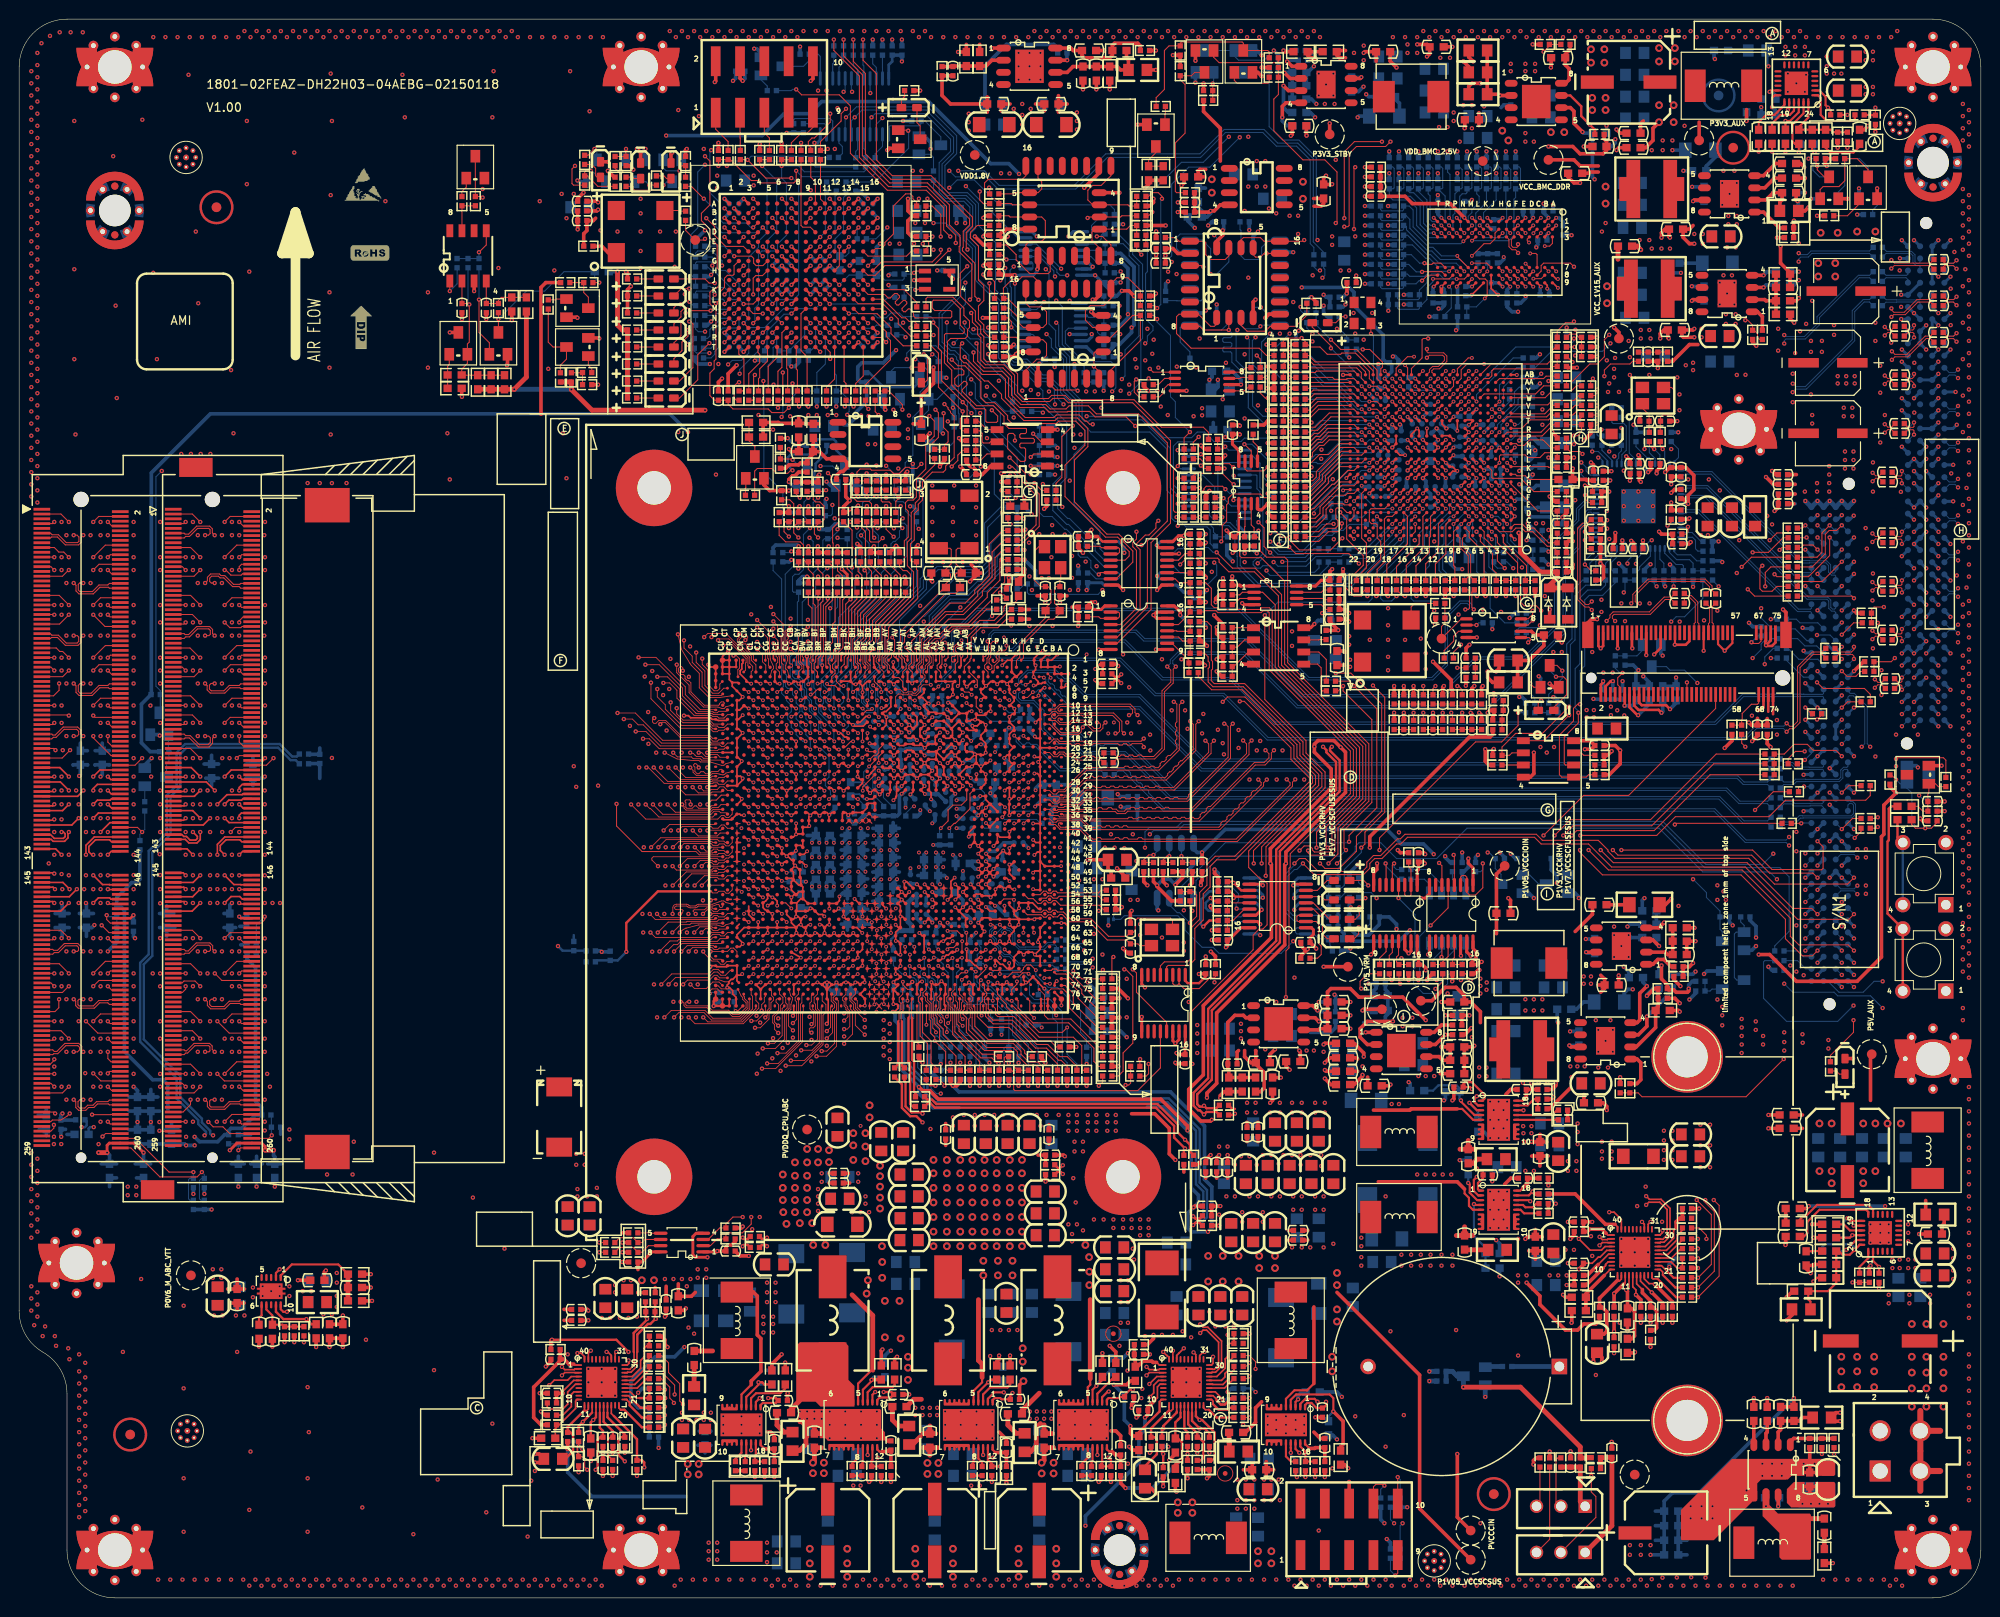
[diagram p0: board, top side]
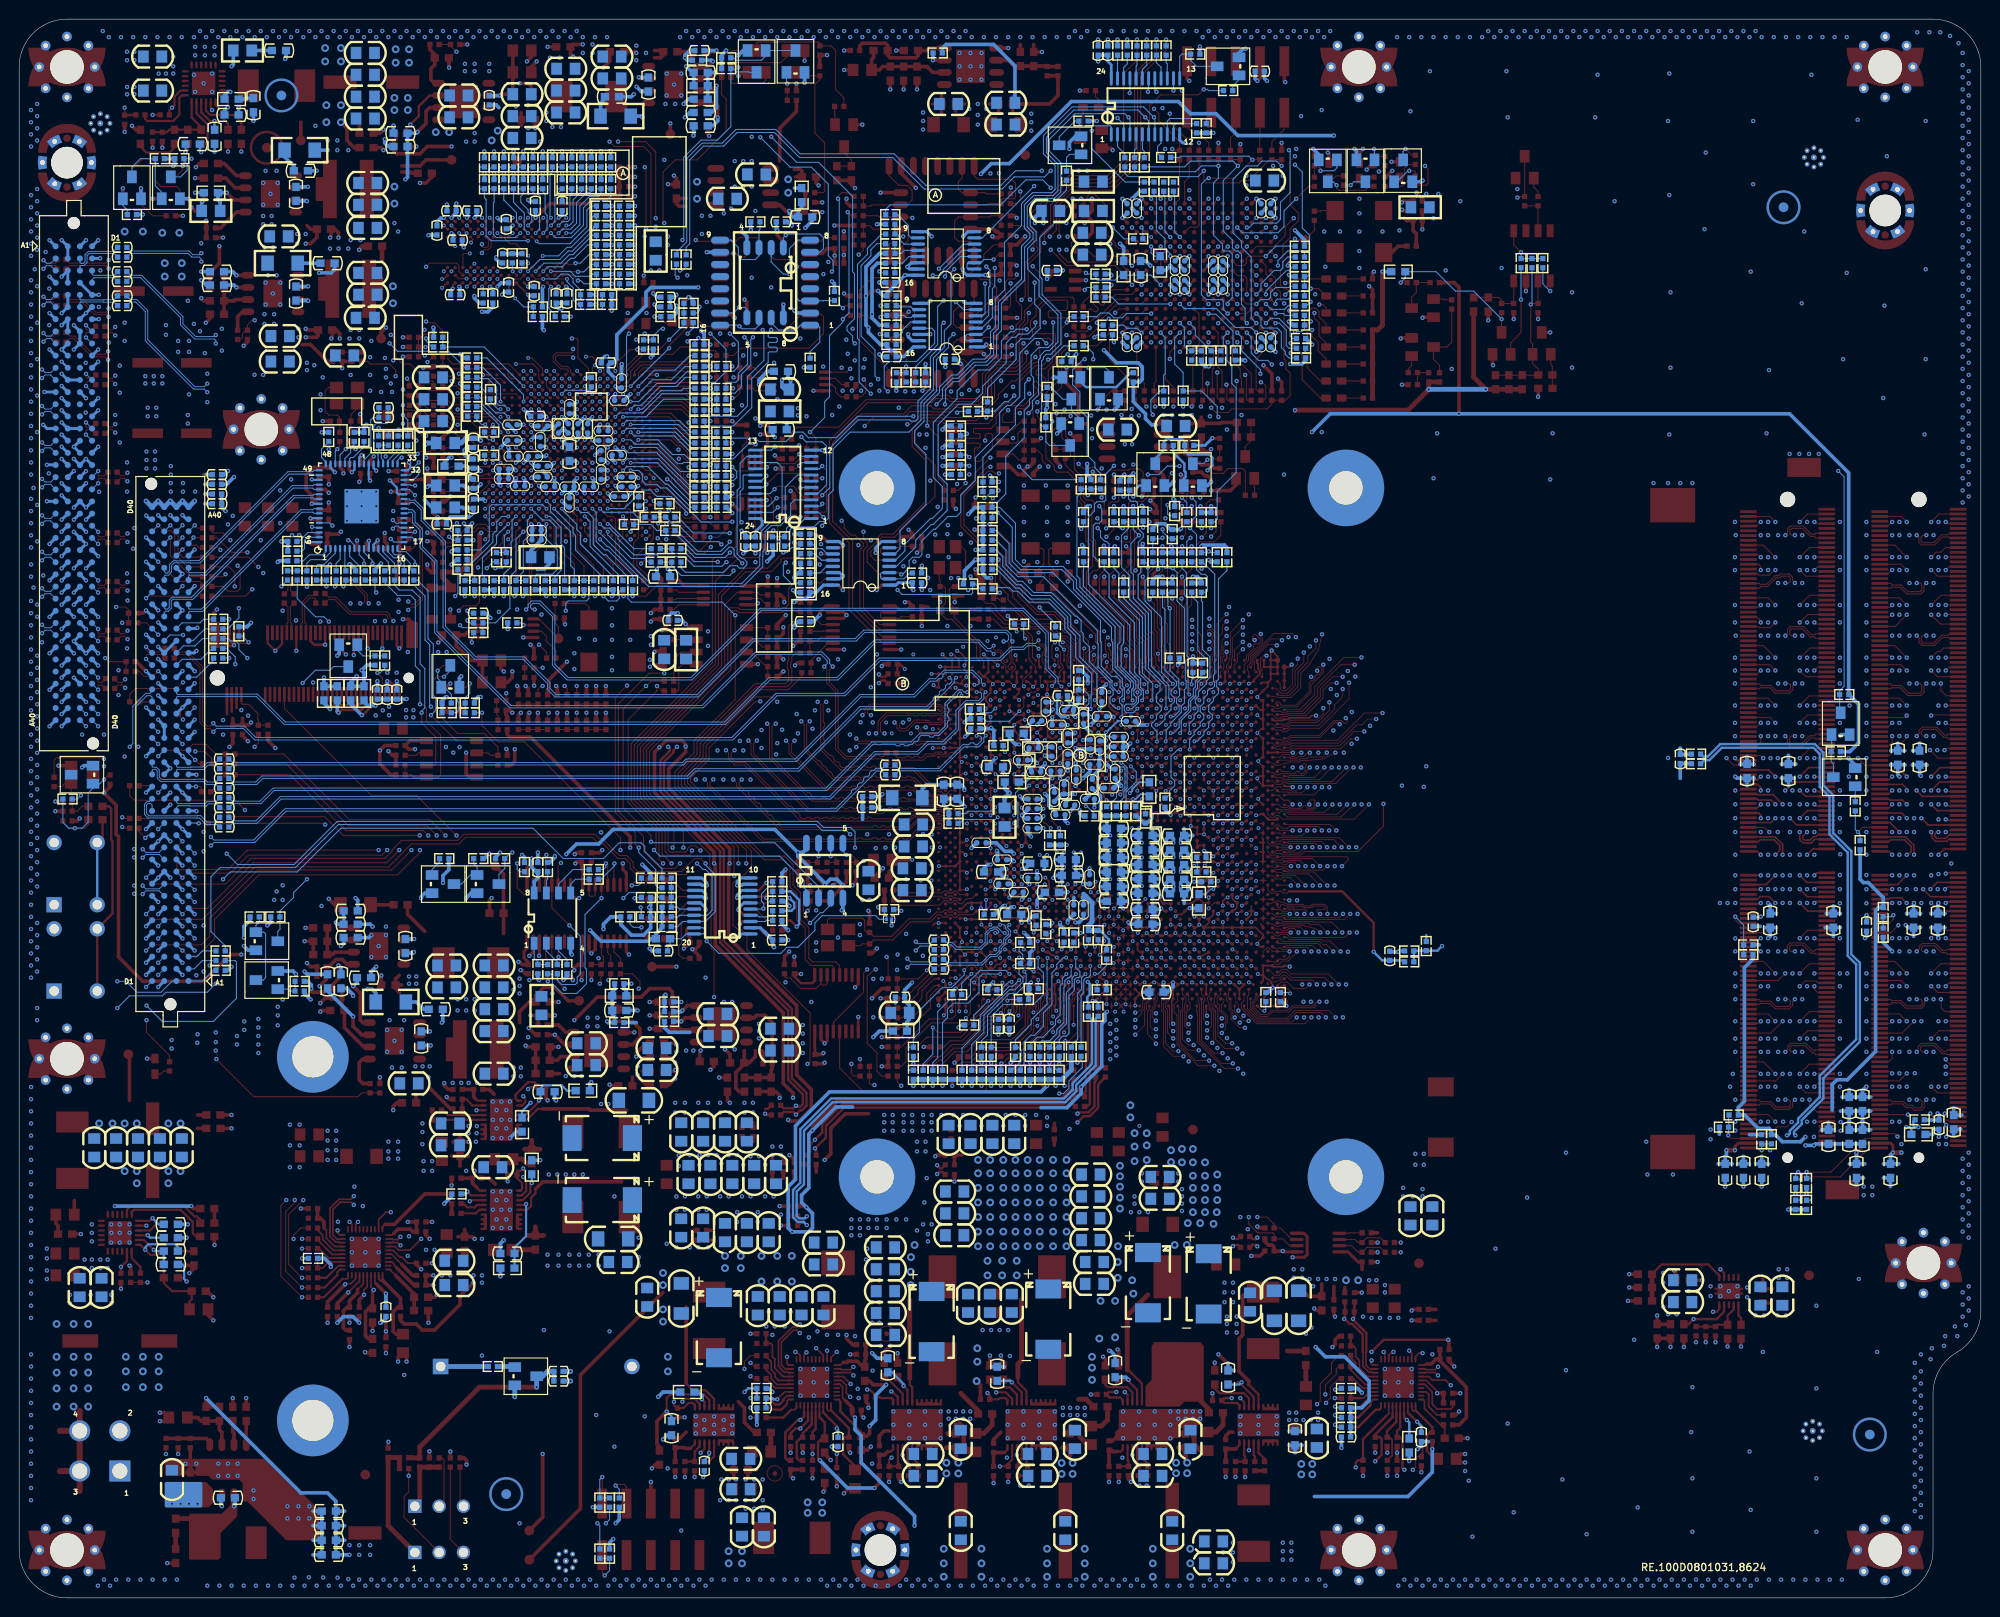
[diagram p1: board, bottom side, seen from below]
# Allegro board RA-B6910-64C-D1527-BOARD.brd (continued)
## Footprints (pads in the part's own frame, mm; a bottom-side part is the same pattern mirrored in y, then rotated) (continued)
10131758
  round 1.1 hole 1.1 unplated: (0,0)
  round 1.6 hole 1.6 unplated: (20,0)
  rect 0.3x1.55 smd: 1(0.75,4.725) 2(1,-1.725) 3(1.25,4.725) 4(1.5,-1.725) 5(1.75,4.725) 6(2,-1.725) 7(2.25,4.725) 8(2.5,-1.725) 9(2.75,4.725) 10(3,-1.725) 11(3.25,4.725) 12(3.5,-1.725) 13(3.75,4.725) 14(4,-1.725) 15(4.25,4.725) 16(4.5,-1.725) 17(4.75,4.725) 18(5,-1.725) 19(5.25,4.725) 20(5.5,-1.725) 21(5.75,4.725) 22(6,-1.725) 23(6.25,4.725) 24(6.5,-1.725) 25(6.75,4.725) 26(7,-1.725) 27(7.25,4.725) 28(7.5,-1.725) 29(7.75,4.725) 30(8,-1.725) 31(8.25,4.725) 32(8.5,-1.725) 33(8.75,4.725) 34(9,-1.725) 35(9.25,4.725) 36(9.5,-1.725) 37(9.75,4.725) 38(10,-1.725) 39(10.25,4.725) 40(10.5,-1.725) 41(10.75,4.725) 42(11,-1.725) 43(11.25,4.725) 44(11.5,-1.725) 45(11.75,4.725) 46(12,-1.725) 47(12.25,4.725) 48(12.5,-1.725) 49(12.75,4.725) 50(13,-1.725) 51(13.25,4.725) 52(13.5,-1.725) 53(13.75,4.725) 54(14,-1.725) 55(14.25,4.725) 56(14.5,-1.725) 57(14.75,4.725) 58(15,-1.725) 67(17.25,4.725) 68(17.5,-1.725) 69(17.75,4.725) 70(18,-1.725) 71(18.25,4.725) 72(18.5,-1.725) 73(18.75,4.725) 74(19,-1.725) 75(19.25,4.725)
  rect 1.2x2.76 smd: 76(-0.35,4.5) 77(20.35,4.5)
10141732
  round 1.1 hole 1.1 unplated: (-34.4,0)
  round 1.6 hole 1.6 unplated: (34.4,0)
  rect 0.3x1.75 smd: 1(33.375,4.1) 2(33.125,-4.1) 3(32.875,4.1) 4(32.625,-4.1) 5(32.375,4.1) 6(32.125,-4.1) 7(31.875,4.1) 8(31.625,-4.1) 9(31.375,4.1) 10(31.125,-4.1) 11(30.875,4.1) 12(30.625,-4.1) 13(30.375,4.1) 14(30.125,-4.1) 15(29.875,4.1) 16(29.625,-4.1) 17(29.375,4.1) 18(29.125,-4.1) 19(28.875,4.1) 20(28.625,-4.1) 21(28.375,4.1) 22(28.125,-4.1) 23(27.875,4.1) 24(27.625,-4.1) 25(27.375,4.1) 26(27.125,-4.1) 27(26.875,4.1) 28(26.625,-4.1) 29(26.375,4.1) 30(26.125,-4.1) 31(25.875,4.1) 32(25.625,-4.1) 33(25.375,4.1) 34(25.125,-4.1) 35(24.875,4.1) 36(24.625,-4.1) 37(24.375,4.1) 38(24.125,-4.1) 39(23.875,4.1) 40(23.625,-4.1) 41(23.375,4.1) 42(23.125,-4.1) 43(22.875,4.1) 44(22.625,-4.1) 45(22.375,4.1) 46(22.125,-4.1) 47(21.875,4.1) 48(21.625,-4.1) 49(21.375,4.1) 50(21.125,-4.1) 51(20.875,4.1) 52(20.625,-4.1) 53(20.375,4.1) 54(20.125,-4.1) 55(19.875,4.1) 56(19.625,-4.1) 57(19.375,4.1) 58(19.125,-4.1) 59(18.875,4.1) 60(18.625,-4.1) 61(18.375,4.1) 62(18.125,-4.1) 63(17.875,4.1) 64(17.625,-4.1) 65(17.375,4.1) 66(17.125,-4.1) 67(16.875,4.1) 68(16.625,-4.1) 69(16.375,4.1) 70(16.125,-4.1) 71(15.875,4.1) 72(15.625,-4.1) 73(15.375,4.1) 74(15.125,-4.1) 75(14.875,4.1) 76(14.625,-4.1) 77(14.375,4.1) 78(14.125,-4.1) 79(13.875,4.1) 80(13.625,-4.1) 81(13.375,4.1) 82(13.125,-4.1) 83(12.875,4.1) 84(12.625,-4.1) 85(12.375,4.1) 86(12.125,-4.1) 87(11.875,4.1) 88(11.625,-4.1) 89(11.375,4.1) 90(11.125,-4.1) 91(10.875,4.1) 92(10.625,-4.1) 93(10.375,4.1) 94(10.125,-4.1) 95(9.875,4.1) 96(9.625,-4.1) 97(9.375,4.1) 98(9.125,-4.1) 99(8.875,4.1) 100(8.625,-4.1) 101(8.375,4.1) 102(8.125,-4.1) 103(7.875,4.1) 104(7.625,-4.1) 105(7.375,4.1) 106(7.125,-4.1) 107(6.875,4.1) 108(6.625,-4.1) 109(6.375,4.1) 110(6.125,-4.1) 111(5.875,4.1) 112(5.625,-4.1) 113(5.375,4.1) 114(5.125,-4.1) 115(4.875,4.1) 116(4.625,-4.1) 117(4.375,4.1) 118(4.125,-4.1) 119(3.875,4.1) 120(3.625,-4.1) 121(3.375,4.1) 122(3.125,-4.1) 123(2.875,4.1) 124(2.625,-4.1) 125(2.375,4.1) 126(2.125,-4.1) 127(1.875,4.1) 128(1.625,-4.1) 129(1.375,4.1) 130(1.125,-4.1) 131(0.875,4.1) 132(0.625,-4.1) 133(0.375,4.1) 134(0.125,-4.1) 135(-0.125,4.1) 136(-0.375,-4.1) 137(-0.625,4.1) 138(-0.875,-4.1) 139(-1.125,4.1) 140(-1.375,-4.1) 141(-1.625,4.1) 142(-1.875,-4.1) 143(-2.125,4.1) 144(-2.375,-4.1) 145(-4.625,4.1) 146(-4.875,-4.1) 147(-5.125,4.1) 148(-5.375,-4.1) 149(-5.625,4.1) 150(-5.875,-4.1) 151(-6.125,4.1) 152(-6.375,-4.1) 153(-6.625,4.1) 154(-6.875,-4.1) 155(-7.125,4.1) 156(-7.375,-4.1) 157(-7.625,4.1) 158(-7.875,-4.1) 159(-8.125,4.1) 160(-8.375,-4.1) 161(-8.625,4.1) 162(-8.875,-4.1) 163(-9.125,4.1) 164(-9.375,-4.1) 165(-9.625,4.1) 166(-9.875,-4.1) 167(-10.125,4.1) 168(-10.375,-4.1) 169(-10.625,4.1) 170(-10.875,-4.1) 171(-11.125,4.1) 172(-11.375,-4.1) 173(-11.625,4.1) 174(-11.875,-4.1) 175(-12.125,4.1) 176(-12.375,-4.1) 177(-12.625,4.1) 178(-12.875,-4.1) 179(-13.125,4.1) 180(-13.375,-4.1) 181(-13.625,4.1) 182(-13.875,-4.1) 183(-14.125,4.1) 184(-14.375,-4.1) 185(-14.625,4.1) 186(-14.875,-4.1) 187(-15.125,4.1) 188(-15.375,-4.1) 189(-15.625,4.1) 190(-15.875,-4.1) 191(-16.125,4.1) 192(-16.375,-4.1) 193(-16.625,4.1) 194(-16.875,-4.1) 195(-17.125,4.1) 196(-17.375,-4.1) 197(-17.625,4.1) 198(-17.875,-4.1) 199(-18.125,4.1) 200(-18.375,-4.1) 201(-18.625,4.1) 202(-18.875,-4.1) 203(-19.125,4.1) 204(-19.375,-4.1) 205(-19.625,4.1) 206(-19.875,-4.1) 207(-20.125,4.1) 208(-20.375,-4.1) 209(-20.625,4.1) 210(-20.875,-4.1) 211(-21.125,4.1) 212(-21.375,-4.1) 213(-21.625,4.1) 214(-21.875,-4.1) 215(-22.125,4.1) 216(-22.375,-4.1) 217(-22.625,4.1) 218(-22.875,-4.1) 219(-23.125,4.1) 220(-23.375,-4.1) 221(-23.625,4.1) 222(-23.875,-4.1) 223(-24.125,4.1) 224(-24.375,-4.1) 225(-24.625,4.1) 226(-24.875,-4.1) 227(-25.125,4.1) 228(-25.375,-4.1) 229(-25.625,4.1) 230(-25.875,-4.1) 231(-26.125,4.1) 232(-26.375,-4.1) 233(-26.625,4.1) 234(-26.875,-4.1) 235(-27.125,4.1) 236(-27.375,-4.1) 237(-27.625,4.1) 238(-27.875,-4.1) 239(-28.125,4.1) 240(-28.375,-4.1) 241(-28.625,4.1) 242(-28.875,-4.1) 243(-29.125,4.1) 244(-29.375,-4.1) 245(-29.625,4.1) 246(-29.875,-4.1) 247(-30.125,4.1) 248(-30.375,-4.1) 249(-30.625,4.1) 250(-30.875,-4.1) 251(-31.125,4.1) 252(-31.375,-4.1) 253(-31.625,4.1) 254(-31.875,-4.1) 255(-32.125,4.1) 256(-32.375,-4.1) 257(-32.625,4.1) 258(-32.875,-4.1) 259(-33.125,4.1) 260(-33.375,-4.1)
  rect 2x3.5 smd: 261(-37.75,-8) 262(37.75,-12)
10141997
  round 1.1 hole 1.1 unplated: (0,0)
  round 1.6 hole 1.6 unplated: (68.8,0)
  rect 0.3x1.75 smd: 1(67.775,4.1) 2(67.525,-4.1) 3(67.275,4.1) 4(67.025,-4.1) 5(66.775,4.1) 6(66.525,-4.1) 7(66.275,4.1) 8(66.025,-4.1) 9(65.775,4.1) 10(65.525,-4.1) 11(65.275,4.1) 12(65.025,-4.1) 13(64.775,4.1) 14(64.525,-4.1) 15(64.275,4.1) 16(64.025,-4.1) 17(63.775,4.1) 18(63.525,-4.1) 19(63.275,4.1) 20(63.025,-4.1) 21(62.775,4.1) 22(62.525,-4.1) 23(62.275,4.1) 24(62.025,-4.1) 25(61.775,4.1) 26(61.525,-4.1) 27(61.275,4.1) 28(61.025,-4.1) 29(60.775,4.1) 30(60.525,-4.1) 31(60.275,4.1) 32(60.025,-4.1) 33(59.775,4.1) 34(59.525,-4.1) 35(59.275,4.1) 36(59.025,-4.1) 37(58.775,4.1) 38(58.525,-4.1) 39(58.275,4.1) 40(58.025,-4.1) 41(57.775,4.1) 42(57.525,-4.1) 43(57.275,4.1) 44(57.025,-4.1) 45(56.775,4.1) 46(56.525,-4.1) 47(56.275,4.1) 48(56.025,-4.1) 49(55.775,4.1) 50(55.525,-4.1) 51(55.275,4.1) 52(55.025,-4.1) 53(54.775,4.1) 54(54.525,-4.1) 55(54.275,4.1) 56(54.025,-4.1) 57(53.775,4.1) 58(53.525,-4.1) 59(53.275,4.1) 60(53.025,-4.1) 61(52.775,4.1) 62(52.525,-4.1) 63(52.275,4.1) 64(52.025,-4.1) 65(51.775,4.1) 66(51.525,-4.1) 67(51.275,4.1) 68(51.025,-4.1) 69(50.775,4.1) 70(50.525,-4.1) 71(50.275,4.1) 72(50.025,-4.1) 73(49.775,4.1) 74(49.525,-4.1) 75(49.275,4.1) 76(49.025,-4.1) 77(48.775,4.1) 78(48.525,-4.1) 79(48.275,4.1) 80(48.025,-4.1) 81(47.775,4.1) 82(47.525,-4.1) 83(47.275,4.1) 84(47.025,-4.1) 85(46.775,4.1) 86(46.525,-4.1) 87(46.275,4.1) 88(46.025,-4.1) 89(45.775,4.1) 90(45.525,-4.1) 91(45.275,4.1) 92(45.025,-4.1) 93(44.775,4.1) 94(44.525,-4.1) 95(44.275,4.1) 96(44.025,-4.1) 97(43.775,4.1) 98(43.525,-4.1) 99(43.275,4.1) 100(43.025,-4.1) 101(42.775,4.1) 102(42.525,-4.1) 103(42.275,4.1) 104(42.025,-4.1) 105(41.775,4.1) 106(41.525,-4.1) 107(41.275,4.1) 108(41.025,-4.1) 109(40.775,4.1) 110(40.525,-4.1) 111(40.275,4.1) 112(40.025,-4.1) 113(39.775,4.1) 114(39.525,-4.1) 115(39.275,4.1) 116(39.025,-4.1) 117(38.775,4.1) 118(38.525,-4.1) 119(38.275,4.1) 120(38.025,-4.1) 121(37.775,4.1) 122(37.525,-4.1) 123(37.275,4.1) 124(37.025,-4.1) 125(36.775,4.1) 126(36.525,-4.1) 127(36.275,4.1) 128(36.025,-4.1) 129(35.775,4.1) 130(35.525,-4.1) 131(35.275,4.1) 132(35.025,-4.1) 133(34.775,4.1) 134(34.525,-4.1) 135(34.275,4.1) 136(34.025,-4.1) 137(33.775,4.1) 138(33.525,-4.1) 139(33.275,4.1) 140(33.025,-4.1) 141(32.775,4.1) 142(32.525,-4.1) 143(32.275,4.1) 144(32.025,-4.1) 145(29.775,4.1) 146(29.525,-4.1) 147(29.275,4.1) 148(29.025,-4.1) 149(28.775,4.1) 150(28.525,-4.1) 151(28.275,4.1) 152(28.025,-4.1) 153(27.775,4.1) 154(27.525,-4.1) 155(27.275,4.1) 156(27.025,-4.1) 157(26.775,4.1) 158(26.525,-4.1) 159(26.275,4.1) 160(26.025,-4.1) 161(25.775,4.1) 162(25.525,-4.1) 163(25.275,4.1) 164(25.025,-4.1) 165(24.775,4.1) 166(24.525,-4.1) 167(24.275,4.1) 168(24.025,-4.1) 169(23.775,4.1) 170(23.525,-4.1) 171(23.275,4.1) 172(23.025,-4.1) 173(22.775,4.1) 174(22.525,-4.1) 175(22.275,4.1) 176(22.025,-4.1) 177(21.775,4.1) 178(21.525,-4.1) 179(21.275,4.1) 180(21.025,-4.1) 181(20.775,4.1) 182(20.525,-4.1) 183(20.275,4.1) 184(20.025,-4.1) 185(19.775,4.1) 186(19.525,-4.1) 187(19.275,4.1) 188(19.025,-4.1) 189(18.775,4.1) 190(18.525,-4.1) 191(18.275,4.1) 192(18.025,-4.1) 193(17.775,4.1) 194(17.525,-4.1) 195(17.275,4.1) 196(17.025,-4.1) 197(16.775,4.1) 198(16.525,-4.1) 199(16.275,4.1) 200(16.025,-4.1) 201(15.775,4.1) 202(15.525,-4.1) 203(15.275,4.1) 204(15.025,-4.1) 205(14.775,4.1) 206(14.525,-4.1) 207(14.275,4.1) 208(14.025,-4.1) 209(13.775,4.1) 210(13.525,-4.1) 211(13.275,4.1) 212(13.025,-4.1) 213(12.775,4.1) 214(12.525,-4.1) 215(12.275,4.1) 216(12.025,-4.1) 217(11.775,4.1) 218(11.525,-4.1) 219(11.275,4.1) 220(11.025,-4.1) 221(10.775,4.1) 222(10.525,-4.1) 223(10.275,4.1) 224(10.025,-4.1) 225(9.775,4.1) 226(9.525,-4.1) 227(9.275,4.1) 228(9.025,-4.1) 229(8.775,4.1) 230(8.525,-4.1) 231(8.275,4.1) 232(8.025,-4.1) 233(7.775,4.1) 234(7.525,-4.1) 235(7.275,4.1) 236(7.025,-4.1) 237(6.775,4.1) 238(6.525,-4.1) 239(6.275,4.1) 240(6.025,-4.1) 241(5.775,4.1) 242(5.525,-4.1) 243(5.275,4.1) 244(5.025,-4.1) 245(4.775,4.1) 246(4.525,-4.1) 247(4.275,4.1) 248(4.025,-4.1) 249(3.775,4.1) 250(3.525,-4.1) 251(3.275,4.1) 252(3.025,-4.1) 253(2.775,4.1) 254(2.525,-4.1) 255(2.275,4.1) 256(2.025,-4.1) 257(1.775,4.1) 258(1.525,-4.1) 259(1.275,4.1) 260(1.025,-4.1)
  rect 3.6x4.7 smd: 261(0.6,-12) 262(68.2,-12)
BATTERY
  rect 1.626x1.626 hole 1.016: 1(0,0)
  round 1.626 hole 1.016: 2(19.99,0)
BGA_465_1M46_RO014
  round 0.356 smd: A1(-8.4,8.4) A2(-7.6,8.4) A3(-6.8,8.4) A4(-6,8.4) A5(-5.2,8.4) A6(-4.4,8.4) A7(-3.6,8.4) A8(-2.8,8.4) A9(-2,8.4) A10(-1.2,8.4) A11(-0.4,8.4) A12(0.4,8.4) A13(1.2,8.4) A14(2,8.4) A15(2.8,8.4) A16(3.6,8.4) A17(4.4,8.4) A18(5.2,8.4) A19(6,8.4) A20(6.8,8.4) A21(7.6,8.4) A22(8.4,8.4) AA1(-8.4,-7.6) AA2(-7.6,-7.6) AA3(-6.8,-7.6) AA4(-6,-7.6) AA5(-5.2,-7.6) AA6(-4.4,-7.6) AA7(-3.6,-7.6) AA8(-2.8,-7.6) AA9(-2,-7.6) AA10(-1.2,-7.6) AA11(-0.4,-7.6) AA12(0.4,-7.6) AA13(1.2,-7.6) AA14(2,-7.6) AA15(2.8,-7.6) AA16(3.6,-7.6) AA17(4.4,-7.6) AA18(5.2,-7.6) AA19(6,-7.6) AA20(6.8,-7.6) AA21(7.6,-7.6) AA22(8.4,-7.6) AB1(-8.4,-8.4) AB2(-7.6,-8.4) AB3(-6.8,-8.4) AB4(-6,-8.4) AB5(-5.2,-8.4) AB6(-4.4,-8.4) AB7(-3.6,-8.4) AB8(-2.8,-8.4) AB9(-2,-8.4) AB10(-1.2,-8.4) AB11(-0.4,-8.4) AB12(0.4,-8.4) AB13(1.2,-8.4) AB14(2,-8.4) AB15(2.8,-8.4) AB16(3.6,-8.4) AB17(4.4,-8.4) AB18(5.2,-8.4) AB19(6,-8.4) AB20(6.8,-8.4) AB21(7.6,-8.4) AB22(8.4,-8.4) B1(-8.4,7.6) B2(-7.6,7.6) B3(-6.8,7.6) B4(-6,7.6) B5(-5.2,7.6) B6(-4.4,7.6) B7(-3.6,7.6) B8(-2.8,7.6) B9(-2,7.6) B10(-1.2,7.6) B11(-0.4,7.6) B12(0.4,7.6) B13(1.2,7.6) B14(2,7.6) B15(2.8,7.6) B16(3.6,7.6) B17(4.4,7.6) B18(5.2,7.6) B19(6,7.6) B20(6.8,7.6) B21(7.6,7.6) B22(8.4,7.6) C1(-8.4,6.8) C2(-7.6,6.8) C3(-6.8,6.8) C4(-6,6.8) C5(-5.2,6.8) C6(-4.4,6.8) C7(-3.6,6.8) C8(-2.8,6.8) C9(-2,6.8) C10(-1.2,6.8) C11(-0.4,6.8) C12(0.4,6.8) C13(1.2,6.8) C14(2,6.8) C15(2.8,6.8) C16(3.6,6.8) C17(4.4,6.8) C18(5.2,6.8) C19(6,6.8) C20(6.8,6.8) C21(7.6,6.8) C22(8.4,6.8) D1(-8.4,6) D2(-7.6,6) D3(-6.8,6) D4(-6,6) D5(-5.2,6) D6(-4.4,6) D7(-3.6,6) D8(-2.8,6) D9(-2,6) D10(-1.2,6) D11(-0.4,6) D12(0.4,6) D13(1.2,6) D14(2,6) D15(2.8,6) D16(3.6,6) D17(4.4,6) D18(5.2,6) D19(6,6) D20(6.8,6) D21(7.6,6) D22(8.4,6) E1(-8.4,5.2) E2(-7.6,5.2) E3(-6.8,5.2) E4(-6,5.2) E5(-5.2,5.2) E6(-4.4,5.2) E7(-3.6,5.2) E8(-2.8,5.2) E9(-2,5.2) E10(-1.2,5.2) E11(-0.4,5.2) E12(0.4,5.2) E13(1.2,5.2) E14(2,5.2) E15(2.8,5.2) E16(3.6,5.2) E17(4.4,5.2) E18(5.2,5.2) E19(6,5.2) E20(6.8,5.2) E21(7.6,5.2) E22(8.4,5.2) F1(-8.4,4.4) F2(-7.6,4.4) F3(-6.8,4.4) F4(-6,4.4) F5(-5.2,4.4) F6(-4.4,4.4) F7(-3.6,4.4) F8(-2.8,4.4) F9(-2,4.4) F10(-1.2,4.4) F11(-0.4,4.4) F12(0.4,4.4) F13(1.2,4.4) F14(2,4.4) F15(2.8,4.4) F16(3.6,4.4) F17(4.4,4.4) F18(5.2,4.4) F19(6,4.4) F20(6.8,4.4) F21(7.6,4.4) F22(8.4,4.4) G1(-8.4,3.6) G2(-7.6,3.6) G3(-6.8,3.6) G4(-6,3.6) G5(-5.2,3.6) G6(-4.4,3.6) G7(-3.6,3.6) G8(-2.8,3.6) G9(-2,3.6) G10(-1.2,3.6) G11(-0.4,3.6) G12(0.4,3.6) G13(1.2,3.6) G14(2,3.6) G15(2.8,3.6) G16(3.6,3.6) G17(4.4,3.6) G18(5.2,3.6) G19(6,3.6) G20(6.8,3.6) G21(7.6,3.6) G22(8.4,3.6) H1(-8.4,2.8) H2(-7.6,2.8) H3(-6.8,2.8) H4(-6,2.8) H5(-5.2,2.8) H6(-4.4,2.8) H7(-3.6,2.8) H16(3.6,2.8) H17(4.4,2.8) H18(5.2,2.8) H19(6,2.8) H20(6.8,2.8) H21(7.6,2.8) H22(8.4,2.8) J1(-8.4,2) J2(-7.6,2) J3(-6.8,2) J4(-6,2) J5(-5.2,2) J6(-4.4,2) J7(-3.6,2) J9(-2,2) J10(-1.2,2) J11(-0.4,2) J12(0.4,2) J13(1.2,2) J14(2,2) J16(3.6,2) J17(4.4,2) J18(5.2,2) J19(6,2) J20(6.8,2) J21(7.6,2) J22(8.4,2) K1(-8.4,1.2) K2(-7.6,1.2) K3(-6.8,1.2) K4(-6,1.2) K5(-5.2,1.2) K6(-4.4,1.2) K7(-3.6,1.2) K9(-2,1.2) K10(-1.2,1.2) K11(-0.4,1.2) K12(0.4,1.2) K13(1.2,1.2) K14(2,1.2) K16(3.6,1.2) K17(4.4,1.2) K18(5.2,1.2) K19(6,1.2) K20(6.8,1.2) K21(7.6,1.2) K22(8.4,1.2) L1(-8.4,0.4) L2(-7.6,0.4) L3(-6.8,0.4) L4(-6,0.4) L5(-5.2,0.4) L6(-4.4,0.4) L7(-3.6,0.4) L9(-2,0.4) L10(-1.2,0.4) L11(-0.4,0.4) L12(0.4,0.4) L13(1.2,0.4) L14(2,0.4) L16(3.6,0.4) L17(4.4,0.4) L18(5.2,0.4) L19(6,0.4) L20(6.8,0.4) L21(7.6,0.4) L22(8.4,0.4) M1(-8.4,-0.4) M2(-7.6,-0.4) M3(-6.8,-0.4) M4(-6,-0.4) M5(-5.2,-0.4) M6(-4.4,-0.4) M7(-3.6,-0.4) M9(-2,-0.4) M10(-1.2,-0.4) M11(-0.4,-0.4) M12(0.4,-0.4) M13(1.2,-0.4) M14(2,-0.4) M16(3.6,-0.4) M17(4.4,-0.4) M18(5.2,-0.4) M19(6,-0.4) M20(6.8,-0.4) M21(7.6,-0.4) M22(8.4,-0.4) N1(-8.4,-1.2) N2(-7.6,-1.2) N3(-6.8,-1.2) N4(-6,-1.2) N5(-5.2,-1.2) N6(-4.4,-1.2) N7(-3.6,-1.2) N9(-2,-1.2) N10(-1.2,-1.2) N11(-0.4,-1.2) N12(0.4,-1.2) N13(1.2,-1.2) N14(2,-1.2) N16(3.6,-1.2) N17(4.4,-1.2) N18(5.2,-1.2) N19(6,-1.2) N20(6.8,-1.2) N21(7.6,-1.2) N22(8.4,-1.2) P1(-8.4,-2) P2(-7.6,-2) P3(-6.8,-2) P4(-6,-2) P5(-5.2,-2) P6(-4.4,-2) P7(-3.6,-2) P9(-2,-2) P10(-1.2,-2) P11(-0.4,-2) P12(0.4,-2) P13(1.2,-2) P14(2,-2) P16(3.6,-2) P17(4.4,-2) P18(5.2,-2) P19(6,-2) P20(6.8,-2) P21(7.6,-2) P22(8.4,-2) R1(-8.4,-2.8) R2(-7.6,-2.8) R3(-6.8,-2.8) R4(-6,-2.8) R5(-5.2,-2.8) R6(-4.4,-2.8) R7(-3.6,-2.8) R16(3.6,-2.8) R17(4.4,-2.8) R18(5.2,-2.8) R19(6,-2.8) R20(6.8,-2.8) R21(7.6,-2.8) R22(8.4,-2.8) T1(-8.4,-3.6) T2(-7.6,-3.6) T3(-6.8,-3.6) T4(-6,-3.6) T5(-5.2,-3.6) T6(-4.4,-3.6) T7(-3.6,-3.6) T8(-2.8,-3.6) T9(-2,-3.6) T10(-1.2,-3.6) T11(-0.4,-3.6) T12(0.4,-3.6) T13(1.2,-3.6) T14(2,-3.6) T15(2.8,-3.6) T16(3.6,-3.6) T17(4.4,-3.6) T18(5.2,-3.6) T19(6,-3.6) T20(6.8,-3.6) T21(7.6,-3.6) T22(8.4,-3.6) U1(-8.4,-4.4) U2(-7.6,-4.4) U3(-6.8,-4.4) U4(-6,-4.4) U5(-5.2,-4.4) U6(-4.4,-4.4) U7(-3.6,-4.4) U8(-2.8,-4.4) U9(-2,-4.4) U10(-1.2,-4.4) U11(-0.4,-4.4) U12(0.4,-4.4) U13(1.2,-4.4) U14(2,-4.4) U15(2.8,-4.4) U16(3.6,-4.4) U17(4.4,-4.4) U18(5.2,-4.4) U19(6,-4.4) U20(6.8,-4.4) U21(7.6,-4.4) U22(8.4,-4.4) V1(-8.4,-5.2) V2(-7.6,-5.2) V3(-6.8,-5.2) V4(-6,-5.2) V5(-5.2,-5.2) V6(-4.4,-5.2) V7(-3.6,-5.2) V8(-2.8,-5.2) V9(-2,-5.2) V10(-1.2,-5.2) V11(-0.4,-5.2) V12(0.4,-5.2) V13(1.2,-5.2) V14(2,-5.2) V15(2.8,-5.2) V16(3.6,-5.2) V17(4.4,-5.2) V18(5.2,-5.2) V19(6,-5.2) V20(6.8,-5.2) V21(7.6,-5.2) V22(8.4,-5.2) W1(-8.4,-6) W2(-7.6,-6) W3(-6.8,-6) W4(-6,-6) W5(-5.2,-6) W6(-4.4,-6) W7(-3.6,-6) W8(-2.8,-6) W9(-2,-6) W10(-1.2,-6) W11(-0.4,-6) W12(0.4,-6) W13(1.2,-6) W14(2,-6) W15(2.8,-6) W16(3.6,-6) W17(4.4,-6) W18(5.2,-6) W19(6,-6) W20(6.8,-6) W21(7.6,-6) W22(8.4,-6) Y1(-8.4,-6.8) Y2(-7.6,-6.8) Y3(-6.8,-6.8) Y4(-6,-6.8) Y5(-5.2,-6.8) Y6(-4.4,-6.8) Y7(-3.6,-6.8) Y8(-2.8,-6.8) Y9(-2,-6.8) Y10(-1.2,-6.8) Y11(-0.4,-6.8) Y12(0.4,-6.8) Y13(1.2,-6.8) Y14(2,-6.8) Y15(2.8,-6.8) Y16(3.6,-6.8) Y17(4.4,-6.8) Y18(5.2,-6.8) Y19(6,-6.8) Y20(6.8,-6.8) Y21(7.6,-6.8) Y22(8.4,-6.8)
C0201
  rect 0.305x0.381 smd: 1(-0.267,0) 2(0.267,0)
C0402
  rect 0.559x0.559 smd: 1(-0.483,0) 2(0.483,0)
C0603
  rect 0.864x0.787 smd: 1(-0.737,0) 2(0.737,0)
C0805
  rect 1.118x1.27 smd: 1(-0.965,0) 2(0.965,0)
C1206
  rect 1.321x1.6 smd: 1(-1.575,0) 2(1.575,0)
CDNCC_6M6X7M7
  rect 3.2x1 smd: 1(2.55,0) 2(-2.55,0)
CDNCC_10M30X12M2
  rect 3.75x1.4 smd: 1(4.125,0) 2(-4.125,0)
CDNCC_0810
  rect 3.45x1.4 smd: 1(3.275,0) 2(-3.275,0)
CDRUB_7M3X4M3
  rect 2x2.7 smd: 1(3.15,0) 2(-3.15,0)
COUPON
  round 0.61 hole 0.206: 1(0,0)
  round 0.508 hole 0.203: 2(0,1.001) 3(0.711,0.711) 4(1.001,0) 5(0.711,-0.711) 6(0,-1.001) 7(-0.711,-0.711) 8(-1.001,0) 9(-0.711,0.711)
CSD95490Q5MC
  oval 0.25x0.7 smd: 1(-2.5,-2.35) 2(-2,-2.35) 3(-1.5,-2.35) 4(-1,-2.35) 5(-0.5,-2.35) 8(-0.5,2.35) 9(-1,2.35) 10(-1.5,2.35) 11(-2,2.35) 12(-2.5,2.35)
  custom 0.175x0.175 smd: 6(1.25,-2.35) 7(1.25,2.35)
  rect 5.4x3.3 smd: 13(0,0)
CSD95492QVMT
  oval 0.25x0.7 smd: 1(-2,-1.85) 2(-1.5,-1.85) 3(-1,-1.85) 4(-0.5,-1.85) 5(0,-1.85) 14(0,1.85) 15(-0.5,1.85) 16(-1,1.85) 17(-1.5,1.85) 18(-2,1.85)
  custom 0.176x0.176 smd: 6(1.25,-1.85) 10(1.25,1.85)
  rect 4.4x2.4 smd: 19(0,0)
D3SX24E000008E
  rect 1.2x0.95 smd: 1(-1.1,-0.875) 2(1.1,-0.875) 3(1.1,0.875) 4(-1.1,0.875)
FBGA_96_1M20_R14_GE
  round 0.356 smd: A1(-3.2,6) A2(-2.4,6) A3(-1.6,6) A7(1.6,6) A8(2.4,6) A9(3.2,6) B1(-3.2,5.2) B2(-2.4,5.2) B3(-1.6,5.2) B7(1.6,5.2) B8(2.4,5.2) B9(3.2,5.2) C1(-3.2,4.4) C2(-2.4,4.4) C3(-1.6,4.4) C7(1.6,4.4) C8(2.4,4.4) C9(3.2,4.4) D1(-3.2,3.6) D2(-2.4,3.6) D3(-1.6,3.6) D7(1.6,3.6) D8(2.4,3.6) D9(3.2,3.6) E1(-3.2,2.8) E2(-2.4,2.8) E3(-1.6,2.8) E7(1.6,2.8) E8(2.4,2.8) E9(3.2,2.8) F1(-3.2,2) F2(-2.4,2) F3(-1.6,2) F7(1.6,2) F8(2.4,2) F9(3.2,2) G1(-3.2,1.2) G2(-2.4,1.2) G3(-1.6,1.2) G7(1.6,1.2) G8(2.4,1.2) G9(3.2,1.2) H1(-3.2,0.4) H2(-2.4,0.4) H3(-1.6,0.4) H7(1.6,0.4) H8(2.4,0.4) H9(3.2,0.4) J1(-3.2,-0.4) J2(-2.4,-0.4) J3(-1.6,-0.4) J7(1.6,-0.4) J8(2.4,-0.4) J9(3.2,-0.4) K1(-3.2,-1.2) K2(-2.4,-1.2) K3(-1.6,-1.2) K7(1.6,-1.2) K8(2.4,-1.2) K9(3.2,-1.2) L1(-3.2,-2) L2(-2.4,-2) L3(-1.6,-2) L7(1.6,-2) L8(2.4,-2) L9(3.2,-2) M1(-3.2,-2.8) M2(-2.4,-2.8) M3(-1.6,-2.8) M7(1.6,-2.8) M8(2.4,-2.8) M9(3.2,-2.8) N1(-3.2,-3.6) N2(-2.4,-3.6) N3(-1.6,-3.6) N7(1.6,-3.6) N8(2.4,-3.6) N9(3.2,-3.6) P1(-3.2,-4.4) P2(-2.4,-4.4) P3(-1.6,-4.4) P7(1.6,-4.4) P8(2.4,-4.4) P9(3.2,-4.4) R1(-3.2,-5.2) R2(-2.4,-5.2) R3(-1.6,-5.2) R7(1.6,-5.2) R8(2.4,-5.2) R9(3.2,-5.2) T1(-3.2,-6) T2(-2.4,-6) T3(-1.6,-6) T7(1.6,-6) T8(2.4,-6) T9(3.2,-6)
FBGA_256
  round 0.457 smd: A1(-7.5,7.5) A2(-6.5,7.5) A3(-5.5,7.5) A4(-4.5,7.5) A5(-3.5,7.5) A6(-2.5,7.5) A7(-1.5,7.5) A8(-0.5,7.5) A9(0.5,7.5) A10(1.5,7.5) A11(2.5,7.5) A12(3.5,7.5) A13(4.5,7.5) A14(5.5,7.5) A15(6.5,7.5) A16(7.5,7.5) B1(-7.5,6.5) B2(-6.5,6.5) B3(-5.5,6.5) B4(-4.5,6.5) B5(-3.5,6.5) B6(-2.5,6.5) B7(-1.5,6.5) B8(-0.5,6.5) B9(0.5,6.5) B10(1.5,6.5) B11(2.5,6.5) B12(3.5,6.5) B13(4.5,6.5) B14(5.5,6.5) B15(6.5,6.5) B16(7.5,6.5) C1(-7.5,5.5) C2(-6.5,5.5) C3(-5.5,5.5) C4(-4.5,5.5) C5(-3.5,5.5) C6(-2.5,5.5) C7(-1.5,5.5) C8(-0.5,5.5) C9(0.5,5.5) C10(1.5,5.5) C11(2.5,5.5) C12(3.5,5.5) C13(4.5,5.5) C14(5.5,5.5) C15(6.5,5.5) C16(7.5,5.5) D1(-7.5,4.5) D2(-6.5,4.5) D3(-5.5,4.5) D4(-4.5,4.5) D5(-3.5,4.5) D6(-2.5,4.5) D7(-1.5,4.5) D8(-0.5,4.5) D9(0.5,4.5) D10(1.5,4.5) D11(2.5,4.5) D12(3.5,4.5) D13(4.5,4.5) D14(5.5,4.5) D15(6.5,4.5) D16(7.5,4.5) E1(-7.5,3.5) E2(-6.5,3.5) E3(-5.5,3.5) E4(-4.5,3.5) E5(-3.5,3.5) E6(-2.5,3.5) E7(-1.5,3.5) E8(-0.5,3.5) E9(0.5,3.5) E10(1.5,3.5) E11(2.5,3.5) E12(3.5,3.5) E13(4.5,3.5) E14(5.5,3.5) E15(6.5,3.5) E16(7.5,3.5) F1(-7.5,2.5) F2(-6.5,2.5) F3(-5.5,2.5) F4(-4.5,2.5) F5(-3.5,2.5) F6(-2.5,2.5) F7(-1.5,2.5) F8(-0.5,2.5) F9(0.5,2.5) F10(1.5,2.5) F11(2.5,2.5) F12(3.5,2.5) F13(4.5,2.5) F14(5.5,2.5) F15(6.5,2.5) F16(7.5,2.5) G1(-7.5,1.5) G2(-6.5,1.5) G3(-5.5,1.5) G4(-4.5,1.5) G5(-3.5,1.5) G6(-2.5,1.5) G7(-1.5,1.5) G8(-0.5,1.5) G9(0.5,1.5) G10(1.5,1.5) G11(2.5,1.5) G12(3.5,1.5) G13(4.5,1.5) G14(5.5,1.5) G15(6.5,1.5) G16(7.5,1.5) H1(-7.5,0.5) H2(-6.5,0.5) H3(-5.5,0.5) H4(-4.5,0.5) H5(-3.5,0.5) H6(-2.5,0.5) H7(-1.5,0.5) H8(-0.5,0.5) H9(0.5,0.5) H10(1.5,0.5) H11(2.5,0.5) H12(3.5,0.5) H13(4.5,0.5) H14(5.5,0.5) H15(6.5,0.5) H16(7.5,0.5) J1(-7.5,-0.5) J2(-6.5,-0.5) J3(-5.5,-0.5) J4(-4.5,-0.5) J5(-3.5,-0.5) J6(-2.5,-0.5) J7(-1.5,-0.5) J8(-0.5,-0.5) J9(0.5,-0.5) J10(1.5,-0.5) J11(2.5,-0.5) J12(3.5,-0.5) J13(4.5,-0.5) J14(5.5,-0.5) J15(6.5,-0.5) J16(7.5,-0.5) K1(-7.5,-1.5) K2(-6.5,-1.5) K3(-5.5,-1.5) K4(-4.5,-1.5) K5(-3.5,-1.5) K6(-2.5,-1.5) K7(-1.5,-1.5) K8(-0.5,-1.5) K9(0.5,-1.5) K10(1.5,-1.5) K11(2.5,-1.5) K12(3.5,-1.5) K13(4.5,-1.5) K14(5.5,-1.5) K15(6.5,-1.5) K16(7.5,-1.5) L1(-7.5,-2.5) L2(-6.5,-2.5) L3(-5.5,-2.5) L4(-4.5,-2.5) L5(-3.5,-2.5) L6(-2.5,-2.5) L7(-1.5,-2.5) L8(-0.5,-2.5) L9(0.5,-2.5) L10(1.5,-2.5) L11(2.5,-2.5) L12(3.5,-2.5) L13(4.5,-2.5) L14(5.5,-2.5) L15(6.5,-2.5) L16(7.5,-2.5) M1(-7.5,-3.5) M2(-6.5,-3.5) M3(-5.5,-3.5) M4(-4.5,-3.5) M5(-3.5,-3.5) M6(-2.5,-3.5) M7(-1.5,-3.5) M8(-0.5,-3.5) M9(0.5,-3.5) M10(1.5,-3.5) M11(2.5,-3.5) M12(3.5,-3.5) M13(4.5,-3.5) M14(5.5,-3.5) M15(6.5,-3.5) M16(7.5,-3.5) N1(-7.5,-4.5) N2(-6.5,-4.5) N3(-5.5,-4.5) N4(-4.5,-4.5) N5(-3.5,-4.5) N6(-2.5,-4.5) N7(-1.5,-4.5) N8(-0.5,-4.5) N9(0.5,-4.5) N10(1.5,-4.5) N11(2.5,-4.5) N12(3.5,-4.5) N13(4.5,-4.5) N14(5.5,-4.5) N15(6.5,-4.5) N16(7.5,-4.5) P1(-7.5,-5.5) P2(-6.5,-5.5) P3(-5.5,-5.5) P4(-4.5,-5.5) P5(-3.5,-5.5) P6(-2.5,-5.5) P7(-1.5,-5.5) P8(-0.5,-5.5) P9(0.5,-5.5) P10(1.5,-5.5) P11(2.5,-5.5) P12(3.5,-5.5) P13(4.5,-5.5) P14(5.5,-5.5) P15(6.5,-5.5) P16(7.5,-5.5) R1(-7.5,-6.5) R2(-6.5,-6.5) R3(-5.5,-6.5) R4(-4.5,-6.5) R5(-3.5,-6.5) R6(-2.5,-6.5) R7(-1.5,-6.5) R8(-0.5,-6.5) R9(0.5,-6.5) R10(1.5,-6.5) R11(2.5,-6.5) R12(3.5,-6.5) R13(4.5,-6.5) R14(5.5,-6.5) R15(6.5,-6.5) R16(7.5,-6.5) T1(-7.5,-7.5) T2(-6.5,-7.5) T3(-5.5,-7.5) T4(-4.5,-7.5) T5(-3.5,-7.5) T6(-2.5,-7.5) T7(-1.5,-7.5) T8(-0.5,-7.5) T9(0.5,-7.5) T10(1.5,-7.5) T11(2.5,-7.5) T12(3.5,-7.5) T13(4.5,-7.5) T14(5.5,-7.5) T15(6.5,-7.5) T16(7.5,-7.5)
FCBGA_1667_3M556
  round 0.381 smd: A3(-16.642,18.064) A5(-15.931,18.064) A74(15.931,18.064) A76(16.642,18.064) AA9(-14.166,8.172) AA12(-12.507,8.172) AA14(-11.707,8.172) AA16(-10.907,8.172) AA18(-10.107,8.172) AA19(-9.307,8.172) AA21(-8.506,8.172) AA23(-7.706,8.172) AA25(-6.906,8.172) AA27(-6.106,8.172) AA28(-5.306,8.172) AA30(-4.506,8.172) AA53(5.758,8.172) AA55(6.558,8.172) AA56(7.358,8.172) AA58(8.158,8.172) AA60(8.959,8.172) AA62(9.759,8.172) AA66(11.59,8.172) AA69(13.307,8.172) AA72(15.024,8.172) AC7(-15.024,7.677) AC11(-13.307,7.677) AC12(-12.507,7.372) AC14(-11.707,7.372) AC16(-10.907,7.372) AC18(-10.107,7.372) AC19(-9.307,7.372) AC21(-8.506,7.372) AC23(-7.706,7.372) AC25(-6.906,7.372) AC27(-6.106,7.372) AC28(-5.306,7.372) AC30(-4.506,7.372) AC53(5.758,7.372) AC55(6.558,7.372) AC56(7.358,7.372) AC58(8.158,7.372) AC60(8.959,7.372) AC62(9.759,7.372) AC64(10.732,7.677) AC67(12.449,7.677) AC71(14.166,7.677) AD9(-14.166,7.182) AD66(11.59,7.182) AD69(13.307,7.182) AD72(15.024,7.182) AE7(-15.024,6.687) AE11(-13.307,6.687) AE12(-12.507,6.572) AE14(-11.707,6.572) AE16(-10.907,6.572) AE18(-10.107,6.572) AE19(-9.307,6.572) AE21(-8.506,6.572) AE23(-7.706,6.572) AE25(-6.906,6.572) AE27(-6.106,6.572) AE28(-5.306,6.572) AE30(-4.506,6.572) AE53(5.758,6.572) AE55(6.558,6.572) AE56(7.358,6.572) AE58(8.158,6.572) AE60(8.959,6.572) AE62(9.759,6.572) AE64(10.732,6.687) AE67(12.449,6.687) AE71(14.166,6.687) AF9(-14.166,6.191) AF66(11.59,6.191) AF69(13.307,6.191) AF72(15.024,6.191) AG7(-15.024,5.696) AG11(-13.307,5.696) AG12(-12.507,5.772) AG14(-11.707,5.772) AG16(-10.907,5.772) AG18(-10.107,5.772) AG19(-9.307,5.772) AG21(-8.506,5.772) AG23(-7.706,5.772) AG25(-6.906,5.772) AG27(-6.106,5.772) AG28(-5.306,5.772) AG30(-4.506,5.772) AG53(5.758,5.772) AG55(6.558,5.772) AG56(7.358,5.772) AG58(8.158,5.772) AG60(8.959,5.772) AG62(9.759,5.772) AG64(10.732,5.696) AG67(12.449,5.696) AG71(14.166,5.696) AH9(-14.166,5.201) AH12(-12.507,4.972) AH14(-11.707,4.972) AH16(-10.907,4.972) AH18(-10.107,4.972) AH19(-9.307,4.972) AH21(-8.506,4.972) AH23(-7.706,4.972) AH25(-6.906,4.972) AH27(-6.106,4.972) AH28(-5.306,4.972) AH30(-4.506,4.972) AH53(5.758,4.972) AH55(6.558,4.972) AH56(7.358,4.972) AH58(8.158,4.972) AH60(8.959,4.972) AH62(9.759,4.972) AH66(11.59,5.201) AH69(13.307,5.201) AH72(15.024,5.201) AJ7(-15.024,4.705) AJ11(-13.307,4.705) AJ64(10.732,4.705) AJ67(12.449,4.705) AJ71(14.166,4.705) AK9(-14.166,4.21) AK12(-12.507,4.172) AK14(-11.707,4.172) AK16(-10.907,4.172) AK18(-10.107,4.172) AK19(-9.307,4.172) AK21(-8.506,4.172) AK23(-7.706,4.172) AK25(-6.906,4.172) AK27(-6.106,4.172) AK28(-5.306,4.172) AK30(-4.506,4.172) AK53(5.758,4.172) AK55(6.558,4.172) AK56(7.358,4.172) AK58(8.158,4.172) AK60(8.959,4.172) AK62(9.759,4.172) AK66(11.59,4.21) AK69(13.307,4.21) AK72(15.024,4.21) AL7(-15.024,3.715) AL11(-13.307,3.715) AL64(10.732,3.715) AL67(12.449,3.715) AL71(14.166,3.715) AM9(-14.166,3.219) AM12(-12.507,3.372) AM14(-11.707,3.372) AM16(-10.907,3.372) AM18(-10.107,3.372) AM19(-9.307,3.372) AM21(-8.506,3.372) AM23(-7.706,3.372) AM25(-6.906,3.372) AM27(-6.106,3.372) AM28(-5.306,3.372) AM30(-4.506,3.372) AM53(5.758,3.372) AM55(6.558,3.372) AM56(7.358,3.372) AM58(8.158,3.372) AM60(8.959,3.372) AM62(9.759,3.372) AM66(11.59,3.219) AM69(13.307,3.219) AM72(15.024,3.219) AN7(-15.024,2.724) AN11(-13.307,2.724) AN64(10.732,2.724) AN67(12.449,2.724) AN71(14.166,2.724) AP9(-14.166,2.229) AP12(-12.507,2.572) AP14(-11.707,2.572) AP16(-10.907,2.572) AP18(-10.107,2.572) AP19(-9.307,2.572) AP21(-8.506,2.572) AP23(-7.706,2.572) AP25(-6.906,2.572) AP27(-6.106,2.572) AP28(-5.306,2.572) AP30(-4.506,2.572) AP53(5.758,2.572) AP55(6.558,2.572) AP56(7.358,2.572) AP58(8.158,2.572) AP60(8.959,2.572) AP62(9.759,2.572) AP66(11.59,2.229) AP69(13.307,2.229) AP72(15.024,2.229) AR7(-15.024,1.734) AR11(-13.307,1.734) AR12(-12.507,1.772) AR14(-11.707,1.772) AR16(-10.907,1.772) AR18(-10.107,1.772) AR19(-9.307,1.772) AR21(-8.506,1.772) AR23(-7.706,1.772) AR25(-6.906,1.772) AR27(-6.106,1.772) AR28(-5.306,1.772) AR30(-4.506,1.772) AR53(5.758,1.772) AR55(6.558,1.772) AR56(7.358,1.775) AR60(9.014,1.734) AR64(10.732,1.734) AR67(12.449,1.734) AR71(14.166,1.734) AU9(-14.166,1.238) AU12(-12.507,0.972) AU14(-11.707,0.972) AU16(-10.907,0.972) AU18(-10.107,0.972) AU19(-9.307,0.972) AU21(-8.506,0.972) AU23(-7.706,0.972) AU25(-6.906,0.972) AU27(-6.106,0.972) AU28(-5.306,0.972) AU30(-4.506,0.972) AU53(5.758,0.972) AU55(6.558,0.972) AU56(7.358,0.975) AU58(8.156,1.238) AU62(9.873,1.238) AU66(11.59,1.238) AU69(13.307,1.238) AU72(15.024,1.238) AV7(-15.024,0.743) AV11(-13.307,0.743) AV60(9.014,0.743) AV64(10.732,0.743) AV67(12.449,0.743) AV71(14.166,0.743) AW9(-14.166,0.248) AW12(-12.507,0.171) AW14(-11.707,0.171) AW16(-10.907,0.171) AW18(-10.107,0.171) AW19(-9.307,0.171) AW21(-8.506,0.171) AW23(-7.706,0.171) AW25(-6.906,0.171) AW27(-6.106,0.171) AW28(-5.306,0.171) AW30(-4.506,0.171) AW55(6.558,0.171) AW56(7.358,0.174) AW58(8.156,0.248) AW62(9.873,0.248) AW66(11.59,0.248) AW69(13.307,0.248) AW72(15.024,0.248) AY7(-15.024,-0.248) AY11(-13.307,-0.248) AY60(9.014,-0.248) AY64(10.732,-0.248) AY67(12.449,-0.248) AY71(14.166,-0.248) B2(-17.353,17.353) B77(17.353,17.353) BA9(-14.166,-0.743) BA12(-12.507,-0.629) BA14(-11.707,-0.629) BA16(-10.907,-0.629) BA18(-10.107,-0.629) BA19(-9.307,-0.629) BA21(-8.506,-0.629) BA23(-7.706,-0.629) BA25(-6.906,-0.629) BA27(-6.106,-0.629) BA28(-5.306,-0.629) BA30(-4.506,-0.629) BA56(7.358,-0.626) BA58(8.156,-0.743) BA62(9.873,-0.743) BA66(11.59,-0.743) BA69(13.307,-0.743) BA72(15.024,-0.743) BB7(-15.024,-1.238) BB11(-13.307,-1.238) BB12(-12.507,-1.429) BB14(-11.707,-1.429) BB16(-10.907,-1.429) BB18(-10.107,-1.429) BB19(-9.307,-1.429) BB21(-8.506,-1.429) BB23(-7.706,-1.429) BB25(-6.906,-1.429) BB27(-6.106,-1.429) BB28(-5.306,-1.429) BB30(-4.506,-1.429) BB32(-3.806,-1.429) BB33(-3.106,-1.429) BB35(-2.406,-1.429) BB36(-1.672,-1.429) BB56(7.358,-1.426) BB60(9.014,-1.238) BB64(10.732,-1.238) BB67(12.449,-1.238) BB71(14.166,-1.238) BC9(-14.166,-1.734) BC58(8.156,-1.734) BC62(9.873,-1.734) BC66(11.59,-1.734) BC69(13.307,-1.734) BC72(15.024,-1.734) BD7(-15.024,-2.229) BD11(-13.307,-2.229) BD14(-11.59,-2.229) BD18(-9.873,-2.229) BD22(-8.156,-2.229) BD26(-6.439,-2.229) BD30(-4.722,-2.229) BD33(-3.005,-2.229) BD36(-2.039,-2.029) BD37(-1.306,-2.026) BD56(7.358,-2.226) BD60(9.014,-2.229) BD64(10.732,-2.229) BD67(12.449,-2.229) BD71(14.166,-2.229) BE9(-14.166,-2.724) BE13(-12.449,-2.724) BE16(-10.732,-2.724) BE20(-9.014,-2.724) BE24(-7.297,-2.724) BE28(-5.58,-2.724) BE32(-3.863,-2.724) BE35(-2.146,-2.724) BE37(-1.306,-2.726) BE58(8.156,-2.724) BE62(9.873,-2.724) BE66(11.59,-2.724) BE69(13.307,-2.724) BE72(15.024,-2.724) BF7(-15.024,-3.219) BF11(-13.307,-3.219) BF14(-11.59,-3.219) BF18(-9.873,-3.219) BF22(-8.156,-3.219) BF26(-6.439,-3.219) BF30(-4.722,-3.219) BF33(-3.005,-3.219) BF56(7.358,-3.026) BF60(9.014,-3.219) BF64(10.732,-3.219) BF67(12.449,-3.219) BF71(14.166,-3.219) BG9(-14.166,-3.715) BG13(-12.449,-3.715) BG16(-10.732,-3.715) BG20(-9.014,-3.715) BG24(-7.297,-3.715) BG28(-5.58,-3.715) BG32(-3.863,-3.715) BG35(-2.146,-3.715) BG37(-1.306,-3.426) BG58(8.156,-3.715) BG62(9.873,-3.715) BG66(11.59,-3.715) BG69(13.307,-3.715) BG72(15.024,-3.715) BH7(-15.024,-4.21) BH11(-13.307,-4.21) BH14(-11.59,-4.21) BH18(-9.873,-4.21) BH22(-8.156,-4.21) BH26(-6.439,-4.21) BH30(-4.722,-4.21) BH33(-3.005,-4.21) BH37(-1.306,-4.126) BH56(7.358,-3.826) BH60(9.014,-4.21) BH64(10.732,-4.21) BH67(12.449,-4.21) BH71(14.166,-4.21) BJ9(-14.166,-4.705) BJ13(-12.449,-4.705) BJ16(-10.732,-4.705) BJ20(-9.014,-4.705) BJ24(-7.297,-4.705) BJ28(-5.58,-4.705) BJ32(-3.863,-4.705) BJ35(-2.146,-4.705) BJ56(7.358,-4.626) BJ58(8.156,-4.705) BJ62(9.873,-4.705) BJ66(11.59,-4.705) BJ69(13.307,-4.705) BJ72(15.024,-4.705) BK37(-1.306,-4.826) BL7(-15.024,-5.201) BL11(-13.307,-5.201) BL14(-11.59,-5.201) BL18(-9.873,-5.201) BL22(-8.156,-5.201) BL26(-6.439,-5.201) BL30(-4.722,-5.201) BL33(-3.005,-5.201) BL37(-1.306,-5.526) BL56(7.358,-5.426) BL60(9.014,-5.201) BL64(10.732,-5.201) BL67(12.449,-5.201) BL71(14.166,-5.201) BM9(-14.166,-5.696) BM13(-12.449,-5.696) BM16(-10.732,-5.696) BM20(-9.014,-5.696) BM24(-7.297,-5.696) BM28(-5.58,-5.696) BM32(-3.863,-5.696) BM35(-2.146,-5.696) BM58(8.156,-5.696) BM62(9.873,-5.696) BM66(11.59,-5.696) BM69(13.307,-5.696) BM72(15.024,-5.696) BN7(-15.024,-6.191) BN11(-13.307,-6.191) BN14(-11.59,-6.191) BN18(-9.873,-6.191) BN22(-8.156,-6.191) BN26(-6.439,-6.191) BN30(-4.722,-6.191) BN33(-3.005,-6.191) BN37(-1.306,-6.226) BN56(7.358,-6.226) BN60(9.014,-6.191) BN64(10.732,-6.191) BN67(12.449,-6.191) BN71(14.166,-6.191) BP9(-14.166,-6.687) BP13(-12.449,-6.687) BP16(-10.732,-6.687) BP20(-9.014,-6.687) BP24(-7.297,-6.687) BP28(-5.58,-6.687) BP32(-3.863,-6.687) BP35(-2.146,-6.687) BP37(-1.306,-6.926) BP56(7.358,-7.026) BP58(8.156,-6.687) BP62(9.873,-6.687) BP66(11.59,-6.687) BP69(13.307,-6.687) BP72(15.024,-6.687) BR7(-15.024,-7.182) BR11(-13.307,-7.182) BR14(-11.59,-7.182) BR18(-9.873,-7.182) BR22(-8.156,-7.182) BR26(-6.439,-7.182) BR30(-4.722,-7.182) BR33(-3.005,-7.182) BR60(9.014,-7.182) BR64(10.732,-7.182) BR67(12.449,-7.182) BR71(14.166,-7.182) BT9(-14.166,-7.677) BT13(-12.449,-7.677) BT16(-10.732,-7.677) BT20(-9.014,-7.677) BT24(-7.297,-7.677) BT28(-5.58,-7.677) BT32(-3.863,-7.677) BT35(-2.146,-7.677) BT37(-1.306,-7.627) BT56(7.358,-7.727) BT58(8.156,-7.677) BT62(9.873,-7.677) BT66(11.59,-7.677) BT69(13.307,-7.677) BT72(15.024,-7.677) BU7(-15.024,-8.172) BU11(-13.307,-8.172) BU14(-11.59,-8.172) BU18(-9.873,-8.172) BU22(-8.156,-8.172) BU26(-6.439,-8.172) BU30(-4.722,-8.172) BU33(-3.005,-8.172) BU37(-1.306,-8.327) BU60(9.014,-8.172) BU64(10.732,-8.172) BU67(12.449,-8.172) BU71(14.166,-8.172) BV9(-14.166,-8.668) BV13(-12.449,-8.668) BV16(-10.732,-8.668) BV20(-9.014,-8.668) BV24(-7.297,-8.668) BV28(-5.58,-8.668) BV32(-3.863,-8.668) BV35(-2.146,-8.668) BV56(7.358,-8.427) BV58(8.156,-8.668) BV62(9.873,-8.668) BV66(11.59,-8.668) BV69(13.307,-8.668) BV72(15.024,-8.668) BW7(-15.024,-9.163) BW11(-13.307,-9.163) BW14(-11.59,-9.163) BW18(-9.873,-9.163) BW22(-8.156,-9.163) BW26(-6.439,-9.163) BW30(-4.722,-9.163) BW33(-3.005,-9.163) BW37(-1.306,-9.027) BW39(-0.607,-8.958) BW40(0.093,-8.958) BW42(0.793,-8.958) BW43(1.493,-8.958) BW45(2.226,-9.258) BW47(3.026,-9.258) BW49(3.827,-9.258) BW50(4.627,-9.258) BW52(5.427,-9.158) BW54(6.127,-8.958) BW55(6.877,-8.958) BW60(9.014,-9.163) BW64(10.732,-9.163) BW67(12.449,-9.163) BW71(14.166,-9.163) BY9(-14.166,-9.658) BY13(-12.449,-9.658) BY16(-10.732,-9.658) BY20(-9.014,-9.658) BY24(-7.297,-9.658) BY28(-5.58,-9.658) BY32(-3.863,-9.658) BY35(-2.146,-9.658) BY39(-0.429,-9.658) BY43(1.288,-9.658) BY54(6.439,-9.658) BY58(8.156,-9.658) BY62(9.873,-9.658) BY66(11.59,-9.658) BY69(13.307,-9.658) BY72(15.024,-9.658) C1(-18.064,16.642) C78(18.064,16.642) CA7(-15.024,-10.154) CA11(-13.307,-10.154) CA14(-11.59,-10.154) CA18(-9.873,-10.154) CA22(-8.156,-10.154) CA26(-6.439,-10.154) CA30(-4.722,-10.154) CA33(-3.005,-10.154) CA37(-1.288,-10.154) CA41(0.429,-10.154) CA45(2.146,-10.154) CA46(2.84,-9.943) CA49(3.863,-10.154) CA51(4.887,-9.943) CA52(5.58,-10.154) CA56(7.297,-10.154) CA60(9.014,-10.154) CA64(10.732,-10.154) CA67(12.449,-10.154) CA71(14.166,-10.154) CB9(-14.166,-10.649) CB13(-12.449,-10.649) CB16(-10.732,-10.649) CB20(-9.014,-10.649) CB24(-7.297,-10.649) CB28(-5.58,-10.649) CB32(-3.863,-10.649) CB35(-2.146,-10.649) CB39(-0.429,-10.649) CB43(1.288,-10.649) CB47(3.005,-10.649) CB51(4.722,-10.649) CB54(6.439,-10.649) CB58(8.156,-10.649) CB62(9.873,-10.649) CB66(11.59,-10.649) CB69(13.307,-10.649) CB72(15.024,-10.649) CC7(-15.024,-11.144) CC11(-13.307,-11.144) CC14(-11.59,-11.144) CC18(-9.873,-11.144) CC22(-8.156,-11.144) CC26(-6.439,-11.144) CC30(-4.722,-11.144) CC33(-3.005,-11.144) CC37(-1.288,-11.144) CC41(0.429,-11.144) CC45(2.146,-11.144) CC49(3.863,-11.144) CC52(5.58,-11.144) CC56(7.297,-11.144) CC60(9.014,-11.144) CC64(10.732,-11.144) CC67(12.449,-11.144) CC71(14.166,-11.144) CD9(-14.166,-11.64) CD13(-12.449,-11.64) CD16(-10.732,-11.64) CD20(-9.014,-11.64) CD24(-7.297,-11.64) CD28(-5.58,-11.64) CD32(-3.863,-11.64) CD35(-2.146,-11.64) CD39(-0.429,-11.64) CD43(1.288,-11.64) CD47(3.005,-11.64) CD51(4.722,-11.64) CD54(6.439,-11.64) CD58(8.156,-11.64) CD62(9.873,-11.64) CD66(11.59,-11.64) CD69(13.307,-11.64) CD72(15.024,-11.64) CF7(-15.024,-12.135) CF11(-13.307,-12.135) CF14(-11.59,-12.135) CF18(-9.873,-12.135) CF22(-8.156,-12.135) CF26(-6.439,-12.135) CF30(-4.722,-12.135) CF33(-3.005,-12.135) CF37(-1.288,-12.135) CF41(0.429,-12.135) CF45(2.146,-12.135) CF49(3.863,-12.135) CF52(5.58,-12.135) CF56(7.297,-12.135) CF60(9.014,-12.135) CF64(10.732,-12.135) CF67(12.449,-12.135) CF71(14.166,-12.135) CG9(-14.166,-12.63) CG13(-12.449,-12.63) CG16(-10.732,-12.63) CG20(-9.014,-12.63) CG24(-7.297,-12.63) CG28(-5.58,-12.63) CG32(-3.863,-12.63) CG35(-2.146,-12.63) CG39(-0.429,-12.63) CG43(1.288,-12.63) CG47(3.005,-12.63) CG51(4.722,-12.63) CG54(6.439,-12.63) CG58(8.156,-12.63) CG62(9.873,-12.63) CG66(11.59,-12.63) CG69(13.307,-12.63) CG72(15.024,-12.63) CH7(-15.024,-13.125) CH11(-13.307,-13.125) CH14(-11.59,-13.125) CH18(-9.873,-13.125) CH22(-8.156,-13.125) CH26(-6.439,-13.125) CH30(-4.722,-13.125) CH33(-3.005,-13.125) CH37(-1.288,-13.125) CH41(0.429,-13.125) CH45(2.146,-13.125) CH49(3.863,-13.125) CH52(5.58,-13.125) CH56(7.297,-13.125) CH60(9.014,-13.125) CH64(10.732,-13.125) CH67(12.449,-13.125) CH71(14.166,-13.125) CJ9(-14.166,-13.621) CJ13(-12.449,-13.621) CJ16(-10.732,-13.621) CJ20(-9.014,-13.621) CJ24(-7.297,-13.621) CJ28(-5.58,-13.621) CJ32(-3.863,-13.621) CJ35(-2.146,-13.621) CJ39(-0.429,-13.621) CJ43(1.288,-13.621) CJ47(3.005,-13.621) CJ51(4.722,-13.621) CJ54(6.439,-13.621) CJ58(8.156,-13.621) CJ62(9.873,-13.621) CJ66(11.59,-13.621) CJ69(13.307,-13.621) CJ72(15.024,-13.621) CK7(-15.024,-14.116) CK11(-13.307,-14.116) CK14(-11.59,-14.116) CK18(-9.873,-14.116) CK22(-8.156,-14.116) CK26(-6.439,-14.116) CK30(-4.722,-14.116) CK33(-3.005,-14.116) CK37(-1.288,-14.116) CK41(0.429,-14.116) CK45(2.146,-14.116) CK49(3.863,-14.116) CK52(5.58,-14.116) CK56(7.297,-14.116) CK60(9.014,-14.116) CK64(10.732,-14.116) CK67(12.449,-14.116) CK71(14.166,-14.116) CL9(-14.166,-14.611) CL13(-12.449,-14.611) CL16(-10.732,-14.611) CL20(-9.014,-14.611) CL24(-7.297,-14.611) CL28(-5.58,-14.611) CL32(-3.863,-14.611) CL35(-2.146,-14.611) CL39(-0.429,-14.611) CL43(1.288,-14.611) CL47(3.005,-14.611) CL51(4.722,-14.611) CL54(6.439,-14.611) CL58(8.156,-14.611) CL62(9.873,-14.611) CL66(11.59,-14.611) CL69(13.307,-14.611) CL72(15.024,-14.611) CM7(-15.024,-15.107) CM11(-13.307,-15.107) CM14(-11.59,-15.107) CM18(-9.873,-15.107) CM22(-8.156,-15.107) CM26(-6.439,-15.107) CM30(-4.722,-15.107) CM33(-3.005,-15.107) CM37(-1.288,-15.107) CM41(0.429,-15.107) CM45(2.146,-15.107) CM49(3.863,-15.107) CM52(5.58,-15.107) CM56(7.297,-15.107) CM60(9.014,-15.107) CM64(10.732,-15.107) CM67(12.449,-15.107) CM71(14.166,-15.107) CP1(-18.064,-15.931) CP78(18.064,-15.931) CR1(-18.064,-16.642) CR78(18.064,-16.642) CU2(-17.353,-17.353) CU77(17.353,-17.353) CV3(-16.642,-18.064) CV5(-15.931,-18.064) CV74(15.931,-18.064) CV76(16.642,-18.064) E1(-18.064,15.931) E78(18.064,15.931) F9(-14.166,15.107) F13(-12.449,15.107) F16(-10.732,15.107) F20(-9.014,15.107) F24(-7.297,15.107) F28(-5.58,15.107) F32(-3.863,15.107) F35(-2.146,15.107) F39(-0.429,15.107) F43(1.288,15.107) F47(3.005,15.107) F51(4.722,15.107) F54(6.439,15.107) F58(8.156,15.107) F62(9.873,15.107) F66(11.59,15.107) F69(13.307,15.107) F72(15.024,15.107) H7(-15.024,14.611) H11(-13.307,14.611) H14(-11.59,14.611) H18(-9.873,14.611) H22(-8.156,14.611) H26(-6.439,14.611) H30(-4.722,14.611) H33(-3.005,14.611) H37(-1.288,14.611) H41(0.429,14.611) H45(2.146,14.611) H49(3.863,14.611) H52(5.58,14.611) H56(7.297,14.611) H60(9.014,14.611) H64(10.732,14.611) H67(12.449,14.611) H71(14.166,14.611) J9(-14.166,14.116) J13(-12.449,14.116) J16(-10.732,14.116) J20(-9.014,14.116) J24(-7.297,14.116) J28(-5.58,14.116) J32(-3.863,14.116) J35(-2.146,14.116) J39(-0.429,14.116) J43(1.288,14.116) J47(3.005,14.116) J51(4.722,14.116) J54(6.439,14.116) J58(8.156,14.116) J62(9.873,14.116) J66(11.59,14.116) J69(13.307,14.116) J72(15.024,14.116) K7(-15.024,13.621) K11(-13.307,13.621) K14(-11.59,13.621) K18(-9.873,13.621) K22(-8.156,13.621) K26(-6.439,13.621) K30(-4.722,13.621) K33(-3.005,13.621) K37(-1.288,13.621) K41(0.429,13.621) K45(2.146,13.621) K49(3.863,13.621) K52(5.58,13.621) K56(7.297,13.621) K60(9.014,13.621) K64(10.732,13.621) K67(12.449,13.621) K71(14.166,13.621) L9(-14.166,13.125) L13(-12.449,13.125) L16(-10.732,13.125) L20(-9.014,13.125) L24(-7.297,13.125) L28(-5.58,13.125) L32(-3.863,13.125) L35(-2.146,13.125) L39(-0.429,13.125) L43(1.288,13.125) L47(3.005,13.125) L51(4.722,13.125) L54(6.439,13.125) L58(8.156,13.125) L62(9.873,13.125) L66(11.59,13.125) L69(13.307,13.125) L72(15.024,13.125) M7(-15.024,12.63) M11(-13.307,12.63) M14(-11.59,12.63) M18(-9.873,12.63) M22(-8.156,12.63) M26(-6.439,12.63) M30(-4.722,12.63) M33(-3.005,12.63) M37(-1.288,12.63) M41(0.429,12.63) M45(2.146,12.63) M49(3.863,12.63) M52(5.58,12.63) M56(7.297,12.63) M60(9.014,12.63) M64(10.732,12.63) M67(12.449,12.63) M71(14.166,12.63) N9(-14.166,12.135) N13(-12.449,12.135) N16(-10.732,12.135) N20(-9.014,12.135) N24(-7.297,12.135) N28(-5.58,12.135) N32(-3.863,12.135) N35(-2.146,12.135) N39(-0.429,12.135) N43(1.288,12.135) N47(3.005,12.135) N51(4.722,12.135) N54(6.439,12.135) N58(8.156,12.135) N62(9.873,12.135) N66(11.59,12.135) N69(13.307,12.135) N72(15.024,12.135) P7(-15.024,11.64) P11(-13.307,11.64) P14(-11.59,11.64) P18(-9.873,11.64) P22(-8.156,11.64) P26(-6.439,11.64) P30(-4.722,11.64) P33(-3.005,11.64) P52(5.58,11.64) P56(7.297,11.64) P60(9.014,11.64) P64(10.732,11.64) P67(12.449,11.64) P71(14.166,11.64) R9(-14.166,11.144) R13(-12.449,11.144) R16(-10.732,11.144) R20(-9.014,11.144) R24(-7.297,11.144) R28(-5.58,11.144) R32(-3.863,11.144) R35(-2.243,11.373) R37(-1.443,11.373) R39(-0.643,11.373) R40(0.157,11.373) R42(0.958,11.373) R44(1.758,11.373) R46(2.558,11.373) R48(3.358,11.373) R49(4.158,11.373) R54(6.439,11.144) R58(8.156,11.144) R62(9.873,11.144) R66(11.59,11.144) R69(13.307,11.144) R72(15.024,11.144) T7(-15.024,10.649) T11(-13.307,10.649) T14(-11.59,10.649) T18(-9.873,10.649) T22(-8.156,10.649) T26(-6.439,10.649) T30(-4.722,10.649) T33(-3.005,10.649) T35(-2.243,10.573) T37(-1.443,10.573) T39(-0.643,10.573) T40(0.157,10.573) T42(0.958,10.573) T44(1.758,10.573) T46(2.558,10.573) T48(3.358,10.573) T49(4.158,10.573) T51(4.958,10.573) T53(5.758,10.573) T56(7.297,10.649) T60(9.014,10.649) T64(10.732,10.649) T67(12.449,10.649) T71(14.166,10.649) U9(-14.166,10.154) U13(-12.449,10.154) U16(-10.732,10.154) U20(-9.014,10.154) U24(-7.297,10.154) U28(-5.58,10.154) U32(-3.863,10.154) U66(11.59,10.154) U69(13.307,10.154) U72(15.024,10.154) V7(-15.024,9.658) V11(-13.307,9.658) V14(-11.59,9.658) V18(-9.873,9.658) V22(-8.156,9.658) V26(-6.439,9.658) V30(-4.722,9.658) V33(-3.043,9.773) V35(-2.243,9.773) V37(-1.443,9.773) V39(-0.643,9.773) V40(0.157,9.773) V42(0.958,9.773) V44(1.758,9.773) V46(2.558,9.773) V48(3.358,9.773) V49(4.158,9.773) V51(4.958,9.773) V53(5.758,9.773) V55(6.558,9.773) V56(7.358,9.773) V58(8.158,9.773) V60(8.959,9.773) V62(9.759,9.773) V64(10.732,9.658) V67(12.449,9.658) V71(14.166,9.658) W9(-14.166,9.163) W13(-12.449,9.163) W16(-10.732,9.163) W20(-9.014,9.163) W24(-7.297,9.163) W28(-5.58,9.163) W66(11.59,9.163) W69(13.307,9.163) W72(15.024,9.163) Y7(-15.024,8.668) Y11(-13.307,8.668) Y30(-4.506,8.898) Y32(-3.778,8.973) Y33(-3.043,8.973) Y35(-2.243,8.973) Y37(-1.443,8.973) Y39(-0.643,8.973) Y40(0.157,8.973) Y42(0.958,8.973) Y53(5.758,8.973) Y55(6.558,8.973) Y56(7.358,8.973) Y58(8.158,8.973) Y60(8.959,8.973) Y62(9.759,8.973) Y64(10.732,8.668) Y67(12.449,8.668) Y71(14.166,8.668)
  round 0.356 smd: A6(-15.219,18.064) A73(15.219,18.064) AA2(-17.327,8.416) AA4(-16.337,8.416) AA75(16.337,8.416) AA77(17.327,8.416) AB3(-16.832,7.921) AB5(-15.842,7.921) AB74(15.842,7.921) AB76(16.832,7.921) AC2(-17.327,7.426) AC4(-16.337,7.426) AC75(16.337,7.426) AC77(17.327,7.426) AD3(-16.832,6.931) AD5(-15.842,6.931) AD74(15.842,6.931) AD76(16.832,6.931) AE2(-17.327,6.436) AE4(-16.337,6.436) AE75(16.337,6.436) AE77(17.327,6.436) AF3(-16.832,5.941) AF5(-15.842,5.941) AF74(15.842,5.941) AF76(16.832,5.941) AG2(-17.327,5.446) AG4(-16.337,5.446) AG75(16.337,5.446) AG77(17.327,5.446) AH3(-16.832,4.95) AH5(-15.842,4.95) AH74(15.842,4.95) AH76(16.832,4.95) AK2(-17.327,4.455) AK4(-16.337,4.455) AK75(16.337,4.455) AK77(17.327,4.455) AL3(-16.832,3.96) AL5(-15.842,3.96) AL74(15.842,3.96) AL76(16.832,3.96) AM2(-17.327,3.465) AM4(-16.337,3.465) AM75(16.337,3.465) AM77(17.327,3.465) AN3(-16.832,2.97) AN5(-15.842,2.97) AN74(15.842,2.97) AN76(16.832,2.97) AP2(-17.327,2.475) AP4(-16.337,2.475) AP75(16.337,2.475) AP77(17.327,2.475) AR3(-16.832,1.98) AR5(-15.842,1.98) AR74(15.842,1.98) AR76(16.832,1.98) AT2(-17.327,1.485) AT4(-16.337,1.485) AT75(16.337,1.485) AT77(17.327,1.485) AU3(-16.832,0.99) AU5(-15.842,0.99) AU74(15.842,0.99) AU76(16.832,0.99) AV2(-17.327,0.495) AV4(-16.337,0.495) AV75(16.337,0.495) AV77(17.327,0.495) AW3(-16.832,0) AW5(-15.842,0) AW74(15.842,0) AW76(16.832,0) AY2(-17.327,-0.495) AY4(-16.337,-0.495) AY75(16.337,-0.495) AY77(17.327,-0.495) B3(-16.642,17.353) B10(-13.366,17.327) B13(-12.376,17.327) B15(-11.386,17.327) B17(-10.396,17.327) B19(-9.406,17.327) B21(-8.416,17.327) B24(-7.426,17.327) B26(-6.436,17.327) B28(-5.446,17.327) B30(-4.455,17.327) B32(-3.465,17.327) B35(-2.475,17.327) B37(-1.485,17.327) B39(-0.495,17.327) B41(0.495,17.327) B43(1.485,17.327) B46(2.475,17.327) B48(3.465,17.327) B50(4.455,17.327) B52(5.446,17.327) B54(6.436,17.327) B57(7.426,17.327) B59(8.416,17.327) B61(9.406,17.327) B63(10.396,17.327) B65(11.386,17.327) B67(12.376,17.327) B69(13.366,17.327) B76(16.642,17.353) BA3(-16.832,-0.99) BA5(-15.842,-0.99) BA74(15.842,-0.99) BA76(16.832,-0.99) BB2(-17.327,-1.485) BB4(-16.337,-1.485) BB75(16.337,-1.485) BB77(17.327,-1.485) BD3(-16.832,-1.98) BD5(-15.842,-1.98) BD74(15.842,-1.98) BD76(16.832,-1.98) BE2(-17.327,-2.475) BE4(-16.337,-2.475) BE75(16.337,-2.475) BE77(17.327,-2.475) BF3(-16.832,-2.97) BF5(-15.842,-2.97) BF74(15.842,-2.97) BF76(16.832,-2.97) BG2(-17.327,-3.465) BG4(-16.337,-3.465) BG75(16.337,-3.465) BG77(17.327,-3.465) BH3(-16.832,-3.96) BH5(-15.842,-3.96) BH74(15.842,-3.96) BH76(16.832,-3.96) BJ2(-17.327,-4.455) BJ4(-16.337,-4.455) BJ75(16.337,-4.455) BJ77(17.327,-4.455) BK3(-16.832,-4.95) BK5(-15.842,-4.95) BK74(15.842,-4.95) BK76(16.832,-4.95) BL2(-17.327,-5.446) BL4(-16.337,-5.446) BL75(16.337,-5.446) BL77(17.327,-5.446) BM3(-16.832,-5.941) BM5(-15.842,-5.941) BM74(15.842,-5.941) BM76(16.832,-5.941) BN2(-17.327,-6.436) BN4(-16.337,-6.436) BN75(16.337,-6.436) BN77(17.327,-6.436) BP3(-16.832,-6.931) BP5(-15.842,-6.931) BP74(15.842,-6.931) BP76(16.832,-6.931) BR2(-17.327,-7.426) BR4(-16.337,-7.426) BR75(16.337,-7.426) BR77(17.327,-7.426) BT3(-16.832,-7.921) BT5(-15.842,-7.921) BT74(15.842,-7.921) BT76(16.832,-7.921) BU2(-17.327,-8.416) BU4(-16.337,-8.416) BU75(16.337,-8.416) BU77(17.327,-8.416) BW3(-16.832,-8.911) BW5(-15.842,-8.911) BW74(15.842,-8.911) BW76(16.832,-8.911) BY2(-17.327,-9.406) BY4(-16.337,-9.406) BY75(16.337,-9.406) BY77(17.327,-9.406) C2(-17.353,16.642) C9(-13.861,16.832) C12(-12.871,16.832) C14(-11.881,16.832) C16(-10.891,16.832) C18(-9.901,16.832) C20(-8.911,16.832) C23(-7.921,16.832) C25(-6.931,16.832) C27(-5.941,16.832) C29(-4.95,16.832) C31(-3.96,16.832) C34(-2.97,16.832) C36(-1.98,16.832) C38(-0.99,16.832) C40(0,16.832) C42(0.99,16.832) C44(1.98,16.832) C47(2.97,16.832) C49(3.96,16.832) C51(4.95,16.832) C53(5.941,16.832) C55(6.931,16.832) C58(7.921,16.832) C60(8.911,16.832) C62(9.901,16.832) C64(10.891,16.832) C66(11.881,16.832) C68(12.871,16.832) C70(13.861,16.832) C77(17.353,16.642) CA3(-16.832,-9.901) CA5(-15.842,-9.901) CA74(15.842,-9.901) CA76(16.832,-9.901) CB2(-17.327,-10.396) CB4(-16.337,-10.396) CB75(16.337,-10.396) CB77(17.327,-10.396) CC3(-16.832,-10.891) CC5(-15.842,-10.891) CC74(15.842,-10.891) CC76(16.832,-10.891) CD2(-17.327,-11.386) CD4(-16.337,-11.386) CD75(16.337,-11.386) CD77(17.327,-11.386) CE3(-16.832,-11.881) CE5(-15.842,-11.881) CE74(15.842,-11.881) CE76(16.832,-11.881) CF2(-17.327,-12.376) CF4(-16.337,-12.376) CF75(16.337,-12.376) CF77(17.327,-12.376) CG3(-16.832,-12.871) CG5(-15.842,-12.871) CG74(15.842,-12.871) CG76(16.832,-12.871) CH2(-17.327,-13.366) CH4(-16.337,-13.366) CH75(16.337,-13.366) CH77(17.327,-13.366) CJ3(-16.832,-13.861) CJ5(-15.842,-13.861) CJ74(15.842,-13.861) CJ76(16.832,-13.861) CK4(-16.337,-14.356) CK75(16.337,-14.356) CM1(-18.064,-15.219) CM78(18.064,-15.219) CP9(-13.861,-15.842) CP12(-12.871,-15.842) CP14(-11.881,-15.842) CP16(-10.891,-15.842) CP18(-9.901,-15.842) CP20(-8.911,-15.842) CP23(-7.921,-15.842) CP25(-6.931,-15.842) CP27(-5.941,-15.842) CP29(-4.95,-15.842) CP31(-3.96,-15.842) CP34(-2.97,-15.842) CP36(-1.98,-15.842) CP38(-0.99,-15.842) CP40(0,-15.842) CP42(0.99,-15.842) CP44(1.98,-15.842) CP47(2.97,-15.842) CP49(3.96,-15.842) CP51(4.95,-15.842) CP53(5.941,-15.842) CP55(6.931,-15.842) CP58(7.921,-15.842) CP60(8.911,-15.842) CP62(9.901,-15.842) CP64(10.891,-15.842) CP66(11.881,-15.842) CP68(12.871,-15.842) CP70(13.861,-15.842) CR2(-17.353,-16.642) CR8(-14.356,-16.337) CR10(-13.366,-16.337) CR13(-12.376,-16.337) CR15(-11.386,-16.337) CR17(-10.396,-16.337) CR19(-9.406,-16.337) CR21(-8.416,-16.337) CR24(-7.426,-16.337) CR26(-6.436,-16.337) CR28(-5.446,-16.337) CR30(-4.455,-16.337) CR32(-3.465,-16.337) CR35(-2.475,-16.337) CR37(-1.485,-16.337) CR39(-0.495,-16.337) CR41(0.495,-16.337) CR43(1.485,-16.337) CR46(2.475,-16.337) CR48(3.465,-16.337) CR50(4.455,-16.337) CR52(5.446,-16.337) CR54(6.436,-16.337) CR57(7.426,-16.337) CR59(8.416,-16.337) CR61(9.406,-16.337) CR63(10.396,-16.337) CR65(11.386,-16.337) CR67(12.376,-16.337) CR69(13.366,-16.337) CR71(14.356,-16.337) CR77(17.353,-16.642) CT9(-13.861,-16.832) CT12(-12.871,-16.832) CT14(-11.881,-16.832) CT16(-10.891,-16.832) CT18(-9.901,-16.832) CT20(-8.911,-16.832) CT23(-7.921,-16.832) CT25(-6.931,-16.832) CT27(-5.941,-16.832) CT29(-4.95,-16.832) CT31(-3.96,-16.832) CT34(-2.97,-16.832) CT36(-1.98,-16.832) CT38(-0.99,-16.832) CT40(0,-16.832) CT42(0.99,-16.832) CT44(1.98,-16.832) CT47(2.97,-16.832) CT49(3.96,-16.832) CT51(4.95,-16.832) CT53(5.941,-16.832) CT55(6.931,-16.832) CT58(7.921,-16.832) CT60(8.911,-16.832) CT62(9.901,-16.832) CT64(10.891,-16.832) CT66(11.881,-16.832) CT68(12.871,-16.832) CT70(13.861,-16.832) CU3(-16.642,-17.353) CU10(-13.366,-17.327) CU13(-12.376,-17.327) CU15(-11.386,-17.327) CU17(-10.396,-17.327) CU19(-9.406,-17.327) CU21(-8.416,-17.327) CU24(-7.426,-17.327) CU26(-6.436,-17.327) CU28(-5.446,-17.327) CU30(-4.455,-17.327) CU32(-3.465,-17.327) CU35(-2.475,-17.327) CU37(-1.485,-17.327) CU39(-0.495,-17.327) CU41(0.495,-17.327) CU43(1.485,-17.327) CU46(2.475,-17.327) CU48(3.465,-17.327) CU50(4.455,-17.327) CU52(5.446,-17.327) CU54(6.436,-17.327) CU57(7.426,-17.327) CU59(8.416,-17.327) CU61(9.406,-17.327) CU63(10.396,-17.327) CU65(11.386,-17.327) CU67(12.376,-17.327) CU69(13.366,-17.327) CU76(16.642,-17.353) CV6(-15.219,-18.064) CV73(15.219,-18.064) D8(-14.356,16.337) D10(-13.366,16.337) D13(-12.376,16.337) D15(-11.386,16.337) D17(-10.396,16.337) D19(-9.406,16.337) D21(-8.416,16.337) D24(-7.426,16.337) D26(-6.436,16.337) D28(-5.446,16.337) D30(-4.455,16.337) D32(-3.465,16.337) D35(-2.475,16.337) D37(-1.485,16.337) D39(-0.495,16.337) D41(0.495,16.337) D43(1.485,16.337) D46(2.475,16.337) D48(3.465,16.337) D50(4.455,16.337) D52(5.446,16.337) D54(6.436,16.337) D57(7.426,16.337) D59(8.416,16.337) D61(9.406,16.337) D63(10.396,16.337) D65(11.386,16.337) D67(12.376,16.337) D69(13.366,16.337) D71(14.356,16.337) E9(-13.861,15.842) E12(-12.871,15.842) E14(-11.881,15.842) E16(-10.891,15.842) E18(-9.901,15.842) E20(-8.911,15.842) E23(-7.921,15.842) E25(-6.931,15.842) E27(-5.941,15.842) E29(-4.95,15.842) E31(-3.96,15.842) E34(-2.97,15.842) E36(-1.98,15.842) E38(-0.99,15.842) E40(0,15.842) E42(0.99,15.842) E44(1.98,15.842) E47(2.97,15.842) E49(3.96,15.842) E51(4.95,15.842) E53(5.941,15.842) E55(6.931,15.842) E58(7.921,15.842) E60(8.911,15.842) E62(9.901,15.842) E64(10.891,15.842) E66(11.881,15.842) E68(12.871,15.842) E70(13.861,15.842) F1(-18.064,15.219) F78(18.064,15.219) H4(-16.337,14.356) H75(16.337,14.356) J3(-16.832,13.861) J5(-15.842,13.861) J74(15.842,13.861) J76(16.832,13.861) K2(-17.327,13.366) K4(-16.337,13.366) K75(16.337,13.366) K77(17.327,13.366) L3(-16.832,12.871) L5(-15.842,12.871) L74(15.842,12.871) L76(16.832,12.871) M2(-17.327,12.376) M4(-16.337,12.376) M75(16.337,12.376) M77(17.327,12.376) N3(-16.832,11.881) N5(-15.842,11.881) N74(15.842,11.881) N76(16.832,11.881) R2(-17.327,11.386) R4(-16.337,11.386) R75(16.337,11.386) R77(17.327,11.386) T3(-16.832,10.891) T5(-15.842,10.891) T74(15.842,10.891) T76(16.832,10.891) U2(-17.327,10.396) U4(-16.337,10.396) U75(16.337,10.396) U77(17.327,10.396) V3(-16.832,9.901) V5(-15.842,9.901) V74(15.842,9.901) V76(16.832,9.901) W2(-17.327,9.406) W4(-16.337,9.406) W75(16.337,9.406) W77(17.327,9.406) Y3(-16.832,8.911) Y5(-15.842,8.911) Y74(15.842,8.911) Y76(16.832,8.911)
  oval 0.254x0.343 smd: A9(-13.861,18.064) A12(-12.871,18.064) A14(-11.881,18.064) A16(-10.891,18.064) A18(-9.901,18.064) A20(-8.911,18.064) A23(-7.921,18.064) A25(-6.931,18.064) A27(-5.941,18.064) A29(-4.95,18.064) A31(-3.96,18.064) A34(-2.97,18.064) A36(-1.98,18.064) A38(-0.99,18.064) A40(0,18.064) A42(0.99,18.064) A44(1.98,18.064) A47(2.97,18.064) A49(3.96,18.064) A51(4.95,18.064) A53(5.941,18.064) A55(6.931,18.064) A58(7.921,18.064) A60(8.911,18.064) A62(9.901,18.064) A64(10.891,18.064) A66(11.881,18.064) A68(12.871,18.064) A70(13.861,18.064) CV9(-13.861,-18.064) CV12(-12.871,-18.064) CV14(-11.881,-18.064) CV16(-10.891,-18.064) CV18(-9.901,-18.064) CV20(-8.911,-18.064) CV23(-7.921,-18.064) CV25(-6.931,-18.064) CV27(-5.941,-18.064) CV29(-4.95,-18.064) CV31(-3.96,-18.064) CV34(-2.97,-18.064) CV36(-1.98,-18.064) CV38(-0.99,-18.064) CV40(0,-18.064) CV42(0.99,-18.064) CV44(1.98,-18.064) CV47(2.97,-18.064) CV49(3.961,-18.064) CV51(4.951,-18.064) CV53(5.941,-18.064) CV55(6.931,-18.064) CV58(7.921,-18.064) CV60(8.911,-18.064) CV62(9.901,-18.064) CV64(10.891,-18.064) CV66(11.881,-18.064) CV68(12.871,-18.064) CV70(13.862,-18.064)
  round 0.584 smd: A77(17.353,18.064) B78(18.064,17.353) CU1(-18.064,-17.353) CU78(18.064,-17.353) CV2(-17.353,-18.064) CV77(17.353,-18.064)
  oval 0.343x0.254 smd: AB1(-18.064,7.921) AB78(18.064,7.921) AD1(-18.064,6.931) AD78(18.064,6.931) AF1(-18.064,5.941) AF78(18.064,5.941) AH1(-18.064,4.95) AH78(18.064,4.95) AL1(-18.064,3.96) AL78(18.064,3.96) AN1(-18.064,2.97) AN78(18.064,2.97) AR1(-18.064,1.98) AR78(18.064,1.98) AU1(-18.064,0.99) AU78(18.064,0.99) AW1(-18.064,0) AW78(18.064,0) BA1(-18.064,-0.99) BA78(18.064,-0.99) BD1(-18.064,-1.98) BD78(18.064,-1.98) BF1(-18.064,-2.97) BF78(18.064,-2.97) BH1(-18.064,-3.96) BH78(18.064,-3.96) BK1(-18.064,-4.95) BK78(18.064,-4.95) BM1(-18.064,-5.941) BM78(18.064,-5.941) BP1(-18.064,-6.931) BP78(18.064,-6.931) BT1(-18.064,-7.921) BT78(18.064,-7.921) BW1(-18.064,-8.911) BW78(18.064,-8.911) CA1(-18.064,-9.901) CA78(18.064,-9.901) CC1(-18.064,-10.891) CC78(18.064,-10.891) CE1(-18.064,-11.881) CE78(18.064,-11.881) CG1(-18.064,-12.871) CG78(18.064,-12.871) CJ1(-18.064,-13.861) CJ78(18.064,-13.861) J1(-18.064,13.861) J78(18.064,13.861) L1(-18.064,12.871) L78(18.064,12.871) N1(-18.064,11.881) N78(18.064,11.881) T1(-18.064,10.891) T78(18.064,10.891) V1(-18.064,9.901) V78(18.064,9.901) Y1(-18.064,8.911) Y78(18.064,8.911)
  round 0.305 smd: B5(-15.931,17.353) B8(-14.54,17.327) B71(14.54,17.327) B74(15.931,17.353) C3(-16.642,16.642) C7(-15.136,16.832) C73(15.136,16.832) C76(16.642,16.642) CL2(-17.327,-14.54) CL5(-15.842,-14.851) CL74(15.842,-14.851) CL77(17.327,-14.54) CM3(-16.832,-15.136) CM76(16.832,-15.136) CN4(-16.337,-15.73) CN5(-15.641,-15.641) CN74(15.641,-15.641) CN75(16.337,-15.73) CP2(-17.353,-15.931) CP7(-14.851,-15.842) CP72(14.851,-15.842) CP77(17.353,-15.931) CR3(-16.642,-16.642) CR5(-15.73,-16.337) CR74(15.73,-16.337) CR76(16.642,-16.642) CT7(-15.136,-16.832) CT73(15.136,-16.832) CU5(-15.841,-17.365) CU8(-14.54,-17.327) CU71(14.54,-17.327) CU74(15.931,-17.353) D5(-15.73,16.337) D74(15.73,16.337) E2(-17.353,15.931) E4(-16.337,15.73) E5(-15.641,15.641) E7(-14.851,15.842) E72(14.851,15.842) E74(15.641,15.641) E75(16.337,15.73) E77(17.353,15.931) F3(-16.832,15.136) F76(16.832,15.136) G5(-15.842,14.851) G74(15.842,14.851) H2(-17.327,14.54) H77(17.327,14.54)
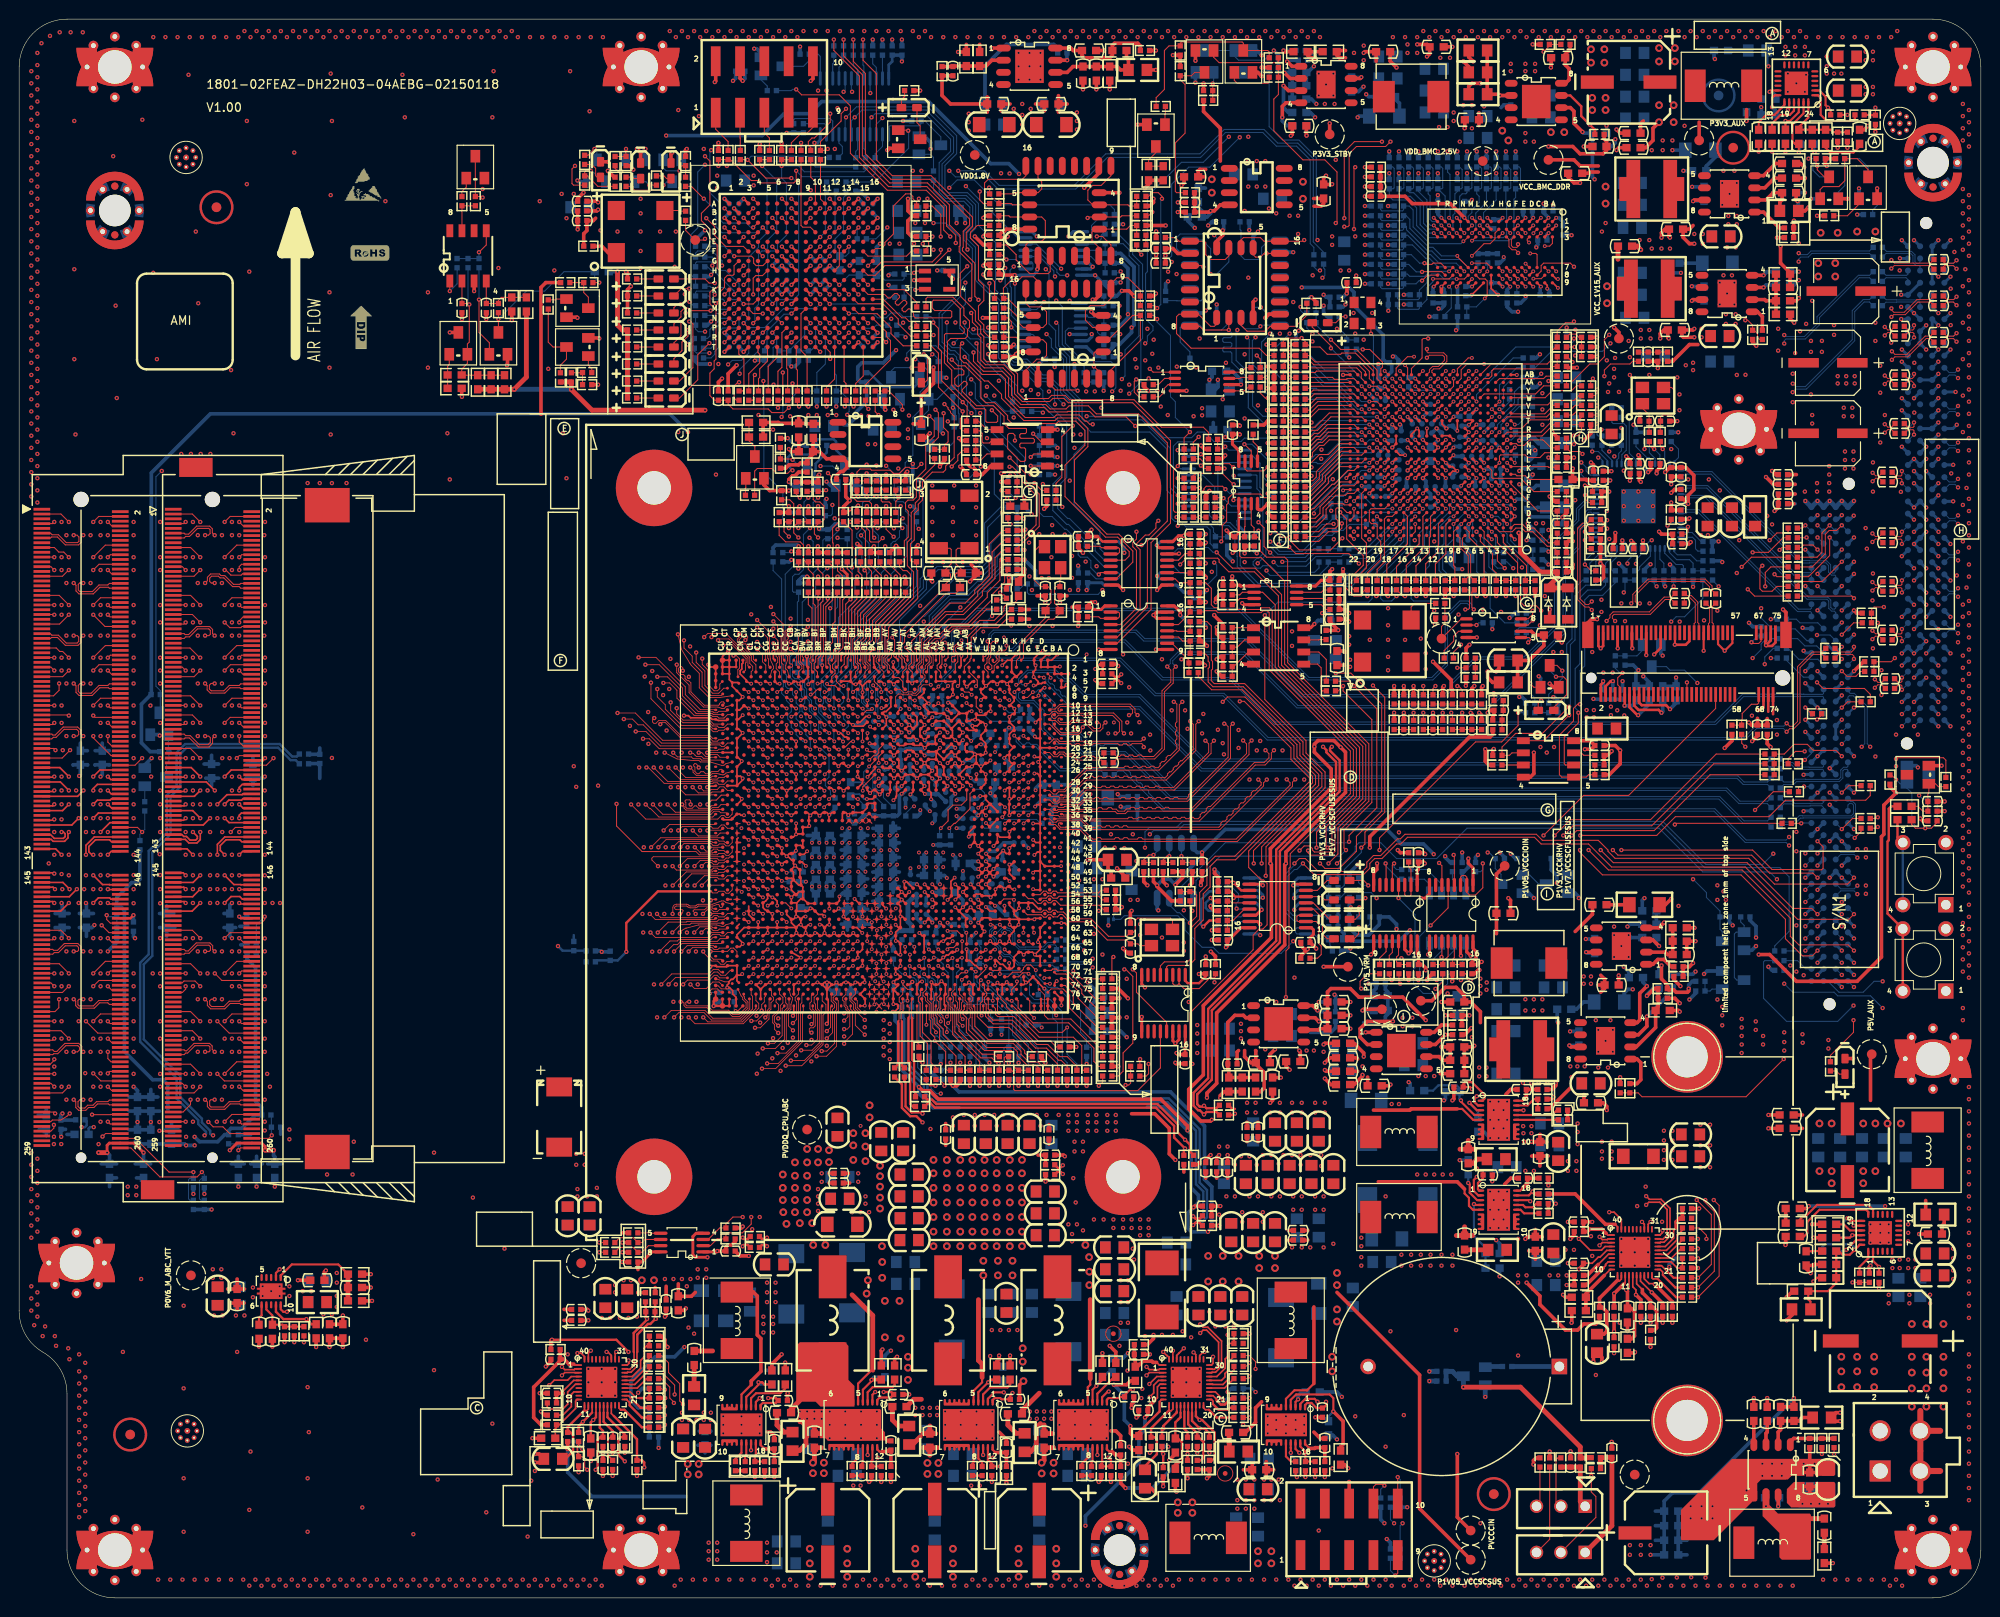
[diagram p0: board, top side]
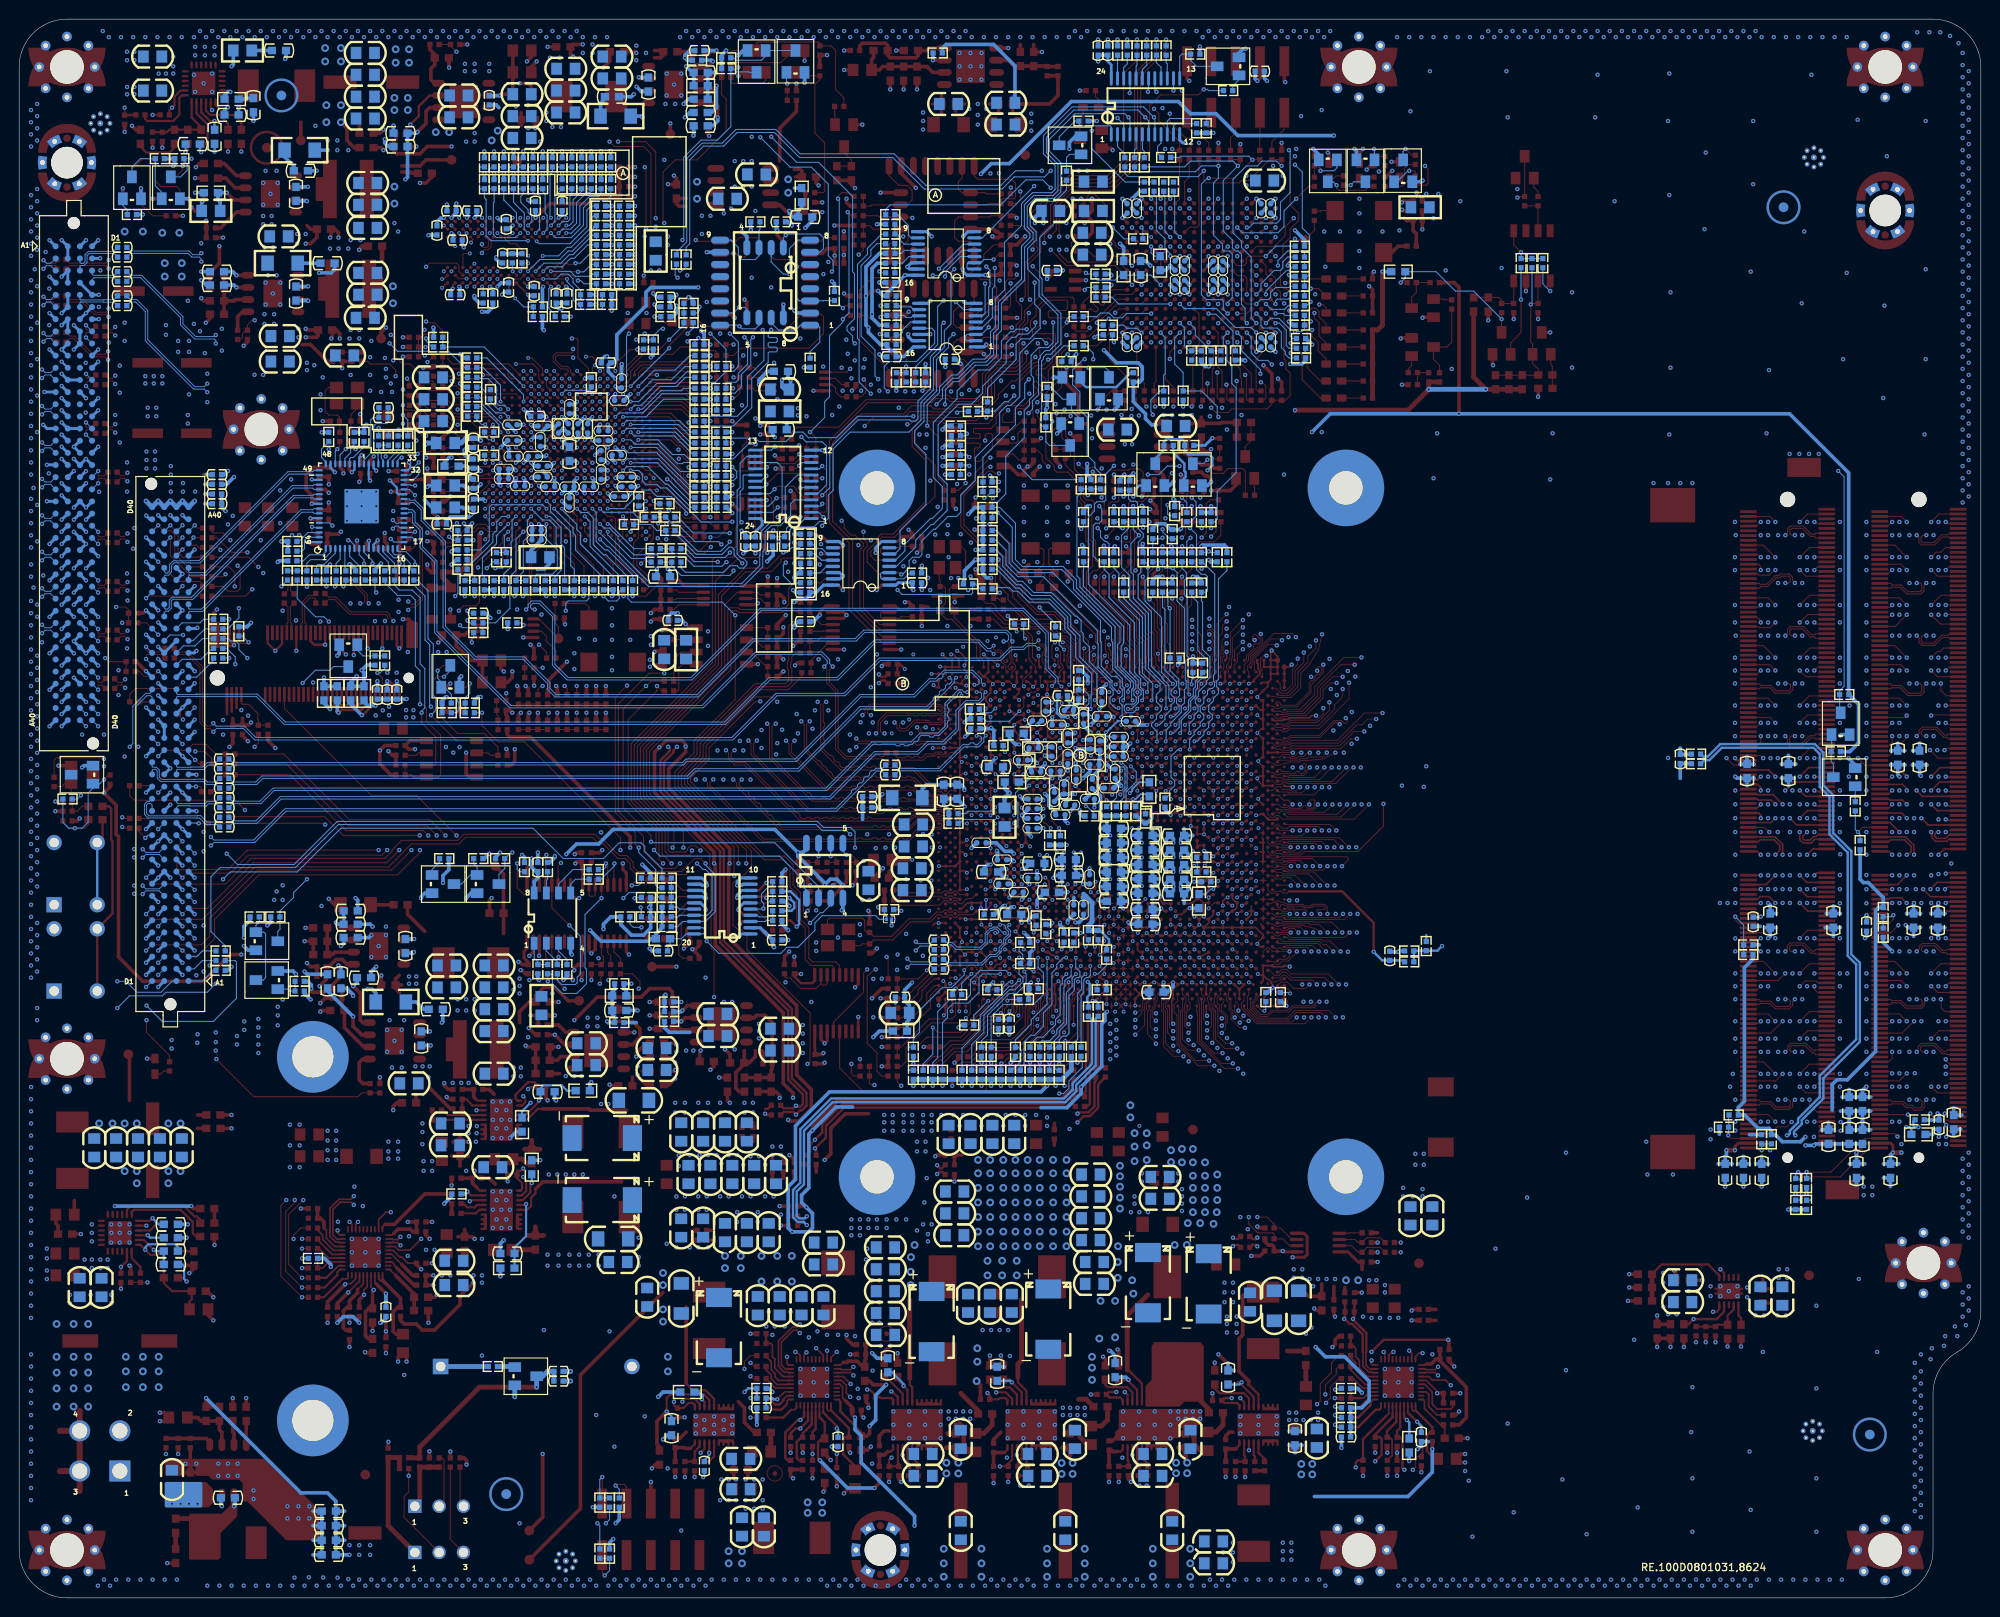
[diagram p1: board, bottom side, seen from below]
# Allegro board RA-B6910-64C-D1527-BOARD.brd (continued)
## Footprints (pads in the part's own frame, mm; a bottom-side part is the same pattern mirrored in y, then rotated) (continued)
HX42003_4
  rect 2.21x2.21 hole 1.6: 1(0,4.2)
  round 2.21 hole 1.6: 2(4.2,4.2) 3(0,0) 4(4.2,0)
L0603
  rect 0.864x0.787 smd: 1(-0.737,0) 2(0.737,0)
L0805
  rect 1.118x1.27 smd: 1(-0.965,0) 2(0.965,0)
L1206
  rect 1.321x1.6 smd: 1(-1.575,0) 2(1.575,0)
L_7M2X6M5X3
  rect 2.2x3.4 smd: 1(-2.95,0) 2(2.95,0)
L_11M50X7M00X9M20
  rect 4.5x2.9 smd: 1(-4.55,0) 2(4.55,0)
LED_SMT0603
  custom 0.191x0.191 smd: 1(0.813,0) 2(-0.813,0)
MARK
  round 1.016 smd: 1(0,0)
MARK_SYMBOL
  round 0.508 smd: 1(0,0)
MSOP_8_1M1_2
  oval 0.35x1.45 smd: 1(-0.975,-2.225) 2(-0.325,-2.225) 3(0.325,-2.225) 4(0.975,-2.225) 5(0.975,2.225) 6(0.325,2.225) 7(-0.325,2.225) 8(-0.975,2.225)
MWSA0603S
  rect 2.3x3.3 smd: 1(-2.85,0) 2(2.85,0)
NR6045T100M
  custom 0.55x0.55 smd: 1(-2.3,0) 2(2.3,0)
OSC_SMD3M2X2M5
  rect 1.4x1.2 smd: 1(-1.1,-0.85) 2(1.1,-0.85) 3(1.1,0.85) 4(-1.1,0.85)
QFN_10_YEP2M40X1M65
  oval 0.25x0.75 smd: 1(-1,-1.425) 2(-0.5,-1.425) 3(0,-1.425) 4(0.5,-1.425) 5(1,-1.425) 6(1,1.425) 7(0.5,1.425) 8(0,1.425) 9(-0.5,1.425) 10(-1,1.425)
  custom 0.412x0.412 smd: 11(0,0)
QFN_24_EP2M45
  oval 0.75x0.25 smd: 1(-1.925,1.25) 2(-1.925,0.75) 3(-1.925,0.25) 4(-1.925,-0.25) 5(-1.925,-0.75) 6(-1.925,-1.25) 13(1.925,-1.25) 14(1.925,-0.75) 15(1.925,-0.25) 16(1.925,0.25) 17(1.925,0.75) 18(1.925,1.25)
  oval 0.25x0.75 smd: 7(-1.25,-1.925) 8(-0.75,-1.925) 9(-0.25,-1.925) 10(0.25,-1.925) 11(0.75,-1.925) 12(1.25,-1.925) 19(1.25,1.925) 20(0.75,1.925) 21(0.25,1.925) 22(-0.25,1.925) 23(-0.75,1.925) 24(-1.25,1.925)
  rect 2.45x2.45 smd: 25(0,0)
QFN_40_EPAD3M25
  oval 0.7x0.2 smd: 1(-2.4,1.8) 2(-2.4,1.4) 3(-2.4,1) 4(-2.4,0.6) 5(-2.4,0.2) 6(-2.4,-0.2) 7(-2.4,-0.6) 8(-2.4,-1) 9(-2.4,-1.4) 10(-2.4,-1.8) 21(2.4,-1.8) 22(2.4,-1.4) 23(2.4,-1) 24(2.4,-0.6) 25(2.4,-0.2) 26(2.4,0.2) 27(2.4,0.6) 28(2.4,1) 29(2.4,1.4) 30(2.4,1.8)
  oval 0.2x0.7 smd: 11(-1.8,-2.4) 12(-1.4,-2.4) 13(-1,-2.4) 14(-0.6,-2.4) 15(-0.2,-2.4) 16(0.2,-2.4) 17(0.6,-2.4) 18(1,-2.4) 19(1.4,-2.4) 20(1.8,-2.4) 31(1.8,2.4) 32(1.4,2.4) 33(1,2.4) 34(0.6,2.4) 35(0.2,2.4) 36(-0.2,2.4) 37(-0.6,2.4) 38(-1,2.4) 39(-1.4,2.4) 40(-1.8,2.4)
  rect 3.25x3.25 smd: 41(0,0)
QFN_64_EP3M60
  oval 0.75x0.25 smd: 1(-4.425,3.75) 2(-4.425,3.25) 3(-4.425,2.75) 4(-4.425,2.25) 5(-4.425,1.75) 6(-4.425,1.25) 7(-4.425,0.75) 8(-4.425,0.25) 9(-4.425,-0.25) 10(-4.425,-0.75) 11(-4.425,-1.25) 12(-4.425,-1.75) 13(-4.425,-2.25) 14(-4.425,-2.75) 15(-4.425,-3.25) 16(-4.425,-3.75) 33(4.425,-3.75) 34(4.425,-3.25) 35(4.425,-2.75) 36(4.425,-2.25) 37(4.425,-1.75) 38(4.425,-1.25) 39(4.425,-0.75) 40(4.425,-0.25) 41(4.425,0.25) 42(4.425,0.75) 43(4.425,1.25) 44(4.425,1.75) 45(4.425,2.25) 46(4.425,2.75) 47(4.425,3.25) 48(4.425,3.75)
  oval 0.25x0.75 smd: 17(-3.75,-4.425) 18(-3.25,-4.425) 19(-2.75,-4.425) 20(-2.25,-4.425) 21(-1.75,-4.425) 22(-1.25,-4.425) 23(-0.75,-4.425) 24(-0.25,-4.425) 25(0.25,-4.425) 26(0.75,-4.425) 27(1.25,-4.425) 28(1.75,-4.425) 29(2.25,-4.425) 30(2.75,-4.425) 31(3.25,-4.425) 32(3.75,-4.425) 49(3.75,4.425) 50(3.25,4.425) 51(2.75,4.425) 52(2.25,4.425) 53(1.75,4.425) 54(1.25,4.425) 55(0.75,4.425) 56(0.25,4.425) 57(-0.25,4.425) 58(-0.75,4.425) 59(-1.25,4.425) 60(-1.75,4.425) 61(-2.25,4.425) 62(-2.75,4.425) 63(-3.25,4.425) 64(-3.75,4.425)
  rect 3.6x3.6 smd: 65(0,0)
R0402
  rect 0.559x0.559 smd: 1(-0.483,0) 2(0.483,0)
R0603
  rect 0.864x0.787 smd: 1(-0.737,0) 2(0.737,0)
R0805
  rect 1.118x1.27 smd: 1(-0.965,0) 2(0.965,0)
R1206
  rect 1.321x1.6 smd: 1(-1.575,0) 2(1.575,0)
R2512
  rect 2.6x3.5 smd: 1(-2.825,0) 2(2.825,0)
SCREW_HOLE_7M50X4M30_PST
  round 7.5 hole 4.3: 1(0,0)
SCREW_N_M_3_5MM_1
  round 3.5 hole 3.5 unplated: (0,0)
  round 1.016 hole 0.508: 2(-2.9,0) 3(0,3.175) 4(2.9,0) 5(0,-3.175) 6(2.235,2.235) 7(2.235,-2.235) 8(-2.235,-2.235) 9(-2.235,2.235)
  custom 1.003x1.003 smd: 10(0,0) 11(0,0) 12(0,0) 13(0,0)
SCREW_NEW_M_3_3MM
  round 3.3 hole 3.3 unplated: (0,0)
  round 0.914 hole 0.508: 2(2.55,0) 3(1.275,-2.208) 4(-1.275,-2.208) 5(-2.55,0) 6(-1.275,2.208) 7(1.275,2.208)
  custom 0.75x0.75 smd: 8(0,2.55) 9(0,-2.55) 10(0,2.55) 11(0,-2.55)
SIP_3P
  rect 1.4x1.4 hole 1: 1(0,0)
  round 1.4 hole 1: 2(2.54,0) 3(5.08,0)
SMD5X7
  rect 1.8x2 smd: 1(-2.54,-2.2) 2(2.54,-2.2) 3(2.54,2.2) 4(-2.54,2.2)
SMD_32768HZ
  rect 1.3x1.9 smd: 1(-2.75,-1.6) 2(2.75,-1.6) 3(2.75,1.6) 4(-2.75,1.6)
SO_8
  oval 0.711x1.778 smd: 1(-1.905,-2.87) 2(-0.635,-2.87) 3(0.635,-2.87) 4(1.905,-2.87) 5(1.905,2.87) 6(0.635,2.87) 7(-0.635,2.87) 8(-1.905,2.87)
SO_16_2M65
  oval 0.72x1.9 smd: 1(-4.445,-4.7) 2(-3.175,-4.7) 3(-1.905,-4.7) 4(-0.635,-4.7) 5(0.635,-4.7) 6(1.905,-4.7) 7(3.175,-4.7) 8(4.445,-4.7) 9(4.445,4.7) 10(3.175,4.7) 11(1.905,4.7) 12(0.635,4.7) 13(-0.635,4.7) 14(-1.905,4.7) 15(-3.175,4.7) 16(-4.445,4.7)
SOC_W_8
  oval 0.72x1.61 smd: 1(-1.905,-3.65) 2(-0.635,-3.65) 3(0.635,-3.65) 4(1.905,-3.65) 5(1.905,3.65) 6(0.635,3.65) 7(-0.635,3.65) 8(-1.905,3.65)
SOD_123
  rect 0.914x1.219 smd: 1(1.638,0) 2(-1.638,0)
SOIC_8_2M50
  rect 0.72x1.35 smd: 1(-1.905,-2.625) 2(-0.635,-2.625) 3(0.635,-2.625) 4(1.905,-2.625) 5(1.905,2.625) 6(0.635,2.625) 7(-0.635,2.625) 8(-1.905,2.625)
SOP_8
  rect 0.72x1.35 smd: 1(-1.905,-2.625) 2(-0.635,-2.625) 3(0.635,-2.625) 4(1.905,-2.625) 5(1.905,2.625) 6(0.635,2.625) 7(-0.635,2.625) 8(-1.905,2.625)
SOP_8_EP2M90X2M00
  oval 0.72x1.35 smd: 1(-1.905,-2.625) 2(-0.635,-2.625) 3(0.635,-2.625) 4(1.905,-2.625) 5(1.905,2.625) 6(0.635,2.625) 7(-0.635,2.625) 8(-1.905,2.625)
  rect 2.9x2 smd: 9(0,0)
SOP_8P
  oval 0.72x1.35 smd: 1(-1.905,-2.625) 2(-0.635,-2.625) 3(0.635,-2.625) 4(1.905,-2.625) 5(1.905,2.625) 6(0.635,2.625) 7(-0.635,2.625) 8(-1.905,2.625)
  rect 3.5x3 smd: 9(0,0)
SOP_8P_EP3M50X3M00
  oval 0.72x1.55 smd: 1(-1.905,-2.725) 2(-0.635,-2.725) 3(0.635,-2.725) 4(1.905,-2.725) 5(1.905,2.725) 6(0.635,2.725) 7(-0.635,2.725) 8(-1.905,2.725)
  rect 3.5x3 smd: 9(0,0)
SOT_23
  rect 1.321x1.016 smd: 1(1.143,-0.947) 2(1.143,0.947) 3(-1.143,0)
SWITCH_4
  rect 1.6x1.6 hole 1: 1(0,0)
  round 1.6 hole 1: 2(6.5,0) 3(6.5,4.5) 4(0,4.5)
TEST_40
  round 1.016 smd: 1(0,0)
TPS3823
  rect 1.27x0.508 smd: 1(1.27,-0.953) 2(1.27,0) 3(1.27,0.953) 4(-1.27,0.953) 5(-1.27,-0.953)
TSSOP_8
  oval 0.35x1.31 smd: 1(-0.925,-2.845) 2(-0.275,-2.845) 3(0.375,-2.845) 4(1.025,-2.845) 5(1.025,2.845) 6(0.375,2.845) 7(-0.275,2.845) 8(-0.925,2.845)
TSSOP_16_1M10
  oval 0.35x1.5 smd: 1(-2.275,-2.95) 2(-1.625,-2.95) 3(-0.975,-2.95) 4(-0.325,-2.95) 5(0.325,-2.95) 6(0.975,-2.95) 7(1.625,-2.95) 8(2.275,-2.95) 9(2.275,2.95) 10(1.625,2.95) 11(0.975,2.95) 12(0.325,2.95) 13(-0.325,2.95) 14(-0.975,2.95) 15(-1.625,2.95) 16(-2.275,2.95)
TSSOP_20_PW
  oval 0.35x1.5 smd: 1(-2.925,-2.95) 2(-2.275,-2.95) 3(-1.625,-2.95) 4(-0.975,-2.95) 5(-0.325,-2.95) 6(0.325,-2.95) 7(0.975,-2.95) 8(1.625,-2.95) 9(2.275,-2.95) 10(2.925,-2.95) 11(2.925,2.95) 12(2.275,2.95) 13(1.625,2.95) 14(0.975,2.95) 15(0.325,2.95) 16(-0.325,2.95) 17(-0.975,2.95) 18(-1.625,2.95) 19(-2.275,2.95) 20(-2.925,2.95)
TSSOP_24
  oval 0.305x1.524 smd: 1(-3.575,-2.925) 2(-2.925,-2.925) 3(-2.275,-2.925) 4(-1.625,-2.925) 5(-0.975,-2.925) 6(-0.325,-2.925) 7(0.325,-2.925) 8(0.975,-2.925) 9(1.625,-2.925) 10(2.275,-2.925) 11(2.925,-2.925) 12(3.575,-2.925) 13(3.575,2.925) 14(2.925,2.925) 15(2.275,2.925) 16(1.625,2.925) 17(0.975,2.925) 18(0.325,2.925) 19(-0.325,2.925) 20(-0.975,2.925) 21(-1.625,2.925) 22(-2.275,2.925) 23(-2.925,2.925) 24(-3.575,2.925)
ZQ20100207_85M00X63M00X18M00
  round 8 hole 3.5: 1(-36,24.5) 2(36,24.5) 3(36,-24.5) 4(-36,-24.5)

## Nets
12V_VCCGBE_P1V05_PCH: C441.1 C442.1 C443.1 C444.1 C460.1 C461.1 C462.1 C463.1 C477.1 L27.1 R693.2 U34.10(VIN) U35.10(VIN)
12V_VCCIN_VCCSCSUS: C342.1 C343.1 C344.1 C345.1 C370.1 C371.1 C372.1 C373.1 C400.1 C401.1 C408.1 C409.1 C410.1 C411.1 CD10.1 CD11.1 L23.1 R647.2 U30.7(VIN) U31.7(VIN) U32.10(VIN)
12V_VDDQ_P2V5_VPP: C484.1 C485.1 C486.1 C487.1 C507.1 C508.1 C509.1 C510.1 C517.1 CD19.1 L30.1 R730.2 U37.7(VIN) U38.10(VIN)
12V_VIN: C62.1 C63.1 C64.1 C65.1 C66.1 C67.1 C68.1 C69.1 C82.1 C83.1 C84.1 C101.2 C102.2 C103.2 C104.2 C120.2 C121.2 C122.2 C123.2 C143.1 C144.1 C145.1 C155.1 C156.1 C157.1 C398.1 C399.1 C475.1 C476.1 C515.1 C516.1 C779.1 C780.1 C781.1 CD1.1 CD2.1 CD3.1 CD4.1 J4.3 J4.4 L23.2 L27.2 L30.2 R35.1 R207.2 R266.1 R267.1 R279.1 R280.1 R1217.1 R1219.1 R1236.1 R1241.2 R1242.2 R1243.2 R1244.1 U4.A40 U4.B40 U4.C40 U4.D40 U6.8(VIN) U7.3(VIN_1) U7.4(VIN_2) U7.5(VIN_3) U7.6(VIN_4) U8.3(VIN_1) U8.4(VIN_2) U8.5(VIN_3) U8.6(VIN_4) U10.8(VIN) U11.8(VIN) U63.8(VIN)
GND: BZ1.2 C1.2 C2.2 C3.1 C4.1 C5.1 C6.1 C7.1 C8.1 C9.1 C10.1 C11.1 C12.1 C13.2 C14.1 C15.1 C16.1 C17.2 C18.1 C19.2 C20.1 C21.2 C22.2 C23.2 C24.2 C25.2 C26.2 C27.2 C28.2 C29.2 C30.2 C31.2 C32.2 C33.2 C34.2 C35.2 C36.2 C37.2 C38.2 C39.2 C40.2 C41.2 C42.2 C43.2 C53.2 C54.2 C55.2 C56.2 C57.2 C62.2 C63.2 C64.2 C65.2 C66.2 C67.2 C68.2 C69.2 C70.2 C71.2 C72.1 C73.2 C74.2 C75.2 C76.2 C77.2 C78.2 C79.2 C80.2 C81.2 C82.2 C83.2 C84.2 C87.2 C88.2 C90.2 C91.2 C92.2 C93.2 C94.2 C96.1 C97.1 C100.2 C101.1 C102.1 C103.1 C104.1 C106.2 C107.2 C108.2 C109.2 C110.2 C111.2 C112.2 C113.2 C114.1 C115.1 C119.2 C120.1 C121.1 C122.1 C123.1 C125.2 C126.2 C127.2 C128.2 C129.2 C130.2 C131.2 C133.2 C134.2 C135.2 C136.2 C137.2 C138.2 C139.2 C140.2 C141.2 C142.2 C143.2 C144.2 C145.2 C148.2 C150.2 C151.2 C152.2 C153.2 C154.2 C155.2 C156.2 C157.2 C160.2 C162.2 C163.2 C164.2 C165.2 C166.2 C168.2 C169.2 C170.2 C171.2 C172.2 C173.2 C174.2 C175.2 C176.2 C177.2 C178.2 C180.2 C181.2 C182.2 C183.2 C185.2 C186.2 C187.2 C188.2 C189.2 C192.2 C194.2 C195.2 C196.2 C197.2 C198.2 C200.2 C201.2 C202.2 C203.2 C204.2 C205.2 C206.2 C207.2 C208.2 C209.2 C210.2 C211.2 C212.2 C213.2 C214.2 C218.2 C219.2 C220.2 C221.2 C222.2 C223.2 C224.2 C225.2 C226.2 C227.2 C228.1 C229.1 C230.2 C231.2 C232.2 C233.2 C234.2 C235.2 C236.2 C237.2 C238.2 C239.2 C240.2 C241.2 C242.2 C243.2 C244.1 C245.2 C246.1 C247.1 C248.2 C249.2 C250.2 C251.2 C252.2 C253.2 C254.1 C255.1 C256.2 C257.2 C258.2 C259.1 C260.2 C261.1 C262.2 C265.2 C266.1 C267.1 C268.2 C269.2 C270.2 C271.2 C272.1 C273.1 C274.2 C275.2 C276.2 C277.2 C278.1 C279.1 C280.2 C281.2 C282.1 C283.1 C284.2 C285.2 C286.2 C287.2 C290.2 C291.2 C294.2 C295.2 C296.2 C297.2 C298.2 C299.2 C300.2 C301.2 C302.2 C303.2 C304.2 C305.2 C306.2 C307.2 C308.2 C309.2 C310.2 C311.2 C312.2 C313.2 C314.2 C315.2 C316.2 C317.2 C318.2 C319.2 C320.2 C321.2 C322.2 C323.2 C324.2 C325.2 C326.2 C327.2 C328.2 C335.2 C336.2 C337.2 C338.1 C339.2 C340.2 C341.2 C342.2 C343.2 C344.2 C345.2 C348.2 C349.2 C350.2 C351.2 C352.2 C353.2 C354.2 C355.2 C356.2 C357.2 C358.2 C359.2 C360.2 C361.2 C362.2 C363.2 C364.2 C365.2 C366.2 C367.2 C368.2 C369.2 C370.2 C371.2 C372.2 C373.2 C376.2 C377.2 C378.2 C379.2 C380.2 C381.2 C382.2 C383.2 C384.2 C385.2 C386.2 C387.2 C388.2 C389.2 C390.2 C391.2 C392.2 C393.2 C394.2 C395.2 C396.2 C397.2 C398.2 C399.2 C400.2 C401.2 C403.2 C404.2 C405.2 C406.2 C407.2 C408.2 C409.2 C410.2 C411.2 C412.2 C413.2 C414.2 C415.2 C416.2 C417.2 C418.2 C419.2 C420.2 C421.2 C423.2 C424.2 C425.2 C426.2 C427.2 C428.2 C429.1 C430.2 C431.2 C433.2 C434.2 C435.2 C436.2 C437.2 C438.2 C439.2 C440.2 C441.2 C442.2 C443.2 C444.2 C445.2 C446.2 C447.2 C448.2 C449.2 C450.2 C452.2 C453.2 C454.2 C456.2 C457.2 C458.2 C459.2 C460.2 C461.2 C462.2 C463.2 C464.2 C465.2 C466.2 C467.2 C468.2 C469.2 C470.2 C472.2 C473.2 C474.2 C475.2 C476.2 C477.2 C478.2 C479.2 C480.2 C481.1 C482.2 C483.2 C484.2 C485.2 C486.2 C487.2 C490.2 C491.2 C492.2 C493.2 C494.2 C495.2 C496.2 C497.2 C498.2 C500.2 C501.2 C502.2 C503.2 C504.2 C506.2 C507.2 C508.2 C509.2 C510.2 C512.2 C513.2 C514.2 C515.2 C516.2 C517.2 C518.2 C519.2 C520.2 C521.2 C524.2 C527.2 C528.2 C550.2 C562.2 C563.2 C564.1 C565.2 C566.2 C567.1 C582.2 C583.2 C586.2 C587.2 C588.2 C589.2 C590.2 C591.1 C592.2 C593.1 C594.2 C595.1 C596.2 C597.2 C598.2 C599.2 C600.2 C601.2 C602.2 C603.2 C604.2 C605.2 C606.2 C607.2 C608.2 C613.2 C614.2 C615.2 C616.2 C617.2 C618.2 C619.2 C620.2 C621.2 C622.2 C623.2 C624.2 C625.2 C626.2 C627.2 C628.2 C629.2 C630.2 C631.2 C632.2 C633.2 C634.2 C635.2 C636.2 C637.2 C638.2 C639.2 C640.2 C641.2 C642.2 C643.2 C644.2 C645.2 C646.2 C647.2 C648.2 C649.2 C650.2 C651.2 C652.2 C653.2 C654.2 C655.2 C656.2 C657.2 C658.2 C659.2 C660.2 C661.2 C662.2 C663.2 C664.2 C665.2 C666.2 C667.2 C668.2 C669.2 C670.2 C671.2 C672.2 C673.2 C674.2 C675.2 C676.2 C677.2 C678.2 C679.1 C680.1 C681.1 C682.1 C683.1 C684.1 C685.1 C686.1 C687.1 C688.1 C689.1 C690.1 C691.1 C692.1 C693.2 C694.2 C695.1 C696.1 C697.2 C698.2 C699.2 C700.2 C701.1 C702.1 C703.1 C704.1 C729.2 C742.2 C743.2 C744.2 C745.2 C746.2 C747.2 C748.2 C749.2 C750.2 C751.2 C752.2 C753.2 C756.2 C757.2 C758.2 C759.1 C760.1 C761.2 C762.2 C763.2 C764.2 C765.2 C767.2 C768.2 C769.2 C770.2 C771.2 C772.2 C773.2 C774.2 C775.2 C776.2 C777.2 C778.2 C779.2 C780.2 C781.2 C785.2 C787.2 C788.2 C789.2 C790.2 C791.2 C792.2 C793.2 C794.2 C795.2 C796.2 C797.2 C798.2 C799.2 C800.2 C801.2 C802.2 C803.2 C804.2 C806.2 C807.2 C808.2 C809.2 C810.2 C811.2 C812.2 C813.2 C814.2 C815.2 C816.2 C817.2 CD1.2 CD2.2 CD3.2 CD4.2 CD6.2 CD7.2 CD8.2 CD9.2 CD10.2 CD11.2 CD12.2 CD13.2 CD14.2 CD16.2 CD17.2 CD18.2 CD19.2 CD20.2 COUPON1.2(GND_1) COUPON1.3(GND_2) COUPON1.4(GND_3) COUPON1.5(GND_4) COUPON1.6(GND_5) COUPON1.7(GND_6) COUPON1.8(GND_7) COUPON1.9(GND_8) COUPON2.2(GND_1) COUPON2.3(GND_2) COUPON2.4(GND_3) COUPON2.5(GND_4) COUPON2.6(GND_5) COUPON2.7(GND_6) COUPON2.8(GND_7) COUPON2.9(GND_8) COUPON3.2(GND_1) COUPON3.3(GND_2) COUPON3.4(GND_3) COUPON3.5(GND_4) COUPON3.6(GND_5) COUPON3.7(GND_6) COUPON3.8(GND_7) COUPON3.9(GND_8) COUPON4.2(GND_1) COUPON4.3(GND_2) COUPON4.4(GND_3) COUPON4.5(GND_4) COUPON4.6(GND_5) COUPON4.7(GND_6) COUPON4.8(GND_7) COUPON4.9(GND_8) D16.2(CATHODE) D17.2(CATHODE) D18.2(CATHODE) D20.2(CATHODE) J1.2 J1.10 J3.1(GND_1) J3.3(GND_3) J3.9(GND_9) J3.15(GND_15) J3.21(GND_21) J3.27(GND_27) J3.33(GND_33) J3.39(GND_39) J3.45(GND_45) J3.51(GND_51) J3.57(GND_57) J3.71(GND_71) J3.73(GND_73) J3.75(GND_75) J3.76(PAD_76) J3.77(PAD_77) J4.1 J4.2 J5.6 J7.1(VSS1) J7.2(VSS2) J7.5(VSS3) J7.6(VSS4) J7.9(VSS5) J7.10(VSS6) J7.12(DM_DBI0_N) J7.14(VSS7) J7.15(VSS8) J7.18(VSS9) J7.19(VSS10) J7.22(VSS11) J7.23(VSS12) J7.26(VSS13) J7.27(VSS14) J7.30(VSS15) J7.31(VSS16) J7.33(DM_DBI1_N) J7.35(VSS17) J7.36(VSS18) J7.39(VSS19) J7.40(VSS20) J7.43(VSS21) J7.44(VSS22) J7.47(VSS23) J7.48(VSS24) J7.51(VSS25) J7.52(VSS26) J7.54(DM_DBI2_N) J7.56(VSS27) J7.57(VSS28) J7.60(VSS29) J7.61(VSS30) J7.64(VSS31) J7.65(VSS32) J7.68(VSS33) J7.69(VSS34) J7.72(VSS35) J7.73(VSS36) J7.75(DM_DBI3_N) J7.77(VSS37) J7.78(VSS38) J7.81(VSS39) J7.82(VSS40) J7.85(VSS41) J7.86(VSS42) J7.89(VSS43) J7.90(VSS44) J7.93(VSS45) J7.94(VSS46) J7.96(DM_DBI8_N) J7.98(VSS47) J7.99(VSS48) J7.102(VSS49) J7.103(VSS50) J7.106(VSS51) J7.107(VSS52) J7.167(VSS53) J7.168(VSS54) J7.171(VSS55) J7.172(VSS56) J7.175(VSS57) J7.176(VSS58) J7.178(DM_DBI4_N) J7.180(VSS59) J7.181(VSS60) J7.184(VSS61) J7.185(VSS62) J7.188(VSS63) J7.189(VSS64) J7.192(VSS65) J7.193(VSS66) J7.196(VSS67) J7.197(VSS68) J7.199(DM_DBI5_N) J7.201(VSS69) J7.202(VSS70) J7.205(VSS71) J7.206(VSS72) J7.209(VSS73) J7.210(VSS74) J7.213(VSS75) J7.214(VSS76) J7.217(VSS77) J7.218(VSS78) J7.220(DM_DBI6_N) J7.222(VSS79) J7.223(VSS80) J7.226(VSS81) J7.227(VSS82) J7.230(VSS83) J7.231(VSS84) J7.234(VSS85) J7.235(VSS86) J7.238(VSS87) J7.239(VSS88) J7.241(DM_DBI7_N) J7.243(VSS89) J7.244(VSS90) J7.247(VSS91) J7.248(VSS92) J7.251(VSS93) J7.252(VSS94) J7.261(PAD_1) J7.262(PAD_2) J8.1(VSS1) J8.2(VSS2) J8.5(VSS3) J8.6(VSS4) J8.9(VSS5) J8.10(VSS6) J8.12(DM_DBI0_N) J8.14(VSS7) J8.15(VSS8) J8.18(VSS9) J8.19(VSS10) J8.22(VSS11) J8.23(VSS12) J8.26(VSS13) J8.27(VSS14) J8.30(VSS15) J8.31(VSS16) J8.33(DM_DBI1_N) J8.35(VSS17) J8.36(VSS18) J8.39(VSS19) J8.40(VSS20) J8.43(VSS21) J8.44(VSS22) J8.47(VSS23) J8.48(VSS24) J8.51(VSS25) J8.52(VSS26) J8.54(DM_DBI2_N) J8.56(VSS27) J8.57(VSS28) J8.60(VSS29) J8.61(VSS30) J8.64(VSS31) J8.65(VSS32) J8.68(VSS33) J8.69(VSS34) J8.72(VSS35) J8.73(VSS36) J8.75(DM_DBI3_N) J8.77(VSS37) J8.78(VSS38) J8.81(VSS39) J8.82(VSS40) J8.85(VSS41) J8.86(VSS42) J8.89(VSS43) J8.90(VSS44) J8.93(VSS45) J8.94(VSS46) J8.96(DM_DBI8_N) J8.98(VSS47) J8.99(VSS48) J8.102(VSS49) J8.103(VSS50) J8.106(VSS51) J8.107(VSS52) J8.167(VSS53) J8.168(VSS54) J8.171(VSS55) J8.172(VSS56) J8.175(VSS57) J8.176(VSS58) J8.178(DM_DBI4_N) J8.180(VSS59) J8.181(VSS60) J8.184(VSS61) J8.185(VSS62) J8.188(VSS63) J8.189(VSS64) J8.192(VSS65) J8.193(VSS66) J8.196(VSS67) J8.197(VSS68) J8.199(DM_DBI5_N) J8.201(VSS69) J8.202(VSS70) J8.205(VSS71) J8.206(VSS72) J8.209(VSS73) J8.210(VSS74) J8.213(VSS75) J8.214(VSS76) J8.217(VSS77) J8.218(VSS78) J8.220(DM_DBI6_N) J8.222(VSS79) J8.223(VSS80) J8.226(VSS81) J8.227(VSS82) J8.230(VSS83) J8.231(VSS84) J8.234(VSS85) J8.235(VSS86) J8.238(VSS87) J8.239(VSS88) J8.241(DM_DBI7_N) J8.243(VSS89) J8.244(VSS90) J8.247(VSS91) J8.248(VSS92) J8.251(VSS93) J8.252(VSS94) J8.261(PAD_1) J8.262(PAD_2) OSC1.2(GND) OSC2.2(GND) OSC3.2(GND_1) OSC3.4(GND_2) OSC4.2(GND_1) OSC4.4(GND_2) OSC5.2(GND_1) OSC5.4(GND_2) OSC6.2(GND) Q1.2 Q2.2(S) Q3.2(S) Q4.2 Q5.2(S) Q6.2(S) Q10.2(E) Q11.2(E) Q15.2(E) Q16.2(E) Q17.2(E) Q18.2(E) Q19.2(E) Q20.2(E) Q21.2(E) Q22.2(E) Q23.2(E) Q24.2(E) Q25.2(E) Q26.2(E) Q27.2(E) Q28.2(E) Q29.2(E) Q30.2(E) Q33.2(E) Q34.2(E) Q35.2(S) Q36.2(S) Q37.2(E) Q38.2(E) Q39.2(E) Q40.3(ANODE) Q41.2(E) R13.2 R14.2 R31.2 R42.2 R43.2 R44.2 R45.2 R73.2 R75.2 R76.2 R77.2 R78.2 R111.2 R127.2 R129.2 R131.2 R139.2 R142.2 R163.2 R164.1 R171.1 R185.1 R191.2 R204.1 R206.2 R210.2 R211.2 R212.2 R213.2 R216.1 R217.1 R221.1 R222.2 R226.1 R230.1 R231.2 R235.2 R236.1 R237.1 R239.1 R246.1 R247.2 R248.1 R249.2 R255.2 R256.2 R257.1 R259.2 R260.2 R261.1 R262.1 R274.2 R275.2 R276.2 R285.2 R286.2 R291.2 R292.2 R293.1 R295.2 R296.2 R297.2 R298.2 R299.1 R307.2 R308.2 R309.2 R314.2 R315.2 R319.2 R322.2 R324.2 R326.1 R327.1 R328.1 R333.1 R346.2 R351.2 R355.2 R358.2 R361.1 R363.2 R365.1 R367.2 R369.1 R370.1 R371.1 R372.1 R374.1 R376.1 R377.1 R379.1 R381.1 R383.1 R385.1 R387.1 R389.1 R391.1 R393.1 R395.1 R397.1 R399.1 R401.1 R404.1 R407.1 R409.1 R411.1 R413.1 R415.1 R417.1 R419.1 R421.1 R423.1 R425.1 R427.1 R429.1 R438.2 R458.1 R464.2 R526.1 R537.1 R548.2 R549.2 R552.2 R569.2 R572.2 R575.2 R577.2 R579.2 R580.1 R582.2 R583.1 R585.2 R587.2 R589.2 R591.2 R598.2 R599.2 R602.1 R603.1 R604.1 R605.1 R606.1 R611.2 R617.1 R630.1 R631.1 R646.2 R649.1 R651.1 R652.1 R667.2 R668.1 R674.2 R675.1 R678.2 R681.2 R692.2 R695.1 R697.1 R698.1 R708.2 R711.2 R715.2 R718.2 R729.2 R732.1 R734.1 R735.1 R748.2 R749.1 R753.2 R756.2 R785.1 R787.1 R790.1 R792.1 R793.1 R794.1 R795.1 R800.1 R801.1 R810.2 R844.1 R895.1 R896.1 R897.2 R898.1 R899.1 R900.1 R901.1 R902.1 R903.1 R904.1 R920.1 R921.1 R922.1 R923.2 R924.2 R925.2 R927.2 R928.2 R929.2 R930.2 R931.2 R932.2 R933.2 R937.1 R946.2 R947.2 R948.2 R949.2 R950.2 R951.2 R952.2 R954.2 R955.2 R956.2 R957.1 R960.2 R962.2 R964.1 R966.1 R967.1 R968.1 R969.1 R978.1 R993.2 R996.2 R1001.1 R1002.1 R1004.1 R1007.1 R1025.1 R1032.1 R1051.1 R1052.1 R1053.2 R1057.1 R1065.1 R1066.1 R1076.1 R1077.1 R1078.1 R1096.1 R1106.1 R1113.1 R1114.1 R1123.2 R1134.1 R1143.1 R1144.2 R1145.1 R1146.2 R1158.1 R1159.2 R1160.1 R1161.2 R1164.1 R1165.1 R1174.1 R1178.1 R1183.1 R1206.1 R1211.1 R1214.2 R1215.2 R1216.1 R1218.2 R1232.1 R1233.1 R1238.2 R1248.1 R1249.2 SINK1.1 SINK1.2 SINK1.3 SINK1.4 SW1.1 SW1.2 SW2.1 SW2.2 U1.4(GND) U2.A1(GNDIO_1) U2.A16(GNDIO_2) U2.B2(GNDIO_4) U2.B15(GNDIO_3) U2.G7(GNDIO_6) U2.G8(GNDIO_7) U2.G9(GNDIO_8) U2.G10(GNDIO_5) U2.H7(GNDINT_1) U2.H9(GNDINT_2) U2.J8(GNDINT_4) U2.J10(GNDINT_3) U2.K7(GNDIO_10) U2.K8(GNDIO_11) U2.K9(GNDIO_12) U2.K10(GNDIO_9) U2.R2(GNDIO_14) U2.R15(GNDIO_13) U2.T1(GNDIO_15) U2.T16(GNDIO_16) U3.2(GND) U4.A4 U4.A7 U4.A10 U4.A13 U4.A15 U4.A16 U4.A18 U4.A19 U4.A21 U4.A22 U4.A24 U4.A25 U4.A27 U4.A28 U4.A30 U4.A33 U4.A36 U4.A39 U4.B2 U4.B3 U4.B5 U4.B6 U4.B8 U4.B9 U4.B11 U4.B12 U4.B14 U4.B17 U4.B20 U4.B23 U4.B26 U4.B29 U4.B31 U4.B32 U4.B34 U4.B35 U4.B39 U4.C1 U4.C4 U4.C7 U4.C10 U4.C13 U4.C15 U4.C16 U4.C18 U4.C19 U4.C21 U4.C22 U4.C24 U4.C25 U4.C27 U4.C28 U4.C30 U4.C33 U4.C36 U4.C39 U4.D2 U4.D3 U4.D5 U4.D6 U4.D8 U4.D9 U4.D11 U4.D12 U4.D14 U4.D17 U4.D20 U4.D23 U4.D26 U4.D29 U4.D31 U4.D32 U4.D34 U4.D35 U4.D37 U4.D39 U5.4(PGND) U5.8(GND) U5.11(EPAD) U6.5(GND) U6.9(EPAD) U7.7(PGND_1) U7.8(PGND_2) U7.9(PGND_3) U7.10(PGND_4) U7.11(PGND_5) U7.12(PGND_6) U7.20(AGND) U7.25(EPAD) U8.7(PGND_1) U8.8(PGND_2) U8.9(PGND_3) U8.10(PGND_4) U8.11(PGND_5) U8.12(PGND_6) U8.20(AGND) U8.25(EPAD) U9.1(GND) U10.5(GND) U10.9(EPAD) U11.5(GND) U11.9(EPAD) U12.1(GND) U15.5(GND) U15.9(EPAD) U16.1(GND) U17.5(GND) U17.9(EPAD) U18.4(GND) U19.4(GND) U20.A1(GND_1) U20.A4(RGMII1RXCTL_GPIOU5) U20.A22(GND_2) U20.AA7(GND_6) U20.AA9(GND_7) U20.AA11(GND_3) U20.AA13(GND_4) U20.AA15(GND_5) U20.AB1(GND_8) U20.AB22(GND_9) U20.C1(RGMII2RXCTL_GPIOV3) U20.C2(RGMII2RXCK_RMII2RCLKI_GPIOV2) U20.C3(RGMII2RXD0_RMII2RXD0_GPIOV4) U20.C6(GND_10) U20.D1(RGMII2RXD1_RMII2RXD1_GPIOV5) U20.D2(RGMII2RXD2_RMII2CRSDV_GPIOV6) U20.E5(GND_69) U20.E6(RGMII2RXD3_RMII2RXER_GPIOV7) U20.E8(GND_11) U20.F1(ADC11_GPIX3) U20.F16(GND_12) U20.G1(ADC13_GPIX5) U20.G2(ADC10_GPIX2) U20.G6(GND_14) U20.G19(GND_13) U20.H3(ADC14_GPIX6) U20.H4(ADC15_GPIX7) U20.H5(ADC12_GPIX4) U20.H6(GND_15) U20.J5(GND_23) U20.J9(GND_24) U20.J10(GND_16) U20.J11(GND_17) U20.J12(GND_18) U20.J13(GND_19) U20.J14(GND_20) U20.J21(GND_21) U20.J22(GND_22) U20.K9(GND_31) U20.K10(GND_25) U20.K11(GND_26) U20.K12(GND_27) U20.K13(GND_28) U20.K14(GND_29) U20.K16(GND_30) U20.L9(GND_37) U20.L10(GND_32) U20.L11(GND_33) U20.L12(GND_34) U20.L13(GND_35) U20.L14(GND_36) U20.M1(GND_38) U20.M2(GND_46) U20.M3(GND_47) U20.M4(GND_48) U20.M5(GND_49) U20.M6(GND_50) U20.M7(GND_51) U20.M9(GND_52) U20.M10(GND_39) U20.M11(GND_40) U20.M12(GND_41) U20.M13(GND_42) U20.M14(GND_43) U20.M16(GND_44) U20.M17(GND_45) U20.N9(GND_58) U20.N10(GND_53) U20.N11(GND_54) U20.N12(GND_55) U20.N13(GND_56) U20.N14(GND_57) U20.T6(GND_60) U20.T7(GND_61) U20.T16(GND_59) U20.U6(GND_63) U20.U11(GND_62) U20.V8(GND_68) U20.V10(GND_64) U20.V12(GND_65) U20.V14(GND_66) U20.V16(GND_67) U21.A2(VSSQ_6) U21.A8(VSSQ_8) U21.B2(VSS_8) U21.C9(VSSQ_1) U21.D2(VSSQ_7) U21.D8(VSSQ_9) U21.E1(VSS_4) U21.E3(VSSQ_3) U21.E8(VSSQ_10) U21.E9(VSS_1) U21.F1(VSSQ_4) U21.G8(VSS_9) U21.H1(VSSQ_5) U21.H9(VSSQ_2) U21.K1(VSS_5) U21.K9(VSS_2) U21.M9(VSS_3) U21.N1(VSS_6) U21.N9(TEN) U21.T1(VSS_7) U22.10(GND) U23.10(GND) U24.4(GND) U25.4(GND) U26.65(EPAD) U27.4(VSS) U29.41(GND) U30.13(PGND) U31.13(PGND) U32.19(PGND) U33.41(GND) U34.19(PGND) U35.19(PGND) U36.41(GND) U37.13(PGND) U38.19(PGND) U39.10(GND) U40.4(GND) U41.10(GND) U42.4(GND) U43.A3(VSS_1) U43.A5(VSS_2) U43.A6(VSS_3) U43.A20(VSS_4) U43.A77(VSS_5) U43.AA12(VSS_164) U43.AA14(VSS_165) U43.AA16(VSS_166) U43.AA19(VSS_167) U43.AA21(VSS_168) U43.AA23(VSS_169) U43.AA25(VSS_170) U43.AA56(VSS_171) U43.AA60(VSS_172) U43.AA62(VSS_173) U43.AA69(VSS_174) U43.AB5(VSS_175) U43.AB74(VSS_176) U43.AC2(VSS_177) U43.AC12(VSS_178) U43.AC16(VSS_179) U43.AC18(VSS_180) U43.AC27(VSS_181) U43.AC58(VSS_182) U43.AD5(VSS_183) U43.AE7(VSS_184) U43.AE11(VSS_185) U43.AE14(VSS_186) U43.AE19(VSS_187) U43.AE23(VSS_188) U43.AE64(VSS_189) U43.AE67(VSS_190) U43.AE71(VSS_191) U43.AF5(VSS_192) U43.AF9(VSS_193) U43.AF74(VSS_194) U43.AF76(VSS_195) U43.AF78(VSS_196) U43.AG12(VSS_197) U43.AG16(VSS_198) U43.AG21(VSS_199) U43.AG62(VSS_200) U43.AH3(VSS_201) U43.AH5(VSS_202) U43.AH12(VSS_203) U43.AH16(VSS_204) U43.AH18(VSS_205) U43.AH19(VSS_206) U43.AH25(VSS_207) U43.AH27(VSS_208) U43.AH28(VSS_209) U43.AH30(VSS_210) U43.AH53(VSS_211) U43.AH56(VSS_212) U43.AH66(VSS_213) U43.AH69(VSS_214) U43.AH74(VSS_215) U43.AK12(VSS_216) U43.AK16(VSS_217) U43.AK19(VSS_218) U43.AK60(VSS_219) U43.AK75(VSS_220) U43.AK77(VSS_221) U43.AL7(VSS_222) U43.AL11(VSS_223) U43.AL64(VSS_224) U43.AL67(VSS_225) U43.AL71(VSS_226) U43.AM9(VSS_227) U43.AM19(VSS_228) U43.AM21(VSS_229) U43.AM28(VSS_230) U43.AM30(VSS_231) U43.AN5(VSS_232) U43.AN74(VSS_233) U43.AN76(VSS_234) U43.AP14(VSS_235) U43.AP19(VSS_236) U43.AP23(VSS_237) U43.AP53(VSS_238) U43.AR1(VSS_239) U43.AR3(VSS_240) U43.AR5(VSS_241) U43.AR12(VSS_242) U43.AR19(VSS_243) U43.AR25(VSS_244) U43.AR53(VSS_245) U43.AR55(VSS_246) U43.AR56(VSS_247) U43.AR60(VSS_248) U43.AU1(VSS_249) U43.AU3(VSS_250) U43.AU5(VSS_251) U43.AU19(VSS_252) U43.AU23(VSS_253) U43.AU25(VSS_254) U43.AU28(VSS_255) U43.AU30(VSS_256) U43.AU53(VSS_257) U43.AU55(VSS_258) U43.AU56(VSS_259) U43.AU58(VSS_260) U43.AU62(VSS_261) U43.AU66(VSS_262) U43.AU69(VSS_263) U43.AU72(VSS_264) U43.AU74(VSS_265) U43.AU76(VSS_266) U43.AU78(VSS_267) U43.AV2(VSS_268) U43.AV64(VSS_269) U43.AV67(VSS_270) U43.AV71(VSS_271) U43.AV75(VSS_272) U43.AV77(VSS_273) U43.AW5(VSS_274) U43.AW9(VSS_275) U43.B2(VSS_6) U43.B3(VSS_7) U43.B48(VSS_8) U43.B61(VSS_9) U43.B74(VSS_10) U43.B76(VSS_11) U43.B77(VSS_12) U43.B78(VSS_13) U43.BA3(VSS_276) U43.BA12(VSS_277) U43.BA16(VSS_278) U43.BA28(VSS_279) U43.BA56(VSS_280) U43.BB2(VSS_281) U43.BB19(VSS_282) U43.BB33(VSS_283) U43.BB35(VSS_284) U43.BD1(VSS_285) U43.BD5(VSS_286) U43.BD14(VSS_287) U43.BD33(VSS_288) U43.BE9(VSS_289) U43.BE28(VSS_290) U43.BE35(VSS_291) U43.BE66(VSS_292) U43.BE69(VSS_293) U43.BE72(VSS_294) U43.BE75(VSS_295) U43.BE77(VSS_296) U43.BF5(VSS_297) U43.BF26(VSS_298) U43.BF30(VSS_299) U43.BF56(VSS_300) U43.BF64(VSS_301) U43.BF67(VSS_302) U43.BF71(VSS_303) U43.BF74(VSS_304) U43.BF76(VSS_305) U43.BF78(VSS_306) U43.BG24(VSS_307) U43.BG35(VSS_308) U43.BG62(VSS_309) U43.BG69(VSS_310) U43.BH3(VSS_311) U43.BH5(VSS_312) U43.BH11(VSS_313) U43.BH14(VSS_314) U43.BH18(VSS_315) U43.BH30(VSS_316) U43.BH60(VSS_317) U43.BH64(VSS_318) U43.BH74(VSS_319) U43.BJ24(VSS_320) U43.BJ35(VSS_321) U43.BJ58(VSS_322) U43.BJ69(VSS_323) U43.BK1(VSS_324) U43.BK5(VSS_325) U43.BK37(VSS_326) U43.BK74(VSS_327) U43.BL30(VSS_328) U43.BL56(VSS_329) U43.BL64(VSS_330) U43.BM9(VSS_331) U43.BM13(VSS_332) U43.BM16(VSS_333) U43.BM20(VSS_334) U43.BM24(VSS_335) U43.BM35(VSS_336) U43.BM58(VSS_337) U43.BM69(VSS_338) U43.BM74(VSS_339) U43.BN30(VSS_340) U43.BN37(VSS_341) U43.BN56(VSS_342) U43.BN60(VSS_343) U43.BN64(VSS_344) U43.BN75(VSS_345) U43.BN77(VSS_346) U43.BP3(VSS_347) U43.BP24(VSS_348) U43.BP35(VSS_349) U43.BP62(VSS_350) U43.BP69(VSS_351) U43.BP74(VSS_352) U43.BR11(VSS_353) U43.BR14(VSS_354) U43.BR18(VSS_355) U43.BR22(VSS_356) U43.BR30(VSS_357) U43.BR64(VSS_358) U43.BT24(VSS_359) U43.BT35(VSS_360) U43.BT56(VSS_361) U43.BT58(VSS_362) U43.BT69(VSS_363) U43.BT74(VSS_364) U43.BU2(VSS_365) U43.BU4(VSS_366) U43.BU30(VSS_367) U43.BU37(VSS_368) U43.BU64(VSS_369) U43.BV9(VSS_370) U43.BV13(VSS_371) U43.BV24(VSS_372) U43.BV35(VSS_373) U43.BV56(VSS_374) U43.BV58(VSS_375) U43.BV62(VSS_376) U43.BV69(VSS_377) U43.BW5(VSS_378) U43.BW7(VSS_379) U43.BW11(VSS_380) U43.BW14(VSS_381) U43.BW30(VSS_382) U43.BW39(VSS_383) U43.BW40(VSS_384) U43.BW42(VSS_385) U43.BW43(VSS_386) U43.BW45(VSS_387) U43.BW47(VSS_388) U43.BW49(VSS_389) U43.BW50(VSS_390) U43.BW52(VSS_391) U43.BW54(VSS_392) U43.BW55(VSS_393) U43.BW60(VSS_394) U43.BW64(VSS_395) U43.BW74(VSS_396) U43.BY16(VSS_397) U43.BY20(VSS_398) U43.BY24(VSS_399) U43.BY28(VSS_400) U43.BY35(VSS_401) U43.BY39(VSS_402) U43.BY43(VSS_403) U43.BY54(VSS_404) U43.BY58(VSS_405) U43.BY62(VSS_406) U43.BY66(VSS_407) U43.BY69(VSS_408) U43.BY72(VSS_409) U43.C1(VSS_14) U43.C2(VSS_15) U43.C20(VSS_16) U43.C77(VSS_17) U43.C78(VSS_18) U43.CA5(VSS_410) U43.CA11(VSS_411) U43.CA18(VSS_412) U43.CA22(VSS_413) U43.CA26(VSS_414) U43.CA30(VSS_415) U43.CA41(VSS_416) U43.CA45(VSS_417) U43.CA46(VSS_418) U43.CA49(VSS_419) U43.CA51(VSS_420) U43.CA52(VSS_421) U43.CA56(VSS_422) U43.CA60(VSS_423) U43.CA64(VSS_424) U43.CA67(VSS_425) U43.CA71(VSS_426) U43.CA74(VSS_427) U43.CA76(VSS_428) U43.CA78(VSS_429) U43.CB16(VSS_430) U43.CB32(VSS_431) U43.CB35(VSS_432) U43.CB47(VSS_433) U43.CB51(VSS_434) U43.CB54(VSS_435) U43.CB58(VSS_436) U43.CB62(VSS_437) U43.CC5(VSS_438) U43.CC11(VSS_439) U43.CC30(VSS_440) U43.CC33(VSS_441) U43.CC37(VSS_442) U43.CC41(VSS_443) U43.CC45(VSS_444) U43.CC74(VSS_445) U43.CD16(VSS_446) U43.CD43(VSS_447) U43.CD47(VSS_448) U43.CD62(VSS_449) U43.CE1(VSS_450) U43.CE3(VSS_451) U43.CE5(VSS_452) U43.CE74(VSS_453) U43.CF11(VSS_454) U43.CF30(VSS_455) U43.CG5(VSS_456) U43.CG16(VSS_457) U43.CG20(VSS_458) U43.CG24(VSS_459) U43.CG28(VSS_460) U43.CG62(VSS_461) U43.CG66(VSS_462) U43.CG69(VSS_463) U43.CG72(VSS_464) U43.CG74(VSS_465) U43.CH11(VSS_466) U43.CH18(VSS_467) U43.CH22(VSS_468) U43.CH26(VSS_469) U43.CH30(VSS_470) U43.CH64(VSS_471) U43.CH67(VSS_472) U43.CH71(VSS_473) U43.CH75(VSS_474) U43.CH77(VSS_475) U43.CJ5(VSS_476) U43.CJ16(VSS_477) U43.CJ62(VSS_478) U43.CJ74(VSS_479) U43.CK11(VSS_480) U43.CK30(VSS_481) U43.CL5(VSS_482) U43.CL16(VSS_483) U43.CL62(VSS_484) U43.CL74(VSS_485) U43.CM1(VSS_486) U43.CM11(VSS_487) U43.CM30(VSS_488) U43.CN5(VSS_489) U43.CN74(VSS_490) U43.CP1(VSS_491) U43.CP2(VSS_492) U43.CP7(VSS_493) U43.CP9(VSS_494) U43.CP12(VSS_495) U43.CP14(VSS_496) U43.CP16(VSS_497) U43.CP18(VSS_498) U43.CP20(VSS_499) U43.CP23(VSS_500) U43.CP25(VSS_501) U43.CP27(VSS_502) U43.CP29(VSS_503) U43.CP31(VSS_504) U43.CP34(VSS_505) U43.CP36(VSS_506) U43.CP64(VSS_507) U43.CP66(VSS_508) U43.CP70(VSS_509) U43.CP72(VSS_510) U43.CP77(VSS_511) U43.CP78(VSS_512) U43.CR1(VSS_513) U43.CR2(VSS_514) U43.CR3(VSS_515) U43.CR5(VSS_516) U43.CR21(VSS_517) U43.CR37(VSS_518) U43.CR77(VSS_519) U43.CR78(VSS_520) U43.CT14(VSS_521) U43.CT29(VSS_522) U43.CT70(VSS_523) U43.CU1(VSS_524) U43.CU2(VSS_525) U43.CU3(VSS_526) U43.CU21(VSS_527) U43.CU37(VSS_528) U43.CU77(VSS_529) U43.CU78(VSS_530) U43.CV2(VSS_531) U43.CV3(VSS_532) U43.CV5(VSS_533) U43.CV6(VSS_534) U43.CV14(VSS_535) U43.CV29(VSS_536) U43.CV70(VSS_537) U43.CV73(VSS_538) U43.CV74(VSS_539) U43.CV76(VSS_540) U43.CV77(VSS_541) U43.D5(VSS_19) U43.D48(VSS_20) U43.D61(VSS_21) U43.E1(VSS_22) U43.E2(VSS_23) U43.E5(VSS_24) U43.E7(VSS_25) U43.E9(VSS_26) U43.E12(VSS_27) U43.E14(VSS_28) U43.E16(VSS_29) U43.E18(VSS_30) U43.E20(VSS_31) U43.E23(VSS_32) U43.E25(VSS_33) U43.E27(VSS_34) U43.E29(VSS_35) U43.E31(VSS_36) U43.E34(VSS_37) U43.E36(VSS_38) U43.E38(VSS_39) U43.E40(VSS_40) U43.E42(VSS_41) U43.E44(VSS_42) U43.E47(VSS_43) U43.E49(VSS_44) U43.E51(VSS_45) U43.E53(VSS_46) U43.E58(VSS_47) U43.E60(VSS_48) U43.E62(VSS_49) U43.E64(VSS_50) U43.E66(VSS_51) U43.E68(VSS_52) U43.E70(VSS_53) U43.E74(VSS_54) U43.E77(VSS_55) U43.E78(VSS_56) U43.F1(VSS_57) U43.F3(VSS_58) U43.F72(VSS_59) U43.F78(VSS_60) U43.H56(VSS_61) U43.H60(VSS_62) U43.H67(VSS_63) U43.J3(VSS_64) U43.J72(VSS_65) U43.J74(VSS_66) U43.K4(VSS_67) U43.K56(VSS_68) U43.K60(VSS_69) U43.K67(VSS_70) U43.L1(VSS_71) U43.L3(VSS_72) U43.L5(VSS_73) U43.L9(VSS_74) U43.L13(VSS_75) U43.L16(VSS_76) U43.L20(VSS_77) U43.L24(VSS_78) U43.L28(VSS_79) U43.L32(VSS_80) U43.L35(VSS_81) U43.L39(VSS_82) U43.L43(VSS_83) U43.L47(VSS_84) U43.L51(VSS_85) U43.L58(VSS_86) U43.L62(VSS_87) U43.L66(VSS_88) U43.L69(VSS_89) U43.L74(VSS_90) U43.M7(VSS_91) U43.M11(VSS_92) U43.M14(VSS_93) U43.M18(VSS_94) U43.M22(VSS_95) U43.M26(VSS_96) U43.M30(VSS_97) U43.M33(VSS_98) U43.M37(VSS_99) U43.M41(VSS_100) U43.M45(VSS_101) U43.M49(VSS_102) U43.M52(VSS_103) U43.M56(VSS_104) U43.M60(VSS_105) U43.M64(VSS_106) U43.M71(VSS_107) U43.N5(VSS_108) U43.N66(VSS_109) U43.N74(VSS_110) U43.N76(VSS_111) U43.P52(VSS_112) U43.P60(VSS_113) U43.R35(VSS_114) U43.R37(VSS_115) U43.R40(VSS_116) U43.R42(VSS_117) U43.R46(VSS_118) U43.R54(VSS_119) U43.R66(VSS_120) U43.R69(VSS_121) U43.T5(VSS_122) U43.T11(VSS_123) U43.T33(VSS_124) U43.T39(VSS_125) U43.T60(VSS_126) U43.T74(VSS_127) U43.U9(VSS_128) U43.U13(VSS_129) U43.U16(VSS_130) U43.U20(VSS_131) U43.U24(VSS_132) U43.U28(VSS_133) U43.U32(VSS_134) U43.U66(VSS_135) U43.V1(VSS_136) U43.V3(VSS_137) U43.V5(VSS_138) U43.V7(VSS_139) U43.V14(VSS_140) U43.V18(VSS_141) U43.V22(VSS_142) U43.V26(VSS_143) U43.V30(VSS_144) U43.V35(VSS_145) U43.V42(VSS_146) U43.V44(VSS_147) U43.V46(VSS_148) U43.V55(VSS_149) U43.V60(VSS_150) U43.V62(VSS_151) U43.V64(VSS_152) U43.V71(VSS_153) U43.W13(VSS_154) U43.W16(VSS_155) U43.W24(VSS_156) U43.Y5(VSS_157) U43.Y39(VSS_158) U43.Y40(VSS_159) U43.Y42(VSS_160) U43.Y55(VSS_161) U43.Y74(VSS_162) U43.Y76(VSS_163) U44.4(VSS) U45.4(GND) U46.4(GND) U47.8(GND_1) U47.9(GND_2) U47.14(\\2\O\E\) U47.15(\\1\O\E\) U48.8(GND_1) U48.9(GND_2) U48.14(\\2\O\E\) U48.15(\\1\O\E\) U49.8(GND_1) U49.9(GND_2) U49.14(\\2\O\E\) U49.15(\\1\O\E\) U50.8(GND_1) U50.9(GND_2) U50.14(\\2\O\E\) U50.15(\\1\O\E\) U51.8(GND_1) U51.9(GND_2) U51.14(\\2\O\E\) U51.15(\\1\O\E\) U52.8(GND_1) U52.9(GND_2) U52.14(\\2\O\E\) U52.15(\\1\O\E\) U53.1(GND) U53.6(A4) U53.7(A5) U53.8(A6) U53.9(A7) U53.10(A8) U53.11(B8) U53.12(B7) U53.13(B6) U53.14(B5) U53.15(B4) U54.4(GND) U55.8(GND_1) U55.9(GND_2) U55.14(\\2\O\E\) U55.15(\\1\O\E\) U56.4(GND) U57.4(GND) U58.8(GND_1) U58.9(GND_2) U58.14(\\2\O\E\) U58.15(\\1\O\E\) U59.8(GND_1) U59.9(GND_2) U59.14(\\2\O\E\) U59.15(\\1\O\E\) U60.A1 U60.A4 U60.A7 U60.A10 U60.A13 U60.A16 U60.A19 U60.A22 U60.A25 U60.A28 U60.A31 U60.A34 U60.A37 U60.A40 U60.B1 U60.B2 U60.B3 U60.B4 U60.B5 U60.B6 U60.B7 U60.B8 U60.B9 U60.B10 U60.B11 U60.B12 U60.B13 U60.B14 U60.B15 U60.B16 U60.B17 U60.B18 U60.B19 U60.B20 U60.B21 U60.B22 U60.B23 U60.B24 U60.B25 U60.B26 U60.B27 U60.B28 U60.B29 U60.B30 U60.B31 U60.B32 U60.B33 U60.B34 U60.B35 U60.B36 U60.B37 U60.B38 U60.B39 U60.B40 U60.C1 U60.C4 U60.C7 U60.C8 U60.C9 U60.C12 U60.C13 U60.C16 U60.C17 U60.C18 U60.C19 U60.C20 U60.C21 U60.C22 U60.C23 U60.C24 U60.C25 U60.C26 U60.C27 U60.C28 U60.C29 U60.C30 U60.C31 U60.C32 U60.C33 U60.C34 U60.C35 U60.C36 U60.C37 U60.C38 U60.D1 U60.D2 U60.D5 U60.D6 U60.D7 U60.D10 U60.D11 U60.D14 U60.D15 U60.D18 U60.D19 U60.D22 U60.D23 U60.D26 U60.D27 U60.D30 U60.D31 U60.D34 U60.D35 U60.D38 U61.12(GND) U62.12(GND) U63.5(GND) U63.9(EPAD) U64.1(GND) U65.3(GND) X1.1 X2.1 X3.2 X3.3 X3.4 X3.5 X3.6 X3.7 X3.8 X3.9 X3.10 X3.11 X3.12 X3.13 X4.2 X4.3 X4.4 X4.5 X4.6 X4.7 X4.8 X4.9 X4.10 X4.11 X4.12 X4.13 X5.2 X5.3 X5.4 X5.5 X5.6 X5.7 X5.8 X5.9 X5.10 X5.11 X5.12 X5.13 X6.2 X6.3 X6.4 X6.5 X6.6 X6.7 X6.8 X6.9 X6.10 X6.11 X6.12 X6.13 X7.2 X7.3 X7.4 X7.5 X7.6 X7.7 X7.8 X7.9 X7.10 X7.11 X7.12 X7.13 X8.2 X8.3 X8.4 X8.5 X8.6 X8.7 X8.8 X8.9 X8.10 X8.11 X8.12 X8.13 X11.2 X11.3 X11.4 X11.5 X11.6 X11.7 X11.8 X11.9 X11.10 X11.11 X11.12 X11.13 X12.2 X12.3 X12.4 X12.5 X12.6 X12.7 X12.8 X12.9 X12.10 X12.11 X12.12 X12.13 X13.2 X13.3 X13.4 X13.5 X13.6 X13.7 X13.8 X13.9 X13.10 X13.11 X13.12 X13.13 X16.2 X16.3 X16.4 X16.5 X16.6 X16.7 X16.8 X16.9 X16.10 X16.11 X17.2 X17.3 X17.4 X17.5 X17.6 X17.7 X17.8 X17.9 X17.10 X17.11 X18.2 X18.3 X18.4 X18.5 X18.6 X18.7 X18.8 X18.9 X18.10 X18.11
P0V6_M_ABC_VTT: C78.1 C79.1 C80.1 C81.1 C527.1 C799.1 C800.1 C803.1 C804.1 J7.258(VTT1) J8.258(VTT1) U5.3(VO) U5.5(VOSNS) X19.1
P0V9_NIC_OUT: C278.2 C282.2 C283.2 C284.1 C285.1 C286.1 C287.1 U26.11(VDD0P9_2) U26.32(VDD0P9_1) U26.38(VDD0P9_OUT) U26.42(VDD0P9_4) U26.59(VDD0P9_3)
P1V2_VDDQ_EN: R725.2 R734.2 U2.D16(IO_47)
P1V2_VDDQ_PG: R92.2 R335.1 U36.17(AVR_RDY)
P1V3_VCCKRHV: C199.2 C200.1 C201.1 C202.1 C203.1 C204.1 C205.1 C206.1 R301.1 U16.3(VOUT_1) U16.4(VOUT_2) U43.N51(VCCKX4PLL) U43.N58(VCCKRHV) X28.1
P1V3_VCCKRHV_EN: R299.2 R302.2 U2.F4(IO_155)
P1V3_VCCKRHV_PG: R300.2 U2.N11(IO_193) U16.7(POK)
P1V5_NIC_OUT: C272.2 C273.2 C274.1 C275.1 C276.1 C277.1 C279.2 U26.39(VDD1P5_OUT) U26.47(VDD1P5_1) U26.56(VDD1P5_2)
P1V05_PCH: C236.1 C456.1 C457.1 C458.1 C459.1 C464.1 C465.1 C466.1 C467.1 C468.1 C469.1 C470.1 C658.1 C659.1 C660.1 C661.1 C662.1 C663.1 C664.1 C665.1 C666.1 C667.1 C668.1 C669.1 C670.1 C671.1 C672.1 C673.1 C773.1 C774.1 CD14.1 L26.1 R22.1 R359.2 R360.1 R1008.2 U35.5(VOS) U43.AC21(VCCCLK_1) U43.AC23(VCCCLK_2) U43.AC25(VCCCLK_3) U43.AE21(VCCCLK_4) U43.AE25(VCCCLK_5) U43.AG23(VCCCLK_6) U43.AG25(VCCCLK_7) U43.AG27(VCCIO_1) U43.AH21(VCCIO_2) U43.AH23(VCCCLK_8) U43.AK18(VCCIO_3) U43.AK21(VCC1) U43.AK23(VCC2) U43.AK25(VCC3) U43.AK27(VCCIO_4) U43.AM14(VCCUSBPLL) U43.AM16(VCCIO_5) U43.AM18(VCCIO_6) U43.AM23(VCC4) U43.AM25(VCC5) U43.AM27(VCCIO_7) U43.AP25(VCC6) U43.AP27(VCCIO_8) U43.AR27(VCCIO_9) U43.AU27(VCCIO_10) U43.AW27(VCCIO_11)
P1V05_PCH_BPH1: C455.1 L26.2 U35.6(SW)
P1V05_PCH_EN: R694.2 R698.2 U2.C6(IO_37)
P1V05_PCH_LSET: R718.1 U35.3(LSET)
P1V05_PCH_PG: R91.2 R336.1 U33.15(BVR_RDY)
P1V05_PROC_IO: C185.1 C186.1 R284.1 R1033.2 R1137.2 R1196.1 R1197.1 R1198.1 U14.1(S_1) U14.2(S_2) U14.3(S_3) U43.BB25(P1V05_PROC_IO)
P1V05_PROC_IO_EN: R282.1 R285.1 U2.B13(IO_17)
P1V05_PROC_IO_PG: Q23.3(C) R278.2 U2.D15(IO_46)
P1V05_VCCCIOIN: C182.1 C183.1 C184.1 C216.1 C221.1 C222.1 C223.1 C261.2 C341.1 C641.1 C642.1 C643.1 C649.1 C680.2 C682.2 C684.2 C686.2 C688.2 C690.2 C691.2 C693.1 C696.2 C697.1 C698.1 C702.2 C704.2 C763.1 L13.2 L14.1 R25.1 R304.1 R310.1 R662.2 R663.1 R664.2 R780.1 R781.1 R783.1 R784.1 R786.1 R796.1 R797.1 R798.1 R799.1 R837.1 R840.1 R843.1 R845.1 R907.1 R908.2 R909.1 R910.1 R911.1 R912.1 R913.1 R914.1 R915.1 R917.1 R953.2 R961.1 R963.2 R965.2 R992.2 R994.2 R995.2 R1018.1 R1019.1 R1020.1 R1023.1 R1029.1 R1034.2 R1035.2 R1036.2 R1037.2 R1039.2 R1054.2 R1055.2 R1056.2 R1058.2 R1063.2 R1072.2 R1073.2 R1074.2 R1075.2 R1079.1 R1080.1 R1086.2 R1091.1 R1092.1 R1099.1 R1100.1 R1101.1 R1102.1 R1105.2 R1177.1 R1179.1 R1181.1 U14.5(D_4) U14.6(D_3) U14.7(D_2) U14.8(D_1) U20.AA17(PECIVDD) U43.AC53(VCCIOIN_6) U43.AC55(VCCIOIN_7) U43.AH55(VCCIOIN_8) U43.AK53(VCCIOIN_9) U43.AK55(VCCIOIN_10) U43.AM53(VCCIOIN_11) U43.AP18(VCCIOIN_1) U43.AP21(VCCIOIN_2) U43.AR18(VCCIOIN_3) U43.AR21(VCCIOIN_4) U43.AR23(VCCIOIN_5) U47.16(VCCB) U48.16(VCCB) U49.16(VCCB) U50.16(VCCB) U51.16(VCCB) U52.16(VCCB) U53.2(VREF_A) U54.1(VCCA) U55.16(VCCB) U56.1(VCCA) U57.1(VCCA) U58.16(VCCB) U59.16(VCCB) X29.1
P1V05_VCCCIOIN_EN: R303.1 R307.1 U2.F11(IO_160)
P1V05_VCCCIOIN_PG: Q29.3(C) R306.2 U2.F7(IO_158)
P1V05_VCCGB: C233.1 C433.1 C434.1 C435.1 C436.1 C437.1 C438.1 C439.1 C440.1 C445.1 C446.1 C447.1 C448.1 C449.1 C450.1 C635.1 C636.1 C637.1 C638.1 C639.1 C640.1 C771.1 C772.1 CD13.1 L13.1 L25.1 L32.1 L33.1 R23.1 R349.1 R354.2 U34.5(VOS) U43.AA58(VCCGBE_11) U43.R58(VCCGBE_1) U43.T51(VCCGBE_2) U43.T53(VCCGBE_3) U43.V51(VCCGBE_4) U43.V53(VCCGBE_5) U43.V56(VCCGBE_6) U43.V58(VCCGBE_7) U43.Y53(VCCGBE_8) U43.Y56(VCCGBE_9) U43.Y58(VCCGBE_10)
P1V05_VCCSCSUS: C232.1 C403.1 C404.1 C405.1 C406.1 C407.1 C412.1 C413.1 C414.1 C415.1 C416.1 C417.1 C418.1 C419.1 C420.1 C421.1 C631.1 C632.1 C633.1 C634.1 C749.1 C750.1 C769.1 C770.1 CD12.1 L24.1 R21.1 R349.2 R350.2 U32.5(VOS) U43.R48(VCCSCSUS_1) U43.R49(VCCSCSUS_2) U43.T48(VCCSCSUS_3) U43.T49(VCCSCSUS_4) U43.V48(VCCSCSUS_5) U43.V49(VCCSCSUS_6) X32.1
P1V5_VRM: C167.1 C168.1 C169.1 C170.1 C761.1 C762.1 R264.1 R809.2 R846.2 R959.1 R971.2 U12.3(VOUT_1) U12.4(VOUT_2) U43.AC28(VCCVRM_1) U43.AC30(VCCVRM_2) U43.AE28(VCCVRM_3) U43.AE30(VCCVRM_4) U43.AG19(VCCADAC1_5) U43.AK28(VCCVRM_5) U43.AK30(VCCVRM_6) U43.AW28(VCCVRM_7) U43.AW30(VCCVRM_8) U43.BA30(VCCVRM_9) U43.BB30(VCCVRM_10) U43.BD30(SATA_IREF) U43.V33(SOC_IREF) U43.W20(ICLK_IREF) U43.W28(PCIE_IREF) X26.1
P1V5_VRM_EN: R262.2 R265.2 U2.N12(IO_108)
P1V5_VRM_PG: R263.2 U2.G2(IO_71) U12.7(POK)
P1V7_VCCSCFUSESUS: C191.1 C195.1 C196.1 C197.1 C198.1 L12.1 R288.1 R294.1 U43.AA53(VCCSCFUSESUS_1) U43.AA55(VCCSCFUSESUS_2) U43.AE53(VCCSCFUSESUS_3) U43.AE55(VCCSCFUSESUS_4) X27.1
P1V7_VCCSCFUSESUS_EN: R287.1 R291.1 U2.B14(IO_18)
P1V7_VCCSCFUSESUS_PG: Q27.3(C) R290.2 U2.E13(IO_53)
P2V5_M_ABC_VPP: C235.1 C500.1 C501.1 C502.1 C503.1 C504.1 C506.1 C524.1 C694.1 C729.1 C751.1 C752.1 C753.1 C756.1 C777.1 C778.1 C792.1 C793.1 C794.1 C795.1 C796.1 J7.255(VDDSPD) J7.257(VPP1) J7.259(VPP2) J8.255(VDDSPD) J8.257(VPP1) J8.259(VPP2) L29.1 R137.1 R140.2 R366.2 R368.2 R1093.1 R1094.1 R1095.1 R1116.2 R1118.2 R1120.2 R1122.2 R1125.2 U38.5(VOS) U54.8(VCCB) X35.1
P2V5_VPP_BPH1: C499.1 L29.2 U38.6(SW)
P2V5_VPP_EN: R731.2 R735.2 U2.B3(IO_20)
P2V5_VPP_LSET: R756.1 U38.3(LSET)
P2V5_VPP_PG: R93.2 R334.1 U36.15(BVR_RDY)
P3V3: C180.1 C181.1 C591.2 C650.1 C651.1 C652.1 C653.1 C654.1 C655.1 C656.1 C657.1 C683.2 C685.2 C687.2 L6.1 L31.2 Q7.2(E) Q8.2(E) Q9.2(E) R2.1 R4.1 R5.1 R32.1 R119.2 R122.2 R125.2 R273.1 R816.1 R817.1 R818.1 R819.1 R820.1 R821.1 R822.1 R823.1 R824.1 R825.1 R826.1 R827.1 R842.1 R847.1 R848.1 R850.1 R851.1 R854.1 R855.1 R856.1 R857.1 R858.1 R859.1 R861.1 R862.1 R864.1 R865.1 R866.1 R936.1 R941.1 R945.1 R958.1 R972.1 R974.1 R975.1 R976.1 R977.1 R1028.1 R1081.1 R1082.1 R1084.2 R1087.2 R1180.1 R1182.1 R1192.1 R1193.1 R1194.1 R1210.2 U13.1(S_1) U13.2(S_2) U13.3(S_3) U43.AC14(VCCCLK3_3_1) U43.AC19(VCCADACBG3_3) U43.AE12(VCCCLK3_3_2) U43.AE16(VCCCLK3_3_3) U43.AE18(VCCCLK3_3_4) U43.AG14(VCCCLK3_3_5) U43.AG18(VCC3_3_1) U43.AG28(VCC3_3_2) U43.AG30(VCC3_3_3) U43.AH14(VCCCLK3_3_6) U43.AM12(VCC3_3_4) U43.AU12(VCC3_3_5) U43.AW25(VCC3_3_6) U43.BA25(VCC3_3_7) U49.1(VCCA) U50.1(VCCA) U51.1(VCCA)
P3V3_AUX: C14.2 C18.2 C21.1 C118.2 C125.1 C126.1 C127.1 C128.1 C129.1 C130.1 C177.1 C178.1 C179.1 C228.2 C229.2 C230.1 C254.2 C255.2 C256.1 C257.1 C262.1 C265.1 C290.1 C291.1 C295.1 C302.1 C303.1 C304.1 C318.1 C319.1 C562.1 C563.1 C564.2 C565.1 C566.1 C567.2 C595.2 C644.1 C645.1 C646.1 C647.1 C648.1 C679.2 C681.2 C689.2 C695.2 C699.1 C700.1 C701.2 C703.2 C742.1 C743.1 CD7.1 D21.2(A2) D32.1 L3.2 L4.2 L9.1 L15.1 L16.2 L17.1 L19.1 L20.1 OSC1.4(VCC) OSC2.1(E/D) OSC2.4(VDD) R1.1 R7.1 R8.1 R10.1 R15.2 R16.2 R17.2 R18.2 R33.1 R55.1 R70.1 R133.1 R134.1 R229.2 R268.1 R269.1 R277.1 R278.1 R289.1 R290.1 R305.1 R306.1 R317.1 R318.2 R321.2 R323.2 R325.1 R329.1 R330.1 R334.2 R335.2 R336.2 R337.2 R338.2 R339.2 R403.1 R406.1 R439.2 R441.2 R443.2 R465.2 R467.2 R468.2 R470.2 R472.2 R473.2 R475.2 R483.1 R484.1 R485.1 R487.1 R489.1 R490.2 R491.2 R496.2 R497.2 R499.2 R500.2 R501.2 R503.2 R504.2 R505.1 R506.2 R507.1 R508.2 R509.2 R510.2 R511.2 R512.2 R519.2 R520.2 R524.2 R525.2 R527.2 R528.1 R529.2 R530.1 R531.2 R532.1 R533.2 R534.1 R551.2 R554.2 R555.2 R556.2 R557.2 R558.2 R559.2 R560.2 R561.2 R562.2 R563.2 R564.2 R565.2 R566.1 R567.1 R568.1 R570.1 R571.1 R573.1 R574.1 R576.1 R578.1 R581.1 R584.1 R586.1 R588.1 R590.1 R595.1 R597.1 R600.2 R601.2 R607.2 R608.1 R609.1 R610.2 R621.2 R622.2 R623.2 R624.2 R625.2 R626.2 R627.2 R628.2 R629.1 R760.2 R761.2 R762.2 R764.1 R770.2 R771.2 R772.2 R775.1 R802.1 R805.2 R806.1 R830.1 R831.1 R832.1 R833.1 R834.1 R836.1 R838.1 R868.1 R870.1 R871.1 R873.1 R874.1 R876.1 R877.1 R879.1 R880.1 R882.1 R883.1 R884.1 R885.1 R886.1 R888.1 R979.1 R980.1 R981.1 R982.1 R983.1 R984.1 R986.1 R987.1 R988.1 R989.1 R990.1 R997.1 R998.1 R999.1 R1000.2 R1030.1 R1031.1 R1097.1 R1098.1 R1103.1 R1104.1 R1108.1 R1157.1 R1162.2 R1186.1 R1187.1 R1220.1 U13.5(D_4) U13.6(D_3) U13.7(D_2) U13.8(D_1) U18.8(VCC) U19.8(VCC) U20.F7(R2VDD_1) U20.F8(R2VDD_2) U20.F10(R1VDD_1) U20.F11(R1VDD_2) U20.F12(PV33D_1) U20.F13(PV33D_2) U20.F14(PV33D_3) U20.F15(PV33D_4) U20.G16(PV33D_5) U20.H17(PV33D_6) U20.J17(LPVDD_1) U20.K7(PV33D_7) U20.K17(LPVDD_2) U20.L16(PEAV33) U20.N6(PV33D_9) U20.N17(PV33D_8) U20.P6(PV33D_11) U20.P17(PV33D_10) U20.R6(PV33D_13) U20.R17(PV33D_12) U20.T15(PV33D_14) U22.2(VCC) U23.2(VCC) U24.8(VCC) U25.8(VCC) U27.8(VCC) U39.2(VCC) U40.8(VCC) U41.2(VCC) U42.8(VCC) U43.AP12(VCCSUS3_3_2) U43.AP16(VCCSUS3_3_3) U43.AR14(VCCSUS3_3_4) U43.AR16(VCCSUS3_3_9) U43.AR28(VCCSUS3_3_5) U43.AR30(VCCSUS3_3_6) U43.AU18(VCCSUS3_3_7) U43.AW18(VCCSUS3_3_8) U43.AW23(VCCSUS3_3_1) U44.8(VCC) U46.8(VCC) U47.1(VCCA) U48.1(VCCA) U52.1(VCCA) U55.1(VCCA) U56.8(VCCB) U57.8(VCCB) U58.1(VCCA) U59.1(VCCA) U61.24(VCC) X22.1
P3V3_AUX_EN: R234.1 R235.1 U2.C7(IO_38)
P3V3_AUX_PG: R225.2 U2.C3(IO_34) U8.2(PG)
P3V3_EN: R271.1 R274.1 U2.B12(IO_16)
P3V3_NGFF: C53.1 C54.1 C55.1 C56.1 C57.1 C784.1 C788.1 C789.1 C790.1 C791.1 CD20.1 J3.2(3.3V_2) J3.4(3.3V_4) J3.70(3.3V_70) J3.72(3.3V_72) J3.74(3.3V_74) L6.2 L36.1 Q14.2(E) R159.2 R160.2 R161.2 R162.2 R167.2 R1213.1 X38.1
P3V3_PG: Q19.3(C) R269.2 U2.D12(IO_43)
P3V3_RTC: C226.1 C227.1 D21.3(K1/K2) R311.1 R312.1 R890.1 R891.1 R892.1 U43.AW14(VCCRTC)
P3V3_STBY: C28.1 C29.1 C30.1 C31.1 C32.1 C33.1 C34.1 C35.1 C36.1 C37.1 C38.1 C39.1 C40.1 C41.1 C42.1 C43.1 C70.1 C71.1 C86.1 C91.1 C92.1 C93.1 C94.1 C140.1 C141.1 C142.1 C171.1 C172.1 C173.1 C207.1 C208.1 C209.1 C339.1 C430.1 C482.1 C744.1 C745.1 C813.1 C814.1 C815.1 J1.4 L5.2 L7.1 L35.1 R68.1 R69.1 R94.2 R95.2 R96.1 R97.1 R99.1 R100.1 R101.1 R102.1 R103.1 R104.1 R106.1 R107.1 R109.2 R110.2 R201.2 R203.1 R209.1 R220.1 R225.1 R238.1 R244.1 R245.1 R251.1 R253.1 R263.1 R300.1 R341.2 R342.2 R343.2 R650.1 R653.2 R654.2 R686.2 R690.1 R696.1 R699.2 R700.2 R726.2 R728.1 R733.1 R736.2 R737.2 R1166.2 R1173.1 R1176.1 R1235.2 R1250.1 R1251.1 U2.A3(VCCIO2_8) U2.A14(VCCIO2_5) U2.C1(VCCIO1_1) U2.C16(VCCIO2_4) U2.F8(VCCIO2_7) U2.F9(VCCIO2_6) U2.H6(VCCIO1_2) U2.H11(VCCIO2_3) U2.J6(VCCIO1_3) U2.J11(VCCIO2_2) U2.L8(VCCIO1_6) U2.L9(VCCIO1_7) U2.P1(VCCIO1_4) U2.P16(VCCIO2_1) U2.T3(VCCIO1_5) U2.T14(VCCIO1_8) U3.5(VDD) U5.10(VIN) U9.5(VIN_1) U9.9(VIN_2) U12.5(VIN_1) U12.9(VIN_2) U16.5(VIN_1) U16.9(VIN_2) U29.6(PU3) U33.5(ACSP2) U36.5(ACSP2) U62.24(VCC) U64.5(VIN_1) U64.9(VIN_2) X20.1
P5V_AUX: C99.2 C106.1 C107.1 C108.1 C109.1 C110.1 C111.1 C112.1 C138.1 C139.1 C174.1 C175.1 C176.1 C187.1 C188.1 C189.1 C210.1 C211.1 C212.1 C213.1 C214.1 CD6.1 L8.1 R34.1 R219.2 R665.1 R670.1 R672.1 R677.1 R680.2 R682.1 R710.2 R712.1 R717.2 R719.1 R745.1 R751.1 R755.2 R757.1 U9.6(VCNTL) U12.6(VCNTL) U15.8(VIN) U16.6(VCNTL) U17.8(VIN) X21.1
P5V_AUX_EN: R213.1 R214.2 U2.A7(IO_10)
P5V_AUX_PG: R220.2 U2.B11(IO_15) U7.2(PG)
PVCCCIN: C231.1 C348.1 C349.1 C350.1 C351.1 C352.1 C353.1 C354.1 C355.1 C356.1 C359.1 C360.1 C361.1 C362.1 C363.1 C364.1 C365.1 C366.1 C367.1 C368.1 C376.1 C377.1 C378.1 C379.1 C380.1 C381.1 C382.1 C383.1 C384.1 C387.1 C388.1 C389.1 C390.1 C391.1 C392.1 C393.1 C394.1 C395.1 C396.1 C615.1 C616.1 C617.1 C618.1 C619.1 C620.1 C621.1 C622.1 C623.1 C624.1 C625.1 C626.1 C627.1 C628.1 C629.1 C630.1 C767.1 C768.1 CD8.1 CD9.1 L21.1 L22.1 R24.1 R345.2 U30.5(VOS) U31.5(VOS) U43.AG53(VCCIN_1) U43.AG55(VCCIN_2) U43.AV60(VCCIN_3) U43.AW55(VCCIN_4) U43.AW56(VCCIN_5) U43.AW58(VCCIN_6) U43.AW62(VCCIN_7) U43.AW66(VCCIN_8) U43.AW69(VCCIN_9) U43.AW72(VCCIN_10) U43.AW74(VCCIN_11) U43.AW76(VCCIN_12) U43.AW78(VCCIN_13) U43.AY60(VCCIN_14) U43.AY64(VCCIN_15) U43.AY67(VCCIN_16) U43.AY71(VCCIN_17) U43.AY75(VCCIN_18) U43.AY77(VCCIN_19) U43.BA58(VCCIN_20) U43.BA62(VCCIN_21) U43.BA66(VCCIN_22) U43.BA69(VCCIN_23) U43.BA72(VCCIN_24) U43.BA74(VCCIN_25) U43.BA76(VCCIN_26) U43.BA78(VCCIN_27) U43.BB36(VCCIN_28) U43.BB56(VCCIN_29) U43.BB60(VCCIN_30) U43.BB64(VCCIN_31) U43.BB67(VCCIN_32) U43.BB71(VCCIN_33) U43.BB75(VCCIN_34) U43.BB77(VCCIN_35) U43.BC58(VCCIN_36) U43.BC62(VCCIN_37) U43.BC66(VCCIN_38) U43.BC69(VCCIN_39) U43.BC72(VCCIN_40) U43.BD36(VCCIN_41) U43.BD37(VCCIN_42) U43.BD56(VCCIN_43) U43.BD60(VCCIN_44) U43.BD64(VCCIN_45) U43.BD67(VCCIN_46) U43.BD71(VCCIN_47) U43.BD74(VCCIN_48) U43.BD76(VCCIN_49) U43.BD78(VCCIN_50) U43.BE37(VCCIN_51) U43.BE58(VCCIN_52) U43.BE62(VCCIN_53) U43.BF60(VCCIN_54) U43.BG37(VCCIN_55) U43.BG58(VCCIN_56) U43.BH37(VCCIN_57) U43.BH56(VCCIN_58) U43.BJ56(VCCIN_59) X30.1
PVDDQ_CPU_ABC: C234.1 C490.1 C491.1 C492.1 C493.1 C494.1 C495.1 C518.1 C519.1 C520.1 C521.1 C674.1 C675.1 C676.1 C677.1 C678.1 C775.1 C776.1 C797.1 C798.1 C801.1 C802.1 CD16.1 CD17.1 CD18.1 J7.111(VDD1) J7.112(VDD2) J7.117(VDD3) J7.118(VDD4) J7.123(VDD5) J7.124(VDD6) J7.129(VDD7) J7.130(VDD8) J7.135(VDD9) J7.136(VDD10) J7.141(VDD11) J7.142(VDD12) J7.147(VDD13) J7.148(VDD14) J7.153(VDD15) J7.154(VDD16) J7.159(VDD17) J7.160(VDD18) J7.163(VDD19) J8.111(VDD1) J8.112(VDD2) J8.117(VDD3) J8.118(VDD4) J8.123(VDD5) J8.124(VDD6) J8.129(VDD7) J8.130(VDD8) J8.135(VDD9) J8.136(VDD10) J8.141(VDD11) J8.142(VDD12) J8.147(VDD13) J8.148(VDD14) J8.153(VDD15) J8.154(VDD16) J8.159(VDD17) J8.160(VDD18) J8.163(VDD19) L28.1 R36.1 R200.1 R362.2 R364.1 R985.1 U37.5(VOS) U43.CF60(VCCD_1) U43.CG43(VCCD_2) U43.CG51(VCCD_3) U43.CG54(VCCD_4) U43.CG58(VCCD_5) U43.CH33(VCCD_6) U43.CH37(VCCD_7) U43.CH41(VCCD_8) U43.CH45(VCCD_9) U43.CH49(VCCD_10) U43.CH56(VCCD_11) U43.CJ39(VCCD_12) U43.CK52(VCCD_13) U43.CK60(VCCD_14) U43.CL35(VCCD_15) U43.CL58(VCCD_16) U43.CP38(VCCD_17) U43.CP40(VCCD_18) U43.CP42(VCCD_19) U43.CP44(VCCD_20) U43.CP47(VCCD_21) U43.CP49(VCCD_22) U43.CP51(VCCD_23) U43.CP53(VCCD_24) U43.CP55(VCCD_25) U43.CP58(VCCD_26) U43.CP60(VCCD_27) U43.CP62(VCCD_28) U43.CP68(VCCD_29) U43.CT55(VCCD_30) U43.CU39(VCCD_31) U43.CU43(VCCD_32) U43.CU48(VCCD_33) U43.CU52(VCCD_34) U43.CU59(VCCD_35) U43.CU63(VCCD_36) U43.CU65(VCCD_37) U43.CU67(VCCD_38) U43.CU69(VCCD_39) X34.1
VCC_1V15_AUX: C159.1 C163.1 C164.1 C165.1 C166.1 C308.1 C309.1 C310.1 C311.1 C312.1 C313.1 C314.1 C315.1 L11.1 L18.1 R254.1 R258.1 U20.F6(IV11D_1) U20.G7(IV11D_8) U20.G8(IV11D_9) U20.G9(IV11D_10) U20.G10(IV11D_2) U20.G11(IV11D_3) U20.G12(IV11D_4) U20.G13(IV11D_5) U20.G14(IV11D_6) U20.G15(IV11D_7) U20.H16(IV11D_11) U20.J16(IV11D_12) U20.L7(IV11D_13) U20.L17(PEAV11) U20.N7(IV11D_15) U20.N16(IV11D_14) U20.P7(IV11D_22) U20.P9(IV11D_23) U20.P10(IV11D_16) U20.P11(IV11D_17) U20.P12(IV11D_18) U20.P13(IV11D_19) U20.P14(IV11D_20) U20.P16(IV11D_21) U20.R7(IV11D_25) U20.R16(IV11D_24) U20.V17(PLLDV11) X25.1
VCC_1V15_AUX_EN: R252.1 R255.1 U2.B8(IO_25)
VCC_1V15_AUX_PG: Q17.3(C) R251.2 U2.D1(IO_41)
VCC_BATTERY: D31.1
VCC_BATVDD: C307.1 D31.2 D32.2 U20.E4(BATVDD)
VCC_BMC_DDR: C147.1 C151.1 C152.1 C153.1 C154.1 C237.1 C239.1 C240.1 C241.1 C242.1 C243.1 C248.1 C249.1 C250.1 C251.1 C294.1 C297.1 C299.1 C300.1 C301.1 L10.1 R243.1 R250.1 R373.2 R375.2 R378.2 R380.2 R382.2 R384.2 R386.2 R388.2 R390.2 R392.2 R394.2 R396.2 R398.2 R400.2 R402.2 R405.2 R408.2 R410.2 R412.2 R414.2 R416.2 R418.2 R420.2 R422.2 R424.2 R426.2 R428.2 R454.1 U20.T8(MVDD_5) U20.T10(MVDD_1) U20.T12(MVDD_2) U20.T13(MVDD_3) U20.T14(MVDD_4) U21.A1(VDDQ_4) U21.A9(VDDQ_1) U21.B3(VDD_5) U21.B9(VDD_1) U21.C1(VDDQ_5) U21.D1(VDD_6) U21.D9(VDDQ_2) U21.F2(VDDQ_7) U21.F8(VDDQ_9) U21.G1(VDDQ_6) U21.G7(VDD_10) U21.G9(VDDQ_3) U21.J1(VDD_7) U21.J2(VDDQ_8) U21.J8(VDDQ_10) U21.J9(VDD_2) U21.L1(VDD_8) U21.L9(VDD_3) U21.R1(VDD_9) U21.T9(VDD_4) X24.1
VCC_BMC_DDR_EN: R242.1 R247.1 U2.A8(IO_11)
VCC_BMC_DDR_PG: Q15.3(C) R245.2 U2.C9(IO_40)
VCCAXCK: C603.1 C604.1 R1008.1 U43.AE27(VCCAXCK1_05)
VCCGBE_APH1: C432.1 L25.2 U34.6(SW)
VCCGBE_EN: R689.2 R697.2 U2.D11(IO_42)
VCCGBE_LSET: R711.1 U34.3(LSET)
VCCGBE_PG: R90.2 R337.1 U33.17(AVR_RDY)
VCCGBE_SENSE: R356.1 U43.AR78(VCCGBE_SENSE)
VCCIN_EN: R644.2 R651.2 U2.D6(IO_194)
VCCIN_PG: R88.2 R339.1 R542.2 U29.17(AVR_RDY)
VCCIN_SENSE: R347.1 U43.AT77(VCCIN_SENSE)
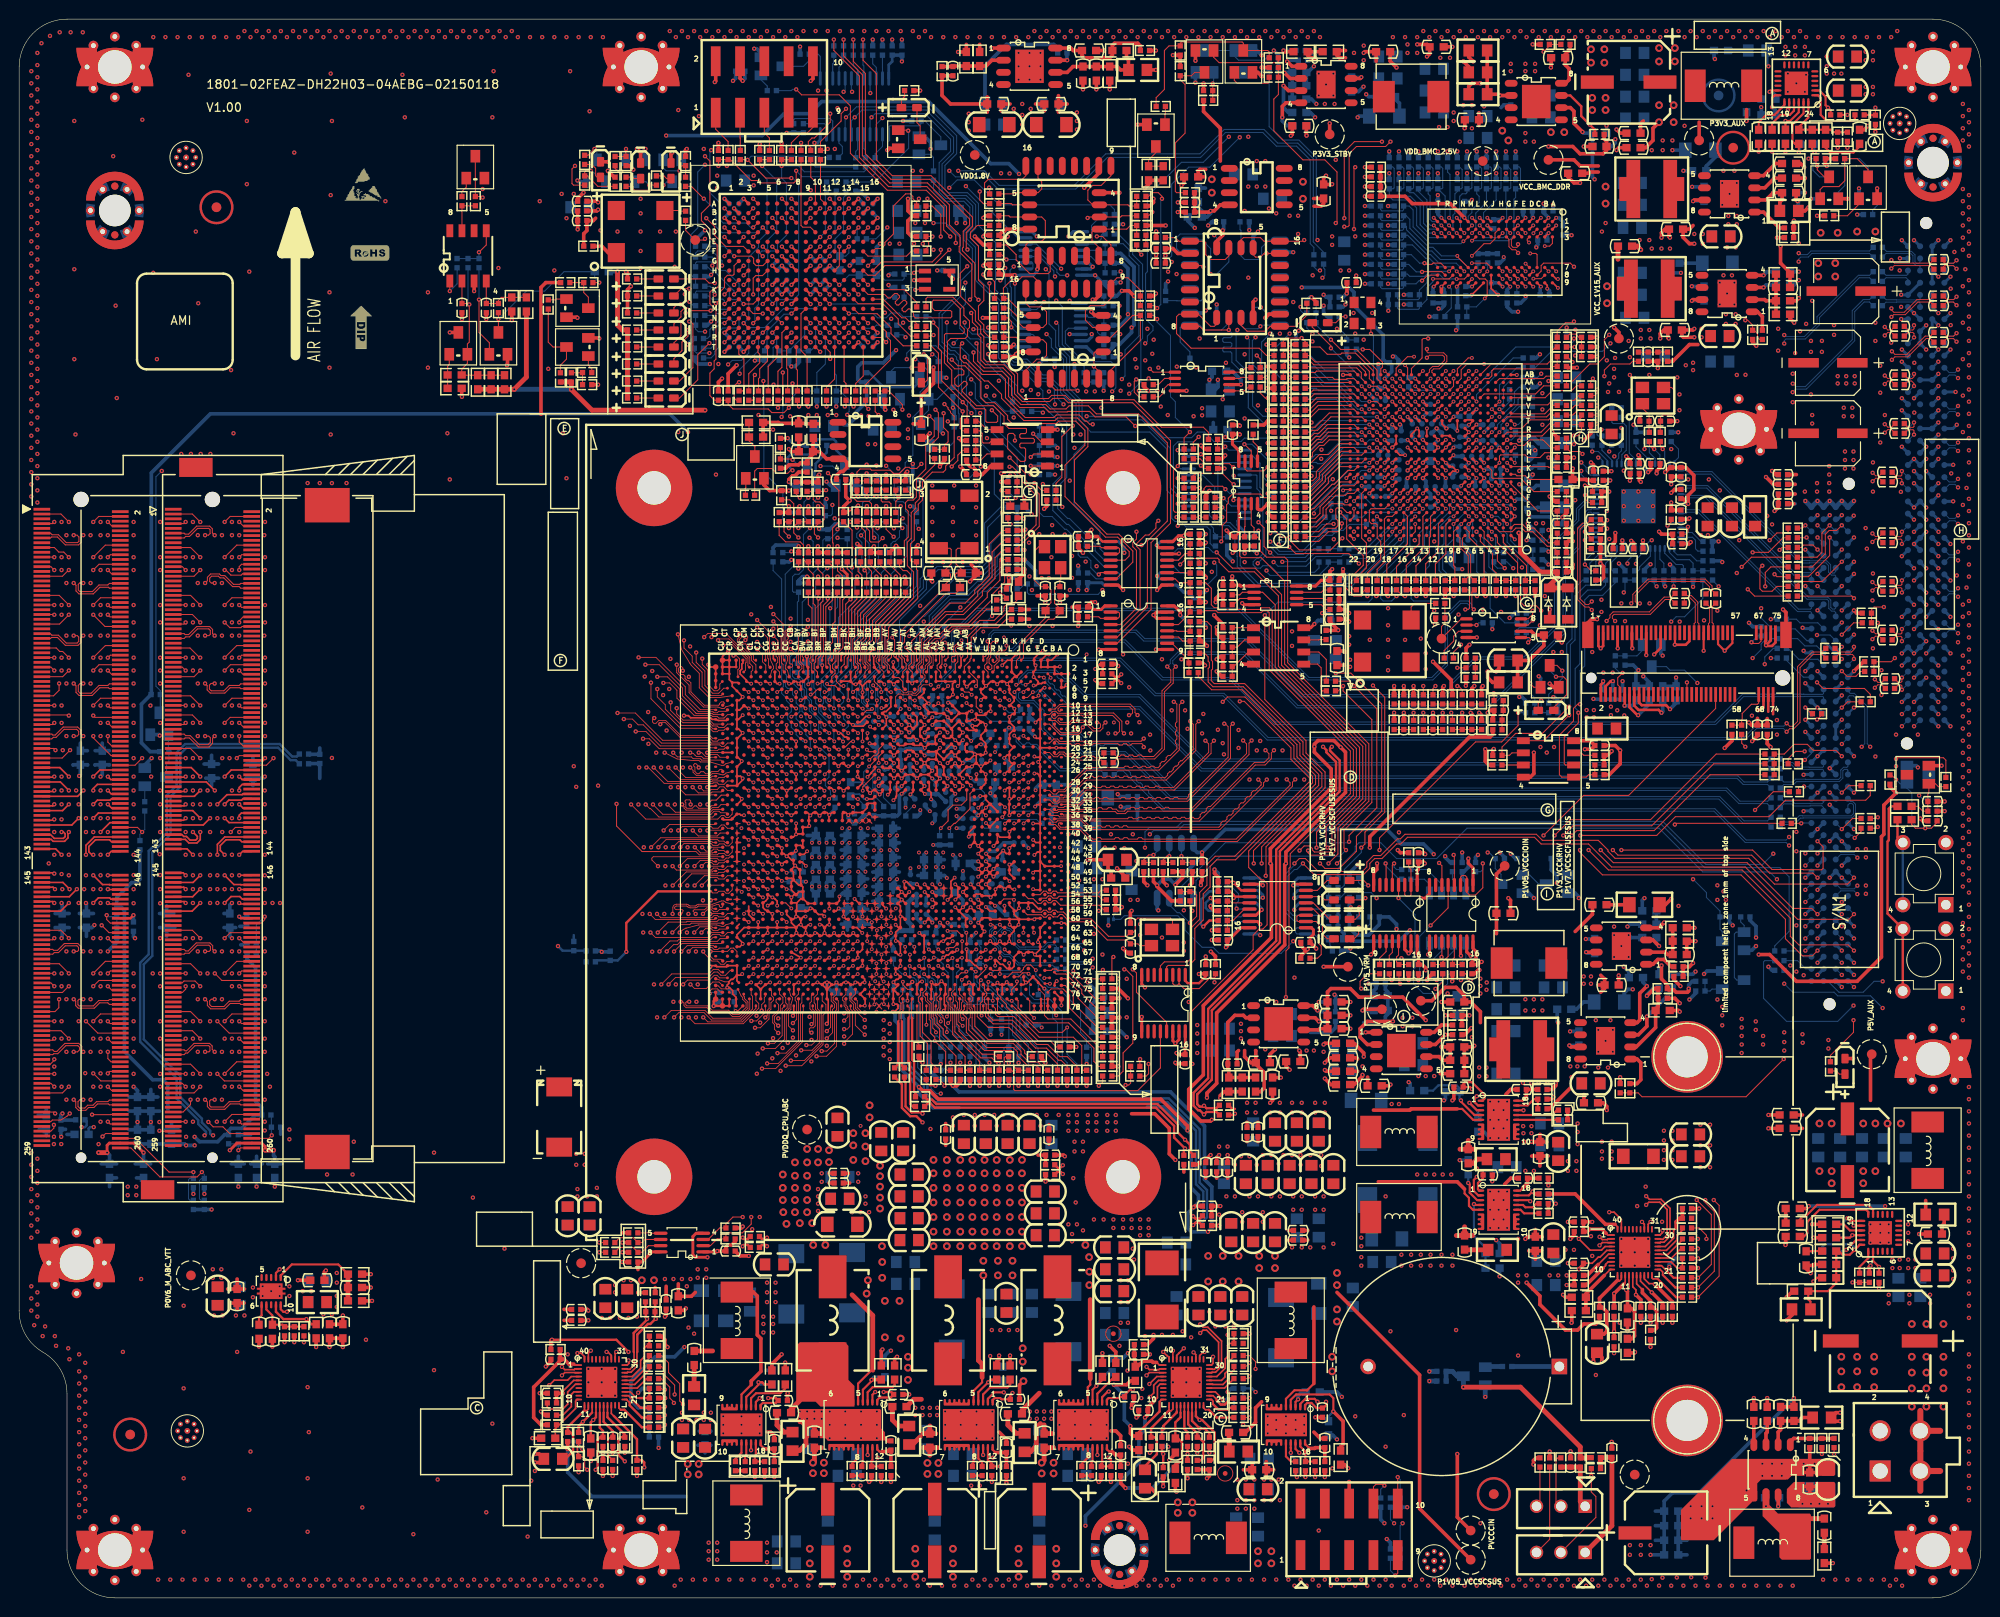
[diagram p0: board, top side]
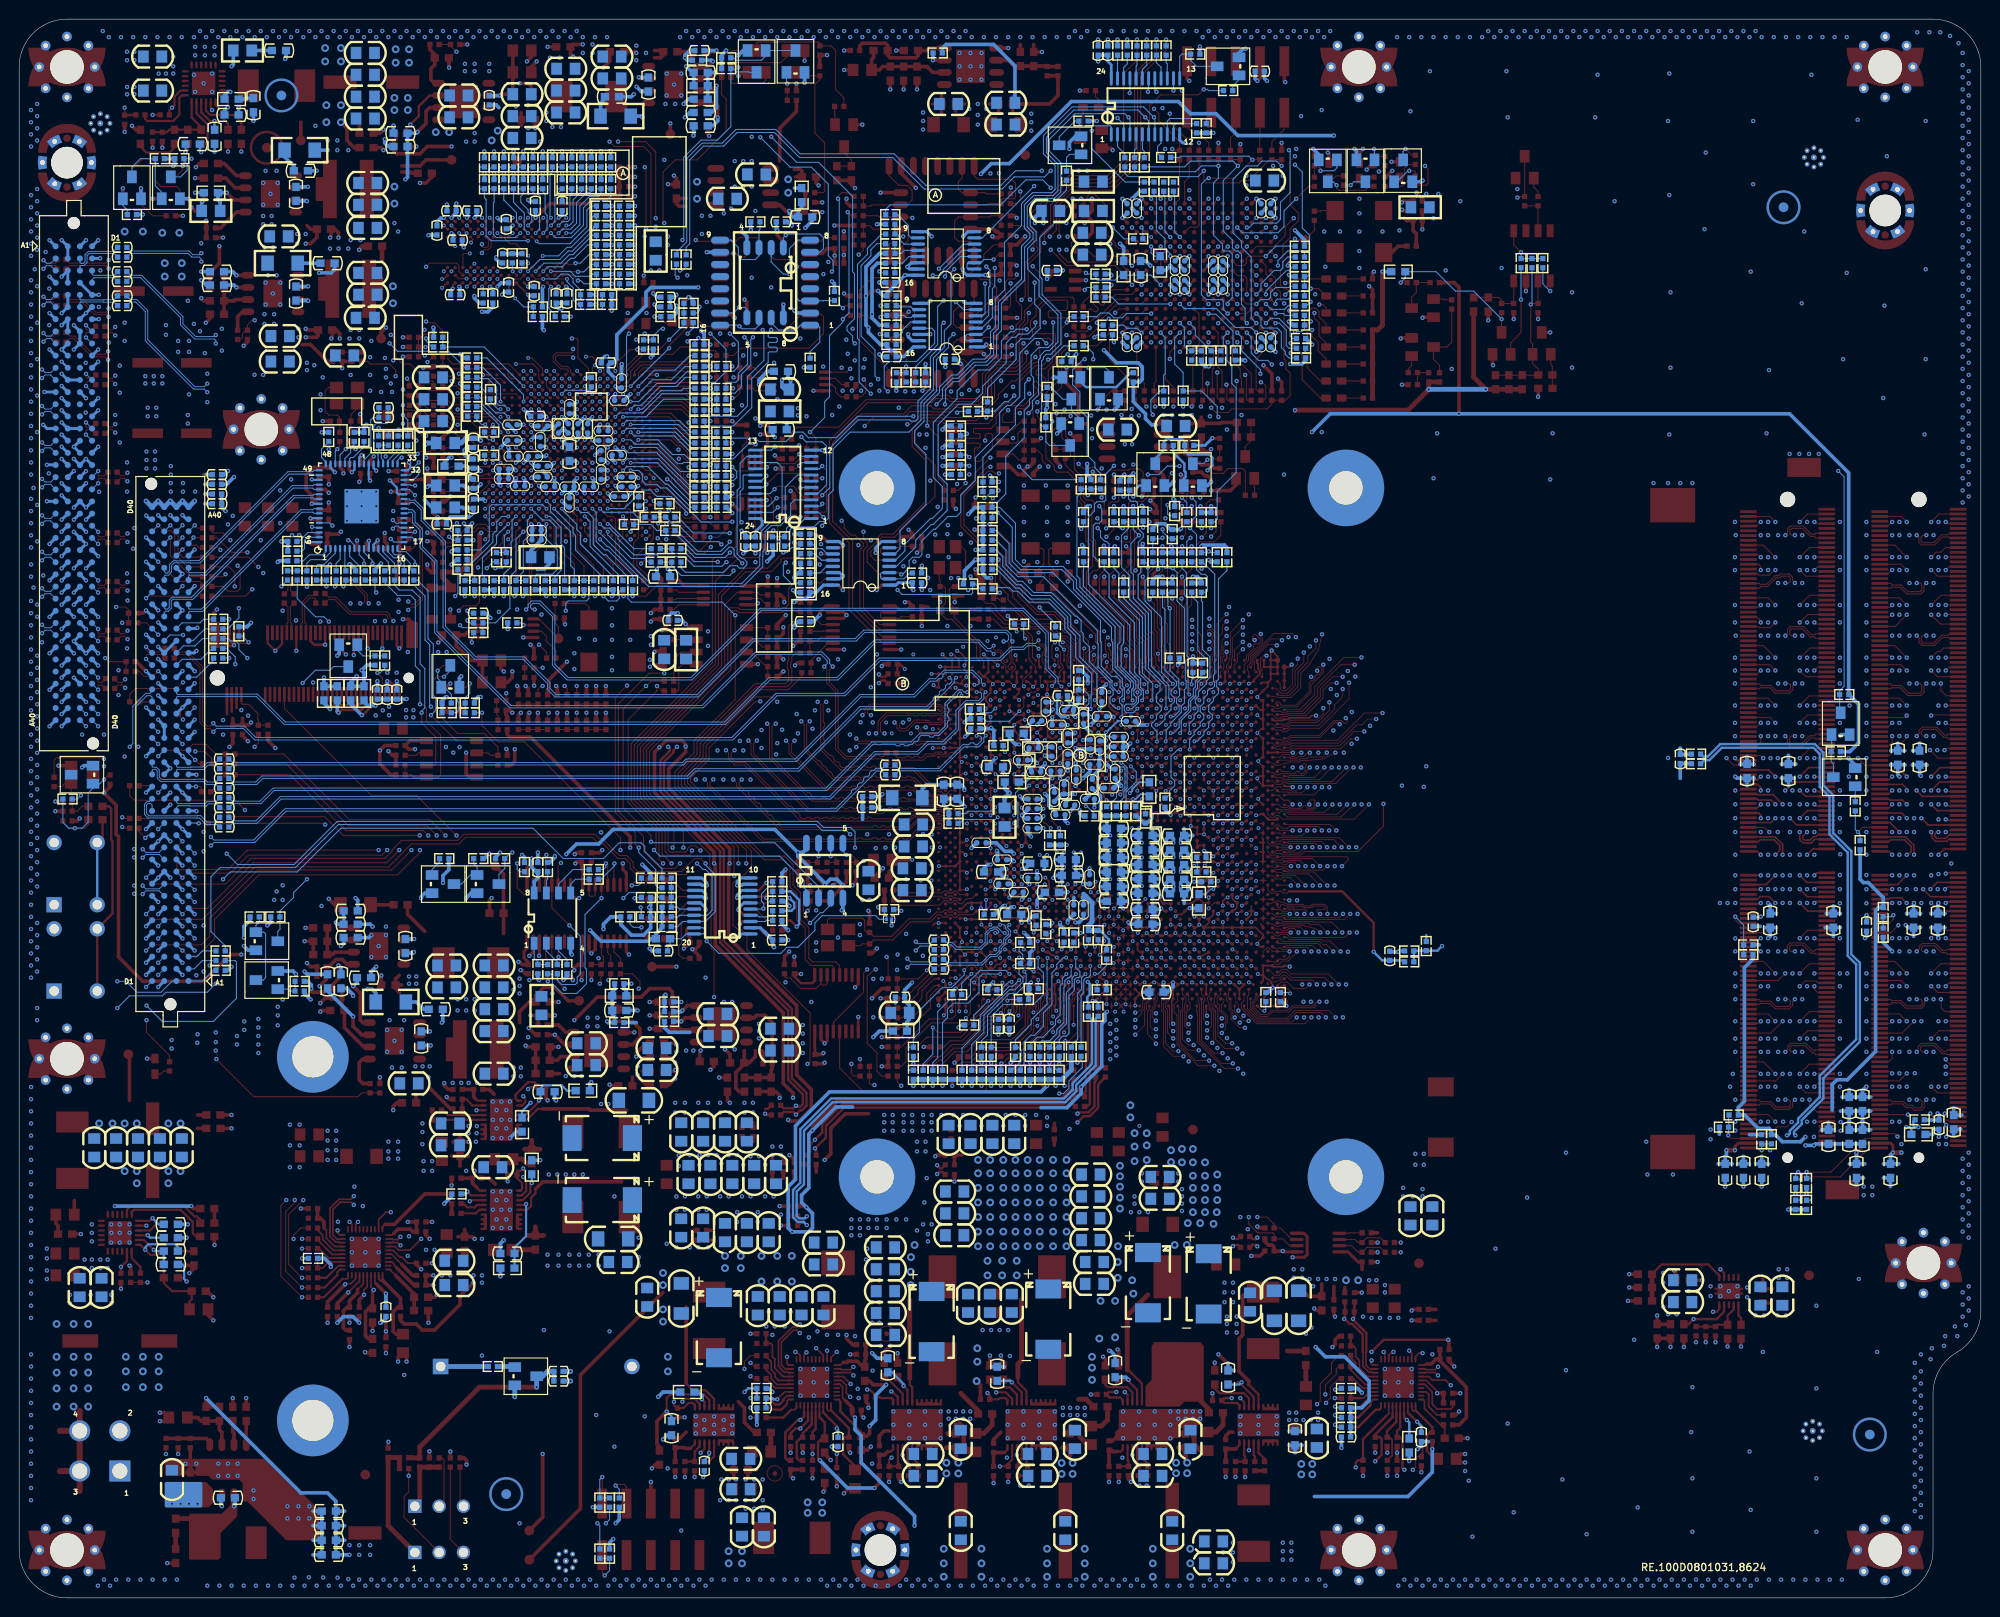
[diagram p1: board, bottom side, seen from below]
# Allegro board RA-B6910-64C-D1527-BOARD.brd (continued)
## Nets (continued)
VCCKRLCPLL: C605.1 C606.1 L32.2 R782.2 U43.T56(VCCKRLCPLL)
VCCSCPLL: C607.1 C608.1 L33.2 U43.T46(VCCSCPLL)
VCCSCSUS_EN: R648.2 R652.2 U2.D13(IO_44)
VCCSCSUS_LSET: R681.1 U32.3(LSET)
VCCSCSUS_PG: R89.2 R338.1 R1115.1
VCCSCSUS_SENSE: R352.1 U43.AR76(VCCSCSUS_SENSE)
VDD1.8V: C805.1 C806.1 C807.1 C808.1 C809.1 L37.2 R1231.1 R1234.1 U64.3(VOUT_1) U64.4(VOUT_2) X39.1
VDD5.0V_EN: Q41.3(C) R1251.2 R1252.2 U2.F13(IO_61)
VDD5.0V_EN_MID: R1252.1 R1253.1 U65.7(RESET)
VDD_BMC_2.5V: C132.1 C133.1 C134.1 C135.1 C136.1 C246.2 C247.2 R240.1 U9.3(VOUT_1) U9.4(VOUT_2) U21.B1(VPP_2) U21.R9(VPP_1) X23.1
VDD_BMC_2.5V_EN: R237.2 R241.2 U2.B1(IO_13)
VDD_BMC_2.5V_PG: R238.2 U2.C2(IO_33) U9.7(POK)
VSS_VCCGBE_SENSE: R357.1 U43.AP77(VSS_VCCGBE_SENSE)
VSS_VCCIN_SENSE: R348.1 U43.AT75(VSS_VCCIN_SENSE)
VSS_VCCSCSUS_SENSE: R353.1 U43.AR74(VSS_VCCSCSUS_SENSE)
24C02_WP: R1003.2 U43.BB21(GPIO24_MGPIO0)
1000M_MDI0N: U4.A32 U26.57(MDI_0-)
1000M_MDI0P: U4.A31 U26.58(MDI_0+)
1000M_MDI1N: U4.C32 U26.54(MDI_1-)
1000M_MDI1P: U4.C31 U26.55(MDI_1+)
1000M_MDI2N: U4.A35 U26.52(MDI_2-)
1000M_MDI2P: U4.A34 U26.53(MDI_2+)
1000M_MDI3N: U4.C35 U26.49(MDI_3-)
1000M_MDI3P: U4.C34 U26.50(MDI_3+)
AC_OK: Q39.3(C) R1221.2 R1239.2 R1250.2 U2.F1(IO_60)
AC_PG_R: Q38.1(B) R1230.1
ACSP1_VCCGBE: U33.4(ACSP1) U34.2(IOUT)
ACSP1_VCCIN: U29.4(ACSP1) U30.2(IOUT)
ACSP1_VDDQ: U36.4(ACSP1) U37.2(IOUT)
ACSP2_VCCIN: U29.5(ACSP2) U31.2(IOUT)
ADCAV33: C292.1 C316.1 C317.1 L17.2 U20.J6(ADCAV33)
ADDR_VCCGBE_P1V05_PCH: R691.2 R692.1 U33.10(ADDR)
ADDR_VCCIN_VCCSCSUS: R645.2 R646.1 U29.10(ADDR)
ADDR_VDDQ: R727.2 R729.1 U36.10(ADDR)
ADR_COMPLETE_CPLD: U2.G16(IO_70) U55.4(1A1)
ADR_COMPLETE_GTL: U43.AF66(ADR_COMPLETE) U55.13(1B1)
ADR_IN_CPLD: U2.F5(IO_156) U58.6(2A1)
ADR_IN_GTL: U43.AD66(ADR_IN) U58.11(2B1)
APH1_VCCIN: C347.1 L21.2 U30.6(SW)
APH1_VDDQ: C488.1 L28.2 U37.6(SW)
APH2_VCCIN: C375.1 L22.2 U31.6(SW)
APWM1_VCCGBE: U33.39(APWM1) U34.16(PWM)
APWM1_VCCIN: U29.39(APWM1) U30.10(PWM)
APWM1_VDDQ: U36.39(APWM1) U37.10(PWM)
APWM2_VCCIN: U29.38(APWM2) U31.10(PWM)
ARM_NTRST: R561.1 U20.E11(NTRST)
ARM_RTCK: R566.2 U20.C9(RTCK)
ARM_TCK: R564.1 U20.C10(TCK)
ARM_TDI: R562.1 U20.D12(TDI)
ARM_TDO: R565.1 U20.D11(TDO)
ARM_TMS: R563.1 U20.C8(TMS)
ASKIP_VCCGBE: R713.1 U33.40(A\S\K\I\P\)
ASKIP_VCCIN: R671.2 U29.40(A\S\K\I\P\)
ASKIP_VDDQ: R752.2 U36.40(A\S\K\I\P\)
BCSP1_P1V05_PCH: U33.30(BCSP) U35.2(IOUT)
BCSP1_P2V5_VPP: U36.30(BCSP) U38.2(IOUT)
BCSP1_VCCSCSUS: U29.30(BCSP) U32.2(IOUT)
BIST_ENABLE: R913.2 R1134.2 U43.AM69(BIST_ENABLE)
BMBUSY_N: R862.2 R1191.1 U43.BB28(BMBUSY_N_GPIO0)
BMC_9641_INT#: R169.1 R557.1 U20.T4(GPION7_PWM7_VPIG7)
BMC_ADC0: R26.1 U20.F4(ADC0_GPIW0)
BMC_ADC1: R27.1 U20.F5(ADC1_GPIW1)
BMC_ADC2: R28.1 U20.E2(ADC2_GPIW2)
BMC_ADC3: R29.1 U20.E1(ADC3_GPIW3)
BMC_ADC4: R30.1 U20.F3(ADC4_GPIW4)
BMC_ADC5: R37.1 U20.E3(ADC5_GPIW5)
BMC_ADC6: R38.1 U20.G5(ADC6_GPIW6)
BMC_ADC7: R39.1 U20.G4(ADC7_GPIW7)
BMC_ADC8: R40.1 U20.F2(ADC8_GPIX0)
BMC_ADC9: R41.1 U20.G3(ADC9_GPIX1)
BMC_ALERT_N: R553.2 R1097.2 U56.7(SCLB)
BMC_EXTRST_N: R536.1 U2.A13(IO_4)
BMC_GPIO_RS0: R197.1 R438.1 R439.1 U20.K18(GPIOB3)
BMC_I2C_RST#: R193.2 R560.1 U20.W6(GPIOP6_TACH14)
BMC_I2C_SCL: R462.2 R470.1 U4.B33
BMC_I2C_SDA: R192.2 R463.2 R472.1
BMC_READY_N: R84.2 R436.2 R467.1 U43.BA19(GPIO46)
BMC_RMII_CLK: R592.1 R593.2 U20.B4(RGMII1RXCK_RMII1RCLKI_GPIOU4)
BMC_RMII_CLK_50M: R54.2 R592.2
BMC_RSTBTN_R: R547.2 R559.1 U20.Y6(GPIOP4_TACH12)
BMC_SCL: R440.2 R441.1 U57.7(SCLB)
BMC_SDA: R442.2 R443.1 U57.6(SDAB)
BMC_SRST_N: R535.1 U2.A12(IO_3)
BMC_UART_RXD1: R494.2 U20.W1(GPIOL7_RXD1)
BMC_UART_RXD5: R1205.2 U20.K2(RXD5)
BMC_UART_TXD1: R493.2 U20.V1(GPIOL6_TXD1)
BMC_UART_TXD5: R580.2 R1204.2 U20.K1(TXD5)
BMCINIT: R837.2 R896.2 U43.AD69(BMCINIT)
BMCO_UART_RXD1: R494.1 U2.B10(IO_14)
BMCO_UART_RXD5: R1205.1 U2.H16(IO_76)
BMCO_UART_TXD1: R493.1 U2.B9(IO_26)
BMCO_UART_TXD5: R1204.1 U2.H15(IO_75)
BPH1_VCCSCSUS: C402.1 L24.2 U32.6(SW)
BPWM1_P1V05_PCH: U33.33(BPWM) U35.16(PWM)
BPWM1_P2V5_VPP: U36.33(BPWM) U38.16(PWM)
BPWM1_VCCSCSUS: U29.33(BPWM) U32.16(PWM)
BROAD_12V_EN: R82.2 R190.2 R191.1 R541.2
BROAD_RST#: R181.1 R185.2 U2.M16(IO_103)
BSKIP_P1V05_PCH: R720.1 U33.32(B\S\K\I\P\)
BSKIP_P2V5_VPP: R758.1 U36.32(B\S\K\I\P\)
BSKIP_VCCSCSUS: R683.1 U29.32(B\S\K\I\P\)
CATERR_N: R1039.1 R1050.2 U49.12(1B2)
CATERR_N_CPLD: U2.J2(IO_83) U49.5(1A2)
CATERR_N_GTL: R1050.1 U43.Y67(C\A\T\E\R\R\_\N\)
CLK: R147.2 R148.2 R768.2 R778.2
CLK_32KL_PCH_RTCX1: C588.1 R894.2 U43.AT2(RTCX1) Y1.4
CLK_32KL_PCH_RTCX2: C587.1 R894.1 U43.AT4(RTCX2) Y1.1
CLK_33M: R938.2 U45.1(CLK_IN)
CLK_33M_LOOPBACK: R940.2 U43.AC7(CLKIN_PCILOOPBACK)
CLKIN: OSC2.3(OUTPUT) U20.W18(CLKIN)
CLKOUT_PCIE_DN0: U26.25(PECLKN) U43.U2(CLKOUT_PCIE_DN[0])
CLKOUT_PCIE_DN1: U43.Y1(CLKOUT_PCIE_DN[1])
CLKOUT_PCIE_DN2: U4.B25 U43.T1(CLKOUT_PCIE_DN[2])
CLKOUT_PCIE_DN3: U43.T7(CLKOUT_PCIE_DN[3]) U60.C40
CLKOUT_PCIE_DN4: U43.R9(CLKOUT_PCIE_DN[4]) U60.D40
CLKOUT_PCIE_DN5: U43.R2(CLKOUT_PCIE_DN[5])
CLKOUT_PCIE_DN6: U43.M4(CLKOUT_PCIE_DN[6])
CLKOUT_PCIE_DN7: U43.N1(CLKOUT_PCIE_DN[7])
CLKOUT_PCIE_DP0: U26.26(PECLKP) U43.U4(CLKOUT_PCIE_DP[0])
CLKOUT_PCIE_DP1: U43.Y3(CLKOUT_PCIE_DP[1])
CLKOUT_PCIE_DP2: U4.B24 U43.T3(CLKOUT_PCIE_DP[2])
CLKOUT_PCIE_DP3: U43.P7(CLKOUT_PCIE_DP[3]) U60.C39
CLKOUT_PCIE_DP4: U43.N9(CLKOUT_PCIE_DP[4]) U60.D39
CLKOUT_PCIE_DP5: U43.R4(CLKOUT_PCIE_DP[5])
CLKOUT_PCIE_DP6: U43.M2(CLKOUT_PCIE_DP[6])
CLKOUT_PCIE_DP7: U43.N3(CLKOUT_PCIE_DP[7])
CON_33M_CLK: R174.1 R942.2
CPLD_25M_CLK: R1185.2 U2.J5(IO/GCLK1) X37.1
CPLD_APWROK: R77.1 U2.P12(IO_118) U43.BE13(APWROK)
CPLD_CLK: R1186.2 R1188.2 R1202.2
CPLD_CLK_50M: R58.2 U2.H12(IO/GCLK3)
CPLD_CSN0: R151.1 U2.M2(IO_104)
CPLD_CSN1: R152.1 U2.M3(IO_105)
CPLD_DATA: R1187.2 R1189.2 R1203.2
CPLD_ERR0_N: R120.1 U2.D4(IO_50)
CPLD_ERR1_N: R123.1 U2.D5(IO_51)
CPLD_ERR2_N: R126.1 U2.E1(IO_52)
CPLD_M2_DEVSLP: J3.38(NC/DEVSLP) R112.2
CPLD_MOLEX_UART_RXD0: R68.2 R79.2 U4.D1
CPLD_MOLEX_UART_TXD0: R69.2 R80.2 U4.B1
CPLD_NMI_N: R864.2 U2.J3(IO_84) U43.BP1(G\P\I\O\3\5\_\N\M\I\_\N\)
CPLD_PCH_PWROK: R75.1 U2.N2(IO_113) U43.AN1(PCH_PWROK)
CPLD_PLTRST_N: U2.R11(IO_131) U43.BE24(P\L\T\R\S\T\_\N\)
CPLD_RSMRST_N: R76.1 U2.N3(IO_114) U43.AR7(R\S\M\R\S\T\_\N\) U43.AV4(DPWROK)
CPLD_SAVEN0: R105.2
CPLD_SAVEN1: R108.2
CPLD_SLP_A_N: U2.H3(IO_78) U43.BB7(S\L\P\_\A\_\N\)
CPLD_SLP_S3_N: R893.1 U2.R10(IO_130) U43.AY2(S\L\P\_\S\3\_\N\)
CPLD_SLP_S4_N: U2.R1(IO_129) U43.AW1(S\L\P\_\S\4\_\N\)
CPLD_SLP_SUS_N: U2.P9(IO_128) U43.AY7(S\L\P\_\S\U\S\_\N\)
CPLD_SMI_N: R865.2 U2.K1(IO_85) U43.BR4(G\P\I\O\2\0\_\S\M\I\_\N\)
CPLD_SYS_PWROK: R70.2 U2.P10(IO_116) U43.BP5(SYS_PWROK)
CPU_ERROR0_N: R1054.1 R1059.2 U51.13(1B1)
CPU_ERROR0_N_CPLD: U2.R4(IO_137) U51.4(1A1)
CPU_ERROR0_N_GTL: R1059.1 U43.AC77(E\R\R\O\R\_\N\[\0\]\)
CPU_ERROR1_N: R1058.1 R1060.2 U51.12(1B2)
CPU_ERROR1_N_CPLD: U2.R5(IO_138) U51.5(1A2)
CPU_ERROR1_N_GTL: R1060.1 U43.AC75(E\R\R\O\R\_\N\[\1\]\)
CPU_ERROR2_N: R1055.1 R1061.2 U51.11(2B1)
CPU_ERROR2_N_CPLD: U2.R6(IO_139) U51.6(2A1)
CPU_ERROR2_N_GTL: R1061.1 U43.AB76(E\R\R\O\R\_\N\[\2\]\)
CPU_MEMHOT: R1037.1 R1049.2 U49.10(2B2)
CPU_MEMHOT_CPLD: U2.R8(IO_141) U49.7(2A2)
CPU_MEMHOT_GTL: R1049.1 U43.CC56(M\E\M\_\H\O\T\_\N\)
CPU_PROCHOT: R1063.1 R1071.2 U50.10(2B2)
CPU_PROCHOT_CPLD: U2.T10(IO_143) U50.7(2A2)
CPU_PROCHOT_GTL: R1071.1 U43.AG71(P\R\O\C\H\O\T\_\N\)
CPU_PWR_DEBUG_N: C614.1 R1029.2 U43.U77(P\W\R\_\D\E\B\U\G\_\N\)
CPU_THROTTLE: R1056.1 R1062.2 U51.10(2B2)
CPU_THROTTLE_CPLD: U2.R7(IO_140) U51.7(2A2)
CPU_THROTTLE_GTL: R922.2 R1062.1 U43.AL74(THROTTLE_PECI_ID2)
CSN0: R151.2 R763.1
CSN1: R152.2 R773.1
DACAV33: C298.1 C305.1 C306.1 R629.2 U20.K5(DACDV33) U20.K6(DACAV33)
DDR3_4_STRAP: R917.2 U43.AK69(DDR3_4_STRAP)
DDR_B_SA0: J8.256(SA0) R142.1 R1122.1
DDR_B_SA1: J8.260(SA1) R140.1 R1123.1
DDR_B_SA2: J8.166(SA2) R139.1 R1125.1
DDR_EVENT_N: Q10.3(C) R134.2 U2.J14(IO_80)
DDR_SA0: J7.256(SA0) R131.1 R1116.1
DDR_SA1: J7.260(SA1) R129.1 R1118.1
DDR_SA2: J7.166(SA2) R127.1 R1120.1
DDR_SCL: J7.253(SCL) J8.253(SCL) R20.1
DDR_SDA: J7.254(SDA) J8.254(SDA) R19.1
DDR_VREF: C528.1 C550.1 J7.164(VREFCA) J8.164(VREFCA) R985.2 R991.2 R993.1
DDR_VREF_CPU: C594.1 R991.1 U43.CR52(DDR_VREF)
DDRVREF: C238.1 C244.2 C252.1 C253.1 R454.2 R464.1 U20.T9(MVREF) U21.M1(VREFCA)
DRAMPWROK_PCH: R840.2 U43.BA9(DRAMPWROK_PCH) U43.CV55(DRAM_PWR_OK)
DSWODVREN: R892.2 U43.AL1(DSWODVREN)
EN/FCCM_P1V05_PCH: R719.2 R720.2 U35.17(EN/FCCM)
EN/FCCM_VCCSCSUS: R682.2 R683.2 U32.17(EN/FCCM)
EN/FCCM_VCCSCSUS_16997268: R712.2 R713.2 U34.17(EN/FCCM)
EN/FCCM_VCCSCSUS_17116599: R757.2 R758.2 U38.17(EN/FCCM)
EN_P0V6_VTT: R205.1 U2.B4(IO_21)
FIVR_FAULT_CPLD: U2.H2(IO_77) U49.4(1A1)
FIVR_FAULT_GTL: U43.AP69(FIVR_FAULT) U49.13(1B1)
FP_PWR_BTN_R: R545.2 R558.1 U20.AA5(GPIOP2_TACH10_VPIR8)
FP_PWR_LED: R11.1 U43.BA5(GPIO25)
FWSPICK: R480.2 U22.16(SCLK) U24.6(CLK)
FWSPICK_R: R480.1 R481.1 R573.2 U20.AA18(FWSPICK)
FWSPICKS: R481.2 U23.16(SCLK) U25.6(CLK)
FWSPICS0#: R492.2 U22.7(C\S\#\) U24.1(C\S\)
FWSPICS0#_R: R487.2 R492.1 R583.2 U20.AB19(F\W\S\P\I\C\S\0\#\)
FWSPICS1#: R498.2 U23.7(C\S\#\) U25.1(C\S\)
FWSPICS1#_R: R489.2 R498.1 U20.AA19(G\P\I\O\R\0\_\F\W\S\P\I\C\S\1\#)
FWSPIMISO: R486.2 U22.8(SO/IO1) U24.2(DO/IO1)
FWSPIMISO_R: R486.1 R488.1 R567.2 U20.T18(FWSPIMISO)
FWSPIMISOS: R488.2 U23.8(SO/IO1) U25.2(DO/IO1)
FWSPIMOSI: R482.2 U22.15(SI/SIO0) U24.5(DI_IO0)
FWSPIMOSI_R: R482.1 R495.1 R570.2 U20.U17(FWSPIMOSI)
FWSPIMOSIS: R495.2 U23.15(SI/SIO0) U25.5(DI_IO0)
GPIO1_CPU_SCL: R184.1 R812.2 R823.2 R889.2
GPIO2_ERR0: R851.2 U2.P2(IO_122) U43.BV16(P\I\R\Q\E\_\N\_\G\P\I\O\2\)
GPIO3_ERR1: R850.2 U2.P4(IO_123) U43.BN22(P\I\R\Q\F\_\N\_\G\P\I\O\3\)
GPIO4_THROT_INPUT: R848.2 U2.P5(IO_124) U43.BL22(P\I\R\Q\G\_\N\_\G\P\I\O\4\)
GPIO5_CATERR_INPUT: R847.2 U2.P6(IO_125) U43.BW22(P\I\R\Q\H\_\N\_\G\P\I\O\5\)
GPIO6_ONLINE_TMS: R813.2 R824.2 U62.7(1A3) U62.18(2A3)
GPIO7_RS0: R814.2 R825.2 U4.B37
GPIO15_CPU_9641_INT_N: R170.1 R830.2 U43.BA23(GPIO15)
GPIO16_CPU_THROTTLE: R975.2 U2.T11(IO_144) U43.BN2(SATA4GP_GPIO16)
GPIO17_CPU_SDA: R187.1 R811.2 R822.2 R887.2
GPIO19: R977.2 U43.BT3(SATA1GP_GPIO19)
GPIO21: R972.2 U43.BR2(SATA0GP_GPIO21)
GPIO22_CPU_INT_N: R820.2 R1174.2 R1190.1 U43.BN14(SCLOCK_GPIO22)
GPIO27: R832.2 U43.BB16(GPIO27_MGPIO6)
GPIO28_MOD_PRE0: R198.2 R831.2 U43.BB23(GPIO28_MGPIO7)
GPIO29: R836.2 U43.BB12(SLP_WLAN_N_GPIO29_MGPIO3)
GPIO30: R838.2 U43.AY11(S\U\S\W\A\R\N\_\N\_\S\U\S\P\W\R)
GPIO32_ONLINE_TDO: R841.2 R854.2 U62.4(1A2) U62.17(2A2)
GPIO33: R900.2 R1180.2 U43.AN11(GPIO33)
GPIO36: R978.2 R1182.2 U43.BT1(SATA2GP_GPIO36)
GPIO37: R976.2 R1183.2 U43.BL2(SATA3GP_GPIO37)
GPIO38_PCIE_CONFIG: R179.1 R821.2 R1206.2 U43.BP13(SLOAD_GPIO38)
GPIO39: R816.2 U43.BU18(SDATAOUT0_GPIO39)
GPIO44: R833.2 U43.BD18(GPIO44)
GPIO45: R834.2 U43.BA21(GPIO45)
GPIO48: R817.2 U43.BT16(SDATAOUT1_GPIO48)
GPIO49: R974.2 U43.BM1(SATA5GP_GPIO49)
GPIO50_ONLINE_JTAG_EN: R829.1 R844.2 R1172.2 U4.B7
GPIO51: R861.2 U43.BL18(GPIO51)
GPIO52: R901.2 U43.BP16(GPIO52)
GPIO53: R895.2 U43.BT20(GPIO53)
GPIO54: R842.2 U43.BW18(GPIO54)
GPIO55: R859.2 R903.2 U43.BU22(GPIO55)
GPIO57: R870.2 R904.2 U43.BP9(GPIO57_MGPIO5)
GPIO62: R852.1 R853.1 R886.2 U43.BD11(SUSCLK_GPIO62)
GPIO65_ONLINE_TCK: R935.2 R937.2 U62.3(1A1) U62.14(2A1)
GPIO67_ONLINE_TDI: R934.2 R936.2 U62.8(1A4) U62.21(2A4)
GPIO68_RS1: R815.2 R826.2 U4.B38
GPIO69: R827.2 U43.AU9(TACH5_GPIO69)
GPIO70: R818.2 U43.AU14(TACH6_GPIO70)
GPIO71_I2C_RST_N: R175.1 R819.2 U43.AM2(TACH7_GPIO71)
GPIO72: R874.2 U43.BB4(GPIO72)
GPIOS4: R527.1 U20.R19(GPIOS4_VPOB6)
GPIOS5: R529.1 U20.W20(GPIOS5_VPOB7)
GPIOS6: R531.1 U20.U20(GPIOS6_VPOB8)
GPIOS7: R533.1 U20.AA20(GPIOS7_VPOB9)
GPIOT4: R581.2 R582.1 U20.E7(RGMII1TXD2_GPIOT4)
GPIOT5: R578.2 R579.1 U20.D7(RGMII1TXD3_GPIOT5)
GPIOZ3: R502.2 R537.2 U20.K3(ENTEST)
GPIOZ4: R528.2 U20.U21(GPIOZ4_VPOG6_NORA4)
GPIOZ5: R530.2 U20.W22(GPIOZ5_VPOG7_NORA5)
GPIOZ6: R532.2 U20.V22(GPIOZ6_VPOG8_NORA6)
GPIOZ7: R534.2 U20.W21(GPIOZ7_VPOG9_NORA7)
HB_LED#: D30.2(CATHODE) U20.Y18(H\B\L\E\D\#\)
I210_REF_CLK: R1138.1 U26.46(XTAL1)
I210_VDD3V3: C266.2 C267.2 C268.1 C269.1 C270.1 C271.1 L16.1 U26.10(VDD3P3_4) U26.27(VDD3P3_5) U26.41(VDD3P3_1) U26.51(VDD3P3_2) U26.64(VDD3P3_3)
I210_XOUT: R615.2 U26.45(XTAL2)
INTRUDER_N: R890.2 U43.AK2(I\N\T\R\U\D\E\R\_\N\)
INTVRMEN: R891.2 U43.AP2(INTVRMEN)
JTAG_NIC_TCK: R623.1 U26.19(JTAG_CLK)
JTAG_NIC_TDI: R622.1 U26.29(JTAG_TDI)
JTAG_NIC_TDO: R621.1 U26.4(JTAG_TDO)
JTAG_NIC_TMS: R624.1 U26.18(JTAG_TMS)
JTAG_PCH_TCK: R996.1 U43.BM3(JTAG_TCK_PCH)
JTAG_PCH_TDI: R994.1 U43.BM5(JTAG_TDI_PCH)
JTAG_PCH_TDO: R995.1 U43.BK3(JTAG_TDO_PCH)
JTAG_PCH_TMS: R992.1 U43.BJ2(JTAG_TMS_PCH)
KR_P0_RX_DN: C578.1 U4.C9
KR_P0_RX_DP: C579.1 U4.C8
KR_P0_TX_DN: U4.B22 U43.J62(LAN_KR_TX0_N)
KR_P0_TX_DP: U4.B21 U43.F62(LAN_KR_TX0_P)
KR_P1_RX_DN: C580.1 U4.C12
KR_P1_RX_DP: C581.1 U4.C11
KR_P1_TX_DN: U4.D22 U43.J66(LAN_KR_TX1_N)
KR_P1_TX_DP: U4.D21 U43.F66(LAN_KR_TX1_P)
LAN_ALERT_N_GTL: R788.1 R1100.2 U56.2(SCLA)
LAN_CLK: R1109.2 U59.12(1B2)
LAN_CS: R1105.1 R1107.2 U59.13(1B1)
LAN_DI: R1111.2 R1113.2 U58.12(1B2)
LAN_DO: R1110.2 U59.11(2B1)
LAN_JTDO: R783.2 U43.B71(LAN_JTDO)
LAN_MODE_SEL0: R798.2 R801.2 U43.E75(LAN_MDIO_DIR_CTL_0)
LAN_MODE_SEL1: R799.2 R800.2 U43.N72(LAN_MDIO_DIR_CTL_1)
LAN_P0_ACTIVE: D5.2(CATHODE) U52.4(1A1)
LAN_P0_ACTIVE_GTL: R1068.2 R1083.2 U43.W69(LAN_MDIO0_LED0_0)
LAN_P0_SPEED: D4.2(CATHODE) U52.5(1A2)
LAN_P0_SPEED_GTL: R1069.2 R1085.2 U43.U69(LAN_MDC0_LED0_1)
LAN_P1_ACTIVE: D7.2(CATHODE) U52.6(2A1)
LAN_P1_ACTIVE_GTL: R1074.1 U43.T67(LAN_MDIO1_LED1_0) U52.11(2B1)
LAN_P1_SPEED: D6.2(CATHODE) U52.7(2A2)
LAN_P1_SPEED_GTL: R1075.1 U43.V67(LAN_MDC1_LED1_1) U52.10(2B2)
LAN_PWR_GOOD: R628.1 U26.1(LAN_PWR_GOOD)
LAN_PWRGD: R1112.2 R1114.2 U58.13(1B1)
LAN_PWRGD_CPLD: U2.F6(IO_157) U58.4(1A1)
LAN_PWRGD_GTL: R1112.1 U43.AE77(LAN_PWRGOOD)
LAN_SCL_GTL: R789.1 R1102.2 U57.2(SCLA)
LAN_SDA_GTL: R791.1 R1101.2 U57.3(SDAA)
LAN_SDP0_1: R781.2 U43.C76(LAN_SDP0_1)
LAN_SPI_CLK: R807.2 U59.5(1A2)
LAN_SPI_CLK_GTL: R1109.1 U43.M67(LAN_FLSH_CLK)
LAN_SPI_CS: R803.1 U59.4(1A1)
LAN_SPI_CS_GTL: R1107.1 U43.P67(L\A\N\_\F\L\S\H\_\C\S\_\N\)
LAN_SPI_DI: R804.1 U58.5(1A2)
LAN_SPI_DI_GTL: R1111.1 U43.D74(LAN_FLSH_DO)
LAN_SPI_DO: R808.2 U59.6(2A1)
LAN_SPI_DO_GTL: R1110.1 U43.C73(LAN_FLSH_DI)
LAN_XTAL_IN: C582.1 OSC4.1 U43.J58(LAN_XTAL_IN)
LAN_XTAL_OUT: C583.1 OSC4.3 U43.F58(LAN_XTAL_OUT)
LED: J3.10(LED_1#/DAS/DSS#) R168.2
LED0_N: D8.2(CATHODE) U2.K5(IO_173)
LED1_N: D9.2(CATHODE) U2.K6(IO_174)
LED2_N: D10.2(CATHODE) U2.K11(IO_175)
LED3_N: D11.2(CATHODE) U2.K12(IO_176)
LED4_N: D12.2(CATHODE) U2.K13(IO_177)
LED5_N: D13.2(CATHODE) U2.L5(IO_178)
LED6_N: D14.2(CATHODE) U2.L7(IO_179)
LED7_N: D15.2(CATHODE) U2.L10(IO_180)
LED_HDD_ACTIVITY_N: R6.1 U43.BF14(S\A\T\A\L\E\D\_\N\)
LM75_OS: R320.1 U20.E13(GPIOA3_TIMER4)
LPC_33M_BMC: R943.2 U20.C22(GPIOAC4_ESPICK_LCLK)
LPC_33M_CPLD: R944.2 U2.H5(IO/GCLK0)
LPC_DA0: R65.2 R180.1 R431.2 U43.AF3(LAD[0])
LPC_DA1: R66.2 R182.1 R432.2 U43.AG4(LAD[1])
LPC_DA2: R67.2 R188.1 R434.2 U43.AL3(LAD[2])
LPC_DA3: R60.2 R189.1 R435.2 U43.AF1(LAD[3])
LPC_FRAME_N: R51.1 R63.2 R178.1 U43.AH1(L\F\R\A\M\E\_\N\)
LPC_RST_N: R52.1 U2.D14(IO_45)
LPC_SERIRQ: R176.1 R1089.2
LPCPD#: R403.2 U20.H21(G\P\I\O\B\5\_\L\P\C\P\D\#\_\L\P)
LPCPME#: R406.2 U20.H22(G\P\I\O\B\6\_\L\P\C\P\M\E\#\)
M_A-CLK_DN2: J7.140(CK1_C) U43.CG47(DDR0_CLK_DN[2])
M_A_BA0: J7.150(BA0) U43.CH52(DDR0_BA[0])
M_A_BA1: J7.145(BA1) U43.CL51(DDR0_BA[1])
M_A_BG0: J7.115(BG0) U43.CM33(DDR0_BG0_BA[2])
M_A_BG1: J7.113(BG1) U43.CD35(DDR0_BG1_MA[14])
M_A_CKE0: J7.109(CKE0) U43.CD32(DDR0_CKE[0])
M_A_CKE1: J7.110(CKE1/NC) U43.CG32(DDR0_CKE[1])
M_A_CKE2: U43.CL32(DDR0_CKE[2])
M_A_CKE3: U43.CJ32(DDR0_CKE[3])
M_A_CLK_DN0: J7.139(CK0_C) U43.CJ47(DDR0_CLK_DN[0])
M_A_CLK_DN1: U43.CM45(DDR0_CLK_DN[1])
M_A_CLK_DN3: U43.CL43(DDR0_CLK_DN[3])
M_A_CLK_DP0: J7.137(CK0_T) U43.CL47(DDR0_CLK_DP[0])
M_A_CLK_DP1: U43.CK45(DDR0_CLK_DP[1])
M_A_CLK_DP2: J7.138(CK1_T) U43.CF45(DDR0_CLK_DP[2])
M_A_CLK_DP3: U43.CJ43(DDR0_CLK_DP[3])
M_A_CS_N0: J7.149(CS0_N) U43.CL54(D\D\R\0\_\C\S\_\N\[\0\]\)
M_A_CS_N1: J7.157(CS1_N/NC) U43.CJ58(D\D\R\0\_\C\S\_\N\[\1\]\)
M_A_CS_N4: U43.CD54(D\D\R\0\_\C\S\_\N\[\4\]\)
M_A_CS_N5: U43.CF52(D\D\R\0\_\C\S\_\N\[\5\]\)
M_A_DQ0: J7.8(DQ0) U43.BY2(DDR0_DQ[0])
M_A_DQ1: J7.7(DQ1) U43.BY4(DDR0_DQ[1])
M_A_DQ2: J7.20(DQ2) U43.CD2(DDR0_DQ[2])
M_A_DQ3: J7.21(DQ3) U43.CD4(DDR0_DQ[3])
M_A_DQ4: J7.4(DQ4) U43.BW1(DDR0_DQ[4])
M_A_DQ5: J7.3(DQ5) U43.BW3(DDR0_DQ[5])
M_A_DQ6: J7.16(DQ6) U43.CC1(DDR0_DQ[6])
M_A_DQ7: J7.17(DQ7) U43.CC3(DDR0_DQ[7])
M_A_DQ8: J7.28(DQ8) U43.CC7(DDR0_DQ[8])
M_A_DQ9: J7.29(DQ9) U43.CB9(DDR0_DQ[9])
M_A_DQ10: J7.41(DQ10) U43.CM7(DDR0_DQ[10])
M_A_DQ11: J7.42(DQ11) U43.CL9(DDR0_DQ[11])
M_A_DQ12: J7.24(DQ12) U43.CA7(DDR0_DQ[12])
M_A_DQ13: J7.25(DQ13) U43.BY9(DDR0_DQ[13])
M_A_DQ14: J7.38(DQ14) U43.CK7(DDR0_DQ[14])
M_A_DQ15: J7.37(DQ15) U43.CJ9(DDR0_DQ[15])
M_A_DQ16: J7.50(DQ16) U43.CB13(DDR0_DQ[16])
M_A_DQ17: J7.49(DQ17) U43.CC14(DDR0_DQ[17])
M_A_DQ18: J7.62(DQ18) U43.CL13(DDR0_DQ[18])
M_A_DQ19: J7.63(DQ19) U43.CM14(DDR0_DQ[19])
M_A_DQ20: J7.46(DQ20) U43.BY13(DDR0_DQ[20])
M_A_DQ21: J7.45(DQ21) U43.CA14(DDR0_DQ[21])
M_A_DQ22: J7.58(DQ22) U43.CJ13(DDR0_DQ[22])
M_A_DQ23: J7.59(DQ23) U43.CK14(DDR0_DQ[23])
M_A_DQ24: J7.70(DQ24) U43.CD20(DDR0_DQ[24])
M_A_DQ25: J7.71(DQ25) U43.CB20(DDR0_DQ[25])
M_A_DQ26: J7.83(DQ26) U43.CD28(DDR0_DQ[26])
M_A_DQ27: J7.84(DQ27) U43.CB28(DDR0_DQ[27])
M_A_DQ28: J7.66(DQ28) U43.CF18(DDR0_DQ[28])
M_A_DQ29: J7.67(DQ29) U43.CC18(DDR0_DQ[29])
M_A_DQ30: J7.79(DQ30) U43.CF26(DDR0_DQ[30])
M_A_DQ31: J7.80(DQ31) U43.CC26(DDR0_DQ[31])
M_A_DQ32: J7.174(DQ32) U43.CD66(DDR0_DQ[32])
M_A_DQ33: J7.173(DQ33) U43.CB66(DDR0_DQ[33])
M_A_DQ34: J7.187(DQ34) U43.CD72(DDR0_DQ[34])
M_A_DQ35: J7.186(DQ35) U43.CB72(DDR0_DQ[35])
M_A_DQ36: J7.170(DQ36) U43.CF64(DDR0_DQ[36])
M_A_DQ37: J7.169(DQ37) U43.CC64(DDR0_DQ[37])
M_A_DQ38: J7.183(DQ38) U43.CF71(DDR0_DQ[38])
M_A_DQ39: J7.182(DQ39) U43.CC71(DDR0_DQ[39])
M_A_DQ40: J7.195(DQ40) U43.CL66(DDR0_DQ[40])
M_A_DQ41: J7.194(DQ41) U43.CJ66(DDR0_DQ[41])
M_A_DQ42: J7.207(DQ42) U43.CL72(DDR0_DQ[42])
M_A_DQ43: J7.208(DQ43) U43.CJ72(DDR0_DQ[43])
M_A_DQ44: J7.191(DQ44) U43.CM64(DDR0_DQ[44])
M_A_DQ45: J7.190(DQ45) U43.CK64(DDR0_DQ[45])
M_A_DQ46: J7.203(DQ46) U43.CM71(DDR0_DQ[46])
M_A_DQ47: J7.204(DQ47) U43.CK71(DDR0_DQ[47])
M_A_DQ48: J7.216(DQ48) U43.BT72(DDR0_DQ[48])
M_A_DQ49: J7.215(DQ49) U43.BU71(DDR0_DQ[49])
M_A_DQ50: J7.228(DQ50) U43.BG72(DDR0_DQ[50])
M_A_DQ51: J7.229(DQ51) U43.BH71(DDR0_DQ[51])
M_A_DQ52: J7.211(DQ52) U43.BV72(DDR0_DQ[52])
M_A_DQ53: J7.212(DQ53) U43.BW71(DDR0_DQ[53])
M_A_DQ54: J7.224(DQ54) U43.BJ72(DDR0_DQ[54])
M_A_DQ55: J7.225(DQ55) U43.BL71(DDR0_DQ[55])
M_A_DQ56: J7.237(DQ56) U43.BU67(DDR0_DQ[56])
M_A_DQ57: J7.236(DQ57) U43.BT66(DDR0_DQ[57])
M_A_DQ58: J7.249(DQ58) U43.BH67(DDR0_DQ[58])
M_A_DQ59: J7.250(DQ59) U43.BG66(DDR0_DQ[59])
M_A_DQ60: J7.232(DQ60) U43.BW67(DDR0_DQ[60])
M_A_DQ61: J7.233(DQ61) U43.BV66(DDR0_DQ[61])
M_A_DQ62: J7.245(DQ62) U43.BL67(DDR0_DQ[62])
M_A_DQ63: J7.246(DQ63) U43.BJ66(DDR0_DQ[63])
M_A_DQS_DN0: J7.11(DQS0_C) U43.CB4(DDR0_DQS_DN[0])
M_A_DQS_DN1: J7.32(DQS1_C) U43.CH7(DDR0_DQS_DN[1])
M_A_DQS_DN2: J7.53(DQS2_C) U43.CG13(DDR0_DQS_DN[2])
M_A_DQS_DN3: J7.74(DQS3_C) U43.CD24(DDR0_DQS_DN[3])
M_A_DQS_DN4: J7.177(DQS4_C) U43.CD69(DDR0_DQS_DN[4])
M_A_DQS_DN5: J7.198(DQS5_C) U43.CL69(DDR0_DQS_DN[5])
M_A_DQS_DN6: J7.219(DQS6_C) U43.BM72(DDR0_DQS_DN[6])
M_A_DQS_DN7: J7.240(DQS7_C) U43.BN67(DDR0_DQS_DN[7])
M_A_DQS_DN8: J7.95(DQS8_C) U43.CL24(DDR0_DQS_DN[8])
M_A_DQS_DN9: U43.CA1(DDR0_DQS_DN[9])
M_A_DQS_DN10: U43.CD9(DDR0_DQS_DN[10])
M_A_DQS_DN11: U43.CF14(DDR0_DQS_DN[11])
M_A_DQS_DN12: U43.CC22(DDR0_DQS_DN[12])
M_A_DQS_DN13: U43.CC67(DDR0_DQS_DN[13])
M_A_DQS_DN14: U43.CK67(DDR0_DQS_DN[14])
M_A_DQS_DN15: U43.BR71(DDR0_DQS_DN[15])
M_A_DQS_DN16: U43.BP66(DDR0_DQS_DN[16])
M_A_DQS_DN17: U43.CK22(DDR0_DQS_DN[17])
M_A_DQS_DP0: J7.13(DQS0_T) U43.CB2(DDR0_DQS_DP[0])
M_A_DQS_DP1: J7.34(DQS1_T) U43.CG9(DDR0_DQS_DP[1])
M_A_DQS_DP2: J7.55(DQS2_T) U43.CH14(DDR0_DQS_DP[2])
M_A_DQS_DP3: J7.76(DQS3_T) U43.CB24(DDR0_DQS_DP[3])
M_A_DQS_DP4: J7.179(DQS4_T) U43.CB69(DDR0_DQS_DP[4])
M_A_DQS_DP5: J7.200(DQS5_T) U43.CJ69(DDR0_DQS_DP[5])
M_A_DQS_DP6: J7.221(DQS6_T) U43.BN71(DDR0_DQS_DP[6])
M_A_DQS_DP7: J7.242(DQS7_T) U43.BM66(DDR0_DQS_DP[7])
M_A_DQS_DP8: J7.97(DQS8_T) U43.CJ24(DDR0_DQS_DP[8])
M_A_DQS_DP9: U43.CA3(DDR0_DQS_DP[9])
M_A_DQS_DP10: U43.CF7(DDR0_DQS_DP[10])
M_A_DQS_DP11: U43.CD13(DDR0_DQS_DP[11])
M_A_DQS_DP12: U43.CF22(DDR0_DQS_DP[12])
M_A_DQS_DP13: U43.CF67(DDR0_DQS_DP[13])
M_A_DQS_DP14: U43.CM67(DDR0_DQS_DP[14])
M_A_DQS_DP15: U43.BP72(DDR0_DQS_DP[15])
M_A_DQS_DP16: U43.BR67(DDR0_DQS_DP[16])
M_A_DQS_DP17: U43.CM22(DDR0_DQS_DP[17])
M_A_ECC0: J7.92(CB0/NC) U43.CL20(DDR0_ECC[0])
M_A_ECC1: J7.91(CB1/NC) U43.CJ20(DDR0_ECC[1])
M_A_ECC2: J7.101(CB2/NC) U43.CL28(DDR0_ECC[2])
M_A_ECC3: J7.105(CB3/NC) U43.CJ28(DDR0_ECC[3])
M_A_ECC4: J7.88(CB4/NC) U43.CM18(DDR0_ECC[4])
M_A_ECC5: J7.87(CB5/NC) U43.CK18(DDR0_ECC[5])
M_A_ECC6: J7.100(CB6/NC) U43.CM26(DDR0_ECC[6])
M_A_ECC7: J7.104(CB7/NC) U43.CK26(DDR0_ECC[7])
M_A_MA0: J7.144(A0) U43.CK49(DDR0_MA[0])
M_A_MA1: J7.133(A1) U43.CK41(DDR0_MA[1])
M_A_MA2: J7.132(A2) U43.CM41(DDR0_MA[2])
M_A_MA3: J7.131(A3) U43.CF41(DDR0_MA[3])
M_A_MA4: J7.128(A4) U43.CL39(DDR0_MA[4])
M_A_MA5: J7.126(A5) U43.CG39(DDR0_MA[5])
M_A_MA6: J7.127(A6) U43.CK37(DDR0_MA[6])
M_A_MA7: J7.122(A7) U43.CD39(DDR0_MA[7])
M_A_MA8: J7.125(A8) U43.CM37(DDR0_MA[8])
M_A_MA9: J7.121(A9) U43.CJ35(DDR0_MA[9])
M_A_MA10: J7.146(A10/AP) U43.CJ51(DDR0_MA[10])
M_A_MA11: J7.120(A11) U43.CG35(DDR0_MA[11])
M_A_MA12: J7.119(A12/BC) U43.CF37(DDR0_MA[12])
M_A_MA13: J7.158(A13) U43.CK56(DDR0_MA[13])
M_A_MA14: J7.151(WE_N/A14) U43.CM52(D\D\R\0\_\M\A\1\4\_\W\E\_\N\)
M_A_MA15: J7.156(CAS_N/A15) U43.CJ54(D\D\R\0\_\M\A\1\5\_\C\A\S\_\N\)
M_A_MA16: J7.152(RAS_N/A16) U43.CF49(D\D\R\0\_\M\A\1\6\_\R\A\S\_\N\)
M_A_ODT0: J7.155(ODT0) U43.CF56(DDR0_ODT[0])
M_A_ODT1: J7.161(ODT1/NC) U43.CM60(DDR0_ODT[1])
M_A_ODT2: U43.CM56(DDR0_ODT[2])
M_A_ODT3: U43.CH60(DDR0_ODT[3])
M_A_PAR: J7.143(PARITY) U43.CM49(DDR0_PAR)
M_ACT_N: J7.114(ACT_N) U43.CF33(DDR0_ACT_N_MA[15])
M_ALERT_N: J7.116(ALERT_N) U43.CK33(D\D\R\0\_\A\L\E\R\T\_\N\_\P\A\R)
M_B_ACT_N: J8.114(ACT_N) U43.CU41(DDR1_ACT_N_MA[15])
M_B_ALERT_N: J8.116(ALERT_N) U43.CT42(D\D\R\1\_\A\L\E\R\T\_\N\_\P\A\R)
M_B_BA0: J8.150(BA0) U43.CR61(DDR1_BA[0])
M_B_BA1: J8.145(BA1) U43.CT60(DDR1_BA[1])
M_B_BG0: J8.115(BG0) U43.CR41(DDR1_BG0_BA[2])
M_B_BG1: J8.113(BG1) U43.CV42(DDR1_BG1_MA[14])
M_B_CKE0: J8.109(CKE0) U43.CT40(DDR1_CKE[0])
M_B_CKE1: J8.110(CKE1/NC) U43.CV38(DDR1_CKE[1])
M_B_CKE2: U43.CV40(DDR1_CKE[2])
M_B_CKE3: U43.CT38(DDR1_CKE[3])
M_B_CLK_DN0: J8.139(CK0_C) U43.CT58(DDR1_CLK_DN[0])
M_B_CLK_DN1: U43.CR54(DDR1_CLK_DN[1])
M_B_CLK_DN2: J8.140(CK1_C) U43.CR57(DDR1_CLK_DN[2])
M_B_CLK_DN3: U43.CT53(DDR1_CLK_DN[3])
M_B_CLK_DP0: J8.137(CK0_T) U43.CV58(DDR1_CLK_DP[0])
M_B_CLK_DP1: U43.CU54(DDR1_CLK_DP[1])
M_B_CLK_DP2: J8.138(CK1_T) U43.CU57(DDR1_CLK_DP[2])
M_B_CLK_DP3: U43.CV53(DDR1_CLK_DP[3])
M_B_CS_N0: J8.149(CS0_N) U43.CR63(D\D\R\1\_\C\S\_\N\[\0\]\)
M_B_CS_N1: J8.157(CS1_N/NC) U43.CV66(D\D\R\1\_\C\S\_\N\[\1\]\)
M_B_CS_N2: J8.162(CS2_N/C0/NC)
M_B_CS_N3: J8.165(CS3_N/C1/NC)
M_B_CS_N4: U43.CR65(D\D\R\1\_\C\S\_\N\[\4\]\)
M_B_CS_N5: U43.CT68(D\D\R\1\_\C\S\_\N\[\5\]\)
M_B_DQ0: J8.8(DQ0) U43.CG1(DDR1_DQ[0])
M_B_DQ1: J8.7(DQ1) U43.CG3(DDR1_DQ[1])
M_B_DQ2: J8.20(DQ2) U43.CM3(DDR1_DQ[2])
M_B_DQ3: J8.21(DQ3) U43.CN4(DDR1_DQ[3])
M_B_DQ4: J8.4(DQ4) U43.CF2(DDR1_DQ[4])
M_B_DQ5: J8.3(DQ5) U43.CF4(DDR1_DQ[5])
M_B_DQ6: J8.16(DQ6) U43.CL2(DDR1_DQ[6])
M_B_DQ7: J8.17(DQ7) U43.CK4(DDR1_DQ[7])
M_B_DQ8: J8.28(DQ8) U43.CU8(DDR1_DQ[8])
M_B_DQ9: J8.29(DQ9) U43.CR8(DDR1_DQ[9])
M_B_DQ10: J8.41(DQ10) U43.CU13(DDR1_DQ[10])
M_B_DQ11: J8.42(DQ11) U43.CR13(DDR1_DQ[11])
M_B_DQ12: J8.24(DQ12) U43.CU5(DDR1_DQ[12])
M_B_DQ13: J8.25(DQ13) U43.CT7(DDR1_DQ[13])
M_B_DQ14: J8.38(DQ14) U43.CV12(DDR1_DQ[14])
M_B_DQ15: J8.37(DQ15) U43.CT12(DDR1_DQ[15])
M_B_DQ16: J8.50(DQ16) U43.CV16(DDR1_DQ[16])
M_B_DQ17: J8.49(DQ17) U43.CT16(DDR1_DQ[17])
M_B_DQ18: J8.62(DQ18) U43.CV20(DDR1_DQ[18])
M_B_DQ19: J8.63(DQ19) U43.CT20(DDR1_DQ[19])
M_B_DQ20: J8.46(DQ20) U43.CU15(DDR1_DQ[20])
M_B_DQ21: J8.45(DQ21) U43.CR15(DDR1_DQ[21])
M_B_DQ22: J8.58(DQ22) U43.CU19(DDR1_DQ[22])
M_B_DQ23: J8.59(DQ23) U43.CR19(DDR1_DQ[23])
M_B_DQ24: J8.70(DQ24) U43.CU24(DDR1_DQ[24])
M_B_DQ25: J8.71(DQ25) U43.CR24(DDR1_DQ[25])
M_B_DQ26: J8.83(DQ26) U43.CU28(DDR1_DQ[26])
M_B_DQ27: J8.84(DQ27) U43.CR28(DDR1_DQ[27])
M_B_DQ28: J8.66(DQ28) U43.CV23(DDR1_DQ[28])
M_B_DQ29: J8.67(DQ29) U43.CT23(DDR1_DQ[29])
M_B_DQ30: J8.79(DQ30) U43.CV27(DDR1_DQ[30])
M_B_DQ31: J8.80(DQ31) U43.CT27(DDR1_DQ[31])
M_B_DQ32: J8.174(DQ32) U43.CT73(DDR1_DQ[32])
M_B_DQ33: J8.173(DQ33) U43.CU74(DDR1_DQ[33])
M_B_DQ34: J8.187(DQ34) U43.CJ78(DDR1_DQ[34])
M_B_DQ35: J8.186(DQ35) U43.CJ76(DDR1_DQ[35])
M_B_DQ36: J8.170(DQ36) U43.CU71(DDR1_DQ[36])
M_B_DQ37: J8.169(DQ37) U43.CR71(DDR1_DQ[37])
M_B_DQ38: J8.183(DQ38) U43.CL77(DDR1_DQ[38])
M_B_DQ39: J8.182(DQ39) U43.CK75(DDR1_DQ[39])
M_B_DQ40: J8.195(DQ40) U43.CF77(DDR1_DQ[40])
M_B_DQ41: J8.194(DQ41) U43.CF75(DDR1_DQ[41])
M_B_DQ42: J8.207(DQ42) U43.CB77(DDR1_DQ[42])
M_B_DQ43: J8.208(DQ43) U43.CB75(DDR1_DQ[43])
M_B_DQ44: J8.191(DQ44) U43.CG78(DDR1_DQ[44])
M_B_DQ45: J8.190(DQ45) U43.CG76(DDR1_DQ[45])
M_B_DQ46: J8.203(DQ46) U43.CC78(DDR1_DQ[46])
M_B_DQ47: J8.204(DQ47) U43.CC76(DDR1_DQ[47])
M_B_DQ48: J8.216(DQ48) U43.BW78(DDR1_DQ[48])
M_B_DQ49: J8.215(DQ49) U43.BW76(DDR1_DQ[49])
M_B_DQ50: J8.228(DQ50) U43.BP78(DDR1_DQ[50])
M_B_DQ51: J8.229(DQ51) U43.BP76(DDR1_DQ[51])
M_B_DQ52: J8.211(DQ52) U43.BY77(DDR1_DQ[52])
M_B_DQ53: J8.212(DQ53) U43.BY75(DDR1_DQ[53])
M_B_DQ54: J8.224(DQ54) U43.BR77(DDR1_DQ[54])
M_B_DQ55: J8.225(DQ55) U43.BR75(DDR1_DQ[55])
M_B_DQ56: J8.237(DQ56) U43.BL77(DDR1_DQ[56])
M_B_DQ57: J8.236(DQ57) U43.BL75(DDR1_DQ[57])
M_B_DQ58: J8.249(DQ58) U43.BG77(DDR1_DQ[58])
M_B_DQ59: J8.250(DQ59) U43.BG75(DDR1_DQ[59])
M_B_DQ60: J8.232(DQ60) U43.BM78(DDR1_DQ[60])
M_B_DQ61: J8.233(DQ61) U43.BM76(DDR1_DQ[61])
M_B_DQ62: J8.245(DQ62) U43.BH78(DDR1_DQ[62])
M_B_DQ63: J8.246(DQ63) U43.BH76(DDR1_DQ[63])
M_B_DQS_DN0: J8.11(DQS0_C) U43.CJ1(DDR1_DQS_DN[0])
M_B_DQS_DN1: J8.32(DQS1_C) U43.CU10(DDR1_DQS_DN[1])
M_B_DQS_DN2: J8.53(DQS2_C) U43.CV18(DDR1_DQS_DN[2])
M_B_DQS_DN3: J8.74(DQS3_C) U43.CU26(DDR1_DQS_DN[3])
M_B_DQS_DN4: J8.177(DQS4_C) U43.CM76(DDR1_DQS_DN[4])
M_B_DQS_DN5: J8.198(DQS5_C) U43.CD77(DDR1_DQS_DN[5])
M_B_DQS_DN6: J8.219(DQS6_C) U43.BT78(DDR1_DQS_DN[6])
M_B_DQS_DN7: J8.240(DQS7_C) U43.BJ77(DDR1_DQS_DN[7])
M_B_DQS_DN8: J8.95(DQS8_C) U43.CV34(DDR1_DQS_DN[8])
M_B_DQS_DN9: U43.CH4(DDR1_DQS_DN[9])
M_B_DQS_DN10: U43.CT9(DDR1_DQS_DN[10])
M_B_DQS_DN11: U43.CR17(DDR1_DQS_DN[11])
M_B_DQS_DN12: U43.CT25(DDR1_DQS_DN[12])
M_B_DQS_DN13: U43.CR74(DDR1_DQS_DN[13])
M_B_DQS_DN14: U43.CE76(DDR1_DQS_DN[14])
M_B_DQS_DN15: U43.BU75(DDR1_DQS_DN[15])
M_B_DQS_DN16: U43.BK76(DDR1_DQS_DN[16])
M_B_DQS_DN17: U43.CR32(DDR1_DQS_DN[17])
M_B_DQS_DP0: J8.13(DQS0_T) U43.CJ3(DDR1_DQS_DP[0])
M_B_DQS_DP1: J8.34(DQS1_T) U43.CR10(DDR1_DQS_DP[1])
M_B_DQS_DP2: J8.55(DQS2_T) U43.CT18(DDR1_DQS_DP[2])
M_B_DQS_DP3: J8.76(DQS3_T) U43.CR26(DDR1_DQS_DP[3])
M_B_DQS_DP4: J8.179(DQS4_T) U43.CN75(DDR1_DQS_DP[4])
M_B_DQS_DP5: J8.200(DQS5_T) U43.CD75(DDR1_DQS_DP[5])
M_B_DQS_DP6: J8.221(DQS6_T) U43.BT76(DDR1_DQS_DP[6])
M_B_DQS_DP7: J8.242(DQS7_T) U43.BJ75(DDR1_DQS_DP[7])
M_B_DQS_DP8: J8.97(DQS8_T) U43.CT34(DDR1_DQS_DP[8])
M_B_DQS_DP9: U43.CH2(DDR1_DQS_DP[9])
M_B_DQS_DP10: U43.CV9(DDR1_DQS_DP[10])
M_B_DQS_DP11: U43.CU17(DDR1_DQS_DP[11])
M_B_DQS_DP12: U43.CV25(DDR1_DQS_DP[12])
M_B_DQS_DP13: U43.CR76(DDR1_DQS_DP[13])
M_B_DQS_DP14: U43.CE78(DDR1_DQS_DP[14])
M_B_DQS_DP15: U43.BU77(DDR1_DQS_DP[15])
M_B_DQS_DP16: U43.BK78(DDR1_DQS_DP[16])
M_B_DQS_DP17: U43.CU32(DDR1_DQS_DP[17])
M_B_ECC0: J8.92(CB0/NC) U43.CV31(DDR1_ECC[0])
M_B_ECC1: J8.91(CB1/NC) U43.CT31(DDR1_ECC[1])
M_B_ECC2: J8.101(CB2/NC) U43.CV36(DDR1_ECC[2])
M_B_ECC3: J8.105(CB3/NC) U43.CT36(DDR1_ECC[3])
M_B_ECC4: J8.88(CB4/NC) U43.CU30(DDR1_ECC[4])
M_B_ECC5: J8.87(CB5/NC) U43.CR30(DDR1_ECC[5])
M_B_ECC6: J8.100(CB6/NC) U43.CU35(DDR1_ECC[6])
M_B_ECC7: J8.104(CB7/NC) U43.CR35(DDR1_ECC[7])
M_B_MA0: J8.144(A0) U43.CV60(DDR1_MA[0])
M_B_MA1: J8.133(A1) U43.CU50(DDR1_MA[1])
M_B_MA2: J8.132(A2) U43.CR50(DDR1_MA[2])
M_B_MA3: J8.131(A3) U43.CT49(DDR1_MA[3])
M_B_MA4: J8.128(A4) U43.CV49(DDR1_MA[4])
M_B_MA5: J8.126(A5) U43.CR48(DDR1_MA[5])
M_B_MA6: J8.127(A6) U43.CT47(DDR1_MA[6])
M_B_MA7: J8.122(A7) U43.CR46(DDR1_MA[7])
M_B_MA8: J8.125(A8) U43.CV47(DDR1_MA[8])
M_B_MA9: J8.121(A9) U43.CT44(DDR1_MA[9])
M_B_MA10: J8.146(A10/AP) U43.CU61(DDR1_MA[10])
M_B_MA11: J8.120(A11) U43.CU46(DDR1_MA[11])
M_B_MA12: J8.119(A12/BC) U43.CV44(DDR1_MA[12])
M_B_MA13: J8.158(A13) U43.CT66(DDR1_MA[13])
M_B_MA14: J8.151(WE_N/A14) U43.CV62(D\D\R\1\_\M\A\1\4\_\W\E\_\N\)
M_B_MA15: J8.156(CAS_N/A15) U43.CT64(D\D\R\1\_\M\A\1\5\_\C\A\S\_\N\)
M_B_MA16: J8.152(RAS_N/A16) U43.CT62(D\D\R\1\_\M\A\1\6\_\R\A\S\_\N\)
M_B_ODT0: J8.155(ODT0) U43.CV64(DDR1_ODT[0])
M_B_ODT1: J8.161(ODT1/NC) U43.CR69(DDR1_ODT[1])
M_B_ODT2: U43.CR67(DDR1_ODT[2])
M_B_ODT3: U43.CV68(DDR1_ODT[3])
M_B_PAR: J8.143(PARITY) U43.CR59(DDR1_PAR)
M_CPU0_EVENT_N: J7.134(EVENT_N) J8.134(EVENT_N) R137.2 R138.1
M_CS_N2: J7.162(CS2_N/C0/NC)
M_CS_N3: J7.165(CS3_N/C1/NC)
M_RESET: J7.108(RESET_N) J8.108(RESET_N) U43.CR43(D\D\R\_\R\E\S\E\T_\N\)
MAC1MDC: R525.1 U20.D8(GPIOR6_MDC1)
MAC1MDIO: R524.1 U20.E10(GPIOR7_MDIO1)
MEMA_0: R397.2 R398.1 U20.V13(MA0) U21.P3(A0)
MEMA_1: R399.2 R400.1 U20.AB14(MA1) U21.P7(A1)
MEMA_2: R401.2 R402.1 U20.W14(MA2) U21.R3(A2)
MEMA_3: R404.2 R405.1 U20.U14(MA3) U21.N7(A3)
MEMA_4: R407.2 R408.1 U20.W15(MA4) U21.N3(A4)
MEMA_5: R409.2 R410.1 U20.V15(MA5) U21.P8(A5)
MEMA_6: R411.2 R412.1 U20.AB16(MA6) U21.P2(A6)
MEMA_7: R413.2 R414.1 U20.AA16(MA7) U21.R8(A7)
MEMA_8: R415.2 R416.1 U20.W16(MA8) U21.R2(A8)
MEMA_9: R417.2 R418.1 U20.Y16(MA9) U21.R7(A9)
MEMA_10: R419.2 R420.1 U20.U13(MA10) U21.M3(A10/AP)
MEMA_11: R421.2 R422.1 U20.AA14(MA11) U21.T2(A11)
MEMA_12: R423.2 R424.1 U20.Y14(MA12) U21.M7(A12/B\C\)
MEMA_13: R425.2 R426.1 U20.AB15(MA13) U21.T8(A13)
MEMACT_N: R427.2 R428.1 U20.Y15(M\A\1\4\_\M\A\C\T\#\) U21.L3(A\C\T\)
MEMALERT_N: R378.1 U20.U16(M\A\L\E\R\T\#\) U21.P9(A\L\E\R\T\)
MEMBA_0: R391.2 R392.1 U20.U12(MBA0) U21.N2(BA0)
MEMBA_1: R393.2 R394.1 U20.Y13(MBA1) U21.N8(BA1)
MEMBG_0: R395.2 R396.1 U20.W13(MBA2_MBG0) U21.M2(BG0)
MEMCASN: R383.2 R384.1 U20.AB13(M\C\A\S\#\) U21.M8(A15/\C\A\S\)
MEMCK: R430.1 U20.AB11(MCK) U21.K7(CK_T)
MEMCKE: R387.2 R388.1 U20.Y11(MCKE) U21.K2(CKE)
MEMCKN: R433.1 U20.AB12(M\C\K\#\) U21.K8(CK_C)
MEMCSN: R379.2 R380.1 U20.AA12(M\C\S\#\) U21.L7(\\C\S\)
MEMDM_0: U20.U8(MDM0) U21.E7(NF/L\D\M\/L\D\B\I\)
MEMDM_1: U20.AB8(MDM1) U21.E2(NF/U\D\M\/U\D\B\I\)
MEMDQ_0: U20.U10(MDQ0) U21.G2(DQ0)
MEMDQ_1: U20.W10(MDQ1) U21.F7(DQ1)
MEMDQ_2: U20.Y10(MDQ2) U21.H3(DQ2)
MEMDQ_3: U20.AA10(MDQ3) U21.H7(DQ3)
MEMDQ_4: U20.U9(MDQ4) U21.H2(DQ4)
MEMDQ_5: U20.Y9(MDQ5) U21.H8(DQ5)
MEMDQ_6: U20.W9(MDQ6) U21.J3(DQ6)
MEMDQ_7: U20.V9(MDQ7) U21.J7(DQ7)
MEMDQ_8: U20.AA8(MDQ8) U21.A3(DQ8)
MEMDQ_9: U20.Y8(MDQ9) U21.B8(DQ9)
MEMDQ_10: U20.Y7(MDQ10) U21.C3(DQ10)
MEMDQ_11: U20.W8(MDQ11) U21.C7(DQ11)
MEMDQ_12: U20.AA6(MDQ12) U21.C2(DQ12)
MEMDQ_13: U20.W7(MDQ13) U21.C8(DQ13)
MEMDQ_14: U20.V7(MDQ14) U21.D3(DQ14)
MEMDQ_15: U20.U7(MDQ15) U21.D7(DQ15)
MEMDQS_0_DN: U20.AB10(M\D\Q\S\0\#\) U21.F3(LDQS_C)
MEMDQS_0_DP: U20.AB9(MDQS0) U21.G3(LDQS_T)
MEMDQS_1_DN: U20.AB6(M\D\Q\S\1\#\) U21.A7(UDQS_C)
MEMDQS_1_DP: U20.AB7(MDQS1) U21.B7(UDQS_T)
MEMODT: R389.2 R390.1 U20.V11(MODT) U21.K3(ODT)
MEMRASN: R381.2 R382.1 U20.W12(M\R\A\S\#\) U21.L8(A16/R\A\S\)
MEMRESET_N: R375.1 U20.AB17(M\R\E\S\E\T\#\) U21.P1(R\E\S\E\T\)
MEMWEN: R385.2 R386.1 U20.Y12(M\W\E\#\) U21.L2(A14/W\E\)
MFG_MODE_SRTAP: R899.2 U43.BD22(MFG_MODE_STRAP)
MISO: R149.2 R150.2 R765.1 R774.1
MOSI: R145.2 R146.2 R769.2 R779.2
NC_SI_ARB_IN: R625.1 U26.43(NC_SI_ARB_IN)
NC_SI_ARB_OUT: R626.1 U26.44(NC_SI_ARB_OUT)
NCSI_ABR_OUT: R780.2 R785.2 U43.AB78(LAN_NCSI_ARB_OUT)
NCSI_CLK_IN: R794.2 U43.AA72(LAN_NCSI_CLK_IN)
NCSI_CRS_DV: R790.2 U43.V74(LAN_NCSI_CRS_DV)
NCSI_NIC_ACT: R194.2 U26.30(LED1)
NCSI_NIC_LED_100M: R196.1 U26.31(LED0)
NCSI_NIC_LED_1000M: R199.1 U26.33(LED2)
NCSI_RXD0: R786.2 R1178.2 U43.Y71(LAN_NCSI_RXD0)
NCSI_RXD1: R787.2 R1177.2 U43.W72(LAN_NCSI_RXD1)
NCSI_TX_EN: R792.2 U43.AA75(LAN_NCSI_TX_EN)
NCSI_TXD0: R793.2 U43.W77(LAN_NCSI_TXD0)
NCSI_TXD1: R1165.2 U43.Y78(LAN_NCSI_TXD1)
NIC0_RMII_RXCLK: R594.2 R596.1 R599.1 U26.2(NC_SI_CLK_IN)
NIC0_RMII_RXCLK_50M: R56.2 R596.2
NIC_FLASH_CE_N: R616.2 U27.1(S\)
NIC_FLASH_SCK: R619.2 U27.6(C)
NIC_FLASH_SI: R610.1 R611.1 R620.2 U27.5(D)
NIC_FLASH_SO: R609.2 R618.2 U27.2(Q)
NIC_PLAYDEAD: R627.1 U2.C8(IO_39) U26.28(D\E\V\_\O\F\F\_\N\)
NIC_WAKEN: R600.1 U2.C4(IO_35) U26.16(P\E\_\W\A\K\E\_\N\)
ONLINE_CPLD_JTAG_EN: R1163.2 R1164.2 R1175.2
ONLINE_TCK: R1167.2 U4.B4
ONLINE_TDI: R1170.2 U4.D4
ONLINE_TDO: R1168.2 U4.B10
ONLINE_TMS: R1169.2 U4.B13
OSC_50M: C17.1 R57.2 U1.1(CLK_IN) X36.1
P0_PU: R796.2 U43.R72(LAN_I2C_SCL0) U43.U72(LAN_I2C_SDA0)
P1_PU: R797.2 U43.P71(LAN_I2C_SCL1) U43.T71(LAN_I2C_SDA1)
PAR: R372.2 R373.1 U21.T3(PAR)
PCH_WAKE_N: R83.2 R871.2 U43.BA1(W\A\K\E\_\N\)
PCHHOT_CPU_N: R1043.1 U43.AL76(P\C\H\H\O\T\_\C\P\U\_\N\)
PCHHOT_CPU_N_CPLD: U2.N15(IO_111) U47.5(1A2)
PCHHOT_CPU_N_GTL: R1034.1 R1043.2 U47.12(1B2)
PCIE_RX_N0: U4.C3 U43.D15(PCIE_RX_DN[1])
PCIE_RX_N1: U4.A6 U43.C14(PCIE_RX_DN[2])
PCIE_RX_N2: U4.C6 U43.D13(PCIE_RX_DN[3])
PCIE_RX_N3: U4.A9 U43.C12(PCIE_RX_DN[4])
PCIE_RX_P0: U4.C2 U43.B15(PCIE_RX_DP[1])
PCIE_RX_P1: U4.A5 U43.A14(PCIE_RX_DP[2])
PCIE_RX_P2: U4.C5 U43.B13(PCIE_RX_DP[3])
PCIE_RX_P3: U4.A8 U43.A12(PCIE_RX_DP[4])
PCIE_TX_N0: C570.2 U4.B16
PCIE_TX_N1: C572.2 U4.D16
PCIE_TX_N2: C574.2 U4.B19
PCIE_TX_N3: C576.2 U4.D19
PCIE_TX_P0: C571.2 U4.B15
PCIE_TX_P1: C573.2 U4.D15
PCIE_TX_P2: C575.2 U4.B18
PCIE_TX_P3: C577.2 U4.D18
PD_SPARE_1: R952.1 U43.AJ67(RSVD12)
PD_SPARE_2: R951.1 U43.AG67(RSVD11)
PD_SPARE_3: R946.1 U43.AN78(RSVD10)
PD_SPARE_4: R950.1 U43.AC64(RSVD09)
PE1_RX_N0: U43.J24(PE1_RX_DN[0]) U60.A12
PE1_RX_N1: U43.K26(PE1_RX_DN[1]) U60.A15
PE1_RX_N2: U43.J28(PE1_RX_DN[2]) U60.A18
PE1_RX_N3: U43.K30(PE1_RX_DN[3]) U60.A21
PE1_RX_N4: U43.J32(PE1_RX_DN[4]) U60.A24
PE1_RX_N5: U43.K33(PE1_RX_DN[5]) U60.A27
PE1_RX_N6: U43.J35(PE1_RX_DN[6]) U60.A30
PE1_RX_N7: U43.K37(PE1_RX_DN[7]) U60.A33
PE1_RX_P0: U43.F24(PE1_RX_DP[0]) U60.A11
PE1_RX_P1: U43.H26(PE1_RX_DP[1]) U60.A14
PE1_RX_P2: U43.F28(PE1_RX_DP[2]) U60.A17
PE1_RX_P3: U43.H30(PE1_RX_DP[3]) U60.A20
PE1_RX_P4: U43.F32(PE1_RX_DP[4]) U60.A23
PE1_RX_P5: U43.H33(PE1_RX_DP[5]) U60.A26
PE1_RX_P6: U43.F35(PE1_RX_DP[6]) U60.A29
PE1_RX_P7: U43.H37(PE1_RX_DP[7]) U60.A32
PE1_TX_N0: C713.2 U60.D9
PE1_TX_N1: C715.2 U60.D13
PE1_TX_N2: C717.2 U60.D17
PE1_TX_N3: C719.2 U60.D21
PE1_TX_N4: C721.2 U60.D25
PE1_TX_N5: C723.2 U60.D29
PE1_TX_N6: C725.2 U60.D33
PE1_TX_N7: C727.2 U60.D37
PE1_TX_P0: C714.2 U60.D8
PE1_TX_P1: C716.2 U60.D12
PE1_TX_P2: C718.2 U60.D16
PE1_TX_P3: C720.2 U60.D20
PE1_TX_P4: C722.2 U60.D24
PE1_TX_P5: C724.2 U60.D28
PE1_TX_P6: C726.2 U60.D32
PE1_TX_P7: C728.2 U60.D36
PE2_RX_N0: C263.2 U43.K22(PE2_RX_DN[0])
PE2_RX_P0: C264.2 U43.H22(PE2_RX_DP[0])
PE2_TX_N0: C568.1 U26.23(PE_RN)
PE2_TX_P0: C569.1 U26.24(PE_RP)
PE_HP_SCL: R911.2 U43.AR67(PE_HP_SCL)
PE_HP_SDA: R912.2 U43.AN67(PE_HP_SDA)
PECI_BMC: R550.1 R552.1 R905.2
PECI_ID0: R921.2 U43.L72(PECI_ID0)
PECI_ID1: R795.2 R1179.2 U43.AD78(LAN_NCSI_TRI_EN_PECI_ID1)
PECI_PCH: C586.1 R828.2 R906.2
PERST_M.2_N: J3.50(PERST#/NC) R71.2
PG_P0V6_VTT: R203.2 U2.D2(IO_48) U5.9(PGOOD)
PIRQA_N: R177.1 R855.2 U43.BG20(P\I\R\Q\A\_\N\)
PIRQB_N: R856.2 U43.BF22(P\I\R\Q\B\_\N\)
PIRQC_N: R857.2 U43.AR11(P\I\R\Q\C\_\N\)
PIRQD_N: R858.2 U43.BH22(P\I\R\Q\D\_\N\)
PLLAV33: C323.1 C324.1 C325.1 L19.2 U20.T11(MPLLAV33) U20.W17(PLLAV33_1) U20.Y17(PLLAV33_2)
PM_SYNC: U43.BT9(PM_SYNC_PCH) U43.H77(PMSYNC_CPU)
PMB_ALERT: J5.8 R341.1 R659.2 R705.2 R742.2
PMB_ALERT_VCCGBE_P1V05_PCH: R705.1 U33.25(S\M\B\_\A\L\E\R\T\)
PMB_ALERT_VCCIN_VCCSCSUS: R659.1 U29.25(S\M\B\_\A\L\E\R\T\)
PMB_ALERT_VDDQ: R742.1 U36.25(S\M\B\_\A\L\E\R\T\)
PMB_CLK: J5.9 R343.1 R344.1 R658.2 R704.2 R741.2
PMB_CLK_VCCGBE_P1V05_PCH: R704.1 U33.24(SMB_CLK)
PMB_CLK_VCCIN_VCCSCSUS: R658.1 U29.24(SMB_CLK)
PMB_CLK_VDDQ: R741.1 U36.24(SMB_CLK)
PMB_DIO: J5.10 R340.1 R342.1 R660.2 R706.2 R743.2
PMB_DIO_VCCGBE_P1V05_PCH: R706.1 U33.26(SMB_DIO)
PMB_DIO_VCCIN_VCCSCSUS: R660.1 U29.26(SMB_DIO)
PMB_DIO_VDDQ: R743.1 U36.26(SMB_DIO)
PME_N: R877.2 U43.BE16(P\M\E\_\N\)
PROCPWRGD_PCH: R1070.2 R1078.2 U50.11(2B1)
PROCPWRGD_PCH_CPLD: U2.R9(IO_142) U50.6(2A1)
PROCPWRGD_PCH_GTL: R1070.1 U43.BU11(PROCPWRGD_PCH)
PUD_SAEN0: R73.1 R105.1 U2.N9(IO_191)
PUD_SAEN1: R78.1 R108.1 U2.N10(IO_192)
PWR_BTN_N: R3.2 R72.2 R544.1
PWR_BTN_PASS_N: R59.1 R545.1 R888.2 U43.AW3(P\W\R\B\T\N\_\N\)
PWRGD_CPU: R1046.2 R1051.2 U47.11(2B1)
PWRGD_CPU_CPLD: U2.P13(IO_119) U47.6(2A1)
PWRGD_CPU_GTL: R1046.1 U43.CR39(DDR_PWRGOOD) U43.V76(PWRGOOD_CPU)
PWRGD_PS_PWROK: R543.2
RESET_CPU_N: R1045.2 R1053.1 U48.12(1B2)
RESET_CPU_N_CPLD: U2.R13(IO_133) U48.5(1A2)
RESET_CPU_N_GTL: R1045.1 U43.L76(R\E\S\E\T\_\C\P\U\_\N\)
RGMII2TXCTL_R: R588.2 R589.1 U20.B1(RGMII2TXCTL_RMII2TXEN_GPIOT7)
RGMII2TXD0_R: R576.2 R577.1 U20.A2(RGMII2TXD0_RMII2TXD0_GPIOU0)
RGMII2TXD1_R: R574.2 R575.1 U20.B3(RGMII2TXD1_RMII2TXD1_GPIOU1)
RGMII2TXD2_R: R571.2 R572.1 U20.D5(RGMII2TXD2_GPIOU2)
RGMII2TXD3_R: R568.2 R569.1 U20.D4(RGMII2TXD3_GPIOU3)
RI_N: R873.2 U43.BF11(R\I\_\N\)
RMII1CRSDV: R598.1 R612.1 U20.C5(RGMII1RXD2_RMII1CRSDV_GPIOV0)
RMII1RCLKO_BMC: R593.1 R594.1 U20.B5(RGMII1TXCK_RMII1RCLKO_GPIOT0)
RMII1RXD0: R597.2 R614.1 U20.A3(RGMII1RXD0_RMII1RXD0_GPIOU6)
RMII1RXD1: R595.2 R613.1 U20.D6(RGMII1RXD1_RMII1RXD1_GPIOU7)
RMII1RXER: R526.2 U20.C4(RGMII1RXD3_RMII1RXER_GPIOV1)
RMII1TXD0: R523.2 U26.9(NC_SI_TXD0)
RMII1TXD0_R: R523.1 R586.2 R587.1 U20.F9(RGMII1TXD0_RMII1TXD0_GPIOT2)
RMII1TXD1: R522.2 U26.8(NC_SI_TXD1)
RMII1TXD1_R: R522.1 R584.2 R585.1 U20.A5(RGMII1TXD1_RMII1TXD1_GPIOT3)
RMII1TXEN: R521.2 U26.7(NC_SI_TX_EN)
RMII1TXEN_R: R521.1 R590.2 R591.1 U20.E9(RGMII1TXCTL_RMII1TXEN_GPIOT1)
RSMRST_CPU_N: R1042.2 R1052.2 U48.13(1B1)
RSMRST_CPU_N_CPLD: U2.R12(IO_132) U48.4(1A1)
RSMRST_CPU_N_GTL: R1042.1 U43.R77(R\S\M\R\S\T\_\C\P\U\_\N\)
RST_BTN_N: R9.2 R74.2 R546.1
RST_BTN_PASS_N: C613.1 R64.1 R547.1 R1028.2 U43.BL4(S\Y\S\_\R\E\S\E\T\_\N\)
RST_NIC0_N: R601.1 R602.2 U2.A9(IO_12) U26.17(P\E\_\R\S\T\_\N\)
RTCRST_N: JP1.2 R1209.2 U43.AP9(R\T\C\R\S\T\_\N\)
SAFE_MODE_BOOT: R907.2 R920.2 U43.AF69(SAFE_MODE_BOOT)
SALERT_VCCGBE_P1V05_PCH: R688.1 U33.22(S\A\L\E\R\T\)
SALERT_VCCIN_VCCSCSUS: R643.1 U29.22(S\A\L\E\R\T\)
SALERT_VDDQ: R724.1 U36.22(S\A\L\E\R\T\)
SALT2: R554.1 U20.D16(GPIOG5_SGPS2LD_SALT2)
SALT3: R555.1 U20.D15(GPIOG6_SGPS2I0_SALT3)
SALT4: R556.1 U20.E14(GPIOG7_SGPS2I1_SALT4)
SALT5: R505.2 U20.R18(GPIOS2_VPOB4_SALT5)
SALT6: R507.2 U20.P18(GPIOS3_VPOB5_SALT6)
SATA_RX_DN0: U43.CA33(SATA_RX_DN[0])
SATA_RX_DN1: C58.1 U43.BW33(SATA_RX_DN[1])
SATA_RX_DN2: C734.1 U43.BU33(SATA_RX_DN[2])
SATA_RX_DN3: C731.1 U43.BR33(SATA_RX_DN[3])
SATA_RX_DN4: C733.1 U43.BN33(SATA_RX_DN[4])
SATA_RX_DN5: U43.BL33(SATA_RX_DN[5])
SATA_RX_DP0: U43.BY32(SATA_RX_DP[0])
SATA_RX_DP1: C59.1 U43.BV32(SATA_RX_DP[1])
SATA_RX_DP2: C730.1 U43.BT32(SATA_RX_DP[2])
SATA_RX_DP3: C737.1 U43.BP32(SATA_RX_DP[3])
SATA_RX_DP4: C739.1 U43.BM32(SATA_RX_DP[4])
SATA_RX_DP5: U43.BJ32(SATA_RX_DP[5])
SATA_TX_DN0: U43.BV28(SATA_TX_DN[0])
SATA_TX_DN1: C61.1 U43.BT28(SATA_TX_DN[1])
SATA_TX_DN2: C736.1 U43.BP28(SATA_TX_DN[2])
SATA_TX_DN3: C732.1 U43.BM28(SATA_TX_DN[3])
SATA_TX_DN4: C741.1 U43.BJ28(SATA_TX_DN[4])
SATA_TX_DN5: U43.BG28(SATA_TX_DN[5])
SATA_TX_DP0: U43.BW26(SATA_TX_DP[0])
SATA_TX_DP1: C60.1 U43.BU26(SATA_TX_DP[1])
SATA_TX_DP2: C735.1 U43.BR26(SATA_TX_DP[2])
SATA_TX_DP3: C738.1 U43.BN26(SATA_TX_DP[3])
SATA_TX_DP4: C740.1 U43.BL26(SATA_TX_DP[4])
SATA_TX_DP5: U43.BH26(SATA_TX_DP[5])
SCLK_VCCGBE_P1V05_PCH: R702.2 U33.20(SCLK)
SCLK_VCCIN_VCCSCSUS: R657.2 U29.20(SCLK)
SCLK_VDDQ: R740.2 U36.20(SCLK)
SDIO_VCCGBE_P1V05_PCH: R687.1 U33.21(SDIO)
SDIO_VCCIN_VCCSCSUS: R642.1 U29.21(SDIO)
SDIO_VDDQ: R723.1 U36.21(SDIO)
SDP0: R603.2 U26.63(SDP0)
SDP1: R604.2 U26.62(SDP2)
SDP2: R605.2 U26.61(SDP1/PCIE_DIS)
SDP3: R606.2 U26.60(SDP3)
SERIRQ: R839.1 R1088.2
SERIRQ_BMC: R53.1 R1090.2
SERIRQ_CLK: R926.1 U43.Y11(CLKOUT_PCI[4])
SERIRQ_CLK_GTL: R926.2 R930.1 U43.AC67(SERIRQ_CLK)
SERIRQ_DATA: R849.2 R1086.1 U53.5(A3)
SERIRQ_DIR: R843.2 R902.2 U43.AD74(SERIRQ_DIR)
SLP_S3_CPU: R1048.2 U47.10(2B2)
SLP_S3_CPU_CPLD: U2.A4(IO_7) U47.7(2A2)
SLP_S3_CPU_GTL: R893.2 R897.1 R1048.1 U43.AC71(S\L\P\_\S\3\_\C\P\U\_\N\)
SMB_CPU_ALERT_N: R981.2 U43.BH7(SMBALERT_N_GPIO11)
SMB_CPU_SCL: R47.2 R61.2 R172.2 R457.2 R980.2 R1005.2 U43.BN11(SMBCLK)
SMB_CPU_SDA: R46.2 R81.2 R173.1 R459.2 R979.2 R1006.2 U43.BJ13(SMBDATA)
SMB_DDR_ABC_SCL: R1092.2 U43.CD58(DDR_SCL) U54.2(SCLA)
SMB_DDR_ABC_SDA: R1091.2 U43.CC60(DDR_SDA) U54.3(SDAA)
SMB_PWR_ALERT_N: R868.2 U2.P11(IO_117) U43.BC9(GPIO31_MGPIO2)
SMB_SENSOR_CLK: R331.2 R455.2 R473.1 U18.2(SCL)
SMB_SENSOR_DATA: R332.2 R456.2 R475.1 U18.1(SDA)
SMI_MDC: R1081.2 U4.D10 U53.18(B1)
SMI_MDIO: R1082.2 U4.D7 U53.17(B2)
SML1_CLK: R444.2 R882.2 U43.BG9(SML1CLK_GPIO58_MGPIO11)
SML1_DATA: R445.2 R880.2 U43.BB11(SML1DATA_GPIO75_MGPIO12)
SML1ALERT_N: R98.1 R437.2 R879.2 U43.BF7(SML1ALERT_N_PCHHOT_N_GPIO74)
SMLINK0_ALERT_N: R50.2 R883.2 U43.BL7(SML0ALERT_N_GPIO60_MGPIO4)
SMLINK0_CLK: R48.2 R885.2 R889.1 U43.BR7(SML0CLK)
SMLINK0_DATA: R49.2 R884.2 R887.1 U43.BN18(SML0DATA)
SPI_BMC_CK: U20.C15(GPIOI5_SPI1CK_VBCK) U61.7(1A3)
SPI_BMC_CS0_N: U20.B15(G\P\I\O\I\4\_\S\P\I\1\C\S\0\#\_) U61.8(1A4)
SPI_BMC_EN: R1131.2 U20.D14(GPIOA1_MAC2LINK)
SPI_BMC_MISO: U20.A15(GPIOI7_SPI1MISO_VBMISO) U61.4(1A2)
SPI_BMC_MOSI: U20.A14(GPIOI6_SPI1MOSI_VBMOSI) U61.3(1A1)
SPI_BMC_OE: R1132.1 U2.E2(IO_57)
SPI_CLK_0: R768.1 U39.16(SCK) U40.6(CLK)
SPI_CLK_1: R778.1 U41.16(SCK) U42.6(CLK)
SPI_CPU_OE: R1133.2 U2.E3(IO_58)
SPI_CS_CPLD: R1129.2 R1130.2 U2.P15(IO_121)
SPI_CS_N_0: R761.1 R763.2 U39.7(C\S\) U40.1(C\S\)
SPI_CS_N_1: R771.1 R773.2 U41.7(C\S\) U42.1(C\S\)
SPI_HOLD#: R484.2 U22.1(DNU/SIO3) U24.7(H\O\L\D\/\R\E\S\E\T\/\IO3)
SPI_HOLD#S: R519.1 U23.1(DNU/SIO3) U25.7(H\O\L\D\/\R\E\S\E\T\/\IO3)
SPI_HOLD_N_0: R762.1 R766.1 U39.1(I\O\3\/\H\O\L\D\) U40.7(H\O\L\D\/\R\E\S\E\T\/\IO3)
SPI_HOLD_N_1: R772.1 R776.1 U41.1(I\O\3\/\H\O\L\D\) U42.7(H\O\L\D\/\R\E\S\E\T\/\IO3)
SPI_IO2: R767.1 R777.1
SPI_IO3: R766.2 R776.2
SPI_MISO_0: R765.2 U39.8(SO/IO1) U40.2(DO/IO1)
SPI_MISO_1: R774.2 U41.8(SO/IO1) U42.2(DO/IO1)
SPI_MOSI_0: R769.1 U39.15(SI/IO0) U40.5(DI_IO0)
SPI_MOSI_1: R779.1 U41.15(SI/IO0) U42.5(DI_IO0)
SPI_RST#: R483.2 U22.3(R\E\S\E\T\#\) U23.3(R\E\S\E\T\#\)
SPI_SSB_BMC_CLK: R872.2 U20.E15(GPIOI1_SYSCK)
SPI_SSB_BMC_MISO: R878.2 U20.C16(GPIOI3_SYSMISO)
SPI_SSB_BMC_MOSI: R867.2 U20.B16(GPIOI2_SYSMOSI)
SPI_SSB_CLK: R872.1 R875.1 U43.BG13(SPI_CLK)
SPI_SSB_CS0_BMC_N: R860.2 U20.C18(G\P\I\O\I\0\_\S\Y\S\C\S\#\)
SPI_SSB_CS0_CPLD_N: R863.2 U61.21(2A4)
SPI_SSB_CS0_N: R860.1 R863.1 U43.BN7(S\P\I\_\C\S\0\_\N\)
SPI_SSB_F_CLK: R875.2 U61.18(2A3)
SPI_SSB_F_MISO: R881.2 U61.17(2A2)
SPI_SSB_F_MOSI: R869.2 U61.14(2A1)
SPI_SSB_MISO: R878.1 R881.1 U43.BJ20(SPI_MISO_IO1)
SPI_SSB_MOSI: R867.1 R869.1 U43.BL11(SPI_MOSI_IO0)
SPI_WP#: R485.2 U22.9(W\P\#\/SIO2) U24.3(W\P\/IO2)
SPI_WP#S: R520.1 U23.9(W\P\#\/SIO2) U25.3(W\P\/IO2)
SPI_WP_N_0: R760.1 R767.2 U39.9(A\C\C\/\I\O\2\/\W\) U40.3(W\P\/IO2)
SPI_WP_N_1: R770.1 R777.2 U41.9(A\C\C\/\I\O\2\/\W\) U42.3(W\P\/IO2)
SPKR: R866.2 R898.2 U2.G6(IO_164) U43.BP20(SPKR)
SPKR_CPLD: R12.1 U2.G11(IO_165)
SRTCRST_N: JP2.2 R313.2 U43.AP4(S\R\T\C\R\S\T\_\N\)
SSD_PWR_EN: R1212.1 U2.F3(IO_66)
SUSACK_N: R876.2 U43.AY4(S\U\S\A\C\K\_\N\)
SUSCLK_CPLD: R852.2 U2.N6(IO_188)
SUSCLK_M2: R165.2 R853.2
SVID_ALERT_N: R643.2 R663.2 R688.2 R724.2 R908.1 R918.2
SVID_CLK: R657.1 R662.1 R702.1 R740.1 R909.2 R919.2
SVID_DATA: R642.2 R664.1 R687.2 R723.2 R910.2 R916.2
SYS_UART_CTS1: R513.1
SYS_UART_DCD1: R514.1
SYS_UART_DSR1: R515.1
SYS_UART_DTR1: R517.1
SYS_UART_RI1: R516.1
SYS_UART_RTS1: R518.1
TAO_VCCGBE_P1V05_PCH: C429.2 R695.2 R714.2 R721.2 U33.14(TSEN)
TAO_VCCIN_VCCSCSUS: C338.2 R649.2 R669.2 R676.2 R684.2 U29.14(TSEN)
TAO_VDD_P2V5_VPP: C481.2 R732.2 R750.2 R759.2 U36.14(TSEN)
TCK: R111.1 R114.1 R1139.2 U2.P3(TCK)
TDI: R109.1 R117.1 R1140.2 U2.L6(TDI)
TDO: R115.1 R1142.2 U2.M5(TDO)
THERMTRIP_CPU_N: R1047.1 U43.AF72(T\H\E\R\M\T\R\I\P\_\N\)
THERMTRIP_CPU_N_CPLD: U2.J15(IO_81) U49.6(2A1)
THERMTRIP_CPU_N_GTL: R1047.2 R1137.1 U49.11(2B1)
THERMTRIP_PCH_N: R1040.1 U43.BJ16(T\H\E\R\M\T\R\I\P\_\P\C\H\_\N\)
THERMTRIP_PCH_N_CPLD: U2.N14(IO_110) U47.4(1A1)
THERMTRIP_PCH_N_GTL: R1033.1 R1040.2 U47.13(1B1)
TMS: R110.1 R116.1 R1141.2 U2.N4(TMS)
TO_BMC_INT#: R195.1 R468.1 U20.L18(GPIOB2)
TPS3823_MR_N: R113.1 U2.L11(IO_181)
TPS3823_RST_N: C757.1 R107.2 R1166.1 U2.J12(IO/GCLK2) U3.1(R\E\S\E\T\)
TXT_AGENT: R915.2 U43.AM72(TXT_AGENT)
TXT_PLTEN: R914.2 U43.AP72(TXT_PLTEN)
UART_RX0: R1036.1 R1041.2 U48.11(2B1)
UART_RX0_GTL: R1041.1 U43.AG77(UART_RXD[0])
UART_RX1_GTL: R1035.1 U43.AH78(UART_RXD[1])
UART_SIN0: R1207.2 U48.6(2A1)
UART_SOUT0: R1208.2 U50.4(1A1)
UART_TX0: R1064.2 R1077.2 U50.13(1B1)
UART_TX0_GTL: R1064.1 U43.AG75(UART_TXD[0])
UART_TX1_GTL: R1076.2 U43.AH76(UART_TXD[1])
USB2_DN0: R183.2 U43.AD3(USB2_DN[0])
USB2_DN1: U43.AK9(USB2_DN[1])
USB2_DN2: U43.AE4(USB2_DN[2])
USB2_DN3: R539.2 U43.AG7(USB2_DN[3])
USB2_DP0: R186.2 U43.AD1(USB2_DP[0])
USB2_DP1: U43.AH9(USB2_DP[1])
USB2_DP2: U43.AE2(USB2_DP[2])
USB2_DP3: R538.2 U43.AJ7(USB2_DP[3])
USB2A_DN: R539.1 U20.A8(USB2A_DN)
USB2A_DP: R538.1 U20.A7(USB2A_DP)
USB3_RX_DN1: U4.A12 U43.D19(USB3_RX_DN[1])
USB3_RX_DP1: U4.A11 U43.B19(USB3_RX_DP[1])
USB3_TX_DN1: C584.2 U4.D25
USB3_TX_DP1: C585.2 U4.D24
USB_OC0: R973.1 R982.2 U4.C29
USB_OC1: R983.2 U43.BE2(O\C\1\_\N\_\G\P\I\O\4\0\)
USB_OC2: R984.2 U43.BG4(O\C\2\_\N\_\G\P\I\O\4\1\)
USB_OC3: R986.2 U43.BG2(O\C\3\_\N\_\G\P\I\O\4\2\)
USB_OC4: R987.2 U43.BE4(O\C\4\_\N\_\G\P\I\O\4\3\)
USB_OC5: R988.2 U43.BF3(O\C\5\_\N\_\G\P\I\O\9\)
USB_OC6: R989.2 U43.BF1(O\C\6\_\N\_\G\P\I\O\1\0\)
USB_OC7: R990.2 U43.BD3(O\C\7\_\N\_\G\P\I\O\1\4\)
USBCLK: U20.J20(GPIOB4_USBCKI)
VPLLAV11: C320.1 C321.1 C322.1 L18.2 U20.L5(VPLLAV11_1) U20.L6(VPLLAV11_2)
VPLLAV33: C326.1 C327.1 C328.1 L20.2 U20.H7(VPLLAV33_2) U20.J7(VPLLAV33_1)
VR_FAULT: R656.2
VR_FAULT_17088173: R739.2
VR_FAULT_17093326: R703.2
VR_FAULT_VCCGBE_P1V05_PCH: R699.1 R703.1 U33.27(V\R\_\F\A\U\L\T\)
VR_FAULT_VCCIN_VCCSCSUS: R653.1 R656.1 U29.27(V\R\_\F\A\U\L\T\)
VR_FAULT_VDDQ: R736.1 R739.1 U36.27(V\R\_\F\A\U\L\T\)
VR_HOT_VCCGBE_P1V05_PCH: R86.2 R700.1 U33.18(V\R\_\H\O\T\)
VR_HOT_VCCIN_VCCSCSUS: R85.2 R654.1 U29.18(V\R\_\H\O\T\)
VR_HOT_VDDQ: R87.2 R737.1 U36.18(V\R\_\H\O\T\)
VR_PMCLK: R344.2 R460.2
VR_PMDATA: R340.2 R461.2
VREF_P_VCCGBE_P1V05_PCH: C453.1 C473.1 R685.2 U34.1(REFIN) U35.1(REFIN)
VREF_P_VCCIN_VCCSCSUS: C369.1 C397.1 C424.1 R641.2 U30.1(REFIN) U31.1(REFIN) U32.1(REFIN)
VREF_P_VDDQ_P2V5_VPP: C498.1 C513.1 R722.2 U37.1(REFIN) U38.1(REFIN)
VREF_VCCGBE_P1V05_PCH: C426.1 R685.1 R691.1 U33.1(VREF)
VREF_VCCIN_VCCSCSUS: C335.1 R641.1 R645.1 U29.1(VREF)
VREF_VDDQ_P2V5_VPP: C478.1 R722.1 R727.1 U36.1(VREF)
WAKELAN_N: R835.1 R845.2 U55.12(1B2)
WAKELAN_N_CPLD: U2.F10(IO_159) U55.5(1A2)
WDI: U65.6(WDI)
WDO: U65.8(WDO)
XDP_BPM_N2: U43.N78(B\P\M\_\N\[\2\]\)
XDP_BPM_N3: U43.M75(B\P\M\_\N\[\3\]\)
XDP_BPM_N4: U43.J78(B\P\M\_\N\[\4\]\)
XDP_BPM_N5: U43.H75(B\P\M\_\N\[\5\]\)
XDP_BPM_N6: U43.K75(B\P\M\_\N\[\6\]\)
XDP_BPM_N7: U43.J76(B\P\M\_\N\[\7\]\)
XDP_CLK_N: U43.H2(CLKOUT_ITPXDP_DN)
XDP_CLK_P: U43.H4(CLKOUT_ITPXDP_DP)
XDP_CPU_PRESENT_N: R1023.2 U43.M77(D\E\B\U\G\_\E\N\_\N\)
XDP_PRDY_N: R1181.2 U43.L78(P\R\D\Y\_\N\)
XDP_PREQ_N: R961.2 U43.K77(P\R\E\Q\_\N\)
XDP_TCK: R962.1 U43.T76(JTAG_TCK_CPU)
XDP_TDI: R1019.2 U43.V78(JTAG_TDI_CPU)
XDP_TDO: R1018.2 U43.T78(JTAG_TDO_CPU)
XDP_TMS: R1020.2 U43.R75(JTAG_TMS_CPU)
XDP_TRST_N: R1025.2 U43.U75(JTAG_TRST_N_CPU)
XTAL_IN: C589.1 OSC5.1 R939.1 U43.K2(XTAL25_IN)
XTAL_OUT: C590.1 OSC5.3 R939.2 U43.J1(XTAL25_OUT)
N02413: R429.2 U20.W11(MIOZ)
N04135: R458.2 U21.F9(ZQ)
N17191: C245.1 R430.2 R433.2
N23205: R465.1 U20.N20(G\P\I\O\Q\7\_\P\E\W\A\K\E\#\)
N47262: R631.2 U20.J1(ADCREXT)
N51572: C292.2 C293.1 U20.H2(ADCVREFP)
N51617: C293.2 C296.1 U20.H1(ADCVREFN)
N914107: R775.2 U41.3(DNC_1)
N914711: R764.2 U39.3(DNC_1)
N1689961: C571.1 U43.F9(PCIE_TX_DP[1])
N1689981: C570.1 U43.J9(PCIE_TX_DN[1])
N1690001: C573.1 U43.H7(PCIE_TX_DP[2])
N1690029: C572.1 U43.K7(PCIE_TX_DN[2])
N1690065: C575.1 U43.G5(PCIE_TX_DP[3])
N1690077: C574.1 U43.J5(PCIE_TX_DN[3])
N1690117: C577.1 U43.E4(PCIE_TX_DP[4])
N1690121: C576.1 U43.C3(PCIE_TX_DN[4])
N1702143: C568.2 U43.D21(PE2_TX_DN[0])
N1702147: C569.2 U43.B21(PE2_TX_DP[0])
N1709608: C579.2 U43.R62(LAN_KR_RX0_P)
N1709612: C578.2 U43.N62(LAN_KR_RX0_N)
N1709672: C580.2 U43.T64(LAN_KR_RX1_N)
N1709676: C581.2 U43.P64(LAN_KR_RX1_P)
N1709920: R784.2 U43.AA77(LAN_NCSI_ARB_IN)
N1710412: R782.1 U43.P56(LAN_RBIAS)
N1710726: R805.1 U44.7(H\O\L\D\)
N1710802: R806.2 U44.3(W\)
N1710854: R802.2 R803.2 U44.1(S\)
N1710898: R804.2 U44.2(Q)
N1710922: R808.1 U44.5(D)
N1710926: R807.1 U44.6(C)
N1713278: R809.1 U43.BB32(SATA_RCOMP)
N1713310: R810.1 U43.AG11(USB2_RBIAS) U43.AJ11(U\S\B\2\_\R\B\I\A\S\_\N\)
N1713626: C585.1 U43.H18(USB3_TX_DP[1])
N1713630: C584.1 U43.K18(USB3_TX_DN[1])
N1725618: R846.1 U43.AA18(DIFFCLK_BIASREF)
N1730669: R916.1 U43.AJ71(SVIDDATA)
N1730709: R919.1 U43.AH72(SVIDCLK)
N1730713: R918.1 U43.AK72(S\V\I\D\A\L\E\R\T\_\N\)
N1730757: R905.1 R906.1 U43.AL78(PECI_CPU)
N1731005: R923.1 U43.Y30(CLKIN_GND1_DN)
N1731009: R924.1 U43.AA30(CLKIN_GND1_DP)
N1731029: R927.1 U43.N35(CLKIN_GND2_DN)
N1731049: R928.1 U43.P33(CLKIN_GND2_DP)
N1731085: R929.1 U43.AB1(CLKIN_GND3_DN)
N1731089: R925.1 U43.AB3(CLKIN_GND3_DP)
N1731109: R931.1 U43.BG32(CLKIN_GND4_DN)
N1731145: R932.1 U43.BH33(CLKIN_GND4_DP)
N1731149: R933.1 U43.W9(REFCLK14IN)
N1731399: R938.1 U43.AA9(CLKOUT_PCI[0])
N1731483: R941.2 U45.2(OE)
N1731523: C592.1 C593.2 L31.1 U45.6(VDD)
N1731571: R940.1 U45.3(1Y0)
N1731591: R942.1 U45.5(1Y1)
N1731697: R943.1 U45.7(1Y2)
N1731791: R944.1 U45.8(1Y3)
N1735750: R945.2 U43.BL14(RSVD00)
N1735754: R954.1 U43.AA66(RSVD84)
N1735798: R949.1 U43.A73(RSVD93)
N1735802: R948.1 U43.A74(RSVD94)
N1735846: R955.1 U43.J54(RSVD17)
N1735866: R947.1 U43.F54(RSVD16)
N1735902: R956.1 U43.E55(RSVD18)
N1735930: R958.2 U43.BA27(NCTF/TP12)
N1735934: R960.1 U43.P11(TD_IREF)
N1736004: R953.1 U43.D71(RSVD13)
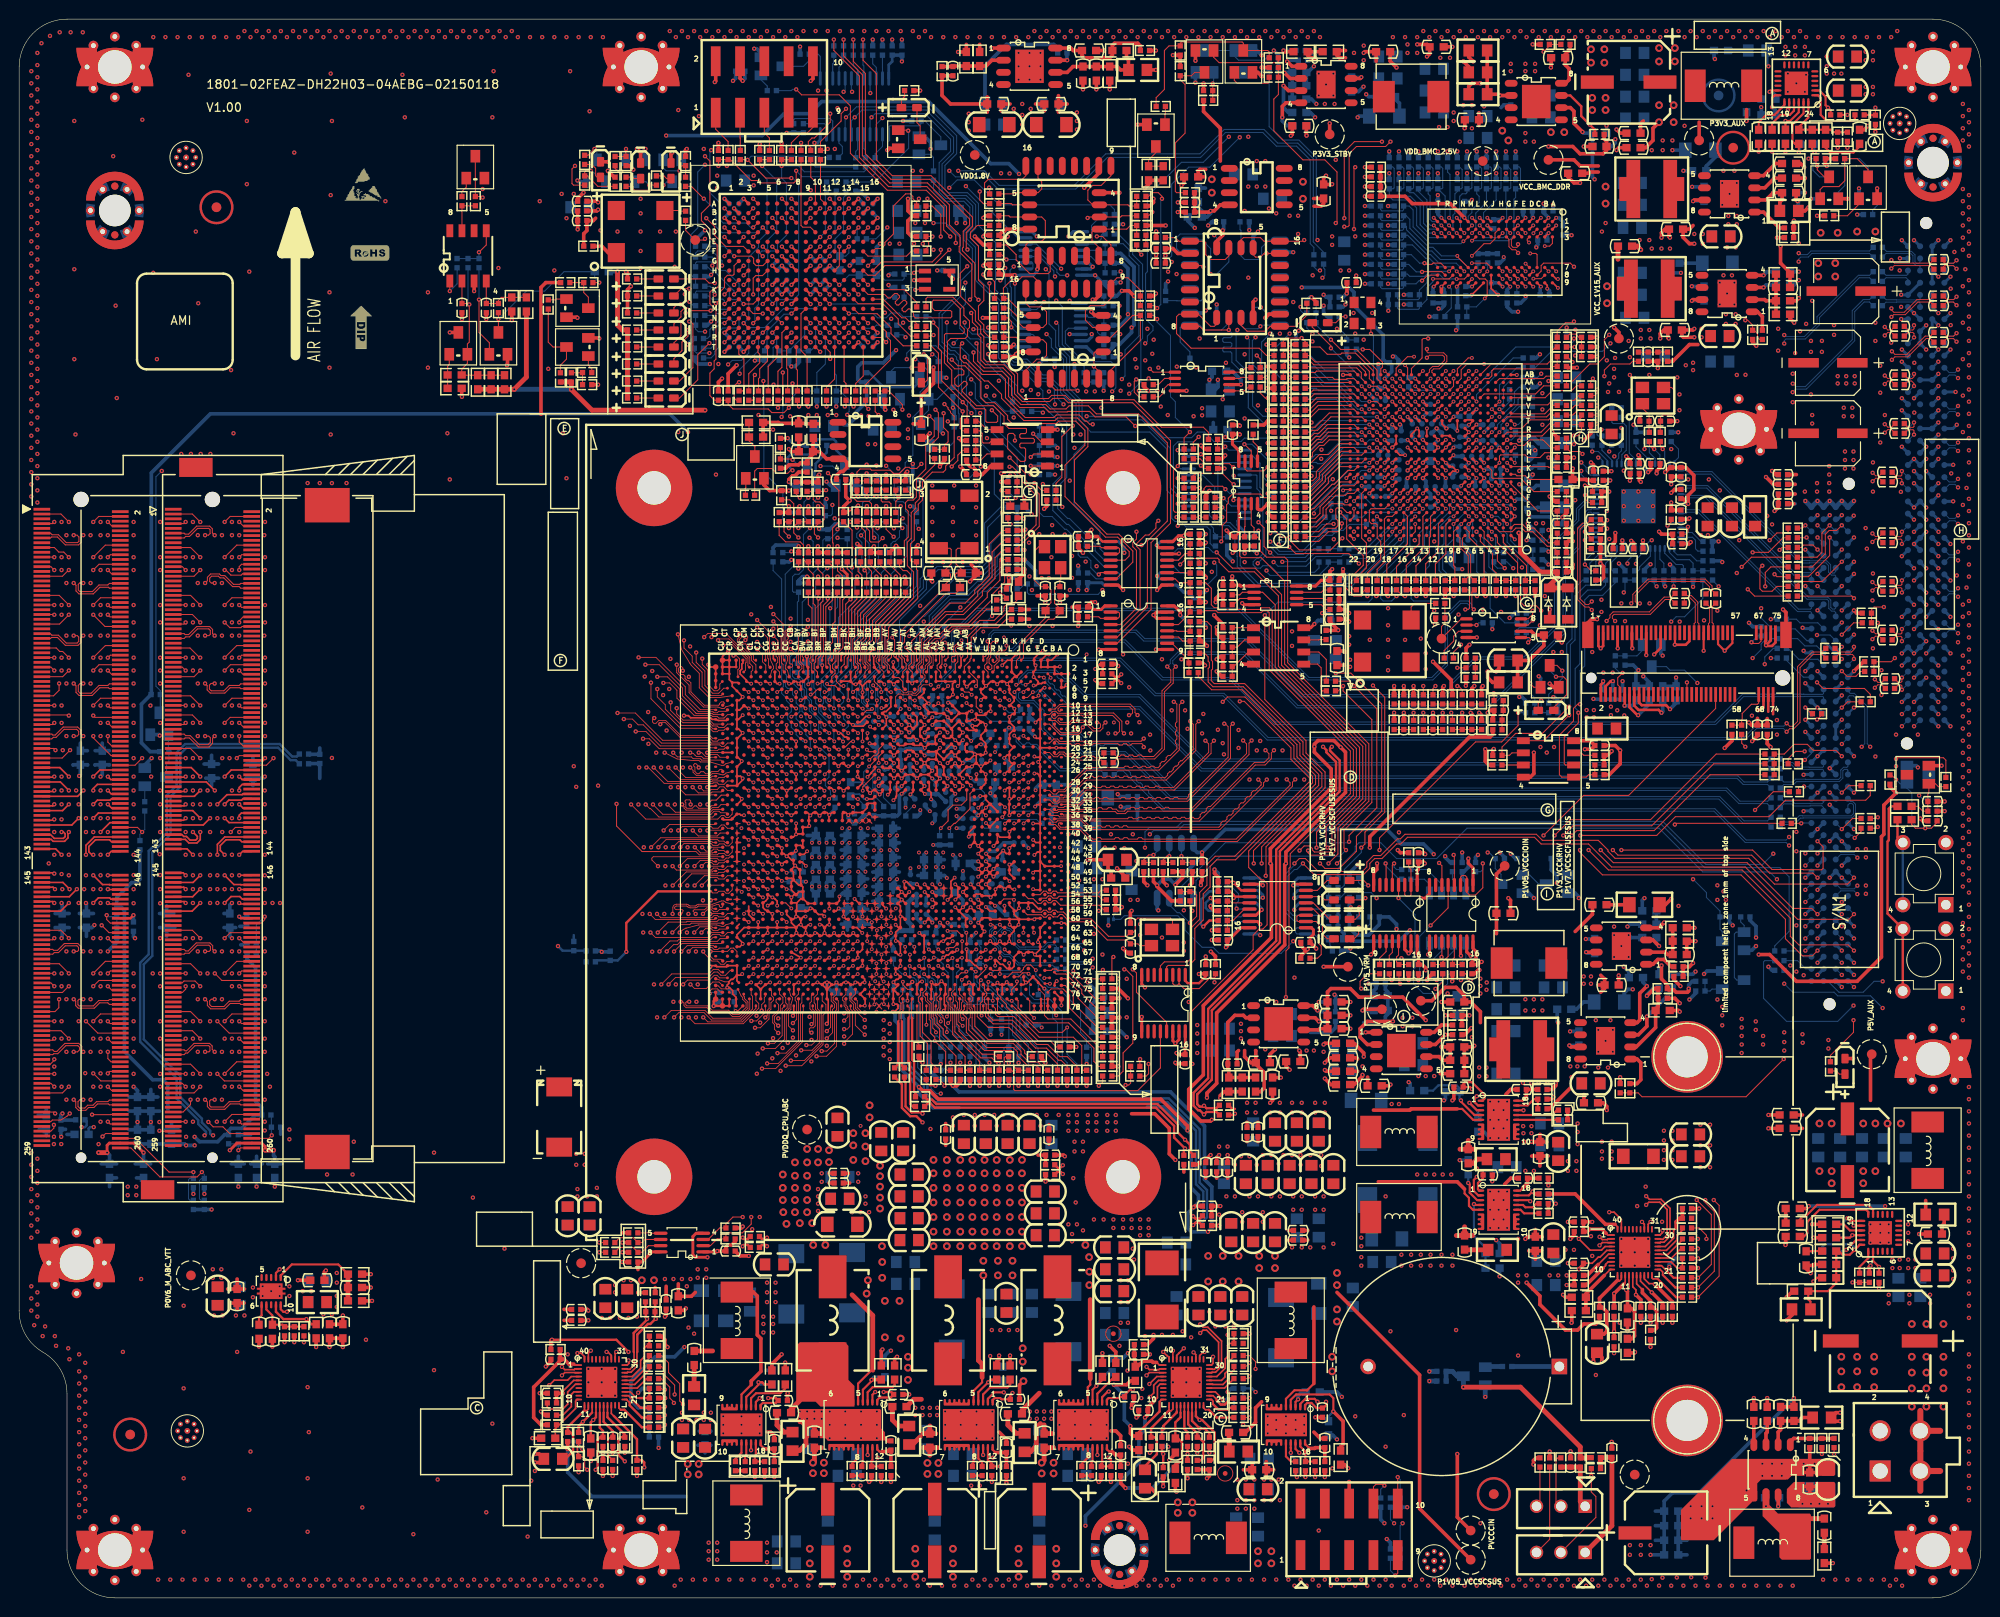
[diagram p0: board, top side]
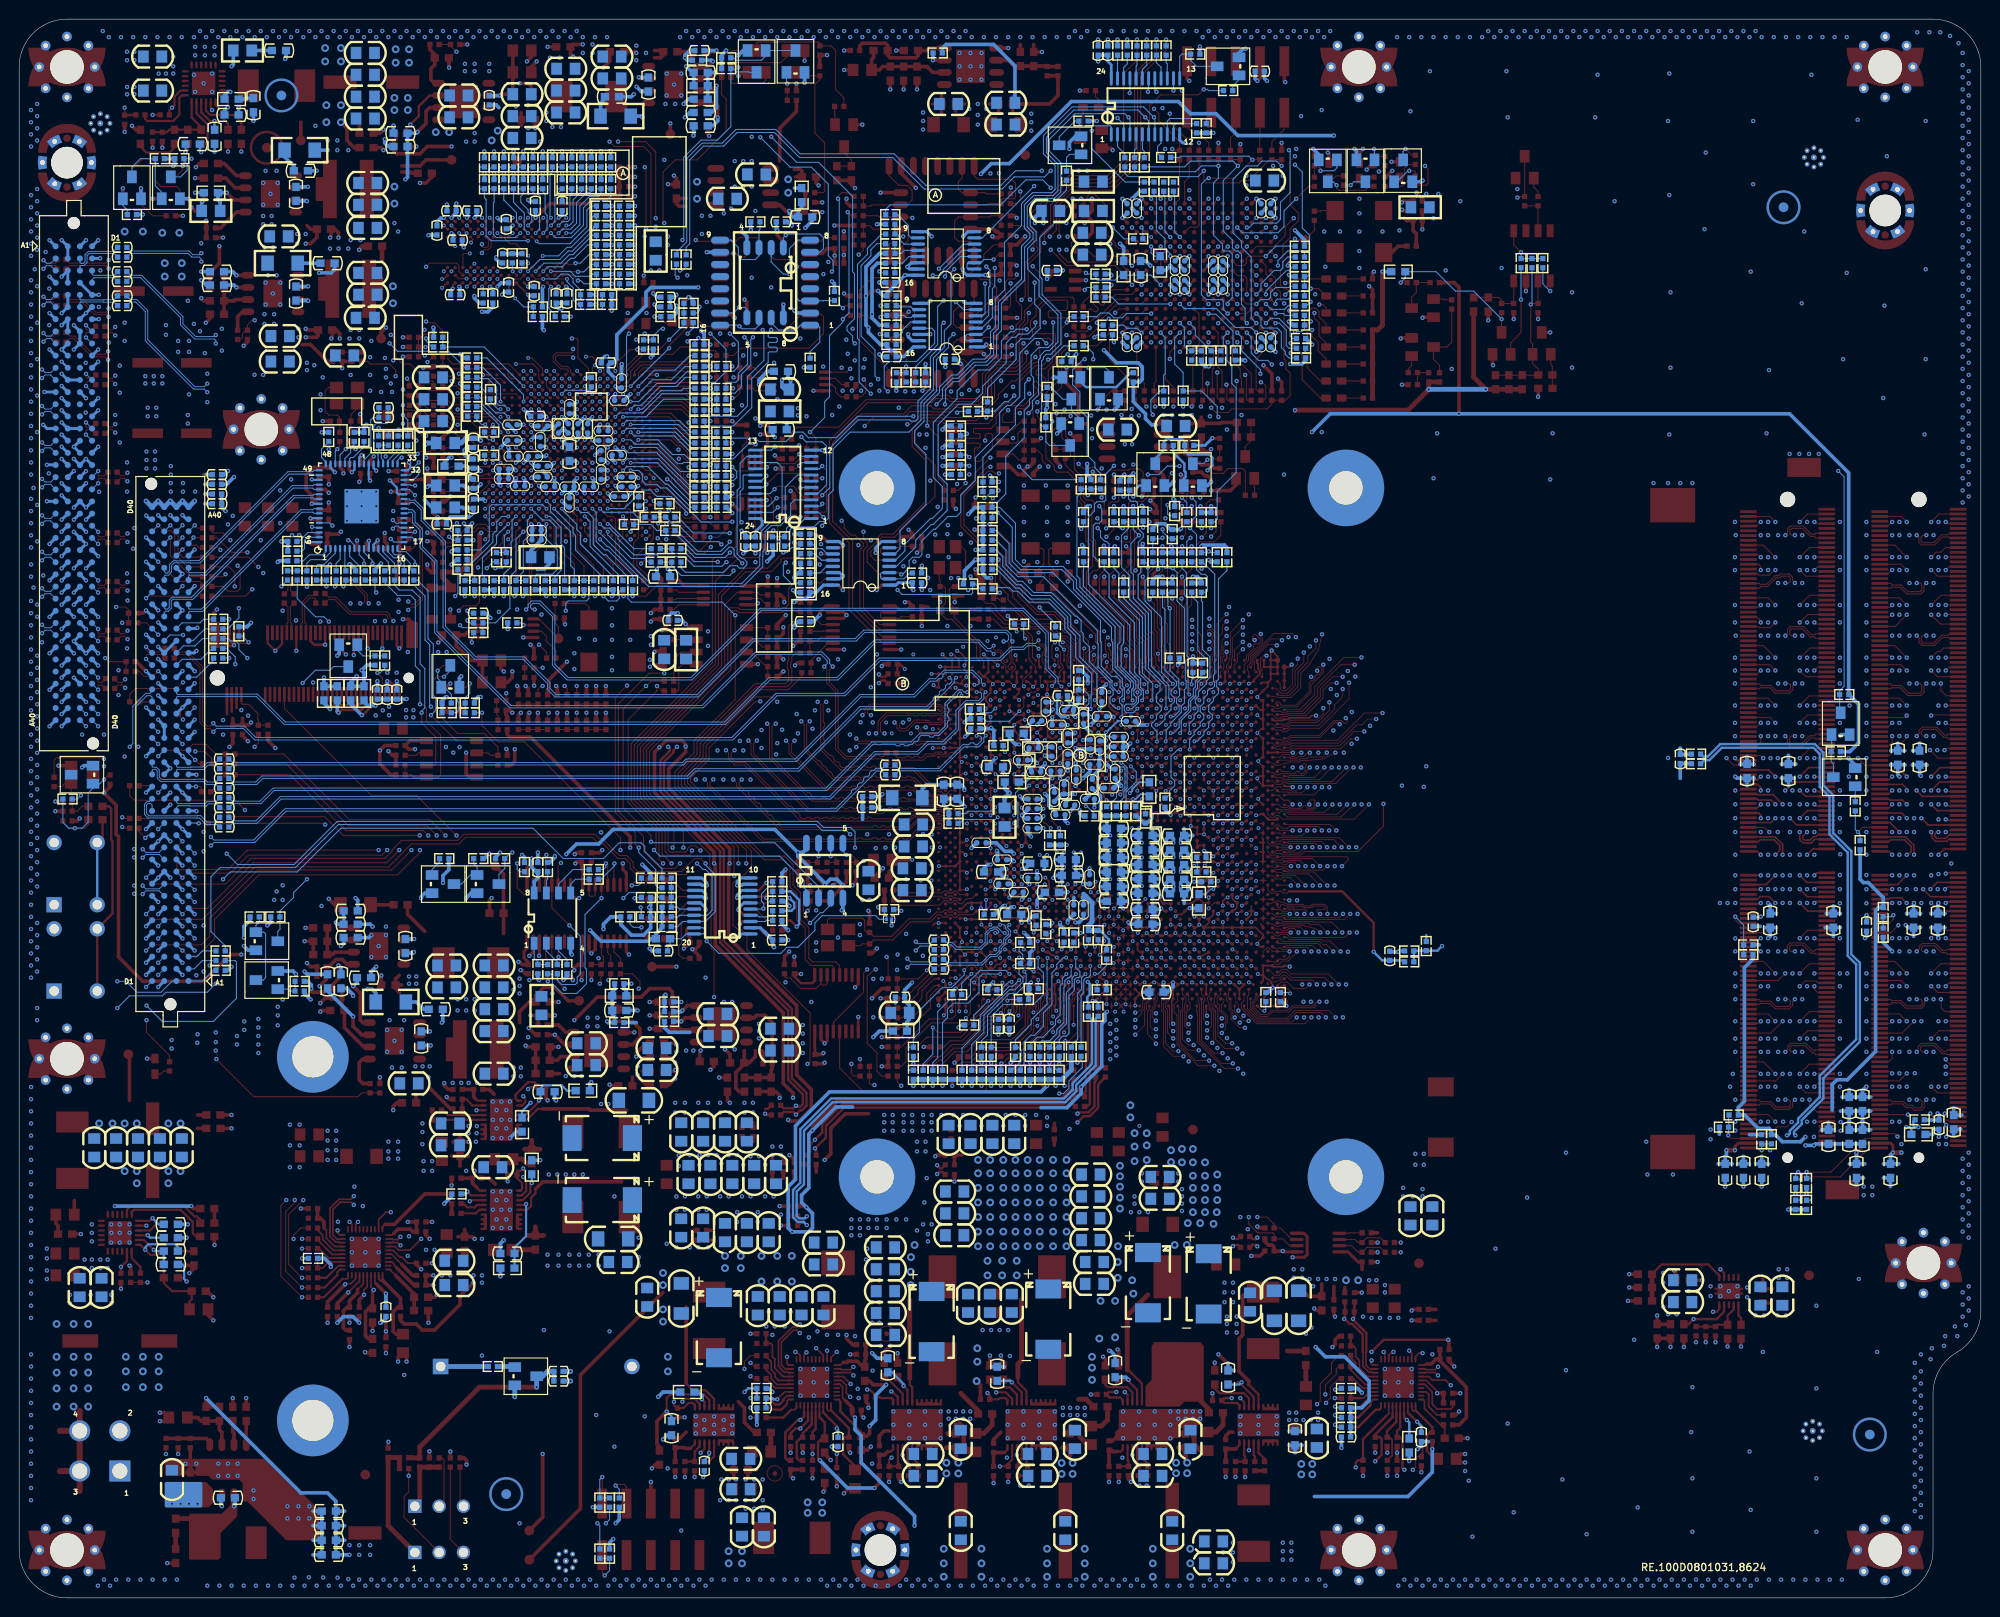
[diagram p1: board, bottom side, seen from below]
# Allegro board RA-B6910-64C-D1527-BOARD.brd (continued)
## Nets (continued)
N1736034: R959.2 U43.AA28(SOC_RCOMP)
N1737422: R969.2 R970.1
N1737426: R966.2 U43.CU76(TEST0)
N1737430: R964.2 U43.CM78(TEST1)
N1737496: R971.1 U43.AA27(PCIE_RCOMP)
N1737500: R963.1 U43.W75(B\P\M\_\N\[\0\]\)
N1737504: R965.1 U43.AD72(B\P\M\_\N\[\1\]\)
N1738008: R967.2 U43.CC52(DDR_RCOMP[0])
N1738012: R968.2 U43.CD51(DDR_RCOMP[1])
N1738056: R970.2 U43.CC49(DDR_RCOMP[2])
N1739742: C596.1 U43.AW16(DCPRTC)
N1739750: C597.1 U43.AW19(DCPSST)
N1739794: C598.1 U43.AU16(DCPSUS1)
N1739798: C599.1 U43.AK14(DCPSUS2)
N1739830: C600.1 U43.AP28(DCPSUS3_1) U43.AP30(DCPSUS3_2)
N1739866: C601.1 U43.AU21(DCPSUSBYP_1) U43.AW21(DCPSUSBYP_2)
N1739906: C602.1 U43.BT5(VCC_SENSE)
N1743737: R178.2 U4.A20
N1743791: R174.2 U4.A14
N1743888: R180.2 U4.A23
N1743955: R182.2 U4.A26
N1744023: R188.2 U4.A29
N1744091: R189.2 U4.B30
N1746574: C22.1 C23.1 C24.1 C25.1 C26.1 C27.1 L5.1 L37.1 U2.H8(VCCINT_2) U2.H10(VCCINT_1) U2.J7(VCCINT_3) U2.J9(VCCINT_4)
N1747948: R187.2 U4.B28
N1747980: R184.2 U4.B27
N1765923: C147.2 R243.2 R246.2 R248.2 U10.2(VFB)
N1766937: C146.1 U10.7(VBST)
N1766981: C148.1 U10.3(VREG5)
N1767005: C150.1 U10.4(SS)
N1767077: C149.2 R249.1
N1767081: C146.2 C149.1 L10.2 U10.6(SW)
N1767201: R242.2 U10.1(EN)
N1768542: R1032.2 U49.2(1DIR) U49.3(2DIR)
N1768822: R1030.2 U47.2(1DIR) U47.3(2DIR)
N1769078: R1031.2 U48.2(1DIR) U48.3(2DIR)
N1771458: R1065.2 U51.2(1DIR) U51.3(2DIR)
N1771492: R1068.1 R1072.1 U52.13(1B1)
N1771500: R1069.1 R1073.1 U52.12(1B2)
N1771708: R1066.2 U52.2(1DIR) U52.3(2DIR)
N1772180: R1057.2 U50.2(1DIR) U50.3(2DIR)
N1774144: C159.2 R254.2 R256.1 R257.2 U11.2(VFB)
N1774506: C158.1 U11.7(VBST)
N1774550: C160.1 U11.3(VREG5)
N1774562: C162.1 U11.4(SS)
N1774640: C161.2 R259.1
N1774644: C158.2 C161.1 L11.2 U11.6(SW)
N1774764: R252.2 U11.1(EN)
N1776237: R1095.2 U54.5(EN)
N1776541: R1103.2 U57.5(EN)
N1776695: R1098.2 U56.6(SDAB)
N1776757: R1099.2 U56.3(SDAA)
N1777634: R1106.2 U59.2(1DIR) U59.3(2DIR)
N1777804: R1108.2 U58.2(1DIR) U58.3(2DIR)
N1783254: Q15.1(B) Q16.3(C) R244.2
N1783372: Q16.1(B) R250.2
N1784134: Q17.1(B) Q18.3(C) R253.2
N1784252: Q18.1(B) R258.2
N1788886: C191.2 R288.2 R292.1 R293.2 U15.2(VFB)
N1789254: C190.1 U15.7(VBST)
N1789298: C192.1 U15.3(VREG5)
N1789310: C194.1 U15.4(SS)
N1789388: C193.2 R295.1
N1789392: C190.2 C193.1 L12.2 U15.6(SW)
N1789520: R287.2 U15.1(EN)
N1789628: Q27.1(B) Q28.3(C) R289.2
N1789730: Q28.1(B) R294.2 R296.1
N11710283: R789.2 U43.AM75(LAN_SMBCLK)
N11710317: R791.2 U43.AM77(LAN_SMBDATA)
N11710357: R788.2 U43.AN71(L\A\N\_\S\M\B\A\L\R\T\_\N\)
N11776877: R1005.1 U46.6(SCL)
N11776881: R1006.1 U46.5(SDA)
N11776929: R997.2 R1001.2 U46.1(A0)
N11776933: R998.2 R1002.2 U46.2(A1)
N11776953: R999.2 R1004.2 U46.3(A2)
N11777003: R1000.1 R1003.1 R1007.2 U46.7(WP)
N11794527: R849.1 U43.AE75(SERIRQ_DATA)
N11795538: R839.2 U43.BU14(SERIRQ)
N12394792: Q20.1(B) R271.2
N12395045: Q20.3(C) R266.2 R272.1 R1195.1
N12395788: Q21.1(B) R272.2
N12395875: Q21.3(C) R267.2 R270.1
N12395879: C179.2 C764.1 R270.2 R275.1 R1192.2 U13.4(G)
N12402803: C184.2 C765.1 R281.2 R286.1 R1196.2 U14.4(G)
N12402827: Q25.3(C) R280.2 R281.1
N12402879: Q24.1(B) R282.2
N12402927: Q24.3(C) R279.2 R283.1 R1199.1
N12402999: Q25.1(B) R283.2
N12409933: R302.1 U16.8(EN)
N12410255: C199.1 R297.1 R298.1 R301.2 U16.2(FB)
N12417603: R265.1 U12.8(EN)
N12417815: C167.2 R260.1 R261.2 R264.2 U12.2(FB)
N12424653: C137.1 R241.1 U9.8(EN)
N12425131: C132.2 R236.2 R239.2 R240.2 U9.2(FB)
N12431533: R171.2 U4.A1
N12431544: R169.2 U4.A2
N12431744: R170.2 U4.A3
N12431813: R176.2 U4.A17
N12431851: R811.1 U43.AN3(TACH0_GPIO17)
N12431888: R812.1 U43.AM4(TACH1_GPIO1)
N12431946: R813.1 U43.AV11(TACH2_GPIO6)
N12432021: R814.1 U43.AG2(TACH3_GPIO7)
N12432061: R815.1 U43.AV7(TACH4_GPIO68)
N12432134: R829.2 U43.BV20(GPIO50)
N12432641: R194.1 U4.B36
N12433834: R828.1 U43.BG16(PECI_PCH)
N12435911: R106.2 R113.2 U3.3(M\R\)
N12441283: J1.1 R114.2
N12441300: J1.3 R115.2
N12441304: J1.5 R116.2
N12441326: J1.9 R117.2
N12446006: R173.2 U4.C14
N12446036: R175.2 U4.C17
N12446074: R177.2 R1190.2 R1191.2 U4.C20
N12446215: R179.2 U4.C23
N12446425: R181.2 U4.C26
N12446773: R195.2 U4.C37
N12446840: R197.2 U4.C38
N12451021: R172.1 U4.D13
N12451452: R183.1 U4.D27
N12451530: R186.1 U4.D28
N12451653: R190.1 U4.D30
N12451741: R192.1 U4.D33
N12451802: R193.1 U4.D36
N12451883: R198.1 U4.D38
N12456803: R63.1 U2.K15(IO_87)
N12456807: R65.1 U2.K16(IO_88)
N12456811: R66.1 U2.K2(IO_89)
N12456815: R67.1 U2.K3(IO_90)
N12456949: R60.1 U2.L1(IO_91)
N12457439: R196.2 U4.A37
N12457473: R199.2 U4.A38
N12457550: R80.1 U2.M1(IO_99)
N12459341: R81.1 U2.M13(IO_100)
N12459393: R61.1 U2.M14(IO_101)
N12460724: R79.1 U2.L4(IO_98)
N12462137: R82.1 U2.N1(IO_107)
N12467054: R83.1 U2.N16(IO_112)
N12494143: R84.1 U2.P7(IO_126)
N12494253: J3.68(SUSCLK(32K)) R163.1 R165.1
N12494458: R934.1 U43.AA2(CLKOUTFLEX3_GPIO67)
N12494514: R935.1 U43.AC4(CLKOUTFLEX1_GPIO65)
N12494701: R973.2 U43.BH1(O\C\0\_\N\_\G\P\I\O\5\9\)
N12494835: R51.2 U20.F21(G\P\I\O\A\C\5\_\E\S\P\I\C\S\#\_)
N12494901: R52.2 U20.G22(G\P\I\O\A\C\7\_\E\S\P\I\R\S\T\#)
N12495914: R47.1 R48.1 U26.34(SMB_CLK)
N12495922: R46.1 R49.1 U26.36(SMB_DAT)
N12495930: R50.1 U26.35(S\M\B\_\A\L\R\T\_\N\)
N12501290: R1207.1 U2.R16(IO_135)
N12501313: R1208.1 U2.R3(IO_136)
N12509695: J3.18(3.3V_18) R162.1
N12509699: J3.16(3.3V_16) R161.1
N12509703: J3.14(3.3V_14) R160.1
N12509707: J3.12(3.3V_12) R159.1
N12515607: R71.1 U2.L14(IO_93)
N12522400: R232.1 U8.17(VBST)
N12522404: C124.2 L9.2 R233.1 U8.13(SW_1) U8.14(SW_2) U8.15(SW_3) U8.16(SW_4)
N12522444: C116.1 C117.1 U8.23(COMP)
N12522448: C117.2 R226.2 R227.2 R228.1 R229.1 U8.24(FB)
N12522508: C118.1 R228.2
N12522632: R231.1 U8.21(RT/SYNC)
N12522664: C119.1 R230.2 U8.22(MODE/SS)
N12522708: C131.1 R233.2
N12523074: R234.2 U8.1(EN)
N12523098: C114.2 U8.19(BP3)
N12523126: C115.2 U8.18(BP7)
N12526727: L1.1 SW1.3 SW1.4
N12526853: C1.1 L1.2 Q1.1 R1.2 R3.1
N12527177: L2.1 SW2.3 SW2.4
N12527267: C2.1 L2.2 Q4.1 R7.2 R9.1
N12527562: R72.1 U2.L16(IO_95)
N12528497: R59.2 U2.A10(IO_1)
N12541458: R74.1 U2.L2(IO_96)
N12546465: R64.2 U2.A11(IO_2)
N12556062: C8.2 R32.2 R37.2 R42.1
N12556533: C9.2 R33.2 R38.2 R43.1
N12557485: C10.2 R34.2 R39.2 R44.1
N12558669: C11.2 R35.2 R40.2 R45.1
N12558773: C12.2 R36.2 R41.2
N12558953: C7.2 R25.2 R30.2
N12560407: C5.2 R21.2 R26.2
N12560503: C3.2 R22.2 R27.2
N12560842: C6.2 R23.2 R28.2
N12560934: C4.2 R24.2 R29.2 R31.1
N12564156: R55.2 U1.2(OE)
N12564196: C19.1 C20.2 L4.1 U1.6(VDD)
N12564244: R54.1 U1.3(1Y0)
N12564264: R56.1 U1.5(1Y1)
N12564408: R58.1 U1.7(1Y2)
N12564466: C13.1 U1.8(1Y3)
N12565688: OSC1.3(CLK) R57.1
N12565730: C15.2 C16.2 L3.1 OSC1.1(DOWN)
N12568148: R323.1 R324.1 U18.5(A2)
N12568156: R321.1 R322.1 U18.6(A1)
N12568164: R318.1 R319.1 U18.7(A0)
N12569009: R331.1 U19.6(SCL)
N12569029: R332.1 U19.5(SDA)
N12569077: R325.2 R328.2 U19.1(A0)
N12569081: R326.2 R329.2 U19.2(A1)
N12569085: R327.2 R330.2 U19.3(A2)
N12569141: R333.2 U19.7(WP)
N12580885: Q14.1(B) R167.1 R168.1
N12580929: D20.1(ANODE) R166.1
N12580933: Q14.3(C) R166.2
N12727421: R98.2 U2.K14(IO_86)
N12727425: R53.2 U20.F22(G\P\I\O\A\C\6\_\E\S\P\I\A\L\T\#)
N13190675: R19.2 R1094.2 U54.6(SDAB)
N13190679: R20.2 R1093.2 U54.7(SCLB)
N13251249: C224.1 JP1.1 R311.2 R1209.1
N13251327: JP1.3 R314.1
N13251979: C225.1 JP2.1 R312.2 R313.1
N13252027: JP2.3 R315.1
N13252429: BZ1.1 R316.1
N13252463: D21.1(A1) R316.2
N13331287: Q7.1(B) R119.1 R120.2
N13331331: D16.1(ANODE) R118.1
N13331335: Q7.3(C) R118.2
N13331583: Q8.1(B) R122.1 R123.2
N13331627: D17.1(ANODE) R121.1
N13331631: Q8.3(C) R121.2
N13331888: Q9.1(B) R125.1 R126.2
N13331932: D18.1(ANODE) R124.1
N13331936: Q9.3(C) R124.2
N13334771: Q2.3(D) Q3.1(G) R5.2
N13334891: Q2.1(G) R4.2 R6.2
N13350702: R1079.2 R1085.1 U53.3(A1)
N13350706: R1080.2 R1083.1 U53.4(A2)
N13352439: C692.2 R1084.1 U53.19(VREF_B) U53.20(EN)
N13362638: D7.1(ANODE) R18.1
N13362837: D4.1(ANODE) R15.1
N13362858: D5.1(ANODE) R16.1
N13362901: D6.1(ANODE) R17.1
N13419508: D1.1(ANODE) R2.2
N13419676: D2.1(ANODE) R8.2
N13419890: Q6.1(G) R11.2 R14.1
N13421232: R317.2 R320.2 U18.3(OS)
N13449203: Q19.1(B) Q22.3(C) R268.2
N13449305: Q22.1(B) R273.2 R276.1
N13450062: Q23.1(B) Q26.3(C) R277.2
N13450164: Q26.1(B) R284.2
N13467875: R1087.1 R1088.1 R1089.1 R1090.1 U53.16(B3)
N13470118: R1096.2 U55.2(1DIR) U55.3(2DIR)
N13473742: C96.2 U7.19(BP3)
N13473942: C95.1 C98.1 U7.23(COMP)
N13473946: C98.2 R215.2 R216.2 R217.2 R218.1 R219.1 U7.24(FB)
N13473950: C95.2 R215.1
N13474144: C99.1 R218.2
N13474224: R222.1 U7.21(RT/SYNC)
N13474252: C100.1 R221.2 U7.22(MODE/SS)
N13474272: C97.2 U7.18(BP7)
N13474364: C105.2 L8.2 R224.1 U7.13(SW_1) U7.14(SW_2) U7.15(SW_3) U7.16(SW_4)
N13474368: C105.1 R223.2
N13474526: R214.1 U7.1(EN)
N13474606: R223.1 U7.17(VBST)
N13474690: C113.1 R224.2
N13478611: C85.1 U6.7(VBST)
N13478619: C86.2 R209.2 R211.1 U6.2(VFB)
N13478663: C88.1 U6.3(VREG5)
N13478671: C90.1 U6.4(SS)
N13478763: C89.2 R212.1
N13478791: C85.2 C89.1 L7.2 U6.6(SW)
N13479725: C87.1 R207.1 R208.2 R210.1
N13485147: R835.2 U43.AD76(W\A\K\E\L\A\N\_\N\)
N13485239: C216.2 R304.2 R308.1 U17.2(VFB)
N13485295: C215.2 C217.1 L14.2 U17.6(SW)
N13485589: R303.2 U17.1(EN)
N13485597: C215.1 U17.7(VBST)
N13485605: C218.1 U17.3(VREG5)
N13485609: C219.1 C220.1 U17.4(SS)
N13485681: C217.2 R309.1
N13488505: Q29.1(B) Q30.3(C) R305.2
N13488607: Q30.1(B) R310.2
N13745783: R957.2 U43.AP75(RSVD21)
N14074963: C728.1 U43.A38(PE1_TX_DP[7])
N14074967: C725.1 U43.D37(PE1_TX_DN[6])
N14074969: C722.1 U43.B35(PE1_TX_DP[4])
N14074975: C719.1 U43.C34(PE1_TX_DN[3])
N14074977: C716.1 U43.A31(PE1_TX_DP[1])
N14074985: C727.1 U43.C38(PE1_TX_DN[7])
N14074987: C724.1 U43.A36(PE1_TX_DP[5])
N14074993: C721.1 U43.D35(PE1_TX_DN[4])
N14074995: C718.1 U43.B32(PE1_TX_DP[2])
N14075001: C715.1 U43.C31(PE1_TX_DN[1])
N14075005: C726.1 U43.B37(PE1_TX_DP[6])
N14075011: C723.1 U43.C36(PE1_TX_DN[5])
N14075013: C720.1 U43.A34(PE1_TX_DP[3])
N14075019: C717.1 U43.D32(PE1_TX_DN[2])
N14075081: C713.1 U43.D30(PE1_TX_DN[0])
N14075085: C714.1 U43.B30(PE1_TX_DP[0])
N14342396: R1163.1 U43.BB14(GPIO26)
N16697668: R367.1 R369.2 R1200.2 U36.29(BVSN)
N16697688: R366.1 R368.1 R1200.1 U36.28(BVSP)
N16697962: R363.1 R365.2 U36.3(AVSN)
N16697994: R362.1 R364.2 U36.2(AVSP)
N16698122: R358.1 R361.2 U33.29(BVSN)
N16698154: R359.1 R360.2 U33.28(BVSP)
N16698306: R355.1 R357.2 U33.3(AVSN)
N16698318: R354.1 R356.2 U33.2(AVSP)
N16698468: R351.1 R353.2 U29.29(BVSN)
N16698500: R350.1 R352.2 U29.28(BVSP)
N16698648: R346.1 R348.2 U29.3(AVSN)
N16698676: R345.1 R347.2 U29.2(AVSP)
N16705316: R85.1 U2.T12(IO_145)
N16705352: R86.1 U2.T13(IO_146)
N16705397: R87.1 U2.T15(IO_147)
N16706083: R88.1 U2.T2(IO_148)
N16706087: R89.1 U2.T4(IO_149)
N16706091: R90.1 U2.T5(IO_150)
N16706101: R91.1 U2.T6(IO_151)
N16706105: R92.1 U2.T7(IO_152)
N16706132: R93.1 U2.T8(IO_153)
N16755005: C73.1 C74.1 C75.1 R200.2 R202.1 U5.2(VLDOIN)
N16755089: C72.2 R201.1 R204.2 R205.2 U5.7(EN)
N16755125: C76.1 R202.2 R206.1 U5.1(REFIN)
N16755585: C77.1 U5.6(REFOUT)
N16793694: C423.1 R680.1 U32.4(VDD)
N16794342: C422.1 R679.2
N16794347: R679.1 U32.14(BOOTR)
N16794368: C422.2 U32.15(BOOT)
N16794661: C425.1 R684.1 U32.18(TAO/FAULT)
N16903889: D3.1(ANODE) R10.2
N16903915: Q5.1(G) R12.2 R13.1
N16909700: R1115.2 U29.15(BVR_RDY)
N16935902: C357.1 R665.2 U30.4(VDD)
N16936603: R668.2 U30.3(LSET)
N16937550: R670.2 R671.1 R677.2 U30.11(EN/FCCM) U31.11(EN/FCCM)
N16941751: R666.1 U30.8(BOOTR)
N16941772: C346.1 U30.9(BOOT)
N16941889: C358.1 R669.1 U30.12(TAO/FAULT)
N16948518: C385.1 R672.2 U31.4(VDD)
N16948538: R675.2 U31.3(LSET)
N16948700: R673.1 U31.8(BOOTR)
N16948702: C374.1 U31.9(BOOT)
N16948718: C386.1 R676.1 U31.12(TAO/FAULT)
N16975861: R146.1 U61.15(2B1)
N16975864: R145.1 U61.2(1B1)
N16975903: R147.1 U61.6(1B3)
N16975906: R148.1 U61.19(2B3)
N16975938: R149.1 U61.5(1B2)
N16975941: R150.1 U61.16(2B2)
N16975982: R208.1 U6.1(EN)
N16997266: C452.1 R710.1 U34.4(VDD)
N16997274: C451.1 R709.2
N16997276: R709.1 U34.14(BOOTR)
N16997279: C451.2 U34.15(BOOT)
N16997281: C454.1 R714.1 U34.18(TAO/FAULT)
N16998858: C471.2 U35.15(BOOT)
N16998860: R716.1 U35.14(BOOTR)
N16998866: C471.1 R716.2
N16998883: C472.1 R717.1 U35.4(VDD)
N16998909: C474.1 R721.1 U35.18(TAO/FAULT)
N17027955: D8.1(ANODE) R96.2
N17027975: D9.1(ANODE) R97.2
N17027989: D10.1(ANODE) R99.2
N17028003: D11.1(ANODE) R100.2
N17028013: D12.1(ANODE) R101.2
N17028027: D13.1(ANODE) R102.2
N17028039: D14.1(ANODE) R103.2
N17028059: D15.1(ANODE) R104.2
N17031624: C496.1 R745.2 U37.4(VDD)
N17031630: R749.2 U37.3(LSET)
N17031638: R751.2 R752.1 U37.11(EN/FCCM)
N17031650: R746.1 U37.8(BOOTR)
N17031652: C489.1 U37.9(BOOT)
N17031655: C497.1 R750.1 U37.12(TAO/FAULT)
N17031694: C489.2 R746.2
N17039294: C428.1 R693.1 U33.11(VIN_CSNIN) U33.12(CSPIN)
N17040089: C747.1 R694.1 U33.13(BVR_EN)
N17040626: C431.1 R696.2 U33.16(V3P3)
N17041421: C427.1 R689.1 U33.23(AVR_EN)
N17047383: C480.1 R730.1 U36.11(VIN_CSNIN) U36.12(CSPIN)
N17047812: C748.1 R731.1 U36.13(BVR_EN)
N17048287: C483.1 R733.2 U36.16(V3P3)
N17049239: C479.1 R725.1 U36.23(AVR_EN)
N17052448: C337.1 R647.1 U29.11(VIN_CSNIN) U29.12(CSPIN)
N17053094: C746.1 R648.1 U29.13(BVR_EN)
N17053632: C340.1 R650.2 U29.16(V3P3)
N17054263: C336.1 R644.1 U29.23(AVR_EN)
N17098376: R686.1 U33.6(PU3)
N17098434: R726.1 U36.6(PU3)
N17098818: R728.2 U36.8(NC_1)
N17098920: R690.2 U33.8(NC_1)
N17105456: C59.2 J3.41(PERN0/SATA_B+)
N17105459: C58.2 J3.43(PERP0/SATA_B-)
N17105487: C61.2 J3.47(PETN0/SATA_A-)
N17105490: C60.2 J3.49(PETP0/SATA_A+)
N17107496: J3.69(PEDET) R164.2
N17107982: R112.1 U2.D10(IO_198)
N17116587: C511.2 U38.15(BOOT)
N17116589: R754.1 U38.14(BOOTR)
N17116595: C511.1 R754.2
N17116612: C512.1 R755.1 U38.4(VDD)
N17116638: C514.1 R759.1 U38.18(TAO/FAULT)
N17480014: R1129.1 U61.9(1B4)
N17480023: R1130.1 U61.20(2B4)
N17481397: R1131.1 U2.P14(IO_120)
N17481458: R1133.1 R1162.1 U61.13(2\Q\E\)
N17482004: R1132.2 R1157.2 U61.1(1\Q\E\)
N17547354: R1136.1 U2.E11(IO_205)
N17547355: R1135.1 U2.E10(IO_204)
N17563236: R1139.1 U62.2(1B1)
N17563239: R1140.1 U62.5(1B2)
N17563242: R1141.1 U62.6(1B3)
N17563245: R1142.1 U62.9(1B4)
N17571333: Q33.3(C) R1173.2 U62.13(2\Q\E\)
N17682193: Q33.1(B) R1172.1
N17689359: R1143.2 U62.11(1A5)
N17750781: C738.2 U60.D3
N17750784: C732.2 U60.D4
N17756086: C740.2 U60.C5
N17756089: C741.2 U60.C6
N17760907: Q34.1(B) R1175.1
N17761211: Q34.3(C) R1176.2 U62.1(1\Q\E\)
N17768751: R1104.2 U56.5(EN)
N17772566: R1146.1 U62.23(2B5)
N17773057: R1145.2 U62.22(2A5)
N17794271: C733.2 U60.A9
N17794274: C739.2 U60.A8
N17794486: C731.2 U60.A6
N17794489: C737.2 U60.A5
N17794993: C730.2 U60.A2
N17794996: C734.2 U60.A3
N17795291: C735.2 U60.C2
N17795581: C736.2 U60.C3
N17832270: C758.1 C759.2 C760.2 L35.2 OSC6.4(VCC) R1184.2
N17832309: OSC6.1(DOWN) R1184.1
N17832341: OSC6.3(CLK) R1185.1
N17914718: Q36.3(D) R1197.2 R1198.2
N17914746: Q36.1(G) R1199.2
N17916073: Q35.3(D) R1193.2 R1194.2
N17916093: Q35.1(G) R1195.2
N17918460: R1188.1 U2.F15(IO_63)
N17918580: R1189.1 U2.F16(IO_64)
N18052602: R1210.1 R1211.2 R1212.2 U63.1(EN)
N18052688: C784.2 R1213.2 R1214.1 U63.2(VFB)
N18052713: C786.2 R1215.1
N18052715: C787.1 U63.4(SS)
N18052767: C783.1 U63.7(VBST)
N18052773: C785.1 U63.3(VREG5)
N18052836: C783.2 C786.1 L36.2 U63.6(SW)
N18094371: R1216.2 U2.G5(IO_163)
N18134263: R1217.2 R1218.1 R1230.2
N18134715: Q38.3(C) R1219.2 R1222.1
N18135317: Q37.1(B) R1222.2
N18135357: Q37.3(C) R1220.2 R1221.1
N18148857: C811.1 C812.1 R1236.2 R1237.2 R1238.1 U64.6(VCNTL)
N18148863: C810.1 R1235.1 R1237.1 U64.8(EN)
N18148873: C805.2 R1232.2 R1233.2 R1234.2 U64.2(FB)
N18149045: R1231.2 U64.7(POK)
N18169102: C817.1 R1239.1 R1244.2 R1248.2 U65.4(PFI)
N18169160: R1240.1 U65.1(MR)
N18169166: R1240.2 R1245.2 R1246.1 U65.5(PFO)
N18169184: C816.1 Q40.2(CATHODE) R1241.1 R1242.1 R1243.1 R1245.1 R1247.2 U65.2(VCC)
N18169218: Q39.1(B) R1246.2
N18169273: Q40.1(REF) R1247.1 R1249.1
N18205231: Q41.1(B) R1253.2
N18362458: R431.1 U20.G21(GPIOAC0_ESPID0_LAD0)
N18362461: R432.1 U20.G20(GPIOAC1_ESPID1_LAD1)
N18362464: R434.1 U20.D22(GPIOAC2_ESPID2_LAD2)
N18362467: R435.1 U20.E22(GPIOAC3_ESPID3_LAD3)
N18373532: Q11.1(B) R138.2
N18373604: Q10.1(B) Q11.3(C) R133.2
N18390944: C258.1 R548.1 U20.B8(USB2AVRES)
N18390947: R549.1 U20.B7(USB2BVRES)
N18391131: C259.2 C260.1 L15.2 U20.C7(USB2AV33)
N18404073: D30.1(ANODE) R551.1
N18404109: R535.2 U20.U18(S\R\S\T\#\)
N18404132: R536.2 U20.V18(E\X\T\R\S\T\#\)
N18446289: C288.2 C289.2 U26.40(CTOP)
N18446291: C288.1 C289.1 U26.37(CBOT)
N18446408: R617.2 U26.48(RSET)
N18446673: C281.1 OSC3.1 R615.1
N18446681: C280.1 OSC3.3 R1138.2
N18462506: R607.1 U27.7(H\O\L\D\)
N18462522: R608.2 U27.3(W\)
N18484629: C264.1 U26.21(PE_TP)
N18484631: C263.1 U26.20(PE_TN)
N18490477: R445.1 U20.P20(GPIOY7_SDA2)
N18490497: R444.1 U20.M20(GPIOY6_SCL2)
N18491459: R550.2 U20.AB18(PECI)
N18565933: R513.2 U20.T2(GPIOL0_NCTS1)
N18565936: R514.2 U20.T1(GPIOL1_NDCD1_VPIDE)
N18565939: R515.2 U20.U1(GPIOL2_NDSR1)
N18565942: R516.2 U20.U2(GPIOL3_NRI1_VPIHS)
N18565945: R517.2 U20.P4(GPIOL4_NDTR1_VPIVS)
N18565948: R518.2 U20.P3(GPIOL5_NRTS1_VPICLK)
N18581691: R490.1 U20.R22(G\P\I\O\Y\0\_\S\I\O\S\3\#\)
N18581694: R491.1 U20.R21(G\P\I\O\Y\1\_\S\I\O\S\5\#\)
N18581697: R496.1 U20.P22(G\P\I\O\Y\2\_\S\I\O\P\W\R\E\Q\#)
N18581700: R497.1 U20.P21(G\P\I\O\Y\3\_\S\I\O\O\N\C\T\R\L)
N18581728: R499.1 U20.Y20(G\P\I\O\Z\0\_\V\P\O\G\2\_\N\O\R)
N18581730: R501.1 U20.AB20(GPIOZ1_VPOG3_NORA1_SIOPWRGD)
N18581732: R500.1 U20.AB21(G\P\I\O\Z\2\_\V\P\O\G\4\_\N\O\R)
N18581734: R502.1 U20.AA21(G\P\I\O\Z\3\_\V\P\O\G\5\_\N\O\R)
N18601236: R541.1 U20.V3(GPION2_PWM2_VPIG2)
N18601239: R542.1 U20.U3(GPION3_PWM3_VPIG3)
N18601328: R543.1 U20.AA3(GPION5_PWM5_VPIG5)
N18603109: R544.2 U20.W5(GPIOP1_TACH9_VPIR7)
N18603113: R546.2 U20.AB5(GPIOP3_TACH11_VPIR9)
N18655553: R462.1 U20.N21(GPIOQ4_SCL14)
N18655556: R463.1 U20.N22(GPIOQ5_SDA14)
N18657207: R460.1 U20.C14(GPIOA4_TIMER5_SCL9)
N18657210: R461.1 U20.A13(GPIOA5_TIMER6_SDA9)
N18657671: R455.1 U20.N1(GPIOK4_SCL7)
N18657674: R456.1 U20.P1(GPIOK5_SDA7)
N18657896: R457.1 U20.P2(GPIOK6_SCL8)
N18657899: R459.1 U20.R1(GPIOK7_SDA8)
N18673991: R437.1 U20.K19(GPIOB0)
N18673994: R436.1 U20.L19(GPIOB1)
N18683698: R503.1 U20.Y21(GPIOAA0_VPOR2_NORD0_SALT7)
N18683701: R504.1 U20.V21(GPIOAA1_VPOR3_NORD1_SALT8)
N18683704: R506.1 U20.Y22(GPIOAA2_VPOR4_NORD2_SALT9)
N18683707: R508.1 U20.AA22(GPIOAA3_VPOR5_NORD3_SALT10)
N18683710: R509.1 U20.U22(GPIOAA4_VPOR6_NORD4_SALT11)
N18683713: R510.1 U20.T20(GPIOAA5_VPOR7_NORD5_SALT12)
N18683716: R511.1 U20.N18(GPIOAA6_VPOR8_NORD6_SALT13)
N18683719: R512.1 U20.P19(GPIOAA7_VPOR9_NORD7_SALT14)
N18701636: R370.2 U20.L20(P\E\R\S\T\#\)
N18701697: R374.2 U20.K22(PEREFCLKN)
N18701700: R376.2 U20.M21(PERXP)
N18701703: R377.2 U20.M22(PERXN)
N18713379: R440.1 U20.M18(GPIOY4_SCL1)
N18713382: R442.1 U20.M19(GPIOY5_SDA1)
N18846064: R371.2 U20.K21(PEREFCLKP)
N18997501: R1202.1 U20.L1(GPIOK2_SCL6)
N18997503: R1203.1 U20.N2(GPIOK3_SDA6)
N125223401: C116.2 R227.1
N125223760: C124.1 R232.2
N127846400: R841.1 U43.BB27(GPIO32)
N133349620: D1.2(CATHODE) Q3.3(D)
N134196140: D2.2(CATHODE) Q6.3(D)
N169038700: D3.2(CATHODE) Q5.3(D)
N169417421: C346.2 R666.2
N169486101: C374.2 R673.2
N174789369: R1159.1 U61.10(1B5)
N175629399: R1144.1 U62.10(1B5)
N175901350: C347.2 R667.1
N175914301: C375.2 R674.1
N175914741: C402.2 R678.1
N175915121: C432.2 R708.1
N175915511: C455.2 R715.1
N175915931: C488.2 R748.1
N175916371: C499.2 R753.1
N184153402: R612.2 U26.3(NC_SI_CRS_DV)
N184153404: R613.2 U26.5(NC_SI_RXD1)
N184153405: R614.2 U26.6(NC_SI_RXD0)
N185203330: R630.2 R632.1
N185203331: R632.2 U20.K4(DACRSET)
N187134720: R553.1 U20.E17(GPIOG4_SGPS2CK_SALT1)
N1744816154: R94.1 U2.M9(IO/DEV_CLRN)
N1744816155: R95.1 U2.M8(IO/DEV_OE)
N1747893610: R1158.2 U61.11(1A5)
N1747893621: R1160.2 U61.22(2A5)
N1747893622: R1161.1 U61.23(2B5)
N1756293914: R1167.1 U62.15(2B1)
N1756293915: R1168.1 U62.16(2B2)
N1756293918: R1169.1 U62.19(2B3)
N1756293919: R1170.1 U62.20(2B4)
N1841534011: R620.1 U26.12(NVM_SI)
N1841534012: R619.1 U26.13(NVM_SK)
N1841534013: R618.1 U26.14(NVM_SO)
N1841534014: R616.1 U26.15(N\V\M\_\C\S\_\N\)

Pads without a net: COUPON1 1; COUPON2 1; COUPON3 1; COUPON4 1; FD1 1; FD3 1; FD4 1; FD5 1; FD6 1; FD10 1; FD11 1; FD12 1; FD13 1; FD14 1; J1 6 7 8; J3 5 6 7 8 11 13 17 19 20 22 23 24 25 26 28 29 30 31 32 34 35 36 37 40 42 44 46 48 52 53 54 55 56 58 67; J5 1 2 3 4 5 7; Q1 3; Q4 3; R1135 2; R1136 2; U2 A2 A5 A6 A15 B5 B6 B7 B16 C5 C10 C11 C12 C13 C14 C15 D3 D7 D8 D9 E4 E5 E6 E7 E8 E9 E12 E14 E15 E16 F2 F12 F14 G1 G3 G4 G12 G13 G14 G15 H1 H4 H13 H14 J1 J4 J13 J16 K4 L3 L12 L13 L15 M4 M6 M7 M10 M11 M12 M15 N5 N7 N8 N13 P8 R14 T9; U3 4; U20 A6 A9 A10 A11 A12 A16 A17 A18 A19 A20 A21 AA1 AA2 AA4 AB2 AB3 AB4 B2 B6 B9 B10 B11 B12 B13 B14 B17 B18 B19 B20 B21 B22 C11 C12 C13 C17 C19 C20 C21 D3 D9 D10 D13 D17 D18 D19 D20 D21 E12 E16 E18 E19 E20 E21 F17 F18 F19 F20 G17 G18 H18 H19 H20 J2 J3 J4 J18 J19 K20 L2 L3 L4 L21 L22 N3 N4 N5 N19 P5 R2 R3 R4 R5 R20 T3 T5 T17 T19 T21 T22 U4 U5 U15 U19 V2 V4 V5 V6 V19 V20 W2 W3 W4 W19 Y1 Y2 Y3 Y4 Y5 Y19; U21 T7; U22 4 5 6 11 12 13 14; U23 4 5 6 11 12 13 14; U26 22; U29 7 8 9 19 31 34 35 36 37; U33 7 9 19 31 34 35 36 37 38; U36 7 9 19 31 34 35 36 37 38; U39 4 5 6 11 12 13 14; U41 4 5 6 11 12 13 14; U43 A9 A16 A18 A23 A25 A27 A29 A40 A42 A44 A47 A49 A51 A53 A55 A58 A60 A62 A64 A66 A68 A70 A76 AA4 AC11 AC56 AC60 AC62 AD9 AE56 AE58 AE60 AE62 AG56 AG58 AG60 AG64 AH58 AH60 AH62 AJ64 AK4 AK56 AK58 AK62 AK66 AL5 AM55 AM56 AM58 AM60 AM62 AM66 AN7 AN64 AP55 AP56 AP58 AP60 AP62 AP66 AR64 AR71 AW12 B5 B8 B10 B17 B24 B26 B28 B39 B41 B43 B46 B50 B52 B54 B57 B59 B63 B65 B67 B69 BA14 BA18 BB18 BD7 BD26 BE20 BE32 BF18 BF33 BJ4 BJ9 BJ62 BL37 BL60 BM62 BN4 BP37 BP56 BP58 BR60 BT13 BT37 BT62 BU7 BU60 BW37 C7 C9 C16 C18 C23 C25 C27 C29 C40 C42 C44 C47 C49 C51 C53 C55 C58 C60 C62 C64 C66 C68 C70 CA37 CB39 CB43 CT51 CV51 D8 D10 D17 D24 D26 D28 D39 D41 D43 D46 D50 D52 D54 D57 D59 D63 D65 D67 D69 E72 F13 F16 F20 F39 F43 F47 F51 F69 F76 G74 H11 H14 H41 H45 H49 H52 H64 H71 J13 J16 J20 J39 J43 J47 J51 J69 K11 K14 K41 K45 K49 K52 K64 K71 L54 N13 N16 N20 N24 N28 N32 N39 N43 N47 N54 N69 P14 P18 P22 P26 P30 R13 R16 R20 R24 R28 R32 R39 R44 T14 T18 T22 T26 T30 T35 T37 T40 T42 T44 V11 V37 V39 V40 W2 W4 W66 Y7 Y32 Y33 Y35 Y37 Y60 Y62 Y64; U48 7 10; U50 5 12; U55 6 7 10 11; U58 7 10; U59 7 10; U60 A35 A36 A38 A39 C10 C11 C14 C15; Y1 2 3

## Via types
v1: diameter 0.457, hole 0.203, TOP to BOTTOM, 4994 vias
v2: diameter 0.406, hole 0.203, TOP to BOTTOM, 1249 vias
v3: diameter 0.813, hole 0.406, TOP to BOTTOM, 250 vias
v4: diameter 0.457, hole 0.229, TOP to BOTTOM, 71 vias

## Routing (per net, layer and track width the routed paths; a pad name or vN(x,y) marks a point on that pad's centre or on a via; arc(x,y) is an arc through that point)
12V_VCCGBE_P1V05_PCH: length 16.1
  TOP w0.381: C462.1 159.66,47.65 ; C462.1 158.06,47.65 v1(158.03,47.68) ; C462.1 158.92,48.44 ; C444.1 158.44,38.51 ; C444.1 157.63,37.74 v1(157.4,37.52) ; C444.1 159.15,37.74 ; R693.2 165.15,29.01 164.77,28.63 163.5,28.63 162.86,27.99 161.59,27.99 158.92,30.66 158.92,31.55 v1(157.53,32.94)
  vias: v1(156.64,37.52) v1(156.64,33.71) v1(156.64,32.94) v1(157.17,49.3) v1(157.2,48.57) v1(157.27,47.68) v1(157.4,44.63) v1(157.53,33.71) v1(158.03,49.3) v1(158.03,48.57) v1(158.29,44.63) v1(165.4,47.68) v1(165.4,46.66) v1(165.4,45.9) v1(166.42,47.68) v1(166.42,46.66) v1(166.42,45.9)
12V_VCCIN_VCCSCSUS: length 8.4
  TOP w0.381: v1(130.09,12.37) 130.32,12.6 C408.1 ; v1(118.16,15.16) 118.28,15.29 R647.2 ; C408.1 131.11,13.39 ; C408.1 130.32,14.25
  TOP w0.508: 94.51,15.7 C373.1 ; C373.1 95.17,14.91 ; C373.1 95.96,15.7 ; 108.1,15.7 C345.1 107.11,14.38 v3(106.85,14.12)
  vias: v1(130.09,10.21) v1(130.86,12.37) v1(130.86,10.21) v1(131.62,12.37) v1(131.75,10.21) v3(94.92,14.1) v3(94.92,12.95) v3(96.06,14.1) v3(96.06,12.95) v3(106.85,13.01) v3(108.1,14.12) v3(108.1,13.01) v3(121.08,9.98) v3(121.08,8.89) v3(122.6,9.98) v3(122.6,8.89)
12V_VDDQ_P2V5_VPP: length 21.1
  TOP w0.381: v1(57.32,15.55) R730.2
  TOP w0.508: v3(82.95,14.12) 83.1,14.28 C487.1 83.84,15.7
  BOTTOM w0.381: C509.1 70.94,15.95 ; C509.1 72.28,15.95 ; C509.1 71.67,15.16 ; v1(57.32,15.55) 57.32,13.13 59.86,10.59 69.64,10.59
  vias: v3(69.87,14) v3(69.87,12.9) v3(71.01,14) v3(71.01,12.9) v3(82.95,13.03) v3(84.1,14.12) v3(84.1,13.03)
12V_VIN: length 208.6
  TOP w0.305: v1(80.31,121.21) 80.29,121.19 R280.1
  TOP w0.381: 174.93,143.43 174.54,143.05 C145.1 173.88,142.19 174.54,141.53 v1(175.05,141.53) ; C62.1 185.72,117.4 ; v1(120.57,161.24) R266.1 R267.1 ; R1236.1 v1(118.79,159.69) ; 138.6,161.72 137.69,161.72 R207.2 137.69,161.24 137.97,160.96 138.6,160.96 ; R35.1 172.79,129.24 174.54,130.99 175.43,130.99 ; C781.1 186.25,11.63 ; C781.1 187.12,10.72 ; C781.1 187.98,11.63 ; v1(175.05,132.64) 174.93,132.51 C157.1 173.76,131.9 173.91,131.75 v1(175.05,131.75) ; C63.1 185.59,115.37 ; 141.8,160.6 C84.1 140.64,161.6 v1(140.51,161.47) ; C67.1 185.47,114.35 ; C66.1 185.59,116.38
  TOP w0.508: R1241.2 R1243.2 R1242.2 v1(51.74,126.31) 53.01,127.58 R1244.1 ; v1(71.67,124.13) 59.86,124.13 v1(57.7,126.29) R1217.1 R1219.1
  TOP w0.635: 198.67,15.39 J4.4 ; J4.4 198.67,19.53 ; J4.4 200.75,17.46 ; J4.3 200.75,13.26 ; J4.3 198.67,11.19 ; J4.3 198.67,15.33
  SIG1 w0.508: v1(80.31,121.21) 74.6,121.21 v1(71.67,124.13) 68.37,127.43 68.37,136.32 70.15,138.1 70.15,149.66 69.01,150.8 69.01,154.1 72.18,157.28 77.26,157.28 79.55,159.56 98.47,159.56 100.63,157.4 107.49,157.4 109.65,159.56 118.66,159.56 v1(118.79,159.69) 120.34,161.24 v1(120.57,161.24)
  POWER1 w0.635: J4.3 198.67,15.33 ; J4.3 198.67,11.19 ; J4.3 200.75,13.26 ; J4.4 200.75,17.46 ; J4.4 198.67,15.39 ; J4.4 198.67,19.53
  POWER2 w0.635: J4.3 200.75,13.26 ; J4.3 198.67,15.33 ; J4.3 198.67,11.19 ; 198.67,15.39 J4.4 ; J4.4 198.67,19.53 ; J4.4 200.75,17.46
  BOTTOM w0.305: R279.1 81.07,120.45 v1(80.31,121.21)
  BOTTOM w0.381: C67.1 185.59,114.35 ; C62.1 185.47,117.4 ; C63.1 185.59,115.37 ; C66.1 185.59,116.38
  BOTTOM w0.508: v1(51.74,126.31) 57.68,126.31 v1(57.7,126.29) ; v1(186.66,114.64) U4.A40 v1(187.93,114.64) U4.B40 v1(189.2,114.64) U4.C40 v1(190.47,114.64) U4.D40 v1(191.74,114.64)
  vias: v1(72.06,5.77) v1(72.06,4.88) v1(72.06,3.99) v1(72.94,5.77) v1(72.94,4.88) v1(72.94,3.99) v1(78.15,5.77) v1(78.15,4.75) v1(78.15,3.73) v1(79.17,4.75) v1(139.49,161.47) v1(140.51,162.23) v1(140.51,160.71) v1(171.88,48.82) v1(171.88,47.8) v1(171.88,46.79) v1(171.88,45.77) v1(172.77,48.82) v1(172.77,47.8) v1(172.77,46.79) v1(172.77,45.77) v1(175.05,142.55) v1(175.81,132.64) v1(175.81,131.75) v1(175.94,142.55) v1(175.94,141.53) v1(186.36,9.83) v1(186.61,115.62) v1(187.24,9.83) v1(187.88,116.51) v1(187.88,115.62) v1(188.13,9.83) v1(188.9,161.09) v1(188.9,160.07) v1(188.9,159.31) v1(189.02,9.83) v1(189.15,118.29) v1(189.15,117.4) v1(189.15,116.51) v1(189.15,115.62) v1(189.66,159.31) v1(189.66,133.02) v1(189.66,132) v1(190.04,127.69) v1(190.04,126.92) v1(190.42,159.31) v1(190.67,124.38) v1(190.67,123.5) v1(190.8,119.81) v1(190.8,118.92) v1(190.8,118.03) v1(190.93,127.69) v1(190.93,126.92) v1(191.56,124.38) v1(191.56,123.5) v1(191.69,119.81) v1(191.69,118.92) v1(191.69,118.03) v1(191.82,127.69) v1(191.82,126.92) v1(195.75,35.36) v1(195.75,34.47) v1(196.52,35.36) v1(196.52,34.47) v1(197.4,35.36) v1(197.4,34.47) v1(198.17,35.36) v1(198.17,34.47) v3(129.46,4.88) v3(129.46,3.61) v3(130.86,4.88) v3(130.86,3.61) v3(192.07,142.8) v3(193.98,142.8) v3(197.79,28.63) v3(197.79,25.2) v3(197.79,23.55) v3(197.79,21.9) v3(197.79,19.99) v3(199.31,28.63) v3(199.31,25.2) v3(199.31,23.55) v3(199.31,21.9) v3(199.31,19.99) v3(201.09,28.63) v3(201.09,25.2) v3(201.09,23.55) v3(201.09,21.9) v3(201.09,19.99)
GND: length 2622.5
  TOP w0.089: 74.16,64.38 73.74,64.38 U43.CV73 ; U43.CU21 71.92,88.35 v1(71.9,88.34) ; U43.CV74 73.07,63.95 73.37,63.65 73.86,63.65 v2(74,63.78)
  TOP w0.109: U43.F78 v2(106.07,61.29)
  TOP w0.178: v2(103.47,68.63) 103.18,68.34 U43.N66 102.77,68.34 v2(102.49,68.63) 102.2,68.34 U43.R66 101.78,68.34 v2(101.48,68.65) 101.18,68.34 U43.U66 ; v2(103.47,68.63) 103.47,69.19 U43.M64 103.98,69.7 U43.L62 ; v2(103.47,68.63) 103.76,68.34 U43.L66 ; U20.J5 v2(153.09,117.03) 153.09,117.03 U20.H5 ; v2(80.2,91.24) U43.CB16 v2(80.7,90.38) ; U43.AU3 U43.AV2 v2(91.35,97.8) ; U43.BW54 U43.BW55 ; U43.BW54 81.51,73.81 U43.BY54 ; U43.BW54 81.89,74.31 U43.BW52 ; U43.BW55 81.94,73.06 U43.BV56 U43.BT56 ; U43.BW55 81.68,73.06 81.26,72.64 ; U20.J22 v2(138.69,117.03) ; U43.CC33 v2(80.2,82.65) ; v2(79.21,70.63) 79.21,70.63 U43.CD62 ; U20.N11 v2(148.29,120.23) U20.M11 ; U43.CR1 74.21,98.92 v1(74.11,99.01) 73.5,98.4 U43.CU1 ; U43.CR1 U43.CU1 ; U43.CR1 U43.CR2 ; U43.AP14 v2(93.02,92.04) U43.AR12 ; v1(78.82,98.88) 78.82,98.15 U43.CE1 ; v2(81.19,80.94) U43.BY39 v2(81.19,79.8) ; U43.CD62 U43.CB62 U43.BY62 ; U43.CD62 U43.CG62 ; v2(103.48,85.23) 103.69,85.23 U43.L28 ; U43.BF30 88.13,85.15 U43.BE28 87.93,85.51 v2(87.62,85.82) 87.63,85.84 U43.BF26 ; v2(100.22,78.59) 99.84,78.98 U43.Y42 ; v2(100.22,78.59) 100.61,78.98 U43.V42 ; v2(100.22,78.59) 100.62,78.19 U43.V44 v2(100.22,77.78) U43.V46 ; U43.BN30 84.87,84.66 v2(85.18,84.34) ; U43.T74 102.03,64.09 v2(102.24,64.3) 102.44,64.09 U43.N74 ; U43.BY58 81.26,71.84 81.26,72.64 ; U43.BY58 U43.BV58 82.42,71.78 v2(82.7,72.06) 82.89,72.06 U43.BT58 83.53,71.43 83.94,71.43 v2(84.14,71.23) ; U43.BY58 v2(81.19,71.21) ; U20.AA15 v2(144.29,127.43) ; v2(81.45,64.32) U43.CA74 U43.CA76 ; U43.BY16 81.4,90.67 v2(81.69,90.38) ; U21.N9 v2(150.23,137.04) ; U43.CH71 v2(78.22,66.05) ; U43.CR3 U43.CU3 U43.CU2 ; U43.CR3 74.21,95.97 U43.CR5 ; U43.CR3 U43.CR2 ; v2(80.2,77.5) 80.49,77.79 U43.CA45 80.88,77.79 v2(81.17,78.08) 81.19,78.1 U43.BY43 81.69,78.65 U43.BW43 U43.BW42 ; v2(80.2,77.5) 80.33,77.5 80.74,77.09 U43.CA46 80.91,76.72 v2(81.1,76.53) ; v2(80.2,77.5) 79.92,77.79 U43.CC45 v2(79.71,78.36) ; U43.BW74 v2(82.44,64.32) ; U20.F1 v2(156.29,114.63) ; U43.BV9 v2(81.66,93.81) ; v2(82.68,81.77) 82.99,82.08 U43.BT35 83.31,82.08 v2(83.64,81.74) 83.98,82.08 U43.BP35 84.4,82.08 v2(84.66,81.82) ; v2(82.68,81.77) 82.53,81.62 U43.BU37 82.53,80.72 v2(82.57,80.67) 82.44,80.54 U43.BW39 U43.BW40 81.23,79.84 v2(81.19,79.8) ; v2(82.68,81.77) 82.37,82.08 U43.BV35 ; v2(99.36,78.54) 99.8,78.98 U43.Y42 ; U43.Y76 99.67,63.2 99.67,64 U43.Y74 99.5,64.09 v2(99.27,64.32) 99.04,64.09 U43.AB74 ; U43.AU53 91.83,74.18 v2(92.23,73.78) ; 150.26,117.75 149.82,117.75 U20.J9 ; 150.26,117.75 149.78,118.23 U20.K9 v2(149.09,118.63) U20.L10 ; 150.26,117.75 v2(150.29,117.78) ; U43.BH11 86.79,93.24 v2(87.1,92.93) ; v2(81.69,70.35) 81.69,70.35 U43.BW60 ; v2(81.69,70.35) 81.98,70.06 U43.BV62 ; v2(81.69,70.35) 81.48,70.35 U43.BY62 ; v2(102,66.07) U43.R69 102.13,66.63 102.54,66.22 102.79,66.22 103.24,65.77 U43.M71 ; U43.M71 103.74,65.77 103.98,66.01 U43.L69 103.98,66.99 U43.K67 104.7,67.49 v2(104.97,67.21) 105.25,67.49 U43.H67 105.89,67.49 v2(106.14,67.23) ; U43.M71 103.48,66.32 v2(103.46,66.35) ; U43.BY62 80.7,70.56 U43.CA60 ; U43.BY62 81.19,69.53 v2(81.23,69.49) ; v2(81.19,79.8) 80.9,79.5 U43.CA41 ; v2(95.42,72.98) U43.AH56 v2(95.42,72.18) ; U43.B2 108.71,97.29 v2(108.76,97.33) ; U43.B2 U43.B3 U43.A3 v2(109.65,96.58) ; U43.B2 U43.C2 ; v2(83.66,70.36) 83.87,70.36 U43.BP62 ; U43.AH53 v2(95.42,74.58) ; v2(79.71,78.36) 79.42,78.65 U43.CD43 v2(79.71,78.36) ; U43.AM21 v2(94.62,88.04) ; U43.AR3 U43.AR5 93.05,95.78 93.25,95.57 v2(93.33,95.57) 93.53,95.78 U43.AN5 ; U43.BP74 84.15,64.32 v2(84.42,64.32) ; U43.BP74 U43.BN75 ; U43.BP74 v2(83.43,64.32) U43.BT74 ; v2(100.51,93.84) 100.77,94.1 U43.U9 100.51,94.59 U43.V7 100.69,94.96 v2(101.04,95.32) ; U43.Y39 99.23,79.99 v2(99.23,79.55) 99.46,79.78 U43.Y40 U43.Y42 ; v2(84.66,81.82) 84.92,82.08 U43.BM35 ; v2(84.66,81.82) 84.63,81.78 U43.BN37 ; U21.D2 v2(158.22,143.44) ; U43.CB47 79.99,76.93 v2(79.71,76.64) 79.42,76.93 U43.CD47 ; U20.M10 v2(149.09,120.23) U20.N9 ; U20.E5 v2(153.09,113.83) ; U43.E77 U43.E78 106.78,61.34 v2(106.76,61.31) ; v2(99.89,91.78) 100.02,91.9 U43.W13 100.14,92.25 100.88,92.25 U43.U13 101.28,92.66 v2(101.52,92.66) 101.5,92.68 U43.T11 ; v2(99.89,91.78) 99.53,91.78 99.38,91.64 U43.AA14 U43.AA12 ; v2(99.89,91.78) 100.25,91.78 U43.V14 ; U43.BE66 88.13,67.77 87.84,67.49 U43.BF67 v2(87.63,66.91) 87.35,66.63 U43.BG69 ; U43.BW11 81.9,93.24 v2(82.18,92.95) ; U20.K16 v1(143.49,117.83) ; U20.A1 v2(156.29,110.63) ; U43.CP66 75.31,68.05 v2(75.61,68.35) 75.61,68.44 U43.CP64 75.01,69.3 75.77,70.06 U43.CL62 U43.CJ62 ; U43.BN75 U43.BN77 84.54,62.48 84.54,60.14 v1(84.4,60) ; U43.BN75 84.42,64.32 v2(84.42,64.32) ; U43.BN75 U43.BM74 ; U43.L62 104.14,70.06 v2(104.44,70.36) 104.44,70.41 104.47,70.44 U43.K60 ; U43.L62 103.8,70.06 v2(103.51,70.36) 103.51,70.89 U43.M60 ; v2(106.17,82.7) 106.37,82.9 U43.E34 ; v2(102.99,84.37) 103.27,84.66 U43.M30 103.48,83.51 v2(103.48,83.51) ; U43.L51 103.48,75.71 U43.M49 v2(103.48,76.64) 103.69,76.64 U43.L47 ; U43.L32 103.69,83.51 v2(103.48,83.51) ; U43.BR11 83.88,93.24 v2(84.17,92.95) ; U43.L1 103.27,98 v2(102.73,97.46) ; U43.L1 U43.L3 U43.K4 ; U43.L1 103.72,98.14 v2(104.19,98.6) ; v2(107.13,63.68) 107.11,63.68 U43.E74 106.49,64.38 U43.F72 105.36,64.31 v2(105.2,64.31) ; v2(82.22,76.51) 81.81,76.91 U43.BW47 ; v2(92.68,98.55) 92.72,98.55 92.83,98.44 U43.AR1 ; v2(97.07,93.55) 97.24,93.55 97.54,93.25 U43.AE11 98.22,92.56 U43.AC12 ; U43.AL67 U43.AL64 94.36,69.2 v2(94.07,69.49) ; v2(106.09,87.94) 106.17,87.85 U43.E23 ; U43.AU23 91.93,87.53 91.93,86.95 U43.AU25 91.82,86.81 92.19,86.45 v2(92.23,86.45) 92.24,86.45 92.62,86.83 U43.AR25 ; v2(82.18,71.21) 81.98,71.21 U43.BW60 ; U43.BY35 v2(80.7,81.79) U43.CB35 ; U20.N14 v2(145.09,121.03) ; v2(82.18,69.49) 82.47,69.2 U43.BU64 82.89,69.2 v2(83.18,69.49) 83.38,69.49 U43.BR64 83.88,69.2 v2(84.17,69.49) ; v2(82.18,69.49) U43.BV62 ; v2(82.18,69.49) 81.9,69.2 U43.BW64 81.52,69.2 v2(81.23,69.49) ; 81.26,72.64 U43.CA56 v2(80.7,73.21) ; v2(81.23,69.49) 80.93,69.2 U43.CA64 ; v2(104.01,74.04) 103.79,74.04 U43.M52 103.31,74.35 v2(102.99,74.04) 102.68,74.35 U43.P52 102.32,74.35 v2(102.03,74.06) 102,74.03 U43.R54 101.81,73.5 v2(101.52,73.2) 101.35,73.38 U43.V55 100.45,73.55 100,73.55 U43.Y55 ; v2(98.03,67.75) 97.77,67.49 U43.AE67 97.4,67.49 97.1,67.18 96.9,67.18 96.64,66.93 v2(96.57,66.93) 96.26,66.63 U43.AH69 ; U20.V14 v2(145.09,125.03) ; U43.CA18 v2(81.19,89.52) U43.BY20 ; v2(96.62,61.37) 96.79,61.54 U43.AF78 96.68,61.98 96.68,62.99 U43.AF76 U43.AF74 96.74,64.09 v2(96.38,64.45) 96.02,64.09 U43.AH74 95.59,64.09 v2(95.33,64.35) 95.33,63.62 U43.AK75 U43.AK77 ; U20.C2 v2(155.49,112.23) ; v2(97.82,88.84) U43.AE19 U43.AG21 ; U43.CU1 U43.CU2 ; U43.CU2 U43.CR2 ; U43.AE64 97.27,68.94 96.95,68.94 96.64,68.63 v2(96.57,68.63) 96.34,68.63 U43.AH66 ; U43.L43 103.77,78.65 v2(103.48,78.36) U43.M45 103.16,77.79 v2(102.84,78.11) 102.22,77.49 U43.R46 ; U43.CA30 v2(80.2,84.37) ; v2(80.2,84.37) U43.CC30 ; v2(80.2,84.37) U43.CB32 ; U43.CP12 75.03,92.78 75.29,92.78 U43.CM11 v2(76.24,92.95) ; U43.CP12 U43.CP14 ; U43.CP12 U43.CP9 75.25,93.8 v2(75.61,94.16) 75.61,94.18 U43.CP7 74.52,95.28 U43.CR5 ; U43.BW60 81.4,71.21 v2(81.19,71.21) ; U20.H3 v2(154.69,116.23) ; U43.D61 107.19,70.49 106.73,70.03 U43.E62 U43.E64 106.47,68.82 v2(106.47,68.54) 106.69,68.32 U43.E66 106.69,67.78 v2(106.14,67.23) ; U43.AR53 92.5,74.3 v2(92.5,74.85) 92.73,74.85 93.41,74.18 U43.AP53 ; U43.AA19 98.85,89.07 98.85,88.61 U43.AA21 99.61,88.44 v2(99.88,88.17) ; U20.AB22 138.37,127.83 v1(138.35,127.81) ; U43.CJ62 77.23,70.63 v2(77.23,70.63) ; U43.CJ62 U43.CG62 ; v2(100.51,86.92) 100.38,86.92 100.06,87.23 U43.W24 ; v2(100.51,86.92) 100.63,86.92 100.94,87.23 U43.U24 101.2,87.23 v2(101.49,87.53) ; v2(100.51,86.92) 100.51,86.92 U43.V26 100.5,86.37 100.73,86.37 v2(101.01,86.09) U43.U28 101.01,85.15 U43.V30 ; U43.E5 106.51,95.56 106.85,95.56 106.96,95.66 U43.D5 ; U43.E5 106.49,95.76 v2(106.02,96.24) 105.99,96.27 U43.F3 106.22,97 v2(106.22,97.46) 106.07,97.61 U43.F1 106.07,98.2 106.73,98.86 106.85,98.86 v2(106.98,98.98) ; U43.E5 106.27,95.35 106.02,95.35 v2(106.02,95.35) ; 91.83,73.38 v2(92.23,73.78) ; 91.83,73.38 v2(92.23,72.98) ; 91.83,73.38 U43.AU55 ; v2(92.23,73.78) 92.62,73.38 U43.AR55 93.01,73.77 v2(93.01,73.78) ; U43.CA11 v2(81.19,92.95) ; U43.CP27 75.39,85.87 v2(75.61,85.65) 75.61,85.49 U43.CP29 ; U43.CP27 U43.CP25 75.51,87.36 v2(75.51,87.45) 75.11,87.85 U43.CP23 U43.CP20 U43.CP18 75.07,89.83 75.61,90.38 ; U43.CP27 U43.CP29 ; U43.BB35 U43.BB33 88.72,83.04 U43.BD33 88.62,82.58 U43.BE35 U43.BG35 87.03,81.98 86.81,81.98 v2(86.64,81.81) 86.38,82.08 U43.BJ35 86.03,81.96 U43.BK37 ; v2(105.96,80.94) 105.97,80.92 U43.E38 ; v2(85.65,92.1) 85.37,92.38 U43.BM13 ; U43.CK30 v2(77.23,84.37) ; U20.F16 v2(143.49,114.63) ; v2(106.21,91.49) 106.54,91.82 U43.E14 ; U43.CB51 80.74,75.21 U43.CA51 ; U43.CR77 U43.CR78 U43.CU78 U43.CU77 ; U43.V14 100.12,91.14 v2(99.61,91.14) 99.61,90.96 99.91,90.67 ; U43.V14 100.72,91.52 v2(101.01,91.24) U43.U16 100.51,90.17 U43.V18 101.01,89.31 U43.U20 v2(101.01,88.34) 100.76,88.09 U43.V22 100.43,88.17 v2(99.88,88.17) ; U43.AV75 U43.AV77 91.35,62.07 v2(91.36,62.05) 91.73,62.05 91.84,61.94 U43.AU78 91.84,61.62 91.49,61.27 v2(91.31,61.27) ; U43.AV75 91.43,63.6 91.84,64.01 U43.AU74 91.61,64.09 v2(91.36,64.34) 91.66,64.64 91.82,64.64 U43.AU72 91.8,65.2 v2(91.59,65.2) U43.AV71 91.85,65.77 92.1,66.02 v2(92.1,66.03) 92.09,66.04 U43.AU69 ; U43.AV75 U43.AU76 ; U43.AE71 97.33,65.77 v2(97.04,66.05) ; U43.BN60 84.66,70.35 v2(84.66,70.35) 84.45,70.35 U43.BP62 ; v2(81.2,84.38) 81.48,84.66 U43.BW30 ; U43.CA51 80.7,74.84 U43.CA52 80.7,73.99 U43.BY54 ; U43.CA51 80.91,75.86 U43.CA49 80.7,76.13 v2(81.1,76.53) ; U43.CA51 81.45,74.51 U43.BW52 ; U43.CP72 74.57,64.64 74.42,64.64 74.16,64.38 74.16,64.22 74,64.06 v2(74,63.78) 74.24,63.78 74.57,63.45 74.57,63.12 74.92,62.77 U43.CP77 U43.CP78 ; U43.CP72 75.44,65.08 v2(75.56,65.2) ; U43.CP72 U43.CP70 U43.CT70 73.91,65.96 72.9,65.96 U43.CV70 72.32,66.07 v1(72.22,65.97) ; U43.CP72 75.01,64.49 U43.CN74 ; v2(84.42,64.32) 84.68,64.32 U43.BM74 ; U20.M12 v2(146.69,120.23) ; v2(108.92,61.92) U43.A77 U43.B76 ; U43.K60 U43.M60 ; U43.K60 U43.H60 105.47,70.92 v2(106.09,70.92) 106.2,71.02 U43.E60 ; U43.K60 103.98,71.41 U43.L58 ; U43.M60 U43.P60 U43.T60 101.35,71.07 100.72,71.07 U43.V60 100.62,70.96 v2(100.22,70.56) 100.24,70.56 U43.V62 100.62,69.91 v2(100.88,69.65) 100.51,69.27 U43.V64 ; U43.W16 99.91,90.67 ; 99.91,90.67 99.2,90.67 U43.AA16 ; U43.BP62 v2(84.17,69.49) ; v2(84.17,69.49) 84.45,69.2 U43.BN64 84.87,69.2 v2(85.16,69.49) 85.44,69.2 U43.BL64 85.8,69.2 v2(86.11,69.51) 86.42,69.2 U43.BH64 86.88,69.2 v2(87.17,69.49) 87.46,69.2 U43.BF64 ; U21.H1 v2(155.02,144.24) ; U20.A4 v2(153.89,110.63) ; U43.AM28 v2(94.62,84.84) U43.AM30 v2(94.65,84.01) ; v2(83.18,84.37) 82.89,84.66 U43.BU30 ; v2(81.45,95.55) 81.22,95.78 U43.CA5 80.72,95.55 v2(80.46,95.55) 80.23,95.78 U43.CC5 ; v2(81.45,95.55) 81.69,95.3 U43.BW7 ; v2(81.45,95.55) 81.68,95.78 U43.BW5 U43.BU4 U43.BU2 82.32,97.38 v1(82.32,98.4) ; U43.CP29 U43.CT29 ; U43.V35 v2(101.03,82.58) 101.39,82.94 U43.T33 ; U43.V35 101.01,81.79 101.02,81.79 v2(101.03,81.78) ; U43.V35 v2(100.22,81.78) ; U20.AA13 v2(145.89,127.43) ; v2(106.09,77.65) 106.11,77.65 106.41,77.95 U43.E44 ; U43.BR22 83.88,88.09 v2(84.17,87.8) ; v2(98.62,85.64) U43.AC27 U43.AA25 99.46,86.84 99.54,86.92 v2(99.57,86.89) 99.91,87.23 U43.W24 ; U43.E7 107.03,95.12 107.16,95.12 v2(107.16,95.12) ; U20.AB1 156.49,127.83 v2(156.51,127.81) ; v2(83.93,97.47) 83.92,97.47 U43.BP3 ; U43.BV62 82.47,70.35 v2(82.68,70.35) ; U43.CP14 U43.CP16 75.17,90.83 75.61,90.38 ; U43.CP14 75.17,91.82 v2(75.61,92.25) ; U43.BF56 87.78,72.58 v2(87.31,73.05) ; U21.M9 v2(151.83,137.84) ; v2(105.2,64.31) 104.98,64.09 U43.J74 ; v2(105.2,64.31) 104.97,64.55 U43.J72 ; U43.CV76 U43.CV77 ; U43.E18 106.33,89.83 v2(106.14,90.02) ; U43.E18 U43.E20 ; U43.E18 U43.E16 U43.E14 ; v2(105.96,74.07) 106.03,73.99 U43.E53 U43.E51 U43.E49 ; U43.E20 U43.C20 v2(108.38,88.84) U43.A20 108.94,88.82 v2(109.52,88.82) ; U43.E20 U43.E23 ; v2(106.09,86.16) 106.41,86.16 U43.E27 ; U43.E27 U43.E29 U43.E31 U43.E34 ; U43.E27 U43.E25 106.69,87.16 v2(106.49,87.36) 106.69,87.57 U43.E23 ; v2(97.02,90.44) U43.AG16 96.53,90.93 95.92,90.93 U43.AH16 ; U43.AL71 94.3,65.77 94.05,66.01 v2(94.05,66.04) ; v2(88.11,69.49) 87.54,70.06 U43.BG62 ; U43.AB5 98.77,95.48 v2(99.03,95.22) 99.58,95.78 U43.Y5 ; U43.CB58 80.2,71.41 U43.CA60 ; v2(85.65,93.81) 85.44,93.81 U43.BM9 ; U43.AU28 91.69,85.11 91.69,84.57 U43.AU30 91.69,84.31 91.69,83.82 91.61,83.74 91.61,83.62 v2(91.36,83.36) ; v2(88.88,89.31) 88.94,89.24 U43.BB19 ; v2(109.44,95.4) 109.2,95.15 U43.A6 U43.A5 ; U43.AU1 91.84,98.04 91.54,98.35 v2(91.54,98.48) ; U43.BY54 80.99,73.5 v2(80.7,73.21) ; U20.J11 v2(148.29,117.03) ; v2(84.16,84.35) 83.85,84.66 U43.BR30 ; U20.E6 v2(152.29,113.83) ; U43.BH5 87.19,95.48 v2(87.42,95.48) 87.53,95.48 87.83,95.78 U43.BF5 87.88,95.54 88.13,95.29 ; U43.BH5 86.86,95.81 85.93,95.81 U43.BK5 ; U43.BH5 U43.BH3 ; v1(69.47,92.21) 69.94,92.21 70.17,91.98 72.25,91.98 72.42,91.82 U43.CV14 73.06,91.7 73.91,91.7 U43.CT14 ; v2(149.09,127.43) U20.AA9 ; U43.L74 103.46,64.09 v2(103.2,64.35) 102.95,64.09 U43.N74 ; U43.BA28 89.84,84.86 v2(89.82,84.86) ; U43.BM20 85.44,88.66 v2(85.65,88.66) ; U43.AC58 v2(98.62,72.18) U43.AA56 ; U43.AC58 v2(97.82,72.18) ; U43.AC58 U43.AA60 98.9,70.85 98.9,70.3 U43.AA62 ; U43.CF11 v2(79.21,92.95) ; U43.C77 U43.C78 107.49,61.38 v2(107.56,61.32) ; v2(81.19,71.21) 80.91,70.92 U43.CA60 ; U20.U6 v2(152.29,124.23) ; v2(89.35,99.16) 89.25,99.16 88.87,98.78 U43.BD1 ; U20.A22 139.46,110.67 v2(139.49,110.67) ; v2(99.88,88.17) 100.02,88.03 U43.W24 ; v2(99.88,88.17) 99.36,87.64 U43.AA23 ; U43.E14 U43.E12 U43.E9 ; U43.E47 U43.E49 ; U43.E47 U43.D48 U43.B48 108.88,76.47 v2(108.89,76.48) ; U43.E47 U43.E44 ; U43.E49 106.15,75.97 v2(105.96,75.78) ; U43.BP69 v2(84.66,66.91) ; v2(99.54,92.67) 99.25,92.67 U43.AA12 ; U43.AC2 98.43,97.41 98.43,98.43 98.45,98.45 v2(98.47,98.45) ; U20.M4 v2(153.89,120.23) ; v2(105.46,72.09) 105.46,72.09 U43.H56 ; U43.BM74 85.18,64.09 v2(85.41,64.32) 85.64,64.09 U43.BK74 86.13,64.32 v2(86.4,64.32) 86.66,64.32 U43.BH74 87.16,64.09 v2(87.39,64.32) 87.65,64.32 U43.BF74 88.11,64.32 v2(88.35,64.32) 88.35,64.68 U43.BE72 ; U43.AH25 95.93,86.73 95.93,86.15 U43.AH27 v2(96.22,85.64) U43.AH28 U43.AH30 ; U43.CA71 v2(81.19,66.05) ; U43.BM58 85.36,71.78 v2(85.64,72.06) ; U43.BY69 v2(81.69,66.91) U43.CA67 ; U43.T33 101.01,83.43 U43.U32 v2(100.43,83.8) ; U43.T33 102.22,82.21 U43.R35 ; U43.CR5 75.12,95.66 U43.CN5 ; U43.CH22 v2(78.22,87.8) ; v2(149.89,119.43) 149.89,119.43 U20.L9 ; v2(82.68,86.94) 82.39,87.23 U43.BV24 ; U43.CP34 75.52,83.41 v2(75.52,83.51) 75.13,83.89 U43.CP31 ; U21.E9 v2(157.42,137.04) ; U43.CA26 v2(81.19,86.09) U43.BY28 ; U20.T16 v2(143.49,123.43) ; U43.E38 U43.E40 U43.E42 ; U43.E38 U43.E36 U43.E34 ; U43.E42 U43.E44 ; U43.E42 106.23,78.94 v2(105.96,79.22) ; U20.K12 v1(146.69,117.83) ; U43.CC11 v2(80.2,92.95) ; U43.CA78 80.95,60.92 v1(80.86,60.84) ; U43.L58 104.18,71.78 v2(104.49,72.09) 104.47,72.1 U43.K56 U43.H56 ; U43.L58 103.98,71.89 103.48,72.38 U43.M56 ; U43.AA12 U43.AC12 ; v2(86.64,66.91) 86.36,66.63 U43.BJ69 ; U43.BV69 v2(82.68,66.91) ; U43.CH75 U43.CJ74 v2(77.49,64.32) ; U43.CH75 U43.CG74 v2(78.48,64.32) ; U43.CH75 U43.CH77 ; U43.BW14 81.93,91.52 v2(82.22,91.24) ; U21.F1 v2(156.62,144.24) ; U43.AN76 U43.AN74 94.14,64.41 v2(94.36,64.41) ; U43.BM24 85.31,87.23 v2(85.62,86.92) 85.93,87.23 U43.BJ24 86.15,87.22 86.45,86.92 v2(86.65,86.92) 86.84,86.92 87.14,87.22 U43.BG24 ; U20.L13 v1(145.89,118.63) ; v2(82.34,78.03) 82.02,77.71 U43.BW45 ; U20.M2 v2(154.69,120.23) U20.M3 ; U43.CH18 v2(78.22,89.52) ; U43.AF9 97.27,94.1 v2(97.58,94.41) 97.58,94.91 U43.AE7 97.54,95.53 U43.AD5 U43.AF5 96.76,95.81 95.84,95.81 U43.AH5 U43.AH3 ; U43.AC18 v2(98.62,90.44) U43.AC16 ; v2(106.14,67.23) 106.31,67.06 U43.E68 U43.E70 ; U21.E8 v2(157.42,137.84) ; U43.C2 U43.C1 107.9,98 v2(108.5,98.6) ; U43.C2 U43.E2 U43.E1 107.39,98.6 v2(107.62,98.6) ; U43.BD14 88.21,91.11 87.27,91.11 v2(87.14,91.24) U43.BH14 ; U20.V8 v2(150.69,125.03) ; U21.E1 v2(157.42,144.24) ; U43.CG62 v2(78.22,69.49) U43.CH64 ; U43.CR2 U43.CP2 U43.CP1 ; U43.V1 100.75,98.38 v2(100.88,98.51) ; U20.C1 155.89,112.63 v2(156.29,113.03) U20.D1 ; v2(103.25,95.5) 103.48,95.27 U43.M7 103.48,94.59 U43.L9 103.98,93.74 U43.M11 103.69,93.24 v2(104,92.93) 104.05,92.88 104.05,92.46 U43.L13 103.79,92.38 v2(103.48,92.08) U43.M14 103.98,91.03 U43.L16 103.87,90.67 103.48,90.28 U43.M18 103.48,89.27 103.81,88.95 U43.L20 103.48,88.45 U43.M22 ; v2(103.25,95.5) 102.98,95.78 U43.N5 102.5,95.78 v2(102.21,95.48) 101.91,95.78 U43.T5 101.54,95.78 101.08,95.32 v2(101.04,95.32) ; v2(103.25,95.5) 103.25,95.53 103.49,95.78 U43.L5 103.72,95.98 104.01,96.27 U43.K4 ; v2(80.7,73.21) 80.41,73.5 U43.CB54 ; U21.H9 v2(155.02,137.04) ; U43.CH67 v2(78.22,67.77) ; v2(144.83,119.43) 144.29,119.43 U20.M16 ; v2(89.35,98.48) 89.3,98.43 89.3,97.59 89.37,97.52 U43.BB2 U43.BA3 ; v2(102.96,86.08) 102.96,86.09 103.25,86.37 U43.M26 103.48,86.74 U43.L24 103.72,87.23 103.47,87.48 103.47,88.08 U43.M22 ; v2(94.64,70.59) 95.02,70.97 U43.AK60 95.03,70.98 v2(95.44,70.57) ; v2(96.22,90.44) U43.AH18 95.73,89.95 95.73,89.34 U43.AH19 U43.AK19 95.02,89.22 v2(94.64,88.83) U43.AM19 94.08,89.1 93.57,89.1 U43.AP19 U43.AR19 92.46,89.08 91.99,89.08 U43.AU19 ; 95.02,93.47 94.39,94.1 U43.AM9 94.57,94.59 U43.AL7 ; 95.02,93.47 v2(95.06,93.47) ; 95.02,93.47 94.8,93.47 U43.AL11 94.57,93.11 95.02,92.65 U43.AK12 95.14,92.56 95.71,92.56 U43.AH12 U43.AG12 v2(97.02,92.04) U43.AE14 U43.AC12 ; v2(81.1,76.53) 81.52,76.11 U43.BW49 U43.BW50 81.69,75.21 U43.BW52 ; v2(108.43,64.47) 108.21,64.24 U43.B74 ; v2(91.59,70.35) 91.88,70.06 U43.AU62 ; U21.K9 153.03,137.41 v2(151.81,136.2) ; v2(92.23,72.98) U43.AR56 ; v2(92.23,72.98) U43.AU56 92.09,72.31 U43.AU58 v2(92.09,71.21) ; U20.K14 v1(145.09,117.83) ; U20.G19 v2(141.09,115.43) ; v1(72.02,97.53) 72.27,97.29 U43.CV2 U43.CV3 U43.CV5 U43.CV6 ; U20.M6 v2(152.29,120.23) ; U43.BH30 86.47,84.66 v2(86.16,84.34) 85.85,84.66 U43.BL30 ; v2(85.65,66.91) 85.37,66.63 U43.BM69 ; v2(84.67,72.03) 84.67,72.53 U43.BN56 U43.BL56 85.72,72.87 v2(85.72,73.3) ; v2(158.22,138.64) U21.D8 ; U43.R37 U43.T39 101.42,80.59 v2(101.03,80.98) ; U20.J12 v1(146.69,117.03) ; U43.BH60 86.43,70.92 v2(86.15,71.21) 86.15,71.21 86.15,71.3 86.15,71.3 U43.BJ58 ; v2(92.09,71.21) U43.AU62 ; v2(92.09,71.21) 92.3,71.21 U43.AR60 ; U43.AU62 91.59,69.57 U43.AV64 91.59,68.68 v2(91.61,68.66) 91.82,68.66 92.09,68.38 U43.AU66 v2(92.09,67.21) 91.87,67.21 U43.AV67 ; U43.CE74 v2(79.47,64.32) ; U43.BR18 v2(84.17,89.52) ; v2(101.04,95.32) 101,95.32 100.75,95.56 U43.V5 U43.V3 ; U20.G6 v2(152.29,115.43) ; U43.CV29 72.74,84.84 72.01,84.84 v1(71.9,84.73) ; U43.N74 U43.N76 ; U43.CM1 75.63,97.71 75.53,97.6 75.53,97.08 75.34,96.9 75.34,96.56 76,95.9 U43.CL5 v2(76.5,95.55) ; U20.AA7 v2(151.49,127.43) ; U43.CH30 v2(78.22,84.37) ; U43.E58 106.52,72.01 105.9,72.64 U43.H56 ; v2(103.02,80.91) 103.33,81.22 U43.M37 ; U43.CE3 U43.CE5 79.2,95.55 v2(79.47,95.55) ; U43.AK16 v2(94.62,90.44) ; U43.CC37 v2(80.2,80.94) ; U43.BF71 87.71,65.81 v2(88.13,66.05) 88.13,66.06 U43.BE69 ; U43.BP24 83.95,87.23 v2(83.66,86.94) 83.18,87.23 U43.BT24 ; U20.M1 v2(156.29,120.23) ; U43.CK11 v2(77.23,92.95) ; U43.CD16 v2(79.71,90.38) ; U43.CL74 v2(76.5,64.32) ; U20.N13 v2(145.89,121.03) ; U21.T1 v2(147.83,144.24) ; U43.AP23 v2(93.81,87.25) ; U43.BD5 88.62,95.78 88.13,95.29 ; U20.E8 v2(150.69,113.83) ; v2(86,98.68) 85.9,98.58 U43.BK1 ; v2(99.01,67.79) 99.02,67.77 U43.AA69 99.33,66.63 99.87,66.09 100,66.09 100.32,65.77 U43.V71 ; U20.G2 v2(155.49,115.43) ; U43.BE9 88.13,94.64 v2(88.13,94.65) 88.13,95.29 ; U20.M5 v2(153.09,120.23) ; U43.BE75 U43.BF76 U43.BE77 88.4,62.58 88.4,61.93 v2(88.37,61.9) 88.34,61.87 U43.BF78 ; U20.T7 151.18,123.11 151.81,123.11 U20.T6 151.89,122.99 v2(151.51,122.61) ; U43.CM30 v2(76.24,84.37) ; U43.J3 U43.K4 ; v2(81.69,86.94) 81.68,86.95 U43.BY24 ; v2(84.17,91.24) 83.88,91.52 U43.BR14 ; U21.C9 v2(159.02,137.04) ; 75.61,90.38 v2(75.61,90.4) ; v2(108.38,60.88) 108.21,61.06 U43.B78 U43.B77 ; U21.E3 156.63,142.64 v2(156.62,142.64) ; U43.CG69 v2(78.72,66.91) ; U20.M17 v2(142.69,120.23) ; U21.A8 160.62,137.84 v2(160.8,137.84) ; U20.K10 v2(149.09,117.83) ; U43.M22 103.25,88.09 v2(102.94,87.78) ; v2(82.65,92.07) 82.34,92.38 U43.BV13 ; U20.K11 v2(148.29,117.83) ; U20.N12 v2(146.69,121.03) ; U20.AA11 v2(148.29,127.43) ; U20.M13 v2(145.89,120.23) ; U20.D2 v2(155.49,113.03) ; U21.N1 v2(150.23,144.24) ; U43.CJ5 v2(77.49,95.55) ; U43.AW9 91.1,93.14 90.6,92.63 90.42,92.63 U43.BA12 90.23,92.44 v2(90.63,92.04) 90.62,92.03 90.62,91.24 U43.BA16 ; U43.L39 103.77,80.36 v2(103.48,80.08) U43.M41 102.5,79.5 U43.R40 U43.R42 v2(101.82,78.58) ; U20.V10 v2(148.29,124.23) U20.U11 ; v2(103.48,83.51) 103.48,82.94 U43.M33 103.45,82.91 103.46,82.9 103.46,81.82 v2(103.48,81.79) 103.77,82.08 U43.L35 ; U20.G1 v2(156.29,115.43) ; U20.M9 v2(149.89,120.23) ; U20.N10 v2(149.09,121.03) ; v2(151.49,112.23) U20.C6 ; U43.CG66 v2(78.72,68.63) ; U20.J10 v2(149.09,117.03) ; U20.M14 v2(145.09,120.23) ; U43.CG16 v2(78.72,90.38) ; v2(75.75,81.79) 75.41,81.79 75.29,81.91 U43.CP36 U43.CR37 74.41,81.31 73.63,81.31 U43.CU37 ; U20.J13 v1(145.89,117.03) ; U21.B2 v2(159.82,143.44) ; U43.AU5 91.68,95.78 91.4,95.49 v2(91.4,95.48) 91.39,95.48 91.09,95.78 U43.AW5 ; U20.J21 v2(139.49,117.03) ; U43.CF30 v2(79.21,84.37) ; U43.BM16 85.37,90.67 v2(85.65,90.38) 85.87,90.38 86.28,89.97 86.48,89.97 U43.BH18 ; U20.C3 v2(154.69,112.23) ; U43.CG28 v2(78.72,85.23) ; U20.H4 v2(153.89,116.23) ; U20.J14 v1(145.09,117.03) ; U20.M7 v2(151.49,120.23) ; U43.CG24 v2(78.72,86.94) ; U43.BT69 v2(83.67,66.91) ; U43.BY66 v2(81.69,68.63) ; U20.L14 v1(145.09,118.63) ; U43.B61 v2(108.91,70.53) 109.27,70.53 109.52,70.28 ; U43.CG72 v2(78.72,65.2) ; U20.V12 v2(146.69,125.03) ; U21.G8 v2(155.82,137.84) ; U43.CA22 v2(80.2,87.8) ; U43.BY72 v2(81.69,65.2) ; U43.CH26 v2(78.22,86.09) ; U43.BA56 90.23,72.41 v2(90.6,72.04) ; U20.L11 v2(148.29,118.63) ; U20.V16 v2(143.49,125.03) ; U43.AE23 v2(97.02,87.24) ; U21.A2 v2(160.62,143.44) ; U21.K1 v2(152.63,144.24) ; U43.CG5 v2(78.48,95.55) ; U20.K13 v1(145.89,117.83) ; v2(80.46,64.32) U43.CC74 ; U43.CL16 v2(76.74,90.38) ; U43.CG20 v2(78.72,88.66) ; U20.L12 v1(146.69,118.63) ; v2(96.22,70.58) U43.AG62 ; U43.CJ16 v2(77.73,90.38) ; U20.H6 v1(151.49,116.23) ; U43.CH11 v2(78.22,92.95) ; U43.CR21 U43.CU21 ; v2(80.2,79.22) U43.CC41 79.92,79.5 v2(80.2,79.22)
  TOP w0.229: U2.K9 v1(82.71,136.23) ; v1(83.71,137.23) U2.J10 ; U2.G9 v1(82.71,140.23) ; U2.A1 v1(73.71,146.23) ; C114.1 v1(181.78,151.16) ; v1(173.02,99.62) 173.03,99.63 J3.33 ; J3.57 179.03,99.79 v1(178.23,98.98) 177.53,99.68 J3.51 ; U2.B2 v1(74.71,145.23) ; v1(176.03,98.98) J3.45 ; U2.H7 v1(79.71,139.23) ; U2.R15 v1(88.71,131.23) ; U2.A16 v1(89.71,146.23) ; R231.2 v1(183.18,151.16) ; U2.G10 v1(83.71,140.23) ; U2.K8 v1(80.71,136.23) ; U2.K7 v1(79.71,136.23) ; U2.G8 v1(80.71,140.23) ; v1(184.83,155.5) 184.97,155.64 U8.20 ; U2.K10 v1(83.71,136.23) ; U2.J8 v1(80.71,137.23) ; U2.H9 v1(82.71,139.23) ; U2.R2 v1(74.71,131.23) ; U2.B15 v1(88.71,145.23) ; U7.20 v1(191.7,38.9) ; U2.T16 89.71,131.23 v1(89.71,131.23) ; U2.G7 v1(79.71,140.23) ; R230.1 v1(184.58,151.16) ; U2.T1 v1(73.71,130.23)
  TOP w0.254: U43.CU78 72.59,61.87 v1(72.58,61.85) 72.58,62.37 U43.CV77 ; v1(78.15,36.75) 78.02,36.88 77.62,36.88 R363.2 ; J8.106 25.45,87.53 v1(25.69,87.76) ; R358.2 126.92,50.47 v1(127.05,50.6)
  TOP w0.279: J3.39 174.53,99.99 174.16,99.62 v1(173.02,99.62) ; J3.27 171.53,99.27 v1(170.86,98.6) ; J3.3 165.53,99.5 v1(165.27,99.24) 165.03,99.48 J3.1 ; J3.75 183.53,99.84 183.18,99.49 182.62,99.49 v1(182.55,99.57) ; J3.71 182.53,100.05 182.48,100 182.48,99.63 v1(182.55,99.57) ; v1(182.55,99.57) 183.03,100.06 J3.73
  TOP w0.305: v1(112.82,99.11) 112.83,99.12 U51.8 ; U52.14 129.25,71.34 129.82,71.91 v1(129.84,71.91) ; J3.9 167.03,99.26 v1(167.05,99.24) ; v1(133.14,74.47) 133.26,74.59 U52.8 ; U50.14 121.16,109.1 v1(121.2,109.14) ; v1(118.92,105.33) 119.44,105.85 U50.9 ; U52.9 129.85,74.59 v1(129.97,74.47) ; U51.9 v1(118.8,99.12) ; v1(118.89,110.01) 119.15,109.75 U50.15 ; U55.9 v1(117.31,60.71) ; v1(129.69,70.41) 129.41,70.69 U52.15 ; U55.15 121.21,58.35 v1(120.82,57.96) 120.56,58.23 U55.14 ; v1(146.48,73.13) 146.92,73.13 147.38,73.6 U58.8 ; J3.15 168.53,99.28 v1(168.58,99.24) ; v1(71.93,35.6) 70.67,35.6 70.4,35.87 70.4,37.77 70.75,38.11 U54.4 ; J3.21 v1(170.03,98.54) ; v1(117.65,63.81) 117.31,64.14 U55.8
  TOP w0.33: v1(141.27,67.23) 141.55,67.51 U59.9 ; U45.4 121.96,126.15 121.97,126.16 v1(121.99,126.16) ; v1(115.36,105.33) 114.84,105.85 U50.8 ; U1.4 152.31,100.37 v1(152.32,100.38) ; v1(127.81,103.96) 127.97,103.8 U56.4 ; U51.15 118.84,103.02 v1(118.54,102.72) 118.88,102.37 U51.14 ; v1(141.91,76.76) 141.91,76.12 141.55,75.77 U59.8 ; v1(147.24,67.23) 147.38,67.37 U58.9 ; U58.14 150.63,67.15 v1(150.67,67.11) ; U59.15 145.45,67.6 v1(145.21,67.36) 144.8,67.77 U59.14 ; v1(151.68,67.11) 151.28,67.51 U58.15 ; v1(130.48,114.35) 129.84,113.72 129.59,113.72 129.4,113.9 129.4,114.35
  TOP w0.381: C223.2 155.85,72.9 v1(155.62,73.13) ; J1.10 82.95,158.78 v1(82.72,158.55) ; v1(124.13,52.27) 124.13,52.76 125.14,53.77 125.14,61.14 132.25,68.25 132.25,76.63 v1(132.38,76.76) 132.38,77.95 138.6,84.18 138.6,88.39 v1(138.1,88.9) 137.39,89.6 135.73,89.6 135.35,89.22 v1(135.35,88.98) 135.35,88.39 137.11,86.64 137.11,84.66 130.75,78.31 v1(130.75,76.76) 130.86,76.65 130.86,69.01 123.74,61.9 123.74,54.66 122.22,53.14 122.22,51.11 123.49,49.84 124.51,49.84 v1(124.63,49.96) ; C337.2 118.28,11.46 v4(118.82,10.92) ; v1(95.43,106.22) 95.42,106.22 95.32,106.32 C588.2 ; C180.2 121.74,147.9 v1(121.46,147.63) ; v1(99.36,106.22) 99.97,106.83 C587.2 ; C775.2 86.79,43.36 ; v1(151.56,99.62) 151.2,99.26 C6.1 ; R367.2 v1(64.69,31.9) ; R256.2 185.06,133.71 v1(185.49,133.27) ; C185.2 81.47,120.59 81.48,120.57 C765.2 80.7,119.8 v1(80.44,120.07) ; C769.2 134.67,37.39 ; v1(68.25,151.05) 68.12,150.93 D18.2 ; R247.2 v1(183.69,142.16) ; C425.2 135.96,16.66 135.3,17.32 ; C431.2 v1(170.48,28.75) ; C19.2 154.66,97.13 v1(154.35,96.83) ; R646.2 116.35,15.44 v1(116,15.8) ; 114.09,17.45 114.6,17.45 115.11,16.94 C358.2 ; R810.2 v1(105.05,115.01) ; v1(146.1,162.36) 147.14,162.36 C94.2 147.39,161.37 v1(147.11,161.09) ; C369.2 116.48,20.47 116.25,20.24 v1(116.25,19.86) ; C729.2 69.46,30.05 v1(69.67,30.25) ; v1(164.89,102.29) 164.32,102.29 163.93,101.9 J3.76 ; C587.2 100.63,107.11 ; C587.2 99.97,107.52 99.49,108 ; R930.2 114.85,63.68 v1(115.87,62.66) ; U41.10 112.82,148.9 v1(111.3,147.37) ; v1(132.13,161.72) 132.25,161.6 R210.2 ; v1(124,106.6) 124,106.73 123.62,107.11 R1078.1 ; R948.2 R949.2 114.96,60.63 v1(114.98,60.66) ; v1(166.42,16.31) 166.44,16.28 C224.2 ; C232.2 122.86,40.95 v1(122.73,40.82) ; R580.1 R537.1 v1(162.48,119.18) ; C696.1 120.93,55.83 v1(120.82,55.93) ; R464.2 v1(140.64,149.53) ; R1032.1 v1(100.71,133.78) ; v1(112.19,135.69) 112.44,135.69 112.82,136.07 U39.10 ; R322.2 119.55,74.85 v1(119.93,74.47) ; 155.37,52.63 155.88,53.14 C474.2 ; v1(114.98,146.86) U42.4 ; R575.2 C307.2 161.97,107.21 162.35,107.59 v1(162.35,108) ; C21.2 136.98,102.01 v1(137.84,101.14) 137.82,101.12 R333.1 ; v1(171.12,117.53) 171.12,117.78 171.47,118.14 C286.2 ; v1(80.06,24.59) R756.2 ; R1066.1 133.93,67.08 v1(134.64,67.79) 134.31,67.79 133.93,68.17 C689.1 ; C812.2 v1(112.57,157.66) ; v1(100.76,139.24) 100.88,139.37 C257.2 C679.1 ; v1(171.24,128.52) R45.2 C11.1 ; J1.2 72.79,158.52 v1(72.69,158.42) ; C174.2 v1(139.11,60.88) ; R902.1 v1(101.39,53.52) ; C197.2 v1(148.64,62.28) ; C701.1 146.78,77.88 v1(146.94,77.72) ; R355.2 123.14,45.29 123.36,45.52 ; v1(169.46,116.64) 169.31,116.79 C274.2 ; v1(161.21,99.85) 160.8,100.25 C20.1 ; R371.1 v1(132.76,113.97) ; C55.2 181.66,90.09 v1(181.1,89.54) ; v1(182.8,49.07) C112.2 ; v1(107.25,55.93) 106.83,56.35 R1165.1 ; C130.2 167.31,153.09 v1(166.92,153.47) ; C427.2 v1(175.43,34.47) ; R376.1 130.67,116.13 v1(130.48,116.32) ; 155.24,43.23 155.88,43.87 C454.2 ; v1(76.25,35.74) 75.33,35.74 C693.2 ; 116.25,50.6 118.66,50.6 120.19,49.07 120.19,46.41 v1(120.82,45.77) ; C276.2 173,115.85 v1(172.64,115.49) ; C202.2 137.08,53.65 v1(136.44,54.28) ; R308.2 v1(175.08,70.03) ; v1(182.55,117.15) 183.31,116.38 C66.2 ; R1106.1 144.34,77.88 v1(144.06,78.16) ; C296.2 R589.2 162.2,111.28 162.25,111.33 v1(162.35,111.33) ; R947.2 R956.2 R955.2 114.98,71.93 v1(115.24,72.19) ; C758.2 58.37,146.25 v1(58.97,146.86) ; v1(25.07,26.26) C77.2 ; D17.2 64.94,151.05 v1(64.56,151.44) ; v1(98.34,118.24) 99.01,117.58 C595.1 ; v1(87.68,115.11) 87.55,115.24 R285.2 ; v1(111.17,109.22) 110.69,109.7 R1057.1 C685.1 ; C206.2 136.44,57.96 v1(136.32,57.84) ; C386.2 103.17,16.56 102.41,17.32 ; C767.2 96.82,49.58 ; C772.2 126.29,46.28 v1(126.28,46.28) ; v1(131.24,57.33) 130.7,56.79 C168.2 ; R749.1 91.49,24.94 v1(91.74,25.2) ; 109.5,104.72 C590.2 v1(108.76,104.06) ; R1164.1 v1(90.6,117.4) ; 107.13,155.4 C813.2 106.22,156.13 ; C698.2 127.05,109.45 v1(126.82,109.22) ; v1(149.02,104.7) C258.2 R548.2 ; v1(186.53,149.53) 186.15,149.91 C150.2 ; R361.1 112.82,95.56 v2(112.44,95.94) ; R925.2 105.58,102.29 ; v1(80.44,115.73) R898.1 78.43,115.73 77.83,116.32 Q36.2 ; R897.2 96.69,118.85 96.22,118.38 v1(96.22,118.22) ; Q2.2 160.32,95.17 v1(159.94,95.56) ; C771.2 125.14,46.03 v1(125.4,46.28) ; v1(165.91,50.98) 165.91,51.36 165.53,51.74 C189.2 ; C810.2 v1(113.36,161.72) ; v1(132.76,55.19) 132.41,55.55 C171.2 ; C2.2 v1(201.21,83.24) ; C697.2 v1(125.8,106.58) ; R1218.2 v1(60.5,126.8) ; v1(110.66,101.57) 110.69,101.6 R1065.1 C687.1 110.03,103.56 ; v1(178.23,88.82) 178.99,89.59 R163.2 ; v1(98.22,121.21) 98.47,120.96 R1007.1 ; C9.1 v1(145.72,95.3) ; C462.2 158.06,46.18 ; C462.2 158.92,45.14 ; C462.2 159.79,46.18 ; v1(186.99,145.34) 186.61,144.96 R246.1 ; v1(184.32,103.3) 184.63,102.99 J3.77 ; C699.2 137.94,106.58 138.35,106.99 v1(138.35,107.52) ; C781.2 186.25,13.11 ; C781.2 187.98,13.11 ; C781.2 187.12,13.89 ; C129.2 167.18,151.56 v1(166.92,151.31) ; R649.1 120.82,11.23 v4(120.95,11.1) ; R237.1 v1(158.16,162.36) ; v1(172.64,114.48) R606.1 C285.2 ; v4(168.86,25.68) 168.78,25.6 R695.1 ; v1(158.25,13.94) 158.25,14.36 158.52,14.63 R315.2 ; C773.2 128.32,47.68 ; v1(50.97,128.83) 51.03,128.89 Q39.2 ; v1(191.74,103.21) 192.03,102.92 R191.2 ; C482.2 v1(54.4,21.39) ; C113.2 v1(198.55,38.02) ; v1(122.09,48.85) 122.09,49.33 119.3,52.12 96.06,52.12 95.17,53.01 94.41,53.01 v1(94.03,53.39) ; R276.2 v1(123.77,158.27) ; C774.2 129.46,47.68 ; v1(191.74,96.86) 192.72,97.84 R185.1 ; C270.2 v1(169.69,110.52) ; v1(182.67,20.88) C785.2 ; R792.1 v1(107.49,53.52) ; C430.2 v1(161.84,34.98) ; v1(90.52,124.18) 90.5,124.18 90.47,124.21 R14.2 ; C776.2 86.66,44.37 ; v1(126.03,119.41) 125.68,119.05 R1158.1 ; C281.2 v1(169.36,123.72) ; v1(124,110.29) 123.87,110.16 R1077.1 C686.1 ; R319.2 122.6,74.73 v1(122.35,74.47) ; C562.2 101.55,129.72 v1(101.27,130) ; v1(114.85,97.38) 114.65,97.59 C236.2 ; v1(130.48,114.35) 130.86,113.97 R374.1 ; v1(185.97,135.84) 185.97,135.84 185.7,135.56 R257.1 ; C778.2 v1(59.48,29.01) ; C464.2 v1(131.85,54.38) ; v1(152.07,95.3) 151.81,95.05 C7.1 ; v1(137.21,147.75) 137.18,147.73 C178.2 136.32,148.39 v1(136.57,148.64) ; v1(164.51,24.69) 164.51,25.25 C428.2 165.4,25.12 v1(165.4,24.69) ; v1(183.43,113.59) 183.84,114 C67.2 C63.2 ; R327.1 R326.1 125.4,98.35 v1(125.14,98.1) ; C183.2 94.69,121.23 v1(95.17,121.72) ; C12.1 148.76,95.17 v1(148.89,95.3) ; v1(153.23,104.7) 153.08,104.85 R549.2 ; U16.1 v1(140.71,59.11) ; R698.1 v4(166.67,25.58) ; C444.2 158.44,35.38 ; C444.2 157.76,36.27 ; C444.2 159.08,36.27 ; v1(123.49,74.5) 123.49,74.85 123.62,74.98 C228.1 ; C207.2 C210.2 C211.2 151.94,57.58 v1(152.07,57.71) ; C137.2 160.09,159.97 v1(160.07,159.94) ; R324.2 117.52,74.85 v1(117.9,74.47) ; v1(151.94,160.58) 151.48,161.04 R236.1 ; v1(143.94,159.94) 143.28,160.6 C84.2 ; R1161.2 R1160.1 124.02,115.34 v1(124.38,115.7) ; C204.2 136.95,56.44 v1(136.44,55.93) ; Q15.2 v1(191.05,146.23) ; v1(172.64,73.06) 172.02,72.44 R309.2 ; R206.2 v1(36.75,33.83) ; v1(153.46,92.51) 153.72,92.76 C4.1 154.12,92.28 154,92.15 R31.2 ; R377.1 v1(132.76,116.13) ; R611.2 166.16,86.03 167.31,87.17 v1(167.31,88.57) 166.8,89.08 C265.2 ; C176.2 v1(139.11,62.28) ; R222.2 v1(187.37,39.04) ; R293.1 173.4,61.39 v1(173.53,61.27) ; C175.2 v1(139.11,59.49) ; R996.2 v1(85.52,106.73) ; v1(134.54,152.83) 134.51,152.83 C18.1 ; v1(143.3,53.65) 143.18,53.52 C203.2 ; R1174.1 v1(83.49,114.1) ; U46.4 v1(108.5,122.1) ; C429.1 v4(168.07,27.89) ; v1(101.27,130.91) 101.44,130.73 C683.1 ; C498.2 v1(93.01,21.26) ; C816.2 v1(46.27,133.66) ; v1(173.61,63.93) 172.92,64.62 R307.2 ; R1215.2 v1(189.53,3.63) ; C426.2 v1(161.84,39.29) ; C787.2 v1(181.28,20.88) ; C76.2 v1(36.75,32.44) ; 98.98,162.36 R1232.1 v1(98.12,161.57) ; U64.1 v1(101.65,161.98) ; D20.2 v1(191.64,56.36) ; R790.1 v1(110.54,53.52) ; R652.1 v4(119.55,11.66) ; v1(136.44,55.17) 136.57,55.04 C205.2 ; v1(59.48,30.02) 59.36,30.15 C777.2 ; v1(90.72,151.31) 90.92,151.5 Q5.2 ; R1248.1 v1(51.48,133.53) ; v1(172.51,142.16) 172.41,142.27 C145.2 172,143.05 171.62,142.67 v1(171.62,142.16) ; Q4.2 v1(200.89,86.98) ; R261.1 R260.2 125.93,52.91 125.52,52.5 v1(125.52,52.25) ; C231.2 109.14,46.28 v1(109.27,46.15) ; v1(129.84,159.03) 129.43,159.44 Q20.2 ; R1096.1 125.01,67.06 v1(124.53,67.54) ; U40.4 112.42,134.04 v1(112.04,134.42) ; 187.12,14.4 R1211.1 ; C473.2 149.93,52.15 v1(149.78,51.99) ; C408.2 127.94,13.39 ; C408.2 128.85,12.6 v1(129.08,12.37) ; C408.2 128.85,14.12 ; v4(120.19,14.4) 120.82,15.04 C338.1 ; C262.2 v1(139.72,138.2) ; 78.15,17.32 78.53,17.32 78.91,16.94 C514.2 ; v1(166.8,111.3) 166.8,110.41 166.57,110.19 C287.2 ; 103.55,156.13 C807.2 102.64,155.4 ; R793.1 v1(108.5,53.52) ; v4(58.47,13.13) R735.1 ; R1233.1 100.38,162.36 ; R1076.1 98.34,53.9 97.96,53.52 v1(97.58,53.52) 97.33,53.77 R922.1 ; C53.2 182.67,89.28 v1(183.03,88.93) ; v1(159.94,115.11) 160.45,114.61 R630.1 ; C154.2 161.87,148.49 162.48,147.88 v1(163.11,147.88) ; R785.1 v1(104.44,53.52) ; C768.2 107.62,49.45 ; v1(151.68,92.51) 151.81,92.38 C8.1 ; R111.2 v1(73.07,152.07) ; C453.2 v1(153.95,43.54) ; C567.1 100.88,142.42 v1(100.76,142.29) ; R1114.1 149.78,64.47 v1(149.75,64.44) ; C582.2 115.85,67.39 v1(115.36,67.87) ; C140.2 v1(163.5,151.69) ; C613.2 73.07,127.05 v1(73.45,127.43) ; R795.1 v1(102.41,53.52) ; C695.1 v1(124,67.03) ; R585.2 v1(155.37,104.7) ; v1(124.51,46.28) 124,45.77 C233.2 ; R43.2 v1(144.7,95.3) ; Q35.2 v1(116.89,153.98) ; C483.2 62.05,15.19 v1(62.02,15.16) ; C62.2 183.56,117.4 v1(183.18,117.78) ; v1(58.34,133.78) 58.27,133.85 Q37.2 ; 90.22,16.94 90.75,16.41 C497.2 ; U27.4 157.91,85.78 158.29,86.16 v1(158.29,88.34) ; v1(150.92,160.58) 151.48,160.02 R239.1 ; C81.2 22.17,30.81 ; C81.2 22.78,30.15 ; C81.2 23.52,30.81 ; R44.2 v1(164.89,131.75) ; C16.1 138.5,98.96 v1(138.6,98.86) ; v1(103.55,25.32) R675.1 ; v1(129.21,135.69) 128.95,135.43 U25.4 ; C5.1 v1(147.75,92.51) ; v1(184.7,31.42) 185.34,32.06 R217.1 ; v1(171.37,111.43) 171.62,111.18 R605.1 C269.2 ; Q16.2 v1(194.16,147.31) ; C271.2 168.35,118.9 v1(167.94,119.3) ; C10.1 v1(164.89,130.73) ; R1113.1 147.67,65.23 147.14,64.69 v1(147.14,64.57) ; R668.1 114.6,25.71 v1(113.97,26.34) ; C770.2 134.67,38.4 ; C513.2 80.29,21.36 v1(80.31,21.39) ; v1(46.27,125.53) 46.25,125.55 R1249.2 ; v1(67.48,29.39) 67.61,29.52 C506.2 ; R299.1 v1(149.02,60.88) ; C268.2 v1(166.39,117.75) ; R226.1 v1(191.05,151.56) ; C284.2 163.85,116.79 163.75,116.89 R631.1 162.33,118.01 v1(162.35,118.03) ; C566.2 v1(118.82,140.36) C565.2 ; R328.1 125.8,101.75 124.89,102.67 v1(124.89,102.72) ; v1(144.7,92.51) C3.1 ; R692.2 162.25,28.78 v1(162.23,28.75) ; v1(60.63,131.62) 60.57,131.68 Q38.2 ; C700.2 127.48,122.58 v1(127.55,122.5) ; 131.75,134.16 130.6,134.16 v1(130.22,133.78) ; C481.1 v4(59.74,14.3) ; C275.2 C277.2 v1(172.64,116.38) ; v1(116.76,18.85) 116.99,19.08 C339.2 ; C253.2 v1(140.64,147.5) ; C230.2 v4(61.01,12.75) ; v1(116.25,71.81) 116.12,71.68 C583.2 ; C817.2 v1(48.81,133.66) ; C75.2 31.9,34.06 v1(32.05,34.21) ; C1.2 198.93,81.2 v1(198.67,81.46) ; R42.2 v1(150.8,92.51) ; v1(171.5,131.62) 171.5,132.13 171.88,132.51 C157.2 172.28,131.72 v1(172.39,131.62) ; C704.1 152.09,65.23 152.47,65.61 v1(152.6,65.61) ; D16.2 v1(61.59,150.09) ; v1(107.23,104.06) C589.2 106.37,104.72 ; C690.1 v1(124.63,68.76) ; v1(125.4,38.91) R351.2 ; v1(173.53,62.15) 173.02,62.66 R292.2 ; R346.2 v1(107.26,43.51) ; Q40.3 v1(45,132.26) ; v1(67.51,20.88) C479.2 ; C148.2 v1(186.61,148.39) ; C424.2 v1(135.45,18.87) ; R370.1 v1(132.76,114.99) ; C694.2 v1(63.04,35.1) ; v1(181.53,130.86) 181.15,131.24 R255.2 ; v1(33.83,26.21) C70.2 C71.2 v1(32.43,26.21) ; C811.2 v1(111.17,157.66) ; R929.2 105.58,103.3 ; v1(182.8,50.47) C111.2 ; R216.1 185.26,29.57 v1(184.7,29.01) ; J5.6 v1(138.98,12.12) ; v1(147.95,101.75) 148.03,101.83 C17.2 ; C478.2 55.57,24.71 v1(55.04,24.18) ; R946.2 94.03,56.31 v1(94.41,55.93) ; v1(151.05,153.59) 151.08,153.62 C134.2 ; R274.2 v1(129.84,159.94) ; v1(53.89,15.04) 54.33,15.04 C480.2 54.45,14.15 v1(53.89,14.15) ; U19.4 v1(127.81,97.59) ; R275.2 v1(121.08,144.83) ; R204.1 v1(28.75,26.72) ; C252.2 v1(140.64,146.48) ; v1(53.64,16.69) R729.2 ; C702.1 v1(146.22,64.57) ; v1(58.37,143.03) C760.1 C759.1 ; R235.2 v1(193.98,153.21) ; Q21.2 v1(122.92,160.65) ; v1(193.47,34.72) 193.34,34.6 R213.2 ; v3(104.95,22.66) 104.54,22.25 C397.2 ; U3.2 v1(93.52,137.72) ; C335.2 v1(118.16,25.45) ; U65.3 v1(47.54,136.58) ; R577.2 v1(158.42,104.7) ; R314.2 v1(159.94,15.29) ; R801.1 v1(114.85,57.58) ; R1238.2 v1(113.97,157.66) ; R1159.2 v1(125.95,118.03) ; v1(190.29,19.36) 189.86,19.36 R1214.2 189.73,18.47 v1(190.29,18.47) ; v1(81.56,114.1) 81.45,114 R903.1 ; C97.1 184.6,36.91 v1(184.58,36.88) ; v1(26.46,26.26) C72.1 ; R291.2 v1(167.31,54.41) ; C225.2 v1(162.12,15.32) ; R286.2 81.46,117.66 81.07,117.27 80.82,117.27 80.44,116.89 v1(80.44,116.64) ; R978.1 v1(82.47,109.91) ; C214.2 v1(167.15,65.05) ; C280.2 v1(173.27,122.99) ; R221.1 v1(187.5,37.64) ; C340.2 v1(123.11,15.16)
  TOP w0.508: C373.2 94.43,17.17 ; C373.2 95.78,17.17 ; C373.2 95.17,17.96 ; 106.73,18.21 106.3,17.78 106.3,15.88 105.69,15.27 R667.2 ; v1(169.46,140.89) 169.08,141.28 C166.2 ; 94.15,16.82 93.37,16.03 R674.2 ; 83.89,17.17 C487.2 v1(83.1,18.72) ; R748.2 81.56,15.39 82.22,16.05 82.22,16.94 ; 107.11,18.09 C345.2 107.97,17.17
  GND1 w0.406: SW1.1 203.11,72.44 ; SW1.1 201.34,74.21 ; SW1.1 199.58,72.44 ; SW2.1 201.34,65.19 ; SW2.1 199.58,63.42 ; SW2.1 201.34,61.66 ; SW2.1 203.11,63.42 ; 201.34,77.18 SW1.2 ; SW1.2 201.34,80.71 ; SW1.2 203.11,78.94 ; SW1.2 199.58,78.94 ; 199.58,69.92 SW2.2 ; SW2.2 203.11,69.92 ; SW2.2 201.34,68.16 ; 140.97,24.18 142.74,24.18 ; 140.97,24.18 140.97,22.4 ; 140.97,24.18 139.19,24.18 ; 140.97,24.18 140.97,25.96
  GND1 w0.635: 192.4,13.26 J4.1 ; J4.1 194.47,11.19 ; J4.1 194.47,15.33 ; 192.4,17.46 J4.2 ; J4.2 194.47,19.53 ; J4.2 194.47,15.39
  SIG1 w0.381: v1(164.26,37.8) 162.84,36.37 v1(162.48,36.37) v1(161.59,36.37) 152.19,36.37 144.45,44.12 126.41,44.12 125.4,45.14 124.51,45.14 122.98,46.66 122.98,47.96 v1(122.09,48.85) 121.75,48.85 120.7,47.8 120.7,45.9 v1(120.82,45.77) 122.98,43.61 124.63,43.61 125.65,42.6 143.94,42.6 151.56,34.98 v1(161.84,34.98) 163.62,34.98 v1(164.38,35.74) ; v1(57.32,25.45) 58.85,26.98 68.68,26.98 v1(69.95,28.25) 75.1,33.4 75.1,35.23 75.61,35.74 v1(76.25,35.74) 76.6,36.09 v1(76.6,38.53) 76.3,38.23 74.93,38.23 73.58,36.88 73.58,34.17 v1(69.67,30.25) 67.79,28.37 58.21,28.37 55.42,25.58 55.42,24.56 v1(55.04,24.18) ; v1(115.82,23.75) 115.82,25.53 v1(115.87,25.58) v1(115.87,28.75) v1(115.87,30.91) v1(115.87,33.2) 115.87,33.83 112.82,36.88 112.7,36.88 v1(111.17,38.41) v1(110.54,39.04) 108.76,40.82 v1(108.76,41.33) 108.76,43.36 106.98,45.14 106.98,45.9 105.2,47.68 96.57,47.68 v1(95.23,49.01) 94.22,49.01 93.77,49.45 93.77,50.85 94.28,51.36 94.94,51.36 96.97,49.33 v1(97.58,49.33) v1(99.87,49.33) v1(102.15,49.33) v1(104.44,49.33) 105.79,49.33 108.96,46.15 v1(109.27,46.15) 110.16,45.26 v1(110.16,43.87) 110.16,41.58 v1(110.41,41.33) 112.19,39.55 v1(112.31,39.55) v1(116.51,35.36) 117.65,34.21 v1(117.65,27.36) 117.65,25.96 v1(118.16,25.45) ; 123.77,52.27 123.24,51.74 123.24,50.19 123.59,49.84 124.51,49.84 v1(124.63,49.96) 126.16,48.44 135.81,48.44 137.61,46.63 155.39,46.63 156.64,45.39 159.13,45.39 161.29,43.23 167.18,43.23 169.08,41.33 v1(169.08,40.95) 169.72,40.31 170.35,40.31 170.68,40.64 170.68,42.65 170.35,42.98 v1(169.97,42.98) 169.72,42.98 168.07,44.63 v1(162.73,44.63) v1(161.84,44.63) 159.69,46.79 157.27,46.79 156,48.06 v1(155.49,48.06) v1(154.61,48.06) v1(153.72,48.06) 138.6,48.06 136.83,49.84 126.82,49.84 124.38,52.27 v1(124.13,52.27) 123.77,52.27 ; 123.92,27.03 123.06,27.03 122.86,27.23 v1(122.47,27.23) 122.22,27.23 v1(121.59,27.86) 121.59,39.68 v1(122.73,40.82) 124.23,39.32 v1(124.23,38.25) 123.11,37.14 123.11,30.28 123.49,29.9 v1(124.38,29.9) 124.38,29.01 v1(125.01,28.37) 125.01,28.12 123.92,27.03
  SIG1 w0.406: SW1.2 203.11,78.94 ; SW1.2 201.34,77.18 ; SW1.2 201.34,80.71 ; SW1.2 199.58,78.94 ; 199.58,69.92 SW2.2 ; SW2.2 203.11,69.92 ; SW2.2 201.34,68.16 ; SW1.1 201.34,74.21 ; SW1.1 199.58,72.44 ; SW1.1 203.11,72.44 ; SW2.1 203.11,63.42 ; SW2.1 199.58,63.42 ; SW2.1 201.34,61.66 ; SW2.1 201.34,65.19
  SIG1 w0.635: 192.4,17.46 J4.2 194.47,19.53 ; 192.4,13.26 J4.1 194.47,11.19
  GND2 w0.406: SW2.1 201.34,65.19 ; SW2.1 199.58,63.42 ; SW2.1 203.11,63.42 ; SW2.1 201.34,61.66 ; 201.34,68.16 SW2.2 ; SW2.2 199.58,69.92 ; SW2.2 203.11,69.92 ; SW1.1 201.34,74.21 ; SW1.1 203.11,72.44 ; SW1.1 199.58,72.44 ; 201.34,77.18 SW1.2 ; SW1.2 201.34,80.71 ; SW1.2 199.58,78.94 ; SW1.2 203.11,78.94 ; 140.97,24.18 140.97,25.96 ; 140.97,24.18 142.74,24.18 ; 140.97,24.18 140.97,22.4 ; 140.97,24.18 139.19,24.18
  GND2 w0.635: 194.47,11.19 J4.1 ; J4.1 194.47,15.33 ; J4.1 192.4,13.26 ; 192.4,17.46 J4.2 ; J4.2 194.47,15.39 ; J4.2 194.47,19.53
  SIG2 w0.406: 201.34,77.18 SW1.2 ; SW1.2 203.11,78.94 ; SW1.2 199.58,78.94 ; SW1.2 201.34,80.71 ; SW1.1 203.11,72.44 ; SW1.1 201.34,74.21 ; SW1.1 199.58,72.44 ; SW2.2 203.11,69.92 ; SW2.2 199.58,69.92 ; SW2.2 201.34,68.16 ; 199.58,63.42 SW2.1 ; SW2.1 203.11,63.42 ; SW2.1 201.34,61.66 ; SW2.1 201.34,65.19
  POWER2 w0.406: 139.19,24.18 140.97,24.18 ; 140.97,24.18 140.97,22.4 ; 140.97,24.18 140.97,25.96 ; 140.97,24.18 142.74,24.18
  SIG3 w0.635: 194.47,11.19 J4.1 192.4,13.26 ; 192.4,17.46 J4.2 194.47,19.53
  GND3 w0.406: 201.34,77.18 SW1.2 ; SW1.2 199.58,78.94 ; SW1.2 201.34,80.71 ; SW1.2 203.11,78.94 ; 140.97,24.18 140.97,25.96 ; 140.97,24.18 140.97,22.4 ; 140.97,24.18 139.19,24.18 ; 140.97,24.18 142.74,24.18 ; SW2.1 203.11,63.42 ; SW2.1 201.34,65.19 ; SW2.1 199.58,63.42 ; SW2.1 201.34,61.66 ; 199.58,69.92 SW2.2 ; SW2.2 203.11,69.92 ; SW2.2 201.34,68.16 ; SW1.1 201.34,74.21 ; SW1.1 203.11,72.44 ; SW1.1 199.58,72.44
  GND3 w0.635: 192.4,13.26 J4.1 ; J4.1 194.47,15.33 ; J4.1 194.47,11.19 ; 194.47,15.39 J4.2 ; J4.2 194.47,19.53 ; J4.2 192.4,17.46
  SIG4 w0.254: v1(87.68,44.37) 86.41,44.37 86.15,44.12 86.15,42.34 84.88,41.07 84.88,38.79 83.87,37.77 80.27,37.77 79.47,36.97 78.37,36.97 v1(78.15,36.75)
  SIG4 w0.381: 116,96.83 118.16,96.83 119.27,95.71 132.36,95.71 137.52,90.55 137.52,89.48 v1(138.1,88.9) 137.51,88.32 136.01,88.32 v1(135.35,88.98) 135.48,89.1 135.48,90.3 131.42,94.36 118.21,94.36 117.39,95.17 v1(116,95.17) 115.74,94.92 114.98,94.92 114.46,95.44 114.46,96.99 v1(114.85,97.38) 115.44,97.38 116,96.83
  BOTTOM w0.229: U4.A25 v1(186.66,95.59) ; U4.D23 v1(191.74,93.05) ; U60.B11 v1(200.55,129.19) ; U60.B10 v1(200.55,130.46) ; R230.1 v1(184.58,151.16)
  BOTTOM w0.279: U61.12 v1(121.07,119.96)
  BOTTOM w0.305: U4.D8 v1(190.47,72.73) ; U60.C27 v1(199.28,107.6) ; U53.14 133.61,73.29 133.45,73.13 v1(133.24,73.13) 133.24,73.56 133.63,73.94 U53.13 ; U4.D2 v1(191.74,65.11) ; U4.C36 v1(190.47,109.56) ; U4.A10 v1(186.66,75.27) ; U48.15 119.22,106.5 v1(118.92,106.81) 119.26,107.15 U48.14 ; v1(189.21,82.89) 189.83,82.26 U4.C15 ; U4.D12 v1(190.47,79.08) U4.C13 v1(189.2,79.08) ; U60.D11 v1(196.74,129.19) ; U60.B20 v1(199.28,117.76) ; v1(190.47,99.4) U4.C28 U4.B29 ; U60.C12 U60.B12 v1(200.55,127.92) ; v1(202.1,114.61) 201.2,114.61 U60.A22 ; U4.D39 191.34,112.73 v1(191.72,113.11) ; U60.C4 U60.D5 196.73,136.18 196.72,136.2 v1(196.67,136.2) ; U60.A13 201.2,126.04 v1(202.36,126.04) ; U60.C7 v1(198.01,134.27) U60.D6 ; U60.D31 v1(196.74,102.52) ; U60.B5 U60.B6 v1(200.55,134.27) ; U60.B39 v1(200.55,92.36) ; U62.12 83.72,152.37 83.42,152.07 v1(83.1,152.07) ; U60.B24 199.94,112.05 v1(200.57,111.41) ; v1(199.28,111.41) U60.C25 v1(198.01,110.14) U60.C26 ; U48.8 114.87,110.4 115.49,109.78 v1(115.49,109.22) ; v1(186.48,98.98) 186.69,98.76 U4.A28 ; v1(129.84,71.91) 129.84,72.06 129.26,72.64 U53.6 ; U60.B33 v1(200.55,99.98) ; U4.B31 v1(187.93,103.21) U4.B32 ; U4.B20 v1(187.93,87.97) U4.A19 ; U4.A18 186.51,86.06 v1(186.48,86.03) ; v1(189.2,113.16) 188.78,112.73 U4.B39 ; v1(200.55,141.89) U60.B1 U60.B2 ; U4.C4 v1(190.47,67.65) ; U4.A36 v1(186.66,109.56) ; U60.B27 v1(200.55,107.6) ; U60.B25 v1(200.55,110.14) ; U4.C16 189.83,83.53 v1(189.21,84.16) ; U49.8 106.08,135.3 v1(106.22,135.43) ; U4.C27 v1(190.47,98.13) ; U60.C23 v1(199.28,112.68) ; U53.1 129.57,69.39 v1(129.69,69.27) ; v1(200.55,133) U60.B7 U60.B8 ; U60.C37 v1(199.28,96.17) ; U60.D38 v1(196.74,93.63) ; U60.C17 v1(199.28,120.3) U60.C18 ; U4.C21 U4.C22 v1(190.47,91.78) ; U4.A7 v1(186.66,71.46) ; U4.C39 190.05,112.73 v1(190.47,113.16) ; U53.8 129.49,73.94 129.97,73.46 v1(129.97,73.18) 129.49,73.18 129.37,73.29 U53.7 ; U4.B26 v1(187.93,96.86) ; U60.A40 v1(201.82,91.09) ; U4.D31 v1(191.74,103.21) ; U60.D15 v1(196.74,124.11) ; U60.A25 v1(201.82,110.14) ; U60.B15 v1(200.55,124.11) ; C586.2 v1(113.83,70.28) ; U60.B17 v1(200.55,121.57) ; U53.15 133.8,72.64 133.25,72.09 v1(133.25,71.9) ; U60.D26 v1(196.74,108.87) ; U60.C30 v1(199.28,103.79) ; U4.A15 186.51,82.25 v1(186.48,82.22) ; U4.D37 v1(191.74,110.83) ; v1(196.67,133.66) 196.68,133.64 U60.D7 ; U60.C24 v1(198.01,111.41) ; U60.B35 v1(200.55,97.44) ; U4.A33 v1(186.66,105.75) ; v1(199.28,130.46) U60.C9 U60.C8 v1(199.28,133) ; v1(196.74,98.71) U60.D34 v1(198.01,98.71) U60.C34 v1(199.28,99.98) U60.C33 ; U52.8 133.77,74.59 133.65,74.47 v1(133.14,74.47) 133.14,74.73 133.66,75.24 U53.11 ; U60.A7 v1(201.82,134.27) ; U60.A37 v1(201.82,94.9) ; U4.B6 v1(187.93,70.19) ; U60.C16 U60.B16 v1(200.55,122.84) ; U4.B2 v1(187.93,65.11) ; U60.C29 v1(199.28,105.06) ; U60.A34 v1(201.82,98.71) ; U60.B4 U60.B3 v1(200.55,138.08) ; U60.C31 v1(198.01,102.52) ; U60.D10 v1(196.74,130.46) ; U60.C20 v1(198.01,117.76) ; v1(199.28,119.03) U60.C19 v1(198.01,119.03) U60.D19 ; U4.B8 v1(187.93,72.73) ; U4.A16 v1(187.93,84.16) U4.B17 ; U60.B13 v1(200.55,126.65) ; U52.9 129.34,74.59 129.46,74.47 v1(129.97,74.47) 129.97,74.85 129.58,75.24 U53.10 ; U60.B21 v1(200.55,116.49) ; U4.C18 189.83,86.07 v1(189.21,86.7) 189.83,87.33 U4.C19 ; U4.D26 v1(191.74,96.86) ; U4.D29 v1(191.74,100.67) ; U4.D9 v1(190.47,75.27) U4.C10 v1(189.2,75.27) ; U60.B34 v1(199.28,98.71) ; U60.A16 202.09,122.21 v1(202.48,122.61) ; U4.C33 v1(190.47,105.75) ; U60.C35 v1(198.01,97.44) ; U4.C1 v1(190.47,63.84) ; U4.D3 v1(191.74,66.38) ; U60.A28 v1(201.82,106.33) ; U4.D14 v1(191.74,80.35) ; U4.A13 v1(187.93,80.35) U4.B14 ; U4.B34 v1(187.93,107.02) U4.B35 ; U60.B29 v1(200.55,105.06) ; U4.D35 v1(191.74,108.29) ; U4.C30 v1(190.47,101.94) ; U4.B3 v1(187.93,66.38) ; U60.C21 v1(198.01,116.49) ; U4.B23 v1(187.93,93.05) U4.A24 ; U4.D20 v1(191.74,87.97) ; v1(200.55,130.46) U60.B9 ; U60.D1 v1(196.74,141.89) ; U60.B18 v1(200.55,120.3) ; v1(202.1,118.42) 201.2,118.42 U60.A19 ; U4.C7 v1(190.47,71.46) ; U4.B11 v1(187.93,76.54) ; U4.D17 v1(191.74,84.16) ; U4.A39 187.51,112.73 v1(187.93,113.16) ; U4.D34 v1(191.74,107.02) ; U60.B36 v1(200.55,96.17) ; v1(118.89,110.01) 119.29,110.4 U48.9 ; U60.D18 v1(196.74,120.3) ; v1(196.54,140.01) 196.56,139.99 U60.D2 ; U60.A4 v1(201.82,138.08) ; U4.D11 v1(190.47,76.54) ; U60.B38 v1(200.55,93.63) ; U4.B5 v1(187.93,68.92) ; U60.A1 v1(201.82,141.89) ; U60.B26 v1(200.55,108.87) ; U60.B32 v1(200.55,101.25) ; U4.A22 v1(186.66,91.78) ; U4.A30 186.47,101.3 v1(186.38,101.39) ; U4.A21 v1(186.66,90.51) ; U60.D30 v1(198.01,103.79) ; U60.D14 v1(196.74,125.38) ; U60.D35 v1(196.74,97.44) ; U4.A27 v1(186.66,96.86) ; U60.B31 v1(199.28,102.52) ; U60.A31 v1(201.82,102.52) ; U60.D22 v1(198.01,113.95) U60.C22 v1(199.28,113.95) ; U4.C24 v1(190.47,94.32) ; U60.B14 v1(200.55,125.38) ; U4.D5 v1(191.74,68.92) ; U60.B22 v1(200.55,115.22) ; U60.C28 v1(198.01,106.33) ; U4.B12 v1(187.93,77.81) ; U60.C32 v1(198.01,101.25) ; U4.D32 v1(190.47,103.21) ; U60.B40 v1(200.55,91.09) ; U60.C1 v1(198.01,141.89) ; U60.C38 v1(198.01,93.63) ; U4.B9 v1(187.93,74) ; U60.C13 v1(198.01,125.38) ; U60.B28 v1(200.55,106.33) ; U4.A4 v1(186.66,67.65) ; U4.D6 v1(191.74,70.19) ; U60.B23 v1(200.55,112.68) ; U60.D23 v1(198.01,112.68) ; U60.A10 v1(201.82,130.46) ; U60.B37 v1(200.55,94.9) ; U60.D27 v1(198.01,107.6) ; U60.B19 v1(200.55,119.03) ; U4.C25 v1(190.47,95.59) ; U60.C36 v1(198.01,96.17) ; U60.B30 v1(200.55,103.79)
  BOTTOM w0.33: v1(112.09,132.08) 112.09,131.8 111.68,131.39 U49.15 ; U49.9 110.04,135.3 v1(109.77,135.56) ; v1(109.65,142.29) 110.15,142.79 U47.9 ; U47.14 111.77,139.54 v1(112.19,139.12) 111.96,138.89 U47.15 ; v1(109.77,132.08) 109.81,132.04 U49.14 ; v1(106.35,142.29) 105.85,142.79 U47.8
  BOTTOM w0.381: C645.2 90.4,84.86 v2(89.82,84.86) 89.85,84.9 89.85,84.94 90.47,85.56 C646.2 ; 174.29,4.5 C790.2 C791.2 ; Q33.2 77.52,161.47 77.08,161.91 v1(76.81,161.91) ; R697.1 173.07,35.48 172.44,34.85 v1(172.44,34.6) ; v1(108.5,119.23) 108.2,119.23 108,119.43 R1002.1 ; v2(86.76,75.89) 86.56,75.69 C628.2 ; v1(124,101.4) 124,101.65 123.62,102.03 C688.1 ; v2(145.09,121.03) 145.02,120.96 C302.2 ; C38.2 79.24,138.76 v1(79.71,139.23) 80.17,138.76 C27.2 ; C627.2 91.33,76.23 v2(91.74,76.63) ; C627.2 91.33,75.46 v2(90.98,75.11) ; C627.2 91.98,75.86 ; C315.2 146.88,118.82 v1(146.69,118.63) ; v1(168.19,69.27) 168.45,69.01 C218.2 ; C249.2 154.83,144.04 v2(155.02,144.24) ; v1(138.35,107.52) 138.35,106.83 C14.1 ; C664.2 100.58,86.99 v2(100.51,86.92) ; C644.2 93.34,92.35 v2(93.02,92.04) ; C648.2 90.72,92.13 v2(90.63,92.04) ; C32.2 75.19,131.7 v1(74.71,131.23) ; C328.2 149.04,116.98 v2(149.09,117.03) ; v2(101.52,73.2) 101.04,73.69 C635.2 ; v2(142.69,120.23) 142.06,119.6 C314.2 ; v1(80.21,153.11) R1144.2 R1143.1 ; C306.2 C298.2 154.83,116.37 v2(154.69,116.23) ; v1(155.37,104.7) R585.2 R526.1 ; v1(143.56,129.74) 143.79,129.74 144.17,129.36 C261.1 ; v2(152.29,124.23) 151.56,123.5 C244.1 ; R901.1 C602.2 82.34,98.37 v1(82.32,98.4) ; C597.2 89.23,88.95 88.87,89.31 v2(88.88,89.31) ; C597.2 C601.2 ; C597.2 C598.2 ; R967.1 82.67,72.09 v2(82.7,72.06) ; C36.2 84.21,137.73 v1(83.71,137.23) ; C797.2 9.42,88.54 ; C797.2 7.95,88.54 ; C797.2 8.68,89.33 ; Q10.2 14.59,90.22 v1(14.69,90.12) ; 7.13,88.54 C802.2 6.4,89.33 ; C594.2 61.7,67.52 v1(60.88,67.52) 60.79,67.62 R993.2 ; C744.2 v1(91.23,162.87) ; C258.2 v1(149.02,104.7) ; v2(96.22,70.58) 96.22,70.32 95.8,69.9 R951.2 ; v2(149.89,119.43) 150.02,119.3 C320.2 ; v2(99.01,67.79) 99.39,67.41 R787.1 ; C596.2 87.96,91.24 v2(87.14,91.24) ; C219.2 169.62,72.9 v1(169.85,73.13) ; 98.22,51.23 95.5,51.23 94.03,52.71 v1(94.03,53.39) 91.87,55.55 91.87,60 91.54,60.33 91.54,61.04 v2(91.31,61.27) ; C649.2 95.44,70.8 v2(95.44,70.57) ; R379.1 v1(143.05,143.43) ; v1(164.51,93.95) 164.54,93.93 C56.2 C57.2 C54.2 ; v1(71.67,142.93) 70.68,141.94 R1216.1 ; C764.2 122.12,143.92 v1(122.86,143.18) ; v2(97.82,88.84) 97.74,88.93 C665.2 ; C520.2 7.59,70.05 v1(7.86,70.32) ; C520.2 7.03,69.14 ; C520.2 6.3,70.05 ; R968.1 v2(82.22,74.85) ; v2(149.09,118.63) 149.44,118.29 C308.2 ; v1(108.5,122.1) 108.12,122.48 R1004.1 ; v2(140.29,116.23) 140.4,116.13 C318.2 ; C250.2 158.95,136.96 v2(159.02,137.04) ; R397.1 v1(143.18,148.9) ; v2(155.14,140.13) 155.14,139.9 154.76,139.52 C245.2 ; v2(98.62,72.18) 98.62,72.92 C641.2 ; R966.1 73.03,62.31 v1(72.58,61.85) ; 71.07,17.42 C509.2 72.28,17.42 ; v2(86.76,78.92) 86.56,78.71 C618.2 ; v1(185.97,138.61) C162.2 ; v1(155.75,102.41) 156.26,102.92 C13.2 ; v1(90.52,124.18) 90.16,124.54 Q6.2 ; v1(69.87,130.99) 70.13,131.24 70.18,131.24 R75.2 ; v2(99.27,64.32) 99.46,64.13 R794.1 99.46,63.1 99.52,63.04 R962.2 ; v2(99.61,91.14) 99.11,91.64 C653.2 ; C521.2 21.41,70.05 ; C521.2 22.02,69.17 v1(22.24,68.95) ; C521.2 22.63,70.05 ; C325.2 147.65,121.74 v1(148.13,122.23) 148.61,121.74 C299.2 ; C626.2 86.06,73.64 v2(85.72,73.3) ; C626.2 86.56,74.19 v2(86.76,74.39) ; C626.2 86.56,73.05 ; C654.2 96.03,84.02 C669.2 95.79,84.01 v2(94.65,84.01) ; C628.2 86.56,74.95 v2(86,74.39) ; C628.2 85.91,75.14 ; R896.1 v1(103.42,55.91) ; C661.2 94.53,84.93 v2(94.62,84.84) ; v2(151.49,112.23) 151.41,112.14 C259.1 C260.2 ; v2(93.33,95.57) 93.33,96.25 94,96.93 R900.1 ; C496.2 90.47,25.32 90.98,25.83 v1(91.11,25.83) ; v1(135.43,154.74) 134.92,155.25 C88.2 ; R417.1 v1(143.05,140.39) ; C309.2 150.01,120.35 v2(149.89,120.23) ; v2(155.02,137.04) U21.H9 C243.2 ; C138.2 v1(165.88,153.87) ; v1(97.96,143.69) 97.96,144.75 C29.2 98.85,144.27 v1(98.85,143.69) ; C651.2 99.46,88.59 v2(99.88,88.17) ; R1053.2 R1078.1 123.59,107.11 123.97,106.73 123.97,106.63 v1(124,106.6) ; 117.9,51.31 119.64,51.31 v1(122.09,48.85) 122.47,48.47 122.47,42.85 123.24,42.09 123.24,41.33 v1(122.73,40.82) 122.09,40.18 122.09,38.66 122.5,38.25 v1(124.23,38.25) 124.63,38.66 124.63,42.98 123.87,43.74 123.87,49.33 120.32,52.88 98.22,52.88 v1(97.58,53.52) ; C239.2 157.17,144.49 v2(157.42,144.24) ; C659.2 99.91,81.46 v2(100.22,81.78) 99.59,82.41 C660.2 ; v1(103.55,117.3) 103.32,117.07 R937.1 ; R954.2 99.13,71.27 99.44,70.97 v2(99.44,70.59) ; C241.2 151.71,136.09 v2(151.81,136.2) ; R221.1 v1(187.5,37.64) ; v2(105.48,78.36) 104.92,78.92 C607.2 ; 93.91,75.5 C625.2 94.56,76.15 v2(94.79,76.38) 94.56,76.61 C623.2 94.56,77.67 v2(94.79,77.9) ; C518.2 16.28,70.05 ; C518.2 15.41,69.14 ; C518.2 14.68,70.05 ; v1(11.96,53.42) 12.37,53.02 C794.2 ; v1(93.1,114.08) 93.4,114.08 93.77,113.72 R899.1 ; v1(108.21,128.64) 108.23,128.65 C564.1 ; v1(64.69,21.44) 64.69,21.46 65.12,21.9 R734.1 ; C519.2 5.23,70.05 ; C519.2 4.49,69.01 v1(4.43,68.95) ; C519.2 3.76,70.05 ; v2(151.51,122.61) 151.38,122.48 C300.2 ; v1(142.03,128.96) 142.03,128.7 142.06,128.68 C323.2 ; R602.1 158.19,111.76 v1(157.65,112.29) ; R372.1 v1(144.19,148.9) ; C618.2 85.91,78.17 ; C618.2 86.56,77.95 v2(86,77.39) ; v2(95.17,82.22) 94.69,82.7 C762.2 ; C30.2 89.69,131.23 v1(89.71,131.23) ; v1(139,129.65) 138.73,129.92 R552.2 ; R248.1 v1(186.61,146.86) ; C795.2 C794.2 ; C795.2 13.76,53.14 ; C795.2 14.5,52.35 ; C794.2 11.5,52.35 ; v2(91.4,95.48) 91.87,95.01 C655.2 ; v2(91.74,75.11) 91.33,74.7 C630.2 ; v2(81.17,78.08) 80.97,77.88 R969.1 ; R129.2 v1(19.35,42.22) ; R1206.1 83.76,97.64 v2(83.93,97.47) ; R591.2 159.64,109.53 v1(159.81,109.35) ; v2(150.29,117.78) 149.81,117.3 C326.2 ; C684.1 114.85,129.72 v1(115.11,129.97) ; C481.1 v4(59.74,14.3) ; R249.2 v1(172.77,151.31) ; v1(180.77,101.91) 181.17,101.5 R164.1 ; C800.2 v1(26.72,42.98) ; v1(153.72,48.06) 153.06,48.72 R718.2 ; v1(183.43,113.59) 183.84,114 C67.2 C63.2 ; C192.2 174.9,65.18 v1(175.18,65.46) ; C295.2 140.41,117.15 v2(140.29,117.03) ; v2(92.23,72.98) 92.06,72.81 C622.2 ; v1(129.84,161.21) 129.33,161.72 Q19.2 ; Q23.2 96.12,122.12 v1(96.54,121.69) ; C791.2 174.29,6.02 ; C791.2 C788.2 ; 31.42,88.82 C234.2 30.27,88.16 R365.1 ; v1(138.22,21.01) 137.71,21.51 R681.2 ; v1(127.91,18.09) C336.2 ; C650.2 95.77,92.76 v2(95.06,93.47) 95.45,93.86 C599.2 ; C34.2 89.21,145.73 v1(89.71,146.23) ; R923.2 R924.2 v2(95.52,78.69) ; R389.1 v1(155.37,148.9) ; v2(90.98,79.68) 91.33,80.04 C620.2 ; C26.2 v1(82.71,140.23) ; v2(97.02,70.56) 97.2,70.38 R950.2 ; C616.2 85.74,71.97 v2(85.64,72.06) ; C616.2 86.56,72.59 ; C616.2 86.56,71.62 v2(86.15,71.21) ; C614.2 v2(101.52,58.85) ; C254.1 C255.1 136.57,135.94 v1(136.32,136.2) ; C643.2 v2(93.14,76.25) ; R73.2 80.44,128.96 v1(80.69,128.7) 81.07,128.7 81.45,129.08 R78.2 ; v2(96.22,85.64) 96.21,85.65 C666.2 ; v2(141.09,115.43) 141.41,115.11 C304.2 ; R393.1 v1(143.05,141.4) ; C617.2 85.91,79.69 ; C617.2 86.56,80.24 v2(86.76,80.44) ; C617.2 86.56,79.48 v2(86,78.92) ; v2(146.69,121.03) 146.6,121.12 C301.2 ; v2(102.99,74.04) 102.64,74.4 C637.2 ; R131.2 v1(18.21,42.22) ; v1(139.11,67.87) 138.86,67.62 C692.1 ; v1(198.42,86.79) 198.24,86.98 Q1.2 ; v2(100.22,70.56) 100.28,70.61 C638.2 ; v1(148.89,51.99) 149.04,52.15 C472.2 ; Q27.2 181.07,67.68 v1(181.5,68.12) ; v2(85.14,78.92) 85.14,79.27 C675.2 84.37,79.32 v2(84.37,78.92) ; v1(143.49,117.83) 143.54,117.88 C313.2 ; v2(94.64,88.83) 94.53,88.72 C763.2 92.66,88.72 92.53,88.6 C256.2 92.07,87.73 92.15,87.66 C668.2 92.15,86.53 v2(92.23,86.45) 92.86,85.82 C647.2 ; v1(73.71,130.23) 74.21,130.73 C33.2 ; C681.1 110.69,105.36 v1(110.66,105.33) ; R413.1 v1(143.05,139.37) ; Q29.2 157.77,73.65 v1(158.29,73.13) ; v1(158.54,141.15) 158.54,141.28 158.7,141.43 C251.2 ; Q34.2 94.6,152.76 95.25,152.12 v1(95.25,151.44) ; v1(88.71,145.23) 88.22,144.74 C35.2 ; v2(103.48,76.64) 103.78,76.64 104.16,76.26 C631.2 ; v2(90.98,78.16) 91.33,77.8 C629.2 ; v1(88.71,131.23) 88.23,131.7 C31.2 ; R800.1 v1(111.55,55.8) ; R385.1 v1(153.34,148.9) ; C591.1 126.26,121.54 v1(126.03,121.31) ; R77.2 v1(85.39,124.51) ; v1(126.28,21.51) 126.67,21.9 R651.1 ; C682.1 123.87,105.08 v1(124.13,105.33) ; v1(4.52,50.63) 4.36,50.47 C235.2 5.89,49.94 R369.1 ; R295.2 167.74,63.22 168.12,63.6 v1(168.63,63.6) ; v2(85.14,75.87) 85.14,76.23 C677.2 84.37,76.28 v2(84.37,75.87) ; C240.2 C247.1 148.89,135.03 148.61,134.75 v1(148.33,134.75) ; C642.2 93.77,71.04 94.23,70.59 v2(94.64,70.59) ; v1(134.54,152.83) 134.51,152.83 C18.1 ; Q22.2 v1(122.92,158.36) ; 2.84,51.23 C524.2 1.98,50.44 ; R920.1 100.88,56.44 v1(101.39,55.93) ; v2(107.13,63.68) 107.47,63.34 R921.1 ; C788.2 174.29,7.54 ; C788.2 C789.2 174.29,9.07 ; v2(94.62,90.44) 94.74,90.32 C662.2 ; C796.2 C792.2 C793.2 17.29,47.45 v1(17.45,47.3) v1(18.33,47.3) ; C652.2 97.14,93.62 v2(97.07,93.55) ; v1(168.07,70.16) 168.32,70.41 C220.2 ; C798.2 19.33,87.15 ; C798.2 20.11,88.06 ; C798.2 20.85,87.15 ; C40.2 79.21,136.73 v1(79.71,136.23) ; v1(157.43,136.07) 157.43,135.84 156.92,135.33 R458.1 ; v1(74.71,145.23) 75.2,144.74 C39.2 ; C801.2 23.69,87.15 ; C801.2 24.43,87.94 ; C801.2 25.17,87.15 ; R617.1 v1(173.38,121.82) ; v1(176.07,65.2) 176.38,65.51 Q28.2 ; v1(145.09,117.03) 144.98,116.92 C311.2 ; v2(84.66,81.82) 85.26,82.42 R895.1 ; v2(94.62,88.04) 94.75,88.16 C667.2 ; C248.2 155.49,134.93 156,134.42 v1(156.64,134.42) ; v2(145.89,121.03) 145.59,121.34 C294.2 ; R583.1 133.42,132.13 v1(133.73,132.44) ; R844.1 80.49,108.28 v1(80.69,108.48) ; v1(167.28,28.75) 167.15,28.75 166.67,29.24 C747.2 ; R411.1 v1(148.26,148.9) ; v1(124.25,143.43) 124.63,143.82 C563.2 ; C680.1 115.08,137.47 v1(115.11,137.49) ; C297.2 146.99,124.74 v2(146.69,125.03) ; v1(80.44,116.64) 80.82,116.26 Q25.2 ; R262.1 v1(135.81,62.28) ; 78.67,24.55 C512.2 78.05,23.77 ; v2(145.89,127.43) 145.79,127.53 R429.1 ; C357.2 115.34,25.04 v1(115.87,25.58) ; C620.2 91.98,80.43 ; C620.2 91.33,81.03 ; R211.2 135.05,156.64 v1(135.56,156.13) ; C619.2 91.33,78.56 v2(91.74,78.16) ; C619.2 91.98,78.91 ; C619.2 91.33,79.27 v2(91.74,79.68) ; v1(147.24,67.23) 147.37,67.36 U44.4 ; C317.2 156.5,114.83 v2(156.29,114.63) ; C43.2 74.88,158.83 v1(74.6,158.55) ; R391.1 v1(151.3,148.9) ; Q3.2 158.99,96.12 v1(158.8,96.32) ; v1(129.46,142.8) 128.95,142.29 U24.4 ; C630.2 91.33,73.71 ; C630.2 91.98,74.33 ; v2(150.23,137.04) 150.31,136.95 R381.1 ; v1(88.69,146.23) 87.91,147.02 R13.2 ; v1(167.69,65.96) 168.22,65.43 C194.2 ; R1025.1 103.79,63.77 v2(103.2,64.35) ; Q11.2 13.13,87.05 v1(13.84,87.76) ; C799.2 v1(24.81,42.98) ; R1183.1 86.53,106.35 86.15,106.73 v1(85.52,106.73) ; C62.2 183.56,117.4 v1(183.18,117.78) ; v2(84.37,77.39) 84.37,77.8 C676.2 85.14,77.75 v2(85.14,77.39) ; v1(185.97,137.72) 185.47,137.21 C160.2 ; R127.2 10.21,68.5 v1(9.27,67.57) ; R383.1 v1(144.7,136.2) ; 85.91,70.42 C615.2 86.56,69.8 ; C629.2 91.98,77.38 ; C629.2 91.33,76.99 v2(90.98,76.63) ; C803.2 v1(22.91,42.98) ; R399.1 v1(143.05,138.35) ; 116.86,81.36 C671.2 C663.2 ; R598.2 172.89,107.62 v1(172.51,108) ; v1(137.71,16.56) 137.28,16.99 C423.2 ; v1(146.69,117.03) 147.01,116.71 C310.2 147.01,115.85 147.49,115.37 C303.2 ; C672.2 100.12,83.49 v2(100.43,83.8) ; R927.2 R928.2 107.84,82.32 108.38,82.86 C603.2 C604.2 v2(106.17,82.7) ; v2(99.23,79.55) 99.59,79.91 C673.2 ; R419.1 v1(143.05,145.47) ; v1(141.02,64.19) R298.2 141.8,63.7 141.55,63.45 R297.2 ; v2(91.36,64.34) 91.39,64.31 R957.1 ; R425.1 v1(143.05,137.34) ; R401.1 v1(145.21,148.9) ; 9.44,42.98 C527.2 10.18,43.89 ; R711.2 v1(150.54,45.75) ; v2(144.83,119.43) 144.34,119.91 C319.2 ; v1(162.23,142.42) 162.2,142.44 C237.2 ; v1(150.8,77.9) C703.1 ; R1001.1 108,118.42 108.1,118.31 v1(108.5,118.31) ; v2(102.84,78.11) 102.77,78.03 C633.2 ; R415.1 v1(147.24,148.9) ; C690.1 v1(124.63,68.76) ; v1(96.9,127.51) 96.85,127.56 Q26.2 ; v1(129.33,109.17) 129.08,109.42 C743.2 C742.2 ; C656.2 97.05,92.02 v2(97.02,92.04) ; C593.1 124.66,127.58 v1(124.38,127.31) 124.38,126.47 C592.2 125.01,126.29 125.28,126.56 125.28,127.29 v1(125.27,127.31) ; C452.2 154.71,37.03 v1(154.35,37.39) ; v1(82.71,136.23) 83.21,136.73 C22.2 ; C25.2 80.21,136.73 v1(80.71,136.23) ; v2(141.09,125.83) 141.78,125.15 C324.2 ; v1(72.18,128.96) 70.94,128.96 70.56,129.34 R76.2 ; v1(86.79,139.24) 87.27,139.73 C757.2 ; C66.2 183.31,116.38 v1(182.55,117.15) ; v2(99.57,86.89) 99.21,86.53 C670.2 ; C87.2 v1(132.13,161.72) ; R549.2 153.08,104.85 v1(153.23,104.7) ; R407.1 v1(150.29,148.9) ; v2(86.76,77.39) 86.56,77.19 C624.2 ; v1(144.29,122.63) 144.42,122.5 C312.2 ; v1(89.51,117.4) 89.96,116.94 R904.1 ; 97.86,76.15 C632.2 97.86,77.37 v2(97.58,77.65) ; v1(139.87,154.74) 140,154.86 R212.2 ; R421.1 v1(146.22,148.9) ; v2(106.21,91.49) 105.83,91.87 R933.2 105.56,92.35 105.61,92.41 R960.2 ; R409.1 v1(144.7,135.18) ; C600.2 v2(92.63,82.6) ; C37.2 v1(83.71,140.23) ; R387.1 v1(154.35,148.9) ; C746.2 120.06,15.82 v1(120.09,15.8) ; Q30.2 162.61,73.65 162.99,73.27 v1(162.99,73.13) ; Q17.2 v1(187.24,146.23) ; C322.2 153.82,120.16 v2(153.89,120.23) ; v1(58.85,15.55) 58.47,15.93 C748.2 57.73,16.33 ; v1(73.71,146.23) 74.21,145.72 C41.2 ; C624.2 86.56,76.45 v2(86,75.89) ; C624.2 85.91,76.64 ; R139.2 23.16,68.25 ; C528.2 23.06,70.18 ; C246.1 v1(160.3,145.62) ; R404.1 v1(143.05,142.42) ; U22.10 v1(133.14,140.64) ; v2(74,63.78) 74.51,63.27 R964.1 ; Q18.2 v1(192.27,147.31) ; C745.2 v1(92.25,162.87) ; v1(66.82,15.67) C341.2 ; v2(102.94,87.78) 103.65,87.07 C658.2 ; v1(151.81,146.1) 151.66,145.95 C238.2 ; R952.2 94.08,69.49 v2(94.07,69.49) ; R1145.1 v1(89.2,162.87) ; R395.1 v1(152.32,148.9) ; v2(84.42,64.32) 84.42,63.89 85,63.31 C621.2 85.42,64.32 v2(85.41,64.32) ; R171.1 183.18,65.58 v1(182.8,65.96) ; R599.2 v1(174.93,105.66) ; R1134.1 v1(96.31,55.8) ; 113.43,62.18 C605.2 ; C761.2 95.7,81.23 v2(95.42,80.95) ; C229.1 137.18,102.57 136.83,102.92 v1(136.17,102.92) ; C657.2 105.56,90.6 v2(106.14,90.02) ; R1146.2 v1(90.22,162.87) ; 13,43.1 C804.2 12.26,43.89 ; R1178.1 v1(104.44,55.93) ; C291.2 153.87,122.61 v2(153.09,121.83) ; v1(166.8,152.45) 166.8,152.07 166.42,151.69 C139.2 ; v2(153.09,117.03) 153.13,116.99 C316.2 ; v1(174.54,62.54) 175.21,63.2 R296.2 ; Q24.2 84.78,116.26 v1(84.37,116.66) ; v1(119.05,71.86) 118.92,71.98 U18.4 ; v1(12.11,68.95) 11.95,69.11 C550.2 ; C42.2 v1(95.93,138.74) ; 103.4,24.16 C385.2 102.05,24.16 ; v1(115.36,143.56) R1051.1 ; C115.1 182.06,155.78 v1(182.04,155.8) ; R423.1 v1(143.05,144.45) ; C636.2 v2(98.62,75.97) ; C242.2 v1(148.26,146.61) ; C131.2 177.11,160.93 v1(177.21,160.83) ; v2(86.64,81.81) 86.64,81.47 87.14,80.98 R932.2 87.45,80.98 88.21,81.74 R931.2 ; R587.2 145.97,104.75 v1(146.02,104.7) ; C290.2 153.97,120.96 v2(154.69,120.23) ; R603.1 R604.1 v1(177.59,110.41) ; R577.2 v1(158.42,104.7) ; R142.2 27.33,48.46 ; R427.1 v1(156.38,148.9) ; 24.18,48.41 R1123.2 ; R222.2 v1(187.37,39.04) ; R371.1 v1(132.76,113.97) ; 84.37,74.75 v2(84.37,74.35) 84.37,73.94 C674.2 85.14,73.99 v2(85.14,74.35) 85.14,74.7 C678.2 84.37,74.75
  BOTTOM w0.508: C305.2 157.91,119.02 158.42,119.53 v1(158.42,119.94) 158.14,120.22 C321.2 ; C327.2 157.68,116.92 v1(158.16,117.4) ; C227.2 v1(147.37,23.67) ; C226.2 v1(147.37,22.66)
  vias: v1(1.27,159.56) v1(1.27,158.29) v1(1.27,157.02) v1(1.27,155.75) v1(1.27,154.48) v1(1.27,153.21) v1(1.27,151.94) v1(1.27,150.67) v1(1.27,149.4) v1(1.27,148.13) v1(1.27,146.86) v1(1.27,145.59) v1(1.27,144.32) v1(1.27,143.05) v1(1.27,141.78) v1(1.27,140.51) v1(1.27,139.24) v1(1.27,137.97) v1(1.27,136.7) v1(1.27,135.43) v1(1.27,134.16) v1(1.27,132.89) v1(1.27,131.62) v1(1.27,130.35) v1(1.27,129.08) v1(1.27,127.81) v1(1.27,126.54) v1(1.27,125.27) v1(1.27,124) v1(1.27,122.73) v1(1.27,121.46) v1(1.27,120.19) v1(1.27,118.92) v1(1.27,117.65) v1(1.27,116.38) v1(1.27,115.11) v1(1.27,46.53) v1(1.27,45.26) v1(1.27,43.99) v1(1.27,42.72) v1(1.27,41.45) v1(1.27,40.18) v1(1.27,38.91) v1(1.27,37.64) v1(1.27,32.56) v1(1.27,31.29) v1(1.27,30.02) v1(1.57,28.5) v1(1.91,161.47) v1(1.91,160.2) v1(1.91,158.93) v1(1.91,157.66) v1(1.91,156.39) v1(1.91,155.12) v1(1.91,153.85) v1(1.91,152.58) v1(1.91,151.31) v1(1.91,150.04) v1(1.91,148.77) v1(1.91,147.5) v1(1.91,146.23) v1(1.91,144.96) v1(1.91,143.69) v1(1.91,142.42) v1(1.91,141.15) v1(1.91,139.88) v1(1.91,138.61) v1(1.91,137.34) v1(1.91,136.07) v1(1.91,134.8) v1(1.91,133.53) v1(1.91,132.26) v1(1.91,130.99) v1(1.91,129.72) v1(1.91,128.45) v1(1.91,127.18) v1(1.91,125.91) v1(1.91,124.64) v1(1.91,123.37) v1(1.91,122.1) v1(1.91,120.83) v1(1.91,119.56) v1(1.91,118.29) v1(1.91,117.02) v1(1.91,115.75) v1(1.91,114.48) v1(1.91,45.9) v1(1.91,44.63) v1(1.91,43.36) v1(1.91,42.09) v1(1.91,40.82) v1(1.91,39.55) v1(1.91,38.28) v1(1.91,31.93) v1(1.91,30.66) v1(1.91,29.39) v1(2.33,162.48) v1(2.46,27.36) v1(2.71,28.37) v1(3.22,163.25) v1(3.67,55.53) v1(3.73,27.36) v1(3.86,26.34) v1(4.24,163.63) v1(4.43,112.45) v1(4.43,108.76) v1(4.43,107.42) v1(4.43,103.76) v1(4.43,102.75) v1(4.43,98.26) v1(4.43,96.92) v1(4.43,93.26) v1(4.43,91.45) v1(4.43,65.26) v1(4.43,63.92) v1(4.43,60.26) v1(4.43,58.45) v1(4.43,53.42) v1(4.56,88.6) v1(4.94,111.07) v1(4.94,106.07) v1(4.94,100.57) v1(4.94,95.57) v1(4.94,90.07) v1(4.94,67.57) v1(4.94,62.57) v1(4.94,57.07) v1(4.94,52.07) v1(5.13,26.09) v1(5.25,24.94) v1(5.38,163.63) v1(5.76,154.36) v1(5.76,138.86) v1(5.76,129.46) v1(5.89,121.59) v1(6.22,60.26) v1(6.27,25.45) v1(6.27,23.67) v1(6.27,22.4) v1(6.27,21.13) v1(6.27,19.86) v1(6.27,18.59) v1(6.27,17.32) v1(6.27,16.05) v1(6.27,14.78) v1(6.27,13.51) v1(6.27,12.24) v1(6.27,10.97) v1(6.27,9.7) v1(6.27,8.43) v1(6.65,163.63) v1(6.9,54.84) v1(6.9,24.56) v1(6.9,23.04) v1(6.9,21.77) v1(6.9,20.5) v1(6.9,19.23) v1(6.9,17.96) v1(6.9,16.69) v1(6.9,15.42) v1(6.9,14.15) v1(6.9,12.88) v1(6.9,11.61) v1(6.9,10.34) v1(6.9,9.07) v1(7.46,111.07) v1(7.46,106.07) v1(7.46,100.57) v1(7.46,95.57) v1(7.46,67.57) v1(7.46,62.57) v1(7.46,57.07) v1(7.46,52.07) v1(7.75,68.95) v1(7.75,58.45) v1(7.75,53.42) v1(8.3,47.42) v1(8.51,112.45) v1(8.51,111.07) v1(8.51,108.76) v1(8.51,107.42) v1(8.51,103.76) v1(8.51,102.75) v1(8.51,100.57) v1(8.51,98.26) v1(8.51,96.92) v1(8.51,93.26) v1(8.51,91.45) v1(8.51,90.07) v1(8.51,68.95) v1(8.51,67.57) v1(8.51,65.26) v1(8.51,63.92) v1(8.51,60.26) v1(8.51,58.45) v1(8.51,57.07) v1(8.51,54.82) v1(8.51,53.42) v1(8.51,49.76) v1(9.27,111.07) v1(9.27,100.57) v1(9.83,150.67) v1(10.08,135.05) v1(10.21,125.4) v1(10.84,25.71) v1(11.35,42.98) v1(11.35,42.09) v1(11.96,112.45) v1(11.96,111.07) v1(11.96,108.76) v1(11.96,107.42) v1(11.96,103.76) v1(11.96,101.95) v1(11.96,100.57) v1(11.96,98.26) v1(11.96,96.92) v1(11.96,95.57) v1(11.96,93.26) v1(11.96,91.45) v1(11.96,90.07) v1(11.96,87.76) v1(11.96,65.26) v1(11.96,63.92) v1(11.96,62.57) v1(11.96,60.26) v1(11.96,58.45) v1(11.96,57.07) v1(11.96,54.76) v1(12.24,42.98) v1(12.24,42.09) v1(12.75,33.33) v1(12.87,154.48) v1(13.72,93.26) v1(14.02,163.12) v1(14.02,138.48) v1(13.96,65.26) v1(14.4,129.46) v1(14.52,1.91) v1(14.73,112.45) v1(14.73,108.76) v1(14.73,107.42) v1(14.73,103.76) v1(14.73,101.95) v1(14.73,98.26) v1(14.73,96.92) v1(14.73,95.57) v1(14.73,91.45) v1(14.73,87.76) v1(14.73,68.95) v1(14.73,65.26) v1(14.73,63.92) v1(14.73,60.26) v1(14.73,58.45) v1(14.73,54.76) v1(14.73,53.42) v1(15.29,163.12) v1(15.79,1.91) v1(16.56,163.12) v1(16.94,119.56) v1(17.06,1.91) v1(17.19,30.53) v1(17.19,21.9) v1(17.19,12.5) v1(17.19,6.91) v1(17.7,159.18) v1(17.83,163.12) v1(17.95,119.56) v1(18.16,112.45) v1(18.16,108.76) v1(18.16,107.42) v1(18.16,103.76) v1(18.16,101.95) v1(18.16,98.26) v1(18.16,96.92) v1(18.16,93.26) v1(18.16,91.45) v1(18.16,87.76) v1(18.16,68.95) v1(18.16,63.92) v1(18.16,60.26) v1(18.16,58.45) v1(18.16,54.76) v1(18.16,53.42) v1(18.16,49.76) v1(18.33,1.91) v1(18.46,142.8) v1(18.72,135.31) v1(18.67,111.07) v1(18.67,106.07) v1(18.67,100.57) v1(18.67,95.57) v1(18.67,90.07) v1(18.67,67.57) v1(18.67,62.57) v1(18.67,57.07) v1(18.67,52.07) v1(18.97,119.56) v1(19.1,163.12) v1(19.6,1.91) v1(19.69,65.26) v1(19.99,119.56) v1(19.95,60.26) v1(19.95,54.76) v1(20.37,163.12) v1(20.37,29.52) v1(20.66,49.76) v1(20.87,1.91) v1(21.19,111.07) v1(21.19,106.07) v1(21.19,100.57) v1(21.19,95.57) v1(21.22,87.76) v1(21.19,67.57) v1(21.19,62.57) v1(21.19,57.07) v1(21.19,52.07) v1(21.26,29.52) v1(21.48,90.07) v1(21.48,58.45) v1(21.48,53.42) v1(21.64,163.12) v1(21.98,87.76) v1(22.14,128.32) v1(22.14,1.91) v1(22.24,112.45) v1(22.24,111.07) v1(22.24,108.76) v1(22.24,107.42) v1(22.24,103.76) v1(22.24,101.95) v1(22.24,100.57) v1(22.24,98.26) v1(22.24,96.92) v1(22.24,93.26) v1(22.24,91.45) v1(22.24,90.07) v1(22.24,67.57) v1(22.24,65.26) v1(22.24,63.92) v1(22.24,60.26) v1(22.24,58.45) v1(22.24,57.07) v1(22.24,54.76) v1(22.24,53.42) v1(22.24,49.76) v1(22.4,121.72) v1(22.65,29.52) v1(22.78,25.71) v1(22.91,163.12) v1(23,111.07) v1(23,100.57) v1(23,67.57) v1(23,57.07) v1(23.41,1.91) v1(23.54,163.75) v1(23.54,29.52) v1(23.8,154.36) v1(23.8,147.75) v1(24.05,138.61) v1(24.05,9.2) v1(24.05,1.27) v1(24.18,163.12) v1(24.18,15.29) v1(24.43,32.44) v1(24.43,31.42) v1(24.68,1.91) v1(24.81,163.75) v1(25.32,1.27) v1(25.45,163.12) v1(25.45,32.56) v1(25.45,31.55) v1(25.62,111.07) v1(25.62,100.57) v1(25.69,112.45) v1(25.69,108.76) v1(25.69,107.42) v1(25.69,103.76) v1(25.69,101.95) v1(25.69,98.26) v1(25.69,96.92) v1(25.69,95.57) v1(25.69,93.26) v1(25.69,91.45) v1(25.69,90.07) v1(25.67,68.92) v1(25.67,67.57) v1(25.67,65.26) v1(25.67,63.92) v1(25.67,62.57) v1(25.67,60.26) v1(25.67,58.45) v1(25.67,57.07) v1(25.67,52.07) v1(25.67,49.76) v1(25.66,48.85) v1(25.92,54.76) v1(25.95,1.91) v1(26.08,163.75) v1(26.21,53.42) v1(26.34,32.06) v1(26.59,1.27) v1(26.72,163.12) v1(27.22,32.56) v1(27.22,31.55) v1(27.22,1.91) v1(27.35,163.75) v1(27.86,1.27) v1(27.99,163.12) v1(28.24,48.95) v1(28.24,47.93) v1(28.24,32.56) v1(28.24,31.55) v1(28.49,1.91) v1(28.62,163.75) v1(28.75,151.05) v1(28.88,143.05) v1(29.13,1.27) v1(29.26,163.12) v1(29.76,1.91) v1(29.89,163.75) v1(30.15,116.51) v1(30.15,22.02) v1(30.15,12.5) v1(30.15,6.91) v1(30.27,17.32) v1(30.4,1.27) v1(30.53,163.12) v1(31.03,1.91) v1(31.16,163.75) v1(31.42,116.51) v1(31.67,1.27) v1(31.8,163.12) v1(32.18,44.25) v1(32.3,1.91) v1(32.43,163.75) v1(32.43,136.45) v1(32.43,128.58) v1(32.56,159.31) v1(32.56,146.61) v1(32.56,121.59) v1(32.69,154.36) v1(32.69,116.51) v1(32.69,87.78) v1(32.94,1.27) v1(33.07,163.12) v1(33.19,33.96) v1(33.19,32.94) v1(33.57,1.91) v1(33.7,163.75) v1(34.21,116.51) v1(34.21,1.27) v1(34.34,163.12) v1(34.84,44.25) v1(34.84,1.91) v1(34.97,163.75) v1(34.97,47.68) v1(35.48,1.27) v1(35.61,163.12) v1(35.86,9.45) v1(36.11,1.91) v1(36.24,163.75) v1(36.24,26.98) v1(36.75,1.27) v1(36.88,163.12) v1(37.38,1.91) v1(37.51,163.75) v1(38.02,1.27) v1(38.15,163.12) v1(38.27,145.97) v1(38.65,1.91) v1(38.78,163.75) v1(39.29,1.27) v1(39.42,163.12) v1(39.92,1.91) v1(40.05,163.75) v1(40.05,159.18) v1(40.31,154.74) v1(40.56,1.27) v1(40.69,163.12) v1(41.19,6.66) v1(41.19,1.91) v1(41.32,163.75) v1(41.83,1.27) v1(41.96,163.12) v1(42.46,1.91) v1(42.59,163.75) v1(42.72,136.45) v1(42.72,128.58) v1(43.1,1.27) v1(43.23,163.12) v1(43.35,46.53) v1(43.35,23.8) v1(43.73,12.37) v1(43.73,1.91) v1(43.86,163.75) v1(44.37,1.27) v1(44.5,163.12) v1(44.75,121.72) v1(45,116.89) v1(45,1.91) v1(45.13,163.75) v1(45.64,1.27) v1(45.77,163.12) v1(46.27,1.91) v1(46.4,163.75) v1(46.91,1.27) v1(47.04,163.12) v1(47.42,41.83) v1(47.54,1.91) v1(47.67,163.75) v1(48.18,1.27) v1(48.31,163.12) v1(48.43,147.24) v1(48.81,8.94) v1(48.81,1.91) v1(48.94,163.75) v1(49.45,154.74) v1(49.45,18.21) v1(49.45,1.27) v1(49.58,163.12) v1(49.58,159.56) v1(50.08,138.99) v1(50.08,1.91) v1(50.21,163.75) v1(50.72,36.5) v1(50.72,1.27) v1(50.85,163.12) v1(51.35,1.91) v1(51.48,163.75) v1(51.99,1.27) v1(52.12,163.12) v1(52.62,1.91) v1(53.13,6.4) v1(53.26,1.27) v1(53.39,163.12) v1(53.51,12.24) v1(53.89,1.91) v1(54.4,145.97) v1(54.53,1.27) v1(54.66,163.12) v1(55.16,1.91) v1(55.29,128.45) v1(55.8,1.27) v1(55.93,163.12) v1(55.93,138.74) v1(56.43,1.91) v1(56.82,121.72) v1(57.07,1.27) v1(57.2,163.12) v1(57.2,144.2) v1(57.2,117.02) v1(57.58,159.56) v1(57.7,1.91) v1(57.96,86.92) v1(58.21,46.41) v1(58.21,45.26) v1(58.34,42.72) v1(58.34,41.96) v1(58.34,1.27) v1(58.47,163.12) v1(58.97,1.91) v1(59.1,46.41) v1(59.1,45.26) v1(59.36,41.96) v1(59.61,155.37) v1(59.61,1.27) v1(59.74,163.12) v1(60.24,1.91) v1(60.37,42.85) v1(60.37,41.96) v1(60.75,142.93) v1(60.88,29.26) v1(60.88,1.27) v1(61.01,163.12) v1(61.77,29.26) v1(62.53,142.8) v1(62.78,29.26) v1(63.67,29.26) v1(63.83,91.14) v1(64.56,29.39) v1(64.71,82.92) v1(64.79,86.79) v1(64.94,146.23) v1(64.94,144.7) v1(64.94,142.8) v1(64.94,140.77) v1(64.94,138.99) v1(65.38,96.29) v1(65.73,92.58) v1(65.76,89.26) v1(66.15,96.87) v1(66.34,64.11) v1(66.57,88.34) v1(66.66,60.67) v1(66.98,142.8) v1(67,82.92) v1(67.08,86.79) v1(67.3,94.36) v1(67.66,90.65) v1(67.93,94.99) v1(67.99,163.75) v1(68.06,98.14) v1(68.09,84.73) v1(68.37,62.3) v1(68.5,139.12) v1(68.52,82.92) v1(68.5,1.27) v1(68.63,163.12) v1(68.63,142.8) v1(68.63,64.11) v1(68.88,155.5) v1(68.88,121.84) v1(69.13,1.91) v1(69.24,88.34) v1(69.2,60.67) v1(69.26,163.75) v1(69.26,19.36) v1(69.26,18.59) v1(69.36,86.79) v1(69.57,136.25) v1(69.62,84.73) v1(69.9,163.12) v1(69.99,96.26) v1(70.02,18.59) v1(70.12,99.44) v1(70.4,1.91) v1(70.53,163.75) v1(70.53,27.61) v1(70.73,60.67) v1(70.78,62.3) v1(70.79,18.59) v1(70.91,64.11) v1(71.17,163.12) v1(71.16,82.92) v1(71.55,151.44) v1(71.55,19.36) v1(71.55,18.59) v1(71.67,1.91) v1(71.8,163.75) v1(71.9,86.79) v1(72.35,100.41) v1(72.28,19.36) v1(72.28,18.59) v1(72.44,163.12) v1(72.82,117.4) v1(72.94,148.64) v1(72.94,147.37) v1(72.94,1.91) v1(73.07,163.75) v1(73.58,18.97) v1(73.58,18.09) v1(73.58,17.2) v1(73.71,163.12) v1(73.96,149.66) v1(74.21,1.91) v1(74.34,163.75) v1(74.98,163.12) v1(75.48,18.97) v1(75.48,18.09) v1(75.48,17.2) v1(75.48,1.91) v1(75.61,163.75) v1(76.25,163.12) v1(76.43,99.56) v1(76.5,102.79) v1(76.75,1.91) v1(76.88,163.75) v1(77.12,100.67) v1(77.06,60.84) v1(77.09,54.78) v1(77.17,56.88) v1(77.26,123.62) v1(77.44,60.12) v1(77.39,39.8) v1(77.39,18.97) v1(77.39,18.09) v1(77.39,17.2) v1(77.52,163.12) v1(77.77,29.39) v1(77.77,28.63) v1(77.77,27.74) v1(78.02,1.91) v1(78.15,163.75) v1(78.15,32.94) v1(78.15,31.93) v1(78.15,30.91) v1(78.56,103.56) v1(78.71,56.39) v1(78.66,1.27) v1(78.79,163.12) v1(78.79,122.1) v1(78.82,101.29) v1(78.79,58.5) v1(78.79,29.39) v1(78.79,28.63) v1(78.79,27.74) v1(79.04,32.94) v1(79.04,31.93) v1(79.04,30.91) v1(79.32,60.56) v1(79.29,1.91) v1(79.42,163.75) v1(79.57,55.08) v1(79.78,57.47) v1(79.93,1.27) v1(80.06,163.12) v1(80.56,123.5) v1(80.62,102.35) v1(80.62,99.93) v1(80.56,1.91) v1(80.69,163.75) v1(80.86,58.55) v1(81.19,56.7) v1(81.2,1.27) v1(81.33,163.12) v1(81.58,19.48) v1(81.58,18.72) v1(81.96,163.75) v1(82.34,19.48) v1(82.34,18.72) v1(82.43,102.21) v1(82.43,100.72) v1(82.47,123.62) v1(82.47,1.27) v1(82.6,60.73) v1(82.72,147.12) v1(82.8,58.31) v1(82.79,56.07) v1(83.1,19.48) v1(83.23,163.75) v1(83.49,157.53) v1(83.74,1.27) v1(83.87,19.48) v1(83.87,18.72) v1(84.4,57.7) v1(84.5,163.75) v1(84.71,19.48) v1(84.71,18.09) v1(84.71,16.69) v1(85.01,1.27) v1(85.24,151.44) v1(85.52,155.7) v1(85.71,146.23) v1(85.77,163.75) v1(86.21,61.09) v1(86.21,58.68) v1(86.33,19.48) v1(86.33,18.09) v1(86.33,16.69) v1(86.28,1.27) v1(86.71,131.23) v1(87.04,163.75) v1(87.04,40.31) v1(87.17,11.74) v1(87.55,1.27) v1(87.71,144.23) v1(87.68,43.49) v1(87.93,40.31) v1(87.93,11.74) v1(87.98,19.48) v1(87.98,18.09) v1(87.98,16.69) v1(88.18,1.91) v1(88.31,163.75) v1(88.37,59.64) v1(88.44,41.96) v1(88.44,41.2) v1(88.69,120.57) v1(88.77,123.52) v1(88.82,40.31) v1(88.82,1.27) v1(89.45,120.57) v1(89.45,1.91) v1(89.58,163.75) v1(89.63,19.48) v1(89.63,18.09) v1(89.63,16.69) v1(89.71,14.66) v1(90.09,1.27) v1(90.72,1.91) v1(90.85,163.75) v1(91.13,133.68) v1(91.36,1.27) v1(91.99,1.91) v1(92.12,163.75) v1(92.63,1.27) v1(93.39,163.75) v1(93.52,141.53) v1(93.65,143.69) v1(93.65,19.86) v1(93.65,19.1) v1(93.9,1.27) v1(94.03,163.12) v1(94.15,103.68) v1(94.43,141.53) v1(94.41,19.86) v1(94.41,19.1) v1(94.53,102.03) v1(94.53,1.91) v1(94.66,163.75) v1(94.66,143.69) v1(95.17,19.86) v1(95.17,19.1) v1(95.17,1.27) v1(95.3,163.12) v1(95.42,116.26) v1(95.42,113.97) v1(95.42,112.45) v1(95.42,111.05) v1(95.42,108.26) v1(95.55,140.89) v1(95.93,19.86) v1(95.93,19.1) v1(96.44,1.27) v1(96.57,163.12) v1(96.57,108.26) v1(96.77,19.48) v1(96.77,18.09) v1(96.77,16.69) v1(97.58,113.97) v1(97.58,112.45) v1(97.58,111.05) v1(97.58,50.22) v1(97.71,116.26) v1(97.71,1.27) v1(97.84,163.12) v1(97.84,133.3) v1(98.4,19.48) v1(98.4,18.09) v1(98.4,16.69) v1(98.6,108.26) v1(98.73,50.47) v1(98.98,1.27) v1(99.11,163.12) v1(99.49,11.74) v1(99.61,1.91) v1(99.87,50.47) v1(100,116.26) v1(100,113.97) v1(100,112.45) v1(100,111.05) v1(100,108.33) v1(100.05,19.48) v1(100.05,18.09) v1(100.05,16.69) v1(100.25,1.27) v1(100.38,163.12) v1(100.38,11.74) v1(100.88,50.47) v1(100.88,1.91) v1(101.47,25.27) v1(101.52,1.27) v1(101.65,163.12) v1(101.65,27.99) v1(101.7,19.48) v1(101.7,18.09) v1(101.7,16.69) v1(101.77,14.66) v1(101.9,50.47) v1(102.15,1.91) v1(102.54,27.99) v1(102.79,50.47) v1(102.79,1.27) v1(102.92,163.12) v1(103.42,27.99) v1(103.42,1.91) v1(103.81,50.47) v1(103.93,155.63) v1(104.06,1.27) v1(104.19,163.12) v1(104.31,27.99) v1(104.82,156.13) v1(104.82,154.99) v1(104.82,153.98) v1(105.33,1.27) v1(105.46,163.12) v1(105.53,110.29) v1(105.58,106.76) v1(105.58,101.57) v1(105.61,19.48) v1(105.61,18.72) v1(105.71,155.63) v1(105.71,126.24) v1(105.84,105.33) v1(106.09,163.75) v1(106.35,50.47) v1(106.35,19.48) v1(106.35,18.72) v1(106.6,111.18) v1(106.6,1.27) v1(106.73,163.12) v1(106.73,49.33) v1(106.85,106.58) v1(107.11,19.48) v1(107.11,18.72) v1(107.36,163.75) v1(107.36,50.47) v1(107.62,106.58) v1(107.87,108.76) v1(107.87,19.48) v1(107.87,18.72) v1(107.87,1.27) v1(108,163.12) v1(108,111.18) v1(108,101.57) v1(108.63,163.75) v1(108.63,50.47) v1(108.71,19.48) v1(108.71,18.09) v1(108.71,16.69) v1(108.76,39.04) v1(109.14,1.27) v1(109.27,163.12) v1(109.27,111.13) v1(109.65,50.47) v1(109.65,49.71) v1(109.65,48.82) v1(109.65,39.04) v1(109.8,105.33) v1(109.77,1.91) v1(109.9,163.75) v1(110.03,108.89) v1(110.03,106.6) v1(110.03,38.02) v1(110.03,37.26) v1(110.28,47.68) v1(110.28,46.66) v1(110.33,19.48) v1(110.33,18.09) v1(110.33,16.69) v1(110.41,1.27) v1(110.54,163.12) v1(110.54,50.47) v1(110.54,49.71) v1(110.54,48.82) v1(110.56,67.11) v1(111.04,1.91) v1(111.17,163.75) v1(111.17,47.68) v1(111.17,46.66) v1(111.68,50.47) v1(111.68,49.71) v1(111.68,48.82) v1(111.68,1.27) v1(111.81,163.12) v1(111.93,84) v1(111.98,19.48) v1(111.98,18.09) v1(111.98,16.69) v1(112.31,75.11) v1(112.31,69.39) v1(112.31,1.91) v1(112.44,163.75) v1(112.57,50.47) v1(112.57,49.71) v1(112.57,48.82) v1(112.95,1.27) v1(113.08,163.12) v1(113.2,75.11) v1(113.2,67.23) v1(113.25,65.63) v1(113.33,39.55) v1(113.46,78.41) v1(113.64,19.48) v1(113.64,18.09) v1(113.64,16.69) v1(113.71,163.75) v1(113.71,50.47) v1(113.71,49.71) v1(113.71,48.82) v1(114.09,79.81) v1(114.22,1.27) v1(114.35,163.12) v1(114.35,39.55) v1(114.35,38.66) v1(114.47,78.41) v1(114.6,50.47) v1(114.6,49.71) v1(114.6,48.82) v1(114.98,163.75) v1(114.98,26.34) v1(115.11,33.2) v1(115.11,30.91) v1(115.11,28.75) v1(115.36,39.55) v1(115.36,38.66) v1(115.49,78.36) v1(115.49,1.27) v1(115.62,163.12) v1(115.74,60.68) v1(115.79,91.49) v1(116.2,90.35) v1(116.25,163.75) v1(116.25,39.55) v1(116.25,38.66) v1(116.38,79.81) v1(116.38,37.39) v1(116.38,36.5) v1(116.76,77.01) v1(116.76,1.27) v1(116.89,163.12) v1(117.06,91.52) v1(117.14,70.41) v1(117.14,69.27) v1(117.14,39.55) v1(117.14,38.66) v1(117.14,37.9) v1(117.39,1.91) v1(117.52,163.75) v1(118.03,39.55) v1(118.03,38.66) v1(118.03,37.9) v1(118.03,1.27) v1(118.16,163.12) v1(118.18,90.22) v1(118.21,88.57) v1(118.66,1.91) v1(118.79,163.75) v1(119.05,128.58) v1(119.3,1.27) v1(119.43,163.12) v1(119.43,98.1) v1(119.43,69.01) v1(119.43,27.48) v1(119.93,1.91) v1(120.06,163.75) v1(120.44,92.76) v1(120.57,27.48) v1(120.57,1.27) v1(120.7,163.12) v1(120.95,138.35) v1(121.2,1.91) v1(121.33,163.75) v1(121.46,98.1) v1(121.71,71.86) v1(121.71,68.5) v1(121.71,67.62) v1(121.84,92.76) v1(121.97,163.12) v1(122.09,90.83) v1(122.47,1.91) v1(122.6,163.75) v1(123.11,59.87) v1(123.11,58.98) v1(123.11,57.96) v1(123.11,56.95) v1(123.24,163.12) v1(123.62,90.35) v1(123.74,92.38) v1(123.74,1.91) v1(123.87,163.75) v1(124.51,163.12) v1(125.01,1.91) v1(125.14,163.75) v1(125.27,90.73) v1(125.4,47.17) v1(125.4,40.06) v1(125.78,163.12) v1(125.78,89.33) v1(126.03,28.37) v1(126.28,47.17) v1(126.28,27.48) v1(126.28,1.91) v1(126.41,163.75) v1(126.67,29.9) v1(126.92,28.37) v1(127.05,163.12) v1(127.05,45.26) v1(127.3,12.37) v1(127.3,10.21) v1(127.3,9.32) v1(127.43,90.7) v1(127.43,88.82) v1(127.55,1.91) v1(127.68,163.75) v1(127.68,46.15) v1(127.81,40.31) v1(127.81,39.29) v1(128.06,144.96) v1(128.19,12.37) v1(128.19,10.21) v1(128.19,9.32) v1(128.32,163.12) v1(128.44,152.71) v1(128.44,150.17) v1(128.44,147.5) v1(128.57,85.52) v1(128.57,46.15) v1(128.82,1.91) v1(128.95,163.75) v1(129.08,10.21) v1(129.08,9.32) v1(129.33,150.17) v1(129.33,147.5) v1(129.33,88.57) v1(129.33,45.26) v1(129.59,163.12) v1(129.69,89.56) v1(129.97,46.28) v1(129.97,40.31) v1(129.97,39.29) v1(130.09,1.91) v1(130.22,163.75) v1(130.22,150.17) v1(130.22,147.5) v1(130.22,57.33) v1(130.48,62.28) v1(130.48,18.97) v1(130.48,18.09) v1(130.48,17.2) v1(130.6,145.21) v1(130.86,163.12) v1(130.86,46.28) v1(131.42,85.52) v1(131.36,62.28) v1(131.36,18.59) v1(131.36,17.58) v1(131.36,1.91) v1(131.49,163.75) v1(131.62,45.39) v1(131.75,132.13) v1(132.03,88.57) v1(132.13,163.12) v1(132.13,46.28) v1(132.38,18.97) v1(132.38,18.09) v1(132.38,17.2) v1(132.63,1.91) v1(132.76,163.75) v1(133.02,46.28) v1(133.02,36.63) v1(133.14,135.43) v1(133.27,1.27) v1(133.4,163.12) v1(133.4,18.59) v1(133.4,17.58) v1(133.65,144.45) v1(133.65,142.55) v1(133.9,46.28) v1(133.9,45.26) v1(133.9,1.91) v1(134.03,163.75) v1(134.03,36.63) v1(134.29,85.52) v1(134.29,18.97) v1(134.29,18.09) v1(134.29,17.2) v1(134.54,1.27) v1(134.67,163.12) v1(134.92,46.28) v1(134.92,36.63) v1(135.15,131.32) v1(135.17,1.91) v1(135.3,163.75) v1(135.81,159.31) v1(135.81,157.02) v1(135.81,1.27) v1(135.94,163.12) v1(136.06,46.28) v1(136.06,45.14) v1(136.32,57.07) v1(136.32,36.63) v1(136.44,156.13) v1(136.44,1.91) v1(136.57,158.17) v1(137.08,1.27) v1(137.23,13.54) v1(137.33,159.31) v1(137.33,157.02) v1(137.46,156.13) v1(137.71,1.91) v1(138.35,1.27) v1(138.98,100.51) v1(138.98,99.62) v1(138.98,1.91) v1(139.44,134.29) v1(139.62,142.29) v1(139.62,132.13) v1(139.62,18.97) v1(139.62,1.27) v1(140.25,1.91) v1(140.51,131.5) v1(140.89,1.27) v1(141.14,100.13) v1(141.4,134.29) v1(141.52,1.91) v1(142.16,1.27) v1(142.79,15.8) v1(142.79,1.91) v1(143.05,103.43) v1(143.05,101.65) v1(143.05,100.13) v1(143.05,98.35) v1(143.05,96.95) v1(143.3,27.86) v1(143.43,51.61) v1(143.43,1.27) v1(143.56,163.12) v1(144.19,51.61) v1(144.45,35.87) v1(144.45,34.72) v1(144.57,60.63) v1(144.57,59.74) v1(144.7,19.1) v1(144.7,1.27) v1(144.83,163.12) v1(144.83,100.13) v1(145.08,162.36) v1(145.08,161.47) v1(145.33,1.91) v1(145.46,35.87) v1(145.46,34.72) v1(145.59,60.63) v1(145.59,59.74) v1(145.97,1.27) v1(146.1,163.12) v1(146.1,161.47) v1(146.1,44.25) v1(146.48,100.25) v1(146.48,35.87) v1(146.48,34.72) v1(146.6,1.91) v1(146.73,163.75) v1(146.99,98.73) v1(146.99,97.08) v1(146.99,44.25) v1(147.24,1.27) v1(147.37,163.12) v1(147.49,35.87) v1(147.49,34.72) v1(147.87,44.25) v1(147.87,1.91) v1(148,163.75) v1(148.51,1.27) v1(148.64,163.12) v1(148.64,35.87) v1(148.64,34.72) v1(148.76,44.25) v1(149.14,1.91) v1(149.27,163.75) v1(149.65,44.25) v1(149.78,35.87) v1(149.78,34.72) v1(149.78,1.27) v1(149.91,163.12) v1(150.16,27.99) v1(150.41,102.77) v1(150.41,1.91) v1(150.54,163.75) v1(150.54,152.2) v1(150.92,156.01) v1(151.05,1.27) v1(151.18,163.12) v1(151.68,1.91) v1(151.81,163.75) v1(151.81,156.01) v1(151.81,153.59) v1(152.32,1.27) v1(152.45,163.12) v1(152.7,7.8) v1(152.95,103.3) v1(152.95,1.91) v1(153.08,163.75) v1(153.59,1.27) v1(153.72,163.12) v1(153.72,51.87) v1(153.72,49.96) v1(153.72,42.47) v1(153.72,40.56) v1(153.72,38.66) v1(154.1,50.98) v1(154.1,49.07) v1(154.1,41.58) v1(154.1,39.55) v1(154.22,1.91) v1(154.35,163.75) v1(154.61,51.87) v1(154.61,49.96) v1(154.61,42.47) v1(154.61,40.56) v1(154.61,38.66) v1(154.86,1.27) v1(154.99,163.12) v1(155.11,50.98) v1(155.11,49.07) v1(155.11,41.58) v1(155.11,39.55) v1(155.49,51.87) v1(155.49,49.96) v1(155.49,42.47) v1(155.49,40.56) v1(155.49,38.66) v1(155.49,1.91) v1(155.62,163.75) v1(155.88,160.33) v1(155.88,159.56) v1(156.13,1.27) v1(156.26,163.12) v1(156.64,25.32) v1(156.76,1.91) v1(156.89,163.75) v1(157.04,107.7) v1(157.15,53.82) v1(157.4,160.33) v1(157.4,159.56) v1(157.4,153.09) v1(157.4,152.2) v1(157.4,62.56) v1(157.4,61.39) v1(157.4,1.27) v1(157.53,163.12) v1(158.03,53.82) v1(158.03,1.91) v1(158.16,163.75) v1(158.29,152.2) v1(158.29,62.56) v1(158.29,61.39) v1(158.42,160.33) v1(158.42,159.56) v1(158.67,1.27) v1(158.8,163.12) v1(158.8,53.82) v1(159.18,125.91) v1(159.18,124.21) v1(159.18,122.61) v1(159.18,62.56) v1(159.18,61.39) v1(159.3,1.91) v1(159.43,163.75) v1(159.64,88.34) v1(159.69,53.82) v1(159.81,127.18) v1(159.81,111.61) v1(159.94,33.71) v1(159.94,1.27) v1(160.07,163.12) v1(160.57,1.91) v1(160.7,163.75) v1(160.83,33.71) v1(161.21,98.86) v1(161.21,1.27) v1(161.34,163.12) v1(161.84,45.64) v1(161.84,1.91) v1(161.97,163.75) v1(162.48,1.27) v1(162.61,163.12) v1(162.63,132.54) v1(162.61,129.85) v1(162.73,45.64) v1(162.86,49.58) v1(162.86,48.69) v1(162.86,47.42) v1(163.11,1.91) v1(163.24,163.75) v1(163.75,1.27) v1(163.88,163.12) v1(164.38,1.91) v1(164.51,163.75) v1(164.77,60.38) v1(164.77,23.29) v1(165.02,59.36) v1(165.02,57.07) v1(165.02,55.42) v1(165.02,1.27) v1(165.15,163.12) v1(165.35,104.32) v1(165.35,103.05) v1(165.65,1.91) v1(165.78,163.75) v1(165.78,58.22) v1(165.91,113.59) v1(166.04,126.04) v1(166.04,55.42) v1(166.29,60.38) v1(166.29,1.27) v1(166.42,163.12) v1(166.54,59.36) v1(166.54,57.07) v1(166.67,70.16) v1(166.67,69.27) v1(166.67,66.98) v1(166.92,1.91) v1(167.05,163.75) v1(167.18,126.04) v1(167.43,103.94) v1(167.43,68.12) v1(167.56,1.27) v1(167.69,163.12) v1(167.69,115.62) v1(167.69,114.1) v1(167.69,112.57) v1(167.81,102.08) v1(168.19,131.37) v1(168.19,66.98) v1(168.19,1.91) v1(168.32,163.75) v1(168.32,129.67) v1(168.32,127.81) v1(168.32,126.16) v1(168.83,1.27) v1(168.96,163.12) v1(169.21,115.62) v1(169.21,114.1) v1(169.21,112.57) v1(169.34,141.91) v1(169.46,132.51) v1(169.46,131.62) v1(169.46,1.91) v1(169.59,163.75) v1(169.85,120.07) v1(170.1,1.27) v1(170.23,163.12) v1(170.35,141.91) v1(170.35,132.51) v1(170.35,127.81) v1(170.38,103.94) v1(170.48,131.62) v1(170.61,151.31) v1(170.61,141.02) v1(170.61,1.96) v1(170.73,115.62) v1(170.73,114.1) v1(170.73,112.57) v1(170.86,163.75) v1(171.37,1.27) v1(171.5,163.12) v1(171.62,141.02) v1(171.73,2.11) v1(171.75,152.32) v1(171.75,151.31) v1(172.13,163.75) v1(172.51,141.02) v1(172.64,120.07) v1(172.64,1.27) v1(172.77,163.12) v1(172.77,152.32) v1(173.23,2.13) v1(173.27,127.56) v1(173.4,163.75) v1(173.5,125.78) v1(173.5,124.13) v1(173.53,102.03) v1(173.91,1.27) v1(174.04,163.12) v1(174.67,163.75) v1(174.67,9.58) v1(174.67,8.31) v1(174.73,2.15) v1(175.18,1.27) v1(175.31,163.12) v1(175.74,111.07) v1(175.69,49.45) v1(175.69,47.3) v1(175.69,45.01) v1(175.81,9.58) v1(175.81,8.31) v1(175.94,163.75) v1(176.07,102.16) v1(176.23,2.11) v1(176.45,1.27) v1(176.48,111.07) v1(176.58,163.12) v1(176.7,49.45) v1(176.7,47.3) v1(176.7,45.01) v1(176.96,9.58) v1(176.96,8.31) v1(177.21,163.75) v1(177.47,103.18) v1(177.72,137.47) v1(177.72,135.18) v1(177.72,112.32) v1(177.72,1.27) v1(177.85,163.12) v1(177.97,147.88) v1(177.97,145.59) v1(178.1,149.15) v1(178.1,138.23) v1(178.35,134.16) v1(178.35,133.15) v1(178.48,163.75) v1(178.48,141.15) v1(178.48,136.32) v1(178.61,144.42) v1(178.61,143.56) v1(178.74,146.74) v1(178.99,138.23) v1(178.99,1.27) v1(179.12,163.12) v1(179.24,149.15) v1(179.24,137.47) v1(179.24,135.18) v1(179.37,141.15) v1(179.37,134.16) v1(179.37,133.15) v1(179.5,147.88) v1(179.5,145.59) v1(179.5,144.42) v1(179.5,143.56) v1(179.5,127.81) v1(179.5,107.11) v1(179.75,163.75) v1(179.75,110.54) v1(180.26,1.27) v1(180.39,163.12) v1(180.4,127.83) v1(180.51,11.23) v1(180.51,10.34) v1(181.02,163.75) v1(181.53,1.27) v1(181.66,163.12) v1(182.16,14.02) v1(182.16,12.75) v1(182.29,163.75) v1(182.8,1.27) v1(182.93,163.12) v1(183.18,14.02) v1(183.18,12.75) v1(183.56,163.75) v1(183.69,91.75) v1(183.69,90.22) v1(183.82,132.64) v1(183.82,130.35) v1(184.07,1.27) v1(184.2,163.12) v1(184.2,14.02) v1(184.2,12.75) v1(184.58,162.1) v1(184.58,161.21) v1(184.83,163.75) v1(184.83,159.31) v1(184.83,157.4) v1(185.34,127.94) v1(185.34,124.97) v1(185.34,1.27) v1(185.47,163.12) v1(185.59,162.1) v1(185.59,161.21) v1(185.59,130.1) v1(185.72,158.29) v1(185.72,80.06) v1(185.72,78.03) v1(185.72,70.28) v1(185.97,141.58) v1(186.1,163.75) v1(186.1,132.39) v1(186.48,65.08) v1(186.48,14.02) v1(186.61,162.1) v1(186.61,161.21) v1(186.61,157.4) v1(186.74,163.12) v1(186.74,159.18) v1(186.74,133.15) v1(187.24,131.37) v1(187.24,130.23) v1(187.24,125.78) v1(187.37,135.56) v1(187.37,123.62) v1(187.37,122.73) v1(187.63,14.02) v1(188.01,163.12) v1(188.39,131.37) v1(188.39,130.23) v1(188.51,1.91) v1(189.28,163.12) v1(189.78,1.91) v1(190.55,163.12) v1(191.05,1.91) v1(191.82,163.12) v1(192.32,1.91) v1(192.96,161.6) v1(192.96,160.71) v1(192.96,157.91) v1(192.96,157.15) v1(192.96,111.81) v1(192.99,78.26) v1(192.99,77.39) v1(192.99,74.45) v1(192.99,73.58) v1(193.09,163.12) v1(193.09,109.65) v1(193.47,39.04) v1(193.47,38.15) v1(193.47,37.14) v1(193.59,1.91) v1(193.72,161.6) v1(193.72,160.71) v1(193.72,157.91) v1(193.72,157.15) v1(193.72,118.67) v1(193.72,115.62) v1(193.72,107.06) v1(193.67,104.24) v1(193.72,99.24) v1(193.98,133.27) v1(193.98,131.37) v1(193.98,87.94) v1(194.23,101.91) v1(194.36,163.12) v1(194.48,128.78) v1(194.48,125.96) v1(194.48,120.75) v1(194.48,39.04) v1(194.48,38.15) v1(194.48,37.14) v1(194.61,96.95) v1(194.61,94.36) v1(194.86,1.91) v1(194.97,123.62) v1(195.37,39.04) v1(195.37,38.15) v1(195.37,37.14) v1(195.37,31.67) v1(195.37,30.79) v1(195.5,1.27) v1(195.63,163.12) v1(195.63,131.19) v1(196.13,90.22) v1(196.13,86.92) v1(196.13,1.91) v1(196.26,163.75) v1(196.52,138.74) v1(196.64,115.6) v1(196.67,134.93) v1(196.77,1.27) v1(197.4,39.04) v1(197.4,38.15) v1(197.4,37.26) v1(197.53,31.67) v1(197.53,30.79) v1(198.04,129.08) v1(198.04,123.88) v1(198.42,90.22) v1(199.69,31.67) v1(199.69,30.79) v1(201.85,136.83) v1(201.85,133.02) v1(201.9,117.53) v1(202.1,36.5) v1(202.1,35.48) v1(202.1,34.21) v1(202.1,33.33) v1(202.23,140.67) v1(202.48,106.86) v1(202.61,99.87) v1(203.12,156.13) v1(203.12,154.86) v1(203.12,153.59) v1(203.12,152.32) v1(203.12,147.24) v1(203.12,145.97) v1(203.12,144.7) v1(203.12,143.43) v1(203.12,142.16) v1(203.12,140.89) v1(203.12,137.08) v1(203.12,133.27) v1(203.12,129.46) v1(203.12,125.65) v1(203.12,121.84) v1(203.12,114.22) v1(203.12,110.41) v1(203.12,103.81) v1(203.12,102.54) v1(203.12,98.48) v1(203.12,97.21) v1(203.12,95.94) v1(203.12,94.67) v1(203.12,93.4) v1(203.12,92.13) v1(203.12,90.86) v1(203.12,89.59) v1(203.12,88.32) v1(203.12,87.05) v1(203.12,85.78) v1(203.12,84.51) v1(203.12,83.24) v1(203.12,81.97) v1(203.12,80.7) v1(203.12,79.43) v1(203.12,78.16) v1(203.12,76.89) v1(203.12,75.62) v1(203.12,74.35) v1(203.12,70.54) v1(203.12,69.27) v1(203.12,68) v1(203.12,66.73) v1(203.12,65.46) v1(203.12,61.65) v1(203.12,60.38) v1(203.37,138.86) v1(203.5,116) v1(203.5,105.59) v1(203.75,155.5) v1(203.75,154.23) v1(203.75,152.96) v1(203.75,151.69) v1(203.75,146.61) v1(203.75,145.34) v1(203.75,144.07) v1(203.75,142.8) v1(203.75,141.53) v1(203.75,140.26) v1(203.75,137.72) v1(203.75,136.45) v1(203.75,135.18) v1(203.75,133.91) v1(203.75,132.64) v1(203.75,131.37) v1(203.75,130.1) v1(203.75,128.83) v1(203.75,127.56) v1(203.75,126.29) v1(203.75,125.02) v1(203.75,123.75) v1(203.75,122.48) v1(203.75,121.21) v1(203.75,119.94) v1(203.75,118.67) v1(203.75,117.4) v1(203.75,114.86) v1(203.75,113.59) v1(203.75,112.32) v1(203.75,111.05) v1(203.75,109.78) v1(203.75,108) v1(203.75,106.73) v1(203.75,104.19) v1(203.75,102.92) v1(203.75,101.65) v1(203.75,100.38) v1(203.75,99.11) v1(203.75,97.84) v1(203.75,96.57) v1(203.75,95.3) v1(203.75,94.03) v1(203.75,92.76) v1(203.75,91.49) v1(203.75,90.22) v1(203.75,88.95) v1(203.75,87.68) v1(203.75,86.41) v1(203.75,85.14) v1(203.75,83.87) v1(203.75,82.6) v1(203.75,81.33) v1(203.75,80.06) v1(203.75,78.79) v1(203.75,77.52) v1(203.75,76.25) v1(203.75,74.98) v1(203.75,73.71) v1(203.75,72.44) v1(203.75,71.17) v1(203.75,69.9) v1(203.75,68.63) v1(203.75,67.36) v1(203.75,66.09) v1(203.75,64.82) v1(203.75,53.39) v1(203.75,52.12) v1(203.75,50.85) v1(203.75,49.58) v1(203.75,48.31) v1(203.75,47.04) v1(203.75,45.77) v1(203.75,44.5) v1(203.75,43.23) v1(203.75,41.96) v1(203.75,40.69) v1(203.75,39.42) v1(203.75,38.15) v1(203.75,36.88) v1(203.75,35.61) v1(203.75,34.34) v1(203.75,33.07) v1(203.75,31.8) v1(203.75,30.53) v1(203.75,29.26) v1(203.75,25.45) v1(203.75,24.18) v1(203.75,22.91) v1(203.75,21.64) v1(203.75,20.37) v1(203.75,19.1) v1(203.75,17.83) v1(203.75,16.56) v1(203.75,15.29) v1(203.75,14.02) v1(203.75,12.75) v1(203.75,11.48) v1(203.75,10.21) v2(81.19,67.77) v2(81.71,92.13) v2(86,80.44) v2(87.93,49.33) v2(91.61,101.02) v2(93.01,100.51) v2(94.03,77.9) v2(94.03,76.38) v2(98.34,77.65) v2(98.47,100.89) v2(100.76,100.99) v2(102.92,100.38) v2(103.68,101.6) v2(103.81,100) v2(106.35,99.39) v2(109.52,90.81) v2(109.9,71.81) v2(111.81,90.35) v2(111.98,91.8) v2(113.81,90.35) v2(114.4,91.49) v2(154.69,123.43) v3(82.62,5.13) v3(82.62,3.61) v3(82.62,2.21) v3(86.53,5.13) v3(86.53,3.61) v3(86.53,2.21) v3(87.17,48.57) v3(87.17,47.3) v3(87.17,45.77) v3(88.44,48.57) v3(88.44,47.17) v3(88.44,45.64) v3(88.57,31.8) v3(88.69,33.2) v3(88.87,51.49) v3(88.87,50.22) v3(89.96,45.16) v3(89.96,44.07) v3(89.96,42.98) v3(89.96,41.83) v3(89.96,40.69) v3(90.17,36.75) v3(90.19,35.1) v3(90.19,33.45) v3(90.47,31.04) v3(90.47,27.23) v3(91.99,31.04) v3(92.12,27.1) v3(92.88,25.2) v3(92.88,24.05) v3(92.88,22.78) v3(93.65,5.13) v3(93.65,3.61) v3(93.65,2.21) v3(97.58,5.13) v3(97.58,3.61) v3(97.58,2.21) v3(104.44,5.13) v3(104.44,3.61) v3(104.44,2.21) v3(104.87,26.09) v3(104.87,24.69) v3(108.38,5.13) v3(108.38,3.61) v3(108.38,2.21) v3(137.21,25.2) v3(137.21,23.67) v3(137.71,30.15) v3(137.71,28.88) v3(164.26,161.85) v3(164.26,160.45) v3(164.38,156.77) v3(164.38,155.5) v3(165.65,161.85) v3(165.65,160.45) v3(165.78,156.77) v3(165.78,155.5) v3(188.01,139.5) v3(188.01,138.1) v3(188.13,44.6) v3(188.26,142.67) v3(189.4,44.6) v3(189.4,43.33) v3(189.78,139.5) v3(189.78,138.1) v3(190.04,142.67) v3(190.42,25.2) v3(190.42,23.67) v3(190.42,22.02) v3(192.07,25.2) v3(192.07,23.67) v3(192.07,22.02) v3(192.71,44.6) v3(192.71,43.33) v3(193.85,25.2) v3(193.85,23.67) v3(193.85,22.02) v3(193.98,44.6) v4(59.48,23.93) v4(59.48,22.53) v4(59.48,21.13) v4(60.88,23.93) v4(60.88,22.53) v4(60.88,21.13) v4(62.28,23.93) v4(62.28,22.53) v4(62.28,21.13) v4(120.57,23.93) v4(120.57,22.53) v4(120.57,21.13) v4(121.97,23.93) v4(121.97,22.53) v4(121.97,21.13) v4(123.36,23.93) v4(123.36,22.53) v4(123.36,21.13) v4(167.43,37.52) v4(167.43,36.12) v4(167.43,34.72) v4(168.83,37.52) v4(168.83,36.12) v4(168.83,34.72) v4(170.23,37.52) v4(170.23,36.12) v4(170.23,34.72)
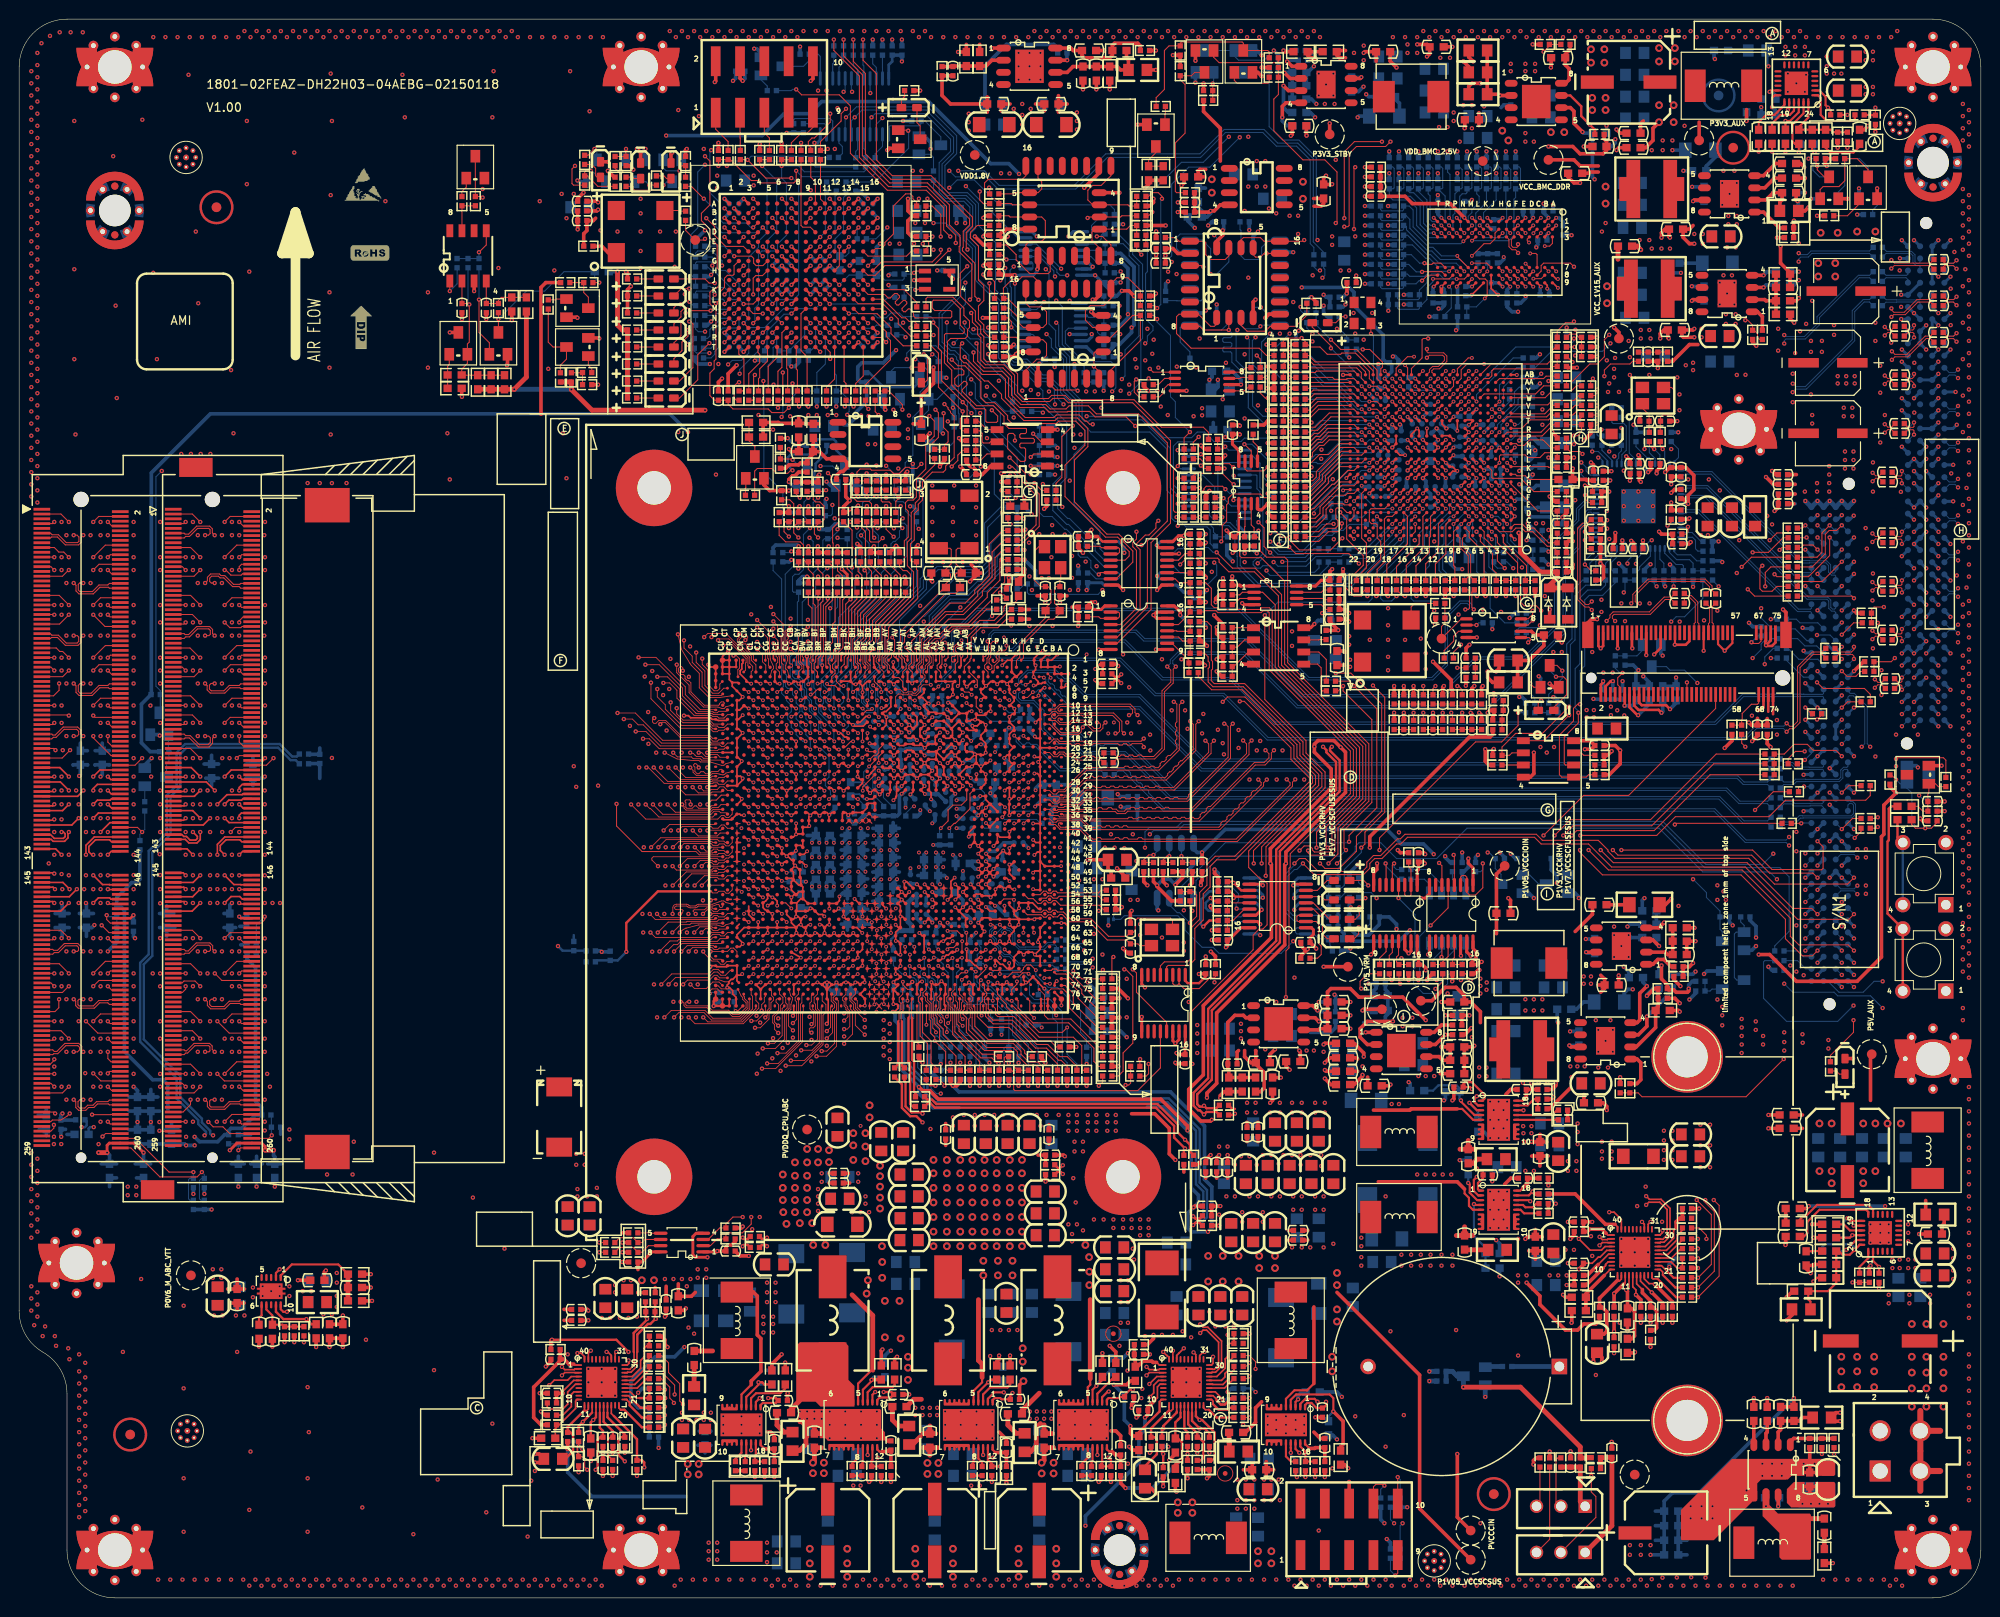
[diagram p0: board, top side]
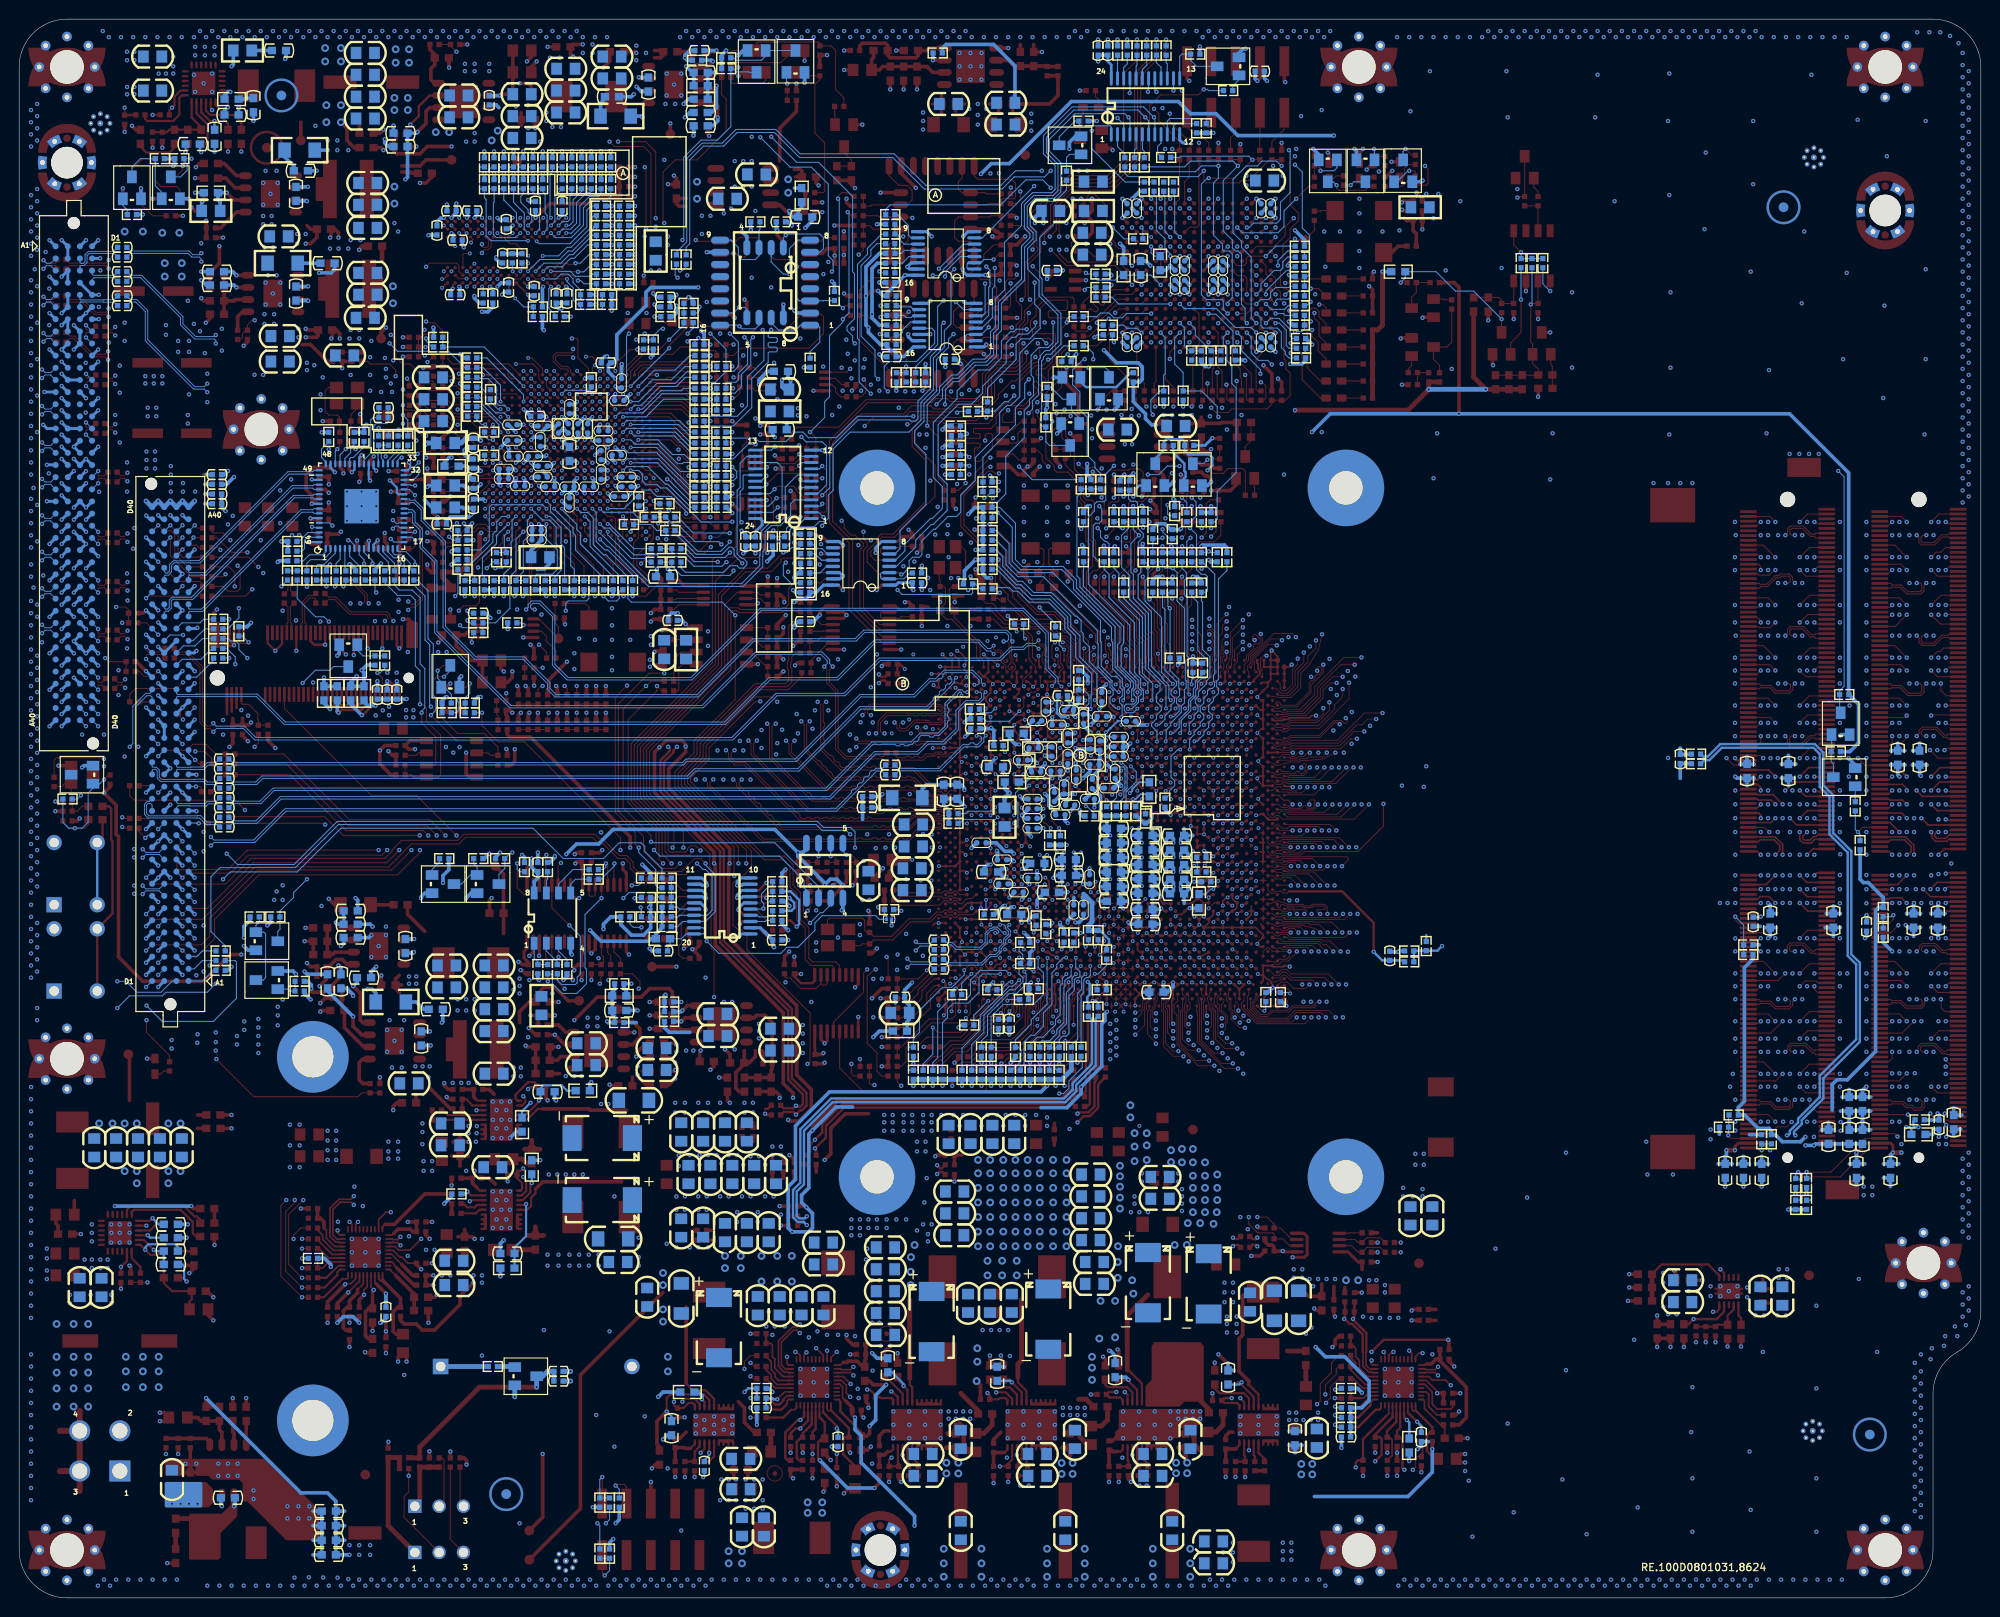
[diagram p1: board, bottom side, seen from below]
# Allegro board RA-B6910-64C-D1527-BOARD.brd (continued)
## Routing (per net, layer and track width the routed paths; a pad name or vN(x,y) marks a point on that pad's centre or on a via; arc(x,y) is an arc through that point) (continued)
P0V6_M_ABC_VTT: length 26.9
  TOP w0.305: v1(9.19,46.53) 9.19,47.3 9.42,47.53 J7.258 12.01,47.53 v1(13,46.53) ; v1(22.02,46.79) 22.76,47.53 J8.258 25.34,47.53 25.7,47.17 v1(25.7,46.79)
  TOP w0.381: 21.79,32.28 C81.1 ; C81.1 22.78,33.33 ; C81.1 23.55,32.28
  TOP w0.508: v1(25.7,46.79) v1(26.59,46.79) ; v1(8.3,46.53) v1(9.19,46.53)
  BOTTOM w0.381: C527.1 9.44,46.28 v1(9.19,46.53) ; C527.1 8.58,45.36 ; C527.1 10.18,45.36 ; 12.14,45.36 C804.1 ; C804.1 13.74,45.36 ; C804.1 v1(13,46.53) ; 25.98,45.36 C800.1 ; C800.1 26.72,46.09 26.59,46.22 v1(26.59,46.79) ; C800.1 27.45,45.36 ; C799.1 24.81,46.15 ; C799.1 24.2,45.36 ; C799.1 25.42,45.36 ; 22.17,45.36 C803.1 ; C803.1 23.52,45.36 ; C803.1 22.91,46.15
  vias: v1(20.24,34.34) v1(20.24,33.45) v1(21.13,34.34) v1(21.13,33.45)
P0V9_NIC_OUT: length 26.4
  TOP w0.381: v1(174.54,112.83) 174.44,112.73 C285.1 ; v1(170.23,117.65) 170.51,117.93 C286.1 ; C287.1 v1(167.53,110.52) ; C284.1 164.51,118.42 v1(164.26,118.67)
  SIG2 w0.381: v1(174.54,112.83) 171.88,112.83 170.86,111.81 168.83,111.81 v1(167.53,110.52) 167.53,111.56 166.73,112.36 166.73,113.65 164.26,116.13 v1(164.26,118.67)
  BOTTOM w0.229: U26.59 174.52,112.85 v1(174.54,112.83) ; v1(164.26,118.67) 164.14,118.55 164.14,118.08 164.37,117.85 U26.32 ; v1(170.23,117.65) 169.96,117.92 U26.42 ; v1(167.53,110.52) 167.96,110.09 U26.11 ; v1(167.69,117.81) 167.96,118.08 U26.38
  vias: v1(166.16,126.92) v1(166.67,128.45) v1(166.67,127.56)
P1V2_VDDQ_EN: length 322.4
  TOP w0.109: v1(67.48,21.77) 67.23,21.77 67.1,21.9 R725.2 ; U2.D16 v1(89.71,143.23)
  SIG3 w0.107: v1(89.71,143.23) 90.01,143.23 90.47,143.69 90.61,143.69 91.08,144.16 91.82,144.16 92.89,145.23 116.49,145.23 117.78,143.94 120.54,143.94 126.06,138.42 128.64,138.42 134.47,132.6 134.47,127.25 135.56,126.16 135.56,121.72 133.51,119.67 133.51,112.45 133.78,112.18 133.78,110.67 134.04,110.4 134.04,96.89 137.49,93.45 139.87,93.45 142.13,91.19 147.57,91.19 152.6,86.16 169.13,86.16 174.06,81.23 174.06,80.04 179.28,74.81 179.28,71.7 178.24,70.66 178.24,69.33 179.02,68.55 179.02,65.79 182.8,62 182.8,58.39 v1(182.24,57.84)
  SIG4 w0.086: v1(67.48,21.77) 67.86,21.77 68.12,22.02 87.8,22.02 90.66,19.16 90.66,13.45 93.52,10.59 116.63,10.59 119.6,13.56 121.26,13.56 121.41,13.72 125.7,13.72 125.97,13.45 132.04,13.45 133.48,12.01 137.4,12.01 138.36,12.97 141.87,12.97 142.3,13.4 154.31,13.4 160.96,20.05 167.25,20.05 172.32,25.11 172.78,25.11 182.04,34.37 182.04,57.63 v1(182.24,57.84)
  BOTTOM w0.109: v1(67.48,21.77) 67.23,21.77 67.1,21.9 R725.2
P1V2_VDDQ_PG: length 326.6
  TOP w0.109: R92.2 80.59,125.17 80.82,125.4 v1(80.82,126.92)
  TOP w0.178: U36.17 61.48,19.36
  TOP w0.254: v1(63.29,14.28) 62.62,14.94 62.62,16.63 62.78,16.79 R335.1 63.29,17.07 61.48,18.88 61.48,19.36
  SIG1 w0.086: v1(80.82,126.92) 81.83,125.91 92.25,125.91 92.82,125.34 97.52,125.34 98.34,124.51 100.25,124.51 100.85,125.11 105.29,125.11 105.47,125.29 106.6,125.29 107.11,125.8 107.11,126.29 107.76,126.94 115.51,126.94 115.82,127.25 116.18,127.25 117.01,126.42 v1(117.01,126.16)
  SIG3 w0.107: v1(136.06,119.05) 136.06,118.29 135.56,117.78 135.56,116.75 134.6,115.79 134.6,112.95 134.96,112.59 134.96,111.14 135.43,110.67 135.43,102.54 135.81,102.16 135.81,96.8 138.05,94.56 140.38,94.56 141.71,93.24 149.81,93.24 150.29,92.76 150.29,91.75 152.45,89.59 154.43,89.59 156.59,87.43 169.59,87.43 175.28,81.74 175.28,80.45 180.4,75.32 180.4,69.88 180.13,69.61 180.13,66.6 184.45,62.28 v1(184.45,59.11)
  SIG4 w0.086: v1(63.29,14.28) 64.05,14.28 68.75,9.58 116.76,9.58 119.81,12.62 121.33,12.62 121.97,11.99 123.74,11.99 124.18,11.56 132.68,11.56 132.97,11.27 152.95,11.27 161.18,19.5 167.48,19.5 172.54,24.56 173.01,24.56 183.11,34.67 183.11,37.58 183.54,38.01 183.54,53.15 183.13,53.57 183.13,57.79 v1(184.45,59.11) ; v1(136.06,119.05) 135.05,120.07 127.68,120.07 126.67,121.08 126.67,121.46 125.65,122.48 119.55,122.48 117.01,125.02 v1(117.01,126.16)
P1V3_VCCKRHV: length 12.3
  TOP w0.178: U43.N51 103.19,75.21 v2(103.5,74.9) ; U43.N58 102.99,72.32 v2(102.97,72.34)
  TOP w0.381: C205.1 139.87,55.04 ; v1(140.51,56.57) 140.51,56.95 139.49,57.96 C206.1 ; C204.1 139.75,56.44 139.87,56.31 ; C203.1 140.92,54.43 ; v1(140.38,54.66) 140.38,54.53 139.49,53.65 C202.1 ; X28.1 140.51,61.52 v1(140.38,61.39)
  BOTTOM w0.381: C199.2 v1(140.38,61.39) ; R301.1 140.51,60.12
  vias: v1(140.38,55.55)
P1V3_VCCKRHV_EN: length 142.6
  TOP w0.109: U2.F4 v1(77.71,140.23)
  TOP w0.381: v1(151.56,60.88) R299.2 R302.2
  SIG3 w0.107: v1(77.71,140.23) 77.71,139.61 78.58,138.74 79.16,138.74 79.94,137.95 87.83,137.95 88.18,137.59 88.18,136.96 89.07,136.07 92.17,136.07 92.85,135.38 98.98,135.38 99.16,135.2 105.1,135.2 105.96,136.07 110.03,136.07 111.17,134.93 113.58,134.93 113.91,134.6 117.34,134.6 118.13,133.8 118.14,133.8 118.79,133.15 119.42,133.15 120.24,132.33 120.24,124.44 119.59,123.79 119.59,111.85 118.39,110.64 118.38,110.64 118.08,110.34 118.08,97.16 120,95.23 120,92.5 121.36,91.15 121.36,89.24 128.94,81.66 140.31,81.66 143.44,78.53 143.44,78.16 144.88,76.71 144.88,68.84 149.01,64.71 149.01,64.32 149.78,63.55 149.78,62.66 v1(151.56,60.88)
P1V3_VCCKRHV_PG: length 135.7
  TOP w0.109: U2.N11 v1(84.71,133.23)
  TOP w0.381: U16.7 148,57.84 v1(149.02,58.85) R300.2
  SIG3 w0.107: v1(149.02,58.85) 149.53,59.36 149.53,62.03 148.64,62.92 148.64,64.69 144.6,68.73 144.6,76.58 143.05,78.13 143.05,78.38 140.05,81.38 128.83,81.38 121.08,89.13 121.08,91.04 119.73,92.39 119.73,95 117.78,96.95 117.78,110.7 118.6,111.52 118.6,113.11 119.31,113.82 119.31,123.9 119.96,124.55 119.96,131.98 119.24,132.7 118.86,132.7 118.01,133.55 115.63,133.55 115.37,133.28 110.57,133.28 109.62,134.24 100.45,134.24 100,133.78 99.36,133.78 98.58,134.56 91.95,134.56 91.46,135.05 86.66,135.05 84.84,133.23 v1(84.71,133.23)
P1V5_NIC_OUT: length 12.2
  TOP w0.381: v1(168.32,116.76) 168.35,116.79 C274.1 ; C276.1 173.88,114.88 v1(174.41,114.35) 174.41,115.24 175,115.82 175,117.32 174.19,118.14 C275.1 C277.1 172.49,118.14 v1(172,117.65)
  BOTTOM w0.229: v1(172,117.65) 172.46,118.11 U26.47 ; U26.56 v1(174.41,114.35) ; v1(168.32,116.76) 168.46,116.9 U26.39
  vias: v1(166.16,119.81) v1(166.7,119.3) v1(174.16,128.83) v1(174.93,129.08) v1(174.93,128.32)
P1V05_PCH: length 91.2
  TOP w0.178: v2(97.82,88.04) U43.AC21 ; v2(97.82,88.04) U43.AC23 v2(98.62,87.24) U43.AC25 98.2,86.84 v2(97.81,87.23) 97.42,86.84 U43.AE25 ; v2(97.82,88.04) U43.AE21 U43.AG23 U43.AH21 ; U43.AM14 v2(94.62,91.24) U43.AM16 94.14,90.76 94.14,90.12 U43.AM18 v2(94.62,89.64) U43.AK18 ; U43.AP25 v2(93.82,86.44) ; U43.AK27 U43.AM27 v2(93.82,85.64) U43.AP27 U43.AR27 v2(92.22,85.64) U43.AU27 v2(91.42,85.64) U43.AW27 ; U43.AK27 v2(95.42,85.64) ; U43.AK27 v2(95.42,86.44) U43.AK25 v2(94.62,87.24) ; U43.AH21 U43.AK21 ; U43.AH21 v2(96.22,88.84) ; U43.AH21 U43.AH23 ; U43.AH23 U43.AK23 v2(94.62,87.24) ; U43.AH23 v2(96.22,87.24) U43.AG25 U43.AG27 v2(97.02,85.64) ; v2(94.62,87.24) U43.AM25 ; v2(94.62,87.24) U43.AM23
  TOP w0.229: U35.5 151.94,49.96 150.8,51.11 150.29,51.11
  TOP w0.254: 127.05,51.11 126.77,51.11 R359.2 ; v2(112.44,97.08) 112.95,97.59 C236.1 R360.1
  TOP w0.381: C464.1 130.98,51.99 v1(130.73,51.74) ; 141.52,50.98 145.33,50.98 145.46,51.11 150.29,51.11 ; C774.1 129.46,49.71 ; C773.1 128.32,49.71 ; R22.1 v1(143.68,92.51)
  SIG4 w0.381: v2(111.55,98.6) 112.19,97.97 118.16,97.97 119.87,96.25 132.7,96.25 136.44,92.51 v1(143.68,92.51)
  BOTTOM w0.381: C660.1 v2(97.96,82.47) ; v2(97.96,81.71) 98.22,81.46 C659.1 ; C668.1 93.11,86.35 v2(93.82,85.64) ; C661.1 94.53,87.15 v2(94.62,87.24) ; C658.1 102.18,86.27 v2(102,86.09) ; C665.1 97.74,87.96 v2(97.82,88.04) ; C670.1 98.24,86.64 97.81,87.07 v2(97.81,87.23) ; v2(95.42,85.64) 95.8,85.26 C669.1 ; C672.1 98.09,83.49 v2(97.96,83.36) ; C664.1 98.94,87.55 v2(98.62,87.24) ; C666.1 97.18,85.79 v2(97.02,85.64) ; C662.1 94.91,89.36 v2(94.62,89.64) ; C673.1 v2(97.96,80.44) ; C671.1 115.21,82.6 v1(115.11,82.7) ; C663.1 115.06,83.74 v1(114.8,84) ; C667.1 v2(95.42,86.44)
  vias: v1(109.65,79.81) v1(110.54,79.81) v1(128.32,51.74) v1(128.32,50.72) v1(129.21,51.74) v1(129.21,50.72) v1(130.73,50.72) v1(131.75,51.74) v1(131.75,50.72) v1(133.02,51.74) v1(133.02,50.72) v1(134.03,51.74) v1(134.03,50.72) v1(135.43,51.74) v1(135.43,50.72) v1(136.44,51.74) v1(136.44,50.72) v2(108.76,78.44) v2(109.65,78.41)
P1V05_PCH_BPH1: length 2.5
  TOP w0.508: C455.1 150.57,46.89 ; C455.1 151.43,47.8 ; C455.1 152.17,46.89
P1V05_PCH_EN: length 207.3
  TOP w0.109: U2.C6 v1(78.71,144.23)
  TOP w0.381: R694.2 v1(166.67,27.86) R698.2
  SIG3 w0.107: v1(180.01,59.61) 179.24,60.38 179.24,62.81 177.19,64.87 177.19,66.35 175.91,67.62 175.91,73.43 166.05,83.29 151.38,83.29 146.6,88.06 141.02,88.06 138.22,90.86 136.32,90.86 130.63,96.55 130.63,105.98 128.79,107.82 128.79,112.96 129.46,113.63 129.46,123.25 128.22,124.5 128.22,128.17 125.68,130.71 125.68,135.43 119.88,141.22 116.89,141.22 115.82,142.29 114.6,142.29 113.84,143.05 99.31,143.05 99.11,143.25 93.47,143.25 92.45,142.23 92.45,141.35 92.12,141.02 89.58,141.02 88.88,141.73 86.6,141.73 86.23,142.1 85.45,142.1 84.81,142.75 81.12,142.75 80.95,142.93 80.01,142.93 v1(78.71,144.23)
  SIG4 w0.086: v1(180.01,59.61) 179.47,59.08 179.47,36.86 175.62,33.01 174.86,33.01 171.62,29.77 169.08,29.77 167.18,27.86 v1(166.67,27.86)
P1V05_PCH_LSET: length 3.4
  TOP w0.229: U35.3 152.34,50.96 v1(151.56,51.74)
  BOTTOM w0.229: v1(151.56,51.74) 152.45,50.85 R718.1
P1V05_PCH_PG: length 196
  TOP w0.109: R91.2 78.69,125.17 78.79,125.27 78.79,126.72 78.84,126.77 v1(78.84,126.8)
  TOP w0.178: U33.15 168.63,32.51 168.96,32.18 v1(168.96,31.67)
  TOP w0.381: R336.1 169.46,31.17 v1(168.96,31.67)
  SIG1 w0.086: v1(116.63,129.46) 117.22,128.88 117.95,128.88 118.11,129.03 119.63,129.03 119.75,129.16 124.69,129.16 125.78,128.07 v1(125.78,125.27)
  SIG3 w0.107: v1(78.84,126.8) 79.6,126.04 81.45,126.04 82.04,126.62 97.16,126.62 98.63,128.08 99.99,128.08 100.65,128.75 104.92,128.75 106.24,130.07 114.12,130.07 114.73,129.46 v1(116.63,129.46) ; v1(125.78,125.27) 127.55,123.5 127.55,123.12 128.06,122.61 128.06,121.34 127.58,120.85 127.58,120.29 128.31,119.56 128.31,114.14 127.66,113.49 127.66,110.69 126.32,109.36 126.32,108.19 126.64,107.87 127.05,107.87 128.8,106.13 128.8,102.25 129.54,101.51 129.54,95.93 135.74,89.73 137.33,89.73 137.64,89.43 137.64,88.72 139.57,86.79 146.12,86.79 150.75,82.17 165.55,82.17 174.8,72.92 174.8,71.43 174.03,70.65 174.03,67.88 175.38,66.52 175.38,66.17 175.1,65.89 174.94,65.89 174.72,65.67 174.72,65.05 175.94,63.83 175.94,61.87 v1(177.97,59.84)
  SIG4 w0.086: v1(177.97,59.84) 178.35,59.46 178.35,42.14 174.26,38.04 174.26,35.23 172.99,33.96 170.99,33.96 168.96,31.93 v1(168.96,31.67)
P1V05_PROC_IO: length 112.8
  TOP w0.178: v2(88.65,85.8) 89.05,86.2 89.05,86.26 89.42,86.63 U43.BB25
  TOP w0.381: C185.1 82.06,122.76 ; C185.1 79.42,122.76 79.33,122.85 R1198.1 R1197.1 ; C185.1 81.47,123.41 ; 82.37,122.71 R1196.1 83.59,122.71
  SIG1 w0.381: v1(115.87,134.16) 115.59,134.44 114.12,134.44 113.52,133.85 107.17,133.85 105.03,131.7 97.41,131.7 96.76,131.05 92.29,131.05 v1(91.64,130.4)
  SIG2 w0.305: 97.71,97.33 97.07,96.7 94.03,96.7 93.39,96.06 91.23,96.06 90.9,95.73 90.9,95.13 90.62,94.86 90.62,94.51 90.14,94.03 90.14,93.65 91.23,92.55 91.23,91.87 90.85,91.49 90.85,90.6 90.6,90.35 90.6,88.82 89.33,87.55 89.33,86.48 v2(88.65,85.8)
  SIG2 w0.508: 97.71,97.33 97.71,102.41 94.03,106.1 94.03,108.92 93.29,109.65 93.29,113.23 94.41,114.35 94.41,116.89 94.92,117.4 94.92,119.69 93.77,120.83 93.77,122.43 93.32,122.89 86.13,122.89 v1(85.39,123.62)
  BOTTOM w0.381: 86.17,122.59 86.65,122.59 87.3,123.24 87.3,123.75 88.57,125.02 R284.1 87.91,127.08 87.64,127.35 87.64,128.66 88.06,129.08 90.32,129.08 v1(91.64,130.4) ; R1033.2 115.31,139.5 115.87,138.94 v1(115.87,134.16) 115.87,133.78 115.11,133.02 R1137.2
  vias: v1(84.5,123.62)
P1V05_PROC_IO_EN: length 44.4
  TOP w0.109: U2.B13 v1(86.71,145.23) ; v1(94.28,118.52) 93.8,118.04 93.13,118.04 93.01,118.16 92.63,118.16 91.99,117.53 91.36,117.53 91.03,117.86 89.07,117.86 88.95,117.98 87.88,117.98 87.55,117.65 R285.1 R282.1
  SIG4 w0.086: v1(86.71,145.23) 87.23,144.7 90.34,144.7 92.88,142.16 92.88,140.39 91.74,139.24 91.74,135.05 96.21,130.58 96.21,124 95.8,123.6 95.8,122.99 94.28,121.46 v1(94.28,118.52)
P1V05_PROC_IO_PG: length 38.4
  TOP w0.109: U2.D15 v1(88.71,143.23)
  SIG1 w0.086: v1(88.71,143.23) 89.19,142.75 90.93,142.75 92.3,144.12 95.12,144.12 v1(95.55,143.69)
  BOTTOM w0.109: Q23.3 97.33,120.45 97.71,120.83 R278.2 97.97,122.38 98.22,122.63 98.22,123.75 98.15,123.81 98.15,129.27 97.96,129.46 97.96,129.67 97.66,129.97 97.2,129.97 96.14,131.04 96.14,134.24 98.11,136.21 98.11,137.86 98.34,138.1 98.34,142.16 96.82,143.69 v1(95.55,143.69)
P1V05_VCCCIOIN: length 383.9
  TOP w0.178: v2(93.02,88.04) 92.62,87.65 U43.AR23 ; v2(93.82,89.64) U43.AP18 93.22,89.84 92.82,89.84 U43.AR18 ; U43.AK53 v2(94.62,74.58) ; U43.AR21 92.78,88.6 93.27,88.6 U43.AP21 93.45,88.44 93.82,88.06 v2(93.82,88.04) ; v2(97.82,74.58) U43.AC53 98.09,74.04 98.09,73.51 U43.AC55 98.22,73.36 v2(97.84,72.97) ; U20.AA17 v2(142.69,127.43) ; U43.AM53 v2(93.82,74.58) ; U43.AK55 v2(94.62,73.78) ; U43.AH55 v2(95.42,73.78)
  TOP w0.254: 127.45,114.35 127.45,111.3 C698.1
  TOP w0.305: U52.16 127.69,70.04 126.41,68.76 C690.2 ; v1(85.98,107.52) 86.53,106.96 R994.2 ; U54.1 72.86,36.16 v1(72.94,36.25) ; U55.16 121.86,57.48 121.84,57.46 C696.2
  TOP w0.33: U56.1 127.65,105.75 127.55,105.84 C697.1 ; C702.2 146.22,67.23 146.1,67.36 U59.16 ; v1(121.33,102.72) 121.33,103.05 120.71,103.67 U51.16 ; U50.16 120.56,110.4 121.16,111.01 v1(121.71,111.01) 121.88,111.18 C686.2 ; U58.16 151.93,67.88 152.24,67.56 152.24,66.88 151.81,66.45 C704.2
  TOP w0.381: R1073.2 124.89,71.81 124.51,72.19 v1(124.51,72.31) ; v1(124.13,99.49) 123.62,100 R1055.2 R1058.2 ; v1(120.95,56.95) 121.1,56.79 C696.2 ; v1(86.82,113.79) 86.46,113.44 R992.2 86.15,114.05 v1(86.79,114.68) 86.38,115.09 C184.1 ; R1074.2 R1075.2 125.29,75.34 124.91,75.72 v1(124.91,76.12) ; 154.38,69.42 C223.1 154.38,75.64 X29.1 ; R1063.2 R1054.2 v1(124,104.06) ; R780.1 v1(105.46,53.52) ; v1(146.99,65.59) 146.99,65.81 146.61,66.19 C702.2 ; C704.2 152.42,66.19 152.7,66.47 v1(152.83,66.47) ; R1020.1 v1(111.55,53.52) ; v1(95.55,128.6) 95.55,126.92 94.28,125.65 C183.1 93.42,122.71 ; v1(114.98,62.66) R953.2 R783.1 ; R1056.2 123.67,97.71 v1(123.92,97.46) ; R1019.1 v1(109.52,53.52) ; v1(75.61,38.81) 75.46,38.66 R1091.1 ; v1(175.18,68.63) R304.1 C216.1 ; v1(114.85,55.55) R961.1 R798.1 ; R1035.2 v1(99.36,53.52) ; v1(125.04,104.06) 125.04,104.45 125.42,104.83 R1100.1 R1099.1 ; v1(72.94,36.25) C693.1 73.86,36.65 74.09,36.88 74.47,36.88 74.82,37.24 R1092.1 ; R845.1 v1(103.42,53.52) ; R1018.1 v1(110.47,57.58) ; v1(126.18,111.56) 126.84,110.9 C698.1 ; R784.1 v1(106.47,53.52) ; v1(115.24,136.6) 115.97,136.6 v1(116.51,136.07) ; v1(126.11,68) 126.26,68.15 C690.2 ; R843.1 v1(100.38,53.52) ; v1(87.58,106.73) 87.55,106.71 R995.2 ; R25.1 152.83,95.17 v1(152.95,95.3) ; R1072.2 v1(124.63,69.77) ; C697.1 v1(126.77,106.76) ; R1101.1 R1102.1 v1(128.06,109.17) ; R781.1 v1(114.85,58.6) ; R1105.2 v1(145.21,64.57)
  SIG1 w0.381: v1(120.44,139.62) 120.57,139.75 124.13,139.75 124.89,138.99 126.54,138.99 128.57,136.96 v1(134.03,136.96) ; v1(95.55,128.6) 103.83,128.6 105.38,130.15 106.9,130.15 109.42,132.66 116.15,132.66 v1(116.25,132.77)
  SIG2 w0.381: 174.29,70.28 174.29,79.55 174.93,80.19 174.93,85.9 170.16,90.67 166.2,90.67 165.2,91.67 165.2,92.96 164.79,93.37 164.03,93.37 162.61,94.79 156.26,94.79 155.75,95.3 v1(152.95,95.3) ; 121.97,52.63 121.97,50.34 123.24,49.07 123.24,44.63 119.43,40.82 119.43,37.77 118.79,37.14 117.78,37.14 117.14,36.5 117.14,29.01 115.87,27.74 113.08,27.74 108.76,23.42 100,23.42 98.55,21.97 92.42,21.97 88.18,26.21 81.45,26.21 80.56,27.1 71.29,27.1 70.4,26.21 v1(69.52,26.21)
  SIG3 w0.381: v1(75.61,38.81) 75.23,38.81 72.94,36.53 v1(72.94,36.25) 72.94,33.71 70.4,31.17 70.4,29.77 69.25,28.61 69.25,27.12 69.52,26.85 v1(69.52,26.21)
  SIG4 w0.381: v1(112.44,138.23) 113.84,139.62 v1(120.44,139.62)
  BOTTOM w0.254: R914.1 91.36,68.12 91.11,68.38 91.11,68.81 92.05,69.75 R911.1
  BOTTOM w0.305: U52.16 127.54,70.04 127.15,69.65
  BOTTOM w0.33: C684.2 112.57,129.72 111.54,130.74 U49.16 ; C680.2 113.2,137.47 v1(112.44,138.23) 112.31,138.23 112.3,138.24 U47.16 ; U48.16 120.94,105.85 121.71,105.08 C682.2
  BOTTOM w0.381: v2(93.82,74.58) 93.77,74.63 C643.1 ; v2(95.42,73.78) 95.46,73.74 C641.1 ; v2(106.85,59.61) 106.6,59.87 R1023.1 ; v1(126.11,68) 126.26,68.15 C690.2 127.15,69.65 ; 93.9,73.2 93.77,73.08 C642.1 ; v1(115.24,136.6) 114.7,136.07 R1037.2 114.32,136.35 113.48,137.19 C680.2 ; R1177.1 99.39,68.91 v2(100,69.52) ; R1075.2 125.29,75.74 v1(124.91,76.12) ; v2(142.69,127.43) 143.43,128.17 143.43,128.85 C261.2 142.92,129.08 142.54,129.46 142.54,132 139.49,135.05 139.49,136.45 138.98,136.96 v1(134.03,136.96) ; C341.1 R662.2 R664.2 R663.1 64.69,19.86 63.93,20.63 63.93,22.66 66.47,25.2 68.5,25.2 v1(69.52,26.21) ; R780.1 v1(105.46,53.52) ; C649.1 94.79,73.2 ; v1(124.51,72.31) 125.01,72.82 R1080.1 ; C688.2 122.02,102.03 v1(121.33,102.72) ; v2(94.17,82.33) 94.17,81.98 93.9,81.71 R840.1 ; R1036.2 v1(124,111.18) ; v1(124,104.06) 123.62,104.45 122.75,104.45 122.37,104.83 C682.2 ; v2(93.82,89.64) 93.78,89.69 C763.1 ; R1079.1 125.29,70.43 v1(124.63,69.77) ; C684.2 113.36,130.12 113.58,130.35 113.94,130.35 114.32,130.73 R1039.2 114.98,130.99 116.25,132.26 v1(116.25,132.77) 116.51,133.02 v1(116.51,136.07) 116.51,139.12 115.11,140.51 R1034.2 ; v1(160.7,74.73) 160.7,75.49 160.09,76.1 R310.1 ; R845.1 v1(103.42,53.52) ; R843.1 v1(100.38,53.52) ; R1029.1 v2(102.66,58.85) ; R1019.1 v1(109.52,53.52) ; R784.1 v1(106.47,53.52) ; R1035.2 v1(99.36,53.52)
  BOTTOM w0.508: R915.1 95.04,55.17 96.03,54.18 R913.1 R908.2 R910.1 R1035.2 R843.1 R907.1 R1179.1 R845.1 R786.1 R780.1 R784.1 R797.1 R1019.1 R1181.1 R1020.1 v1(111.55,53.52) ; 93.77,73.56 92.88,72.67 92.88,70.66 93.26,70.28 R912.1 R911.1
  vias: v1(92.88,122.12) v1(92.88,121.21) v1(149.27,63.17) v1(152.7,64.72) v1(152.7,63.96) v1(152.7,63.17) v1(153.34,63.55) v1(153.36,64.31)
P1V05_VCCCIOIN_EN: length 154.2
  TOP w0.109: U2.F11 v1(84.71,141.23)
  TOP w0.381: R307.1 R303.1 174.54,65.96 v1(174.93,66.35)
  SIG3 w0.107: v1(174.93,66.35) 173.72,67.56 173.72,70.85 174.52,71.65 174.52,72.8 165.43,81.89 150.59,81.89 146,86.49 138.02,86.49 135.79,88.72 135.79,89.28 129.27,95.8 129.27,101.4 128.52,102.14 128.52,106.02 127.04,107.5 126.61,107.5 126.04,108.07 126.04,109.53 127.38,110.87 127.38,113.67 128.04,114.33 128.04,119.2 127.3,119.94 127.3,121.07 127.08,121.29 127.08,123.35 125.27,125.17 125.27,126.04 126.03,126.8 126.03,128.45 125.65,128.83 125.65,129.59 124.89,130.35 124.89,134.29 124,135.18 124,136.07 120.95,139.12 117.9,139.12 115.39,141.63 99.77,141.63 98.69,142.71 93.72,142.71 93.02,142.01 93.02,141.11 92.22,140.32 85.74,140.32 84.83,141.23 v1(84.71,141.23)
P1V05_VCCCIOIN_PG: length 138.8
  TOP w0.109: U2.F7 v1(79.71,141.23)
  SIG3 w0.107: v1(79.71,141.23) 79.72,141.23 80.18,140.77 80.18,140.01 80.44,139.75 80.82,139.75 81.2,139.37 81.2,138.91 81.32,138.79 88.78,138.79 89.85,137.72 91.74,137.72 93.26,136.2 98.42,136.2 100.07,137.85 101.75,137.85 102.67,136.93 104.29,136.93 105,137.64 113.21,137.64 113.77,138.2 116.02,138.2 118.37,135.85 119.37,135.85 122.26,132.96 122.26,127.01 122.44,126.83 122.44,125.34 121.71,124.6 121.71,121.85 122.91,120.65 122.91,112.24 122.17,111.5 121.56,111.5 120.75,110.69 120.75,101.04 123.14,98.65 123.14,95.27 125.92,92.49 127.32,92.49 128.06,91.75 128.06,90.6 126.08,88.62 125.7,88.62 125.4,88.32 125.4,87.22 129.46,83.16 143.84,83.16 148.64,78.36 153.01,78.36 v1(153.46,77.9)
  BOTTOM w0.109: Q29.3 154.86,75.62 154.25,76.23 R306.2 153.62,77.9 v1(153.46,77.9)
P1V05_VCCGB: length 142.2
  TOP w0.178: v2(101.02,72.2) 101.45,71.78 U43.R58 ; U43.V53 v2(100.22,74.58) U43.V51 ; U43.Y56 v2(99.42,72.98) ; U43.Y58 v2(99.42,72.18) U43.AA58 ; U43.T51 v2(101.02,74.58) U43.T53 ; U43.Y53 v2(99.42,74.58) ; U43.V58 100.62,71.8 v2(100.22,72.2) 100.6,72.58 U43.V56 v2(100.22,72.97)
  TOP w0.229: 151.05,42.72 151.05,42.27 151.51,41.81 151.51,40.97 151.91,40.56 U34.5
  TOP w0.381: C771.1 125.14,43.87 ; R23.1 151.2,95.35 v1(151.18,95.33) ; L33.1 115.59,75.39 v1(114.73,76.25) ; R354.2 121.71,44.5 ; C233.1 124,43.87 ; C772.1 126.29,43.87 ; 151.05,42.72 150.29,43.49 142.03,43.49
  SIG2 w0.381: v1(151.18,95.33) 151.79,95.94 156.51,95.94 158.16,97.59 162.1,97.59 162.61,97.08 162.61,95.68 163.5,94.79 165.38,94.79 165.76,94.41 165.76,91.9 166.44,91.21 170.39,91.21 175.56,86.04 175.56,72.57 177.47,70.66 v1(177.47,62.54)
  SIG4 w0.381: v1(151.81,58.6) 153.46,60.25 160.08,60.25 161.18,61.35 167.78,61.35 167.94,61.52 171.88,61.52 172.72,60.68 175.61,60.68 v1(177.47,62.54)
  SIG4 w0.508: v1(151.81,58.6) 153.08,58.6 154.35,57.33 154.35,53.52 152.7,51.87 152.7,46.66 151.18,45.14 151.18,44.63 149.91,43.36 144.19,43.36 v1(142.79,41.96)
  BOTTOM w0.381: v2(101.02,74.58) 101.07,74.63 C637.1 ; v2(100.22,72.97) 100.07,73.13 C635.1 ; C638.1 101.75,71.82 101.37,72.2 v2(101.02,72.2) ; L32.1 115.11,59.23 v1(115.74,58.6) ; C636.1 99.59,74.74 v2(99.42,74.58)
  vias: v1(126.16,41.96) v1(127.05,41.96) v1(128.57,41.96) v1(129.46,41.96) v1(130.86,41.96) v1(131.75,41.96) v1(133.14,41.96) v1(133.14,40.56) v1(134.03,41.96) v1(134.03,40.56) v1(135.43,41.96) v1(135.43,40.56) v1(136.32,41.96) v1(136.32,40.56) v1(140.25,37.64) v1(140.25,36.75) v1(140.25,35.61) v1(140.25,34.72) v2(109.65,76.63) v2(109.65,75.87) v2(109.65,74.98) v2(109.65,74.22) v2(110.79,74.98)
P1V05_VCCSCSUS: length 149.3
  TOP w0.178: v2(101.02,76.18) U43.T48 v2(101.02,76.98) ; v2(101.02,76.18) U43.V49 ; v2(101.02,76.18) U43.T49 ; v2(101.02,75.38) U43.T49 ; U43.T49 v2(101.82,75.38) U43.R49 ; U43.T49 v2(101.82,76.18) U43.R48 ; U43.V49 v2(100.22,76.18) U43.V48 v2(100.22,76.98) ; U43.V49 v2(100.22,75.38)
  TOP w0.229: 135.3,22.4 134.59,21.69 133.27,21.69 132.38,20.8 U32.5
  TOP w0.381: v1(125.52,40.95) C232.1 R350.2 ; 135.3,30.4 135.3,22.4 ; C769.1 132.64,37.39 ; C770.1 132.64,38.4 ; X32.1 146.35,9.32 146.35,23.29 137.71,31.93 ; R21.1 v1(148.76,92.51)
  SIG3 w0.381: v1(133.27,64.82) 133.52,64.82 136.13,67.42 136.13,68.95 137.99,70.82 137.99,75.39 138.6,76 138.6,77.14 137.59,78.16 137.59,78.92 136.83,79.68 128.32,79.68 119.38,88.62 119.38,90.63 118.13,91.87 118.13,93.93 115.74,96.32 115.74,97.33 115.36,97.71 v1(115.36,98.6)
  SIG4 w0.381: v1(148.76,92.51) 148,93.27 136.57,93.27 132.76,97.08 129.97,97.08 128.19,98.86 119.35,98.86 119.02,98.53 115.44,98.53 v1(115.36,98.6)
  BOTTOM w0.381: v2(101.82,75.38) 102.19,75.38 C631.1 102.38,76.18 v2(101.82,76.18) ; v2(100.22,76.18) 99.92,76.18 C632.1 99.55,76.98 v2(100.22,76.98) ; C633.1 101.19,77.14 v2(101.02,76.98)
  vias: v1(116.12,72.95) v1(116.89,72.95) v3(124.25,35.74) v3(124.25,33.07) v3(125.78,35.74) v3(125.78,33.07) v3(127.43,35.74) v3(127.43,33.07) v3(129.59,35.74) v3(129.59,34.47) v3(131.24,35.74) v3(131.24,34.47) v3(137.71,33.96) v3(137.71,32.69)
P1V5_VRM: length 44.4
  TOP w0.178: U43.AW28 U43.AW30 91.02,84.19 v2(90.78,83.94) ; U43.AC28 98.3,85.24 98.62,84.91 v2(98.62,84.84) 98.62,84.81 98.25,84.44 U43.AC30 ; U43.AG19 v2(96.22,89.64) ; U43.AE28 97.43,85.24 v2(97.84,84.84) ; v2(100.5,89.21) 100.27,89.21 U43.W20 ; U43.AE30 v2(97.82,84.04) ; U43.AK28 95.11,85.16 95.11,84.52 U43.AK30 95.3,84.17 v2(95.3,83.47) ; v2(100.04,86.09) 100.04,85.54 U43.W28 ; v2(100.23,82.58) U43.V33 ; U43.BA30 90.22,84.26 v2(89.93,83.96) 89.45,84.44 U43.BB30 89.26,84.44 v2(88.92,84.1) 88.62,84.4 U43.BD30
  TOP w0.381: R264.1 129.74,52.91 130.09,53.26 130.09,54.92 129.23,55.78 C168.1 ; C168.1 128.7,55.93 128.06,56.57 128.06,57.2 ; C168.1 129.23,57.18 129.21,57.2 ; C167.1 127.28,57.05 127.43,57.2 ; X26.1 v1(136.32,65.96)
  SIG3 w0.381: v1(136.32,65.96) 134.54,64.19 131.49,64.19 127.68,60.38 v1(127.68,60)
  BOTTOM w0.178: R809.2 87.96,85.24 88.69,84.51 88.69,84.33 v2(88.92,84.1)
  BOTTOM w0.381: C762.1 95.65,83.11 v2(95.3,83.47) ; v2(97.82,84.04) 97.79,84.04 97.41,83.66 97.41,82.8 96.67,82.07 C761.1 ; v2(100.5,89.21) 100.88,89.21 101.49,89.81 R846.2
  BOTTOM w0.457: R971.2 102,84.61 v2(101.49,84.1) 102.03,83.57 R959.1
  vias: v1(127.68,59.23) v1(127.68,58.47)
P1V5_VRM_EN: length 125.6
  TOP w0.109: U2.N12 v1(85.71,133.23)
  SIG3 w0.107: v1(85.71,133.23) 86.26,133.78 86.91,133.78 87.9,134.77 91.36,134.77 91.83,134.29 98.47,134.29 99.43,133.33 104.88,133.33 105.33,133.78 109.69,133.78 110.49,132.99 115.46,132.99 115.74,133.27 117.9,133.27 118.79,132.38 119.05,132.38 119.67,131.76 119.67,125.64 118.66,124.64 118.66,114.1 118,113.44 118,111.94 116.53,110.46 116.53,109.5 116.76,109.27 116.76,96.44 118.84,94.37 118.84,92.13 120.24,90.72 120.24,88.79 128.52,80.52 138.78,80.52 139.75,79.55 139.75,77.42 139.34,77.01 139.34,73.44 138.71,72.8 138.71,68.86 137.46,67.62 v1(137.46,63.04)
  BOTTOM w0.381: R265.2 R262.2 137.56,62.89 137.59,62.92 v1(137.46,63.04)
P1V5_VRM_PG: length 157.8
  TOP w0.109: U2.G2 74.71,139.23 74.71,138.34 74.6,138.23 74.01,138.23 73.71,137.92 73.71,136.96 73.2,136.45 73.2,135.69 v1(72.81,135.29)
  TOP w0.381: v1(135.81,60.25) 135.43,60.63 U12.7
  SIG3 w0.107: v1(135.81,60.25) 136.95,61.39 136.95,67.74 138.42,69.21 138.42,72.92 139.06,73.56 139.06,77.21 139.47,77.62 139.47,79.42 138.7,80.19 128.45,80.19 119.85,88.79 119.85,90.73 118.55,92.03 118.55,94.14 116.32,96.37 116.32,109.07 111.3,114.1 111.3,118.92 117.66,125.28 118.76,125.28 119.39,125.91 119.39,126.46 118.61,127.23 118.61,129.03 119.02,129.44 119.02,131.78 118.8,132 117.9,132 117.52,131.62 106.09,131.62 104.92,130.45 100.73,130.45 99.51,129.24 98.12,129.24 97.84,128.96 97.05,128.96 96.9,129.11 94.12,129.11 94.03,129.02 92.94,129.02 92.76,128.83 85.52,128.83 85.15,128.46 83.2,128.46 81.74,129.92 77,129.92 76.19,130.73 75.36,130.73 75.23,130.86 75.23,131.37 75.61,131.75 75.99,131.75 76.25,132 76.25,132.51 75.99,132.77 75.48,132.77 75.23,133.02 75.23,133.4 74.85,133.78 73.07,133.78 72.82,134.04 72.82,135.28 v1(72.81,135.29)
  BOTTOM w0.381: R263.2 v1(135.81,60.25)
P1V7_VCCSCFUSESUS: length 49.9
  TOP w0.178: v2(97.02,72.95) 97.42,73.35 U43.AE55 U43.AE53 97.37,74.23 97.37,74.89 v2(97.76,75.27) ; v2(98.62,74.58) U43.AA53 v2(98.62,73.78) U43.AA55
  TOP w0.381: v1(174.47,63.68) 174.47,63.42 174.34,63.3 173.15,63.3 172.89,63.55 172.36,63.55 R288.1 172.23,64.08 171.62,64.69 v1(171.62,66.09) ; X27.1 147.62,62.41 149.02,63.81 150.16,63.81 151.02,62.94 C197.1 151.68,62.28 152.7,61.27 152.7,60.12
  SIG4 w0.381: 149.4,57.2 150.03,57.84 150.03,59.11 151.18,60.25 152.07,60.25 152.62,60.81 159.86,60.81 160.96,61.9 167.43,61.9 167.69,62.15 170.35,62.15 170.99,62.79 173.58,62.79 v1(174.47,63.68)
  BOTTOM w0.381: v1(171.62,66.09) 171.37,65.84 C191.1 ; R294.1 174.85,64.44 174.47,64.06 v1(174.47,63.68)
  vias: v1(152.57,55.42) v1(152.57,54.51) v1(153.34,55.42) v1(153.34,54.51)
P1V7_VCCSCFUSESUS_EN: length 187.5
  TOP w0.109: R291.1 R287.1 169.19,52.78 169.59,52.38 180.46,52.38 v1(184.4,56.31) ; U2.B14 v1(87.71,145.23)
  SIG3 w0.107: v1(87.71,145.23) 88.21,144.73 91.51,144.73 92.55,145.77 117.98,145.77 118.41,145.34 121.33,145.34 127.68,138.99 128.95,138.99 134.16,133.78 135.05,133.78 135.94,132.89 135.94,127.03 136.27,126.7 136.27,120.83 134.05,118.61 134.05,112.7 134.34,112.42 134.34,110.92 134.62,110.64 134.62,97.18 137.79,94.01 140.13,94.01 142.39,91.75 147.87,91.75 152.85,86.77 169.36,86.77 174.67,81.46 174.67,80.21 179.86,75.03 179.86,70.11 179.57,69.82 179.57,66.14 183.56,62.15 183.56,58.34 184.25,57.66 184.66,57.66 184.96,57.35 184.96,56.87 184.87,56.78 184.86,56.78 v1(184.4,56.31)
P1V7_VCCSCFUSESUS_PG: length 146.7
  TOP w0.109: U2.E13 v2(86.71,142.23)
  SIG3 w0.107: v2(86.71,142.23) 86.9,142.04 91.36,142.04 93.45,144.13 99.79,144.13 100.52,143.4 114.26,143.4 114.99,142.66 116.02,142.66 117.14,141.54 120.05,141.54 125.97,135.62 125.97,135.27 125.97,131.02 126.6,130.39 128.49,128.5 128.49,124.6 129.74,123.36 129.74,113.49 129.07,112.82 129.07,110.07 129.89,109.25 129.89,107.19 130.92,106.16 130.92,96.68 136.47,91.14 138.35,91.14 141.12,88.37 146.72,88.37 151.52,83.57 166.47,83.57 v1(174.93,75.11)
  BOTTOM w0.109: Q27.3 177.97,69.65 177.75,69.88 R290.2 177.75,71.78 176.32,73.2 176.32,73.71 v1(174.93,75.11)
P2V5_M_ABC_VPP: length 101.8
  TOP w0.229: U38.5 75.48,21.26 76.5,22.28
  TOP w0.305: C694.1 65.07,35.1 66.13,36.16 U54.8
  TOP w0.381: R1094.1 v1(63.04,37.14) ; 68.88,32.82 C729.1 70.25,31.52 70.66,31.93 ; R366.2 66.47,32.44 ; R1093.1 v1(63.04,36.12) ; C506.1 67.61,32.56 ; C778.1 56.94,29.01 ; 76.5,22.28 76.5,22.66 77.52,23.67 77.52,27.1 77.14,27.48 77.14,31.55 76.73,31.96 L29.1 ; C694.1 64.66,34.32 ; R1095.1 63.04,38.15 ; C777.1 56.94,30.15
  BOTTOM w0.381: v1(18.33,48.18) 18.84,47.68 20.74,47.68 21.48,48.41 R140.2 21.89,48.82 22.14,49.07 23.28,49.07 24.68,50.47 R1122.2 25.35,51.26 24.71,51.9 24.71,65.87 23.82,66.76 R1125.2 ; R368.2 5,48.44 ; R1116.2 R1118.2 v1(20.11,40.59) ; 15.54,50.98 15.54,53.65 15.03,54.15 13.95,54.15 11,57.1 11,71.86 10.7,72.16 R1120.2 10.21,73.2 11.76,74.76 12.27,74.76 12.62,75.11 R137.1 ; 2.84,48.31 C524.1 2.1,48.97 ; v1(4.4,48.19) 4.36,48.22 C235.1 4.85,48.97 ; C795.1 v1(13.76,49.73) C792.1 C796.1 ; C795.1 C794.1 ; C795.1 14.68,50.88 ; C796.1 11.5,48.92 ; C796.1 v1(12.37,49.73) C794.1 ; C794.1 11.5,50.88 ; C793.1 15.92,49.71 ; C793.1 16.66,48.92 ; C793.1 15.31,48.92
  vias: v1(3.63,48.19) v1(3.63,47.43) v1(4.4,47.43) v1(14.65,49.73) v1(17.45,48.18) v1(62.28,32.69) v1(62.28,31.93) v1(63.17,33.2) v1(63.93,33.2) v1(67.48,33.33) v1(68.37,33.33) v1(69.26,33.33) v1(69.77,32.56) v1(70.15,33.33) v1(70.91,34.34) v1(70.91,33.45) v1(71.8,34.34) v1(71.8,33.45) v3(65.07,33.2) v3(66.34,33.2)
P2V5_VPP_BPH1: length 1.9
  TOP w0.508: C499.1 72.46,25.81
P2V5_VPP_EN: length 343.7
  TOP w0.109: R735.2 58.87,14.76 59.1,14.53 59.1,13.64 v1(59.36,13.39) ; v1(76.71,145.23) U2.B3
  TOP w0.178: R735.2 58.47,15.04 58.34,15.16 58.34,15.8 58.47,15.93 R731.2
  SIG3 w0.107: v1(76.71,145.23) 79.92,145.23 80.44,144.7 82.85,144.7 83.87,143.69 89.97,143.69 90.72,144.44 91.72,144.44 92.77,145.5 116.85,145.5 117.99,144.36 120.53,144.36 126.2,138.69 128.76,138.69 134.23,133.22 135.1,133.22 135.61,132.72 135.61,126.62 135.84,126.39 135.84,121.23 133.78,119.18 133.78,112.57 134.06,112.3 134.06,110.8 134.33,110.52 134.33,97.06 137.66,93.73 140,93.73 142.26,91.47 147.69,91.47 152.72,86.44 169.26,86.44 174.39,81.31 174.39,80.11 179.56,74.94 179.56,71.59 178.52,70.56 178.52,69.45 179.29,68.68 179.29,65.94 183.18,62.05 183.18,58.32 184.3,57.2 v1(184.45,57.2)
  SIG4 w0.086: v1(59.36,13.39) 60.5,12.24 65.32,12.24 68.75,8.81 117.67,8.81 120.73,11.86 121.38,11.86 121.8,11.45 123.52,11.45 123.95,11.02 132.34,11.02 132.63,10.72 153.17,10.72 161.41,18.96 167.7,18.96 172.77,24.02 173.24,24.02 183.68,34.46 183.68,37.35 184.09,37.76 184.09,53.38 183.71,53.75 183.71,56.46 v1(184.45,57.2)
P2V5_VPP_LSET: length 5.3
  TOP w0.229: R756.1 80.06,21.9 79.55,21.39 77.01,21.39 76.48,20.86 U38.3
P2V5_VPP_PG: length 329.2
  TOP w0.109: R93.2 81.33,124.69 v1(81.5,124.51)
  TOP w0.178: U36.15 60.68,19.36
  TOP w0.254: v1(60.24,13.39) 60.45,13.59 60.45,16.51 60.73,16.79 R334.1 61.01,17.45 60.68,17.78 60.68,19.36
  SIG3 w0.107: v1(184.45,58.09) 183.94,58.6 183.94,62.23 179.85,66.32 179.85,69.72 180.13,69.99 180.13,75.15 174.98,80.31 174.98,81.61 169.54,87.05 153.08,87.05 148.1,92.02 142.52,92.02 140.25,94.29 137.92,94.29 134.91,97.3 134.91,110.78 134.64,111.05 134.64,112.51 134.32,112.83 134.32,118.23 v1(136.1,120) ; v1(81.5,124.51) 81.5,124.74 83.1,126.34 97.27,126.34 98.75,127.81 100.12,127.81 100.79,128.48 105.05,128.48 106.37,129.79 113.77,129.79 114.45,129.11 116.23,129.11 v1(116.76,128.58)
  SIG4 w0.086: v1(184.45,58.09) 183.43,57.07 183.43,53.65 183.81,53.27 183.81,37.9 183.38,37.47 183.38,34.56 173.12,24.29 172.65,24.29 167.59,19.23 161.29,19.23 153.06,11 132.85,11 132.56,11.29 124.06,11.29 123.63,11.72 121.88,11.72 121.48,12.12 120.62,12.12 117.7,9.2 68.75,9.2 64.56,13.39 v1(60.24,13.39) ; v1(116.76,128.58) 116.76,128.19 117.39,127.56 117.39,127.38 118.44,126.34 118.44,124.08 119.76,122.75 126.01,122.75 126.72,122.05 129,122.05 129.84,121.21 133.14,121.21 133.65,120.7 135.4,120.7 v1(136.1,120)
P3V3: length 235.1
  TOP w0.178: v2(91.42,86.44) U43.AW25 90.87,86.69 90.37,86.69 U43.BA25 ; v2(98.62,89.64) 98.6,89.64 98.22,89.26 U43.AC19 v2(97.82,89.64) U43.AE18 ; U43.AE18 97.22,89.84 96.82,89.84 U43.AG18 ; U43.AE18 97.53,90.15 97.53,90.65 97.42,90.76 U43.AE16 ; v2(95.43,91.24) 95.43,91.25 U43.AH14 U43.AG14 U43.AE16 ; U43.AE16 U43.AC14 v2(98.62,91.24) ; v2(92.12,92.91) 91.83,92.62 U43.AU12 ; v2(96.99,92.86) 96.99,92.86 97.4,92.44 U43.AE12 ; U43.AG30 v2(97.02,84.84) U43.AG28 ; v2(94.62,92.04) 94.62,92.04 U43.AM12
  TOP w0.254: U50.1 113.21,110.4 112.7,110.92
  TOP w0.305: U51.1 113.45,103.67 113.08,103.3 112.19,103.3 111.93,103.56 C687.2
  TOP w0.381: v1(107.11,113.82) 107.39,114.1 R936.1 ; C687.2 111.65,103.68 112.04,104.06 v1(112.44,104.06) ; R865.1 v1(83.49,106.73) ; v1(92.81,117.7) 92.63,117.53 R818.1 R854.1 ; v1(152.57,92.51) 152.83,92.25 R32.1 ; v1(117.98,126.16) 117.55,126.59 R941.1 ; R1028.1 74.09,127.94 v1(74.98,128.83) ; v1(112.06,111.63) 111.65,111.23 C685.2 112.7,110.92 ; v1(61.51,149.15) 62.18,148.49 R119.2 ; R826.1 103.17,105.72 103.42,105.97 v1(103.42,106.6) ; R819.1 v1(105.06,108.51) ; R855.1 v1(89.58,114.1) ; v1(82.34,106.73) 82.47,106.6 R977.1 ; 124,149.3 123.39,149.3 123.21,149.12 C180.1 123.87,148.51 ; v1(80.44,114.1) R866.1 R1182.1 ; R816.1 v1(81.45,109.91) ; C683.2 103.68,130.73 v1(103.93,130.99) ; R1193.1 R1194.1 118.03,147.73 v1(117.65,147.35) ; R958.1 104.92,112.88 v1(105,112.8) ; R975.1 R972.1 83.46,109.27 v1(83.46,109.91) ; v1(84.45,106.73) 84.5,106.68 R864.1 ; R122.2 69.64,151.31 v1(69.77,151.44) ; R273.1 123.77,155.35 125.52,153.59 125.52,150.17 ; v1(64.18,149.28) 63.78,149.68 R125.2 ; R848.1 R820.1 R858.1 83.49,117.27 v1(83.61,117.4) ; R859.1 v1(82.47,114.1) ; R825.1 v1(102.61,116.64) ; v1(85.52,109.91) R974.1 R976.1 ; v1(188.39,15.04) R1210.2
  SIG1 w0.381: v1(188.39,15.04) 188.39,21.51 183.43,26.47 183.43,63.42 174.54,72.31 v1(173.4,72.31)
  SIG2 w0.381: 164.82,89.71 170.23,89.71 174.16,85.78 174.16,80.57 173.4,79.81 v1(173.4,72.31)
  SIG2 w0.457: v2(91.42,86.44) 91.99,87.01 91.99,88.6 93.9,90.51 93.9,92.38
  SIG3 w0.381: v1(145.33,69.77) 146.6,71.04 167.69,71.04 168.42,71.78 172.87,71.78 v1(173.4,72.31)
  BOTTOM w0.33: v1(103.93,130.99) 104.18,130.74 U49.1 ; R1081.1 R1082.1 R1087.2
  BOTTOM w0.381: v1(84.45,106.73) 84.5,106.68 R864.1 R945.1 ; v2(92.12,92.91) 91.87,93.17 C655.1 ; C591.2 124.79,122.83 ; v1(84.37,114.86) 84.25,114.73 R856.1 ; v1(81.45,109.91) 81.33,110.03 79.06,110.03 78.79,109.76 R842.1 ; Q9.2 65.26,151.24 v1(65.45,151.44) ; R1192.1 123.97,147.35 ; C651.1 98.5,89.51 v2(98.62,89.64) ; Q8.2 69.19,150.86 v1(69.77,151.44) ; R822.1 86.53,111.81 86.09,112.26 85.28,112.26 84.68,111.66 R823.1 83.66,111.66 v1(83.59,111.73) ; R2.1 R5.1 160.8,93.78 160.45,94.13 v1(160.32,94.13) ; R855.1 v1(89.58,114.1) ; v1(156.76,94.16) 157.04,94.16 157.43,93.78 R4.1 ; v1(58.34,148.13) 58.47,148.01 Q7.2 ; v2(94.62,92.04) 94.81,92.23 C650.1 94.81,92.99 94.28,93.52 R1180.1 ; C652.1 97.18,92.66 v2(96.99,92.86) ; C653.1 98.2,91.67 v2(98.62,91.24) ; C657.1 103.55,90.86 v2(103.45,90.96) 103.15,90.65 R862.1 ; v1(103.42,106.6) 103.91,106.6 104.29,106.99 R857.1 R819.1 v1(105.06,108.51) 106.22,107.35 106.22,106.35 106.32,106.25 R824.1 ; v1(145.33,69.77) 144.19,68.63 139.24,68.63 138.98,68.89 R1084.2 138.45,69.42 137.82,70.05 R1081.1 ; v1(82.34,106.73) 81.86,106.73 81.45,106.32 R851.1 R977.1 ; C654.1 96.82,84.64 v2(97.02,84.84) ; R850.1 R866.1 v1(80.44,114.1) ; C656.1 v2(95.43,91.24)
  vias: v1(110.16,121.59) v1(110.28,120.19) v1(110.92,121.59) v1(123.62,124.33) v1(123.62,123.6) v1(163.8,92.79) v1(163.8,92.02) v1(164.56,92.79) v1(164.56,92.02) v3(124.63,148.26) v3(124.63,146.86)
P3V3_AUX: length 563.5
  TOP w0.178: U20.N17 v2(142.69,121.03) ; U20.L16 v2(143.49,118.63) ; U20.F13 v2(145.89,114.63) ; U20.K7 v2(151.49,117.83) ; U20.F7 v2(151.49,114.63) ; U20.G16 v2(143.49,115.43) ; U20.F15 v2(144.29,114.63) ; v2(93.02,91.24) U43.AP16 93.82,91.24 93.82,92.08 93.46,92.44 U43.AP12 ; v2(93.02,91.24) U43.AR16 v2(93.02,90.44) ; v2(93.02,91.24) U43.AR14 ; v2(92.22,84.04) U43.AR30 ; U20.F10 v2(149.09,114.63) ; U20.F14 v2(145.09,114.63) ; v2(92.22,84.84) U43.AR28 ; U20.H17 v2(142.69,116.23) ; U43.AW23 v2(91.42,87.24) ; U20.R17 v2(142.69,122.63) ; U20.J17 v2(142.69,117.03) ; U20.T15 v2(144.29,123.43) ; U20.F11 v2(148.29,114.63) ; U43.AU18 91.82,90.02 v2(91.42,89.62) 91.42,89.64 U43.AW18 ; U20.F8 v2(150.69,114.63) ; U20.P6 v2(152.29,121.83) ; U20.F12 v2(146.69,114.63) ; U20.N6 v2(152.29,121.03) ; U20.R6 v2(152.29,122.63) ; U20.P17 v2(142.69,121.83) ; U20.K17 v2(142.69,117.83)
  TOP w0.254: 123.98,65.23 123.98,64.93 123.3,64.25 122.11,64.25 121.86,64.5 U55.1
  TOP w0.305: U52.1 135.04,70.04 135.25,69.82 135.25,69.34 134.9,68.99 C689.2
  TOP w0.33: C699.1 136.06,106.35 135.47,105.75 U56.8 ; U59.1 146.1,76 146.22,76.12 C701.2 ; U19.8 134.97,101.4 v1(135.35,101.78) ; U58.1 151.93,76.29 151.43,76.78 151.43,77.25 v1(151.45,77.27) ; U57.8 127.45,119.91 126.79,120.57 C700.1
  TOP w0.381: v1(92.88,146.23) 92.88,144.96 93.39,144.45 ; R335.2 v1(63.29,15.16) ; C179.1 v1(121.08,145.85) ; X22.1 175.56,154.23 ; D32.1 v1(159.94,103.3) ; R7.1 v1(201.21,82.22) ; R489.1 v1(132.76,129.85) ; R610.2 R607.2 165.99,88.06 v1(166.42,88.49) ; R576.1 v1(157.4,104.7) ; R600.2 165.3,106.38 165.57,106.65 165.57,107.78 v1(165.25,108.1) R624.2 R623.2 ; C230.1 v1(61.01,15.16) R334.2 ; v1(99.87,142.29) 100.76,141.4 R775.1 R1030.1 ; R772.2 100.99,144.45 v1(100.76,144.22) ; R487.1 v1(132.76,130.99) ; R472.2 v1(132.76,117.27) R470.2 ; R990.1 90.98,109.3 v1(91.64,109.96) 91.99,109.6 R871.1 ; R833.1 88.57,114.07 v1(88.59,114.1) ; v1(123.29,65.2) 123.31,65.23 C695.2 ; R989.1 v1(90.6,106.73) ; R566.1 R564.2 ; R564.2 v1(146.99,104.7) ; R564.2 R565.2 R562.2 ; v1(160.19,121.84) 160.73,121.31 R473.2 ; R770.2 118.16,145.47 118.54,145.85 v1(118.54,146.23) ; C18.2 133.04,152.96 v1(132.89,152.81) ; 169.72,154.36 169.44,154.08 C130.1 ; U25.8 125.14,141.78 125.78,142.42 v1(125.78,142.93) ; U40.8 104.42,130.23 v1(104.19,130) 103.91,129.72 C562.1 ; v1(138.98,102.92) 138.6,103.3 R1104.1 R1098.1 R1097.1 ; R554.2 141.91,104.78 v1(141.83,104.7) ; R336.2 v1(169.46,28.75) ; v1(106.6,128.98) 106.47,128.85 U39.2 ; R982.1 87.93,109.81 v1(87.59,110.16) ; R1.1 195.5,84.76 v1(196.13,84.12) 194.86,82.85 194.86,79.81 194.61,79.55 194.61,66.98 192.07,64.44 185.72,64.44 182.93,67.23 v1(181.78,67.23) ; R771.2 v1(119.81,143.43) ; 93.39,144.45 92.87,143.93 92.87,142.69 93.26,142.29 R1186.1 ; 93.39,144.45 R1187.1 ; R1162.2 123.87,120.07 v1(123.49,120.45) ; R10.1 v1(94.15,157.53) ; v1(93.93,110.03) 93.77,109.88 R888.1 ; C21.1 138.73,102.29 v1(138.98,102.03) ; C699.1 136.98,107.29 v1(137.21,107.52) ; v1(146.88,76.76) 146.73,76.91 C701.2 ; R555.2 142.92,104.83 v1(143.05,104.7) ; v1(120.82,74.52) 121.59,75.29 R318.2 R321.2 ; v1(132.76,112.95) R403.1 ; R339.2 v1(124.38,15.16) ; R533.2 v1(132.76,128.7) ; R508.2 v1(130.4,126.42) ; R508.2 R500.2 R501.2 v1(130.48,128.7) ; R508.2 R506.2 ; v1(163.62,88.7) 164.28,88.7 C265.1 164.16,89.59 U27.8 ; C566.1 v1(119.78,140.28) C565.1 120.57,141.02 121.08,140.51 U23.2 ; v1(166.16,115.62) R622.2 R627.2 ; R762.2 v1(101.27,132.77) ; R984.1 v1(89.58,106.73) ; v1(130.47,113.38) 130.9,112.95 R406.1 ; R496.2 v1(132.76,119.56) ; R1000.2 99.01,118.62 99.39,118.24 v1(99.61,118.24) 99.97,117.88 C595.2 100.63,117.4 101.52,118.29 U46.8 ; R983.1 R988.1 88.95,109.53 v1(89.33,109.91) ; R574.1 R588.1 161.87,110.44 162.35,110.44 v1(162.35,110.44) ; v1(138.73,136.32) 138.73,136.45 138.76,136.47 C262.1 ; R530.1 v1(130.4,124.13) ; R229.2 v1(190.04,151.56) ; v1(153.21,88.7) 153.21,87.43 153.59,87.05 R608.1 ; R584.1 v1(154.35,104.7) ; v1(118.79,136.32) 118.54,136.07 R760.2 ; R490.2 v1(132.76,120.7) ; U42.8 103.17,143.05 102.92,142.8 102.76,142.8 C567.2 102.63,142.17 103.17,142.17 v1(103.3,142.29) ; R509.2 v1(130.48,121.84) ; C700.1 127.53,121.62 v1(127.55,121.59) ; R337.2 v1(171.75,28.75) ; L4.2 153.97,95.68 153.46,96.19 v1(153.46,96.83) ; v1(154.1,88.72) 154,88.62 R609.1 ; v1(123.62,77.9) C228.2 ; R876.1 92.63,106.63 v1(92.53,106.73) ; v1(104.03,138.25) 102.76,138.25 102.66,138.35 C679.2 C257.1 ; R317.1 120.42,72.85 118.92,74.35 v1(118.92,74.47) 118.54,74.85 R323.2 ; R33.1 v1(143.68,95.3) ; R532.1 v1(130.48,122.99) 130.07,122.58 R1103.1 ; C129.1 169.97,151.56 170.73,152.32 170.73,153.59 v3(171.37,154.23) ; v1(87.67,114.15) 87.55,114.02 R986.1 ; R520.2 135.53,135.46 v1(135.05,135.94) ; v1(91.61,106.73) R987.1 ; R528.1 v1(132.76,122.99) ; R503.2 v1(132.76,126.42) ; R491.2 v1(130.48,120.7) ; R338.2 v1(122.09,12.5) ; v1(125.14,96.83) 125.65,96.32 R330.1 ; v1(106.4,138.86) 106.47,138.94 U41.2 ; R534.1 v1(132.76,125.27) ; v1(162.78,128.58) 161.82,128.58 R558.2 ; C118.2 192.81,153.44 v1(193.21,153.85) ; 135.28,146.25 C178.1 136.32,145.72 136.05,145.45 135.32,145.45 ; v1(125.14,101.45) 125.14,100.76 125.52,100.38 R325.1 R329.1 ; v1(54.53,123.75) 54.53,136.96 55.04,137.47 R1220.1 ; R504.2 v1(132.76,124.13) ; R497.2 v1(130.48,119.56) ; v1(135.54,67.86) C689.2 ; R475.2 164.23,121.69 v1(163.5,120.96) ; R510.2 v1(132.76,121.84) ; R519.2 v1(118.82,142.82) ; R832.1 v1(90.6,114.1)
  SIG1 w0.381: v1(201.21,82.22) 198.93,82.22 197.02,84.13 v1(196.13,84.13)
  SIG3 w0.381: v1(125.14,101.45) 125.14,99.49 125.78,98.86 125.78,97.46 v1(125.14,96.83) ; v1(158.92,126.92) 158.29,127.56 158.29,129.34 v1(158.92,129.97) ; v1(162.78,128.58) 161.97,128.58 161.21,129.34 161.21,132.26 v1(161.72,132.77) ; v1(139.87,76.63) 139.87,73.08 139.16,72.36 v1(139.16,72.16)
  SIG4 w0.381: v1(193.21,153.85) 192.32,153.85 v1(190.04,151.56) 189.4,151.56 188.13,152.83 175.05,152.83 v1(174.04,153.85) ; v1(123.29,65.2) 123.34,65.15 129.03,65.15 130.09,66.22 133.9,66.22 v1(135.54,67.86) 136.8,66.6 144.19,66.6 v1(144.45,66.85)
  BOTTOM w0.279: C742.1 128.06,111.43 127.34,112.16 127.34,112.55 127.59,112.81 U61.24
  BOTTOM w0.305: v1(104.03,138.25) 104.05,138.24 U47.1 105.98,138.24 106.4,138.66 v1(106.4,138.86) ; U48.1 113.37,105.85 113.13,106.1 C681.2
  BOTTOM w0.381: v1(93.93,110.03) 93.77,109.88 R888.1 ; R883.1 87.59,109.28 v1(87.59,110.16) ; C318.1 142.59,116.13 v2(142.69,116.23) ; R503.2 v1(132.76,126.42) ; R133.1 13.7,88.44 12.78,89.36 12.78,93.4 R134.1 13.82,94.44 13.82,117.58 19.99,123.75 v1(54.53,123.75) 67.99,123.75 v1(69.9,121.84) ; v1(130.48,115.43) 130.48,115.41 130.9,114.99 R467.2 R468.2 ; R573.1 134.57,135.59 134.92,135.94 v1(135.05,135.94) ; C229.2 135.73,102.16 v1(135.35,101.78) ; R278.1 97.71,124.26 v1(97.58,124.38) R277.1 ; R882.1 91.61,109.93 v1(91.64,109.96) ; v1(177.97,108.26) 177.85,108.38 R628.2 ; R559.2 161.69,132.74 v1(161.72,132.77) ; v1(87.67,114.15) 87.55,114.02 R986.1 ; v1(154.73,77.9) 155.22,77.42 R306.1 ; v2(91.42,87.24) 90.8,86.61 C646.1 ; v1(138.73,136.32) 138.35,135.94 C255.2 ; v1(150.67,64.57) 150.8,64.69 R802.1 ; C304.1 143.18,115.11 v2(143.49,115.43) ; v1(126.82,108.33) 126.82,108.36 126.2,108.98 126.2,109.57 126.28,109.65 R1157.1 ; v1(105.06,109.53) R838.1 R874.1 R836.1 R880.1 R868.1 105.1,113.97 v1(105.81,113.26) ; v1(131.11,161.72) 131.59,161.24 R268.1 R269.1 ; v1(172,105.72) 171.88,105.84 R621.2 ; R560.2 158.52,129.59 158.9,129.97 v1(158.92,129.97) ; R578.1 152.07,104.98 v1(152.35,104.7) ; R556.2 v1(140.89,104.7) ; R472.2 v1(132.76,117.27) R470.2 ; R496.2 v1(132.76,119.56) ; C564.2 107.08,129.46 v1(106.6,128.98) ; R509.2 v1(130.48,121.84) ; R999.1 R998.1 108.25,120.45 v1(108.5,120.19) ; R305.1 156.38,77.27 v1(155.88,77.78) ; R17.2 139.01,75.77 v1(139.87,76.63) ; v2(91.42,89.62) 91.48,89.56 C256.1 ; R566.1 R564.2 v1(146.99,104.7) ; C291.1 152.32,122.61 v2(152.29,122.63) ; v1(124,134.54) 123.74,134.29 U22.2 ; C644.1 93.77,91.19 v2(93.02,90.44) ; R629.1 160.55,118.69 160.07,119.18 v1(159.81,119.18) ; R557.2 158.54,126.54 v1(158.92,126.92) ; C290.1 152.37,120.96 v2(152.29,121.03) ; v1(132.76,118.44) 132.79,118.42 R511.2 ; R533.2 v1(132.76,128.7) ; R483.1 119.81,137.34 v1(120.06,137.59) ; C647.1 92.32,84.04 v2(92.22,84.04) 91.99,83.81 91.99,81.97 91.77,81.74 R830.1 R834.1 R831.1 ; v1(110.66,107.87) 110.69,107.85 R1031.1 ; v1(130.47,113.38) 131.06,113.97 R439.2 ; R984.1 v1(89.58,106.73) ; v1(143.05,104.7) 142.92,104.83 R555.2 R524.2 ; v1(123.62,77.9) 123.62,77.52 120.82,74.73 v1(120.82,74.52) 120.24,75.11 119.55,75.11 v1(118.92,74.47) ; v1(123.62,77.9) 123.11,77.9 122.73,78.28 U18.8 ; v1(123.62,77.9) 126.03,80.32 142.92,80.32 144.45,78.79 146.76,78.79 v1(147.82,77.72) ; v1(143.94,69.9) 143.94,70.41 143.18,71.17 R16.2 142.13,70.38 141.02,69.27 139.75,69.27 139.01,70 R15.2 139.01,72.01 v1(139.16,72.16) 139.01,72.31 R18.2 ; v2(142.69,117.03) 142.58,117.15 C295.1 ; R8.1 95.07,129.44 v1(94.53,129.97) ; L17.1 161.84,113.97 v1(162.61,114.73) ; R530.1 v1(130.4,124.13) ; R534.1 v1(132.76,125.27) ; R805.2 149.55,76.86 149.02,77.39 v1(149.02,77.52) ; v1(90.5,109.91) 90.6,109.8 R879.1 ; C681.2 111.65,105.43 v1(111.55,105.33) ; C302.1 142.77,120.96 v2(142.69,121.03) ; v1(137.21,107.52) 136.98,107.29 C14.2 ; R626.2 R625.2 168.96,122.35 v1(168.7,122.61) ; v2(92.22,84.84) 92.02,84.63 C645.1 ; v1(125.78,142.93) 125.88,143.03 C563.1 ; v1(148.13,64.57) 147.75,64.95 R806.1 ; R833.1 88.57,113.59 88.59,113.61 v1(88.59,114.1) ; v1(138.6,135.18) 138.35,134.93 C254.2 ; v1(159.81,108) 159.3,108.51 R590.1 ; v1(152.45,77.65) 152.19,77.39 R1108.1 ; R510.2 v1(132.76,121.84) ; R597.1 167.81,107.47 v1(167.18,108.1) ; R485.1 v1(128.55,142.95) ; C303.1 147.66,114 v2(148.29,114.63) ; R290.1 178.71,70.64 v1(179.07,70.28) ; C742.1 C743.1 129.08,111.1 v1(129.51,111.53) ; v1(84.6,109.91) 84.5,109.8 R885.1 R884.1 ; R484.1 v1(123.01,128.6) ; L15.1 149.58,108.08 150.14,107.52 v1(150.8,107.52) ; R289.1 180.87,70.82 181.5,70.18 v1(181.5,69.01) ; v1(162.35,116.1) 162.2,116.26 L20.1 ; R551.2 136.7,133.91 136.32,134.29 v1(136.32,135.05) ; R870.1 88.95,117.15 v1(88.57,117.53) ; v1(93.39,118.52) 93.39,117.4 93.01,117.02 R886.1 ; U24.8 v1(125.14,135.18) ; R832.1 v1(90.6,114.1) ; v1(149.91,104.7) 150.03,104.83 R581.1 R563.2 ; R576.1 v1(157.4,104.7) ; v2(143.49,118.63) 143.81,118.95 C319.1 ; R497.2 v1(130.48,119.56) ; R601.2 v1(157.53,110.54) ; R764.1 v1(110.28,128.96) ; R584.1 v1(154.35,104.7) ; v1(169.46,28.75) 170.1,29.39 171.12,29.39 v1(171.75,28.75) ; v1(151.45,77.27) 151.45,76.37 150.97,75.9 C703.2 150.8,75.24 151.18,74.85 U44.8 ; R595.1 169.85,107.49 170.38,108.03 v1(170.48,108.03) ; R997.1 v1(108.25,117.4) ; R55.1 v1(153.95,101.24) ; R489.1 v1(132.76,129.85) ; v1(83.36,124.51) R70.1 ; R761.2 v1(113.33,126.16) ; R490.2 v1(132.76,120.7)
  BOTTOM w0.406: v2(93.02,91.24) 93.02,91.25 92.35,91.92 C648.1
  BOTTOM w0.508: D21.2 v1(153.21,21.01)
  vias: v1(133.02,101.02) v1(133.02,99.49) v1(137.21,142.29) v1(137.21,141.4) v1(182.67,113.08) v1(183.18,112.19) v3(134.16,148.01) v3(134.16,146.23) v3(171.37,161.98) v3(171.37,160.58) v3(171.37,156.01) v3(172.89,156.01) v3(172.89,154.23) v3(173.02,161.98) v3(173.02,160.58)
P3V3_AUX_EN: length 125.7
  TOP w0.109: U2.C7 v1(79.71,144.23) ; R235.1 v1(193.98,155.75)
  TOP w0.229: R235.1 193.37,154.97 193.34,154.99 R234.1
  SIG1 w0.086: v1(193.98,155.75) 190.04,155.75 187.5,153.21 175.05,153.21 174.67,152.83 168.32,152.83 167.43,151.94 166.24,151.94 166.04,152.15 159.48,152.15 157.53,154.1 154.61,154.1 152.19,151.69 142.13,151.69 141.6,152.21 124.27,152.21 122.66,150.6 102.86,150.6 102.3,151.16 95.97,151.16 95.41,150.6 83.93,150.6 80.18,146.86 80.18,145.85 79.71,145.37 v1(79.71,144.23)
P3V3_AUX_PG: length 125
  TOP w0.109: U2.C3 v1(75.71,144.23)
  TOP w0.229: U8.2 188.12,157.54 188.77,156.9 188.77,156.01 v1(189.02,155.75) 189.3,155.47 R225.2
  SIG1 w0.086: v1(75.71,144.23) 75.77,144.23 76.25,144.7 77.64,144.7 79.04,146.1 79.04,146.36 79.68,146.99 79.93,146.99 83.81,150.87 95.3,150.87 95.86,151.44 102.41,151.44 102.97,150.87 120.85,150.87 123.27,153.29 136.37,153.29 136.95,152.71 152.78,152.71 154.48,154.41 157.65,154.41 159.61,152.45 165.24,152.45 165.75,152.96 167.81,152.96 168.07,153.21 174.51,153.21 174.9,153.59 186.86,153.59 v1(189.02,155.75)
P3V3_EN: length 74.9
  TOP w0.109: v1(137.59,143.69) 137.71,143.82 137.71,149.02 136.44,150.29 134.16,150.29 131.11,153.34 131.11,156.64 131.59,157.12 R271.1 R274.1 ; U2.B12 v1(85.71,145.23)
  SIG1 w0.086: v1(137.59,143.69) 137.33,143.43 130.09,143.43 129.36,144.17 121.02,144.17 119.85,145.34 116.25,145.34 115.9,144.98 109.2,144.98 108.77,145.41 95.86,145.41 95.44,144.98 91.13,144.98 90.85,144.7 86.41,144.7 85.88,145.23 v1(85.71,145.23)
P3V3_NGFF: length 54.5
  TOP w0.279: J3.72 182.78,92.62 ; v1(165.53,95.81) 165.53,95.68 165.28,95.44 J3.2 ; J3.70 182.28,93.02 ; v1(166.54,95.81) 166.32,95.81 165.78,95.28 J3.4 ; J3.74 183.28,92.36
  TOP w0.381: C55.1 181.66,91.92 ; C55.1 C53.1 182.67,91.9 ; C55.1 181.05,91.21 v1(180.77,91.49) ; v1(185.47,20.88) R1213.1 C784.1
  BOTTOM w0.381: C54.1 v1(167.56,95.81) ; R167.2 168.68,97.49 v1(169.21,96.95) 168.96,96.7 R159.2 R160.2 170.35,95.68 v1(169.72,96.32) ; C56.1 v1(165.53,95.81) ; v1(173.15,96.19) R162.2 R161.2 ; C57.1 v1(166.54,95.81) ; v1(171.75,98.48) 171.56,98.67 Q14.2 ; C789.1 171.9,10.11 172.77,10.97 175.56,10.97 v1(185.47,20.88) ; C789.1 C788.1 ; C789.1 170.99,9.07 ; C788.1 C791.1 ; C788.1 170.99,7.54 ; C791.1 C790.1 v1(170.48,4.5) ; C791.1 170.99,6.02
  vias: v1(165.55,96.7) v1(166.34,93.14) v1(166.34,92.25) v1(166.52,96.7) v1(167,92.76) v1(167.74,92.23) v1(168.32,5.51) v1(168.32,4.5) v1(169.46,5.51) v1(169.46,4.5) v1(170.48,5.51) v1(177.47,74.47) v1(177.47,72.95) v1(178.1,73.84) v1(178.35,72.95) v1(181.07,92.2) v1(181.78,92.79)
P3V3_PG: length 77.8
  TOP w0.109: U2.D12 v1(85.71,143.23)
  SIG1 w0.086: v1(85.71,143.23) 86.16,142.77 86.81,142.77 87.14,142.44 91.39,142.44 92.2,143.25 95.73,143.25 97.31,144.83 108.5,144.83 109.6,143.74 114.4,143.74 114.73,144.07 116.76,144.07 116.89,143.94 120.19,143.94 122.22,141.91 133.65,141.91 134.16,142.42 135.17,142.42 v1(135.68,141.91)
  BOTTOM w0.109: Q19.3 128.7,159.44 128.75,159.49 130.02,159.49 130.35,159.82 R269.2 130.63,153.76 132.03,152.36 133.74,152.36 135.55,150.55 135.55,142.04 v1(135.68,141.91)
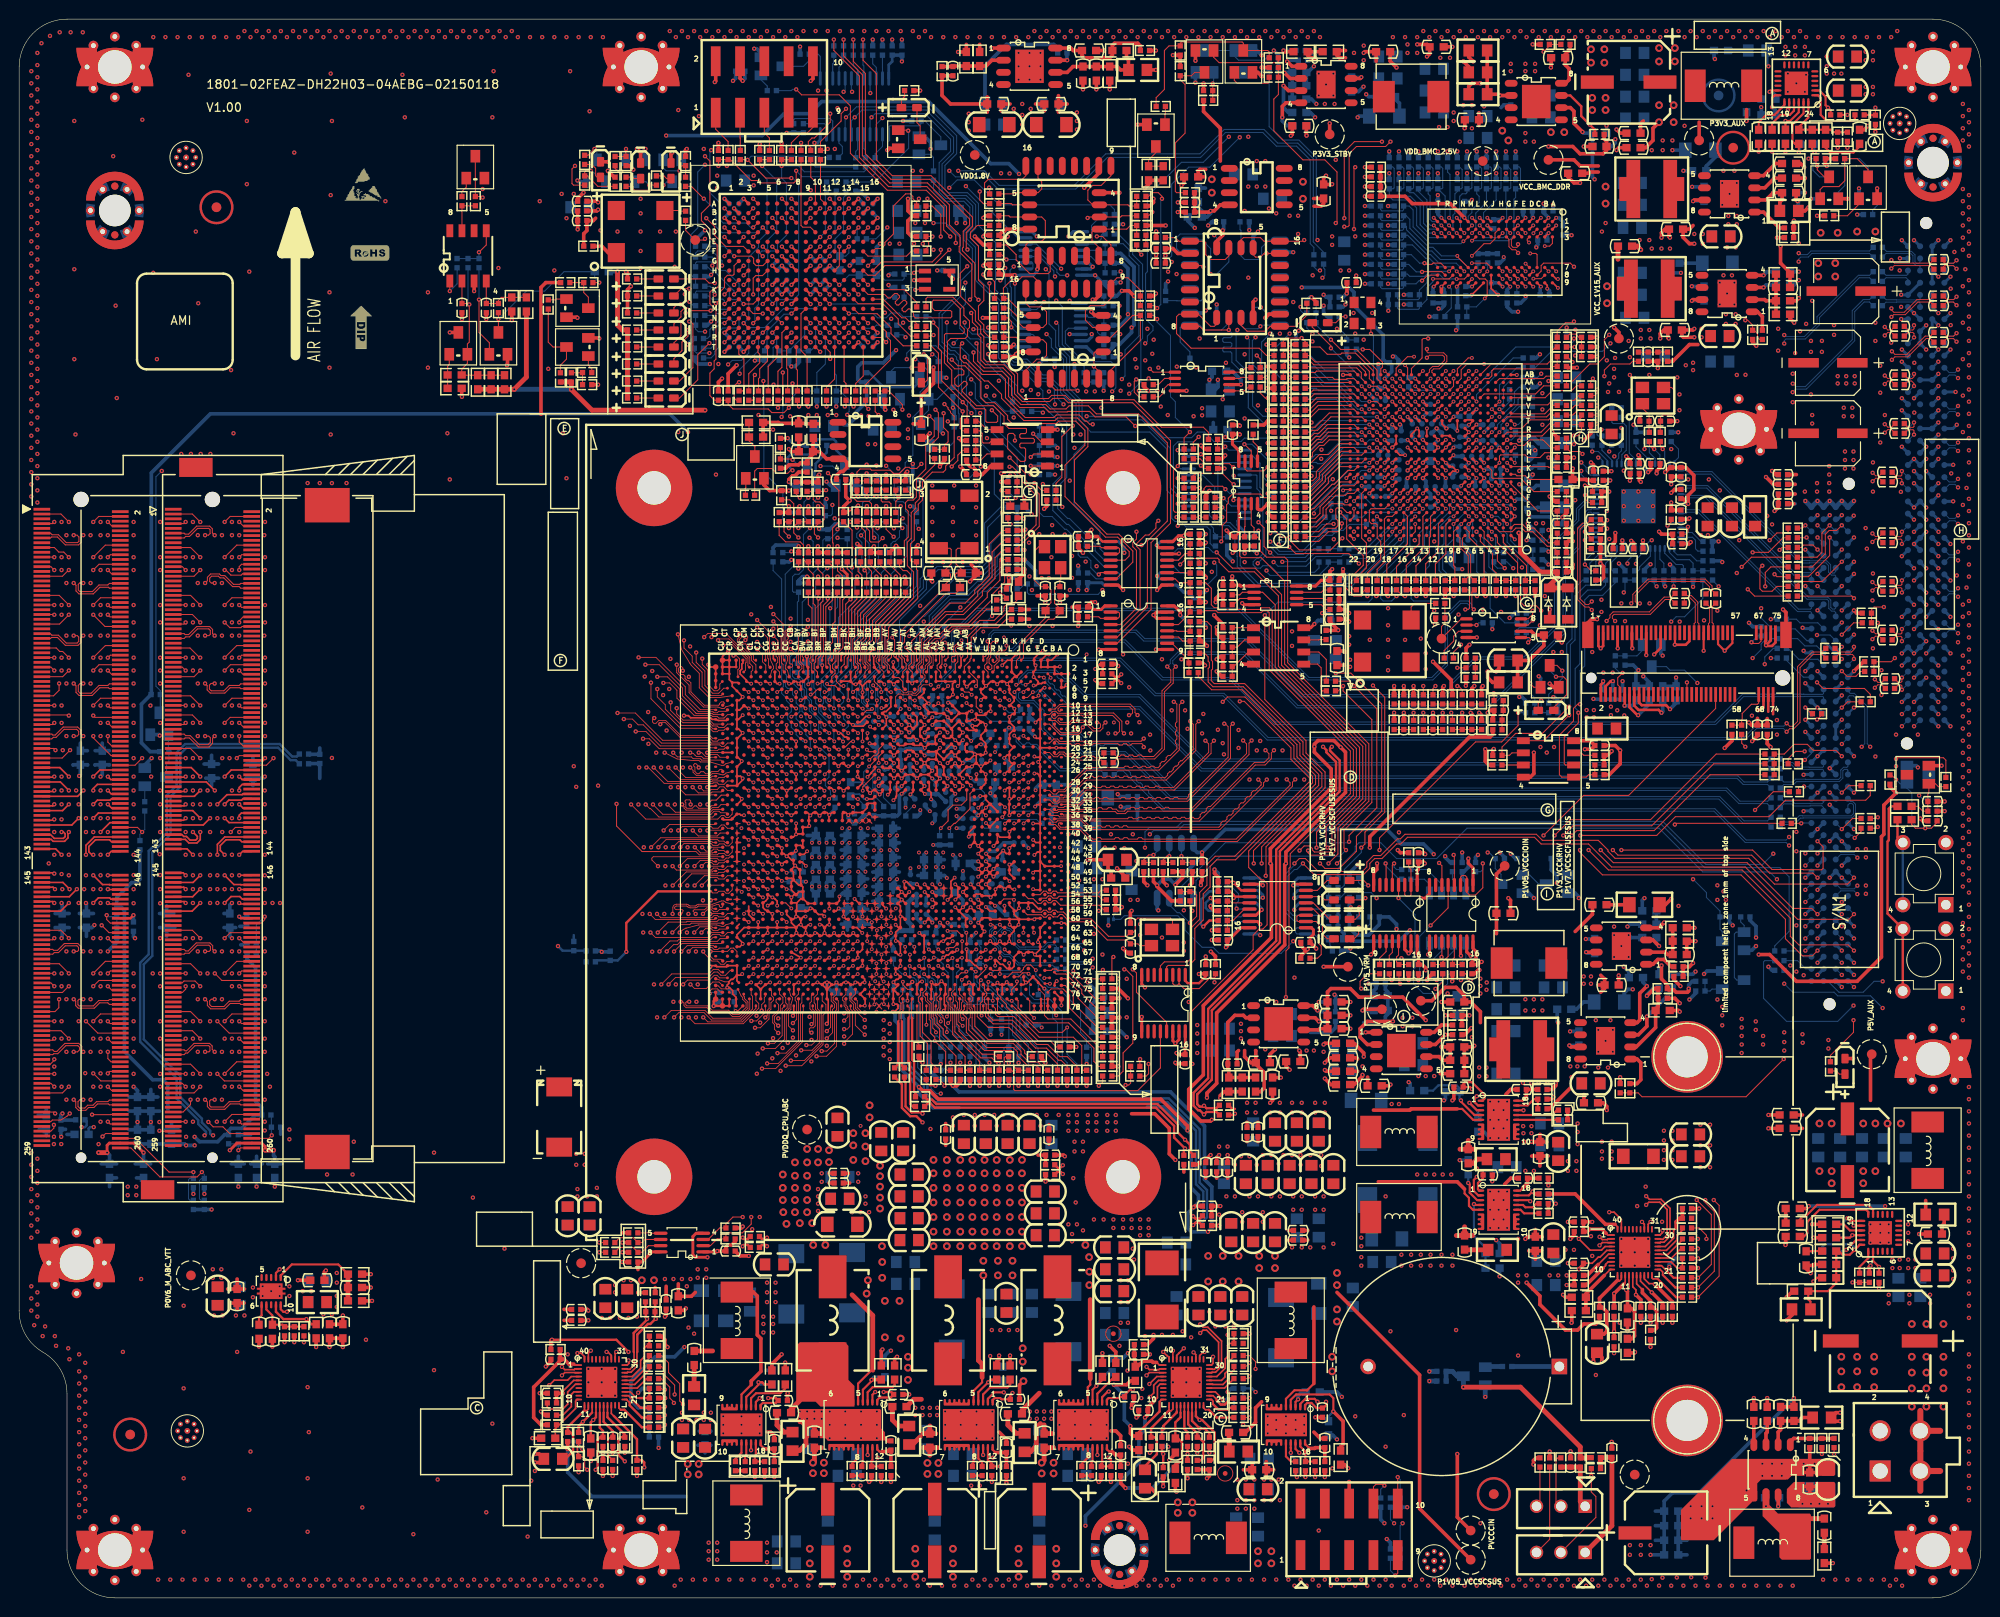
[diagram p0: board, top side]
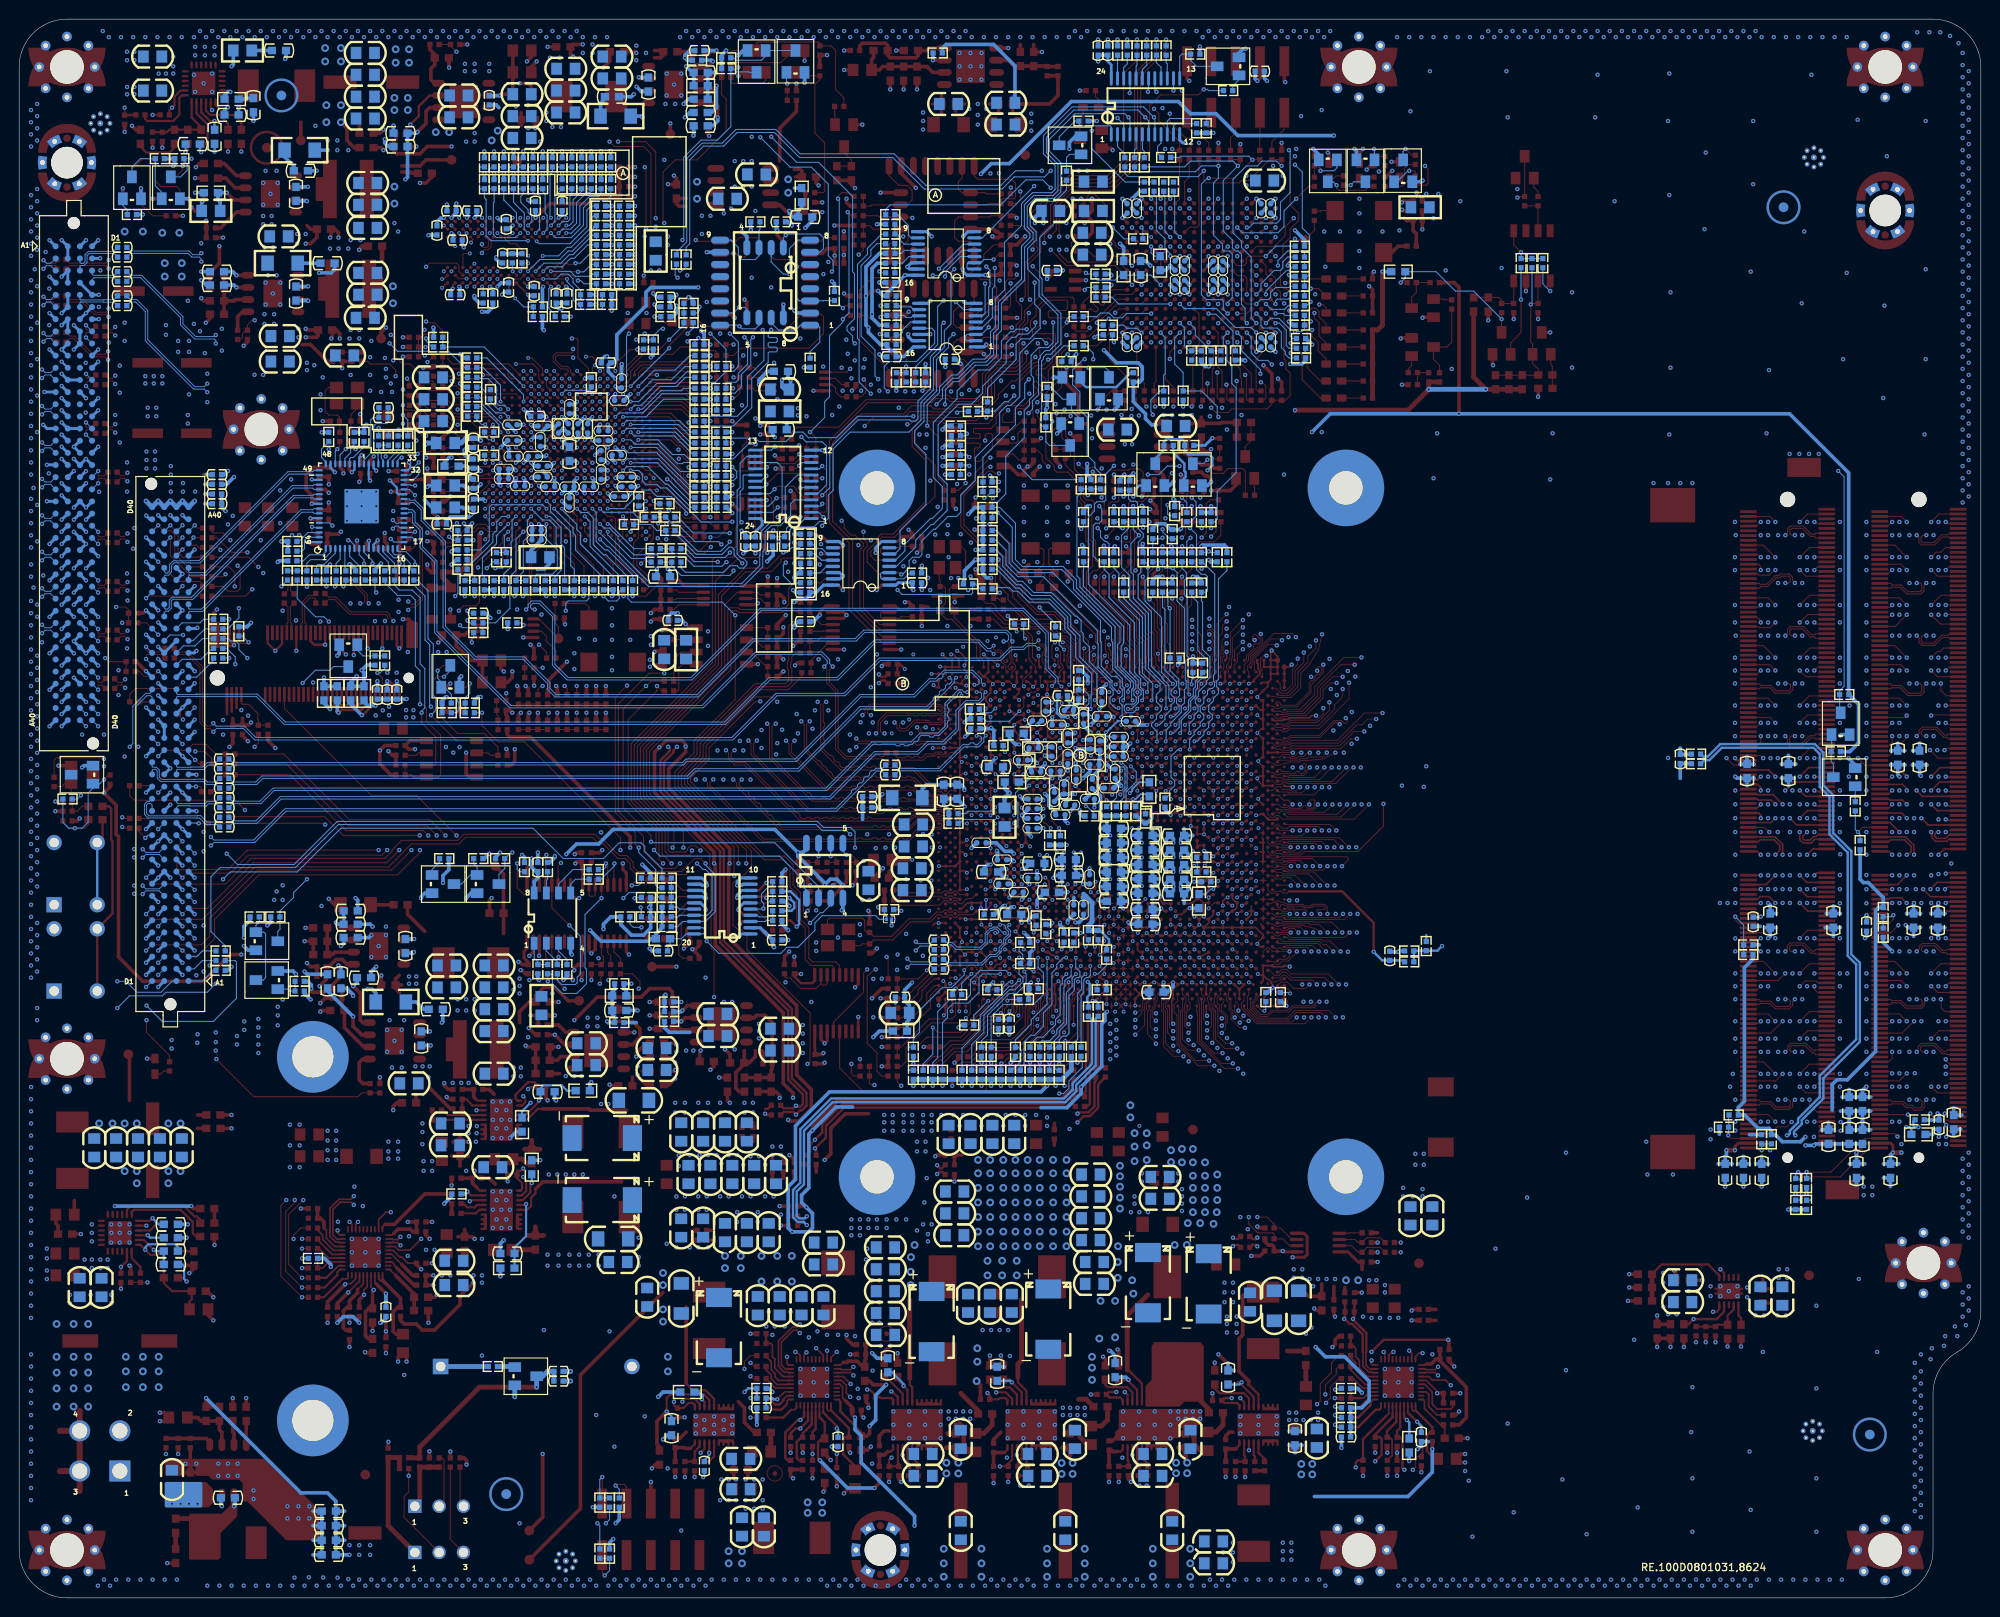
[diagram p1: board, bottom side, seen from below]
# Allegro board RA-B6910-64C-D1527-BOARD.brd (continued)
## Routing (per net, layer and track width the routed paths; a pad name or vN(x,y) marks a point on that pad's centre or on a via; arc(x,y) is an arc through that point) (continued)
P3V3_RTC: length 231.6
  TOP w0.178: U43.AW14 v2(91.42,91.24)
  TOP w0.381: v1(105.15,111.66) 105.05,111.56 R891.1 ; R892.1 v1(105.06,107.49) 105.06,107.09 104.44,106.48 R890.1
  TOP w0.508: R311.1 163.9,14.66 163.88,14.63 R312.1 163.14,15.77 156.89,22.02 v1(150.92,22.02)
  SIG1 w0.508: v1(121.08,112.04) 119.71,110.67 116.12,110.67 v1(116,110.54)
  SIG2 w0.305: 98.09,96.46 97.69,96.06 94.66,96.06 93.52,94.92 91.99,94.92 91.61,94.54 91.61,93.9 91.26,93.55 91.26,93.12 91.74,92.63 91.74,91.56 v2(91.42,91.24)
  SIG2 w0.508: v1(121.08,112.04) 121.33,112.04 121.48,112.19 128.06,112.19 128.7,111.56 128.7,99.24 144.19,83.74 v1(144.19,80.01) ; v1(116,110.54) 111.43,110.54 109.22,112.75 106.65,112.75 105.56,111.66 v1(105.15,111.66) 105.15,111.63 104.19,110.67 104.19,108.36 v1(105.06,107.49) 104.85,107.28 104.85,98.37 102.94,96.46 98.09,96.46
  SIG3 w0.508: v1(180.01,56.95) 179.88,56.95 175.31,61.52 175.31,63.78 173.02,66.07 173.02,70.92 174.04,71.93 174.04,72.59 172.54,74.09 147.37,74.09 145.65,75.81 145.65,76.94 144.83,77.76 144.83,79.38 v1(144.19,80.01)
  SIG4 w0.508: v1(180.01,56.95) 180.01,34.98 172,26.98 155.88,26.98 v1(150.92,22.02)
  BOTTOM w0.508: C226.1 C227.1 149.78,23.67 150.29,23.17 D21.3 v1(150.92,22.02)
P3V3_STBY: length 235.4
  TOP w0.178: U33.5 165.91,36.32 165.2,35.61 165.02,35.61 164.38,34.98 C430.1 ; 118.66,20.63 118.95,20.91 118.95,22.05 119.23,22.33 U29.6 ; U36.5 57.96,22.73 56.82,21.59 v4(56.82,21.39)
  TOP w0.229: U2.J6 v1(78.71,137.23) ; U2.T3 v1(75.71,130.23) ; U2.A14 v1(87.71,146.23) ; U2.P16 v1(89.71,132.23) ; U5.10 27.34,30.17 27.61,29.9 v1(27.99,29.9) ; U2.L9 v1(82.71,135.23) ; U2.J11 v1(84.71,137.23) ; U2.P1 v1(73.71,132.23) ; U2.A3 v1(75.71,146.23) ; U2.C16 v1(89.71,144.23) ; U2.F8 v1(80.71,141.23) ; v1(87.71,131.23) 87.71,131.23 U2.T14 ; U2.F9 v1(82.71,141.23) ; R225.1 v1(191.05,154.99) ; U2.H6 v1(78.71,139.23) ; U2.H11 v1(84.71,139.23) ; U2.C1 v1(73.71,144.23) ; U2.L8 v1(80.71,135.23)
  TOP w0.381: R699.2 v1(175.56,40.69) ; R736.2 67.1,27.36 67.48,26.98 67.48,26.48 v1(67.76,26.2) ; v1(33.83,29.52) C70.1 C71.1 ; J1.4 75.33,158.83 v1(75.61,158.55) ; X20.1 v1(136.95,154.1) ; v1(63.93,137.08) 63.57,136.73 R97.1 R99.1 ; R110.2 v1(77.39,151.94) ; C813.1 108.61,157 ; C813.1 109.52,156.13 ; C813.1 108.61,155.27 ; v1(124.13,12.5) 124.38,12.75 R654.2 R650.1 ; v1(117.65,18.85) 117.95,19.15 C339.1 117.95,19.91 118.66,20.63 ; v1(162.99,34.34) 163.47,34.82 C430.1 ; R220.1 v1(194.36,32.31) ; R728.1 54.91,19.1 v1(54.53,19.48) ; R733.1 v4(62.02,12.75) ; v1(161.72,32.69) R690.1 R686.2 v1(161.72,33.71) ; R109.2 v1(79.68,152.07) ; R203.1 v1(31.03,26.21) ; R238.1 165.63,152.48 165.88,152.22 C140.1 165.88,151.28 165.53,150.93 163.11,150.93 162.35,151.69 v1(159.81,151.69) ; v4(56.82,21.39) C482.1 R726.2 ; v1(63.42,138.61) 63.57,138.46 R96.1 ; v1(151.75,59.55) 151.05,58.85 R300.1 ; R244.1 R245.1 188.74,149.81 v1(188.9,149.66) ; U3.5 97.2,138.23 v1(97.58,137.85) ; R94.2 82.34,124.64 v1(82.47,124.51) ; R653.2 v1(128.57,27.61) ; R737.2 v4(64.56,12.75) ; C171.1 133.88,57.1 v1(133.78,57.2) ; R201.2 v1(27.73,26.72) ; R696.1 v1(170.48,26.21) ; R1235.2 v1(118.79,161.72) ; C94.1 v1(149.78,162.1) ; C207.1 148.51,54.79 ; R700.2 v1(172.77,28.75)
  TOP w0.508: R104.1 R103.1 R102.1 R101.1 R100.1 63.04,132.51 62.53,133.02 v1(62.53,138.61)
  SIG1 w0.381: v1(188.9,149.66) 188.9,151.94 191.05,154.1 v1(191.05,154.99) ; v1(147.87,54.53) 150.92,57.58 150.92,58.73 v1(151.75,59.55) ; v1(128.57,27.61) 128.57,36.63 129.21,37.26 137.08,37.26 v1(137.33,37.01) ; v1(124.13,12.5) 125.27,11.35 132.51,11.35 135.81,8.05 v1(135.81,7.04)
  SIG2 w0.381: 57.58,20.88 57.58,24.31 56.56,25.32 56.56,26.21 58.75,28.4 65.57,28.4 v1(67.76,26.2) ; 82.47,129.97 v1(82.47,124.51)
  SIG4 w0.381: v3(161.46,153.19) 162.89,154.61 167.43,154.61 168.96,153.09 173.91,153.09 174.93,152.07 188.01,152.07 188.9,151.18 v1(188.9,149.66)
  BOTTOM w0.279: C744.1 91.23,160.58 90.87,160.22 U62.24
  BOTTOM w0.381: R1166.2 89.58,141.15 v1(89.96,141.53) ; R209.1 C86.1 134.67,159.44 v1(135.3,160.07) ; C38.1 79.21,139.73 v1(78.71,139.23) ; C35.1 88.21,145.72 v1(87.71,146.23) ; C30.1 89.23,131.75 v1(89.71,132.23) ; v1(117.65,18.85) 117.65,17.58 117.01,16.94 117.01,14.15 111.43,8.56 v1(111.43,7.54) ; R341.2 142.29,8.18 v1(142.67,7.8) ; R343.2 143.3,5.77 v1(142.92,6.15) ; v1(97.58,137.85) 97.58,138.1 97.56,138.13 C42.1 ; C40.1 79.21,137.73 v1(78.71,137.23) ; C31.1 87.73,131.23 v1(87.71,131.23) ; C33.1 74.21,131.72 v1(73.71,132.23) ; 134.92,59.11 137.08,59.11 137.56,59.59 R263.1 ; v1(72.31,138.28) 72.13,138.1 R68.1 ; R1176.1 v1(92.38,154.36) ; R69.1 71.93,133.02 v1(72.31,133.4) ; R95.2 76.93,129.36 v1(76.88,129.31) ; C744.1 C745.1 v1(92.25,160.58) ; R106.1 91.11,136.96 v1(90.85,137.21) ; C43.1 75.84,158.78 v1(75.61,158.55) ; R1251.1 85.17,138.76 v1(84.71,139.23) 84.24,138.76 C37.1 ; v1(89.71,144.23) 89.21,144.72 C34.1 ; R244.1 R245.1 188.74,149.81 v1(188.9,149.66) ; R107.1 90.98,138.35 v1(90.85,138.23) ; C32.1 75.21,130.72 v1(75.71,130.23) ; R342.2 v1(145.06,9.47) ; C41.1 74.21,144.73 v1(73.71,144.23) ; v1(75.71,146.23) 75.21,145.73 C39.1 ; R1173.1 v1(81.61,162.13) ; C36.1 84.24,136.76 v1(84.71,137.23) ; R1250.1 v1(62.53,138.61)
  vias: v1(56.69,146.74) v1(57.96,146.74) v1(76.75,148.64) v1(76.75,147.63) v1(94.03,146.23) v1(94.92,146.23) v1(104.44,161.47) v1(104.44,160.07) v1(104.44,158.67) v1(105.58,161.47) v1(105.58,160.07) v1(105.58,158.67) v1(106.73,161.47) v1(106.73,160.07) v1(106.73,158.67) v1(110.54,155.25) v1(110.54,154.36) v1(110.54,153.47) v1(134.54,57.2) v1(135.3,57.2) v1(146.22,54.53) v1(146.99,54.53) v1(148.38,153.72) v1(148.51,160.96) v1(149.27,153.72) v1(149.53,160.96) v1(149.91,155.25) v1(149.91,154.36) v3(160.07,153.19)
P5V_AUX: length 267.3
  TOP w0.254: R677.1 v1(101.65,12.12)
  TOP w0.381: R682.1 v1(134.41,12.62) ; v1(187.22,33.93) 186.74,34.42 C99.2 187.52,34.75 187.63,34.85 R219.2 ; 162.1,53.29 159.91,51.11 R719.1 ; U9.6 162.1,155.75 162.48,155.37 162.48,154.1 v1(163.37,153.21) ; R751.1 89.07,12.37 v1(88.82,12.12) ; R672.1 102.15,24.69 102.41,24.94 v1(102.41,25.32) ; v1(148.64,57.58) C211.1 C210.1 148.76,56.19 148.38,56.57 U16.6 ; 165.27,65.08 165.68,64.67 C214.1 ; 193.47,51.99 193.47,56.69 X21.1 ; R665.1 v1(113.2,25.58) ; v1(90.22,25.96) 90.09,25.83 R745.1 ; R680.2 138.5,13.92 v1(138.88,13.54) ; C214.1 165.68,63.7 165.27,63.3 ; C214.1 165.02,64.06 ; R755.2 78.66,24.44 v1(79.68,25.45) ; R670.1 113.08,12.37 v1(112.82,12.12) ; v1(146.99,60.38) 144.57,62.79 140,62.79 139.11,63.68 137.08,63.68 136.72,63.32 C176.1 C174.1 C175.1 135.94,59.49 135.81,59.36 U12.6 ; C189.1 163.52,52.6 ; R757.1 v1(76.88,12.62) ; C111.1 186.36,50.47 ; C112.1 186.36,49.07 ; R34.1 v1(164.89,129.72)
  SIG3 w0.381: v1(163.37,153.21) 165.91,150.67 180.89,150.67 183.94,147.63 188.26,147.63 190.67,145.21 194.36,145.21 196.9,142.67 198.17,142.67 199.94,140.89 199.94,83.87 195.37,79.3 195.37,56.31 ; v1(160.57,41.2) 160.57,40.95 158.92,39.29 158.92,32.06 160.96,30.02 ; 79.04,26.47 80.18,27.61 88.57,27.61 v1(90.22,25.96) ; 159.69,30.02 158.29,30.02 v1(154.71,33.6) ; v1(102.41,25.32) 102.28,25.2 102.28,20.37 103.3,19.36 103.3,13.89
  SIG4 w0.381: v1(115.87,14.02) 115.87,14.78 115.11,15.55 115.11,19.48 113.2,21.39 v1(113.2,25.58) ; v1(164.64,148.26) 164.64,133.15 165.53,132.26 165.53,130.23 165.02,129.72 v1(164.89,129.72)
  BOTTOM w0.381: v1(163.37,153.21) 163.5,153.09 C138.1 C139.1 164.41,148.49 v1(164.64,148.26) ; R717.2 145.36,53.75 v1(145.21,53.9) ; R710.2 v1(154.71,33.6) ; R712.1 159.79,41.99 v1(160.57,41.2)
  vias: v1(162.1,55.55) v1(162.23,54.41) v1(162.84,55.55) v1(163.5,64.95) v1(163.5,64.19) v1(163.6,55.55) v1(164.26,64.95) v1(164.26,64.19) v3(188.13,49.58) v3(189.4,49.58) v3(192.71,49.58) v3(193.98,49.58) v3(195.25,49.58) v3(196.64,49.58)
P5V_AUX_EN: length 207.7
  TOP w0.109: R213.1 R214.2 v1(191.59,32.97) ; U2.A7 v1(79.71,146.23)
  SIG3 w0.107: v1(189.07,57.41) 189.52,57.87 189.52,58.48 186.74,61.27 186.74,63.31 184.14,65.91 184.14,66.15 182.42,67.87 182.42,71.81 182.22,72.01 182.22,75.84 176.96,81.1 176.96,82.6 168.96,90.6 157.91,90.6 155.04,93.47 152.06,93.47 151.46,94.08 141.73,94.08 139.62,96.19 137.41,96.19 136.57,97.03 136.57,102.16 136.9,102.49 136.9,103.64 136.06,104.47 136.06,111.05 135.68,111.43 135.68,112.74 135.9,112.95 135.9,115.71 136.44,116.26 136.44,117.27 137.1,117.92 137.1,126.83 136.57,127.36 136.57,133.66 133.4,136.83 133.4,138.23 130.16,141.47 129.02,141.47 122.33,148.15 100.43,148.15 99.14,146.86 96.82,146.86 96.48,147.2 92.46,147.2 91.94,146.68 80.16,146.68 v1(79.71,146.23)
  SIG4 w0.086: v1(189.07,57.41) 190.06,56.41 190.06,34.47 190.09,34.47 v1(191.59,32.97)
P5V_AUX_PG: length 203.7
  TOP w0.109: U2.B11 v1(84.71,145.23)
  TOP w0.229: U7.2 193.73,35.22 v1(194.36,34.6) R220.2
  SIG3 w0.107: v1(189.07,58.3) 186.35,61.02 186.35,63.28 183.74,65.89 183.74,66.14 182.04,67.84 182.04,71.43 181.91,71.55 181.91,75.76 176.65,81.02 176.65,82.4 169.08,89.97 157.91,89.97 154.86,93.02 151.68,93.02 150.91,93.79 141.61,93.79 140.56,94.84 138.17,94.84 136.19,96.83 136.19,102.21 136.62,102.64 136.62,103.49 135.78,104.33 135.78,110.82 135.3,111.3 135.3,112.65 134.87,113.08 134.87,115.33 136.01,116.48 136.01,117.43 136.79,118.2 136.79,126.71 136.24,127.25 136.24,133.35 135.27,134.32 125.27,144.32 124.13,144.32 120.59,147.86 100.59,147.86 99.31,146.58 96.47,146.58 96.13,146.92 92.68,146.92 91.49,145.72 85.2,145.72 v1(84.71,145.23)
  SIG4 w0.086: v1(194.36,34.6) 193.4,35.55 190.86,35.55 190.45,35.97 190.45,56.92 v1(189.07,58.3)
PVCCCIN: length 257.9
  TOP w0.109: U43.BC62 89.46,70.06 ; U43.BC62 88.78,70.06 ; U43.BC62 89.12,69.72 ; U43.BC62 89.12,70.4 ; U43.AG55 96.62,73.72 ; U43.AG55 96.28,73.38 ; U43.AG55 96.62,73.03 ; U43.AG55 96.97,73.38 ; U43.BC72 89.46,64.91 ; U43.BC72 89.12,64.57 ; U43.BC72 89.12,65.25 ; U43.BC72 88.78,64.91 ; U43.AG53 96.97,74.18 ; U43.AG53 96.28,74.18 ; U43.AG53 96.62,74.52 ; U43.AG53 96.62,73.83 ; U43.BG58 87.48,71.78 ; U43.BG58 87.14,71.43 ; U43.BG58 87.14,72.12 ; U43.BG58 86.79,71.78 ; 88.87,62.77 U43.BD76 ; U43.BD76 88.87,63.43 ; U43.BD76 88.54,63.1 ; U43.BD76 89.2,63.1 ; 87.29,70.92 U43.BF60 ; U43.BF60 87.98,70.92 ; U43.BF60 87.63,70.58 ; U43.BF60 87.63,71.26 ; U43.BB56 89.77,72.58 ; U43.BB56 89.08,72.58 ; U43.BB56 89.43,72.92 ; U43.BB56 89.43,72.23 ; U43.BA69 90.11,66.97 ; U43.BA69 89.77,66.63 ; U43.BA69 90.11,66.28 ; U43.BA69 90.45,66.63 ; U43.BD78 89.15,61.87 ; U43.BD78 88.87,61.55 ; U43.BD78 88.87,62.19 ; 88.28,72.58 U43.BD56 ; U43.BD56 88.63,72.23 ; U43.BD56 88.97,72.58 ; U43.BD56 88.63,72.92 ; 89.37,63.27 U43.BB75 ; U43.BB75 89.04,63.6 ; U43.BB75 89.7,63.6 ; U43.BB75 89.37,63.93 ; 89.12,71.43 U43.BC58 ; U43.BC58 88.78,71.78 ; U43.BC58 89.46,71.78 ; U43.BC58 89.12,72.12 ; 87.78,71.78 U43.BE58 ; U43.BE58 88.13,71.43 ; U43.BE58 88.13,72.12 ; U43.BE58 88.47,71.78 ; 89.53,64.09 U43.BA74 ; U43.BA74 89.86,63.76 ; U43.BA74 90.19,64.09 ; U43.BA74 89.86,64.42 ; 88.57,81.72 U43.BD36 89.07,81.72 ; U43.BD60 88.62,71.26 ; U43.BD60 88.97,70.92 ; U43.BD60 88.28,70.92 ; U43.BD60 88.62,70.58 ; U43.AW58 91.44,71.78 ; U43.AW58 91.1,71.43 ; U43.AW58 91.1,72.12 ; 87.68,80.99 U43.BG37 87.17,80.98 ; 89.77,68.34 U43.BA66 ; U43.BA66 90.45,68.34 ; U43.BA66 90.11,68.69 ; U43.BA66 90.11,68 ; U43.BD71 88.62,66.11 ; U43.BD71 88.62,65.43 ; U43.BD71 88.97,65.77 ; 90.6,67.14 U43.AY67 ; U43.AY67 90.6,67.83 ; U43.AY67 90.95,67.49 ; U43.AY67 90.26,67.49 ; U43.AW78 90.85,62.19 ; U43.AW78 90.57,61.87 ; U43.AW78 90.85,61.55 ; 88.78,68.34 U43.BC66 ; U43.BC66 89.46,68.34 ; U43.BC66 89.12,68 ; U43.BC66 89.12,68.69 ; U43.BD67 88.97,67.49 ; U43.BD67 88.62,67.14 ; U43.BD67 88.62,67.83 ; U43.AW62 91.1,70.4 ; U43.AW62 90.76,70.06 ; U43.AW62 91.1,69.72 ; U43.BD74 88.87,64.42 ; U43.BD74 88.87,63.76 ; U43.BD74 89.2,64.09 ; 88.13,70.4 U43.BE62 88.47,70.06 ; U43.AW74 90.85,64.42 ; U43.AW74 90.85,63.76 ; U43.AW74 90.52,64.09 ; U43.BB77 89.7,62.61 ; U43.BB77 89.37,62.28 ; U43.BB77 89.37,62.94 ; U43.BB77 89.04,62.61 ; U43.BA62 90.11,70.4 ; U43.BA62 89.77,70.06 ; U43.BA62 90.45,70.06 ; U43.BA62 90.11,69.72 ; U43.BB64 89.61,69.55 ; U43.BB64 89.61,68.86 ; U43.BB64 89.96,69.2 ; U43.BB64 89.27,69.2 ; 89.27,67.49 U43.BB67 ; U43.BB67 89.61,67.14 ; U43.BB67 89.96,67.49 ; U43.BB67 89.61,67.83 ; 89.53,63.1 U43.BA76 ; U43.BA76 90.19,63.1 ; U43.BA76 89.86,63.43 ; U43.BA76 89.86,62.77 ; 90.68,72.58 U43.AW56 ; U43.AW56 91.03,72.92 ; U43.AW56 91.03,72.23 ; U43.AW56 91.37,72.58 ; U43.AY64 90.95,69.2 ; U43.AY64 90.6,69.55 ; U43.AY64 90.6,68.86 ; U43.AY64 90.26,69.2 ; U43.AY75 90.36,63.93 ; U43.AY75 90.36,63.27 ; U43.AY75 90.69,63.6 ; U43.AY75 90.03,63.6 ; 88.62,68.86 U43.BD64 ; U43.BD64 88.62,69.55 ; U43.BD64 88.97,69.2 ; 86.23,72.23 U43.BJ56 ; U43.BJ56 86.23,72.92 ; U43.BJ56 86.57,72.58 ; U43.BD37 88.61,81.46 ; U43.BD37 89.12,80.95 ; U43.BD37 88.57,80.98 ; 90.11,64.57 U43.BA72 ; U43.BA72 90.45,64.91 ; U43.BA72 89.77,64.91 ; U43.BA72 90.11,65.25 ; U43.BB36 89.77,81.61 ; U43.BB36 89.08,81.61 ; U43.BB36 89.42,81.26 ; 90.76,64.91 U43.AW72 91.1,65.25 ; U43.BB60 89.96,70.92 ; U43.BB60 89.27,70.92 ; U43.BB60 89.61,71.26 ; U43.BB60 89.61,70.58 ; U43.AY77 90.69,62.61 ; U43.AY77 90.36,62.28 ; U43.AY77 90.36,62.94 ; U43.AY77 90.03,62.61 ; 89.12,66.28 U43.BC69 ; U43.BC69 89.46,66.63 ; U43.BC69 89.12,66.97 ; U43.BC69 88.78,66.63 ; 90.6,70.58 U43.AY60 ; U43.AY60 90.26,70.92 ; U43.AY60 90.95,70.92 ; U43.AY60 90.6,71.26 ; 89.27,65.77 U43.BB71 ; U43.BB71 89.61,65.43 ; U43.BB71 89.96,65.77 ; U43.BB71 89.61,66.11 ; U43.AW55 91.37,73.38 ; U43.AW55 90.68,73.38 ; U43.AW55 91.02,73.72 ; U43.AW55 91.02,73.03 ; 90.76,66.63 U43.AW69 ; U43.AW69 91.1,66.97 ; U43.AW69 91.1,66.28 ; 89.58,61.55 U43.BA78 ; U43.BA78 90.14,62.19 ; U43.BA78 90.14,61.55 ; U43.BA78 89.58,62.19 ; U43.AY71 90.95,65.77 ; U43.AY71 90.26,65.77 ; U43.AY71 90.6,66.11 ; U43.AY71 90.6,65.43 ; 90.11,71.43 U43.BA58 89.77,71.78 ; 88.44,81.55 U43.BE37 ; U43.BE37 88.42,80.95 ; U43.BE37 87.84,80.95 ; 86.44,80.95 U43.BH37 87.02,80.95 ; U43.AW76 90.85,63.43 ; U43.AW76 90.52,63.1 ; U43.AW76 90.85,62.77 ; 91.1,68 U43.AW66 ; U43.AW66 91.1,68.69 ; U43.AW66 90.76,68.34 ; 87.03,72.23 U43.BH56 86.68,72.58 ; 91.59,71.26 U43.AV60 91.25,70.92
  TOP w0.229: 100.63,23.04 100.63,22.53 99.73,21.63 U31.5 ; 111.93,22.91 111.93,22.28 111.67,22.01 U30.5
  TOP w0.381: C768.1 107.62,47.42 ; R24.1 154,90.25 153.72,89.97 151.56,89.97 141.14,79.55 v1(141.14,78.41) ; X30.1 150.29,8.43 v1(150.29,15.04) ; C767.1 96.82,47.3 ; R345.2 C231.1 106.47,46.28
  TOP w0.508: 100.25,31.17 100.25,24.82 100.63,24.44 100.63,23.04 ; 111.93,31.17 111.93,22.91
  SIG3 w0.381: 112.19,29.9 122.86,29.9 123.62,29.13 127.3,29.13 127.81,28.63 127.81,23.04 128.44,22.4 138.22,22.4 139.49,21.13 144.19,21.13 v1(150.29,15.04) ; 110.28,51.99 121.08,51.99 126.67,57.58 128.32,57.58 128.7,57.96 135.05,57.96 138.22,61.14 138.22,65.96 141.27,69.01 141.27,73.71 141.65,74.09 141.65,75.49 141.14,76 v1(141.14,78.41)
  BOTTOM w0.381: C622.1 89.86,73.33 v2(90.09,73.56) ; C622.1 89.86,72.29 v2(89.61,72.05) ; C622.1 89.21,72.81 ; v2(89.1,70.61) 88.91,70.42 C615.1 88.03,71.11 v2(88.13,71.21) 88.03,71.3 C616.1 ; C619.1 89.86,78.36 v2(90.09,78.13) 89.86,77.9 C629.1 ; C619.1 89.86,79.45 v2(90.09,79.68) 89.86,79.91 C620.1 89.21,80.43 ; C619.1 89.21,78.91 ; C626.1 88.03,73.99 v2(88.44,74.39) ; C626.1 88.68,73.64 ; C626.1 88.03,73.02 ; C629.1 89.86,77.14 v2(89.33,76.61) ; C629.1 89.21,77.38 ; C628.1 88.03,74.75 v2(87.68,74.39) ; C628.1 88.68,75.14 ; C628.1 88.03,75.54 v2(87.68,75.89) ; C623.1 96.03,77.67 v2(95.8,77.9) ; C623.1 96.68,77.15 ; C623.1 96.03,76.61 v2(95.8,76.38) 96.03,76.15 C625.1 ; C617.1 88.03,79.27 v2(87.68,78.92) ; C617.1 88.03,80.34 v2(87.93,80.44) ; C617.1 88.68,79.69 ; C616.1 88.68,71.97 ; C616.1 88.03,72.57 ; C627.1 89.86,76.38 v2(90.09,76.61) ; C627.1 89.86,75.62 v2(89.33,75.08) ; C627.1 89.21,75.86 ; C624.1 88.68,76.64 ; C624.1 88.03,76.3 v2(88.44,75.89) ; C624.1 88.03,77.04 v2(87.68,77.39) ; v2(88.44,77.39) 88.03,77.8 C618.1 ; C630.1 89.21,74.33 ; C630.1 89.86,74.09 v2(89.33,73.56) ; C630.1 89.86,74.86 v2(90.09,75.08) ; v2(88.44,78.92) 88.03,78.51 C618.1 ; v2(96.22,74.58) 96.03,74.77 C625.1 ; C618.1 88.68,78.17 ; C625.1 96.68,75.5 v2(96.95,75.24) ; C621.1 86.89,62.69 ; C621.1 86.89,63.91 ; C621.1 87.54,63.31
  vias: v1(90.34,60.38) v1(90.34,59.36) v1(90.34,58.47) v1(90.34,57.58) v1(90.34,56.69) v1(90.98,60) v1(90.98,58.98) v1(90.98,58.09) v1(90.98,57.2) v1(90.98,56.31) v2(87.14,71.21) v2(88.62,68.63) v2(88.69,80.44) v2(89.1,67.79) v2(89.33,79.68) v2(89.33,78.13) v2(89.38,62.03) v2(89.45,64.44) v2(89.63,69.77) v2(89.58,66.32) v2(89.58,65.2) v2(89.58,61.27) v2(90.12,71.22) v2(90.09,68.91) v2(90.12,67.23) v2(90.34,64.41) v2(90.37,62.05) v2(90.47,61.27) v2(90.62,70.36) v2(90.6,68.05) v2(90.62,66.35) v2(90.62,65.2) v2(91.11,71.22) v2(91.11,69.49) v2(91.61,72.06) v2(96.57,77.9) v2(96.57,76.38) v3(95.55,45.77) v3(95.55,44.37) v3(95.55,42.85) v3(95.55,41.33) v3(95.55,39.8) v3(95.55,38.28) v3(95.55,36.75) v3(96.95,45.77) v3(96.95,44.37) v3(96.95,42.85) v3(96.95,41.33) v3(96.95,39.8) v3(96.95,38.28) v3(96.95,36.75) v3(98.34,45.77) v3(98.34,44.37) v3(98.34,42.85) v3(98.34,41.33) v3(98.34,39.8) v3(98.34,38.28) v3(98.34,36.75) v3(99.61,45.77) v3(99.61,44.37) v3(99.61,42.85) v3(99.61,41.33) v3(99.61,39.8) v3(99.61,38.28) v3(99.61,36.75) v3(100.76,35.23) v3(100.76,33.71) v3(100.88,45.77) v3(100.88,44.37) v3(100.88,42.85) v3(100.88,41.33) v3(100.88,39.8) v3(100.88,38.28) v3(100.88,36.75) v3(102.15,45.77) v3(102.15,44.37) v3(102.15,42.85) v3(102.15,41.33) v3(102.15,39.8) v3(102.15,38.28) v3(102.15,36.75) v3(102.28,35.23) v3(102.28,33.71) v3(103.53,45.77) v3(103.53,44.37) v3(103.53,42.85) v3(103.53,41.33) v3(103.53,39.8) v3(103.53,38.28) v3(103.53,36.75) v3(103.81,35.23) v3(103.81,33.71) v3(104.8,45.77) v3(104.8,44.37) v3(104.8,42.85) v3(104.8,41.33) v3(104.8,39.8) v3(104.8,38.28) v3(104.8,36.75) v3(111.43,36.88) v3(111.81,35.61) v3(111.83,34.09) v3(111.83,32.69)
PVDDQ_CPU_ABC: length 327.6
  TOP w0.089: U43.CU43 v1(72.14,78.45) ; v1(71.92,80.21) 71.95,80.23 73.33,80.23 U43.CU39 ; v1(68.44,67.56) 69.27,68.39 73.36,68.39 U43.CU65 ; v1(72.12,69.54) U43.CU63 ; v1(72.1,76.48) 72.1,76.47 U43.CU48 ; U43.CU69 73.35,66.75 72.54,66.75 72.25,67.04 v1(72.25,67.56) U43.CU67 74.02,67.56 74.33,67.87 74.33,67.87 74.37,67.91 74.66,67.91 74.66,67.91 75.01,67.56 U43.CP68 ; U43.CU59 72.26,71.52 v1(72.22,71.48) ; U43.CU52 72.15,74.49 v1(72.11,74.45)
  TOP w0.109: 75.01,75.64 U43.CP49 ; U43.CP49 74.68,75.97 ; U43.CP49 75.34,75.97 ; U43.CP49 75.01,76.3 ; U43.CP51 75.01,75.31 ; U43.CP51 75.01,74.65 ; U43.CP51 75.34,74.98 ; U43.CP51 74.68,74.98 ; 75.01,70.69 U43.CP60 ; U43.CP60 75.01,71.35 ; U43.CP60 74.68,71.02 ; U43.CP60 75.34,71.02 ; 75.9,71.78 U43.CL58 76.58,71.78 ; 75.01,80.59 U43.CP38 75.34,80.92 ; U43.CP55 75.34,73 ; U43.CP55 75.01,72.67 ; U43.CP55 74.68,73 ; U43.CP55 75.01,73.33 ; U43.CP58 75.01,72.34 ; U43.CP58 75.01,71.68 ; U43.CP58 74.68,72.01 ; U43.CP58 75.34,72.01 ; 75.01,73.66 U43.CP53 ; U43.CP53 75.01,74.32 ; U43.CP53 75.34,73.99 ; U43.CP40 75.01,80.26 ; U43.CP40 75.34,79.93 ; U43.CP40 75.01,79.6 ; 74.68,76.96 U43.CP47 ; U43.CP47 75.01,76.63 ; U43.CP47 75.34,76.96
  TOP w0.178: U43.CP62 75.01,70.17 75.26,70.42 ; U43.CL35 v2(76.74,81.79) ; U43.CP44 75.3,77.95 ; U43.CP44 U43.CP47 ; U43.CP44 U43.CP42 ; U43.CJ39 v2(77.73,80.08) ; U43.CG51 v2(78.72,74.93) ; U43.CP42 75.01,79.31 75.13,79.43 ; U43.CP42 75.37,78.94 ; U43.CH41 v2(78.22,79.22) ; U43.CG43 v2(78.72,78.36) ; 76.24,72.31 U43.CL58 76.24,71.41 76.57,71.09 76.57,71.09 U43.CK60 ; U43.CH49 v2(78.22,75.78) ; U43.CK52 v2(77.23,74.07) ; U43.CT55 74.41,73 ; U43.CH45 v2(78.22,77.5) ; U43.CF60 v2(78.72,71.49) U43.CG58 77.91,71.95 77.75,72.14 U43.CH56 78.01,72.84 78.22,73.09 U43.CG54 v2(78.72,73.21) 78.99,73.05 79.21,72.82 v2(79.21,72.35) ; U43.CH37 v2(78.22,80.94) ; U43.CH33 v2(78.22,82.65)
  TOP w0.229: U37.5 87.67,22.4 89.07,23.8 89.2,23.8
  TOP w0.254: v1(78.15,37.64) 78.02,37.52 77.62,37.52 R362.2
  TOP w0.381: v1(147.75,97.84) 149.65,95.94 149.65,95.05 149.78,94.92 R36.1 ; C776.1 84.63,44.37 ; C775.1 84.63,43.36
  TOP w0.508: 89.2,23.8 89.2,29.52 87.04,31.67
  SIG1 w0.381: v2(78.22,82.65) 77.38,83.49 76.32,83.49 74.85,84.96 74.85,95.05 77.9,98.1 77.9,116.38 67.48,126.8 67.48,136.7 69.39,138.61 69.39,147.63 67.61,149.4 v1(67.61,152.83)
  SIG2 w0.381: v1(104.49,148.82) 104.82,149.15 134.79,149.15 136.44,147.5 136.44,140.51 137.51,139.45 137.51,134.21 136.3,133 136.3,130.24 136.7,129.85 136.7,118.85 136.52,118.67 136.52,109.58 137.08,109.02 141.47,109.02 145.41,105.08 145.41,102.59 147.3,100.7 147.3,99.62 147.75,99.17 v1(147.75,97.84)
  SIG4 w0.254: v1(78.15,37.64) 78.41,37.39 79.29,37.39 80.1,38.19 83.69,38.19 84.46,38.96 84.46,41.25 85.73,42.52 85.73,44.12 85.48,44.37 v1(83.87,44.37)
  BOTTOM w0.254: R985.1 57.96,69.27
  BOTTOM w0.381: C797.1 8.68,86.01 v1(8.51,85.83) ; C797.1 9.42,87.07 9.44,87.05 ; C797.1 7.95,87.07 7.92,87.05 ; 24.43,84.89 C801.1 ; C801.1 25.51,85.67 v1(25.67,85.83) ; C801.1 23.69,85.67 ; C802.1 5.66,87.07 5.63,87.05 ; C802.1 6.4,86.03 v1(6.27,85.9) ; C802.1 7.13,87.07 7.16,87.05 ; C520.1 6.3,71.53 ; C520.1 7.03,72.58 v1(6.98,72.62) ; C520.1 7.77,71.53 ; v2(82.9,75.87) 82.9,76.28 C677.1 83.61,76.28 v2(83.61,75.87) ; v1(22.24,72.62) 22.02,72.4 C521.1 21.41,71.53 ; v2(83.61,77.39) 83.61,77.8 C676.1 82.85,77.75 v2(82.85,77.39) ; C519.1 3.76,71.53 ; C519.1 5.23,71.53 ; C519.1 4.49,72.57 v1(4.43,72.62) ; C675.1 82.34,79.68 ; C675.1 83.26,80.42 ; C675.1 83.26,79.58 82.85,79.17 v2(82.85,78.92) ; C675.1 83.61,79.32 v2(83.61,78.92) ; R364.1 30.27,87.2 C234.1 31.42,85.65 ; v1(67.61,152.83) 77.64,152.83 79.93,155.12 82.6,155.12 83.87,156.39 95.04,156.39 101.53,149.9 103.41,149.9 v1(104.49,148.82) ; C798.1 20.85,85.67 ; C798.1 20.11,84.89 ; C798.1 19.5,85.67 ; 16.15,71.53 C518.1 ; C518.1 15.41,72.31 ; C518.1 14.68,71.53 ; 83.26,72.59 C674.1 ; C674.1 82.85,73.99 v2(82.85,74.35) 82.85,74.7 C678.1 83.61,74.75 v2(83.61,74.35) 83.61,73.94 C674.1
  vias: v1(3.09,76.76) v1(3.67,80.04) v1(3.67,77.66) v1(4.43,85.83) v1(4.43,84.38) v1(4.43,82.94) v1(4.43,81.36) v1(4.43,75.65) v1(4.51,74.07) v1(5.19,77.66) v1(5.19,75.52) v1(5.96,84.38) v1(6.22,82.94) v1(6.22,72.62) v1(6.8,74.07) v1(6.98,81.49) v1(6.98,80.04) v1(6.98,75.52) v1(7.75,80.04) v1(7.75,74.07) v1(8.51,84.38) v1(8.51,82.94) v1(8.51,81.49) v1(8.51,77.66) v1(8.51,75.52) v1(8.51,74.07) v1(8.51,72.62) v1(9.27,81.49) v1(9.27,80.04) v1(11.96,85.83) v1(11.96,84.38) v1(11.96,82.94) v1(11.96,81.49) v1(11.96,80.04) v1(11.96,77.66) v1(11.96,75.55) v1(11.96,74.07) v1(11.96,72.6) v1(13.79,85.83) v1(14.73,84.38) v1(14.73,82.94) v1(14.73,81.49) v1(14.73,80.04) v1(14.69,77.72) v1(14.73,75.55) v1(14.73,74.07) v1(14.73,72.6) v1(17.4,80.04) v1(17.4,77.66) v1(18.16,85.83) v1(18.16,84.38) v1(18.16,82.94) v1(18.16,81.49) v1(18.16,75.52) v1(18.16,74.07) v1(18.16,72.62) v1(18.92,82.94) v1(18.92,77.66) v1(19.69,84.38) v1(19.95,82.94) v1(19.95,80.04) v1(19.95,77.66) v1(19.95,75.52) v1(19.95,74.07) v1(19.95,72.62) v1(20.71,81.49) v1(20.71,75.52) v1(20.71,74.07) v1(20.71,72.62) v1(21.22,80.04) v1(21.48,74.07) v1(22.24,85.83) v1(22.24,84.38) v1(22.24,82.94) v1(22.24,81.49) v1(22.24,77.66) v1(22.24,75.52) v1(22.24,74.07) v1(23,80.04) v1(25.67,84.38) v1(25.67,82.94) v1(25.67,81.49) v1(25.67,80.04) v1(25.67,77.66) v1(25.67,75.52) v1(25.67,74.07) v1(25.67,72.62) v1(26.48,72.62) v1(27.26,72.62) v1(31.8,29.64) v1(32.69,29.64) v1(33.19,31.55) v1(33.19,30.4) v1(58.21,84.76) v1(60.5,84.89) v1(65.14,71.48) v1(65.21,69.54) v1(65.28,78.45) v1(66.15,67.53) v1(67.42,71.48) v1(67.52,76.48) v1(67.54,74.45) v1(67.5,69.54) v1(67.56,78.45) v1(68.11,80.21) v1(69.64,80.21) v1(69.81,76.48) v1(69.82,74.45) v1(69.78,69.54) v1(69.85,78.45) v1(69.94,71.48) v1(70.72,67.56) v1(71.16,80.21) v1(71.46,72.9) v1(83.49,42.72) v1(83.49,41.96) v1(83.49,41.2) v1(83.49,40.44) v1(83.87,43.49) v2(75.48,80.44) v2(75.51,73.79) v2(75.75,78.36) v2(75.75,76.64) v2(75.75,74.93) v2(75.75,71.49) v2(76.74,71.49) v3(79.8,44.25) v3(79.8,42.85) v3(79.8,41.58) v3(79.85,40.31) v3(80.18,39.09) v3(81.07,45.52) v3(81.07,44.12) v3(81.07,42.85) v3(81.07,41.58) v3(81.07,40.31) v3(81.58,39.17) v3(82.34,46.91) v3(82.34,45.52) v3(82.34,44.12) v3(82.34,42.85) v3(82.34,41.58) v3(82.34,40.31) v3(82.88,39.17) v3(82.98,36.88) v3(83.49,46.91) v3(83.49,45.52) v3(84.25,36.88) v3(84.63,46.79) v3(84.63,45.54)
VCC_1V15_AUX: length 60.2
  TOP w0.178: U20.G11 v2(148.29,115.43) ; U20.R7 v2(151.49,121.83) U20.P7 ; U20.P13 146.29,122.03 v2(146.1,122.23) 145.49,121.62 U20.P14 ; v2(147.11,122.23) 147.09,122.21 U20.P12 ; U20.P11 v2(148.29,121.03) ; U20.H16 v2(143.49,116.23) ; U20.J16 v2(143.49,117.03) ; v2(142.69,124.23) 142.69,124.23 U20.V17 ; U20.G12 v2(146.69,115.43) ; U20.G15 v2(144.29,115.43) ; U20.L7 v2(151.49,118.63) ; U20.P16 U20.N16 v1(143.49,120.23) ; U20.L17 v2(142.69,118.63) ; U20.G7 v2(151.49,115.43) ; U20.G14 v2(145.09,115.43) ; U20.G8 v2(150.69,115.43) ; U20.R16 v2(143.49,122.63) ; U20.P10 148.73,121.46 149.46,121.46 U20.P9 v2(149.89,121.03) ; U20.G13 v2(145.89,115.43) ; U20.G10 v2(149.09,115.43) ; U20.N7 v2(151.49,121.03) ; U20.G9 v2(149.89,115.43) ; U20.F6 v2(152.29,114.63)
  TOP w0.381: X25.1 167.18,132.26 v1(166.67,132.77) ; C159.1 R254.1 185.06,138.51 184.07,139.5 v1(184.07,141.28)
  TOP w0.508: C166.1 167.08,139.9
  SIG1 w0.381: v1(184.07,141.28) 184.46,141.28 186.68,143.5 187.94,143.5 189.02,144.58 v1(192.07,144.58)
  SIG2 w0.381: 167.81,138.23 167.81,138.86 168.83,139.88 182.67,139.88 v1(184.07,141.28)
  BOTTOM w0.381: v2(143.49,122.63) 143.46,122.59 C312.1 ; C315.1 147.56,120.29 v2(148.29,121.03) ; C309.1 151.21,121.31 v2(151.49,121.03) ; C314.1 143.02,118.96 v2(142.69,118.63) ; C310.1 147.98,115.75 v2(148.29,115.43) ; v2(145.89,115.43) 145.94,115.48 C311.1 ; C313.1 143.61,116.92 v2(143.49,117.03) ; v2(151.49,118.63) 151.15,118.29 C308.1 ; R258.1 v1(192.07,144.58)
  BOTTOM w0.508: L18.1 162.35,120.7 v1(162.48,120.57)
  vias: v3(165.93,137.08) v3(165.93,135.31)
VCC_1V15_AUX_EN: length 121.8
  TOP w0.109: R252.1 181.89,131.52 181.66,131.75 181.66,132.13 181.3,132.49 R255.1 181.15,133.02 180.64,133.53 v1(180.39,133.53) ; U2.B8 v1(80.71,145.23)
  SIG1 w0.086: v1(80.71,145.23) 80.71,145.23 81.71,146.23 81.71,147.61 84.15,150.06 123.07,150.06 124.55,151.53 136.11,151.53 136.11,151.53 141.32,151.53 142.59,150.26 162.01,150.26 164.28,147.99 164.28,142.66 165.02,141.91 165.02,134.67 166.04,133.66 180.26,133.66 v1(180.39,133.53)
VCC_1V15_AUX_PG: length 129.2
  TOP w0.109: v1(143.3,152.2) 142.79,151.69 139.75,151.69 138.98,150.93 138.98,143.43 138.86,143.31 v1(138.48,143.31) ; U2.D1 v1(73.71,143.23)
  SIG1 w0.086: v1(138.48,143.31) 138.22,143.05 130.07,143.05 129.22,143.9 120.82,143.9 120.4,144.32 118.28,144.32 117.9,144.71 109.09,144.71 108.66,145.14 95.99,145.14 95.56,144.71 91.77,144.71 90.74,143.69 74.21,143.69 73.75,143.23 v1(73.71,143.23)
  SIG4 w0.086: v1(186.99,150.42) 175.46,150.42 174.07,151.82 165.53,151.82 165.02,152.32 159.43,152.32 158.8,151.69 143.81,151.69 v1(143.3,152.2)
  BOTTOM w0.109: v1(186.99,150.42) R251.2 187.78,150.19 187.45,149.86 187.45,149.2 188.13,148.51 Q17.3
VCC_BATVDD: length 11.3
  TOP w0.178: U20.E4 v2(153.89,113.83)
  TOP w0.508: D31.2 D32.2 159.94,105.84 160.73,106.63 C307.1 158.95,107.21 156.89,109.27 156.89,111.13 v1(156.71,111.3)
VCC_BMC_DDR: length 104.6
  TOP w0.178: v1(149.14,122.23) 148.69,122.68 U20.T10 ; U20.T8 150.29,121.98 v2(150.29,121.97) ; U21.L9 v2(151.83,137.04) ; v2(154.56,136.2) 154.48,136.2 153.82,136.85 U21.J9 U21.J8 ; U21.J2 v2(153.43,143.44) ; v2(160.8,136.91) 160.28,137.44 U21.A9 ; U21.F2 v2(156.62,143.44) ; U21.T9 v2(147.83,137.04) ; U21.D1 v2(158.22,144.24) ; U21.F8 v2(156.62,137.84) ; U21.D9 v2(158.22,137.04) ; U21.C1 v2(159.02,144.24) ; U20.T12 v2(146.69,123.43) ; U21.G7 v2(155.82,138.64) ; U20.T14 v2(145.09,123.43) ; U21.B3 v2(159.82,142.64) ; U21.A1 v2(160.62,144.24) ; v2(159.69,136.83) 159.69,137.18 U21.B9 ; U21.J1 v2(153.43,144.24) ; U21.R1 v2(148.63,144.24) ; U21.L1 v2(151.83,144.24) ; U20.T13 v2(145.89,123.43) ; U21.G1 v2(155.82,144.24) ; U21.G9 v2(155.82,137.04)
  TOP w0.381: R454.1 v1(140.64,148.51) ; R250.1 v1(187.88,144.45) ; C154.1 164,148.9 164.13,149.02 165.02,149.02 ; C147.1 185.7,146.13 v1(185.85,145.97) ; 165.02,149.66 163.11,149.66 162.48,150.29 X24.1
  SIG1 w0.381: v1(165.78,143.69) 167.1,145.01 184.37,145.01 185.34,145.97 v1(185.85,145.97) ; v1(187.88,144.45) 186.86,144.45 185.34,142.93 177.97,142.93 177.34,143.56 167.56,143.56 166.92,142.93 165.53,142.93 v1(165.4,142.8)
  BOTTOM w0.381: C299.1 148.66,122.71 v1(149.14,122.23) 149.4,122.48 C300.1 149.81,122.45 v2(150.29,121.97) ; v2(146.69,123.43) 147.04,123.77 C297.1 ; v2(159.82,142.64) 159.66,142.48 C251.1 ; C241.1 151.81,137.06 v2(151.83,137.04) ; R405.2 v1(140.64,142.42) ; R378.2 v1(147.37,133.91) ; C242.1 148.26,144.61 v2(148.63,144.24) ; C243.1 154.28,136.47 v2(154.56,136.2) ; C240.1 147.75,136.96 v2(147.83,137.04) ; R390.2 v1(155.37,151.18) ; R400.2 v1(140.64,138.35) ; v1(150.16,132.49) 150.31,132.64 R382.2 ; v1(185.85,145.97) 185.85,145.95 185.92,145.87 R243.1 ; v2(145.89,123.43) 146.6,122.72 C301.1 ; v2(158.22,144.24) 158.14,144.33 C239.1 ; v1(143.07,134.52) R410.2 R384.2 ; R373.2 v1(144.19,151.18) ; v2(145.09,123.43) 145.59,122.94 C294.1 ; R418.2 v1(140.64,140.39) ; R420.2 v1(140.64,145.47) ; R398.2 v1(143.18,151.18) ; R375.2 v1(149.27,151.18) ; R394.2 v1(140.64,141.4) ; R392.2 v1(151.3,151.18) ; C249.1 153.79,143.08 v2(153.43,143.44) ; R396.2 v1(152.32,151.18) ; R416.2 v1(147.24,151.18) ; R426.2 v1(140.64,137.34) ; R412.2 v1(148.26,151.18) ; R408.2 v1(150.29,151.18) ; C237.1 161.34,143.82 160.96,144.2 160.67,144.2 v2(160.62,144.24) ; R428.2 v1(156.38,151.18) ; R414.2 v1(140.64,139.37) ; v2(159.69,136.83) 159.91,136.6 C250.1 ; v2(155.82,137.04) 155.49,136.71 C248.1 ; R422.2 v1(146.22,151.18) ; R386.2 v1(153.34,151.18) ; R380.2 v1(140.64,143.43) ; R402.2 v1(145.21,151.18) ; R388.2 v1(154.35,151.18) ; R424.2 v1(140.64,144.45)
  vias: v3(165.78,147.5) v3(165.78,145.72)
VCC_BMC_DDR_EN: length 116.5
  TOP w0.109: U2.A8 v1(80.71,146.23)
  TOP w0.381: R247.1 R242.1 185.44,143.92 v1(185.47,143.94)
  SIG1 w0.086: v1(185.47,143.94) 186.23,144.7 186.23,145.47 186.48,145.72 186.48,146.23 184.96,147.75 183.94,147.75 181.02,150.67 142.76,150.67 141.6,151.84 124.42,151.84 122.91,150.33 102.74,150.33 102.18,150.89 96.09,150.89 95.52,150.33 84.04,150.33 80.71,147 v1(80.71,146.23)
VCC_BMC_DDR_PG: length 120.4
  TOP w0.109: v1(142.41,152.2) 139.54,152.2 138.48,151.14 v1(138.48,144.2) ; R245.2 187.78,149.78 v1(187.91,149.66) 187.91,149.25 188.64,148.51 Q15.3 ; U2.C9 v1(82.71,144.23)
  SIG1 w0.086: v1(138.48,144.2) 136.57,144.2 136.17,143.79 130.12,143.79 129.47,144.44 122.47,144.44 121.58,145.34 120.82,145.34 120.44,145.72 116.06,145.72 115.6,145.26 109.31,145.26 108.89,145.68 95.75,145.68 95.32,145.26 90.55,145.26 90.09,145.72 85.29,145.72 85.19,145.61 85.19,144.79 84.63,144.23 v1(82.71,144.23)
  SIG4 w0.086: v1(142.41,152.2) 142.41,151.31 143,150.72 174.62,150.72 175.31,150.04 186.74,150.04 186.86,149.91 187.65,149.91 v1(187.91,149.66)
VCCAXCK: length 6.5
  TOP w0.178: v2(97.83,85.64) 97.83,85.66 97.45,86.04 U43.AE27
  BOTTOM w0.381: v2(106.22,84.4) 106.22,84.61 106.6,84.99 C604.1 C603.1 110.18,84.99 110.61,84.56 R1008.1
VCCGBE_APH1: length 2.6
  TOP w0.508: C432.1 151.91,37.87 ; C432.1 150.19,37.87 ; C432.1 151.05,38.79
VCCGBE_EN: length 186.9
  TOP w0.109: U2.D11 v1(84.71,143.23)
  TOP w0.254: v4(175.43,35.48) R689.2
  SIG3 w0.107: v1(180.01,60.5) 179.62,60.88 179.62,62.84 177.59,64.87 177.59,67.6 176.18,69.01 176.18,75.89 168.22,83.85 151.79,83.85 146.78,88.85 141.17,88.85 138.6,91.41 136.6,91.41 131.21,96.8 131.21,107.14 130.27,108.08 130.27,109.27 130.02,109.53 130.02,123.46 128.77,124.71 128.77,128.63 127.3,130.1 127.05,130.35 126.87,130.53 126.87,135.28 120.34,141.81 117.39,141.81 116.19,143.02 115.2,143.02 114.55,143.67 100.65,143.67 99.91,144.41 93.33,144.41 91.39,142.47 87.12,142.47 86.91,142.67 85.52,142.67 84.96,143.23 v1(84.71,143.23)
  SIG4 w0.086: v4(175.43,35.48) 179.19,39.24 179.19,59.69 v1(180.01,60.5)
  BOTTOM w0.254: R689.2 v4(175.43,35.48)
VCCGBE_LSET: length 3.5
  TOP w0.229: v1(151.43,43.36) 151.58,43.21 151.58,42.34 152.36,41.56 U34.3
  BOTTOM w0.229: R711.1 v1(151.43,43.36)
VCCGBE_PG: length 196.4
  TOP w0.109: v1(77.77,127.18) 77.77,125.3 77.65,125.17 R90.2
  TOP w0.178: U33.17 169.43,33.11 v1(170.61,31.93)
  TOP w0.381: v1(170.61,31.93) 171.75,30.79 R337.1
  SIG1 w0.086: v1(126.11,129.08) 125.76,129.43 119.64,129.43 119.52,129.3 117.71,129.3 v1(117.67,129.34)
  SIG3 w0.107: v1(117.67,129.34) 116.59,130.42 106.19,130.42 104.78,129.02 100.52,129.02 99.85,128.36 98.51,128.36 97.05,126.9 92.34,126.9 92,127.24 82.23,127.24 81.4,126.42 80.43,126.42 79.32,127.53 78.12,127.53 v1(77.77,127.18) ; v1(177.97,61.77) 177.97,63.04 176.51,64.51 176.51,66.21 174.62,68.1 174.62,70.28 175.36,71.02 175.36,73.18 165.81,82.73 151.02,82.73 146.25,87.5 140.61,87.5 137.81,90.3 136.04,90.3 130.08,96.25 130.08,101.73 129.38,102.43 129.38,106.32 127.63,108.07 127.63,108.08 127.61,108.11 127.61,109.35 128.22,109.96 128.22,113.21 128.88,113.87 128.88,123.07 126.79,125.15 126.79,128.4 v1(126.11,129.08)
  SIG4 w0.086: v1(177.97,61.77) 178.91,60.83 178.91,41.91 174.8,37.79 174.8,34.47 172.26,31.93 v1(170.61,31.93)
VCCGBE_SENSE: length 11.1
  TOP w0.099: 92.93,60.63 92.93,60.67 93.01,60.75 93.01,61.69 U43.AR78
  TOP w0.254: 92.93,60.63 92.93,56.1 93.11,55.93 93.11,51.64 93.39,51.36 R356.1
VCCIN_EN: length 249.7
  TOP w0.109: U2.D6 v1(78.71,143.23)
  SIG3 w0.107: v1(180.01,57.84) 178.86,58.98 178.86,62.66 176.8,64.73 176.8,66.33 175.64,67.49 175.64,73.3 165.93,83.01 151.15,83.01 146.38,87.78 140.89,87.78 138.1,90.58 136.17,90.58 130.36,96.39 130.36,101.85 129.66,102.54 129.66,106.45 128.5,107.61 128.5,113.06 129.17,113.73 129.17,123.16 127.17,125.16 127.17,128.63 125.39,130.42 125.39,134.3 124.51,135.18 124.51,136.2 119.81,140.89 116.76,140.89 115.63,142.02 114.36,142.02 113.64,142.75 99.16,142.75 98.92,142.98 93.6,142.98 92.73,142.11 92.73,141.22 92.21,140.69 86.48,140.69 86.2,140.97 86.2,141.48 85.9,141.78 81.45,141.78 80.77,142.46 79.47,142.46 v1(78.71,143.23)
  SIG4 w0.086: v4(129.21,21.51) 166.8,21.51 171.75,26.47 172.18,26.47 180.65,34.93 180.65,57.17 180.01,57.81 v1(180.01,57.84)
  BOTTOM w0.254: v4(129.21,21.51) 128.82,21.9 R651.2 R644.2
VCCIN_PG: length 342.8
  TOP w0.109: v1(75.23,127.05) 75.1,127.05 74.72,126.67 74.72,125.4 74.95,125.17 R88.2
  TOP w0.178: 122.57,19.36 U29.17
  TOP w0.254: R339.1 124.38,17.2 123.87,17.7 v1(123.36,17.7) 122.57,18.5 122.57,19.36
  SIG1 w0.086: v1(120.98,128.68) 120.21,127.91 117.75,127.91 117.47,127.64 117.47,125.86 117.01,125.4 110.44,125.4 109.3,124.26 107.87,124.26 107.74,124.38 105.79,124.38 105.66,124.26 102.92,124.26 101.76,123.1 98.36,123.1 97.91,123.54 96.99,123.54 96.82,123.37 95.93,123.37 94.59,124.71 88.26,124.71 86.74,123.19 86.23,123.19 85.9,122.86 79.42,122.86 79.32,122.97 v1(75.23,127.05)
  SIG3 w0.107: v1(159.05,127.94) 159.94,127.94 160.45,127.43 160.45,125.15 164.61,120.99 169.56,120.99 170.35,120.19 170.35,119.94 170.73,119.56 173.26,119.56 179.73,113.09 181.64,113.09 186.84,107.88 188.26,107.88 189.38,106.75 189.38,93.65 189.84,93.2 189.84,88.77 189.94,88.67 189.94,82.19 191.15,80.98 191.79,80.98 193.57,79.19 193.57,62.81 v1(194.74,61.65)
  SIG4 w0.086: v1(184.45,64.19) 183.75,63.49 183.12,63.49 181.02,61.39 181.02,59.11 181.19,58.94 181.19,34.71 172.4,25.92 171.98,25.92 166.91,20.86 160.56,20.86 154.28,14.58 136.62,14.58 135.97,13.93 132.72,13.93 132.37,14.27 127.67,14.27 124.23,17.7 v1(123.36,17.7) ; v1(120.98,128.68) 121.2,128.91 121.2,134.93 122.35,136.07 122.35,148.26 124.86,150.77 140.03,150.77 141.14,149.66 141.14,149.15 142.79,147.5 160.57,147.5 162.68,145.39 162.68,141.35 161.84,140.51 161.84,133.27 162.18,132.94 162.18,131.95 161.84,131.62 161.84,130.73 v1(159.05,127.94)
  BOTTOM w0.109: v1(194.74,61.65) 193.46,62.92 190.03,62.92 189.66,63.3 185.34,63.3 v1(184.45,64.19) ; R542.2 158.67,127.56 v1(159.05,127.94)
VCCIN_SENSE: length 7.4
  TOP w0.099: 92.25,60.25 92.25,60.29 92.17,60.37 92.17,61.19 92.37,61.39 92.37,62.22 92.34,62.26 U43.AT77
  TOP w0.254: 92.25,60.25 92.25,55.65 R347.1
VCCKRLCPLL: length 22.3
  TOP w0.178: v2(101.98,72.34) 101.68,72.64 U43.T56
  SIG2 w0.381: v2(101.98,72.34) 102.89,71.43 104.82,71.43 106.09,70.16 106.73,70.16 108.89,68 108.89,65.71 110.28,64.31 v2(111.68,64.31)
  BOTTOM w0.381: v2(101.98,72.34) 102.13,72.34 103.04,71.43 R782.2 ; L32.2 112.21,60.22 111.98,60.45 C606.1 111.98,61.95 112.47,62.43 C605.1 112.47,63.53 v2(111.68,64.31)
VCCSCPLL: length 19.4
  TOP w0.178: v2(101.04,77.77) 101.42,77.39 U43.T46
  TOP w0.381: L33.2 114.12,75.84 113.79,76.17 C608.1 v2(111.68,77.14)
  SIG1 w0.381: v2(101.04,77.77) 101.29,77.52 105.46,77.52 105.84,77.14 107.11,77.14 107.62,77.65 109.65,77.65 110.16,77.14 v2(111.68,77.14)
  BOTTOM w0.381: C607.1 102.89,78.92 102,78.03 101.29,78.03 v2(101.04,77.77)
VCCSCSUS_EN: length 260.2
  TOP w0.109: U2.D13 v1(86.71,143.23)
  TOP w0.254: R648.2 119.43,15.16 v1(119.55,15.04) R652.2
  SIG3 w0.107: v1(181.48,59.36) 181.94,59.82 181.94,61.93 178.46,65.41 178.46,68.25 177,69.71 177,76.29 173.48,79.81 173.48,81 169.08,85.4 152.51,85.4 147.33,90.58 141.93,90.58 139.62,92.89 137.23,92.89 133.47,96.65 133.47,110.03 133.22,110.29 133.22,111.48 132.33,112.37 132.33,131.13 132.24,131.23 132.24,134.31 129.08,137.47 126.03,137.47 121.41,142.09 117.6,142.09 115,144.68 93.19,144.68 91.26,142.75 87.34,142.75 86.87,143.23 v1(86.71,143.23)
  SIG4 w0.086: v1(181.48,59.36) 181.48,34.61 172.52,25.65 172.09,25.65 167.03,20.59 160.67,20.59 154.39,14.31 136.73,14.31 136.08,13.66 132.6,13.66 132.26,14 127.55,14 125.88,15.67 120.95,15.67 120.32,15.04 v1(119.55,15.04)
VCCSCSUS_LSET: length 2.3
  TOP w0.229: v1(133.65,20.75) 133.38,20.48 U32.3
  BOTTOM w0.381: v1(133.65,20.75) 133.65,21.13 134.03,21.51 R681.1
VCCSCSUS_PG: length 260.7
  TOP w0.109: R89.2 76.65,125.17 76.75,125.27 76.75,127.69 v1(76.88,127.81)
  TOP w0.254: R1115.1 v1(122.09,15.04) R338.1
  SIG1 w0.086: v1(118.56,131.5) 122.6,131.5 122.93,131.17 126.87,131.17 v1(128.06,129.97)
  SIG3 w0.107: v1(118.56,131.5) 118.56,131.27 117.78,130.48 117.39,130.48 117.17,130.71 106.07,130.71 104.65,129.29 100.38,129.29 99.72,128.63 98.37,128.63 98.07,128.32 96.82,128.32 96.03,127.53 79.71,127.53 79.42,127.81 v1(76.88,127.81) ; v1(181.48,60.25) 181.48,61.95 178.18,65.25 178.18,68.05 176.72,69.5 176.72,76.15 168.45,84.43 152.1,84.43 146.87,89.66 141.58,89.66 139.26,91.97 136.88,91.97 131.8,97.05 131.8,107.04 132.46,107.7 132.46,108.56 131.18,109.83 131.18,110.29 131.42,110.52 131.42,124.16 130.61,124.96 130.29,124.96 130.28,124.96 129.71,125.53 129.71,128.83 128.57,129.97 v1(128.06,129.97)
  SIG4 w0.086: v1(122.09,15.04) 123.11,14.02 125.78,14.02 126.08,13.73 132.15,13.73 132.49,13.39 136.24,13.39 136.85,14 154.46,14 160.79,20.32 167.14,20.32 172.2,25.38 172.63,25.38 181.78,34.53 181.78,58.98 181.94,59.13 181.94,59.79 v1(181.48,60.25)
VCCSCSUS_SENSE: length 1.8
  TOP w0.178: v2(92.83,62.41) U43.AR76
  BOTTOM w0.254: v2(92.83,62.41) 92.5,62.41 92.25,62.15 R352.1
VDD1.8V: length 23.1
  TOP w0.381: C807.1 97.33,156.13 96.44,157.02 R1234.1 C805.1 ; C807.1 101.16,155.27 ; C807.1 101.16,156.87
  BOTTOM w0.381: 100.94,156.13 C809.1 100.94,160.12 103.17,162.36 108.12,162.36 108.53,161.95 R1231.1
  vias: v1(93.39,149.15) v1(94.28,149.15) v1(99.23,155.12) v1(99.23,154.23) v1(99.23,153.34)
VDD5.0V_EN: length 57
  TOP w0.109: U2.F13 v1(86.71,141.23) ; Q41.3 R1252.2 48.33,146.46 v1(48.43,146.36)
  SIG4 w0.086: v1(86.71,141.23) 86.15,141.78 75.5,141.78 75.23,142.05 75.23,149.15 71.98,152.4 54.48,152.4 v1(48.43,146.36)
  BOTTOM w0.109: v1(86.71,141.23) 86.71,140.56 86.38,140.23 R1251.2
VDD5.0V_EN_MID: length 4
  TOP w0.109: R1252.1 R1253.1 U65.7
VDD_BMC_2.5V: length 8.9
  TOP w0.178: U21.R9 v2(148.63,137.04) ; U21.B1 v2(159.82,144.24)
  TOP w0.381: 152.55,153.87 C134.1 152.55,155.22 ; 148.63,136.46 v2(148.63,137.04) ; R240.1 151.48,157.96 151.81,158.29 v1(152.7,158.29)
  BOTTOM w0.381: C132.1 155.14,156.03 154.86,155.75 ; v2(159.82,144.24) 159.33,144.73 C246.2 159.33,145.69 v1(159.3,145.72) ; v2(148.63,137.04) 148.89,136.77 C247.2
  vias: v1(153.08,155.88) v3(154.99,153.34) v3(155.62,152.32)
VDD_BMC_2.5V_EN: length 96.1
  TOP w0.109: R241.2 R237.2 159.91,162.2 v1(159.3,161.6) ; U2.B1 v1(73.71,145.23)
  SIG1 w0.086: v1(73.71,145.23) 74.34,145.86 74.34,146.36 76.12,148.13 77.14,148.13 80.06,151.05 82.85,151.05 84.05,152.25 121.15,152.25 122.73,153.83 136.59,153.83 137.18,153.25 146.22,153.25 154.57,161.6 v1(159.3,161.6)
VDD_BMC_2.5V_PG: length 102.4
  TOP w0.109: U2.C2 v1(74.71,144.23)
  TOP w0.254: R238.2 164.66,153.44 v1(164.13,153.98) 163.24,154.86 163.24,155.88 162.1,157.02 U9.7
  SIG1 w0.086: v1(74.71,144.23) 74.71,144.44 75.23,144.96 75.23,146.41 75.56,146.74 77.52,146.74 81.45,150.67 83.1,150.67 84.32,151.89 121.41,151.89 123.08,153.56 136.48,153.56 137.07,152.98 152.66,152.98 154.43,154.74 157.78,154.74 158.67,153.85 164,153.85 v1(164.13,153.98)
VSS_VCCGBE_SENSE: length 10.4
  TOP w0.099: U43.AP77 93.24,62.52 93.24,60.75 93.31,60.67 93.31,60.63
  TOP w0.254: 93.31,60.63 93.31,56.26 93.52,56.06 93.52,52.9 93.67,52.76 R357.1
VSS_VCCIN_SENSE: length 8.7
  TOP w0.099: 91.87,60.25 91.87,60.29 91.95,60.37 91.95,61.28 92.15,61.48 92.15,62.13 91.97,62.31 91.97,62.74 92.34,63.11 U43.AT75
  TOP w0.254: 91.87,60.25 91.87,55.78 R348.1
VSS_VCCSCSUS_SENSE: length 3.5
  TOP w0.178: v1(93.33,64.37) 93.05,64.09 U43.AR74
  BOTTOM w0.254: v1(93.33,64.37) 93.14,64.18 93.14,63.04 93.39,62.79 93.39,62.28 93.26,62.15 R353.1
24C02_WP: length 40.1
  TOP w0.109: v2(88.59,88.65) 88.8,88.44 U43.BB21 ; v1(97.46,118.24) 98.09,118.87 98.09,119.43 98.6,119.94 R1003.2
  SIG3 w0.107: v1(97.46,118.24) 96.87,117.65 95.04,117.65 92.88,115.49 92.88,114.93 93.02,114.79 93.54,114.79 93.93,114.4 93.93,112.6 93.58,112.25 93.58,111.37 94.37,110.58 94.37,107.9 94.72,107.55 94.72,103.36 94.08,102.72 94.08,98.02 92.38,96.32 92.38,94.95 91.23,93.8 91.23,91.62 89.45,89.84 89.45,89.21 88.9,88.65 v2(88.59,88.65)
1000M_MDI0N: length 18.5
  BOTTOM w0.099: U26.57 174.18,113.85 174.31,113.72 175.55,113.72 185.94,103.33 187.19,103.33 187.29,103.43 U4.A32
1000M_MDI0P: length 18.5
  BOTTOM w0.099: U26.58 174.18,113.35 174.31,113.47 175.45,113.47 185.84,103.08 187.19,103.08 187.29,102.98 U4.A31
1000M_MDI1N: length 22
  BOTTOM w0.099: U4.C32 189.83,103.46 189.72,103.34 189.49,103.34 189.31,103.52 189.31,104.28 189.02,104.58 186.98,104.58 176.34,115.22 174.31,115.22 174.18,115.35 U26.54
1000M_MDI1P: length 22.1
  BOTTOM w0.099: U4.C31 189.83,102.98 189.68,103.13 189.4,103.13 189.1,103.43 189.1,104.19 188.93,104.37 186.84,104.37 176.23,114.97 174.31,114.97 174.18,114.85 U26.55
1000M_MDI2N: length 17.9
  BOTTOM w0.099: U4.A35 187.29,107.24 187.19,107.14 185.56,107.14 176.46,116.24 174.29,116.24 174.18,116.35 U26.52
1000M_MDI2P: length 17.9
  BOTTOM w0.099: U4.A34 187.29,106.79 187.19,106.89 185.46,106.89 176.36,115.99 174.33,115.99 174.18,115.85 U26.53
1000M_MDI3N: length 21.5
  BOTTOM w0.099: U4.C35 189.83,107.28 189.66,107.1 189.49,107.1 189.3,107.3 189.3,107.98 188.89,108.39 187.11,108.39 187.09,108.41 186.2,108.41 176.91,117.7 174.29,117.7 174.15,117.85 U26.49
1000M_MDI3P: length 21.5
  BOTTOM w0.099: U26.50 174.19,117.35 174.29,117.45 176.8,117.45 186.1,108.16 187.09,108.16 187.11,108.18 188.8,108.18 189.08,107.89 189.08,107.21 189.4,106.89 189.74,106.89 189.83,106.8 U4.C34
AC_OK: length 31.1
  TOP w0.109: R1221.2 v1(60.63,137.47) ; v1(73.71,140.23) U2.F1 ; R1239.2 v1(50.08,133.66) Q39.3
  SIG3 w0.107: v1(73.71,140.23) 71.9,140.23 69.52,137.85 61.01,137.85 v1(60.63,137.47)
  BOTTOM w0.109: v1(50.08,133.66) 53.01,136.58 54.91,136.58 56.94,138.61 R1250.2 60.14,137.95 v1(60.63,137.47)
AC_PG_R: length 1.9
  TOP w0.109: R1230.1 59.84,128.47 59.48,128.83 Q38.1
ACSP1_VCCGBE: length 22.6
  TOP w0.178: U33.4 165.73,36.72 165.36,36.35 164.16,36.35 v1(162.99,37.52)
  TOP w0.229: v1(152.32,43.99) 152.02,43.69 152.02,42.52 152.47,42.06 U34.2
  SIG1 w0.254: v1(152.32,43.99) 152.57,44.25 155.75,44.25 156.74,43.25 156.74,39.82 159.56,37.01 162.48,37.01 v1(162.99,37.52)
ACSP1_VCCIN: length 7.8
  TOP w0.178: U29.4 118.88,23.13 v1(118.11,22.35)
  TOP w0.229: U30.2 113.17,20.97 113.76,21.56 v1(113.86,21.56)
  SIG1 w0.254: v1(118.11,22.35) 116.2,22.35 115.41,21.56 v1(113.86,21.56)
ACSP1_VDDQ: length 42.7
  TOP w0.178: v1(55.39,22.23) 55.93,22.76 57.32,22.76 57.7,23.13 U36.4
  TOP w0.229: U37.2 89.17,21.23 v1(89.45,21.51)
  SIG1 w0.254: v1(55.39,22.23) 55.39,21.79 57.16,20.03 64.01,20.03 66.76,22.78 72.69,22.78 75.36,20.12 80.31,20.12 81.61,21.41 89.1,21.41 89.2,21.51 v1(89.45,21.51)
ACSP2_VCCIN: length 20.9
  TOP w0.178: v4(118.16,21.01) 118.56,21.41 118.56,22.23 119.07,22.73 U29.5
  TOP w0.229: U31.2 101.23,20.81 101.9,21.48 v1(102.9,21.48)
  SIG1 w0.254: v1(102.9,21.48) 103.75,20.63 116.76,20.63 117.01,20.37 117.52,20.37 v4(118.16,21.01)
ADCAV33: length 7.4
  TOP w0.109: U20.J6 v2(152.29,117.03)
  BOTTOM w0.381: v2(152.29,117.03) 152.17,116.91 C316.1 ; C292.1 160.35,112.57 159.94,112.98 158.01,112.98 v1(157.78,113.21) 157.53,113.46 C317.1 158.57,113.87 158.67,113.97 L17.2
ADDR_VCCGBE_P1V05_PCH: length 5.5
  TOP w0.178: U33.10 166.27,34.32 165.65,33.71
  TOP w0.381: 165.65,33.71 163.72,31.78 R691.2 R692.1
ADDR_VCCIN_VCCSCSUS: length 14.2
  TOP w0.178: 119.17,20.5 119.4,20.73 U29.10
  TOP w0.254: R646.1 117.01,17.32 119.17,19.48 119.17,20.5
  TOP w0.381: v1(116.12,17.96) 116.12,17.2 116.4,16.92 R646.1 ; R645.2 116.15,22.68 115.74,22.28 v1(114.4,22.28)
  BOTTOM w0.381: v1(114.4,22.28) 115.49,21.18 115.49,18.59 v1(116.12,17.96)
ADDR_VDDQ: length 5.3
  TOP w0.178: U36.10 58.33,20.73 58.15,20.55 58.15,19.8 56.43,18.09 R727.2 56.16,17.81 56.03,17.68 R729.1
ADR_COMPLETE_CPLD: length 124.5
  TOP w0.109: U55.4 119.91,65.94 120.07,66.1 122.25,66.1 122.86,66.71 122.86,69.96 123.73,70.84 123.73,73.57 124.46,74.3 124.46,76.45 125.14,77.14 127.12,77.14 135.16,85.18 135.16,85.83 133.22,87.77 133.22,89.04 128.1,94.16 126.28,94.16 v1(125.78,93.65) ; U2.G16 v1(88.71,139.23)
  SIG3 w0.107: v1(88.71,139.23) 88.95,139.47 97.88,139.47 98.61,138.74 101.14,138.74 101.39,138.48 103.42,138.48 103.65,138.71 104.29,138.71 105.23,139.65 115.08,139.65 117.95,136.78 118.97,136.78 122.55,133.2 122.55,127.23 122.72,127.06 122.72,125.14 121.99,124.41 121.99,123.09 122.6,122.48 123.11,122.48 124,121.59 124,116.13 123.82,115.95 123.82,112.54 122.53,111.24 122.53,104.65 123.19,103.99 123.19,99.39 124.36,98.21 124.36,95.06 v1(125.78,93.65)
ADR_COMPLETE_GTL: length 29.2
  TOP w0.109: v2(97.56,68.63) 97.27,68.34 U43.AF66 ; U55.13 119.91,60.15 116.76,63.3 116.76,65.3 v1(116.38,65.68)
  SIG1 w0.086: v2(97.56,68.63) 97.94,68.25 99.87,68.25 100.12,68.5 100.76,68.5 101.11,68.15 106.32,68.15 109.29,65.18 115.87,65.18 v1(116.38,65.68)
ADR_IN_CPLD: length 131.9
  TOP w0.109: v1(148.38,76.81) 148.68,76.51 U58.6 ; U2.F5 v1(77.71,141.23)
  SIG3 w0.107: v1(77.71,141.23) 78.25,140.68 78.25,140.03 78.53,139.75 78.91,139.75 79.17,139.5 79.17,139.12 80.06,138.23 88.56,138.23 90.39,136.39 92.23,136.39 92.97,135.65 98.66,135.65 99.4,136.39 104.76,136.39 105.43,137.06 116.38,137.06 118.16,135.28 119.12,135.28 121.71,132.7 121.71,127.17 121.08,126.54 121.08,121.49 122.32,120.25 122.32,113.3 121.51,112.5 120.87,112.5 120.62,112.24 120.62,111.48 120.19,111.05 120.19,100.83 122.58,98.44 122.58,95.06 124.54,93.1 124.54,91.65 123.68,90.79 123.31,90.79 123.1,90.58 123.1,88.7 129.21,82.6 143.58,82.6 148.38,77.8 v1(148.38,76.81)
ADR_IN_GTL: length 72.4
  TOP w0.109: v2(97.01,67.78) 97.19,67.96 97.65,67.96 U43.AD66 ; v1(148.64,66.98) 148.68,67.02 U58.11
  SIG1 w0.086: v2(97.01,67.78) 97.01,67.43 97.07,67.36 97.07,66.73 97.58,66.22 97.58,63.17 99.74,61.01 99.74,58.6 101.83,56.51 101.83,55.55 103.33,54.05 130.63,54.05 132.38,55.8 135.3,55.8 135.94,56.44 136.32,56.44 138.6,58.73 138.6,62.92 140.81,65.13 145.38,65.13 146.7,66.45 148.11,66.45 v1(148.64,66.98)
APH1_VCCIN: length 2.9
  TOP w0.508: 106.6,21.39 104.8,19.58 C347.1
APH1_VDDQ: length 1.6
  TOP w0.508: 81.58,20.63 80.67,19.71 C488.1
APH2_VCCIN: length 1.9
  TOP w0.508: 94.28,20.75 93.49,20.75 C375.1
APWM1_VCCGBE: length 12.8
  TOP w0.178: U33.39 167.43,39.55 166.67,40.31 v4(166.16,40.31)
  TOP w0.229: v1(157.91,41.45) 157.8,41.56 U34.16
  SIG1 w0.381: v1(157.91,41.45) 159.05,40.31 v4(166.16,40.31)
APWM1_VCCIN: length 19
  TOP w0.178: U29.39 120.57,25.83 v4(120.57,25.83)
  TOP w0.229: U30.10 v4(112.67,14.93)
  SIG3 w0.381: v4(120.57,25.83) 119.93,26.47 117.65,26.47 116.76,25.58 116.76,23.55 115.24,22.02 115.24,21.64 114.85,21.26 114.85,16.23 114.09,15.47 113.21,15.47 v4(112.67,14.93)
APWM1_VDDQ: length 40.3
  TOP w0.178: U36.39 59.48,25.58 v4(59.74,25.83)
  TOP w0.229: U37.10 v4(88.67,14.93)
  SIG4 w0.381: v4(88.67,14.93) 88.44,15.16 79.17,15.16 78.02,16.31 73.33,16.31 72.69,16.94 68.12,16.94 67.56,17.5 67.26,17.5 66.15,18.61 66.15,21.2 65.96,21.39 65.96,25.58 64.44,27.1 61.01,27.1 v4(59.74,25.83)
APWM2_VCCIN: length 39.9
  TOP w0.178: U29.38 120.97,25.34 121.2,25.58 v1(121.71,26.09)
  TOP w0.229: U31.10 v1(100.73,14.93)
  SIG1 w0.381: v1(121.71,26.09) 122.09,26.47 125.52,26.47 126.03,25.96 126.03,22.78 125.14,21.9 125.14,19.86 124.51,19.23 119.55,19.23 117.27,16.94 115.11,16.94 113.97,15.8 101.6,15.8 v1(100.73,14.93)
ARM_NTRST: length 10.3
  TOP w0.109: U20.E11 v2(148.29,113.83)
  BOTTOM w0.109: v2(148.29,113.83) 148.29,113.75 146.73,112.19 146.73,111.68 146.35,111.3 146.35,110.16 142.92,106.73 R561.1
ARM_RTCK: length 6.9
  TOP w0.109: R566.2 148,108.05 149.09,109.14 149.09,112.23 U20.C9
ARM_TCK: length 7
  TOP w0.109: R564.1 146.99,108.08 148.31,109.4 148.31,112.24 U20.C10
ARM_TDI: length 8
  TOP w0.109: R562.1 144.95,107.91 146.69,109.65 146.69,113.03 U20.D12
ARM_TDO: length 7.9
  TOP w0.109: R565.1 145.97,107.87 147.37,109.27 147.37,110.8 147.49,110.92 147.49,113.03 U20.D11
ARM_TMS: length 8.9
  TOP w0.109: v2(149.89,112.23) U20.C8
  BOTTOM w0.109: v2(149.89,112.23) 149.89,110.65 148.76,109.53 148.76,107.49 149.27,106.99 150.93,106.99 151.05,106.86 R563.1
ASKIP_VCCGBE: length 8.9
  TOP w0.178: U33.40 167.03,38.79 166.78,39.04
  TOP w0.381: R713.1 162.61,42.22 165.78,39.04 166.78,39.04
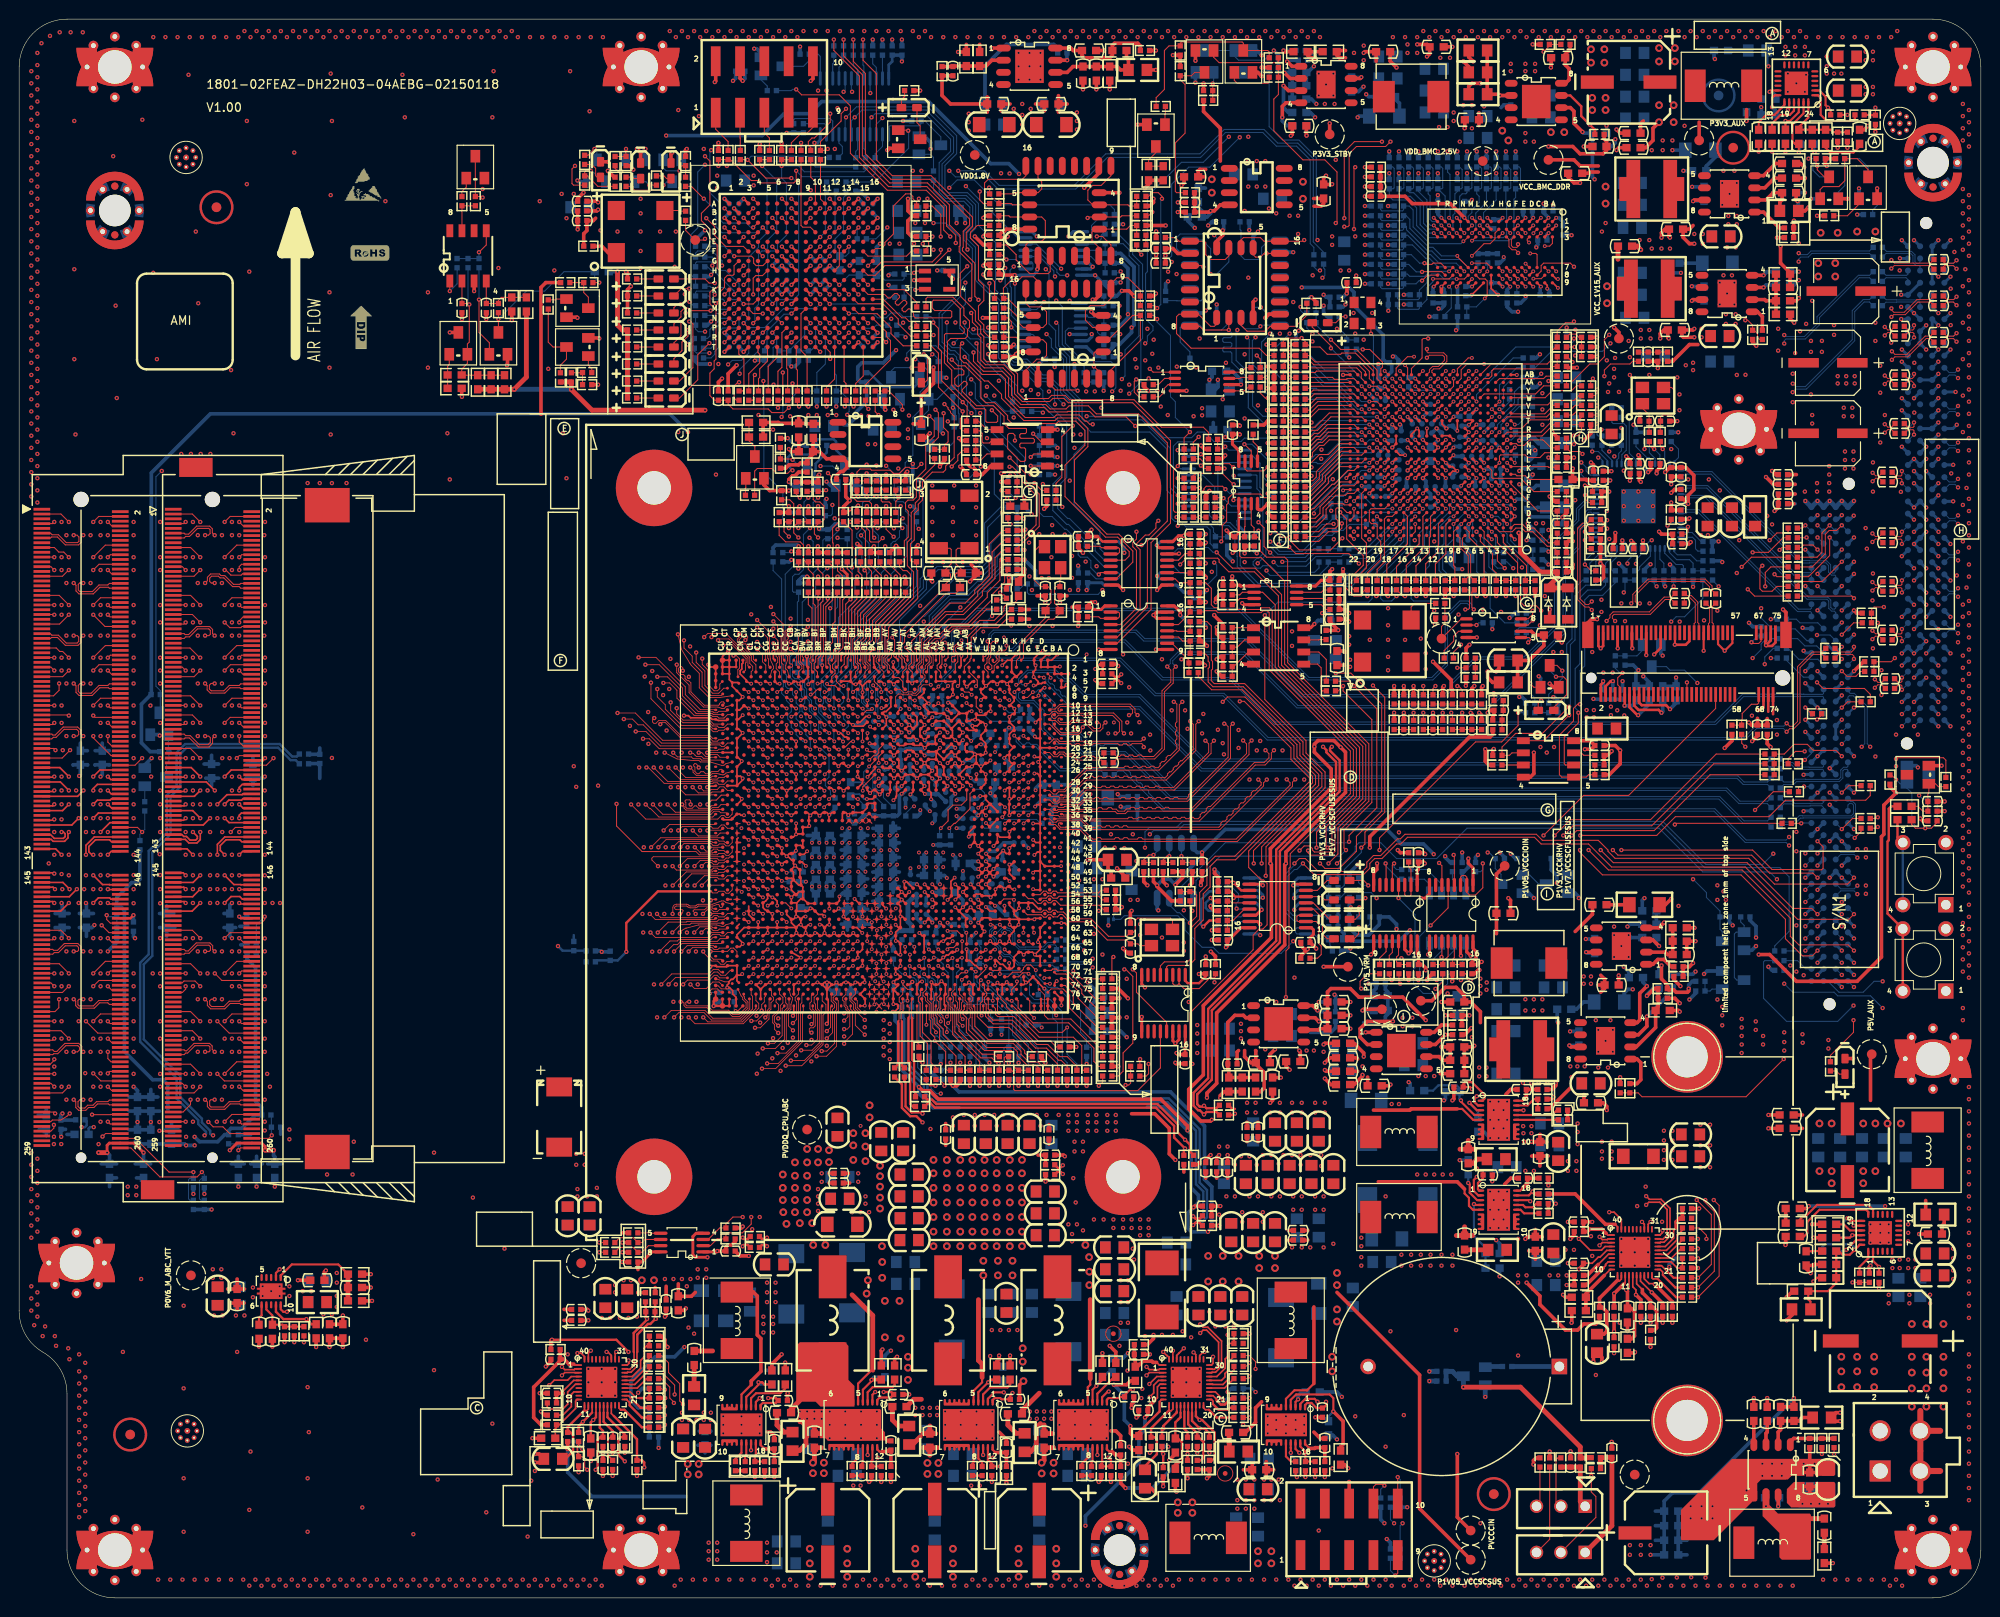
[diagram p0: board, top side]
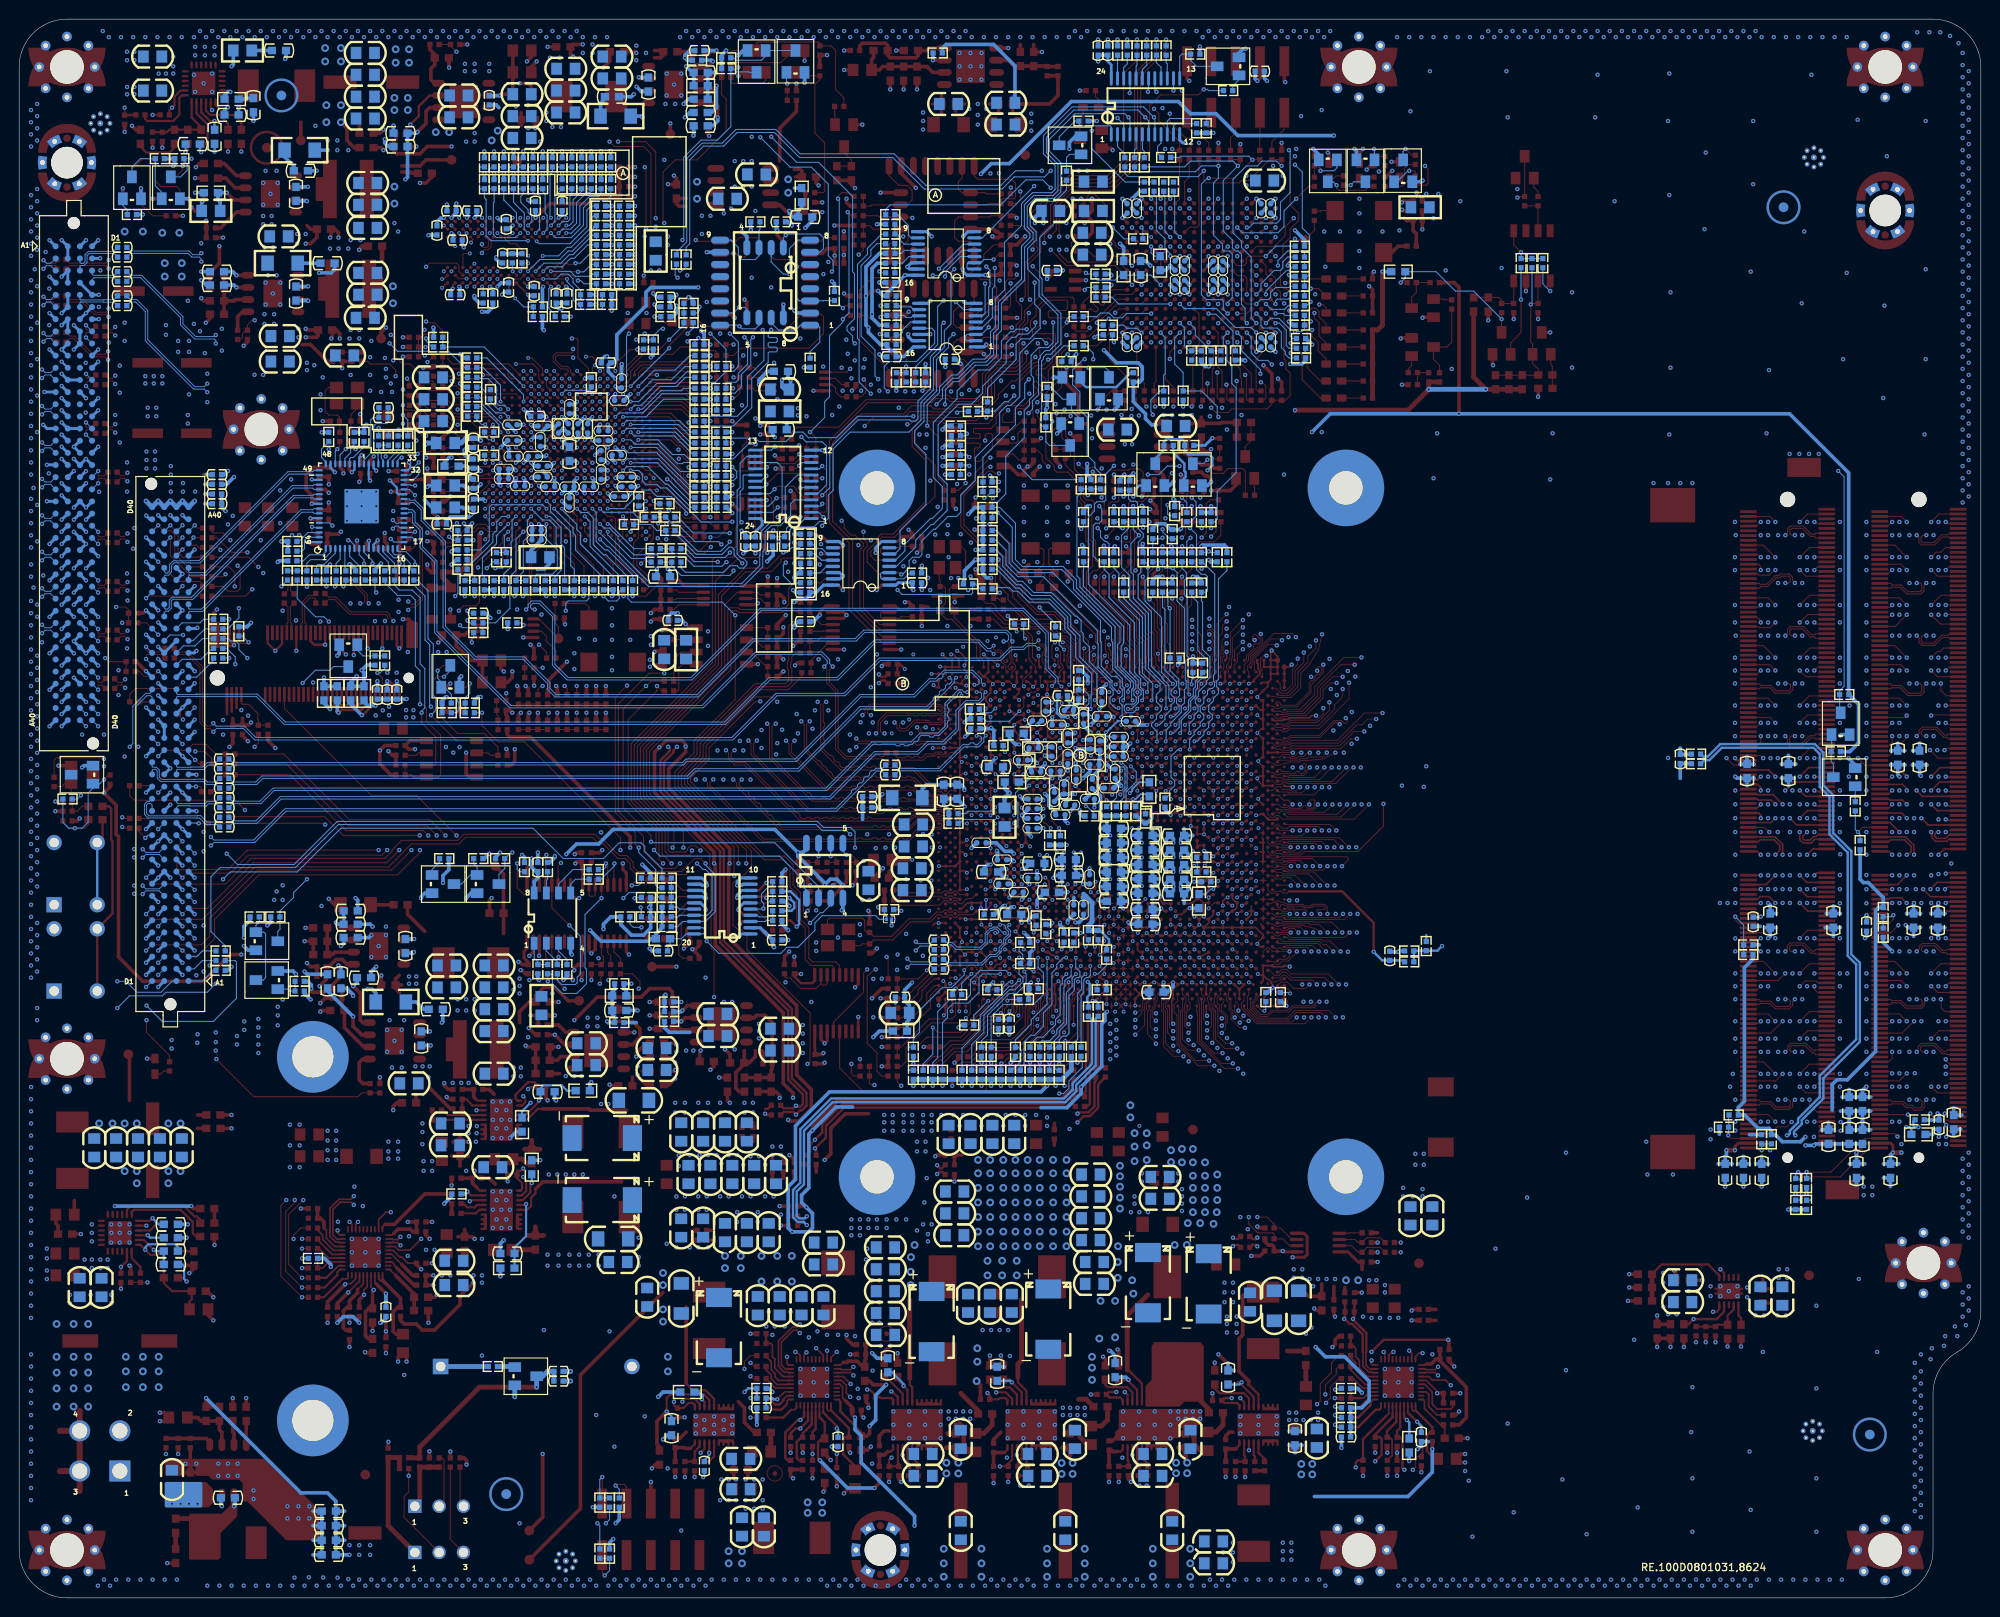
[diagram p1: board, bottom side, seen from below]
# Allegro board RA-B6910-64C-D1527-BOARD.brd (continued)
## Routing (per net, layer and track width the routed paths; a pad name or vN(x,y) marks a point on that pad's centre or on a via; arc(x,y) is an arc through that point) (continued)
ASKIP_VCCIN: length 18.4
  TOP w0.178: U29.40 120.17,25.13 119.97,25.32 119.93,25.32 v1(119.55,25.71)
  TOP w0.381: R671.2 v1(114.09,12.12)
  SIG4 w0.381: v1(114.09,12.12) 115.36,12.12 117.01,13.77 117.01,16.18 119.68,18.85 119.68,25.58 v1(119.55,25.71)
ASKIP_VDDQ: length 44.5
  TOP w0.178: U36.40 59.08,25.22 58.72,25.58 v1(58.34,25.58)
  TOP w0.381: R752.2 v1(90.09,12.12)
  SIG4 w0.381: v1(58.34,25.58) 57.45,24.69 57.45,20.37 58.59,19.23 62.91,19.23 65.78,16.36 67.05,16.36 67.61,15.8 72.06,15.8 72.69,15.16 75.61,15.16 76.25,14.53 78.02,14.53 81.71,10.85 88.82,10.85 v1(90.09,12.12)
BCSP1_P1V05_PCH: length 33
  TOP w0.178: v4(171.73,38.41) 171.73,38.18 171.47,37.92 U33.30
  TOP w0.229: v1(152.32,52.43) 152.12,52.22 152.12,51.79 152.45,51.46 U35.2
  SIG1 w0.254: v1(152.32,52.43) 152.75,52.86 166.06,52.86 170.1,48.82 170.1,44.25 171.17,43.18 171.17,38.97 v4(171.73,38.41)
BCSP1_P2V5_VPP: length 17.5
  TOP w0.178: v4(63.67,24.82) 63.73,24.76 63.73,24.51 63.55,24.33 U36.30
  TOP w0.229: v1(77.39,20.88) 76.99,20.47 U38.2
  SIG1 w0.254: v1(77.39,20.88) 76.93,21.34 75.66,21.34 73,24 65.4,24 64.41,24.99 63.85,24.99 v4(63.67,24.82)
BCSP1_VCCSCSUS: length 16.5
  TOP w0.178: v4(124.76,25.2) 124.76,24.51 124.58,24.33 U29.30
  TOP w0.229: v1(135.68,20.5) 135.38,20.8 134.41,20.8 133.88,20.27 U32.2
  SIG2 w0.254: v4(124.76,25.2) 125.12,25.2 128.16,22.15 134.03,22.15 v1(135.68,20.5)
BIST_ENABLE: length 14.5
  TOP w0.109: U43.AM69 94.31,66.63 v2(94.59,66.9)
  BOTTOM w0.109: R913.2 96.54,55.14 96.82,55.42 96.82,57.33 96.59,57.56 R1134.2 96.31,58.34 95.93,58.73 95.55,58.73 95.3,58.98 95.3,62.92 94.73,63.48 94.73,64.6 94.51,64.82 94.28,64.82 94.15,64.95 94.15,65.46 94.59,65.89 v2(94.59,66.9)
BMBUSY_N: length 107.2
  TOP w0.109: v2(89.82,85.64) 89.82,85.64 U43.BB28 ; v1(161.36,79.68) 162.38,80.7 170.61,80.7 177.08,87.17 R1191.1
  SIG3 w0.107: v2(101.98,88.39) 101.52,87.94 101.14,87.94 100.83,87.63 95.98,87.63 94.38,86.03 90.6,86.03 90.21,85.64 v2(89.82,85.64) ; v1(161.36,79.68) 160.31,78.63 148.77,78.63 143.91,83.49 129.54,83.49 125.9,87.12 v1(125.9,88.16)
  SIG4 w0.086: v1(125.9,88.16) 121.74,88.16 116.76,93.14 110.66,93.14 106.73,89.21 102.79,89.21 v2(101.98,88.39)
  BOTTOM w0.109: R862.2 102.18,88.6 v2(101.98,88.39)
BMC_9641_INT#: length 111.1
  TOP w0.109: U20.T4 v2(153.89,123.43)
  SIG3 w0.107: v2(153.89,123.43) 154.34,122.99 154.99,122.99 155.11,123.11 161.97,123.11 164.38,120.7 168.58,120.7 170.02,119.25 173.17,119.25 179.62,112.8 181.33,112.8 186.64,107.49 188.13,107.49 189.1,106.53 189.1,93.52 189.56,93.06 189.56,88.54 189.65,88.45 189.65,81.97 191.16,80.47 191.16,73.23 193.06,71.32 193.06,63.27 v1(191.69,61.9)
  BOTTOM w0.109: v2(153.89,123.43) 154.31,123.85 155.22,123.85 156.26,124.89 156.26,126.04 156.76,126.54 R557.1 ; R169.1 182.42,66.6 182.29,66.47 182.29,62.66 184.7,60.25 190.04,60.25 v1(191.69,61.9)
BMC_ADC0: length 27.2
  TOP w0.109: U20.F4 v2(153.89,114.63) ; R26.1 v1(146.73,92.51)
  SIG2 w0.107: v2(153.89,114.63) 153.49,114.23 153.49,113.64 153.26,113.41 152.9,113.41 152.7,113.21 152.7,112.83 148.13,108.26 148.13,104.19 148.76,103.56 148.76,96.95 147.5,95.69 147.5,95.03 146.73,94.26 v1(146.73,92.51)
BMC_ADC1: length 29
  TOP w0.109: R27.1 v1(145.72,92.51) ; U20.F5 v2(153.09,114.63)
  SIG2 w0.107: v2(153.09,114.63) 153.09,114.36 152.68,113.94 152.68,113.64 152.47,113.44 149.63,113.44 149.27,113.08 149.27,110.03 147.49,108.26 147.49,104.32 148.48,103.33 148.48,97.32 147.21,96.05 147.21,95.15 145.72,93.65 v1(145.72,92.51)
BMC_ADC2: length 20.9
  TOP w0.109: U20.E2 v2(155.49,113.83) ; v1(150.29,97.21) R28.1
  SIG2 w0.107: v1(150.29,97.21) 149.95,97.55 149.95,103.25 152.68,105.99 152.68,106.33 155.49,109.14 155.49,111.43 155.88,111.81 155.88,113.45 v2(155.49,113.83)
BMC_ADC3: length 27.8
  TOP w0.109: v1(154.1,94.54) 154.12,94.51 R29.1 ; U20.E1 v2(156.29,113.83)
  SIG2 w0.107: v2(156.29,113.83) 156.89,113.23 156.89,112.32 155.87,111.3 155.87,108.89 153.84,106.86 153.84,103.56 152.95,102.67 151.3,102.67 150.23,101.6 150.23,98.53 150.74,98.02 150.74,95.15 151.35,94.54 v1(154.1,94.54)
BMC_ADC4: length 23.8
  TOP w0.109: R30.1 150.8,94.92 150.41,95.3 v1(150.29,95.3) ; U20.F3 v2(154.69,114.63)
  SIG2 w0.107: v2(154.69,114.63) 155.11,114.21 155.11,109.4 152.3,106.58 152.3,105.99 149.61,103.31 149.61,96.36 150.29,95.68 v1(150.29,95.3)
BMC_ADC5: length 25.1
  TOP w0.109: v1(149.65,92.51) 149.78,92.38 R37.1 ; U20.E3 v2(154.69,113.83)
  SIG2 w0.107: v2(154.69,113.83) 154.69,113.68 154.28,113.26 154.28,109.19 151.81,106.73 151.81,105.94 149.32,103.45 149.32,96.01 149.55,95.78 149.55,92.61 v1(149.65,92.51)
BMC_ADC6: length 27.9
  TOP w0.109: U20.G5 v2(153.09,115.43) ; R38.1 v1(146.73,95.3)
  SIG2 w0.107: v2(153.09,115.43) 152.7,115.04 152.7,114.35 152.57,114.22 148.76,114.22 148.69,114.15 148.69,113.64 146.48,111.43 146.48,102.29 148.21,100.56 148.21,97.54 146.73,96.06 v1(146.73,95.3)
BMC_ADC7: length 27.3
  TOP w0.109: v1(162.48,133.4) 162.35,133.27 161.59,133.27 160.73,132.41 R39.1 ; U20.G4 v2(153.89,115.43)
  SIG1 w0.086: v1(162.48,133.4) 162.18,133.1 162.18,132.59 161.84,132.26 161.84,130.1 160.96,129.21 160.96,126.92 157.53,123.5 157.53,115.62 156.94,115.04 154.29,115.04 v2(153.89,115.43)
BMC_ADC8: length 24.3
  TOP w0.109: v1(165.65,127.69) 165.65,128.32 166.29,128.96 168.32,128.96 168.6,129.24 R40.1 ; U20.F2 v2(155.49,114.63)
  SIG1 w0.086: v1(165.65,127.69) 165.65,126.29 165.15,125.78 164.38,125.78 160.83,122.23 160.83,121.08 158.92,119.18 158.92,116.13 157.02,114.22 155.9,114.22 v2(155.49,114.63)
BMC_ADC9: length 25.2
  TOP w0.109: v1(148,95.3) 147.75,95.05 R41.1 ; U20.G3 v2(154.69,115.43)
  SIG2 w0.107: v2(154.69,115.43) 154.28,115.01 154.28,113.64 154.07,113.44 153.69,113.44 153.49,113.23 153.49,111.58 148.51,106.6 148.51,104.32 149.04,103.78 149.04,96.34 v1(148,95.3)
BMC_ALERT_N: length 8.8
  TOP w0.109: R553.2 140.66,105.36 140.38,105.08 140.38,104.82 140.26,104.7 139.49,104.7 138.35,105.84 137.21,105.84 136.98,105.61 R1097.2 136.32,105.33 136.09,105.1 U56.7
BMC_EXTRST_N: length 66.7
  TOP w0.109: U2.A13 v1(86.71,146.23)
  SIG1 w0.086: v1(86.71,146.23) 87.17,146.69 89.89,146.69 90.78,145.79 95.24,145.79 95.57,146.12 109.14,146.12 109.56,145.69 115.42,145.69 115.95,146.23 117.9,146.23 118.41,146.74 120.95,146.74 122.22,145.47 129.08,145.47 130.3,144.25 132.56,144.25 v1(132.76,144.45)
  SIG4 w0.086: v1(132.76,144.45) 131.49,143.18 131.49,133.4 v1(132.76,132.13)
  BOTTOM w0.109: v1(132.76,132.13) 131.14,130.51 R536.1
BMC_GPIO_RS0: length 62
  TOP w0.109: U20.K18 v2(141.89,117.83) ; R197.1 181.02,108.76 v1(180.01,107.75)
  SIG3 w0.107: v2(141.89,117.83) 141.89,115.63 143.3,114.22 159.18,114.22 159.69,113.72 161.96,113.72 165.95,109.73 173.96,109.73 174.29,109.4 178.35,109.4 v1(180.01,107.75)
  BOTTOM w0.109: R439.1 132.1,113.56 132.23,113.44 134.13,113.44 134.39,113.69 R438.1 134.79,113.97 137.21,116.38 137.46,116.38 139.32,118.24 141.49,118.24 v2(141.89,117.83)
BMC_I2C_RST#: length 52.1
  TOP w0.109: v2(152.29,125.03) 152.29,125.03 U20.W6 ; v1(182.16,107.87) 181.91,107.62 181.91,105.46 182.16,105.21 183.18,105.21 183.69,105.72 R193.2
  SIG3 w0.107: v1(182.16,107.87) 181.29,107.87 177.08,112.07 177.08,112.56 172.62,117.02 169.85,117.02 169.59,117.27 162.35,117.27 161.46,118.16 161.46,119.18 158.8,121.84 155.49,121.84 154.86,122.48 153.59,122.48 152.7,123.37 152.7,124.62 v2(152.29,125.03)
  BOTTOM w0.109: R560.1 156.13,129.59 152.29,125.75 v2(152.29,125.03)
BMC_I2C_SCL: length 66.1
  TOP w0.109: v1(130.48,117.27) R470.1 R462.2
  SIG3 w0.107: v1(145.84,110.54) 146.22,110.92 152.45,110.92 152.57,111.05 155.37,111.05 156.13,111.81 158.29,111.81 159.69,110.41 160.35,110.41 160.99,109.78 163.88,109.78 164.26,109.4 173.7,109.4 174.08,109.02 176.58,109.02 179.12,106.48 187.2,106.48 v1(187.93,105.75)
  SIG4 w0.086: v1(130.48,117.27) 132,117.27 132.51,116.76 135.33,116.76 139.14,112.95 141.02,112.95 142.16,111.81 144.83,111.81 145.84,110.8 v1(145.84,110.54)
  BOTTOM w0.109: U4.B33 v1(187.93,105.75)
BMC_I2C_SDA: length 57.6
  TOP w0.109: v1(180.64,105.41) 181.35,104.7 R192.2 ; R463.2 133.42,118.01 133.52,117.91 134.16,117.91 134.39,117.68 R472.1 v1(135.05,117.27)
  SIG3 w0.107: v1(147.87,110.41) 148.26,110.03 160.19,110.03 160.83,109.4 163.72,109.4 164.1,109.02 173.64,109.02 174.02,108.64 176.48,108.64 179.71,105.41 v1(180.64,105.41)
  SIG4 w0.086: v1(135.05,117.27) 135.3,117.27 139.14,113.44 142.06,113.44 142.67,112.83 144.57,112.83 146.99,110.41 v1(147.87,110.41)
BMC_READY_N: length 128.5
  TOP w0.109: v2(88.85,87.58) 89.33,88.06 89.58,88.06 89.84,88.32 89.84,88.7 90.22,89.08 U43.BA19 ; R84.2 79.57,125.17 79.8,125.4 v1(79.8,128.07)
  SIG1 w0.086: v1(137.28,116.92) 137.28,118.57 136.35,119.5 135.86,119.5 133.02,122.35 132.63,122.35 131.75,123.24 131.75,123.62 130.48,124.89 130.22,124.89 129.44,125.67 129.44,127.57 126.4,130.61 122.62,130.61 122.28,130.95 119.04,130.95 118.85,130.77 117.94,130.77 117.78,130.61 117.51,130.61 116.75,131.37 109.4,131.37 107.46,129.44 105.82,129.44 103.12,126.75 101.62,126.75 101.32,127.05 100.63,127.05 v1(99.44,125.86) 98.35,126.94 82.33,126.94 81.2,128.07 v1(79.8,128.07)
  SIG3 w0.107: v2(88.85,87.58) 89.61,87.58 91.26,89.23 92.4,89.23 93.52,90.35 93.52,92.38 93.7,92.56 93.7,93.32 94.74,94.36 94.74,95.5 95.42,96.19 95.42,100.07 96.05,100.7 96.05,103.67 99.18,106.81 100.07,106.81 100.82,107.55 100.82,117.21 100.06,117.97 100.06,122.8 100.87,123.61 100.87,124.43 v1(99.44,125.86)
  BOTTOM w0.109: R467.1 132.1,114.63 132.26,114.47 132.9,114.47 R436.2 133.42,114.71 133.65,114.48 134.74,114.48 137.18,116.92 v1(137.28,116.92)
BMC_RMII_CLK: length 4
  TOP w0.109: U20.B4 v2(153.89,111.43)
  BOTTOM w0.109: v2(153.89,111.43) 154.3,111.02 154.3,109.73 154.1,109.53 R593.2 R592.1
BMC_RMII_CLK_50M: length 14.1
  TOP w0.109: v1(150.67,99.62) 149.88,98.83 R54.2
  SIG2 w0.107: v1(150.67,99.62) 150.67,101.02 151.81,102.16 153.21,102.16 154.86,103.81 154.86,106.35 v1(156.13,107.62)
  BOTTOM w0.109: v1(156.13,107.62) 155.47,108.28 R592.2
BMC_RSTBTN_R: length 11.7
  TOP w0.109: U20.Y6 v2(152.29,126.63)
  BOTTOM w0.109: v2(152.29,126.63) 156.4,130.73 R547.2 R559.1
BMC_SCL: length 10.4
  TOP w0.109: v1(130.48,118.19) 130.07,117.78 128.32,117.78 128.1,117.99 U57.7
  BOTTOM w0.109: v1(130.48,118.19) 130.02,117.73 130.02,117.09 130.35,116.77 132.78,116.77 R440.2 133.42,116.54 133.52,116.64 134.16,116.64 134.39,116.87 R441.1
BMC_SDA: length 7.5
  TOP w0.109: v1(128.04,120.57) 128.75,119.86 U57.6
  BOTTOM w0.109: v1(128.04,120.57) 128.82,120.57 130.35,119.05 130.98,119.05 131.14,118.9 R442.2 R443.1
BMC_SRST_N: length 70.8
  TOP w0.109: U2.A12 v1(84.71,146.23)
  SIG1 w0.086: v1(131.36,144.7) 130.48,144.7 129.21,145.97 122.48,145.97 121.26,147.19 118.25,147.19 117.72,146.66 115.67,146.66 115.24,146.23 109.65,146.23 109.32,146.56 95.99,146.56 95.75,146.79 90.4,146.79 90.05,147.14 85.62,147.14 v1(84.71,146.23)
  SIG4 w0.086: v1(131.36,144.7) 130.98,144.32 130.98,132.39 v1(130.73,132.13)
  BOTTOM w0.109: v1(130.73,132.13) 129.84,131.24 129.84,128.7 130.35,128.19 131.11,128.19 132.25,127.05 133.14,127.05 133.42,127.33 R535.1
BMC_UART_RXD1: length 7.9
  TOP w0.109: R494.2 162.73,126.67 162.24,126.17 160.21,126.17 159.46,125.43 U20.W1
BMC_UART_RXD5: length 41.3
  TOP w0.109: U20.K2 v2(155.49,117.83)
  SIG1 w0.086: v2(155.49,117.83) 155.11,118.21 155.11,118.92 154.99,119.05 151.3,119.05 150.92,118.67 149.84,118.67 149.4,118.23 140.82,118.23 139.49,119.56 139.49,122.1 134.54,127.05 134.54,136.45 135.68,137.59 135.68,138.48 v1(135.94,138.74)
  BOTTOM w0.109: v1(135.94,138.74) 135.68,138.74 135.3,139.12 R1205.2
BMC_UART_TXD1: length 7.8
  TOP w0.109: R493.2 162.99,125.65 162.48,125.15 160.19,125.15 159.74,124.69 155.95,124.69 U20.V1
BMC_UART_TXD5: length 43.7
  TOP w0.109: R580.2 159.83,118.16 159.76,118.23 U20.K1 v2(155.49,118.63)
  SIG1 w0.086: v1(136.19,137.97) 136.19,137.34 135.58,136.73 135.58,126.77 139.87,122.48 139.87,120.07 140.89,119.05 150.8,119.05 151.18,119.43 155.11,119.43 155.49,119.05 v2(155.49,118.63)
  BOTTOM w0.109: R1204.2 136.32,138.99 136.44,138.86 136.44,138.23 v1(136.19,137.97)
BMCINIT: length 17.6
  TOP w0.109: v2(98.52,66.9) 98.31,66.9 U43.AD69
  BOTTOM w0.109: R837.2 103.07,55.14 102.92,55.3 102.92,57.43 103.04,57.56 R896.2 103.42,60.76 102.15,62.03 98.98,62.03 97.96,63.04 97.96,65.33 98.52,65.89 v2(98.52,66.9)
BMCO_UART_RXD1: length 104.4
  TOP w0.109: v1(164.46,127.43) 164.23,127.2 R494.1 ; U2.B10 v1(83.71,145.23)
  SIG1 w0.086: v1(83.71,145.23) 83.71,146.07 85.22,147.58 90.51,147.58 90.85,147.24 94.17,147.24 94.9,147.98 101.52,147.98 102,147.5 110.79,147.5 111.53,148.23 123.72,148.23 124.76,149.28 136.57,149.28 137.84,148.01 161.21,148.01 162.84,146.38 162.84,142.06 163.24,141.65 163.24,128.65 v1(164.46,127.43)
BMCO_UART_RXD5: length 69.4
  TOP w0.109: U2.H16 90.11,139.62 95.42,139.62 96.31,140.51 v1(96.31,140.89)
  SIG4 w0.086: v1(97.2,149.15) 97.64,148.71 97.64,147.12 96.77,146.25 96.77,141.35 v1(96.31,140.89)
  BOTTOM w0.109: R1205.1 135.3,141.15 134.92,141.53 134.92,150.29 133.48,151.73 131.39,151.73 129.96,153.15 126.06,153.15 123.45,150.55 113.71,150.55 110.41,147.24 102.28,147.24 101.01,148.51 97.84,148.51 v1(97.2,149.15)
BMCO_UART_TXD1: length 107.2
  TOP w0.109: U2.B9 v1(82.71,145.23) ; v1(164.89,126.29) 164.89,125.91 164.64,125.65 R493.1
  SIG1 w0.086: v1(164.89,126.29) 165.02,126.42 165.02,127.81 163.62,129.21 163.62,141.66 163.11,142.17 163.11,146.49 161.32,148.28 141.89,148.28 141.14,149.02 137.59,149.02 137.06,149.55 124.4,149.55 123.36,148.51 111.41,148.51 110.68,147.77 102.12,147.77 101.63,148.25 94.79,148.25 94.16,147.63 90.98,147.63 90.75,147.85 84.98,147.85 82.71,145.58 v1(82.71,145.23)
BMCO_UART_TXD5: length 71.5
  TOP w0.109: U2.H15 88.71,138.23 89.45,138.23 90.47,139.24 95.55,139.24 v1(97.2,140.89)
  SIG4 w0.086: v1(97.2,140.89) 97.2,141.55 97.84,142.18 97.84,142.55 97.02,143.36 97.02,146.05 97.96,146.99 97.96,148.98 v1(98.13,149.15)
  BOTTOM w0.109: R1204.1 136.32,140.64 135.24,141.72 135.24,150.42 133.61,152.04 131.52,152.04 130.09,153.47 125.93,153.47 123.39,150.93 113.55,150.93 110.25,147.63 102.41,147.63 100.88,149.15 v1(98.13,149.15)
BPH1_VCCSCSUS: length 4.1
  TOP w0.381: 129.84,20.5 129.21,19.86 129.21,18.34 128.16,17.3 C402.1
BPWM1_P1V05_PCH: length 20.2
  TOP w0.178: U33.33 169.83,39.06 v4(169.59,39.29)
  TOP w0.229: U35.16 v1(157.21,50.96)
  SIG3 w0.381: v1(157.21,50.96) 157.8,50.96 160.32,48.44 160.32,47.42 161.13,46.61 163.17,46.61 164,45.77 164,44.5 169.21,39.29 v4(169.59,39.29)
BPWM1_P2V5_VPP: length 26.8
  TOP w0.178: U36.33 61.88,25.34 61.51,25.71 v4(61.39,25.71)
  TOP w0.229: U38.16 v1(76.48,15.43)
  SIG2 w0.381: v4(61.39,25.71) 61.39,26.59 61.9,27.1 64.31,27.1 66.59,24.82 66.59,18.09 67.23,17.45 71.67,17.45 73.69,15.43 v1(76.48,15.43)
BPWM1_VCCSCSUS: length 23.3
  TOP w0.178: U29.33 122.97,25.42 v4(122.73,25.65)
  TOP w0.229: v1(133.78,15.16) 133.38,15.56 U32.16
  SIG3 w0.381: v4(122.73,25.65) 124.05,26.98 125.27,26.98 126.28,25.96 126.28,22.68 127.1,21.87 127.1,17.27 128.19,16.18 133.02,16.18 133.78,15.42 v1(133.78,15.16)
BROAD_12V_EN: length 208.5
  TOP w0.109: R190.2 R191.1 193.57,103.28 193.85,103.56 v1(194.86,103.56)
  SIG1 w0.086: v1(72.13,130.1) 71.93,130.1 70.79,131.24 70.79,133.78 69.59,134.98 69.59,135.64 70.79,136.83 70.79,142.16 71.04,142.42 v1(71.04,154.86)
  SIG3 w0.107: v1(194.86,103.56) 194.86,119.56 194.03,120.39 194.03,127.93 192.6,129.36 176.43,129.36 175.21,130.58 166.82,130.58 v1(166.29,131.12) 165.84,131.12 165.4,131.56 165.4,131.88 164.5,132.77 164.5,145.22 160.32,149.4 142.4,149.4 141.31,150.5 139.57,150.5 138.86,149.78 137.35,149.78 136.01,151.12 127.23,151.12 125.94,152.42 96.27,152.42 92.53,156.16 72.34,156.16 v1(71.04,154.86)
  BOTTOM w0.109: R82.2 70.56,130.33 70.79,130.1 v1(72.13,130.1) ; v1(166.29,131.12) 165.46,130.29 162.29,130.29 162.23,130.23 160.07,130.23 158.42,128.58 R541.2
BROAD_RST#: length 166.9
  TOP w0.109: v1(90.47,134.32) 90.06,134.73 U2.M16 ; v1(196.01,98.22) 195.63,97.84 R185.2 R181.1
  SIG1 w0.086: v1(120.06,138.61) 116,138.61 115.49,138.1 113.33,138.1 111.3,136.07 106.22,136.07 104.9,134.75 98.68,134.75 98.36,134.43 90.59,134.43 v1(90.47,134.32)
  SIG3 w0.107: v1(127.55,152.65) 128.37,151.84 141.12,151.84 142.76,150.21 163.96,150.21 166.54,147.63 166.54,141.53 167.94,140.13 182.04,140.13 185.47,136.7 187.63,136.7 196.01,128.32 v1(196.01,98.22)
  BOTTOM w0.109: v1(120.06,138.61) 119.93,138.74 119.93,139.75 120.44,140.26 120.44,147.75 122.22,149.53 124.43,149.53 v1(127.55,152.65)
BSKIP_P1V05_PCH: length 21.1
  TOP w0.178: v4(170.48,39.29) 170.23,39.04 U33.32
  TOP w0.381: R720.1 160.09,52.12 v1(160.32,52.35)
  SIG3 w0.381: v4(170.48,39.29) 170.48,40.06 171.12,40.69 171.12,44.37 163.14,52.35 v1(160.32,52.35)
BSKIP_P2V5_VPP: length 25.4
  TOP w0.178: v4(62.4,25.71) 62.28,25.58 U36.32
  TOP w0.381: R758.1 v1(77.9,12.62)
  SIG2 w0.381: v1(77.9,12.62) 76.88,13.64 73.83,13.64 71.17,16.31 66.72,16.31 65.45,17.58 65.45,22.02 62.4,25.07 v4(62.4,25.71)
BSKIP_VCCSCSUS: length 22.7
  TOP w0.178: U29.32 123.37,25.33 123.74,25.71 v4(123.87,25.71)
  TOP w0.229: R683.1 v1(135.43,12.62)
  SIG2 w0.381: v1(135.43,12.62) 134.92,13.13 134.92,15.42 133.9,16.43 130.09,16.43 129.33,17.2 127.81,17.2 126.92,18.09 126.92,22.15 123.87,25.2 v4(123.87,25.71)
CATERR_N: length 4.1
  BOTTOM w0.109: U49.12 111.86,133.35 112.7,132.51 112.7,132.26 112.95,132 R1050.2 R1039.1
CATERR_N_CPLD: length 38.7
  TOP w0.109: U2.J2 v1(74.71,137.23)
  SIG1 w0.086: v1(74.71,137.23) 75.2,137.72 75.99,137.72 76.79,138.51 87.2,138.51 88.38,139.69 101.58,139.69 102.74,138.53 103.32,138.53 v1(103.93,139.14)
  BOTTOM w0.109: v1(103.93,139.14) 103.55,138.76 103.55,137.08 103.68,136.96 103.68,134.04 104.37,133.35 U49.5
CATERR_N_GTL: length 133.6
  TOP w0.109: v2(100.02,67.77) 99.9,67.77 99.62,67.49 U43.Y67
  SIG3 w0.107: v2(100.02,67.77) 98.47,66.22 98.47,65.33 98.09,64.95 98.09,64.19 99.23,63.04 105.08,63.04 105.33,62.79 111.8,62.79 115.14,66.12 121.62,66.12 123.8,68.3 124.81,68.3 128.14,71.63 128.14,72.44 128.32,72.62 128.32,74.98 128.31,74.98 128.31,75.19 122.33,81.18 110.69,81.18 108.12,83.74 108.12,85.4 107.62,85.9 107.62,87.39 105.33,89.68 105.33,91.75 108.91,95.33 108.91,96.47 109.77,97.33 109.77,104.7 109.34,105.13 109.34,105.66 109.65,105.97 110.84,105.97 111.43,106.56 111.43,107.66 111.89,108.13 111.89,109.14 109.39,111.63 107.67,111.63 107.36,111.94 107.36,112.7 107.62,112.95 107.62,115.01 106.53,116.1 106.53,125.11 106.95,125.53 106.95,126.25 107.49,126.79 114.48,126.79 v1(115.11,126.16)
  SIG4 w0.086: v1(115.11,126.16) 114.47,126.8 114.47,131.5 v1(115.06,132.08)
  BOTTOM w0.109: v1(115.06,132.08) 114.98,132 R1050.1
CLK: length 55.1
  TOP w0.109: R768.2 101.65,134.8 101.39,135.05 v1(101.39,137.39) ; R147.2 R148.2 v1(121.08,117.02) ; v1(100.38,146.99) 100.38,146.1 100.76,145.72 R778.2
  SIG4 w0.086: v1(121.08,117.02) 121.57,117.51 121.57,120.2 121.2,120.57 120.19,120.57 116.86,123.9 112.63,123.9 112.06,124.46 110.21,124.46 109.47,125.2 105.15,125.2 104.31,126.04 104.31,127.69 104.69,128.07 104.69,134.09 v1(101.39,137.39) 101.82,137.82 101.82,147.7 101.67,147.85 101.11,147.85 100.38,147.12 v1(100.38,146.99)
CLK_32KL_PCH_RTCX1: length 16.9
  TOP w0.109: U43.AT2 92.25,97.35 92.25,98.1 91.94,98.4 91.94,99.82 92.12,100 92.12,101.02 96.69,105.59 R894.2 96.85,105.99 97.33,106.48 97.33,106.99 97.2,107.11 C588.1 96.8,107.47 97.41,108.08 97.41,109.57 97.28,109.7 Y1.4
CLK_32KL_PCH_RTCX2: length 19.2
  TOP w0.109: U43.AT4 92.34,96.77 92.69,97.13 92.69,97.65 92.52,97.83 92.52,98.14 92.2,98.46 92.2,99.57 92.53,99.9 92.53,100.69 96.82,104.98 97.86,104.98 98.32,105.44 R894.1 98.32,106.12 97.84,106.6 97.84,106.99 97.96,107.11 C587.1 98.5,107.47 97.91,108.05 97.91,109.52 98.09,109.7 Y1.1
CLK_33M: length 45
  TOP w0.109: v1(118.16,128.45) 118.5,128.1 U45.1
  SIG1 w0.086: v1(104.82,126.16) 105.58,126.92 106.47,126.92 107.62,128.07 113.08,128.07 113.28,128.27 116.43,128.27 116.63,128.07 117.27,128.07 117.57,128.37 118.08,128.37 v1(118.16,128.45)
  SIG3 w0.107: v1(101.67,102.62) 102.61,102.62 104.62,104.63 104.62,110.45 105.84,111.67 105.84,112.6 105.3,113.14 105.3,113.94 105.58,114.22 105.58,115.28 105.16,115.7 105.16,116.59 104.59,117.15 104.59,125.93 v1(104.82,126.16)
  BOTTOM w0.109: R938.2 100.99,101.93 v1(101.67,102.62)
CLK_33M_LOOPBACK: length 51.9
  TOP w0.109: v2(99.54,94.39) 99.26,94.67 98.82,94.67 U43.AC7 ; R940.2 117.01,125.53 116.53,126.01 116.53,127.14 v1(116.73,127.34)
  SIG1 w0.086: v1(106.5,125.81) 106.5,126.31 107.74,127.56 114.22,127.56 114.49,127.83 116.25,127.83 v1(116.73,127.34)
  SIG3 w0.107: v2(99.54,94.39) 99.49,94.44 99.49,95.94 100.2,96.65 100.2,99.37 100.31,99.48 100.31,101.33 100.88,101.91 102.54,101.91 105.06,104.43 105.06,106.87 105.99,107.79 105.99,111.2 106.42,111.63 106.42,113.26 106.19,113.48 106.19,115.29 105.61,115.88 105.61,116.76 105.08,117.3 105.08,124.36 106.5,125.78 v1(106.5,125.81)
CLKIN: length 8.2
  TOP w0.109: OSC2.3 141.26,132.15 v1(141.27,132.13) ; U20.W18 v2(141.89,125.83)
  BOTTOM w0.109: v2(141.89,125.83) 141.52,126.2 141.52,131.88 v1(141.27,132.13)
CLKOUT_PCIE_DN0: length 85.9
  TOP w0.099: v1(102.12,99.97) 101.77,99.97 101.55,99.75 101.55,98.86 101.53,98.84 101.53,98.28 101.35,98.11 101.35,97.71 101.65,97.42 101.65,97.16 101.51,97.02 101.35,97.02 101.25,97.12 U43.U2
  BOTTOM w0.099: v1(102.12,99.97) 101.78,99.97 101.6,100.15 101.6,100.58 101.9,100.89 116.63,100.89 117.52,100 128.21,100 134.05,94.16 149,94.16 149.78,94.94 149.78,95.56 152.32,98.1 157.38,98.1 160.7,101.42 160.7,110.31 162.99,112.59 162.99,113.72 163.74,114.47 164.11,114.47 164.24,114.35 U26.25
CLKOUT_PCIE_DN2: length 94.2
  TOP w0.099: v2(103.17,99.52) 103.17,99.17 103.05,99.05 102.42,99.05 102.2,98.82 102.2,98.64 102.1,98.55 102.1,98.27 102.2,98.18 102.2,98.01 101.95,97.76 101.82,97.76 101.74,97.84 U43.T1
  BOTTOM w0.099: v2(103.17,99.52) 103.48,99.22 103.79,99.22 104.69,100.13 115.6,100.13 119.53,96.19 126.64,96.19 131.29,91.54 177.19,91.54 180.09,94.45 186.3,94.45 186.31,94.44 186.45,94.44 186.46,94.45 186.51,94.45 186.53,94.43 188.46,94.43 188.56,94.53 U4.B25
CLKOUT_PCIE_DN3: length 107.1
  TOP w0.099: v2(102.03,94.67) 101.74,94.96 U43.T7
  SIG1 w0.094: v1(198.02,91.1) 198.02,91.27 197.96,91.33 197.59,91.33 197.32,91.6 197.32,92.67 197.11,92.89 196.58,92.89 196.56,92.87 194.31,92.87 193.7,92.25 182.8,92.25 176.2,85.65 135.79,85.65 134.77,84.63 128.21,84.63 125.29,87.55 124.15,87.55 117.54,94.16 107.59,94.16 106.98,93.55 106.24,93.55 105.99,93.8 105.8,93.8 105.78,93.82 104,93.82 103.62,94.2 102.49,94.2 v2(102.03,94.67)
  BOTTOM w0.099: U60.C40 198.65,91.73 v1(198.02,91.1)
CLKOUT_PCIE_DN4: length 104.6
  TOP w0.099: v2(102.51,93.8) 102.29,93.8 U43.R9
  SIG1 w0.094: v2(102.51,93.8) 102.83,93.8 103.09,93.54 103.09,93.4 103.3,93.19 103.73,93.19 103.85,93.31 104.48,93.31 105.03,92.76 105.68,92.76 105.7,92.74 107.47,92.74 107.87,93.14 117.16,93.14 123.64,86.67 124.76,86.67 127.55,83.87 135.3,83.87 136.19,84.76 177.7,84.76 178.21,85.27 189.51,85.27 191.31,87.07 191.31,88.95 193.62,91.26 196.59,91.26 v1(196.75,91.1)
  BOTTOM w0.099: U60.D40 197.38,91.73 v1(196.75,91.1)
CLKOUT_PCIE_DP0: length 85.9
  TOP w0.099: v1(101.21,99.97) 101.3,99.88 101.3,98.86 101.32,98.84 101.32,98.37 101.14,98.2 101.14,97.72 100.89,97.47 100.89,97.12 101.25,96.77 U43.U4
  BOTTOM w0.099: U26.26 164.24,114.85 164.11,114.72 163.64,114.72 162.73,113.82 162.73,112.7 160.45,110.41 160.45,101.52 157.27,98.35 152.21,98.35 149.53,95.66 149.53,95.05 148.89,94.41 134.16,94.41 128.32,100.25 117.63,100.25 116.74,101.14 101.8,101.14 101.34,100.69 101.34,100.1 v1(101.21,99.97)
CLKOUT_PCIE_DP2: length 94.3
  TOP w0.099: v2(103.17,98.66) 103,98.83 102.51,98.83 102.41,98.73 102.41,97.92 101.89,97.4 101.89,96.92 U43.T3
  BOTTOM w0.099: v2(103.17,98.66) 103.48,98.96 103.89,98.96 104.8,99.87 115.49,99.87 119.43,95.94 126.54,95.94 131.19,91.29 177.29,91.29 180.2,94.2 186.51,94.2 186.53,94.22 188.47,94.22 188.56,94.12 U4.B24
CLKOUT_PCIE_DP3: length 107.1
  TOP w0.099: v2(102.97,94.67) 102.78,94.67 U43.P7
  SIG1 w0.094: v2(102.97,94.67) 102.97,94.49 103.04,94.41 103.7,94.41 104.09,94.03 105.78,94.03 105.8,94.05 106.09,94.05 106.35,93.8 106.88,93.8 107.49,94.41 107.83,94.41 107.98,94.57 108.26,94.57 108.42,94.41 108.77,94.41 108.89,94.54 109.17,94.54 109.3,94.41 109.58,94.41 109.71,94.54 109.99,94.54 110.12,94.41 110.46,94.41 110.59,94.54 110.87,94.54 111,94.41 117.65,94.41 124.25,87.81 125.4,87.81 128.32,84.89 134.67,84.89 135.68,85.9 176.09,85.9 182.69,92.51 193.59,92.51 194.21,93.12 196.56,93.12 196.58,93.1 197.2,93.1 197.53,92.76 197.53,91.69 197.68,91.54 197.87,91.54 198.02,91.69 v1(198.02,92.37)
  BOTTOM w0.099: v1(198.02,92.37) 198.65,93 U60.C39
CLKOUT_PCIE_DP4: length 104.6
  TOP w0.099: U43.N9 103.26,93.83 v2(103.48,93.83)
  SIG1 w0.094: v1(196.75,92.37) 196.75,91.72 196.54,91.52 193.51,91.52 191.05,89.06 191.05,87.17 189.4,85.52 178.1,85.52 177.59,85.01 136.09,85.01 135.2,84.13 127.66,84.13 124.87,86.92 123.74,86.92 117.27,93.4 107.77,93.4 107.36,92.99 105.68,92.99 105.66,92.97 105.11,92.97 104.57,93.52 103.77,93.52 103.65,93.4 103.39,93.4 103.3,93.49 103.3,93.73 103.4,93.83 v2(103.48,93.83)
  BOTTOM w0.099: U60.D39 197.38,93 v1(196.75,92.37)
CON_33M_CLK: length 90.1
  TOP w0.109: R942.2 129.69,125.93 130.22,125.4 v1(130.48,125.4) ; v1(173.02,80.82) 173.15,80.95 R174.1
  SIG3 w0.107: v1(173.02,80.82) 172.89,80.82 168.83,84.89 152.32,84.89 147.09,90.12 141.75,90.12 139.44,92.43 137.05,92.43 132.25,97.23 132.25,106.6 132.91,107.26 132.91,108.74 132.25,109.4 132.25,111.3 131.87,111.68 131.87,124.38 130.86,125.4 v1(130.48,125.4)
CPLD_25M_CLK: length 13.4
  TOP w0.109: v1(71.67,142.04) 71.55,141.91 X37.1 69.64,142.93 R1185.2 ; U2.J5 v1(77.71,137.23)
  SIG4 w0.086: v1(77.71,137.23) 77.71,139.18 76.12,140.77 72.94,140.77 v1(71.67,142.04)
CPLD_APWROK: length 49.2
  TOP w0.109: U43.BE13 88.19,92.38 88.57,92.76 88.97,92.76 v2(89.12,92.91) ; U2.P12 v1(85.71,132.23)
  SIG4 w0.086: v1(86.53,123.65) 86.53,121.59 89.33,118.8 90.09,118.8 90.57,118.31 v1(90.6,118.31)
  BOTTOM w0.109: v2(89.12,92.91) 88.71,92.91 88.03,93.59 88.03,94.16 87.75,94.44 87.75,94.8 88.06,95.11 88.06,95.94 88.95,96.83 88.95,101.65 93.26,105.97 93.26,112.95 92.63,113.59 92.63,114.31 92.38,114.57 91.62,114.57 91.45,114.74 91.45,117.47 v1(90.6,118.31) ; v1(86.53,123.65) 86.53,123.8 86.74,124 86.74,125.2 85.8,126.14 R77.1 85.39,127.79 85.24,127.94 85.24,131.72 85.71,132.19 v1(85.71,132.23)
CPLD_CLK: length 82.8
  TOP w0.109: v1(95.44,142.28) 95.43,142.29 R1186.2 94.76,141.94 95.04,141.66 95.04,141.28 94.76,140.99 R1188.2
  SIG1 w0.086: v1(95.44,142.28) 95.88,141.84 97.5,141.84 98.45,142.8 107.8,142.8 109.27,141.33 117.85,141.33 118.03,141.15 120.82,141.15 121.59,140.39 127.05,140.39 128.06,139.37 136.03,139.37 136.75,138.65 136.75,134.76 136.06,134.07 136.06,126.92 140.25,122.73 140.25,122.4 140.69,121.97 140.69,120.02 140.89,119.81 155.07,119.81 v2(155.49,120.23)
  BOTTOM w0.109: v2(155.49,120.23) 155.4,120.14 R1202.2
CPLD_CLK_50M: length 99.6
  TOP w0.109: U2.H12 85.71,139.23 v1(85.71,141.23)
  SIG1 w0.086: v1(85.71,141.23) 86.17,140.77 87.42,140.77 87.68,141.02 94.66,141.02 95.05,141.4 97.33,141.4 97.58,141.15 98.55,141.15 98.85,141.46 108.52,141.46 109.09,140.89 117.39,140.89 119.22,139.07 121.26,139.07 122.42,137.9 126.74,137.9 128.32,136.32 129.33,136.32 132.3,133.35 132.3,127.25 132.63,126.92 133.02,126.92 138.98,120.96 138.98,118.92 142.87,115.04 146.94,115.04 147.37,114.61 147.37,113.97 149.91,111.43 v1(152.29,111.43)
  BOTTOM w0.109: v1(152.29,111.43) 153.08,110.64 153.08,107.37 153.72,106.73 153.72,103.43 155.24,101.91 R58.2
CPLD_CSN0: length 44.9
  TOP w0.109: U2.M2 v1(74.71,134.23)
  SIG3 w0.107: v1(108.38,135.59) 107.72,134.93 99.05,134.93 98.87,135.11 92.7,135.11 92.02,135.79 86.37,135.79 84.61,134.04 81.45,134.04 81.1,133.68 75.46,133.68 74.91,134.23 v1(74.71,134.23)
  BOTTOM w0.109: v1(108.38,135.59) 109.01,134.95 109.01,130.99 111.3,128.7 R151.1
CPLD_CSN1: length 45
  TOP w0.109: v1(77.71,134.23) 76.71,134.23 U2.M3 ; v1(117.27,140.39) 116.79,140.87 R152.1
  SIG1 w0.086: v1(77.71,134.23) 78.23,134.75 88.13,134.75 89.07,135.69 97.83,135.69 99.07,136.92 104.65,136.92 105.88,138.15 107.21,138.15 109.44,140.39 v1(117.27,140.39)
CPLD_DATA: length 84.9
  TOP w0.109: v1(96.31,142.28) 96.31,144.58 95.42,145.47 R1189.2 R1187.2
  SIG1 w0.086: v1(96.31,142.28) 97.25,143.22 108.11,143.22 109.56,141.77 118.08,141.77 118.23,141.62 121.02,141.62 121.78,140.86 127.24,140.86 128.26,139.84 136.23,139.84 137.21,138.86 137.21,134.54 136.57,133.91 136.57,127.05 140.72,122.9 140.72,122.48 140.98,122.23 141.27,122.23 141.5,122 141.5,120.85 141.72,120.63 154.15,120.63 155.49,121.97 v2(155.49,122.63)
  BOTTOM w0.109: v2(155.49,122.63) 155.4,122.54 R1203.2
CPLD_ERR0_N: length 28.2
  TOP w0.109: R120.1 57.93,147.65 57.77,147.81 57.77,149.34 v1(58.09,149.66) ; v1(76.71,142.23) U2.D4
  SIG3 w0.107: v1(58.09,149.66) 59.99,149.66 61.03,148.62 69.87,148.62 72.63,145.85 72.63,142.46 73.44,141.66 76.14,141.66 v1(76.71,142.23)
CPLD_ERR1_N: length 12
  TOP w0.109: R123.1 70.25,147.52 v1(71.55,146.23) ; U2.D5 v1(77.71,143.23)
  BOTTOM w0.109: v1(71.55,146.23) 72.82,144.96 72.82,143.31 73.45,142.67 77.15,142.67 v1(77.71,143.23)
CPLD_ERR2_N: length 17.7
  TOP w0.109: U2.E1 v1(73.71,142.23) ; v1(62.91,149.07) 62.61,149.07 62.28,149.4 R126.1
  SIG3 w0.107: v1(73.71,142.23) 73.2,142.74 73.2,145.7 69.12,149.78 63.62,149.78 v1(62.91,149.07)
CPLD_M2_DEVSLP: length 139.1
  TOP w0.109: J3.38 v1(174.28,95.67) ; R112.2 v1(81.71,152.07)
  SIG3 w0.107: v1(174.28,95.67) 171.12,95.67 168.96,97.84 150.98,97.84 149.39,99.44 149.39,103.69 146.78,106.3 140.71,106.3 139.26,107.75 139.26,108.99 137.84,110.41 137.84,111.13 136.9,112.07 136.9,112.42 137.59,113.11 137.59,115.62 138.12,116.15 138.12,127.41 137.84,127.69 137.84,129.21 138.55,129.92 138.55,132.92 137.21,134.26 137.21,136.45 136.57,137.08 135.65,137.08 131.37,141.37 131.37,143.3 124.63,150.04 92.63,150.04 90.72,151.94 83.99,151.94 83.61,151.56 82.22,151.56 v1(81.71,152.07)
CPLD_MOLEX_UART_RXD0: length 202.2
  SIG3 w0.107: v1(191.74,63.84) 191.2,63.3 187.19,63.3 184.43,66.07 184.43,66.37 182.8,68 182.8,71.93 182.5,72.24 182.5,75.95 177.34,81.1 177.34,82.86 169.21,90.98 159.3,90.98 156.89,93.4 156,93.4 155.49,93.9 152.19,93.9 151.56,94.54 141.66,94.54 139.68,96.52 138.53,96.52 137.39,97.66 137.39,101.83 137.56,102.01 137.56,104.1 136.64,105.02 136.64,111.54 136.34,111.84 136.34,112.63 136.65,112.94 136.65,115.32 137.84,116.5 137.84,127.3 137.56,127.58 137.56,129.55 138.24,130.23 138.24,132.75 136.83,134.16 136.83,136.32 136.5,136.65 135.61,136.65 130.98,141.28 130.98,143.18 124.51,149.66 80.31,149.66 79.8,149.15 72.31,149.15 v1(71.67,149.78)
  BOTTOM w0.109: v1(71.67,149.78) 70.91,149.02 70.91,143.18 70.15,142.42 70.15,138.35 70.4,138.1 R68.2 R79.2 ; U4.D1 v1(191.74,63.84)
CPLD_MOLEX_UART_TXD0: length 246.4
  SIG3 w0.107: v1(117.67,131.12) 106.07,131.12 104.51,129.56 100.25,129.56 99.58,128.9 98.26,128.9 98.04,128.68 96.61,128.68 95.95,128.02 82.98,128.02 81.54,129.46 78.41,129.46 77.8,128.85 76.35,128.85 74.47,130.73 73.45,130.73 71.85,132.33 v1(71.67,132.33) ; v1(194.74,64.44) 194.74,79.3 199.09,83.65 199.09,94.5 198.8,94.79 198.8,133.27 199.44,133.91 199.44,140.64 198.87,141.21 196.71,141.21 196.01,141.91 196.01,142.55 194.74,143.82 186.61,143.82 185.85,143.05 176.83,143.05 175.94,143.94 167.27,143.94 167.18,144.04 167.18,147.63 164.15,150.66 143.06,150.66 141.43,152.29 130.26,152.29 129.33,153.21 126.92,153.21 v1(126.41,152.71)
  BOTTOM w0.109: v1(117.67,131.12) 117.9,131.34 117.9,131.88 118.49,132.46 118.49,132.9 117.71,133.67 117.71,138.42 117.9,138.61 117.9,146.48 121.46,150.04 123.74,150.04 v1(126.41,152.71) ; v1(194.74,64.44) 193.85,64.44 192.71,63.3 190.17,63.3 188.99,64.47 U4.B1 ; v1(71.67,132.33) 70.96,132.33 70.68,132.61 R69.2 R80.2
CPLD_NMI_N: length 49.9
  TOP w0.109: U43.BP1 83.92,98.28 84.04,98.4 84.04,103.73 84.5,104.19 v1(84.5,104.45) R864.2 ; U2.J3 v1(75.71,137.23)
  SIG2 w0.107: v1(75.71,137.23) 75.23,136.75 75.23,134.93 75.08,134.77 73.55,134.77 73.25,134.47 73.25,133.11 72.79,132.65 72.79,130.38 73.4,129.77 73.91,129.77 74.52,129.16 74.52,128.5 74.37,128.35 74.37,125.88 77.14,123.11 79.29,123.11 80.06,122.35 80.69,122.35 81.83,121.21 81.83,115.49 82.02,115.31 82.02,113.79 83.1,112.7 83.1,111.56 83.03,111.48 83.03,109.53 83.99,108.56 83.99,106.35 84.5,105.84 v1(84.5,104.45)
CPLD_PCH_PWROK: length 60.4
  TOP w0.109: U43.AN1 93.77,98.05 93.77,99.16 v2(93.7,99.24) ; U2.N2 v1(74.71,133.23)
  SIG1 w0.086: v1(74.71,133.23) 74.21,132.73 74.21,129.59 74.53,129.27 74.53,127.11 79.24,122.41 90.91,122.41 91.92,123.42 92.83,123.42 v1(92.99,123.57)
  SIG3 w0.107: v1(92.99,123.57) 92.99,123.47 92.35,122.83 92.35,117.04 92.61,116.78 92.61,114.79 92.88,114.52 93.4,114.52 93.64,114.28 93.64,112.81 93.31,112.47 93.31,111.21 93.48,111.04 93.48,108.41 94.45,107.44 94.45,104.61 93.7,103.86 v2(93.7,99.24)
  BOTTOM w0.109: R75.1 71.93,131.62 72.18,131.88 72.18,132.56 73.35,133.73 74.2,133.73 v1(74.71,133.23)
CPLD_PLTRST_N: length 50.3
  TOP w0.109: v2(87.65,86.92) 87.82,86.92 U43.BE24 ; U2.R11 v1(84.71,131.23)
  SIG3 w0.107: v1(87.98,123.57) 87.98,123.39 87.63,123.04 87.63,116.1 88.11,115.62 88.11,113.74 88.47,113.38 88.47,110.9 88.02,110.45 88.02,109.11 87.48,108.56 87.48,107.38 87.09,106.99 87.09,106.18 87.78,105.49 87.78,103.15 87.21,102.58 87.21,95.98 86.91,95.68 86.91,95.15 86.66,94.89 86.66,94.41 87.05,94.02 87.05,93.53 86.73,93.21 86.73,92.78 86.74,92.77 86.74,92.76 87.04,92.46 87.04,92.13 87.55,91.62 87.55,90.98 87.24,90.67 87.24,90.25 87.54,89.95 87.54,89.32 87.26,89.05 87.26,88.22 87.51,87.97 87.51,87.05 v2(87.65,86.92)
  SIG4 w0.086: v1(87.98,123.57) 88.18,123.77 88.18,128.12 85.08,131.23 v1(84.71,131.23)
CPLD_RSMRST_N: length 59.5
  TOP w0.089: 90.93,98.55 90.56,98.19 90.56,97.83 90.97,97.42 90.97,97.15 91.35,96.77 U43.AV4
  TOP w0.109: U2.N3 75.71,134.23 v1(75.71,134.23) ; U43.AR7 92.33,95.21 92.33,95.78 91.92,96.19 91.43,96.19 U43.AV4 ; v2(91.11,99.62) 91.11,99.11 90.93,98.93 90.93,98.55
  SIG2 w0.107: v1(75.71,134.23) 75.26,133.78 74.41,133.78 74.25,133.62 74.25,132.95 74.06,132.77 73.53,132.77 73.33,132.57 73.25,132.49 73.25,130.85 73.37,130.73 73.83,130.73 76.25,128.32 77.26,128.32 78.36,127.23 78.36,125.96 79.8,124.51 79.8,124 80.12,123.69 80.12,123.3 80.56,122.86 80.82,122.86 82.34,121.34 82.34,115.88 82.98,115.24 82.98,113.46 84.12,112.32 84.12,111.43 83.99,111.3 83.99,109.53 84.95,108.57 84.95,105.53 90.85,99.62 v2(91.11,99.62)
  BOTTOM w0.109: v1(75.71,134.23) 75.23,133.75 75.23,132.97 74.98,132.72 73.53,132.72 73.1,132.28 73.1,130.68 72.69,130.27 72.69,129.97 72.31,129.59 R76.1
CPLD_SLP_A_N: length 54.6
  TOP w0.109: U2.H3 75.71,138.23 v1(75.71,138.23) ; U43.BB7 89.24,95.33 v2(89.24,95.37)
  SIG3 w0.107: v1(89.58,118.34) 89.96,117.96 89.96,116.64 90.22,116.38 90.22,115.49 90.09,115.37 90.09,112.57 90.17,112.5 90.17,111.48 90.68,110.97 90.68,110.41 90.93,110.15 90.93,107.74 91.03,107.64 91.03,105.39 90.47,104.83 90.47,102.46 89.76,101.75 89.76,98.02 89.24,97.5 v2(89.24,95.37)
  SIG4 w0.086: v1(89.58,118.34) 89.3,118.34 85.83,121.82 85.83,129.28 85.01,130.1 84.37,130.1 83.99,129.72 83.49,129.72 81.96,131.24 81.96,132.13 81.33,132.77 79.17,132.77 78.15,133.78 78.15,134.42 77.9,134.67 77.26,134.67 76.25,135.69 76.25,137.69 v1(75.71,138.23)
CPLD_SLP_S3_N: length 50.1
  TOP w0.089: U43.AY2 90.15,97.47 90.15,98.41 90.47,98.73
  TOP w0.109: 90.47,98.73 90.47,101.53 93.47,104.52 93.47,107.23 92.82,107.88 92.82,110.33 93.22,110.74 93.22,113.42 93.65,113.84 93.65,114.43 94.08,114.86 94.08,116.81 95.68,118.42 R893.1 95.4,119.08 95.12,119.35 95.12,120.35 96.06,121.29 96.06,123.88 v1(95.75,124.18) ; U2.R10 v1(83.71,131.23)
  SIG4 w0.086: v1(83.71,131.23) 84.25,131.77 84.25,132.64 84.37,132.77 90.09,132.77 92.25,130.61 92.25,127.43 95.5,124.18 v1(95.75,124.18)
CPLD_SLP_S4_N: length 42.4
  TOP w0.109: U2.R1 v1(73.71,131.23) ; v2(91.23,100.38) 91.49,100.13 91.49,98.98 91.16,98.65 91.16,98.3 U43.AW1
  SIG2 w0.107: v2(91.23,100.38) 91.23,100.76 85.98,106.02 85.98,106.89 85.38,107.48 85.38,109.27 85.06,109.59 85.06,110.62 84.76,110.92 84.76,112.32 83.94,113.13 83.94,115.42 82.98,116.38 82.98,122.1 81.05,124.03 81.05,125.3 77.52,128.83 76.37,128.83 73.98,131.23 v1(73.71,131.23)
CPLD_SLP_SUS_N: length 46.9
  TOP w0.109: U43.AY7 90.9,94.67 v2(91.11,94.67) ; U2.P9 v1(82.71,132.23)
  SIG3 w0.107: v2(91.11,94.67) 91.34,94.67 91.8,95.12 91.8,96.63 93.06,97.89 93.06,99.49 92.63,99.92 92.63,103.58 93.91,104.85 93.91,107.22 92.92,108.2 92.92,110.79 92.76,110.94 92.76,111.98 92.48,112.27 92.17,112.27 91.87,112.57 91.87,113.08 92.6,113.82 92.6,114.25 92.34,114.52 92.34,115.66 91.87,116.13 v1(91.87,118.03)
  SIG4 w0.086: v1(91.87,118.03) 91.87,119.05 87.52,123.39 87.52,124.1 87.68,124.26 87.68,127.99 84.93,130.73 83.49,130.73 83.23,130.99 83.23,131.7 v1(82.71,132.23)
CPLD_SMI_N: length 50
  TOP w0.109: v1(73.71,136.23) U2.K1 ; U43.BR4 83.43,96.77 83.08,97.12 83.08,97.66 83.24,97.82 83.24,98.35 83.49,98.6 83.49,104.19 83.54,104.24 v1(83.54,104.45) 83.49,104.5 R865.2
  SIG2 w0.107: v1(73.71,136.23) 73.25,135.77 73.25,134.9 72.97,134.62 72.97,133.22 72.44,132.69 72.44,132.26 71.55,131.37 71.55,129.97 72.06,129.46 73.33,129.46 73.58,129.21 73.58,128.45 74.08,127.95 74.08,125.77 77.11,122.73 79.17,122.73 79.93,121.97 80.44,121.97 81.33,121.08 81.33,117.4 81.07,117.15 81.07,113.46 81.96,112.57 81.96,109.53 82.98,108.51 82.98,106.35 83.54,105.79 v1(83.54,104.45)
CPLD_SYS_PWROK: length 44.8
  TOP w0.109: U2.P10 v1(83.71,132.23) ; v2(83.44,95.56) 83.7,95.56 U43.BP5
  SIG3 w0.107: v1(79.68,123.42) 79.68,123.24 80.28,122.64 80.86,122.64 82.6,120.9 82.6,116.26 82.98,115.88 82.98,112.89 82.16,112.07 82.16,110.36 81.91,110.11 81.91,108.69 80.97,107.75 80.97,106.68 82.55,105.11 82.55,103.94 83.1,103.38 83.1,99.37 83.44,99.03 v2(83.44,95.56)
  BOTTOM w0.109: v1(83.71,132.23) 84.25,131.69 84.25,128.96 83.36,128.07 R70.2 81.43,126.14 79.8,124.51 79.8,123.55 v1(79.68,123.42)
CPU_ERROR0_N: length 4
  TOP w0.109: R1054.1 R1059.2 122.37,102.95 121.15,101.72 U51.13
CPU_ERROR0_N_CPLD: length 70.4
  TOP w0.109: U2.R4 v1(76.71,131.23) ; v1(116.76,111.43) 116.76,110.67 116.38,110.29 116.38,109.86 116.76,109.48 116.76,103.43 115.05,101.72 U51.4 ; v1(112.19,122.66) 111.88,122.66 111.55,122.99 111.43,122.99 110.78,123.63 108.39,123.63 108.12,123.36 105.13,123.36 103.07,125.43 103.07,127.36 102.56,127.86 100.63,127.86 v1(98.8,129.69)
  SIG3 w0.107: v1(98.8,129.69) 98.63,129.86 96.08,129.86 95.73,129.52 94.35,129.52 93.9,129.97 92.62,129.97 92.05,129.4 85.3,129.4 84.93,129.03 83.41,129.03 81.96,130.49 77.45,130.49 v1(76.71,131.23)
  SIG4 w0.086: v1(112.19,122.66) 112.19,120.32 110.66,118.8 110.66,114.1 113.51,111.25 116.58,111.25 v1(116.76,111.43)
CPU_ERROR0_N_GTL: length 93.4
  TOP w0.089: v2(98.6,59.79) 98.19,60.2 98.19,61.52 98.28,61.6 U43.AC77
  TOP w0.109: R1059.1 123.74,103.05 123.87,103.18 125.07,103.18 125.27,102.97 129.79,102.97 129.98,103.16 130.43,103.16 130.63,102.96 130.63,96.99 139.11,88.51 139.11,84.05 132.83,77.76 132.83,76.38 132.7,76.25 132.7,67.93 132.38,67.62 v1(132.38,62.79)
  SIG3 w0.107: v1(122.22,62.28) 117.22,62.28 116.76,61.82 114.14,61.82 111.54,59.22 108.75,59.22 107.9,58.37 100.02,58.37 v2(98.6,59.79)
  SIG4 w0.086: v1(132.38,62.79) 132.23,62.94 127.38,62.94 126.83,62.39 122.33,62.39 v1(122.22,62.28)
CPU_ERROR1_N: length 3.4
  TOP w0.109: U51.12 120.95,101.07 121.01,101.02 R1058.1 R1060.2
CPU_ERROR1_N_CPLD: length 72.3
  TOP w0.109: v1(119.05,112.57) 118.79,112.32 118.79,111.81 118.06,111.08 117.68,111.08 116.76,110.16 116.76,109.92 117.14,109.54 117.14,103.3 114.91,101.07 U51.5 ; v1(99.73,130.17) 99.73,129.23 100.76,128.2 102.72,128.2 103.39,127.52 103.39,125.56 104.55,124.4 107.14,124.4 107.6,123.95 109.53,123.95 109.59,124 111.87,124 112.44,123.43 115.68,123.43 v1(116.63,122.48) ; U2.R5 v1(77.71,131.23)
  SIG3 w0.107: v1(77.71,131.23) 78.16,130.77 82.07,130.77 83.35,129.48 84.08,129.48 84.52,129.93 85.87,129.93 86.12,129.68 91.94,129.68 92.68,130.42 96.5,130.42 96.78,130.14 99.69,130.14 v1(99.73,130.17)
  SIG4 w0.086: v1(119.05,112.57) 120.01,113.54 120.01,118.72 116.63,122.1 v1(116.63,122.48)
CPU_ERROR1_N_GTL: length 84.2
  TOP w0.089: U43.AC75 98.28,63.1 98.63,62.75 98.63,62.33 98.48,62.19 98.48,61.51 98.4,61.43 98.4,60.68 v2(98.6,60.48)
  TOP w0.109: R1060.1 124.13,102.03 124.58,101.57 124.58,98.01 124.71,97.88 124.71,97.08 124.58,96.95 124.58,95.86 124.89,95.56 128.06,95.56 134.16,89.46 134.16,88.16 136.13,86.19 136.13,84.78 129.84,78.49 v1(129.84,76.76)
  SIG3 w0.107: v2(98.6,60.48) 98.93,60.48 99.41,60 104.57,60 105.93,58.63 107.77,58.63 110.41,61.27 112.95,61.27 113.89,62.2 116.68,62.2 117.27,62.79 121.94,62.79 125.37,66.22 126.54,66.22 128.95,68.63 128.95,69.39 129.51,69.95 129.91,69.95 130.93,70.98 130.93,76.05 130.65,76.33 130.27,76.33 v1(129.84,76.76)
CPU_ERROR2_N: length 3.9
  TOP w0.109: R1061.2 R1055.1 121.59,100 121.16,100.42 U51.11
CPU_ERROR2_N_CPLD: length 74
  TOP w0.109: U51.6 114.77,100.42 117.9,103.56 117.9,110.46 119.99,112.55 119.99,120.73 116.97,123.74 112.57,123.74 111.73,124.59 109.72,124.59 109.4,124.26 107.74,124.26 107.28,124.72 104.69,124.72 103.71,125.7 103.71,127.65 102.81,128.55 100.86,128.55 100.17,129.24 100.17,130.99 v1(100.05,131.12) ; U2.R6 v1(78.71,131.23)
  SIG3 w0.107: v1(100.05,131.12) 99.23,131.12 98.53,130.41 97.02,130.41 96.7,130.73 92.6,130.73 91.83,129.97 86.22,129.97 85.98,130.22 84.42,130.22 83.97,129.77 83.46,129.77 81.48,131.75 79.23,131.75 v1(78.71,131.23)
CPU_ERROR2_N_GTL: length 78.5
  TOP w0.089: v2(99.01,61.19) 99.06,61.25 99.06,62.25 98.85,62.46 98.85,63.02 98.77,63.1 U43.AB76
  TOP w0.109: R1061.1 123.87,98.73 124.25,98.35 124.25,97.89 124.38,97.76 124.38,97.26 124.25,97.13 124.25,95.72 124.75,95.22 127.93,95.22 133.85,89.31 133.85,88.03 135.8,86.07 135.8,84.92 128.99,78.1 128.99,76.78 v1(129.02,76.76)
  SIG3 w0.107: v2(99.01,61.19) 99.82,60.38 104.57,60.38 106.06,58.89 107.68,58.89 110.41,61.62 112.8,61.62 114.47,63.3 116.51,63.3 117.65,64.44 123.19,64.44 125.35,66.6 126.43,66.6 127.43,67.6 127.43,68.78 129.81,71.17 130.08,71.17 130.48,71.57 130.48,74.59 129.81,75.26 129.81,75.97 v1(129.02,76.76)
CPU_MEMHOT: length 3.6
  BOTTOM w0.109: U49.10 111.53,134.65 111.81,134.93 112.95,134.93 113.08,135.05 R1049.2 R1037.1
CPU_MEMHOT_CPLD: length 31.4
  TOP w0.109: U2.R8 v1(80.71,131.23)
  SIG1 w0.086: v1(80.71,131.23) 82.25,132.77 89.58,132.77 89.99,133.17 91.64,133.17 92.46,134 99.11,134 99.32,133.78 100,133.78 100.45,134.24 105.91,134.24 v1(107.11,135.43)
  BOTTOM w0.109: U49.7 106.32,134.65 v1(107.11,135.43)
CPU_MEMHOT_GTL: length 94.1
  TOP w0.109: v2(80.69,72.06) 80.12,72.64 U43.CC56
  SIG1 w0.086: v1(100.43,123.83) 101.44,124.84 105.41,124.84 105.58,125.02 107.36,125.02 109.01,126.67 115.87,126.67 v1(116,126.8)
  SIG3 w0.107: v2(80.69,72.06) 80.85,72.22 80.85,72.76 81.17,73.08 83.9,73.08 83.99,73.17 83.99,80.44 87.5,83.95 88.33,83.95 88.55,84.17 88.55,84.9 88.26,85.19 88.26,87.1 88.47,87.31 88.47,87.74 88.69,87.96 89.23,87.96 91.33,90.07 92.48,90.07 92.63,90.22 92.63,92.25 92.88,92.51 93.26,92.51 93.42,92.66 93.42,93.24 93.14,93.52 93.14,94.41 94.92,96.19 94.92,100 95.68,100.76 95.68,103.94 98.85,107.1 99.98,107.1 100.54,107.67 100.54,116.67 99.11,118.11 99.11,122.5 v1(100.43,123.83)
  SIG4 w0.086: v1(114.98,135.05) 115.74,135.05 116.89,133.91 116.89,131.62 116.02,130.76 116.02,126.82 v1(116,126.8)
  BOTTOM w0.109: R1049.1 v1(114.98,135.05)
CPU_PROCHOT: length 3.6
  TOP w0.109: R1063.1 R1071.2 121.2,106.1 120.8,106.5 U50.10
CPU_PROCHOT_CPLD: length 55.6
  TOP w0.109: U2.T10 v1(83.71,130.23) ; v1(98.55,131.12) 98.34,130.91 98.34,129.46 98.73,129.08 98.97,129.08 100.87,127.18 101.27,127.18 102.66,125.78 102.66,125.37 104.99,123.05 108.25,123.05 108.52,123.32 110.59,123.32 111.68,122.23 111.68,120.32 110.28,118.92 110.28,114.55 113.66,111.18 114.92,111.18 115.42,110.67 115.42,110.37 116.38,109.41 116.38,108.26 114.63,106.5 U50.7
  SIG3 w0.107: v1(83.71,130.23) 83.95,130.23 84.22,130.5 90.9,130.5 91.4,131 96.94,131 97.26,130.68 98.11,130.68 v1(98.55,131.12)
CPU_PROCHOT_GTL: length 100.1
  TOP w0.109: U43.AG71 96.34,65.77 v2(96.05,66.05) ; v1(135.58,78.41) 135.58,80.03 139.43,83.88 139.43,88.64 130.94,97.13 130.94,103.19 130.65,103.48 129.84,103.48 129.66,103.3 125.38,103.3 125.2,103.49 124.89,103.49 124.58,103.79 124.58,105.51 124,106.1 R1071.1
  SIG3 w0.107: v2(96.05,66.05) 96.06,66.05 96.06,64.95 95.87,64.76 95.87,60.06 96.57,59.36 96.57,58.93 98.8,56.69 115.67,56.69 119.4,60.43 123.12,60.43 134.92,72.22 134.92,77.16 135.58,77.82 v1(135.58,78.41)
CPU_PWR_DEBUG_N: length 3.4
  TOP w0.109: v2(101.52,61.32) 101.27,61.56 101.27,62.58 U43.U77
  BOTTOM w0.109: v2(101.52,61.32) C614.1 102.66,60.47 R1029.2
CPU_THROTTLE: length 4.3
  TOP w0.109: R1062.2 R1056.1 122.25,97.99 120.47,99.77 U51.10
CPU_THROTTLE_CPLD: length 75.8
  TOP w0.109: U2.R7 80.71,132.23 v1(80.71,132.24) ; v1(99.49,134.29) 99.61,134.16 99.61,133.32 100.16,132.78 100.16,132.03 100.49,131.7 100.49,129.37 100.99,128.88 102.93,128.88 104.02,127.78 104.02,125.84 104.83,125.03 107.7,125.03 108.03,125.36 109.18,125.36 109.63,124.91 116.36,124.91 120.32,120.96 120.32,112.32 118.28,110.29 118.28,103.3 114.75,99.77 U51.7
  SIG3 w0.107: v1(80.71,132.24) 80.71,132.67 81.72,133.68 84.65,133.68 86.47,135.5 91.81,135.5 92.48,134.84 98.75,134.84 99.3,134.29 v1(99.49,134.29)
CPU_THROTTLE_GTL: length 95.3
  TOP w0.089: U43.AL74 94.81,63.6 94.46,63.25 94.46,62.97 94.71,62.71 94.71,62.43 95.1,62.03 95.1,60.44 95.22,60.33 95.22,59.06
  TOP w0.109: v1(122.6,55.8) 122.35,56.06 122.35,61.13 128.95,67.73 128.95,69.27 129.59,69.9 129.97,69.9 130.41,70.34 130.41,74.66 130.04,75.03 129.79,75.03 128.49,76.33 128.49,78.07 135.47,85.05 135.47,85.96 133.53,87.9 133.53,89.18 127.8,94.91 124.62,94.91 123.21,96.32 R1062.1 ; R922.2 96.97,55.14 96.82,55.3 96.82,57.07 v2(95.68,58.22) 95.68,58.6 95.22,59.06
  SIG3 w0.107: v1(122.6,55.8) 121.71,54.92 97.58,54.92 96.82,55.68 96.82,55.93 95.68,57.07 v2(95.68,58.22)
CSN0: length 1
  BOTTOM w0.109: R763.1 R151.2
CSN1: length 1
  TOP w0.109: R773.1 R152.2
DACAV33: length 10.5
  TOP w0.178: U20.K6 v2(152.29,117.83) ; U20.K5 v2(153.09,117.83)
  SIG3 w0.508: v1(156.76,117.78) 156.13,117.15 154.48,117.15 153.79,117.83 v2(153.09,117.83) v2(152.29,117.83)
  BOTTOM w0.381: R629.2 158.29,118.29 158.06,118.06 C305.1 157.04,118.06 v1(156.76,117.78) ; C298.1 C306.1 153.25,117.98 v2(153.09,117.83)
DDR3_4_STRAP: length 14.8
  TOP w0.109: v2(95.59,66.92) 95.3,66.63 U43.AK69
  BOTTOM w0.109: R917.2 100.38,55.42 100,55.8 100,58.09 99.3,58.79 98.92,58.79 97.96,59.74 97.96,61.14 97.07,62.03 97.07,65.33 96.57,65.84 96.57,66.22 95.87,66.92 v2(95.59,66.92)
DDR_B_SA0: length 4.4
  TOP w0.109: J8.256 26.08,48.03 v1(26.4,48.34)
  BOTTOM w0.109: v1(26.4,48.34) 26.36,48.38 R142.1 26.36,50.42 R1122.1
DDR_B_SA1: length 3.2
  TOP w0.109: v1(22.91,46.79) 23.14,47.03 J8.260
  BOTTOM w0.109: R140.1 R1123.1 v1(22.91,46.79)
DDR_B_SA2: length 6.2
  TOP w0.109: J8.166 25.31,70.53 25.66,70.88 v1(25.66,71.2)
  BOTTOM w0.109: v1(25.66,71.2) 24.79,70.32 R139.1 R1125.1
DDR_EVENT_N: length 123.3
  TOP w0.109: U2.J14 v1(87.71,137.23)
  SIG3 w0.107: v1(14.91,117.78) 14.91,125.78 38.27,149.15 59.08,149.15 59.89,148.34 68.8,148.34 72.35,144.79 72.35,142.35 73.55,141.15 75.74,141.15 78.44,138.45 78.97,138.45 79.75,137.67 87.27,137.67 v1(87.71,137.23)
  BOTTOM w0.109: Q10.3 14.75,92.61 R134.2 14.75,94.82 14.29,95.28 14.29,117.17 v1(14.91,117.78)
DDR_SA0: length 12.9
  TOP w0.109: v1(18.21,44.5) 15.67,44.5 12.14,48.03 J7.256
  BOTTOM w0.109: R1116.1 17.85,41.55 17.7,41.71 17.7,43.71 17.83,43.84 R131.1 v1(18.21,44.5)
DDR_SA1: length 13.8
  TOP w0.109: v1(19.1,44.5) 18.59,43.99 14.71,43.99 11.68,47.03 J7.260
  BOTTOM w0.109: R1118.1 19,41.55 18.84,41.71 18.84,43.61 19.07,43.84 R129.1 19.35,44.25 v1(19.1,44.5)
DDR_SA2: length 4.3
  TOP w0.109: v1(9.15,71.35) 9.15,70.9 9.52,70.53 J7.166
  BOTTOM w0.109: v1(9.15,71.35) 9.31,71.2 R1120.1 R127.1
DDR_SCL: length 69.7
  TOP w0.109: R20.1 v1(60.63,36.12) ; v1(3.63,49.43) 3.63,49.1 3.31,48.78 J7.253 ; v1(14.65,48.82) 14.7,48.78 J8.253
  SIG4 w0.086: v1(3.63,49.43) 4.26,49.43 5,48.69 14.52,48.69 v1(14.65,48.82) 16.43,50.6 48.43,50.6 61.13,37.9 61.13,36.63 v1(60.63,36.12)
DDR_SDA: length 66.7
  TOP w0.109: J7.254 9.03,48.53 v1(8.71,48.21) ; R19.1 v1(60.63,37.14) ; J8.254 22,48.53 21.29,49.23 20.28,49.23 v1(19.77,49.74)
  SIG4 w0.086: v1(60.63,37.14) 60.63,37.9 48.31,50.22 20.25,50.22 v1(19.77,49.74) 19.29,50.22 16.81,50.22 14.81,48.21 v1(8.71,48.21)
DDR_VREF: length 55.1
  TOP w0.254: J7.164 11.62,71.03 v1(11.95,71.35) ; v1(23,71.2) 23.17,71.03 J8.164
  SIG1 w0.254: v1(23,71.2) 22.11,70.31 12.99,70.31 v1(11.95,71.35)
  SIG3 w0.381: v1(56.31,68.12) 54.15,70.28 23.92,70.28 v1(23,71.2)
  BOTTOM w0.254: v1(23,71.2) 23.05,71.15 C528.1 ; R991.2 R993.1 59.23,67.64 R985.2 56.79,67.64 v1(56.31,68.12)
  BOTTOM w0.381: C550.1 v1(11.95,71.35)
DDR_VREF_CPU: length 20
  TOP w0.089: U43.CR52 74.52,73.99 74.16,73.64 73.87,73.64 73.67,73.85 73.12,73.85 72.94,73.68 72.47,73.68 72.31,73.84
  TOP w0.254: 72.31,73.84 66.74,73.84 63.45,70.54 v1(63.45,67.52)
  BOTTOM w0.254: v1(63.45,67.52) 62.55,66.62 C594.1 60.37,66.62 R991.1
DDRVREF: length 55.9
  TOP w0.178: U20.T9 v2(149.89,123.43) ; U21.M1 v2(151.03,144.24)
  TOP w0.381: R464.1 R454.2 C253.1 C252.1 144.83,146.48 145.59,145.72 149.54,145.72 v2(151.03,144.24)
  SIG4 w0.381: v2(149.89,123.43) 153.02,123.43 153.72,122.73 154.86,122.73 157.21,125.08 157.21,127.24 160.45,130.48 160.45,134.67 161.34,135.56 161.34,144.58 160.96,144.96 151.74,144.96 v2(151.03,144.24)
  BOTTOM w0.381: C238.1 151.05,144.26 v2(151.03,144.24) ; C244.2 149.96,123.5 v2(149.89,123.43)
DRAMPWROK_PCH: length 42.7
  TOP w0.109: U43.BA9 90.38,93.83 v2(90.62,93.83) ; v1(72.27,72.9) 72.37,73 U43.CV55
  SIG1 w0.086: v2(90.62,93.83) 90.62,92.74 91.11,92.25 91.11,91.75 90.22,90.86 90.22,85.4 92.38,83.24 93.01,83.24 v2(93.52,82.73)
  SIG4 w0.086: v2(93.52,82.73) 93.01,82.22 86.41,82.22 84.48,80.29 82.32,80.29 79.75,77.72 79.75,77.29 79.19,76.73 79.19,76.43 78.79,76.02 78.79,75.67 78.23,75.11 78.23,74.78 77.69,74.24 77.69,73.89 77.26,73.46 77.26,73.1 76.93,72.77 72.4,72.77 v1(72.27,72.9)
  BOTTOM w0.109: R840.2 92.66,81.99 93.39,82.73 v2(93.52,82.73)
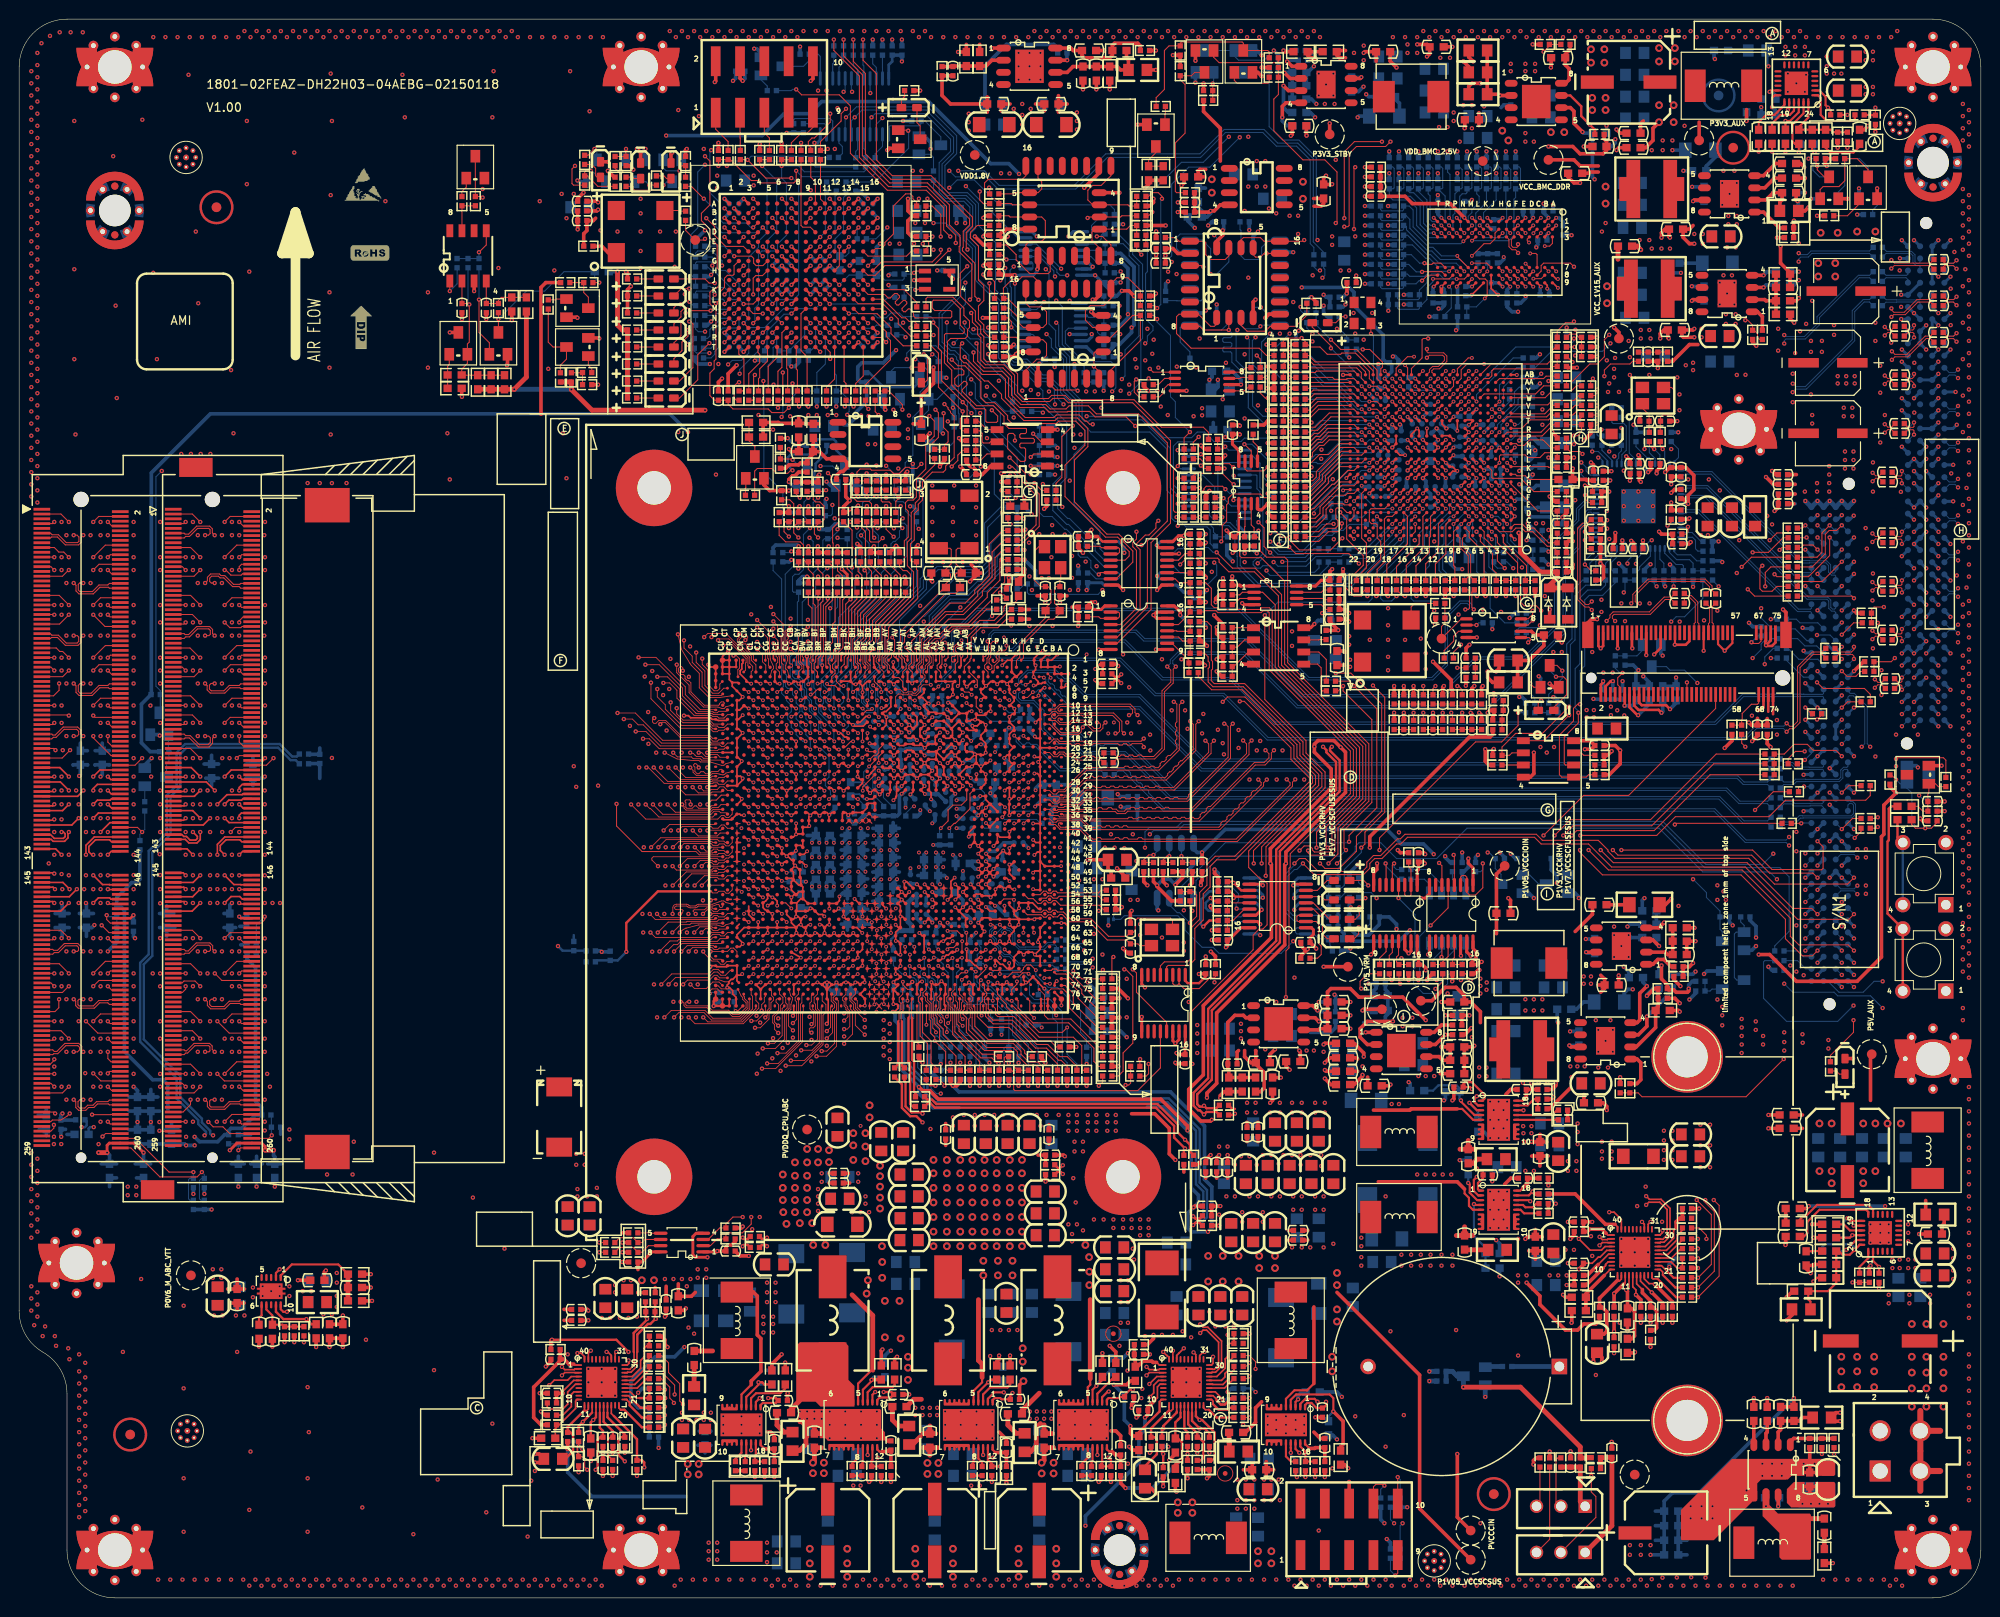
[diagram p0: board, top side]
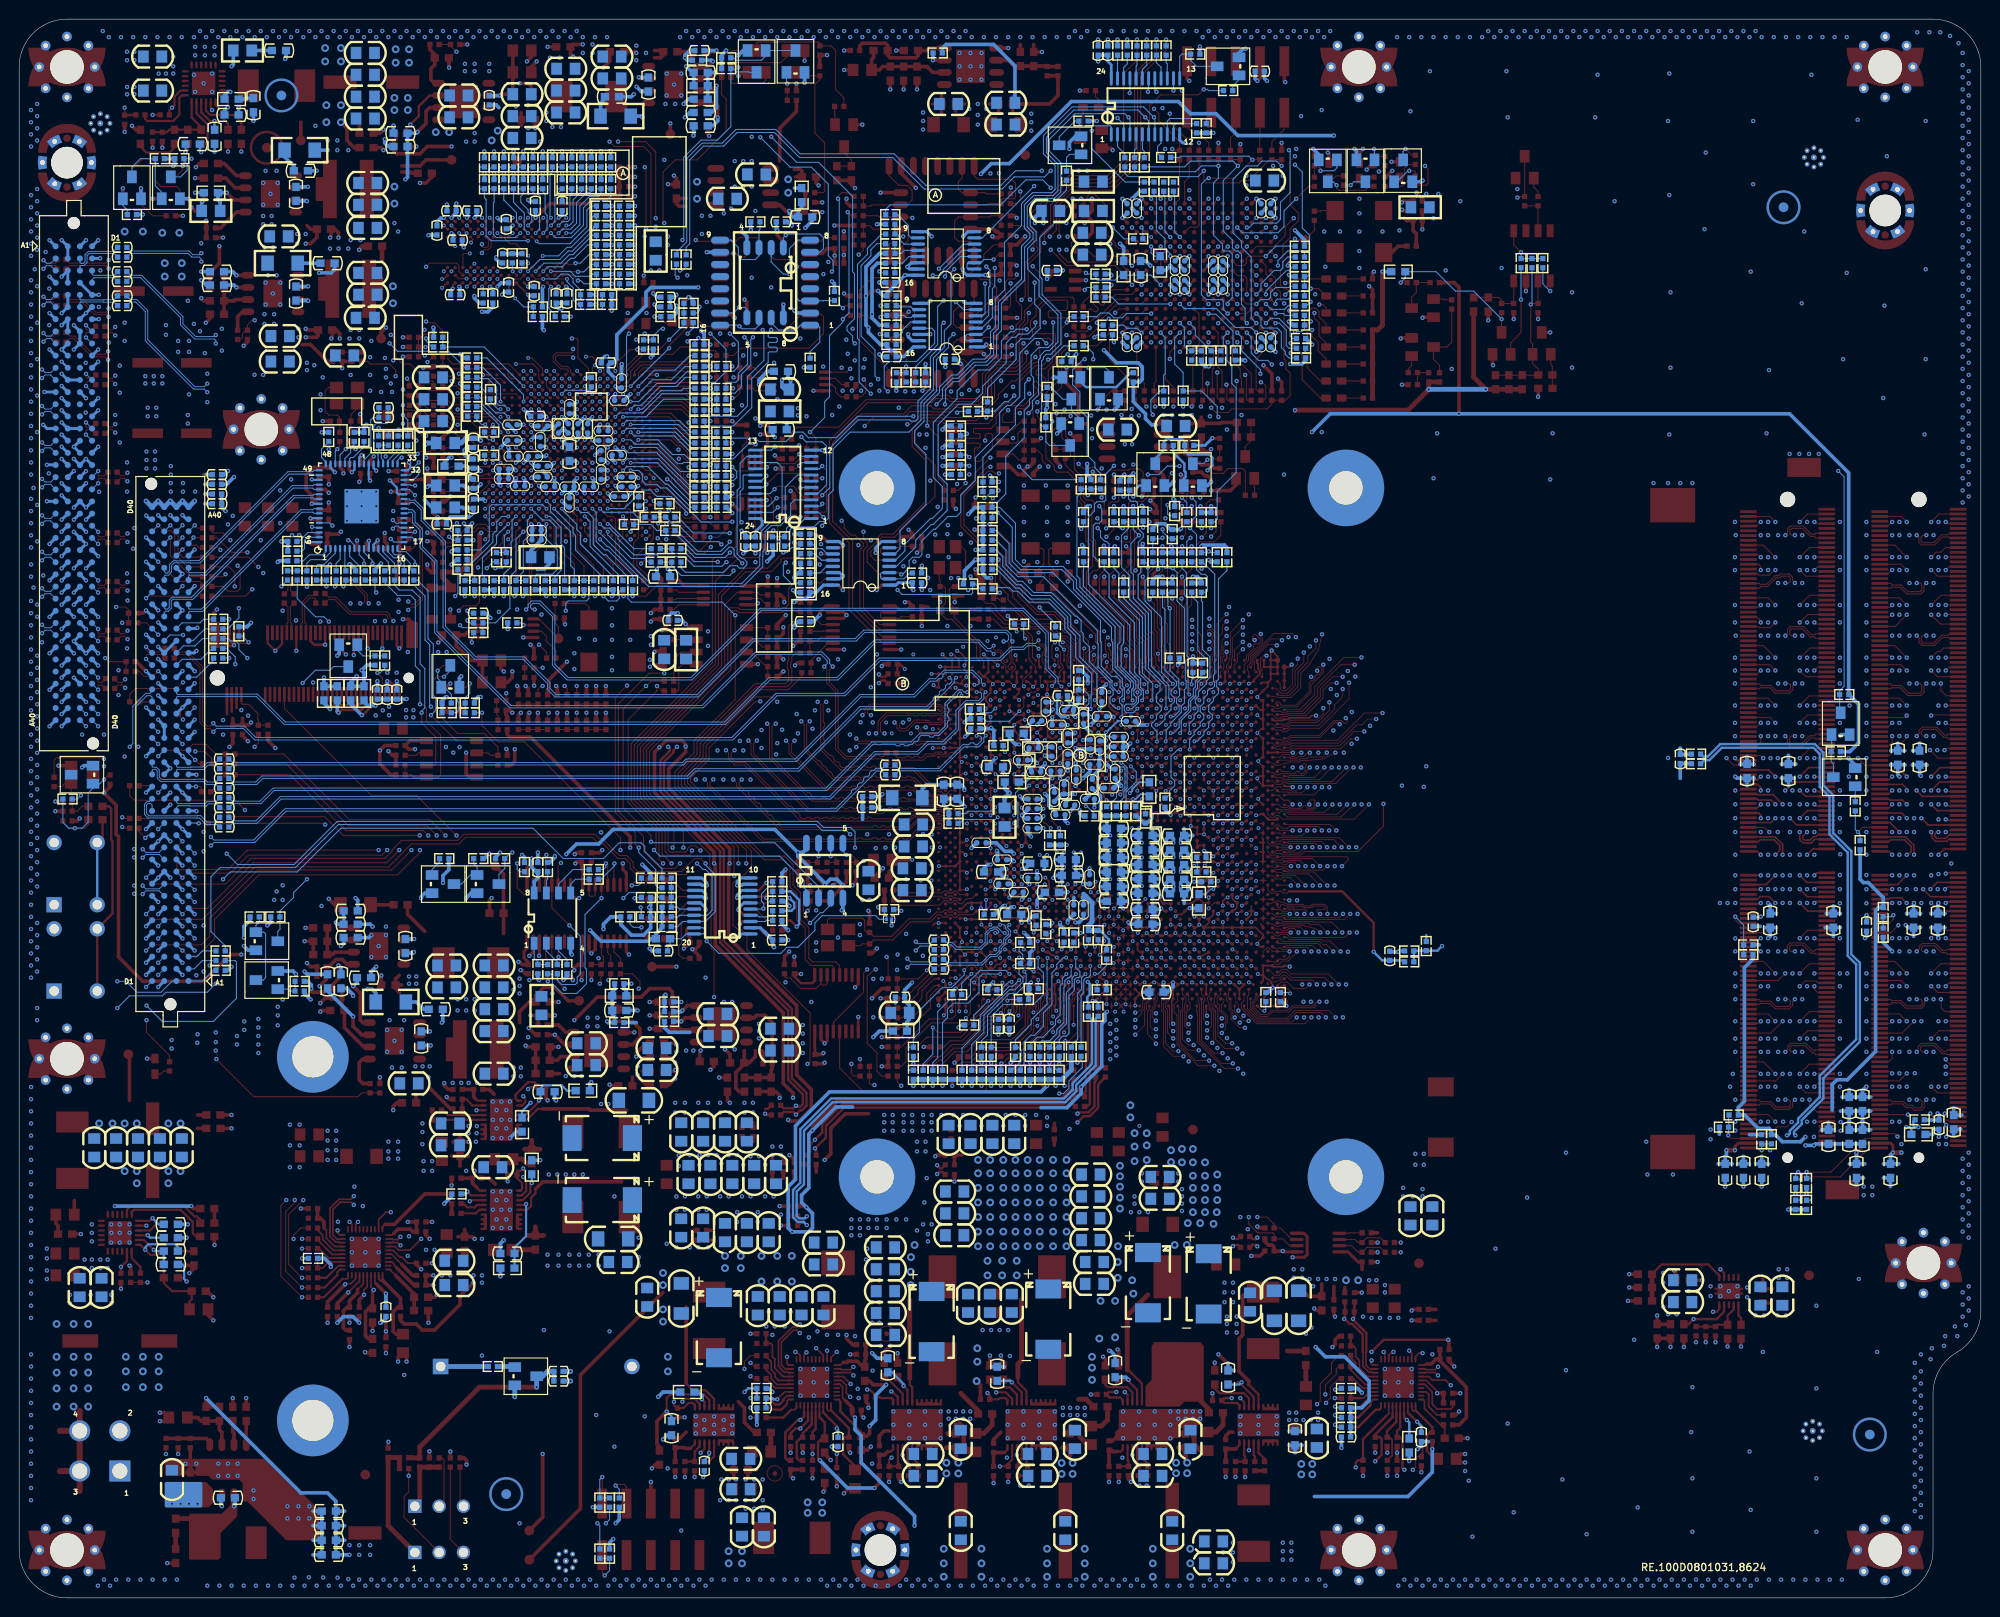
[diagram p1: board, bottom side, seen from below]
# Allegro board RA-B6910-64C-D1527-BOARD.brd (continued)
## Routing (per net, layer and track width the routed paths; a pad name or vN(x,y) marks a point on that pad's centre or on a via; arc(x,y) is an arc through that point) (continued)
DSWODVREN: length 14.4
  TOP w0.089: 95.55,100.51 94.76,99.72 94.76,98.05 U43.AL1
  TOP w0.109: R892.2 103.32,107.26 102.99,106.93 102.99,106.16 101.66,104.84 101.66,104.33 99.12,101.79 97.32,101.79 96.03,100.51 95.55,100.51
EN/FCCM_P1V05_PCH: length 3.5
  TOP w0.229: U35.17 157.63,51.46 158.29,52.12 R720.2 R719.2
EN/FCCM_VCCSCSUS: length 3.2
  TOP w0.229: U32.17 133.88,15.82 134.41,15.29 R682.2 R683.2
EN/FCCM_VCCSCSUS_16997268: length 3.4
  TOP w0.229: v1(158.16,42.47) 157.76,42.06 U34.17
  TOP w0.381: v1(158.16,42.47) 158.42,42.22 R713.2
  BOTTOM w0.381: v1(158.16,42.47) 158.42,42.22 R713.2
EN/FCCM_VCCSCSUS_17116599: length 3
  TOP w0.229: R758.2 R757.2 76.88,14.78 76.99,14.89 U38.17
EN_P0V6_VTT: length 199.9
  TOP w0.109: v1(76.71,144.23) U2.B4 ; R205.1 v1(29.76,26.72)
  SIG3 w0.107: v1(76.71,144.23) 76.6,144.23 74.14,146.69 73,146.69 70.65,149.04 70.65,151.32 69.74,152.22 59.64,152.22 58.63,151.22 39.45,151.22 1.7,113.47 1.7,47.26 21.23,27.74 28.75,27.74 v1(29.76,26.72)
FIVR_FAULT_CPLD: length 36.6
  TOP w0.109: v1(75.71,139.23) U2.H2
  SIG1 w0.086: v1(103.04,138.99) 102.03,140.01 88.18,140.01 86.97,138.79 76.15,138.79 v1(75.71,139.23)
  BOTTOM w0.109: U49.4 104.41,132.69 103.3,133.81 103.3,136.83 103.04,137.08 v1(103.04,138.99)
FIVR_FAULT_GTL: length 142.9
  TOP w0.109: U43.AP69 93.08,67.23 v2(93.09,67.23)
  SIG3 w0.107: v1(114.22,126.09) 114.22,122.86 110.31,118.95 110.31,114 114.52,109.79 114.52,101.61 113.84,100.92 113.84,95.81 115.11,94.54 115.11,91.49 115.62,90.98 118.06,90.98 118.66,90.37 118.66,88.06 127.75,78.97 135.63,78.97 135.76,78.84 135.76,78.84 136.02,78.59 136.02,77.86 135.2,77.04 135.2,72.11 131.87,68.78 131.87,68 123.68,59.81 123.68,59.8 123.29,59.41 118.94,59.41 115.91,56.39 98.7,56.39 96.19,58.9 96.19,59.34 95.63,59.9 95.63,63.35 94.92,64.06 94.92,64.69 95.04,64.82 95.04,65.33 94.66,65.71 94.66,66.22 93.9,66.98 93.34,66.98 v2(93.09,67.23)
  BOTTOM w0.109: v1(114.22,126.09) 114.6,126.47 114.6,128.7 114.09,129.21 111.24,129.21 109.33,131.12 109.33,132.39 109.64,132.69 U49.13
FP_PWR_BTN_R: length 10.1
  TOP w0.109: R545.2 R558.1 160.19,128.7 159.94,128.45 154.1,128.45 153.89,128.24 153.89,127.71 153.61,127.43 153.09,127.43 U20.AA5
FP_PWR_LED: length 33.8
  TOP w0.109: v1(89.81,123.62) 89.45,123.98 R11.1
  TOP w0.178: v2(90.41,95.47) 90.11,95.78 U43.BA5
  SIG3 w0.107: v1(89.81,123.62) 89.84,123.6 89.84,123.01 91.06,121.79 91.06,114.84 91.31,114.58 91.31,113.73 90.85,113.27 90.85,111.68 91.21,111.33 91.59,111.33 92.36,110.56 92.36,107.99 93.36,106.99 93.36,105.3 91.99,103.94 91.99,99.94 90.6,98.54 90.6,95.66 v2(90.41,95.47)
FWSPICK: length 26.2
  SIG4 w0.086: v1(135.15,132.13) 136.57,132.13 136.7,132.26 136.7,134.31 136.59,134.42 136.14,134.42 136.04,134.31 136.04,133.13 135.93,133.02 135.72,133.02 135.61,133.13 135.61,134.31 135.5,134.42 135.29,134.42 135.18,134.31 135.18,133.13 135.08,133.02 134.86,133.02 134.76,133.13 134.76,134.31 134.65,134.42 134.44,134.42 134.33,134.31 134.33,133.13 134.22,133.02 133.4,133.02 133.27,132.89 133.27,131.62 133.11,131.46 130.13,131.46 129.71,131.88 v1(129.71,132.89)
  BOTTOM w0.109: U22.16 129.84,133.02 v1(129.71,132.89) 129.46,132.64 128.06,132.64 127.68,133.02 U24.6 ; v1(135.15,132.13) 134.57,132.72 R480.2
FWSPICK_R: length 12
  TOP w0.109: U20.AA18 141.89,127.43 141.89,128.33 139.75,130.48 138.1,130.48 v1(137.08,131.5)
  BOTTOM w0.109: R573.2 R481.1 R480.1 135.53,133.05 v1(137.08,131.5)
FWSPICKS: length 20.6
  TOP w0.109: U25.6 127.68,141.91 127.94,142.16 129.71,142.16 130.09,141.78 134.16,141.78 v1(134.29,141.91)
  SIG4 w0.086: v1(133.9,134.93) 133.9,135.81 133.52,136.2 133.52,137.44 133.63,137.55 134.18,137.55 134.29,137.66 134.29,137.87 134.18,137.98 133.63,137.98 133.52,138.08 133.52,138.3 133.63,138.4 134.26,138.4 134.39,138.54 134.39,138.7 134.26,138.83 133.63,138.83 133.52,138.94 133.52,139.15 133.63,139.26 134.31,139.26 134.41,139.36 134.41,139.58 134.31,139.68 133.63,139.68 133.52,139.79 133.52,140.13 133.65,140.26 133.65,141.28 v1(134.29,141.91)
  BOTTOM w0.109: v1(133.9,134.93) 133.9,134.54 134.16,134.29 R481.2
FWSPICS0#: length 24.5
  TOP w0.109: R492.2 v1(130.35,130.99)
  SIG4 w0.086: v1(124.89,142.42) 125.9,141.4 125.9,132.39 127.3,130.99 v1(130.35,130.99)
  BOTTOM w0.109: U24.1 125.14,142.16 v1(124.89,142.42) 124.76,142.55 121.33,142.55 120.95,142.16 120.95,141.02 121.33,140.64 U22.7
FWSPICS0#_R: length 12.9
  TOP w0.109: U20.AB19 141.49,128.25 139.65,130.1 138.22,130.1 138.1,129.97 136.7,129.97 135.94,130.73 134.92,130.73 134.67,130.99 R487.2 134.39,131.3 v1(134.02,131.67) 132.42,131.67 132.1,131.34 R492.1
  BOTTOM w0.109: v1(134.02,131.67) 134.09,131.67 134.39,131.37 R487.2
FWSPICS1#: length 18.5
  TOP w0.109: R498.2 130.35,129.85 129.59,130.61 122.47,130.61 120.95,132.13 120.95,133.91 121.2,134.16 123.24,134.16 124.51,132.89 124.89,132.89 125.14,133.15 U25.1
FWSPICS1#_R: length 11.9
  TOP w0.109: R498.1 132.1,130.2 132.25,130.35 134.26,130.35 134.39,130.23 R489.2 134.77,129.85 135.43,129.18 140.11,129.18 141.09,128.19 141.09,127.43 U20.AA19
FWSPIMISO: length 30.3
  SIG3 w0.107: v1(124.51,138.35) 124.51,138.23 127.3,135.43 v1(127.3,132.51)
  BOTTOM w0.109: R486.2 133.42,123.65 133.27,123.5 129.97,123.5 128.89,124.57 128.89,127.62 127.17,129.34 127.17,132.39 v1(127.3,132.51) ; U24.2 126.41,139.62 125.14,138.35 v1(124.51,138.35) 124.51,141.02 123.62,141.91 U22.8
FWSPIMISO_R: length 11.1
  TOP w0.109: U20.T18 v2(141.89,123.43)
  BOTTOM w0.109: R488.1 R486.1 R567.2 137.65,125.27 139.49,123.43 v2(141.89,123.43)
FWSPIMISOS: length 23.8
  TOP w0.109: U25.2 v1(126.41,132.51) 123.74,132.51 123.36,132.89 U23.8
  BOTTOM w0.109: R488.2 133.42,122.76 133.14,122.48 130.35,122.48 128.44,124.38 128.44,127.43 126.73,129.15 126.73,130.1 126.6,130.22 125.9,130.22 125.78,130.35 125.78,130.6 125.9,130.72 126.6,130.72 126.73,130.85 126.73,131.09 126.6,131.22 125.9,131.22 125.78,131.34 125.78,131.59 125.9,131.72 126.6,131.72 126.73,131.84 126.73,132.2 v1(126.41,132.51)
FWSPIMOSI: length 20.7
  SIG4 w0.086: v1(128.32,131.75) 128.32,132.94 128.21,133.05 127.28,133.05 127.17,133.16 127.17,133.37 127.28,133.48 128.21,133.48 128.32,133.58 128.32,133.8 128.21,133.9 127.28,133.9 127.17,134.01 127.17,134.22 127.28,134.33 128.21,134.33 128.32,134.44 128.32,134.77 128.42,134.88 v1(129.76,134.88)
  BOTTOM w0.109: R482.2 131.14,125.76 130.98,125.91 130.2,125.91 129.52,126.58 129.52,127.86 128.55,128.84 128.55,131.52 v1(128.32,131.75) ; U22.15 130.35,134.29 v1(129.76,134.88) 129.16,134.88 128.95,134.67 U24.5
FWSPIMOSI_R: length 14.7
  TOP w0.109: U20.U17 142.69,123.43 v2(142.69,123.43)
  BOTTOM w0.109: R570.2 R482.1 R495.1 132.67,125.85 137.81,125.85 139.81,123.85 142.27,123.85 v2(142.69,123.43)
FWSPIMOSIS: length 21
  TOP w0.109: U23.15 v1(130.35,140.51) 130.09,140.51 129.71,140.13 129.21,140.13 128.95,140.39 U25.5
  SIG4 w0.086: v1(129.21,131.75) 129.21,133.66 130.35,134.8 130.35,139.03 130.24,139.13 129.82,139.13 129.71,139.24 129.71,139.45 129.82,139.56 130.24,139.56 130.35,139.67 v1(130.35,140.51)
  BOTTOM w0.109: R495.2 131.14,126.9 130.98,127.05 130.09,127.05 129.84,127.31 129.84,127.99 128.88,128.95 128.88,131.42 v1(129.21,131.75)
GPIO1_CPU_SCL: length 139.7
  TOP w0.109: R812.2 104.29,109.68 106.6,111.99 106.6,115.37 105.14,116.83 105.14,117.54 v1(103.5,119.18)
  SIG1 w0.086: v1(141.09,111.43) 140.31,112.22 139.14,112.22 138.71,111.79 136.14,111.79 132.18,107.83 131.83,107.83 131.54,108.11 131.54,109.22 130.98,109.78 130.6,109.78 129.97,110.41 129.51,110.41 127.61,112.32 122.03,112.32 119.16,109.45 116.46,109.45 115.87,110.03 114.05,110.03 112.79,111.3 112.79,112.01 110.64,114.16 110.64,117.55 109.4,118.79 103.88,118.79 v1(103.5,119.18) 103.42,119.25 92.33,119.25 91.23,118.16 91.23,117.28 90.21,116.26 88.95,116.26 88.13,115.44 88.13,113.66 87.64,113.18 86.57,113.18 85.52,112.12 v1(85.52,111.68)
  SIG3 w0.107: v1(141.09,111.43) 144.34,108.18 148.81,108.18 151.48,105.51 156.51,105.51 156.89,105.13 156.89,104.19 157.4,103.68 157.4,101.78 158.21,100.97 179.04,100.97 v1(182.42,97.59)
  BOTTOM w0.109: v1(182.42,97.59) 182.42,98.35 183.31,99.24 R184.1 ; v1(85.52,111.68) 85.52,111.43 84.78,110.69 R823.2 84.15,110.69 83.99,110.54 83.99,109.4 83.84,109.25 R889.2
GPIO2_ERR0: length 51
  TOP w0.109: v2(82.68,90.38) 82.39,90.67 U43.BV16 ; U2.P2 v1(74.71,132.23)
  SIG1 w0.086: v1(79.29,124.38) 75.74,127.94 75.74,129.58 75.23,130.09 75.23,131.7 v1(74.71,132.23)
  SIG3 w0.107: v1(79.29,124.38) 79.42,124.38 80.13,123.68 80.13,123.3 80.44,122.99 81.07,122.99 83.04,121.02 83.04,116.45 83.93,115.56 83.93,113.91 83.61,113.59 83.61,112.78 v1(82.65,111.81)
  BOTTOM w0.109: v2(82.68,90.38) 82.68,90.56 82.72,90.6 82.72,91.36 82.22,91.87 82.22,92.25 81.81,92.66 81.81,93.24 82.09,93.52 82.09,93.91 81.76,94.24 81.76,94.69 80.95,95.5 80.95,95.81 80.56,96.19 80.56,98.35 81.33,99.11 81.33,104.06 81.45,104.19 R851.2 80.94,105.11 80.82,105.23 80.82,106.73 81.07,106.99 81.48,106.99 81.96,107.47 81.96,111.12 v1(82.65,111.81)
GPIO3_ERR1: length 55.3
  TOP w0.109: v2(85.13,87.78) 84.82,88.09 U43.BN22 ; U2.P4 v1(76.71,132.23)
  SIG3 w0.107: v2(85.13,87.78) 85.13,88.83 84.63,89.33 84.63,89.71 84.3,90.04 84.3,90.3 83.61,90.98 83.61,91.67 82.8,92.49 82.8,93.27 82.36,93.71 82.36,94.18 82.09,94.45 82.09,95.91 82.72,96.55 82.72,97.41 81.91,98.22 81.91,104.86 80.23,106.54 80.23,110.08 80.95,110.8 80.95,111.05 81.43,111.53 v1(81.43,111.81) 81.43,112.34 81.07,112.7 81.07,115.11 81.71,115.75 81.71,120.98 80.65,122.04 80.03,122.04 75.53,126.54 75.1,126.54 74.47,127.18 74.47,128.53 v1(74.09,128.91)
  BOTTOM w0.109: v1(76.71,132.23) 76.25,131.77 76.25,130.1 75.48,129.34 74.52,129.34 v1(74.09,128.91) ; R850.2 81.45,111.84 v1(81.43,111.81)
GPIO4_THROT_INPUT: length 54.8
  TOP w0.109: v1(81.58,114.99) 81.2,115.37 R848.2 ; U43.BL22 85.86,88.09 v2(86.15,87.8) ; U2.P5 v1(77.71,132.23)
  SIG3 w0.107: v2(86.15,87.8) 86.03,87.92 86.03,88.82 85.64,89.21 85.64,89.71 85.14,90.22 85.14,90.6 84.76,90.98 84.76,91.17 83.56,92.37 83.56,93.09 82.98,93.67 82.98,94.14 83.1,94.26 83.1,94.79 82.85,95.05 82.85,95.8 83.21,96.16 83.21,98.95 82.83,99.34 82.83,103.24 82.27,103.81 82.27,104.9 80.69,106.48 80.69,107.86 81.19,108.36 81.19,109.53 80.98,109.74 80.98,110.12 81.23,110.36 81.66,110.36 81.89,110.59 81.89,112.63 82.02,112.76 82.02,114.54 v1(81.58,114.99) 82.09,115.49 82.09,121.01 80.74,122.35 80.11,122.35 75.87,126.6 75.87,127.37 v1(75.29,127.94)
  BOTTOM w0.109: v1(77.71,132.23) 77.26,131.78 77.26,130.35 75.29,128.38 v1(75.29,127.94)
GPIO5_CATERR_INPUT: length 50.4
  TOP w0.109: U2.P6 v1(78.71,132.23) ; v2(82.18,87.8) 81.9,88.09 U43.BW22
  SIG1 w0.086: v1(80.44,111.81) 79.93,111.3 79.93,106.86 81.33,105.46 81.33,96.57 80.82,96.06 80.82,94.67 80.31,94.16 80.31,93.52 80.56,93.27 80.56,92.63 80.18,92.25 80.18,92 80.56,91.62 80.56,91.24 81.07,90.73 81.07,90.09 80.69,89.71 80.69,89.3 v2(82.18,87.8)
  BOTTOM w0.109: v1(78.71,132.23) 79.17,131.77 79.17,131.04 78.79,130.66 78.79,129.34 78.28,128.83 78.28,126.92 77.82,126.47 77.82,117.6 79.8,115.62 79.8,112.7 80.03,112.47 R847.2 v1(80.44,111.81)
GPIO6_ONLINE_TMS: length 87.2
  SIG3 w0.107: v1(113.2,105.33) 113.58,105.72 113.58,108.61 109.47,112.73 109.47,115.46 107.78,117.15 107.78,123 108.91,124.13 108.91,124.51 v1(109.14,124.74)
  SIG4 w0.086: v1(87.32,154.74) 87.32,157.12 v1(87.04,157.4)
  BOTTOM w0.109: U62.18 86.97,157.47 v1(87.04,157.4) ; v1(113.2,105.33) 112.75,104.88 105.53,104.88 105.36,105.05 R824.2 105.08,105.97 104.57,105.46 R813.2 ; v1(109.14,124.74) 108.51,125.37 108.51,126.41 107.46,127.46 106.89,127.46 105.2,129.15 103.96,129.15 103.17,129.94 103.17,132.19 102.67,132.7 102.67,135.43 100.25,137.85 100.25,141.28 99.36,142.17 99.36,142.55 99.95,143.13 99.95,145.6 98.98,146.56 96.95,146.56 96.45,147.07 96.45,149.85 97.65,151.06 97.65,152.64 94.79,155.5 88.08,155.5 v1(87.32,154.74) 86.97,154.39 U62.7
GPIO7_RS0: length 155.3
  TOP w0.109: R814.2 R825.2 104.29,117.22 103.76,117.75 103.27,117.75 103.04,117.53 v1(102.61,117.53)
  SIG2 w0.107: v1(102.61,117.53) 102.46,117.68 102.46,125.93 101.87,126.52 101.87,128.05 102.19,128.37 102.19,135.16 103.35,136.32 103.35,138.05 102.59,138.81 102.59,147.9 103.5,148.82 v1(103.5,148.87)
  SIG3 w0.107: v1(165.91,129.34) 166.32,128.93 169.69,128.93 169.85,129.08 172.64,129.08 174.67,127.05 174.67,120.29 180.21,114.76 183.71,114.76 185.21,113.26 185.21,112.19 186.1,111.3 187.45,111.3 v1(187.93,110.83)
  SIG4 w0.086: v1(165.91,129.34) 165.5,128.93 164.28,128.93 163.96,129.26 163.96,146.01 160.18,149.78 142.79,149.78 140.69,151.89 124.2,151.89 121.2,148.9 105.69,148.9 105.31,149.28 103.91,149.28 v1(103.5,148.87)
  BOTTOM w0.109: U4.B37 v1(187.93,110.83)
GPIO15_CPU_9641_INT_N: length 120.6
  TOP w0.109: U43.BA23 90.25,87.64 v2(90.62,87.26)
  SIG3 w0.107: v1(118.16,79.81) 117.52,79.17 113.84,79.17 109.65,79.17 106.85,81.97 106.85,84.76 106.47,85.14 106.47,86.41 106.35,86.54 103.93,86.54 103.42,87.05 103.42,87.97 102.57,88.82 99.74,88.82 99.48,88.56 98.79,88.56 98.68,88.45 96.45,88.45 94.84,86.84 91.04,86.84 v2(90.62,87.26)
  BOTTOM w0.109: R170.1 183.46,68.15 184.96,69.65 184.96,75.36 184,76.32 176.13,76.32 173.02,79.43 171.62,80.82 121.71,80.82 121.08,80.19 118.54,80.19 v1(118.16,79.81) ; R830.2 91.26,82.7 90.32,83.64 90.32,84.15 90.09,84.38 89.77,84.38 89.44,84.71 89.44,86.67 89.62,86.84 90.01,86.84 90.43,87.26 v2(90.62,87.26)
GPIO16_CPU_THROTTLE: length 36.1
  TOP w0.109: v1(84.76,129.49) 84.76,130.18 U2.T11 ; v1(84.53,117.55) 84.83,117.25 84.83,116.56 85.66,115.73 85.66,112.45 85.01,111.8 85.01,110.29 85.06,110.24 85.06,109.7 85.01,109.65 85.01,108.4 84.89,108.28 R975.2 85.01,107.77 85.01,104.29 84.3,103.58 84.3,97.38 U43.BN2
  SIG4 w0.086: v1(84.53,117.55) 84.53,121.82 83.87,122.48 83.87,128.6 v1(84.76,129.49)
GPIO17_CPU_SDA: length 135.9
  TOP w0.109: R811.2 104.67,110.54 106.27,112.14 106.27,115.24 104.82,116.69 104.82,117.2 103.81,118.21 v1(103.5,118.21)
  SIG1 w0.086: v1(141.09,110.62) 139.78,111.94 139.25,111.94 138.82,111.51 136.25,111.51 132.3,107.55 131.17,107.55 130.65,108.07 130.65,108.61 130.22,109.04 130.22,109.3 127.47,112.05 122.14,112.05 119.26,109.17 116.23,109.17 115.69,109.7 114,109.7 112.52,111.18 112.52,111.89 110.36,114.05 110.36,117.42 109.92,117.86 105.25,117.86 105.08,118.03 103.68,118.03 v1(103.5,118.21) 102.74,118.97 92.93,118.97 92.38,118.42 92.38,117.91 91.74,117.27 91.61,117.27 90.09,115.75 89.58,115.75 89.07,115.24 89.07,113.84 88.13,112.9 86.69,112.9 86.03,112.24 86.03,111.3 v1(85.52,110.8)
  SIG3 w0.107: v1(181.15,98.22) 180.39,98.22 177.97,100.64 157.78,100.64 157.02,101.4 157.02,103.3 155.88,104.45 155.88,104.99 155.71,105.16 151.23,105.16 148.53,107.85 143.86,107.85 v1(141.09,110.62)
  BOTTOM w0.109: v1(181.15,98.22) 182.04,99.11 182.04,99.7 182.37,100.03 182.93,100.03 183.16,100.25 R187.1 ; v1(85.52,110.8) 85.62,110.69 R822.2 R887.2
GPIO19: length 8.7
  TOP w0.089: U43.BT3 82.79,96.91 82.79,97.68 82.63,97.83 82.63,98.16 82.72,98.25 82.72,98.6
  TOP w0.109: 82.72,98.6 82.85,98.73 82.85,103.43 82.47,103.81 R977.2
GPIO21: length 11.5
  TOP w0.109: R972.2 83.49,107.49 83.99,106.99 83.99,104.19 83.77,103.96 83.77,98.45 83.49,98.17 83.49,97.32 U43.BR2
GPIO22_CPU_INT_N: length 165.1
  TOP w0.109: v1(160.45,79.68) 162.1,81.33 170.48,81.33 177.34,88.19 R1190.1 ; R820.2 82.7,115.65 82.98,115.37 82.98,114.8 83.23,114.54 83.68,114.54 84.12,114.1 84.12,112.7 83.89,112.47 R1174.2 83.49,112.26 83.1,111.88 83.1,111.2 v1(83.49,110.82) ; U43.BN14 v2(85.16,91.24)
  SIG3 w0.107: v1(121.2,110.13) 121.97,109.37 121.97,100.2 123.41,98.76 123.41,95.38 126.03,92.76 128.21,92.76 130.22,90.75 130.22,89.46 129.84,89.08 129.21,89.08 128.06,87.94 128.06,85.36 129.55,83.87 143.94,83.87 148.9,78.91 159.81,78.91 160.45,79.55 v1(160.45,79.68) ; v1(83.49,110.82) 82.93,110.26 82.93,108.97 82.12,108.16 82.12,107.51 81.58,106.97 81.58,106.46 82.83,105.22 82.83,104.06 83.49,103.4 83.49,99.49 84.3,98.68 84.3,97.13 83.82,96.65 83.82,95.25 83.36,94.79 83.36,94.03 83.23,93.9 83.23,93.73 83.78,93.17 83.78,92.44 84.99,91.24 v2(85.16,91.24)
  SIG4 w0.086: v1(83.49,110.82) 83.49,110.8 83.99,110.29 83.99,109.65 85.52,108.13 92.88,108.13 93.39,107.62 101.01,107.62 104.31,110.92 105.2,110.92 105.94,111.66 109.42,111.66 111.93,109.14 113.86,109.14 114.24,108.76 119.83,108.76 v1(121.2,110.13)
GPIO27: length 25
  TOP w0.109: U43.BB16 89.14,90.84 v2(88.92,91.06) ; v1(91.39,110.9) 90.6,111.68 R832.2
  SIG3 w0.107: v1(91.39,110.9) 92.08,110.2 92.08,107.89 93.06,106.91 93.06,105.64 91.23,103.81 91.23,101.02 90.24,100.03 90.24,96.72 89.93,96.41 89.93,95.17 89.71,94.95 89.71,94.29 90.02,93.97 90.02,93.65 89.73,93.36 89.73,92.53 89.45,92.25 89.45,92.13 88.92,91.59 v2(88.92,91.06)
GPIO28_MOD_PRE0: length 150.3
  TOP w0.109: U43.BB23 89.42,87.5 v2(88.82,86.89) ; R198.2 183.05,107.75 182.47,107.16 v1(182.47,105.72)
  SIG3 w0.107: v1(182.47,105.72) 184.23,105.72 188.8,101.15 188.8,93.26 189.28,92.79 189.28,88.95 188.74,88.42 187.6,88.42 187.31,88.13 187.31,79.24 186.17,78.1 186.17,77.72 185.85,77.39 183.69,77.39 v1(183.31,77.78) ; v2(88.82,86.89) 89.2,86.51 89.2,85.52 89.48,85.24 94.81,85.24 96.06,84 96.57,84 97.58,82.98 98.22,82.98 98.98,82.22 98.98,81.59 100.88,79.68 108.5,79.68 109.33,78.85 117.2,78.85 v1(117.65,78.41)
  BOTTOM w0.109: v2(88.82,86.89) 88.26,86.33 88.26,85.29 89.33,84.22 R831.2 ; v1(183.31,77.78) 182.18,76.65 176.27,76.65 171.76,81.15 121.58,81.15 120.94,80.52 118.11,80.52 117.65,80.06 v1(117.65,78.41)
GPIO29: length 28.6
  TOP w0.109: U43.BB12 89.81,92.05 89.81,92.05 v2(89.84,92.05)
  BOTTOM w0.109: v2(89.84,92.05) 89.73,92.15 89.73,93.29 90.01,93.57 90.01,93.98 89.72,94.28 89.72,94.92 89.96,95.17 89.96,95.94 90.34,96.32 90.85,96.32 91.92,97.38 91.92,99.92 91.99,100 91.99,102.16 96.99,107.15 100.54,107.15 101.54,108.15 101.54,110.18 102.92,111.56 R836.2
GPIO30: length 24.8
  TOP w0.109: U43.AY11 90.36,93 90.12,93 v2(90.12,92.99)
  BOTTOM w0.109: R838.2 102.92,109.53 102.21,108.81 102.21,107.8 100.66,106.25 100.15,106.25 98.98,105.08 97.11,105.08 94.63,102.6 94.46,102.6 94.03,102.16 94.03,101.02 93.8,100.79 93.8,100.03 93.14,99.36 93.14,97.84 91,95.71 91,95.17 90.67,94.84 90.67,94.41 91,94.08 91,93.55 90.43,92.97 90.14,92.97 v2(90.12,92.99)
GPIO32_ONLINE_TDO: length 90.1
  TOP w0.109: R841.2 91.61,114.61 91.89,114.88 v1(91.89,115.01) 91.61,115.29 R854.2
  SIG1 w0.086: v1(109.01,114.02) 108.48,114.02 107.79,114.71 105.38,114.71 105.18,114.5 102.24,114.5 101.29,115.45 101.29,116.74 100.81,117.22 94.54,117.22 92.33,115.01 v1(91.89,115.01)
  SIG3 w0.107: v1(108.25,124.74) 107.77,124.26 107.77,123.41 107.49,123.13 107.49,117.05 109.01,115.53 v1(109.01,114.02)
  SIG4 w0.086: v1(89.07,154.74) 89.58,155.24 89.58,157.53 89.2,157.91 86.66,157.91 v1(86.15,157.4)
  BOTTOM w0.109: U62.17 86.32,157.57 v1(86.15,157.4) ; v1(108.25,124.74) 108.25,125.02 108.19,125.08 108.19,126.29 107.36,127.11 106.79,127.11 105.07,128.83 103.83,128.83 102.86,129.81 102.86,131.93 102.35,132.44 102.35,135.3 99.94,137.72 99.94,141.15 99.05,142.04 99.05,142.65 99.65,143.26 99.65,145.47 98.86,146.26 96.83,146.26 96.15,146.94 96.15,150 97.33,151.19 97.33,152.45 94.66,155.12 89.46,155.12 v1(89.07,154.74) 88.92,154.58 U62.4
GPIO33: length 4.9
  TOP w0.109: U43.AN11 93.83,93.24 v2(94.08,92.99)
  BOTTOM w0.109: v2(94.08,92.99) 93.67,92.99 93.21,93.45 93.21,94.36 93.75,94.89 R1180.2 R900.2
GPIO36: length 17.2
  TOP w0.089: U43.BT1 82.95,98.02 82.95,98.5 83.18,98.73
  TOP w0.109: 83.18,98.73 83.18,103.73 82.98,103.94 82.98,106.99 82.47,107.49 R978.2 82.19,108.28 81.96,108.51 81.96,110.03 81.63,110.36 80.11,110.36 79.42,111.05 R1182.2
GPIO37: length 12.8
  TOP w0.109: U43.BL2 85.58,97.44 85.58,98.79 86.08,99.29 86.08,100.94 86.38,101.24 86.38,103.86 v1(86.88,104.36) 87.04,104.52 87.04,107.06 86.53,107.57 R976.2
  BOTTOM w0.109: R1183.2 86.53,104.7 v1(86.88,104.36)
GPIO38_PCIE_CONFIG: length 160.4
  TOP w0.109: v1(187.88,95.68) 188.51,95.05 192.83,95.05 193.44,94.44 R179.1 ; v2(84.66,92.1) 84.37,92.38 U43.BP13 ; v1(140,108.1) 138.96,109.14 133.41,109.14 v1(132.72,109.83)
  SIG1 w0.086: v1(84.76,103.43) 85.01,103.68 85.01,109.65 85.06,109.7 85.06,111.63 84.63,112.07 84.63,113.03 84.93,113.34 85.31,113.34 85.89,113.91 85.89,117.45 87.98,119.53 90.83,119.53 91.7,120.41 107.68,120.41 108.33,121.06 109.54,121.06 109.73,120.87 112.23,120.87 112.89,121.54 117.43,121.54 119.9,119.07 124.98,119.07 125.78,119.86 126.74,119.86 128.89,117.72 130.79,117.72 132.3,116.21 132.3,110.62 132.72,110.2 v1(132.72,109.83)
  SIG3 w0.107: v1(140,108.1) 140.96,107.14 148.17,107.14 150.41,104.9 150.41,104.27 149.96,103.81 149.96,99.65 151.21,98.4 169.37,98.4 170.69,97.08 179.37,97.08 181.73,94.72 186.91,94.72 v1(187.88,95.68)
  BOTTOM w0.109: R821.2 84.81,105.11 84.96,104.96 84.96,103.63 v1(84.76,103.43) 84.73,103.4 R1206.2 84.73,96.92 83.82,96.01 83.82,95.07 83.74,95 83.74,94.29 84.05,93.97 84.05,93.5 83.78,93.24 83.78,92.67 84.35,92.1 v2(84.66,92.1)
GPIO39: length 21
  TOP w0.109: R816.2 81.45,107.59 v1(81.43,107.57) ; v2(83.18,89.52) 82.89,89.81 U43.BU18
  SIG1 w0.086: v1(81.43,107.57) 81.43,106.25 81.83,105.84 81.83,94.29 82.09,94.03 82.09,93.65 81.71,93.27 81.71,92.89 82.22,92.38 82.22,91.87 82.72,91.36 82.72,90.98 82.22,90.48 82.22,90.22 82.92,89.52 v2(83.18,89.52)
GPIO44: length 25.8
  TOP w0.109: v1(90.24,110.77) 89.82,110.35 89.01,110.35 88.87,110.49 88.87,111.51 88.57,111.81 R833.2 ; U43.BD18 88.62,90.35 v2(88.65,90.38)
  SIG3 w0.107: v2(88.65,90.38) 88.65,90.64 88.45,90.85 88.45,92.39 88.74,92.68 88.74,93.31 89.02,93.6 89.02,94.15 88.74,94.44 88.74,101.14 90.06,102.47 90.06,110.59 v1(90.24,110.77)
GPIO45: length 6.7
  TOP w0.109: v2(89.82,87.26) 89.82,87.92 90.22,88.32 U43.BA21
  BOTTOM w0.109: v2(89.82,87.26) 89.71,87.26 89.21,86.77 89.21,84.64 89.55,84.3 89.55,83.65 90.34,82.86 R834.2
GPIO48: length 17.4
  TOP w0.109: U43.BT16 83.38,90.67 v2(83.67,90.38)
  BOTTOM w0.109: R817.2 82.47,104.7 81.83,104.06 81.83,99.01 80.82,97.99 80.82,96.32 81.07,96.06 81.48,96.06 81.86,95.68 81.86,95.07 82.04,94.89 82.04,94.26 82.57,93.73 82.57,92.71 83.56,91.72 83.56,90.49 v2(83.67,90.38)
GPIO49: length 11
  TOP w0.109: R974.2 85.52,107.35 86.03,106.84 86.03,104.7 85.77,104.45 85.77,101.78 85.52,101.52 85.52,99.49 85.11,99.09 85.11,98.2 U43.BM1
GPIO50_ONLINE_JTAG_EN: length 253.2
  TOP w0.109: v1(187.93,71.46) 187.33,72.06 185.34,72.06 180.56,76.84 166.59,76.84 v1(165.27,78.16) ; v1(81.2,157.66) 81.77,157.09 85.71,157.09 86.86,155.93 86.86,150.98 90.72,147.12 94.79,147.12 96.61,145.29 96.61,142.97 v1(97.3,142.28)
  SIG1 w0.086: v1(97.05,122.96) 96.8,122.71 94.1,122.71 93.68,123.12 92.45,123.12 91.81,122.48 91.37,122.48 91.02,122.13 86.57,122.13 80.93,116.5 80.93,110.68 80.56,110.32 80.56,109.5 v1(80.69,109.37)
  SIG3 w0.107: v1(97.3,142.28) 98.49,142.28 99.49,141.28 115.26,141.28 118.44,138.1 120.32,138.1 120.96,137.46 120.96,136.7 124.51,133.15 124.51,130.23 125.27,129.46 125.27,128.58 125.73,128.12 125.73,127 124.96,126.24 124.96,125.09 126.81,123.24 126.81,121.17 127.01,120.98 127.01,119.72 127.68,119.05 127.68,114.43 127.07,113.82 127.07,111.07 125.75,109.75 125.75,107.9 126.44,107.21 126.93,107.21 128.24,105.9 128.24,102.04 129,101.28 129,95.66 134.9,89.76 134.9,88.72 137.41,86.21 145.79,86.21 150.39,81.61 162.84,81.61 165.27,79.17 v1(165.27,78.16)
  SIG4 w0.086: v1(81.2,157.66) 82.6,157.66 83.23,158.29 90.34,158.29 99.39,149.25 99.39,143.05 99.16,142.83 99.16,142 99.74,141.42 99.74,137.19 101.39,135.53 101.39,133.66 100.76,133.02 100.76,127.43 99.87,126.54 99.11,126.54 98.09,125.53 98.09,124 v1(97.05,122.96)
  BOTTOM w0.109: U4.B7 v1(187.93,71.46) ; R1172.2 80.69,157.53 80.82,157.66 v1(81.2,157.66) ; R844.2 80.56,109.25 v1(80.69,109.37) 80.82,109.25 R829.1
GPIO51: length 27
  TOP w0.109: v2(86.1,89.49) 85.78,89.81 U43.BL18
  BOTTOM w0.109: v2(86.1,89.49) 86.1,90.55 86.66,91.11 86.66,91.36 86.15,91.87 86.15,92.25 85.64,92.76 85.64,93.14 86.15,93.65 86.15,94.41 85.77,94.79 85.77,95.56 87.31,97.09 87.31,102.68 88.95,104.32 88.95,106.86 89.79,107.7 89.79,111.04 89.07,111.76 89.07,112.32 89.23,112.47 R861.2
GPIO52: length 8.5
  TOP w0.109: v2(84.66,90.38) 84.37,90.67 U43.BP16
  BOTTOM w0.109: R901.2 81.33,96.55 82.09,95.78 82.09,95.2 82.3,94.99 82.3,94.31 82.8,93.8 82.8,92.79 83.78,91.81 83.78,90.96 84.37,90.38 v2(84.66,90.38)
GPIO53: length 6.9
  TOP w0.109: v2(83.67,88.66) 83.38,88.95 U43.BT20
  BOTTOM w0.109: R895.2 85.16,83.59 84.78,83.97 84.78,84.35 84.25,84.89 84.25,85.4 84.63,85.78 84.63,87.94 83.9,88.66 v2(83.67,88.66)
GPIO54: length 21.4
  TOP w0.109: U43.BW18 81.9,89.81 v2(82.18,89.52)
  BOTTOM w0.109: R842.2 78.79,107.37 79.68,106.48 79.68,95.99 79.86,95.81 79.86,95.23 79.68,95.05 79.68,94.54 80.18,94.03 80.18,93.78 80.69,93.27 80.69,92.63 80.31,92.25 80.31,91.87 80.69,91.49 80.69,90.98 81.2,90.48 81.2,90.22 81.9,89.52 v2(82.18,89.52)
GPIO55: length 29.6
  TOP w0.109: U43.BU22 82.89,88.09 v2(83.18,87.8) ; v1(81.43,110.82) 80.95,111.3 80.95,111.96 R903.2 R859.2
  SIG1 w0.086: v2(83.18,87.8) 82.86,87.8 81.71,88.95 81.71,89.71 81.33,90.09 81.33,90.73 81.71,91.11 81.71,91.49 81.2,92 81.2,92.25 80.82,92.63 80.82,93.27 81.2,93.65 81.2,94.03 81.58,94.41 81.58,94.84 81.07,95.35 81.07,95.94 81.58,96.44 81.58,105.59 80.95,106.22 80.95,108 81.2,108.26 81.2,109.53 80.95,109.78 80.95,110.16 81.43,110.64 v1(81.43,110.82)
GPIO57: length 26.4
  TOP w0.109: U43.BP9 84.37,94.1 v2(84.66,93.81)
  BOTTOM w0.109: R904.2 R870.2 88.95,115.49 89.07,115.37 89.07,114.86 88.82,114.61 88.31,114.61 88.13,114.43 88.13,113.92 88.06,113.84 88.06,111.75 87.52,111.22 87.52,110.85 88.06,110.31 88.06,107.9 87.79,107.63 87.79,107.18 88.06,106.91 88.06,104.44 86.68,103.06 86.68,97.35 85.57,96.24 85.57,96.11 84.86,95.4 84.86,94.01 v2(84.66,93.81)
GPIO62: length 27.6
  TOP w0.109: U43.BD11 88.64,93.26 v2(88.64,93.8)
  BOTTOM w0.109: v2(88.64,93.8) 88.74,93.9 88.74,94.92 88.57,95.1 88.57,95.73 90.22,97.38 90.22,99.62 89.96,99.87 89.96,101.46 94.15,105.65 94.15,106.5 94.46,106.81 94.46,115.06 94.03,115.49 R853.1 R886.2 R852.1
GPIO65_ONLINE_TCK: length 59.5
  SIG4 w0.086: v1(84.37,157.53) 84.37,156.13 86.69,153.82 89.38,153.82 v1(90.22,154.66) 90.97,154.66 91.78,153.85 94.05,153.85 98.6,149.3 98.6,148.54 98.44,148.39 98.44,146.88 97.44,145.87 97.44,143.54 98.44,142.53 98.44,134.44 99.29,133.6 99.29,129.99 99.62,129.67 99.62,127.48 v1(99.49,127.36)
  BOTTOM w0.109: v1(99.49,127.36) 99.92,126.93 99.92,125.35 100.88,124.38 100.88,122.61 104.29,119.2 R937.2 R935.2 ; U62.14 84.37,157.54 v1(84.37,157.53) ; U62.3 89.57,154.01 v1(90.22,154.66)
GPIO67_ONLINE_TDI: length 68.8
  TOP w0.109: v1(110.11,122.5) 108.96,121.36 108.96,117.09 108.35,116.48 R934.2 R936.2
  SIG4 w0.086: v1(88.95,157.28) 88.82,157.15 88.82,155.25 87.85,154.28 86.86,154.28 v1(86.41,154.74)
  BOTTOM w0.109: U62.8 86.32,154.65 v1(86.41,154.74) 87.5,155.83 94.97,155.83 97.96,152.83 97.96,150.93 96.74,149.71 96.74,147.19 97.07,146.86 99.11,146.86 100.25,145.72 100.25,143.43 102.03,141.66 102.03,136.7 102.98,135.75 102.98,132.83 103.49,132.32 103.49,130.07 104.09,129.46 105.33,129.46 106.98,127.81 107.56,127.81 108.83,126.54 108.83,125.98 109.01,125.79 109.01,125.78 110.11,124.69 v1(110.11,122.5) ; U62.21 88.92,157.3 v1(88.95,157.28)
GPIO68_RS1: length 168.2
  TOP w0.109: v1(102.51,105.05) 102.51,104.95 102.64,104.83 102.92,104.83 103.17,104.57 R826.2 102.69,104.47 102.51,104.29 R815.2
  SIG2 w0.107: v1(102.61,148.9) 102.28,148.56 102.28,138.72 103.04,137.96 103.04,136.47 101.9,135.33 101.9,128.47 101.58,128.16 101.58,126.1 101.45,125.96 101.45,125.22 102.15,124.51 102.15,118.8 101.39,118.03 101.39,106.17 v1(102.51,105.05)
  SIG3 w0.107: v1(187.93,112.1) 187.41,111.58 186.25,111.58 185.59,112.24 185.59,113.28 183.84,115.04 180.32,115.04 174.95,120.41 174.95,127.17 172.65,129.46 169.46,129.46 169.21,129.21 167.15,129.21 v1(166.77,129.59)
  SIG4 w0.086: v1(166.77,129.59) 166.4,129.96 165.9,129.96 165.15,129.21 164.64,129.21 164.23,129.62 164.23,146.13 160.3,150.06 142.91,150.06 140.8,152.17 124.09,152.17 121.09,149.17 105.81,149.17 105.33,149.66 103.37,149.66 v1(102.61,148.9)
  BOTTOM w0.109: U4.B38 v1(187.93,112.1)
GPIO69: length 21.5
  TOP w0.109: U43.AU9 92.37,93.82 v2(92.6,93.82)
  BOTTOM w0.109: v2(92.6,93.82) 92.38,94.05 92.38,96.57 94.15,98.35 94.15,100.57 95.1,101.52 95.1,102.62 97.24,104.76 99.17,104.76 100.3,105.89 100.75,105.89 102.87,108 103.17,108 103.32,108.15 R827.2
GPIO70: length 28.6
  TOP w0.109: v1(93.32,115.24) 92.78,115.77 R818.2 ; U43.AU14 v2(92.22,91.24)
  SIG3 w0.107: v1(93.32,115.24) 93.52,115.24 94.46,114.3 94.46,111.68 94.92,111.23 94.92,108.13 95.88,107.16 95.88,104.78 95.3,104.19 95.3,100.76 94.66,100.13 94.66,97.21 93.77,96.32 93.77,95.43 93.01,94.67 92.78,94.67 92.12,94.01 92.12,93.65 92.5,93.27 92.5,92.51 92.22,92.23 v2(92.22,91.24)
GPIO71_I2C_RST_N: length 131.3
  TOP w0.089: U43.AM2 94.32,97.37 94.52,97.57 94.52,99.86 95.55,100.89
  TOP w0.109: 95.55,100.89 95.72,100.89 97.12,102.28 98.88,102.28 101.17,104.58 101.17,105.04 102.49,106.36 102.49,108.33 v1(102.66,108.51) R819.2 ; R175.1 193.44,83.85 192.96,83.36 184.58,83.36 182.86,81.64 173.08,81.64 171.12,79.69 v1(163.14,79.69)
  SIG1 w0.086: v1(102.66,108.51) 102.66,109.63 104.09,111.05 105.35,111.05 105.96,111.66 109.39,111.66 113.79,107.26 119.78,107.26 119.96,107.09 124.48,107.09 v1(124.63,107.24)
  SIG3 w0.107: v1(124.63,107.24) 124.63,106.26 126.59,104.3 126.59,102.3 127.3,101.59 127.3,95.95 133.65,89.6 133.65,88.14 136.65,85.14 145.21,85.14 149.75,80.59 162.23,80.59 v1(163.14,79.69)
GPIO72: length 25.1
  TOP w0.109: U43.BB4 89.37,95.78 90.09,95.05 v2(90.09,94.67)
  BOTTOM w0.109: v2(90.09,94.67) 90.21,94.67 90.79,95.25 90.79,95.84 92.25,97.29 92.25,99.75 92.33,99.82 92.33,101.09 97.96,106.73 100.63,106.73 101.88,107.98 101.88,109.5 102.92,110.54 R874.2
GPIOS4: length 10.5
  TOP w0.109: U20.R19 v2(141.09,122.63)
  BOTTOM w0.109: R527.1 132.1,121.49 132.25,121.34 134.79,121.34 136.09,122.63 v2(141.09,122.63)
GPIOS5: length 7.7
  TOP w0.109: U20.W20 v2(140.29,125.83)
  BOTTOM w0.109: v2(140.29,125.83) 138.82,127.31 136.83,127.31 135.43,128.7 R529.1
GPIOS6: length 7.4
  TOP w0.109: U20.U20 v2(140.29,124.23)
  BOTTOM w0.109: R531.1 135.56,126.42 135.81,126.16 137.94,126.16 139.87,124.23 v2(140.29,124.23)
GPIOS7: length 7.3
  TOP w0.109: R533.1 134.79,128.7 134.95,128.55 139.77,128.55 140.25,128.07 140.25,127.47 U20.AA20
GPIOT4: length 11.1
  TOP w0.109: U20.E7 v2(151.49,113.83)
  BOTTOM w0.109: v2(151.49,113.83) 150.44,112.77 150.31,112.65 149.6,112.65 148.89,111.94 148.89,110.16 148.38,109.65 148.38,107.37 149.02,106.73 R582.1 R581.2
GPIOT5: length 8.9
  TOP w0.109: U20.D7 v2(151.49,113.03)
  BOTTOM w0.109: R578.2 R579.1 153.08,106.48 152.32,107.24 152.32,110.41 151.89,110.85 151.89,112.62 151.49,113.02 v2(151.49,113.03)
GPIOZ3: length 36.8
  TOP w0.109: R502.2 v1(132.76,127.56) ; U20.K3 v2(154.69,118.63) 154.69,119.33 154.82,119.46 157.37,119.46 157.65,119.18 158.92,119.18 159.43,119.69 160.57,119.69 160.73,119.53 R537.2
  SIG1 w0.086: v1(132.76,127.56) 133.14,127.56 139.24,121.46 139.24,119.05 140.86,117.43 149.31,117.43 150.11,118.23 154.3,118.23 v2(154.69,118.63)
GPIOZ4: length 6.2
  TOP w0.109: R528.2 134.57,122.99 135.81,124.23 139.49,124.23 U20.U21
GPIOZ5: length 7.7
  TOP w0.109: U20.W22 135.59,125.43 134.79,124.64 132.25,124.64 132.1,124.49 R530.2
GPIOZ6: length 7.9
  TOP w0.109: R532.2 132.1,123.34 132.25,123.5 134.62,123.5 135.75,124.63 U20.V22
GPIOZ7: length 5.9
  TOP w0.109: U20.W21 139.49,125.83 135.35,125.83 134.79,125.27 R534.2
HB_LED#: length 10.5
  TOP w0.109: D30.2 135.12,132.82 137.08,130.86 v1(137.08,130.61) ; U20.Y18 141.89,126.63 v2(141.09,126.63)
  BOTTOM w0.109: v2(141.09,126.63) 138.13,129.59 138.1,129.59 v1(137.08,130.61)
I210_REF_CLK: length 2.5
  TOP w0.109: v1(171.75,120.07) 171.5,120.32 R1138.1
  BOTTOM w0.109: v1(171.75,120.07) 171.96,119.86 U26.46
I210_VDD3V3: length 16.5
  TOP w0.381: v1(169.21,119.43) 169.31,119.33 C271.1 ; C270.1 168.73,110.21 v1(168.46,110.48) ; v1(174.67,110.34) 174.49,110.16 C269.1 ; C268.1 v1(166.26,116.79)
  SIG2 w0.381: v1(168.46,110.48) 169.11,111.13 170.84,111.13 171.62,110.34 v1(174.67,110.34)
  BOTTOM w0.229: U26.41 169.46,119.18 v1(169.21,119.43) ; v1(174.67,110.34) 174.68,110.35 U26.64 ; v1(174.42,116.89) 174.37,116.85 U26.51 ; U26.10 v1(168.46,110.48) ; v1(166.26,116.79) 165.53,116.05 165.53,115.49 165.38,115.35 U26.27
  vias: v1(176.58,116.89) v1(177.72,115.75)
I210_XOUT: length 2.9
  TOP w0.109: R615.2 170.35,120.45 170.73,120.07 v1(170.86,120.07)
  BOTTOM w0.109: U26.45 171.46,119.47 v1(170.86,120.07)
INTRUDER_N: length 14.1
  TOP w0.089: 96.19,99.49 95.58,99.49 95.37,99.28 95.37,98.63 95.51,98.49 95.51,97.47 U43.AK2
  TOP w0.109: R890.2 104.44,104.45 103.93,103.94 103.3,103.94 102.92,103.56 102.92,103.18 101.9,102.16 100.38,102.16 99.49,101.27 97.61,101.27 96.31,99.97 96.31,99.62 96.19,99.49
INTVRMEN: length 19.9
  TOP w0.109: U43.AP2 93.52,97.45 93.52,98.76 93.26,99.01 93.26,100 97.23,103.96 98.85,103.96 99.86,104.97 99.86,105.3 101.37,106.81 101.37,110.13 102.79,111.56 R891.2
JTAG_NIC_TCK: length 2.2
  TOP w0.109: v1(163.62,111.43) 164.28,110.77 R623.1
  BOTTOM w0.109: U26.19 163.71,111.35 v1(163.62,111.43)
JTAG_NIC_TDI: length 2.6
  TOP w0.109: v1(163.62,116.26) 164.29,116.26 164.41,116.13 R622.1
  BOTTOM w0.109: v1(163.62,116.26) 164,116.26 164.09,116.35 U26.29
JTAG_NIC_TDO: length 2.5
  BOTTOM w0.109: R621.1 171.88,108.13 171.46,108.55 U26.4
JTAG_NIC_TMS: length 2.7
  TOP w0.109: R624.1 163.88,109.65 163.62,109.91 v1(163.62,110.54)
  BOTTOM w0.109: U26.18 163.93,110.85 v1(163.62,110.54)
JTAG_PCH_TCK: length 8.9
  TOP w0.109: R996.1 85.52,104.83 85.26,104.57 85.26,102.03 85.01,101.78 85.01,99.87 84.76,99.62 84.76,98.32 84.56,98.12 84.56,97.66 84.78,97.43 84.78,96.9 U43.BM3
JTAG_PCH_TDI: length 10.2
  TOP w0.109: R994.1 86.53,104.78 86.06,104.3 86.06,101.43 85.77,101.14 85.77,99.37 85.37,98.96 85.37,97.91 85.01,97.55 85.01,97.17 85.26,96.91 85.26,96.62 84.91,96.27 U43.BM5
JTAG_PCH_TDO: length 9
  TOP w0.109: R995.1 87.55,104.39 86.69,103.54 86.69,101.08 86.39,100.78 86.39,98.5 86.22,98.33 86.22,97.58 85.9,97.26 U43.BK3
JTAG_PCH_TMS: length 16.7
  TOP w0.109: R992.1 87.04,111.58 87.04,109.91 87.42,109.53 87.42,107.92 87.68,107.67 87.68,107.26 88.06,106.88 88.06,104.47 87.01,103.42 87.01,101.08 86.66,100.74 86.66,98.35 86.53,98.22 86.53,97.4 U43.BJ2
KR_P0_RX_DN: length 89.9
  SIG4 w0.094: v1(192.09,74.44) 192.09,74.27 191.91,74.09 191.46,74.09 191.18,73.82 191.18,72.55 190.82,72.19 175.05,72.19 174.42,71.55 142.67,71.55 140.25,69.14 134.54,69.14 132.89,67.49 128.32,67.49 127.3,66.47 112.52,66.47 v1(112.19,66.8)
  BOTTOM w0.099: U4.C9 190.36,74.1 191.76,74.1 v1(192.09,74.44) ; C578.1 109.62,66.47 111.86,66.47 v1(112.19,66.8)
KR_P0_RX_DP: length 89.8
  SIG4 w0.094: v1(192.09,73.55) 191.81,73.84 191.56,73.84 191.44,73.71 191.44,72.44 190.93,71.93 175.16,71.93 174.52,71.3 142.77,71.3 140.36,68.89 134.65,68.89 132.99,67.23 128.42,67.23 127.41,66.22 112.52,66.22 v1(112.19,65.89)
  BOTTOM w0.099: v1(192.09,73.55) 191.76,73.89 190.36,73.89 U4.C8 ; v1(112.19,65.89) 111.86,66.22 109.88,66.22 C579.1
KR_P0_TX_DN: length 93.3
  TOP w0.099: U43.J62 104.97,69.54 v2(104.94,69.51)
  SIG4 w0.094: v2(104.94,69.51) 105.2,69.51 105.33,69.65 105.33,70.01 105.73,70.41 106.85,70.41 110.92,74.47 113.84,74.47 114.98,75.62 128.44,75.62 129.03,76.2 156.48,76.2 157.55,77.27 170.1,77.27 182.56,89.72 185.5,89.72 185.83,90.05 187.48,90.05 v1(187.94,90.51)
  BOTTOM w0.099: v1(187.94,90.51) 188.56,91.14 U4.B22
KR_P0_TX_DP: length 93.4
  TOP w0.099: U43.F62 105.96,69.54 105.98,69.51 v2(106.06,69.51)
  SIG4 w0.094: v1(187.94,89.24) 187.94,89.62 187.75,89.8 185.94,89.8 185.6,89.47 182.66,89.47 170.21,77.01 157.65,77.01 156.59,75.95 129.13,75.95 128.55,75.36 115.09,75.36 113.94,74.22 111.02,74.22 106.96,70.16 105.84,70.16 105.58,69.9 105.58,69.65 105.72,69.51 v2(106.06,69.51)
  BOTTOM w0.099: v1(187.94,89.24) 188.56,89.87 U4.B21
KR_P1_RX_DN: length 90.7
  SIG4 w0.094: v1(192.09,78.25) 192.09,78.05 191.94,77.9 191.46,77.9 191.18,77.63 191.18,76.36 190.82,76 173.91,76 170.61,72.7 142.03,72.7 140.64,71.3 116.38,71.3 113.33,68.25 111.63,68.25 v1(111.3,68.58)
  BOTTOM w0.099: C580.1 109.75,68.38 111.1,68.38 v1(111.3,68.58) ; v1(192.09,78.25) 191.76,77.91 190.36,77.91 U4.C12
KR_P1_RX_DP: length 90.7
  SIG4 w0.094: v1(111.3,67.67) 111.63,68 113.44,68 116.48,71.04 140.74,71.04 142.14,72.44 170.71,72.44 174.02,75.74 190.93,75.74 191.44,76.25 191.44,77.52 191.56,77.65 191.81,77.65 v1(192.09,77.36)
  BOTTOM w0.099: C581.1 109.75,68.12 110.84,68.12 v1(111.3,67.67) ; U4.C11 190.36,77.7 191.76,77.7 v1(192.09,77.36)
KR_P1_TX_DN: length 99.8
  TOP w0.099: v2(104.49,68.63) 104.68,68.63 U43.J66
  SIG4 w0.094: v1(190.48,90.51) 190.48,90.35 190.33,90.21 189.98,90.21 189.66,89.88 189.66,86.01 188.92,85.27 188.03,85.27 184.45,81.69 184.45,80.42 182.57,78.54 173.04,78.54 170.63,76.12 158.67,76.12 156.51,73.97 115.36,73.97 114.09,72.7 111.68,72.7 109.01,70.03 108.27,70.03 107.49,69.24 106.82,69.24 106.8,69.22 106.3,69.22 106.17,69.09 105.85,69.09 105.73,69.22 105.24,69.22 104.92,68.9 104.92,68.73 104.82,68.63 v2(104.49,68.63)
  BOTTOM w0.099: U4.D22 191.1,91.14 v1(190.48,90.51)
KR_P1_TX_DP: length 99.8
  TOP w0.099: v2(105.48,68.63) 105.76,68.34 U43.F66
  SIG4 w0.094: v2(105.48,68.63) 105.21,68.63 105.13,68.71 105.13,68.81 105.32,69.01 105.64,69.01 105.76,68.89 106.26,68.89 106.39,69.01 106.8,69.01 106.82,68.99 107.59,68.99 108.38,69.77 109.12,69.77 111.79,72.44 114.2,72.44 115.47,73.71 156.62,73.71 158.78,75.87 170.73,75.87 173.15,78.28 182.67,78.28 184.7,80.32 184.7,81.59 188.13,85.01 189.02,85.01 189.91,85.9 189.91,89.78 190.09,89.95 190.36,89.95 190.48,89.84 v1(190.48,89.24)
  BOTTOM w0.099: v1(190.48,89.24) 191.1,89.87 U4.D21
LAN_ALERT_N_GTL: length 98.9
  TOP w0.109: R1100.2 127.55,104.83 127.83,105.1 U56.2 129.95,105.1 131.26,103.78 131.26,97.25 139.74,88.77 139.74,83.75 136.57,80.58 136.57,78.56 v1(136.72,78.41)
  SIG3 w0.107: v1(96.31,52.71) 96.44,52.58 121.03,52.58 127.05,58.6 127.05,60.83 137.52,71.3 137.52,75.79 138.17,76.45 138.17,76.96 v1(136.72,78.41)
  BOTTOM w0.109: R788.1 94.03,56.19 93.9,56.06 93.9,55.42 95.3,54.03 95.3,53.26 95.86,52.71 v1(96.31,52.71)
LAN_CLK: length 2.6
  TOP w0.109: R1109.2 143.18,67.14 143.5,67.46 U59.12
LAN_CS: length 3.6
  TOP w0.109: R1105.1 R1107.2 143.94,66.45 143.94,66.98 144.15,67.19 U59.13
LAN_DI: length 3.7
  TOP w0.109: R1113.2 R1111.2 148.76,66.47 149.33,67.04 U58.12
LAN_DO: length 2.7
  TOP w0.109: R1110.2 142.16,66.85 142.85,67.54 U59.11
LAN_JTDO: length 6.8
  TOP w0.109: U43.B71 108.37,65.2 109.39,65.2 111.04,63.55 111.04,63.17 112.57,61.65 R783.2
LAN_MODE_SEL0: length 11.4
  TOP w0.089: 107.14,60.88 107.14,63.04 U43.E75
  TOP w0.109: 107.14,60.88 107.52,60.5 109.9,60.5 112.82,57.58 R801.2 R798.2
LAN_MODE_SEL1: length 18.2
  TOP w0.109: U43.N72 103.32,64.91 103.81,65.39 104.63,65.39 104.95,65.71 104.95,65.84 105.27,66.15 105.7,66.15 v2(106.24,65.61)
  BOTTOM w0.109: R799.2 111.91,55.14 112.06,55.3 112.06,57.46 111.96,57.56 R800.2 111.55,58.47 110.92,59.11 110.92,61.39 108.5,63.81 107.54,63.81 106.24,65.11 v2(106.24,65.61)
LAN_P0_ACTIVE: length 5.2
  TOP w0.109: D5.2 136.7,68.89 136.19,69.39 136.19,71.04 135.25,71.99 U52.4
LAN_P0_ACTIVE_GTL: length 35.1
  TOP w0.178: U43.W69 100.04,66.63 100.34,66.93 v2(100.5,66.93)
  TOP w0.254: v1(123.74,70.16) 124.38,70.79 R1068.2
  SIG3 w0.254: v1(123.74,70.16) 122.73,71.17 113.71,71.17 113.2,70.66 109.9,70.66 109.14,69.9 108,69.9 107.23,69.14 107.23,67.62 106.22,66.6 104.44,66.6 103.6,65.76 102.36,65.76 102.18,65.58 101.78,65.58 101.52,65.84 101.52,66.22 100.81,66.93 v2(100.5,66.93)
  BOTTOM w0.254: v1(123.74,70.16) 123.49,70.41 123.49,72.95 124.38,73.84 R1083.2
LAN_P0_SPEED: length 3.7
  TOP w0.109: U52.5 135.23,72.64 136.95,70.92 D4.2
LAN_P0_SPEED_GTL: length 30.4
  TOP w0.178: U43.U69 101.24,66.63 v2(101.52,66.9)
  TOP w0.254: v1(124.51,73.15) 124.84,72.82 R1069.2
  SIG3 w0.254: v2(101.52,66.9) 101.8,66.9 102.31,67.41 102.61,67.41 102.79,67.23 103.3,67.23 103.81,67.74 105.33,67.74 105.96,68.38 105.96,68.76 109.65,72.44 113.58,72.44 113.84,72.7 115.62,72.7 115.87,72.44 117.27,72.44 117.52,72.7 124.05,72.7 v1(124.51,73.15)
  BOTTOM w0.254: v1(124.51,73.15) 124,72.64 124,72.1 124.3,71.81 R1085.2
LAN_P1_ACTIVE: length 3.1
  TOP w0.109: U52.6 136.1,73.29 136.44,72.95 D7.2
LAN_P1_ACTIVE_GTL: length 32.1
  TOP w0.178: U43.T67 101.78,67.77 v2(101.98,67.77)
  TOP w0.254: R1074.1 126.54,73.84 126.92,73.46 v1(126.92,73.15) 127.06,73.29 U52.11
  SIG3 w0.254: v1(126.92,73.15) 126.36,73.71 124.33,73.71 123.82,73.2 117.52,73.2 117.14,73.58 113.84,73.58 113.39,73.14 109.33,73.14 106.35,70.16 104.95,70.16 104.06,69.27 103.45,69.27 103.17,68.99 102.78,68.99 102.68,69.09 102.23,69.09 101.98,68.83 101.98,67.77 v2(101.98,67.77)
LAN_P1_SPEED: length 3.4
  TOP w0.109: D6.2 136.7,74.98 135.66,73.94 U52.7
LAN_P1_SPEED_GTL: length 34.6
  TOP w0.178: U43.V67 100.76,67.49 v2(101.01,67.74)
  TOP w0.254: R1075.1 126.79,74.85 v1(126.92,74.73) 127.71,73.94 U52.10
  SIG3 w0.254: v2(101.01,67.74) 100.44,68.31 100.44,70.09 101.39,71.04 105.2,71.04 107.87,73.71 113.2,73.71 113.58,74.09 117.4,74.09 117.78,73.71 123.49,73.71 124.25,74.47 126.67,74.47 v1(126.92,74.73)
LAN_PWR_GOOD: length 3.7
  BOTTOM w0.109: U26.1 172.96,109.33 173.27,109.02 174.67,109.02 175.31,108.38 R628.1
LAN_PWRGD: length 3.5
  TOP w0.109: U58.13 149.98,66.92 149.78,66.73 R1114.2 R1112.2
LAN_PWRGD_CPLD: length 133.1
  TOP w0.109: v1(149.91,77.65) 149.98,77.58 U58.4 ; U2.F6 v1(78.71,141.23)
  SIG3 w0.107: v1(78.71,141.23) 79.24,140.69 79.24,139.85 79.34,139.75 79.93,139.75 80.18,139.5 80.18,138.74 80.41,138.51 88.67,138.51 90.5,136.68 92.34,136.68 93.09,135.92 98.54,135.92 99.28,136.66 104.52,136.66 105.22,137.36 113.32,137.36 113.89,137.93 115.9,137.93 118.26,135.57 119.24,135.57 121.98,132.82 121.98,127.04 121.43,126.49 121.43,121.59 122.63,120.4 122.63,112.47 121.97,111.81 121.48,111.81 120.47,110.8 120.47,100.93 122.86,98.55 122.86,95.17 124.81,93.21 124.81,90.55 125.14,90.22 125.78,90.22 126.28,89.71 126.28,89.21 125.97,88.89 125.59,88.89 125.01,88.32 125.01,87.2 129.33,82.88 143.71,82.88 148.61,77.98 149.58,77.98 v1(149.91,77.65)
LAN_PWRGD_GTL: length 64.5
  TOP w0.089: v2(97.07,60.07) 97.35,60.35 97.35,61.49 97.29,61.56 U43.AE77
  TOP w0.109: R1112.1 151.15,65.23 151.3,65.08 151.3,64.72 151.45,64.57 v1(151.68,64.57)
  SIG3 w0.107: v1(124.91,64.34) 123.74,63.17 123.74,62.33 122.68,61.27 118.54,61.27 117.39,60.12 114.09,60.12 112.36,58.39 109.08,58.39 108.23,57.53 99.51,57.53 97.07,59.97 v2(97.07,60.07)
  SIG4 w0.086: v1(124.91,64.34) 125.24,64.67 130.58,64.67 131.22,65.31 139.75,65.31 140.02,65.58 143.56,65.58 145.03,64.11 148.84,64.11 149.02,63.93 151.05,63.93 v1(151.68,64.57)
LAN_SCL_GTL: length 103.7
  TOP w0.109: 128.1,114.35 128.1,111.98 128.06,111.94 R1102.2 127.67,110.9 127.55,110.77 127.55,108.9 127.73,108.71 129.79,108.71 132.24,106.26 132.24,97.61 140.72,89.13 140.72,83.39 137.82,80.48 137.82,77.75 v1(136.83,76.76) ; v1(95.75,53.52) 95.17,53.52 94.79,53.9 R789.1
  SIG3 w0.107: v1(95.75,53.52) 96.54,54.31 114.19,54.31 115.36,53.14 120.57,53.14 126.28,58.85 126.28,60.85 136.83,71.39 v1(136.83,76.76)
LAN_SDA_GTL: length 101.9
  TOP w0.109: v1(96.69,53.52) 96.69,53.65 96.16,54.18 R791.1 ; v1(137.71,76.76) 138.13,77.17 138.13,80.35 141.04,83.26 141.04,89.25 132.56,97.74 132.56,108.46 132.25,108.76 130.35,108.76 129.71,109.4 129.71,110.54 129.36,110.9 R1101.2 129.05,110.92 129.05,111.84 128.75,112.14 128.75,114.35
  SIG3 w0.107: v1(137.71,76.76) 137.21,76.25 137.21,71.38 126.67,60.84 126.67,58.73 120.8,52.86 97.35,52.86 v1(96.69,53.52)
LAN_SDP0_1: length 8.8
  TOP w0.089: U43.C76 107.49,63.3 107.84,63.65 109.1,63.65
  TOP w0.109: 109.1,63.65 109.77,62.97 109.77,61.65 112.82,58.6 R781.2
LAN_SPI_CLK: length 3.6
  TOP w0.109: U59.5 143.5,76.57 v1(143.68,76.76)
  BOTTOM w0.109: v1(143.68,76.76) 143.68,76.38 143.94,76.12 R807.2
LAN_SPI_CLK_GTL: length 44.6
  TOP w0.109: v1(143.43,64.57) 143.43,64.69 143.18,64.95 R1109.1 ; v2(102.99,67.77) 103.27,67.49 U43.M67
  SIG1 w0.086: v1(114.85,64.72) 108.86,64.72 107.49,66.09 104.69,66.09 103.01,67.77 v2(102.99,67.77)
  SIG4 w0.086: v1(143.43,64.57) 142.87,65.13 140.33,65.13 140.07,64.88 134.84,64.88 134.18,64.21 126.44,64.21 126.09,63.86 121.51,63.86 120.17,65.2 115.34,65.2 v1(114.85,64.72)
LAN_SPI_CS: length 17
  TOP w0.109: v1(144.14,73.13) 144.15,73.14 U59.4
  BOTTOM w0.109: R803.1 149.42,65.23 149.27,65.08 149.27,64.19 148.26,63.17 146.73,63.17 145.72,64.19 145.72,65.71 145.87,65.86 145.87,71.41 v1(144.14,73.13)
LAN_SPI_CS_GTL: length 46.9
  TOP w0.109: U43.P67 102.49,66.88 v2(102.49,66.88) ; R1107.1 144.19,64.31 v1(144.32,64.19)
  SIG1 w0.086: v2(102.49,66.88) 102.49,66.78 104.44,64.82 105.33,64.82 105.71,64.44 106.9,64.44 107.84,63.5 113.4,63.5 114.17,64.27 115.32,64.27 v1(115.74,64.69)
  SIG4 w0.086: v1(115.74,64.69) 120.06,64.69 121.33,63.42 126.39,63.42 126.75,63.77 134.36,63.77 135.02,64.44 140.25,64.44 140.51,64.69 142.29,64.69 142.92,64.06 144.19,64.06 v1(144.32,64.19)
LAN_SPI_DI: length 14.6
  TOP w0.109: U58.5 149.33,72.12 v1(147.49,70.28)
  BOTTOM w0.109: v1(147.49,70.28) 146.35,69.14 146.35,65.2 146.68,64.87 146.68,64.29 146.86,64.11 148.31,64.11 148.76,64.57 R804.1
LAN_SPI_DI_GTL: length 44
  TOP w0.109: v1(148,63.65) 148.76,64.41 R1111.1 ; v2(107.72,64.19) 107.7,64.2 U43.D74
  SIG4 w0.086: v2(107.72,64.19) 107.84,64.06 109.9,64.06 110.41,63.55 116.38,63.55 117.14,62.79 126.53,62.79 126.97,63.23 134.85,63.23 135.17,63.55 138.6,63.55 138.98,63.17 147.52,63.17 v1(148,63.65)
LAN_SPI_DO: length 4.8
  TOP w0.109: U59.6 142.85,76.71 v1(142.79,76.76)
  BOTTOM w0.109: R808.2 144.19,75.11 142.79,76.51 v1(142.79,76.76)
LAN_SPI_DO_GTL: length 38.1
  TOP w0.109: R1110.1 140.92,65.23 140.13,64.44 140.13,63.81 v1(140.25,63.68) ; v2(107.13,64.77) 107.16,64.8 U43.C73
  SIG4 w0.086: v2(107.13,64.77) 107.31,64.95 109.31,64.95 110.37,63.89 116.43,63.89 117.25,63.06 126.42,63.06 126.86,63.5 134.74,63.5 135.13,63.89 140.05,63.89 v1(140.25,63.68)
LAN_XTAL_IN: length 15.3
  TOP w0.109: OSC4.1 117.1,68.16 116.91,68.35 C582.1 115.72,68.76 113.71,68.76 111.81,70.66 109.77,70.66 109.01,71.43 108.76,71.43 108.5,71.17 108.1,71.17 108.04,71.17 107.81,71.4 107.57,71.4 107.3,71.14 107.08,71.14 106.81,71.4 105.35,71.4 U43.J58
LAN_XTAL_OUT: length 18.4
  TOP w0.109: OSC4.3 120.53,70.83 120.32,71.04 116.89,71.04 116.63,70.79 116.63,69.77 116.4,69.55 C583.1 115.72,69.14 113.84,69.14 112.01,70.97 109.85,70.97 109.14,71.68 108.51,71.68 108.32,71.87 108.03,71.87 107.83,71.66 107.54,71.66 107.34,71.87 107.04,71.87 106.84,71.66 106.07,71.66 U43.F58
LED: length 3.9
  TOP w0.109: J3.10 167.28,95.2 167.05,95.43 167.05,96.16 v1(167.56,96.67)
  BOTTOM w0.109: v1(167.56,96.67) 167.28,96.67 166.8,97.16 R168.2
LED0_N: length 11.1
  TOP w0.109: D8.2 71.67,137.85 72.11,137.41 v1(72.69,137.41) ; U2.K5 v1(77.71,136.23)
  SIG3 w0.107: v1(72.69,137.41) 72.77,137.41 73.33,137.97 75.23,137.97 75.48,137.72 76.09,137.72 77.59,136.23 v1(77.71,136.23)
LED1_N: length 13.3
  TOP w0.109: D9.2 69.19,136.83 v1(70.02,136.83) ; U2.K6 v1(78.71,136.23)
  SIG3 w0.107: v1(70.02,136.83) 70.96,137.77 72.44,137.77 72.99,138.32 74.87,138.32 75.23,138.68 75.92,138.68 77.14,137.47 77.14,137.08 77.52,136.7 77.9,136.7 78.37,136.23 v1(78.71,136.23)
LED2_N: length 22.9
  TOP w0.109: U2.K11 v1(84.71,136.23) ; v1(69.13,135.18) 68.75,135.18 68.42,134.85 D10.2
  SIG3 w0.107: v1(84.71,136.23) 84.19,135.71 79.4,135.71 79.17,135.94 79.17,136.45 78.91,136.7 78.53,136.7 78.25,136.98 78.25,137.5 76.05,139.7 75.36,139.7 74.39,138.74 71.29,138.74 69.11,136.55 69.11,135.2 v1(69.13,135.18)
LED3_N: length 22.4
  TOP w0.109: U2.K12 v1(85.71,136.23) ; v1(72.26,134.53) 70.16,134.53 69.9,134.8 69.52,134.8 69.16,134.44 69.16,133.88 68.42,133.15 D11.2
  SIG3 w0.107: v1(85.71,136.23) 85.71,135.57 84.91,134.77 75.38,134.77 75.23,134.93 75.23,135.43 74.93,135.74 72.61,135.74 72.26,135.38 v1(72.26,134.53)
LED4_N: length 29.1
  TOP w0.109: D12.2 68.42,131.17 69.16,131.9 69.16,133.27 69.64,133.76 v1(69.64,134.29) ; U2.K13 v1(86.71,136.23)
  SIG3 w0.107: v1(86.71,136.23) 86.23,136.7 79.55,136.7 79.27,136.98 79.27,137.74 78.91,138.1 78.28,138.1 76.37,140.01 75.23,140.01 74.98,139.75 71.89,139.75 68.68,136.54 68.68,134.87 69.26,134.29 v1(69.64,134.29)
LED5_N: length 16.2
  TOP w0.109: U2.L5 v1(77.71,135.23) ; D13.2 68.42,129.51 69.26,130.35 69.26,131.24 69.9,131.88 v1(69.9,132.51)
  SIG3 w0.107: v1(69.9,132.51) 70.53,133.15 70.53,134.67 72.54,136.68 75,136.68 75.23,136.45 75.23,135.94 75.48,135.69 76.12,135.69 76.58,135.23 v1(77.71,135.23)
LED6_N: length 22
  TOP w0.109: U2.L7 v1(79.71,135.23) ; v1(70.02,133.4) 70.15,133.4 70.4,133.15 70.4,128.58 69.01,127.18 D14.2
  SIG3 w0.107: v1(70.02,133.4) 70.2,133.58 70.2,134.75 72.42,136.96 73.45,136.96 74.16,137.67 75.03,137.67 75.23,137.47 75.23,137.08 75.54,136.78 76.04,136.78 76.25,136.58 76.25,136.07 76.63,135.69 78.91,135.69 79.37,135.23 v1(79.71,135.23)
LED7_N: length 24.5
  TOP w0.109: U2.L10 v1(83.71,135.23) ; v1(72.13,131.14) 70.91,129.92 70.91,127.31 69.01,125.4 D15.2
  SIG3 w0.107: v1(72.13,131.14) 71.65,131.14 71.17,131.62 71.17,132.51 71.45,132.79 74.82,132.79 75.36,132.26 v1(75.74,132.26)
  BOTTOM w0.109: v1(83.71,135.23) 83.23,134.75 79.88,134.75 77.9,132.77 76.25,132.77 v1(75.74,132.26)
LED_HDD_ACTIVITY_N: length 130.7
  TOP w0.109: v1(142.16,78.16) 142.16,79.43 152.19,89.46 154.92,89.46 156.64,91.17 v1(156.64,92.51)
  TOP w0.178: U43.BF14 87.88,91.52 88.49,92.13 v2(88.82,92.13)
  SIG1 w0.086: v1(106.98,116.41) 106.35,115.77 104.16,115.77 103.75,116.18 102.32,116.18 101.97,116.54 101.97,116.85 101.04,117.78 94.28,117.78 93.01,116.51 92.12,116.51 v1(90.6,114.99)
  SIG3 w0.107: v1(90.6,114.99) 90.6,114.73 91.04,114.29 91.04,113.85 90.47,113.28 90.47,111.57 90.95,111.09 90.95,110.53 91.21,110.28 91.21,107.91 92.05,107.06 92.05,105.64 90.85,104.45 90.85,101.14 90.02,100.31 90.02,97.16 89.71,96.85 89.71,95.25 89.5,95.04 89.5,94.46 89.24,94.2 89.24,93.48 89.51,93.22 89.51,92.68 88.95,92.13 v2(88.82,92.13) ; v1(117.29,110.03) 117.47,109.86 117.47,96.75 119.45,94.77 119.45,92.28 120.8,90.93 120.8,89.02 128.72,81.1 139.75,81.1 142.16,78.69 v1(142.16,78.16)
  SIG4 w0.086: v1(117.29,110.03) 117.22,110.11 112.75,110.11 109.77,113.08 109.77,113.97 107.34,116.41 v1(106.98,116.41)
  BOTTOM w0.109: R6.1 v1(156.64,92.51)
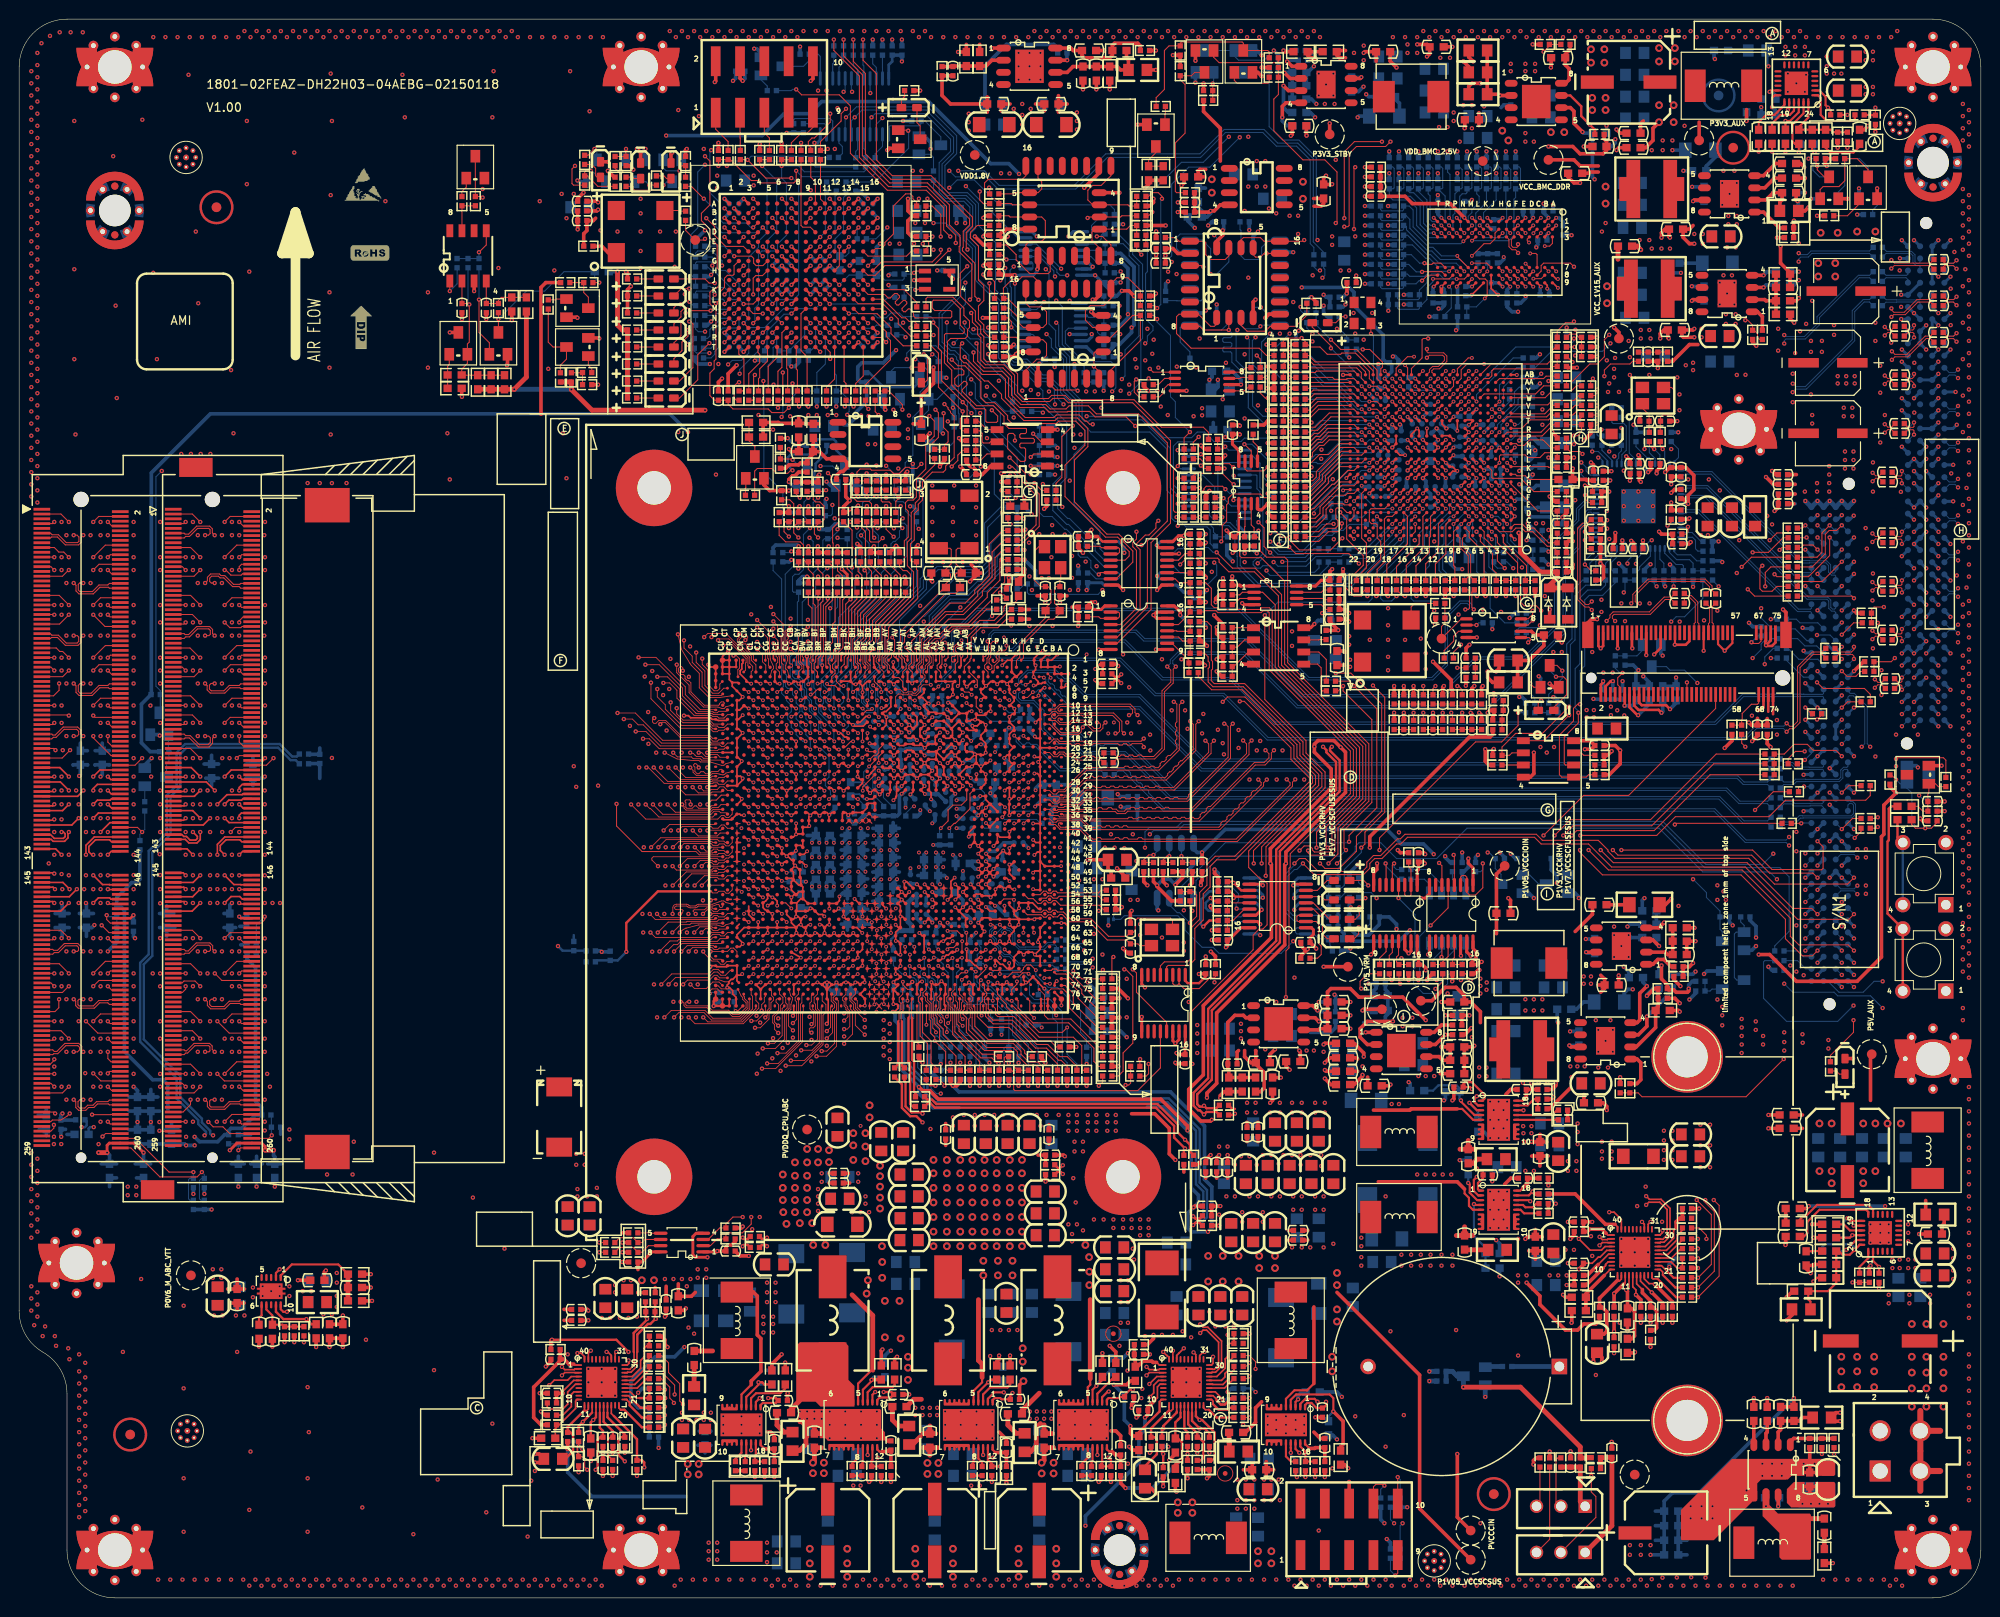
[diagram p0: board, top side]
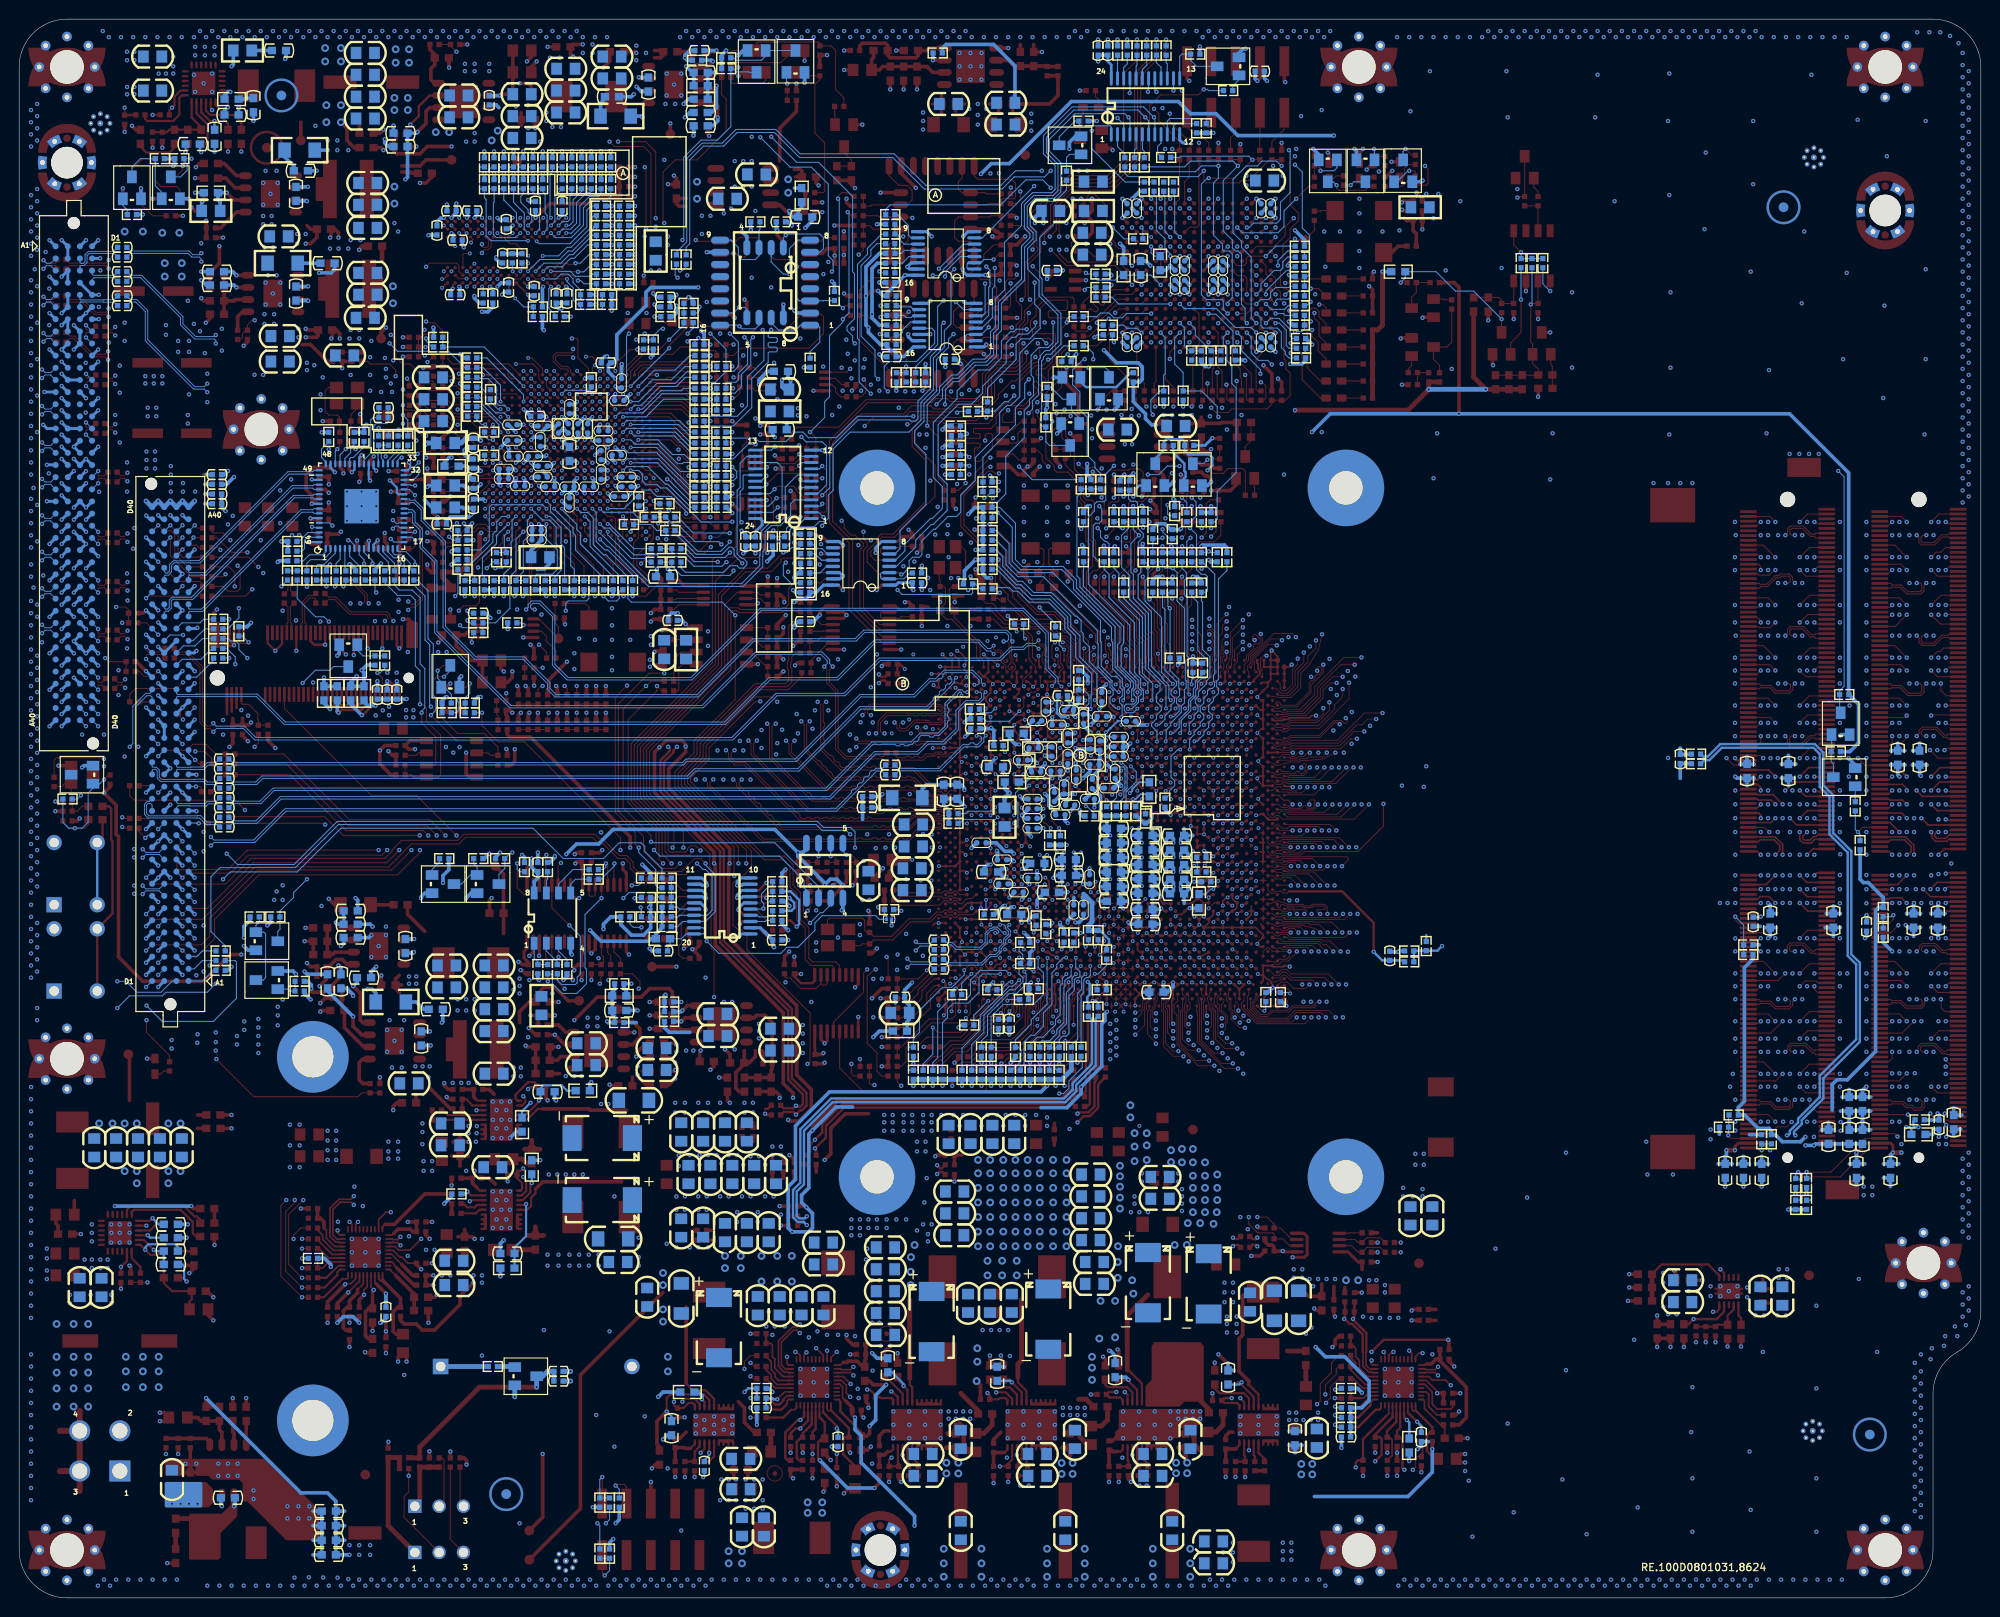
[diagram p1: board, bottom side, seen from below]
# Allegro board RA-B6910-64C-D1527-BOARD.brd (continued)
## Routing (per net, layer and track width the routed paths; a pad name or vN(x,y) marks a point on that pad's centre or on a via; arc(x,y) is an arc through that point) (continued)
LM75_OS: length 67.5
  TOP w0.109: v1(130.27,75.46) 130.3,75.49 130.3,78.5 136.47,84.67 136.47,86.31 134.48,88.3 134.48,89.59 130.17,93.89 v1(130.17,102.7) ; v2(146.69,113.83) U20.E13 ; R320.1 122.35,72.06 v1(122.6,71.81)
  SIG1 w0.086: v1(130.27,75.46) 128.52,73.71 124.38,73.71 122.6,71.93 v1(122.6,71.81)
  BOTTOM w0.109: v1(130.17,102.7) 131.54,104.06 141.02,104.06 141.38,104.43 141.38,106.72 143.68,109.02 143.94,109.02 144.95,110.03 144.95,112.83 145.56,113.43 146.3,113.43 v2(146.69,113.83)
LPC_33M_BMC: length 20.4
  TOP w0.109: R943.2 v1(130.35,127.56) ; v2(139.49,113.83) 139.49,113.03 U20.C22
  SIG1 w0.086: v1(130.35,127.56) 131.24,126.67 131.24,126.04 132.51,124.77 133.9,124.77 138.22,120.45 138.22,118.29 139.11,117.4 139.11,114.21 v2(139.49,113.83)
LPC_33M_CPLD: length 64.8
  TOP w0.109: R944.2 129.69,129.49 v1(129.33,129.85) ; v1(76.71,136.23) 76.71,137.93 76.98,138.19 77.68,138.19 U2.H5
  SIG1 w0.086: v1(129.33,129.85) 127.17,132 124.76,132 123.59,133.17 118.51,133.17 118.44,133.25 109.19,133.25 106.93,130.99 104.69,130.99 104.16,130.45 100.78,130.45 100.56,130.68 97.46,130.68 97.26,130.48 92.53,130.48 91.94,129.9 85.34,129.9 84.5,130.73 80.31,130.73 80.06,130.99 80.06,132.13 78.66,133.53 77.77,133.53 77.26,134.04 77.26,135.67 v1(76.71,136.23)
LPC_DA0: length 204.4
  TOP w0.109: R431.2 131.14,111.66 131.95,110.85 v1(132.76,110.85) 132.76,110.54 133.78,109.53 137.05,109.53 138.26,110.74 v1(138.27,110.74) ; R65.2 94.76,135.79 94.92,135.94 97.58,135.94 98.73,134.8 98.73,134.04 99.31,133.45 99.31,132.77 99.11,132.56 99.11,131.88 98.85,131.62 97.33,131.62 97.01,131.3 97.01,129.21 97.77,128.45 98.5,128.45 98.73,128.23 98.73,127.91 98.63,127.81 98.15,127.81 97.77,127.43 97.77,126.88 98.02,126.63 98.2,126.63 98.71,127.14 98.89,127.14 99.07,126.97 99.07,126.79 98.55,126.27 98.55,126.1 100.05,124.6 101.81,124.6 102.92,123.49 102.92,122.73 103.42,122.23 105.2,122.23 105.27,122.16 105.27,121.81 105.14,121.68 104.69,121.68 104.57,121.56 104.57,121.31 104.69,121.19 105.97,121.19 106.09,121.06 106.09,120.81 105.97,120.69 104.69,120.69 104.57,120.56 104.57,120.31 104.69,120.19 105.05,120.19 105.17,120.07 105.17,118.9 105.05,118.78 104.64,118.78 103.3,120.12 103.3,121.54 103.46,121.7 103.86,121.7 104.06,121.5 v1(104.06,120.96) ; R180.1 188.36,92.28 v1(187.88,91.8) ; U43.AF3 96.79,97.46 96.8,97.46 v2(96.8,97.47)
  SIG1 w0.086: v1(104.06,120.96) 104.06,121.28 104.25,121.46 104.59,121.46 104.7,121.36 104.7,120.79 104.8,120.68 105.02,120.68 105.12,120.79 105.12,121.48 105.23,121.59 105.44,121.59 105.55,121.48 105.55,120.79 105.66,120.68 105.87,120.68 105.98,120.79 105.98,121.04 106.08,121.14 106.3,121.14 106.4,121.04 106.4,120.79 106.51,120.68 106.72,120.68 106.83,120.79 106.83,121.72 106.96,121.84 107.13,121.84 107.26,121.72 107.26,120.99 107.42,120.83 107.62,120.83 107.74,120.96 107.74,121.21 107.87,121.34 109.65,121.34 109.84,121.14 112.11,121.14 112.83,121.86 117.49,121.86 120.02,119.34 122.07,119.34 122.22,119.49 122.22,121.05 122.38,121.21 122.6,121.21 122.73,121.08 122.73,120.07 122.81,119.99 124.02,119.99 124.13,120.1 124.13,121.48 124.23,121.59 124.53,121.59 124.63,121.48 124.63,120.1 124.74,119.99 125.04,119.99 125.14,120.1 125.14,121.04 125.25,121.14 125.54,121.14 125.85,120.83 126.41,120.83 128.57,118.67 130.73,118.67 132.63,116.76 133.02,116.76 133.4,116.38 133.4,111.48 v1(132.76,110.85)
  SIG3 w0.107: v1(104.06,120.96) 104.13,121.02 104.13,121.5 104.04,121.59 103.59,121.59 103.5,121.5 103.5,119.87 104.01,119.36 104.01,117.07 104.22,116.85 104.22,116.6 104.13,116.51 103.16,116.51 103.07,116.42 103.07,116.1 103.16,116 104.47,116 104.57,115.91 104.57,115.62 104.44,115.49 103.07,115.49 102.79,115.21 102.79,114.73 103.48,114.05 103.48,112.8 103.15,112.47 103.15,111.79 103.37,111.56 103.37,107.58 102.72,106.93 102.72,105.53 103.01,105.24 103.01,104.92 102.28,104.19 101.01,104.19 97.81,100.99 97.81,97.56 97.72,97.47 v2(96.8,97.47) ; v1(138.27,110.74) 139.57,109.45 139.57,107.92 139.62,107.87 139.62,107.87 140.62,106.87 147.48,106.87 149.45,104.9 149.45,104.39 149.67,104.17 149.67,99.54 151.1,98.12 169.08,98.12 170.51,96.7 177.24,96.7 181.68,92.25 182.15,92.25 182.25,92.35 182.25,93.3 182.34,93.4 182.53,93.4 182.62,93.3 182.62,92.35 182.72,92.25 182.9,92.25 183,92.35 183,93.3 183.09,93.4 183.28,93.4 183.37,93.3 183.37,92.35 183.47,92.25 183.66,92.25 183.75,92.35 183.75,93.3 183.84,93.4 184.03,93.4 184.13,93.3 184.13,92.35 184.22,92.25 187.42,92.25 v1(187.88,91.8)
LPC_DA1: length 214.4
  TOP w0.109: v2(96.56,99.17) 96.19,98.8 96.19,97.71 95.93,97.46 95.93,97.13 96.3,96.76 U43.AG4 ; R432.2 139.47,105.36 139.24,105.59 139.24,106.71 140.46,107.92 140.46,108.94 138.73,110.67 138.73,112.75 138.05,113.44 v1(138.05,113.46)
  SIG1 w0.086: v1(138.05,113.46) 138.02,113.49 138.02,114.05 136.83,115.24 136.83,117.65 133.14,121.34 132.63,121.34 131.24,122.73 131.24,122.86 130.41,123.69 130.22,123.69 129.92,124 129.92,124.81 129.17,125.56 129.17,127.46 126.3,130.33 122.52,130.33 122.17,130.68 119.15,130.68 118.97,130.5 118.05,130.5 117.88,130.33 117.42,130.33 116.64,131.1 109.63,131.1 106.36,127.83 104.71,127.83 103.29,126.42 101.39,126.42 101.27,126.54 101.19,126.54 101.16,126.57 v1(101.14,126.57) 100.78,126.57 99.61,125.4 99.21,125.4 97.94,126.67 82.21,126.67 81.09,127.8 80.18,127.8 79.93,127.54 79.21,127.54 78.15,128.6 78.15,132.51 77.9,132.77 76.5,132.77 76.25,133.02 76.25,134.64 76.14,134.75 74.39,134.75 74.21,134.93 74.21,135.43 73.96,135.69 73.58,135.69 73.2,136.07 73.2,138.48 v1(72.44,139.24)
  SIG3 w0.107: v1(138.05,113.46) 138.81,112.7 141.65,112.7 145.26,109.09 156.94,109.09 158.49,107.54 176.79,107.54 179.89,104.45 184.58,104.45 185.72,103.3 185.72,102.44 185.63,102.35 183.91,102.35 183.82,102.25 183.82,102.06 183.91,101.97 185.63,101.97 185.72,101.88 185.72,101.69 185.63,101.59 183.4,101.59 183.31,101.5 183.31,101.31 183.4,101.22 185.63,101.22 185.72,101.12 185.72,100.94 185.63,100.84 183.4,100.84 183.31,100.75 183.31,100.56 183.4,100.47 185.63,100.47 185.72,100.37 185.72,100.18 185.63,100.09 183.4,100.09 183.31,100 183.31,99.81 183.4,99.71 185.63,99.71 185.72,99.62 185.72,99.33 185.63,99.24 183.43,99.24 183.05,98.86 v1(183.05,98.22) ; v2(96.56,99.17) 96.75,99.17 97.2,99.62 97.2,101.27 102.18,106.24 102.18,117.8 102.99,118.62 102.99,125.2 102.03,126.16 101.57,126.16 101.16,126.57 v1(101.14,126.57)
  BOTTOM w0.109: v1(72.44,139.24) 72.44,139.5 72.3,139.63 70.81,139.63 70.68,139.51 R66.2 ; R182.1 v1(183.05,98.22)
LPC_DA2: length 208.9
  TOP w0.089: v2(95.93,99.87) 95.68,99.87 95.17,99.37 95.17,98.45 95.31,98.3 95.31,97.75 94.92,97.35 94.92,96.87 U43.AL3
  TOP w0.109: v1(138.22,112.29) 138.22,111.81 137.84,111.43 136.83,111.43 135.81,110.41 133.65,110.41 133.42,110.64 R434.2
  SIG1 w0.086: v1(73.45,139.24) 74.23,138.47 74.23,136.06 74.49,135.79 76.02,135.79 76.83,134.98 76.83,133.85 77.59,133.09 78.48,133.09 79.62,131.95 79.62,130.79 80.69,129.72 83.49,129.72 85.14,128.07 101.39,128.07 102.26,127.2 v1(102.38,127.2) 103.2,127.2 105.71,129.72 107.23,129.72 109.16,131.65 117.78,131.65 118.39,131.04 118.74,131.04 118.93,131.22 122.39,131.22 122.73,130.89 126.51,130.89 129.71,127.69 129.71,126.47 130.27,125.91 130.6,125.91 131.49,125.02 131.49,124.77 132.63,123.62 133.52,123.62 133.94,123.21 133.94,123.06 133.45,122.57 133.45,122.42 133.6,122.27 133.76,122.27 134.24,122.76 134.39,122.76 134.54,122.6 134.54,122.45 134.06,121.97 134.06,121.82 134.21,121.67 134.36,121.67 134.84,122.15 134.99,122.15 135.14,122 135.14,121.85 134.66,121.37 134.66,121.22 134.81,121.06 134.96,121.06 135.45,121.55 135.6,121.55 135.75,121.4 135.75,121.25 135.26,120.76 135.26,120.61 135.42,120.46 135.57,120.46 136.05,120.95 136.2,120.95 137.77,119.37 137.77,114.8 138.48,114.1 138.48,112.55 v1(138.22,112.29)
  SIG3 w0.107: v1(182.04,103.43) 182.04,103.81 181.78,104.06 179.88,104.06 176.69,107.25 158.15,107.25 156.59,108.81 154.8,108.81 154.7,108.72 154.7,106.95 154.61,106.86 154.42,106.86 154.33,106.95 154.33,108.72 154.23,108.81 154.04,108.81 153.95,108.72 153.95,106.95 153.86,106.86 153.67,106.86 153.57,106.95 153.57,108.72 153.48,108.81 153.29,108.81 153.2,108.72 153.2,106.95 153.1,106.86 152.92,106.86 152.82,106.95 152.82,108.72 152.73,108.81 152.54,108.81 152.45,108.72 152.45,106.95 152.35,106.86 152.16,106.86 152.07,106.95 152.07,108.72 151.98,108.81 151.79,108.81 151.69,108.72 151.69,106.95 151.6,106.86 151.41,106.86 151.32,106.95 151.32,108.72 151.22,108.81 144.96,108.81 141.48,112.29 v1(138.22,112.29) ; v1(102.38,127.2) 101.14,127.2 100.5,126.56 100.5,125.28 101.14,124.64 101.14,123.47 100.63,122.96 100.63,120.96 101.09,120.5 101.09,107.31 96.34,102.57 96.34,100.53 95.93,100.13 v2(95.93,99.87)
  BOTTOM w0.109: R67.2 70.68,140.54 70.91,140.77 72.44,140.77 73.45,139.75 v1(73.45,139.24) ; R188.1 183.18,101.27 182.04,102.41 v1(182.04,103.43)
LPC_DA3: length 210.9
  TOP w0.109: R435.2 133.42,111.55 133.55,111.43 135.81,111.43 136.62,112.24 v1(137.36,112.24) ; v2(96.74,99.85) 97.07,99.52 97.07,98.28 U43.AF1
  SIG1 w0.086: v1(137.36,112.24) 136.32,113.28 136.32,117.53 133.65,120.19 132.63,120.19 132.25,120.57 132.25,120.7 130.6,122.35 130.48,122.35 128.63,124.2 128.63,127.23 126.16,129.7 119.53,129.7 119.4,129.58 118.1,129.58 117.83,129.85 117.27,129.85 117.14,129.97 116.38,129.97 115.82,129.41 114.43,129.41 114.32,129.52 114.32,129.87 114.21,129.97 114,129.97 113.89,129.87 113.89,129.52 113.79,129.41 113.57,129.41 113.47,129.52 113.47,130.5 113.36,130.61 113.15,130.61 113.04,130.5 113.04,129.52 112.93,129.41 112.72,129.41 112.61,129.52 112.61,130.5 112.51,130.61 112.29,130.61 112.19,130.5 112.19,129.52 112.08,129.41 111.87,129.41 111.76,129.52 111.76,130.5 111.65,130.61 111.44,130.61 111.33,130.5 111.33,129.52 111.23,129.41 111.01,129.41 110.91,129.52 110.91,130.5 110.8,130.61 110.59,130.61 110.48,130.5 110.48,129.52 110.37,129.41 110.16,129.41 110.05,129.52 110.05,130.5 109.95,130.61 109.73,130.61 109.63,130.5 109.63,129.52 109.52,129.41 108.33,129.41 106.47,127.56 104.82,127.56 103.3,126.04 102.28,126.04 v1(101.9,125.65) 101.44,126.11 100.71,126.11 99.75,125.15 99.06,125.15 97.8,126.4 97.13,126.4 97.02,126.29 97.02,125.89 96.91,125.78 96.7,125.78 96.59,125.89 96.59,126.29 96.49,126.4 96.27,126.4 96.17,126.29 96.17,125.89 96.06,125.78 95.85,125.78 95.74,125.89 95.74,126.29 95.63,126.4 95.42,126.4 95.31,126.29 95.31,125.89 95.21,125.78 94.99,125.78 94.89,125.89 94.89,126.29 94.78,126.4 94.57,126.4 94.46,126.29 94.46,125.89 94.35,125.78 94.14,125.78 94.03,125.89 94.03,126.29 93.93,126.4 82.07,126.4 80.95,127.52 80.3,127.52 80.04,127.27 78.82,127.27 77.52,128.58 76.96,128.58 76.2,129.34 76.2,132.56 75.99,132.77 75.36,132.77 75.23,132.89 75.23,133.53 74.98,133.78 73.33,133.78 72.82,134.29 72.82,134.65 72.31,135.15 72.31,135.81 v1(72.69,136.2)
  SIG3 w0.107: v2(96.74,99.85) 96.9,100 96.9,101.43 101.9,106.44 101.9,117.92 102.69,118.71 102.69,124.87 v1(101.9,125.65) ; v1(137.36,112.24) 137.77,111.84 141.5,111.84 144.8,108.53 148.85,108.53 151.54,105.84 160.93,105.84 161.02,105.75 161.02,104.92 161.11,104.83 161.3,104.83 161.4,104.92 161.4,105.75 161.49,105.84 161.68,105.84 161.77,105.75 161.77,104.92 161.87,104.83 162.05,104.83 162.15,104.92 162.15,105.75 162.24,105.84 162.43,105.84 162.52,105.75 162.52,104.92 162.62,104.83 162.81,104.83 162.9,104.92 162.9,105.75 162.99,105.84 163.18,105.84 163.28,105.75 163.28,104.92 163.37,104.83 163.56,104.83 163.65,104.92 163.65,105.75 163.75,105.84 163.93,105.84 164.03,105.75 164.03,104.92 164.12,104.83 164.31,104.83 164.4,104.92 164.4,105.75 164.5,105.84 164.68,105.84 164.78,105.75 164.78,104.92 164.87,104.83 165.06,104.83 165.15,104.92 165.15,105.75 165.25,105.84 165.44,105.84 165.53,105.75 165.53,104.92 165.62,104.83 165.81,104.83 165.91,104.92 165.91,105.75 166,105.84 166.19,105.84 166.28,105.75 166.28,104.92 166.38,104.83 166.56,104.83 166.66,104.92 166.66,105.75 166.75,105.84 168.25,105.84 168.34,105.75 168.34,104.79 168.43,104.7 168.62,104.7 168.71,104.79 168.71,105.75 168.81,105.84 169,105.84 169.09,105.75 169.09,104.79 169.18,104.7 169.37,104.7 169.47,104.79 169.47,105.75 169.56,105.84 170.35,105.84 170.48,105.72 170.48,105.21 170.73,104.95 176.45,104.95 178.86,102.54 179.74,102.54 179.84,102.63 179.84,102.95 179.93,103.05 180.12,103.05 180.21,102.95 180.21,102.63 180.31,102.54 182.8,102.54 v1(183.05,102.29)
  BOTTOM w0.109: v1(72.69,136.2) 72.31,136.58 70.81,136.58 70.68,136.45 R60.2 ; v1(183.05,102.29) R189.1
LPC_FRAME_N: length 167.1
  TOP w0.109: v2(95.8,99.11) 95.8,98.48 95.8,98.47 U43.AH1 ; v1(186.58,88.47) 185.62,88.47 184.86,87.71 R178.1
  SIG1 w0.086: v1(101.14,121.21) 102.28,121.21 102.85,121.78 104.63,121.78 105.08,122.23 107.74,122.23 108.35,121.62 108.78,121.62 109.22,122.05 112.26,122.05 112.95,122.73 114.1,122.73 114.36,122.99 117.28,122.99 117.67,122.61 118.51,122.61 118.62,122.5 118.62,121.34 118.72,121.23 118.94,121.23 119.04,121.34 119.04,122.5 119.15,122.61 119.36,122.61 119.47,122.5 119.47,120.43 119.58,120.32 119.79,120.32 119.9,120.43 119.9,122.5 120,122.61 120.22,122.61 120.32,122.5 120.32,120.43 120.43,120.32 120.64,120.32 120.75,120.43 120.75,122.5 120.86,122.61 121.07,122.61 121.18,122.5 121.18,120.55 121.28,120.45 121.5,120.45 121.6,120.55 121.6,122.5 121.71,122.61 122.86,122.61 123.36,122.1 126.03,122.1 126.79,121.34 126.79,121.08 128.82,119.05 130.98,119.05 132.3,117.73 133.7,117.73 135.3,116.13 135.3,115.46 135.2,115.35 134.27,115.35 134.16,115.25 134.16,115.03 134.27,114.93 135.2,114.93 135.3,114.82 135.3,114.61 135.2,114.5 134.27,114.5 134.16,114.39 134.16,114.18 134.27,114.07 135.2,114.07 135.3,113.97 v1(135.3,113.34)
  SIG3 w0.107: v2(95.8,99.11) 96.31,99.62 96.31,100.02 96.62,100.32 96.62,102.45 101.36,107.19 101.36,120.99 v1(101.14,121.21) ; v1(186.58,88.47) 186.81,88.7 188.64,88.7 188.99,89.05 188.99,92.66 188.51,93.14 188.51,101.04 184.73,104.83 179.9,104.83 176.47,108.26 173.99,108.26 173.61,108.64 164,108.64 163.75,108.89 158.42,108.89 157.65,109.65 146.1,109.65 145.33,110.41 145.33,112.22 143.71,113.84 v2(143.51,113.84)
  BOTTOM w0.109: v1(135.3,113.34) 135.3,113.54 136.88,115.11 138.35,115.11 139.02,115.78 139.84,115.78 140.25,115.37 R51.1 140.53,115.09 141.78,113.84 v2(143.51,113.84) ; v2(95.8,99.11) 96.31,99.62 96.31,100.41 96.44,100.53 R63.2
LPC_RST_N: length 2
  TOP w0.109: U2.D14 v1(87.71,143.23)
  BOTTOM w0.109: v1(87.71,143.23) 87.58,143.09 R52.1
LPC_SERIRQ: length 65
  TOP w0.109: R176.1 183.31,84.25 v1(181.4,82.35)
  SIG3 w0.107: v1(183.69,75.11) 183.69,76.37 181.4,78.66 v1(181.4,82.35)
  BOTTOM w0.109: R1089.2 137.82,76.23 139.62,78.03 139.62,78.54 140,78.92 142.29,78.92 143.94,77.27 148.13,77.27 151.3,80.44 171.37,80.44 175.94,75.87 182.93,75.87 v1(183.69,75.11)
LPCPD#: length 7.5
  TOP w0.109: U20.H21 139.49,116.23 138.14,116.23 135.94,114.04 135.94,113.34 135.43,112.83 134.92,112.83 134.79,112.95 R403.2
LPCPME#: length 8.7
  TOP w0.109: U20.H22 138.09,116.63 135.3,113.84 135.15,113.84 134.77,113.46 132.35,113.46 132.1,113.21 R406.2
M_A-CLK_DN2: length 84.2
  TOP w0.175: v1(7.75,77.66) 7.59,77.66 7.29,77.97 7.29,78.53 7.97,79.22 9.46,79.22 9.65,79.03 J7.140 ; U43.CG47 v2(78.72,76.64)
  SIG3 w0.089: v2(78.72,76.64) 78.72,76.64 arc(78.9,76.57) 79.07,76.64 arc(79.15,76.83) 79.07,77.02 arc(79,77.07) 78.91,77.07 78.77,77.05 arc(78.73,77.05) 78.69,77.04 arc(78.6,77.03) 78.52,76.99 arc(78.37,76.85) 78.32,76.65 78.32,76.62 arc(78.23,76.34) 78.02,76.13 arc(77.73,76.05) 77.43,76.13 arc(77.23,76.18) 77.03,76.13 arc(76.74,76.05) 76.44,76.13 arc(76.24,76.18) 76.04,76.13 arc(75.75,76.05) 75.45,76.13 75.25,76.13 75.21,76.09 75.19,76.09
  SIG3 w0.163: 75.19,76.09 75.06,76.09 72.56,73.59 64.72,73.59 62.7,75.61 56.65,75.61 53.46,78.8 46.97,78.8 46.64,79.12 46.64,79.61 46.46,79.79 45.95,79.79 45.77,79.61 45.77,79.12 45.44,78.8 44.1,78.8 43.57,79.32 11.19,79.32 10.03,78.16 7.69,78.16 7.54,78.02 7.54,77.87 v1(7.75,77.66)
M_A_BA0: length 87
  TOP w0.175: J7.150 9.47,74.53 9.44,74.55 8.71,74.55 v1(7.75,75.52) ; U43.CH52 v2(78.22,74.07)
  SIG2 w0.163: v1(7.75,75.52) 7.75,75.16 8.05,74.85 9.44,74.85 11.27,76.68 42.47,76.68 42.99,76.15 46.29,76.15 48.64,73.8 59.4,73.8 59.57,73.62 59.57,72.64 59.75,72.46 60.05,72.46 60.22,72.64 60.22,73.33 60.35,73.46 60.75,73.46 60.87,73.33 60.87,72.64 61.05,72.46 61.35,72.46 61.52,72.64 61.52,73.33 61.65,73.46 62.05,73.46 62.17,73.33 62.17,72.64 62.35,72.46 62.65,72.46 62.82,72.64 62.82,73.46 62.95,73.58 63.35,73.58 63.47,73.46 63.47,72.64 63.65,72.46 63.95,72.46 64.12,72.64 64.12,73.46 64.25,73.58 64.65,73.58 64.78,73.46 64.78,72.64 64.95,72.46 65.32,72.46 65.45,72.59 65.45,73.08 65.58,73.2 65.96,73.2 66.09,73.08 66.09,72.59 66.21,72.46 72.53,72.46 74.55,74.48 77.81,74.48 v2(78.22,74.07)
M_A_BA1: length 87.7
  TOP w0.175: J7.145 3.59,75.78 v1(3.67,75.7) ; U43.CL51 v2(76.74,74.93)
  SIG2 w0.163: v1(3.67,75.7) 3.67,75.94 3.98,76.25 9.95,76.25 10.93,77.22 43.02,77.22 43.54,76.7 47.23,76.7 47.41,76.52 47.41,75.8 47.59,75.62 47.88,75.62 48.06,75.8 48.06,76.2 48.24,76.37 48.53,76.37 48.71,76.2 48.71,74.5 48.87,74.34 49.2,74.34 49.36,74.5 49.36,76.2 49.54,76.37 49.83,76.37 50.01,76.2 50.01,74.5 50.17,74.34 50.5,74.34 50.66,74.5 50.66,76.2 50.84,76.37 51.13,76.37 51.31,76.2 51.31,74.5 51.47,74.34 66.13,74.34 66.62,73.85 72.99,73.85 74.64,75.5 75.78,75.5 76.16,75.12 76.54,75.12 v2(76.74,74.93)
M_A_BG0: length 82.6
  TOP w0.175: v1(5.19,84.38) 5.19,84.39 4.31,85.28 J7.115 ; U43.CM33 v2(76.24,82.65)
  SIG3 w0.163: v1(5.19,84.38) 5.82,85.01 6.78,85.01 7.03,85.27 7.16,85.39 25.97,85.39 26.3,85.72 55.5,85.72 60.58,80.64 60.83,80.64 61.04,80.85 61.04,81.1 59.9,82.24 59.9,82.49 60.11,82.7 60.36,82.7 62.42,80.64 72.99,80.64 75,82.65 v2(76.24,82.65)
M_A_BG1: length 84.4
  TOP w0.175: v1(3.67,85.83) 3.61,85.78 J7.113 ; U43.CD35 v2(79.71,81.79)
  SIG2 w0.163: v1(3.67,85.83) 4.11,85.39 49.8,85.39 52.87,82.32 53.12,82.32 53.33,82.53 53.33,82.78 52.24,83.87 52.24,84.1 52.47,84.33 52.7,84.33 54.71,82.32 58.49,82.32 58.65,82.49 58.65,82.7 58.82,82.86 59.14,82.86 59.3,82.7 59.3,82.49 59.47,82.32 75.13,82.32 75.26,82.2 79.3,82.2 v2(79.71,81.79)
M_A_CKE0: length 81.9
  TOP w0.175: v1(5.19,85.83) 4.25,86.78 J7.109 ; U43.CD32 v2(79.71,83.51)
  SIG3 w0.163: v2(79.71,83.51) 79.29,83.93 74.73,83.93 72.54,81.74 62.87,81.74 58.85,85.76 57.89,85.76 56.8,86.84 6.2,86.84 v1(5.19,85.83)
M_A_CKE1: length 81.3
  TOP w0.175: v1(7.75,85.83) 8.44,86.53 J7.110 ; U43.CG32 v2(78.72,83.51)
  SIG3 w0.163: v2(78.72,83.51) 78.31,83.11 74.68,83.11 72.76,81.19 62.64,81.19 59.29,84.54 59.03,84.54 58.83,84.34 58.83,84.09 59.65,83.26 59.65,83.01 59.44,82.8 59.19,82.8 55.7,86.29 8.21,86.29 v1(7.75,85.83)
M_A_CLK_DN0: length 86.6
  TOP w0.175: v1(5.19,80.04) 5.1,79.95 5.1,79.43 4.75,79.07 3.55,79.07 3.35,79.28 J7.139 ; U43.CJ47 v2(77.73,76.64)
  SIG3 w0.089: v2(77.73,76.64) 77.4,76.64 77.32,76.72 arc(77.32,76.73) 77.32,76.74 arc(77.22,76.98) 77.03,77.15 arc(76.74,77.23) 76.44,77.15 arc(76.25,77.1) 76.06,77.14 75.86,77.35 75.39,77.35 75.35,77.39 75.32,77.39
  SIG3 w0.163: v1(5.19,80.04) 4.99,79.84 4.99,79.5 5.41,79.07 6.58,79.07 7.1,79.59 9.44,79.59 10.87,81.03 26.91,81.03 28,82.12 47.36,82.12 48.23,81.25 48.23,80.69 48.39,80.52 48.94,80.52 49.1,80.69 49.1,81.25 49.44,81.59 50.19,81.59 50.53,81.25 50.53,80.69 50.69,80.52 51.24,80.52 51.4,80.69 51.4,81.25 51.74,81.59 52.49,81.59 52.83,81.25 52.83,80.69 52.92,80.6 53.68,80.6 57.24,77.04 63.29,77.04 65.16,75.16 72.76,75.16 74.98,77.39 75.32,77.39
M_A_CLK_DP0: length 86.6
  TOP w0.175: J7.137 3.27,79.78 3.67,79.38 4.62,79.38 4.8,79.55 4.8,79.86 4.62,80.04 v1(4.43,80.04) ; U43.CL47 v2(76.74,76.64)
  SIG3 w0.089: v2(76.74,76.64) 77.07,76.64 77.13,76.71 arc(77.07,76.87) 76.94,76.99 arc(76.74,77.04) 76.54,76.99 arc(76.24,76.91) 75.95,76.99 75.78,77.16 75.39,77.16 75.35,77.11 75.32,77.11
  SIG3 w0.163: v1(4.43,80.04) 4.71,79.76 4.71,79.38 5.3,78.8 6.69,78.8 7.21,79.31 9.55,79.31 10.99,80.75 27.02,80.75 28.12,81.84 47.24,81.84 47.95,81.14 47.95,80.57 48.27,80.25 49.05,80.25 49.38,80.57 49.38,81.14 49.56,81.31 50.07,81.31 50.25,81.14 50.25,80.57 50.58,80.25 51.35,80.25 51.68,80.57 51.68,81.14 51.86,81.31 52.37,81.31 52.55,81.14 52.55,80.57 52.8,80.32 53.56,80.32 57.12,76.76 63.18,76.76 65.05,74.89 72.87,74.89 75.1,77.11 75.32,77.11
M_A_CLK_DP2: length 84.2
  TOP w0.175: U43.CF45 v2(79.21,77.5) ; J7.138 7.85,79.53 6.98,78.66 v1(6.98,77.66)
  SIG3 w0.089: v2(79.21,77.5) 79.17,77.46 arc(78.94,77.3) 78.67,77.23 arc(78.54,77.21) 78.42,77.15 arc(78.21,76.95) 78.13,76.66 78.13,76.63 arc(78.07,76.44) 77.93,76.3 arc(77.73,76.24) 77.53,76.3 arc(77.23,76.38) 76.94,76.3 arc(76.74,76.24) 76.54,76.3 arc(76.24,76.38) 75.95,76.3 arc(75.75,76.24) 75.55,76.3 75.5,76.32 75.25,76.32 75.21,76.36 75.19,76.36
  SIG3 w0.163: v1(6.98,77.66) 7.23,77.91 7.23,78.1 7.57,78.44 9.91,78.44 11.07,79.6 43.69,79.6 44.21,79.08 45.33,79.08 45.49,79.24 45.49,79.73 45.83,80.07 46.58,80.07 46.92,79.73 46.92,79.24 47.08,79.08 53.57,79.08 56.76,75.89 62.81,75.89 64.83,73.87 72.45,73.87 74.94,76.36 75.19,76.36
M_A_CS_N0: length 81
  TOP w0.175: v1(5.27,74.07) 4.57,74.78 J7.149 ; v2(76.74,73.21) U43.CL54
  SIG3 w0.163: v2(76.74,73.21) 76.29,72.76 75.29,72.76 72.5,69.97 58.58,69.97 52.95,75.61 41.59,75.61 41.06,76.13 11.55,76.13 10.5,75.08 5.06,75.08 4.88,74.91 4.88,74.46 v1(5.27,74.07)
M_A_CS_N1: length 80.5
  TOP w0.175: J7.157 3.52,72.78 v1(3.67,72.62) ; U43.CJ58 v2(77.73,71.49)
  SIG3 w0.163: v2(77.73,71.49) 77.29,71.05 75.12,71.05 72.63,68.55 58.45,68.55 53,74.01 40.58,74.01 40.05,74.53 11.5,74.53 10.57,73.61 4.66,73.61 v1(3.67,72.62)
M_A_DQ0: length 96.9
  TOP w0.089: U43.BY2 81.26,97.45 81.26,98.53 v1(80.62,99.16)
  TOP w0.109: v1(9.27,112.45) 9.69,112.03 J7.8
  SIG2 w0.107: v1(9.27,112.45) 9.71,112.88 12.06,112.88 12.24,113.06 12.24,113.75 12.42,113.92 12.71,113.92 12.89,113.75 12.89,113.06 13.07,112.88 13.36,112.88 13.54,113.06 13.54,114.99 13.67,115.11 14.06,115.11 14.19,114.99 14.19,113.06 14.37,112.88 14.66,112.88 14.84,113.06 14.84,114.99 14.97,115.11 15.36,115.11 15.49,114.99 15.49,113.06 15.67,112.88 15.96,112.88 16.14,113.06 16.14,114.22 16.27,114.35 16.66,114.35 16.79,114.22 16.79,113.06 16.97,112.88 59.98,112.88 62.92,109.94 75.3,109.94 81.06,104.18 81.06,99.6 v1(80.62,99.16)
M_A_DQ1: length 96.8
  TOP w0.089: U43.BY4 81.45,96.78 81.8,97.14 81.8,97.39 81.58,97.61 81.45,97.75 81.45,100.61 82.32,101.48 v1(82.43,101.48)
  TOP w0.109: v1(3.67,112.45) 3.5,112.28 J7.7
  SIG2 w0.107: v1(82.43,101.48) 82.76,101.48 82.89,101.6 82.89,102.67 82.44,103.11 82.44,104.93 76.03,111.35 63.5,111.35 60.56,114.29 23.45,114.29 20.96,116.78 10.48,116.78 7.06,113.36 4.59,113.36 v1(3.67,112.45)
M_A_DQ2: length 97.2
  TOP w0.089: U43.CD2 79.47,97.26 79.47,98.32 79.41,98.38 79.41,99.13 79.29,99.24 79.29,99.35 79.33,99.39 79.33,99.58 79.29,99.62 79.29,100.06 v1(78.82,100.53)
  TOP w0.109: J7.20 9.53,109.03 v1(9.27,108.76)
  SIG2 w0.107: v1(9.27,108.76) 10.19,109.68 44.88,109.68 45,109.56 45,108.89 44.88,108.76 36.62,108.76 36.5,108.64 36.5,108 36.62,107.87 56.32,107.87 57.45,106.74 73.91,106.74 78.19,102.47 78.19,101.16 v1(78.82,100.53)
M_A_DQ3: length 97.2
  TOP w0.089: U43.CD4 79.47,96.27 79.47,96.77 79.11,97.12 79.11,97.61 79.27,97.78 79.27,98.24 79.1,98.41 79.1,98.6 79.22,98.72 79.22,99.05 79.1,99.16 79.1,99.49 v1(78.82,99.77)
  TOP w0.109: v1(3.67,108.76) 3.66,108.78 J7.21
  SIG2 w0.107: v1(3.67,108.76) 4.41,108.03 9.44,108.03 10.62,109.21 35.73,109.21 35.86,109.09 35.86,108.41 35.73,108.28 30.78,108.28 30.65,108.15 30.65,107.49 30.78,107.37 56.05,107.37 57.15,106.27 73.72,106.27 77.72,102.27 77.72,100.86 v1(78.82,99.77)
M_A_DQ4: length 97
  TOP w0.089: U43.BW1 81.94,98.27 81.83,98.38 81.83,98.68 82.32,99.16 v1(82.43,99.16)
  TOP w0.109: J7.4 8.32,113.03 v1(7.75,112.45)
  SIG2 w0.107: v1(7.75,112.45) 8.65,113.35 10.44,113.35 12.8,115.71 15.78,115.71 15.96,115.54 15.96,115.11 16.08,114.99 16.48,114.99 16.61,115.11 16.61,115.62 16.73,115.75 17.13,115.75 17.26,115.62 17.26,113.53 17.44,113.35 17.73,113.35 17.91,113.53 17.91,115.54 18.09,115.71 18.38,115.71 18.56,115.54 18.56,113.53 18.74,113.35 60.18,113.35 63.12,110.41 75.54,110.41 81.52,104.43 81.52,99.68 82.04,99.16 v1(82.43,99.16)
M_A_DQ5: length 97
  TOP w0.089: v1(82.43,99.95) 82.32,99.95 81.64,99.28 81.64,97.82 81.99,97.47 81.99,96.82 U43.BW3
  TOP w0.109: J7.3 4.37,113.28 v1(5.19,112.45)
  SIG2 w0.107: v1(82.43,99.95) 81.98,100.4 81.98,104.68 75.78,110.88 63.31,110.88 60.37,113.82 23.26,113.82 20.77,116.31 12.74,116.31 11.34,114.92 11.17,114.92 10.88,115.2 10.88,115.38 11.2,115.7 11.2,115.97 11.02,116.16 10.75,116.16 7.32,112.73 5.48,112.73 v1(5.19,112.45)
M_A_DQ6: length 97.3
  TOP w0.089: U43.CC1 79.85,98.11 79.85,98.51 79.83,98.53 79.83,101.81 v1(78.82,102.82)
  TOP w0.109: J7.16 9.01,110.03 v1(7.75,108.76)
  SIG2 w0.107: v1(78.82,102.82) 78.65,102.82 74.26,107.21 57.83,107.21 56.66,108.38 45.89,108.38 45.77,108.51 45.77,109.14 45.89,109.27 52.24,109.27 52.37,109.4 52.37,110.02 52.24,110.15 9.13,110.15 v1(7.75,108.76)
M_A_DQ7: length 96.9
  TOP w0.089: U43.CC3 79.83,96.9 79.83,97.56 79.66,97.73 79.66,98.4 79.62,98.43 79.62,100.48 79.26,100.85 79.26,101.61 v1(78.82,102.06)
  TOP w0.109: J7.17 3.67,109.78 4.15,109.3 4.66,109.3 v1(5.19,108.76)
  SIG2 w0.107: v1(5.19,108.76) 7.05,110.62 56.94,110.62 57.07,110.49 57.07,109.91 56.94,109.78 53.26,109.78 53.13,109.65 53.13,109.14 53.26,109.02 56.82,109.02 58.16,107.68 75.11,107.68 79.26,103.52 79.26,102.5 v1(78.82,102.06)
M_A_DQ8: length 88.4
  TOP w0.109: U43.CC7 v2(79.21,94.67) ; v1(9.27,107.42) 9.67,107.03 J7.28
  SIG3 w0.089: v2(79.21,94.67) 79.87,95.32 79.87,95.73 79.58,96.01
  SIG3 w0.107: 79.58,96.01 78.56,97.04 73.13,97.04 66.9,103.27 55.84,103.27 55.29,103.81 55.29,107.73 55.16,107.86 54.78,107.86 54.66,107.73 54.66,105.59 54.53,105.46 54.15,105.46 54.02,105.59 54.02,107.73 53.89,107.86 53.51,107.86 53.39,107.73 53.39,106.6 53.26,106.48 52.88,106.48 52.75,106.6 52.75,107.73 52.62,107.86 9.71,107.86 v1(9.27,107.42)
M_A_DQ9: length 88.4
  TOP w0.109: U43.CB9 v2(80.7,93.81) ; v1(5.19,107.42) 5.19,107.45 4.52,106.78 J7.29
  SIG3 w0.089: 80.69,96.38 80.84,96.22 80.84,95.07 80.7,94.93 v2(80.7,93.81)
  SIG3 w0.107: v1(5.19,107.42) 5.19,107.46 5.65,107.92 6.95,107.92 7.31,108.28 7.31,109.02 7.51,109.23 55.84,109.23 60.87,104.2 67.29,104.2 70.33,101.16 72.71,101.16 75.9,97.97 79.09,97.97 80.69,96.38
M_A_DQ10: length 88.1
  TOP w0.109: v1(3.67,103.76) 3.66,103.78 J7.41 ; U43.CM7 v2(76.24,94.67)
  SIG3 w0.107: v2(76.24,94.67) 75.74,95.17 71.75,95.17 65.38,101.55 54.83,101.55 50.53,105.85 50.35,105.85 50.07,105.57 50.07,105.39 52.66,102.8 52.66,102.55 52.45,102.34 52.2,102.34 48.94,105.6 8.57,105.6 7.57,104.6 4.51,104.6 v1(3.67,103.76)
M_A_DQ11: length 88.4
  TOP w0.109: J7.42 9.51,103.53 v1(9.27,103.76) ; U43.CL9 v2(76.74,93.81)
  SIG3 w0.107: v1(9.27,103.76) 10.17,104.67 45.26,104.67 45.39,104.54 45.39,104.19 45.26,104.06 44.37,104.06 44.24,103.94 44.24,103.56 44.37,103.43 46.06,103.43 46.31,103.18 49,100.49 49.18,100.49 49.46,100.77 49.46,100.95 46.34,104.07 46.34,104.25 46.62,104.53 46.8,104.53 50.81,100.52 50.99,100.52 51.27,100.8 51.27,100.98 51.07,101.18 51.07,101.36 51.35,101.64 51.53,101.64 52.66,100.51 64.1,100.51 69.44,95.17 70.15,95.17 71.29,94.03 74.96,94.03 75.23,93.76 76.68,93.76 v2(76.74,93.81)
M_A_DQ12: length 88.4
  TOP w0.109: J7.24 8.35,108.03 v1(7.75,107.42) ; U43.CA7 v2(80.2,94.67)
  SIG3 w0.089: v2(80.2,94.67) 80.06,94.82 80.06,96.06
  SIG3 w0.107: 80.06,96.06 80.06,96.25 78.8,97.5 73.33,97.5 67.1,103.73 57.32,103.73 57.2,103.86 57.2,105.33 57.07,105.46 56.69,105.46 56.56,105.33 56.56,103.94 56.43,103.81 56.05,103.81 55.93,103.94 55.93,108 55.6,108.33 8.65,108.33 v1(7.75,107.42)
M_A_DQ13: length 88.1
  TOP w0.109: v1(3.67,107.42) 3.32,107.78 J7.25 ; v2(81.19,94.67) U43.BY9
  SIG3 w0.089: 81.07,96.71 81.07,94.79 v2(81.19,94.67)
  SIG3 w0.107: v1(3.67,107.42) 3.67,107.85 3.89,108.07 5.12,108.07 6.74,109.69 56.14,109.69 61.16,104.67 67.49,104.67 70.53,101.63 73.01,101.63 76.2,98.44 79.34,98.44 81.07,96.71
M_A_DQ14: length 88.2
  TOP w0.109: U43.CK7 v2(77.23,94.67) ; v1(7.75,103.76) 8.51,104.53 J7.38
  SIG3 w0.107: v1(7.75,103.76) 9.12,105.14 46.88,105.14 50.33,101.69 50.5,101.69 50.79,101.97 50.79,102.15 48.3,104.64 48.3,104.82 48.58,105.1 48.76,105.1 52.87,100.98 53.05,100.98 53.33,101.26 53.33,101.44 53.07,101.7 53.07,101.95 53.28,102.16 53.53,102.16 54.68,101.02 64.4,101.02 69.69,95.73 70.38,95.73 71.44,94.67 75.68,94.67 76.07,94.27 76.83,94.27 v2(77.23,94.67)
M_A_DQ15: length 88.2
  TOP w0.109: U43.CJ9 v2(77.73,93.81) ; J7.37 4.18,104.78 v1(5.19,103.76)
  SIG3 w0.107: v1(5.19,103.76) 5.76,103.2 10.26,103.2 11.25,104.2 42.79,104.2 46.99,100 47.17,100 47.45,100.28 47.45,100.46 45.47,102.44 45.47,102.62 45.75,102.9 45.93,102.9 48.83,100 63.82,100 69.21,94.61 69.92,94.61 71.12,93.4 77.32,93.4 v2(77.73,93.81)
M_A_DQ16: length 88.3
  TOP w0.109: U43.CB13 v2(79.71,92.1) ; v1(7.75,102.75) 8.97,101.53 J7.50
  SIG2 w0.089: v2(79.71,92.1) 79.54,91.81 79.45,91.79 arc(79.35,91.92) 79.31,92.08 79.31,92.12 arc(79.22,92.4) 79.01,92.61 arc(78.87,92.75) 78.81,92.94 78.81,92.98 arc(78.73,93.26) 78.52,93.47 arc(78.32,93.81) 78.52,94.16 arc(78.73,94.36) 78.81,94.64 78.81,95.04 79.07,95.29 79.07,95.99
  SIG2 w0.107: v1(7.75,102.75) 8.2,102.3 10.3,102.3 10.85,102.85 30.38,102.85 30.91,103.38 69.69,103.38 70.95,102.12 70.95,101.94 70.62,101.61 70.44,101.61 69.92,102.13 69.74,102.13 69.34,101.73 69.34,101.55 72.79,98.1 73.86,98.1 74.43,97.53 77.94,97.53 79.07,96.41 79.07,95.99
M_A_DQ17: length 88
  TOP w0.109: U43.CC14 v2(79.21,91.24) ; v1(5.19,102.75) 4.22,101.78 J7.49
  SIG2 w0.089: v2(79.21,91.24) 79.38,91.52 79.35,91.63 arc(79.18,91.82) 79.12,92.07 79.12,92.11 arc(79.06,92.3) 78.92,92.44 arc(78.71,92.65) 78.62,92.93 78.62,92.97 arc(78.57,93.16) 78.42,93.3 arc(78.13,93.81) 78.42,94.32 arc(78.56,94.46) 78.62,94.65 78.62,95.11 78.88,95.37 78.88,95.82 78.69,96.01
  SIG2 w0.107: v1(5.19,102.75) 5.2,102.75 7.09,102.75 8,101.83 10.49,101.83 11.05,102.38 31.03,102.38 31.16,102.51 31.16,102.79 31.26,102.9 31.82,102.9 31.92,102.79 31.92,102.29 32.05,102.16 32.43,102.16 32.56,102.29 32.56,102.79 32.66,102.9 67.33,102.9 72.63,97.59 73.49,97.59 74.17,96.91 77.79,96.91 78.69,96.01
M_A_DQ18: length 88.2
  TOP w0.109: v1(9.27,98.26) 9.53,98.53 J7.62 ; U43.CL13 v2(76.74,92.1)
  SIG2 w0.107: v2(76.74,92.1) 76.38,92.45 76.09,92.45 74.12,94.42 73.41,94.42 72.68,95.16 70.87,95.16 70.75,95.28 69.92,95.28 67.17,98.03 65.22,98.03 64.89,97.7 61.4,97.7 61.23,97.87 61.23,99.45 61.05,99.62 60.75,99.62 60.58,99.45 60.58,97.87 60.4,97.7 60.1,97.7 59.92,97.87 59.92,99.45 59.75,99.62 59.45,99.62 59.27,99.45 59.27,97.87 59.1,97.7 58.8,97.7 58.62,97.87 58.62,99.45 58.45,99.62 58.15,99.62 57.97,99.45 57.97,97.87 57.8,97.7 57.5,97.7 57.32,97.87 57.32,99.45 57.15,99.62 56.85,99.62 56.67,99.45 56.67,98.03 56.5,97.85 56.2,97.85 56.02,98.03 56.02,99.45 55.82,99.65 9.98,99.65 9.27,98.94 v1(9.27,98.26)
M_A_DQ19: length 87.9
  TOP w0.109: U43.CM14 v2(76.24,91.24) ; J7.63 3.66,98.28 v1(3.67,98.26)
  SIG2 w0.107: v2(76.24,91.24) 75.29,91.24 73.9,92.63 70.28,92.63 70.15,92.76 70.15,93.4 70.02,93.52 69.52,93.52 69.39,93.4 69.39,92.89 69.01,92.51 68.37,92.51 64.49,96.39 52.21,96.39 52.03,96.57 52.03,98.51 51.85,98.69 51.56,98.69 51.38,98.51 51.38,96.57 51.2,96.39 50.91,96.39 50.73,96.57 50.73,98.51 50.55,98.69 50.26,98.69 50.08,98.51 50.08,97.52 49.9,97.34 49.61,97.34 49.43,97.52 49.43,98.51 49.22,98.71 14.39,98.71 13.03,97.36 3.96,97.36 3.67,97.65 v1(3.67,98.26)
M_A_DQ20: length 88
  TOP w0.109: v1(9.27,102.75) 9.49,102.53 J7.46 ; U43.BY13 v2(80.7,92.1)
  SIG2 w0.089: v2(80.7,92.1) 80.86,91.81 80.95,91.79 arc(81.06,91.92) 81.1,92.09 81.1,92.1 arc(81.04,92.3) 80.9,92.44 arc(80.69,92.65) 80.6,92.93 80.6,92.97 arc(80.55,93.16) 80.4,93.3 arc(80.19,93.51) 80.11,93.79 80.11,93.82 arc(80.05,94.02) 79.91,94.16 arc(79.69,94.37) 79.61,94.66 79.61,95.09 79.87,95.34 79.87,95.79 79.54,96.12 79.54,96.28
  SIG2 w0.107: 79.54,96.28 79.54,96.59 78.08,98.06 75.69,98.06 69.89,103.86 30.14,103.86 30.02,103.73 30.02,103.45 29.89,103.33 29.51,103.33 29.38,103.45 29.38,103.73 29.26,103.86 28.88,103.86 28.75,103.73 28.75,103.45 28.62,103.33 28.24,103.33 28.11,103.45 28.11,103.73 27.99,103.86 27.61,103.86 27.48,103.73 27.48,103.45 27.35,103.33 26.97,103.33 26.84,103.45 26.84,103.73 26.72,103.86 26.34,103.86 26.21,103.73 26.21,103.45 26.08,103.32 24.56,103.32 24.43,103.45 24.43,103.71 24.3,103.84 23.92,103.84 23.8,103.71 23.8,103.45 23.67,103.32 20.49,103.32 20.37,103.45 20.37,103.71 20.24,103.84 19.86,103.84 19.73,103.71 19.73,103.45 19.6,103.32 16.43,103.32 16.3,103.45 16.3,103.71 16.18,103.84 15.79,103.84 15.67,103.71 15.67,103.45 15.54,103.32 13.38,103.32 13.25,103.45 13.25,103.71 13.13,103.84 12.75,103.84 12.62,103.71 12.62,103.45 12.49,103.32 10.84,103.32 10.71,103.45 10.71,103.71 10.59,103.84 10.21,103.84 10.08,103.71 10.08,103.45 9.95,103.32 9.59,103.32 9.27,103 v1(9.27,102.75)
M_A_DQ21: length 88.2
  TOP w0.109: J7.45 3.64,102.78 v1(3.67,102.75) ; U43.CA14 v2(81.19,91.24)
  SIG2 w0.089: v2(81.19,91.24) 81.03,91.52 81.06,91.63 arc(81.22,91.83) 81.29,92.08 81.29,92.11 arc(81.21,92.4) 80.99,92.61 arc(80.85,92.75) 80.79,92.94 80.79,92.98 arc(80.71,93.26) 80.5,93.47 arc(80.35,93.61) 80.3,93.8 80.3,93.83 arc(80.21,94.12) 80,94.32 80,94.33 arc(79.85,94.48) 79.8,94.67 79.8,95.01 80.06,95.26 80.06,96.23
  SIG2 w0.107: v1(3.67,102.75) 4.13,103.21 6.02,103.21 7.03,103.81 7.54,104.32 70.09,104.32 75.83,98.57 78.22,98.57 80.06,96.74 80.06,96.23
M_A_DQ22: length 87.8
  TOP w0.109: U43.CJ13 v2(77.73,92.1) ; J7.58 9.01,99.53 v1(7.75,98.26)
  SIG2 w0.089: 75.91,94.45 76.19,94.18 arc(76.29,94.02) 76.34,93.83 76.34,93.8 arc(76.39,93.61) 76.54,93.47 arc(76.75,93.26) 76.83,92.98 76.83,92.94 arc(76.89,92.75) 77.03,92.61 arc(77.39,92.37) v2(77.73,92.1)
  SIG2 w0.107: v1(7.75,98.26) 7.75,98.81 9.05,100.12 61.49,100.12 61.69,99.91 61.69,99.42 61.87,99.25 62.17,99.25 62.34,99.42 62.34,99.91 62.52,100.09 62.82,100.09 62.99,99.91 62.99,98.34 63.17,98.16 63.47,98.16 63.64,98.34 63.64,99.91 63.82,100.09 64.93,100.09 65.1,99.91 65.1,98.67 65.28,98.5 65.58,98.5 65.75,98.67 65.75,99.91 65.93,100.09 66.23,100.09 66.4,99.91 66.4,98.67 66.58,98.5 66.88,98.5 67.05,98.67 67.05,99.18 67.22,99.34 67.61,99.34 71.08,95.87 72.98,95.87 73.51,95.34 74.72,95.34 75.1,94.96 75.4,94.96 75.91,94.45
M_A_DQ23: length 88.1
  TOP w0.109: v1(5.19,98.26) 4.55,98.91 4.25,98.91 3.88,99.28 J7.59 ; U43.CK14 v2(77.23,91.24)
  SIG2 w0.107: v2(77.23,91.24) 76.92,91.24 76.4,91.75 75.54,91.75 73.92,93.37 71.7,93.37 70.35,94.72 69.59,94.72 66.89,97.42 66.01,97.42 65.54,96.95 55.26,96.95 55.1,97.11 55.1,98.99 54.93,99.16 54.61,99.16 54.45,98.99 54.45,97.04 54.27,96.86 53.97,96.86 53.8,97.04 53.8,98.99 53.63,99.16 53.31,99.16 53.15,98.99 53.15,98.03 52.97,97.85 52.67,97.85 52.5,98.03 52.5,98.99 52.31,99.18 14.19,99.18 12.84,97.83 7.16,97.83 6.38,98.6 5.53,98.6 v1(5.19,98.26)
M_A_DQ24: length 86.1
  TOP w0.109: J7.70 9.67,96.53 v1(9.27,96.92) ; U43.CD20 v2(79.71,88.66)
  SIG3 w0.107: v2(79.71,88.66) 79.28,89.09 75.39,89.09 74.4,90.07 66.11,90.07 60.14,96.04 59.96,96.04 59.64,95.71 59.64,95.53 61.54,93.63 61.54,93.38 61.34,93.17 61.08,93.17 58.32,95.94 45,95.94 43.58,97.36 42.34,97.36 42.21,97.49 42.21,97.94 42.08,98.07 41.7,98.07 41.58,97.94 41.58,97.49 41.45,97.36 41.07,97.36 40.94,97.49 40.94,97.94 40.81,98.07 40.43,98.07 40.31,97.94 40.31,97.49 40.18,97.36 39.8,97.36 39.67,97.49 39.67,97.97 39.54,98.1 39.16,98.1 39.04,97.97 39.04,97.49 38.91,97.36 9.71,97.36 v1(9.27,96.92)
M_A_DQ25: length 86.2
  TOP w0.109: J7.71 4.55,96.28 v1(5.19,96.92) ; U43.CB20 v2(80.7,88.66)
  SIG3 w0.107: v1(5.19,96.92) 5.48,96.92 7.28,98.73 26.08,98.73 26.46,98.35 36.11,98.35 36.24,98.48 36.24,98.81 36.37,98.93 36.75,98.93 36.88,98.81 36.88,98.48 37,98.35 37.38,98.35 37.51,98.48 37.51,98.98 37.64,99.11 43.61,99.11 45.51,97.21 62.55,97.21 66.37,93.38 67.41,93.38 69.68,91.11 74.89,91.11 75.18,90.81 78.87,90.81 79.2,90.48 79.2,90.1 79.71,89.59 79.71,89.45 80.5,88.66 v2(80.7,88.66)
M_A_DQ26: length 86.3
  TOP w0.109: J7.83 3.66,93.28 v1(3.67,93.26) ; U43.CD28 v2(79.71,85.23)
  SIG3 w0.089: 75.88,84.69 75.96,84.77 76.24,84.77 arc(76.34,84.76) 76.44,84.72 76.44,84.72 arc(76.74,84.64) 77.03,84.72 arc(77.23,84.77) 77.43,84.72 arc(77.73,84.64) 78.02,84.72 arc(78.22,84.77) 78.42,84.72 arc(78.72,84.64) 79.01,84.72 79.1,84.81 79.29,84.81 v2(79.71,85.23)
  SIG3 w0.107: v1(3.67,93.26) 4.27,92.66 9.45,92.66 10.49,93.7 33.57,93.7 33.7,93.57 33.7,93.14 33.57,93.02 32.3,93.02 32.18,92.89 32.18,92.41 32.3,92.28 56.4,92.28 63.4,85.29 74.76,85.29 75.36,84.69 75.88,84.69
M_A_DQ27: length 86.2
  TOP w0.109: v1(9.27,93.26) 9.51,93.03 J7.84 ; v2(80.7,85.23) U43.CB28
  SIG3 w0.089: v2(80.7,85.23) 80.53,85.51 80.43,85.54 arc(80.17,85.5) 79.91,85.57 arc(79.71,85.63) 79.51,85.57 arc(79.21,85.5) 78.92,85.57 arc(78.72,85.63) 78.52,85.57 arc(78.22,85.5) 77.93,85.57 arc(77.73,85.63) 77.53,85.57 arc(77.23,85.5) 76.94,85.57 arc(76.74,85.63) 76.54,85.57 76.11,85.15 75.51,85.15
  SIG3 w0.107: 75.51,85.15 74.81,85.86 63.49,85.86 56.6,92.75 34.34,92.75 34.21,92.88 34.21,93.27 34.34,93.4 37.89,93.4 38.02,93.52 38.02,94.03 37.88,94.17 10.17,94.17 v1(9.27,93.26)
M_A_DQ28: length 86.2
  TOP w0.109: v1(7.75,96.92) 8.35,97.53 J7.66 ; U43.CF18 v2(79.21,89.52)
  SIG3 w0.107: v2(79.21,89.52) 78.76,89.98 75.39,89.98 74.76,90.6 69.53,90.6 67.21,92.92 66.18,92.92 63.06,96.04 62.81,96.04 62.6,95.83 62.6,95.58 64.58,93.59 64.58,93.41 64.3,93.13 64.12,93.13 60.68,96.57 45.26,96.57 43.23,98.6 38.78,98.6 38.01,97.83 8.65,97.83 v1(7.75,96.92)
M_A_DQ29: length 86.3
  TOP w0.109: J7.67 3.32,97.28 v1(3.67,96.92) ; U43.CC18 v2(80.2,89.52)
  SIG3 w0.107: v2(80.2,89.52) 80.2,90.49 79.71,90.99 79.71,91.37 79.43,91.65 70.67,91.65 68.29,94.03 67.67,94.03 67.49,93.85 66.57,93.85 62.58,97.84 45.77,97.84 43.99,99.62 35.73,99.62 35.61,99.49 35.61,98.98 35.48,98.86 35.1,98.86 34.97,98.98 34.97,99.37 34.84,99.49 34.46,99.49 34.34,99.37 34.34,98.98 34.21,98.86 26.8,98.86 26.46,99.19 6.99,99.19 5.32,97.52 4.27,97.52 v1(3.67,96.92)
M_A_DQ30: length 86.5
  TOP w0.109: J7.79 3.6,94.28 4.18,94.86 v1(4.18,95.57) ; U43.CF26 v2(79.21,86.09)
  SIG3 w0.089: v2(79.21,86.09) 78.84,86.46 78.71,86.46 78.61,86.46 arc(78.35,86.56) 78.09,86.5 arc(77.82,86.44) 77.57,86.54 arc(77.23,86.64) 76.9,86.48 arc(76.79,86.44) 76.68,86.49 arc(76.48,86.63) 76.24,86.68
  SIG3 w0.107: 76.24,86.68 76.24,86.68 75.92,87.01 73.7,87.01 72.81,87.9 62.8,87.9 57.01,93.69 41.45,93.69 41.32,93.81 41.32,94.29 41.45,94.41 42.85,94.41 42.97,94.54 42.97,94.98 42.85,95.1 8.62,95.1 8.33,94.82 4.92,94.82 v1(4.18,95.57)
M_A_DQ31: length 86.3
  TOP w0.109: v1(7.75,93.26) 8.51,94.03 J7.80 ; U43.CC26 v2(80.2,86.09)
  SIG3 w0.089: 75.64,86.17 76.18,85.63 76.32,85.63 76.42,85.73 arc(76.43,85.73) 76.44,85.74 arc(76.74,85.82) 77.03,85.74 arc(77.23,85.69) 77.43,85.74 arc(77.73,85.82) 78.02,85.74 arc(78.22,85.69) 78.42,85.74 arc(78.72,85.82) 79.01,85.74 arc(79.21,85.69) 79.41,85.74 arc(79.71,85.82) 80,85.74 arc(80.17,85.69) 80.34,85.71 80.37,85.8 v2(80.2,86.09)
  SIG3 w0.107: v1(7.75,93.26) 9.12,94.64 40.64,94.64 40.76,94.51 40.76,94.03 40.64,93.9 38.65,93.9 38.53,93.78 38.53,93.35 38.65,93.22 56.82,93.22 62.6,87.43 72.62,87.43 73.56,86.49 75.32,86.49 75.64,86.17
M_A_DQ32: length 87.3
  TOP w0.109: J7.174 9.69,68.53 v1(9.27,68.95) ; U43.CD66 v2(79.71,68.63)
  SIG2 w0.089: 76.25,64.69 76.25,65.3 76.42,65.48 76.54,65.54 arc(76.75,65.75) 76.83,66.03 76.83,66.07 arc(76.89,66.26) 77.03,66.4 arc(77.24,66.61) 77.33,66.89 77.33,66.92 arc(77.38,67.12) 77.53,67.26 arc(77.74,67.47) 77.82,67.75 77.82,67.78 arc(78.03,68.12) 78.42,68.12 arc(78.72,68.04) 79.01,68.12 arc(79.06,68.14) 79.12,68.16 arc(79.46,68.33) v2(79.71,68.63)
  SIG2 w0.107: v1(9.27,68.95) 9.68,69.36 15.45,69.36 15.54,69.27 15.54,69.14 15.67,69.01 16.05,69.01 16.18,69.14 16.18,69.27 16.26,69.36 26.25,69.36 26.92,68.68 43.85,68.68 49.36,63.17 55.8,63.17 55.93,63.04 55.93,62.28 56.05,62.15 56.43,62.15 56.56,62.28 56.56,63.04 56.69,63.17 57.07,63.17 57.2,63.04 57.2,62.28 57.32,62.15 57.7,62.15 57.83,62.28 57.83,63.04 57.96,63.17 58.34,63.17 58.47,63.04 58.47,62.28 58.59,62.15 58.97,62.15 59.1,62.28 59.1,63.04 59.23,63.17 59.61,63.17 59.74,63.04 59.74,62.28 59.86,62.15 60.24,62.15 60.37,62.28 60.37,63.04 60.5,63.17 60.88,63.17 61.01,63.04 61.01,62.28 61.13,62.15 67.73,62.15 68.03,61.85 71.96,61.85 72.39,62.29 73.84,62.29 76.25,64.69
M_A_DQ33: length 87.4
  TOP w0.109: U43.CB66 v2(80.7,68.63) ; J7.173 3.5,68.78 v1(3.67,68.95)
  SIG2 w0.089: v2(80.7,68.63) 80.53,68.92 80.44,68.95 arc(80.17,68.9) 79.91,68.98 arc(79.71,69.03) 79.51,68.98 arc(79.4,68.9) 79.31,68.79 79.07,68.43 arc(79,68.35) 78.92,68.28 arc(78.72,68.23) 78.52,68.28 arc(77.94,68.29) 77.63,67.79 77.63,67.76 arc(77.58,67.57) 77.43,67.43 arc(77.22,67.22) 77.14,66.94 77.14,66.9 arc(77.08,66.71) 76.94,66.57 arc(76.73,66.36) 76.64,66.08 76.64,66.04 arc(76.58,65.85) 76.44,65.71 76.22,65.58 75.99,65.35 75.99,65.04 75.61,64.66
  SIG2 w0.107: 75.61,64.66 75.4,64.45 73.99,64.45 73.36,63.82 73.36,63.14 72.97,62.76 72.2,62.76 71.91,62.47 71.44,62.47 71.17,62.74 61.64,62.74 61.51,62.87 61.51,63.55 61.39,63.68 49.51,63.68 44.02,69.16 27.29,69.16 26.63,69.82 9.47,69.82 9.04,69.38 6.29,69.38 5.31,68.41 4.21,68.41 v1(3.67,68.95)
M_A_DQ34: length 87.4
  TOP w0.109: U43.CD72 v2(79.71,65.2) ; v1(3.67,65.26) 3.66,65.28 J7.187
  SIG2 w0.107: v1(3.67,65.26) 4.46,64.48 5.93,64.48 8.1,66.65 42.74,66.65 48.51,60.88 51.23,60.88 51.35,60.76 51.35,59.74 51.48,59.61 51.86,59.61 51.99,59.74 51.99,60.76 52.12,60.88 52.5,60.88 52.62,60.76 52.62,59.74 52.75,59.61 74.4,59.61 78.94,64.16 78.94,64.43 v2(79.71,65.2)
M_A_DQ35: length 87.3
  TOP w0.109: U43.CB72 v2(80.7,65.2) ; v1(9.27,65.26) 9.53,65.53 J7.186
  SIG2 w0.107: v2(80.7,65.2) 80.06,64.55 80.06,63.68 78.89,62.51 78.89,60.29 77.19,58.6 49.47,58.6 43.42,64.65 24.7,64.65 24.53,64.81 24.53,65.55 24.37,65.71 24.05,65.71 23.88,65.55 23.88,64.81 23.72,64.65 16.27,64.65 16.11,64.81 16.11,65.55 15.94,65.71 15.62,65.71 15.46,65.55 15.46,64.81 15.29,64.65 13.4,64.65 13.24,64.81 13.24,65.46 13.11,65.58 12.71,65.58 12.58,65.46 12.58,64.81 12.42,64.65 11.25,64.65 11.09,64.81 11.09,65.46 10.96,65.58 10.56,65.58 10.44,65.46 10.44,64.83 10.26,64.65 9.74,64.65 9.27,65.12 v1(9.27,65.26)
M_A_DQ36: length 87.4
  TOP w0.109: J7.170 9.39,69.53 v1(8.62,70.29) ; U43.CF64 v2(79.21,69.49)
  SIG2 w0.089: 75.2,66.01 75.51,66.31 76.1,67.23 76.44,67.43 arc(76.58,67.57) 76.64,67.76 76.64,67.79 arc(76.73,68.08) 76.94,68.28 arc(77.08,68.43) 77.14,68.62 77.14,68.65 arc(77.44,69.15) 78.02,69.14 arc(78.22,69.09) 78.42,69.14 arc(78.81,69.34) v2(79.21,69.49)
  SIG2 w0.107: v1(8.62,70.29) 9.07,70.75 27.09,70.75 27.71,70.13 44.38,70.13 49.82,64.69 56.69,64.69 56.82,64.82 56.82,64.95 56.94,65.08 57.32,65.08 57.45,64.95 57.45,64.82 57.58,64.69 57.96,64.69 58.09,64.82 58.09,64.95 58.21,65.08 58.59,65.08 58.72,64.95 58.72,64.82 58.85,64.69 59.23,64.69 59.36,64.82 59.36,64.95 59.48,65.08 59.86,65.08 59.99,64.95 59.99,64.82 60.12,64.69 60.5,64.69 60.63,64.82 60.63,64.95 60.75,65.08 61.13,65.08 61.26,64.95 61.26,64.82 61.39,64.69 61.77,64.69 61.9,64.82 61.9,64.95 62.02,65.08 62.4,65.08 62.53,64.95 62.53,64.44 62.66,64.31 63.04,64.31 63.17,64.44 63.17,64.95 63.29,65.08 63.67,65.08 63.8,64.95 63.8,63.81 63.93,63.68 64.31,63.68 64.44,63.81 64.44,64.92 64.56,65.05 64.94,65.05 65.07,64.92 65.07,63.8 65.2,63.67 71.44,63.67 73.78,66.01 73.78,66.7 73.9,66.83 74.21,66.83 74.34,66.7 74.34,66.13 74.47,66.01 75.2,66.01
M_A_DQ37: length 87.1
  TOP w0.109: U43.CC64 v2(80.2,69.49) ; J7.169 4.37,69.78 v1(5.19,68.95)
  SIG2 w0.089: 75.35,65.82 75.99,66.47 76.36,67.16 76.54,67.26 arc(76.75,67.47) 76.83,67.75 76.83,67.78 arc(76.89,67.98) 77.03,68.12 arc(77.24,68.33) 77.33,68.61 77.33,68.64 arc(77.53,68.98) 77.93,68.98 arc(78.22,68.9) 78.52,68.98 arc(78.64,69.03) 78.76,69.04 arc(78.87,69.04) 78.98,69.03 arc(79.16,69.05) 79.33,69.1 arc(79.37,69.12) 79.41,69.14 arc(79.71,69.22) 80,69.14 arc(80.17,69.09) 80.35,69.12 80.37,69.2 v2(80.2,69.49)
  SIG2 w0.107: v1(5.19,68.95) 6.1,69.85 8.84,69.85 9.27,70.28 26.89,70.28 27.53,69.65 44.2,69.65 49.66,64.19 61.9,64.19 62.02,64.06 62.02,63.35 62.15,63.22 62.53,63.22 62.66,63.35 62.66,63.68 62.78,63.81 63.17,63.81 63.29,63.68 63.29,63.33 63.42,63.21 71.64,63.21 73.52,65.08 74.61,65.08 75.35,65.82
M_A_DQ38: length 87
  TOP w0.109: v1(5.19,65.26) 4.18,66.28 J7.183 ; U43.CF71 v2(79.21,66.05)
  SIG2 w0.107: v1(5.19,65.26) 7.05,67.12 42.94,67.12 48.66,61.39 53.01,61.39 53.13,61.27 53.13,60.26 53.26,60.13 53.77,60.13 53.89,60.26 53.89,61.01 54.02,61.14 54.4,61.14 54.53,61.01 54.53,60.26 54.66,60.13 74.25,60.13 77.96,63.84 77.96,64.73 78.3,65.08 78.3,65.46 78.9,66.05 v2(79.21,66.05)
M_A_DQ39: length 87.4
  TOP w0.109: v1(7.75,65.26) 9.01,66.53 J7.182 ; U43.CC71 v2(80.2,66.05)
  SIG2 w0.089: v2(80.2,66.05) 80.2,65.07 79.85,64.72 79.85,64.14 79.75,64.05
  SIG2 w0.107: v1(7.75,65.26) 8.66,66.18 42.55,66.18 48.35,60.38 49.45,60.38 49.58,60.25 49.58,59.36 49.7,59.23 50.08,59.23 50.21,59.36 50.21,60.25 50.34,60.38 50.72,60.38 50.85,60.25 50.85,59.23 50.97,59.11 77.04,59.11 78.42,60.49 78.42,62.71 79.75,64.05
M_A_DQ40: length 81.8
  TOP w0.109: v1(5.19,63.92) 5.19,63.95 4.52,63.28 J7.195 ; U43.CL66 v2(76.74,68.63)
  SIG3 w0.107: v1(5.19,63.92) 5.66,63.92 7.46,65.73 42.85,65.73 42.97,65.6 42.97,65.08 43.1,64.95 43.52,64.95 43.65,65.08 43.65,66.22 43.78,66.35 44.17,66.35 44.3,66.22 44.3,64.95 44.43,64.82 44.82,64.82 44.95,64.95 44.95,66.23 45.13,66.41 72.96,66.41 75.48,68.93 76.44,68.93 v2(76.74,68.63)
M_A_DQ41: length 82
  TOP w0.109: v1(9.27,63.92) 9.67,63.53 J7.194 ; U43.CJ66 v2(77.73,68.63)
  SIG3 w0.089: v2(77.73,68.63) 77.1,68 76.26,68 75.74,67.49
  SIG3 w0.107: v1(9.27,63.92) 9.27,64.23 9.4,64.36 41.78,64.36 42.31,63.83 48.59,63.83 48.77,64.01 48.77,65.29 48.95,65.47 49.24,65.47 49.42,65.29 49.42,64.01 49.6,63.83 49.89,63.83 50.07,64.01 50.07,65.29 50.25,65.47 50.54,65.47 50.72,65.29 50.72,64.01 50.9,63.83 51.19,63.83 51.37,64.01 51.37,65.29 51.55,65.47 51.84,65.47 52.02,65.29 52.02,64.37 52.2,64.19 52.49,64.19 52.67,64.37 52.67,65.29 52.85,65.47 71.42,65.47 71.82,65.07 72.89,65.07 75.32,67.49 75.74,67.49
M_A_DQ42: length 82
  TOP w0.109: J7.207 3.66,60.28 v1(3.67,60.26) ; U43.CL72 v2(76.74,65.2)
  SIG3 w0.107: v1(3.67,60.26) 3.67,60.57 4.27,61.17 7.19,61.17 7.66,61.64 38.41,61.64 38.94,61.11 55.33,61.11 55.49,61.27 55.49,63.05 55.65,63.21 55.98,63.21 56.14,63.05 56.14,61.71 56.32,61.53 56.61,61.53 56.79,61.71 56.79,63.05 56.95,63.21 71.49,63.21 71.94,62.76 73.53,62.76 74.99,64.21 75.13,64.21 76.12,65.2 v2(76.74,65.2)
M_A_DQ43: length 81.9
  TOP w0.109: J7.208 9.51,60.03 v1(9.27,60.26) ; U43.CJ72 v2(77.73,65.2)
  SIG3 w0.107: v1(9.27,60.26) 9.71,60.7 37.69,60.7 38.22,60.17 59.92,60.17 60.08,60.34 60.08,62.11 60.24,62.27 60.57,62.27 60.73,62.11 60.73,60.34 60.89,60.17 61.22,60.17 61.38,60.34 61.38,62.11 61.54,62.27 61.87,62.27 62.03,62.11 62.03,61.07 62.21,60.89 62.5,60.89 62.68,61.07 62.68,62.11 62.84,62.27 67.78,62.27 68.72,61.33 73.43,61.33 75.79,63.69 77.67,63.69 77.93,63.94 77.93,65 v2(77.73,65.2)
M_A_DQ44: length 81.9
  TOP w0.109: v1(3.67,63.92) 3.32,64.28 J7.191 ; U43.CM64 v2(76.24,69.49)
  SIG3 w0.107: v1(3.67,63.92) 4.34,64.6 5.67,64.6 7.27,66.19 8.05,66.19 8.21,66.36 8.21,66.68 8.34,66.8 8.74,66.8 8.87,66.68 8.87,66.36 9.03,66.19 9.35,66.19 9.52,66.36 9.52,66.73 9.64,66.85 10.04,66.85 10.17,66.73 10.17,66.36 10.33,66.19 10.65,66.19 10.82,66.36 10.82,66.73 10.94,66.85 11.34,66.85 11.47,66.73 11.47,66.36 11.63,66.19 11.95,66.19 12.12,66.36 12.12,66.73 12.24,66.85 12.64,66.85 12.77,66.73 12.77,66.36 12.93,66.19 13.25,66.19 13.38,66.32 13.38,66.73 13.51,66.85 13.89,66.85 14.02,66.73 14.02,66.32 14.14,66.19 42.82,66.19 43.5,66.87 72.87,66.87 75.7,69.7 76.03,69.7 v2(76.24,69.49)
M_A_DQ45: length 82
  TOP w0.109: J7.190 8.35,64.53 v1(7.75,63.92) ; U43.CK64 v2(77.23,69.49)
  SIG3 w0.089: v2(77.23,69.49) 77.23,68.51 76.91,68.2 76.07,68.2
  SIG3 w0.107: 76.07,68.2 75.75,67.88 75.04,67.88 72.7,65.53 72.02,65.53 71.61,65.94 48.46,65.94 48.3,65.78 48.3,65.26 48.12,65.08 47.83,65.08 47.65,65.26 47.65,65.78 47.49,65.94 47.16,65.94 47,65.78 47,64.46 46.84,64.3 46.51,64.3 46.35,64.46 46.35,65.78 46.19,65.94 45.86,65.94 45.7,65.78 45.7,64.46 45.54,64.3 42.73,64.3 42.21,64.83 8.31,64.83 7.75,64.26 v1(7.75,63.92)
M_A_DQ46: length 81.9
  TOP w0.109: J7.203 3.74,61.28 4.14,61.68 4.14,62.53 v1(4.18,62.57) ; U43.CM71 v2(76.24,66.05)
  SIG3 w0.107: v2(76.24,66.05) 75.6,66.05 73.22,63.68 54.77,63.68 54.61,63.51 54.61,62.09 54.43,61.91 54.14,61.91 53.96,62.09 53.96,62.54 53.83,62.66 53.43,62.66 53.31,62.54 53.31,61.74 53.14,61.58 39.23,61.58 38.71,62.1 7.47,62.1 7,61.63 3.73,61.63 3.6,61.76 3.6,62.44 3.73,62.57 v1(4.18,62.57)
M_A_DQ47: length 81.9
  TOP w0.109: U43.CK71 v2(77.23,66.05) ; J7.204 8.51,61.03 v1(7.75,60.26)
  SIG3 w0.107: v2(77.23,66.05) 77.23,65.12 76.86,64.75 76.33,64.75 75.65,64.08 75.51,64.08 73.73,62.29 71.74,62.29 71.29,62.74 59.25,62.74 59.08,62.58 59.08,60.8 58.92,60.64 58.6,60.64 58.43,60.8 58.43,62.58 58.27,62.74 57.95,62.74 57.78,62.58 57.78,60.8 57.62,60.64 38.53,60.64 38,61.17 8.46,61.17 7.75,60.45 v1(7.75,60.26)
M_A_DQ48: length 98.7
  TOP w0.109: J7.216 9.69,58.03 v1(9.27,58.45) ; U43.BT72 v2(83.67,65.2)
  SIG2 w0.089: 83.11,63.86 83.03,63.94 83.03,64.55 v2(83.67,65.2)
  SIG2 w0.107: 83.11,63.86 83.11,62.29 81.95,61.12 81.95,58.07 77.64,53.77 75.99,53.77 73.8,55.96 46.46,55.96 43.7,58.73 28.24,58.73 28.11,58.85 28.11,59.23 28.24,59.36 33.32,59.36 33.45,59.49 33.45,59.87 33.32,60 27.86,60 26.75,58.88 9.71,58.88 v1(9.27,58.45)
M_A_DQ49: length 98.6
  TOP w0.109: J7.215 3.5,58.28 v1(3.67,58.45) ; U43.BU71 v2(83.18,66.05)
  SIG2 w0.089: v2(83.18,66.05) 83.18,65.06 82.84,64.72 82.84,64.07 82.75,63.99 82.75,63.84
  SIG2 w0.107: v1(3.67,58.45) 3.67,57.99 3.8,57.87 5.27,57.87 6.76,59.35 26.46,59.35 27.61,60.5 35.86,60.5 35.99,60.38 35.99,60 35.86,59.87 34.08,59.87 33.96,59.74 33.96,59.36 34.08,59.23 43.85,59.23 46.65,56.43 74.19,56.43 76.34,54.28 77.49,54.28 81.39,58.18 81.39,61.33 82.63,62.57 82.63,63.26 82.75,63.38 82.75,63.84
M_A_DQ50: length 98.9
  TOP w0.109: v1(9.27,54.82) 9.48,55.03 J7.228 ; U43.BG72 v2(87.63,65.2)
  SIG2 w0.107: v1(9.27,54.82) 9.67,55.21 37.16,55.21 38.52,53.85 41.45,53.85 41.58,53.72 41.58,53.39 41.45,53.26 38.91,53.26 38.78,53.14 38.78,52.83 38.91,52.71 71.86,52.71 74.21,50.35 79.01,50.35 82.89,54.23 83.6,54.23 86.94,57.57 86.94,61.78 87.89,62.72 87.89,63.86 87.79,63.96 87.79,64.54 87.63,64.7 v2(87.63,65.2)
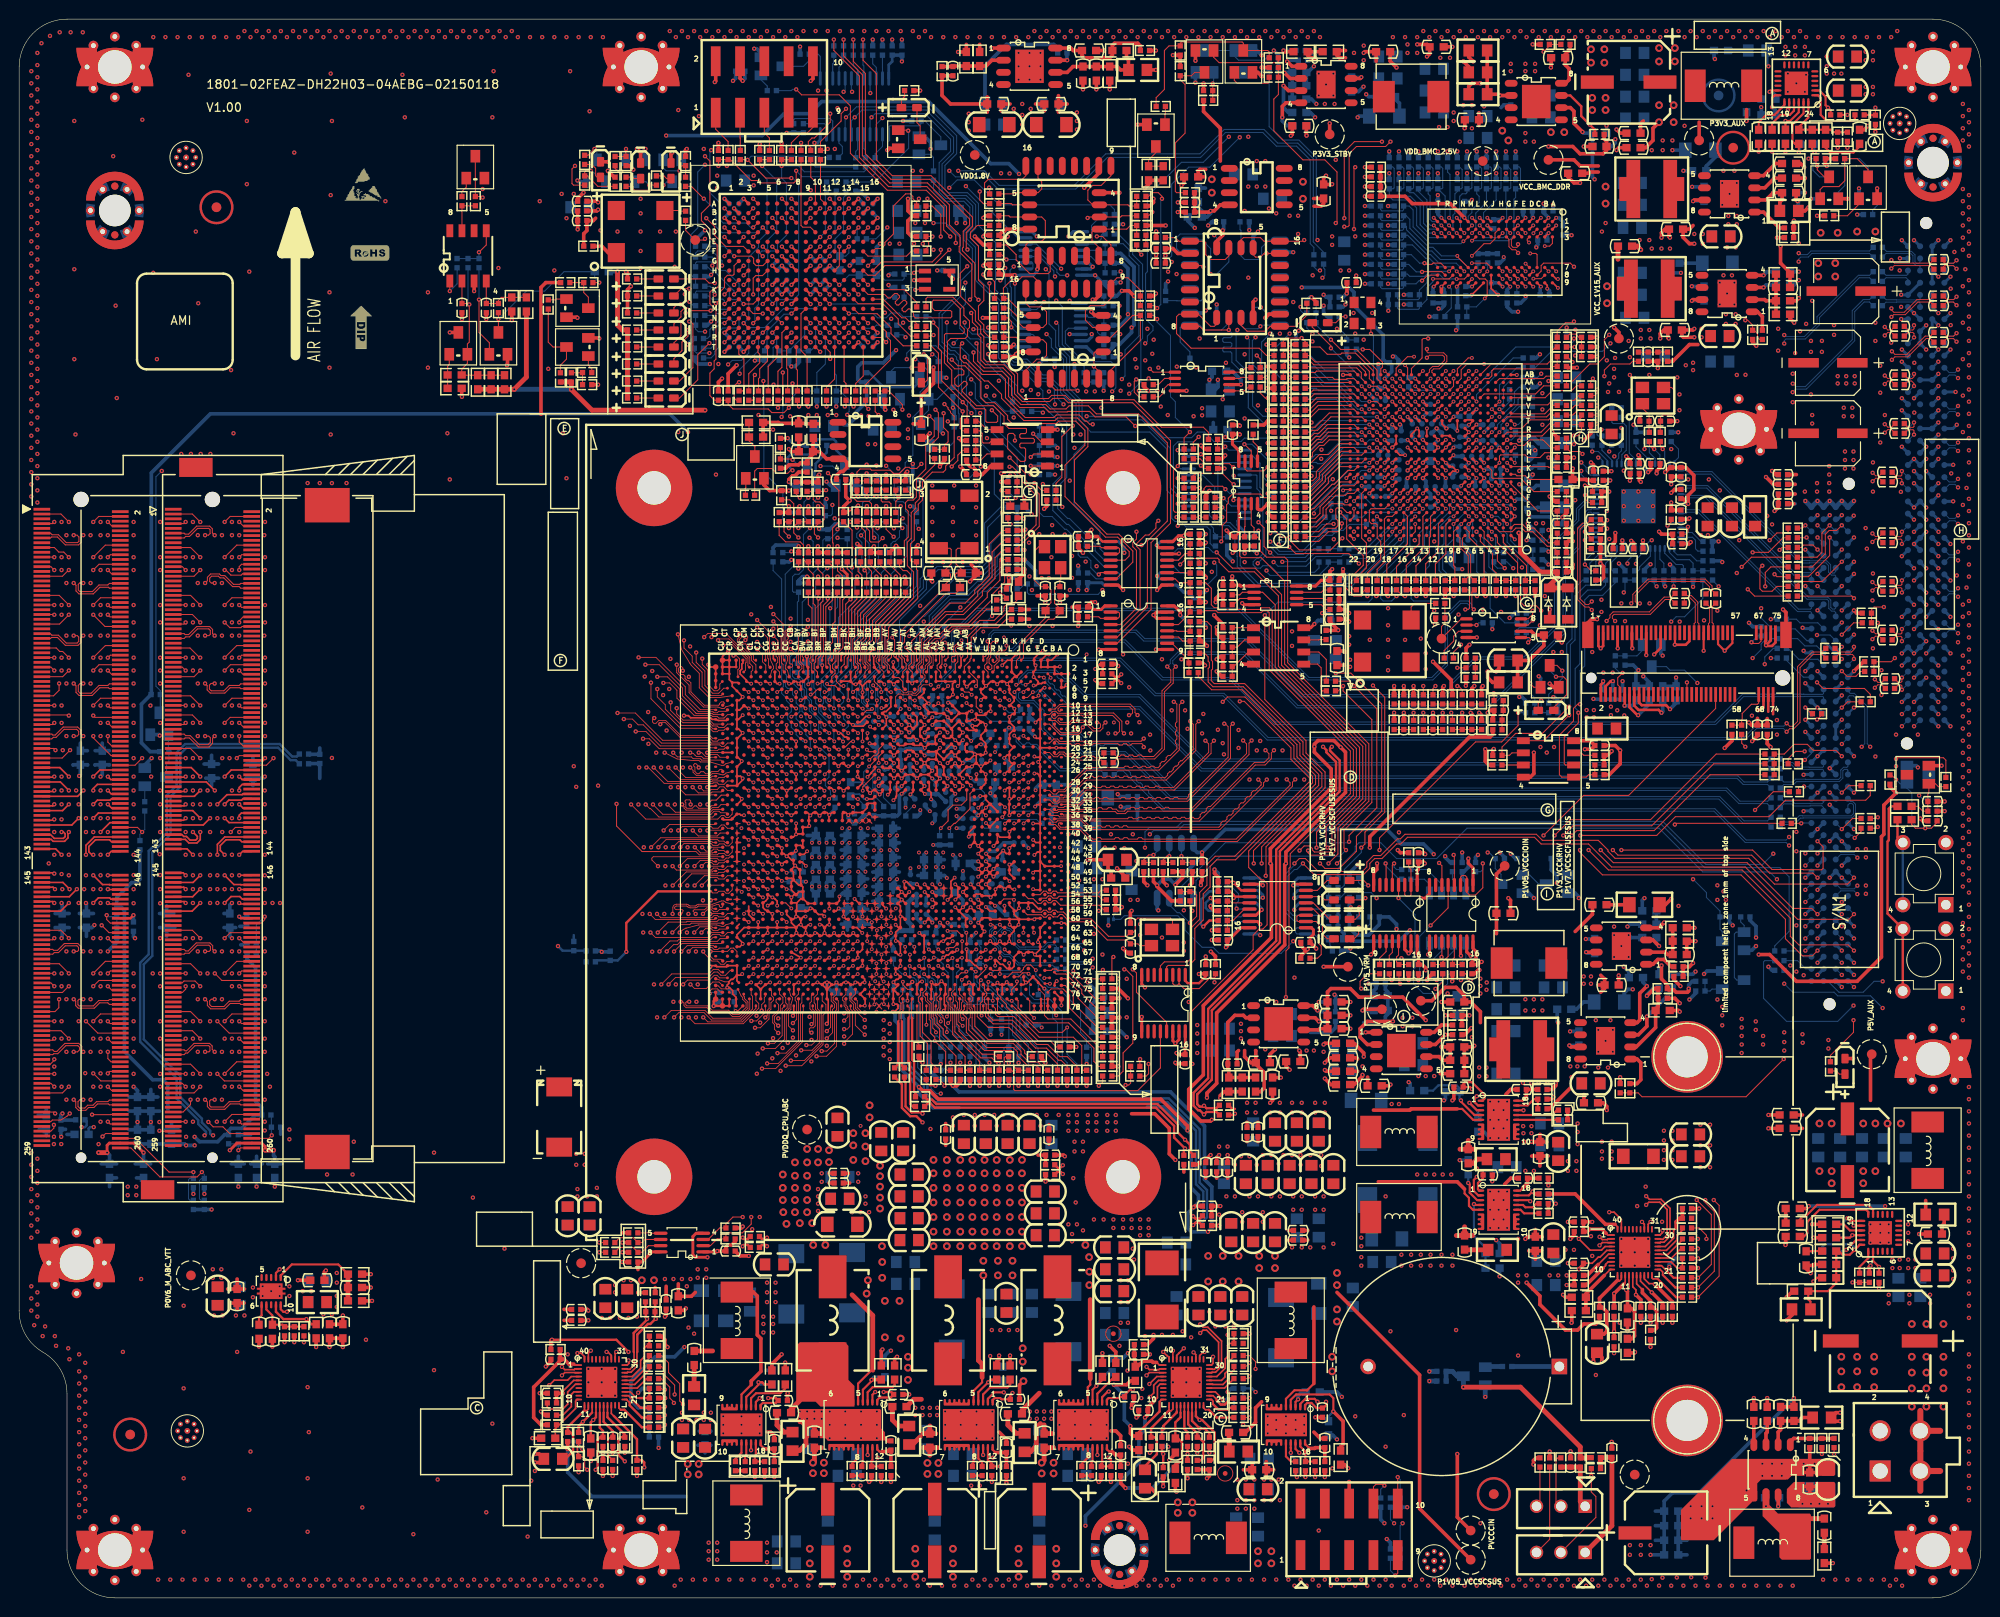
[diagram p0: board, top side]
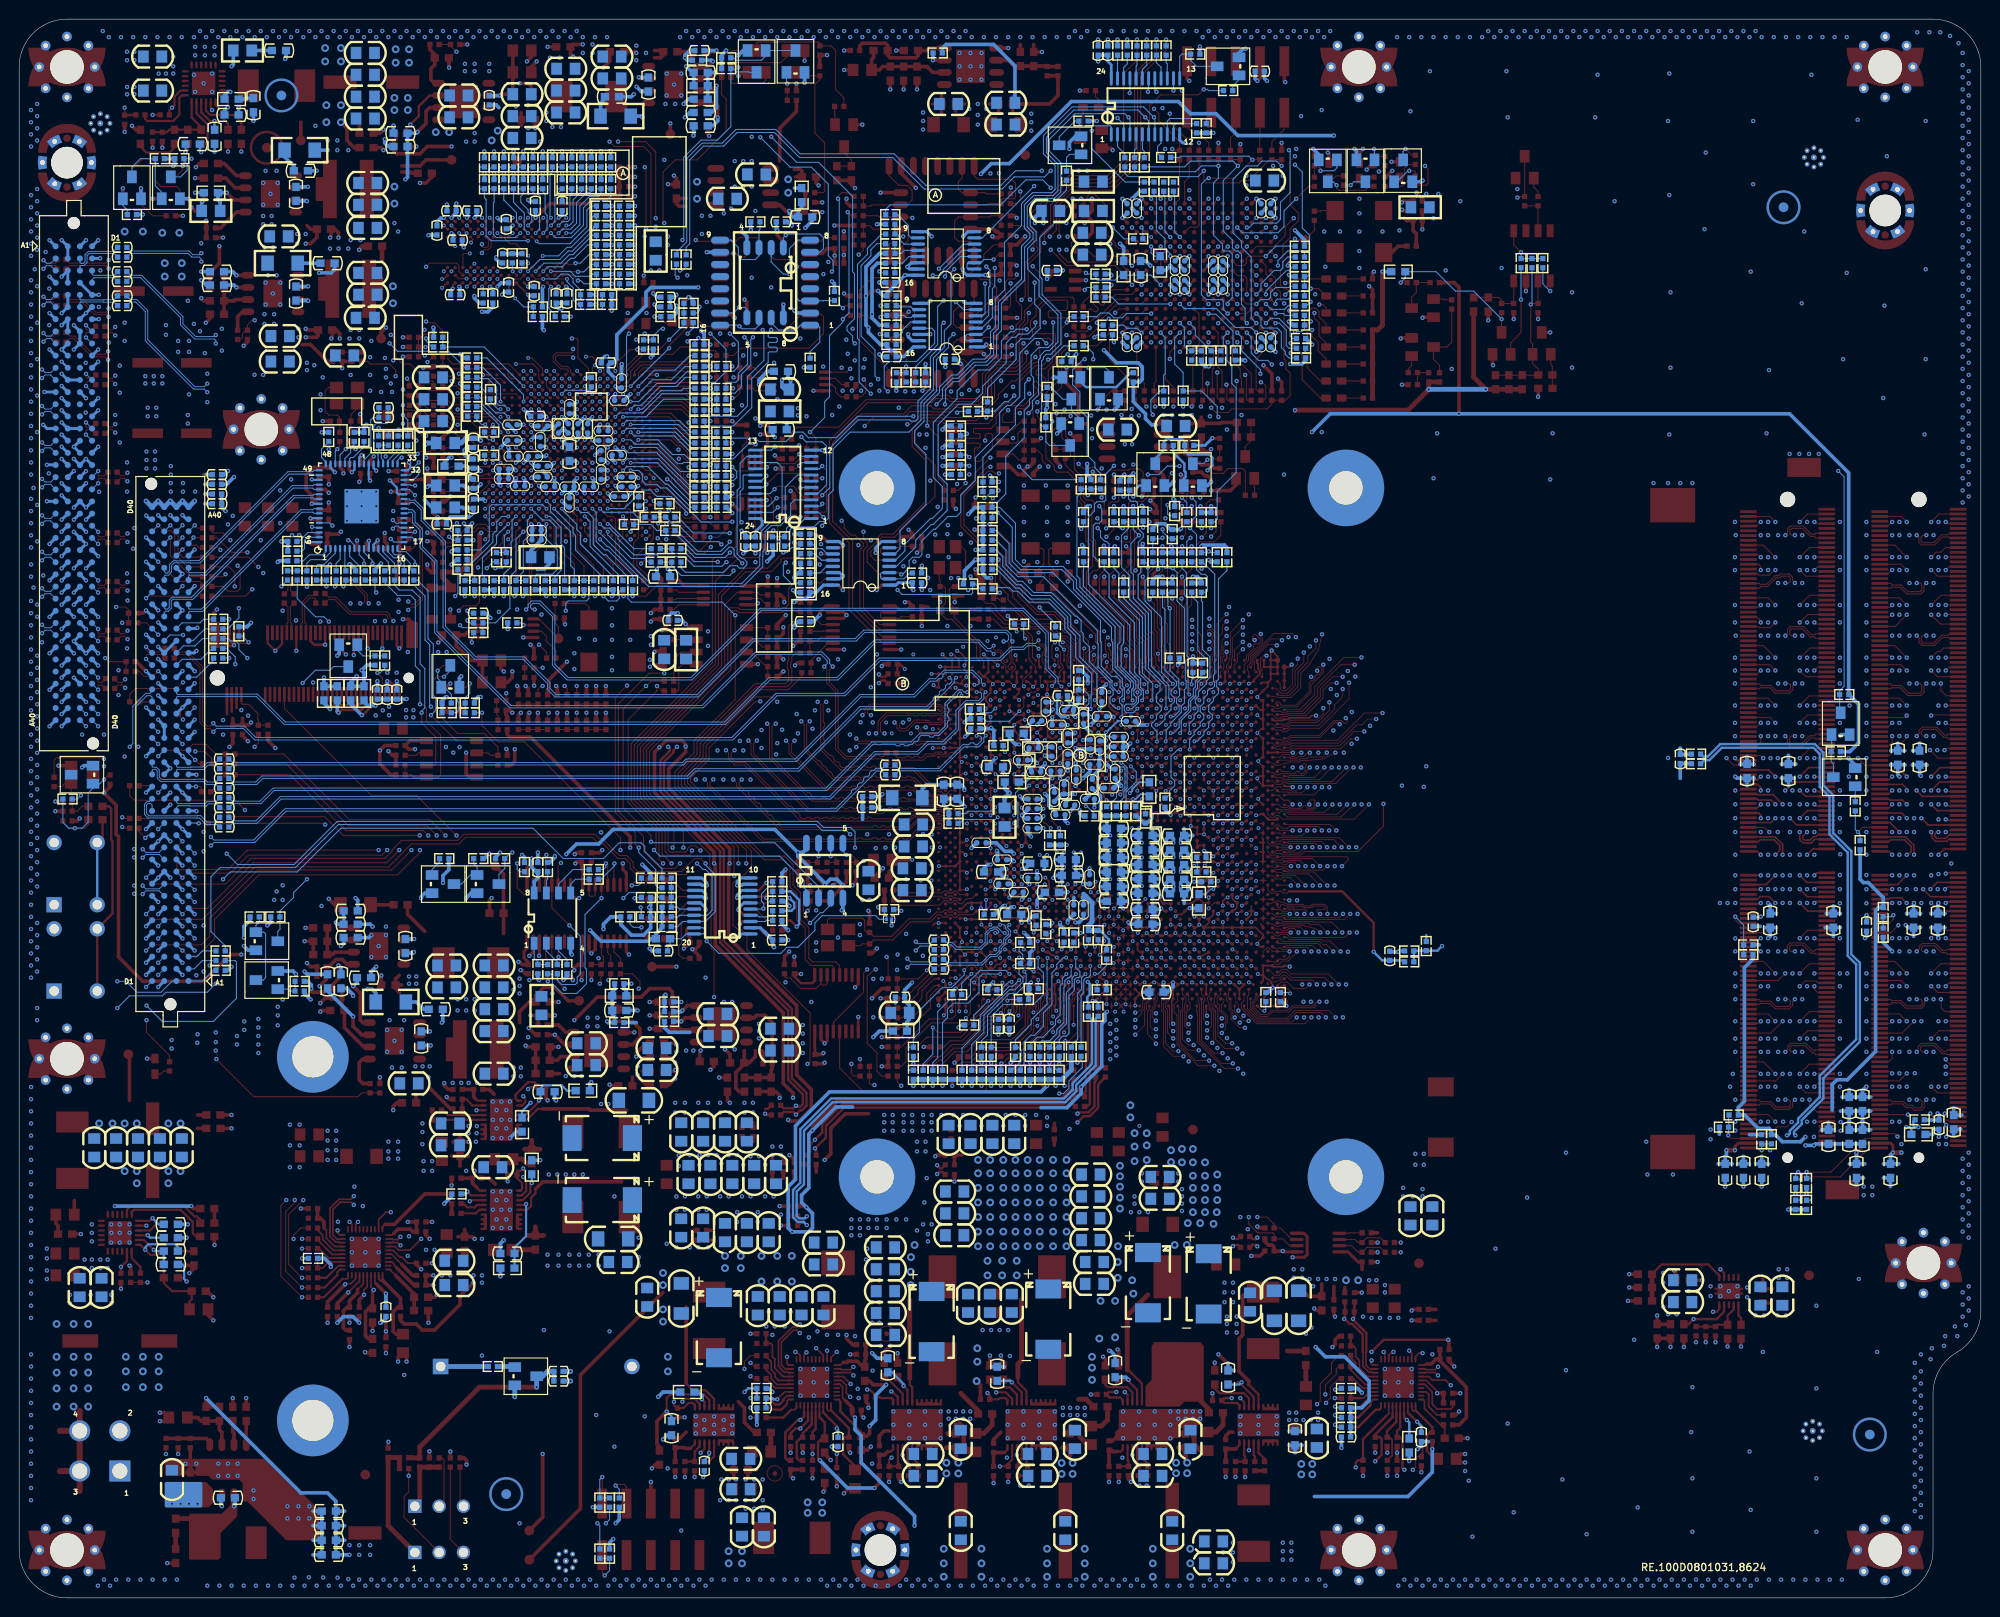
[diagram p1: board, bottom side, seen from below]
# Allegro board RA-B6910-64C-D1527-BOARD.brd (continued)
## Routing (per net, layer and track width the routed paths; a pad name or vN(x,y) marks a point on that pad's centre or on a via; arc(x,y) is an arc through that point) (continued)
M_A_DQ51: length 98.8
  TOP w0.109: U43.BH71 v2(87.14,66.05) ; J7.229 3.66,54.78 v1(3.67,54.76)
  SIG2 w0.089: 87.25,63.8 86.99,64.06 86.99,64.49 87.25,64.75 87.25,65.94 v2(87.14,66.05)
  SIG2 w0.107: 87.25,63.8 87.25,62.74 85.77,61.27 85.77,57.06 83.41,54.7 82.7,54.7 78.82,50.81 74.62,50.81 72.25,53.19 42.8,53.19 41.65,54.33 38.7,54.33 37.35,55.68 6.78,55.68 5.87,54.76 v1(3.67,54.76)
M_A_DQ52: length 98.8
  TOP w0.109: J7.211 4.37,59.28 v1(5.19,58.45) ; U43.BV72 v2(82.68,65.2)
  SIG2 w0.089: 82.12,63.86 82.04,63.94 82.04,64.55 v2(82.68,65.2)
  SIG2 w0.107: v1(5.19,58.45) 6.57,59.82 26.21,59.82 27.4,61.01 40.18,61.01 40.31,60.88 40.31,60.5 40.18,60.38 36.67,60.38 36.55,60.25 36.55,59.87 36.67,59.74 44,59.74 46.84,56.9 74.82,56.9 75.89,55.83 77.52,55.83 80.43,58.73 80.43,61.21 81.97,62.75 81.97,63.25 82.12,63.4 82.12,63.86
M_A_DQ53: length 98.9
  TOP w0.109: J7.212 8.22,59.03 v1(6.98,60.26) ; U43.BW71 v2(82.18,66.05)
  SIG2 w0.089: 81.76,63.84 81.85,63.92 81.85,64.72 82.18,65.06 v2(82.18,66.05)
  SIG2 w0.107: 81.76,63.84 81.45,63.53 81.45,63.03 79.96,61.53 79.96,58.92 77.45,56.41 76,56.41 75.04,57.37 47.04,57.37 44.15,60.25 40.94,60.25 40.81,60.38 40.81,60.76 40.94,60.88 42.85,60.88 42.97,61.01 42.97,61.39 42.85,61.52 27.1,61.52 26.55,60.97 25.15,60.97 25.07,60.89 25.07,60.5 24.94,60.38 24.56,60.38 24.43,60.5 24.43,61.65 24.3,61.77 23.92,61.77 23.8,61.65 23.8,61.1 23.67,60.97 23.29,60.97 23.16,61.1 23.16,61.65 23.03,61.77 22.65,61.77 22.53,61.65 22.53,61.12 22.38,60.97 22.02,60.97 21.89,61.1 21.89,61.52 21.76,61.65 21.38,61.65 21.26,61.52 21.26,61.07 21.16,60.97 7.69,60.97 v1(6.98,60.26)
M_A_DQ54: length 98.7
  TOP w0.109: J7.224 9.61,56.03 9.27,56.36 v1(9.27,57.07) ; U43.BJ72 v2(86.64,65.2)
  SIG2 w0.107: v1(9.27,57.07) 9.72,56.62 42.34,56.62 42.46,56.49 42.46,56.06 42.34,55.93 39.16,55.93 39.04,55.8 39.04,55.42 39.16,55.3 42.24,55.3 43.38,54.15 72.6,54.15 75.01,51.75 78.43,51.75 82.31,55.63 82.97,55.63 84.84,57.5 84.84,61.65 85.92,62.74 85.92,64.61 86.51,65.2 v2(86.64,65.2)
M_A_DQ55: length 98.7
  TOP w0.109: v1(3.67,56.29) 3.67,56.19 3.25,55.78 J7.225 ; U43.BL71 v2(86.15,66.05)
  SIG2 w0.089: v2(86.15,66.05) 86.48,65.72 86.69,65.72 87.02,65.39 87.02,64.91 86.8,64.68 86.8,63.63
  SIG2 w0.107: v1(3.67,56.29) 4.25,55.71 5.83,55.71 6.27,56.15 37.55,56.15 38.88,54.81 41.93,54.81 43.07,53.67 72.43,53.67 74.81,51.28 78.62,51.28 82.5,55.16 83.22,55.16 85.31,57.25 85.31,61.46 86.64,62.79 86.64,63.47 86.8,63.63
M_A_DQ56: length 98.4
  TOP w0.109: U43.BU67 v2(83.18,67.77) ; v1(5.19,53.42) 5.19,53.45 4.52,52.78 J7.237
  SIG3 w0.089: 82.56,63.72 82.56,63.84 82.84,64.12 82.84,64.65 83.08,64.9 83.08,65.22 arc(83.16,65.5) 83.37,65.71 arc(83.58,66.05) 83.37,66.4 83.37,66.41 arc(83.16,66.61) 83.08,66.89 arc(83.1,67.34) v2(83.18,67.77)
  SIG3 w0.107: v1(5.19,53.42) 5.69,53.91 10.93,53.91 11.35,54.33 63.67,54.33 63.8,54.45 63.8,55.17 63.67,55.3 60.24,55.3 60.12,55.42 60.12,56.06 60.24,56.19 71.63,56.19 77.28,61.84 81.06,61.84 82.56,63.33 82.56,63.72
M_A_DQ57: length 98.1
  TOP w0.109: J7.236 9.67,53.03 v1(9.27,53.42) ; U43.BT66 v2(83.67,68.63)
  SIG3 w0.089: 83.03,63.9 83.03,64.57 83.27,64.82 83.27,65.21 arc(83.33,65.4) 83.47,65.54 arc(83.69,65.76) 83.77,66.05 83.77,66.06 arc(83.69,66.35) 83.47,66.57 arc(83.3,66.77) 83.29,67.03 arc(83.38,67.23) 83.54,67.4 arc(83.63,67.52) 83.68,67.66 arc(83.71,68.14) v2(83.67,68.63)
  SIG3 w0.107: v1(9.27,53.42) 9.29,53.45 11.13,53.45 11.54,53.86 70.02,53.86 70.15,53.99 70.15,54.66 70.02,54.79 64.56,54.79 64.44,54.92 64.44,55.55 64.56,55.68 73.61,55.68 78.56,60.63 78.56,60.64 79.29,61.37 81.25,61.37 83.03,63.14 83.03,63.9
M_A_DQ58: length 98.3
  TOP w0.109: J7.249 3.31,49.78 3.48,49.94 4.36,49.94 5,50.34 v1(5.29,50.63) ; U43.BH67 v2(87.14,67.77)
  SIG3 w0.107: v1(5.29,50.63) 6.72,50.63 7.39,49.96 7.92,49.96 8.63,50.67 74.54,50.67 75.87,51.99 78.42,51.99 82.06,55.63 82.97,55.63 85.04,57.7 85.04,61.45 86.82,63.23 86.82,64.45 87.07,64.7 87.07,65.34 87.58,65.85 87.58,66.23 87.2,66.61 87.2,67.71 v2(87.14,67.77)
M_A_DQ59: length 98.4
  TOP w0.109: v1(9.27,49.76) 9.51,49.53 J7.250 ; v2(87.63,68.63) U43.BG66
  SIG3 w0.107: v1(9.27,49.76) 9.71,50.2 77.77,50.2 77.9,50.33 77.9,50.72 77.77,50.85 76.12,50.85 75.99,50.98 75.99,51.36 76.12,51.49 78.58,51.49 82.13,55.04 83.04,55.04 85.51,57.51 85.51,61.26 87.91,63.66 87.91,64.78 88.09,64.96 88.09,65.34 88.5,65.75 88.5,66.32 88.09,66.73 88.09,67.18 87.63,67.64 v2(87.63,68.63)
M_A_DQ60: length 98.4
  TOP w0.109: v1(7.75,54.82) 8.54,54.03 J7.232 ; U43.BW67 v2(82.18,67.77)
  SIG3 w0.089: 81.57,63.88 81.83,64.14 81.83,64.62 82.09,64.88 82.09,65.22 arc(82.17,65.5) 82.38,65.71 arc(82.58,66.05) 82.38,66.4 arc(82.17,66.62) 82.09,66.91 82.09,66.93 arc(82.11,67.36) v2(82.18,67.77)
  SIG3 w0.107: 81.57,63.88 81.57,63.68 80.74,62.85 76.97,62.85 71.32,57.2 49.2,57.2 49.07,57.07 49.07,56.57 49.2,56.44 54.91,56.44 55.04,56.31 55.04,55.82 54.91,55.69 8.62,55.69 v1(7.75,54.82)
M_A_DQ61: length 98.4
  TOP w0.109: v1(3.67,53.42) 3.32,53.78 J7.233 ; U43.BV66 v2(82.68,68.63)
  SIG3 w0.089: 82.04,63.8 82.04,64.53 82.28,64.77 82.28,65.21 arc(82.34,65.4) 82.48,65.54 arc(82.71,65.77) 82.79,66.08 arc(82.71,66.35) 82.5,66.56 82.48,66.57 arc(82.28,66.85) 82.38,67.18 arc(82.53,67.4) 82.61,67.65 arc(82.67,68.14) v2(82.68,68.63)
  SIG3 w0.107: 82.04,63.8 82.04,63.47 80.87,62.3 77.09,62.3 71.48,56.69 55.8,56.69 55.67,56.57 55.67,56.06 55.8,55.93 59.36,55.93 59.48,55.8 59.48,55.35 59.36,55.23 11.34,55.23 10.49,54.38 4.63,54.38 v1(3.67,53.42)
M_A_DQ62: length 98.6
  TOP w0.109: v1(3.76,50.63) 3.61,50.78 J7.245 ; U43.BL67 v2(86.15,67.77)
  SIG3 w0.107: v2(86.15,67.77) 85.82,67.77 85.17,67.12 85.17,66.73 85.67,66.23 85.67,65.85 85.01,65.18 85.01,62.74 83.24,60.97 83.24,58.13 78.12,53.01 71.67,53.01 71.55,52.88 71.55,52.38 71.67,52.25 72.31,52.25 72.44,52.12 72.44,51.73 72.31,51.6 7.79,51.6 7.57,51.39 4.14,51.39 3.76,51.01 v1(3.76,50.63)
M_A_DQ63: length 98.1
  TOP w0.109: J7.246 9.57,50.53 9.55,50.5 v1(7.62,50.5) ; U43.BJ66 v2(86.64,68.63)
  SIG3 w0.107: v2(86.64,68.63) 86.63,68.62 86.63,67.69 86.18,67.24 86.18,66.73 86.69,66.23 86.69,65.97 86.18,65.46 86.18,64.96 85.93,64.7 85.93,63 83.71,60.78 83.71,57.94 78.27,52.5 73.2,52.5 73.07,52.38 73.07,51.99 73.2,51.87 74.21,51.87 74.34,51.74 74.34,51.26 74.21,51.14 8.25,51.14 v1(7.62,50.5)
M_A_DQS_DN0: length 97.2
  TOP w0.089: v1(80.62,101.58) 80.03,100.99 80.03,98.65 80.28,98.39 80.28,97.96 80.11,97.44 80.11,97.12 80.29,96.93 U43.CB4
  TOP w0.109: J7.11 3.28,111.28 3.45,111.11 4.1,111.11 4.93,110.29 6.11,110.29 6.25,110.43 6.25,110.87 6.06,111.07 v1(5.7,111.07)
  SIG2 w0.107: v1(80.62,101.58) 80.29,101.25 80.15,101.25 80.01,101.4 80.01,104.17 75.17,109.01 58.21,109.01 58.09,109.14 58.09,110.16 58.21,110.29 59.32,110.29 59.58,110.54 59.58,111.7 59.32,111.95 6.19,111.95 5.91,111.67 5.91,111.27 v1(5.7,111.07)
M_A_DQS_DN1: length 88.6
  TOP w0.109: U43.CH7 v2(78.22,94.67) ; v1(6.7,106.07) 6.32,106.07 6.18,105.92 6.18,105.34 6.35,105.17 7.65,105.17 8.34,105.86 9.27,105.86 9.43,106.03 J7.32
  SIG3 w0.089: 78.63,95.93 78.65,95.92 78.67,95.92 78.85,95.74 78.88,95.71 78.88,95.38 78.62,95.13 78.62,94.65 arc(78.62,94.54) 78.62,94.43 78.61,94.41 arc(78.6,94.35) 78.56,94.29 78.53,94.26 arc(78.43,94.19) 78.31,94.17 arc(78.22,94.2) 78.18,94.29 78.18,94.57 arc(78.19,94.63) v2(78.22,94.67)
  SIG3 w0.107: 78.63,95.93 78.5,96.06 72.18,96.06 65.95,102.29 55.35,102.29 50.94,106.7 12.86,106.7 12.7,106.54 12.7,106.4 12.38,106.07 11.6,106.07 11.27,106.4 11.27,106.54 11.11,106.7 10.56,106.7 10.4,106.54 10.4,106.4 10.07,106.07 9.3,106.07 8.97,106.4 8.97,106.54 8.81,106.7 6.32,106.7 6.16,106.55 6.16,106.22 6.32,106.07 v1(6.7,106.07)
M_A_DQS_DN2: length 87.1
  TOP w0.109: v1(5.7,100.57) 6.08,100.57 6.22,100.42 6.22,99.96 6.05,99.79 4.93,99.79 4.1,100.61 3.42,100.61 3.25,100.78 J7.53 ; U43.CG13 v2(78.72,92.1)
  SIG2 w0.089: 78.09,95.75 78.09,95.73 78.08,95.72 78.08,95.24 77.82,94.98 77.82,94.63 arc(77.82,94.59) 77.81,94.55 arc(77.71,94.32) 77.53,94.16 arc(77.38,94.02) 77.33,93.83 arc(77.33,93.81) 77.33,93.8 77.33,93.8 arc(77.38,93.61) 77.52,93.47 arc(77.75,93.25) 77.83,92.93 77.83,92.89 arc(77.88,92.74) 77.99,92.62 78.02,92.61 arc(78.23,92.4) 78.32,92.11 78.32,92.08 arc(78.36,91.92) 78.47,91.78 78.55,91.8 v2(78.72,92.1)
  SIG2 w0.107: v1(5.7,100.57) 5.88,100.74 5.88,101.44 6.34,101.9 7.19,101.9 7.79,101.31 67.49,101.31 71.8,97 73.21,97 73.97,96.24 77.81,96.24 78.09,95.95 78.09,95.75
M_A_DQS_DN3: length 86.8
  TOP w0.109: U43.CD24 v2(79.71,86.94) ; v1(6.7,95.57) 6.37,95.57 6.18,95.37 6.18,94.73 6.36,94.55 7.53,94.55 8.34,95.36 9.27,95.36 9.43,95.53 J7.74
  SIG3 w0.089: v2(79.71,86.94) 79.86,86.79 80.06,86.79 80.15,86.89 80.15,87.04 79.81,87.39 79.61,87.39 79.4,87.17 79.03,87.17 78.85,87.35 78.58,87.35 78.39,87.16 78.06,87.16 77.67,87.55 77.64,87.55 77.63,87.57
  SIG3 w0.107: v1(6.7,95.57) 6.28,95.57 6.13,95.72 6.13,96.05 6.28,96.2 42.96,96.2 44.37,94.79 57.58,94.79 63.84,88.53 66.07,88.53 66.34,88.8 74.16,88.8 74.99,87.97 77.23,87.97 77.63,87.57
M_A_DQS_DN4: length 88
  TOP w0.109: U43.CD69 v2(79.71,66.91) ; v1(6.7,67.57) 6.44,67.83 6.44,68.08 6.13,68.39 4.72,68.39 4.01,67.68 3.61,67.68 3.51,67.78 J7.177
  SIG2 w0.089: 77.1,63.99 77.1,64.01 77.09,64.02 77.09,64.64 77.33,64.88 77.33,65.21 arc(77.38,65.4) 77.53,65.54 arc(77.74,65.75) 77.82,66.04 77.82,66.06 arc(77.88,66.26) 78.02,66.4 78.03,66.41 arc(78.24,66.62) 78.32,66.9 78.32,66.9 78.32,66.93 arc(78.32,66.94) 78.32,66.96 arc(78.54,67.27) 78.92,67.26 arc(79.23,67.18) 79.53,67.26 arc(79.9,67.27) 80.1,66.97 80.1,66.65 80.04,66.58 79.82,66.58 79.71,66.69 v2(79.71,66.91)
  SIG2 w0.107: 77.1,63.99 77.1,63.79 76.74,63.42 76.37,63.42 74.06,61.11 55.7,61.11 54.66,62.15 49.01,62.15 43.32,67.84 26.32,67.84 26.08,68.09 6.51,68.09 6.36,67.93 6.36,67.67 6.46,67.57 v1(6.7,67.57)
M_A_DQS_DN5: length 81.9
  TOP w0.109: J7.198 9.43,62.53 9.33,62.43 8.32,62.43 7.76,61.87 6.27,61.87 6.14,61.99 6.14,62.44 6.27,62.57 v1(6.7,62.57) ; U43.CL69 v2(76.74,66.91)
  SIG3 w0.107: v2(76.74,66.91) 77.1,66.91 77.2,67.02 77.2,67.16 77.02,67.34 76.55,67.34 75.8,66.6 75.48,66.6 73.08,64.19 71.45,64.19 71.07,64.58 66.05,64.58 65.92,64.44 54.11,64.44 52.2,62.54 41.9,62.54 41.23,63.2 6.28,63.2 6.1,63.03 6.1,62.76 6.37,62.49 6.63,62.49 v1(6.7,62.57)
M_A_DQS_DN6: length 99.8
  TOP w0.109: v1(6.7,57.07) 6.55,57.22 6.55,57.63 6.23,57.95 4.78,57.95 3.94,57.11 3.68,57.11 3.51,57.27 2.37,57.27 J7.219 ; v2(85.65,65.2) U43.BM72
  SIG2 w0.089: 85.02,64.11 85.02,64.14 85.01,64.15 85.01,64.56 85.26,64.82 85.26,65.41 85.44,65.59 85.59,65.59 85.65,65.53 v2(85.65,65.2)
  SIG2 w0.107: 85.02,64.11 85.02,62.87 83.77,61.62 83.77,58.16 78.22,52.61 75.38,52.61 73.07,54.92 45.96,54.92 45.58,55.3 44.88,55.3 44.5,54.92 43.68,54.92 43.26,55.33 43.26,57.17 42.75,57.68 25.48,57.68 25.16,57.36 23.58,57.36 23.23,57.71 17.32,57.71 16.97,57.36 14.91,57.36 14.56,57.71 13.9,57.71 13.56,57.36 12.33,57.36 12.11,57.59 7.55,57.59 7.14,58 6.74,58 6.34,57.59 6.34,57.27 6.54,57.07 v1(6.7,57.07)
M_A_DQS_DN7: length 98.2
  TOP w0.109: v2(85.16,67.77) U43.BN67 ; v1(6.7,52.07) 6.35,52.07 6.15,51.87 6.15,51.35 6.31,51.19 6.87,51.19 7.16,51.49 7.71,51.49 8.09,51.86 9.27,51.86 9.43,52.03 J7.240
  SIG3 w0.089: 84.03,63.73 84.03,63.75 84.02,63.77 84.02,64.63 84.26,64.88 84.26,65.19 84.26,65.21 arc(84.32,65.4) 84.46,65.54 arc(84.67,65.75) 84.76,66.03 84.76,66.08 arc(84.67,66.36) 84.46,66.57 arc(84.26,66.91) 84.46,67.26 arc(84.68,67.48) 84.76,67.77 84.76,67.83 arc(84.81,68) 84.94,68.11 85.26,68.25 arc(85.42,68.2) 85.41,68.03 v2(85.16,67.77)
  SIG3 w0.107: 84.03,63.73 84.03,62.77 81.88,60.62 81.88,58.01 77.68,53.81 71.47,53.81 70.37,52.7 14.52,52.7 14.17,52.35 12.98,52.35 12.62,52.7 6.49,52.7 6.31,52.52 6.31,52.24 6.49,52.07 v1(6.7,52.07)
M_A_DQS_DN8: length 81.1
  TOP w0.109: v1(6.7,90.07) 6.46,90.31 6.46,90.67 6.11,91.01 4.6,91.01 3.77,90.18 3.52,90.18 3.42,90.28 J7.95 ; U43.CL24 v2(76.74,86.94)
  SIG2 w0.107: v1(6.7,90.07) 6.4,90.07 6.26,90.21 6.26,90.49 6.43,90.65 62.07,90.65 63.83,88.89 64.58,88.89 64.92,88.55 65.2,88.55 65.21,88.54 66.02,88.54 66.36,88.88 72.81,88.88 74.88,86.81 75.83,86.81 76.62,87.6 77.2,87.6 77.35,87.45 77.35,87.13 77.17,86.94 v2(76.74,86.94)
M_A_DQS_DP0: length 97.2
  TOP w0.089: v1(80.62,100.69) 80.83,100.9 80.83,101.09 80.74,101.18 80.49,101.18 80.22,100.91 80.22,100.52 80.37,100.37 80.37,100.24 80.22,100.09 80.22,99.76 80.39,99.59 80.39,99.49 80.22,99.33 80.22,98.73 80.48,98.47 80.48,97.71 80.58,97.61 80.71,97.61 80.81,97.5 80.81,97.36 80.71,97.26 U43.CB2
  TOP w0.109: J7.13 3.28,110.78 3.38,110.87 4.01,110.87 4.83,110.05 6.21,110.05 6.48,110.33 6.48,110.85 v1(6.7,111.07)
  SIG2 w0.107: v1(80.62,100.69) 80.28,101.03 80.06,101.03 79.79,101.3 79.79,104.08 75.07,108.79 58.12,108.79 57.87,109.05 57.87,110.25 58.12,110.51 59.23,110.51 59.36,110.64 59.36,111.61 59.23,111.73 6.28,111.73 6.13,111.58 6.13,111.32 6.38,111.07 v1(6.7,111.07)
M_A_DQS_DP1: length 88.6
  TOP w0.109: v1(5.7,106.07) 5.94,105.82 5.94,105.24 6.25,104.93 7.75,104.93 8.44,105.62 9.33,105.62 9.43,105.53 J7.34 ; U43.CG9 v2(78.72,93.81)
  SIG3 w0.089: 78.79,96.09 78.8,96.08 78.8,96.05 78.98,95.88 79.07,95.79 79.07,95.3 78.81,95.05 78.81,94.65 arc(78.79,94.23) v2(78.72,93.81)
  SIG3 w0.107: 78.79,96.09 78.72,96.16 78.59,96.28 72.27,96.28 66.04,102.51 55.44,102.51 51.04,106.92 12.77,106.92 12.48,106.63 12.48,106.49 12.28,106.29 11.69,106.29 11.49,106.49 11.49,106.63 11.2,106.92 10.47,106.92 10.18,106.63 10.18,106.49 9.98,106.29 9.39,106.29 9.19,106.49 9.19,106.63 8.9,106.92 6.23,106.92 5.94,106.64 5.94,106.31 v1(5.7,106.07)
M_A_DQS_DP2: length 87.1
  TOP w0.109: v1(6.7,100.57) 6.46,100.32 6.46,99.86 6.15,99.55 4.83,99.55 4.01,100.37 3.38,100.37 3.28,100.28 J7.55 ; U43.CH14 v2(78.22,91.24)
  SIG2 w0.089: 77.87,95.75 77.87,95.73 77.89,95.72 77.89,95.32 77.63,95.06 77.63,94.63 77.63,94.63 arc(77.63,94.61) 77.62,94.59 arc(77.56,94.44) 77.43,94.32 arc(77.22,94.12) 77.14,93.83 arc(77.14,93.82) 77.14,93.8 77.14,93.79 arc(77.22,93.51) 77.42,93.31 arc(77.58,93.15) 77.64,92.93 77.64,92.89 arc(77.71,92.64) 77.9,92.46 77.93,92.44 arc(78.07,92.3) 78.13,92.11 78.13,92.07 arc(78.19,91.82) 78.37,91.62 78.39,91.53 v2(78.22,91.24)
  SIG2 w0.107: 77.87,95.75 77.87,95.86 77.71,96.02 73.88,96.02 73.12,96.78 71.71,96.78 67.4,101.09 7.69,101.09 7.1,101.68 6.43,101.68 6.1,101.35 6.1,100.74 6.36,100.49 6.62,100.49 v1(6.7,100.57)
M_A_DQS_DP3: length 86.8
  TOP w0.109: J7.76 10.57,95.02 9.43,95.02 9.33,95.12 8.44,95.12 7.63,94.31 6.27,94.31 5.94,94.64 5.94,95.32 v1(5.7,95.57) ; U43.CB24 v2(80.7,86.94)
  SIG3 w0.089: v2(80.7,86.94) 80.52,86.94 79.89,87.58 79.53,87.58 79.32,87.36 79.11,87.36 78.93,87.54 78.5,87.54 78.31,87.35 78.14,87.35 77.8,87.69 77.8,87.71 77.79,87.72
  SIG3 w0.107: 77.79,87.72 77.32,88.19 75.09,88.19 74.25,89.02 66.25,89.02 65.97,88.75 63.93,88.75 57.67,95.01 44.46,95.01 43.05,96.42 6.19,96.42 5.91,96.14 5.91,95.77 v1(5.7,95.57)
M_A_DQS_DP4: length 88
  TOP w0.109: U43.CB69 v2(80.7,66.91) ; J7.179 3.51,67.28 3.68,67.44 4.11,67.44 4.82,68.15 6.03,68.15 6.21,67.98 6.21,67.68 6.1,67.57 v1(5.7,67.57)
  SIG2 w0.089: 76.88,63.99 76.88,64.01 76.9,64.02 76.9,64.72 77.14,64.96 77.14,65.21 arc(77.22,65.5) 77.43,65.71 arc(77.57,65.85) 77.63,66.04 77.63,66.06 arc(77.71,66.35) 77.93,66.57 77.94,66.57 arc(78.08,66.71) 78.13,66.9 78.13,66.98 78.13,66.98 arc(78.45,67.44) 79.01,67.43 arc(79.23,67.37) 79.44,67.43 arc(79.98,67.44) 80.29,66.99 80.36,66.91 v2(80.7,66.91)
  SIG2 w0.107: 76.88,63.99 76.88,63.88 76.65,63.65 76.28,63.65 73.97,61.33 55.79,61.33 54.75,62.38 49.1,62.38 43.41,68.06 26.42,68.06 26.17,68.31 6.42,68.31 6.14,68.03 6.14,67.77 5.93,67.57 v1(5.7,67.57)
M_A_DQS_DP5: length 81.9
  TOP w0.109: v1(5.7,62.57) 5.91,62.36 5.91,61.9 6.17,61.63 7.85,61.63 8.41,62.19 9.27,62.19 9.43,62.03 J7.200 ; U43.CJ69 v2(77.73,66.91)
  SIG3 w0.107: v2(77.73,66.91) 77.73,66.95 77.11,67.56 76.46,67.56 75.71,66.82 75.39,66.82 72.98,64.42 71.54,64.42 71.16,64.8 65.96,64.8 65.82,64.66 54.01,64.66 52.11,62.76 41.99,62.76 41.32,63.42 6.19,63.42 5.88,63.12 5.88,62.74 v1(5.7,62.57)
M_A_DQS_DP6: length 99.7
  TOP w0.109: J7.221 3.51,56.78 3.61,56.87 4.04,56.87 4.88,57.71 6.13,57.71 6.31,57.54 6.31,57.27 6.11,57.07 v1(5.7,57.07) ; U43.BN71 v2(85.16,66.05)
  SIG2 w0.089: v2(85.16,66.05) 85.26,65.95 85.26,65.68 85.07,65.49 85.07,64.9 84.82,64.64 84.82,64.15 84.8,64.14 84.8,64.11
  SIG2 w0.107: v1(5.7,57.07) 5.85,57.07 6.12,57.34 6.12,57.69 6.65,58.22 7.23,58.22 7.64,57.81 12.2,57.81 12.42,57.58 13.46,57.58 13.81,57.93 14.65,57.93 15,57.58 16.88,57.58 17.23,57.93 23.32,57.93 23.67,57.58 25.07,57.58 25.39,57.9 42.84,57.9 43.48,57.26 43.48,55.42 43.77,55.14 44.41,55.14 44.79,55.52 45.67,55.52 46.05,55.14 73.16,55.14 75.47,52.83 78.13,52.83 83.55,58.25 83.55,61.71 84.8,62.96 84.8,64.11
M_A_DQS_DP7: length 98.2
  TOP w0.109: U43.BM66 v2(85.65,68.63) ; J7.242 10.57,51.52 9.43,51.52 9.33,51.62 8.19,51.62 7.81,51.25 7.26,51.25 6.96,50.96 6.21,50.96 5.92,51.25 5.92,51.85 v1(5.7,52.07)
  SIG3 w0.089: 83.81,63.73 83.81,63.75 83.83,63.77 83.83,64.71 84.07,64.96 84.07,65.19 84.07,65.22 arc(84.15,65.5) 84.37,65.71 arc(84.51,65.85) 84.57,66.04 84.57,66.07 arc(84.51,66.26) 84.37,66.4 arc(84.07,66.91) 84.37,67.43 arc(84.51,67.57) 84.57,67.77 84.57,67.83 arc(84.65,68.1) 84.86,68.29 v2(85.65,68.63)
  SIG3 w0.107: v1(5.7,52.07) 5.85,52.07 6.09,52.31 6.09,52.62 6.4,52.92 12.71,52.92 13.07,52.57 14.08,52.57 14.43,52.92 70.28,52.92 71.38,54.03 77.59,54.03 81.66,58.1 81.66,60.71 83.81,62.86 83.81,63.73
M_A_DQS_DP8: length 81.1
  TOP w0.109: U43.CJ24 v2(77.73,86.94) ; J7.97 2.37,89.78 3.41,89.78 3.58,89.94 3.87,89.94 4.7,90.78 6.02,90.78 6.22,90.57 6.22,90.23 6.06,90.07 v1(5.7,90.07)
  SIG2 w0.107: v1(5.7,90.07) 6.05,90.42 6.05,90.57 6.34,90.86 62.15,90.86 63.92,89.1 64.67,89.1 65.01,88.76 65.93,88.76 66.27,89.1 72.9,89.1 74.97,87.03 75.74,87.03 76.53,87.82 77.29,87.82 77.57,87.54 77.57,87.1 v2(77.73,86.94)
M_A_ECC0: length 80.8
  TOP w0.109: J7.92 9.69,91.03 v1(9.27,91.45) ; U43.CL20 v2(76.74,88.66)
  SIG2 w0.107: v1(9.27,91.45) 9.71,91.88 56.43,91.88 56.56,92.01 56.56,92.89 56.69,93.02 57.2,93.02 57.32,92.89 57.32,92.01 57.45,91.88 57.83,91.88 57.96,92.01 57.96,92.9 58.09,93.02 58.52,93.02 58.7,92.85 58.7,91.87 58.82,91.75 59.22,91.75 59.35,91.87 59.35,92.99 59.51,93.15 59.83,93.15 60,92.99 60,91.75 60.12,91.62 60.52,91.62 60.65,91.75 60.65,92.99 60.81,93.15 61.13,93.15 61.3,92.99 61.3,91.75 61.42,91.62 62.53,91.62 64.18,89.97 64.69,89.97 65.07,90.35 65.75,90.35 66.44,89.65 73.42,89.65 74.62,88.45 76.53,88.45 v2(76.74,88.66)
M_A_ECC1: length 80.7
  TOP w0.109: U43.CJ20 v2(77.73,88.66) ; J7.91 3.5,91.28 v1(3.67,91.45)
  SIG2 w0.107: v1(3.67,91.45) 4.23,90.89 5.03,90.89 5.38,91.24 5.38,91.49 5.89,92 6.81,92 7.29,91.52 7.83,91.52 8.66,92.35 55.93,92.35 56.05,92.48 56.05,93.55 56.18,93.68 63.21,93.68 66.71,90.17 73.63,90.17 74.76,89.04 76.4,89.04 76.45,89.09 76.91,89.09 77.34,88.66 v2(77.73,88.66)
M_A_ECC2: length 80.7
  TOP w0.109: U43.CL28 v2(76.74,85.23) ; J7.101 3.62,88.78 v1(3.8,88.6)
  SIG2 w0.089: 75.66,84.96 76.47,84.96 v2(76.74,85.23)
  SIG2 w0.107: v1(3.8,88.6) 3.8,89.21 3.92,89.33 5.92,89.33 6.05,89.21 6.05,88.86 6.21,88.7 53.45,88.7 55.39,86.76 55.64,86.76 55.85,86.97 55.85,87.22 55.24,87.83 55.24,88.01 55.52,88.29 55.7,88.29 58.07,85.91 72.72,85.91 73.9,84.73 75.35,84.73 75.58,84.96 75.66,84.96
M_A_ECC3: length 80.8
  TOP w0.109: U43.CJ28 v2(77.73,85.23) ; v1(5.32,88.6) 4.5,87.78 J7.105
  SIG2 w0.089: v2(77.73,85.23) 77.42,85.23 76.94,84.74 76,84.74 75.74,84.49
  SIG2 w0.107: 75.74,84.49 75.51,84.26 73.23,84.26 72.15,85.34 57.99,85.34 56.6,86.73 56.42,86.73 56.14,86.45 56.14,86.27 56.61,85.8 56.61,85.55 56.4,85.34 56.15,85.34 53.26,88.23 5.69,88.23 v1(5.32,88.6)
M_A_ECC4: length 80.7
  TOP w0.109: U43.CM18 v2(76.24,89.52) ; v1(7.75,92.21) 7.93,92.03 J7.88
  SIG2 w0.107: v2(76.24,89.52) 75,89.52 73.39,91.14 67.48,91.14 67.18,90.83 66.83,90.83 63.35,94.31 55.55,94.31 55.42,94.18 55.42,93.02 55.29,92.89 54.91,92.89 54.78,93.02 54.78,94.18 54.66,94.31 54.28,94.31 54.15,94.18 54.15,92.95 54.02,92.82 53.64,92.82 53.51,92.95 53.51,94.03 53.39,94.16 53.01,94.16 52.88,94.03 52.88,92.95 52.75,92.82 8.36,92.82 v1(7.75,92.21)
M_A_ECC5: length 80.8
  TOP w0.109: v1(5.19,92.21) 5.13,92.28 J7.87 ; U43.CK18 v2(77.23,89.52)
  SIG2 w0.107: v1(5.19,92.21) 5.19,92.96 6.21,93.97 51.48,93.97 51.61,93.85 51.61,93.4 51.71,93.29 52.21,93.29 52.31,93.4 52.31,94.48 52.83,95 64.23,95 67.61,91.62 73.67,91.62 75.3,89.99 76.52,89.99 76.99,89.52 v2(77.23,89.52)
M_A_ECC6: length 80.6
  TOP w0.109: U43.CM26 v2(76.24,86.09) ; v1(9.27,90.07) 9.27,89.44 9.69,89.03 J7.100
  SIG2 w0.107: v2(76.24,86.09) 74.3,86.09 72.49,87.9 63.71,87.9 62.52,89.09 61.99,89.09 61.83,88.93 61.83,88.32 61.7,88.19 61.3,88.19 61.18,88.32 61.18,89.46 61.05,89.59 60.65,89.59 60.53,89.46 60.53,88.32 60.4,88.19 60,88.19 59.88,88.32 59.88,89.46 59.75,89.59 59.35,89.59 59.23,89.46 59.23,88.32 59.1,88.19 58.7,88.19 58.58,88.32 58.58,89.46 58.45,89.59 58.05,89.59 57.93,89.46 57.93,88.32 57.8,88.19 57.4,88.19 57.28,88.32 57.28,89.5 57.15,89.63 9.71,89.63 v1(9.27,90.07)
M_A_ECC7: length 80.8
  TOP w0.109: v1(7.75,90.07) 7.75,89.89 9.61,88.03 J7.104 ; U43.CK26 v2(77.23,86.09)
  SIG2 w0.107: v2(77.23,86.09) 76.83,86.09 75.98,85.24 74.36,85.24 72.17,87.43 64.53,87.43 64.36,87.25 64.36,86.53 64.23,86.41 63.83,86.41 63.71,86.53 63.71,87.25 63.53,87.43 63.23,87.43 63.06,87.25 63.06,86.53 62.93,86.41 62.53,86.41 62.41,86.53 62.41,87.25 62.23,87.43 61.77,87.43 61.64,87.3 61.64,86.79 61.51,86.67 61.13,86.67 61.01,86.79 61.01,87.3 60.88,87.43 57.22,87.43 55.49,89.16 8.65,89.16 v1(7.75,90.07)
M_A_MA0: length 87.1
  TOP w0.175: U43.CK49 v2(77.23,75.78) ; v1(9.27,77.66) 9.63,78.03 J7.144
  SIG3 w0.163: v2(77.23,75.78) 76.82,75.37 75.25,75.37 74.21,74.33 74.21,74 72.67,72.46 64.61,72.46 62.34,74.74 62.09,74.74 61.88,74.53 61.88,74.28 63.23,72.92 63.23,72.67 63.02,72.46 62.77,72.46 60.5,74.74 60.25,74.74 60.04,74.53 60.04,74.28 61.39,72.92 61.39,72.67 61.18,72.46 60.93,72.46 58.66,74.74 58.41,74.74 58.2,74.53 58.2,74.28 58.75,73.72 58.75,73.47 58.55,73.26 57.61,73.26 52.95,77.93 43.2,77.93 42.68,78.45 11.55,78.45 10.33,77.23 9.71,77.23 v1(9.27,77.66)
M_A_MA1: length 81.9
  TOP w0.175: U43.CK41 v2(77.23,79.22) ; v1(6.22,81.49) 5.51,80.78 J7.133
  SIG3 w0.163: v2(77.23,79.22) 76.81,78.8 75.51,78.8 75.01,78.29 75.01,78.04 73.01,76.04 65.53,76.04 63.65,77.91 57.6,77.91 52.52,82.99 27.43,82.99 26.39,81.95 10.35,81.95 8.88,80.48 6.55,80.48 6.22,80.81 v1(6.22,81.49)
M_A_MA2: length 83.3
  TOP w0.175: v1(8.51,80.04) 9.49,81.03 J7.132 ; U43.CM41 v2(76.24,79.22)
  SIG2 w0.163: v1(8.51,80.04) 9.52,79.03 44.89,79.03 45.42,78.5 47.74,78.5 48.77,77.47 54.96,77.47 55.13,77.29 55.13,77.07 55.31,76.89 55.61,76.89 55.78,77.07 55.78,77.29 55.96,77.47 56.26,77.47 56.43,77.29 56.43,75.68 56.61,75.5 56.91,75.5 57.08,75.68 57.08,77.29 57.26,77.47 57.56,77.47 57.73,77.29 57.73,75.6 57.9,75.43 58.22,75.43 58.39,75.6 58.39,77.29 58.56,77.47 58.86,77.47 59.04,77.29 59.04,75.6 59.2,75.43 72.44,75.43 75.33,78.32 75.33,78.62 75.93,79.22 v2(76.24,79.22)
M_A_MA3: length 85.7
  TOP w0.175: J7.131 3.58,81.28 v1(3.67,81.36) ; U43.CF41 v2(79.21,79.22)
  SIG2 w0.089: 75.39,79.31 75.67,79.59 78.84,79.59 v2(79.21,79.22)
  SIG2 w0.163: 75.39,79.31 74.76,78.68 74.76,78.52 72.22,75.98 61.22,75.98 61.04,76.16 61.04,77.83 60.87,78.01 60.57,78.01 60.39,77.83 60.39,76.31 60.22,76.13 59.92,76.13 59.74,76.31 59.74,77.83 59.57,78.01 49,78.01 47.96,79.05 45.99,79.05 44.56,80.48 4.55,80.48 v1(3.67,81.36)
M_A_MA4: length 84.8
  TOP w0.175: J7.128 8.28,82.03 v1(7.75,81.49) ; U43.CL39 v2(76.74,80.08)
  SIG2 w0.089: v2(76.74,80.08) 76.53,79.87 75.23,79.87 75.12,79.76
  SIG2 w0.163: v1(7.75,81.49) 8.21,81.03 44.78,81.03 46.22,79.59 48.19,79.59 49.23,78.56 61.41,78.56 61.59,78.38 61.59,77.07 61.77,76.89 62.06,76.89 62.24,77.07 62.24,78.38 62.42,78.56 62.71,78.56 62.89,78.38 62.89,76.7 63.07,76.53 63.36,76.53 63.54,76.7 63.54,78.38 63.72,78.56 64.01,78.56 64.19,78.38 64.19,76.7 64.37,76.53 64.66,76.53 64.84,76.7 64.84,78.71 65.02,78.89 67.19,78.89 67.5,79.2 74.56,79.2 75.12,79.76
M_A_MA5: length 85.6
  TOP w0.175: J7.126 9.68,82.53 v1(9.27,82.94) ; U43.CG39 v2(78.72,80.08)
  SIG2 w0.089: 74.47,80.08 75.65,80.08 75.77,80.2 76.34,80.2 76.59,80.45 78.34,80.45 v2(78.72,80.08)
  SIG2 w0.163: v1(9.27,82.94) 9.71,82.5 44.09,82.5 46.44,80.14 49.3,80.14 49.47,79.98 49.47,79.49 49.64,79.31 49.94,79.31 50.12,79.49 50.12,79.98 50.28,80.14 50.6,80.14 50.77,79.98 50.77,79.27 50.93,79.1 51.25,79.1 51.42,79.27 51.42,79.98 51.58,80.14 51.9,80.14 52.07,79.98 52.07,79.27 52.23,79.1 52.55,79.1 52.72,79.27 52.72,79.98 52.88,80.14 53.2,80.14 53.37,79.98 53.37,79.27 53.53,79.1 53.86,79.1 54.02,79.27 54.02,79.98 54.18,80.14 54.51,80.14 54.67,79.98 54.67,79.27 54.83,79.1 55.16,79.1 55.32,79.27 55.32,79.98 55.48,80.14 55.81,80.14 55.97,79.98 55.97,79.27 56.13,79.1 56.46,79.1 56.62,79.27 56.62,79.98 56.78,80.14 57.11,80.14 57.27,79.98 57.27,79.27 57.43,79.1 57.76,79.1 57.92,79.27 57.92,79.98 58.08,80.14 58.41,80.14 58.57,79.98 58.57,79.27 58.73,79.1 64.36,79.1 64.69,79.43 66.96,79.43 67.27,79.74 73.44,79.74 73.77,80.08 74.47,80.08
M_A_MA6: length 85.6
  TOP w0.175: J7.127 4.53,82.28 v1(5.19,82.94) ; U43.CK37 v2(77.23,80.94)
  SIG2 w0.089: 75.01,80.69 75.14,80.82 75.78,80.82 76.05,80.55 76.37,80.55 76.75,80.94 v2(77.23,80.94)
  SIG2 w0.163: v1(5.19,82.94) 5.66,83.4 43.96,83.4 46.67,80.69 59.58,80.69 59.76,80.51 59.76,79.99 59.94,79.82 60.23,79.82 60.41,79.99 60.41,80.51 60.59,80.69 60.88,80.69 61.06,80.51 61.06,79.83 61.24,79.65 61.53,79.65 61.71,79.83 61.71,80.51 61.89,80.69 62.18,80.69 62.36,80.51 62.36,79.83 62.54,79.65 62.83,79.65 63.01,79.83 63.01,80.51 63.19,80.69 63.48,80.69 63.66,80.51 63.66,79.83 63.84,79.65 64.13,79.65 64.31,79.83 64.31,80.51 64.49,80.69 64.78,80.69 64.96,80.51 64.96,80.16 65.14,79.98 65.43,79.98 65.61,80.16 65.61,80.51 65.79,80.69 66.08,80.69 66.26,80.51 66.26,80.16 66.44,79.98 66.73,79.98 66.91,80.16 66.91,80.51 67.09,80.69 75.01,80.69
M_A_MA7: length 86.2
  TOP w0.175: v1(7.75,82.94) 8.19,83.38 9.52,83.38 9.66,83.53 J7.122 ; U43.CD39 v2(79.71,80.08)
  SIG3 w0.163: v2(79.71,80.08) 79.29,79.66 76.1,79.66 75.87,79.43 75.38,79.43 74.46,78.52 74.46,78.26 73.13,76.93 65.41,76.93 63.88,78.46 57.83,78.46 52.75,83.54 27.2,83.54 26.16,82.5 14.31,82.5 13.6,83.21 13.23,83.21 12.52,82.5 9.72,82.5 9.44,82.22 6.06,82.22 5.63,82.65 5.63,83.25 5.78,83.4 7.28,83.4 v1(7.75,82.94)
M_A_MA8: length 86
  TOP w0.175: v1(3.67,82.94) 3.51,82.78 J7.125 ; U43.CM37 v2(76.24,80.94)
  SIG2 w0.089: 74.63,81.23 74.83,81.03 76.15,81.03 v2(76.24,80.94)
  SIG2 w0.163: 74.63,81.23 50.58,81.23 48.03,83.78 47.78,83.78 47.57,83.57 47.57,83.32 49.14,81.74 49.14,81.51 48.91,81.28 48.68,81.28 46.19,83.78 45.94,83.78 45.73,83.57 45.73,83.32 46.88,82.17 46.88,81.92 46.67,81.71 46.42,81.71 44.18,83.94 4.68,83.94 v1(3.67,82.94)
M_A_MA9: length 83.8
  TOP w0.175: U43.CJ35 v2(77.73,81.79) ; v1(6.72,84.38) 6.11,83.78 J7.121
  SIG2 w0.089: v2(77.73,81.79) 77.3,81.37 75.27,81.37 75.21,81.43
  SIG2 w0.163: 75.21,81.43 74.86,81.78 52.64,81.78 50.1,84.32 49.85,84.32 49.64,84.11 49.64,83.86 51.22,82.28 51.22,82.06 50.98,81.82 50.76,81.82 47.73,84.85 16.62,84.85 16.46,84.69 16.46,84.66 16.3,84.49 15.97,84.49 15.81,84.66 15.81,84.69 15.65,84.85 7.18,84.85 v1(6.72,84.38)
M_A_MA10: length 85.5
  TOP w0.175: U43.CJ51 v2(77.73,74.93) ; J7.146 9.27,75.53 v1(9.27,75.52)
  SIG3 w0.163: v1(9.27,75.52) 9.27,75.96 9.45,76.13 10.78,76.13 11.32,76.68 41.4,76.68 41.93,76.15 44.46,76.15 44.62,76.32 44.62,76.67 44.78,76.83 45.11,76.83 45.27,76.67 45.27,76.32 45.43,76.15 45.76,76.15 45.92,76.32 45.92,76.67 46.08,76.83 46.41,76.83 46.57,76.67 46.57,76.32 46.74,76.15 47.06,76.15 47.22,76.32 47.22,76.67 47.39,76.83 47.71,76.83 47.87,76.67 47.87,76.32 48.04,76.15 48.36,76.15 48.52,76.32 48.52,76.67 48.69,76.83 49.01,76.83 49.17,76.67 49.17,76.32 49.34,76.15 49.66,76.15 49.82,76.32 49.82,76.67 49.99,76.83 50.31,76.83 50.47,76.67 50.47,76.32 50.64,76.15 50.96,76.15 51.12,76.32 51.12,76.67 51.29,76.83 51.61,76.83 51.77,76.67 51.77,76.32 51.94,76.15 53.17,76.15 58.81,70.52 60.93,70.52 61.1,70.68 61.1,71.21 61.26,71.37 61.58,71.37 61.75,71.21 61.75,70.68 61.91,70.52 62.23,70.52 62.4,70.68 62.4,71.21 62.56,71.37 62.88,71.37 63.05,71.21 63.05,70.68 63.21,70.52 63.53,70.52 63.7,70.68 63.7,71.21 63.86,71.37 64.19,71.37 64.35,71.21 64.35,70.68 64.51,70.52 72.27,70.52 75.06,73.31 76.12,73.31 76.66,73.85 76.66,74.23 76.92,74.49 77.3,74.49 v2(77.73,74.93)
M_A_MA11: length 81.6
  TOP w0.175: U43.CG35 v2(78.72,81.79) ; J7.120 9.63,84.03 v1(9.27,84.38)
  SIG3 w0.163: v1(9.27,84.38) 9.27,84.1 9.42,83.95 9.96,83.95 10.31,84.3 10.64,84.3 11,83.95 12.19,83.95 12.54,84.3 14.1,84.3 14.46,83.95 15.11,83.95 15.46,84.3 16.85,84.3 17.2,83.94 26.06,83.94 26.75,84.63 53.2,84.63 58.28,79.55 58.53,79.55 58.74,79.76 58.74,80.01 57.32,81.43 57.32,81.68 57.53,81.89 57.78,81.89 60.12,79.55 66.53,79.55 67.19,78.89 73.28,78.89 75.66,81.26 75.9,81.26 76,81.37 78.29,81.37 v2(78.72,81.79)
M_A_MA12: length 83.6
  TOP w0.175: U43.CF37 v2(79.21,80.94) ; v1(3.67,84.38) 3.67,84.39 3.56,84.28 J7.119
  SIG3 w0.163: v2(79.21,80.94) 78.78,80.5 76.16,80.5 75.64,79.98 75.15,79.98 73.91,78.74 73.91,78.49 72.9,77.48 65.63,77.48 64.1,79 58.05,79 52.97,84.08 26.98,84.08 26.29,83.4 16.97,83.4 16.62,83.75 15.89,83.75 15.54,83.4 14.23,83.4 13.88,83.75 12.88,83.75 12.53,83.4 8.83,83.4 8.29,83.94 5.56,83.94 5.26,83.65 3.89,83.65 3.67,83.86 v1(3.67,84.38)
M_A_MA13: length 86.7
  TOP w0.175: U43.CK56 v2(77.23,72.35) ; J7.158 9.37,72.53 v1(9.27,72.62)
  SIG2 w0.163: v1(9.27,72.62) 10.64,72.62 11.63,73.61 12.35,73.61 12.49,73.47 12.49,73.27 12.68,73.08 12.95,73.08 13.14,73.27 13.14,73.47 13.28,73.61 40.79,73.61 41.32,73.08 45.8,73.08 48.91,69.97 50.5,69.97 50.67,70.14 50.67,70.58 50.83,70.74 51.15,70.74 51.32,70.58 51.32,70.01 51.48,69.85 51.8,69.85 51.97,70.01 51.97,70.58 52.13,70.74 52.45,70.74 52.62,70.58 52.62,70.01 52.78,69.85 53.1,69.85 53.27,70.01 53.27,70.58 53.43,70.74 53.75,70.74 53.92,70.58 53.92,70.14 54.08,69.97 54.4,69.97 54.57,70.14 54.57,70.58 54.73,70.74 55.05,70.74 55.22,70.58 55.22,70.14 55.38,69.97 55.7,69.97 55.87,70.14 55.87,70.58 56.03,70.74 56.35,70.74 56.52,70.58 56.52,70.14 56.68,69.97 57.01,69.97 57.17,70.14 57.17,70.58 57.33,70.74 57.66,70.74 57.82,70.58 57.82,70.14 57.98,69.97 58.31,69.97 58.47,70.14 58.47,70.58 58.63,70.74 58.96,70.74 59.12,70.58 59.12,70.14 59.28,69.97 59.61,69.97 59.77,70.14 59.77,70.58 59.93,70.74 60.26,70.74 60.42,70.58 60.42,70.14 60.58,69.97 60.91,69.97 61.07,70.14 61.07,70.58 61.23,70.74 61.56,70.74 61.72,70.58 61.72,70.14 61.88,69.97 62.21,69.97 62.37,70.14 62.37,70.58 62.53,70.74 62.86,70.74 63.02,70.58 63.02,70.14 63.18,69.97 63.51,69.97 63.67,70.14 63.67,70.58 63.83,70.74 64.16,70.74 64.32,70.58 64.32,70.14 64.48,69.97 72.36,69.97 74.32,71.93 76.81,71.93 v2(77.23,72.35)
M_A_MA14: length 84.8
  TOP w0.175: v1(3.75,74.07) 3.54,74.28 J7.151 ; U43.CM52 v2(76.24,74.07)
  SIG3 w0.163: v1(3.75,74.07) 3.44,74.07 3.23,74.28 3.23,76 3.73,76.5 3.73,77.11 3.89,77.27 4.23,77.27 4.38,77.11 4.38,76.33 4.56,76.15 4.85,76.15 5.03,76.33 5.03,77.05 5.21,77.23 5.5,77.23 5.68,77.05 5.68,76.86 5.86,76.68 10.55,76.68 11.1,77.22 25.91,77.22 26.59,77.9 42.08,77.9 42.61,77.38 52.72,77.38 58.18,71.92 72.9,71.92 74.75,73.77 74.75,74.1 75.15,74.49 75.81,74.49 v2(76.24,74.07)
M_A_MA15: length 87.4
  TOP w0.175: v1(7.75,72.62) 8.28,73.16 9.47,73.16 9.6,73.03 J7.156 ; v2(77.73,73.21) U43.CJ54
  SIG2 w0.163: v2(77.73,73.21) 77.3,72.78 74.39,72.78 72.13,70.52 65.48,70.52 64.63,71.37 53.12,71.37 52.95,71.54 52.95,72.53 52.78,72.7 52.48,72.7 52.32,72.54 52.32,71.6 52.16,71.43 51.83,71.43 51.67,71.6 51.67,72.54 51.51,72.7 51.18,72.7 51.02,72.54 51.02,71.6 50.86,71.43 50.53,71.43 50.37,71.6 50.37,72.54 50.21,72.7 49.88,72.7 49.72,72.54 49.72,71.6 49.56,71.43 49.23,71.43 49.07,71.6 49.07,72.54 48.91,72.7 48.19,72.7 46.79,74.1 44.65,74.1 44.49,74.26 44.49,74.9 44.33,75.06 44,75.06 43.84,74.9 43.84,74.26 43.68,74.1 42.08,74.1 41.55,74.63 24.43,74.63 24.27,74.79 24.27,75.43 24.11,75.59 23.78,75.59 23.62,75.43 23.62,74.79 23.46,74.63 11.51,74.63 10.33,73.46 8.58,73.46 v1(7.75,72.62)
M_A_MA16: length 86.5
  TOP w0.175: v1(9.27,74.07) 9.32,74.03 J7.152 ; U43.CF49 v2(79.21,75.78)
  SIG2 w0.163: v2(79.21,75.78) 79.21,74.75 78.69,74.23 78.69,73.92 78.41,73.64 76.33,73.64 76.01,73.33 74.17,73.33 72.76,71.92 58.95,71.92 58.79,72.08 58.79,73.07 58.61,73.25 58.32,73.25 58.14,73.07 58.14,72.08 57.98,71.92 57.65,71.92 57.49,72.08 57.49,73.07 57.31,73.25 57.02,73.25 56.84,73.07 56.84,72.08 56.68,71.92 56.35,71.92 56.19,72.08 56.19,73.07 56.01,73.25 55.72,73.25 55.54,73.07 55.54,72.08 55.38,71.92 55.05,71.92 54.89,72.08 54.89,73.07 54.71,73.25 54.42,73.25 54.24,73.07 54.24,72.08 54.08,71.92 53.75,71.92 53.59,72.08 53.59,73.07 53.41,73.25 48.42,73.25 46.06,75.61 42.35,75.61 41.82,76.13 11.74,76.13 9.68,74.07 v1(9.27,74.07)
M_A_ODT0: length 82
  TOP w0.175: J7.155 5.24,73.28 v1(6.03,74.07) ; U43.CF56 v2(78.22,72.35)
  SIG3 w0.163: v1(6.03,74.07) 6.5,74.53 10.73,74.53 11.27,75.08 25.93,75.08 26.43,75.59 40.46,75.59 40.99,75.06 52.72,75.06 58.68,69.1 60.46,69.1 60.63,69.26 60.79,69.43 61.44,69.43 61.6,69.27 61.77,69.1 62.42,69.1 62.58,69.26 62.75,69.43 63.4,69.43 63.56,69.27 63.72,69.1 72.4,69.1 75.21,71.92 77.79,71.92 v2(78.22,72.35)
M_A_ODT1: length 82.2
  TOP w0.175: v1(5.19,72.62) 4.35,71.78 J7.161 ; U43.CM60 v2(76.24,70.63)
  SIG3 w0.163: v1(5.19,72.62) 5.19,72.74 5.51,73.06 39.95,73.06 40.45,72.56 43.94,72.56 44.1,72.72 44.1,73.12 44.28,73.3 44.57,73.3 44.75,73.12 44.75,72.72 44.91,72.56 45.24,72.56 45.4,72.72 45.4,73.3 45.56,73.46 45.89,73.46 46.05,73.3 46.05,72.72 46.21,72.56 46.54,72.56 46.7,72.72 46.7,73.3 46.87,73.46 47.19,73.46 47.35,73.3 47.35,72.72 47.52,72.56 53.68,72.56 58.23,68.01 72.85,68.01 75.48,70.63 v2(76.24,70.63)
M_A_PAR: length 88.4
  TOP w0.175: v1(4.43,77.66) 3.82,78.28 J7.143 ; U43.CM49 v2(76.24,75.78)
  SIG2 w0.163: v1(4.43,77.66) 5.25,78.48 43.74,78.48 44.27,77.96 45.58,77.96 45.75,77.79 45.75,77.69 45.91,77.53 46.23,77.53 46.4,77.69 46.4,77.79 46.56,77.96 47.51,77.96 48.55,76.92 51.81,76.92 51.99,76.74 51.99,75.07 52.16,74.89 52.46,74.89 52.64,75.07 52.64,76.74 52.81,76.92 53.11,76.92 53.29,76.74 53.29,75.07 53.47,74.89 53.76,74.89 53.94,75.07 53.94,76.74 54.12,76.92 54.41,76.92 54.59,76.74 54.59,75.07 54.77,74.89 55.06,74.89 55.24,75.07 55.24,76.17 55.42,76.35 55.71,76.35 55.89,76.17 55.89,75.07 56.07,74.89 73.25,74.89 74.5,76.13 75.89,76.13 v2(76.24,75.78)
M_ACT_N: length 76.4
  TOP w0.175: U43.CF33 v2(79.21,82.65) ; J7.114 9.58,85.53 v1(9.27,85.83)
  SIG2 w0.163: v2(79.21,82.65) 79.03,82.65 78.61,83.08 72.64,83.08 72.21,83.5 61.16,83.5 61,83.34 61,83.15 60.84,82.99 60.51,82.99 60.35,83.15 60.35,83.34 60.19,83.5 54.31,83.5 52.02,85.78 51.77,85.78 51.56,85.58 51.56,85.32 51.94,84.94 51.94,84.69 51.73,84.48 51.48,84.48 49.65,86.31 9.75,86.31 v1(9.27,85.83)
M_ALERT_N: length 83.3
  TOP w0.175: v1(7.75,84.38) 7.75,84.59 8.18,85.03 J7.116 ; U43.CK33 v2(77.23,82.65)
  SIG3 w0.163: v1(7.75,84.38) 8.21,84.85 26.19,84.85 26.52,85.18 53.43,85.18 56.61,82 56.86,82 57.07,82.21 57.07,82.46 55.34,84.19 55.34,84.44 55.55,84.65 55.8,84.65 60.35,80.1 66.75,80.1 67.42,79.43 72.55,79.43 75.35,82.23 76.81,82.23 v2(77.23,82.65)
M_B_ACT_N: length 61.5
  TOP w0.089: U43.CU41 67.03,79.44 v1(66.04,78.45)
  TOP w0.175: v1(23,85.83) 23.3,85.53 23.3,85.53 J8.114
  SIG4 w0.137: v1(66.04,78.45) 65.62,78.87 61.37,78.87 57.91,82.34 57.69,82.34 57.52,82.16 57.52,81.95 59.35,80.11 59.35,79.93 59.15,79.72 58.97,79.72 53.34,85.35 23.48,85.35 v1(23,85.83)
M_B_ALERT_N: length 72
  TOP w0.089: U43.CT42 73.79,78.94 73.65,79.09 73.14,79.09 72.98,79.25 67.6,79.25 v1(66.8,78.45)
  TOP w0.175: v1(23,84.38) 23,84.7 23.33,85.03 J8.116
  SIG4 w0.137: v1(66.8,78.45) 66.38,78.02 65.05,78.02 64.72,78.35 59.58,78.35 53.3,84.62 53.12,84.62 52.93,84.43 52.93,84.25 58.14,79.04 58.14,78.82 57.97,78.65 57.75,78.65 51.57,84.83 23.45,84.83 v1(23,84.38)
M_B_BA0: length 60.8
  TOP w0.089: v1(69.02,69.54) 69.02,69.62 69.65,69.99 69.72,69.99 70.98,70.32 72.9,70.32 73.44,70.18 73.63,70.18 73.75,70.26 73.84,70.35 U43.CR61
  TOP w0.175: J8.150 23.19,74.53 23.16,74.55 22.44,74.55 v1(21.48,75.52)
  SIG4 w0.137: v1(69.02,69.54) 68.08,70.48 65.53,70.48 63.14,72.88 56.89,72.88 56.34,73.43 53.24,73.43 50.67,76 22.27,76 22.14,76.12 22.14,76.51 22.02,76.63 21.6,76.63 21.48,76.51 v1(21.48,75.52)
M_B_BA1: length 71.4
  TOP w0.089: v1(66.74,69.54) 67.83,70.63 69.72,70.63 69.8,70.71 72.94,70.71 73.11,70.88 73.65,70.88 73.79,71.02 U43.CT60
  TOP w0.175: v1(17.4,75.52) 17.15,75.78 J8.145
  SIG4 w0.137: v1(17.4,75.52) 18.38,74.54 29.89,74.54 30.02,74.42 30.02,73.84 30.15,73.71 30.65,73.71 30.78,73.84 30.78,74.42 30.91,74.54 50.65,74.54 52.81,72.39 55.91,72.39 58.52,69.78 58.75,69.78 58.94,69.97 58.94,70.17 57.66,71.45 57.66,71.67 57.83,71.84 58.05,71.84 60.88,69.01 61.09,69.01 61.26,69.18 61.26,69.4 60.16,70.5 60.16,70.71 60.34,70.89 60.55,70.89 62.42,69.02 66.22,69.02 v1(66.74,69.54)
M_B_BG0: length 72.4
  TOP w0.089: v1(69.09,78.45) 69.49,78.85 72.31,78.85 72.51,78.65 73.01,78.65 73.17,78.8 73.67,78.8 73.87,78.59 74.17,78.59 74.52,78.94 U43.CR41
  TOP w0.175: J8.115 19.56,85.28 20.45,84.39 v1(20.45,84.38)
  SIG4 w0.137: v1(69.09,78.45) 68.14,77.5 64.83,77.5 64.5,77.83 57.83,77.83 51.41,84.25 51.23,84.25 51.02,84.05 51.02,83.87 53.82,81.07 53.82,80.85 53.65,80.68 53.43,80.68 50.18,83.93 21.51,83.93 21.38,84.06 21.38,84.56 21.26,84.68 20.75,84.68 v1(20.45,84.38)
M_B_BG1: length 73.9
  TOP w0.089: U43.CV42 72.48,78.94 72.39,79.04 68.92,79.04 v1(68.33,78.45)
  TOP w0.175: J8.113 17.34,85.78 v1(17.4,85.83)
  SIG1 w0.137: v1(68.33,78.45) 67.88,78.9 64.83,78.9 64.25,78.32 59.83,78.32 57.48,80.66 53.75,80.66 52.09,82.32 50.53,82.32 47.71,85.14 32.43,85.14 32.3,85.01 32.3,84.13 32.18,84 31.8,84 31.67,84.13 31.67,85.01 31.54,85.14 31.16,85.14 31.03,85.01 31.03,84.13 30.91,84 30.53,84 30.4,84.13 30.4,85.01 30.27,85.14 29.89,85.14 29.76,85.01 29.76,84.13 29.64,84 29.26,84 29.13,84.13 29.13,85.01 29,85.14 28.62,85.14 28.49,85.01 28.49,84.13 28.37,84 27.99,84 27.86,84.13 27.86,84.58 27.61,84.83 20.67,84.83 20.49,85.01 20.49,85.52 20.37,85.65 19.99,85.65 19.86,85.52 19.86,84.96 19.73,84.83 15.54,84.83 15.41,84.96 15.41,85.71 15.54,85.83 v1(17.4,85.83)
M_B_CKE0: length 73.5
  TOP w0.089: U43.CT40 73.25,79.93 72.95,79.63 70.97,79.63 v1(70.4,80.21)
  TOP w0.175: J8.109 17.98,86.78 v1(18.92,85.83)
  SIG1 w0.137: v1(70.4,80.21) 69.65,80.95 58.66,80.95 57.91,81.7 55.73,81.7 52.87,84.57 52.69,84.57 52.48,84.36 52.48,84.18 54.57,82.09 54.57,81.88 54.39,81.7 54.18,81.7 50.15,85.73 49.94,85.73 49.77,85.56 49.77,85.34 51.35,83.75 51.35,83.54 51.18,83.36 50.96,83.36 48.05,86.28 19.37,86.28 v1(18.92,85.83)
M_B_CKE1: length 70.8
  TOP w0.089: v1(67.35,80.21) 67.97,80.82 72.69,80.82 U43.CV38
  TOP w0.175: v1(21.48,85.83) 22.17,86.53 J8.110
  SIG1 w0.137: v1(67.35,80.21) 67.28,80.14 66.53,80.14 66.38,79.99 66.38,79.55 66.25,79.42 65.96,79.42 65.83,79.55 65.83,79.99 65.68,80.14 65.44,80.14 65.28,79.99 65.28,79.55 65.16,79.42 64.86,79.42 64.74,79.55 64.74,79.99 64.58,80.14 64.34,80.14 64.19,79.99 64.19,78.99 64.03,78.84 63.79,78.84 63.64,78.99 63.64,80.06 63.51,80.19 63.22,80.19 63.09,80.06 63.09,78.99 62.94,78.84 62.69,78.84 62.54,78.99 62.54,80.06 62.41,80.19 62.12,80.19 61.99,80.06 61.99,78.99 61.84,78.84 61.6,78.84 61.44,78.99 61.44,80.19 61.32,80.32 61.02,80.32 60.89,80.19 60.89,78.99 60.74,78.84 60.5,78.84 60.35,78.99 60.35,80.19 60.22,80.32 59.92,80.32 59.8,80.19 59.8,79.63 59.65,79.48 59.4,79.48 59.25,79.63 59.25,79.99 59.1,80.14 58.74,80.14 57.7,81.18 53.96,81.18 52.3,82.84 50.75,82.84 47.84,85.75 26.6,85.75 26.21,85.35 21.68,85.35 21.48,85.56 v1(21.48,85.83)
M_B_CLK_DN0: length 74.5
  TOP w0.089: U43.CT58 73.94,71.94 73.18,71.94 72.96,71.71 72.57,71.71 72.36,71.92 71.9,71.92 v1(71.46,71.48)
  TOP w0.175: J8.139 17.36,79.28 17.73,78.9 18.58,78.9 18.92,79.24 v1(18.92,80.04)
  SIG1 w0.137: v1(71.46,71.48) 71.46,71.89 71.77,72.2 74.86,72.2 75.16,72.5 75.16,73.54 74.86,73.84 59.41,73.84 56.05,77.21 44.91,77.21 42.5,79.62 29.47,79.62 29.01,79.15 29.01,78.41 28.88,78.28 28.24,78.28 28.11,78.41 28.11,79.17 27.71,79.58 20.68,79.58 20.05,78.94 18.94,78.94 18.67,79.22 18.67,79.79 v1(18.92,80.04)
M_B_CLK_DN2: length 72.8
  TOP w0.089: v1(68.29,71.48) 68.31,71.51 68.31,71.63 68.31,72.13 arc(68.42,72.39) 68.68,72.5 69.74,72.5 arc(69.86,72.47) 69.97,72.4 70.02,72.35 arc(70.06,72.32) 70.11,72.31 70.65,72.31 arc(70.69,72.32) 70.73,72.34 70.79,72.4 arc(70.89,72.47) 71,72.49 72.44,72.49 73.41,72.84 73.59,72.84 73.75,72.78 73.86,72.67 U43.CR57
  TOP w0.175: v1(21.48,77.66) 21.02,78.12 21.02,78.62 21.62,79.22 23.07,79.22 23.27,79.03 J8.140
  SIG1 w0.137: v1(68.29,71.48) 68.4,71.48 68.8,71.88 68.8,72.08 68.65,72.23 68.24,72.23 68.13,72.11 67.71,72.11 67.6,72.23 67.19,72.23 67.07,72.11 66.66,72.11 66.55,72.23 66.13,72.23 66.02,72.11 65.61,72.11 65.5,72.23 65.08,72.23 64.97,72.11 64.56,72.11 64.45,72.23 63.83,72.23 63.7,72.09 63.7,70.78 63.4,70.48 62.64,70.48 62.35,70.78 62.35,72.34 62.21,72.48 61.63,72.48 61.5,72.34 61.5,71.2 61.2,70.9 60.44,70.9 60.15,71.2 60.15,72.09 60.01,72.23 59.12,72.23 55.49,75.86 44.12,75.86 41.82,78.16 34.19,78.16 32.92,76.89 32.08,76.89 31.67,77.29 31.67,77.65 31.55,77.78 30.78,77.78 30.65,77.65 30.65,77.29 30.25,76.89 26.97,76.89 26.59,77.27 26.59,78.05 26.42,78.22 25.95,78.22 25.84,78.11 25.43,78.11 25.32,78.22 24.91,78.22 24.79,78.11 24.38,78.11 24.27,78.22 23.86,78.22 23.75,78.11 23.34,78.11 23.22,78.22 21.28,78.22 21.16,78.11 21.16,77.8 21.31,77.66 v1(21.48,77.66)
M_B_CLK_DP0: length 74.5
  TOP w0.089: U43.CV58 72.54,72.01 72.44,72.11 71.82,72.11 71.63,71.92 70.54,71.92 70.43,71.81 70.43,71.75 v1(70.7,71.48)
  TOP w0.175: J8.137 17,79.78 17.2,79.58 17.48,79.58 17.86,79.2 18.45,79.2 18.62,79.37 18.62,79.58 v1(18.16,80.04)
  SIG1 w0.137: v1(70.7,71.48) 71.66,72.45 74.75,72.45 74.91,72.6 74.91,73.44 74.75,73.59 59.31,73.59 55.94,76.96 44.81,76.96 42.4,79.37 29.58,79.37 29.26,79.05 29.26,78.31 28.98,78.03 28.13,78.03 27.86,78.31 27.86,79.07 27.61,79.32 20.78,79.32 20.15,78.69 18.84,78.69 18.42,79.11 18.42,79.79 v1(18.16,80.04)
M_B_CLK_DP2: length 72.8
  TOP w0.089: U43.CU57 73.53,72.26 73.44,72.17 73.26,72.17 73.17,72.26 73.17,72.39 73.1,72.46 72.91,72.46 72.47,72.3 71,72.3 arc(70.96,72.29) 70.92,72.27 70.87,72.21 arc(70.77,72.14) 70.65,72.12 70.11,72.12 arc(69.99,72.14) 69.89,72.21 69.83,72.27 arc(69.79,72.3) 69.74,72.31 68.68,72.31 arc(68.55,72.25) 68.5,72.13 68.5,72.11 arc(68.55,71.98) 68.68,71.93 69.27,71.93 arc(69.34,71.9) 69.37,71.82 69.37,71.81 arc(69.35,71.68) 69.28,71.58 arc(69.17,71.51) v1(69.05,71.48)
  TOP w0.175: J8.138 21.49,79.53 20.71,78.75 v1(20.71,77.66)
  SIG1 w0.137: v1(20.71,77.66) 20.91,77.86 20.91,78.21 21.18,78.48 26.52,78.48 26.84,78.16 26.84,77.37 27.08,77.14 30.15,77.14 30.4,77.39 30.4,77.75 30.67,78.03 31.65,78.03 31.92,77.75 31.92,77.39 32.18,77.14 32.81,77.14 34.08,78.41 41.93,78.41 44.23,76.11 55.59,76.11 59.22,72.48 60.11,72.48 60.4,72.19 60.4,71.31 60.55,71.15 61.09,71.15 61.25,71.31 61.25,72.45 61.53,72.73 62.31,72.73 62.6,72.45 62.6,70.89 62.75,70.73 63.29,70.73 63.44,70.89 63.44,72.19 63.73,72.48 68.76,72.48 69.05,72.19 v1(69.05,71.48)
M_B_CS_N0: length 74.8
  TOP w0.089: U43.CR63 74.02,69.54 73.66,69.18 73.34,69.18 73.18,69.34 72.49,69.34 72.16,69.02 66.49,69.02 v1(65.97,69.54)
  TOP w0.175: v1(18.92,75.52) 18.18,74.78 J8.149
  SIG1 w0.137: v1(18.92,75.52) 18.92,77.01 19.05,77.14 19.52,77.14 19.65,77.01 19.65,76.1 19.8,75.94 20.04,75.94 20.2,76.1 20.2,76.82 20.35,76.97 20.59,76.97 20.75,76.82 20.75,76.1 20.9,75.94 21.14,75.94 21.29,76.1 21.29,76.66 21.45,76.82 21.69,76.82 21.84,76.66 21.84,76.1 22,75.94 22.24,75.94 22.39,76.1 22.39,77.09 22.54,77.24 22.79,77.24 22.94,77.09 22.94,76.1 23.09,75.94 23.34,75.94 23.5,76.1 23.5,77.02 23.65,77.17 23.89,77.17 24.04,77.02 24.04,76.1 24.17,75.97 24.56,75.97 24.68,76.1 24.68,76.76 24.81,76.89 25.19,76.89 25.32,76.76 25.32,76.1 25.45,75.97 33.29,75.97 34.59,77.27 41.19,77.27 43.45,75.01 55.14,75.01 60.51,69.63 63.95,69.63 64.27,69.96 65.55,69.96 v1(65.97,69.54)
M_B_CS_N1: length 71.7
  TOP w0.089: v1(69.2,67.56) 69.81,68.17 72.55,68.17 72.66,68.05 U43.CV66
  TOP w0.175: v1(17.4,72.62) 17.25,72.78 J8.157
  SIG1 w0.137: v1(69.2,67.56) 68.71,67.07 57.11,67.07 56.94,67.23 56.94,67.62 57.07,67.74 57.32,67.74 57.45,67.87 57.45,68.2 56.08,69.57 55.87,69.57 55.69,69.39 55.69,69.18 55.99,68.88 55.99,68.7 55.79,68.49 55.61,68.49 51.5,72.6 51.28,72.6 51.11,72.43 51.11,72.21 52.3,71.02 52.3,70.8 52.13,70.63 51.91,70.63 49.94,72.6 41.55,72.6 39.42,74.73 35.73,74.73 34.13,73.12 16.18,73.12 16.05,73 16.05,72.65 16.18,72.52 17.3,72.52 v1(17.4,72.62)
M_B_DQ0: length 74.6
  TOP w0.089: v1(77.12,99.91) 77.98,99.05 U43.CG1
  TOP w0.109: J8.8 23.42,112.03 v1(23,112.45)
  SIG4 w0.086: v1(23,112.45) 23.55,113 32.81,113 33.07,112.74 33.07,109.91 33.19,109.78 33.7,109.78 33.83,109.91 33.83,112.87 33.96,113 34.46,113 34.59,112.87 34.59,109.89 34.72,109.76 35.1,109.76 35.23,109.89 35.23,111.43 35.35,111.56 35.73,111.56 35.86,111.43 35.86,109.89 35.99,109.76 64.45,109.76 71.42,102.79 74.24,102.79 v1(77.12,99.91)
M_B_DQ1: length 74.4
  TOP w0.089: U43.CG3 78.03,96.81 78.03,97.49 77.68,97.83 77.68,98.59 v1(77.12,99.15)
  TOP w0.109: J8.7 17.23,112.28 v1(17.4,112.45)
  SIG4 w0.086: v1(17.4,112.45) 17.84,112.89 20.67,112.89 22.1,114.32 35.75,114.32 38.99,111.09 65.54,111.09 72.31,104.32 76.79,104.32 77.9,103.21 77.9,99.93 v1(77.12,99.15)
M_B_DQ2: length 74.5
  TOP w0.089: U43.CM3 75.9,96.95 75.9,97.7 75.97,97.78 75.97,98.16 74.5,99.63 73.65,99.63 v1(73.58,99.55)
  TOP w0.109: v1(23,108.76) 23.26,109.03 J8.20
  SIG4 w0.086: v1(23,108.76) 23.55,109.32 27.43,109.32 29.87,106.88 59.54,106.88 65.46,100.96 66.44,100.96 70.9,96.5 71.11,96.5 71.29,96.67 71.29,96.89 67.92,100.26 67.92,100.43 68.13,100.64 68.31,100.64 71.86,97.09 73.36,97.09 73.58,97.31 v1(73.58,99.55)
M_B_DQ3: length 74.8
  TOP w0.089: U43.CN4 75.1,96.29 75.1,97 75.28,97.18 75.28,98.14 74.94,98.48 74.66,98.48 v1(74.65,98.47)
  TOP w0.109: J8.21 17.39,108.78 v1(17.4,108.76)
  SIG4 w0.086: v1(17.4,108.76) 18.32,109.68 20.53,109.68 21.49,110.64 28.39,110.64 30.83,108.21 61.64,108.21 64.7,105.15 64.88,105.15 65.09,105.36 65.09,105.53 62.86,107.77 62.86,107.95 63.07,108.16 63.25,108.16 70.13,101.27 70.46,100.95 73.09,100.95 74.63,99.41 74.63,98.5 v1(74.65,98.47)
M_B_DQ4: length 74.3
  TOP w0.089: v1(77.12,101.44) 78.23,100.33 78.23,98.21 78.3,98.13 78.3,97.43 U43.CF2
  TOP w0.109: v1(21.48,112.45) 22.05,113.03 J8.4
  SIG4 w0.086: v1(77.12,101.44) 76.98,101.3 76.48,101.3 75.74,102.03 75.74,102.41 75.99,102.67 75.99,103.05 75.74,103.3 71.67,103.3 64.77,110.21 37.77,110.21 37.64,110.33 37.64,111.18 37.51,111.3 37.13,111.3 37,111.18 37,110.29 36.93,110.21 36.45,110.21 36.37,110.29 36.37,112.45 36.24,112.57 35.86,112.57 35.73,112.45 35.73,112.19 35.61,112.07 35.23,112.07 35.1,112.19 35.1,113.31 34.97,113.44 22.47,113.44 v1(21.48,112.45)
M_B_DQ5: length 74.4
  TOP w0.089: v1(77.12,102.2) 78.42,100.9 78.42,98.84 78.5,98.21 78.5,98.07 78.83,97.35 78.83,97.12 78.65,96.94 U43.CF4
  TOP w0.109: v1(18.92,112.45) 18.1,113.28 J8.3
  SIG4 w0.086: v1(18.92,112.45) 20.85,112.45 22.29,113.88 35.57,113.88 38.81,110.65 65.09,110.65 71.92,103.82 76.65,103.82 77.44,103.03 77.44,102.52 v1(77.12,102.2)
M_B_DQ6: length 74.7
  TOP w0.089: v1(73.04,100.09) 73.17,100.22 74.17,100.22 76.16,98.24 76.16,97.41 U43.CL2
  TOP w0.109: v1(21.48,108.76) 22.74,110.03 J8.16
  SIG4 w0.086: v1(21.48,108.76) 22.47,109.76 27.71,109.76 30.15,107.32 59.73,107.32 65.64,101.4 65.86,101.4 66.03,101.58 66.03,101.79 62.73,105.1 62.73,105.28 62.94,105.48 63.12,105.48 66.83,101.77 68.39,101.77 70.18,99.97 72.92,99.97 v1(73.04,100.09)
M_B_DQ7: length 74.5
  TOP w0.089: v1(71.58,100.41) 71.97,100.8 73.86,100.8 76.35,98.31 76.35,97.66 76.66,97.35 76.66,96.96 76.5,96.8 U43.CK4
  TOP w0.109: v1(18.92,108.76) 17.91,109.78 J8.17
  SIG4 w0.086: v1(71.58,100.41) 70.37,100.41 65.79,104.99 65.61,104.99 65.4,104.78 65.4,104.6 66.24,103.76 66.24,103.58 66.03,103.37 65.85,103.37 61.52,107.7 61.34,107.7 61.13,107.49 61.13,107.31 61.71,106.74 61.71,106.52 61.54,106.35 61.32,106.35 59.91,107.76 30.51,107.76 28.07,110.2 21.69,110.2 20.25,108.76 v1(18.92,108.76)
M_B_DQ8: length 70.1
  TOP w0.089: v1(69.48,100.07) 69.48,99.28 70.33,98.42 70.33,97.78 70.65,97.46 70.81,97.3 70.97,97.14 71.13,96.98 71.29,96.82 71.37,96.75 71.37,95.23 72.28,94.32 73.37,94.32 U43.CU8
  TOP w0.109: v1(21.48,107.42) 21.6,107.42 22.13,106.89 23.2,106.89 23.34,107.03 J8.28
  SIG1 w0.086: v1(21.48,107.42) 22.37,108.31 50.53,108.31 55.83,103.01 56.01,103.01 56.22,103.22 56.22,103.39 55.11,104.5 54.05,105.56 54.05,105.74 54.26,105.95 54.44,105.95 57.5,102.89 66.02,102.89 67.58,101.32 68.83,100.07 v1(69.48,100.07)
M_B_DQ9: length 70.1
  TOP w0.089: U43.CR8 73.17,94.09 72.09,94.09 71.07,95.11 71.07,96.62 70.24,97.46 70.09,97.68 69.23,99.11 v1(68.85,100.71)
  TOP w0.109: J8.29 18.28,106.78 v1(18.92,107.42)
  SIG1 w0.086: v1(68.85,100.71) 68.85,101.36 66.87,103.33 57.69,103.33 53.35,107.66 53.18,107.66 52.97,107.45 52.97,107.27 53.42,106.82 53.42,106.64 53.21,106.43 53.03,106.43 50.07,109.4 20.9,109.4 v1(18.92,107.42)
M_B_DQ10: length 70
  TOP w0.089: v1(66.69,96.26) 67.75,96.26 69.03,94.98 69.03,94.16 70.66,92.52 70.66,92.52 70.76,92.42 72.43,92.42 72.54,92.31 U43.CU13
  TOP w0.109: J8.41 17.39,103.78 v1(17.4,103.76)
  SIG1 w0.086: v1(66.69,96.26) 66.69,97.56 63.47,100.78 52.73,100.78 49.57,103.94 46.4,103.94 46.27,104.06 46.27,104.45 46.4,104.57 48.56,104.57 48.69,104.7 48.69,105.13 48.56,105.26 18.89,105.26 v1(17.4,103.76)
M_B_DQ11: length 70.1
  TOP w0.089: v1(67.32,95.63) 67.97,95.63 68.74,94.86 68.74,94.03 70.54,92.23 72.35,92.23 72.47,92.11 72.96,92.11 73.12,91.95 73.66,91.95 74.02,92.31 U43.CR13
  TOP w0.109: J8.42 23.24,103.53 v1(23,103.76)
  SIG1 w0.086: v1(67.32,95.63) 66.68,95.63 65.34,96.97 64.66,96.97 62.19,99.45 52.15,99.45 49.19,102.41 32.05,102.41 31.92,102.54 31.92,102.92 32.05,103.05 37,103.05 37.13,103.18 37.13,103.68 37,103.81 26.84,103.81 26.21,103.18 23.29,103.18 23,103.46 v1(23,103.76)
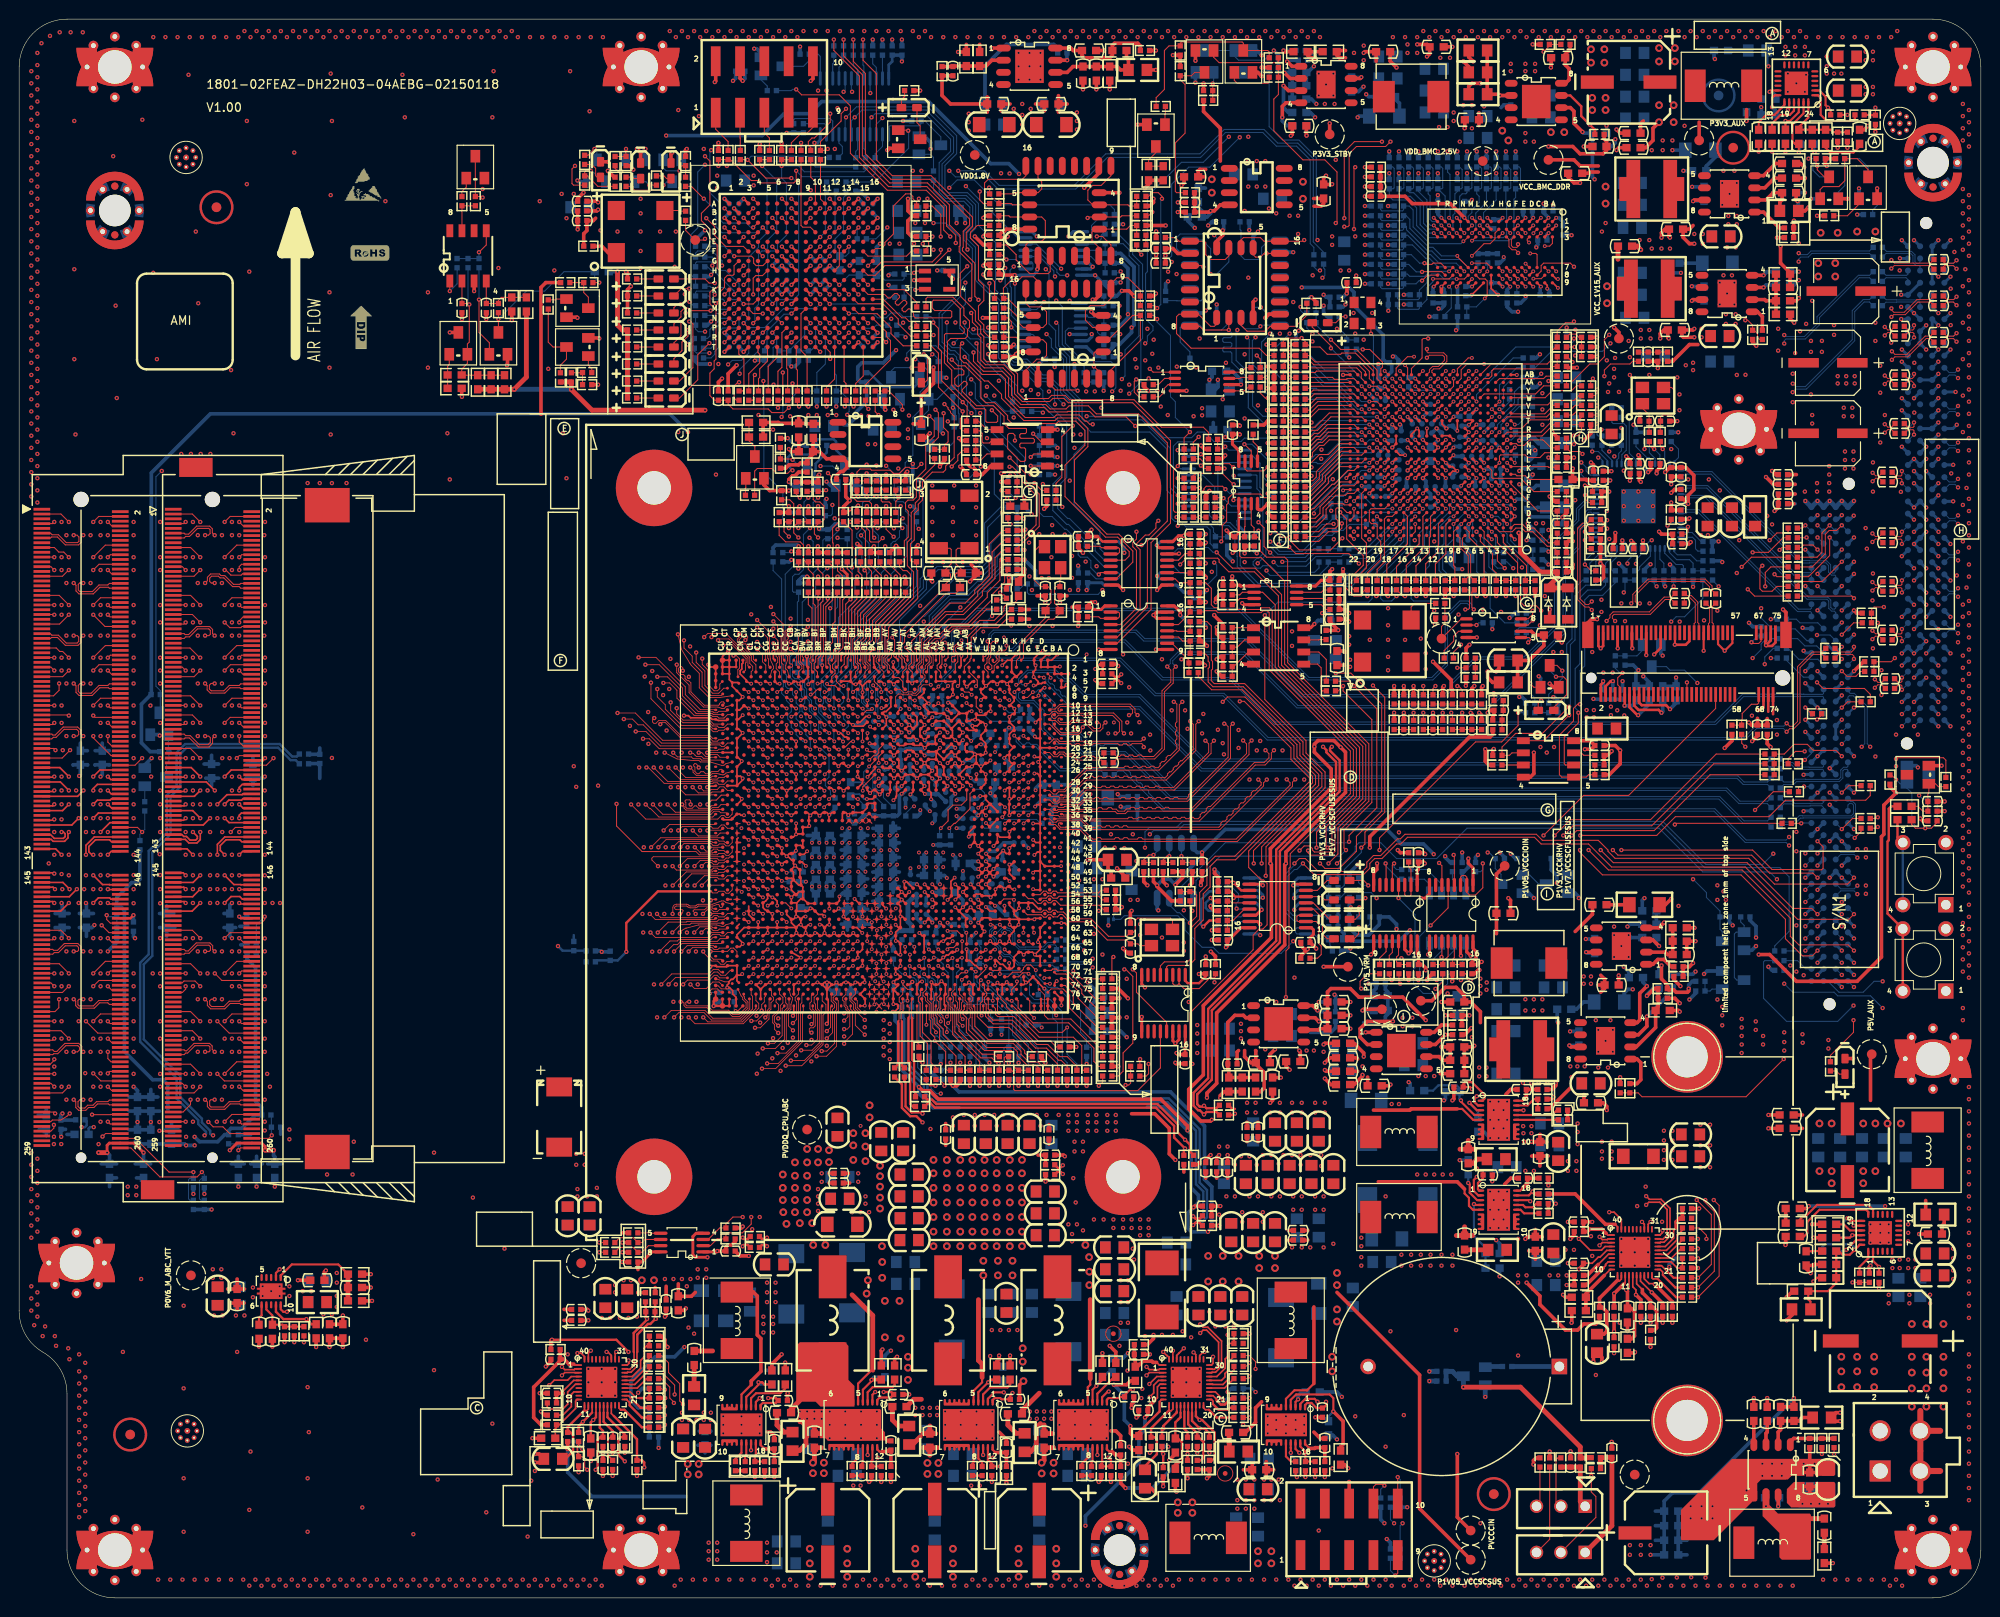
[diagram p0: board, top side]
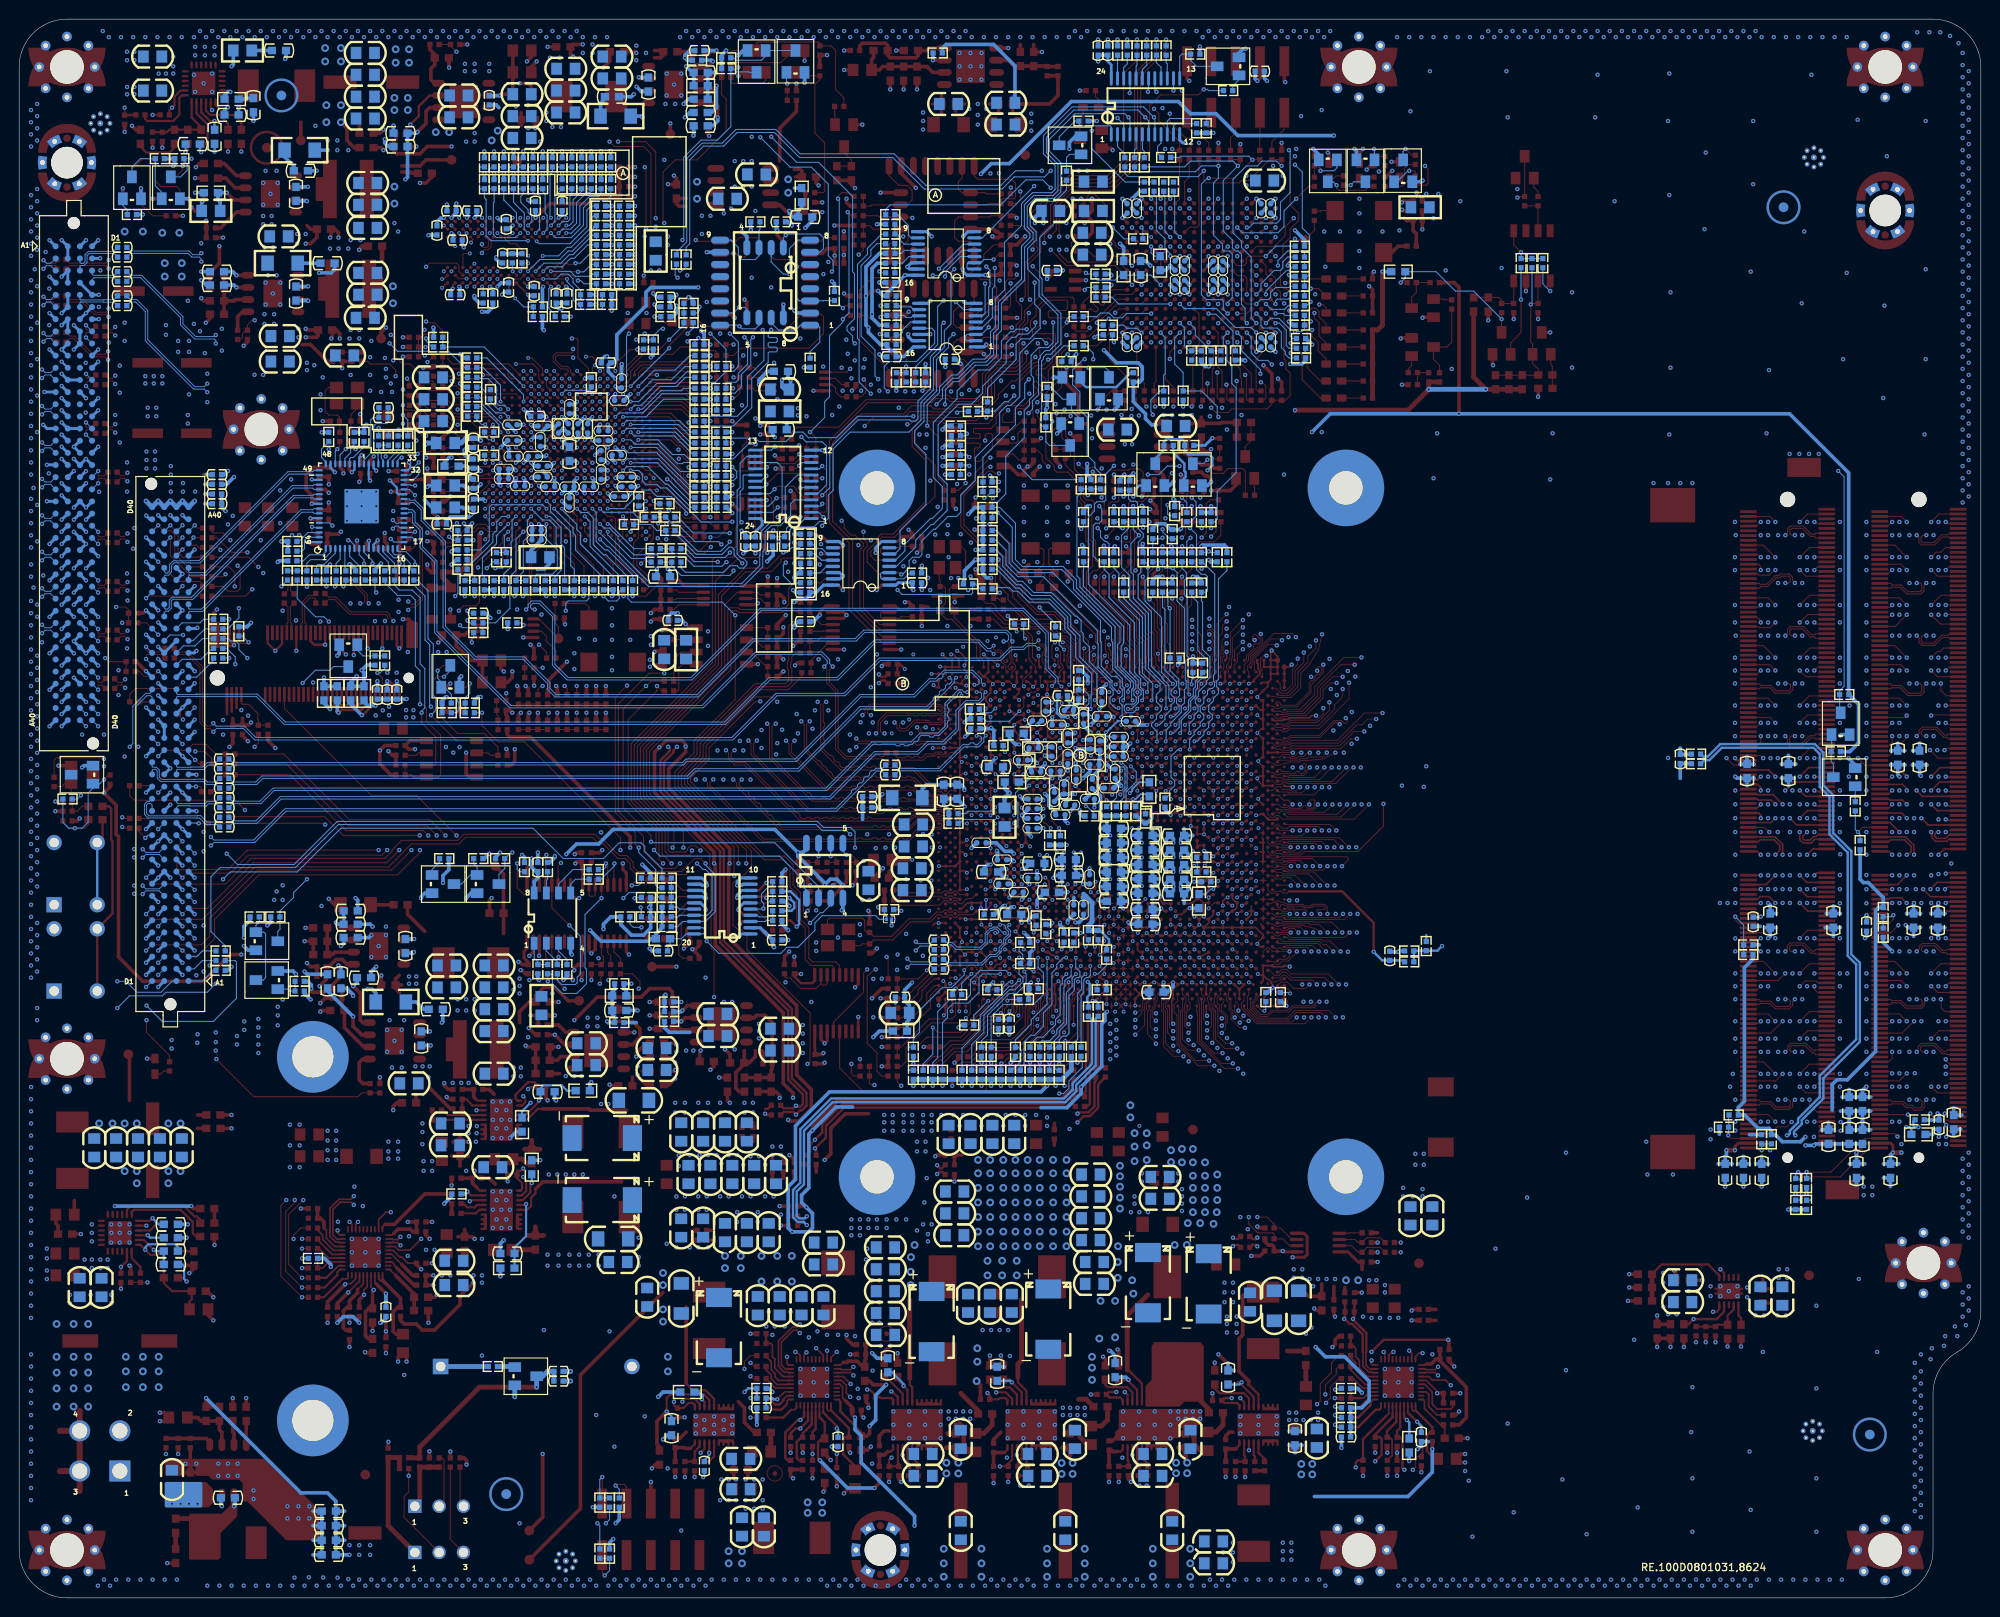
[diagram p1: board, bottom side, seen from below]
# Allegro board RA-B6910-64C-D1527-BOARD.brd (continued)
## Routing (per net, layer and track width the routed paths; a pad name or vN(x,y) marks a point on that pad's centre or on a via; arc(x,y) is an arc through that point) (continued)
M_B_DQ12: length 70
  TOP w0.089: v1(71.39,98.17) 71.38,98.16 71.38,97.55 71.95,96.99 71.95,95.48 72.62,94.8 72.98,94.8 73.22,95.04 73.22,95.51 U43.CU5
  TOP w0.109: v1(23,107.42) 23,107.79 23.24,108.03 J8.24
  SIG1 w0.086: v1(71.39,98.17) 70.11,98.17 65.83,102.45 55.74,102.45 51.61,106.58 51.46,106.58 51.25,106.37 51.25,106.19 54.56,102.88 54.56,102.7 54.35,102.49 54.17,102.49 48.79,107.87 25.44,107.87 25,107.42 v1(23,107.42)
M_B_DQ13: length 70
  TOP w0.089: v1(70.75,98.8) 70.75,97.77 70.85,97.67 71.02,97.51 71.5,97.02 71.66,96.87 71.66,95.35 72.47,94.55 73.1,94.55 73.63,95.07 U43.CT7
  TOP w0.109: J8.25 17.05,107.78 v1(17.4,107.42)
  SIG1 w0.086: v1(17.4,107.42) 18,108.02 18.87,108.02 21.14,110.29 25.32,110.29 25.75,109.86 50.26,109.86 52.29,107.82 52.45,107.82 52.66,108.03 52.66,108.21 52.33,108.54 52.33,108.72 52.54,108.93 52.71,108.93 57.87,103.77 67.06,103.77 70.75,100.08 v1(70.75,98.8)
M_B_DQ14: length 70.1
  TOP w0.089: v1(64.73,98.29) 66.54,98.29 69.61,95.22 69.61,94.4 71.18,92.83 72.76,92.83 U43.CV12
  TOP w0.109: v1(21.48,103.76) 22.24,104.53 J8.38
  SIG1 w0.086: v1(64.73,98.29) 63.97,98.29 62.37,99.89 52.33,99.89 49.3,102.92 37.89,102.92 37.77,103.05 37.77,103.43 37.89,103.56 42.46,103.56 42.59,103.68 42.59,104.17 42.46,104.29 22,104.29 v1(21.48,103.76)
M_B_DQ15: length 70.2
  TOP w0.089: U43.CT12 73.87,92.66 73.11,92.66 72.96,92.51 72.62,92.51 72.5,92.62 70.98,92.62 69.32,94.28 69.32,95.1 66.89,97.53 v1(65.44,97.53)
  TOP w0.109: v1(18.92,103.76) 17.91,104.78 J8.37
  SIG1 w0.086: v1(18.92,103.76) 19.96,104.8 45.39,104.8 45.51,104.67 45.51,104.19 45.39,104.06 43.23,104.06 43.1,103.94 43.1,103.56 43.23,103.43 49.45,103.43 52.54,100.33 63.29,100.33 65.44,98.18 v1(65.44,97.53)
M_B_DQ16: length 67.3
  TOP w0.089: v1(66.69,94.99) 66.69,94.17 67.52,93.33 67.52,92.89 69.23,91.18 72.16,91.18 72.51,90.83 U43.CV16
  TOP w0.109: v1(21.48,101.95) 22.02,101.4 23.17,101.4 23.3,101.53 J8.50
  SIG4 w0.086: v1(66.69,94.99) 66.08,94.99 59.54,101.52 55.29,101.52 55.16,101.65 55.16,102.03 55.29,102.16 58.21,102.16 58.34,102.29 58.34,102.69 58.21,102.81 22.34,102.81 v1(21.48,101.95)
M_B_DQ17: length 67.2
  TOP w0.089: U43.CT16 73.79,90.83 73.65,90.68 73.11,90.68 72.96,90.53 72.53,90.53 72.17,90.89 69.11,90.89 66.03,93.97 v1(66.03,95.65)
  TOP w0.109: J8.49 17.23,101.78 v1(17.4,101.95)
  SIG4 w0.086: v1(17.4,101.95) 17.92,101.43 19.03,101.43 20.86,103.26 58.44,103.26 63.29,98.4 63.48,98.4 63.63,98.55 63.82,98.55 64.02,98.36 64.02,98.16 63.87,98.02 63.87,97.82 64.07,97.63 64.26,97.63 64.41,97.77 64.6,97.77 64.79,97.58 64.79,97.39 64.65,97.24 64.65,97.05 64.84,96.85 65.04,96.85 65.18,97 65.38,97 66.03,96.35 v1(66.03,95.65)
M_B_DQ18: length 67.4
  TOP w0.089: v1(64.44,90.55) 65.5,90.55 67.01,89.04 72.05,89.04 72.25,88.84 U43.CV20
  TOP w0.109: J8.62 23.26,98.53 v1(23,98.26)
  SIG4 w0.086: v1(64.44,90.55) 63.81,90.55 61.19,93.17 61.19,94.22 57.82,97.59 38.65,97.59 38.53,97.71 38.53,98.22 38.65,98.35 43.48,98.35 43.61,98.48 43.61,98.98 43.48,99.11 27.61,99.11 27.28,98.79 23.13,98.79 23,98.66 v1(23,98.26)
M_B_DQ19: length 67.4
  TOP w0.089: v1(65.2,89.79) 65.85,89.79 66.89,88.75 72.06,88.75 72.26,88.54 72.97,88.54 73.12,88.7 73.65,88.7 73.79,88.84 U43.CT20
  TOP w0.109: v1(17.4,98.26) 17.39,98.28 J8.63
  SIG4 w0.086: v1(17.4,98.26) 16.94,98.26 16.81,98.39 16.81,99.78 16.94,99.9 21.25,99.9 21.47,100.12 26.34,100.12 26.86,100.64 47.54,100.64 49.07,99.11 58.17,99.11 65.2,92.09 v1(65.2,89.79)
M_B_DQ20: length 67.2
  TOP w0.089: v1(68.72,92.98) 68.72,92.4 69.38,91.74 72.16,91.74 72.57,91.32 U43.CU15
  TOP w0.109: J8.46 23.41,102.53 23,102.12 v1(23,101.95)
  SIG4 w0.086: v1(23,101.95) 23.42,102.37 54.57,102.37 54.66,102.29 54.66,101.78 54.53,101.65 50.08,101.65 49.96,101.52 49.96,101.14 50.08,101.02 59.43,101.02 65.89,94.55 66.45,94.55 68.02,92.98 v1(68.72,92.98)
M_B_DQ21: length 67.2
  TOP w0.089: U43.CR15 74.02,91.32 73.67,90.97 73.11,90.97 72.96,91.12 72.49,91.12 72.14,91.47 69.36,91.47 68.08,92.75 v1(68.08,93.59)
  TOP w0.109: J8.45 18.1,102.78 v1(18.92,101.95)
  SIG4 w0.086: v1(68.08,93.59) 68.38,93.89 68.38,95.29 64.34,99.33 62.99,99.33 58.1,104.22 21.2,104.22 v1(18.92,101.95)
M_B_DQ22: length 67.3
  TOP w0.089: v1(62.53,92.48) 64.39,92.48 67.25,89.63 72.05,89.63 72.33,89.34 U43.CU19
  TOP w0.109: J8.58 22.74,99.53 v1(21.48,98.26)
  SIG4 w0.086: v1(62.53,92.48) 62.53,93.5 57.94,98.1 44.37,98.1 44.24,98.22 44.24,98.73 44.37,98.86 47.04,98.86 47.16,98.98 47.16,99.49 47.04,99.62 27.35,99.62 26.96,99.23 22.44,99.23 v1(21.48,98.26)
M_B_DQ23: length 67.1
  TOP w0.089: v1(63.19,91.85) 64.08,91.85 64.69,91.25 65.22,91.25 67.13,89.34 72.05,89.34 72.24,89.15 73.23,89.15 73.38,88.99 73.67,88.99 74.02,89.34 U43.CR19
  TOP w0.109: J8.59 17.86,99.28 18.87,98.26 v1(18.92,98.26)
  SIG4 w0.086: v1(18.92,98.26) 18.92,99.31 19.08,99.46 19.48,99.46 19.6,99.33 19.6,98.86 19.73,98.73 20.11,98.73 20.24,98.86 20.24,99.33 20.37,99.46 21.45,99.46 21.66,99.67 26.64,99.67 27.1,100.13 47.29,100.13 48.81,98.6 58.06,98.6 63.19,93.47 v1(63.19,91.85)
M_B_DQ24: length 66.4
  TOP w0.089: v1(68.35,88.34) 68.79,87.89 70.24,87.89 70.43,87.71 71.17,87.71 71.33,87.56 73.33,87.56 U43.CU24
  TOP w0.109: v1(23,96.92) 23.4,96.53 J8.70
  SIG1 w0.086: v1(68.35,88.34) 60.49,96.19 29,96.19 28.88,96.32 28.88,96.67 29,96.8 33.57,96.8 33.7,96.93 33.7,97.24 33.57,97.37 25.36,97.37 24.91,96.92 v1(23,96.92)
M_B_DQ25: length 66.4
  TOP w0.089: U43.CR24 73.84,87.18 73.72,87.06 73.59,87.01 73.4,87.01 72.38,87.31 72.2,87.36 71.19,87.36 71.05,87.51 70.5,87.51 68.76,87.67 v1(67.46,88.34)
  TOP w0.109: v1(18.92,96.92) 18.28,96.28 J8.71
  SIG1 w0.086: v1(67.46,88.34) 60.11,95.68 26.97,95.68 26.84,95.81 26.84,96.19 26.97,96.32 28.11,96.32 28.24,96.44 28.24,96.8 28.11,96.93 26.69,96.93 25.95,96.19 19.66,96.19 v1(18.92,96.92)
M_B_DQ26: length 66.3
  TOP w0.089: v1(66.32,86.79) 67.78,85.32 72.39,85.32 72.45,85.38 U43.CU28
  TOP w0.109: v1(17.4,93.26) 17.39,93.28 J8.83
  SIG1 w0.086: v1(66.32,86.79) 66.22,86.79 60.75,92.25 39.29,92.25 39.16,92.38 39.16,92.89 39.29,93.02 41.32,93.02 41.45,93.14 41.45,93.65 41.32,93.78 17.91,93.78 v1(17.4,93.26)
M_B_DQ27: length 66.4
  TOP w0.089: U43.CR28 74.02,85.38 73.67,85.03 73.11,85.03 72.95,85.19 72.54,85.19 72.49,85.13 67.41,85.13 65.75,86.79 v1(65.55,86.79)
  TOP w0.109: v1(23,93.26) 23.24,93.03 J8.84
  SIG1 w0.086: v1(65.55,86.79) 60.6,91.75 34.21,91.75 34.08,91.87 34.08,92.38 34.21,92.51 38.27,92.51 38.4,92.63 38.4,93.14 38.27,93.27 26.72,93.27 26.08,92.63 23.41,92.63 23,93.05 v1(23,93.26)
M_B_DQ28: length 66.2
  TOP w0.089: U43.CV23 72.26,87.85 72.15,87.75 71.51,87.75 71.32,87.94 70.77,87.94 70.64,88.06 70.44,88.27 70.2,88.27 v1(70.13,88.34)
  TOP w0.109: J8.66 22.08,97.53 v1(21.48,96.92)
  SIG1 w0.086: v1(21.48,96.92) 22.37,97.81 37.64,97.81 37.77,97.69 37.77,97.33 37.64,97.21 34.46,97.21 34.34,97.08 34.34,96.76 34.46,96.63 60.68,96.63 67.49,89.82 68.65,89.82 v1(70.13,88.34)
M_B_DQ29: length 66
  TOP w0.089: U43.CT23 73.25,87.85 73.08,88.03 73.08,88.03 72.96,88.15 72.29,88.15 72.07,87.94 71.74,87.94 71.34,88.34 v1(71.02,88.34)
  TOP w0.109: v1(17.4,96.92) 17.05,97.28 J8.67
  SIG1 w0.086: v1(17.4,96.92) 18,97.52 19.29,97.52 20.62,98.86 25.83,98.86 26.4,98.28 39.54,98.28 39.67,98.15 39.67,97.82 39.54,97.69 38.78,97.69 38.65,97.56 38.65,97.21 38.78,97.08 62.01,97.08 70.75,88.34 v1(71.02,88.34)
M_B_DQ30: length 66
  TOP w0.089: U43.CV27 72.42,85.87 72.28,85.74 69.65,85.74 v1(68.6,86.79)
  TOP w0.109: v1(18.92,93.26) 17.91,94.28 J8.79
  SIG1 w0.086: v1(68.6,86.79) 67.74,85.92 64.43,85.92 60.06,90.3 59.63,90.73 28.37,90.73 28.24,90.86 28.24,91.24 28.37,91.36 29.89,91.36 30.02,91.49 30.02,91.87 29.89,92 27.73,92 26.46,90.73 21.46,90.73 v1(18.92,93.26)
M_B_DQ31: length 66.6
  TOP w0.089: v1(67.84,86.79) 69.11,85.51 72.31,85.51 72.37,85.57 72.95,85.57 73.11,85.73 73.65,85.73 73.8,85.87 U43.CT27
  TOP w0.109: v1(21.48,93.26) 22.24,94.03 J8.80
  SIG1 w0.086: v1(21.48,93.26) 21.48,92.67 21.8,92.34 22.74,92.34 23.34,91.75 25.19,91.75 25.45,92 26.34,92 26.97,92.63 33.32,92.63 33.45,92.51 33.45,92 33.32,91.87 30.78,91.87 30.65,91.75 30.65,91.36 30.78,91.24 59.74,91.24 64.62,86.36 67.42,86.36 v1(67.84,86.79)
M_B_DQ32: length 69.2
  TOP w0.089: v1(69.39,64.11) 69.84,64.57 72.14,64.57 72.64,65.07 72.93,65.07 73.2,64.8 U43.CT73
  TOP w0.109: v1(23,68.95) 23.42,68.53 J8.174
  SIG4 w0.086: v1(23,68.95) 23,69.23 23.17,69.4 23.8,69.4 24,69.19 24.73,69.19 24.94,69.4 26.08,69.4 26.29,69.19 26.89,69.19 27.1,69.4 47.93,69.4 51.84,65.49 51.84,65.31 51.57,65.04 51.39,65.04 47.7,68.73 47.52,68.73 47.25,68.47 47.25,68.29 51.1,64.44 65.71,64.44 65.83,64.31 65.83,63.82 65.96,63.69 69.26,63.69 69.39,63.82 v1(69.39,64.11)
M_B_DQ33: length 69.2
  TOP w0.089: v1(70.15,64.11) 70.59,63.68 71.8,63.68 72.49,64.37 73.14,64.37 U43.CU74
  TOP w0.109: v1(17.4,68.95) 17.23,68.78 J8.173
  SIG4 w0.086: v1(70.15,64.11) 69.48,64.78 66.98,65.81 66.85,65.86 56.45,65.86 52.16,70.15 51.98,70.15 51.77,69.94 51.77,69.76 54.25,67.28 54.25,67.06 54.08,66.89 53.89,66.89 50.06,70.72 19.18,70.72 v1(17.4,68.95)
M_B_DQ34: length 69.2
  TOP w0.089: v1(71.49,60.67) 71.96,60.2 75.58,60.2 76.99,61.61 U43.CJ78
  TOP w0.109: v1(17.4,65.26) 17.39,65.28 J8.187
  SIG4 w0.086: v1(71.49,60.67) 71.04,61.12 70.28,61.12 69.55,61.85 68.22,61.85 67.63,62.44 50.69,62.44 46.91,66.22 44.37,66.22 44.24,66.35 44.24,66.73 44.37,66.85 45.64,66.85 45.77,66.98 45.77,67.36 45.64,67.49 26.45,67.49 26.08,67.12 21.47,67.12 20.53,66.18 18.32,66.18 v1(17.4,65.26)
M_B_DQ35: length 69.1
  TOP w0.089: v1(69.97,60.67) 70.63,60.01 75.67,60.01 77.29,61.63 77.29,62.13 76.99,62.43 U43.CJ76
  TOP w0.109: J8.186 23.26,65.53 v1(23,65.26)
  SIG4 w0.086: v1(69.97,60.67) 69.23,61.41 68.04,61.41 67.45,62 50.51,62 46.79,65.71 40.31,65.71 40.18,65.84 40.18,66.22 40.31,66.35 43.61,66.35 43.73,66.47 43.73,66.85 43.61,66.98 26.59,66.98 26.28,66.67 24.41,66.67 v1(23,65.26)
M_B_DQ36: length 69.2
  TOP w0.089: v1(67.1,64.11) 68.2,65.21 72.06,65.21 72.54,65.69 73.04,65.69 73.34,65.39 U43.CU71
  TOP w0.109: v1(21.48,68.95) 22.05,69.53 J8.170
  SIG4 w0.086: v1(21.48,68.95) 21.48,69.05 21.26,69.27 20.75,69.27 20.62,69.39 20.62,69.71 20.75,69.84 48.12,69.84 52.98,64.98 53.19,64.98 53.36,65.15 53.36,65.37 50.63,68.11 50.63,68.28 50.84,68.49 51.02,68.49 54.53,64.98 66.24,64.98 v1(67.1,64.11)
M_B_DQ37: length 68.9
  TOP w0.089: U43.CR71 74.31,65.58 73.8,65.07 73.34,65.07 73,65.41 72.62,65.41 72.04,64.83 68.58,64.83 v1(67.86,64.11)
  TOP w0.109: J8.169 18.1,69.78 v1(18.92,68.95)
  SIG4 w0.086: v1(18.92,68.95) 20.26,70.28 48.3,70.28 50.05,68.53 50.23,68.53 50.44,68.74 50.44,68.91 49.48,69.88 49.48,70.06 49.69,70.27 49.89,70.27 54.74,65.42 54.93,65.42 55.1,65.59 55.1,65.81 54.51,66.4 54.51,66.58 54.72,66.79 54.9,66.79 56.26,65.42 66.56,65.42 v1(67.86,64.11)
M_B_DQ38: length 69.3
  TOP w0.089: v1(67.43,60.67) 68.15,61.39 71.67,61.39 72.49,60.58 75.4,60.58 76.35,61.53 76.35,62.57 U43.CL77
  TOP w0.109: J8.183 17.91,66.28 v1(18.92,65.26)
  SIG4 w0.086: v1(67.43,60.67) 66.98,61.11 50.11,61.11 46.53,64.69 35.86,64.69 35.73,64.82 35.73,65.2 35.86,65.33 37,65.33 37.13,65.46 37.13,65.84 37,65.96 27.22,65.96 25.63,64.37 19.82,64.37 v1(18.92,65.26)
M_B_DQ39: length 69.2
  TOP w0.089: U43.CK75 76.5,63.02 76.65,62.87 76.65,61.55 75.48,60.39 72.35,60.39 71.56,61.18 68.95,61.18 v1(68.44,60.67)
  TOP w0.109: v1(21.48,65.26) 22.74,66.53 J8.182
  SIG4 w0.086: v1(68.44,60.67) 68.15,60.96 67.85,60.96 67.26,61.55 50.3,61.55 47.04,64.82 46.66,65.2 37.89,65.2 37.77,65.33 37.77,65.71 37.89,65.84 39.54,65.84 39.67,65.96 39.67,66.35 39.54,66.47 26.84,66.47 26.6,66.23 25.46,66.23 24.04,64.81 21.93,64.81 v1(21.48,65.26)
M_B_DQ40: length 73.1
  TOP w0.089: U43.CF77 78.37,62.5 78.37,61.6 78.17,61.4 78.17,60.86 v1(77.98,60.66)
  TOP w0.109: v1(17.4,63.92) 17.4,63.62 17.05,63.28 J8.195
  SIG1 w0.086: v1(77.98,60.66) 78.04,60.72 78.04,61.56 76.87,62.72 73.8,62.72 72.83,63.69 52.31,63.69 49.33,66.68 49.15,66.68 48.94,66.47 48.94,66.29 49.63,65.59 49.63,65.38 49.46,65.21 49.24,65.21 47.33,67.12 18.6,67.12 17.95,66.47 17.95,64.48 v1(17.4,63.92)
M_B_DQ41: length 73.3
  TOP w0.089: v1(76.9,59.58) 77.45,59.58 78.36,60.5 78.36,61.32 78.56,61.52 78.56,62.2 78.83,62.46 78.83,62.75 78.62,62.96 78.62,63.46 U43.CF75
  TOP w0.109: J8.194 23.4,63.53 v1(23,63.92)
  SIG1 w0.086: v1(23,63.92) 24.93,63.92 25.38,64.37 43.37,64.37 44.79,62.95 45.01,62.95 45.18,63.12 45.18,63.34 43.24,65.29 43.24,65.41 43.49,65.67 43.62,65.67 47,62.3 47.18,62.3 47.39,62.51 47.39,62.69 46.24,63.83 46.24,64.05 46.41,64.22 46.63,64.22 48.49,62.36 66.65,62.36 67.91,61.1 71.67,61.1 72.07,60.69 75.43,60.69 76.53,59.58 v1(76.9,59.58)
M_B_DQ42: length 73.3
  TOP w0.089: U43.CB77 80.46,61.57 80.17,61.28 80.17,58.17 v1(80.32,58.01)
  TOP w0.109: v1(17.4,60.26) 17.39,60.28 J8.207
  SIG1 w0.086: v1(17.4,60.26) 17.4,59.53 17.63,59.3 26.66,59.3 28.11,60.76 29,60.76 30.46,59.3 62.21,59.3 64.21,57.3 74.3,57.3 75.64,55.97 77.68,55.97 79.72,58.01 v1(80.32,58.01)
M_B_DQ43: length 73.2
  TOP w0.089: U43.CB75 80.63,62.93 80.81,62.75 80.81,62.53 80.65,62.04 80.65,61.5 80.4,61.24 80.4,59.78 v1(80.86,59.31)
  TOP w0.109: v1(23,60.26) 23.24,60.03 J8.208
  SIG1 w0.086: v1(23,60.26) 23,60.16 23.41,59.74 26.34,59.74 27.86,61.27 32.76,61.27 32.89,61.14 32.89,60.63 32.76,60.5 30.78,60.5 30.65,60.38 30.65,59.87 30.78,59.74 62.67,59.74 64.67,57.74 74.49,57.74 75.82,56.41 77.49,56.41 80.4,59.31 v1(80.86,59.31)
M_B_DQ44: length 73.1
  TOP w0.089: v1(76.52,60.3) 77.06,60.3 77.98,61.22 77.98,61.87 U43.CG78
  TOP w0.109: v1(18.92,63.92) 18.38,64.47 17.23,64.47 17.04,64.28 J8.191
  SIG1 w0.086: v1(76.52,60.3) 76.52,60.33 75.11,61.74 74.4,61.74 73.79,61.13 72.7,61.13 71.03,62.81 50.22,62.81 49.09,63.94 48.88,63.94 48.7,63.76 48.7,63.55 49.05,63.2 49.05,63.02 48.84,62.81 48.69,62.81 45.31,66.19 45.1,66.19 44.9,65.98 44.9,65.8 46.03,64.67 46.03,64.46 45.85,64.29 45.64,64.29 43.69,66.23 28,66.23 26.58,64.81 23.33,64.81 23.08,64.57 19.57,64.57 v1(18.92,63.92)
M_B_DQ45: length 73.3
  TOP w0.089: U43.CG76 77.98,62.87 77.87,62.76 77.87,62.28 77.59,62 v1(77.59,61.38)
  TOP w0.109: v1(20.45,65.26) 21.19,64.53 J8.190
  SIG1 w0.086: v1(77.59,61.38) 76.69,62.28 72.51,62.28 71.54,63.25 51.98,63.25 50.16,65.06 49.94,65.06 49.77,64.89 49.77,64.68 50.68,63.76 50.68,63.55 50.51,63.38 50.29,63.38 47.4,66.27 47.22,66.27 47.01,66.06 47.01,65.88 48.05,64.84 48.05,64.62 47.88,64.45 47.69,64.45 45.47,66.67 26.79,66.67 26.08,65.96 21.15,65.96 v1(20.45,65.26)
M_B_DQ46: length 73.2
  TOP w0.089: v1(78.25,57.96) 78.93,57.96 79.74,58.76 79.74,61.6 79.96,61.83 U43.CC78
  TOP w0.109: J8.203 17.91,61.28 v1(18.92,60.26)
  SIG1 w0.086: v1(78.25,57.96) 75.52,57.96 74.76,58.73 65.22,58.73 63.32,60.63 35.99,60.63 35.86,60.76 35.86,61.39 35.99,61.52 36.83,61.52 36.95,61.65 36.95,62.28 36.83,62.41 26.97,62.41 25.95,61.39 20.05,61.39 v1(18.92,60.26)
M_B_DQ47: length 73.3
  TOP w0.089: U43.CC76 79.96,62.88 80.11,62.73 80.11,62.19 80.26,62.04 80.26,61.65 79.97,61.36 79.97,58.36 79.03,57.42 v1(77.71,57.42)
  TOP w0.109: J8.204 22.24,61.03 v1(21.48,60.26)
  SIG1 w0.086: v1(77.71,57.42) 75.43,57.42 74.59,58.26 65.06,58.26 63.14,60.18 33.7,60.18 33.57,60.31 33.57,60.88 33.7,61.01 34.97,61.01 35.1,61.14 35.1,61.77 34.97,61.9 27.48,61.9 26.34,60.76 21.97,60.76 v1(21.48,60.26)
M_B_DQ48: length 78.2
  TOP w0.089: v1(77.63,55.32) 79.06,55.32 81.86,58.12 81.86,61.24 81.94,61.31 U43.BW78
  TOP w0.109: v1(23,58.45) 23.42,58.03 J8.216
  SIG4 w0.086: v1(23,58.45) 23,58.56 23.37,58.93 42.77,58.93 43.27,58.43 53.27,58.43 53.4,58.29 53.4,57.07 53.53,56.95 53.82,56.95 53.95,57.07 53.95,58.29 54.09,58.43 54.36,58.43 54.5,58.29 54.5,57.07 54.63,56.95 54.92,56.95 55.05,57.07 55.05,58.29 55.19,58.43 55.46,58.43 55.6,58.29 55.6,57.07 55.72,56.95 56.02,56.95 56.15,57.07 56.15,58.29 56.28,58.43 56.56,58.43 56.69,58.29 56.69,57.07 56.82,56.95 57.12,56.95 57.24,57.07 57.24,58.22 57.37,58.34 57.66,58.34 57.79,58.22 57.79,57.04 57.93,56.9 74.92,56.9 76.5,55.32 v1(77.63,55.32)
M_B_DQ49: length 78.5
  TOP w0.089: v1(78.17,55.85) 79.33,55.85 81.64,58.17 81.64,62.04 81.8,62.19 81.8,62.96 U43.BW76
  TOP w0.109: J8.215 17.23,58.28 v1(17.4,58.45)
  SIG4 w0.086: v1(78.17,55.85) 76.59,55.85 75.1,57.34 60.89,57.34 60.74,57.49 60.74,58.6 60.61,58.73 60.32,58.73 60.19,58.6 60.19,57.71 60.06,57.58 59.77,57.58 59.64,57.71 59.64,58.6 59.52,58.73 59.22,58.73 59.09,58.6 59.09,57.87 58.94,57.72 58.7,57.72 58.55,57.87 58.55,58.72 58.39,58.87 43.59,58.87 43.09,59.37 22.4,59.37 21.98,58.96 20.25,58.96 19.16,57.87 17.8,57.87 17.4,58.26 v1(17.4,58.45)
M_B_DQ50: length 78.3
  TOP w0.089: U43.BP78 83.81,61.76 83.81,57.91 82.06,56.16 v1(80.65,56.16)
  TOP w0.109: v1(23,54.76) 23.26,55.03 J8.228
  SIG4 w0.086: v1(23,54.76) 24.09,55.85 26.51,55.85 27.22,56.57 41.45,56.57 41.58,56.44 41.58,55.8 41.45,55.68 38.53,55.68 38.4,55.55 38.4,54.89 38.53,54.76 73.83,54.76 75.51,53.09 78.98,53.09 80.65,54.75 v1(80.65,56.16)
M_B_DQ51: length 78.4
  TOP w0.089: U43.BP76 83.92,62.39 84.31,62.01 84.31,61.2 84,60.89 84,57.83 81.79,55.62 v1(80.11,55.62)
  TOP w0.109: v1(17.4,54.76) 17.39,54.78 J8.229
  SIG4 w0.086: v1(80.11,55.62) 80.11,54.84 78.8,53.53 75.73,53.53 74.04,55.22 43.61,55.22 41.75,57.07 26.99,57.07 26.21,56.29 18.44,56.29 17.4,55.25 v1(17.4,54.76)
M_B_DQ52: length 78.3
  TOP w0.089: v1(79.25,56.93) 80.14,56.93 81.45,58.24 U43.BY77
  TOP w0.109: v1(18.92,58.45) 18.1,59.28 J8.211
  SIG4 w0.086: v1(79.25,56.93) 78.54,56.93 77.9,56.3 76.77,56.3 75.29,57.78 64.61,57.78 64.47,57.92 64.47,58.85 64.35,58.98 64.05,58.98 63.93,58.85 63.93,58.09 63.8,57.96 63.5,57.96 63.38,58.09 63.38,58.98 63.25,59.11 62.96,59.11 62.83,58.98 62.83,58.38 62.68,58.23 62.43,58.23 62.28,58.38 62.28,58.98 62.15,59.11 61.86,59.11 61.73,58.98 61.73,58.34 61.6,58.22 61.31,58.22 61.18,58.34 61.18,59.18 61.05,59.31 44.04,59.31 43.53,59.81 22.22,59.81 21.8,59.4 19.77,59.4 18.92,58.55 v1(18.92,58.45)
M_B_DQ53: length 78.3
  TOP w0.089: U43.BY75 81.45,63.1 81.09,62.75 81.09,62.44 81.25,62.29 81.25,60.46 v1(80.86,60.07)
  TOP w0.109: J8.212 21.95,59.03 v1(20.71,60.26)
  SIG4 w0.086: v1(20.71,60.26) 20.71,60.47 21.16,60.91 25.8,60.91 26.43,60.28 44.01,60.28 44.54,59.75 65.04,59.75 65.17,59.62 65.17,58.36 65.31,58.23 65.59,58.23 65.72,58.36 65.72,59.62 65.86,59.75 66.13,59.75 66.27,59.62 66.27,58.36 66.41,58.23 66.68,58.23 66.82,58.36 66.82,59.62 66.96,59.75 67.23,59.75 67.37,59.62 67.37,58.6 67.5,58.47 67.79,58.47 67.92,58.6 67.92,59.62 68.05,59.75 75.37,59.75 77.42,61.8 79.14,61.8 v1(80.86,60.07)
M_B_DQ54: length 78.7
  TOP w0.089: U43.BR77 83.43,61.58 83.62,61.39 83.62,57.99 82.87,57.23 v1(81.72,57.23)
  TOP w0.109: v1(21.48,54.76) 22.74,56.03 J8.224
  SIG4 w0.086: v1(21.48,54.76) 21.93,54.31 26.37,54.31 28.11,56.06 37.64,56.06 37.77,55.93 37.77,55.3 37.64,55.17 36.88,55.17 36.75,55.04 36.75,54.44 36.88,54.31 73.63,54.31 75.3,52.65 79.17,52.65 81.41,54.89 81.41,55.99 81.72,56.31 v1(81.72,57.23)
M_B_DQ55: length 78.4
  TOP w0.089: U43.BR75 83.43,63.1 83.08,62.75 83.08,62.19 83.23,62.04 83.23,61.51 83.43,61.31 83.43,58.39 82.81,57.77 v1(82.26,57.77)
  TOP w0.109: J8.225 17.91,55.78 v1(18.92,54.76)
  SIG4 w0.086: v1(82.26,57.77) 82.25,57.76 82.25,56.19 81.85,55.8 81.85,54.7 79.35,52.2 75.12,52.2 73.45,53.87 19.82,53.87 v1(18.92,54.76)
M_B_DQ56: length 81.6
  TOP w0.089: U43.BL77 85.6,62.41 85.6,61.36 85.41,61.16 85.41,57.64 84.37,56.61 v1(83.32,56.61)
  TOP w0.109: v1(18.92,53.42) 18.28,52.78 J8.237
  SIG1 w0.086: v1(83.32,56.61) 83.32,56.01 80.56,53.24 73.8,53.24 73.15,53.9 32.3,53.9 32.18,54.03 32.18,54.41 32.3,54.53 33.4,54.53 33.52,54.66 33.52,55.04 33.4,55.17 27.83,55.17 26.97,54.31 25.73,54.31 25.18,53.76 23.37,53.76 23.26,53.87 19.38,53.87 v1(18.92,53.42)
M_B_DQ57: length 81.4
  TOP w0.089: U43.BL75 85.41,63.09 85.07,62.75 85.07,62.47 85.41,62.13 85.41,61.45 85.2,61.24 85.2,57.95 84.4,57.14 v1(83.86,57.14)
  TOP w0.109: J8.236 23.4,53.03 v1(23,53.42)
  SIG1 w0.086: v1(23,53.42) 23.11,53.31 25.37,53.31 25.93,53.87 27.22,53.87 28.01,54.66 31.54,54.66 31.67,54.53 31.67,54.18 31.54,54.05 28.24,54.05 28.11,53.92 28.11,53.57 28.24,53.44 72.77,53.44 73.41,52.8 80.75,52.8 83.86,55.92 v1(83.86,57.14)
M_B_DQ58: length 81.7
  TOP w0.089: v1(88.37,61.16) 88.12,61.16 87.58,61.7 87.58,62.41 U43.BG77
  TOP w0.109: v1(17.4,49.76) 17.39,49.78 J8.249
  SIG1 w0.086: v1(88.37,61.16) 86.66,59.46 86.66,55.58 81.55,50.47 71.41,50.47 70.78,51.11 26.21,51.11 25.9,50.8 18.92,50.8 18.15,50.52 v1(17.4,49.76)
M_B_DQ59: length 81.5
  TOP w0.089: U43.BG75 87.39,63.1 87.01,62.72 87.01,62.49 87.39,62.11 87.39,61.61 87.71,61.29 87.71,61.06 v1(88.37,60.4)
  TOP w0.109: J8.250 23.24,49.53 v1(23,49.76)
  SIG1 w0.086: v1(88.37,60.4) 87.1,59.14 87.1,55.4 81.67,49.96 71.04,49.96 70.4,50.6 30.78,50.6 30.65,50.47 30.65,50.09 30.53,49.96 30.15,49.96 30.02,50.09 30.02,50.47 29.89,50.6 29.51,50.6 29.38,50.47 29.38,50.09 29.26,49.96 28.88,49.96 28.75,50.09 28.75,50.47 28.62,50.6 28.24,50.6 28.11,50.47 28.11,50.09 27.99,49.96 27.61,49.96 27.48,50.09 27.48,50.47 27.35,50.6 26.97,50.6 26.84,50.47 26.84,49.96 26.72,49.84 26.34,49.84 26.21,49.96 26.21,50.09 26.08,50.22 23.29,50.22 23,49.93 v1(23,49.76)
M_B_DQ60: length 81.6
  TOP w0.089: U43.BM78 84.8,61.75 84.8,59.63 v1(84.4,59.23)
  TOP w0.109: v1(20.71,54.76) 21.45,54.03 J8.232
  SIG1 w0.086: v1(20.71,54.76) 21.6,55.66 26.46,55.66 26.99,56.19 39.92,56.19 40.05,56.06 40.05,55.68 39.92,55.55 36.62,55.55 36.5,55.42 36.5,55.04 36.62,54.92 73.45,54.92 74.24,54.13 79.43,54.13 84.4,59.1 v1(84.4,59.23)
M_B_DQ61: length 81.6
  TOP w0.089: v1(84.4,58.47) 85,59.07 85,61.49 85.21,61.7 85.21,62.04 84.86,62.39 84.86,63.05 U43.BM76
  TOP w0.109: v1(17.4,53.42) 17.05,53.78 J8.233
  SIG1 w0.086: v1(84.4,58.47) 79.62,53.69 73.99,53.69 73.26,54.41 34.21,54.41 34.08,54.53 34.08,54.92 34.21,55.04 35.86,55.04 35.99,55.17 35.99,55.55 35.86,55.68 27.31,55.68 26.84,55.21 25.72,55.21 24.82,54.31 18.29,54.31 v1(17.4,53.42)
M_B_DQ62: length 81.5
  TOP w0.089: U43.BH78 86.89,61.53 87.09,61.33 87.09,58.92 86.21,58.04 v1(86.21,57.92)
  TOP w0.109: v1(17.91,52.07) 17.91,51.56 17.13,50.78 J8.245
  SIG1 w0.086: v1(86.21,57.92) 86.21,55.86 81.33,50.98 71.73,50.98 70.97,51.74 26.16,51.74 25.7,51.28 17.57,51.28 17.45,51.41 17.45,51.94 17.57,52.07 v1(17.91,52.07)
M_B_DQ63: length 81.9
  TOP w0.089: U43.BH76 86.82,63.03 86.82,62.41 87.19,62.04 87.19,61.53 87.38,61.34 87.38,59.84 v1(88.37,58.86)
  TOP w0.109: v1(21.48,49.76) 22.24,50.53 J8.246
  SIG1 w0.086: v1(21.48,49.76) 21.93,49.31 27.08,49.31 27.22,49.45 30.91,49.45 31.42,49.96 70.02,49.96 70.53,49.45 81.79,49.45 87.55,55.21 87.55,58.96 87.67,59.08 88.21,59.08 88.37,58.93 v1(88.37,58.86)
M_B_DQS_DN0: length 74.9
  TOP w0.089: U43.CJ1 76.83,98 76.73,98.1 76.73,98.5 76.03,99.2 76.03,99.6 75.93,99.7 75.52,99.7 75.24,99.99 75.24,100.13 75.79,100.68 75.94,100.68 76.13,100.49 76.13,100.34 v1(75.89,100.1)
  TOP w0.109: v1(20.43,111.07) 20.19,111.31 20.19,111.73 19.91,112.01 18.55,112.01 17.71,111.18 17.34,111.18 17.24,111.28 J8.11
  SIG4 w0.086: v1(75.89,100.1) 75.43,100.1 75.23,99.91 74.75,99.91 72.83,101.83 70.83,101.83 63.84,108.82 31.33,108.82 31.09,109.06 31.09,110.3 31.33,110.54 31.8,110.54 31.92,110.67 31.92,111.6 31.8,111.73 20.16,111.73 20.04,111.6 20.04,111.22 20.19,111.07 v1(20.43,111.07)
M_B_DQS_DN1: length 70.4
  TOP w0.089: U43.CU10 73.68,93.45 73.68,93.56 73.59,93.64 73.37,93.64 73.17,93.44 73.17,93.36 73.11,93.29 71.59,93.29 70.2,94.69 70.2,95.63 69.97,95.86 69.83,95.86 69.69,95.99 69.59,96.09 69.59,96.33 69.42,96.5 69.19,96.5 68.91,96.78 68.91,96.97 68.91,97.16 69.09,97.33 69.21,97.33 69.35,97.19 v1(69.35,96.9)
  TOP w0.109: v1(19.43,106.07) 19.67,106.31 19.67,106.67 20.01,107.01 20.93,107.01 21.1,106.84 21.49,106.84 22.4,105.93 23.06,105.93 23.16,106.03 J8.32
  SIG1 w0.086: v1(19.43,106.07) 19.55,106.07 19.79,106.3 19.79,106.59 20.1,106.91 21.87,106.91 22.23,106.55 48.64,106.55 53.5,101.7 64.26,101.7 66.19,99.77 67.81,99.77 69.76,97.82 69.76,97.3 v1(69.35,96.9)
M_B_DQS_DN2: length 67.5
  TOP w0.089: v1(66.37,91.95) 66.18,91.76 66.18,91.55 66.33,91.4 66.54,91.4 66.84,91.7 67.57,91.7 69.16,90.11 72.19,90.11 72.46,89.83 U43.CV18
  TOP w0.109: v1(20.43,100.57) 20.21,100.78 20.21,101.21 19.92,101.51 18.55,101.51 17.71,100.68 17.34,100.68 17.24,100.78 J8.53
  SIG4 w0.086: v1(66.37,91.95) 66.58,91.74 67.01,91.74 67.36,92.08 67.36,92.47 66.74,93.08 65.61,93.08 58.82,99.87 49.55,99.87 47.97,101.45 26.55,101.45 26.23,101.14 23.53,101.14 23.35,101.32 20.17,101.32 19.83,100.98 19.83,100.72 19.98,100.57 v1(20.43,100.57)
M_B_DQS_DN3: length 67
  TOP w0.089: v1(71.02,86.79) 70.88,87.03 70.72,87.19 70.6,87.19 70.49,87.08 70.49,86.95 70.62,86.83 70.62,86.37 70.85,86.13 71.04,86.13 71.25,86.35 71.52,86.35 71.74,86.13 72.14,86.13 72.37,86.36 73.02,86.36 73.25,86.59 arc(73.32,86.6) 73.39,86.6 arc(73.43,86.58) 73.46,86.54 U43.CU26
  TOP w0.109: J8.74 23.16,95.53 23,95.36 21.96,95.36 21.4,94.8 20.08,94.8 19.88,94.99 19.88,95.4 20.05,95.57 v1(20.43,95.57)
  SIG1 w0.086: v1(71.02,86.79) 71.02,87.51 70.61,87.91 66.4,87.91 59.62,94.69 20.15,94.69 19.83,95.02 19.83,95.41 19.98,95.57 v1(20.43,95.57)
M_B_DQS_DN4: length 69
  TOP w0.089: v1(69.13,62.3) 69.35,62.3 69.48,62.17 69.48,61.9 69.69,61.68 71.89,61.68 72.34,61.23 74.06,61.23 74.52,60.77 75.3,60.77 76.16,61.63 76.16,62.27 75.8,62.63 75.8,62.83 75.72,62.91 U43.CM76
  TOP w0.109: v1(20.43,67.57) 20.22,67.77 20.22,68.16 19.93,68.45 18.51,68.45 17.67,67.61 17.41,67.61 17.24,67.78 J8.177
  SIG4 w0.086: v1(20.43,67.57) 20.03,67.57 19.91,67.69 19.91,68.14 20.02,68.25 45.99,68.25 50.89,63.35 65.11,63.35 65.47,63 69.22,63 69.63,62.59 69.63,62.48 69.45,62.3 v1(69.13,62.3)
M_B_DQS_DN5: length 73.5
  TOP w0.089: v1(79.32,59.04) 78.94,59.43 78.94,59.92 78.75,60.11 78.75,60.82 79.35,61.43 79.35,62.01 79.1,62.26 79.1,62.49 79.21,62.61 U43.CD77
  TOP w0.109: J8.198 23.16,62.53 23,62.36 21.96,62.36 21.4,61.8 20.11,61.8 19.91,62 19.91,62.4 20.08,62.57 v1(20.43,62.57)
  SIG1 w0.086: v1(79.32,59.04) 79.12,59.24 78.57,59.24 77.73,58.4 76.25,58.4 74.91,59.74 65.8,59.74 64.12,61.42 44.6,61.42 42.81,63.21 25.61,63.21 25.32,62.92 21.68,62.92 21.38,63.21 19.97,63.21 19.82,63.06 19.82,62.74 19.99,62.57 v1(20.43,62.57)
M_B_DQS_DN6: length 78
  TOP w0.089: v1(82.8,59.07) 82.68,59.07 82.58,59.18 82.58,59.47 82.68,59.58 82.99,59.58 83.19,59.78 83.19,61.28 82.93,61.54 U43.BT78
  TOP w0.109: v1(20.43,57.07) 20.17,57.32 20.17,57.68 19.9,57.95 18.28,57.95 17.5,57.18 17.34,57.18 17.24,57.27 16.1,57.27 J8.219
  SIG4 w0.086: v1(20.43,57.07) 20.07,57.07 19.89,57.24 19.89,57.62 20.02,57.75 42.27,57.75 43.91,56.11 45.57,56.11 46.78,57.33 51.45,57.33 52.82,55.96 74.34,55.96 76.17,54.13 77.72,54.13 81.99,58.4 81.99,59.22 82.17,59.39 82.48,59.39 v1(82.8,59.07)
M_B_DQS_DN7: length 82.8
  TOP w0.089: U43.BJ77 86.4,61.95 86.59,61.76 86.59,61.56 86.8,61.35 86.8,59.71 86.53,59.44 v1(86.21,59.44)
  TOP w0.109: v1(20.43,52.07) 20.04,52.07 19.91,51.93 19.91,51.44 20.05,51.3 21.4,51.3 21.96,51.86 23,51.86 23.16,52.03 J8.240
  SIG1 w0.086: v1(86.21,59.44) 85.89,59.76 85.55,59.76 85.39,59.6 85.39,56.08 81.07,51.77 72.46,51.77 71.72,52.5 22.93,52.5 22.73,52.71 22.32,52.71 22.2,52.6 21.79,52.6 21.68,52.71 21.27,52.71 21.15,52.6 20.74,52.6 20.63,52.71 20.11,52.71 19.99,52.58 19.99,52.19 20.11,52.07 v1(20.43,52.07)
M_B_DQS_DN8: length 67.8
  TOP w0.089: U43.CV34 72.68,82.8 72.36,82.8 72.09,82.52 71.02,82.52 70.76,82.78 70.58,82.78 70.33,82.52 69.77,82.52 69.67,82.62 69.67,83.11 69.59,83.2 69.59,83.3 69.69,83.4 70.07,83.4 70.17,83.3 v1(70.17,82.92)
  TOP w0.109: J8.95 17.24,90.28 17.41,90.11 17.89,90.11 18.83,89.17 19.74,89.17 19.98,89.4 19.98,89.9 19.81,90.07 v1(19.43,90.07)
  SIG4 w0.086: v1(70.17,82.92) 69.98,83.12 69.98,83.94 69.71,84.21 67.18,84.21 66.98,84.41 66.98,85.14 66.69,85.43 64.05,85.43 63.43,86.05 63.43,86.83 60.35,89.91 49.76,89.91 48.18,91.49 29.35,91.49 28.59,90.73 27.73,90.73 27.28,91.19 26.38,91.19 26.13,90.93 21,90.93 20.82,91.11 20.16,91.11 19.74,90.68 19.74,90.37 v1(19.43,90.07)
M_B_DQS_DP0: length 74.9
  TOP w0.089: U43.CJ3 76.99,97.52 76.54,97.97 76.54,98.42 75.05,99.91 75.05,100.21 75.25,100.41 v1(75.25,100.74)
  TOP w0.109: J8.13 17.24,110.78 17.41,110.94 17.81,110.94 18.64,111.78 19.81,111.78 19.95,111.64 19.95,111.24 19.79,111.07 v1(19.43,111.07)
  SIG4 w0.086: v1(75.25,100.74) 75.25,100.21 75.15,100.11 74.83,100.11 72.91,102.03 70.91,102.03 63.93,109.02 31.42,109.02 31.29,109.14 31.29,110.21 31.42,110.34 31.88,110.34 32.12,110.58 32.12,111.69 31.88,111.93 20.08,111.93 19.84,111.69 19.84,111.47 v1(19.43,111.07)
M_B_DQS_DP1: length 70.4
  TOP w0.089: U43.CR10 73.85,93.14 73.67,92.95 73.44,92.95 73.03,93.1 71.51,93.1 70.01,94.61 70.01,95.4 69.56,95.86 68.72,96.7 68.72,96.97 68.72,97.16 68.72,97.53 v1(68.72,97.53)
  TOP w0.109: J8.34 23.16,105.53 23,105.69 22.3,105.69 21.39,106.6 21,106.6 20.83,106.78 20.11,106.78 19.91,106.57 19.91,106.23 20.08,106.07 v1(20.43,106.07)
  SIG1 w0.086: v1(68.72,97.53) 68.93,97.32 69.42,97.32 69.56,97.46 69.56,97.74 69.27,98.03 69.11,98.03 68.81,98.33 68.81,98.48 68.52,98.78 68.36,98.78 68.07,99.07 68.07,99.23 67.73,99.57 66.11,99.57 64.18,101.5 53.41,101.5 48.56,106.35 22.14,106.35 21.79,106.71 21.27,106.71 21.15,106.6 20.74,106.6 20.63,106.71 20.19,106.71 19.99,106.51 19.99,106.17 20.09,106.07 v1(20.43,106.07)
M_B_DQS_DP2: length 67.6
  TOP w0.089: U43.CT18 73.79,89.83 73.65,89.69 73.11,89.69 72.95,89.54 72.49,89.54 72.11,89.92 69.08,89.92 67.49,91.51 67.2,91.51 v1(67,91.31)
  TOP w0.109: J8.55 17.24,100.28 17.41,100.44 17.81,100.44 18.64,101.28 19.82,101.28 19.98,101.11 19.98,100.71 19.84,100.57 v1(19.43,100.57)
  SIG4 w0.086: v1(67,91.31) 67,91.44 67.56,92 67.56,92.55 66.82,93.28 65.69,93.28 58.9,100.07 49.63,100.07 48.05,101.65 26.46,101.65 26.15,101.34 23.62,101.34 23.43,101.52 20.08,101.52 19.63,101.07 19.63,100.76 v1(19.43,100.57)
M_B_DQS_DP3: length 66.9
  TOP w0.089: v1(70.13,86.79) 70.43,86.49 70.43,86.29 70.77,85.94 72.22,85.94 72.45,86.17 72.87,86.17 73.15,86.1 73.47,86.02 73.61,86.02 73.73,86.08 73.85,86.2 U43.CR26
  TOP w0.109: J8.76 24.3,95.02 23.16,95.02 23.06,95.12 22.05,95.12 21.5,94.56 19.98,94.56 19.65,94.89 19.65,95.35 v1(19.43,95.57)
  SIG1 w0.086: v1(19.43,95.57) 19.63,95.37 19.63,94.93 20.07,94.49 59.53,94.49 66.31,87.71 70.53,87.71 70.82,87.42 70.82,87.25 70.35,86.79 v1(70.13,86.79)
M_B_DQS_DP4: length 69
  TOP w0.089: U43.CN75 75.45,62.91 75.61,62.75 75.61,62.55 75.97,62.19 75.97,61.71 75.22,60.96 74.6,60.96 74.14,61.42 72.42,61.42 71.97,61.87 69.77,61.87 69.67,61.98 69.67,62.23 69.74,62.3 v1(70.02,62.3)
  TOP w0.109: v1(19.43,67.57) 19.86,67.57 19.99,67.69 19.99,68.06 19.84,68.21 18.61,68.21 17.77,67.37 17.34,67.37 17.24,67.28 J8.179
  SIG4 w0.086: v1(19.43,67.57) 19.71,67.84 19.71,68.22 19.94,68.45 46.08,68.45 50.97,63.55 65.2,63.55 65.55,63.2 69.3,63.2 69.83,62.67 69.83,62.49 v1(70.02,62.3)
M_B_DQS_DP5: length 73.5
  TOP w0.089: v1(79.32,59.8) 79.22,59.91 79.13,60 78.94,60.19 78.94,60.74 79.54,61.35 79.54,61.92 79.81,62.19 79.81,62.75 79.47,63.1 U43.CD75
  TOP w0.109: v1(19.43,62.57) 19.67,62.33 19.67,61.91 20.01,61.56 21.5,61.56 22.05,62.12 23.06,62.12 23.16,62.03 24.3,62.03 J8.200
  SIG1 w0.086: v1(79.32,59.8) 78.97,59.44 78.49,59.44 77.65,58.6 76.34,58.6 75,59.94 65.89,59.94 64.21,61.62 44.68,61.62 42.89,63.41 25.53,63.41 25.24,63.12 21.76,63.12 21.47,63.41 19.89,63.41 19.62,63.14 19.62,62.75 v1(19.43,62.57)
M_B_DQS_DP6: length 78
  TOP w0.089: U43.BT76 82.79,62.96 82.79,62.32 82.63,62.17 82.63,61.57 83,61.2 83,60.16 v1(82.8,59.96)
  TOP w0.109: v1(19.43,57.07) 19.84,57.07 19.94,57.17 19.94,57.58 19.81,57.71 18.37,57.71 17.6,56.94 17.41,56.94 17.24,56.78 J8.221
  SIG4 w0.086: v1(82.8,59.96) 82.43,59.59 82.09,59.59 81.79,59.3 81.79,58.48 77.64,54.33 76.25,54.33 74.43,56.16 52.91,56.16 51.54,57.53 46.7,57.53 45.48,56.31 43.99,56.31 42.35,57.95 19.93,57.95 19.69,57.7 19.69,57.33 v1(19.43,57.07)
M_B_DQS_DP7: length 82.8
  TOP w0.089: U43.BJ75 86.4,63.08 86.06,62.75 86.06,62.47 86.21,62.32 86.21,61.87 86.4,61.68 86.4,61.48 86.61,61.27 86.61,60.73 v1(86.21,60.33)
  TOP w0.109: v1(19.43,52.07) 19.67,51.82 19.67,51.34 19.95,51.06 21.5,51.06 22.05,51.62 23.06,51.62 23.16,51.52 24.3,51.52 J8.242
  SIG1 w0.086: v1(86.21,60.33) 85.84,59.96 85.47,59.96 85.19,59.68 85.19,56.17 80.99,51.97 72.54,51.97 71.8,52.71 23.01,52.71 22.81,52.91 20.03,52.91 19.79,52.67 19.79,52.42 v1(19.43,52.07)
M_B_DQS_DP8: length 67.8
  TOP w0.089: v1(69.28,82.92) 69.48,82.73 69.48,82.55 69.69,82.33 72.17,82.33 72.44,82.61 73.05,82.61 73.35,82.9 U43.CT34
  TOP w0.109: J8.97 17.24,89.78 17.34,89.87 17.79,89.87 18.73,88.93 19.84,88.93 20.21,89.31 20.21,89.85 v1(20.43,90.07)
  SIG4 w0.086: v1(20.43,90.07) 20.07,90.07 19.94,90.2 19.94,90.6 20.25,90.91 20.74,90.91 20.92,90.73 26.21,90.73 26.47,90.99 27.19,90.99 27.65,90.53 28.68,90.53 29.44,91.29 48.1,91.29 49.67,89.71 60.27,89.71 63.23,86.75 63.23,85.96 63.97,85.23 66.61,85.23 66.78,85.06 66.78,84.33 67.1,84.01 69.62,84.01 69.78,83.85 69.78,83.08 69.62,82.92 v1(69.28,82.92)
M_B_ECC0: length 67.7
  TOP w0.089: v1(68.86,84.73) 69.66,83.93 72.75,83.93 U43.CV31
  TOP w0.109: v1(23,91.45) 23.42,91.03 J8.92
  SIG4 w0.086: v1(68.86,84.73) 68.86,85.33 68.27,85.92 64.43,85.92 63.93,86.43 63.93,87.36 60.43,90.86 49.96,90.86 49.83,90.98 49.83,91.36 49.96,91.49 55.29,91.49 55.42,91.62 55.42,92.13 55.29,92.25 26.91,92.25 26.59,91.93 23.48,91.93 v1(23,91.45)
M_B_ECC1: length 67.5
  TOP w0.109: J8.91 17.23,91.28 v1(17.4,91.45) ; v1(71.93,82.92) 72.38,83.37 72.85,83.37 73.37,83.89 U43.CT31
  SIG4 w0.086: v1(71.93,82.92) 72.77,83.77 72.77,87.15 72,87.91 65.25,87.91 59.44,93.72 19.98,93.72 18.92,92.66 18.62,92.66 v1(17.4,91.45)
M_B_ECC2: length 67.4
  TOP w0.089: v1(65.47,82.92) 65.92,82.48 65.99,82.48 66.86,81.61 72.48,81.61 U43.CV36
  TOP w0.109: J8.101 17.89,88.78 18.9,87.76 v1(18.92,87.76)
  SIG4 w0.086: v1(65.47,82.92) 64.5,83.9 63.26,83.9 59.06,88.1 42.34,88.1 40.98,89.46 30.27,89.46 29.53,88.72 23.79,88.72 23.33,89.18 22.49,89.18 22.33,89.03 22.33,88.36 22.2,88.22 21.92,88.22 21.78,88.36 21.78,89.03 21.63,89.18 21.39,89.18 21.24,89.03 21.24,88.36 21.1,88.22 20.82,88.22 20.69,88.36 20.69,89.03 20.54,89.18 20.29,89.18 20.14,89.03 20.14,88.19 20.01,88.06 19.72,88.06 19.59,88.19 19.59,89.03 19.44,89.18 19.08,89.18 18.92,89.03 v1(18.92,87.76)
M_B_ECC3: length 67.6
  TOP w0.089: U43.CT36 73.88,82.05 73.31,82.05 73.15,82.21 72.62,82.21 72.3,81.89 67.27,81.89 v1(66.24,82.92)
  TOP w0.109: J8.105 17.39,87.78 v1(17.4,87.76)
  SIG4 w0.086: v1(17.4,87.76) 17.4,88.83 17.25,88.98 15.54,88.98 15.41,89.11 15.41,89.5 15.54,89.62 24.45,89.62 24.92,89.16 29.21,89.16 30.02,89.97 41.19,89.97 42.62,88.54 59.25,88.54 63.46,84.34 64.74,84.34 66.17,82.92 v1(66.24,82.92)
M_B_ECC4: length 67.5
  TOP w0.089: v1(70.38,84.73) 70.98,84.13 72.32,84.13 72.41,84.23 73.36,84.23 U43.CU30
  TOP w0.109: v1(21.48,91.45) 22.05,92.03 J8.88
  SIG4 w0.086: v1(21.48,91.45) 21.48,91.58 22.26,92.37 26.34,92.37 26.72,92.76 59.1,92.76 59.23,92.63 59.23,92.25 59.1,92.13 56.05,92.13 55.93,92 55.93,91.62 56.05,91.49 60.42,91.49 64.37,87.54 64.37,86.61 64.62,86.36 69.6,86.36 70.38,85.59 v1(70.38,84.73)
M_B_ECC5: length 67.8
  TOP w0.089: U43.CR30 74.01,84.39 73.64,84.77 73.23,84.77 72.96,84.5 72.33,84.5 72.17,84.34 71.54,84.34 v1(71.14,84.73)
  TOP w0.109: J8.87 18.1,92.28 v1(18.92,91.45)
  SIG4 w0.086: v1(71.14,84.73) 71.14,85.12 71.62,85.59 71.93,85.59 72.33,85.99 72.33,86.96 71.82,87.47 65.07,87.47 59.27,93.27 26.54,93.27 26.08,92.81 21.13,92.81 21,92.69 21,92.38 20.87,92.25 20.49,92.25 20.37,92.38 20.37,92.69 20.24,92.81 19.91,92.81 18.92,91.83 v1(18.92,91.45)
M_B_ECC6: length 67.5
  TOP w0.089: U43.CU35 72.52,82.41 72.23,82.11 68.57,82.11 v1(67.76,82.92)
  TOP w0.109: J8.100 23.41,89.03 23,89.43 v1(23,90.07)
  SIG4 w0.086: v1(67.76,82.92) 67.12,83.56 66.15,83.56 64.93,84.79 63.65,84.79 59.45,88.99 42.97,88.99 42.85,89.11 42.85,89.59 42.97,89.71 47.8,89.71 47.93,89.84 47.93,90.35 47.8,90.48 29.76,90.48 28.89,89.6 25.1,89.6 24.63,90.07 v1(23,90.07)
M_B_ECC7: length 67.6
  TOP w0.089: U43.CR35 74.52,81.91 74.15,81.55 73.89,81.55 73.67,81.77 73.38,81.77 73,81.39 65.48,81.39 v1(63.95,82.92)
  TOP w0.109: v1(22.75,87.76) 23.01,88.03 J8.104
  SIG4 w0.086: v1(22.75,87.76) 22.75,88.02 22.97,88.24 29.82,88.24 30.53,88.95 40.81,88.95 40.94,88.82 40.94,88.44 40.81,88.32 36.55,88.32 36.42,88.19 36.42,87.79 36.55,87.66 58.87,87.66 63.61,82.92 v1(63.95,82.92)
M_B_MA0: length 71
  TOP w0.089: U43.CV60 72.79,71.02 72.66,70.9 66.48,70.9 v1(65.9,71.48)
  TOP w0.175: v1(23,77.66) 23.36,78.03 J8.144
  SIG4 w0.137: v1(65.9,71.48) 65.9,71.8 65.74,71.96 64.82,71.96 63.38,73.4 57.11,73.4 56.56,73.95 53.46,73.95 49.63,77.78 35.61,77.78 35.48,77.9 35.48,78.41 35.61,78.54 42.46,78.54 42.59,78.66 42.59,79.17 42.46,79.3 28.12,79.3 25.83,77.01 23.65,77.01 v1(23,77.66)
M_B_MA1: length 66.3
  TOP w0.089: v1(70.58,74.45) 71.61,75.48 U43.CU50
  TOP w0.175: v1(19.95,81.49) 19.24,80.78 J8.133
  SIG4 w0.137: v1(19.95,81.49) 20.43,81.97 49.94,81.97 54.94,76.97 55.12,76.97 55.33,77.17 55.33,77.35 53.95,78.73 53.95,78.95 54.12,79.12 54.34,79.12 57.97,75.48 69.6,75.48 70.58,74.49 v1(70.58,74.45)
M_B_MA2: length 69.2
  TOP w0.089: U43.CR50 74.02,75.48 73.67,75.13 73.11,75.13 72.96,75.28 72.18,75.28 v1(71.35,74.45)
  TOP w0.175: v1(21.48,81.49) 21.94,81.03 J8.132
  SIG4 w0.137: v1(71.35,74.45) 71.35,74.49 70.34,73.49 66.94,73.49 65.99,74.44 57.54,74.44 56.99,74.99 53.89,74.99 49.71,79.17 48.43,79.17 48.31,79.3 48.31,80.44 48.18,80.57 47.67,80.57 47.54,80.44 47.54,79.3 47.42,79.17 46.91,79.17 46.78,79.3 46.78,80.7 46.66,80.82 46.27,80.82 46.15,80.7 46.15,79.3 46.02,79.17 45.51,79.17 45.39,79.3 45.39,80.57 45.26,80.7 44.75,80.7 44.62,80.57 44.62,79.3 44.5,79.17 43.99,79.17 43.86,79.3 43.86,80.32 43.66,80.52 23.23,80.52 22.71,81.04 21.93,81.04 v1(21.48,81.49)
M_B_MA3: length 73.5
  TOP w0.089: U43.CT49 73.79,75.97 73.65,75.83 73.11,75.83 72.95,75.67 70.28,75.67 v1(69.06,74.45)
  TOP w0.175: v1(17.4,81.49) 17.19,81.28 J8.131
  SIG1 w0.137: v1(69.06,74.45) 68.59,74.93 67.41,74.93 67.18,74.69 59.77,74.69 56.4,78.06 46.46,78.06 42.68,81.84 40.43,81.84 40.31,81.71 40.31,81.08 40.18,80.95 39.67,80.95 39.54,81.08 39.54,81.71 39.42,81.84 38.91,81.84 38.78,81.71 38.78,81.07 38.65,80.94 25.97,80.94 25.83,80.8 25.83,80.6 25.72,80.49 25.39,80.49 25.28,80.6 25.28,81.2 25.16,81.33 24.86,81.33 24.73,81.2 24.73,80.6 24.6,80.47 24.32,80.47 24.19,80.6 24.19,81.32 24.06,81.45 23.76,81.45 23.64,81.32 23.64,80.6 23.5,80.47 23.23,80.47 23.09,80.6 23.09,80.8 22.95,80.94 22.68,80.94 22.54,80.8 22.54,80.6 22.43,80.5 22.1,80.5 21.99,80.6 21.99,80.8 21.85,80.94 21.58,80.94 21.44,80.8 21.44,80.6 21.31,80.47 21.03,80.47 20.89,80.6 20.89,80.8 20.76,80.94 20.48,80.94 20.35,80.8 20.35,80.6 20.23,80.49 19.91,80.49 19.8,80.6 19.8,80.8 19.66,80.94 15.79,80.94 15.67,81.07 15.67,81.36 15.79,81.49 v1(17.4,81.49)
M_B_MA4: length 70.8
  TOP w0.089: U43.CV49 72.53,75.97 72.42,75.87 69.72,75.87 v1(68.3,74.45)
  TOP w0.175: v1(23,81.49) 23,81.8 23.23,82.03 J8.128
  SIG4 w0.137: v1(68.3,74.45) 68.3,74.78 68.12,74.96 57.76,74.96 56.97,75.75 55.39,75.75 49.78,81.36 49.6,81.36 49.41,81.16 49.41,80.98 54.49,75.9 54.49,75.68 54.32,75.51 54.1,75.51 48.17,81.45 26.36,81.45 25.95,81.04 23.45,81.04 v1(23,81.49)
M_B_MA5: length 73.1
  TOP w0.089: U43.CR48 74.02,76.47 73.67,76.12 73.11,76.12 72.96,76.27 72.56,76.27 72.35,76.06 68.69,76.06 68.29,76.47 v1(68.29,76.48)
  TOP w0.175: v1(23,82.94) 23.41,82.53 J8.126
  SIG1 w0.137: v1(68.29,76.48) 68.29,76.47 67.48,77.27 59.39,77.27 57.05,79.62 50.21,79.62 47.22,82.61 47.04,82.61 46.83,82.4 46.83,82.22 49.05,80.01 49.05,79.79 48.87,79.62 48.66,79.62 45.37,82.91 45.15,82.91 44.98,82.74 44.98,82.52 47.49,80.01 47.49,79.79 47.32,79.62 47.11,79.62 42.85,83.87 33.7,83.87 33.57,83.74 33.57,83.11 33.32,82.86 27.28,82.86 26.72,83.41 23.13,83.41 23,83.29 v1(23,82.94)
M_B_MA6: length 73.8
  TOP w0.089: v1(71.33,76.48) 71.33,76.47 71.73,76.87 72.36,76.87 72.56,76.67 72.96,76.67 73.11,76.82 73.66,76.82 73.79,76.96 U43.CT47
  TOP w0.175: v1(18.92,81.49) 18.14,82.28 J8.127
  SIG1 w0.137: v1(71.33,76.48) 71.33,76.17 71.18,76.02 69.83,76.02 69.67,75.86 69.67,75.62 69.83,75.47 73.62,75.47 73.77,75.32 73.77,75.07 73.62,74.92 69.33,74.92 68.8,75.45 67.19,75.45 66.96,75.21 59.98,75.21 56.62,78.58 46.67,78.58 42.78,82.47 38.15,82.47 38.02,82.35 38.02,81.71 37.89,81.59 37.38,81.59 37.26,81.71 37.26,82.35 37.13,82.47 36.62,82.47 36.5,82.35 36.5,81.71 36.37,81.59 26.46,81.59 26.08,81.97 19.4,81.97 v1(18.92,81.49)
M_B_MA7: length 74.5
  TOP w0.089: U43.CR46 74.29,77.46 74.15,77.33 73.89,77.33 73.66,77.1 73.12,77.1 72.96,77.26 69.84,77.26 69.05,76.47 v1(69.05,76.48)
  TOP w0.175: v1(21.48,82.94) 21.92,83.38 23.25,83.38 23.39,83.53 J8.122
  SIG1 w0.137: v1(69.05,76.48) 69.05,76.47 67.72,77.79 59.61,77.79 57.26,80.14 53.53,80.14 51.87,81.8 51.65,81.8 51.48,81.63 51.48,81.41 52.37,80.53 52.37,80.31 52.19,80.14 51.98,80.14 48.11,84.01 47.93,84.01 47.73,83.8 47.73,83.62 50.81,80.53 50.81,80.31 50.64,80.14 50.43,80.14 46.06,84.51 33.07,84.51 32.94,84.38 32.94,83.59 32.81,83.46 27.57,83.46 27.1,83.93 22.47,83.93 v1(21.48,82.94)
M_B_MA8: length 69.8
  TOP w0.089: U43.CV47 72.53,76.96 72.44,77.06 71.16,77.06 70.57,76.47 v1(70.57,76.48)
  TOP w0.175: J8.125 17.24,82.78 v1(17.4,82.94)
  SIG4 w0.137: v1(70.57,76.48) 70.57,76.47 70.11,76 66.12,76 65.98,76.14 65.98,76.33 65.84,76.46 65.57,76.46 65.43,76.33 65.43,76.14 65.3,76 65.02,76 64.88,76.14 64.88,76.33 64.75,76.46 64.47,76.46 64.34,76.33 64.34,76.14 64.2,76 63.92,76 63.79,76.14 63.79,76.64 63.63,76.79 63.39,76.79 63.24,76.64 63.24,76.14 63.1,76 62.83,76 62.69,76.14 62.69,76.64 62.54,76.79 62.29,76.79 62.14,76.64 62.14,76.14 62,76 61.73,76 61.59,76.14 61.59,76.64 61.44,76.79 61.2,76.79 61.04,76.64 61.04,76.14 60.91,76 60.63,76 60.5,76.14 60.5,76.64 60.34,76.79 60.1,76.79 59.95,76.64 59.95,76.14 59.81,76 59.54,76 59.4,76.14 59.4,76.64 59.25,76.79 59,76.79 58.85,76.64 58.85,76.14 58.71,76 58.44,76 58.3,76.14 58.3,76.64 58.15,76.79 57.4,76.79 54.55,79.64 53,79.64 50.15,82.49 19.75,82.49 19.39,82.12 16.81,82.12 16.68,82.25 16.68,82.81 16.81,82.94 v1(17.4,82.94)
M_B_MA9: length 71.5
  TOP w0.089: U43.CT44 73.79,77.95 73.65,78.1 73.11,78.1 72.95,78.26 72.57,78.26 72.36,78.05 71.77,78.05 v1(71.37,78.45)
  TOP w0.175: J8.121 18.32,83.78 v1(18.92,84.38)
  SIG4 w0.137: v1(71.37,78.45) 70.43,79.39 61.59,79.39 54.83,86.15 54.65,86.15 54.44,85.94 54.44,85.76 57.3,82.9 57.3,82.69 57.13,82.51 56.91,82.51 53.15,86.28 20.82,86.28 v1(18.92,84.38)
M_B_MA10: length 70.8
  TOP w0.089: v1(68.26,69.54) 68.29,69.54 69.11,70.36 70.09,70.36 70.24,70.52 73.51,70.52 U43.CU61
  TOP w0.175: J8.146 23,75.53 v1(23,75.52)
  SIG4 w0.137: v1(68.26,69.54) 67.84,69.96 65.32,69.96 62.92,72.36 62.71,72.36 62.53,72.19 62.53,71.97 64.49,70.01 64.49,69.83 64.28,69.62 64.11,69.62 61.37,72.36 61.15,72.36 60.98,72.19 60.98,71.97 63.02,69.93 63.02,69.71 62.85,69.54 62.63,69.54 59.82,72.36 59.6,72.36 59.43,72.19 59.43,71.97 59.95,71.45 59.95,71.24 59.78,71.06 59.56,71.06 58.26,72.36 56.68,72.36 56.13,72.91 53.02,72.91 50.52,75.42 26.84,75.42 26.5,75.07 25.08,75.07 24.79,75.36 24.18,75.36 23.9,75.08 23.19,75.08 23,75.27 v1(23,75.52)
M_B_MA11: length 75.1
  TOP w0.089: v1(66.76,76.48) 66.12,77.12 66.12,77.31 66.27,77.46 U43.CU46
  TOP w0.175: J8.120 23.38,84.03 23.3,83.94 21.72,83.94 v1(20.71,82.94)
  SIG1 w0.137: v1(66.76,76.48) 66.76,75.89 66.61,75.73 66.26,75.73 66.11,75.89 66.11,76.6 65.95,76.75 65.71,76.75 65.56,76.6 65.56,75.89 65.41,75.73 65.16,75.73 65.01,75.89 65.01,76.6 64.86,76.75 64.61,76.75 64.46,76.6 64.46,75.89 64.31,75.73 64.06,75.73 63.91,75.89 63.91,76.6 63.76,76.75 63.52,76.75 63.36,76.6 63.36,75.89 63.21,75.73 62.97,75.73 62.81,75.89 62.81,76.6 62.66,76.75 62.42,76.75 62.27,76.6 62.27,75.89 62.11,75.73 61.87,75.73 61.72,75.89 61.72,76.6 61.57,76.75 61.32,76.75 61.17,76.6 61.17,75.89 61.02,75.73 60.77,75.73 60.62,75.89 60.62,76.6 60.47,76.75 60.21,76.75 59.91,76.46 59.48,76.46 56.83,79.1 46.89,79.1 42.88,83.11 35.86,83.11 35.73,82.98 35.73,82.35 35.61,82.22 35.1,82.22 34.97,82.35 34.97,82.98 34.84,83.11 34.34,83.11 34.21,82.98 34.21,82.35 34.08,82.22 26.73,82.22 26.46,82.49 25.36,82.49 25.21,82.64 25.21,82.77 25.08,82.89 24.79,82.89 24.66,82.77 24.66,82.64 24.51,82.49 24.27,82.49 24.11,82.64 24.11,82.77 23.99,82.89 23.69,82.89 23.56,82.77 23.56,82.64 23.41,82.49 20.89,82.49 20.71,82.66 v1(20.71,82.94)
M_B_MA12: length 62.3
  TOP w0.089: U43.CV44 72.43,77.86 71.2,77.86 v1(70.61,78.45)
  TOP w0.175: v1(17.4,84.38) 17.4,84.39 17.29,84.28 J8.119
  SIG4 w0.137: v1(17.4,84.38) 18.37,83.41 49.96,83.41 53.22,80.16 54.77,80.16 57.62,77.31 64.29,77.31 64.62,76.98 70.66,76.98 70.79,77.11 70.79,77.52 70.66,77.65 70.28,77.65 70.15,77.78 70.15,77.99 v1(70.61,78.45)
M_B_MA13: length 75
  TOP w0.089: U43.CT66 73.88,67.91 73.16,67.91 73,67.75 72.63,67.75 72.41,67.98 70.38,67.98 v1(69.96,67.56)
  TOP w0.175: v1(23,72.62) 23.1,72.53 J8.158
  SIG1 w0.137: v1(23,72.62) 23.42,72.2 34.1,72.2 35.99,74.09 39.16,74.09 41.58,71.67 48.58,71.67 51.41,68.84 51.61,68.84 51.8,69.03 51.8,69.23 49.34,71.69 49.34,71.91 49.51,72.08 49.73,72.08 55.19,66.61 55.41,66.61 55.58,66.79 55.58,67 52.52,70.06 52.52,70.28 52.69,70.45 52.91,70.45 56.81,66.55 69.59,66.55 69.96,66.92 v1(69.96,67.56)
M_B_MA14: length 73.3
  TOP w0.089: U43.CV62 72.79,70.03 72.49,70.03 72.39,70.13 71.14,70.13 v1(70.55,69.54)
  TOP w0.175: J8.151 17.2,74.28 v1(17.4,74.07)
  SIG1 w0.137: v1(70.55,69.54) 70.12,69.11 60.3,69.11 54.92,74.49 42.96,74.49 40.81,76.63 34.84,76.63 33.23,75.02 17.13,75.02 16.95,75.19 16.95,76.92 16.82,77.04 13.83,77.04 13.67,76.89 13.67,74.65 13.8,74.53 15.43,74.53 15.61,74.35 15.61,73.97 15.74,73.84 17.17,73.84 v1(17.4,74.07)
M_B_MA15: length 70.8
  TOP w0.089: v1(67.68,67.56) 68.39,68.27 68.8,68.27 69.14,68.61 72.95,68.61 73.24,68.9 73.87,68.9 U43.CT64
  TOP w0.175: J8.156 23.33,73.03 23.05,73.3 22.15,73.3 v1(21.48,72.62)
  SIG4 w0.137: v1(21.48,72.62) 21.98,73.13 41.27,73.13 41.8,72.6 42.34,72.6 42.46,72.73 42.46,73.58 42.59,73.71 43.1,73.71 43.23,73.58 43.23,72.73 43.35,72.6 43.86,72.6 43.99,72.73 43.99,73.59 44.12,73.72 44.62,73.72 44.75,73.59 44.75,72.73 44.88,72.6 45.39,72.6 45.51,72.73 45.51,73.59 45.64,73.72 46.15,73.72 46.27,73.59 46.27,72.73 46.4,72.6 46.91,72.6 47.04,72.73 47.04,73.59 47.16,73.72 47.63,73.72 47.76,73.59 47.76,72.73 47.88,72.6 48.31,72.6 48.43,72.73 48.43,73.58 48.56,73.71 49.07,73.71 49.2,73.58 49.2,72.73 49.32,72.6 49.83,72.6 49.96,72.73 49.96,73.71 50.08,73.84 50.59,73.84 50.72,73.71 50.72,72.73 50.85,72.6 51.86,72.6 52.59,71.87 55.7,71.87 59.07,68.49 66.74,68.49 v1(67.68,67.56)
M_B_MA16: length 72.2
  TOP w0.089: v1(71.31,69.54) 71.71,69.94 72.31,69.94 72.52,69.73 73,69.73 73.17,69.9 73.89,69.9 U43.CT62
  TOP w0.175: v1(23,74.07) 23.05,74.03 J8.152
  SIG1 w0.137: v1(23,74.07) 23,74.31 23.18,74.5 33.73,74.5 35.23,76 40.31,76 42.33,73.97 53.15,73.97 58.95,68.18 59.16,68.18 59.33,68.35 59.33,68.56 54.32,73.58 54.32,73.8 54.49,73.97 54.7,73.97 60.08,68.59 70.36,68.59 v1(71.31,69.54)
M_B_ODT0: length 72.5
  TOP w0.089: v1(66.91,67.56) 68.01,68.65 68.78,68.65 68.93,68.8 72.29,68.8 72.53,69.04 U43.CV64
  TOP w0.175: J8.155 18.13,73.28 v1(18.92,74.07)
  SIG1 w0.137: v1(66.91,67.56) 66.91,67.95 66.79,68.07 63.09,68.07 62.95,67.94 62.95,67.79 62.82,67.65 62.54,67.65 62.4,67.79 62.4,67.94 62.27,68.07 61.99,68.07 61.86,67.94 61.86,67.79 61.72,67.65 61.44,67.65 61.31,67.79 61.31,67.94 61.17,68.07 59.83,68.07 59.42,67.65 58.73,67.65 52.94,73.45 52.72,73.45 52.55,73.27 52.55,73.06 55.48,70.13 55.48,69.91 55.31,69.74 55.09,69.74 51.71,73.12 42.04,73.12 39.8,75.36 35.48,75.36 33.76,73.65 19.35,73.65 v1(18.92,74.07)
M_B_ODT1: length 71
  TOP w0.089: v1(71.49,67.56) 71.49,67.46 72.39,66.55 72.99,66.55 73.33,66.22 73.67,66.22 73.95,66.5 74.45,66.5 U43.CR69
  TOP w0.175: J8.161 18.08,71.78 v1(18.92,72.62)
  SIG1 w0.137: v1(71.49,67.56) 69.96,66.03 55.04,66.03 52.39,68.68 52.19,68.68 52,68.49 52,68.3 54.01,66.28 54.01,66.06 53.84,65.89 53.63,65.89 48.37,71.15 41.21,71.15 38.91,73.46 36.24,73.46 34.46,71.68 19.87,71.68 v1(18.92,72.62)
M_B_PAR: length 72.2
  TOP w0.089: U43.CR59 74.02,71.52 73.67,71.17 73.11,71.17 72.95,71.32 72.63,71.32 72.39,71.09 67.05,71.09 v1(66.66,71.48)
  TOP w0.175: J8.143 17.55,78.28 v1(18.16,77.66)
  SIG4 w0.137: v1(66.66,71.48) 66.66,72.29 66.47,72.48 65.04,72.48 63.59,73.92 57.32,73.92 56.78,74.47 53.67,74.47 49.58,78.56 43.35,78.56 43.23,78.69 43.23,79.81 43.1,79.93 27.1,79.93 25.72,78.56 15.73,78.56 15.45,78.28 15.45,76.56 15.6,76.41 16.91,76.41 v1(18.16,77.66)
M_CPU0_EVENT_N: length 17.8
  TOP w0.109: J8.134 22.59,80.53 v1(22.11,80.04) ; J7.134 12.37,80.53 v1(12.85,80.04)
  SIG4 w0.086: v1(12.85,80.04) 13.31,79.58 21.65,79.58 v1(22.11,80.04)
  BOTTOM w0.109: R137.2 12.62,79.81 v1(12.85,80.04) 13.13,80.32 R138.1
M_RESET: length 73.6
  TOP w0.089: U43.CR43 74.52,77.95 74.16,77.6 73.87,77.6 73.67,77.81 73.11,77.81 72.96,77.66 71.07,77.66 70.72,78 70.09,78
  TOP w0.109: v1(26.58,87.76) 25.84,87.03 J8.108 ; 70.09,78 65.1,78 62.43,80.67 v1(62.43,82.98) ; J7.108 12.11,87.03 v1(12.85,87.76)
  SIG1 w0.086: v1(62.43,82.98) 59.36,82.98 55.09,87.25 27.1,87.25 v1(26.58,87.76) 26.04,87.22 13.39,87.22 v1(12.85,87.76)
MAC1MDC: length 8.3
  TOP w0.109: v2(149.89,113.03) U20.D8
  BOTTOM w0.109: R525.1 148,109.78 148.38,110.16 148.38,111.89 149.53,113.03 v2(149.89,113.03)
MAC1MDIO: length 10.2
  TOP w0.109: U20.E10 v2(149.09,113.83)
  BOTTOM w0.109: R524.1 143.94,106.6 146.86,109.53 146.86,111.05 147.11,111.3 147.11,111.85 v2(149.09,113.83)
MEMA_0: length 42.4
  TOP w0.109: U21.P3 v2(149.43,142.64) ; U20.V13 v2(145.89,125.03)
  SIG1 w0.086: v2(145.89,125.03) 145.47,125.45 143.25,125.45 143.1,125.6 143.1,130.97 143.21,131.07 143.39,131.07 143.5,131.18 143.5,131.39 143.39,131.5 143.21,131.5 143.1,131.61 143.1,131.82 143.21,131.93 143.39,131.93 143.5,132.03 143.5,132.25 143.39,132.35 143.21,132.35 143.1,132.46 143.1,132.96 143.23,133.09 144.09,133.09 144.19,133.2 144.19,133.41 144.09,133.52 143.21,133.52 143.1,133.63 143.1,133.93 143.21,134.04 143.45,134.04 143.56,134.14 143.56,139.62 146.99,143.05 149.32,143.05 149.43,142.95 v2(149.43,142.64)
  BOTTOM w0.109: R398.1 143.53,149.56 143.68,149.4 143.68,147.37 143.58,147.27 R397.2 143.18,146.48 143.56,146.1 145.21,146.1 146.04,145.27 146.04,143.43 147.3,142.16 148.95,142.16 v2(149.43,142.64)
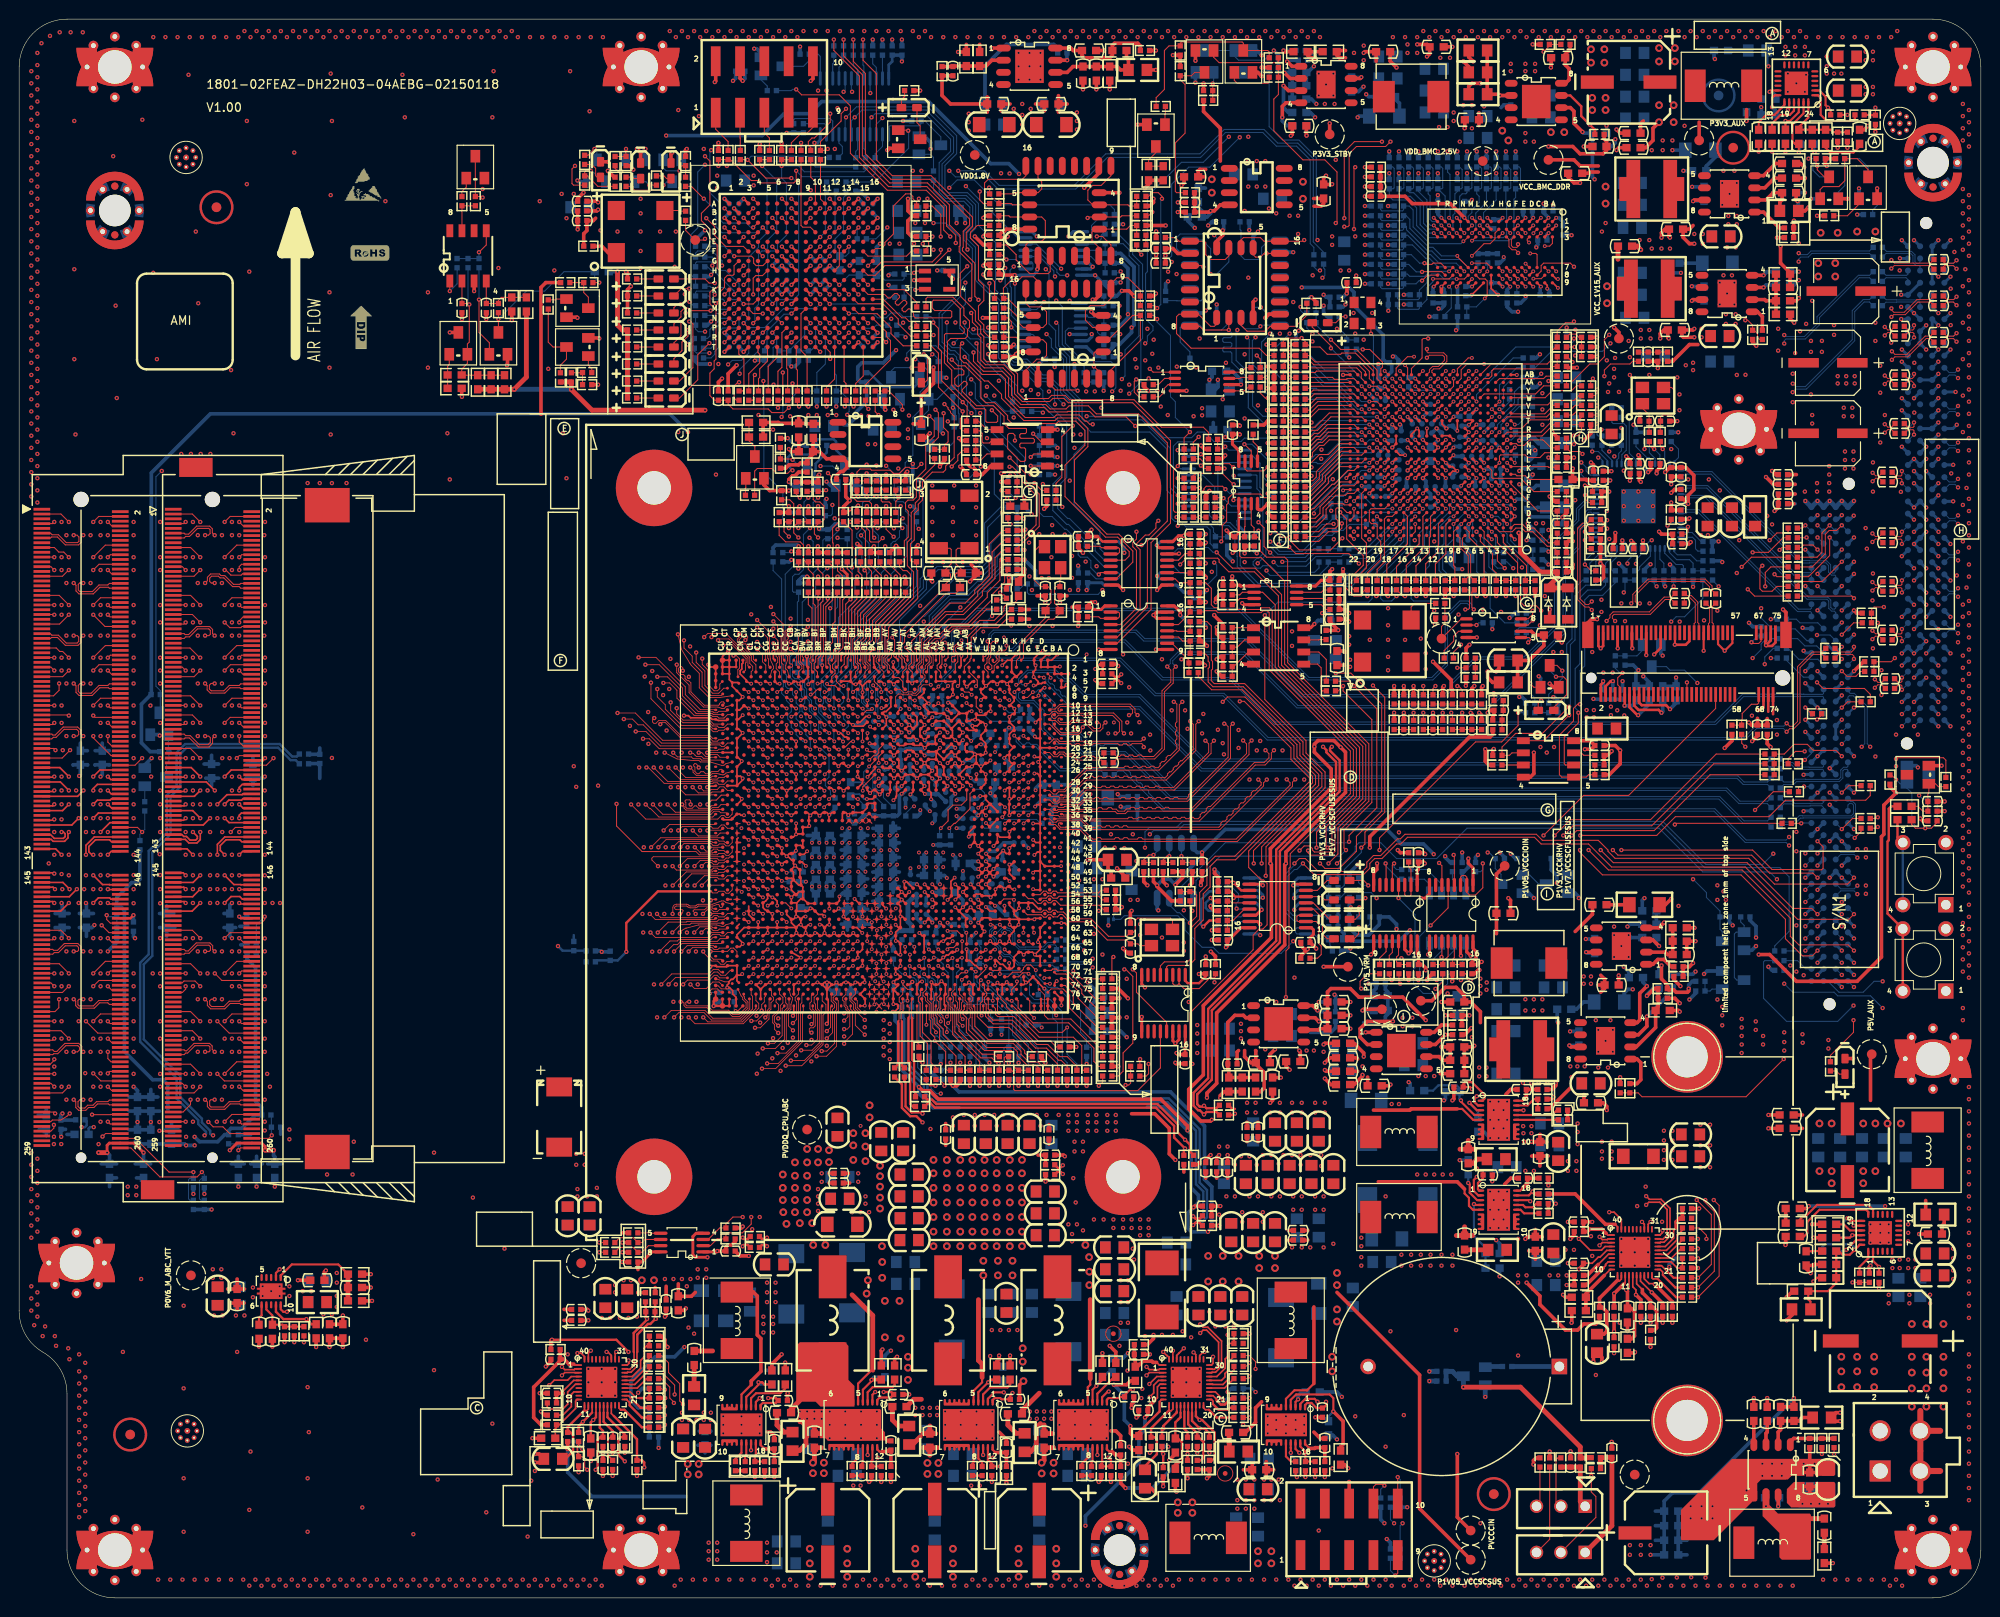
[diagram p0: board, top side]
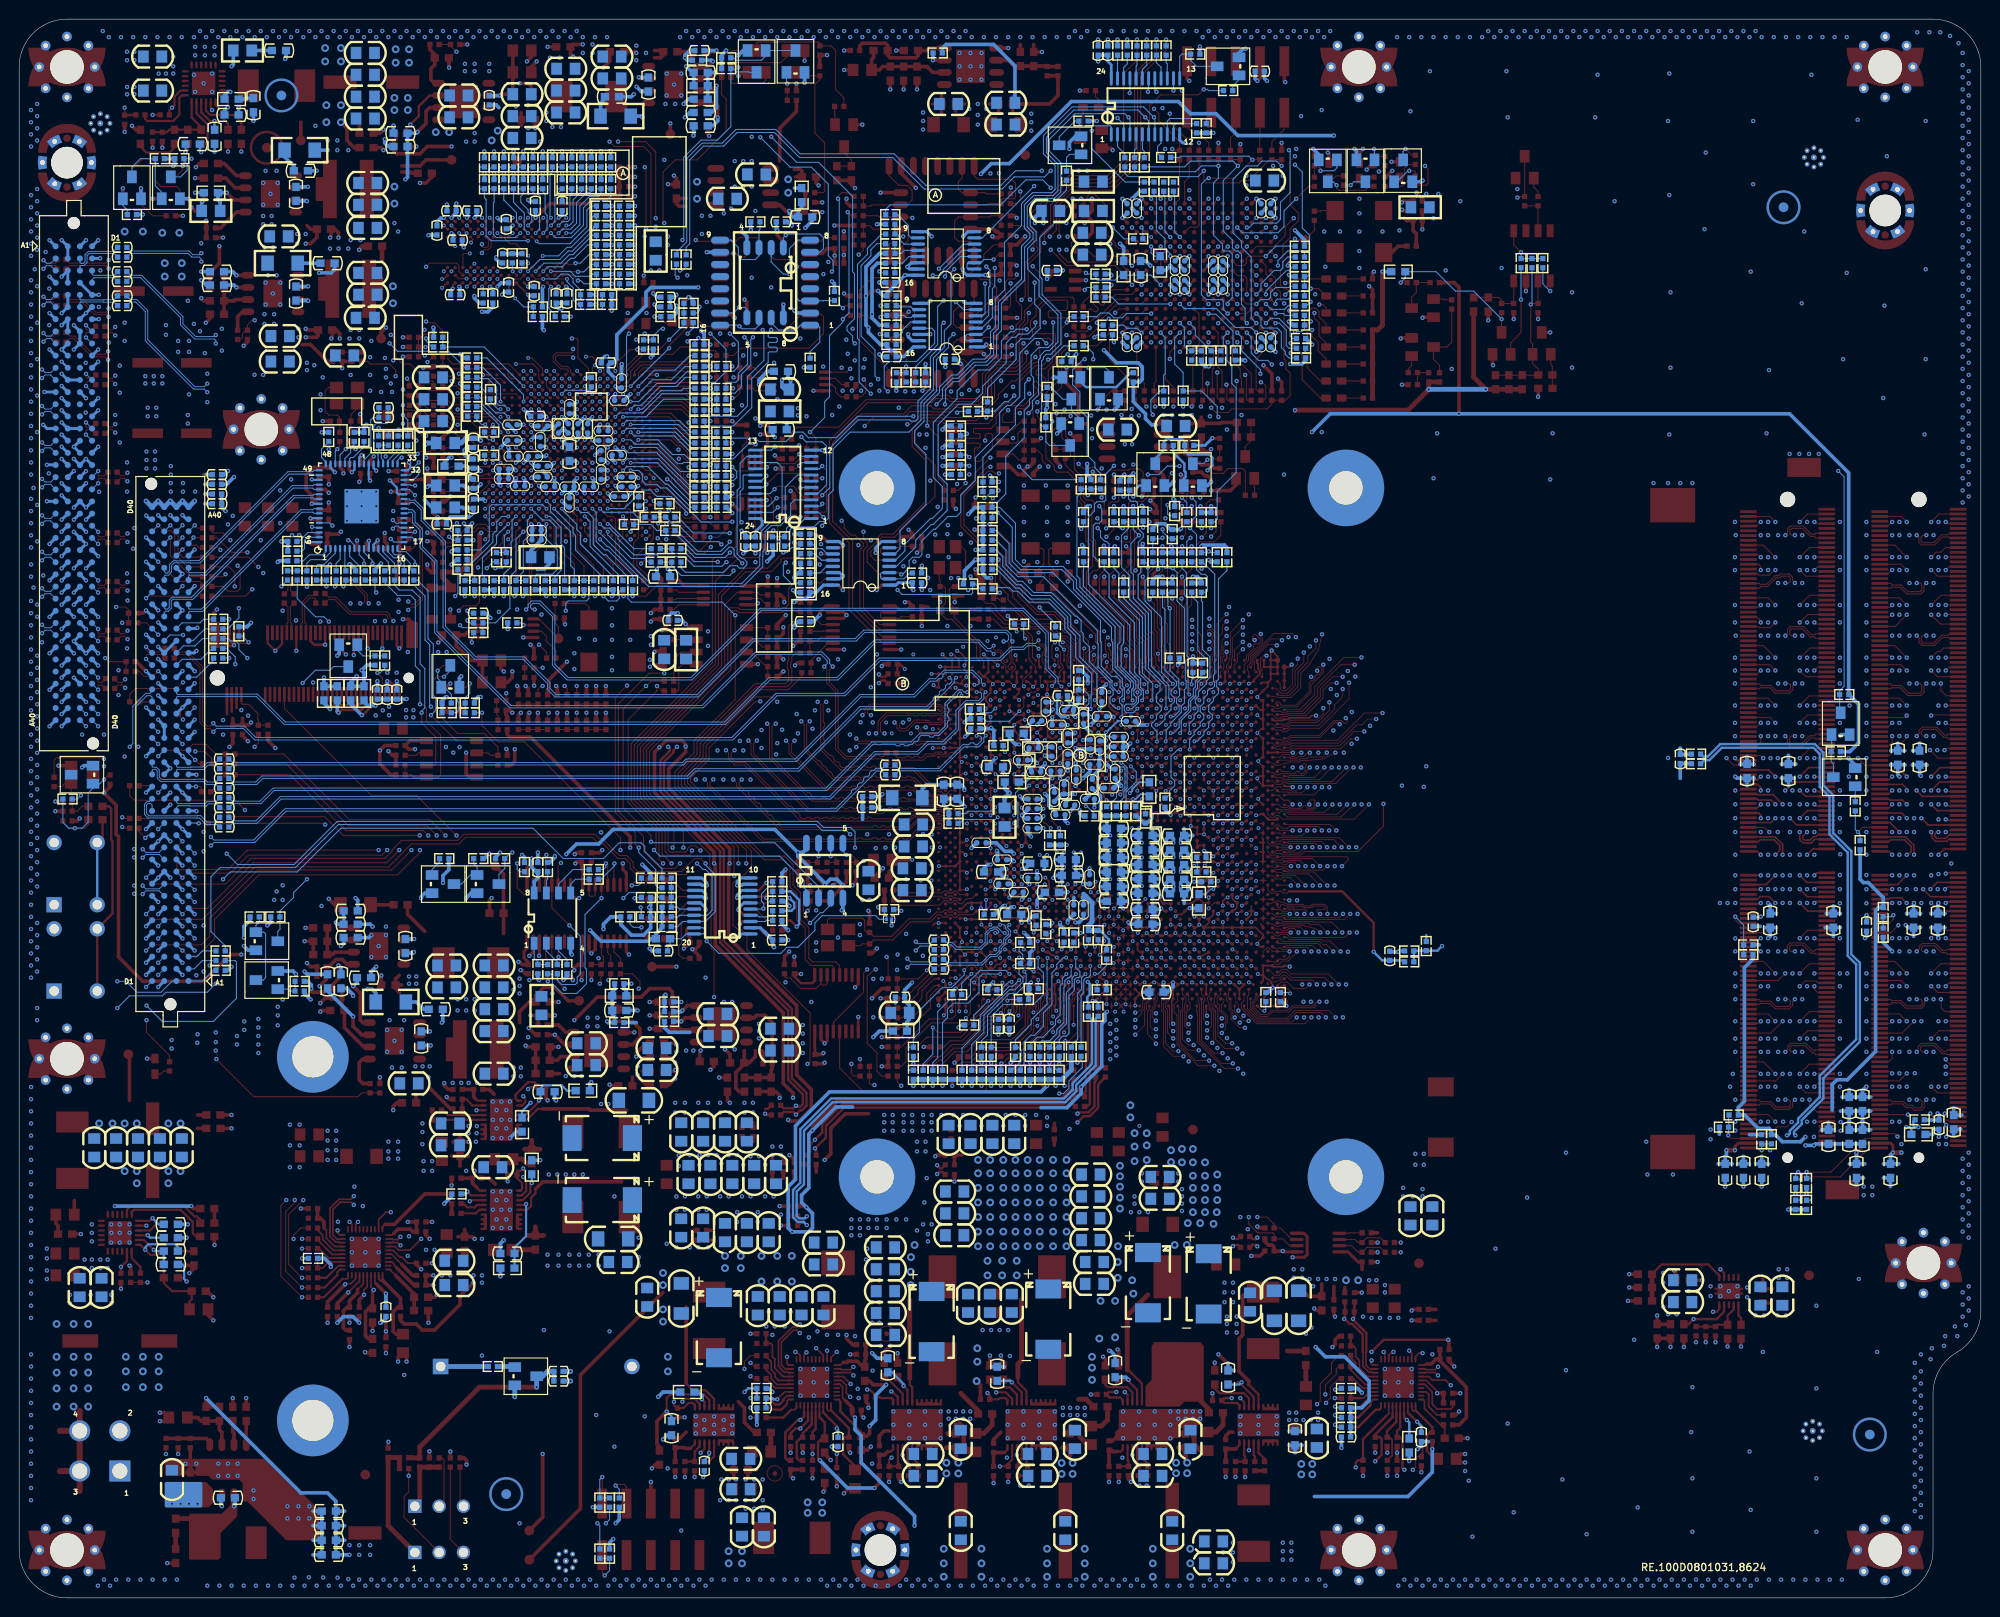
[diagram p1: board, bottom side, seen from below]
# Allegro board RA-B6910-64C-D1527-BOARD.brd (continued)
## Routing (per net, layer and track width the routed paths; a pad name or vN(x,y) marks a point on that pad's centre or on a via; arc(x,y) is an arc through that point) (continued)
MEMA_1: length 33.4
  TOP w0.109: U20.AB14 145.49,128.48 146.6,129.59 146.6,131.5 146.73,131.62 v1(147.24,131.62) ; U21.P7 v2(149.43,138.64)
  SIG3 w0.107: v1(147.24,131.62) 147.34,131.52 147.34,131.06 147.27,130.99 146.74,130.99 146.6,131.12 146.6,132.01 146.73,132.14 149.56,132.14 149.68,132.26 149.68,132.42 149.59,132.51 146.7,132.51 146.6,132.61 146.6,132.79 146.73,132.92 150.52,132.92 150.64,133.05 150.64,133.17 150.54,133.27 149.96,133.27 149.83,133.4 149.83,137.38 149.7,137.51 149.49,137.51 149.43,137.58 v2(149.43,138.64)
  BOTTOM w0.109: v2(149.43,138.64) 147.4,138.64 146.88,138.13 145.31,138.13 145.08,138.35 R399.2 144.67,137.97 144.55,137.85 142.41,137.85 142.26,138 R400.1
MEMA_2: length 36.5
  TOP w0.109: U21.R3 v2(148.63,142.64) ; U20.W14 v2(145.09,125.83)
  SIG3 w0.107: v2(148.63,142.64) 148.34,142.64 148.24,142.54 148.24,142.29 148.35,142.18 149.18,142.18 149.27,142.09 149.27,141.9 149.18,141.81 147.71,141.81 147.62,141.71 147.62,141.52 147.71,141.43 149.31,141.43 149.4,141.34 149.4,141.15 149.31,141.05 147.75,141.05 147.62,140.93 147.62,140.6 147.7,140.51 148.51,140.51 148.63,140.4 148.63,137.58 148.21,137.16 148.21,136.09 145.33,133.22 145.33,129.54 145.61,129.26 145.61,128.19 145.09,127.67 v2(145.09,125.83)
  BOTTOM w0.109: R402.1 145.56,149.56 145.72,149.4 145.72,147.37 145.61,147.27 R401.2 145.21,146.99 145.33,146.86 145.72,146.86 146.76,145.82 146.76,143.66 147.37,143.05 148.21,143.05 v2(148.63,142.64)
MEMA_3: length 37.2
  TOP w0.109: U20.U14 v2(145.09,124.23) ; v2(151.03,138.64) 151.02,138.64 U21.N7
  SIG3 w0.107: v2(145.09,124.23) 145.31,124.23 145.72,124.64 146.1,124.64 146.29,124.83 146.29,126.79 147.57,128.07 147.87,128.07 148.89,129.08 150.16,129.08 151.58,130.51 152.47,130.51 152.72,130.75 152.72,133.82 152.6,133.93 151.91,133.93 151.81,134.04 151.81,134.42 151.94,134.54 152.22,134.54 152.32,134.64 152.32,134.93 152.19,135.05 151.42,135.05 151.33,135.15 151.33,138.25 151.41,138.34 151.41,140.05 151.33,140.13 150.99,140.13 150.9,140.05 150.9,138.76 v2(151.03,138.64)
  BOTTOM w0.109: v2(151.03,138.64) 150.17,139.5 148.38,139.5 147.49,140.39 147.12,140.39 145.09,142.42 R404.2 144.67,142.03 144.55,141.91 142.41,141.91 142.26,142.06 R405.1
MEMA_4: length 36.2
  TOP w0.109: U20.W15 v2(144.29,125.83) ; U21.N3 v2(150.23,142.64)
  SIG1 w0.086: v2(150.23,142.64) 149.75,142.16 147.6,142.16 145.06,139.62 144.22,139.62 144.12,139.52 144.12,139.22 144.22,139.12 145.03,139.12 145.13,139.01 145.13,138.79 145.03,138.68 144.12,138.68 144.01,138.58 144.01,138.33 144.12,138.22 144.66,138.22 144.77,138.12 144.77,137.9 144.66,137.8 144.12,137.8 144.01,137.69 144.01,137.3 144.12,137.19 144.66,137.19 144.77,137.09 144.77,136.87 144.66,136.77 144.17,136.77 144.06,136.66 144.06,134.4 144.17,134.29 144.59,134.29 144.7,134.18 144.7,132.77 144.57,132.64 144.1,132.64 143.94,132.48 143.94,130.1 144.06,129.97 144.06,129.59 143.91,129.44 143.91,125.96 144.04,125.83 v2(144.29,125.83)
  BOTTOM w0.109: R408.1 150.52,149.56 150.8,149.28 150.8,147.37 150.69,147.27 R407.2 150.29,146.99 150.03,146.74 150.03,144.7 149.83,144.5 149.83,143.03 v2(150.23,142.64)
MEMA_5: length 33.1
  TOP w0.109: U20.V15 v2(144.29,125.03) ; v2(147.75,137.85) 149.43,137.85 U21.P8
  SIG3 w0.107: v2(147.75,137.85) 147.87,137.97 147.87,138.32 147.78,138.42 147.46,138.42 147.37,138.51 147.37,138.7 147.46,138.79 147.74,138.79 147.84,138.89 147.84,139.12 147.96,139.24 148.13,139.24 148.26,139.12 148.26,137.59 148.13,137.47 147.46,137.47 147.37,137.37 147.37,136.67 147.46,136.58 147.73,136.58 147.82,136.48 147.82,136.29 147.73,136.2 147.52,136.2 147.33,136.01 147.33,135.77 147.17,135.61 147.06,135.61 146.92,135.75 146.77,135.75 146.66,135.64 146.66,135.48 146.77,135.37 146.77,135.21 146.66,135.1 146.51,135.1 146.4,135.21 146.25,135.21 146.14,135.1 146.14,134.94 146.24,134.84 146.24,134.68 146.13,134.57 145.97,134.57 145.86,134.68 145.73,134.68 145.6,134.55 145.6,134.42 145.71,134.31 145.71,134.16 145.54,133.99 145.06,133.99 144.93,133.86 144.93,129.36 145.21,129.08 145.21,128.32 144.7,127.81 143.98,127.81 143.89,127.72 143.89,127.15 143.98,127.05 144.64,127.05 144.73,126.96 144.73,126.33 144.64,126.24 144.01,126.24 143.89,126.11 143.89,125.2 144.05,125.03 v2(144.29,125.03)
  BOTTOM w0.109: v2(147.75,137.85) 147.75,137.57 147.11,136.93 147.11,135.69 146.6,135.18 R409.2 146.33,134.77 146.22,134.67 144.16,134.67 144.04,134.8 R410.1
MEMA_6: length 31.9
  TOP w0.109: U21.P2 v2(149.43,143.44) ; v2(145.77,129.72) 145.08,129.72 143.89,128.53 U20.AB16
  SIG3 w0.107: v2(145.77,129.72) 145.77,133.1 147.09,134.42 147.75,134.42 147.87,134.54 147.87,135.05 148,135.18 148.26,135.18 148.33,135.26 148.33,135.61 148.61,135.89 148.61,136.46 148.73,136.58 148.92,136.58 149.02,136.67 149.02,140.55 149.11,140.64 150.32,140.64 150.41,140.73 150.41,142.08 150.64,142.31 150.64,142.82 150.38,143.09 150.38,143.34 150.47,143.43 151.34,143.43 151.43,143.53 151.43,143.72 151.34,143.82 149.52,143.82 149.43,143.72 v2(149.43,143.44)
  BOTTOM w0.109: v2(149.43,143.44) 149.02,143.85 149.02,146.51 R411.2 148.66,147.27 148.76,147.37 148.76,149.4 148.61,149.56 R412.1
MEMA_7: length 30.3
  TOP w0.109: v1(146.6,138.58) 146.73,138.58 146.76,138.61 148.66,138.61 U21.R8 ; U20.AA16 v2(143.49,127.43)
  SIG3 w0.107: v1(146.6,138.58) 146.6,138.86 146.38,139.09 144.51,139.09 144.45,139.02 144.45,138.7 144.54,138.61 145.5,138.61 145.59,138.51 145.59,138.27 145.5,138.18 144.41,138.18 144.32,138.08 144.32,137.82 144.41,137.72 145.62,137.72 145.72,137.63 145.72,137.38 145.62,137.29 143.76,137.29 143.33,136.86 143.33,135.03 143.56,134.8 143.56,134.34 142.79,133.57 142.79,130.1 142.9,129.99 142.9,128.66 143.21,128.35 143.59,128.35 143.68,128.26 143.68,128.07 143.56,127.94 143.15,127.94 143.05,127.85 143.05,127.56 143.18,127.43 v2(143.49,127.43)
  BOTTOM w0.109: v1(146.6,138.58) 146,138.58 145.21,139.37 R413.2 144.67,138.99 144.55,138.86 142.41,138.86 142.26,139.01 R414.1
MEMA_8: length 33.7
  TOP w0.109: U20.W16 v2(143.49,125.83) ; U21.R2 v2(148.63,143.44)
  SIG3 w0.107: v2(143.49,125.83) 143.49,126.12 143.4,126.21 142.49,126.21 141.52,127.18 141.52,129.34 141.98,129.79 141.98,138.94 142.92,139.88 143.18,139.88 144.65,141.35 144.78,141.35 145.15,140.97 145.29,140.97 145.42,141.11 145.42,141.24 145.05,141.61 145.05,141.75 147.11,143.82 148.26,143.82 148.63,143.45 v2(148.63,143.44)
  BOTTOM w0.109: R416.1 147.6,149.56 147.75,149.4 147.75,147.37 147.65,147.27 R415.2 147.24,146.74 147.44,146.53 147.44,144.07 147.67,143.84 148.22,143.84 v2(148.63,143.44)
MEMA_9: length 31.4
  TOP w0.109: U21.R7 148.57,139.5 147.75,139.5 147.62,139.37 147.11,139.37 146.99,139.5 v1(146.86,139.5) ; U20.Y16 v2(143.49,126.63)
  SIG3 w0.107: v2(143.49,126.63) 143.49,126.73 143.18,127.05 142.29,127.05 142.03,127.31 142.03,128.19 142.49,128.65 142.49,129.26 142.39,129.36 142.39,135.41 142.51,135.53 142.83,135.53 142.92,135.62 142.92,135.81 142.83,135.9 142.51,135.9 142.41,136 142.41,136.18 142.51,136.28 142.83,136.28 142.92,136.37 142.92,136.56 142.83,136.65 142.51,136.65 142.41,136.75 142.41,137.72 142.61,137.92 143.79,137.92 143.91,138.05 143.91,139.1 143.68,139.33 143.68,139.73 144.34,140.39 144.95,140.39 145.11,140.23 145.11,140.03 144.98,139.9 144.67,139.9 144.57,139.81 144.57,139.62 144.7,139.5 v1(146.86,139.5)
  BOTTOM w0.109: R418.1 142.26,140.03 142.41,139.88 144.55,139.88 144.67,140 R417.2 145.46,140.39 146.35,139.5 v1(146.86,139.5)
MEMA_10: length 40.8
  TOP w0.109: v2(150.92,141.78) 150.97,141.78 U21.M3 ; U20.U13 v2(145.89,124.23)
  SIG1 w0.086: v2(145.89,124.23) 146.15,124.23 146.3,124.38 146.3,127.61 146.2,127.71 146.2,134.01 148.23,136.04 148.23,138.48 148.54,138.8 148.54,139.08 148.38,139.24 147.62,139.24 147.49,139.37 147.49,139.62 147.62,139.75 150.8,139.75 151.05,140.01 151.05,140.69 150.94,140.8 148.9,140.8 148.76,140.94 148.76,141.17 148.87,141.28 150.8,141.28 150.92,141.4 v2(150.92,141.78)
  BOTTOM w0.109: v2(150.92,141.78) 150.67,141.53 147.43,141.53 145.67,143.29 145.67,145.06 145.26,145.47 R419.2 144.67,145.08 144.55,144.96 142.41,144.96 142.26,145.11 R420.1
MEMA_11: length 32.5
  TOP w0.109: v2(144.83,128.83) 145.09,128.56 145.09,127.43 U20.AA14 ; U21.T2 v2(147.83,143.44)
  SIG3 w0.107: v2(144.83,128.83) 144.52,129.13 144.52,134.21 147.07,136.76 147.07,138.94 147.37,139.24 147.37,140.12 147.27,140.21 146.32,140.21 146.22,140.31 146.22,140.5 146.32,140.59 147.15,140.59 147.24,140.68 147.24,140.91 147.15,141 146.32,141 146.22,141.1 146.22,141.25 146.32,141.34 147.15,141.34 147.24,141.44 147.24,141.62 147.15,141.72 146.32,141.72 146.22,141.81 146.22,142 146.32,142.09 147.27,142.09 147.37,142.19 147.37,143.31 147.5,143.44 v2(147.83,143.44)
  BOTTOM w0.109: v2(147.83,143.44) 147.49,143.44 147.11,143.81 147.11,146.1 146.22,146.99 R421.2 146.63,147.27 146.73,147.37 146.73,149.4 146.58,149.56 R422.1
MEMA_12: length 39.5
  TOP w0.109: v2(150.29,140.26) 150.29,140.18 U21.M7 ; U20.Y14 v2(145.89,125.83)
  SIG1 w0.086: v2(150.29,140.26) 146.97,140.26 146.4,139.7 146.4,139.15 146.51,139.04 147.11,139.04 147.21,138.93 147.21,138.35 146.99,138.13 146.08,138.13 145.97,138.02 145.97,137.32 146.08,137.21 147.27,137.21 147.39,137.08 147.39,136.68 147.29,136.58 145.82,136.58 145.72,136.47 145.72,136.17 145.82,136.07 147.13,136.07 147.24,135.96 147.24,135.69 147.11,135.56 145.84,135.56 145.72,135.43 145.72,135.18 145.97,134.92 145.97,134.58 145.72,134.32 145.72,130.28 145.21,129.77 145.21,129.34 145.49,129.06 145.49,126.24 v2(145.89,125.83)
  BOTTOM w0.109: R424.1 142.26,144.09 142.41,143.94 144.55,143.94 144.67,144.07 R423.2 144.95,144.45 145.33,144.07 145.33,143.14 147.32,141.15 147.75,141.15 148.64,140.26 v2(150.29,140.26)
MEMA_13: length 28.9
  TOP w0.109: U20.AB15 v2(144.29,128.23) ; v1(146.6,137.67) 147.18,138.24 U21.T8
  SIG3 w0.107: v2(144.29,128.23) 144.29,128.64 144.2,128.73 143.4,128.73 143.3,128.83 143.3,129.01 143.4,129.11 143.99,129.11 144.12,129.23 144.12,130.19 143.99,130.32 143.39,130.32 143.3,130.41 143.3,130.6 143.39,130.69 144.01,130.69 144.12,130.8 144.12,130.96 144.01,131.07 143.27,131.07 143.18,131.16 143.18,131.35 143.27,131.45 144.01,131.45 144.12,131.56 144.12,131.71 144.01,131.82 143.27,131.82 143.18,131.92 143.18,132.1 143.27,132.2 144.01,132.2 144.12,132.31 144.12,132.46 144.01,132.57 143.27,132.57 143.18,132.67 143.18,132.86 143.27,132.95 144,132.95 144.12,133.07 144.12,133.23 144,133.35 143.52,133.35 143.43,133.44 143.43,133.64 143.52,133.73 143.97,133.73 144.06,133.83 144.06,135.56 144.19,135.69 144.96,135.69 145.08,135.81 145.08,135.97 145.2,136.09 145.62,136.09 145.72,136.19 145.72,136.38 145.62,136.47 145.56,136.47 145.46,136.56 145.46,136.79 145.56,136.88 146.64,136.88 146.73,136.97 146.73,137.54 v1(146.6,137.67)
  BOTTOM w0.109: v1(146.6,137.67) 146.3,137.67 145.97,137.34 R425.2 144.67,136.95 144.55,136.83 142.41,136.83 142.26,136.98 R426.1
MEMACT_N: length 40.2
  TOP w0.109: U20.Y15 v2(144.29,126.63) ; U21.L3 v2(151.82,141.84)
  SIG1 w0.086: v2(151.82,141.84) 151.82,142.06 151.72,142.16 150.42,142.16 150.29,142.04 150.29,141.78 150.17,141.67 148.36,141.67 148.26,141.56 148.26,140.83 148.15,140.73 146.79,140.73 145.58,139.51 145.58,138.47 145.21,138.1 145.21,132.29 145.1,132.19 144.55,132.19 144.45,132.08 144.45,131.87 144.55,131.76 145.1,131.76 145.21,131.65 145.21,131.44 145.1,131.33 144.55,131.33 144.45,131.23 144.45,131.01 144.55,130.9 145.1,130.9 145.21,130.8 145.21,130.61 145.08,130.48 144.7,130.48 144.57,130.35 144.57,129.34 144.45,129.21 144.45,128.65 144.7,128.4 145,128.4 145.11,128.29 145.11,127.81 144.95,127.66 144.95,127.2 145.11,127.05 145.11,126.44 144.83,126.16 144.53,126.16 144.29,126.4 v2(144.29,126.63)
  BOTTOM w0.109: R428.1 156.74,149.56 156.89,149.4 156.89,147.37 156.79,147.27 R427.2 156.38,146.36 156.21,146.18 156.21,142.37 155.68,141.84 v2(151.82,141.84)
MEMALERT_N: length 29.5
  TOP w0.109: U21.P9 v2(149.43,137.04) ; v2(144.29,124.23) U20.U16
  SIG3 w0.107: v2(144.29,124.23) 144.29,124.14 143.98,123.83 142.34,123.83 142.16,124 142.16,124.41 142.39,124.64 145.33,124.64 145.49,124.79 145.49,127.56 146.35,128.42 146.35,130.14 146.17,130.33 146.17,132.94 146.54,133.31 149.3,133.31 149.43,133.43 149.43,133.6 149.33,133.69 148.48,133.69 148.38,133.79 148.38,133.98 148.48,134.07 149.33,134.07 149.43,134.16 149.43,134.35 149.33,134.45 148.86,134.45 148.79,134.51 148.79,134.75 148.86,134.82 149.33,134.82 149.43,134.92 v2(149.43,137.04)
  BOTTOM w0.109: R378.1 148.99,134.14 149.65,134.8 149.65,136.81 v2(149.43,137.04)
MEMBA_0: length 37.1
  TOP w0.109: U20.U12 v2(146.69,124.23) ; U21.N2 v2(151.03,142.64)
  SIG1 w0.086: v2(151.03,142.64) 151.45,143.06 152.06,143.06 152.22,142.9 152.22,141.43 152.07,141.28 151.54,141.28 151.43,141.17 151.43,139.24 151.3,139.12 149.94,139.12 149.83,139.01 149.83,138.33 149.94,138.23 151.3,138.23 151.43,138.1 151.43,137.59 151.3,137.47 149.14,137.47 149.02,137.34 149.02,136.2 146.66,133.83 146.66,129.03 147.11,128.58 147.11,124.38 146.96,124.23 v2(146.69,124.23)
  BOTTOM w0.109: v2(151.03,142.64) 150.62,143.05 150.62,144.5 150.54,144.58 150.54,146.48 150.81,146.75 151.18,146.75 151.3,146.87 R391.2 151.71,147.27 151.81,147.37 151.81,149.43 151.69,149.56 R392.1
MEMBA_1: length 35.6
  TOP w0.109: U20.Y13 v2(145.89,126.63) ; v2(150.23,138.64) U21.N8
  SIG3 w0.107: v2(150.23,138.64) 150.06,138.81 150.06,139.01 150.16,139.12 150.52,139.12 150.62,139.02 150.62,138.51 150.92,138.2 150.92,134.93 151.41,134.44 151.41,133.71 151.58,133.54 152.23,133.54 152.32,133.44 152.32,133.25 152.23,133.16 151.52,133.16 151.43,133.07 151.43,132.88 151.52,132.78 152.23,132.78 152.32,132.69 152.32,132.5 152.23,132.41 151.52,132.41 151.43,132.31 151.43,131.97 151.52,131.88 152.19,131.88 152.32,131.75 152.32,131.49 152.19,131.36 150.15,131.36 150.03,131.24 150.03,131.05 150.12,130.95 151.08,130.95 151.18,130.86 151.18,130.67 151.08,130.58 150.12,130.58 150.03,130.48 150.03,129.84 149.78,129.59 148.3,129.59 148.21,129.5 148.21,129.16 145.89,126.85 v2(145.89,126.63)
  BOTTOM w0.109: R394.1 142.26,141.05 142.41,140.89 144.55,140.89 144.67,141.02 R393.2 145.59,141.4 146.99,140.01 147.37,140.01 148.26,139.12 149.75,139.12 v2(150.23,138.64)
MEMBG_0: length 34.2
  TOP w0.109: v2(151.83,143.44) 151.82,143.44 U21.M2 ; v2(146.69,125.83) U20.W13
  SIG3 w0.107: v2(146.69,125.83) 146.69,125.83 147.1,126.24 147.7,126.24 147.87,126.42 147.87,126.8 148.13,127.05 148.51,127.05 148.71,127.25 148.71,127.64 148.89,127.81 150.54,127.81 151.43,128.7 152.19,128.7 152.52,129.03 152.52,129.16 152.27,129.41 152.27,129.54 152.4,129.68 152.54,129.68 152.88,129.34 153.08,129.34 153.51,129.77 153.51,135.13 153.34,135.31 153.08,135.31 152.7,135.69 152.7,138.1 153.03,138.43 153.03,141.05 153.13,141.15 153.37,141.15 153.46,141.24 153.46,141.66 153.34,141.78 152.95,141.78 152.22,142.52 152.22,143.05 v2(151.83,143.44)
  BOTTOM w0.109: R396.1 152.68,149.56 152.83,149.4 152.83,147.37 152.73,147.27 R395.2 152.32,146.74 152.57,146.48 152.57,145.85 151.81,145.09 151.81,144.78 151.43,144.4 151.43,143.83 v2(151.83,143.44)
MEMCASN: length 33.3
  TOP w0.109: v2(146.69,128.23) U20.AB13 ; v2(150.22,137.84) 151.03,137.84 U21.M8
  SIG3 w0.107: v2(146.69,128.23) 146.86,128.4 146.86,128.99 146.95,129.08 147.49,129.08 147.75,129.34 147.75,129.89 147.84,129.98 149.43,129.98 149.53,130.08 149.53,130.34 149.43,130.43 147.71,130.43 147.62,130.52 147.62,130.77 147.71,130.86 149.5,130.86 149.63,130.99 149.63,131.17 149.5,131.29 147.84,131.29 147.75,131.39 147.75,131.66 147.84,131.75 150.8,131.75 151.04,132 151.04,133.55 150.92,133.68 150.36,133.68 150.24,133.81 150.24,134 150.36,134.12 150.67,134.12 150.8,134.25 150.8,134.44 150.69,134.55 150.36,134.55 150.24,134.68 150.24,136.45 150.36,136.58 150.54,136.58 150.67,136.7 150.67,137.72 150.55,137.84 v2(150.22,137.84)
  BOTTOM w0.109: v2(150.22,137.84) 150.22,137.85 148.89,137.85 148.38,138.35 147.62,138.35 147.11,137.85 147.11,137.47 146.33,136.68 R383.2 146.33,135.81 146.2,135.69 144.19,135.69 144.04,135.84 R384.1
MEMCK: length 28.5
  TOP w0.099: v1(147.11,130.53) 147.11,130.25 147.23,130.13 148.86,130.13 149.19,129.8 149.19,129.23 148.42,128.45 147.82,128.45 147.63,128.26 147.63,128.1 U20.AB11 ; U21.K7 v2(152.63,138.64)
  SIG1 w0.094: v1(147.11,130.53) 147.29,130.35 147.64,130.35 147.87,130.59 147.87,130.97 148.44,131.53 148.44,131.82 147.43,132.84 147.43,133.21 147.74,133.52 148.11,133.52 149.01,132.62 149.25,132.62 149.46,132.83 149.46,133.07 148.62,133.9 148.62,134.28 148.93,134.59 149.31,134.59 150.34,133.56 150.57,133.56 150.78,133.77 150.78,134.01 149.45,135.34 149.45,135.72 149.91,136.18 150.28,136.18 151.41,135.05 152.09,135.05 152.33,135.3 152.33,137.33 152.95,137.95 152.95,138.31 v2(152.63,138.64)
  BOTTOM w0.099: v2(152.63,138.64) 152.45,138.82 R430.1
MEMCKE: length 36.5
  TOP w0.109: v2(147.49,126.63) U20.Y11 ; U21.K2 v2(152.63,143.44)
  SIG1 w0.086: v2(147.49,126.63) 147.85,126.98 147.87,127.05 147.87,128.68 149.3,130.1 149.3,130.35 154.1,135.15 154.1,136.32 154.22,136.45 154.22,140.53 154.33,140.64 155.74,140.64 155.88,140.78 155.88,141.04 155.74,141.18 154.33,141.18 154.22,141.29 154.22,141.5 154.33,141.61 155.64,141.61 155.75,141.71 155.75,142.06 155.64,142.16 154.2,142.16 154.1,142.27 154.1,143.74 153.99,143.85 152.74,143.85 152.63,143.74 v2(152.63,143.44)
  BOTTOM w0.109: R388.1 154.71,149.56 154.86,149.4 154.86,147.37 154.76,147.27 R387.2 154.35,146.1 153.03,144.78 153.03,143.85 v2(152.63,143.44)
MEMCKN: length 28.4
  TOP w0.099: v1(147.11,129.61) 147.37,129.87 148.76,129.87 148.94,129.69 148.94,129.33 148.31,128.7 147.71,128.7 147.37,128.36 147.37,128.11 U20.AB12 ; U21.K8 v2(153.43,138.64)
  SIG1 w0.094: v2(153.43,138.64) 153.21,138.42 153.21,137.85 152.59,137.22 152.59,135.19 152.19,134.8 151.3,134.8 150.18,135.92 150.02,135.92 149.7,135.61 149.7,135.45 151.04,134.11 151.04,133.67 150.68,133.3 150.23,133.3 149.2,134.33 149.04,134.33 148.88,134.17 148.88,134.01 149.72,133.17 149.72,132.72 149.35,132.36 148.91,132.36 148,133.27 147.84,133.27 147.68,133.1 147.68,132.94 148.7,131.93 148.7,131.43 148.13,130.86 148.13,130.48 147.75,130.1 147.34,130.1 147.11,129.87 v1(147.11,129.61)
  BOTTOM w0.099: R433.1 153.46,138.68 v2(153.43,138.64)
MEMCSN: length 39.9
  TOP w0.109: U21.L7 v2(151.82,138.64) ; v2(147.49,127.43) U20.AA12
  SIG1 w0.086: v2(147.49,127.43) 147.49,128.92 148.86,130.28 148.86,130.55 153.59,135.28 153.59,136.7 153.84,136.96 153.84,139.23 153.74,139.33 152.81,139.33 152.7,139.44 152.7,139.65 152.81,139.76 153.74,139.76 153.84,139.87 153.84,140.08 153.74,140.19 152.81,140.19 152.7,140.29 152.7,140.51 152.81,140.61 153.74,140.61 153.84,140.72 153.84,141.8 153.48,142.16 153.08,142.16 152.76,141.85 152.76,141.21 152.32,140.77 152.32,138.86 152.1,138.64 v2(151.82,138.64)
  BOTTOM w0.109: v2(151.82,138.64) 150.59,139.88 148.51,139.88 147.62,140.77 147.19,140.77 144.98,142.98 144.98,143.31 144.85,143.43 R379.2 144.67,143.05 144.55,142.93 142.41,142.93 142.26,143.08 R380.1
MEMDM_0: length 25.1
  TOP w0.109: U21.E7 v2(157.43,138.64) ; U20.U8 v2(150.69,124.23)
  SIG4 w0.086: v2(157.43,138.64) 157.67,138.64 157.83,138.48 157.83,136.78 157.96,136.65 157.96,135.48 157.85,135.38 157.71,135.38 157.6,135.27 157.6,134.87 157.71,134.77 158.18,134.77 158.29,134.66 158.29,134.45 158.18,134.34 157.71,134.34 157.6,134.23 157.6,134.02 157.71,133.91 158.18,133.91 158.29,133.81 158.29,133.59 158.18,133.49 157.71,133.49 157.6,133.38 157.6,133.17 157.71,133.06 158.18,133.06 158.29,132.95 158.29,132.74 158.18,132.63 157.71,132.63 157.6,132.53 157.6,132.31 157.71,132.21 158.18,132.21 158.29,132.1 158.29,131.89 158.18,131.78 157.71,131.78 157.6,131.67 157.6,130.56 153.21,126.16 153.21,125.02 152.7,124.51 152.7,124 152.55,123.85 151.07,123.85 v2(150.69,124.23)
MEMDM_1: length 27.4
  TOP w0.109: U20.AB8 150.29,128.45 151.43,129.59 v2(151.81,129.59) ; v2(157.42,142.64) U21.E2
  SIG1 w0.086: v2(151.81,129.59) 156.13,133.91 156.76,133.91 158.8,135.94 158.8,136.58 158.62,136.75 158.62,137.16 158.92,137.47 159.33,137.47 159.44,137.57 159.44,139 159.81,139.37 159.81,139.88 159.05,140.64 159.05,141.4 158.29,142.16 156.3,142.16 156.2,142.27 156.2,143.18 156.07,143.31 155.98,143.31 155.88,143.41 155.88,143.71 155.98,143.82 157.65,143.82 157.78,143.69 157.78,143 v2(157.42,142.64)
MEMDQ_0: length 25.3
  TOP w0.109: v2(155.82,142.64) U21.G2 ; v2(149.09,123.43) 149.09,123.43 U20.U10
  SIG4 w0.086: v2(155.82,142.64) 156.58,141.89 156.91,141.89 157.27,141.53 157.27,140.64 157.02,140.39 157.02,135.81 157.15,135.69 157.15,131.62 155.55,130.03 155.55,129.14 151.84,125.43 151.33,125.43 151.1,125.2 151.1,124.82 150.92,124.64 150.3,124.64 v2(149.09,123.43)
MEMDQ_1: length 25.1
  TOP w0.109: U21.F7 v2(156.63,138.64) ; U20.W10 v2(149.09,125.83)
  SIG4 w0.086: v2(156.63,138.64) 156.24,138.26 156.24,136.82 156.04,136.61 156.04,136.29 156.13,136.2 156.4,136.2 156.51,136.09 156.51,135.69 156.7,135.5 156.7,135.03 156.59,134.93 156.31,134.93 156.18,134.79 156.18,134.02 156.29,133.91 156.58,133.91 156.71,133.78 156.71,131.82 154.6,129.71 154.6,129.56 154.88,129.28 154.88,129.1 154.75,128.98 154.58,128.98 154.47,129.08 154.3,129.26 154.14,129.26 153.99,129.11 153.99,128.96 154.16,128.79 154.16,128.64 154.01,128.49 153.86,128.49 153.69,128.65 153.54,128.65 153.34,128.45 153.34,127.5 153.23,127.4 152.93,127.4 152.83,127.5 152.83,128.58 152.67,128.74 152.23,128.74 151.91,128.42 151.91,127.28 151.68,127.05 151.3,127.05 151.1,126.85 151.1,125.63 150.92,125.45 149.73,125.45 149.35,125.83 v2(149.09,125.83)
MEMDQ_2: length 25.1
  TOP w0.109: v2(148.29,126.63) U20.Y10 ; U21.H3 v2(155.02,142.64)
  SIG4 w0.086: v2(148.29,126.63) 148.47,126.63 148.71,126.87 148.71,127.74 148.51,127.94 148.51,129.3 148.62,129.41 148.99,129.41 149.1,129.51 149.1,129.73 148.99,129.83 148.57,129.83 148.46,129.94 148.46,131.65 149.83,133.02 150.8,133.02 152.19,134.42 152.19,135.38 153.01,136.2 153.01,138.94 152.57,139.37 152.57,141.02 153.97,142.42 153.97,143.69 154.1,143.82 155.02,143.82 155.13,143.71 155.13,143.25 155.02,143.15 v2(155.02,142.64)
MEMDQ_3: length 24.6
  TOP w0.109: U21.H7 v2(155.02,138.64) ; U20.AA10 149.08,126.64 v2(149.09,126.64)
  SIG4 w0.086: v2(149.09,126.64) 149.45,127 150.62,127 150.92,127.31 150.92,128.64 151.11,128.83 151.68,128.83 152.24,129.39 152.39,129.39 152.56,129.22 152.71,129.22 152.86,129.37 152.86,129.52 152.69,129.69 152.69,129.84 152.95,130.09 153.1,130.09 153.58,129.61 153.73,129.61 153.88,129.76 153.88,129.91 153.4,130.39 153.4,130.54 153.55,130.7 153.7,130.7 154.25,130.15 154.4,130.15 154.55,130.3 154.55,130.45 154,131 154,131.15 154.16,131.3 154.31,131.3 154.79,130.82 154.94,130.82 155.09,130.97 155.09,131.12 154.61,131.6 154.61,131.75 154.76,131.9 154.91,131.9 155.39,131.42 155.54,131.42 155.7,131.57 155.7,131.72 155.21,132.2 155.21,132.36 155.74,132.89 155.74,135.1 155.82,135.18 155.9,135.18 156,135.29 156,135.58 155.9,135.69 155.6,135.69 155.49,135.79 155.49,136.37 155.42,136.45 155.42,138.25 v2(155.02,138.64)
MEMDQ_4: length 25.3
  TOP w0.109: v2(149.09,124.23) U20.U9 ; v2(151.81,140.26) 153.08,141.53 153.72,141.53 154.22,142.04 154.22,142.64 U21.H2
  SIG4 w0.086: v2(149.09,124.23) 148.69,124.64 148.13,124.64 147.11,125.65 147.11,125.96 146.83,126.24 146.53,126.24 146.27,126.49 146.27,128.27 146.2,128.35 146.2,133.38 149.14,136.32 149.27,136.32 149.81,136.86 149.81,138.76 151.3,140.26 v2(151.81,140.26)
MEMDQ_5: length 25.3
  TOP w0.109: U21.H8 v2(155.02,137.84) ; U20.Y9 149.89,126.63 149.89,127.42 v2(149.91,127.43)
  SIG4 w0.086: v2(155.02,137.84) 154.48,137.29 154.48,136.83 154.99,136.32 154.99,134.8 154.86,134.67 154.61,134.67 154.48,134.54 154.48,134.27 154.59,134.16 155.01,134.16 155.11,134.06 155.11,133.76 155.01,133.66 154.48,133.66 154.41,133.59 154.41,133.31 154.83,132.89 154.83,132.74 154.68,132.59 154.53,132.59 154.11,133.01 153.96,133.01 153.81,132.86 153.81,132.7 154.23,132.28 154.23,132.13 154.08,131.98 153.93,131.98 153.31,132.59 153.16,132.59 153.01,132.44 153.01,132.29 153.62,131.68 153.62,131.53 153.47,131.38 153.32,131.38 152.9,131.8 152.75,131.8 152.6,131.65 152.6,131.5 153.02,131.08 153.02,130.93 152.87,130.78 152.72,130.78 152.3,131.2 152.15,131.2 152,131.04 152,130.89 152.42,130.47 152.42,130.32 152.27,130.17 152.11,130.17 151.63,130.66 151.48,130.66 151.25,130.43 151.25,130.28 151.47,130.06 151.47,129.91 151.3,129.75 151.15,129.75 150.8,130.1 150.67,130.1 150.54,129.97 150.54,129.59 150.91,129.22 150.91,129.07 150.54,128.7 150.54,127.56 150.41,127.43 v2(149.91,127.43)
MEMDQ_6: length 24
  TOP w0.109: U20.W9 v2(149.89,125.83) ; U21.J3 v2(153.43,142.64)
  SIG4 w0.086: v2(149.89,125.83) 149.49,126.24 148.11,126.24 147.87,126.47 147.87,127.94 147.62,128.19 147.62,131.19 147.76,131.33 147.76,131.61 150.13,133.98 150.28,133.98 150.56,133.7 150.71,133.7 150.86,133.85 150.86,134 150.58,134.28 150.58,134.43 150.73,134.58 150.88,134.58 151.17,134.3 151.32,134.3 151.47,134.45 151.47,134.6 151.19,134.89 151.19,135.04 152.24,136.09 152.24,141.46 v2(153.43,142.64)
MEMDQ_7: length 24.7
  TOP w0.109: U21.J7 153.37,139.5 v2(151.81,139.5) ; U20.V9 v2(149.89,125.03)
  SIG4 w0.086: v2(149.89,125.03) 149.64,125.03 149.22,125.45 148.08,125.45 147.87,125.65 147.87,126.04 147.67,126.24 147.29,126.24 147.11,126.42 147.11,128.58 146.66,129.03 146.66,132.31 147.69,133.34 148.09,133.34 148.41,133.03 148.56,133.03 148.71,133.18 148.71,133.33 148.4,133.64 148.4,133.8 148.55,133.95 148.7,133.95 148.93,133.72 149.08,133.72 149.23,133.87 149.23,134.02 149,134.25 149,134.4 149.33,134.73 149.48,134.73 149.8,134.42 149.95,134.42 150.7,135.17 150.7,136.23 151.43,136.96 151.43,139.37 151.56,139.5 v2(151.81,139.5)
MEMDQ_8: length 27.4
  TOP w0.109: U20.AA8 150.69,127.43 150.69,128.35 151.3,128.96 v2(153.08,128.96) ; v2(159.43,141.28) 159.94,141.28 160.22,141.56 U21.A3
  SIG1 w0.086: v2(159.43,141.28) 159.43,140.89 159.65,140.68 159.8,140.68 160.16,141.03 160.31,141.03 160.46,140.88 160.46,140.73 160.1,140.37 160.1,140.22 160.25,140.07 160.4,140.07 160.7,140.37 160.85,140.37 161.21,140.01 161.21,136.58 161.08,136.45 161.08,134.93 159.77,133.61 159.77,132.98 158.72,131.92 158.72,131.77 158.88,131.61 158.88,131.45 158.73,131.3 158.58,131.3 158.41,131.47 158.26,131.47 158.11,131.32 158.11,131.17 158.34,130.94 158.34,130.79 158.19,130.64 158.04,130.64 157.81,130.87 157.66,130.87 155.37,128.58 153.46,128.58 v2(153.08,128.96)
MEMDQ_9: length 27.7
  TOP w0.109: U21.B8 159.06,137.87 v2(158.24,137.87) ; U20.Y8 v2(150.69,126.63)
  SIG1 w0.086: v2(158.24,137.87) 158.24,137.92 158.67,138.35 158.67,139.12 158.51,139.28 158.32,139.28 157.83,138.78 157.83,138.4 157.65,138.23 157.15,138.23 157.02,138.35 157.02,138.88 156.72,139.18 156.31,139.18 156.21,139.07 156.21,137.57 156.31,137.47 156.89,137.47 157.02,137.34 157.02,136.68 156.91,136.58 156.01,136.58 155.86,136.43 155.86,136.21 156.02,136.05 156.91,136.05 157.02,135.95 157.02,135.71 156.89,135.59 156.03,135.59 155.93,135.48 155.93,134.98 150.94,129.99 150.94,129.1 150.29,128.45 150.29,127.69 150.41,127.56 150.56,127.56 150.73,127.39 150.73,127.16 150.62,127.05 149.98,127.05 149.87,126.94 149.87,126.56 150.01,126.42 150.48,126.42 v2(150.69,126.63)
MEMDQ_10: length 28
  TOP w0.109: U20.Y7 v2(151.49,126.63) ; U21.C3 v2(159.02,142.64)
  SIG1 w0.086: v2(151.49,126.63) 151.91,127.05 152.66,127.05 152.77,126.94 152.77,126.52 152.88,126.42 153.09,126.42 153.2,126.52 153.2,126.94 153.3,127.05 153.52,127.05 153.62,126.94 153.62,126.52 153.73,126.42 153.94,126.42 154.05,126.52 154.05,126.94 154.16,127.05 156.64,127.05 160.65,131.06 160.65,133.22 162,134.57 162,140.49 160.45,142.04 159.63,142.04 v2(159.02,142.64)
MEMDQ_11: length 27.5
  TOP w0.109: U20.W8 v2(150.69,125.83) ; v2(157.91,140.51) 158.5,140.51 158.63,140.39 U21.C7
  SIG1 w0.086: v2(157.91,140.51) 157.8,140.62 157.6,140.62 157.49,140.51 157.49,140.29 157.65,140.13 158.56,140.13 158.67,140.03 158.67,139.75 158.54,139.62 158.24,139.62 157.65,139.04 157.3,139.04 156.84,139.5 156,139.5 155.44,138.94 155.44,135.13 150.24,129.92 150.24,129.51 150.49,129.27 150.49,129.03 150.34,128.88 150.19,128.88 149.86,129.22 149.71,129.22 149.58,129.09 149.58,128.9 149.69,128.79 149.69,128.56 149.5,128.37 149.5,125.55 149.63,125.43 150.59,125.43 150.69,125.53 v2(150.69,125.83)
MEMDQ_12: length 27.6
  TOP w0.109: v2(158.24,142.62) 158.24,142.65 U21.C2 ; U20.AA6 v2(152.29,127.43)
  SIG1 w0.086: v2(158.24,142.62) 158.7,142.16 158.92,142.16 159.3,141.78 160.07,141.78 161.54,140.31 161.54,134.75 160.21,133.42 160.21,131.89 158.16,129.84 157.91,129.84 157.66,130.1 157.51,130.1 157.27,129.86 157.27,129.71 157.64,129.34 157.64,129.19 157.49,129.04 157.34,129.04 156.97,129.41 156.82,129.41 156.67,129.26 156.67,129.11 156.97,128.8 156.97,128.65 156.82,128.5 156.67,128.5 156.37,128.81 156.22,128.81 154.84,127.43 153.38,127.43 153.27,127.54 153.27,127.96 153.17,128.07 152.95,128.07 152.85,127.96 152.85,127.54 152.74,127.43 v2(152.29,127.43)
MEMDQ_13: length 27.4
  TOP w0.109: U20.W7 v2(151.49,125.83) ; U21.C8 159.05,138.67 159.05,139.24 159.3,139.5 162.1,139.5 v1(162.48,139.12)
  SIG1 w0.086: v1(162.48,139.12) 162.48,134.42 161.08,133.02 161.08,130.86 156.05,125.83 155.28,125.83 155.18,125.94 155.18,126.56 155.07,126.67 154.86,126.67 154.75,126.56 154.75,125.94 154.64,125.83 v2(151.49,125.83)
MEMDQ_14: length 27.5
  TOP w0.109: v2(157.78,141.66) 157.6,141.84 157.6,142.01 U21.D3 ; U20.V7 v2(151.49,125.03)
  SIG1 w0.086: v2(157.78,141.66) 157.54,141.89 156.37,141.89 156.23,141.76 156.23,141.17 156.38,141.02 157.02,141.02 157.27,141.28 157.78,141.28 158.54,140.51 158.67,140.51 159.3,139.88 159.3,139.5 159.05,139.24 159.05,138.1 158.42,137.47 158.03,137.47 157.83,137.26 157.83,136.68 157.94,136.58 158.29,136.58 158.41,136.46 158.41,136.19 157.91,135.69 157.65,135.69 157.4,135.43 157.4,135.18 157.15,134.93 156.51,134.93 151.38,129.79 151.38,128.91 150.8,128.32 150.8,128.07 151.1,127.76 151.1,125.63 151.49,125.24 v2(151.49,125.03)
MEMDQ_15: length 28.2
  TOP w0.109: U21.D7 v2(157.43,139.44) ; U20.U7 v2(151.49,124.23)
  SIG1 w0.086: v2(151.49,124.23) 151.09,124.64 148.04,124.64 147.87,124.8 147.87,125.24 148.09,125.45 148.58,125.45 148.69,125.56 148.69,127.64 148.51,127.81 148.36,127.81 148.26,127.92 148.26,128.42 149.78,129.95 149.78,130.1 154.56,134.87 154.56,135.55 154.69,135.69 154.87,135.69 154.99,135.81 154.99,136.46 154.87,136.58 154.73,136.58 154.61,136.7 154.61,139.59 154.74,139.72 155.02,139.72 155.11,139.62 155.52,139.62 155.62,139.73 155.62,140.15 155.73,140.26 156.1,140.26 156.21,140.15 156.21,139.98 156.32,139.88 156.53,139.88 156.64,139.98 156.64,140.03 156.8,140.18 157.12,140.18 157.27,140.03 157.27,139.59 v2(157.43,139.44)
MEMDQS_0_DN: length 24.4
  TOP w0.099: v1(156.64,141.48) 156.64,141.27 156.51,141.15 156.11,141.15 155.94,141.32 155.94,141.95 U21.F3 ; U20.AB10 v2(149.09,128.23)
  SIG4 w0.094: v2(149.09,128.23) 149.5,128.63 149.5,129.03 149.78,129.32 149.78,130.01 149.3,130.49 149.3,130.86 149.95,131.52 150.33,131.52 150.72,131.13 150.95,131.13 151.17,131.34 151.17,131.58 150.86,131.88 150.86,132.25 151.17,132.56 151.55,132.56 151.85,132.26 152.09,132.26 152.3,132.47 152.3,133.49 153.68,134.87 153.68,137.53 154.35,138.21 154.35,139.27 154.12,139.5 153.61,139.5 153.34,139.77 153.34,140.76 153.75,141.17 156.33,141.17 v1(156.64,141.48)
MEMDQS_0_DP: length 24.4
  TOP w0.099: v1(156.64,140.56) 156.64,140.64 156.38,140.9 156,140.9 155.69,141.21 155.69,141.98 U21.G3 ; U20.AB9 v2(149.89,128.23)
  SIG4 w0.094: v2(149.89,128.23) 149.75,128.38 149.75,128.93 150.03,129.21 150.03,130.11 149.55,130.6 149.55,130.76 150.06,131.27 150.22,131.27 150.62,130.87 151.06,130.87 151.42,131.23 151.42,131.68 151.12,131.99 151.12,132.15 151.28,132.31 151.44,132.31 151.75,132 152.19,132 152.56,132.37 152.56,133.38 153.93,134.76 153.93,137.43 154.61,138.1 154.61,139.37 154.23,139.75 153.72,139.75 153.59,139.88 153.59,140.65 153.85,140.91 156.47,140.91 156.64,140.75 v1(156.64,140.56)
MEMDQS_1_DN: length 26.6
  TOP w0.099: U21.A7 v2(160.63,138.64) ; U20.AB6 v2(152.29,128.23)
  SIG1 w0.094: v2(160.63,138.64) 160.33,138.35 160.33,136.46 159.68,135.8 159.68,135.57 160.03,135.22 160.03,134.76 159.46,134.19 159.08,134.19 158.67,134.6 158.44,134.6 158.22,134.38 158.22,134.15 158.94,133.43 158.94,133.06 158.63,132.75 158.26,132.75 157.54,133.47 157.3,133.47 157.09,133.25 157.09,133.02 157.74,132.36 157.74,131.99 157.43,131.68 157.06,131.68 156.17,132.57 155.93,132.57 155.72,132.35 155.72,132.12 156.55,131.29 156.55,130.92 156.24,130.61 155.87,130.61 155.04,131.44 154.8,131.44 154.59,131.22 154.59,130.99 155.29,130.29 155.29,129.91 154.72,129.34 154.34,129.34 153.72,129.97 153.34,129.97 152.12,128.76 152.12,128.4 v2(152.29,128.23)
MEMDQS_1_DP: length 26.7
  TOP w0.099: U21.B7 v2(159.82,138.64) ; U20.AB7 v2(151.49,128.23)
  SIG1 w0.094: v2(159.82,138.64) 160.08,138.39 160.08,136.57 159.42,135.91 159.42,135.46 159.77,135.11 159.77,134.86 159.35,134.44 159.19,134.44 158.78,134.85 158.33,134.85 157.97,134.49 157.97,134.04 158.69,133.32 158.69,133.16 158.52,133 158.36,133 157.64,133.72 157.2,133.72 156.84,133.36 156.84,132.91 157.49,132.26 157.49,132.09 157.33,131.93 157.17,131.93 156.28,132.82 155.83,132.82 155.47,132.46 155.47,132.01 156.29,131.19 156.29,131.03 156.13,130.86 155.97,130.86 155.14,131.69 154.7,131.69 154.33,131.33 154.33,130.88 155.03,130.18 155.03,130.02 154.61,129.6 154.45,129.6 153.82,130.23 153.23,130.23 151.87,128.86 151.87,128.61 v2(151.49,128.23)
MEMODT: length 37
  TOP w0.109: U21.K3 v2(152.63,142.64) ; U20.V11 v2(148.29,125.03)
  SIG3 w0.107: v2(152.63,142.64) 153.1,142.16 153.59,142.16 153.84,141.91 153.84,140.77 153.75,140.68 153.56,140.68 153.46,140.58 153.46,140.39 153.56,140.3 153.88,140.3 153.97,140.21 153.97,140.02 153.88,139.92 153.56,139.92 153.46,139.83 153.46,139.64 153.56,139.55 154,139.55 154.12,139.43 154.12,136.04 154.35,135.81 154.35,127.94 152.65,126.24 148.84,126.24 148.71,126.11 148.71,125.45 v2(148.29,125.03)
  BOTTOM w0.109: v2(152.63,142.64) 153.1,142.16 155.11,142.16 155.44,142.49 155.44,145.77 155.37,145.85 R389.2 155.77,147.27 155.88,147.37 155.88,149.28 155.6,149.56 R390.1
MEMRASN: length 28.6
  TOP w0.109: v2(147.49,125.83) U20.W12 ; v2(153.16,135.81) 153.41,136.07 153.41,137.64 153.21,137.85 152.62,137.85 U21.L8
  SIG3 w0.107: v2(153.16,135.81) 153.16,138 153.31,138.15 153.54,138.15 153.72,137.97 153.72,135.82 153.95,135.59 153.95,128.42 153.52,128 153.39,128 153.03,128.36 152.9,128.36 152.76,128.23 152.76,128.09 153.12,127.73 153.12,127.6 152.57,127.05 148.89,127.05 148.69,126.85 148.69,126.47 148.46,126.24 148.15,126.24 147.75,125.83 v2(147.49,125.83)
  BOTTOM w0.109: v2(153.16,135.81) 152.27,134.93 R381.2 R382.1
MEMRESET_N: length 31.5
  TOP w0.109: U20.AB17 v2(142.69,128.23) ; U21.P1 v2(149.43,144.24)
  SIG1 w0.086: v2(149.43,144.24) 149.03,143.84 147.01,143.84 144.84,141.67 144.56,141.67 144.02,142.2 143.85,142.2 143.72,142.08 143.72,141.9 144.32,141.3 144.32,141.15 144.17,141 144.02,141 143.73,141.29 143.58,141.29 143.42,141.14 143.42,140.99 143.78,140.63 143.78,140.48 143.18,139.88 142.92,139.88 142.54,139.5 142.54,136.6 142.65,136.49 143,136.49 143.13,136.36 143.13,136.19 143,136.06 142.65,136.06 142.54,135.96 142.54,135.74 142.65,135.64 143,135.64 143.13,135.51 143.13,135.33 143,135.21 142.67,135.21 142.54,135.08 142.54,128.38 v2(142.69,128.23)
  BOTTOM w0.109: R375.1 149.27,149.02 149.53,148.77 149.53,144.34 v2(149.43,144.24)
MEMWEN: length 34.2
  TOP w0.109: v2(151.83,142.64) U21.L2 ; U20.Y12 v2(146.69,126.63)
  SIG3 w0.107: v2(151.83,142.64) 151.83,142.4 152.45,141.78 152.45,141.28 152.32,141.15 151.02,141.15 150.92,141.05 150.92,140.85 151.02,140.75 152.48,140.75 152.57,140.66 152.57,140.47 152.48,140.38 152.34,140.38 152.24,140.28 152.24,140.1 152.34,140 152.48,140 152.57,139.91 152.57,139.72 152.48,139.63 152.34,139.63 152.24,139.53 152.24,138.48 152.3,138.42 152.3,135.53 153.12,134.72 153.12,130.51 152.7,130.1 151.74,130.1 150.26,128.63 148.81,128.63 147.87,127.69 147.87,127.18 147.75,127.05 147.11,127.05 v2(146.69,126.63)
  BOTTOM w0.109: R386.1 153.72,149.56 153.84,149.43 153.84,147.37 153.74,147.27 R385.2 153.34,145.85 152.22,144.73 152.22,143.03 v2(151.83,142.64)
MFG_MODE_SRTAP: length 29.4
  TOP w0.109: U43.BD22 88.39,88.09 v2(88.11,87.81)
  SIG3 w0.107: v1(94.01,111.72) 94.64,111.09 94.64,108.02 94.99,107.67 94.99,100.97 94.41,100.38 94.41,97.84 92.63,96.06 92.63,94.87 91.61,93.86 91.61,92.38 91.82,92.18 91.82,91.06 91.61,90.86 90.98,90.86 90.09,89.97 90.09,89.46 88.9,88.27 88.57,88.27 v2(88.11,87.81)
  BOTTOM w0.109: R899.2 93.77,111.96 v1(94.01,111.72)
MISO: length 29.5
  TOP w0.109: v1(122.35,121.84) 121.74,121.23 R149.2 R150.2 ; R765.1 118.54,134.04 v1(118.92,133.66) ; v1(118.41,144.83) 118.03,144.45 R774.1
  BOTTOM w0.109: v1(118.41,144.83) 118.28,144.7 118.28,134.29 v1(118.92,133.66) 118.92,133.34 120.32,131.94 120.32,125.53 120.82,125.02 120.82,123.37 v1(122.35,121.84)
MOSI: length 59.5
  TOP w0.109: v1(100.76,138.3) 100.76,138.1 101.01,137.85 101.65,137.85 101.93,137.57 R769.2 ; R779.2 101.42,147.35 v1(101.37,147.4) ; R145.2 v1(123.36,112.95) R146.2
  SIG4 w0.086: v1(123.36,112.95) 122.37,112.95 121.75,113.57 120.84,113.57 120.3,114.11 120.3,119.45 116.55,123.19 111.88,123.19 111.68,122.99 105.46,122.99 105.38,122.91 103.37,122.91 102.69,123.6 102.69,124.66 103.68,125.65 103.68,128.32 103.17,128.83 103.17,134.98 100.88,137.26 100.88,138.18 v1(100.76,138.3) 101.27,138.81 101.27,147.29 v1(101.37,147.4)
NC_SI_ARB_IN: length 3.1
  BOTTOM w0.109: U26.43 170.46,119.05 170.34,119.18 170.1,119.18 168.96,120.32 R625.1
NC_SI_ARB_OUT: length 2.7
  BOTTOM w0.109: R626.1 169.97,120.57 170.35,120.19 170.35,119.69 170.96,119.08 U26.44
NCSI_ABR_OUT: length 11.9
  TOP w0.109: R780.2 R785.2 104.34,55.14 103.93,55.55 103.93,56.95 103.68,57.2 100.88,57.2 98.98,59.11 98.98,60.66 98.62,61.01 98.62,61.37 98.77,61.51 U43.AB78
NCSI_CLK_IN: length 1.6
  TOP w0.109: v2(98.51,64.59) 98.83,64.91 U43.AA72
  BOTTOM w0.109: v2(98.51,64.59) 98.5,64.58 R794.2
NCSI_CRS_DV: length 15.5
  TOP w0.109: U43.V74 100.88,63.96 100.88,63.46 101.11,63.23 101.11,62.97 100.88,62.74 100.88,62.23 101.06,62.06 101.06,61.24 101.27,61.04 101.27,60.88 101.77,60.38 103.81,60.38 106.35,57.84 107.49,57.84 108.76,56.57 109.52,56.57 110.54,55.55 R790.2
NCSI_NIC_ACT: length 29.2
  TOP w0.109: R194.2 184.22,109.78 v1(183.97,109.53)
  SIG3 w0.107: v1(163.24,117.78) 165.4,117.78 165.88,118.26 172.28,118.26 172.64,117.91 172.64,117.63 174.39,115.88 175.14,115.88 180.26,110.76 180.26,109.53 181.02,108.76 183.21,108.76 v1(183.97,109.53)
  BOTTOM w0.109: v1(163.24,117.78) 163.24,117.4 163.79,116.85 U26.30
NCSI_NIC_LED_100M: length 29.7
  TOP w0.109: R196.1 184.32,110.8 182.8,109.27 v1(181.15,109.27)
  SIG3 w0.107: v1(163.24,118.67) 163.75,119.18 164.38,119.18 165.02,118.54 172.51,118.54 173.02,118.03 173.02,117.65 174.29,116.38 175.05,116.38 181.15,110.29 v1(181.15,109.27)
  BOTTOM w0.109: U26.31 164.18,117.35 163.75,117.78 163.75,118.16 v1(163.24,118.67)
NCSI_NIC_LED_1000M: length 25.1
  TOP w0.109: v1(182.93,110.54) 183.69,111.3 184.73,111.3 184.86,111.43 R199.1
  SIG3 w0.107: v1(165.02,119.18) 165.35,118.85 173.1,118.85 179.62,112.32 181.15,112.32 v1(182.93,110.54)
  BOTTOM w0.109: v1(165.02,119.18) 165.15,119.18 165.46,118.86 U26.33
NCSI_RXD0: length 14.2
  TOP w0.109: v2(99.97,65.46) 99.83,65.46 U43.Y71
  BOTTOM w0.109: R786.2 104.09,55.14 103.93,55.3 103.93,57.43 104.06,57.56 R1178.2 104.44,58.22 103.81,58.85 103.81,60.88 101.52,63.17 100.76,63.17 100.02,63.91 100.02,64.08 99.77,64.34 99.77,65.25 v2(99.97,65.46)
NCSI_RXD1: length 4.9
  TOP w0.109: v2(101.01,66.01) 101.01,65.71 100.21,64.91 U43.W72
  BOTTOM w0.109: R1177.2 100.35,68.15 100.5,68 100.5,67.62 100.12,67.23 100.12,66.75 100.35,66.52 R787.2 100.73,66.29 v2(101.01,66.01)
NCSI_TX_EN: length 14.4
  TOP w0.089: 99.59,60.64 99.59,61.57 99.47,61.69 99.47,62.31 99.61,62.46 99.61,62.76 99.27,63.11 U43.AA75
  TOP w0.109: 99.59,60.64 99.59,59.51 101.14,57.96 103.87,57.96 104.69,57.14 104.69,56.82 105.52,55.99 106.48,55.99 106.98,55.5 106.98,55.3 107.13,55.14 R792.2
NCSI_TXD0: length 13
  TOP w0.089: 100.12,60.76 100.12,62.47 U43.W77
  TOP w0.109: 100.12,60.76 101.27,59.61 103.42,59.61 105.96,57.07 107.23,57.07 108.5,55.8 R793.2
NCSI_TXD1: length 9.6
  TOP w0.109: R1165.2 105.46,56.57 105.08,56.95 105.08,57.2 103.94,58.34 101.27,58.34 99.87,59.74 99.87,61.76 U43.Y78
NIC0_RMII_RXCLK: length 6.2
  BOTTOM w0.109: R594.2 R596.1 R599.1 174.93,108.13 174.54,108.51 173.21,108.51 172.46,109.26 U26.2
NIC0_RMII_RXCLK_50M: length 23.2
  SIG3 w0.107: v1(158.92,101.65) 159.15,101.42 172.03,101.42 v1(172.64,102.03)
  BOTTOM w0.109: v1(172.64,102.03) 173.15,102.54 174.04,102.54 175.94,104.45 R596.2 ; R56.2 156.54,101.17 156.76,101.4 158.67,101.4 v1(158.92,101.65)
NIC_FLASH_CE_N: length 21.4
  TOP w0.109: U27.1 159.3,89.59 v1(161.97,92.25)
  BOTTOM w0.109: v1(161.97,92.25) 161.46,92.76 161.46,94.03 161.72,94.29 161.72,99.69 162.27,100.24 162.27,105.25 163.39,106.38 R616.2
NIC_FLASH_SCK: length 23.1
  TOP w0.109: U27.6 161.59,87.05 161.46,87.17 161.46,89.97 162.94,91.44 v1(162.94,92.51)
  BOTTOM w0.109: v1(162.94,92.51) 162.94,92.68 162.61,93.01 162.61,97.13 163.09,97.61 163.09,104.51 163.92,105.33 165.27,105.33 165.78,105.84 R619.2
NIC_FLASH_SI: length 28.7
  TOP w0.109: R610.1 R611.1 164,86.03 163.75,85.78 U27.5 161.21,85.78 160.96,86.03 160.96,90.17 162.43,91.65 162.43,92.96 162.86,93.4 v1(163.11,93.4)
  BOTTOM w0.109: R620.2 166.8,106.1 165.48,104.78 164.08,104.78 163.6,104.3 163.6,97.4 163.11,96.92 v1(163.11,93.4)
NIC_FLASH_SO: length 26.9
  TOP w0.109: v1(161.97,93.14) 159.18,90.35 156.38,90.35 154.96,88.93 R609.2 155.75,88.06 156,88.32 U27.2
  BOTTOM w0.109: v1(161.97,93.14) 162.1,93.27 162.1,99.62 162.59,100.11 162.59,104.72 163.71,105.84 164.64,105.84 164.77,105.97 R618.2
NIC_PLAYDEAD: length 129
  TOP w0.109: v1(163.64,115.25) 163.64,114.85 164,114.48 R627.1 ; U2.C8 v1(80.71,144.23)
  SIG1 w0.086: v1(80.71,144.23) 81.36,144.23 82.09,144.96 82.09,147.61 84.26,149.79 123.37,149.79 124.84,151.26 141.21,151.26 142.48,149.99 161.9,149.99 164,147.88 164,142.55 164.58,141.97 164.58,134.61 165.91,133.27 166.92,133.27 167.69,132.51 167.69,125.91 166.16,124.38 166.16,121.34 165.53,120.7 165.53,117.15 v1(163.64,115.25)
  BOTTOM w0.109: v1(163.64,115.25) 164.23,115.85 U26.28
NIC_WAKEN: length 140.5
  TOP w0.109: v1(76.71,143.23) U2.C4 ; R600.1 164.28,107.34 v1(163.62,108)
  SIG3 w0.107: v1(72.31,151.31) 72.44,151.44 80.18,151.44 81.33,152.58 90.98,152.58 93.19,150.37 124.81,150.37 134.54,140.64 135.17,140.64 140.13,135.69 140.13,131.75 139.87,131.5 139.87,114.99 141.4,113.46 143.64,113.46 145.08,112.02 145.08,110.13 145.84,109.37 157.35,109.37 158.16,108.56 163.06,108.56 v1(163.62,108)
  BOTTOM w0.109: U26.16 165.46,109.47 165.34,109.35 164.59,109.35 163.62,108.38 v1(163.62,108) ; v1(72.31,151.31) 72.18,151.18 72.18,146.86 73.2,145.85 73.2,144.07 73.58,143.69 75.99,143.69 76.45,143.23 v1(76.71,143.23)
ONLINE_CPLD_JTAG_EN: length 55.9
  TOP w0.109: R1164.2 90.32,115.77 90.09,116 90.09,116.64 89.99,116.74 R1163.2 89.18,116.74 89.07,116.64 89.07,115.37 89.33,115.11 v1(89.58,115.11)
  SIG3 w0.107: v1(99.51,123.83) 99.18,123.5 96.95,123.5 96.82,123.37 95.93,123.37 94.67,124.63 89.93,124.63 89.23,123.93 89.23,122.77 88.18,121.73 88.18,119.46 89.05,118.59 89.05,116.54 89.58,116 v1(89.58,115.11)
  BOTTOM w0.109: v1(99.51,123.83) 99.11,124.23 99.11,125.1 98.47,125.73 98.47,129.4 98.28,129.59 98.28,129.85 97.77,130.36 97.34,130.36 96.45,131.25 96.45,134.11 98.42,136.08 98.42,137.67 99.61,138.86 99.61,141.03 98.73,141.91 98.73,142.76 99.35,143.38 99.35,145.34 98.73,145.96 96.7,145.96 95.55,147.12 R1175.2
ONLINE_TCK: length 177.3
  TOP w0.109: v1(187.93,67.65) 187.39,67.11 186.36,67.11 184.58,68.88 184.58,70.92 179.93,75.57 165.45,75.57 163.11,77.9 v1(163.11,78.16) ; v1(85.14,162.87) 85.14,161.72 87.8,159.06 87.8,150.55 90.85,147.5 94.85,147.5 96.91,145.44 96.91,143.38 97.88,142.42 v1(97.88,141.61)
  SIG3 w0.107: v1(97.88,141.61) 97.88,141.51 98.93,140.46 115.21,140.46 118.23,137.44 119.14,137.44 123.94,132.63 123.94,129.77 124.38,129.34 124.38,127.97 123.94,127.53 123.94,125.28 125.57,123.65 125.57,121.03 125.78,120.83 126.28,120.83 126.47,120.65 126.47,119.23 126.43,119.2 126.43,116.18 126.54,116.08 126.54,115.14 126.38,114.99 126.38,112.7 125.58,111.89 125.58,111.45 124.76,110.63 124.76,110.29 124.25,109.78 124.25,108.94 124.43,108.76 124.43,108.04 124.71,107.77 124.87,107.77 125.14,107.49 125.14,106.6 127.04,104.71 127.04,102.47 128.45,101.06 128.45,95.41 134.16,89.71 134.16,88.47 137.03,85.6 145.39,85.6 149.93,81.05 162.51,81.05 163.62,79.93 163.62,78.66 v1(163.11,78.16)
  BOTTOM w0.109: R1167.2 v1(85.14,162.87) ; U4.B4 v1(187.93,67.65)
ONLINE_TDI: length 178.7
  TOP w0.109: v1(99.1,140.92) 98.97,141.04 98.97,142.71 99.61,143.35 99.61,144.32 95.3,148.64 91.23,148.64 89.58,150.29 89.58,159.31 88.18,160.71 v1(88.18,162.87) ; v1(191.74,67.65) 191.14,68.25 185.97,68.25 185.09,69.14 185.09,71.04 180.06,76.07 166.09,76.07 v1(164,78.16)
  SIG3 w0.107: v1(99.1,140.92) 99.22,140.8 115.33,140.8 118.31,137.82 119.1,137.82 119.1,137.82 119.17,137.82 124.21,132.77 124.21,130.08 124.83,129.46 124.83,127 124.63,126.8 124.63,125.02 126.54,123.11 126.54,121.06 126.74,120.86 126.74,118.98 127.38,118.34 127.38,114.55 126.66,113.83 126.66,111.3 126.4,111.05 125.62,111.05 125.14,110.57 125.14,110.03 124.69,109.58 124.69,109.09 125.4,108.38 125.4,107.72 126.28,106.83 126.28,105.97 127.37,104.88 127.37,102.52 128.73,101.17 128.73,95.53 134.54,89.71 134.54,88.67 137.28,85.93 145.56,85.93 150.16,81.33 162.63,81.33 164,79.96 v1(164,78.16)
  BOTTOM w0.109: U4.D4 v1(191.74,67.65) ; R1170.2 v1(88.18,162.87)
ONLINE_TDO: length 182.6
  TOP w0.109: v1(187.93,75.27) 187.45,75.74 182.93,75.74 181.05,77.62 167.08,77.62 v1(166.54,78.16) ; v1(86.15,162.87) 86.15,161.15 88.12,159.19 88.12,150.74 90.98,147.88 94.92,147.88 97.21,145.58 97.21,143.5 98.32,142.4 98.32,141.31 98.23,141.22 98.23,140.69 99.55,139.37 99.55,135.88 v1(99.36,135.69)
  SIG3 w0.107: v1(166.54,78.16) 164.54,76.15 148.23,76.15 147.11,77.27 146.66,77.27 145.84,78.08 145.84,79.68 143.23,82.3 129.1,82.3 122.83,88.57 122.83,90.69 123.2,91.06 123.57,91.06 124.27,91.76 124.27,92.99 122.3,94.95 122.3,98.33 119.81,100.82 119.81,111.06 120.3,111.56 120.3,112.94 120.77,113.4 121.53,113.4 122.02,113.89 122.02,120.14 120.79,121.37 120.79,126.75 121.43,127.39 121.43,132.16 119.23,134.36 118.67,134.36 117.71,135.33 116.24,135.33 115.48,136.09 113.7,136.09 113.17,136.62 105.5,136.62 104.99,136.11 99.79,136.11 v1(99.36,135.69)
  BOTTOM w0.109: U4.B10 v1(187.93,75.27) ; R1168.2 v1(86.15,162.87)
ONLINE_TMS: length 185.4
  TOP w0.109: v1(100.25,135.66) 99.87,136.04 99.87,139.5 98.57,140.79 98.57,141.06 98.66,141.15 98.66,142.83 99.32,143.49 99.32,144.11 95.17,148.26 91.11,148.26 88.43,150.93 88.43,159.32 87.17,160.58 v1(87.17,162.87) ; v1(167.43,78.16) 181.15,78.16 183.18,76.12 186.45,76.12 186.48,76.09 188.36,76.09 188.51,76.25 188.51,78.49 v1(187.93,79.08)
  SIG3 w0.107: v1(100.25,135.66) 100.38,135.79 105.18,135.79 105.74,136.35 113.05,136.35 113.58,135.81 115.36,135.81 116.12,135.05 117.6,135.05 118.56,134.09 119.11,134.09 120.52,132.68 120.52,121.25 121.71,120.05 121.71,114.1 121.33,113.71 120.67,113.71 119.99,113.04 119.99,111.74 119.43,111.18 119.43,99.1 118.92,98.59 118.92,97.21 122.71,93.41 122.71,92.87 121.64,91.8 121.64,89.36 128.98,82.02 143,82.02 145.46,79.55 145.46,78.03 146.22,77.27 146.22,76.51 146.86,75.87 165.15,75.87 v1(167.43,78.16)
  BOTTOM w0.109: R1169.2 v1(87.17,162.87) ; U4.B13 v1(187.93,79.08)
OSC_50M: length 7.3
  TOP w0.109: U1.1 150.71,102.32 X36.1 148.64,101.52 148.99,101.88 C17.1 R57.2
P0_PU: length 17.9
  TOP w0.109: U43.U72 101.3,65.2 v2(101.52,65.2) 101.81,64.91 U43.R72
  BOTTOM w0.109: R796.2 109.52,55.93 109.01,56.44 109.01,61.27 107.74,62.54 106.09,62.54 105.58,63.04 105.58,64.57 104.57,65.58 101.9,65.58 v2(101.52,65.2)
P1_PU: length 16.2
  TOP w0.109: v2(102.49,65.2) 102.49,65.21 U43.P71 102.31,65.58 101.69,65.58 U43.T71
  BOTTOM w0.109: v2(102.49,65.2) 104.31,65.2 104.69,64.82 104.69,63.3 105.84,62.15 107.36,62.15 108,61.52 108,60.63 108.5,60.12 R797.2
PAR: length 10.7
  TOP w0.109: U21.T3 v2(147.82,142.64)
  BOTTOM w0.109: R373.1 144.55,149.56 144.7,149.4 144.7,147.37 144.6,147.27 R372.2 144.19,146.74 144.45,146.48 145.39,146.48 146.4,145.47 146.4,143.51 147.27,142.64 v2(147.82,142.64)
PCH_WAKE_N: length 38.1
  TOP w0.109: R83.2 88.44,124.56 v1(88.74,124.26) ; U43.BA1 89.94,98.07 89.94,99.14 90.17,99.37 90.17,101.68 93.14,104.65 93.14,106.99 92.76,107.37 92.38,107.37 91.99,107.75 R871.2 92.38,108.28 92.5,108.4 92.5,110.46 92.91,110.87 92.91,113.56 92.63,113.84 92.63,114.48 92.88,114.73 93.43,114.73 93.76,115.06 93.76,117.01 94.74,117.98 94.74,120.52 95.63,121.41 95.63,123.01 v1(95.12,123.52)
  SIG1 w0.086: v1(88.74,124.26) 89.81,124.26 90.38,123.69 92.48,123.69 92.82,124.03 93.49,124.03 94,123.52 v1(95.12,123.52)
PCHHOT_CPU_N: length 144.2
  TOP w0.089: U43.AL76 94.94,62.97 94.94,62.49 95.3,62.13 95.3,60.62 95.47,60.45 95.47,59.56
  TOP w0.109: v2(95.8,59.11) 95.8,59.23 95.47,59.56
  SIG3 w0.107: v2(95.8,59.11) 95.8,58.85 97.84,56.82 97.84,55.8 98.34,55.3 111.98,55.3 112.75,56.06 116,56.06 118.41,58.47 123.24,58.47 124.27,59.5 124.27,60 132.25,67.99 132.25,68.76 135.48,71.98 135.48,76.94 136.29,77.74 136.29,78.7 136.19,78.8 136.19,78.8 135.73,79.26 127.98,79.26 118.95,88.29 118.95,90.47 117.68,91.74 117.68,92.45 114.22,95.91 114.22,100.89 114.91,101.57 114.91,109.98 110.59,114.3 110.59,118.72 115.56,123.7 115.56,126.47 115.24,126.8 v1(115.24,127.38)
  BOTTOM w0.109: R1043.1 115.36,141.53 116,140.89 116,140.26 117.01,139.24 117.01,131.88 115.57,130.43 115.57,127.71 v1(115.24,127.38)
PCHHOT_CPU_N_CPLD: length 29.2
  TOP w0.109: U2.N15 v1(88.71,133.23)
  SIG1 w0.086: v1(88.71,133.23) 90.35,134.87 98.17,134.87 98.49,135.19 104.08,135.19 106.22,137.34 108.12,137.34 109.01,138.23 v1(109.52,138.23)
  BOTTOM w0.109: v1(109.52,138.23) 108.76,138.23 108.44,138.55 108.44,138.83 106.43,140.84 U47.5
PCHHOT_CPU_N_GTL: length 3.6
  BOTTOM w0.109: R1043.2 R1034.1 112.82,140.51 112.5,140.84 U47.12
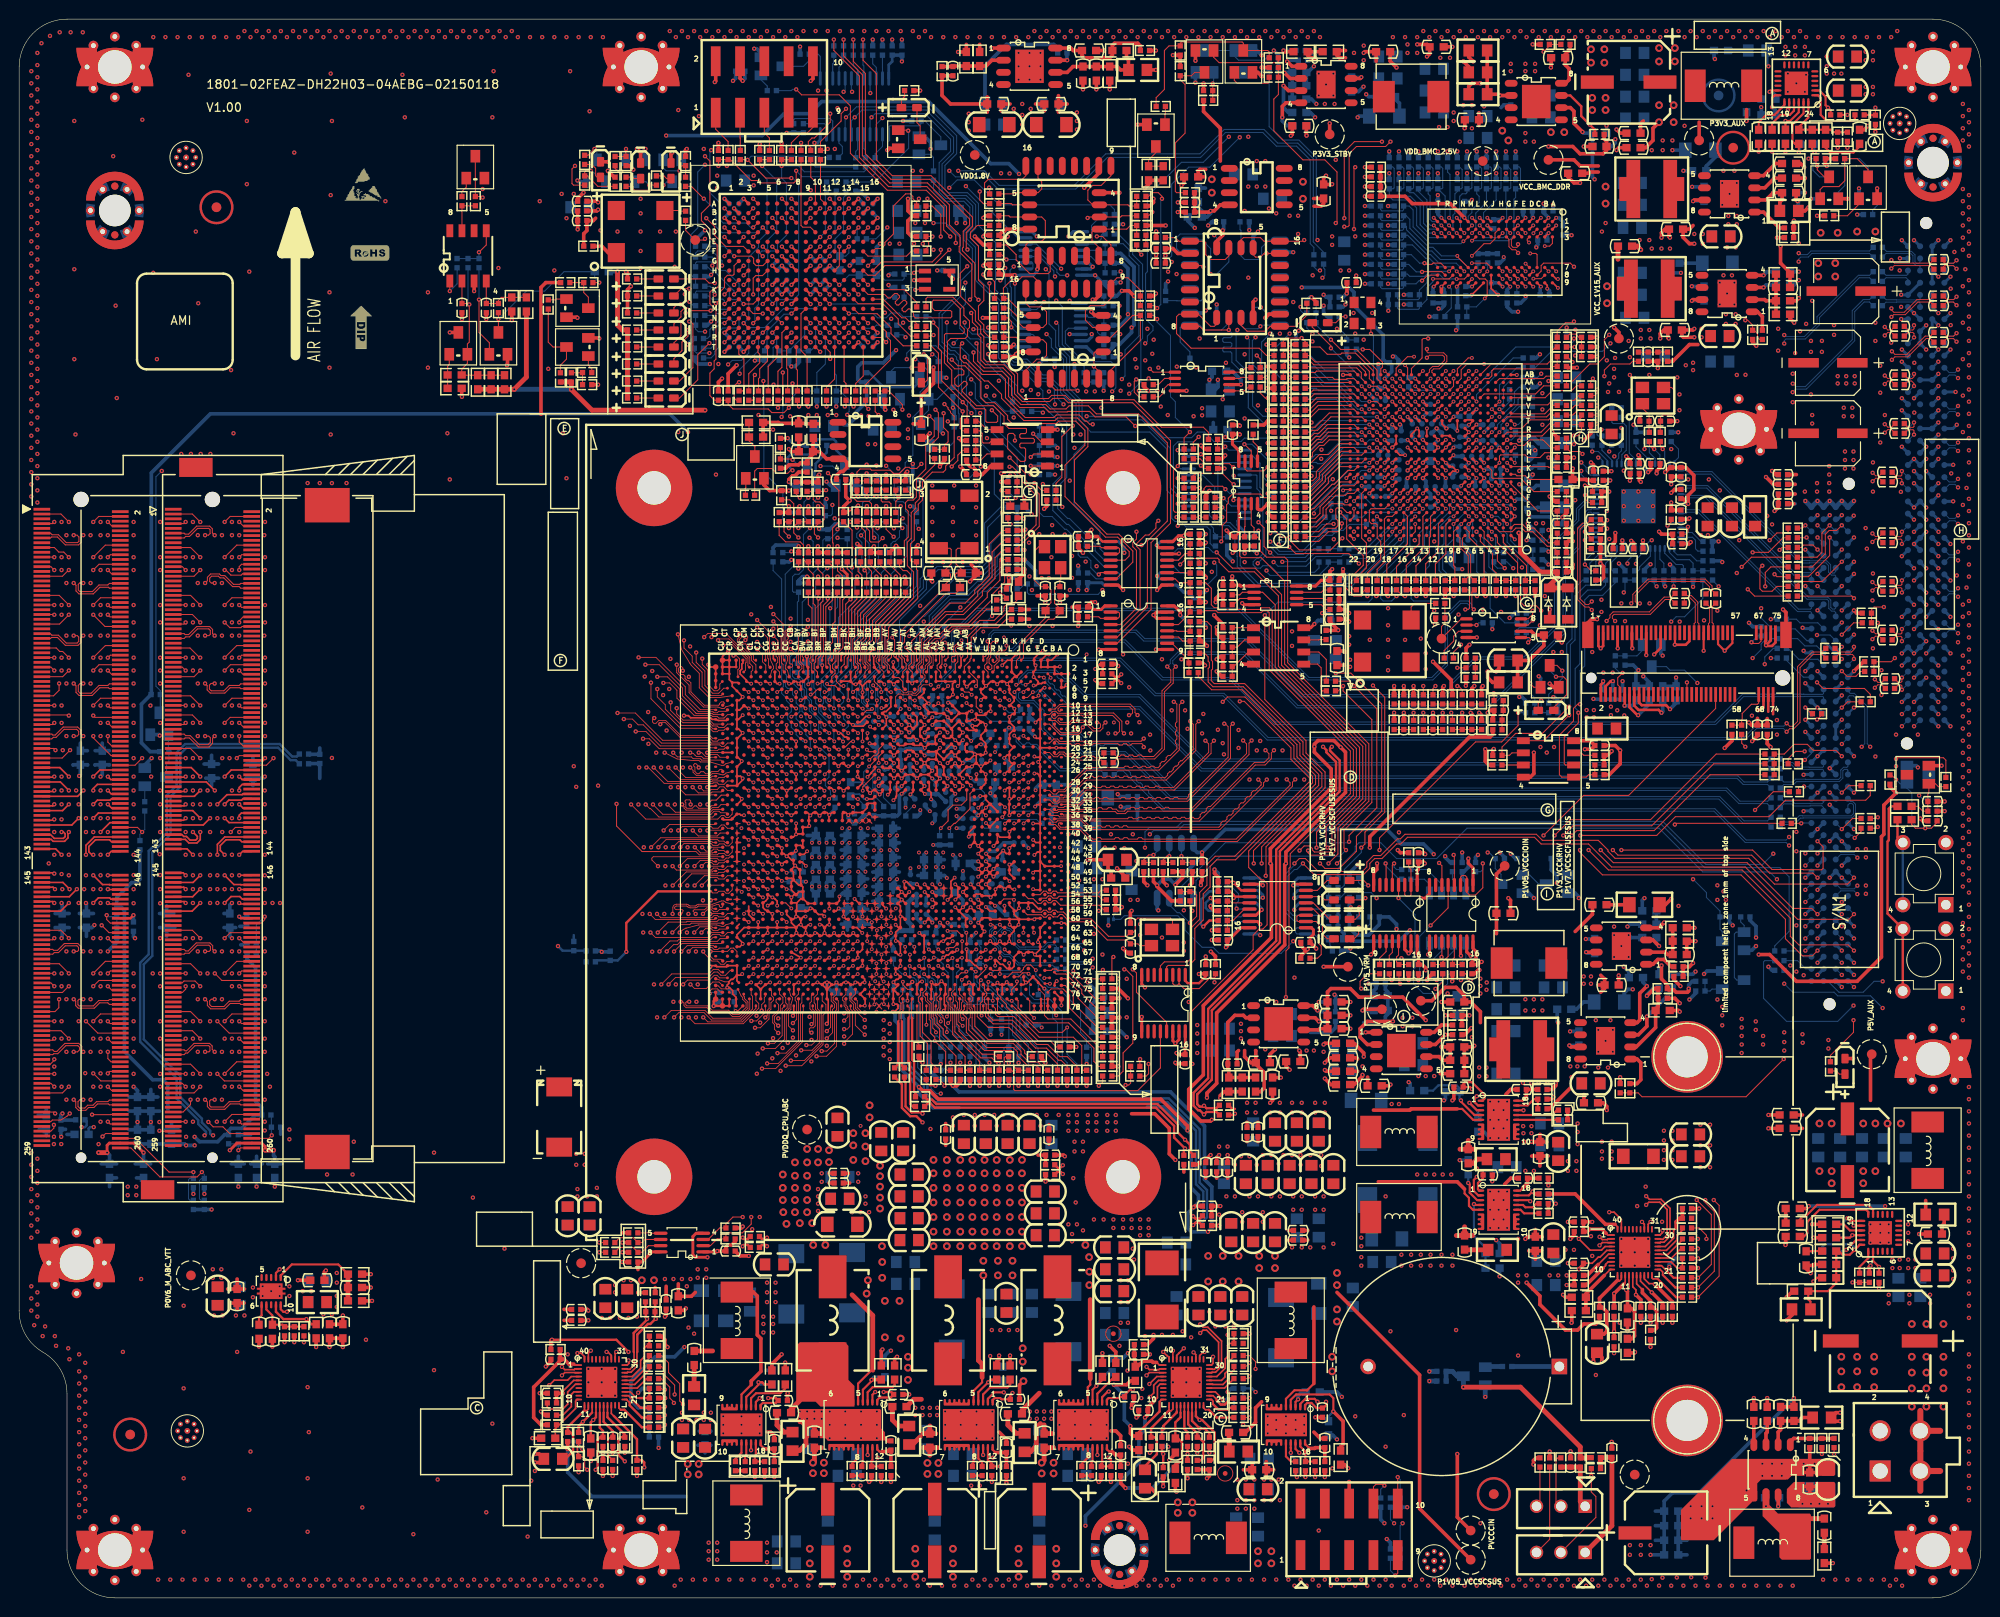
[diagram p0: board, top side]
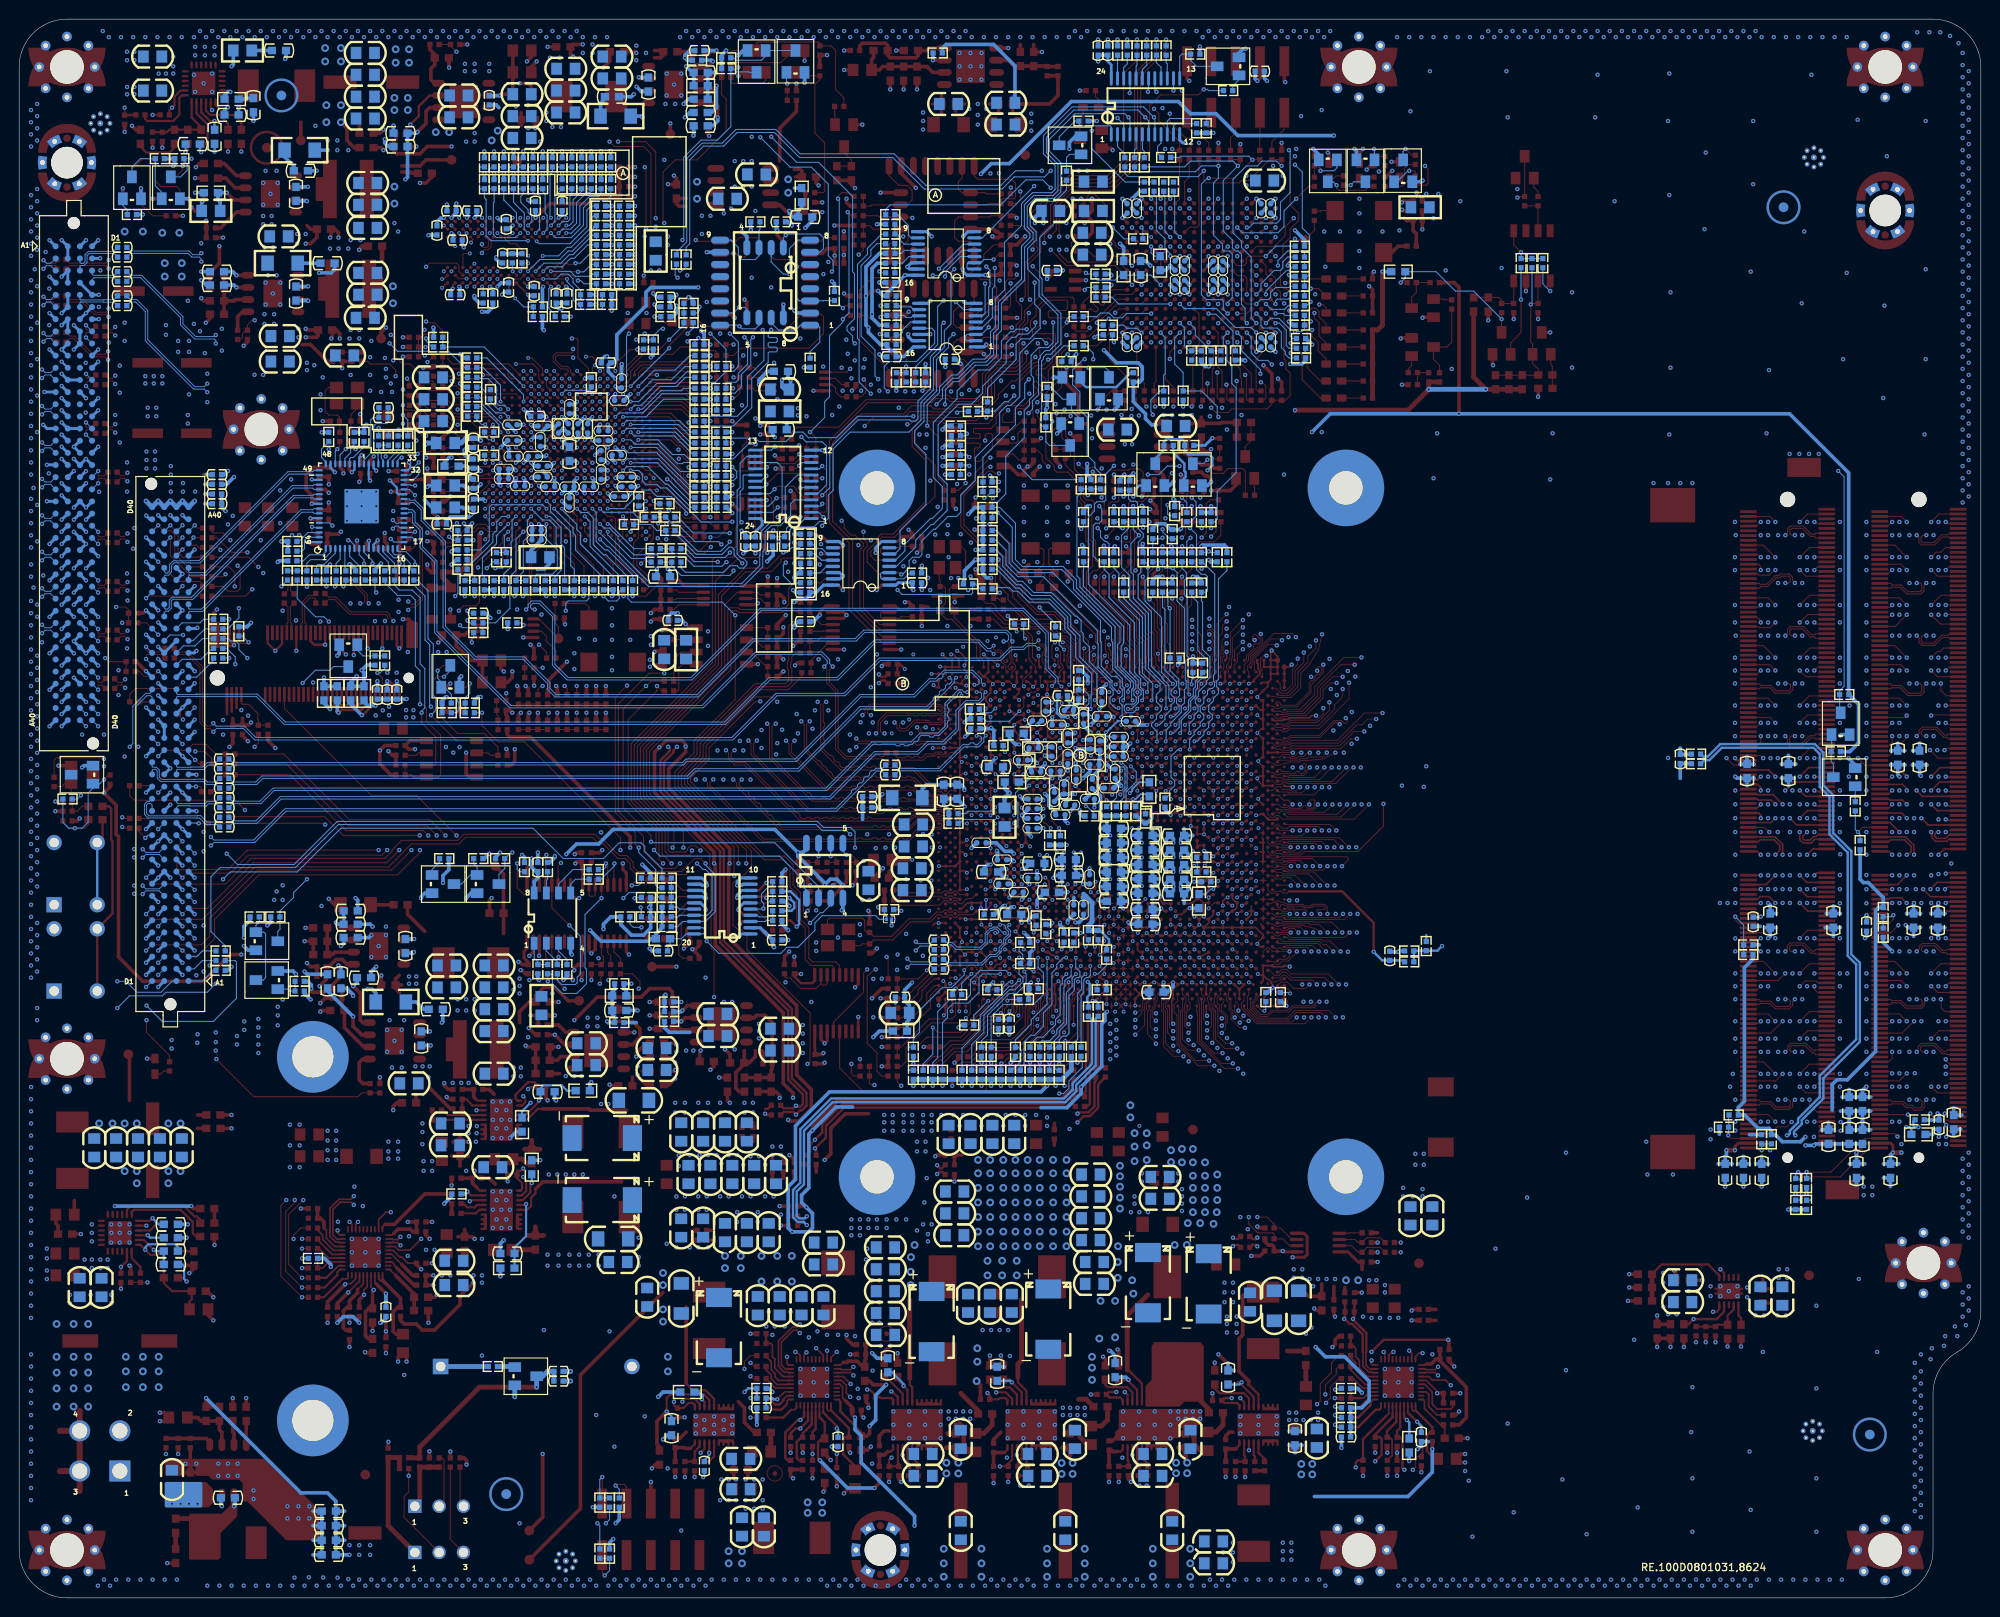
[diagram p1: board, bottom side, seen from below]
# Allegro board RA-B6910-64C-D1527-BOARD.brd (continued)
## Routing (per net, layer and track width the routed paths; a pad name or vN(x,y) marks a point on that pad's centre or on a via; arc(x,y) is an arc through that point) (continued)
PCIE_RX_N0: length 98.2
  TOP w0.099: v1(111.16,90.98) 110.99,90.81 110.99,90.51 110.7,90.22 108.78,90.22 107.68,91.32 U43.D15
  SIG1 w0.094: v1(111.16,90.98) 110.84,90.67 110.84,88.01 112.01,86.84 112.01,86.84 112.62,86.23 113.71,85.14 115.87,85.14 119.81,81.2 122.86,81.2 126.16,77.9 130.6,77.9 132.38,76.12 177.08,76.12 187.34,65.87 190.38,65.87 190.47,65.96 v1(190.47,66.38)
  BOTTOM w0.099: U4.C3 v1(190.47,66.38)
PCIE_RX_N1: length 93.9
  TOP w0.099: v1(113.52,91.49) 113.25,91.23 113.25,90.9 112.96,90.6 112.23,90.6 111.35,91.49 110.3,91.49 110.27,91.52 110.05,91.52 109.81,91.27 108.73,91.27 108.3,91.69 107.8,91.69 U43.C14
  SIG1 w0.094: v1(113.52,91.49) 113.2,91.17 113.2,86.92 113.71,86.41 116.25,86.41 120.44,82.22 123.36,82.22 126.16,79.43 137.71,79.43 138.22,79.93 142.29,79.93 143.05,79.17 157.15,79.17 159.05,77.27 177.47,77.27 184.96,69.77 186.25,69.77 v1(186.66,70.19)
  BOTTOM w0.099: U4.A6 v1(186.66,70.19)
PCIE_RX_N2: length 96.8
  TOP w0.099: U43.D13 107.68,92.31 108.02,92.65 108.33,92.65 108.53,92.45 112.12,92.45 112.14,92.48 114.37,92.48 115.24,91.62 115.24,90.57 v1(115.46,90.35)
  SIG1 w0.094: v1(190.47,70.19) 190.47,69.77 190.34,69.65 189.66,69.65 188.31,70.99 185.26,70.99 176.2,80.06 172.64,80.06 171.75,80.95 137.71,80.95 137.08,80.32 126.54,80.32 123.62,83.24 120.82,83.24 115.14,88.92 115.14,90.03 v1(115.46,90.35)
  BOTTOM w0.099: U4.C6 v1(190.47,70.19)
PCIE_RX_N3: length 91.8
  TOP w0.099: U43.C12 107.77,92.89 108.25,92.89 108.74,93.38 108.97,93.38 109,93.41 116.11,93.41 116.61,92.91 116.61,92.53 v1(116.87,92.26)
  SIG1 w0.094: v1(116.87,92.26) 116.55,91.94 116.55,91.42 116.89,91.09 116.89,88.55 117.75,87.68 118.77,87.68 122.07,84.38 123.8,84.38 126.84,81.33 136.32,81.33 137.08,82.09 175.69,82.09 184.2,73.58 186.25,73.58 v1(186.66,74)
  BOTTOM w0.099: U4.A9 v1(186.66,74)
PCIE_RX_P0: length 98.2
  TOP w0.099: v1(110.27,90.98) 110.61,90.98 110.79,90.81 110.79,90.6 110.61,90.42 108.86,90.42 108.18,91.11 U43.B15
  SIG1 w0.094: v1(110.27,90.98) 110.59,90.67 110.59,90.38 110.43,90.23 110.43,89.94 110.59,89.79 110.59,89.5 110.43,89.35 110.43,89.07 110.59,88.91 110.59,87.91 110.79,87.71 110.79,87.48 110.99,87.28 111.21,87.28 111.41,87.09 111.41,86.86 111.61,86.66 111.83,86.66 113.61,84.89 115.77,84.89 119.7,80.95 122.75,80.95 126.05,77.65 130.5,77.65 132.28,75.87 176.98,75.87 187.23,65.62 190.38,65.62 190.47,65.52 v1(190.47,65.11)
  BOTTOM w0.099: U4.C2 v1(190.47,65.11)
PCIE_RX_P1: length 93.8
  TOP w0.099: U43.A14 108.78,91.95 108.67,91.95 108.57,91.85 108.57,91.71 108.81,91.47 109.72,91.47 109.97,91.72 110.27,91.72 110.3,91.74 111.45,91.74 112.34,90.86 112.85,90.86 113,91.01 113,91.31 112.82,91.49 v1(112.63,91.49)
  SIG1 w0.094: v1(112.63,91.49) 112.95,91.17 112.95,86.81 113.61,86.16 116.15,86.16 120.34,81.97 123.26,81.97 126.05,79.17 137.82,79.17 138.33,79.68 142.18,79.68 142.94,78.92 157.04,78.92 158.95,77.01 177.36,77.01 184.85,69.52 186.36,69.52 186.66,69.22 v1(186.66,68.92)
  BOTTOM w0.099: U4.A5 v1(186.66,68.92)
PCIE_RX_P2: length 96.7
  TOP w0.099: v1(114.57,90.35) 114.78,90.35 114.98,90.55 114.98,91.51 114.27,92.23 112.14,92.23 112.12,92.25 111.55,92.25 111.48,92.18 111.12,92.18 111.04,92.25 110.69,92.25 110.61,92.18 110.26,92.18 110.18,92.25 109.83,92.25 109.75,92.18 109.39,92.18 109.32,92.25 108.61,92.25 108.25,91.9 108.1,91.9 107.9,92.1 107.9,92.24 107.97,92.31 U43.B13
  SIG1 w0.094: v1(190.47,68.92) 190.47,69.09 190.17,69.39 189.55,69.39 188.21,70.74 185.16,70.74 176.09,79.81 172.53,79.81 171.65,80.7 137.82,80.7 137.19,80.06 126.43,80.06 123.51,82.98 120.72,82.98 114.89,88.81 114.89,90.03 v1(114.57,90.35)
  BOTTOM w0.099: U4.C5 v1(190.47,68.92)
PCIE_RX_P3: length 91.8
  TOP w0.099: U43.A12 108.78,92.67 108.67,92.67 108.56,92.78 108.56,92.92 108.83,93.18 108.97,93.18 109,93.15 109.03,93.15 109.04,93.17 109.18,93.17 109.2,93.15 116.01,93.15 116.35,92.81 116.35,92.48 116.13,92.26 v1(115.98,92.26)
  SIG1 w0.094: v1(186.66,72.73) 186.66,73.03 186.36,73.33 184.09,73.33 175.58,81.84 137.19,81.84 136.42,81.08 126.74,81.08 123.69,84.13 121.97,84.13 118.66,87.43 117.65,87.43 116.63,88.44 116.63,90.98 116.3,91.32 116.3,91.94 v1(115.98,92.26)
  BOTTOM w0.099: U4.A8 v1(186.66,72.73)
PCIE_TX_N0: length 5.2
  BOTTOM w0.099: C570.2 184.43,83.24 185.34,83.24 185.56,83.02 187.14,83.02 187.16,83 188.4,83 188.56,83.16 U4.B16
PCIE_TX_N1: length 10.5
  BOTTOM w0.099: U4.D16 191.38,83.25 191.6,83.25 191.9,82.94 191.9,81.88 191.54,81.52 186.44,81.52 186.42,81.5 186.14,81.5 185.47,80.83 184.44,80.83 184.3,80.83 C572.2
PCIE_TX_N2: length 5.3
  BOTTOM w0.099: U4.B19 188.56,86.91 188.46,86.81 187.06,86.81 187.04,86.83 185.81,86.83 185.34,87.3 184.43,87.3 C574.2
PCIE_TX_N3: length 8.8
  BOTTOM w0.099: U4.D19 191.1,86.91 191,86.81 190.64,86.81 190.36,86.53 190.36,85.76 190.14,85.54 186.69,85.54 186.67,85.56 185.63,85.56 185.34,85.27 184.42,85.27 184.32,85.37 184.32,85.37 C576.2
PCIE_TX_P0: length 5.2
  BOTTOM w0.099: U4.B15 188.56,82.6 188.38,82.79 187.16,82.79 187.14,82.77 185.45,82.77 185.23,82.98 184.43,82.98 C571.2
PCIE_TX_P1: length 10.5
  BOTTOM w0.099: C573.2 184.55,81.08 185.37,81.08 186.04,81.75 186.38,81.75 186.35,81.73 191.45,81.73 191.69,81.97 191.69,82.86 191.51,83.03 191.28,83.03 191.1,82.86 U4.D15
PCIE_TX_P2: length 5.4
  BOTTOM w0.099: C575.2 184.43,87.05 185.23,87.05 185.71,86.58 187.04,86.58 187.06,86.6 188.46,86.6 188.56,86.49 U4.B18
PCIE_TX_P3: length 8.8
  BOTTOM w0.099: C577.2 184.43,85.01 185.45,85.01 185.74,85.31 186.67,85.31 186.69,85.33 190.22,85.33 190.57,85.67 190.57,86.44 190.73,86.6 191,86.6 191.1,86.5 U4.D18
PD_SPARE_1: length 1.5
  TOP w0.109: U43.AJ67 95.35,67.49 v2(95.06,67.77)
  BOTTOM w0.109: v2(95.06,67.77) 94.79,68.05 R952.1
PD_SPARE_2: length 1.5
  TOP w0.109: v2(96.05,67.77) 96.34,67.49 U43.AG67
  BOTTOM w0.109: R951.1 95.8,68.02 v2(96.05,67.77)
PD_SPARE_3: length 4.4
  TOP w0.109: U43.AN78 93.82,58.04 94.03,57.84 R946.1
PD_SPARE_4: length 2.5
  TOP w0.109: v2(97.02,69.71) 98.02,69.71 U43.AC64
  BOTTOM w0.109: R950.1 97.32,69.42 v2(97.02,69.71)
PE1_RX_N0: length 125.1
  TOP w0.099: U43.J24 104.76,87.23 v2(104.47,86.94)
  SIG4 w0.094: v1(202.61,127.49) 202.29,127.81 202.1,127.81 201.98,127.69 201.98,126.92 200.96,125.91 199.56,125.91 198.29,124.64 194.61,124.64 191.31,121.34 189.02,121.34 179.12,111.43 179.12,110.82 173.66,105.36 173.66,104.21 169.72,100.28 169.72,99.01 168.7,97.99 168.7,91.87 167.05,90.22 162.99,90.22 160.07,87.3 117.42,87.3 115.77,88.95 111.53,88.95 109.37,86.79 106.98,86.79 106.73,86.54 104.88,86.54 v2(104.47,86.94)
  BOTTOM w0.099: v1(202.61,127.49) 202.29,127.81 201.71,127.81 U60.A12
PE1_RX_N1: length 120.7
  TOP w0.099: U43.K26 104.26,86.37 v2(103.98,86.09)
  SIG4 w0.094: v2(103.98,86.09) 104.42,85.65 105.71,85.65 105.84,85.52 106.71,85.52 106.96,85.78 109.9,85.78 111.81,87.68 115.77,87.68 117.29,86.16 167.03,86.16 180.01,99.13 180.01,100.02 195.37,115.39 195.37,117.29 200.18,122.1 201.09,122.1 201.98,122.99 201.98,123.87 202.1,124 202.29,124 v1(202.61,123.68)
  BOTTOM w0.099: v1(202.61,123.68) 202.29,124 201.71,124 U60.A15
PE1_RX_N2: length 117.1
  TOP w0.099: v2(104.47,85.23) 104.76,85.51 U43.J28
  SIG4 w0.094: v2(104.47,85.23) 104.86,84.84 127.5,84.84 127.7,84.63 134.9,84.63 135.41,85.14 167.43,85.14 187.24,104.95 188.77,104.95 191.31,107.49 192.07,107.49 194.74,110.16 194.74,111.71 201.98,118.94 201.98,119.96 202.2,120.19 202.29,120.19 v1(202.61,119.87)
  BOTTOM w0.099: v1(202.61,119.87) 202.29,120.19 201.71,120.19 U60.A18
PE1_RX_N3: length 116.8
  TOP w0.099: v2(103.98,84.37) 104.19,84.37 U43.K30
  SIG4 w0.094: v2(103.98,84.37) 104.41,83.94 105.66,83.94 105.86,83.74 108.78,83.74 109.29,83.24 135.03,83.24 135.92,84.13 168.17,84.13 187.99,103.94 189.89,103.94 195.88,109.93 195.88,111.56 197.53,113.21 199.94,113.21 201.98,115.24 201.98,116.18 202.12,116.33 202.35,116.33 v1(202.61,116.06)
  BOTTOM w0.099: v1(202.61,116.06) 202.29,116.38 201.71,116.38 U60.A21
PE1_RX_N4: length 115.4
  TOP w0.099: U43.J32 104.68,83.51 v2(104.47,83.51)
  SIG4 w0.094: v1(202.61,112.25) 202.32,112.54 202.1,112.54 201.98,112.41 201.98,111.56 201.09,110.67 199.69,110.67 194.86,105.84 194.86,104.45 193.98,103.56 193.21,103.56 192.07,102.41 188.49,102.41 182.52,96.44 181.89,96.44 168.68,83.24 136.57,83.24 135.17,81.84 109.29,81.84 108.02,83.11 104.87,83.11 v2(104.47,83.51)
  BOTTOM w0.099: U60.A24 201.71,112.57 202.29,112.57 v1(202.61,112.25)
PE1_RX_N5: length 115
  TOP w0.099: v2(103.98,82.65) 104.19,82.65 U43.K33
  SIG4 w0.094: v1(202.61,108.44) 202.29,108.76 202.1,108.76 201.98,108.63 201.98,108 200.83,106.86 199.82,106.86 195.37,102.41 193.59,102.41 192.32,101.14 190.02,101.14 186.1,97.23 186.1,95.32 185.19,94.41 181.25,94.41 169.06,82.22 137.31,82.22 135.92,80.82 108.65,80.82 107.51,81.97 105.86,81.97 105.61,82.22 104.41,82.22 v2(103.98,82.65)
  BOTTOM w0.099: v1(202.61,108.44) 202.29,108.76 201.71,108.76 U60.A27
PE1_RX_N6: length 113.3
  TOP w0.099: U43.J35 104.68,81.79 v2(104.47,81.79)
  SIG4 w0.094: v2(104.47,81.79) 104.94,81.33 106.62,81.33 108.91,79.05 136.17,79.05 138.33,81.2 169.44,81.2 181.76,93.52 185.7,93.52 186.46,94.29 188.13,94.29 189.91,96.06 192.2,96.06 195.37,99.24 197.66,99.24 201.98,103.56 201.98,104.82 202.1,104.95 202.29,104.95 v1(202.61,104.63)
  BOTTOM w0.099: U60.A30 201.71,104.95 202.29,104.95 v1(202.61,104.63)
PE1_RX_N7: length 114.5
  TOP w0.099: v2(103.98,80.94) 104.19,80.94 U43.K37
  SIG4 w0.094: v1(202.61,100.82) 202.29,101.14 202.2,101.14 202.1,101.04 202.1,100.38 198.8,97.08 198.8,95.43 197.53,94.16 195.75,94.16 193.85,92.25 182.8,92.25 170.35,79.81 165.25,79.81 164.24,78.79 143.92,78.79 142.39,77.27 124.49,77.27 124.05,76.83 117.83,76.83 117.01,77.65 108.38,77.65 105.96,80.06 104.72,80.06 104.31,80.46 104.31,80.8 104.18,80.94 v2(103.98,80.94)
  BOTTOM w0.099: U60.A33 201.71,101.14 202.29,101.14 v1(202.61,100.82)
PE1_RX_P0: length 125.1
  TOP w0.099: v2(105.46,86.94) 105.75,87.23 U43.F24
  SIG4 w0.094: v1(202.61,128.38) 202.61,128.3 202.38,128.06 201.99,128.06 201.72,127.79 201.72,127.03 200.86,126.16 199.46,126.16 198.19,124.89 194.51,124.89 191.2,121.59 188.92,121.59 178.86,111.54 178.86,110.92 173.4,105.46 173.4,104.32 169.46,100.38 169.46,99.11 168.45,98.1 168.45,91.98 166.95,90.48 162.88,90.48 159.96,87.55 117.52,87.55 115.87,89.21 114.06,89.21 113.91,89.36 113.62,89.36 113.47,89.21 113.18,89.21 113.03,89.36 112.74,89.36 112.59,89.21 112.3,89.21 112.15,89.36 111.87,89.36 111.71,89.21 111.43,89.21 111.13,88.91 110.91,88.91 110.71,88.71 110.71,88.49 110.51,88.29 110.29,88.29 110.09,88.09 110.09,87.87 109.89,87.67 109.67,87.67 109.47,87.47 109.47,87.25 109.27,87.05 108.63,87.05 108.48,87.2 108.19,87.2 108.04,87.05 107.75,87.05 107.6,87.2 107.31,87.2 107.16,87.05 106.88,87.05 106.62,86.79 105.62,86.79 v2(105.46,86.94)
  BOTTOM w0.099: U60.A11 201.69,128.06 202.29,128.06 v1(202.61,128.38)
PE1_RX_P1: length 120.7
  TOP w0.099: U43.H26 105.25,86.37 v2(104.97,86.09)
  SIG4 w0.094: v2(104.97,86.09) 105.15,85.9 105.82,85.9 105.94,85.78 106.6,85.78 106.85,86.03 107.14,86.03 107.29,86.19 107.58,86.19 107.73,86.03 108.01,86.03 108.17,86.19 108.45,86.19 108.61,86.03 108.89,86.03 109.05,86.19 109.33,86.19 109.49,86.03 109.8,86.03 110,86.23 110,86.45 110.2,86.65 110.42,86.65 110.62,86.85 110.62,87.07 110.82,87.27 111.04,87.27 111.7,87.94 111.98,87.94 112.14,88.09 112.42,88.09 112.58,87.94 112.86,87.94 113.02,88.09 113.3,88.09 113.46,87.94 113.74,87.94 113.9,88.09 114.18,88.09 114.34,87.94 115.87,87.94 117.39,86.41 166.92,86.41 179.75,99.24 179.75,100.13 195.12,115.49 195.12,117.4 200.07,122.35 200.98,122.35 201.72,123.09 201.72,123.98 202,124.25 202.4,124.25 202.61,124.46 v1(202.61,124.57)
  BOTTOM w0.099: v1(202.61,124.57) 202.29,124.25 201.69,124.25 U60.A14
PE1_RX_P2: length 117.1
  TOP w0.099: v2(105.46,85.23) 105.75,85.51 U43.F28
  SIG4 w0.094: v2(105.46,85.23) 105.6,85.09 106.81,85.09 106.97,85.25 107.25,85.25 107.41,85.09 107.83,85.09 107.98,85.25 108.26,85.25 108.42,85.09 108.7,85.09 108.86,85.25 109.14,85.25 109.3,85.09 109.58,85.09 109.74,85.25 110.02,85.25 110.18,85.09 110.46,85.09 110.62,85.25 110.9,85.25 111.06,85.09 111.34,85.09 111.5,85.25 111.78,85.25 111.94,85.09 112.22,85.09 112.38,85.25 112.66,85.25 112.82,85.09 113.16,85.09 113.29,85.22 113.57,85.22 113.7,85.09 113.98,85.09 114.1,85.22 114.39,85.22 114.51,85.09 127.61,85.09 127.81,84.89 134.79,84.89 135.3,85.4 167.33,85.4 187.14,105.21 188.66,105.21 191.2,107.75 191.97,107.75 194.48,110.27 194.48,111.81 201.72,119.05 201.72,120.07 202.1,120.44 202.29,120.44 v1(202.61,120.76)
  BOTTOM w0.099: U60.A17 201.68,120.45 202.3,120.45 v1(202.61,120.76)
PE1_RX_P3: length 116.8
  TOP w0.099: U43.H30 105.25,84.66 v2(104.97,84.37)
  SIG4 w0.094: v2(104.97,84.37) 105.2,84.14 105.83,84.14 105.96,84 106.68,84 106.84,84.16 107.12,84.16 107.28,84 107.56,84 107.72,84.16 108,84.16 108.16,84 108.89,84 109.39,83.49 109.68,83.49 109.83,83.65 110.12,83.65 110.27,83.49 110.55,83.49 110.71,83.65 110.99,83.65 111.15,83.49 112.14,83.49 112.3,83.65 112.58,83.65 112.74,83.49 113.02,83.49 113.18,83.65 113.46,83.65 113.62,83.49 113.9,83.49 114.06,83.65 114.34,83.65 114.5,83.49 115.06,83.49 115.22,83.65 115.5,83.65 115.66,83.49 134.92,83.49 135.81,84.38 168.07,84.38 187.88,104.19 189.78,104.19 195.63,110.03 195.63,111.66 197.43,113.46 199.84,113.46 201.72,115.35 201.72,116.28 202.02,116.58 202.3,116.58 202.61,116.89 v1(202.61,116.95)
  BOTTOM w0.099: U60.A20 201.69,116.63 202.29,116.63 v1(202.61,116.95)
PE1_RX_P4: length 115.4
  TOP w0.099: U43.F32 105.75,83.8 v2(105.46,83.51)
  SIG4 w0.094: v2(105.46,83.51) 105.61,83.36 108.12,83.36 109.39,82.09 109.68,82.09 109.83,82.25 110.12,82.25 110.27,82.09 110.55,82.09 110.71,82.25 110.99,82.25 111.15,82.09 111.43,82.09 111.59,82.25 111.87,82.25 112.03,82.09 112.31,82.09 112.47,82.25 112.75,82.25 112.91,82.09 113.19,82.09 113.35,82.25 113.63,82.25 113.79,82.09 114.07,82.09 114.23,82.25 114.51,82.25 114.67,82.09 115.45,82.09 115.6,82.25 115.88,82.25 116.04,82.09 116.32,82.09 116.48,82.25 116.76,82.25 116.92,82.09 135.07,82.09 136.47,83.49 168.58,83.49 181.78,96.7 182.42,96.7 188.39,102.67 191.97,102.67 193.11,103.81 193.87,103.81 194.61,104.55 194.61,105.95 199.59,110.92 200.98,110.92 201.72,111.66 201.72,112.52 202,112.8 202.35,112.8 202.61,113.06 v1(202.61,113.14)
  BOTTOM w0.099: U60.A23 201.69,112.82 202.29,112.82 v1(202.61,113.14)
PE1_RX_P5: length 115
  TOP w0.099: U43.H33 105.25,82.94 v2(104.97,82.65)
  SIG4 w0.094: v1(202.61,109.33) 202.61,109.22 202.4,109.01 202,109.01 201.72,108.74 201.72,108.11 200.73,107.11 199.71,107.11 195.27,102.67 193.49,102.67 192.22,101.4 189.91,101.4 185.85,97.33 185.85,95.43 185.09,94.67 181.15,94.67 168.96,82.47 137.21,82.47 135.81,81.08 115.97,81.08 115.81,81.23 115.53,81.23 115.37,81.08 115.09,81.08 114.94,81.23 114.65,81.23 114.5,81.08 114.21,81.08 114.06,81.23 113.77,81.23 113.62,81.08 113.33,81.08 113.18,81.23 112.9,81.23 112.74,81.08 112.46,81.08 112.3,81.23 112.02,81.23 111.86,81.08 111.58,81.08 111.42,81.23 111.14,81.23 110.98,81.08 110.7,81.08 110.54,81.23 110.26,81.23 110.1,81.08 109.82,81.08 109.66,81.23 109.38,81.23 109.22,81.08 108.76,81.08 107.62,82.22 105.96,82.22 105.71,82.47 105.15,82.47 v2(104.97,82.65)
  BOTTOM w0.099: U60.A26 201.69,109.01 202.29,109.01 v1(202.61,109.33)
PE1_RX_P6: length 113.3
  TOP w0.099: U43.F35 105.75,82.08 v2(105.46,81.79)
  SIG4 w0.094: v2(105.46,81.79) 105.67,81.59 106.73,81.59 109.01,79.3 110.75,79.3 110.9,79.46 111.19,79.46 111.34,79.3 111.63,79.3 111.78,79.46 112.06,79.46 112.22,79.3 112.5,79.3 112.66,79.46 112.94,79.46 113.1,79.3 113.38,79.3 113.54,79.46 113.82,79.46 113.98,79.3 114.26,79.3 114.42,79.46 114.7,79.46 114.86,79.3 115.14,79.3 115.3,79.46 115.58,79.46 115.74,79.3 116.72,79.3 116.87,79.46 117.15,79.46 117.31,79.3 118.37,79.3 118.52,79.46 118.81,79.46 118.96,79.3 136.06,79.3 138.22,81.46 169.34,81.46 181.66,93.78 185.59,93.78 186.36,94.54 188.03,94.54 189.81,96.32 192.09,96.32 195.27,99.49 197.55,99.49 201.72,103.66 201.72,104.93 202,105.2 202.4,105.2 202.61,105.41 v1(202.61,105.52)
  BOTTOM w0.099: v1(202.61,105.52) 202.29,105.2 201.69,105.2 U60.A29
PE1_RX_P7: length 114.5
  TOP w0.099: v2(104.97,80.94) 105.25,81.22 U43.H37
  SIG4 w0.094: v2(104.97,80.94) 104.72,80.94 104.57,80.78 104.57,80.57 104.82,80.32 106.07,80.32 106.27,80.12 106.49,80.12 106.69,79.92 106.69,79.69 106.89,79.49 107.11,79.49 107.31,79.29 107.31,79.07 107.51,78.87 107.74,78.87 107.94,78.67 107.94,78.45 108.48,77.9 117.12,77.9 117.93,77.09 123.95,77.09 124.38,77.52 142.29,77.52 143.81,79.05 164.13,79.05 165.15,80.06 170.25,80.06 182.69,92.51 193.74,92.51 195.65,94.41 197.43,94.41 198.55,95.53 198.55,97.18 201.85,100.49 201.85,101.15 202.1,101.39 202.29,101.39 v1(202.61,101.71)
  BOTTOM w0.099: v1(202.61,101.71) 202.29,101.39 201.69,101.39 U60.A32
PE1_TX_N0: length 2.5
  TOP w0.099: C713.2 197.38,132.26 197.89,132.26 198.01,132.13 v1(198.01,131.73)
  BOTTOM w0.099: U60.D9 v1(198.01,131.73)
PE1_TX_N1: length 2.4
  TOP w0.099: v1(198.01,126.65) 198.01,126.93 197.76,127.18 197.38,127.18 C715.2
  BOTTOM w0.099: U60.D13 v1(198.01,126.65)
PE1_TX_N2: length 2.5
  TOP w0.099: v1(198.01,121.57) 198.01,121.98 197.91,122.08 197.36,122.08 C717.2
  BOTTOM w0.099: U60.D17 v1(198.01,121.57)
PE1_TX_N3: length 2.5
  TOP w0.099: v1(196.74,116.49) 196.74,116.9 196.64,117 196.09,117 C719.2
  BOTTOM w0.099: U60.D21 v1(196.74,116.49)
PE1_TX_N4: length 2.5
  TOP w0.099: v1(196.75,110.15) 196.75,110.55 196.64,110.65 196.09,110.65 C721.2
  BOTTOM w0.099: U60.D25 197.38,110.78 v1(196.75,110.15)
PE1_TX_N5: length 2.5
  TOP w0.099: v1(196.75,105.07) 196.75,105.47 196.64,105.57 196.09,105.57 C723.2
  BOTTOM w0.099: U60.D29 197.38,105.7 v1(196.75,105.07)
PE1_TX_N6: length 2.5
  TOP w0.099: v1(196.75,99.99) 196.75,100.39 196.64,100.49 196.09,100.49 C725.2
  BOTTOM w0.099: U60.D33 197.38,100.62 v1(196.75,99.99)
PE1_TX_N7: length 2.3
  TOP w0.099: C727.2 196.35,95.41 196.64,95.41 196.75,95.31 v1(196.75,94.91)
  BOTTOM w0.099: v1(196.75,94.91) 197.38,95.54 U60.D37
PE1_TX_P0: length 2.5
  TOP w0.099: C714.2 197.38,132.51 197.89,132.51 198.01,132.64 v1(198.01,133)
  BOTTOM w0.099: U60.D8 v1(198.01,133)
PE1_TX_P1: length 2.4
  TOP w0.099: v1(198.01,127.92) 198.01,127.63 197.81,127.43 197.38,127.43 C716.2
  BOTTOM w0.099: U60.D12 v1(198.01,127.92)
PE1_TX_P2: length 2.5
  TOP w0.099: C718.2 197.39,122.34 197.91,122.34 198.01,122.44 v1(198.01,122.84)
  BOTTOM w0.099: U60.D16 v1(198.01,122.84)
PE1_TX_P3: length 2.5
  TOP w0.099: C720.2 196.12,117.26 196.64,117.26 196.74,117.36 v1(196.74,117.76)
  BOTTOM w0.099: U60.D20 v1(196.74,117.76)
PE1_TX_P4: length 2.5
  TOP w0.099: C722.2 196.12,110.91 196.64,110.91 196.75,111.01 v1(196.75,111.42)
  BOTTOM w0.099: U60.D24 197.38,112.05 v1(196.75,111.42)
PE1_TX_P5: length 2.5
  TOP w0.099: v1(196.75,106.34) 196.75,105.93 196.64,105.83 196.12,105.83 C724.2
  BOTTOM w0.099: v1(196.75,106.34) 197.38,106.97 U60.D28
PE1_TX_P6: length 2.5
  TOP w0.099: C726.2 196.12,100.75 196.64,100.75 196.75,100.85 v1(196.75,101.26)
  BOTTOM w0.099: v1(196.75,101.26) 197.38,101.89 U60.D32
PE1_TX_P7: length 2.3
  TOP w0.099: v1(196.75,96.18) 196.75,95.79 196.63,95.67 196.38,95.67 C728.2
  BOTTOM w0.099: v1(196.75,96.18) 197.38,96.81 U60.D36
PE2_RX_N0: length 87.3
  TOP w0.099: C263.2 163.9,112.07 163.47,112.07 163.11,111.71 163.11,104.42 163.73,103.81 164.01,103.81 v1(164.34,104.14) ; v2(103.98,87.81) 104.19,87.81 U43.K22
  SIG1 w0.094: v2(103.98,87.81) 104.28,87.81 104.49,88.02 104.49,88.29 104.24,88.54 104.02,88.54 103.82,88.74 103.82,88.96 102.15,90.62 102.15,92.66 101.39,93.42 101.39,95.03 101.52,95.15 101.52,95.79 102.43,96.7 103.95,96.7 105.48,98.22 109.67,98.22 111.7,100.25 134.79,100.25 138.65,104.11 161.54,104.11 161.83,103.82 164.02,103.82 v1(164.34,104.14)
PE2_RX_P0: length 87.3
  TOP w0.099: C264.2 163.9,112.32 163.37,112.32 162.86,111.81 162.86,104.32 163.62,103.56 164.04,103.56 v1(164.34,103.25) ; U43.H22 105.23,88.09 v2(104.95,87.81)
  SIG1 w0.094: v2(104.95,87.81) 104.75,88.01 104.75,88.39 102.41,90.73 102.41,92.76 101.65,93.52 101.65,94.92 101.77,95.05 101.77,95.68 102.54,96.44 104.06,96.44 105.58,97.97 109.77,97.97 111.81,100 134.9,100 138.76,103.86 161.43,103.86 161.73,103.57 164.02,103.57 v1(164.34,103.25)
PE2_TX_N0: length 77.1
  TOP w0.099: C568.1 114.7,87.68 118.66,87.68 119.68,88.7 119.68,94.69 120.6,95.61 120.6,97.07 v1(120.87,97.33)
  BOTTOM w0.099: v1(120.87,97.33) 120.55,97.65 120.55,97.95 121.2,98.6 127.94,98.6 133.52,93.02 153.72,93.02 161.59,100.89 161.59,108.26 163.11,109.78 163.11,111.58 163.88,112.34 163.88,113.33 164.02,113.47 164.26,113.47 164.38,113.35 U26.23
PE2_TX_P0: length 77.5
  TOP w0.099: v1(119.98,97.33) 120.35,96.96 120.35,95.71 119.43,94.79 119.43,88.8 118.56,87.94 117.4,87.94 117.25,88.09 116.95,88.09 116.8,87.94 116.5,87.94 116.35,88.09 116.05,88.09 115.9,87.94 115.6,87.94 115.45,88.09 115.15,88.09 115,87.94 114.7,87.94 C569.1
  BOTTOM w0.099: U26.24 164.38,113.85 164.26,113.72 163.91,113.72 163.62,113.44 163.62,112.45 162.86,111.68 162.86,109.88 161.34,108.36 161.34,100.99 153.61,93.27 133.63,93.27 128.04,98.86 121.1,98.86 120.3,98.05 120.3,97.65 v1(119.98,97.33)
PE_HP_SCL: length 1.4
  TOP w0.109: U43.AR67 v2(92.59,68.04)
  BOTTOM w0.109: v2(92.59,68.04) 92.25,68.38 R911.2
PE_HP_SDA: length 1.4
  TOP w0.109: U43.AN67 93.58,68.02 v2(93.54,68.05)
  BOTTOM w0.109: v2(93.54,68.05) 93.26,68.33 R912.2
PECI_BMC: length 100
  TOP w0.109: v1(137.59,96.65) 139.16,96.65 142.39,93.42 142.39,82.23 139.75,79.58 139.75,78.03 137.95,76.24 136.46,76.24 v1(135.94,76.76) ; v1(117.14,56.31) 117.12,56.29 R905.2
  SIG3 w0.107: v1(137.59,96.65) 136.95,97.28 136.95,101.91 137.23,102.18 137.23,104.04 136.37,104.9 136.37,111.43 136.06,111.73 136.06,112.74 136.36,113.04 136.36,115.67 136.82,116.12 136.82,117.14 137.56,117.88 137.56,127.15 137.21,127.51 137.21,129.97 137.71,130.48 v1(137.71,132.64) ; v1(117.14,56.31) 118.28,57.46 123.36,57.46 124.63,58.73 124.63,59.98 132.66,68 132.66,68.76 135.94,72.04 v1(135.94,76.76)
  BOTTOM w0.109: R550.1 R552.1 138.73,131.88 137.97,132.64 v1(137.71,132.64)
PECI_ID0: length 4.3
  TOP w0.109: U43.L72 104.46,64.91 104.88,65.33 105.38,65.33 v2(105.49,65.22)
  BOTTOM w0.109: v2(105.49,65.22) 106.5,64.21 R921.2
PECI_ID1: length 10.1
  TOP w0.089: 97.78,59.69 U43.AD78
  TOP w0.109: 97.78,59.69 97.78,59.16 100.5,56.44 101.65,56.44 102.23,55.85 v1(102.36,55.85) 102.41,55.8 R795.2
  BOTTOM w0.109: R795.2 102.41,55.8 v1(102.36,55.85)
PECI_PCH: length 46.5
  TOP w0.109: R906.2 117.78,54.53 118.03,54.79 v1(118.03,55.8)
  SIG3 w0.107: v1(133.14,68.63) 133.14,68.1 125.01,59.97 125.01,58.09 123.36,56.44 118.66,56.44 v1(118.03,55.8)
  BOTTOM w0.109: R828.2 114.58,71.55 114.36,71.34 C586.1 115.11,70.92 115.49,71.3 121.08,71.3 121.84,70.54 121.84,69.77 123.62,68 124.76,68 125.4,67.36 131.87,67.36 v1(133.14,68.63)
PERST_M.2_N: length 134.4
  TOP w0.109: v1(159.3,79.68) 163.49,83.87 168.19,83.87 177.28,92.96 J3.50 ; v1(95.55,131.98) 95.45,131.88 R71.2
  SIG1 w0.086: v1(123.36,131.62) 122.35,132.64 v1(117.9,132.64)
  SIG3 w0.107: v1(123.36,131.62) 123.49,131.5 123.49,129.59 123.92,129.16 123.92,128.14 123.49,127.71 123.49,125.1 125.12,123.47 125.12,118.18 125.6,117.7 125.6,115.3 125.14,114.84 125.14,111.63 124.23,110.72 123.8,110.72 123.54,110.46 123.54,106.17 123.87,105.84 124.25,105.84 126.13,103.96 126.13,102.14 126.86,101.41 126.86,95.77 132.97,89.67 132.97,88.16 136.44,84.68 144.52,84.68 149.53,79.68 v1(159.3,79.68) ; v1(95.55,131.98) 95.56,131.99 100.52,131.99 100.66,131.86 104.93,131.86 105.61,132.54 115.34,132.54 115.62,132.26 116.84,132.26 117.22,132.64 v1(117.9,132.64)
PG_P0V6_VTT: length 201.5
  TOP w0.109: U2.D2 v1(74.71,143.23)
  TOP w0.254: U5.9 26.84,29.9 27.61,29.13 v1(30.02,29.13) 30.55,28.6 R203.2
  SIG3 w0.107: v1(74.71,143.23) 74.21,143.72 74.21,145.34 73.83,145.72 73.57,145.72 69.77,149.52 69.77,150.55 68.38,151.94 59.86,151.94 58.87,150.94 39.61,150.94 1.97,113.3 1.97,47.53 19.22,30.28 24.05,30.28 25.19,29.13 v1(30.02,29.13)
PIRQA_N: length 178
  TOP w0.109: U43.BG20 87.36,88.95 v2(87.67,88.64) ; v1(89.35,110.8) 89.2,110.95 89.2,111.94 89.58,112.32 R855.2 89.18,112.47 89.07,112.57 89.07,114.35 88.82,114.61 87.55,114.61 87.04,115.11 v1(87.04,117.4) ; R177.1 176.7,86.03 170.87,80.19 162.77,80.19 v1(162.25,79.68)
  SIG1 w0.086: v1(122.73,123.5) 122.22,124 121.33,124 120.32,125.02 119.18,125.02 119,124.84 110.65,124.84 109.23,123.42 104.62,123.42 104.12,122.92 102.21,122.92 102.11,122.82 98.36,122.82 97.96,122.43 93.99,122.43 93.57,122.85 92.57,122.85 91.93,122.21 91.48,122.21 91.13,121.86 87.31,121.86 v1(83.74,118.29)
  SIG3 w0.107: v1(162.25,79.68) 161.79,80.14 160.14,80.14 159.81,79.81 159.81,79.55 159.46,79.2 149.12,79.2 144.09,84.23 136.27,84.23 132.51,87.99 132.51,89.51 126.43,95.59 126.43,101.23 125.68,101.98 125.68,102.64 124.44,103.88 124.44,104.26 123.08,105.61 123.08,110.95 124.48,112.34 124.48,114.8 125.14,115.46 125.14,117.4 124.68,117.86 124.68,121.89 123.08,123.5 v1(122.73,123.5) ; v1(89.35,110.8) 89.35,110.55 88.89,110.09 88.89,107.16 88.64,106.91 88.64,106.65 89.07,106.22 89.07,102.54 88.08,101.55 88.08,95.2 87.75,94.87 87.75,94.26 88.03,93.98 88.03,93.5 87.77,93.24 87.77,92.52 88.03,92.26 88.03,90.21 87.76,89.94 87.76,88.72 v2(87.67,88.64)
  BOTTOM w0.109: v1(83.74,118.29) 85.01,118.29 85.9,117.4 v1(87.04,117.4)
PIRQB_N: length 32.4
  TOP w0.109: U43.BF22 87.35,87.81 v2(87.14,87.81)
  SIG3 w0.107: v1(84.98,114.22) 84.98,113.69 84.43,113.13 84.43,112.01 84.76,111.68 84.76,110.81 84.17,110.22 84.17,109.19 82.78,107.8 82.78,106.4 83.99,105.18 83.99,103.94 84.12,103.81 84.12,99.75 84.74,99.13 84.74,96.2 85.03,95.91 85.03,94.94 84.27,94.18 84.27,93.68 84.77,93.17 84.77,92.8 85.26,92.32 85.26,91.97 85.76,91.46 85.76,91.09 86.25,90.61 86.25,90.17 86.7,89.72 86.7,89.19 87.04,88.84 87.04,87.91 v2(87.14,87.81)
  BOTTOM w0.109: R856.2 84.81,113.11 84.98,113.28 v1(84.98,114.22)
PIRQC_N: length 21.3
  TOP w0.109: U43.AR11 92.68,93.24 v2(93.04,92.89)
  BOTTOM w0.109: R857.2 102.82,107.49 100.85,105.53 100.45,105.53 99.3,104.38 97.31,104.38 95.42,102.49 95.42,101.39 94.6,100.57 94.6,98.29 92.92,96.6 92.92,94.41 92.99,94.34 92.99,92.94 v2(93.04,92.89)
PIRQD_N: length 33.4
  TOP w0.109: U43.BH22 86.64,88.63 v2(86.66,88.65) ; v1(84.32,115.77) 84.2,115.65 R858.2
  SIG3 w0.107: v2(86.66,88.65) 86.48,88.82 86.48,89.64 86.03,90.09 86.03,90.53 85.54,91.02 85.54,91.37 85.04,91.88 85.04,92.23 85.03,92.23 85.03,92.25 84.55,92.73 84.55,93.09 84.54,93.11 84.04,93.6 84.04,94.11 83.74,94.41 83.74,94.79 83.99,95.05 84.55,95.05 84.81,95.3 84.81,95.76 84.52,96.05 84.52,98.84 83.79,99.57 83.79,103.49 83.1,104.18 83.1,105.33 81.89,106.55 81.89,106.89 82.39,107.4 82.39,107.92 83.9,109.43 83.9,110.34 84.37,110.82 84.37,111.58 84.15,111.81 84.15,113.36 84.5,113.72 84.5,114.36 84.85,114.71 84.85,115.02 84.5,115.37 84.5,115.6 v1(84.32,115.77)
PLLAV33: length 4.1
  TOP w0.178: U20.W17 v2(142.69,125.83) ; U20.T11 v2(148.29,123.43) ; U20.Y17 v2(142.69,126.63)
  BOTTOM w0.381: C323.1 142.53,126.47 v2(142.69,126.63) ; C324.1 142.77,125.76 v2(142.69,125.83) ; v2(148.29,123.43) 147.62,122.76 C325.1
  vias: v1(138.1,138.74) v1(138.98,138.74)
PM_SYNC: length 127.6
  TOP w0.109: v2(83.67,93.81) 83.38,94.1 U43.BT9 ; U43.H77 105.61,62.39 105.61,61.06 v2(106.07,60.6)
  SIG1 w0.086: v2(83.67,93.81) 83.9,93.81 84.88,94.79 84.88,98.73 92.07,105.92 92.07,106.93 92.33,107.19 93.95,107.19 94.41,106.73 100.51,106.73 102.02,108.24 102.02,109.62 104.5,112.09 105.36,112.09 105.46,112.19 107.87,112.19 v1(107.95,112.12)
  SIG3 w0.107: v1(107.95,112.12) 109.3,112.12 112.19,109.23 112.19,108.03 112.16,108 112.16,108 111.91,107.75 111.91,106.58 111.12,105.79 111.12,103.39 110.16,102.43 110.16,97.21 110.35,97.02 110.35,95.72 106.65,92.02 106.65,88.72 107.87,87.5 107.87,86.03 108.5,85.4 108.5,83.87 110.92,81.46 122.45,81.46 128.6,75.31 128.6,72.51 128.43,72.35 128.43,71.54 124.89,67.99 124.2,67.99 121.93,65.72 117.05,65.72 116.53,65.2 114.6,65.2 111.8,62.41 108.76,62.41 108,61.65 108,61.16 107.44,60.6 v2(106.07,60.6)
PMB_ALERT: length 190.5
  TOP w0.109: v1(142.67,11.74) 142.54,11.86 141.78,11.86 141.52,11.61 J5.8 ; R742.2 67.1,24.18 67.36,23.93 67.36,23.37 68.5,22.23 v1(68.5,21.26) ; v1(128.57,24.56) 128.19,24.18 R659.2 ; R705.2 v1(175.43,37.52)
  SIG1 w0.086: v1(68.5,21.26) 71.67,21.26 73.07,19.86 73.07,16.69 74.9,14.86 74.9,12.83 77.29,10.43 115.59,10.43 116.46,11.3 116.46,12.45 117.15,13.15 118.3,13.15 122.22,17.07 123.36,17.07 126.74,20.45 126.74,22.73 v1(128.57,24.56) 129.46,24.56 130.01,24.01 134.12,24.01 141.28,31.17 170.87,31.17 172.89,33.2 172.89,36.12 174.29,37.52 v1(175.43,37.52) 175.94,38.02 176.6,38.02 176.83,37.79 176.83,30.53 165.27,18.97 151.05,18.97 143.81,11.74 v1(142.67,11.74)
  BOTTOM w0.109: v1(142.67,11.74) 142.29,11.35 R341.1
PMB_ALERT_VCCGBE_P1V05_PCH: length 3.3
  TOP w0.178: R705.1 173.81,37.41 172.29,35.89 171.6,35.89 171.57,35.92 U33.25
PMB_ALERT_VCCIN_VCCSCSUS: length 3.8
  TOP w0.178: U29.25 124.71,22.33 124.73,22.3 125.81,22.3 126.41,22.91 126.41,23.29 126.95,23.83 R659.1
PMB_ALERT_VDDQ: length 3.6
  TOP w0.178: R742.1 65.86,23.83 64.34,22.3 63.65,22.3 63.62,22.33 U36.25
PMB_CLK: length 195.4
  TOP w0.109: 144.06,4.47 144.06,2.59 v1(143.81,2.34) ; v1(128.57,23.17) 128.32,22.91 R658.2 ; R704.2 v1(175.43,36.5) ; v1(68.42,20.37) 68.42,20.45 67.99,20.88 67.99,22.02 67.1,22.91 R741.2
  SIG1 w0.086: v1(143.81,2.34) 142.16,3.99 142.16,11.86 150.16,19.86 165.02,19.86 175.89,30.73 175.89,36.04 v1(175.43,36.5) 173.78,34.85 173.78,33.07 171.17,30.45 141.58,30.45 134.41,23.29 128.7,23.29 v1(128.57,23.17) 127.61,22.2 127.61,20.04 123.49,15.93 123.17,15.93 122.6,15.36 122.6,14.36 122.37,14.13 122.09,14.13 121.13,13.17 119.42,13.17 115.95,9.7 76.88,9.7 74.09,12.5 74.09,13.77 71.29,16.56 69.77,16.56 68.63,17.7 68.63,18.56 68.42,18.76 v1(68.42,20.37)
  BOTTOM w0.109: R344.1 R343.1 143.3,2.85 v1(143.81,2.34)
PMB_CLK_VCCGBE_P1V05_PCH: length 3
  TOP w0.178: R704.1 173.66,36.5 172.68,35.52 U33.24
PMB_CLK_VCCIN_VCCSCSUS: length 3
  TOP w0.178: R658.1 125.96,21.93 U29.24
PMB_CLK_VDDQ: length 3
  TOP w0.178: U36.24 64.6,21.93 65.58,22.91 R741.1
PMB_DIO: length 193.4
  TOP w0.109: R743.2 67.1,25.32 67.86,24.56 67.86,23.55 69.03,22.38 69.03,20.57 v1(69.36,20.24) ; 144.06,9.85 v1(144.06,12.62) ; v1(176.32,37.52) 176.32,37.9 175.56,38.66 R706.2 ; v1(129.21,23.93) 129.21,24.69 128.57,25.32 R660.2
  SIG1 w0.086: v1(69.36,20.24) 72.18,20.24 72.79,19.63 72.79,16.54 74.6,14.74 74.6,12.71 77.14,10.16 115.72,10.16 116.93,11.37 116.93,12.54 117.27,12.88 118.49,12.88 119.22,13.61 120.57,13.61 120.82,13.86 120.82,14.66 122.6,16.43 123.36,16.43 127.12,20.19 127.12,22.35 128.7,23.93 v1(129.21,23.93) 129.39,23.74 134.23,23.74 141.39,30.9 170.98,30.9 173.17,33.09 173.17,35.87 174.31,37.01 175.81,37.01 v1(176.32,37.52) 176.45,37.39 176.45,30.62 165.14,19.3 150.75,19.3 v1(144.06,12.62)
  BOTTOM w0.109: R340.1 R342.1 144.32,12.37 v1(144.06,12.62)
PMB_DIO_VCCGBE_P1V05_PCH: length 3.9
  TOP w0.178: R706.1 173.81,38.43 173.27,37.9 173.27,37.45 172.14,36.32 U33.26
PMB_DIO_VCCIN_VCCSCSUS: length 4.4
  TOP w0.178: U29.26 125.65,22.73 126.01,23.09 126.01,23.44 126.41,23.85 126.41,24.69 126.95,25.22 R660.1
PMB_DIO_VDDQ: length 4.2
  TOP w0.178: U36.26 64.2,22.73 65.32,23.85 65.32,24.56 65.86,25.1 R743.1
PME_N: length 26.2
  TOP w0.109: U43.BE16 88.13,89.52 v2(88.13,89.51)
  SIG3 w0.107: v2(88.13,89.51) 88.24,89.62 88.24,92.49 88.53,92.77 88.53,93.38 88.25,93.65 88.25,93.97 88.52,94.23 88.52,96.37 88.41,96.47 88.41,101.24 89.45,102.29 89.45,106.22 89.12,106.55 89.12,107.01 89.79,107.68 89.79,111.7 v1(89.7,111.8)
  BOTTOM w0.109: v1(89.7,111.8) 89.95,111.8 90.09,111.94 90.09,112.32 90.24,112.47 R877.2
PROCPWRGD_PCH: length 3.4
  TOP w0.109: R1070.2 R1078.2 121.88,107.11 121.84,107.15 U50.11
PROCPWRGD_PCH_CPLD: length 50.7
  TOP w0.109: U2.R9 v1(82.71,131.23) ; v1(112.82,106.96) 113.02,107.15 U50.6
  SIG3 w0.107: v1(97.66,131.12) 97.5,131.27 91.28,131.27 90.8,130.78 83.15,130.78 v1(82.71,131.23)
  BOTTOM w0.109: v1(97.66,131.12) 98.17,131.62 98.9,131.62 100.43,130.1 100.43,125.56 101.35,124.64 101.77,124.64 102.54,123.88 102.54,121.72 105.08,119.18 105.08,116.76 106.6,115.24 106.6,113.46 107.04,113.02 107.93,113.02 109.27,111.68 109.44,111.68 110.66,110.46 110.66,109.02 110.92,108.76 111.63,108.76 112,108.4 112,107.66 112.7,106.96 v1(112.82,106.96)
PROCPWRGD_PCH_GTL: length 58.2
  TOP w0.109: R1070.1 123.34,108.41 123.11,108.64 121.97,108.64 v1(121.33,108) ; U43.BU11 82.89,93.24 v2(83.18,92.95)
  SIG1 w0.086: v1(121.33,108) 114.05,108 109.23,112.83 106.07,112.83 106.05,112.8 105.63,112.8 105.1,113.33 104.08,113.33 101.38,110.63 101.38,108.4 100.36,107.38 94.68,107.38 94.19,107.87 91.11,107.87 90.09,106.86 90.09,106.6 84.69,101.21 84.69,99.81 84.12,99.24 84.12,98.22 83.49,97.59 83.49,96.95 83.81,96.63 83.81,95.2 83.18,94.56 v2(83.18,92.95)
PUD_SAEN0: length 5.6
  TOP w0.109: U2.N9 v1(82.71,133.23)
  BOTTOM w0.109: R105.1 R73.1 82.09,131.98 82.09,132.61 v1(82.71,133.23)
PUD_SAEN1: length 5.3
  TOP w0.109: U2.N10 v1(83.71,133.23)
  BOTTOM w0.109: R78.1 R108.1 82.7,130.33 83.23,130.86 83.23,132.75 v1(83.71,133.23)
PWR_BTN_N: length 186
  TOP w0.109: R544.1 161.69,127.05 161.82,127.18 162.35,127.18 164.13,128.96 164.89,128.96 165.65,129.72 165.65,131.5 v1(166.16,132) ; R72.2 94.76,132.61 94.53,132.39 93.39,132.39 93.14,132.64 v1(93.14,132.74)
  SIG1 w0.086: v1(126.41,136.96) 116.44,136.96 115.43,135.94 115.11,135.94 114.27,135.1 111.51,135.1 110.66,134.25 107,134.25 105.06,132.31 101.11,132.31 100.34,133.08 99.29,133.08 98.76,132.55 95.13,132.55 94.94,132.74 v1(93.14,132.74)
  SIG3 w0.107: v1(198.55,83.87) 197.53,84.89 197.53,87.3 195.65,89.18 195.65,97 195.55,97.1 195.55,102.97 195.32,103.2 195.32,120.06 195.5,120.24 195.5,125.57 194.36,126.72 194.36,128.07 192.78,129.65 176.65,129.65 175.38,130.91 167.89,130.91 166.8,132 v1(166.16,132) 164.89,133.27 164.89,145.24 160.37,149.76 142.56,149.76 141.54,150.77 138.07,150.77 v1(137.59,150.29)
  SIG4 w0.086: v1(137.59,150.29) 134.54,147.24 131.87,147.24 130.09,145.47 130.09,141.4 126.41,137.72 v1(126.41,136.96)
  BOTTOM w0.109: R3.2 198.93,83.49 v1(198.55,83.87)
PWR_BTN_PASS_N: length 176.8
  TOP w0.089: U43.AW3 90.71,96.91 90.71,97.39 90.35,97.75 90.35,98.28 90.7,98.63
  TOP w0.109: v1(96.69,124.77) 97.07,124.38 97.07,124.26 97.33,124 97.33,123.88 97.71,123.5 97.71,119.18 96.82,118.29 96.82,117.91 96.57,117.65 95.42,117.65 94.39,116.62 94.39,114.73 93.96,114.3 93.96,113.71 93.54,113.29 93.54,110.56 93.14,110.16 93.14,108.4 93.26,108.28 R888.2 93.77,107.49 93.9,107.37 93.9,104.45 90.85,101.4 90.85,100.25 90.7,100.1 90.7,98.63 ; R545.1 161.77,129.72 v1(162.33,129.16) ; v1(84.76,155.12) 84.76,154.23 83.1,152.58 82.85,152.58 82.47,152.2 82.47,151.82 82.72,151.56 R59.1
  SIG3 w0.107: v1(162.33,129.16) 161.67,129.82 161.67,131.45 162.3,132.08 162.88,132.08 163.11,132.31 163.11,144.7 160.29,147.52 142.36,147.52 141.88,148.01 137.84,148.01 136.29,149.56 127.26,149.56 125.31,151.51 95.91,151.51 92.25,155.17 85.7,155.17 85.64,155.12 v1(84.76,155.12)
  SIG4 w0.086: v1(84.76,155.12) 84.76,152.71 93.01,144.45 93.01,143.18 93.98,142.21 93.98,140.72 92.38,139.12 92.38,135.81 94.28,133.91 95.8,133.91 96.06,133.66 96.06,131.21 96.57,130.71 96.57,128.58 97.46,127.69 97.46,125.91 96.69,125.15 v1(96.69,124.77)
PWRGD_CPU: length 4.1
  BOTTOM w0.109: R1051.2 R1046.2 113.2,142.55 113.08,142.42 113.08,142.04 112.53,141.49 U47.11
PWRGD_CPU_CPLD: length 30
  TOP w0.109: v1(86.71,133.23) 86.71,133.23 U2.P13
  SIG1 w0.086: v1(108.89,138.91) 108.38,138.91 107.35,137.88 105.99,137.88 104.76,136.65 99.18,136.65 97.95,135.42 89.18,135.42 86.99,133.23 v1(86.71,133.23)
  BOTTOM w0.109: v1(108.89,138.91) 106.31,141.49 U47.6
PWRGD_CPU_GTL: length 201.6
  TOP w0.089: v1(68.87,80.21) 69.29,80.63 72.3,80.63 72.49,80.44 73.04,80.44 73.38,80.78 73.67,80.78 74.02,80.43 U43.CR39
  TOP w0.109: v2(100.58,60.86) 100.44,61 100.44,62.14 100.66,62.36 100.66,63.01 U43.V76
  SIG1 w0.086: v2(100.58,60.86) 98.09,63.35 98.09,65.2 98.47,65.58 98.47,66.35 98.09,66.73 98.09,66.98 97.58,67.49 97.58,67.87 97.07,68.38 97.07,68.89 97.58,69.39 97.58,70.41 99.03,71.86 99.03,77.85 96.82,80.06 96.82,81.08 96.44,81.46 91.11,81.46 90.34,82.22 88.82,82.22 87.93,81.33 74.72,81.33 73.07,79.68 69.4,79.68 v1(68.87,80.21)
  SIG3 w0.107: v2(100.58,60.86) 100.68,60.76 104.69,60.76 106.22,59.23 107.67,59.23 110.33,61.9 112.57,61.9 114.35,63.68 116.29,63.68 117.41,64.8 122.25,64.8 123.16,65.71 123.96,65.71 125.23,66.98 126.41,66.98 127.05,67.61 127.05,68.89 129.41,71.24 129.41,72.09 129.52,72.2 129.52,75.64 121.98,83.19 114.42,83.19 113.84,82.6 110.79,82.6 109.27,84.13 109.27,85.9 108.63,86.54 108.63,87.96 107.35,89.24 107.35,91.73 111.04,95.43 111.04,100.64 113.08,102.67 113.08,104.32 112.7,104.7 112.7,105.84 113.28,106.43 113.28,108.53 108.38,113.43 108.38,115.75 107.21,116.92 107.21,123.24 107.49,123.52 107.49,125.96 v1(107.62,126.09)
  SIG4 w0.086: v1(116,125.86) 115.67,125.53 110.41,125.53 109.88,126.06 107.64,126.06 v1(107.62,126.09)
  BOTTOM w0.109: R1046.1 114.85,142.55 116.36,141.04 116.36,140.41 117.39,139.37 117.39,131.62 117.22,131.45 117.22,127.08 v1(116,125.86)
RESET_CPU_N: length 3.7
  BOTTOM w0.109: U48.12 121.15,108.45 121.84,109.14 R1045.2 R1053.1
RESET_CPU_N_CPLD: length 47.1
  TOP w0.109: v1(86.71,132.23) 86.71,132.23 U2.R13
  SIG3 w0.107: v1(99.72,132.59) 99.56,132.43 93.59,132.43 93.42,132.26 91.11,132.26 90.6,131.75 87.18,131.75 v1(86.71,132.23)
  BOTTOM w0.109: v1(99.72,132.59) 100.81,132.59 101.08,132.32 101.4,132.32 102.35,131.37 102.35,129.6 103.62,128.33 104.81,128.33 106.98,126.16 106.98,125.33 109.47,122.84 109.47,117.09 108.53,116.15 108.53,113.85 109.57,112.81 109.76,112.81 112.44,110.13 112.44,109.42 113.41,108.45 U48.5
RESET_CPU_N_GTL: length 100.7
  TOP w0.109: U43.L76 103.72,63.6 104.27,64.14 v2(104.27,64.42)
  SIG3 w0.107: v1(111.45,108.31) 111.38,108.38 110.49,108.38 108.89,106.78 108.89,104.83 109.27,104.45 109.27,98.48 108.25,97.46 108.25,95.3 104.44,91.49 104.44,89.84 105.71,88.57 106.09,88.57 107.23,87.43 107.23,85.65 107.74,85.14 107.74,83.74 110.77,80.72 119.66,80.72 124.76,75.62 127.26,75.62 127.88,75 127.88,72.82 127.68,72.63 127.68,71.86 125.12,69.29 124.15,69.29 121.43,66.57 114.96,66.57 111.55,63.17 105.58,63.17 105.2,63.55 104.8,63.55 104.27,64.08 v2(104.27,64.42)
  SIG4 w0.086: v1(111.45,108.31) 118.74,108.31 119.5,107.55 123.42,107.55 v1(124,108.13)
  BOTTOM w0.109: v1(124,108.13) 124,108.36 123.34,109.02 R1045.1
RGMII2TXCTL_R: length 6.8
  TOP w0.109: R589.1 R588.2 159.84,110.26 158.29,111.81 157.5,111.81 157.12,112.19 156.25,112.19 U20.B1
RGMII2TXD0_R: length 6.8
  TOP w0.109: R577.1 R576.2 157.4,106.86 157.53,106.99 157.53,107.87 155.09,110.31 U20.A2
RGMII2TXD1_R: length 8.9
  TOP w0.109: U20.B3 154.7,111.43 156.03,111.43 156.41,111.81 157.02,111.81 157.4,111.43 158.16,111.43 159.69,109.91 160.19,109.91 160.73,109.37 R574.2 R575.1
RGMII2TXD2_R: length 8.8
  TOP w0.109: U20.D5 v2(153.09,113.03)
  BOTTOM w0.109: v2(153.09,113.03) 153.49,112.64 153.49,110.46 153.59,110.36 153.59,107.75 154.35,106.99 R571.2 R572.1
RGMII2TXD3_R: length 10.3
  TOP w0.109: U20.D4 v2(153.89,113.03)
  BOTTOM w0.109: R569.1 R568.2 157.4,106.73 157.65,106.99 157.65,108.18 155.49,110.34 155.49,111.18 155.09,111.58 155.09,112.47 154.53,113.03 v2(153.89,113.03)
RI_N: length 21.5
  TOP w0.109: U43.BF11 87.7,93.24 88,92.94 v2(88.15,92.94)
  BOTTOM w0.109: R873.2 93.77,105.72 89.58,101.53 89.58,99.75 89.84,99.49 89.84,97.33 88.31,95.81 88.31,95.05 88.52,94.84 88.52,94.39 88.26,94.13 88.26,93.66 88.51,93.41 89.31,93.41 89.51,93.22 89.51,92.74 89.28,92.51 88.57,92.51 88.15,92.92 v2(88.15,92.94)
RMII1CRSDV: length 26
  TOP w0.109: U20.C5 v2(153.09,112.23)
  SIG2 w0.107: v1(172.89,105.72) 172,106.6 172,107.37 169.85,109.53 162.61,109.53 159.81,112.32 v1(159.25,112.32)
  SIG4 w0.086: v1(159.25,112.32) 158.82,112.75 156.56,112.75 155.62,111.81 153.51,111.81 v2(153.09,112.23)
  BOTTOM w0.109: R612.1 R598.1 v1(172.89,105.72)
RMII1RCLKO_BMC: length 30.9
  TOP w0.109: U20.B5 153.09,111.43 153.09,110.78 154.48,109.4 154.48,108.38 v1(155.24,107.62)
  SIG3 w0.107: v1(155.24,107.62) 156.26,106.6 176.7,106.6 v1(177.59,105.72)
  BOTTOM w0.109: R593.1 154.1,108 154.48,107.62 v1(155.24,107.62) ; R594.1 176.96,106.35 v1(177.59,105.72)
RMII1RXD0: length 22.4
  TOP w0.109: v1(159.05,103.18) 158.54,103.68 157.27,103.68 156.89,104.06 156.89,106.86 156.59,107.16 156.59,108.18 154.48,110.29 154.48,110.85 U20.A3
  SIG2 w0.107: v1(159.05,103.18) 160.96,105.08 v1(167.69,105.08)
  BOTTOM w0.109: v1(167.69,105.08) 167.81,105.21 R597.2 R614.1
RMII1RXD1: length 26.5
  TOP w0.109: U20.D6 v2(152.29,113.03)
  SIG2 w0.107: v1(158.52,112.29) 158.52,111.81 161.18,109.14 168.7,109.14 169.85,108 169.85,106.99 v1(171.12,105.72)
  SIG4 w0.086: v2(152.29,113.03) 152.29,112.35 153.59,111.05 155.49,111.05 156.26,111.81 158.03,111.81 v1(158.52,112.29)
  BOTTOM w0.109: R595.2 R613.1 170.86,105.97 v1(171.12,105.72)
RMII1RXER: length 7.7
  TOP w0.109: U20.C4 v2(153.89,112.23)
  BOTTOM w0.109: R526.2 156.38,106.73 156.59,106.93 156.59,108.69 155.11,110.16 155.11,111.01 v2(153.89,112.23)
RMII1TXD0: length 31
  SIG1 w0.086: v1(154.86,103.05) 154.1,102.29 149.27,102.29 148.38,103.18 v1(147.87,103.18)
  SIG2 w0.107: v1(168.07,108.1) 167.53,108.64 158.67,108.64 155.88,105.84 155.88,104.06 v1(154.86,103.05)
  BOTTOM w0.109: v1(168.07,108.1) 168.07,108.38 168.96,109.28 U26.9 ; v1(147.87,103.18) 147.87,103.94 147.62,104.19 145.72,104.19 145.46,104.45 145.46,105.08 145.18,105.36 R523.2
RMII1TXD0_R: length 12.1
  TOP w0.109: U20.F9 v2(149.89,114.63)
  BOTTOM w0.109: v2(149.89,114.63) 149.48,114.21 149.48,113.54 147.37,111.43 147.37,107.87 146.99,107.49 R586.2 R587.1 R523.1
RMII1TXD1: length 16.4
  TOP w0.109: R522.2 v1(156.38,104.7)
  SIG2 w0.107: v1(168.96,108.08) 167.99,107.11 158.8,107.11 v1(156.38,104.7)
  BOTTOM w0.109: U26.8 169.46,109.01 168.96,108.51 v1(168.96,108.08)
RMII1TXD1_R: length 7.4
  TOP w0.109: R522.1 R585.1 R584.2 154.35,107.11 153.97,107.49 153.97,109.14 152.69,110.42 U20.A5
RMII1TXEN: length 25.3
  SIG2 w0.107: v1(159.43,104.7) 160.32,105.59 169.46,105.59 170.1,104.95 173.15,104.95 173.4,105.21 173.4,107.75 v1(170.61,110.54)
  BOTTOM w0.109: v1(159.43,104.7) 159.15,104.98 R521.2 ; U26.7 169.96,110.02 170.48,110.54 v1(170.61,110.54)
RMII1TXEN_R: length 15.1
  TOP w0.109: U20.E9 v2(149.89,113.83)
  BOTTOM w0.109: R521.1 R590.2 R591.1 156.84,109.53 155.88,110.49 155.88,114 155.62,114.25 150.31,114.25 v2(149.89,113.83)
RSMRST_CPU_N: length 3.7
  BOTTOM w0.109: U48.13 120.64,107.8 121.33,107.11 R1052.2 R1042.2
RSMRST_CPU_N_CPLD: length 50.9
  TOP w0.109: U2.R12 v1(85.71,131.23)
  SIG3 w0.107: v1(85.71,131.23) 85.76,131.23 86.25,131.72 86.25,132.52 86.52,132.78 86.93,132.78 87.17,133.02 87.17,133.41 87.46,133.71 89.33,133.71 89.81,133.22 91.69,133.22 92.32,133.86 98.25,133.86 v1(98.8,133.3)
  BOTTOM w0.109: v1(98.8,133.3) 98.8,132.88 99.6,132.09 100.55,132.09 100.88,131.75 101.26,131.75 101.85,131.16 101.85,129.1 104.31,126.64 104.31,125.91 105.46,124.77 106.83,124.77 108.96,122.63 108.96,117.35 108.02,116.41 108.02,113.64 109.47,112.19 109.67,112.19 111.3,110.55 111.3,109.82 113.33,107.8 U48.4
RSMRST_CPU_N_GTL: length 105.4
  TOP w0.109: U43.R77 102.24,61.31 v2(102.41,61.14)
  SIG3 w0.107: v1(112.59,107.82) 112.59,107.52 112.37,107.29 112.37,106.35 112.19,106.17 112.19,105.08 111.81,104.7 111.81,103.3 111.17,102.67 111.17,101.4 110.66,100.89 110.66,95.66 106.92,91.91 106.92,89.06 108.25,87.73 108.25,86.28 108.89,85.65 108.89,84 110.97,81.92 122.63,81.92 129.05,75.49 129.05,72.35 128.95,72.25 128.95,71.43 126.59,69.06 126.59,67.82 126.26,67.49 125.12,67.49 123.8,66.17 123,66.17 122.08,65.25 117.21,65.25 116.15,64.19 114.22,64.19 112.19,62.15 110.19,62.15 108.16,60.12 105.84,60.12 104.82,61.14 v2(102.41,61.14)
  SIG4 w0.086: v1(124.89,108.2) 123.8,107.11 119.3,107.11 118.59,107.82 v1(112.59,107.82)
  BOTTOM w0.109: v1(124.89,108.2) 125.14,107.95 125.14,106.86 124.25,105.97 123.74,105.97 123.62,106.1 R1042.1
RST_BTN_N: length 208.2
  TOP w0.109: v1(162.53,130.73) R546.1 ; R9.2 201.34,87.55 201.09,87.81 196.26,87.81 v1(196.13,87.68) ; v1(139.62,149.53) 139.49,149.4 v1(139.49,143.05)
  SIG1 w0.086: v1(70.05,135.46) 71.29,136.71 71.29,139.62 73.07,141.4 73.96,141.4 75.23,142.67 85.14,142.67 86.05,141.76 89.3,141.76 89.53,141.99 91.87,141.99 92.7,142.82 95.91,142.82 97.51,144.41 99.88,144.41 100.5,143.79 108.93,143.79 109.59,143.13 117.83,143.13 118.66,142.29 121.13,142.29 122.09,141.33 136.5,141.33 137.02,141.85 138.29,141.85 v1(139.49,143.05)
  SIG3 w0.107: v1(139.62,149.53) 140.13,150.04 141.09,150.04 142.69,148.44 160.66,148.44 164.03,145.07 164.03,131.9 163.24,131.12 162.91,131.12 v1(162.53,130.73) 163.04,130.23 165.65,130.23 165.76,130.12 175.03,130.12 176.24,128.91 192.4,128.91 193.57,127.74 193.57,119.96 194.36,119.18 194.36,103.3 195.1,102.56 195.1,96.92 195.2,96.83 195.2,88.62 v1(196.13,87.68)
  BOTTOM w0.109: v1(70.05,135.46) 70.05,135.46 70.46,135.05 R74.2
RST_BTN_PASS_N: length 190.2
  TOP w0.109: v1(71.67,150.67) 72.18,150.17 72.18,145.59 71.29,144.7 71.29,143.94 72.18,143.05 72.18,142.16 72.95,141.4 72.95,138.99 73.2,138.74 73.2,137.21 72.82,136.83 72.56,136.83 72.18,136.45 72.18,135.26 72.82,134.62 72.82,129.46 72.63,129.27 72.63,128.45 72.18,128 72.18,125.65 72.67,125.17 C613.1 R1028.2 74.09,124.77 74.6,124.26 78.28,124.26 78.66,123.88 79.93,123.88 v1(80.44,124.38) ; v2(86.15,95.3) 85.87,95.3 85.41,95.77 U43.BL4 ; v1(86.41,155.63) 85.9,155.12 85.9,154.36 83.74,152.2 R64.1 84.35,151.28 v1(84.5,151.44)
  SIG3 w0.107: v2(86.15,95.3) 86.15,95.8 86.41,96.06 86.41,98.98 86.34,99.06 86.34,102.98 86.43,103.07 86.43,105.31 86.18,105.56 86.18,106.7 85.39,107.49 85.39,108.09 86.71,109.41 86.71,111.66 87.32,112.27 87.32,112.66 87.08,112.9 86.34,112.9 85.88,113.36 85.88,115.39 85.46,115.81 85.46,121.9 83.99,123.37 83.99,123.69 83.61,124.07 80.76,124.07 v1(80.44,124.38) ; v1(162.48,131.62) 163.11,131.62 163.57,132.08 163.57,144.88 160.47,147.98 142.53,147.98 141.49,149.02 137.46,149.02 135.81,150.67 126.92,150.67 125.62,151.97 96.09,151.97 92.43,155.63 v1(86.41,155.63) ; v1(84.5,151.44) 83.99,150.93 72.94,150.93 72.69,150.67 v1(71.67,150.67)
  BOTTOM w0.109: v1(162.48,131.62) 162.47,131.61 162.47,131.36 161.84,130.73 R547.1
RST_NIC0_N: length 136.9
  TOP w0.109: U2.A9 v1(82.71,146.23)
  SIG1 w0.086: v1(166.16,110.67) 165.84,111 163.47,111 163.4,110.92 160.09,110.92 v1(160.07,110.9) 160.07,110.92 160.57,111.43 160.57,119.94 161.4,120.77 161.4,121.91 164.64,125.15 165.91,125.15 166.54,125.78 166.54,126.16 167.23,126.85 167.23,129.85 166.85,130.23 166.42,130.23 165.4,131.24 165.4,131.88 164.06,133.22 164.06,141.84 163.55,142.36 163.55,146.69 160.7,149.53 142.31,149.53 141.04,150.8 125.01,150.8 123.16,148.95 111.24,148.95 110.5,148.21 102.3,148.21 101.81,148.69 94.64,148.69 93.99,148.04 91.15,148.04 90.92,148.27 84.75,148.27 v1(82.71,146.23)
  BOTTOM w0.109: v1(160.07,110.9) 159.71,110.54 R601.1 R602.2 ; U26.17 165.84,110.35 v1(166.16,110.67)
RTCRST_N: length 195.6
  TOP w0.109: JP1.2 164.77,8.41 164.77,10.59 164.29,11.07 v1(164.29,12.75) R1209.2 ; v2(93.6,93.8) 93.38,93.8 U43.AP9
  SIG3 w0.107: v1(158.97,88.93) 158.97,88.19 159.28,87.88 169.77,87.88 175.74,81.92 175.74,80.7 180.84,75.6 180.84,69.7 180.59,69.45 180.59,66.78 184.9,62.47 184.9,59.5 v1(186.38,58.01)
  SIG4 w0.086: v2(93.6,93.8) 93.6,94.62 95.3,96.32 105.08,96.32 105.63,95.76 108.2,95.76 109.52,97.08 109.52,99.55 110.1,100.13 128.57,100.13 130.98,97.71 133.14,97.71 137,93.85 152.88,93.85 157.81,88.93 v1(158.97,88.93) ; v1(164.29,12.75) 164.8,13.26 175.67,13.26 179.24,16.82 179.24,27.71 186.38,34.86 v1(186.38,58.01)
SAFE_MODE_BOOT: length 14.7
  TOP w0.109: v2(97.53,66.88) 97.48,66.88 97.23,66.63 U43.AF69
  BOTTOM w0.109: v2(97.53,66.88) 97.58,66.83 97.58,62.05 99.23,60.4 99.23,60 100.88,58.34 R920.2 100.6,57.55 100.31,57.26 100.31,56.07 101.24,55.14 R907.2
SALERT_VCCGBE_P1V05_PCH: length 3.1
  TOP w0.178: U33.22 171.63,34.72 172.26,34.09
  TOP w0.229: 172.26,34.09 172.89,33.45 R688.1
SALERT_VCCIN_VCCSCSUS: length 3.3
  TOP w0.178: U29.22 124.76,21.13 125.14,20.75
  TOP w0.254: 125.14,20.75 125.14,20.63 125.56,20.21 125.99,20.21 126.67,20.88 R643.1
SALERT_VDDQ: length 3.1
  TOP w0.178: 64.25,20.56 63.68,21.13 U36.22
  TOP w0.254: 64.25,20.56 64.94,19.86 R724.1
SALT2: length 8.3
  TOP w0.109: R554.1 141.91,107.49 142.67,108.26 142.67,112.75 142.95,113.03 143.49,113.03 U20.D16
SALT3: length 8.2
  TOP w0.109: U20.D15 145.08,113.04 145.08,110.16 142.92,108 R555.1
SALT4: length 10
  TOP w0.109: U20.E14 v2(145.09,113.83)
  BOTTOM w0.109: v2(145.09,113.83) 144.7,113.44 144.7,110.41 143.81,109.53 143.49,109.53 140.89,106.92 R556.1
SALT5: length 8.7
  TOP w0.109: U20.R18 v2(141.89,122.63)
  BOTTOM w0.109: R505.2 134.79,121.84 135.99,123.04 141.49,123.04 v2(141.89,122.63)
SALT6: length 8.9
  TOP w0.109: U20.P18 v2(141.89,121.83)
  BOTTOM w0.109: v2(141.89,121.83) 141.5,122.23 136.32,122.23 134.79,120.7 R507.2
SATA_RX_DN1: length 115.3
  TOP w0.099: v1(165.89,102.09) 166.24,102.44 166.24,102.72 166.57,103.05 170.35,103.05 171.9,104.6 172.67,104.6 C58.1 ; v2(81.2,82.65) 81.49,82.94 U43.BW33
  SIG4 w0.094: v2(81.2,82.65) 81.41,82.86 81.53,82.86 81.61,82.77 81.61,82.38 81.97,82.02 82.37,82.02 82.53,82.18 82.82,82.18 82.95,82.05 83.41,82.05 83.54,82.18 83.76,82.18 83.94,82 84.3,82 84.58,82.28 85.85,82.28 87.49,83.92 87.49,84.55 88.25,85.31 88.25,86.08 88.39,86.22 89.03,86.22 89.42,86.61 89.42,87.95 89.45,87.98 89.45,88.44 90.72,89.71 90.72,91.24 91.49,92 91.49,93.65 92.25,94.41 92.25,100.38 93.01,101.14 95.91,101.14 96.29,101.52 102.39,101.52 103.02,102.16 114.75,102.16 115,101.91 132.61,101.91 136.3,105.59 165.3,105.59 166.21,104.68 166.21,102.41 v1(165.89,102.09)
SATA_RX_DN2: length 158.3
  TOP w0.099: C734.1 199.72,139.24 195.95,139.24 v1(195.64,138.93) ; U43.BU33 82.47,82.94 v2(82.18,82.65)
  SIG4 w0.094: v1(195.64,138.93) 195.46,139.12 193.59,139.12 192.18,137.7 192.18,137.34 181.76,126.92 177.7,126.92 174.8,124.02 174.8,118.82 173.91,117.93 173.91,112.21 171.35,109.65 161.1,109.65 160.85,109.91 158.9,109.91 158.65,109.65 135.81,109.65 132,105.84 101.88,105.84 101.5,105.46 92.23,105.46 87.42,100.66 87.42,97.59 85.28,95.44 85.28,94.41 85.25,94.38 85.25,93.58 84.79,93.13 84.79,92.77 84.29,92.27 84.29,91.92 84.73,91.49 84.73,91.01 84.27,90.55 84.27,90.17 83.77,89.67 83.77,89.28 83.26,88.78 83.26,88.45 82.81,88 82.81,87.62 82.28,87.1 82.28,86.67 81.83,86.22 81.83,85.16 83.23,83.77 83.23,83.29 82.99,83.05 82.58,83.05 v2(82.18,82.65)
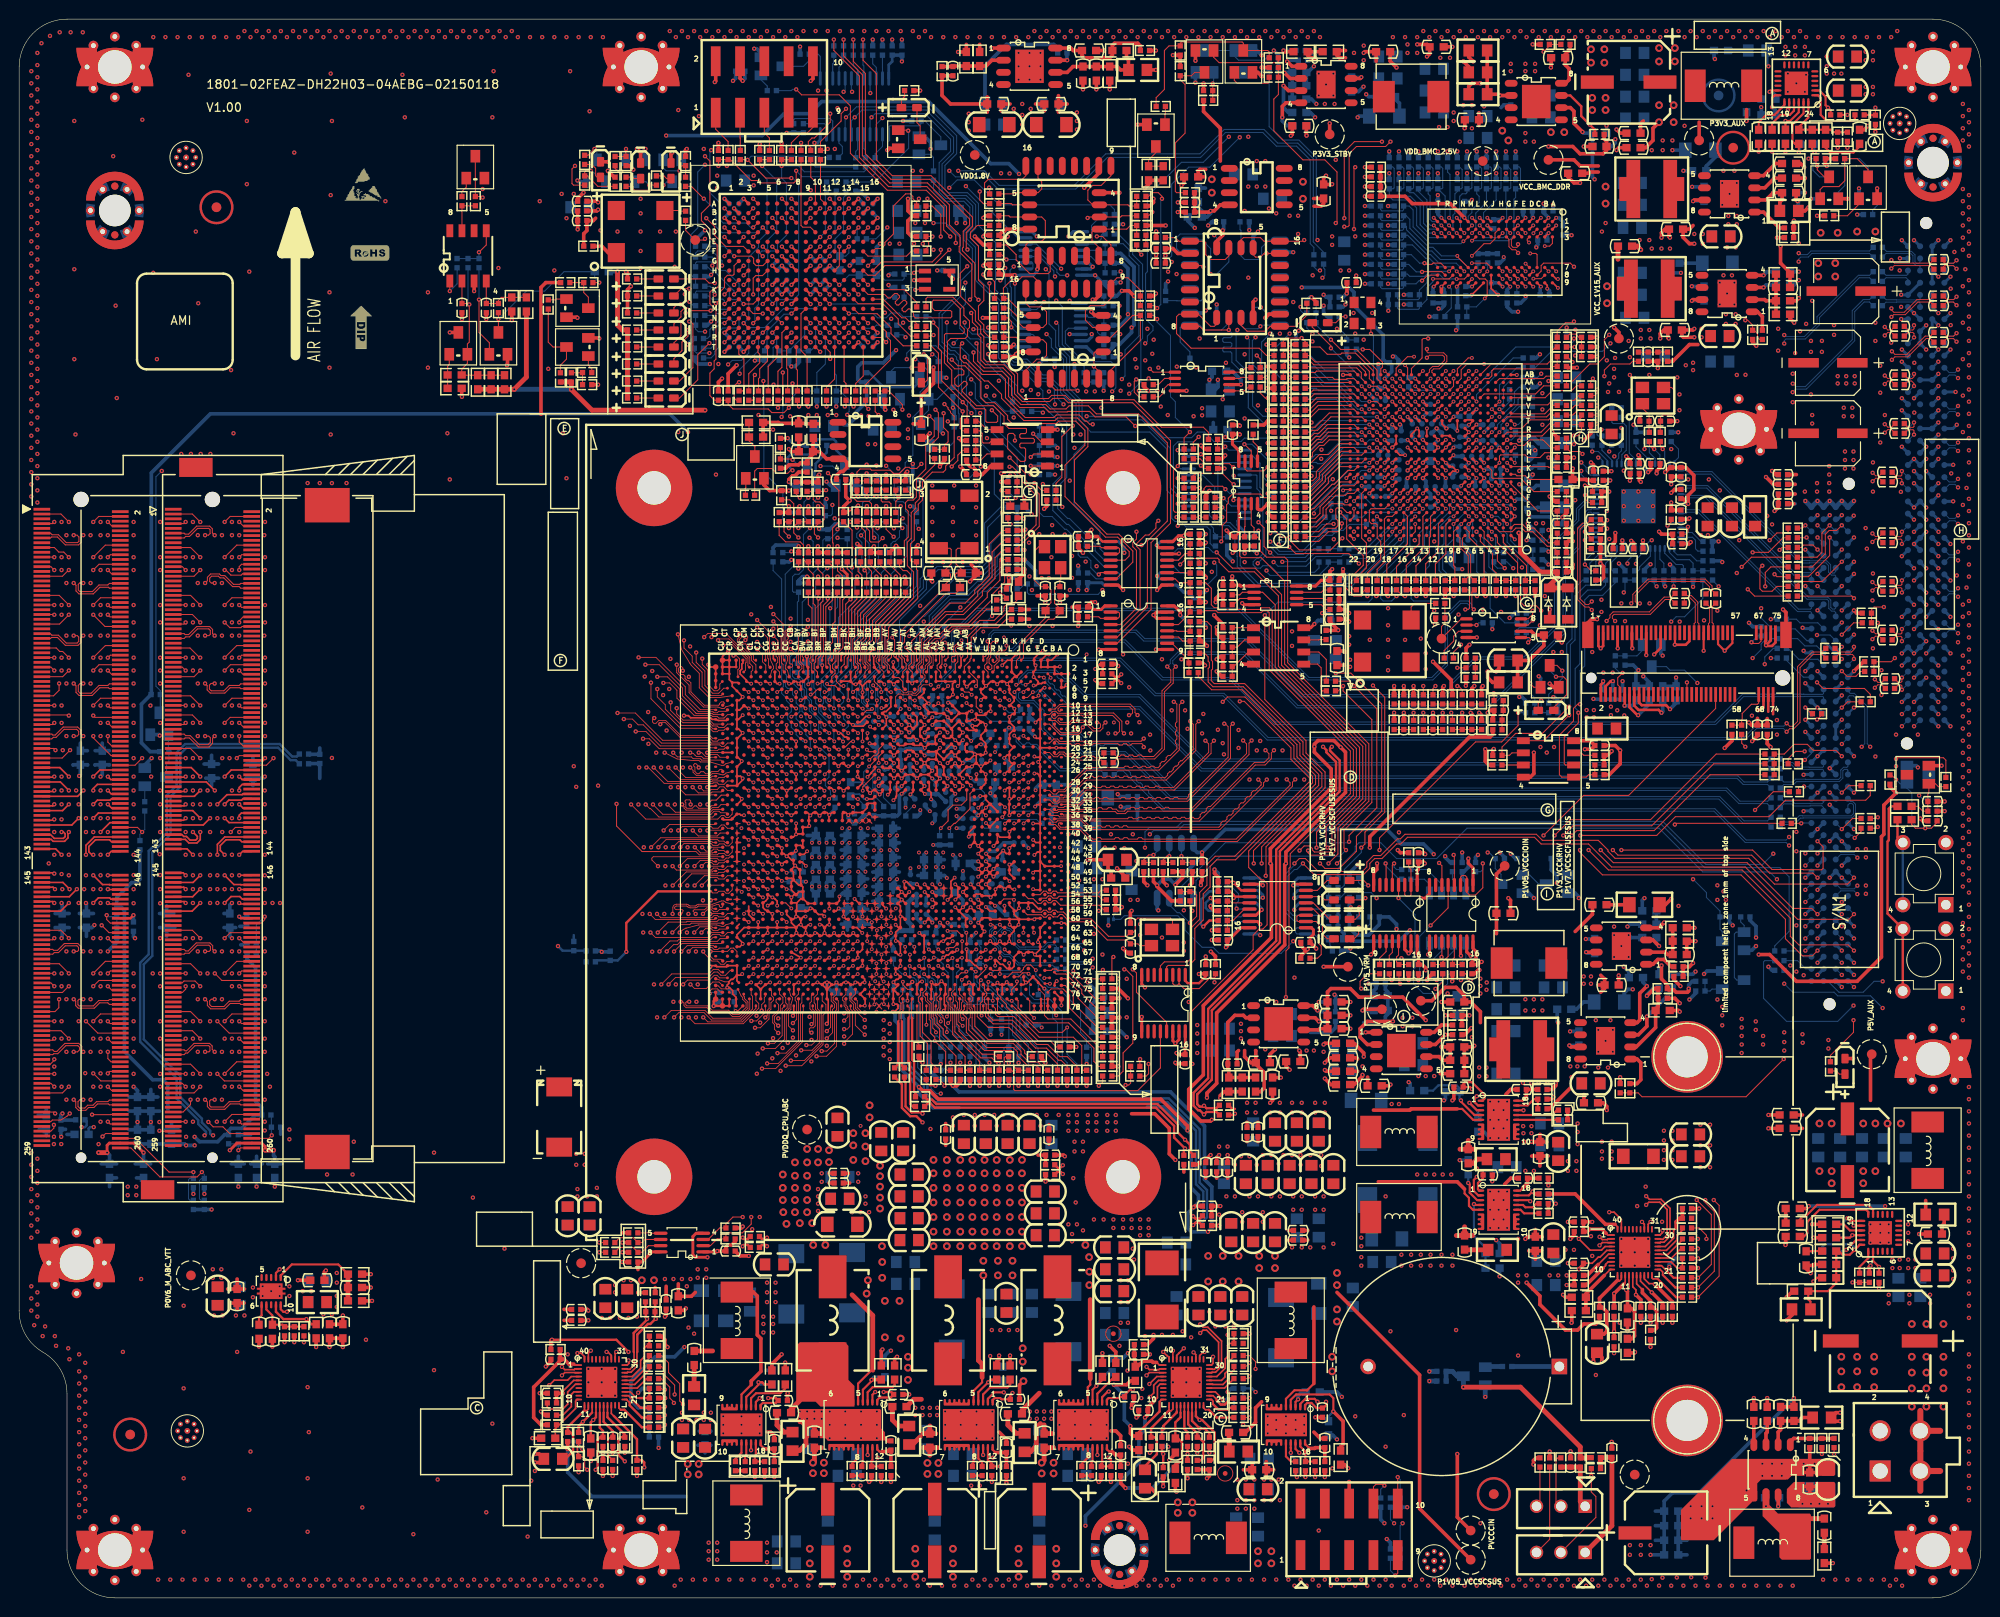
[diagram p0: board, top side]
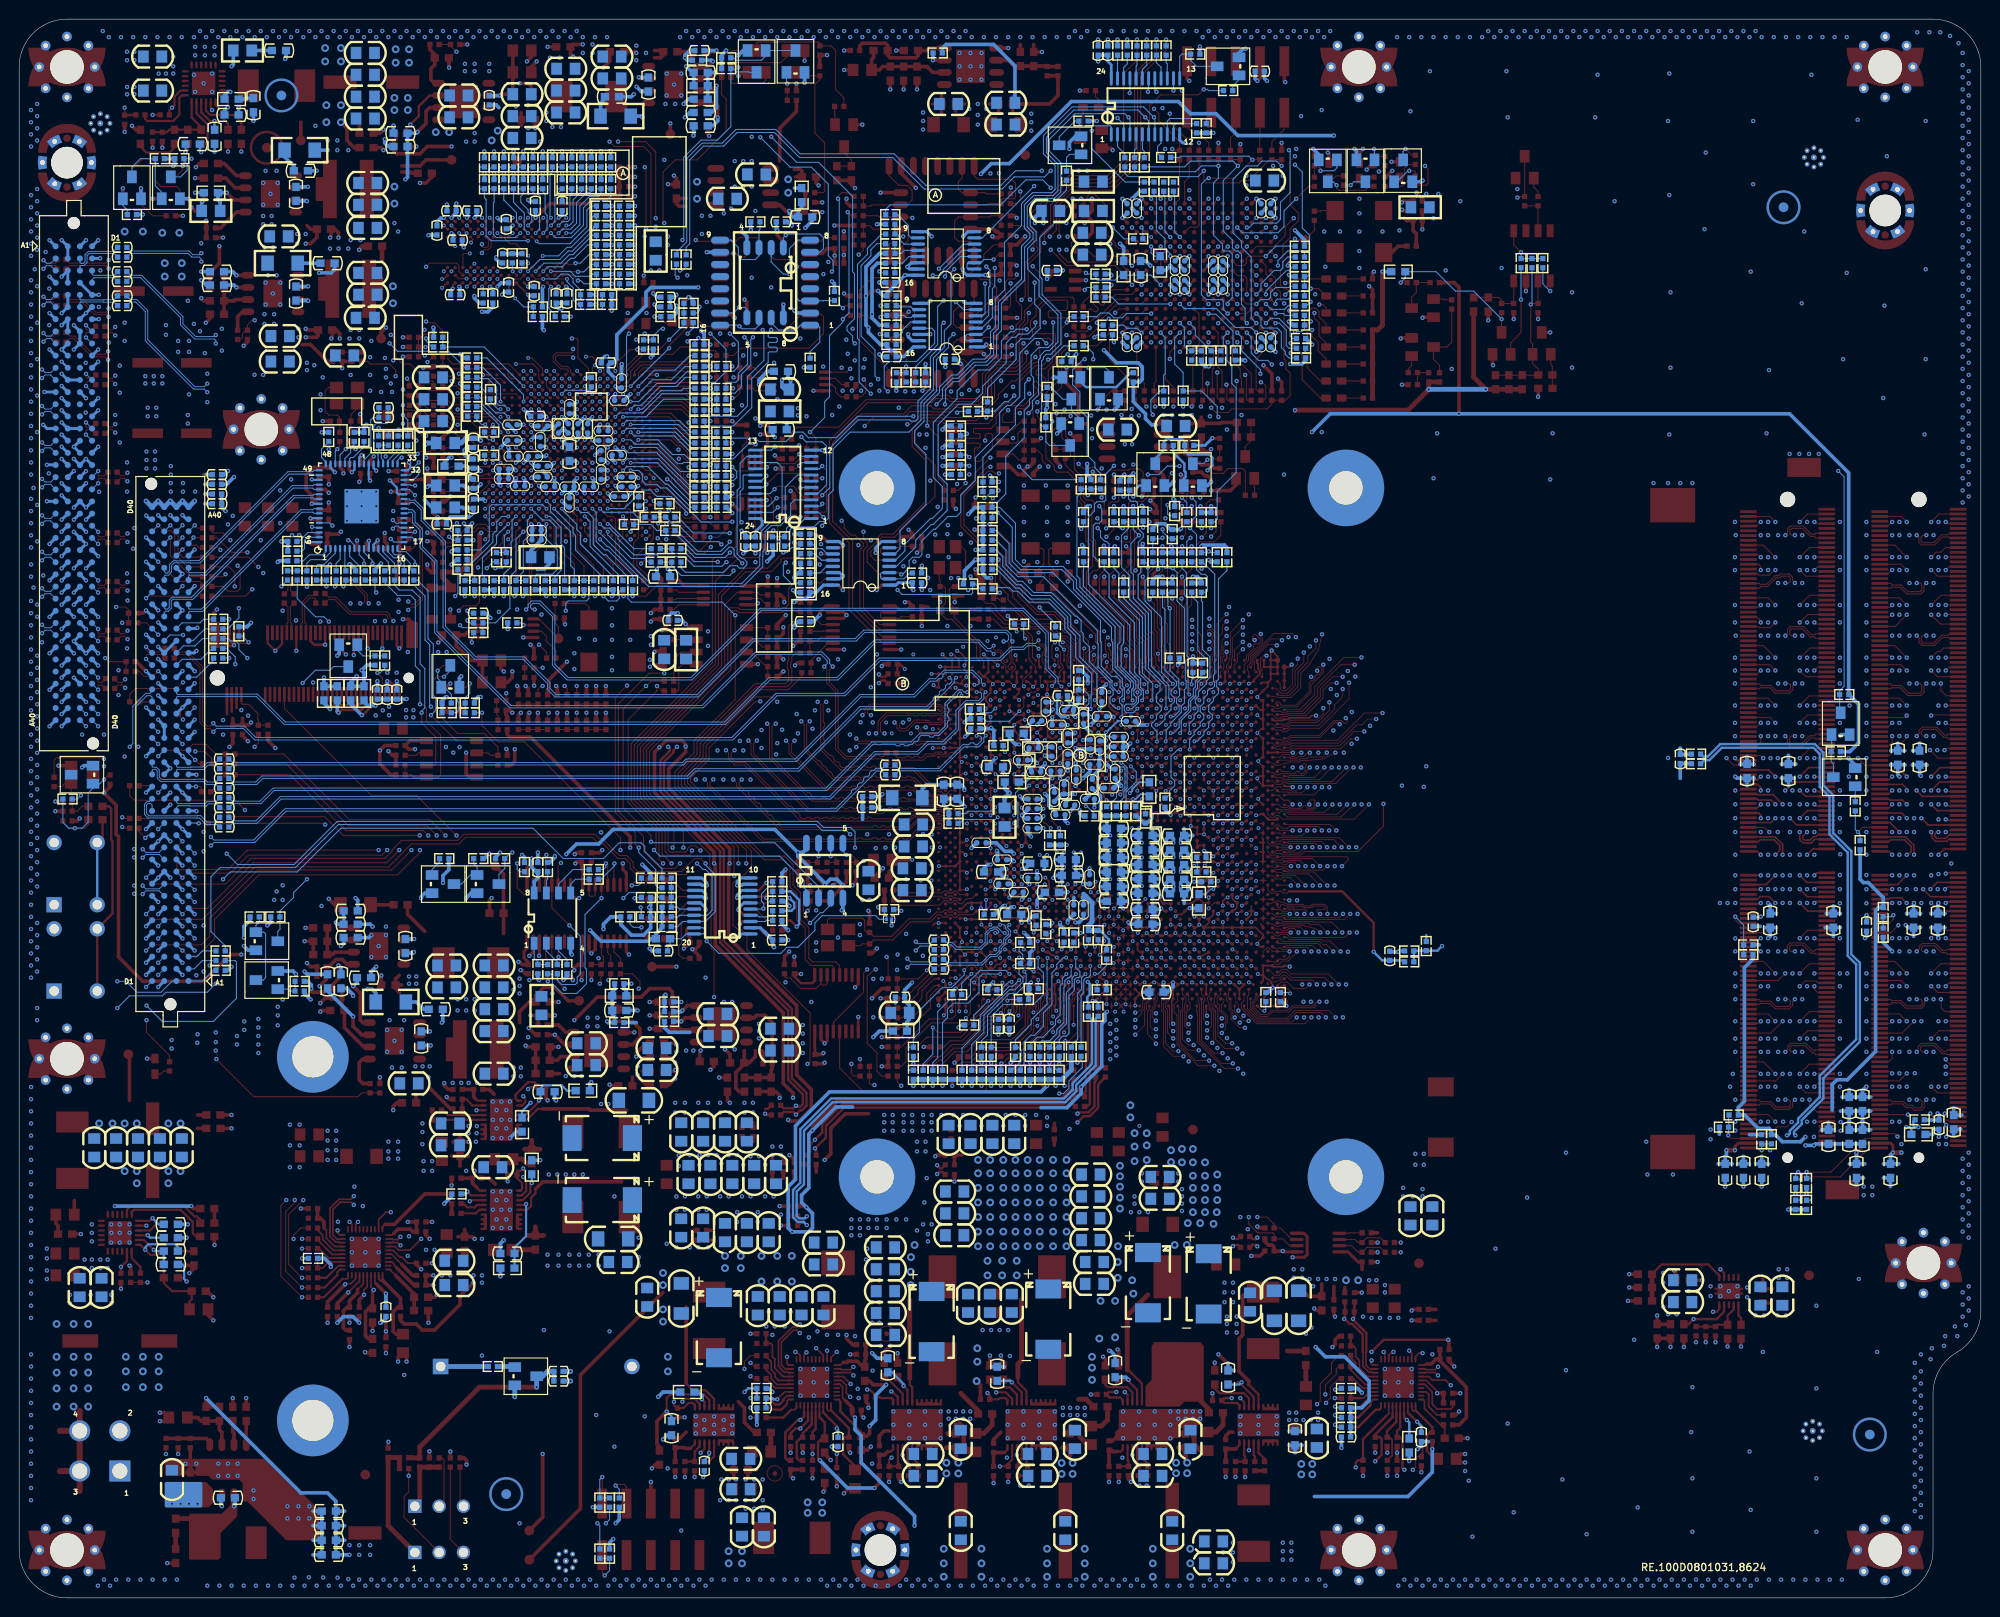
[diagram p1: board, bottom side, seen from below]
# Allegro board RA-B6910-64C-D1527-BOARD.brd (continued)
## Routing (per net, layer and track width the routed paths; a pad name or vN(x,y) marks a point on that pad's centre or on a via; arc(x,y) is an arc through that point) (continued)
SATA_RX_DN3: length 151.5
  TOP w0.099: C731.1 199.72,135.43 198.42,135.43 197.1,134.11 195.89,134.11 v1(195.65,133.88) ; U43.BR33 83.46,82.94 v2(83.18,82.65)
  SIG4 w0.094: v2(83.18,82.65) 83.56,83.04 84.03,83.04 84.25,83.26 84.25,83.65 84.45,83.85 84.8,83.85 84.91,83.74 85.41,83.74 85.77,84.1 85.77,84.48 86.25,84.97 86.25,87.1 86.73,87.57 86.73,88.04 86.27,88.5 86.27,88.82 86.66,89.21 86.66,89.76 86.27,90.15 86.27,90.54 86.71,90.98 86.71,91.36 87.22,91.87 87.22,92.25 87.75,92.78 87.75,93.06 88.25,93.57 88.25,93.97 88.72,94.44 88.72,94.86 88.75,94.89 88.75,100.58 92.35,104.19 106.07,104.19 106.45,104.57 132.11,104.57 136.17,108.64 172.13,108.64 176.45,112.95 177.08,112.95 186.48,122.35 186.48,127.07 193.55,134.14 195.39,134.14 v1(195.65,133.88)
SATA_RX_DN4: length 148.7
  TOP w0.099: v2(84.12,82.63) 84.43,82.94 U43.BN33 ; C733.1 199.72,131.62 199.29,131.62 197.38,129.71 196.02,129.71 v1(195.7,129.39)
  SIG4 w0.094: v2(84.12,82.63) 84.28,82.79 85.73,82.79 86.86,83.92 86.86,85.95 87.24,86.33 87.24,87.09 87.72,87.57 87.72,88.04 87.29,88.48 87.29,88.82 87.72,89.25 87.72,89.8 87.29,90.23 87.29,90.59 88.38,91.69 88.38,92.3 88.74,92.65 88.74,93.09 89.22,93.57 89.22,93.95 89.7,94.43 89.7,94.89 90.03,95.22 90.03,95.75 90.06,95.78 90.06,100.25 92.48,102.67 100.36,102.67 100.86,103.18 132.23,103.18 135.53,106.48 172.87,106.48 188.51,122.12 188.51,127.33 190.78,129.59 195.51,129.59 v1(195.7,129.39)
SATA_RX_DP1: length 115.4
  TOP w0.099: v2(81.66,83.49) 81.96,83.8 U43.BV32 ; C59.1 172.67,104.34 172.01,104.34 170.46,102.79 166.67,102.79 166.49,102.62 166.49,102.38 v1(166.78,102.09)
  SIG4 w0.094: v1(166.78,102.09) 166.46,102.41 166.46,104.78 165.4,105.84 136.19,105.84 132.51,102.16 115.11,102.16 114.85,102.41 102.92,102.41 102.28,101.78 96.19,101.78 95.8,101.4 92.91,101.4 91.99,100.49 91.99,94.52 91.23,93.76 91.23,92.1 90.47,91.34 90.47,89.82 89.2,88.54 89.2,87.98 89.23,87.95 89.23,86.69 88.95,86.41 88.31,86.41 88.06,86.16 88.06,85.4 87.3,84.63 87.3,84 85.77,82.47 84.5,82.47 84.22,82.19 84.02,82.19 83.84,82.37 83.46,82.37 83.33,82.25 83.03,82.25 82.9,82.37 82.44,82.37 82.29,82.22 82.06,82.22 81.81,82.47 81.81,82.86 81.66,83.01 v2(81.66,83.49)
SATA_RX_DP2: length 158.3
  TOP w0.099: v1(195.64,139.82) 195.97,139.5 199.72,139.5 C730.1 ; U43.BT32 82.94,83.8 v2(82.66,83.51)
  SIG4 w0.094: v2(82.66,83.51) 82.66,83.34 82.75,83.24 82.91,83.24 83.04,83.37 83.04,83.68 81.64,85.08 81.64,86.3 82.09,86.75 82.09,87.18 82.56,87.64 82.56,88.02 83.06,88.53 83.06,88.86 83.57,89.37 83.57,89.75 84.08,90.25 84.08,90.63 84.54,91.09 84.54,91.41 84.1,91.84 84.1,92.35 84.59,92.85 84.59,93.21 85.05,93.67 85.05,94.38 85.02,94.41 85.02,95.54 87.17,97.69 87.17,100.76 92.12,105.72 101.39,105.72 101.77,106.1 131.89,106.1 135.7,109.91 158.54,109.91 158.8,110.16 160.96,110.16 161.21,109.91 171.24,109.91 173.66,112.32 173.66,118.03 174.54,118.92 174.54,124.13 177.59,127.18 181.66,127.18 191.92,137.44 191.92,137.8 193.49,139.37 195.5,139.37 195.64,139.51 v1(195.64,139.82)
SATA_RX_DP3: length 151.5
  TOP w0.099: C737.1 199.72,135.69 198.32,135.69 196.99,134.37 195.91,134.37 195.65,134.62 v1(195.65,134.77) ; v2(83.64,83.48) 83.64,83.48 83.96,83.8 84.05,83.8 U43.BP32
  SIG4 w0.094: v1(195.65,134.77) 195.65,134.54 195.5,134.39 193.44,134.39 186.23,127.18 186.23,122.46 176.98,113.21 176.34,113.21 172.03,108.89 136.06,108.89 132,104.83 106.35,104.83 105.96,104.45 92.25,104.45 88.49,100.69 88.49,94.89 88.52,94.86 88.52,94.52 88.06,94.05 88.06,93.65 87.55,93.14 87.55,92.86 87.02,92.33 87.02,91.95 86.52,91.45 86.52,91.06 86.08,90.62 86.08,90.07 86.47,89.68 86.47,89.29 86.08,88.9 86.08,88.42 86.53,87.96 86.53,87.65 86.06,87.18 86.06,85.05 85.58,84.56 85.58,84.18 85.33,83.94 84.99,83.94 84.88,84.05 84.37,84.05 84.05,83.73 84.05,83.34 83.95,83.24 83.74,83.24 83.64,83.33 v2(83.64,83.48)
SATA_RX_DP4: length 148.7
  TOP w0.099: v1(195.7,130.28) 196.02,129.97 197.27,129.97 199.18,131.88 199.72,131.88 199.82,131.98 199.82,131.98 C739.1 ; v2(84.63,83.49) 84.94,83.8 U43.BM32
  SIG4 w0.094: v1(195.7,130.28) 195.7,129.97 195.58,129.85 190.67,129.85 188.26,127.43 188.26,122.23 172.77,106.73 135.43,106.73 132.13,103.43 100.76,103.43 100.25,102.92 92.38,102.92 89.81,100.35 89.81,95.78 89.84,95.75 89.84,95.3 89.51,94.97 89.51,94.51 89.02,94.03 89.02,93.65 88.54,93.17 88.54,92.74 88.18,92.38 88.18,91.77 87.09,90.68 87.09,90.15 87.52,89.72 87.52,89.33 87.09,88.9 87.09,88.4 87.52,87.96 87.52,87.66 87.04,87.17 87.04,86.41 86.66,86.03 86.66,84 85.64,82.98 85.13,82.98 v2(84.63,83.49)
SATA_TX_DN1: length 115.8
  TOP w0.099: v1(169.36,103.94) 169.07,103.94 168.88,104.13 168.88,104.77 170.33,106.22 176.09,106.22 176.65,105.66 176.65,105.31 C61.1 ; v2(82.64,85.21) 82.94,85.51 U43.BT28
  SIG1 w0.094: v2(82.64,85.21) 82.88,84.97 83.4,84.97 83.53,84.84 83.8,84.84 83.94,84.98 84.33,84.98 84.53,84.78 84.79,84.78 84.94,84.93 85.39,84.93 85.53,84.79 85.8,84.79 87.05,86.05 87.05,87.18 87.52,87.65 87.52,87.96 87.1,88.38 87.1,88.91 87.54,89.35 87.54,89.65 87.09,90.11 87.09,90.62 88.23,91.76 88.23,92.45 88.55,92.77 88.55,93.17 89.04,93.67 89.04,94.02 89.51,94.49 89.51,95 89.77,95.26 89.77,95.89 90.24,96.37 90.48,96.37 90.51,96.4 91.95,96.4 94.53,98.98 94.53,99.6 96.84,101.91 102.3,101.91 102.66,102.26 133.88,102.26 137.33,105.72 149.17,105.72 150.18,106.73 152.57,106.73 153.46,105.84 160.29,105.84 160.44,106 160.72,106 160.88,105.84 161.16,105.84 161.32,106 161.6,106 161.76,105.84 162.04,105.84 162.2,106 162.48,106 162.64,105.84 162.92,105.84 163.08,106 163.36,106 163.52,105.84 163.8,105.84 163.96,106 164.24,106 164.4,105.84 164.68,105.84 164.84,106 165.12,106 165.28,105.84 165.56,105.84 165.72,106 166,106 166.16,105.84 166.44,105.84 166.59,106 166.88,106 167.03,105.84 167.32,105.84 167.47,106 167.76,106 167.91,105.84 168.19,105.84 168.83,105.21 168.83,104.19 169.08,103.94 v1(169.36,103.94)
SATA_TX_DN2: length 151.6
  TOP w0.099: v2(83.66,85.23) 83.95,85.51 U43.BP28
  SIG1 w0.094: v2(83.66,85.23) 83.66,85.68 83.81,85.82 83.81,86.23 84.76,87.17 84.76,88.04 84.25,88.54 84.25,88.9 83.78,89.37 83.78,89.65 84.25,90.12 84.25,90.51 84.75,91 84.75,91.47 84.27,91.95 84.27,92.23 84.76,92.71 84.76,93.09 85.26,93.6 85.26,94.39 85.64,94.77 85.64,95.31 85.67,95.34 85.67,95.71 87.3,97.33 87.3,99.37 93.26,105.33 101.9,105.33 102.36,105.79 133.22,105.79 137.08,109.65 148.13,109.65 148.76,110.29 153.21,110.29 153.45,110.04 153.84,109.65 158.54,109.65 158.71,109.82 160.28,109.82 160.45,109.65 170.99,109.65 173.66,112.32 173.66,117.67 174.29,118.31 174.29,125.15 183.69,134.54 183.69,138.38 185.32,140.01 185.61,140.01 v1(185.96,139.66)
  BOTTOM w0.099: v1(185.96,139.66) 185.96,139.92 186.18,140.13 186.97,140.13 187.35,140.51 193.37,140.51 C736.1
SATA_TX_DN3: length 147.3
  TOP w0.099: v2(84.68,85.21) 84.99,85.51 U43.BM28
  SIG1 w0.094: v2(84.68,85.21) 84.68,85.74 84.8,85.86 84.8,86.64 85.7,87.54 85.7,88.03 85.26,88.47 85.26,88.91 84.79,89.37 84.79,89.7 85.26,90.16 85.26,90.54 85.72,91.01 85.72,91.47 85.28,91.91 85.28,92.25 85.77,92.74 85.77,93.12 86.27,93.62 86.27,94.35 86.91,94.99 86.91,95.81 88.44,97.33 88.44,99.01 93.71,104.27 103.06,104.27 103.33,104.54 133.37,104.54 137.46,108.64 148.74,108.64 149.12,109.02 152.98,109.02 153.36,108.64 172.11,108.64 175.31,111.83 175.31,124.41 179.86,128.96 181.28,128.96 183.79,131.47 184.08,131.47 v1(184.45,131.1)
  BOTTOM w0.099: v1(184.45,131.1) 184.45,131.39 184.63,131.57 186.66,131.57 188.13,133.04 188.13,133.8 192.3,137.97 193.37,137.97 C732.1
SATA_TX_DN4: length 143.7
  TOP w0.099: U43.BJ28 85.98,85.51 v2(85.67,85.21)
  SIG1 w0.094: v2(85.67,85.21) 85.52,85.36 85.52,85.52 86.2,86.21 86.2,87 86.72,87.51 86.72,88.06 86.27,88.51 86.27,88.82 86.74,89.29 86.74,89.65 86.27,90.12 86.27,90.55 86.76,91.04 86.76,91.4 87.24,91.88 87.24,92.25 87.75,92.77 87.75,93.09 88.25,93.59 88.25,93.95 88.75,94.44 88.75,95.41 88.77,95.43 88.77,96.29 92.5,100.02 92.5,101.29 93.8,102.58 100.4,102.58 100.99,103.18 133.76,103.18 137.19,106.6 148.23,106.6 149.63,108 152.47,108 153.61,106.86 173.63,106.86 177.16,110.38 177.16,112.8 184.58,120.21 184.58,126.06 184.81,126.29 185.07,126.29 v1(185.34,126.02)
  BOTTOM w0.099: v1(185.34,126.02) 185.66,126.33 186.76,126.33 191.82,131.39 191.82,134.44 192.81,135.43 193.37,135.43 C741.1
SATA_TX_DP1: length 115.8
  TOP w0.099: v2(82.2,86.07) 82.51,86.37 U43.BU26 ; C60.1 176.91,105.31 176.91,105.77 176.2,106.48 170.23,106.48 168.63,104.88 168.63,104.1 v1(168.47,103.94)
  SIG1 w0.094: v1(168.47,103.94) 168.58,104.05 168.58,105.1 168.09,105.59 153.36,105.59 152.47,106.48 150.29,106.48 149.27,105.46 137.44,105.46 133.98,102.01 102.76,102.01 102.41,101.65 96.95,101.65 94.79,99.49 94.79,98.88 92.05,96.14 90.51,96.14 90.48,96.17 90.32,96.17 89.96,95.81 89.96,95.17 89.71,94.92 89.71,94.41 89.24,93.94 89.24,93.58 88.74,93.09 88.74,92.68 88.42,92.36 88.42,91.68 87.28,90.54 87.28,90.19 87.74,89.73 87.74,89.27 87.3,88.83 87.3,88.47 87.72,88.04 87.72,87.57 87.25,87.1 87.25,85.97 85.88,84.6 85.45,84.6 85.31,84.73 85.02,84.73 84.87,84.58 84.45,84.58 84.25,84.78 84.02,84.78 83.89,84.64 83.45,84.64 83.32,84.77 82.51,84.77 82.22,85.06 82.22,86.05 v2(82.2,86.07)
SATA_TX_DP2: length 151.6
  TOP w0.099: v2(83.19,86.07) 83.5,86.37 U43.BR26
  SIG1 w0.094: v2(83.19,86.07) 83.19,85.97 83.36,85.8 83.51,85.8 83.61,85.9 83.61,86.31 84.56,87.25 84.56,87.96 84.05,88.46 84.05,88.82 83.59,89.28 83.59,89.74 84.06,90.2 84.06,90.59 84.55,91.08 84.55,91.39 84.08,91.86 84.08,92.31 84.56,92.79 84.56,93.18 85.07,93.68 85.07,94.47 85.45,94.85 85.45,95.31 85.42,95.34 85.42,95.82 87.04,97.44 87.04,99.47 93.16,105.59 101.8,105.59 102.25,106.05 133.11,106.05 136.97,109.91 148.02,109.91 148.66,110.54 153.31,110.54 153.95,109.91 158.44,109.91 158.6,110.07 160.39,110.07 160.55,109.91 170.88,109.91 173.4,112.42 173.4,117.78 174.04,118.42 174.04,125.25 183.43,134.65 183.43,138.48 185.21,140.26 185.68,140.26 v1(185.96,140.54)
  BOTTOM w0.099: v1(185.96,140.54) 185.97,140.54 186.13,140.39 186.86,140.39 187.24,140.77 193.37,140.77 C735.1
SATA_TX_DP3: length 147.3
  TOP w0.099: v2(84.18,86.07) 84.49,86.37 U43.BN26
  SIG1 w0.094: v1(184.45,131.99) 184.19,131.72 183.69,131.72 181.17,129.21 179.75,129.21 175.05,124.51 175.05,111.94 172,108.89 153.46,108.89 153.08,109.27 149.02,109.27 148.64,108.89 137.36,108.89 133.26,104.8 103.23,104.8 102.96,104.53 93.6,104.53 88.18,99.11 88.18,97.44 86.66,95.91 86.66,95.1 86.08,94.51 86.08,93.7 85.58,93.2 85.58,92.82 85.09,92.33 85.09,91.82 85.53,91.38 85.53,91.09 85.06,90.62 85.06,90.24 84.6,89.78 84.6,89.29 85.06,88.83 85.06,88.39 85.5,87.95 85.5,87.62 84.6,86.73 84.6,85.94 84.44,85.78 84.28,85.78 84.18,85.88 v2(84.18,86.07)
  BOTTOM w0.099: v1(184.45,131.99) 184.61,131.83 186.56,131.83 187.88,133.15 187.88,133.91 192.2,138.23 193.37,138.23 C738.1
SATA_TX_DP4: length 143.7
  TOP w0.099: U43.BL26 85.48,86.37 v2(85.18,86.07)
  SIG1 w0.094: v2(85.18,86.07) 85.78,86.07 86.01,86.29 86.01,87.08 86.52,87.59 86.52,87.98 86.08,88.43 86.08,88.9 86.55,89.37 86.55,89.57 86.08,90.04 86.08,90.63 86.56,91.12 86.56,91.48 87.04,91.96 87.04,92.33 87.56,92.85 87.56,93.17 88.06,93.67 88.06,94.03 88.56,94.53 88.56,95.39 88.52,95.43 88.52,96.39 92.25,100.13 92.25,101.4 93.69,102.84 100.29,102.84 100.88,103.43 133.65,103.43 137.08,106.86 148.13,106.86 149.53,108.26 152.57,108.26 153.72,107.11 173.53,107.11 176.91,110.49 176.91,112.9 184.32,120.32 184.32,126.16 184.7,126.54 185.03,126.54 185.34,126.85 v1(185.34,126.91)
  BOTTOM w0.099: v1(185.34,126.91) 185.66,126.59 186.65,126.59 191.56,131.5 191.56,134.54 192.71,135.69 193.37,135.69 C740.1
SCLK_VCCGBE_P1V05_PCH: length 4.3
  TOP w0.178: U33.20 170.63,33.45 170.74,33.34 171.23,33.34
  TOP w0.229: 171.23,33.34 173.15,31.42 R702.2
SCLK_VCCIN_VCCSCSUS: length 3.9
  TOP w0.178: 124.33,19.66 123.97,19.66 123.77,19.86 U29.20
  TOP w0.254: 124.33,19.66 125.14,18.85 R657.2
SCLK_VDDQ: length 4.3
  TOP w0.178: U36.20 62.68,19.84 62.86,19.66
  TOP w0.254: R740.2 65.07,17.83 63.24,19.66 62.86,19.66
SDIO_VCCGBE_P1V05_PCH: length 3.5
  TOP w0.178: 171.75,33.75 171.75,34.06 171.49,34.32 U33.21
  TOP w0.229: R687.1 173.07,32.44 171.75,33.75
SDIO_VCCIN_VCCSCSUS: length 3.3
  TOP w0.178: U29.21 124.58,20.73 124.76,20.55 124.76,20.24
  TOP w0.254: 124.76,20.24 125.33,19.67 126.35,19.67 126.54,19.86 R642.1
SDIO_VDDQ: length 3.5
  TOP w0.178: 63.8,20.4 63.47,20.73 U36.21
  TOP w0.254: R723.1 65.07,18.85 63.8,20.12 63.8,20.4
SDP0: length 3.5
  BOTTOM w0.109: U26.63 174.87,110.85 175.18,110.54 175.18,109.65 175.43,109.4 R603.2
SDP1: length 2.7
  BOTTOM w0.109: R604.2 175.75,110.41 174.82,111.35 U26.62
SDP2: length 2.1
  TOP w0.109: v1(174.39,111.94) 174.39,111.4 174.16,111.18 R605.2
  BOTTOM w0.109: v1(174.39,111.94) 174.3,111.85 U26.61
SDP3: length 2.3
  TOP w0.109: v1(172.26,112.07) 172.64,112.45 R606.2
  BOTTOM w0.109: U26.60 172.54,112.35 v1(172.26,112.07)
SERIRQ: length 118.7
  SIG1 w0.086: v1(83.49,114.99) 83.49,116.51 84.07,117.09 84.07,117.98 87.68,121.59 91.25,121.59 91.6,121.94 92.04,121.94 92.68,122.58 93.1,122.58 93.46,122.23 93.46,122.04 94.27,121.23 96.96,121.23 97.67,121.94 97.98,121.94 98.6,122.55 102.23,122.55 102.32,122.65 104.23,122.65 104.73,123.15 109.34,123.15 110.42,124.22 112.1,124.22 112.55,123.77 113.98,123.77 114.73,124.51 v1(119.3,124.51)
  SIG3 w0.107: v1(119.3,124.51) 119.02,124.23 119.02,113.94 118.28,113.21 118.28,111.8 116.84,110.35 116.84,109.83 117.14,109.53 117.14,96.57 119.17,94.54 119.17,92.18 120.52,90.83 120.52,88.91 128.6,80.82 139.62,80.82 141.65,78.79 141.65,78.03 142.36,77.32 142.36,73.64 v1(141.86,73.13)
  BOTTOM w0.109: v1(83.49,114.99) 82.98,114.48 R839.1 ; v1(141.86,73.13) 141.28,73.71 138.6,73.71 138.1,73.2 R1088.2
SERIRQ_BMC: length 46.2
  TOP w0.109: v1(141.47,95.35) 142.7,94.12 142.7,82.1 140.64,80.03 140.64,78.79 v1(140.25,78.41)
  SIG3 w0.107: v1(141.47,95.35) 140,96.83 138.62,96.83 137.97,97.49 137.97,100.38 138.3,100.71 138.3,104.88 137.66,105.51 137.66,109.25 136.93,109.99 136.93,111.65 136.62,111.96 136.62,112.53 137.11,113.01 v1(137.11,113.61)
  BOTTOM w0.109: R1090.2 138.22,74.22 138.48,74.47 138.48,76.12 140.25,77.9 v1(140.25,78.41) ; v1(137.11,113.61) 137.08,113.64 R53.1
SERIRQ_CLK: length 58.4
  TOP w0.109: R926.1 114.19,66.83 v1(114.35,66.98) ; v2(99.01,93.52) 99.29,93.24 U43.Y11
  SIG3 w0.107: v2(99.01,93.52) 100.25,93.52 101.01,92.76 101.01,92.13 103.93,89.21 104.44,89.21 105.58,88.06 105.58,87.7 106.85,86.43 106.85,85.4 107.23,85.01 107.23,83.87 110.84,80.26 119.48,80.26 124.58,75.16 127.1,75.16 127.43,74.83 127.43,73.03 127.1,72.7 126.92,72.7 122.27,68.05 121.51,68.05 120.47,67.01 114.38,67.01 v1(114.35,66.98)
SERIRQ_CLK_GTL: length 18.9
  TOP w0.109: v2(110.16,65.58) 111.04,64.69 R926.2 R930.1 ; v2(98.55,68.63) 98.53,68.61 U43.AC67
  SIG1 w0.086: v2(110.16,65.58) 106.65,69.09 99.01,69.09 v2(98.55,68.63)
SERIRQ_DATA: length 32.5
  TOP w0.109: v1(115.49,65.68) 115.64,65.68 116.38,64.95 116.38,57.97 115.36,56.96 115.36,55.04 114.85,54.53 R849.2
  SIG1 w0.086: v1(115.49,65.68) 116.79,66.98 121.71,66.98 122.73,68 122.73,68.48 124.53,70.28 125.47,70.28 v1(127.22,72.03)
  BOTTOM w0.109: U53.5 127.27,71.99 v1(127.22,72.03) 127.17,72.09 127.17,72.57 127.43,72.82 127.43,73.58 126.67,74.35 126.41,74.35 126.26,74.5 R1086.1
SERIRQ_DIR: length 11.5
  TOP w0.089: U43.AD74 97.78,63.6 97.43,63.25 97.43,62.97 97.63,62.76 97.63,62.36 97.49,62.21 97.49,61.69 97.56,61.62 97.56,59.69
  TOP w0.109: R902.2 R843.2 100.38,56.06 97.56,58.88 97.56,59.69
SLP_S3_CPU: length 4
  BOTTOM w0.109: U47.10 111.78,142.14 112.06,142.42 112.06,143.43 113.2,144.58 R1048.2
SLP_S3_CPU_CPLD: length 32.2
  TOP w0.109: U2.A4 v1(76.71,146.23)
  SIG3 w0.107: v1(98.93,147.55) 98.6,147.88 92.38,147.88 92.12,147.63 78.11,147.63 v1(76.71,146.23)
  BOTTOM w0.109: v1(98.93,147.55) 104.34,142.14 U47.7
SLP_S3_CPU_GTL: length 197
  TOP w0.109: U43.AC71 98.34,65.77 v2(98.04,66.06) ; v1(96.61,123.81) 96.61,122.31 97.07,121.84 97.07,120.83 96.69,120.45 R897.1 R893.2
  SIG1 w0.086: v1(96.61,123.81) 98.03,123.81 98.47,123.37 101.65,123.37 102.85,124.57 105.59,124.57 105.77,124.75 107.6,124.75 108.53,125.68 111.1,125.68 v1(111.5,126.09)
  SIG3 w0.107: v2(98.04,66.06) 97.84,65.85 97.84,60 99.74,58.09 108,58.09 108.86,58.95 111.78,58.95 114.28,61.45 116.9,61.45 117.27,61.82 122.4,61.82 123.08,62.51 123.08,63.54 125.38,65.84 126.89,65.84 131.24,70.19 131.24,76.97 130.81,77.39 128.32,77.39 122.22,83.49 113.71,83.49 113.31,83.09 110.68,83.09 109.77,84 109.77,86.03 109.01,86.79 109.01,87.94 108.76,88.19 108.76,89.08 107.74,90.09 107.74,91.75 111.68,95.68 111.68,98.1 112.31,98.73 112.31,100.41 113.93,102.02 113.93,108.68 109.75,112.85 109.75,115.72 108.96,116.51 108.96,123.55 v1(111.5,126.09)
  SIG4 w0.086: v1(97.2,147.37) 94.15,144.32 94.15,142.8 95.04,141.91 95.04,141.15 92.76,138.86 92.76,135.82 94.39,134.18 95.92,134.18 96.44,133.66 96.44,131.26 96.84,130.86 96.84,128.69 97.84,127.69 97.84,125.72 97.2,125.08 97.2,124.64 96.61,124.04 v1(96.61,123.81)
  BOTTOM w0.109: R1048.1 114.45,145.11 113.97,145.59 102.41,145.59 99.81,148.2 98.03,148.2 v1(97.2,147.37)
SMB_CPU_ALERT_N: length 13.8
  TOP w0.109: v2(86.66,93.8) 86.64,93.82 U43.BH7
  BOTTOM w0.109: R981.2 89.58,104.45 87.62,102.48 87.62,96.64 86.53,95.56 86.53,93.93 v2(86.66,93.8)
SMB_CPU_SCL: length 246.9
  TOP w0.109: R457.2 v1(164.89,123.62) ; R1005.2 98.6,121.97 98.34,122.23 98.34,123.24 98.6,123.5 v1(98.6,124) 96.06,126.54 96.06,130.09 95.3,130.86 R61.2 ; v1(194.23,80.57) 194.1,80.44 R172.2 ; v2(85.16,92.95) 84.87,93.24 U43.BN11
  SIG3 w0.107: v1(194.23,80.57) 193.59,81.2 193.59,86.8 194.45,87.66 194.45,93.19 192.6,95.04 192.6,108.36 192.07,108.89 186.61,108.89 184.4,111.1 184.4,113.26 183.52,114.14 180.04,114.14 173.48,120.7 170.47,120.7 169.7,121.46 167.05,121.46 v1(164.89,123.62) ; v1(98.6,124) 98.47,123.88 97.2,123.88 96.82,124.26 96.31,124.26 95.65,124.92 88.69,124.92 87.25,123.47 87.25,123.26 86.53,122.55 86.53,116.51 87.18,115.87 87.18,114.99 87.35,114.82 87.35,114.45 87.22,114.32 87.22,113.97 88.03,113.16 88.03,111.1 v1(87.98,111.05)
  SIG4 w0.086: v1(164.89,123.62) 163.73,124.78 163.73,128.71 163.37,129.08 163.37,145.72 161.03,148.06 143.01,148.06 141.69,149.37 141.69,149.9 140.25,151.33 124.53,151.33 121.2,148.01 102.28,148.01 101.98,148.31 100.81,148.31 99.94,147.44 99.94,146.28 100.32,145.9 100.32,137.42 102.66,135.08 102.66,128.83 103.3,128.19 103.3,126.04 102.13,124.87 99.46,124.87 v1(98.6,124)
  BOTTOM w0.109: R47.2 164.38,123.11 v1(164.89,123.62) ; v2(85.16,92.95) 85.16,95.32 86.99,97.16 86.99,102.87 88.57,104.45 88.57,106.93 88.82,107.19 88.82,110.21 v1(87.98,111.05) 88.57,111.63 R980.2
SMB_CPU_SDA: length 249.2
  TOP w0.109: v2(86.64,92.1) 86.36,92.38 U43.BJ13 ; v1(95.53,133.3) 95.53,133.22 96.06,132.69 96.06,130.61 96.38,130.29 96.38,127.24 98.6,125.02 v1(98.6,124.97) 99.06,124.51 99.06,123.32 99.01,123.27 R1006.2 ; R459.2 162.36,123.62 162.48,123.75 162.48,123.75 162.86,124.13 164.59,124.13 164.89,124.43 v1(164.89,124.64) ; R173.1 194.1,81.46 v1(194.23,81.59)
  SIG3 w0.107: v1(194.23,81.59) 193.98,81.84 193.98,86.79 194.74,87.55 194.74,93.29 192.88,95.15 192.88,109.09 191.69,110.29 186.36,110.29 184.78,111.86 184.78,113.28 183.61,114.45 180.12,114.45 173.59,120.99 170.7,120.99 169.72,121.97 167.74,121.97 v1(167.43,122.28) 166.87,122.28 166.04,123.11 166.04,123.5 v1(164.89,124.64) ; v1(98.6,124.97) 98.34,125.22 88.61,125.22 86.97,123.58 86.97,123.37 85.91,122.32 85.91,115.99 86.32,115.59 86.32,113.59 86.57,113.34 87.26,113.34 87.76,112.84 87.76,112.07 v1(87.55,111.86) 87.15,111.46 87.15,109.13 86.41,108.38 86.41,107.62 86.64,107.39 86.64,105.74 87.32,105.05 87.32,103.33 86.77,102.78 86.77,95.83 86.64,95.7 86.64,95.25 86.25,94.86 86.25,93.56 86.52,93.28 86.52,92.22 v2(86.64,92.1)
  SIG4 w0.086: v1(98.6,124.97) 98.62,124.94 98.83,125.15 102.01,125.15 103.02,126.15 103.02,128.08 102.38,128.71 102.38,134.95 100.02,137.31 100.02,141.52 99.43,142.11 99.43,142.62 99.67,142.85 99.67,147.55 100.7,148.58 102.09,148.58 102.39,148.28 121.09,148.28 124.42,151.61 140.37,151.61 141.96,150.01 141.96,149.49 143.12,148.33 161.14,148.33 163.69,145.79 163.69,129.14 164,128.83 164,125.53 v1(164.89,124.64)
  BOTTOM w0.109: R81.2 95.27,133.91 95.53,133.66 v1(95.53,133.3) ; R46.2 v1(167.43,122.28) ; R979.2 v1(87.55,111.86)
SMB_DDR_ABC_SCL: length 48.5
  TOP w0.109: v2(79.71,71.49) 79.42,71.78 U43.CD58 ; U54.2 72.24,36.81 72.94,37.52 R1092.2 73.86,38.02 73.99,38.15 75.59,38.15 76.5,39.07 v1(76.5,39.8)
  SIG4 w0.086: v1(76.5,39.8) 76.5,43.23 87.55,54.28 87.55,62.54 86.28,63.81 84.12,63.81 83.87,64.06 83.87,64.44 83.23,65.08 83.23,65.33 82.6,65.96 82.6,66.35 82.22,66.73 82.22,67.11 81.71,67.62 81.71,67.87 81.2,68.38 81.2,68.89 80.69,69.39 80.69,70.79 79.99,71.49 v2(79.71,71.49)
SMB_DDR_ABC_SDA: length 46.4
  TOP w0.109: U54.3 72,37.46 73.2,38.66 R1091.2 73.86,39.07 74.6,39.8 v1(75.61,39.8) ; U43.CC60 79.92,70.92 v2(80.2,70.63)
  SIG4 w0.086: v2(80.2,70.63) 79.68,70.11 79.68,69.39 80.18,68.89 80.18,68.5 80.82,67.87 80.82,67.49 81.2,67.11 81.2,66.73 81.71,66.22 81.71,65.96 82.22,65.46 82.22,65.08 82.85,64.44 82.85,64.19 83.61,63.42 86.18,63.42 87.17,62.43 87.17,54.53 75.61,42.98 v1(75.61,39.8)
SMB_PWR_ALERT_N: length 66.2
  TOP w0.109: v2(89.12,94.69) 89.12,94.67 89.12,94.66 U43.BC9 ; U2.P11 v1(84.71,132.23)
  SIG1 w0.086: v1(96.95,133.3) 96.34,133.3 95.86,132.82 95.25,132.82 94.79,133.27 93.01,133.27 92.5,132.77 92.12,132.77 91.99,132.89 91.11,132.89 89.96,131.75 85.18,131.75 v1(84.71,132.23)
  BOTTOM w0.109: v2(89.12,94.69) 89.12,94.95 88.86,95.21 88.86,95.71 90.47,97.32 90.47,101.53 94.5,105.55 94.5,106.39 95.91,107.8 100.17,107.8 100.88,108.51 100.88,112.32 102.54,113.97 R868.2 103.32,114.33 103.17,114.48 102.79,114.48 101.9,115.37 101.9,119.3 99.97,121.23 99.97,124.09 99.42,124.64 99.42,125.24 98.99,125.67 98.99,127.55 99.25,127.8 99.25,129.88 98.45,130.67 97.48,130.67 96.95,131.2 v1(96.95,133.3)
SMB_SENSOR_CLK: length 117.3
  TOP w0.109: v1(163.37,119.56) 163.11,119.81 162.07,119.81 R455.2 R473.1 ; v1(138.98,79.02) 138.98,79.68 141.88,82.58 141.88,92.92 v1(139.49,95.3) 138.98,95.81 R331.2
  SIG2 w0.107: v1(163.37,119.56) 164.13,120.32 168.35,120.32 168.86,120.83 173.91,120.83 178.48,116.26 178.48,102.79 176.83,101.14 165.27,101.14 163.45,99.31 160.78,99.31 v1(160.32,98.86)
  SIG4 w0.086: v1(160.32,98.86) 159.95,98.86 156.9,95.81 140,95.81 v1(139.49,95.3)
  BOTTOM w0.109: U18.2 121.46,74.35 126.03,78.92 138.87,78.92 v1(138.98,79.02)
SMB_SENSOR_DATA: length 120.1
  TOP w0.109: R332.2 137.84,94.79 v1(138.35,95.3) 138.35,94.79 141.36,91.79 141.36,83.13 138.45,80.22 138.45,78.37 v1(138.65,78.16) ; v1(162.48,121.46) 162.86,121.46 163.27,121.87 R475.1 R456.2
  SIG2 w0.107: v1(164.38,98.86) 164.38,99.62 165.4,100.64 176.96,100.64 178.93,102.61 178.93,116.43 174.09,121.28 168.68,121.28 168.17,120.77 164.74,120.77 164.05,121.46 v1(162.48,121.46)
  SIG4 w0.086: v1(138.35,95.3) 139.32,96.27 156.71,96.27 159.76,99.31 163.93,99.31 v1(164.38,98.86)
  BOTTOM w0.109: v1(138.65,78.16) 138.02,77.52 125.52,77.52 122.98,74.98 122.98,74.22 122.73,73.97 U18.1
SMI_MDC: length 75.2
  TOP w0.109: v1(133.27,76.76) 133.78,77.27 134.41,77.27 135.76,75.92 140.37,75.92 140.83,76.38 140.83,76.89 141.52,77.58 142.28,77.58 144.03,79.33 144.35,79.33 144.83,79.81 158.54,79.81 159.18,79.17 165.02,79.17 166.04,78.16 166.04,78.03 166.77,77.29 180.74,77.29 183.43,74.6 191.07,74.6 v1(191.74,75.27)
  BOTTOM w0.109: R1081.2 136.19,70.16 135.66,70.69 U53.18 133.29,70.69 132.25,71.73 132.25,75.58 133.27,76.59 v1(133.27,76.76) ; U4.D10 v1(191.74,75.27)
SMI_MDIO: length 74.9
  TOP w0.109: v1(191.74,71.46) 191.2,70.92 185.85,70.92 180.38,76.39 166.41,76.39 164,78.79 159.05,78.79 158.35,79.49 145.08,79.49 144.38,78.79 143.94,78.79 142.41,77.27 141.65,77.27 141.14,76.76 141.14,76.25 140.48,75.59 135.33,75.59 v1(134.16,76.76)
  BOTTOM w0.109: v1(134.16,76.76) 133.52,76.12 133.27,76.12 132.58,75.44 132.58,71.86 133.1,71.34 U53.17 136.02,71.34 136.19,71.17 R1082.2 ; U4.D7 v1(191.74,71.46)
SML1_CLK: length 74.1
  TOP w0.109: v1(125.62,110.41) 125.73,110.52 125.73,112.08 126.18,112.53 126.18,114.25 126.36,114.43 126.36,114.94 126.79,115.37 129.71,115.37 130.09,114.99 R444.2 ; U43.BG9 87.33,94.1 87.63,93.8 v2(87.65,93.8)
  SIG1 w0.086: v1(92.12,114.1) 92.76,114.73 93.52,114.73 93.9,115.11 93.9,115.93 94.74,116.76 100.63,116.76 100.83,116.56 100.83,115.29 102.08,114.05 105.34,114.05 105.56,114.27 107.6,114.27 108.33,113.54 109.52,113.54 114.34,108.72 120.14,108.72 121.08,109.65 124.86,109.65 v1(125.62,110.41)
  BOTTOM w0.109: v2(87.65,93.8) 87.52,93.93 87.52,94.89 87.8,95.16 87.8,96.06 88.44,96.7 88.44,101.91 91.11,104.57 91.11,106.99 91.61,107.49 R882.2 92.15,108.28 92.76,108.89 92.76,112.07 92.5,112.32 92.12,112.32 91.87,112.57 91.87,113.84 v1(92.12,114.1)
SML1_DATA: length 70.1
  TOP w0.109: U43.BB11 89.61,93.78 v2(89.63,93.8)
  SIG2 w0.107: v1(102.75,113.42) 101.9,114.27 101.9,116.64 102.36,117.09 102.86,117.09 103.05,117.27 103.05,122.48 v1(103.93,123.37)
  SIG4 w0.086: v1(111.55,123.5) 111.43,123.37 v1(103.93,123.37)
  BOTTOM w0.109: v1(111.55,123.5) 117.4,123.5 119.63,121.26 122.53,121.26 123.11,121.84 123.87,121.84 124.86,120.85 127.68,120.85 128.04,121.21 130.98,121.21 131.14,121.06 R445.2 ; R880.2 103.32,113.18 103.08,113.42 v1(102.75,113.42) 101.22,111.89 101.22,108.33 100.35,107.47 96.03,107.47 94.81,106.25 94.81,105.42 90.85,101.46 90.85,100 90.72,99.87 90.72,97.08 89.71,96.06 89.71,95.28 89.5,95.07 89.5,93.93 v2(89.63,93.8)
SML1ALERT_N: length 48.3
  TOP w0.109: U43.BF7 87.42,94.96 v2(87.14,94.67)
  SIG2 w0.107: v1(101.01,125.65) 100.63,125.27 98.98,125.27 98.6,125.65 96.57,125.65 95.68,124.77 91.94,124.77 v1(91.36,124.18)
  SIG3 w0.107: v1(91.36,124.18) 91.39,124.16 91.39,114.89 91.59,114.68 91.59,112.34 92.12,111.81 v1(92.3,111.81)
  BOTTOM w0.109: v1(92.3,111.81) 91.99,111.51 91.99,110.87 91.54,110.41 91.36,110.41 91.11,110.16 91.11,108.38 91,108.28 R879.2 90.6,107.62 90.09,107.11 90.09,104.32 87.94,102.16 87.94,96.58 87.04,95.68 87.04,94.77 v2(87.14,94.67) ; R437.2 104.21,124 104.19,124.03 R98.1 103.02,124.03 102.03,125.02 101.65,125.02 v1(101.01,125.65)
SMLINK0_ALERT_N: length 113.9
  TOP w0.109: v2(84.43,95.53) 84.6,95.35 85.26,95.35 U43.BL7
  SIG1 w0.086: v1(87.04,107.7) 87.04,108.89 88.69,110.54 88.69,111.56 91.11,113.97 91.11,115.11 92.23,116.24 93.12,116.24 94.38,117.5 100.94,117.5 101.65,116.79 101.65,115.75 102.15,115.24 102.79,115.24 103.04,115.49 108.52,115.49 v1(109.79,116.76)
  SIG3 w0.107: v1(109.79,116.76) 109.79,119.05 113.08,122.34 v1(113.08,124.38)
  SIG4 w0.086: v1(164.89,122.71) 160.3,122.71 159.18,121.59 158.54,121.59 156.76,119.81 137.62,119.81 136.4,118.59 135.89,118.59 135.43,119.05 128.06,119.05 126.28,120.83 125.4,120.83 124.38,121.84 123.11,121.84 122.6,121.34 120.06,121.34 117.01,124.38 v1(113.08,124.38)
  BOTTOM w0.109: v2(84.43,95.53) 85.62,96.72 85.62,102.47 87.35,104.19 87.35,106.3 87.04,106.6 v1(87.04,107.7) 87.04,108 87.32,108.28 R883.2 ; v1(164.89,122.71) 164.89,121.56 165.02,121.44 R50.2
SMLINK0_CLK: length 17.6
  TOP w0.109: v2(82.72,94.41) 82.88,94.41 83.42,94.96 U43.BR7
  BOTTOM w0.109: v2(82.72,94.41) 82.84,94.54 82.84,98.34 82.95,98.45 82.95,104.55 83.23,104.83 83.23,106.35 83.03,106.55 83.03,107.16 83.49,107.62 R889.1 ; R48.2 R889.1 ; R889.1 R885.2
SMLINK0_DATA: length 121.5
  TOP w0.109: v2(85.19,89.51) 84.89,89.81 U43.BN18
  SIG1 w0.086: v1(135.05,118.16) 134.16,119.05 132.63,119.05 131.87,119.81 131.87,120.07 130.6,121.34 129.97,121.34 129.26,122.05 126.84,122.05 125.86,123.03 119.89,123.03 119.55,123.37 114.35,123.37 114.21,123.22 112.04,123.22 111.77,122.95 109.92,122.95 109.57,122.61 105.08,122.61 104.52,122.05 102.61,122.05 102.28,121.72 99.87,121.72 98.83,120.68 91.34,120.68 90.6,119.94 87.98,119.94 85.62,117.58 85.62,114.05 85.29,113.72 84.89,113.72 84.25,113.08 84.25,110.65 83.99,110.4 83.99,108.38 84.48,107.9 84.48,107.65 v1(84.45,107.62)
  SIG4 w0.086: v1(165.35,122.1) 161.97,122.1 161.08,121.21 158.67,121.21 156.89,119.43 150.92,119.43 150.54,119.05 137.24,119.05 136.35,118.16 v1(135.05,118.16)
  BOTTOM w0.109: v1(165.35,122.1) 166.16,122.1 166.42,121.84 R49.2 ; v2(85.19,89.51) 85.19,89.6 85.14,89.65 85.14,90.7 84.65,91.19 84.65,91.44 83.56,92.54 83.56,93.2 83.23,93.52 83.23,94.92 83.05,95.1 83.05,95.86 83.13,95.94 83.13,97.99 83.23,98.1 83.23,103.43 83.99,104.19 83.99,107.16 v1(84.45,107.62) 85.26,107.62 85.52,107.87 R884.2 R887.1
SPI_BMC_CK: length 32.6
  TOP w0.109: U20.C15 v2(144.29,112.23)
  SIG4 w0.086: v1(123.36,116.89) 123.87,116.38 126.18,116.38 128.72,113.84 130.86,113.84 132,112.7 132,110.92 132.25,110.67 132.25,109.53 131.09,108.36 v1(131.09,108.26)
  BOTTOM w0.109: v1(131.09,108.26) 131.11,108.26 131.54,107.82 134.49,107.82 135.51,108.84 138.17,108.84 138.35,109.02 140.76,109.02 142.41,110.67 142.41,110.92 143.3,111.81 143.87,111.81 v2(144.29,112.23) ; U61.7 123.18,116.71 v1(123.36,116.89)
SPI_BMC_CS0_N: length 33.4
  TOP w0.109: U20.B15 v2(144.29,111.43)
  BOTTOM w0.109: v2(144.29,111.43) 144.29,111.28 139.04,106.03 129.48,106.03 127.61,107.9 127.61,108.97 127.59,108.98 127.59,109.55 127.43,109.71 127.43,111.49 126.54,112.38 125.59,112.38 124.94,113.03 124.94,116.08 123.66,117.36 U61.8
SPI_BMC_EN: length 72.6
  TOP w0.109: U20.D14 v2(145.89,113.83)
  SIG1 w0.086: v2(145.89,113.83) 145.85,113.83 145.46,114.22 141.52,114.22 139.9,115.85 139.9,117.25 138.6,118.54 138.6,120.7 133.52,125.78 132.51,125.78 131.82,126.47 131.82,128.63 129.84,130.61 129.84,131.88 128.44,133.27 128.44,135.56 126.56,137.44 120.98,137.44 120.37,138.05 116.58,138.05 115.59,137.06 112.9,137.06 110.39,134.54 106.85,134.54 105.66,133.35 99.4,133.35 99.02,133.73 92.83,133.73 v1(92.38,133.27)
  BOTTOM w0.109: R1131.2 92.12,133.02 v1(92.38,133.27)
SPI_BMC_MISO: length 31.1
  TOP w0.109: U20.A15 v2(144.29,110.63)
  BOTTOM w0.109: v2(144.29,110.63) 143.54,109.88 143.4,109.88 139.24,105.72 129.33,105.72 127.29,107.76 127.29,108.84 127.28,108.85 127.28,109.4 127.05,109.63 127.05,111.43 126.41,112.07 125.46,112.07 124.38,113.14 124.38,114.35 123.97,114.76 U61.4
SPI_BMC_MOSI: length 32.2
  TOP w0.109: v2(145.89,112.23) 145.89,111.43 U20.A14
  SIG4 w0.086: v1(121.08,114.35) 121.71,114.99 121.71,115.88 123.19,117.35 124.68,117.35 125.2,116.84 127.63,116.84 128.5,117.71 137.46,117.71 139.62,115.54 139.62,115.37 140.76,114.22 142.03,114.22 142.92,113.34 144.79,113.34 v2(145.89,112.23)
  BOTTOM w0.109: v1(121.08,114.35) 121.08,114.23 121.2,114.11 U61.3
SPI_BMC_OE: length 75.9
  TOP w0.109: v1(75.71,142.23) U2.E2
  SIG1 w0.086: v1(107.29,138.86) 105.76,140.39 87.8,140.39 87.68,140.26 85.77,140.26 85.16,140.87 85.16,141.63 85.01,141.78 76.15,141.78 v1(75.71,142.23)
  BOTTOM w0.109: v1(107.29,138.86) 107.62,138.53 107.62,133.15 108.32,132.45 108.32,130.73 109.46,129.59 109.46,126.23 110.76,124.93 110.76,123.08 112,121.84 118.16,121.84 119.93,120.07 119.93,115.75 120.44,115.24 120.44,112.83 120.77,112.5 121.37,112.5 121.93,111.94 124.13,111.94 124.46,111.61 124.46,110.21 124.74,109.93 R1132.1
SPI_CLK_0: length 11.1
  TOP w0.109: R768.1 103.42,134.8 104.44,133.78 104.44,133.27 104.95,132.77 U40.6 106.98,132.77 107.36,133.15 107.36,134.42 106.85,134.93 105.58,134.93 105.2,135.31 U39.16
SPI_CLK_1: length 12.4
  TOP w0.109: U42.6 103.81,145.59 103.68,145.72 R778.1 102.38,146.1 102.26,146.23 101.01,146.23 100.88,146.36 100.88,147.88 101.27,148.26 104.82,148.26 105.2,148.64 U41.16
SPI_CPU_OE: length 64.3
  TOP w0.109: R1133.2 124.28,121.82 123.74,122.35 119.38,122.35 116.51,125.22 109.77,125.22 109.32,125.68 107.9,125.68 107.56,125.35 104.96,125.35 104.34,125.97 104.34,127.91 103.06,129.19 101.12,129.19 100.81,129.5 100.81,131.83 100.48,132.16 100.48,132.92 99.93,133.47 99.93,134.48 98.34,136.07 98.34,138.44 v1(99.08,139.17) ; U2.E3 v1(76.71,141.23)
  SIG3 w0.107: v1(99.08,139.17) 98.5,139.75 82.47,139.75 81.71,140.51 81.71,140.89 80.92,141.68 77.16,141.68 v1(76.71,141.23)
SPI_CS_CPLD: length 50.6
  TOP w0.109: U2.P15 v1(88.71,132.23) ; R1129.2 R1130.2 121.2,114.99 121.08,115.11 v1(121.08,115.24)
  SIG3 w0.107: v1(108.38,133.27) 105.58,133.27 104.61,132.3 101.11,132.3 100.36,133.05 99.34,133.05 99.16,132.87 95.2,132.87 94.79,133.27 93.01,133.27 92.5,132.77 89.48,132.77 88.94,132.23 v1(88.71,132.23)
  BOTTOM w0.109: v1(121.08,115.24) 120.29,116.03 120.29,120.16 117.33,123.11 111.93,123.11 111.81,122.99 111.3,122.99 111.08,123.21 111.08,125.06 109.77,126.37 109.77,129.72 108.63,130.86 108.63,133.02 v1(108.38,133.27)
SPI_CS_N_0: length 5.6
  TOP w0.109: U39.7 112.82,128.19 v1(112.31,128.7) 112.31,130.1 112.44,130.23 U40.1
  BOTTOM w0.109: v1(112.31,128.7) R763.2 R761.1
SPI_CS_N_1: length 8.8
  TOP w0.109: U41.7 112.82,141.15 112.11,141.86 112.11,142.75 112.42,143.05 U42.1 115.74,143.05 116.12,143.43 R771.1 R773.2
SPI_HOLD#: length 9.9
  BOTTOM w0.109: U24.7 126.41,133.27 125.65,132.51 123.87,132.51 123.36,133.02 U22.1 121.59,133.02 121.33,132.77 121.33,131.24 122.35,130.23 R484.2
SPI_HOLD#S: length 9.3
  TOP w0.109: R519.1 120.82,142.16 121.2,141.78 123.87,141.78 124,141.66 124,140.39 124.51,139.88 126.03,139.88 126.41,140.26 U25.7
SPI_HOLD_N_0: length 10.7
  TOP w0.109: U39.1 105.2,128.32 106.35,129.46 106.98,129.46 107.36,129.85 107.36,131.12 106.98,131.5 U40.7 104.44,131.5 104.19,131.75 R766.1 R762.1
SPI_HOLD_N_1: length 11.3
  TOP w0.109: R776.1 R772.1 103.42,144.45 103.55,144.32 U42.7 106.85,144.32 107.23,143.94 107.23,142.16 106.85,141.78 105.58,141.78 105.2,141.4 U41.1
SPI_IO2: length 14.8
  TOP w0.109: v1(119.43,146.23) 119.43,146.48 119.05,146.86 118.41,146.86 118.03,146.48 R777.1 ; v1(118.92,134.8) 118.66,135.05 R767.1
  BOTTOM w0.109: v1(119.43,146.23) 119.3,146.1 119.3,135.18 v1(118.92,134.8)
SPI_IO3: length 15.1
  TOP w0.109: R766.2 101.39,131.75 100.81,132.33 100.81,133.05 100.25,133.6 100.25,135.03 100.81,135.59 100.81,137.16 100.25,137.72 100.25,141.28 99.43,142.1 99.43,142.74 100.12,143.43 R776.2
SPI_MISO_0: length 12.8
  TOP w0.109: U39.8 114.09,128.33 117.17,131.4 R765.2 116.37,134.04 113.83,131.5 U40.2
SPI_MISO_1: length 10.5
  TOP w0.109: v1(112.62,142.29) 113.2,142.29 114.09,141.4 U41.8 ; R774.2 115.24,144.45 115.11,144.32 U42.2 111.76,144.32 v1(111.65,144.22)
  SIG4 w0.086: v1(111.65,144.22) 111.65,143.26 v1(112.62,142.29)
SPI_MOSI_0: length 10
  TOP w0.109: U39.15 106.47,137.59 105.99,138.07 104.8,138.07 104.53,137.81 103.77,137.81 102.85,136.89 102.85,135.85 R769.1 103.3,135.81 105.08,134.04 U40.5
SPI_MOSI_1: length 7.3
  TOP w0.109: U41.15 106.47,148.39 106.85,148.01 106.85,147.24 106.47,146.86 U42.5 104.06,146.86 103.93,146.74 R779.1
SPI_RST#: length 8.8
  TOP w0.109: v1(123.74,139.12) 123.62,139.24 U23.3
  BOTTOM w0.109: R483.2 120.95,135.59 120.98,135.56 U22.3 123.49,135.56 123.74,135.81 v1(123.74,139.12)
SPI_SSB_BMC_CLK: length 5.6
  TOP w0.109: U20.E15 v2(144.29,113.83)
  BOTTOM w0.109: v2(144.29,113.83) 143.92,113.46 140.89,113.46 140.38,112.95 R872.2
SPI_SSB_BMC_MISO: length 6.2
  TOP w0.109: U20.C16 v2(143.49,112.23)
  BOTTOM w0.109: v2(143.49,112.23) 143.34,112.23 140.76,109.65 R878.2
SPI_SSB_BMC_MOSI: length 6.6
  TOP w0.109: U20.B16 v2(143.49,111.43)
  BOTTOM w0.109: v2(143.49,111.43) 143.49,111.11 141.02,108.64 139.62,108.64 139.24,108.26 R867.2
SPI_SSB_CLK: length 92.2
  TOP w0.109: v2(87.63,92.1) 87.35,92.38 U43.BG13
  SIG1 w0.086: v1(88.57,118.44) 88.92,118.8 91.11,118.8 92,119.69 108.88,119.69 109.27,119.3 111.68,119.3 113.2,120.83 117.14,120.83 120.44,117.53 124.52,117.53 124.62,117.42 124.62,116.62 124.73,116.51 124.94,116.51 125.05,116.62 125.05,117.42 125.16,117.53 125.37,117.53 125.48,117.42 125.48,116.62 125.58,116.51 125.8,116.51 125.9,116.62 125.9,117.42 126.01,117.53 126.41,117.53 126.59,117.71 127.25,117.71 129.97,114.99 130.6,114.99 131.24,114.35 131.24,110.49 v1(131.62,110.11)
  SIG3 w0.107: v2(87.63,92.1) 87.5,92.23 87.5,93.32 87.27,93.55 87.27,94 87.53,94.26 87.53,94.95 87.86,95.28 87.86,96.2 87.65,96.42 87.65,102.38 88.64,103.37 88.64,106.02 88.18,106.48 88.18,106.86 87.91,107.13 87.91,108.1 88.46,108.64 88.46,110.27 88.9,110.72 88.9,112.27 89.07,112.45 89.07,115.49 88.11,116.46 88.11,117.98 v1(88.57,118.44)
  BOTTOM w0.109: R872.1 R875.1 136.67,112.19 136.17,112.19 134.36,110.39 131.9,110.39 v1(131.62,110.11)
SPI_SSB_CS0_BMC_N: length 1.5
  TOP w0.109: v2(141.89,113.03) 141.89,113.03 U20.C18
  BOTTOM w0.109: R860.2 141.75,112.89 v2(141.89,113.03)
SPI_SSB_CS0_CPLD_N: length 14.4
  SIG1 w0.086: v1(126.89,114.73) 126.89,114.38 129.3,111.97 129.71,111.97 130.09,111.59 130.09,111.05 v1(130.75,110.39)
  BOTTOM w0.109: R863.2 136.27,111.56 134.09,109.38 131.69,109.38 130.75,110.32 v1(130.75,110.39) ; U61.21 126.92,114.76 v1(126.89,114.73)
SPI_SSB_CS0_N: length 96.2
  TOP w0.109: v2(84.17,94.67) 84.37,94.67 U43.BN7
  SIG1 w0.086: v2(84.17,94.67) 84.02,94.82 84.02,96.6 84.5,97.08 84.5,98.98 85.66,100.14 85.66,100.29 85.17,100.77 85.17,100.92 85.32,101.07 85.47,101.07 85.96,100.59 86.11,100.59 86.26,100.74 86.26,100.89 85.78,101.38 85.78,101.53 85.93,101.68 86.08,101.68 86.56,101.19 86.71,101.19 86.86,101.34 86.86,101.5 86.38,101.98 86.38,102.13 86.53,102.28 86.68,102.28 87.16,101.8 87.32,101.8 87.47,101.95 87.47,102.1 87.17,102.39 87.17,102.54 87.32,102.69 87.47,102.69 87.77,102.4 87.92,102.4 88.07,102.55 88.07,102.7 87.78,103 87.78,103.15 87.93,103.3 88.08,103.3 88.37,103 88.52,103 88.67,103.16 88.67,103.31 88.38,103.6 88.38,103.75 88.53,103.9 88.68,103.9 88.97,103.61 89.13,103.61 89.28,103.76 89.28,103.91 88.98,104.2 88.98,104.35 89.13,104.5 89.28,104.5 89.58,104.21 89.73,104.21 89.97,104.45 89.97,104.6 89.67,104.89 89.67,105.04 89.82,105.2 89.97,105.2 90.27,104.9 90.42,104.9 90.66,105.14 90.66,105.29 90.3,105.64 90.3,105.8 90.45,105.95 90.6,105.95 90.96,105.59 91.11,105.59 91.49,105.97 91.49,106.22 91.11,106.6 91.11,107.11 91.46,107.47 94.21,107.47 94.57,107.11 100.5,107.11 101.75,108.36 101.75,109.73 102.08,110.06 102.08,110.21 101.8,110.49 101.8,110.64 101.95,110.8 102.1,110.8 102.38,110.51 102.53,110.51 102.68,110.66 102.68,110.81 102.4,111.1 102.4,111.25 102.55,111.4 102.7,111.4 102.99,111.12 103.14,111.12 104.39,112.36 105.25,112.36 105.41,112.53 106.16,112.53 106.18,112.56 109.12,112.56 113.95,107.72 120.09,107.72 120.27,107.54 121.9,107.54 122.01,107.65 122.01,108.28 122.11,108.38 122.33,108.38 122.43,108.28 122.43,107.65 122.54,107.54 122.75,107.54 122.86,107.65 122.86,108.28 122.97,108.38 123.18,108.38 123.29,108.28 123.29,107.65 123.39,107.54 124.05,107.54 124.25,107.75 125.15,107.75 125.26,107.64 125.26,107.3 125.36,107.19 125.58,107.19 125.68,107.3 125.68,108.02 125.79,108.13 126,108.13 126.11,108.02 126.11,107.3 126.22,107.19 126.43,107.19 126.54,107.3 126.54,107.77 126.64,107.87 126.86,107.87 126.96,107.77 126.96,107.3 127.07,107.19 127.28,107.19 127.39,107.3 127.39,107.77 127.5,107.87 127.71,107.87 127.82,107.77 127.82,107.3 127.92,107.19 128.14,107.19 128.24,107.3 128.24,107.64 128.35,107.75 128.57,107.75 128.7,107.62 128.7,107.24 128.82,107.11 129.33,107.11 129.43,107.22 v1(129.43,108.13)
  BOTTOM w0.109: v1(129.43,108.13) 130.29,108.98 130.29,109.59 130.5,109.81 130.8,109.81 131.55,109.06 134.23,109.06 136.22,111.05 137.21,111.05 137.44,111.28 R863.1 138.35,111.56 138.98,112.19 R860.1
SPI_SSB_F_CLK: length 15.4
  SIG1 w0.086: v1(126.92,117.27) 128.32,115.88 128.32,114.25 129.97,112.6 129.97,112.34 130.75,111.57 v1(130.75,111.28)
  BOTTOM w0.109: U61.18 127.48,116.71 v1(126.92,117.27) ; R875.2 136.19,112.95 134.53,111.29 130.76,111.29 v1(130.75,111.28)
SPI_SSB_F_MISO: length 15.7
  TOP w0.109: v1(130.73,109.25) 130.09,109.88 130.09,111.84 v1(129.51,112.42)
  BOTTOM w0.109: v1(129.51,112.42) 129.65,112.56 129.65,115.62 129.35,115.92 129.35,117.27 129.26,117.36 U61.17 ; v1(130.73,109.25) 131.24,108.74 134.39,108.74 135.3,109.65 R881.2
SPI_SSB_F_MOSI: length 21.4
  BOTTOM w0.109: U61.14 128.95,119.31 129.66,118.59 129.66,116.05 129.97,115.75 129.97,109.11 129.5,108.64 129.31,108.64 128.95,108.28 128.95,107.98 129.31,107.62 129.71,107.62 129.97,107.87 130.73,107.87 131.42,107.19 135.38,107.19 135.84,107.65 R869.2
SPI_SSB_MISO: length 97.5
  TOP w0.109: U43.BJ20 86.35,88.95 86.91,89.51 v2(87.14,89.51)
  SIG1 w0.086: v1(85.22,112.82) 85.24,112.82 86.16,113.75 86.16,117.33 88.08,119.25 90.93,119.25 91.82,120.14 107.82,120.14 108.35,120.68 108.86,120.68 109.8,119.74 111.5,119.74 113.02,121.26 117.32,121.26 119.79,118.8 127.05,118.8 129.08,116.76 130.73,116.76 132.03,115.46 132.03,110.5 132.13,110.41 132.13,108.41 v1(132,108.28)
  SIG3 w0.107: v1(85.22,112.82) 86.01,112.03 86.01,109.76 85.64,109.4 85.47,109.4 83.99,107.93 83.99,106.22 85.47,104.75 85.47,103.12 84.83,102.49 84.83,100.18 85.24,99.77 85.24,96.47 85.54,96.17 85.54,94.43 85.27,94.17 85.27,93.67 85.77,93.17 85.77,92.79 86.25,92.31 86.25,91.96 86.76,91.45 86.76,91.01 87.02,90.75 87.02,89.64 v2(87.14,89.51)
  BOTTOM w0.109: R878.1 R881.1 136.8,109.31 136.65,109.15 135.31,109.15 134.46,108.31 132.05,108.31 132.03,108.28 v1(132,108.28)
SPI_SSB_MOSI: length 89.6
  TOP w0.109: U43.BL11 v2(86.15,92.95)
  SIG1 w0.086: v1(86.89,112.46) 88.58,112.46 90.09,113.97 90.09,115.11 91.76,116.78 92.89,116.78 94.16,118.05 95.17,118.05 95.81,118.69 102.26,118.69 103.2,117.75 104.59,117.75 104.92,117.42 v1(105.71,117.42)
  SIG3 w0.107: v2(86.15,92.95) 86.03,93.08 86.03,94.29 85.77,94.54 85.77,96.44 85.52,96.7 85.52,100 85.14,100.38 85.14,102.41 85.75,103.02 85.75,105.11 84.91,105.94 84.91,108.27 86.28,109.64 86.28,111.86 v1(86.89,112.46)
  SIG4 w0.086: v1(105.71,117.42) 106.96,117.42 113.4,110.98 117.58,110.98 118.03,111.43 121.2,111.43 122.09,112.32 126.76,112.32 126.87,112.21 126.87,110.39 126.97,110.29 127.32,110.29 127.43,110.39 127.43,112.21 127.53,112.32 128.57,112.32 128.82,112.07 128.82,107.62 129.08,107.37 v1(130.35,107.37)
  BOTTOM w0.109: v1(130.35,107.37) 130.35,107.24 130.73,106.86 135.81,106.86 136.8,107.85 R869.1 R867.1
SPI_WP#: length 9.2
  BOTTOM w0.109: R485.2 127.58,143.03 127.68,142.93 U24.3 127.68,140.26 128.06,139.88 129.46,139.88 129.84,140.26 129.84,141.15 130.6,141.91 U22.9
SPI_WP#S: length 9.9
  TOP w0.109: R520.1 134.57,134.06 133.4,132.89 U23.9 130.73,132.89 130.22,132.39 128.32,132.39 127.68,133.02 U25.3
SPI_WP_N_0: length 13.4
  TOP w0.109: U40.3 112.19,132.77 111.43,133.53 111.43,134.54 111.93,135.05 113.33,135.05 114.09,135.81 U39.9 114.09,137.34 114.73,137.97 115.87,137.97 117.17,136.68 R760.1 R767.2
SPI_WP_N_1: length 11.5
  TOP w0.109: U41.9 114.09,148.64 113.08,147.63 112.19,147.63 111.68,147.12 111.68,146.1 112.19,145.59 U42.3 115.87,145.59 116,145.47 R770.1 R777.2
SPKR: length 73.9
  TOP w0.109: R898.2 80.53,114.76 80.95,114.35 80.95,112.73 80.69,112.47 R866.2 80.08,112.47 79.93,112.32 79.93,111.43 v1(80.44,110.92) ; U2.G6 v1(78.71,140.23)
  TOP w0.178: U43.BP20 84.37,88.95 v2(84.66,88.66)
  SIG1 w0.086: v1(73.07,128.96) 73.07,129.85 73.01,129.91 73.01,131.97 71.8,133.18 71.8,139.37 72.15,139.72 78.2,139.72 v1(78.71,140.23)
  SIG3 w0.107: v1(73.07,128.96) 73.07,128.45 73.96,127.56 73.96,127.28 75.1,126.14 75.54,126.14 79.91,121.77 80.51,121.77 81.28,121.01 81.28,115.94 79.93,114.59 79.93,113.21 80.9,112.24 80.9,111.63 80.44,111.18 v1(80.44,110.92) 79.96,110.44 79.96,106.43 81.58,104.8 81.58,98.1 82.34,97.33 82.34,96.47 81.86,95.99 81.86,94.38 82.09,94.16 82.09,93.63 82.58,93.14 82.58,92.74 82.22,92.38 82.22,91.87 82.72,91.36 82.72,90.98 83.1,90.6 83.1,90.22 83.61,89.71 83.61,89.33 84.28,88.66 v2(84.66,88.66)
SPKR_CPLD: length 8.2
  TOP w0.109: U2.G11 v1(84.71,140.23)
  BOTTOM w0.109: R12.1 86.41,146.61 86.15,146.36 86.15,142.93 85.26,142.04 85.26,141.02 84.71,140.47 v1(84.71,140.23)
SRTCRST_N: length 198.6
  TOP w0.109: JP2.2 160.6,10.08 160.6,14.43 160.8,14.63 R313.2 ; U43.AP4 93.33,96.76 92.97,97.12 92.97,97.42 93.26,97.71 93.26,98.6 92.68,99.19 v2(92.68,99.34)
  SIG3 w0.107: v1(160.4,88.93) 160.93,89.46 168.83,89.46 176.2,82.09 176.2,80.86 181.28,75.78 181.28,69.52 181.05,69.29 181.05,66.95 185.34,62.66 185.34,59.92 v1(186.36,58.9)
  SIG4 w0.086: JP2.2 161.11,11 163.88,13.77 175.56,13.77 178.8,17.01 178.8,27.89 185.92,35.02 185.92,58.47 v1(186.36,58.9) ; v1(160.4,88.93) 159.74,89.59 157.86,89.59 153.11,94.34 137.24,94.34 133.42,98.15 131.17,98.15 128.68,100.64 108.89,100.64 108,99.75 108,98.22 106.6,96.83 95.3,96.83 92.78,99.34 v2(92.68,99.34)
SSD_PWR_EN: length 376.9
  TOP w0.109: v1(71.8,144.2) 72.69,143.31 72.69,142.39 73.83,141.25 75.69,141.25 U2.F3 ; R1212.1 v1(189.66,15.04)
  SIG3 w0.107: v1(53.89,13.26) 51.99,13.26 35.1,30.15 35.1,34.34 34.21,35.23 14.66,35.23 2.24,47.64 2.24,113.12 6.4,117.27 15.16,117.27 15.41,117.53 15.41,125.78 38.4,148.77 58.97,148.77 59.74,148.01 64.69,148.01 65.58,147.12 69.39,147.12 71.8,144.7 v1(71.8,144.2)
  SIG4 w0.086: v1(53.89,13.26) 55.16,11.99 65.22,11.99 68.65,8.56 117.78,8.56 120.83,11.61 121.28,11.61 121.69,11.2 123.41,11.2 123.85,10.76 132.23,10.76 132.53,10.47 139.36,10.47 142.54,7.29 166.16,7.29 170.73,11.86 176.7,11.86 180.77,15.93 188.77,15.93 v1(189.66,15.04)
SUSACK_N: length 10.4
  TOP w0.089: 89.84,100.25 89.73,100.15 89.73,98.33 89.56,98.15 89.56,97.84 89.94,97.46 89.94,97.18 90.36,96.76 U43.AY4
  TOP w0.109: 89.84,100.25 89.84,101.8 92.63,104.6 R876.2
SUSCLK_CPLD: length 31.3
  TOP w0.109: v1(79.71,133.23) U2.N6
  SIG4 w0.086: v1(79.71,133.23) 80.19,133.71 89.91,133.71 93.65,129.97 v1(93.65,129.46)
  BOTTOM w0.109: R852.2 91.99,117.53 92.59,118.12 92.59,118.63 93.39,119.43 93.39,123.39 94.15,124.16 94.15,126.04 94.92,126.8 94.92,128.32 93.77,129.46 v1(93.65,129.46)
SUSCLK_M2: length 112.8
  TOP w0.109: R165.2 180.01,89.33 v1(180.39,88.95)
  SIG1 w0.086: v1(128.06,108.26) 128.49,108.69 129.56,108.69 129.89,108.36 129.89,107.19 130.25,106.83 132.59,106.83 136.4,110.64 v1(137.38,110.64)
  SIG3 w0.107: v1(180.39,88.95) 180.01,89.33 180.01,92.25 176.07,96.19 175.18,96.19 174.93,95.94 174.93,95.68 174.29,95.05 170.23,95.05 167.92,97.36 150.84,97.36 148.87,99.33 148.87,103.58 146.6,105.84 140.38,105.84 138.81,107.42 138.81,108.81 137.38,110.24 v1(137.38,110.64)
  SIG4 w0.086: v1(128.06,108.26) 127.54,108.78 124.75,108.78 122.95,110.57 118.45,110.57 117.45,109.57 116.84,109.57 116.74,109.67 112.3,109.67 108.76,113.21 106.73,113.21 106.09,113.84 103.3,113.84 100.5,116.64 v1(100.5,118.24)
  BOTTOM w0.109: R853.2 99.13,116.87 v1(100.5,118.24)
SVID_ALERT_N: length 233.9
  TOP w0.109: R688.2 v4(175.43,33.45) 176.83,34.85 176.83,40.06 v1(175.31,41.58) ; v4(67.48,19.99) 67.36,19.86 R724.2 ; R643.2 v1(128.57,20.88)
  SIG1 w0.086: v1(175.31,41.58) 175.25,41.64 175.25,42.41 173.66,44.01 173.66,49.58 169.59,53.65 161.87,53.65 161.25,54.26 154.21,54.26 153.6,53.65 149.27,53.65 147.87,52.25 128.32,52.25 127.81,52.76 123.62,52.76 122.35,51.49 99.87,51.49 98.22,53.14 98.22,55.04 v1(97.33,55.93) ; v4(175.43,33.45) 171.98,30 141.88,30 137.84,25.96 137.84,23.42 136.7,22.28 130.86,22.28 129.46,20.88 v1(128.57,20.88) 128.06,20.37 128.06,19.74 123.74,15.42 123.74,14.78 122.65,13.69 122.27,13.69 121.31,12.74 119.62,12.74 116.12,9.25 70.99,9.25 68.19,12.04 68.19,18.38 67.92,18.65 67.92,19.56 v4(67.48,19.99)
  BOTTOM w0.109: R724.2 67.36,19.86 v4(67.48,19.99) ; R918.2 v1(97.33,55.93) R908.1
SVID_CLK: length 233.6
  TOP w0.109: R740.1 67.23,17.83 v4(67.48,18.09) ; R702.1 v1(175.43,31.42) 177.65,33.64 177.65,41.01 v1(177.08,41.58) ; R657.1 v1(128.57,18.85)
  SIG1 w0.086: v1(177.08,41.58) 177.08,41.83 174.54,44.37 174.54,49.95 169.53,54.97 149.32,54.97 147.49,53.14 135.8,53.14 135.34,53.59 123.2,53.59 121.98,52.38 100.88,52.38 99.87,53.39 99.87,55.42 v1(99.36,55.93) ; v4(67.48,18.09) 67.48,11.71 70.68,8.51 117.04,8.51 120.54,12.01 122.75,12.01 126.16,15.42 126.16,15.67 128.57,18.09 v1(128.57,18.85) 128.7,18.85 131.11,21.26 137.46,21.26 138.98,22.78 138.98,25.32 142.92,29.26 173.27,29.26 v1(175.43,31.42)
  BOTTOM w0.109: R740.1 67.23,17.83 v4(67.48,18.09) ; R919.2 v1(99.36,55.93) R909.2
SVID_DATA: length 233.9
  TOP w0.109: R723.2 67.23,18.85 v4(67.48,19.1) ; R687.2 v4(175.43,32.44) 177.15,34.15 177.15,40.38 176.2,41.33 v1(176.2,41.58) ; R642.2 v1(128.57,19.86)
  SIG1 w0.086: v1(98.34,55.93) 98.73,55.55 98.73,53.26 100.12,51.87 122.19,51.87 123.46,53.14 127.94,53.14 128.44,52.63 147.72,52.63 149.01,53.92 153.49,53.92 154.1,54.53 161.37,54.53 161.97,53.92 169.85,53.92 174.04,49.74 174.04,44.16 176.2,42 v1(176.2,41.58) ; v4(175.43,32.44) 172.72,29.72 142.49,29.72 138.48,25.7 138.48,22.91 137.33,21.77 130.98,21.77 129.46,20.24 128.95,20.24 v1(128.57,19.86) 128.57,19.61 124.89,15.93 124.89,15.04 123.26,13.41 122.37,13.41 121.43,12.46 119.74,12.46 116.24,8.97 70.87,8.97 67.92,11.92 67.92,18.26 67.48,18.7 v4(67.48,19.1)
  BOTTOM w0.109: R723.2 67.23,18.85 v4(67.48,19.1) ; R916.2 v1(98.34,55.93) R910.2
TAO_VCCGBE_P1V05_PCH: length 40.6
  TOP w0.178: U33.14 168.23,32.47 168,32.25
  TOP w0.254: v4(167.94,32.18) 168,32.25
  TOP w0.381: R695.2 168.5,27.08 168.81,27.38 168.81,29.92 168.47,30.25 C429.2 168.07,32.06 v4(167.94,32.18) ; R714.2 159.79,43.13 v1(159.81,43.1) ; v1(160.57,53.8) 160.57,53.54 160.17,53.14 R721.2
  SIG1 w0.381: v4(167.94,32.18) 166.29,33.83 166.29,38.41 168.07,40.18 168.07,41.2 166.59,42.67 160.24,42.67 v1(159.81,43.1)
  SIG4 w0.381: v1(160.57,53.8) 159.69,52.91 159.69,46.03 159.81,45.9 v1(159.81,43.1)
TAO_VCCIN_VCCSCSUS: length 50.1
  TOP w0.178: U29.14 121.37,19.36
  TOP w0.254: 121.37,19.36 121.37,18.88 120.82,18.34 C338.2 121.1,16.66 121.51,16.25 121.51,14.56 v1(121.33,14.38)
  TOP w0.381: R684.2 v1(136.44,12.62) ; R649.2 120.82,13.87 v1(121.33,14.38) ; R669.2 115.11,11.99 v1(115.62,11.48) ; R676.2 v1(103.17,11.99)
  SIG1 w0.381: v1(103.17,11.99) 104.06,11.1 115.24,11.1 v1(115.62,11.48)
  SIG2 w0.381: v1(136.44,12.62) 136.44,12.37 135.68,11.61 133.52,11.61 132.89,12.24 132.89,13.51 130.6,15.8 121.46,15.8 121.2,15.55 121.2,14.5 v1(121.33,14.38)
  BOTTOM w0.381: v1(115.62,11.48) 118.44,11.48 v1(121.33,14.38)
TAO_VDD_P2V5_VPP: length 42.8
  TOP w0.178: U36.14 60.28,19.36
  TOP w0.254: C481.2 59.74,18.34 v4(59.99,18.59) 60.28,18.88 60.28,19.36
  TOP w0.381: R750.2 v1(91.11,12.12) ; R759.2 v1(78.91,12.62)
  SIG1 w0.381: v1(78.91,12.62) 80.06,11.48 85.26,11.48 86.79,13.01 90.22,13.01 v1(91.11,12.12)
  SIG4 w0.381: v1(78.91,12.62) 77.77,13.77 75.87,13.77 75.23,14.4 72.31,14.4 71.61,15.1 65.39,15.1 63.93,16.56 60.88,16.56 59.99,17.45 v4(59.99,18.59)
  BOTTOM w0.254: C481.2 59.74,18.34 v4(59.99,18.59)
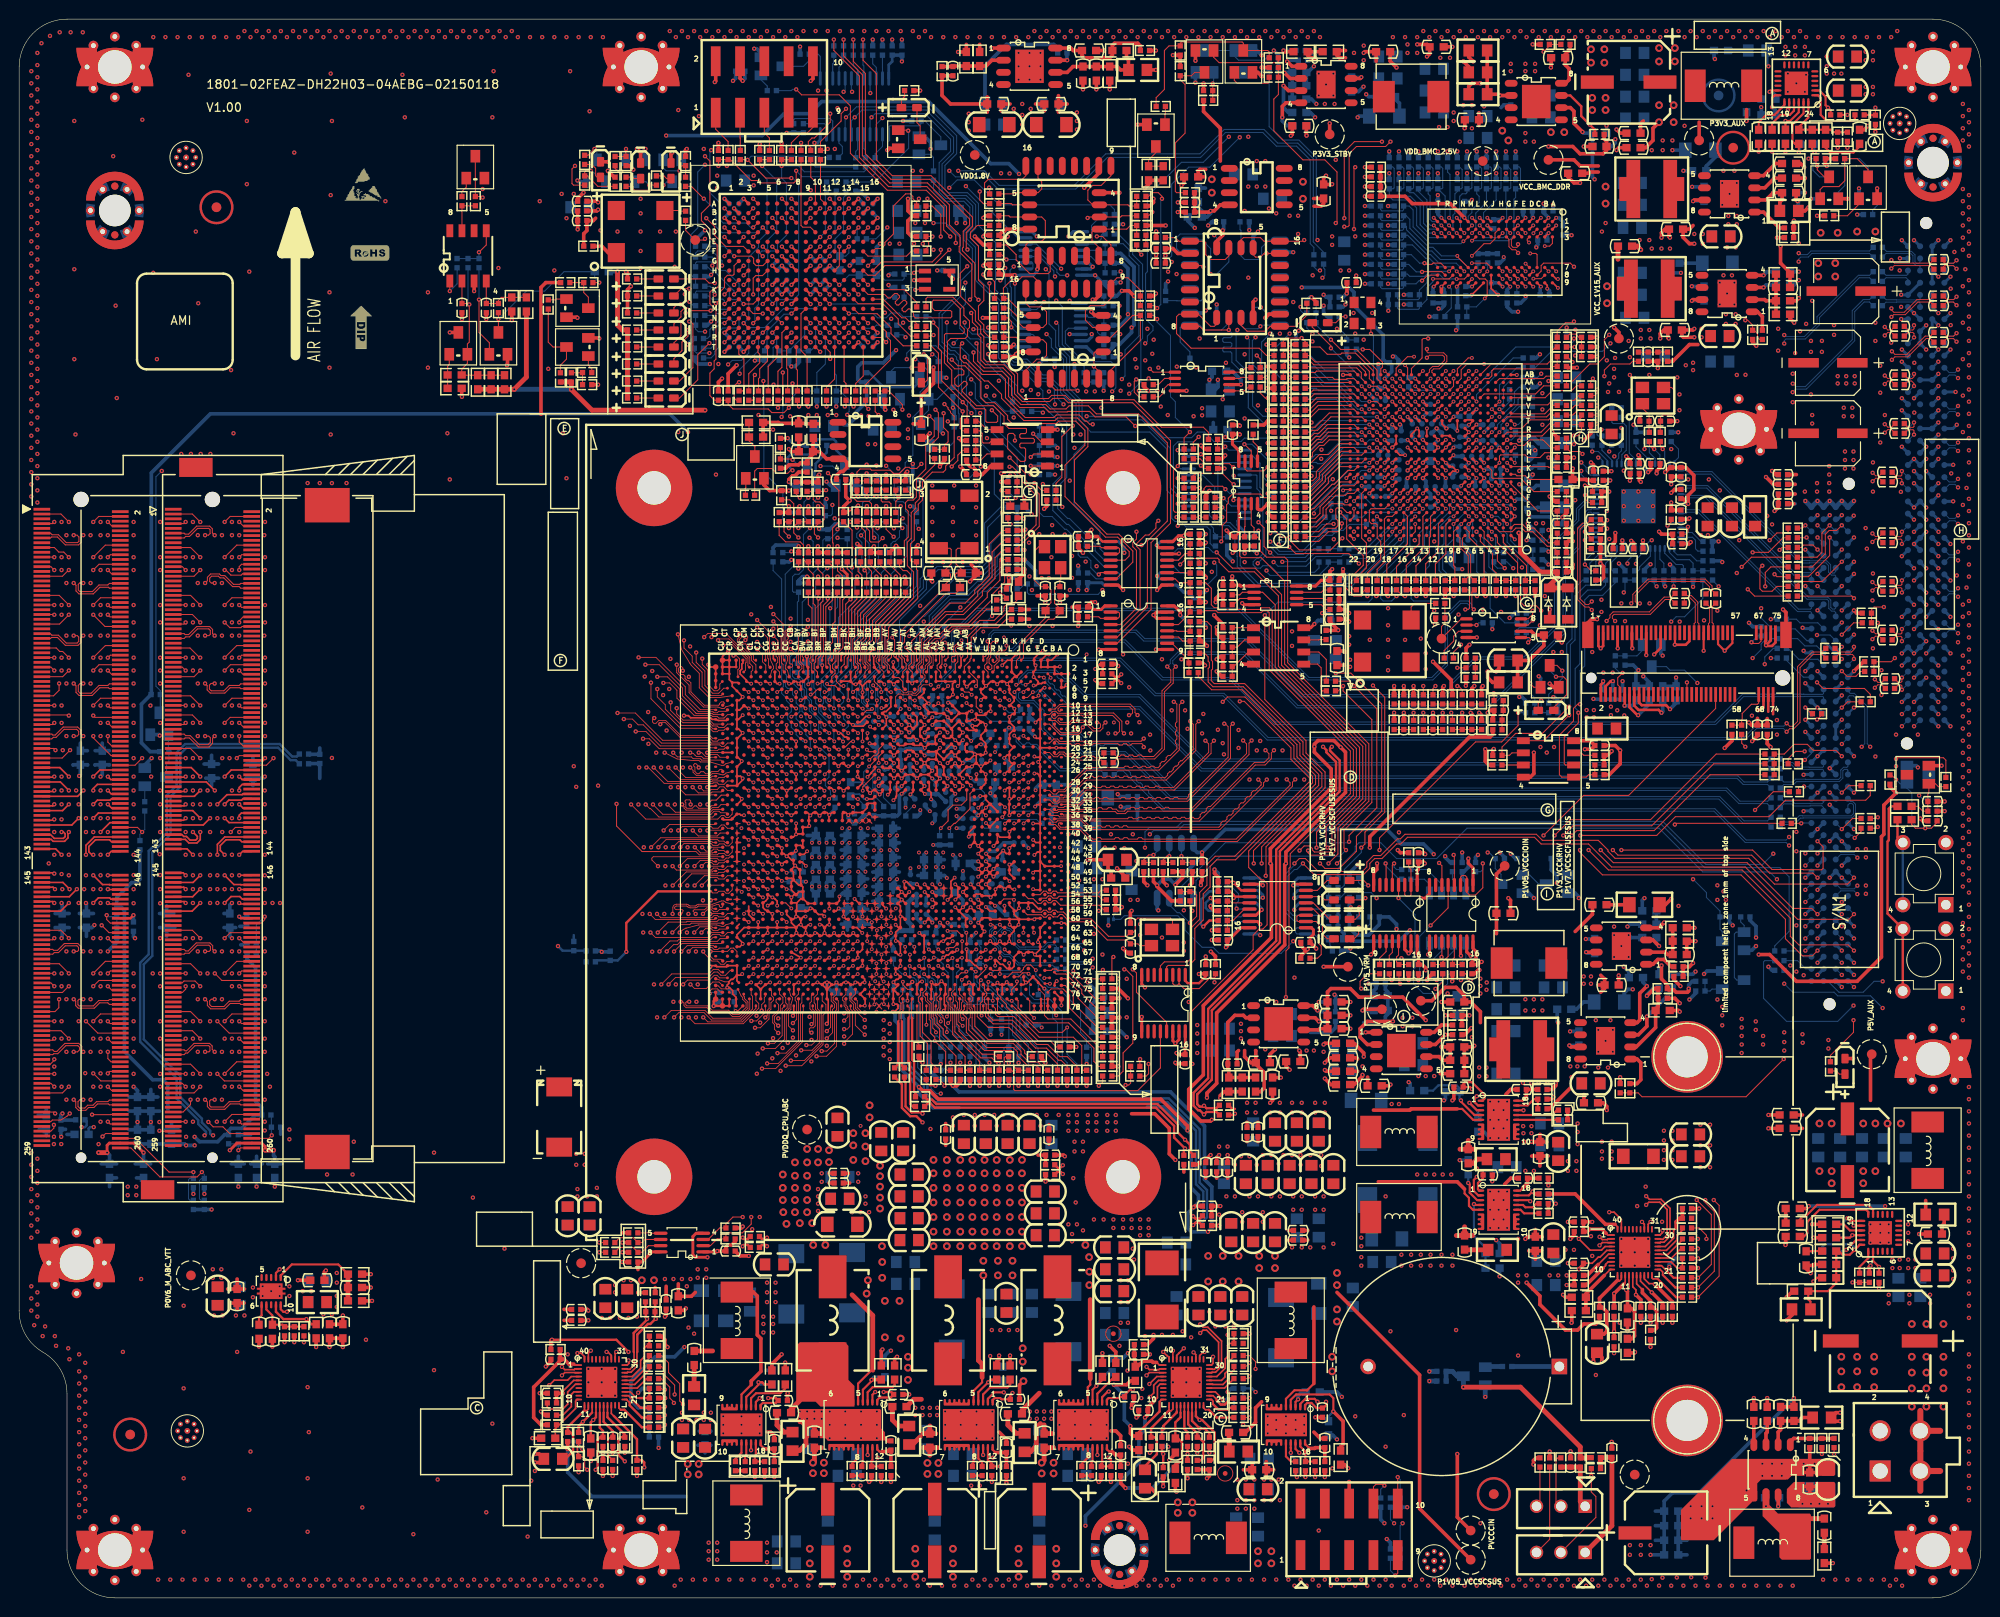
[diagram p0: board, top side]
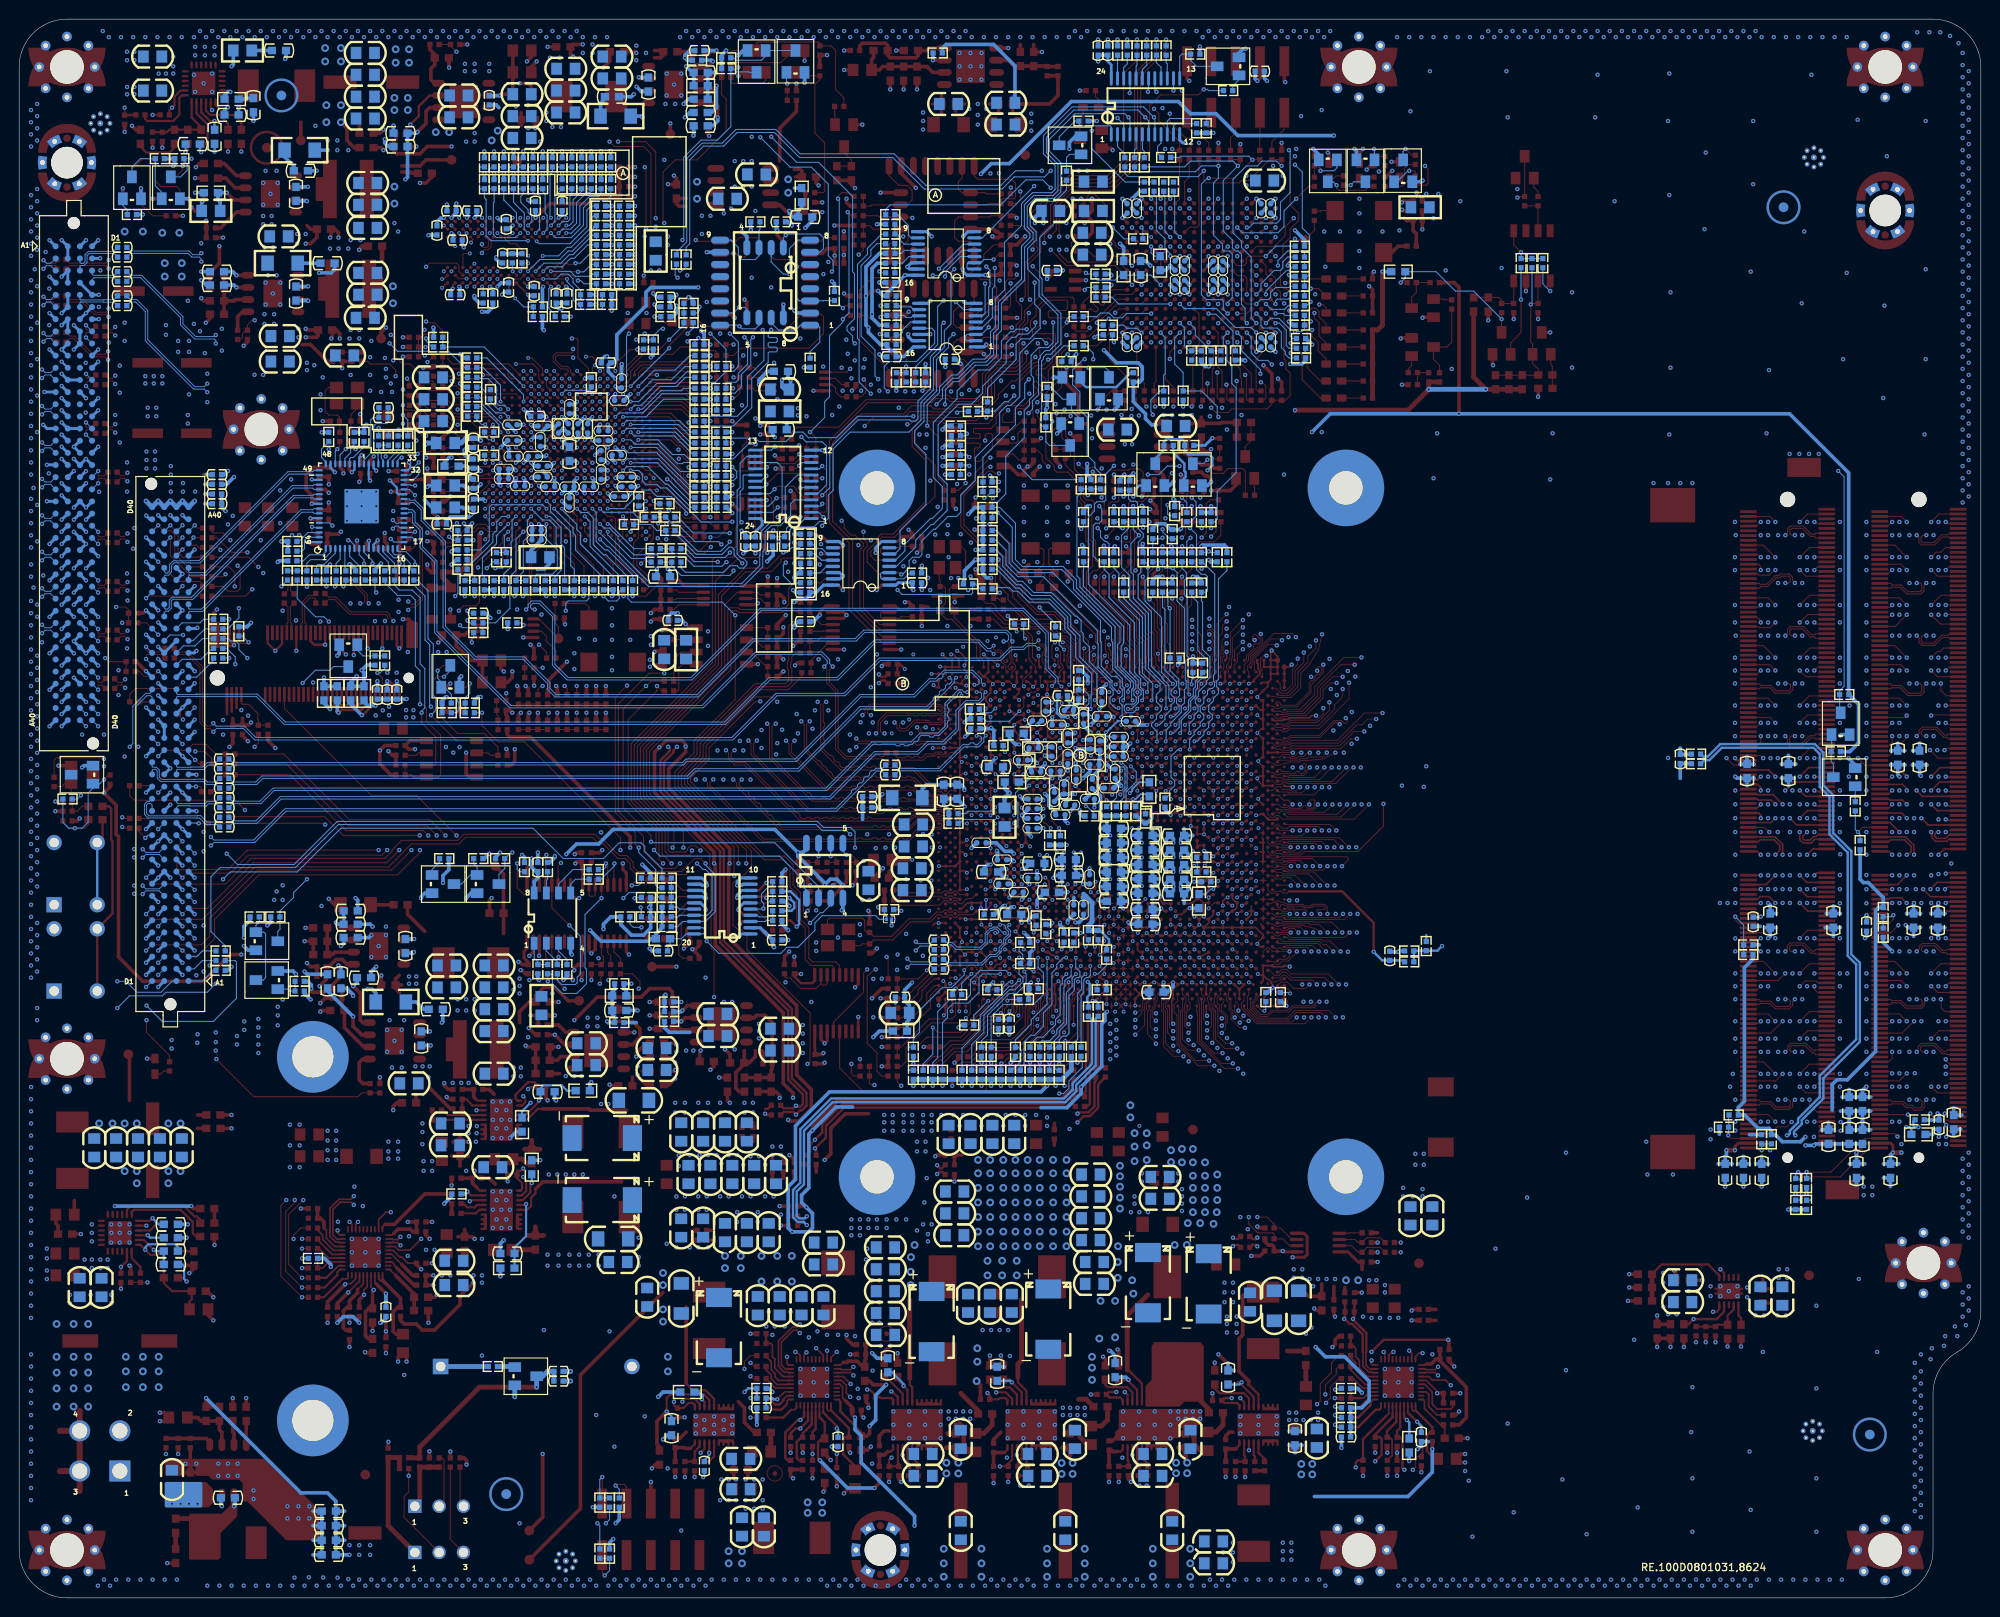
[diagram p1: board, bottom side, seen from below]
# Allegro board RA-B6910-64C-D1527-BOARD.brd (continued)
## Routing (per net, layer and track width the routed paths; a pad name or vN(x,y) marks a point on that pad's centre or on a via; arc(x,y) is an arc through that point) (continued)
TCK: length 43.1
  TOP w0.109: v1(81.2,149.15) 81.2,148.13 80.95,147.88 77.52,147.88 77.26,148.13 76.5,148.13 74.32,150.32 R114.1 R111.1 v1(73.07,149.66) ; U2.P3 75.71,133.23 v1(75.71,133.23)
  BOTTOM w0.109: R1139.2 89.45,148.9 89.1,148.54 81.81,148.54 v1(81.2,149.15) ; v1(75.71,133.23) 76.25,133.77 76.25,140.13 77.26,141.15 77.26,141.78 78.15,142.67 78.15,148.26 76.75,149.66 75.61,149.66 75.1,150.17 73.58,150.17 v1(73.07,149.66)
TDI: length 27.8
  TOP w0.109: U2.L6 v1(78.71,135.23) ; v1(79.68,149.66) R109.1 R117.1
  BOTTOM w0.109: R1140.2 88.44,149.2 88.29,149.05 82.06,149.05 81.45,149.66 v1(79.68,149.66) 79.68,148.39 80.18,147.88 80.18,142.42 79.24,141.48 79.24,140.89 79.12,140.77 78.53,140.77 78.23,140.46 78.23,135.86 78.71,135.38 v1(78.71,135.23)
TDO: length 32.2
  TOP w0.109: v1(80.69,148.39) 78.02,148.39 v1(76.12,150.29) 76.09,150.32 R115.1 ; v1(78.71,134.23) U2.M5
  BOTTOM w0.109: v1(80.69,148.39) 80.82,148.39 81.45,147.75 81.45,136.2 80.95,135.69 79.29,135.69 79.17,135.56 79.17,134.67 78.72,134.23 v1(78.71,134.23) ; R1142.2 83.74,150.55 83.61,150.67 76.5,150.67 v1(76.12,150.29)
THERMTRIP_CPU_N: length 138
  TOP w0.109: U43.AF72 96.77,65.18 v2(96.54,65.18)
  SIG3 w0.107: v1(112.4,126.1) 109.25,122.94 109.25,116.64 110.03,115.86 110.03,112.97 114.22,108.77 114.22,101.78 113.46,101.02 113.46,98.86 111.93,97.33 111.93,95.57 108,91.64 108,90.2 109.01,89.19 109.01,88.32 109.27,88.06 109.27,86.92 110.03,86.16 110.03,84.13 110.74,83.41 113.13,83.41 114.22,84.51 121.6,84.51 128.33,77.78 130.98,77.78 131.79,76.97 131.79,70.33 126.92,65.46 125.4,65.46 123.36,63.42 123.36,62.4 122.51,61.54 117.42,61.54 117.01,61.14 114.6,61.14 112.14,58.67 108.96,58.67 108.1,57.81 99.64,57.81 97.46,60 97.46,64.27 v2(96.54,65.18)
  SIG4 w0.086: v1(112.4,126.1) 113.08,126.77 113.08,132.26 114.65,133.83 114.96,133.83 v1(114.98,133.86)
  BOTTOM w0.109: R1047.1 114.8,134.04 v1(114.98,133.86)
THERMTRIP_CPU_N_CPLD: length 22
  TOP w0.109: U2.J15 v1(88.71,137.23)
  SIG1 w0.086: v1(88.71,137.23) 90.85,139.37 97.96,139.37 98.6,138.74 102.03,138.74 102.54,138.23 103.2,138.23 v1(104.06,137.36)
  BOTTOM w0.109: v1(104.06,137.36) 104.06,134.29 104.35,134 U49.6
THERMTRIP_CPU_N_GTL: length 3.6
  BOTTOM w0.109: R1137.1 R1047.2 112.57,134.04 112.37,133.83 111.76,133.83 111.59,134 U49.11
THERMTRIP_PCH_N: length 81.3
  TOP w0.109: v2(86.64,90.38) 86.36,90.67 U43.BJ16
  SIG2 w0.107: v1(83.36,123.62) 83.87,124.13 83.87,124.89 84.25,125.27 95.55,125.27 100.61,130.33 100.61,132.87 101.39,133.66 101.39,135.23 102.54,136.37 v1(102.54,137.69)
  SIG3 w0.107: v1(83.36,123.62) 83.36,121.84 85.01,120.19 85.01,115.49 85.44,115.06 85.44,113.72 84.76,113.03 84.76,112.19 85.06,111.89 85.06,109.58 83.05,107.56 83.05,106.53 85.19,104.39 85.19,103.23 84.5,102.54 84.5,100 84.96,99.54 84.96,96.37 85.26,96.06 85.26,94.54 85.06,94.34 85.06,93.58 85.55,93.09 85.55,92.72 86.02,92.25 86.02,92.24 86.03,92.23 86.03,91.89 86.54,91.38 86.54,90.48 v2(86.64,90.38) ; v1(115.11,138.63) 114.88,138.86 112.57,138.86 112.37,138.66 111.5,138.66 110.79,139.37 108.5,139.37 107.23,138.1 104.95,138.1 104.67,137.82 102.99,137.82 102.87,137.69 v1(102.54,137.69)
  BOTTOM w0.109: R1040.1 114.96,138.48 v1(115.11,138.63)
THERMTRIP_PCH_N_CPLD: length 27.5
  TOP w0.109: U2.N14 v1(87.71,133.23)
  SIG1 w0.086: v1(108.25,138.1) 107.76,137.61 106.11,137.61 104.88,136.38 99.3,136.38 98.06,135.14 89.93,135.14 88.01,133.23 v1(87.71,133.23)
  BOTTOM w0.109: U47.4 106.62,140.19 108.12,138.68 108.12,138.23 v1(108.25,138.1)
THERMTRIP_PCH_N_GTL: length 3.7
  BOTTOM w0.109: U47.13 112.01,140.19 112.7,139.5 R1033.1 R1040.2
TMS: length 31
  TOP w0.109: U2.N4 v1(76.71,133.23) ; v1(77.64,149.66) 77.39,149.91 R110.1 R116.1
  BOTTOM w0.109: R1141.2 83.21,149.56 82.6,150.17 78.15,150.17 v1(77.64,149.66) 79.17,148.13 79.17,142.86 78.21,141.91 78.21,141.08 77.9,140.77 77.62,140.77 77.26,140.41 77.26,135.18 76.88,134.8 76.88,133.4 v1(76.71,133.23)
TO_BMC_INT#: length 61.7
  TOP w0.109: U20.L18 v2(141.89,118.63) ; R195.1 183.69,106.73 v1(183.43,106.99)
  SIG3 w0.107: v2(141.89,118.63) 142.29,118.24 142.29,115.75 143,115.04 158.87,115.04 159.81,114.1 161.97,114.1 166.04,110.03 174.16,110.03 174.42,109.78 178.68,109.78 181.47,106.99 v1(183.43,106.99)
  BOTTOM w0.109: R468.1 132.1,115.77 132.25,115.62 134.74,115.62 138.17,119.05 141.48,119.05 v2(141.89,118.63)
TPS3823_MR_N: length 7.8
  TOP w0.109: U2.L11 v1(84.71,135.23)
  BOTTOM w0.109: R113.1 90.8,135.94 90.09,135.23 v1(84.71,135.23)
TPS3823_RST_N: length 11
  TOP w0.109: U2.J12 v1(85.71,137.23) ; v1(93.52,138.48) 93.71,138.67 U3.1
  BOTTOM w0.109: v1(85.71,137.23) 86.73,138.25 C757.1 R1166.1 89.94,138.25 90.47,137.72 92.33,137.72 92.48,137.87 R107.2 93.39,138.35 v1(93.52,138.48)
TXT_AGENT: length 8.9
  TOP w0.109: v2(93.57,65.2) 93.78,65.2 U43.AM72
  BOTTOM w0.109: v2(93.57,65.2) 93.97,64.81 93.97,63.61 94.38,63.2 94.38,58.37 95.04,57.71 R915.2
TXT_PLTEN: length 2.9
  TOP w0.109: v2(92.58,65.21) 92.88,64.91 U43.AP72
  BOTTOM w0.109: v2(92.58,65.21) 92.24,65.21 91.36,66.09 R914.2
UART_RX0: length 3.9
  BOTTOM w0.109: R1036.1 R1041.2 122.09,110.16 121.59,109.65 121.08,109.65 120.53,109.1 U48.11
UART_RX0_GTL: length 100.4
  TOP w0.089: 96.54,60.6 96.54,60.84 96.21,61.17 96.21,61.49 96.31,61.6 96.31,62.59 U43.AG77
  TOP w0.109: 96.54,60.6 96.69,60.45 96.69,59.87 96.95,59.61 v2(96.95,59.13) ; v1(134.69,78.11) 134.69,77.88 134.95,77.62 137.12,77.62 137.5,78 137.5,80.61 140.41,83.52 140.41,89 131.92,97.48 131.92,104.86 129.17,107.62 126.79,107.62 v1(125.14,109.27)
  SIG3 w0.107: v2(96.95,59.13) 99.11,56.97 115.52,56.97 119.25,60.71 123.01,60.71 134.62,72.31 134.62,78.03 v1(134.69,78.11)
  BOTTOM w0.109: v1(125.14,109.27) 124.76,109.27 124.25,109.78 123.46,109.78 123.34,109.9 R1041.1
UART_RX1_GTL: length 8.5
  TOP w0.089: U43.AH78 95.73,61.8 95.73,60.9 95.93,60.69 95.93,60.1
  TOP w0.109: 95.93,60.1 96.57,59.46 96.57,58.85 98.85,56.57 98.85,55.3 99.01,55.14 R1035.1
UART_SIN0: length 43.2
  SIG3 w0.107: v1(107.36,132.08) 105.79,132.08 105.13,131.42 100.45,131.42 100.32,131.55 97.29,131.55 97.28,131.54 92.84,131.54 v1(92.63,131.75)
  BOTTOM w0.109: R1207.2 92.38,132 v1(92.63,131.75) ; v1(107.36,132.08) 107.87,131.57 107.87,130.71 109.14,129.44 109.14,126.11 110.45,124.8 110.45,122.95 111.43,121.97 111.43,120.7 110.23,119.51 110.23,114.27 112.95,111.56 112.95,109.65 113.5,109.1 U48.6
UART_SOUT0: length 41.3
  TOP w0.109: U50.4 115.56,108.45 116,108.89 116,109.35 115.11,110.24 115.11,110.54 114.79,110.86 113.53,110.86 109.29,115.1 109.29,118.38 111.37,120.45 111.37,122.03 110.41,122.99 108.63,122.99 108.38,122.73 103.74,122.73 103.3,123.18 103.3,123.56 101.94,124.91 100.99,124.91 100.5,125.4 100.5,127.1 98.84,128.77 98.1,128.77 v1(97.46,129.41)
  BOTTOM w0.109: v1(97.46,129.41) 97.25,129.41 95.8,130.86 R1208.2
UART_TX0: length 3.7
  TOP w0.109: U50.13 121.15,108.45 121.84,109.14 R1064.2 R1077.2
UART_TX0_GTL: length 100.5
  TOP w0.089: v2(96.31,60.25) 96.31,60.66 95.96,61.01 95.96,61.53 96.11,61.68 96.11,62.28 95.91,62.48 95.91,62.71 96.3,63.1 U43.AG75
  TOP w0.109: v1(133.8,78.11) 134.29,78.59 134.87,78.59 135.15,78.31 135.15,78.15 135.35,77.95 136.99,77.95 137.19,78.15 137.19,80.74 140.08,83.63 140.08,88.88 131.59,97.37 131.59,104.72 129.08,107.24 126.41,107.24 125.4,108.26 125.4,108.51 125.24,108.66 123.59,108.66 123.34,108.92 R1064.1
  SIG3 w0.107: v1(133.8,78.11) 132.84,77.14 132.84,75.56 132.63,75.36 132.63,70.78 122.84,60.99 118.89,60.99 116,58.09 109.27,58.09 108.43,57.25 99.36,57.25 96.87,59.74 96.82,59.74 v2(96.31,60.25)
UART_TX1_GTL: length 9.5
  TOP w0.089: U43.AH76 95.68,62.98 95.68,62.46 95.51,62.29 95.51,60.75 95.68,60.58 95.68,59.99
  TOP w0.109: 95.68,59.99 96.19,59.48 96.19,58.34 97.9,56.63 97.9,55.24 98,55.14 R1076.2
USB2_DN0: length 105.7
  TOP w0.099: R183.2 188.41,98.6 187.48,98.6 186.1,97.23 186.1,91.49 185.45,90.84 185.02,90.84 v1(184.7,90.52) ; U43.AD3 97.84,96.82 97.84,97.59 98.09,97.84 98.09,98.73 97.84,98.98 97.84,99.26 98.05,99.47 98.37,99.47 98.47,99.37 v2(98.47,99.19)
  BOTTOM w0.099: v1(184.7,90.52) 184.37,90.86 181.56,90.86 180.36,89.66 130.42,89.66 125.8,94.29 118.69,94.29 115,97.97 102.43,97.97 101.29,99.11 100.02,99.11 99.62,99.51 98.79,99.51 v2(98.47,99.19)
USB2_DN3: length 74.5
  TOP w0.099: R539.2 151.41,105.36 151.56,105.21 151.56,103.43 151.43,103.3 v1(151.13,103.3) ; v2(97.07,95.3) 96.73,94.96 U43.AG7
  BOTTOM w0.099: v1(151.13,103.3) 151.34,103.3 151.56,103.52 151.56,103.7 151.33,103.94 150.65,103.94 149.27,102.56 149.27,97.48 147.73,95.94 134.69,95.94 127.45,103.18 100.12,103.18 97.71,100.76 97.71,97.08 96.68,96.05 96.68,95.7 v2(97.07,95.3)
USB2_DP0: length 105.7
  TOP w0.099: v1(184.7,91.41) 185.02,91.09 185.34,91.09 185.85,91.6 185.85,97.33 187.37,98.86 188.41,98.86 R186.2 ; U43.AD1 97.78,97.91 97.68,97.81 97.54,97.81 97.44,97.91 97.44,98.3 97.54,98.4 97.78,98.4 97.88,98.5 97.88,98.64 97.62,98.89 97.62,99.34 97.96,99.68 98.36,99.68 98.47,99.8 v2(98.47,100.08)
  BOTTOM w0.099: v2(98.47,100.08) 98.79,99.76 99.72,99.76 100.12,99.37 101.39,99.37 102.54,98.22 115.11,98.22 118.79,94.54 125.9,94.54 130.53,89.92 180.26,89.92 181.45,91.11 184.41,91.11 v1(184.7,91.41)
USB2_DP3: length 74.5
  TOP w0.099: v1(152.02,103.3) 151.81,103.51 151.81,105.11 R538.2 ; v2(96.07,95.25) 95.78,94.96 U43.AJ7
  BOTTOM w0.099: v2(96.07,95.25) 96.42,95.6 96.42,96.15 97.46,97.18 97.46,100.87 100.02,103.43 127.55,103.43 134.79,96.19 147.62,96.19 149.02,97.59 149.02,102.67 150.54,104.19 151.43,104.19 151.81,103.81 151.81,103.51 v1(152.02,103.3)
USB2A_DN: length 5.3
  TOP w0.099: R539.1 151.43,106.71 151.43,108.91 150.57,109.78 150.57,110.76 U20.A8
USB2A_DP: length 5.3
  TOP w0.099: R538.1 151.68,106.71 151.68,109.02 150.82,109.88 150.82,110.76 U20.A7
USB3_RX_DN1: length 86.8
  TOP w0.099: U43.D19 107.68,89.34 108.11,89.76 108.51,89.76 108.76,89.51 109.5,89.51 109.52,89.53 117.24,89.53 v1(117.52,89.81)
  SIG1 w0.094: v1(186.66,77.81) 186.12,77.27 182.04,77.27 176.2,83.11 136.57,83.11 135.81,82.35 127.08,82.35 124.16,85.27 122.98,85.27 118.66,89.59 117.74,89.59 v1(117.52,89.81)
  BOTTOM w0.099: U4.A12 v1(186.66,77.81)
USB3_RX_DP1: length 86.8
  TOP w0.099: v1(117.52,88.92) 117.52,89.08 117.32,89.28 116.31,89.28 116.16,89.12 115.86,89.12 115.71,89.28 115.41,89.28 115.26,89.12 114.96,89.12 114.81,89.28 112.26,89.28 112.11,89.12 111.81,89.12 111.66,89.28 111.37,89.28 111.21,89.12 110.92,89.12 110.76,89.28 110.47,89.28 110.31,89.12 110.02,89.12 109.86,89.28 109.57,89.28 109.59,89.3 108.68,89.3 108.42,89.55 108.25,89.55 108.18,89.48 U43.B19
  SIG1 w0.094: v1(117.52,88.92) 117.52,89.15 117.7,89.33 118.56,89.33 122.88,85.01 124.05,85.01 126.97,82.09 135.92,82.09 136.68,82.86 176.09,82.86 181.93,77.01 186.18,77.01 v1(186.66,76.54)
  BOTTOM w0.099: U4.A11 v1(186.66,76.54)
USB3_TX_DN1: length 96.7
  SIG1 w0.094: v1(193.44,88.95) 193.19,88.7 193.19,83.87 188.87,79.55 187.35,79.55 186.72,78.92 185.24,78.92 v1(184.96,78.63)
  BOTTOM w0.099: v1(184.96,78.63) 184.64,78.95 180.38,78.95 177.11,82.22 119.58,82.22 115.38,86.41 114.83,86.41 C584.2 ; U4.D25 191.1,94.77 191.33,94.54 191.76,94.54 193.12,93.18 193.12,89.27 v1(193.44,88.95)
USB3_TX_DP1: length 96.7
  SIG1 w0.094: v1(192.55,88.95) 192.93,88.56 192.93,83.97 188.77,79.81 187.24,79.81 186.61,79.17 185.31,79.17 v1(184.96,79.52)
  BOTTOM w0.099: v1(192.55,88.95) 192.86,89.27 192.86,93.08 191.66,94.29 191.26,94.29 191.1,94.13 U4.D24 ; C585.2 114.83,86.67 115.49,86.67 115.7,86.45 115.92,86.45 116.13,86.24 116.13,86.03 116.34,85.82 116.55,85.82 116.76,85.61 116.76,85.39 116.97,85.18 117.19,85.18 117.4,84.97 117.4,84.76 117.61,84.55 117.82,84.55 118.03,84.34 118.03,84.12 119.68,82.47 177.21,82.47 180.48,79.2 184.64,79.2 v1(184.96,79.52)
USB_OC0: length 124.4
  TOP w0.109: R982.2 87.93,107.87 88.34,107.47 88.34,107.4 v1(88.35,107.39) 88.57,107.17 R973.1
  SIG1 w0.086: v1(88.35,107.39) 89.21,108.26 94.19,108.26 94.79,107.66 100.25,107.66 101.1,108.51 101.1,111.11 103.59,113.6 105.53,113.6 105.64,113.72 106.22,113.72 106.84,113.1 109.34,113.1 114.16,108.28 120.72,108.28 120.95,108.51 121.2,108.51 121.46,108.76 125.65,108.76 126.03,109.14 126.03,109.45 126.28,109.71 129.43,109.71 129.95,109.18 129.95,108.92 130.38,108.49 130.38,107.95 131.06,107.27 132.41,107.27 136.34,111.2 139.26,111.2 v1(139.49,111.43)
  SIG3 w0.107: v1(139.49,111.43) 143.43,107.49 148.42,107.49 151.98,103.94 155.88,103.94 156.64,103.18 156.64,101.27 157.55,100.36 177.75,100.36 181.02,97.08 182.8,97.08 183.31,97.59 186.1,97.59 187.87,99.36 v1(187.87,100.63)
  BOTTOM w0.109: U4.C29 189.24,100.63 v1(187.87,100.63)
USB_OC1: length 12.8
  TOP w0.089: 88.85,100.16 88.17,99.48 88.17,97.62 88.38,97.42 U43.BE2
  TOP w0.109: R983.2 89.96,108 91.11,106.86 91.11,104.52 88.85,102.26 88.85,100.16
USB_OC2: length 10
  TOP w0.089: 87.93,100.51 87.39,99.97 87.39,99.72 87.39,99.71 87.39,97.75 87.68,97.46 87.68,97.46 87.73,97.42 87.73,97.4 87.73,97.12 87.39,96.78 U43.BG4
  TOP w0.109: R984.2 89.58,104.57 87.93,102.92 87.93,100.51
USB_OC3: length 17
  TOP w0.089: 87.63,100.71 87.12,100.2 87.12,98.53 87.19,98.46 87.19,97.67 87.19,97.66 87.19,97.46 U43.BG2
  TOP w0.109: 87.63,100.71 87.63,103.12 89.07,104.57 89.07,107.29 88.44,107.92 88.44,111.43 88.06,111.81 88.06,112.4 87.93,112.52 R986.2
USB_OC4: length 10.5
  TOP w0.089: U43.BE4 88.38,96.76 88.72,97.1 88.72,97.4 88.38,97.74 88.38,99.3 89.18,100.11
  TOP w0.109: 89.18,100.11 89.18,102.14 91.61,104.57 R987.2
USB_OC5: length 13.3
  TOP w0.089: 88.24,100.33 87.59,99.68 87.59,98.17 87.59,98.16 87.59,97.83 87.76,97.66 87.77,97.66 87.93,97.5 87.93,97.49 87.93,97.33 88.01,97.25 88.01,96.89 U43.BF3
  TOP w0.109: R988.2 88.95,108 90.09,106.86 90.09,104.57 88.24,102.72 88.24,100.33
USB_OC6: length 8.2
  TOP w0.089: U43.BF1 87.96,98.07 87.96,99.7 88.54,100.28
  TOP w0.109: R989.2 90.6,104.57 88.54,102.51 88.54,100.28
USB_OC7: length 13.6
  TOP w0.089: U43.BD3 88.92,96.82 88.92,97.48 88.58,97.83 88.58,99 89.51,99.92
  TOP w0.109: 89.51,99.92 89.51,101.96 92.12,104.57 92.12,106.48 92.07,106.53 92.07,106.91 90.98,108 R990.2
VPLLAV11: length 12
  TOP w0.178: U20.L5 v2(153.09,118.63) ; U20.L6 v2(152.29,118.63)
  SIG3 w0.508: v1(156.76,120.96) 156.97,120.75 156.97,120.08 156.54,119.65 154.4,119.65 153.38,118.63 v2(153.09,118.63) v2(152.29,118.63)
  BOTTOM w0.381: C322.1 152.85,118.87 v2(153.09,118.63) ; v2(152.29,118.63) 151.79,119.14 C320.1
  BOTTOM w0.508: v1(156.76,120.96) 156.99,121.18 C321.1 158.31,121.18 158.8,120.7 L18.2
VPLLAV33: length 5.7
  TOP w0.178: U20.J7 v2(151.49,117.03) ; v2(150.69,116.23) U20.H7
  BOTTOM w0.381: L20.2 158.54,116.26 158.24,115.95 C327.1 157.2,115.95 v1(156.76,116.38) ; C328.1 150.59,116.13 v2(150.69,116.23) ; v2(151.49,117.03) 151.38,117.15 C326.1
VR_FAULT_VCCGBE_P1V05_PCH: length 5.7
  TOP w0.178: U33.27 172.02,36.72 172.89,37.59 172.89,38.41 173.15,38.66
  TOP w0.381: 173.15,38.66 173.15,39.29 173.53,39.68 R703.1 R699.1
VR_FAULT_VCCIN_VCCSCSUS: length 6.3
  TOP w0.178: U29.27 125.16,23.13 126.03,24 126.03,24.97 126.28,25.22 126.28,26.42 126.46,26.59 R656.1
  TOP w0.254: R653.1 R656.1
VR_FAULT_VDDQ: length 5.9
  TOP w0.178: R739.1 65.58,26.34 65.32,26.09 65.32,25.2 64.94,24.82 64.94,24 64.07,23.13 U36.27
  TOP w0.254: R739.1 R736.1
VR_HOT_VCCGBE_P1V05_PCH: length 181.5
  TOP w0.109: R86.2 86.41,124.64 v1(86.28,124.51)
  TOP w0.178: U33.18 169.83,33.34 170.33,32.84 170.86,32.84 v1(170.93,32.78)
  TOP w0.381: R700.1 172.77,30.94 v1(170.93,32.78)
  SIG1 w0.086: v1(128.06,123.27) 128.04,123.27 126.54,124.77 125.52,124.77 122.83,127.46 v1(118.03,127.46)
  SIG3 w0.107: v1(177.97,60.88) 176.32,62.54 176.32,63.93 175.61,64.64 175.61,65.38 175.72,65.49 175.72,66.59 174.31,68 174.31,70.48 175.08,71.25 175.08,73.05 165.68,82.45 150.9,82.45 146.17,87.17 140.52,87.17 137.68,90.01 135.89,90.01 129.81,96.09 129.81,101.62 129.08,102.36 129.08,106.23 127.3,108.01 127.3,109.6 127.94,110.24 127.94,113.34 128.6,114 128.6,122.71 128.06,123.24 v1(128.06,123.27) ; v1(86.28,124.51) 87.55,125.78 97.5,125.78 98.34,126.62 99.78,126.62 101.09,127.93 108.5,127.93 108.81,128.24 115.82,128.24 116.25,127.81 117.67,127.81 v1(118.03,127.46)
  SIG4 w0.086: v1(170.93,32.78) 172.73,32.78 174.53,34.58 174.53,37.9 178.64,42.02 178.64,60.22 v1(177.97,60.88)
VR_HOT_VCCIN_VCCSCSUS: length 255.1
  TOP w0.109: v1(84.37,124.51) R85.2
  TOP w0.178: 122.97,19.48 U29.18
  TOP w0.254: R654.1 124.68,14.38 124.94,14.63 124.94,17.27 123.62,18.59 v1(123.36,18.59) 122.97,18.99 122.97,19.48
  SIG1 w0.086: v1(118.41,130.02) 118.44,130 126.25,130 128.9,127.35 128.9,125.2 v1(129.46,124.64)
  SIG3 w0.107: v1(84.37,124.51) 85.92,126.06 97.39,126.06 98.24,126.91 99.67,126.91 100.97,128.2 105.19,128.2 106.45,129.46 113.46,129.46 114.14,128.79 115.89,128.79 116.58,128.09 117.17,128.09 118.41,129.34 v1(118.41,130.02) ; v1(129.46,124.64) 130.5,124.64 130.58,124.56 130.58,124.56 130.83,124.31 130.83,124.31 130.98,124.16 130.98,112.32 130.31,111.65 130.31,109.94 130.48,109.78 130.81,109.78 131.52,109.07 131.52,108.07 131.49,108.05 131.49,96.95 136.75,91.69 138.96,91.69 141.38,89.27 146.79,89.27 151.94,84.13 168.35,84.13 176.45,76.02 176.45,69.25 177.9,67.81 177.9,65.02 180.51,62.41 180.51,59.23 v1(180.01,58.73)
  SIG4 w0.086: v1(180.01,58.73) 180.92,57.81 180.92,34.82 172.29,26.2 171.86,26.2 166.8,21.13 160.45,21.13 155.17,15.85 149.53,15.85 148.53,14.85 136.5,14.85 135.85,14.2 132.83,14.2 132.49,14.54 127.78,14.54 123.73,18.59 v1(123.36,18.59)
VR_HOT_VDDQ: length 317.4
  TOP w0.109: R87.2 87.42,124.74 v1(87.19,124.51)
  TOP w0.178: U36.18 61.88,19.27 62.15,19
  TOP w0.254: 62.15,19 64.56,16.59 R737.1 65.1,14.38 65.32,14.15 v1(65.32,13.64)
  SIG3 w0.107: v1(118.94,126.16) 118.31,126.8 116.63,126.8 115.47,127.96 109.16,127.96 108.86,127.66 101.21,127.66 99.89,126.34 98.45,126.34 97.61,125.5 88.18,125.5 v1(87.19,124.51) ; v1(135.05,122.83) 133.24,121.02 133.24,112.32 133.49,112.06 133.49,110.52 133.76,110.25 133.76,96.77 137.36,93.17 139.75,93.17 142.01,90.91 147.43,90.91 152.56,85.78 169.11,85.78 173.78,81.1 173.78,79.91 179.01,74.68 179.01,71.82 177.95,70.76 177.95,69.16 178.74,68.38 178.74,65.66 182.24,62.15 v1(182.24,58.73)
  SIG4 w0.086: v1(182.24,58.73) 182.85,58.12 182.85,57.65 182.29,57.09 182.29,34.23 172.89,24.84 172.43,24.84 167.37,19.77 161.07,19.77 154.43,13.13 142.41,13.13 141.98,12.7 138.48,12.7 137.51,11.74 133.37,11.74 131.92,13.18 125.85,13.18 125.6,13.44 121.51,13.44 121.34,13.26 119.81,13.26 116.51,9.96 68.88,9.96 65.32,13.51 v1(65.32,13.64) ; v1(135.05,122.83) 134.69,122.48 128.22,122.48 127.67,123.02 119.9,123.02 118.78,124.14 118.78,126 v1(118.94,126.16)
VR_PMCLK: length 157.1
  SIG3 w0.107: v1(143.94,104.7) 144.57,105.33 146.1,105.33 146.53,104.9 146.53,104.52 147.37,103.68 148.1,103.68 148.41,103.37 148.41,98.81 149.4,97.82 149.4,97.33 150.49,96.24 154.05,96.24 154.56,95.73 156.34,95.73 157.02,95.05 161.46,95.05 161.97,94.54 168.22,94.54 170.86,91.9 170.86,91.36 178.52,83.71 178.52,80.93 183.23,76.21 183.23,72.9 183.69,72.44 183.69,68.25 185.72,66.22 v1(185.72,65.46)
  SIG4 w0.086: v1(144.57,7.8) 146.6,9.83 153.28,9.83 161.7,18.25 168,18.25 173.06,23.31 173.6,23.31 185.47,35.18 185.47,65.2 v1(185.72,65.46)
  BOTTOM w0.109: R344.2 144.32,7.54 v1(144.57,7.8) ; R460.2 142.13,105.36 142.29,105.21 142.29,104.45 142.54,104.19 143.43,104.19 v1(143.94,104.7)
VR_PMDATA: length 152.5
  TOP w0.109: R461.2 144.6,104.7 v1(144.83,104.7)
  SIG3 w0.107: v1(185.09,66.09) 185.09,66.22 183.18,68.12 183.18,72.06 182.77,72.47 182.77,76.05 177.72,81.11 177.72,83.11 169.85,90.98 169.85,92.29 168.36,93.78 165.78,93.78 165.5,93.5 164.16,93.5 163.62,94.03 161.72,94.03 161.16,94.59 156.84,94.59 156.16,95.28 154.38,95.28 153.87,95.78 150.32,95.78 148.9,97.21 148.9,97.58 147.87,98.6 147.87,101.14 147.37,101.65 147.37,103.06 146.18,104.24 145.28,104.24 v1(144.83,104.7)
  SIG4 w0.086: v1(143.68,7.8) 143.68,8.81 145.21,10.34 153.17,10.34 161.52,18.69 167.82,18.69 172.88,23.75 173.4,23.75 183.97,34.32 183.97,37.26 185.01,38.3 185.01,66.01 v1(185.09,66.09)
  BOTTOM w0.109: v1(143.68,7.8) 143.3,8.18 R340.2
VREF_P_VCCGBE_P1V05_PCH: length 67.3
  TOP w0.229: U34.1 152.61,42.56 152.44,42.73 152.44,43.36 152.98,43.89 C453.1 152.98,44.63 152.57,44.63 v1(152.32,44.88) ; v1(151.82,53.18) 151.61,53.39 C473.1 150.9,53.67 151.13,53.9 151.81,53.9 153.13,52.58 153.13,52.19 152.9,51.96 U35.1
  TOP w0.381: R685.2 162.51,37.92 v1(162.1,37.52)
  SIG1 w0.254: v1(152.32,44.88) 152.52,44.68 155.91,44.68 157.16,43.43 157.16,40 159.72,37.44 162.02,37.44 v1(162.1,37.52) ; v1(171.69,39.31) 171.62,39.37 171.62,43.32 170.52,44.42 170.52,49.03 166.26,53.29 151.93,53.29 v1(151.82,53.18)
  SIG3 w0.254: v1(162.1,37.52) 162.1,38.53 163.62,40.06 165.02,40.06 166.92,38.15 170.53,38.15 v1(171.69,39.31)
VREF_P_VCCIN_VCCSCSUS: length 58.3
  TOP w0.229: U31.1 101.73,20.69 101.93,20.88 102.54,20.88 102.66,20.75 C397.1 ; v1(136.57,20.5) 136.57,20.12 136.29,19.84 C424.1 135.58,19.84 135.05,20.37 134.61,20.37 134.38,20.14 U32.1 ; v1(116.38,21.77) 116.1,21.77 115.52,21.18 C369.1 115.11,21.01 114.98,20.88 113.84,20.88 113.67,20.71 U30.1
  TOP w0.254: C397.1 103.58,21.18 v1(103.81,21.41)
  TOP w0.381: v1(118.54,27.48) 118.54,27.1 117.9,26.47 R641.2
  SIG1 w0.254: v1(103.81,21.41) 104.17,21.04 117.1,21.04 v1(117.27,20.88) ; v1(117.37,21.84) 116.46,21.84 v1(116.38,21.77)
  SIG2 w0.254: v1(117.27,20.88) 117.37,20.98 v1(117.37,21.84) 117.37,22.56 116.46,23.47 116.46,25.96 116.84,26.34 118.03,26.34 118.54,26.85 v1(118.54,27.48) 119.17,28.12 120.82,28.12 121.97,29.26 123.62,29.26 124.25,28.63 124.25,26.65 128.34,22.57 134.21,22.57 135.64,21.14 135.93,21.14 v1(136.57,20.5)
VREF_P_VDDQ_P2V5_VPP: length 78.2
  TOP w0.229: 89.92,20.94 89.67,20.69 U37.1 ; C513.1 79.07,20.37 77.71,20.37 77.48,20.14 U38.1
  TOP w0.254: 91.39,21.25 91.13,21.51 v1(90.34,21.51) ; 91.39,21.25 91.07,20.94 89.92,20.94 ; 91.39,21.25 C498.1 ; v1(63.67,25.71) 62.4,26.98 v1(55.67,26.98) ; C513.1 79.07,20.88 v1(78.28,20.88)
  TOP w0.381: v1(55.67,26.98) 55.57,26.87 R722.2
  SIG1 w0.254: v1(90.34,21.51) 89.81,20.98 81.81,20.98 80.51,19.69 75.15,19.69 72.5,22.34 66.91,22.34 64.18,19.61 56.94,19.61 54.53,22.02 54.53,25.83 v1(55.67,26.98) ; v1(78.28,20.88) 77.39,21.77 75.84,21.77 73.17,24.44 65.58,24.44 64.56,25.45 63.93,25.45 v1(63.67,25.71)
VREF_VCCGBE_P1V05_PCH: length 15.4
  TOP w0.178: 165.85,38.09 166.01,37.92 U33.1
  TOP w0.381: v1(164.38,39.29) C426.1 R685.1 163.88,38.28 164.13,38.53 165.4,38.53 165.85,38.09 ; R691.1 161.59,31.42 v1(161.34,31.67)
  SIG3 w0.381: v1(161.34,31.67) 161.72,31.67 163.62,33.58 163.62,38.53 v1(164.38,39.29)
VREF_VCCIN_VCCSCSUS: length 5.7
  TOP w0.178: U29.1 119.15,24.33 118.87,24.61
  TOP w0.381: R641.1 C335.1 116.53,24.92 116.63,24.82 R645.1 116.86,24.16 117.45,24.74 118.36,24.74 118.49,24.61 118.87,24.61
VREF_VDDQ_P2V5_VPP: length 12.2
  TOP w0.178: U36.1 58.06,24.33 57.96,24.44
  TOP w0.381: R727.1 54.53,18.09 53.77,18.85 53.77,22.02 56.54,24.79 C478.1 ; R722.1 C478.1 ; C478.1 56.94,24.94 57.45,24.44 57.96,24.44
WAKELAN_N: length 24.8
  TOP w0.109: U55.12 119.26,55.38 116.89,53.01 104.06,53.01 103.93,53.13 103.93,54.92 103.7,55.14 R845.2 103.07,55.14 102.94,55.27 102.94,56.44 103.07,56.57 R835.1
WAKELAN_N_CPLD: length 129.4
  TOP w0.109: v1(127.55,93.7) 128.04,93.7 132.9,88.84 132.9,87.64 134.84,85.7 134.84,85.31 127.04,77.51 124.99,77.51 124.13,76.65 124.13,74.49 123.36,73.73 123.36,70.93 122.47,70.04 122.47,66.85 122.09,66.47 119.68,66.47 119.26,66.05 U55.5 ; U2.F10 v1(83.71,141.23)
  SIG3 w0.107: v1(127.55,93.7) 126.95,93.7 124.63,96.01 124.63,98.32 123.47,99.49 123.47,104.6 122.81,105.26 122.81,111.13 124.2,112.52 124.2,114.91 124.81,115.52 124.81,117.22 124.37,117.66 124.37,121.72 123.24,122.86 122.68,122.86 122.27,123.27 122.27,124.18 123.03,124.94 123.03,127.89 123.47,128.32 123.47,128.98 122.86,129.59 122.86,133.3 119.05,137.11 118.04,137.11 115.22,139.93 103.86,139.93 103.35,139.42 101.59,139.42 101.27,139.75 99.16,139.75 98.87,140.04 85.61,140.04 84.88,140.77 84.17,140.77 v1(83.71,141.23)
XDP_CPU_PRESENT_N: length 3.7
  TOP w0.109: U43.M77 103.44,62.4 v2(103.72,62.4)
  BOTTOM w0.109: R1023.2 105.23,60.89 v2(103.72,62.4)
XDP_PRDY_N: length 12
  TOP w0.109: U43.L78 103.84,61.87 106.6,59.11 109.01,59.11 v2(109.52,59.61)
  BOTTOM w0.109: R1181.2 110.54,55.8 109.52,56.82 v2(109.52,59.61)
XDP_PREQ_N: length 13.2
  TOP w0.109: U43.K77 104.39,62.44 104.39,61.64 105.94,60.1 109.67,60.1 112.31,57.46 112.31,56.06 112.82,55.55 R961.2
XDP_TCK: length 2
  TOP w0.109: U43.T76 v2(101.74,62.41)
  BOTTOM w0.109: v2(101.74,62.41) 101.62,62.54 R962.1
XDP_TDI: length 12.3
  TOP w0.109: R1019.2 109.52,55.55 108.89,56.19 108.63,56.19 107.36,57.46 106.22,57.46 103.68,60 101.77,60 100.99,60.78 100.99,61.01 100.75,61.24 U43.V78
XDP_TDO: length 9.2
  TOP w0.109: R1018.2 108.38,57.58 107.74,58.22 106.47,58.22 103.93,60.76 102.25,60.76 102.02,60.98 102.02,61.59 U43.T78
XDP_TMS: length 14.8
  TOP w0.109: R1020.2 111.2,55.14 111.04,55.3 111.04,57.71 110.16,58.6 106.6,58.6 103.81,61.39 103.55,61.39 103.17,61.77 103.17,62.03 102.59,62.61 102.59,62.75 102.24,63.1 U43.R75
XDP_TRST_N: length 2.7
  TOP w0.109: v2(101.29,64.38) 101.29,64.31 101.25,64.27 U43.U75
  BOTTOM w0.109: R1025.2 102.41,63.55 101.58,64.38 v2(101.29,64.38)
XTAL_IN: length 16
  TOP w0.109: U43.K2 104.22,97.97 104.57,98.32 104.57,99.75 107.26,102.44 R939.1 107.26,103.45 107.82,104.01 107.82,105.38 107.51,105.69 C589.1 106.75,105.69 106.09,106.35 106.09,109.4 106.56,109.86 OSC5.1
XTAL_OUT: length 12.4
  TOP w0.109: U43.J1 104.95,98.23 104.95,99.68 107.55,102.29 108.12,102.29 108.73,102.9 R939.2 108.73,103.43 108.2,103.96 108.2,105.54 108.35,105.69 C590.1 108.76,106.35 108.85,106.44 OSC5.3
N02413: length 4.1
  TOP w0.109: U20.W11 v2(148.29,125.83)
  BOTTOM w0.109: v2(148.29,125.83) 147.91,126.21 145.33,126.21 145.21,126.34 R429.2
N04135: length 1.4
  TOP w0.109: U21.F9 v2(156.62,137.04)
  BOTTOM w0.109: v2(156.62,137.04) 156.51,136.93 R458.2
N17191: length 2
  BOTTOM w0.381: R430.2 R433.2 C245.1
N23205: length 10
  TOP w0.109: U20.N20 v2(140.29,121.03)
  BOTTOM w0.109: R465.1 132.1,119.2 132.25,119.05 135.05,119.05 135.49,119.49 136.7,119.49 138.23,121.03 v2(140.29,121.03)
N47262: length 5.2
  TOP w0.109: R631.2 157.78,116.89 157.4,117.27 156.51,117.27 156.35,117.43 U20.J1
N51572: length 9.2
  TOP w0.109: U20.H2 v2(155.49,116.23)
  TOP w0.381: C293.1 161.69,113.36 v1(161.26,112.94)
  SIG2 w0.107: v2(155.49,116.23) 156.28,116.23 157.15,115.37 158.83,115.37 v1(161.26,112.94)
  BOTTOM w0.381: v1(161.26,112.94) 161.31,112.89 C292.2
N51617: length 7.5
  TOP w0.109: U20.H1 155.89,116.42 158.72,113.59 C293.2 C296.1
N914107: length 8.7
  TOP w0.109: U41.3 107.74,138.61 107.54,138.4 105.61,138.4 104.19,139.83 104.19,140.39 103.17,141.4 R775.2
N914711: length 4.8
  TOP w0.109: U39.3 107.74,126.8 108.3,126.24 110.54,126.24 v1(110.61,126.16)
  BOTTOM w0.109: v1(110.61,126.16) 110.28,126.49 R764.2
N1689961: length 84.8
  TOP w0.099: v2(106.52,94.3) 106.52,94.3 106.32,94.1 U43.F9
  BOTTOM w0.099: v2(106.52,94.3) 106.52,94.59 106.6,94.67 106.72,94.67 106.93,94.46 106.93,94.24 107.14,94.03 107.36,94.03 108,93.39 108,93.06 107.84,92.91 107.84,92.61 108,92.46 108,92.16 107.84,92.01 107.84,91.71 108,91.56 108,91 108.88,90.12 109.35,90.12 109.5,89.97 109.8,89.97 109.95,90.12 110.77,90.12 110.98,89.91 110.98,89.69 111.19,89.48 111.4,89.48 111.68,89.21 111.98,89.21 112.13,89.05 112.43,89.05 112.58,89.21 112.88,89.21 113.03,89.05 113.33,89.05 113.48,89.21 115.77,89.21 120.59,84.38 178.35,84.38 179.72,83.01 182.67,83.01 C571.1
N1689981: length 84.8
  TOP w0.099: U43.J9 105.37,94.1 v2(105.94,94.67)
  BOTTOM w0.099: C570.1 182.73,83.26 179.83,83.26 178.46,84.63 120.7,84.63 115.87,89.46 111.79,89.46 110.87,90.37 108.99,90.37 108.25,91.11 108.25,93.5 106.83,94.92 106.49,94.92 106.24,94.67 v2(105.94,94.67)
N1690001: length 86.9
  TOP w0.099: U43.H7 105.24,94.96 v2(104.95,94.67)
  BOTTOM w0.099: v2(104.95,94.67) 104.57,94.67 104.44,94.54 104.44,94.07 104.73,93.78 106.07,93.78 107.11,92.74 107.11,90.83 108.46,89.48 110.11,89.48 111.15,88.44 115.62,88.44 120.32,83.74 177.72,83.74 180.26,81.2 182.7,81.2 C573.1
N1690029: length 86.9
  TOP w0.099: v2(104.01,94.67) 104.3,94.96 U43.K7
  BOTTOM w0.099: v2(104.01,94.67) 104.19,94.49 104.19,93.96 104.63,93.52 105.96,93.52 106.85,92.63 106.85,90.73 108.35,89.23 110,89.23 111.04,88.19 115.51,88.19 120.21,83.49 177.61,83.49 180.15,80.95 182.7,80.95 C572.1
N1690065: length 84.6
  TOP w0.099: v2(105.18,95.43) 105.3,95.55 105.48,95.55 U43.G5
  BOTTOM w0.099: v2(105.18,95.43) 104.82,95.43 104.69,95.56 104.69,95.94 105.46,96.7 108.25,96.7 108.46,96.49 108.46,96.27 108.67,96.06 108.89,96.06 109.14,95.81 109.77,95.81 111.43,94.16 117.04,94.16 123.77,87.43 135.2,87.43 135.58,87.05 182.7,87.05 C575.1
N1690077: length 84.6
  TOP w0.099: v2(104.19,95.43) 104.37,95.43 U43.J5
  BOTTOM w0.099: v2(104.19,95.43) 104.44,95.68 104.44,96.04 105.35,96.95 108.36,96.95 109.25,96.06 109.88,96.06 111.53,94.41 117.14,94.41 123.87,87.68 135.3,87.68 135.68,87.3 182.7,87.3 C574.1
N1690117: length 81.5
  TOP w0.099: v2(107.08,96.18) 106.99,96.27 U43.E4
  BOTTOM w0.099: v2(107.08,96.18) 107.29,95.98 107.29,95.65 110.05,92.89 117.04,92.89 123.51,86.41 134.31,86.41 135.07,85.65 179.52,85.65 180.15,85.01 182.7,85.01 C577.1
N1690121: length 81.5
  TOP w0.099: v2(107.79,96.16) 107.79,96.28 U43.C3
  BOTTOM w0.099: v2(107.79,96.16) 107.71,96.16 107.54,95.98 107.54,95.76 107.77,95.52 107.99,95.52 108.2,95.31 108.2,95.1 108.41,94.89 108.63,94.89 108.84,94.68 108.84,94.46 109.05,94.25 109.26,94.25 109.47,94.04 109.47,93.83 110.16,93.14 117.14,93.14 123.62,86.67 134.41,86.67 135.17,85.9 179.62,85.9 180.26,85.27 182.7,85.27 C576.1
N1702143: length 6.8
  TOP w0.099: C568.2 113.1,87.55 110.54,87.55 110.14,87.96 109.6,87.96 109.58,87.98 109.31,87.98 109.09,88.19 108.78,88.19 108.5,87.91 108.12,87.91 107.68,88.35 U43.D21
N1702147: length 6.4
  TOP w0.099: U43.B21 108.18,88.2 108.25,88.12 108.42,88.12 108.7,88.4 109.18,88.4 109.39,88.19 109.6,88.19 109.62,88.21 110.24,88.21 110.64,87.81 110.94,87.81 111.09,87.96 111.39,87.96 111.54,87.81 111.84,87.81 111.99,87.96 112.29,87.96 112.44,87.81 113.2,87.81 113.36,87.96 C569.2
N1709608: length 10.8
  TOP w0.099: v2(101.52,70.36) 101.78,70.36 102,70.14 U43.R62
  BOTTOM w0.099: C579.2 107.99,66.12 104.85,66.12 104.83,66.14 104.36,66.14 103.48,67.02 102.89,67.02 102.37,67.53 102.37,67.9 101.9,68.37 101.9,68.77 101.42,69.25 101.42,69.75 101.7,70.03 101.7,70.18 v2(101.52,70.36)
N1709612: length 10.8
  TOP w0.099: v2(102.49,70.36) 102.78,70.06 U43.N62
  BOTTOM w0.099: C578.2 108.05,66.38 104.85,66.38 104.83,66.36 104.45,66.36 103.57,67.23 102.98,67.23 102.59,67.62 102.59,67.99 102.11,68.46 102.11,68.86 101.63,69.34 101.63,69.66 101.91,69.94 101.91,70.16 102.1,70.36 v2(102.49,70.36)
N1709672: length 9
  TOP w0.099: v2(102,69.49) 101.71,69.2 U43.T64
  BOTTOM w0.099: C580.2 108.15,68.5 107.49,68.5 107.01,68.03 105.15,68.03 105.13,68.01 104.56,68.01 104.05,68.51 104.05,69.45 103.52,69.98 103.35,69.98 103.22,70.1 102.78,70.1 102.17,69.49 v2(102,69.49)
N1709676: length 9
  TOP w0.099: U43.P64 102.6,69.2 102.89,69.49 v2(102.99,69.49)
  BOTTOM w0.099: C581.2 108.4,68.1 108.25,68.25 107.59,68.25 107.12,67.77 105.15,67.77 105.13,67.79 104.47,67.79 103.84,68.42 103.84,69.36 103.44,69.76 103.26,69.76 103.13,69.89 102.86,69.89 102.64,69.66 102.64,69.55 102.7,69.48 102.98,69.48 v2(102.99,69.49)
N1709920: length 12.7
  TOP w0.089: U43.AA77 99.27,61.61 99.39,61.49 99.39,60.64 99.23,60.49
  TOP w0.109: 99.23,60.49 99.23,59.36 101.08,57.52 103.87,57.52 104.31,57.07 104.31,56.69 105.33,55.68 106.22,55.68 106.47,55.42 R784.2
N1710412: length 3.3
  TOP w0.109: U43.P56 102.91,73.05 103.86,73.05 v2(103.96,72.95)
  BOTTOM w0.109: R782.1 104.16,71.83 103.96,72.03 v2(103.96,72.95)
N1710726: length 2.3
  BOTTOM w0.109: 149.91,73.67 149.91,74.98 149.78,75.11 R805.1
N1710802: length 2.6
  BOTTOM w0.109: R806.2 147.75,66.73 148.64,67.62 U44.3
N1710854: length 3.4
  BOTTOM w0.109: R803.2 R802.2 150.8,66.47 151.18,66.85 U44.1
N1710898: length 2.7
  BOTTOM w0.109: R804.2 148.76,66.47 149.91,67.62 149.91,68.42
N1710922: length 3.1
  BOTTOM w0.109: R808.1 146.86,75.11 147.37,74.6 U44.5
N1710926: length 4.8
  BOTTOM w0.109: U44.6 148.64,74.6 147.11,76.12 R807.1
N1713278: length 2.9
  TOP w0.178: U43.BB32 89.17,83.49 v2(88.59,83.49)
  BOTTOM w0.178: R809.1 87.07,83.77 87.3,84 87.8,84 88.31,83.49 v2(88.59,83.49)
N1713310: length 28.1
  TOP w0.109: U43.AG11 96.33,93.24 v2(96.06,93.51) 95.79,93.24 U43.AJ11 ; R810.1 103.58,114.61 v1(103.25,114.94)
  SIG3 w0.107: v1(103.25,114.94) 104.26,113.92 104.26,112.24 103.91,111.89 103.91,105.01 102.36,103.45 101.19,103.45 99.44,101.7 99.44,101.19 99.13,100.89 99.13,97.36 97.58,95.81 97.58,95.17 96.06,93.65 v2(96.06,93.51)
N1713626: length 12.1
  TOP w0.099: U43.H18 105.24,89.81 v2(104.95,90.09)
  BOTTOM w0.099: C585.1 113.12,86.68 108.87,86.68 106.35,89.21 105.72,89.21 105.57,89.36 105.27,89.36 105.12,89.21 104.82,89.21 104.44,89.59 104.44,89.94 104.59,90.09 v2(104.95,90.09)
N1713630: length 12.1
  TOP w0.099: v2(103.98,90.12) 104.3,89.81 U43.K18
  BOTTOM w0.099: v2(103.98,90.12) 104.19,89.92 104.19,89.48 104.72,88.95 106.24,88.95 108.76,86.43 113.08,86.43 C584.1
N1725618: length 1.7
  TOP w0.178: U43.AA18 99.02,90.02 v2(99.49,89.56)
  BOTTOM w0.254: R846.1 100.02,90.09 v2(99.49,89.56)
N1730669: length 11
  TOP w0.109: v2(95.06,66.05) 95.35,65.77 U43.AJ71
  BOTTOM w0.109: v2(95.06,66.05) 95.06,65.02 95.32,64.77 95.45,64.77 95.73,64.49 95.73,63.88 95.83,63.78 95.83,60.1 96.57,59.36 96.57,58.98 97.33,58.22 98.09,58.22 98.34,57.96 R916.1
N1730709: length 10.2
  TOP w0.109: U43.AH72 95.84,64.91 v2(95.56,65.2)
  BOTTOM w0.109: R919.1 99.36,57.84 98.6,58.6 98.02,58.6 96.69,59.92 96.69,60.45 96.21,60.93 96.21,64.01 95.98,64.24 95.98,64.77 v2(95.56,65.2)
N1730713: length 9.4
  TOP w0.109: U43.AK72 94.85,64.91 v2(94.57,65.2)
  BOTTOM w0.109: v2(94.57,65.2) 94.96,64.8 94.96,63.89 95.55,63.3 95.55,60 96.31,59.23 96.31,58.73 97.33,57.71 R918.1
N1730757: length 29.7
  TOP w0.109: R905.1 R906.1 116.15,53.8 115.95,53.59 v1(115.62,53.59) ; U43.AL78 94.81,59.9 v2(94.81,59.89)
  SIG3 w0.107: v1(115.62,53.59) 114.58,54.64 96.69,54.64 95.3,56.03 95.3,59.41 v2(94.81,59.89)
N1731005: length 6
  TOP w0.109: U43.Y30 99.36,84.05 99.36,82.47 97.84,80.95 97.71,80.95 v2(97.2,80.44)
  BOTTOM w0.109: v2(97.2,80.44) 97.33,80.32 R923.1
N1731009: length 6.5
  TOP w0.109: v2(96.31,80.44) 97.07,81.2 97.07,82.35 97.58,82.86 98.47,82.86 99.02,83.41 U43.AA30
  BOTTOM w0.109: R924.1 96.19,80.32 v2(96.31,80.44)
N1731029: length 5
  TOP w0.109: v2(102.74,81.59) 102.99,81.83 U43.N35
  BOTTOM w0.109: R927.1 106.73,80.95 106.32,81.36 102.97,81.36 v2(102.74,81.59)
N1731049: length 4.8
  TOP w0.109: v2(103.02,82.63) 102.71,82.94 U43.P33
  BOTTOM w0.109: R928.1 106.09,81.97 105.84,82.22 103.42,82.22 v2(103.02,82.63)
N1731085: length 8.4
  TOP w0.109: U43.AB1 99.11,98.33 99.11,100.46 100.43,101.78 102.03,101.78 103.55,103.3 R929.1
N1731089: length 8.9
  TOP w0.109: U43.AB3 98.77,97.33 99.36,97.92 99.36,98.1 99.49,98.22 99.49,100.41 100.48,101.4 102.28,101.4 103.17,102.29 R925.1
N1731109: length 1.7
  TOP w0.109: U43.BG32 87.44,83.49 v2(87.65,83.49)
  BOTTOM w0.109: v2(87.65,83.49) 88.31,82.83 R931.1
N1731145: length 1.4
  TOP w0.089: v2(87.14,82.65) 86.85,82.94 U43.BH33
  BOTTOM w0.109: v2(87.14,82.65) 87.3,82.49 R932.1
N1731149: length 6.3
  TOP w0.109: U43.W9 100.02,93.14 v2(100.48,92.67)
  BOTTOM w0.109: R933.1 104.19,91.87 103.93,91.62 101.53,91.62 v2(100.48,92.67)
N1731399: length 8.6
  TOP w0.109: v2(98.53,94.36) 98.79,94.1 U43.AA9
  SIG3 w0.107: v2(98.53,94.36) 98.53,95.61 99.74,96.83 99.74,100.13 v2(99.87,100.25)
  BOTTOM w0.109: R938.1 100.02,100.41 v2(99.87,100.25)
N1731483: length 2.5
  TOP w0.109: U45.2 119.7,127.45 119.05,126.8 R941.2
N1731523: length 3.6
  TOP w0.33: U45.6 127.68,126.8 v1(127.68,126.8)
  BOTTOM w0.381: v1(127.68,126.8) 127.68,127.31 126.79,128.19 C593.2
N1731571: length 3
  TOP w0.109: U45.3 120.07,126.8 119.68,126.42 119.68,126.04 119.17,125.53 R940.1
N1731591: length 2.4
  TOP w0.109: U45.5 128.05,126.15 128.44,126.54 R942.1
N1731697: length 2.3
  TOP w0.109: R943.1 127.68,127.56 127.58,127.45 U45.7
N1731791: length 2.5
  TOP w0.109: R944.1 128.19,128.58 127.72,128.1 U45.8
N1735750: length 16.4
  TOP w0.109: v2(86.15,91.24) 85.86,91.52 U43.BL14
  BOTTOM w0.109: v2(86.15,91.24) 85.85,91.24 85.26,91.82 85.26,92.2 84.63,92.84 84.63,93.31 84.28,93.66 84.28,94.06 84.63,94.41 84.63,94.79 84.04,95.38 84.04,95.73 85.26,96.95 85.26,103.3 85.52,103.56 R945.2
N1735754: length 2.1
  TOP w0.109: U43.AA66 99.02,69.48 v2(98.98,69.52)
  BOTTOM w0.109: v2(98.98,69.52) 98.73,69.77 R954.1
N1735798: length 6.5
  TOP w0.109: U43.A73 109.37,64.71 110.66,63.42 110.66,62.66 112.7,60.63 R949.1
N1735802: length 6.7
  TOP w0.109: U43.A74 109.32,64 110.16,63.17 110.16,62.15 112.7,59.61 R948.1
N1735846: length 9.7
  TOP w0.109: U43.J54 105.04,73.5 105.46,73.08 105.96,73.08 106.46,72.58 106.77,72.58 107.06,72.87 107.33,72.87 107.55,72.64 107.82,72.64 108.04,72.87 108.33,72.87 108.81,72.39 112.87,72.39 113.33,71.93 R955.1
N1735866: length 8.2
  TOP w0.109: R947.1 113.08,73.97 112.8,73.69 108.53,73.69 108.35,73.86 108.05,73.86 107.84,73.65 107.83,73.65 107.54,73.65 107.53,73.65 107.32,73.86 107.06,73.86 106.69,73.5 U43.F54
N1735902: length 7.4
  TOP w0.109: U43.E55 106.82,73.13 107.32,73.13 107.56,73.37 107.81,73.37 108.05,73.13 108.48,73.13 108.68,73.33 112.82,73.33 113.2,72.95 R956.1
N1735930: length 36.3
  TOP w0.109: v1(103.6,112.22) 103.32,112.5 R958.2 ; U43.BA27 90.22,86.01 89.82,86.41 v2(89.82,86.46)
  SIG3 w0.107: v1(103.6,112.22) 103.64,112.18 103.64,107.46 102.99,106.81 102.99,105.67 103.3,105.36 103.3,104.81 102.22,103.73 101.05,103.73 98.88,101.56 98.88,97.74 97.2,96.06 95.8,96.06 95.65,95.9 95.65,92.98 95.04,92.38 95.04,89.46 94.79,89.21 93.65,89.21 92.1,87.66 90.45,87.66 90.22,87.43 90.22,86.92 89.82,86.53 v2(89.82,86.46)
N1735934: length 2.8
  TOP w0.109: U43.P11 102.7,93.24 v2(102.99,92.95)
  BOTTOM w0.109: v2(102.99,92.95) 103.43,92.51 104.52,92.51 104.64,92.63 R960.1
N1736004: length 7.4
  TOP w0.109: U43.D71 107.86,65.58 108.01,65.72 108.38,65.72 108.52,65.58 109.52,65.58 112.44,62.66 R953.1
N1736034: length 7.4
  TOP w0.178: U43.AA28 99.11,85.24 v2(99.45,84.9)
  BOTTOM w0.109: v2(99.45,84.9) 99.85,84.51 100.5,84.51 100.88,84.13 100.88,83.36 100.63,83.11 100.63,80.7 100.88,80.44 101.39,80.44 101.57,80.62 R959.2
N1737422: length 1.6
  BOTTOM w0.109: R969.2 81.94,76.99 81.83,76.89 81.83,76.25 81.94,76.15 R970.1
N1737426: length 2.9
  TOP w0.089: v2(72.18,63.17) 72.18,63.42 72.41,63.65 72.98,63.65 73.33,63.29 U43.CU76
  BOTTOM w0.109: R966.2 72.28,63.27 v2(72.18,63.17)
N1737430: length 2
  TOP w0.109: U43.CM78 75.1,61.34 v2(74.88,61.34)
  BOTTOM w0.109: R964.2 74.72,61.5 v2(74.88,61.34)
N1737496: length 1.8
  TOP w0.178: U43.AA27 99.1,86.04 v2(99.45,85.69)
  BOTTOM w0.254: R971.1 99.87,85.27 v2(99.45,85.69)
N1737500: length 13.2
  TOP w0.109: U43.W75 100.38,63.72 100.38,64.44 v2(100.5,64.57)
  BOTTOM w0.109: v2(100.5,64.57) 101.14,63.93 101.52,63.93 104.57,60.88 104.57,59.36 106.47,57.46 R963.1
N1737504: length 16.2
  TOP w0.109: U43.AD72 98.45,65.33 98.85,65.33 v2(98.98,65.46)
  BOTTOM w0.109: R965.1 105.46,57.84 104.19,59.11 104.19,60.88 101.52,63.55 100.94,63.55 100.1,64.39 100.1,64.8 100.5,65.2 100.5,65.71 100.38,65.84 99.49,65.84 99.11,65.46 v2(98.98,65.46)
N1738008: length 2.3
  TOP w0.109: U43.CC52 79.92,74.35 v2(80.2,74.07)
  BOTTOM w0.109: R967.2 80.97,73.56 80.46,74.07 v2(80.2,74.07)
N1738012: length 1.4
  TOP w0.109: U43.CD51 79.42,75.21 v2(79.71,74.93)
  BOTTOM w0.109: v2(79.71,74.93) 79.78,74.85 R968.2
N1738056: length 1.4
  TOP w0.109: U43.CC49 79.92,76.07 v2(80.2,75.78)
  BOTTOM w0.109: R970.2 80.29,75.87 v2(80.2,75.78)
N1739742: length 3.2
  TOP w0.178: U43.AW16 91.4,90.47 v2(91.42,90.47)
  BOTTOM w0.178: C596.1 89.33,91.64 90.19,91.64 90.9,90.93 90.93,90.93 91.4,90.47 v2(91.42,90.47)
N1739750: length 1.5
  TOP w0.178: U43.AW19 v2(91.42,88.84)
  BOTTOM w0.381: C597.1 91.31,88.95 v2(91.42,88.84)
N1739794: length 2.4
  TOP w0.178: U43.AU16 v2(92.22,90.44)
  BOTTOM w0.178: C598.1 90.98,89.97 91.06,90.04 91.83,90.04 v2(92.22,90.44)
N1739798: length 3.7
  TOP w0.178: U43.AK14 v2(95.42,92.04)
  BOTTOM w0.254: v2(95.42,92.04) 96.1,92.04 96.54,92.48 96.54,93.8 96.41,93.93 C599.1
N1739830: length 2.1
  TOP w0.178: U43.AP28 U43.AP30 93.42,84.26 v2(93.14,83.97)
  BOTTOM w0.381: C600.1 93.57,83.49 93.14,83.92 v2(93.14,83.97)
N1739866: length 2
  TOP w0.178: U43.AU21 v2(91.42,88.04) U43.AW21
  BOTTOM w0.381: C601.1 91.32,87.94 v2(91.42,88.04)
N1739906: length 1.9
  TOP w0.178: v2(82.47,95.48) 82.77,95.78 U43.BT5
  BOTTOM w0.109: C602.1 82.34,96.06 82.47,95.94 v2(82.47,95.48)
N1743737: length 2.3
  TOP w0.109: R178.2 186.2,87.17 v1(186.61,87.58)
  BOTTOM w0.109: U4.A20 187.29,88.26 v1(186.61,87.58)
N1743791: length 2.1
  TOP w0.109: v1(186.23,80.95) R174.2
  BOTTOM w0.109: U4.A14 186.52,80.98 186.48,80.95 v1(186.23,80.95)
N1743888: length 1.9
  TOP w0.109: v1(186.66,93.05) 187.3,92.41 R180.2
  BOTTOM w0.109: U4.A23 v1(186.66,93.05)
N1743955: length 3.6
  BOTTOM w0.109: R182.2 184.68,97.99 186.45,96.22 U4.A26
N1744023: length 3.1
  BOTTOM w0.109: R188.2 185.59,101.27 186.83,100.03 U4.A29
N1744091: length 4.3
  BOTTOM w0.109: U4.B30 187.96,101.91 186.1,101.91 185.72,102.29 R189.2
N1746574: length 5.6
  TOP w0.229: U2.H10 v1(83.71,139.23) ; U2.J7 v1(79.71,137.23) ; U2.J9 v1(82.71,137.23) ; U2.H8 v1(80.71,139.23)
  BOTTOM w0.381: C22.1 83.21,137.73 v1(82.71,137.23) ; C27.1 v1(80.71,139.23) ; C25.1 80.21,137.73 v1(79.71,137.23) ; C26.1 83.24,138.76 v1(83.71,139.23)
  vias: v1(90.98,141.53) v1(91.99,141.53)
N1747948: length 4.5
  BOTTOM w0.109: R187.2 185.85,100.25 186.61,99.49 187.83,99.49 U4.B28
N1747980: length 4.6
  BOTTOM w0.109: R184.2 184.83,99.24 185.97,98.1 187.96,98.1 U4.B27
N1765923: length 8.1
  TOP w0.381: R246.2 183.99,145.9 184.22,146.13 C147.2 v1(183.31,146.86) 182.55,146.1 181.36,146.1
  BOTTOM w0.381: v1(183.31,146.86) C147.2 184.22,146.13 183.99,145.9 R246.2
N1766937: length 2.4
  TOP w0.381: 176.11,146.1 175.05,146.1 v1(174.93,145.97)
  BOTTOM w0.381: v1(174.93,145.97) 174.95,146 C146.1
N1766981: length 3.3
  TOP w0.381: U10.3 182.42,147.37 183.43,148.39 C148.1
N1767005: length 3.4
  TOP w0.381: C150.1 183.56,149.91 182.29,148.64 U10.4
N1767077: length 2.6
  BOTTOM w0.381: C149.2 176.3,149.63 177.26,150.6 R249.1
N1767081: length 2.2
  BOTTOM w0.381: C149.1 v1(173.91,149.15) ; C146.2 v1(174.82,147.47)
N1767201: length 3.8
  TOP w0.381: U10.1 182.29,144.83 183.94,143.18 R242.2
N1768542: length 5.8
  TOP w0.109: v1(103.68,132.79) 103.68,133.4 103.3,133.78 R1032.2
  BOTTOM w0.109: U49.2 105.99,131.39 106.09,131.5 106.09,131.88 105.92,132.04 U49.3 104.43,132.04 v1(103.68,132.79)
N1768822: length 5.2
  TOP w0.109: R1030.2 102.66,140.39 v1(103.17,139.88)
  BOTTOM w0.109: U47.2 105.84,138.89 105.94,138.99 105.94,139.41 105.82,139.54 U47.3 104.53,139.54 104.19,139.88 v1(103.17,139.88)
N1769078: length 5
  BOTTOM w0.109: U48.3 114.86,107.15 114.98,107.03 114.98,106.63 114.86,106.5 U48.2 112.54,106.5 111.93,107.11 R1031.2
N1771458: length 4.8
  TOP w0.109: U51.2 114.88,103.02 114.98,102.92 114.98,102.54 114.81,102.37 U51.3 112.99,102.37 112.82,102.54 R1065.2
N1771492: length 3.8
  TOP w0.109: U52.13 128.04,71.99 126.84,70.79 R1068.1 R1072.1
N1771500: length 3.4
  TOP w0.109: R1073.1 R1069.1 126.54,72.82 126.72,72.64 U52.12
N1771708: length 8.5
  TOP w0.109: U52.3 133.65,71.34 133.52,71.21 133.52,70.81 133.65,70.69 U52.2 135.53,70.69 135.81,70.41 135.81,68.38 136.06,68.12 136.06,67.23 135.68,66.85 R1066.2
N1772180: length 4.8
  TOP w0.109: U50.3 114.81,109.1 114.98,109.27 114.98,109.65 114.88,109.75 U50.2 113.1,109.75 112.95,109.91 R1057.2
N1774144: length 6.7
  TOP w0.381: R257.2 182.55,135.56 182.42,135.69 U11.2 ; R257.2 C159.2 R254.2 ; R257.2 R256.1
N1774506: length 2.4
  TOP w0.381: U11.7 174.93,135.69 v1(174.8,135.56)
  BOTTOM w0.381: C158.1 174.82,135.59 v1(174.8,135.56)
N1774550: length 2.6
  TOP w0.381: U11.3 v1(182.29,136.96)
  BOTTOM w0.381: v1(182.29,136.96) 182.55,137.21 C160.1
N1774562: length 2.6
  TOP w0.381: U11.4 v1(182.29,138.23)
  BOTTOM w0.381: C162.1 182.67,138.61 v1(182.29,138.23)
N1774640: length 2.4
  BOTTOM w0.381: C161.2 R259.1
N1774644: length 3.7
  BOTTOM w0.381: v1(173.66,138.48) 172.39,138.48 172.03,138.84 C161.1 ; v1(174.8,137.08) 174.82,137.06 C158.2
N1774764: length 2.7
  TOP w0.381: U11.1 181.66,134.42 182.16,133.91 R252.2
N1776237: length 2.4
  TOP w0.109: R1095.2 66.05,38.15 66.09,38.11 U54.5
N1776541: length 3
  TOP w0.109: R1103.2 128.95,120.83 129.4,120.38 U57.5
N1776695: length 3.5
  TOP w0.109: U56.6 136.31,104.45 136.45,104.32 R1098.2
N1776757: length 2.6
  TOP w0.109: R1099.2 126.92,103.81 127.56,104.45 U56.3
N1777634: length 5.3
  TOP w0.109: U59.3 144.8,73.49 144.95,73.33 145.32,73.33 145.45,73.46 U59.2 145.45,76.14 145.21,76.38 R1106.2
N1777804: length 9.3
  TOP w0.109: v1(152.95,76.76) 152.95,74.22 152.19,73.46 151.56,73.46 151.28,73.74 U58.2 151.28,74.51 151.28,75.33 151.12,75.49 150.8,75.49 150.63,75.32 U58.3
  BOTTOM w0.109: R1108.2 152.73,75.9 152.95,76.12 v1(152.95,76.76)
N1783254: length 9.9
  TOP w0.109: Q16.3 193.21,149.28 192.07,150.42 R244.2 190.78,148.11 190.17,147.5 188.51,147.5 188.2,147.19 Q15.1
N1783372: length 3.7
  TOP w0.109: Q16.1 192.27,145.66 191.05,144.45 R250.2
N1784134: length 8.3
  BOTTOM w0.109: Q17.1 190.1,146.92 190.78,147.6 R253.2 192.32,150.42 193.21,149.53 Q18.3
N1784252: length 1.8
  BOTTOM w0.109: Q18.1 194.16,145.52 193.7,145.06 R258.2
N1788886: length 10.8
  TOP w0.381: U15.2 168.98,57.58 171.01,59.61 R293.2 171.01,61.54 171.27,61.8 R292.1 R288.2 170.86,63.68 v1(170.1,62.92)
  BOTTOM w0.381: v1(170.1,62.92) 170.1,63.04 170.76,63.7 C191.2
N1789254: length 2.2
  TOP w0.381: v1(162,57.73) 162.15,57.58 U15.7
  BOTTOM w0.381: C190.1 v1(162,57.73)
N1789298: length 7.1
  TOP w0.381: v1(170.1,60.76) 170.1,59.74 169.21,58.85 U15.3
  BOTTOM w0.381: v1(170.1,60.76) 172.77,63.42 C192.1
N1789310: length 6
  TOP w0.381: v1(170.1,63.93) 169.35,63.19 169.35,60.39 169.08,60.12 U15.4
  BOTTOM w0.381: C194.1 169.69,64.34 v1(170.1,63.93)
N1789388: length 2.7
  BOTTOM w0.381: C193.2 162.73,61.52 163.5,62.28 R295.1
N1789392: length 2.4
  BOTTOM w0.381: C193.1 160.73,60.22 v1(160.83,60.12) ; C190.2 v1(162.07,59.21)
N1789520: length 4.3
  TOP w0.381: R287.2 169.06,53.75 169.46,54.15 169.46,55.93 169.08,56.31 U15.1
N1789628: length 8.5
  BOTTOM w0.109: R289.2 179.9,70.64 180.26,70.28 Q27.1 179.43,69.58 179.24,69.39 179.24,64.82 179.5,64.57 Q28.3
N1789730: length 2.9
  BOTTOM w0.109: Q28.1 176.9,63.62 176.7,63.42 R296.1 R294.2
N11710283: length 9
  TOP w0.109: R789.2 94.79,55.55 94.92,55.68 94.92,57.96 94.15,58.73 94.15,62.15 93.97,62.34 93.97,62.75 94.18,62.96 94.18,63.46 U43.AM75
N11710317: length 8.1
  TOP w0.109: R791.2 95.8,55.42 95.3,55.93 95.3,58.22 94.41,59.11 94.41,62.31 94.32,62.4 U43.AM77
N11710357: length 9.6
  TOP w0.109: U43.AN71 93.33,65.77 v2(93.06,66.04)
  BOTTOM w0.109: R788.2 94.03,62.99 93.75,63.27 93.75,64.57 93.49,64.82 93.29,64.82 93.06,65.05 v2(93.06,66.04)
N11776877: length 3.3
  TOP w0.109: U46.6 101.52,120.83 101.39,120.7 100.76,120.7 100.63,120.83 100.63,121.72 100.38,121.97 R1005.1
N11776881: length 2.6
  TOP w0.109: R1006.1 100.25,122.99 101.14,122.1 U46.5
N11776929: length 3.7
  TOP w0.109: U46.1 105.74,118.29 v1(105.71,118.31)
  BOTTOM w0.109: v1(105.71,118.31) 105.74,118.31 105.84,118.42 R1001.2 R997.2
N11776933: length 3.9
  TOP w0.109: v1(105.71,119.23) 106.04,119.56 U46.2
  BOTTOM w0.109: R998.2 R1002.2 105.91,119.43 v1(105.71,119.23)
N11776953: length 3.6
  TOP w0.109: v1(105.96,121.67) 106.81,120.83 U46.3
  BOTTOM w0.109: v1(105.96,121.67) 106.17,121.46 R999.2 R1004.2
N11777003: length 4.5
  TOP w0.109: R1007.2 R1003.1 R1000.1 100.5,118.92 101.14,119.56 U46.7
N11794527: length 25.8
  TOP w0.089: v2(96.95,60.76) 97.08,60.89 97.08,62.2 96.93,62.35 96.93,62.75 97.15,62.97 97.15,63.46 U43.AE75
  TOP w0.109: v1(112.82,53.52) 113.23,53.92 R849.1
  SIG1 w0.086: v1(112.82,53.52) 112.31,53.01 101.27,53.01 100.88,53.39 100.88,56.51 97.71,59.69 97.71,60.35 97.3,60.76 v2(96.95,60.76)
N11795538: length 30.1
  TOP w0.109: v2(83.18,91.24) 82.89,91.52 U43.BU14
  SIG1 w0.086: v2(83.18,91.24) 83.18,91.56 83.32,91.71 83.32,92.23 82.79,92.76 82.79,93.71 82.09,94.41 82.09,95.68 82.6,96.19 82.6,97.59 83.36,98.35 83.36,99.11 84.04,99.8 84.04,105.28 82.85,106.48 82.85,108.38 82.01,109.22 82.01,114.53 v1(82.47,114.99)
  BOTTOM w0.109: v1(82.47,114.99) 82.01,114.53 82.01,113.03 82.57,112.47 R839.2
N12394792: length 5.2
  TOP w0.109: R271.2 130.63,158.42 130.5,158.29 127.3,158.29 126.99,158.61 Q20.1
N12395045: length 19.2
  TOP w0.109: R272.1 130.63,161.57 130.48,161.72 Q20.3 127.94,162.48 127.81,162.61 121.46,162.61 121.33,162.49 R266.2 120.16,162.2 119.68,161.72 119.68,157.66 118.82,156.79 R1195.1
N12395788: length 8.1
  TOP w0.109: R272.2 131.59,160.58 131.47,160.45 125.4,160.45 124.82,161.03 Q21.1
N12395875: length 16.5
  TOP w0.109: Q21.3 122.86,159.44 122.5,159.08 R267.2 121.33,158.67 121.84,158.17 121.84,153.09 120.82,152.07 120.82,146.99 120.95,146.86 R270.1
N12395879: length 9
  TOP w0.381: R270.2 C179.2 R275.1 124.38,144.83 v1(124.51,144.96) 124.89,144.96 125.52,145.59 U13.4
  BOTTOM w0.381: v1(124.51,144.96) 124.51,144.7 124.13,144.32 C764.1 123.59,144.96 123.22,145.33 R1192.2
N12402803: length 12.3
  TOP w0.381: C184.2 85.42,117.3 85.84,117.72 86.09,117.72 86.5,118.13 86.5,118.67 86.12,119.05 U14.4 84.37,119.05 83.62,119.8 C765.1 ; C765.1 82.95,120.54 82.99,120.57 R1196.2 ; C765.1 82.95,119.53 82.34,118.92 R286.1 81.66,118.62 81.45,118.42 80.46,118.42 80.1,118.06 R281.2
N12402827: length 4.2
  TOP w0.109: v1(80.83,118.95) 80.75,119.03 R281.1 R280.2
  BOTTOM w0.109: v1(80.83,118.95) 81.24,118.54 Q25.3
N12402879: length 2.8
  TOP w0.254: R282.2 v1(88.57,115.11)
  BOTTOM w0.254: v1(88.57,115.11) 88.31,115.37 88.31,115.88 87.93,116.26 Q24.1
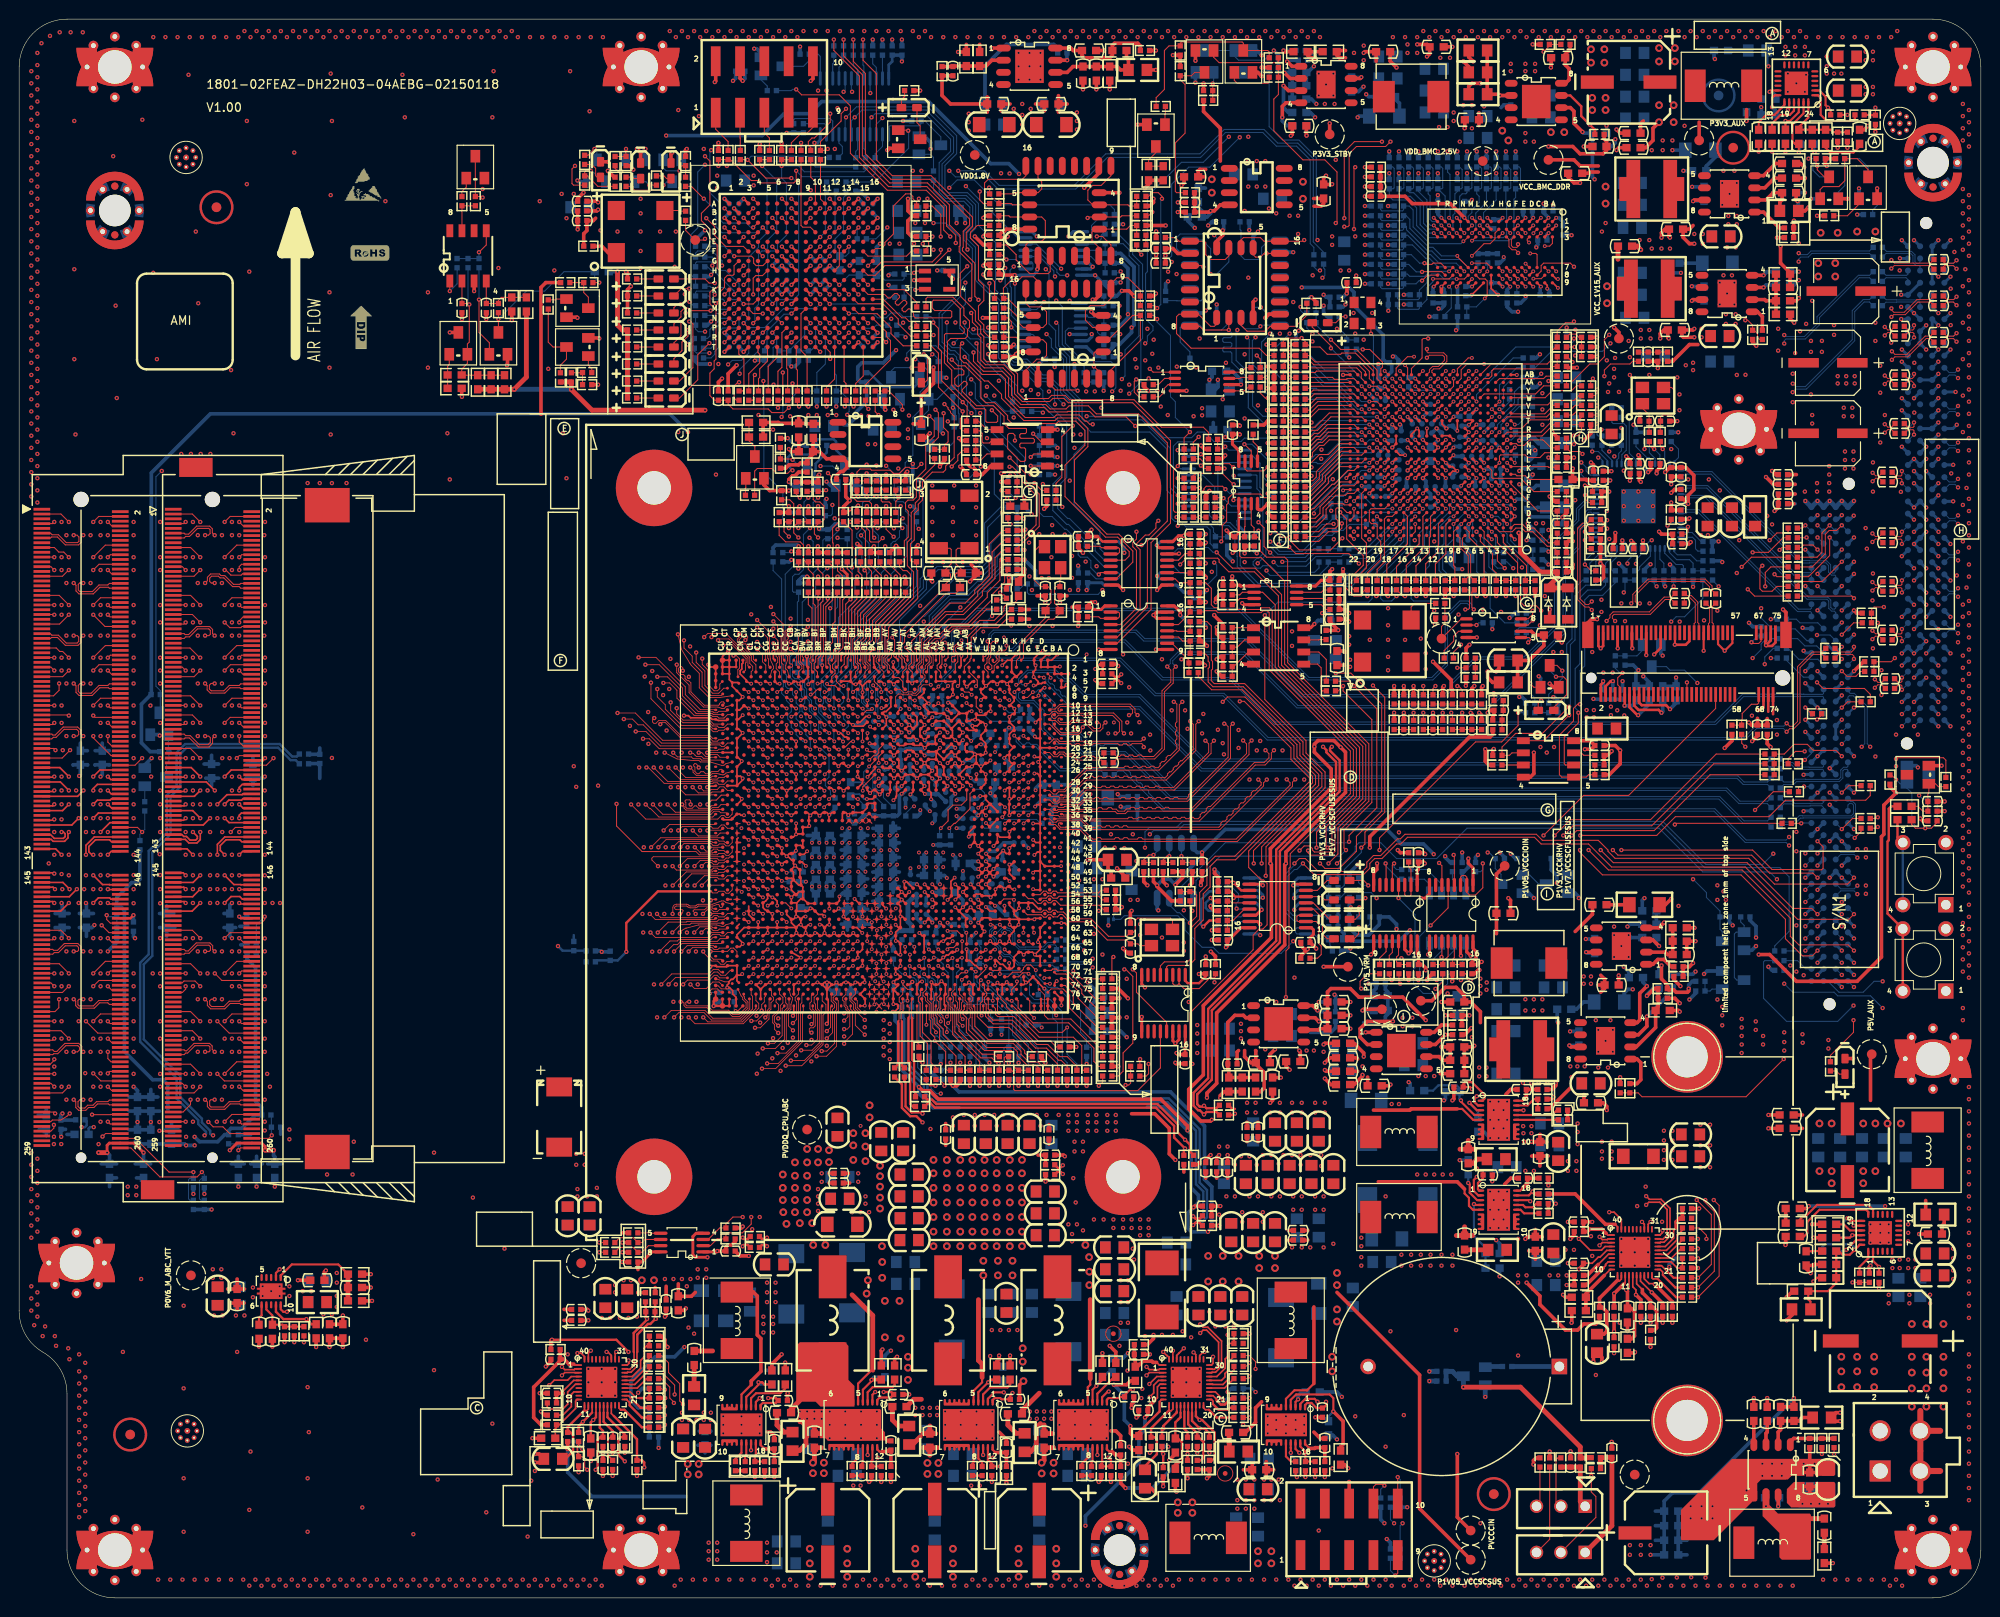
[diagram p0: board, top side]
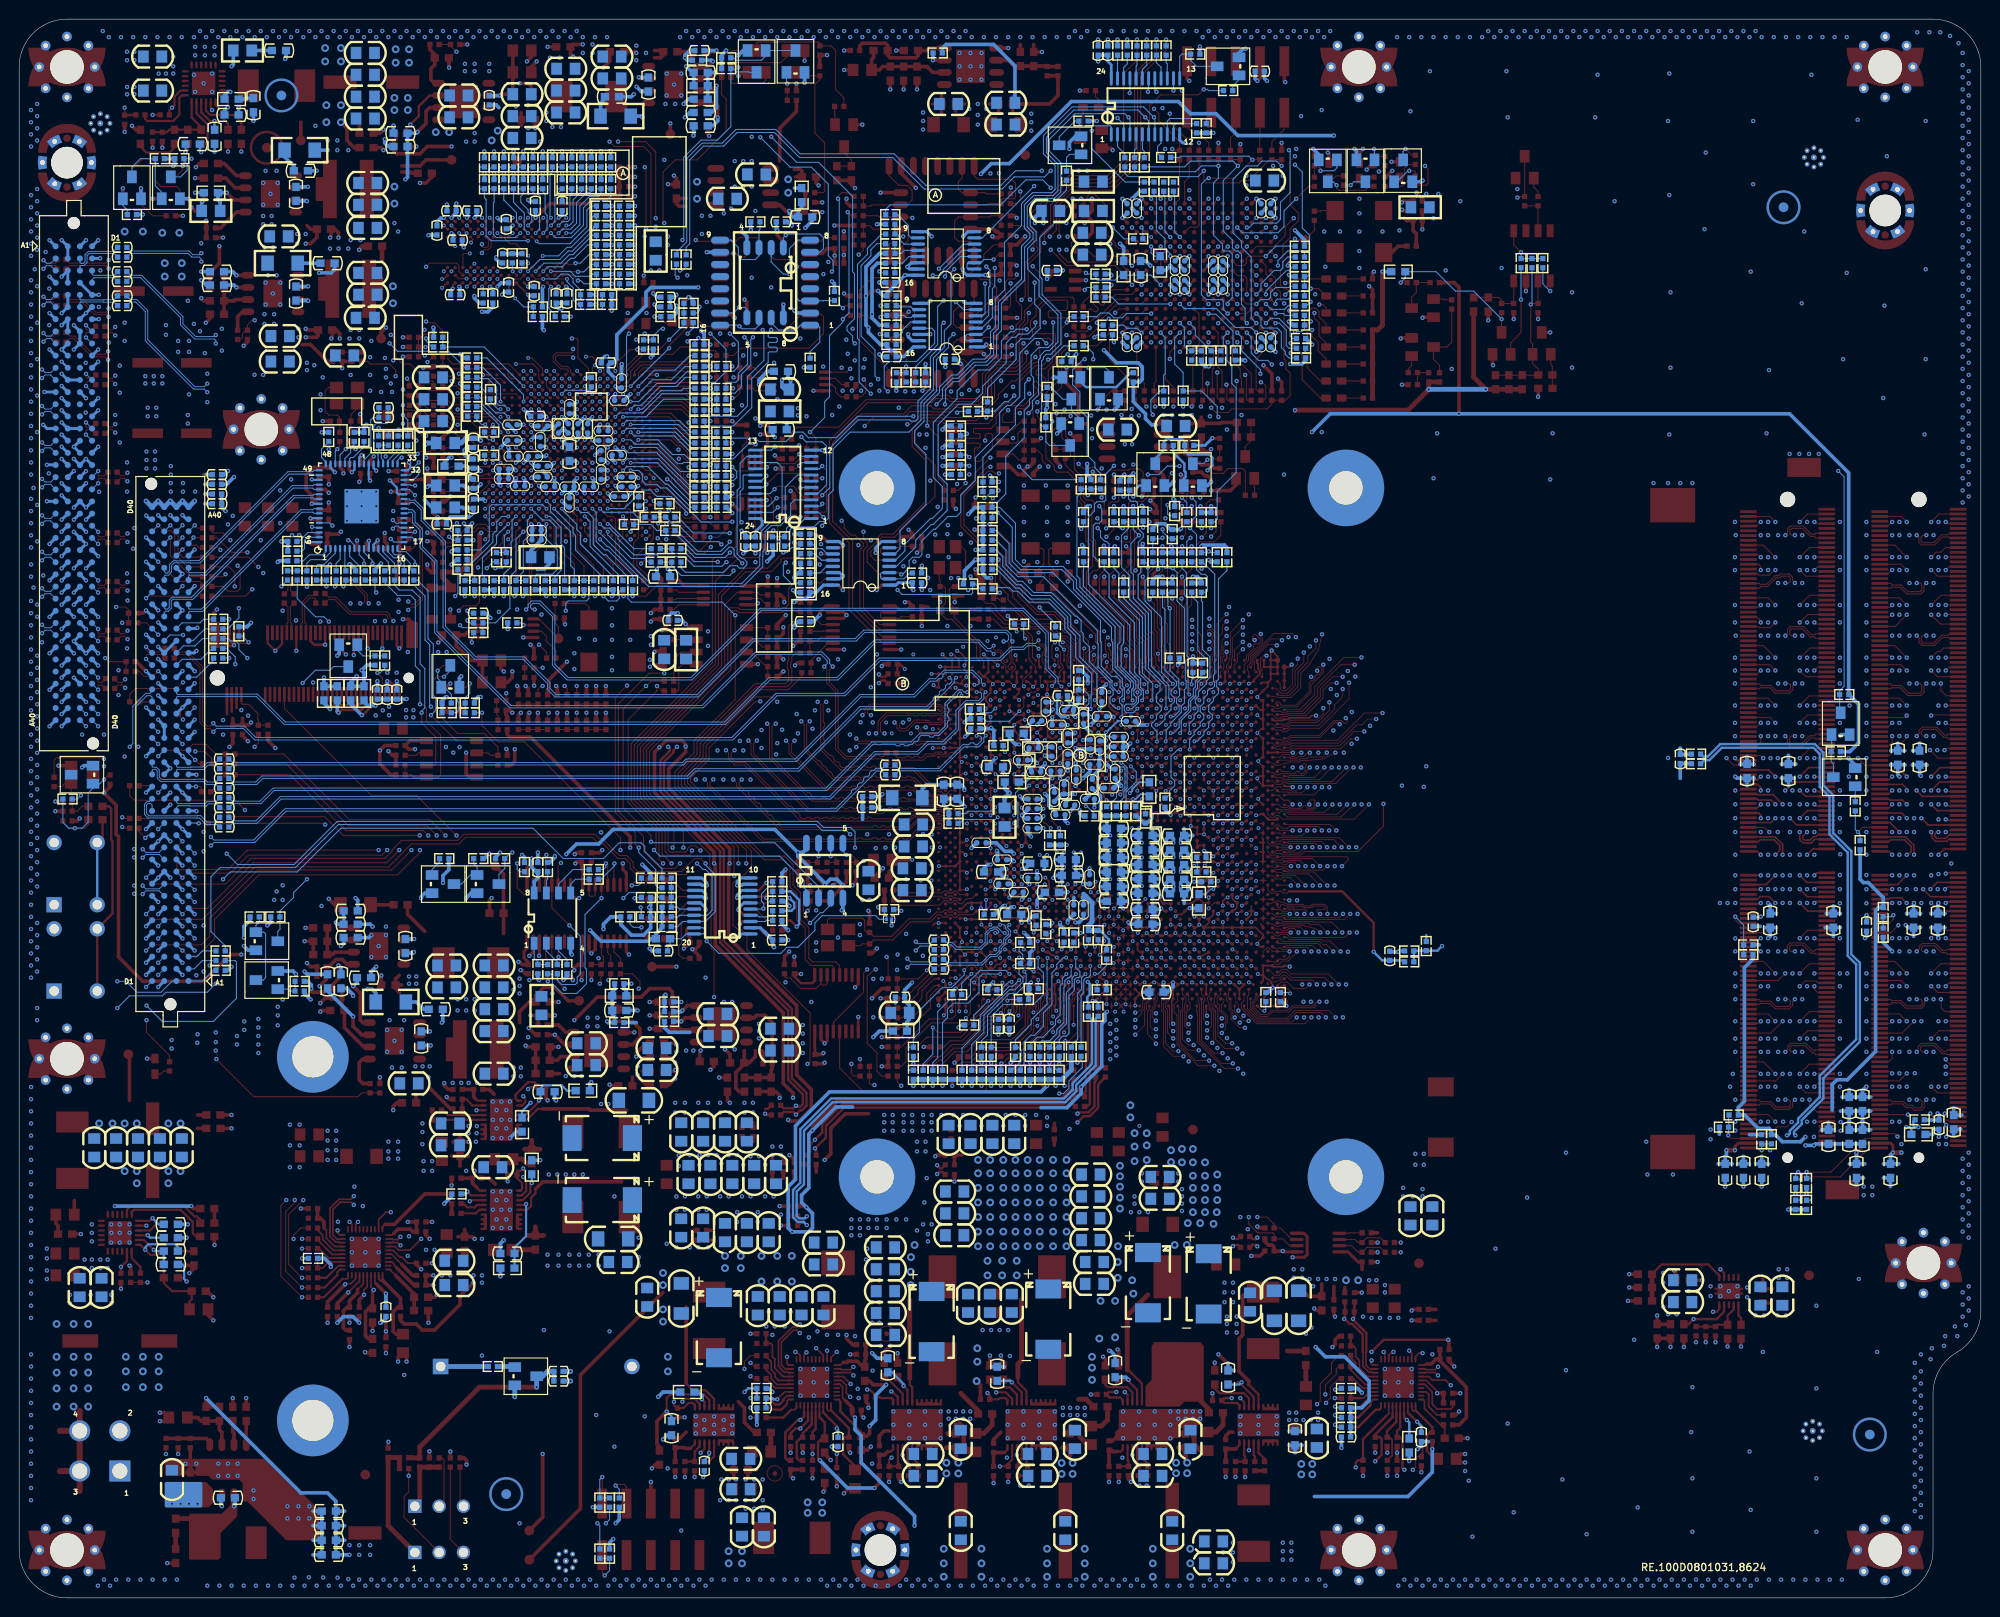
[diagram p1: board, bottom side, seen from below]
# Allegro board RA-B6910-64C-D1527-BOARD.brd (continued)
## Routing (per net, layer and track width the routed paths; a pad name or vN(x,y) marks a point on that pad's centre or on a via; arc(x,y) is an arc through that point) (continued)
N12402927: length 17.7
  TOP w0.109: v1(80.82,117.84) 80.63,117.84 80.31,117.53 79.17,117.53 78.66,118.03 77.14,118.03 76.86,117.76 R1199.1
  BOTTOM w0.254: Q24.3 86.28,119.05 85.37,119.96 R283.1 85.37,120.85 85.14,121.08 83.46,121.08 83.21,120.83 R279.2 83.21,119.89 82.81,119.5 80.63,119.5 80.31,119.18 80.31,118.35 v1(80.82,117.84)
N12402999: length 4.8
  BOTTOM w0.254: Q25.1 83.29,116.96 83.1,117.15 83.1,117.65 83.23,117.78 83.23,118.54 84.4,119.71 R283.2
N12409933: length 3
  TOP w0.381: U16.8 147.87,59.11 148.64,59.87 R302.1
N12410255: length 11.8
  TOP w0.381: v1(143.56,60.25) 140.89,60.25 140.13,59.49 140.13,58.6 140.89,57.84 U16.2
  BOTTOM w0.381: v1(143.56,60.25) 143.43,60.12 R301.2 142.77,60.76 143.02,61.01 C199.1 R297.1 143.02,63.32 142.77,63.58 R298.1
N12417603: length 2.6
  TOP w0.381: v1(135.68,61.39) 135.17,61.9 U12.8
  BOTTOM w0.381: v1(135.68,61.39) 135.81,61.27 R265.1
N12417815: length 11.7
  TOP w0.381: R264.2 R261.2 R260.1 126.41,55.17 126.31,55.27 C167.2 126.31,60.15 127.05,60.88 127.94,60.88 128.19,60.63 U12.2
N12424653: length 5
  TOP w0.381: R241.1 162.07,161.82 161.57,161.32 C137.1 161.57,160.22 161.97,159.82 161.97,158.67 161.59,158.29 U9.8
N12425131: length 8.3
  TOP w0.381: U9.2 v1(154.73,157.02) 154.61,157.15 R240.2 R239.2 R236.2
  BOTTOM w0.381: v1(154.73,157.02) 154.76,157 C132.2
N12431533: length 3.3
  BOTTOM w0.109: U4.A1 185.82,64.47 184.7,65.58 R171.2
N12431544: length 3.2
  BOTTOM w0.109: R169.2 185.85,66.6 186.7,65.74 U4.A2
N12431744: length 3.1
  BOTTOM w0.109: R170.2 185.85,67.62 186.45,67.01 U4.A3
N12431813: length 1.8
  TOP w0.109: R176.2 185.95,84.67 186.07,84.8 v1(186.52,84.8)
  BOTTOM w0.109: v1(186.52,84.8) 186.52,84.79 U4.A17
N12431851: length 19
  TOP w0.089: U43.AN3 93.76,96.83 93.76,97.48 94.12,97.84 94.12,100.42 94.42,100.72
  TOP w0.109: R811.1 102.92,110.54 101.67,109.3 101.67,106.68 100.17,105.18 100.17,104.7 98.55,103.07 96.77,103.07 94.42,100.72
N12431888: length 18.6
  TOP w0.089: U43.AM4 94.18,96.41 94.18,96.9 93.96,97.12 93.96,97.39 94.32,97.75 94.32,100.18 94.71,100.57
  TOP w0.109: R812.1 102.79,109.53 101.98,108.71 101.98,106.55 100.66,105.23 100.66,104.76 98.67,102.77 96.91,102.77 94.71,100.57
N12431946: length 21.8
  TOP w0.089: v2(95.27,95.43) 94.46,95.43 94.2,95.17 94.2,94.77 93.77,94.34 93.37,94.34 93.24,94.46 92.93,94.46 92.86,94.39 92.33,94.39 92.25,94.46 91.87,94.46 91.59,94.19 U43.AV11
  BOTTOM w0.109: R813.1 102.92,105.46 102.79,105.59 101.52,105.59 101.14,105.21 100.63,105.21 99.49,104.06 97.43,104.06 95.73,102.36 95.73,101.26 95.11,100.63 95.11,95.59 v2(95.27,95.43)
N12432021: length 22.6
  TOP w0.109: v2(96.57,98.48) 96.44,98.35 96.44,97.59 96.3,97.44 U43.AG2 ; R814.1 102.78,115.62 102.66,115.75 v1(102.66,115.75)
  SIG3 w0.107: v2(96.57,98.48) 97.51,99.42 97.51,101.15 102.45,106.09 102.45,107.05 103.1,107.7 103.1,109.85 102.86,110.09 102.86,112.58 103.19,112.91 103.19,113.94 102.51,114.62 102.51,115.6 102.66,115.75 v1(102.66,115.75)
N12432061: length 16.9
  TOP w0.089: U43.AV7 92.06,94.96 92.43,94.59 92.73,94.59 92.83,94.69 93.32,94.69 93.47,94.54 93.67,94.54 93.95,94.82 93.95,95.25 94.18,95.48 94.18,95.65 94.66,96.13 94.66,96.42 94.46,96.62 94.46,96.9 94.69,97.13 94.69,97.41 95.11,97.83 95.11,98.22 94.97,98.36 94.97,99.53 95.69,100.25
  TOP w0.109: 95.69,100.25 96.21,100.25 97.45,101.49 99.25,101.49 101.09,103.33 R815.1
N12432134: length 22.5
  TOP w0.109: U43.BV20 82.39,88.95 v2(82.68,88.66)
  BOTTOM w0.109: R829.2 81.35,108.28 80.06,106.99 80.06,96.57 80.18,96.44 80.18,95.81 80.08,95.71 80.08,95.28 80.31,95.05 80.56,95.05 80.82,94.79 80.82,94.41 81.2,94.03 81.2,93.52 81.58,93.14 81.58,92.63 81.2,92.25 81.2,91.87 81.58,91.49 81.58,91.11 82.22,90.48 82.22,90.22 82.68,89.76 v2(82.68,88.66)
N12432641: length 3.3
  TOP w0.109: R194.1 186.23,109.78 186.48,110.03 187.45,110.03 v1(187.93,109.56)
  BOTTOM w0.109: U4.B36 v1(187.93,109.56)
N12433834: length 42.2
  TOP w0.109: v2(87.66,90.38) 87.37,90.67 U43.BG16
  SIG1 w0.086: v2(87.66,90.38) 87.77,90.38 88.31,89.84 89.07,89.84 89.33,89.59 89.33,84 91.49,81.84 96.57,81.84 97.2,81.2 100.12,81.2 100.88,80.44 103.3,80.44 103.42,80.57 103.68,80.57 103.81,80.44 108,80.44 109.39,79.05 111.04,79.05 114.35,75.74 114.35,73.33 v1(112.82,71.81)
  BOTTOM w0.109: R828.1 112.95,71.93 v1(112.82,71.81)
N12435911: length 3.3
  TOP w0.109: v1(93.65,136.7) 93.71,136.77 U3.3
  BOTTOM w0.109: v1(93.65,136.7) 93.39,136.96 R106.2 R113.2
N12441283: length 4.5
  TOP w0.109: J1.1 72.79,153.49 74.09,152.2 R114.2
N12441300: length 3.9
  TOP w0.109: J1.3 75.33,152.58 75.36,152.55 R115.2
N12441304: length 4.2
  TOP w0.109: R116.2 78.41,152.58 77.87,153.11 J1.5
N12441326: length 5.2
  TOP w0.109: R117.2 80.69,152.07 81.71,153.09 82.34,153.09 82.95,153.7 J1.9
N12446006: length 3.4
  TOP w0.109: R173.2 191.58,81.46 v1(190.47,80.35)
  BOTTOM w0.109: U4.C14 v1(190.47,80.35)
N12446036: length 3.2
  TOP w0.109: R175.2 191.2,84.89 v1(190.47,84.16)
  BOTTOM w0.109: U4.C17 v1(190.47,84.16)
N12446074: length 11.1
  TOP w0.109: v1(190.47,87.97) 189.87,88.57 187.5,88.57 186.86,89.21 185.47,89.21 184.45,88.19 R1190.2 R1191.2 R177.2
  BOTTOM w0.109: U4.C20 v1(190.47,87.97)
N12446215: length 3.2
  TOP w0.109: v1(190.47,93.05) 191.07,93.65 R179.2
  BOTTOM w0.109: U4.C23 v1(190.47,93.05)
N12446425: length 3.7
  TOP w0.109: v1(190.47,96.86) 191.01,96.32 191.94,96.32 192.45,96.83 R181.2
  BOTTOM w0.109: U4.C26 v1(190.47,96.86)
N12446773: length 7.1
  TOP w0.109: v1(189.2,110.83) 189.2,108.94 186.99,106.73 R195.2
  BOTTOM w0.109: U4.C37 v1(189.2,110.83)
N12446840: length 6.8
  TOP w0.109: R197.2 187.88,108.76 188.39,109.27 188.39,111.29 v1(189.2,112.1)
  BOTTOM w0.109: U4.C38 v1(189.2,112.1)
N12451021: length 2.1
  TOP w0.109: R172.1 192.48,80.09 v1(191.82,79.43)
  BOTTOM w0.109: v1(191.82,79.43) 191.53,79.71 U4.D13
N12451452: length 3.4
  TOP w0.099: v1(191.74,98.13) 191.74,98.43 191.56,98.6 190.14,98.6 R183.1
  BOTTOM w0.099: U4.D27 v1(191.74,98.13)
N12451530: length 3.4
  TOP w0.099: R186.1 190.14,98.86 191.49,98.86 191.74,99.11 v1(191.74,99.4)
  BOTTOM w0.099: U4.D28 v1(191.74,99.4)
N12451653: length 3.5
  TOP w0.109: v1(190.47,100.67) 191.71,101.91 R190.1
  BOTTOM w0.109: U4.D30 v1(190.47,100.67)
N12451741: length 6.9
  TOP w0.109: R192.1 191.52,104.7 v1(191.74,104.48)
  BOTTOM w0.109: U4.D33 v1(191.74,104.48)
N12451802: length 6.7
  TOP w0.109: v1(190.47,108.29) 188.4,106.22 186.1,106.22 185.82,105.94 R193.1
  BOTTOM w0.109: U4.D36 v1(190.47,108.29)
N12451883: length 8.5
  TOP w0.109: R198.1 187.37,107.75 188.74,109.12 188.74,111.15 189.15,111.56 189.93,111.56 v1(190.47,112.1)
  BOTTOM w0.109: U4.D38 v1(190.47,112.1)
N12456803: length 76.8
  TOP w0.109: U2.K15 88.71,136.23 90.44,136.23 90.82,135.85 91.01,135.85 91.49,136.32 91.74,136.32 91.99,136.08 91.99,135.9 91.56,135.47 91.56,135.3 91.74,135.12 91.91,135.12 92.4,135.61 92.58,135.61 92.76,135.43 92.76,135.26 92.26,134.77 92.26,134.59 92.44,134.42 92.62,134.42 92.92,134.72 93.09,134.72 93.46,134.35 93.46,133.98 93.66,133.78 97.33,133.78 97.46,133.91 97.46,134.42 97.33,134.54 95.68,134.54 95.42,134.8 95.42,135.5 95.55,135.63 97.45,135.63 98.36,134.72 98.36,133 98.76,132.6 98.76,132.28 98.61,132.13 96.82,132.13 96.69,132 96.69,129.08 97.46,128.32 97.46,126.75 99.92,124.28 100.88,124.28 101.01,124.16 101.01,122.99 101.14,122.86 102.13,122.86 102.26,122.98 102.26,123.52 v1(101.65,124.13)
  SIG3 w0.107: v1(101.65,124.13) 101.42,124.36 101.42,124.77 101.51,124.87 102.05,124.87 102.26,124.66 102.26,123.59 102.16,123.5 101.61,123.5 101.52,123.4 101.52,123.18 101.61,123.08 102.31,123.08 102.4,122.99 102.4,122.8 102.31,122.71 101.11,122.71 101.01,122.61 101.01,122.42 101.11,122.33 102.31,122.33 102.4,122.24 102.4,122.05 102.31,121.95 101.49,121.95 101.39,121.86 101.39,121.67 101.49,121.58 102.31,121.58 102.4,121.48 102.4,121.3 102.31,121.2 101.76,121.2 101.66,121.11 101.66,120.92 101.76,120.83 102.31,120.83 102.4,120.73 102.4,120.54 102.31,120.45 101.76,120.45 101.66,120.36 101.66,120.17 101.76,120.07 102.31,120.07 102.4,119.98 102.4,119.79 102.31,119.7 101.76,119.7 101.66,119.6 101.66,119.42 101.76,119.32 102.31,119.32 102.4,119.23 102.4,119.04 102.31,118.95 101.76,118.95 101.63,118.82 101.63,106.79 v1(98.36,103.52)
  BOTTOM w0.109: R63.1 96.69,101.8 98.36,103.47 v1(98.36,103.52)
N12456807: length 5.6
  TOP w0.109: U2.K16 92.48,136.73 93.8,135.41 R65.1
N12456811: length 5.2
  TOP w0.109: v1(74.71,136.23) U2.K2
  BOTTOM w0.109: v1(74.71,136.23) 74.71,136.59 72.56,138.74 72.31,138.74 71.93,139.12 R66.1
N12456815: length 7.1
  TOP w0.109: U2.K3 v1(75.71,136.23)
  BOTTOM w0.109: v1(75.71,136.23) 75.23,136.7 75.23,137.34 73.83,138.74 73.2,138.74 72.94,138.99 72.94,139.62 72.44,140.13 R67.1
N12456949: length 3.3
  TOP w0.109: U2.L1 v1(73.71,135.23)
  BOTTOM w0.109: v1(73.71,135.23) 73.71,135.56 73.53,135.74 72.39,135.74 72.06,136.07 R60.1
N12457439: length 1.8
  TOP w0.109: v1(186.79,110.83) 186.75,110.8 R196.2
  BOTTOM w0.109: v1(186.79,110.83) 186.79,110.74 187.29,110.23 U4.A37
N12457473: length 1.9
  TOP w0.109: v1(186.66,112.1) 186.37,111.81 R199.2
  BOTTOM w0.109: U4.A38 v1(186.66,112.1)
N12457550: length 2.8
  TOP w0.109: U2.M1 v1(73.71,134.23)
  BOTTOM w0.109: v1(73.71,134.23) 72.88,134.23 72.69,134.04 R80.1
N12459341: length 8.3
  TOP w0.109: U2.M13 v1(86.71,134.23)
  BOTTOM w0.109: R81.1 92.38,133.91 91.99,134.29 91.11,134.29 90.6,133.78 89.71,133.78 89.26,134.23 v1(86.71,134.23)
N12459393: length 8.6
  TOP w0.109: U2.M14 87.72,134.21 89.66,134.21 91.11,132.77 91.11,132.13 92.38,130.86 R61.1
N12460724: length 6.8
  TOP w0.109: v1(75.71,135.23) 76.71,135.23 U2.L4
  BOTTOM w0.109: v1(75.71,135.23) 75.25,135.69 74.47,135.69 74.21,135.94 74.21,136.45 73.71,136.96 72.31,136.96 72.18,137.08 R79.1
N12462137: length 4.9
  TOP w0.109: U2.N1 v1(73.71,133.23)
  BOTTOM w0.109: R82.1 72.31,130.61 72.59,130.89 72.59,132.51 73.3,133.23 v1(73.71,133.23)
N12467054: length 9.4
  TOP w0.109: U2.N16 90.64,132.3 90.64,131.84 91.06,131.42 91.06,129.41 88.44,126.8 R83.1
N12494143: length 7
  TOP w0.109: U2.P7 79.71,132.23 79.71,128.61 79.29,128.19 R84.1
N12494253: length 5.3
  TOP w0.109: R163.1 R165.1 180.01,91.75 180.06,91.8 180.06,92.43 181.02,93.4 181.66,93.4 181.78,93.52 J3.68
N12494458: length 29.2
  TOP w0.109: v1(106.09,116.51) 106.85,115.75 R934.1 ; U43.AA2 99.27,96.77 100.12,95.91 100.12,95.4 v2(100,95.28)
  SIG3 w0.107: v2(100,95.28) 100,95.91 100.45,96.36 100.45,98.86 100.76,99.17 100.76,100.38 101.77,101.4 102.79,101.4 106.3,104.9 106.3,106.86 106.42,106.99 106.42,110.36 107.11,111.05 107.11,111.68 106.85,111.94 106.85,113.44 106.65,113.64 106.65,115.57 106.09,116.13 v1(106.09,116.51)
N12494514: length 25.3
  TOP w0.109: U43.AC4 98.28,95.49 v2(98.09,95.3)
  SIG3 w0.107: v2(98.09,95.3) 98.09,95.56 99.41,96.88 99.41,100.64 99.82,101.04 99.82,101.68 101.32,103.18 102.49,103.18 104.18,104.87 104.18,111.78 104.54,112.14 104.54,114.56 v1(104.14,114.96)
  BOTTOM w0.109: R935.1 103.36,115.62 104.02,114.96 v1(104.14,114.96)
N12494701: length 7.8
  TOP w0.089: U43.BH1 86.91,98.02 86.91,100.51 87.32,100.91
  TOP w0.109: R973.2 88.57,104.55 87.32,103.3 87.32,100.91
N12494835: length 1.5
  TOP w0.109: U20.F21 v2(139.49,114.63)
  BOTTOM w0.109: v2(139.49,114.63) 140,114.12 R51.2
N12494901: length 76.8
  TOP w0.109: v2(138.35,115.75) 138.43,115.83 U20.G22
  SIG1 w0.086: v1(128.44,137.97) 134.92,137.97 v1(135.17,138.23)
  SIG3 w0.107: v1(128.44,137.97) 126.02,137.97 121.62,142.37 118.02,142.37 115.43,144.96 93.01,144.96 91.28,143.23 v1(90.72,143.23) ; v1(135.17,138.23) 135.94,137.47 136.7,137.47 137.97,136.2 137.97,133.91 139.06,132.82 139.06,131.55 139.49,131.12 139.49,129.21 139.11,128.83 139.11,116.51 v2(138.35,115.75)
  BOTTOM w0.109: v1(90.72,143.23) 89.53,142.04 R52.2
N12495914: length 149.4
  SIG1 w0.086: v1(82.59,110.8) 83.13,111.33 83.13,112.98 85.18,115.03 85.18,117.7 88.8,121.32 91.36,121.32 91.71,121.67 93.44,121.67 94.15,120.96 97.07,120.96 97.79,121.67 98.1,121.67 98.71,122.28 102.33,122.28 102.38,122.33 104.3,122.33 104.85,122.88 109.46,122.88 110.53,123.95 111.98,123.95 112.44,123.5 114.1,123.5 114.48,123.87 119.78,123.87 v1(120.04,123.62)
  SIG4 w0.086: v1(120.04,123.62) 120.04,134.14 122.08,136.18 122.08,148.37 124.75,151.05 140.14,151.05 141.42,149.77 141.42,149.26 142.91,147.77 160.69,147.77 163.08,145.38 163.08,128.98 163.46,128.6 163.46,124.42 164.72,123.16 165.1,123.16 165.81,122.45 165.81,121.23 v1(164.38,119.81)
  BOTTOM w0.109: R48.1 82.85,109.25 82.98,109.37 82.98,110.41 v1(82.59,110.8) ; R47.1 v1(164.38,119.81) 165.02,119.81 165.96,118.87 U26.34
N12495922: length 3.2
  BOTTOM w0.109: R49.1 R46.1 167.43,119.89 167.15,119.61 167.15,119.13 166.96,118.93 U26.36
N12495930: length 2.4
  BOTTOM w0.109: R50.1 165.4,119.94 166.46,118.88 U26.35
N12501290: length 2.4
  TOP w0.109: U2.R16 90.11,131.73 v1(90.6,131.24)
  BOTTOM w0.109: v1(90.6,131.24) 90.75,131.39 R1207.1
N12501313: length 21.1
  TOP w0.109: U2.R3 v1(75.71,131.23)
  SIG3 w0.107: v1(92.76,129.46) 92.42,129.11 85.41,129.11 85.04,128.75 83.31,128.75 81.85,130.2 77.11,130.2 76.08,131.23 v1(75.71,131.23)
  BOTTOM w0.109: R1208.1 93.52,130.86 92.76,130.1 v1(92.76,129.46)
N12509695: length 5.5
  TOP w0.279: J3.18 169.28,93.57 169.56,93.29 172.11,93.29 v1(172.51,92.89)
  BOTTOM w0.381: v1(172.51,92.89) 173.15,93.52 R162.1
N12509699: length 5.7
  TOP w0.279: J3.16 168.78,93.25 169.22,92.81 171.32,92.81 v1(171.62,92.51)
  BOTTOM w0.381: R161.1 171.75,92.63 v1(171.62,92.51)
N12509703: length 4.6
  TOP w0.279: v1(169.19,92.25) 169.11,92.25 168.28,93.08 J3.14
  BOTTOM w0.381: v1(169.19,92.25) 170.35,93.42 R160.1
N12509707: length 2.7
  TOP w0.279: v1(167.76,93.24) 167.78,93.26 J3.12
  BOTTOM w0.381: v1(167.76,93.24) 168.55,93.24 168.96,93.65 R159.1
N12515607: length 8.5
  TOP w0.109: U2.L14 87.68,135.26 90.27,135.26 91.87,133.66 91.87,133.16 93.15,131.88 R71.1
N12522400: length 2.1
  TOP w0.229: v1(182.93,157.4) 183.07,157.54 U8.17
  BOTTOM w0.381: v1(182.93,157.4) 183.16,157.4 183.54,157.02 R232.1
N12522404: length 3.8
  TOP w0.381: v1(180.51,154.36) 180.51,155.54
  BOTTOM w0.381: C124.2 v1(180.51,154.36) ; R233.1 182.62,160.25 v1(182.8,160.07)
N12522444: length 7.2
  TOP w0.229: U8.23 186.47,155.16 185.31,154 185.31,152.22 185.57,151.97 C117.1 v1(185.97,151.1)
  BOTTOM w0.229: C116.1 186.13,151.26 v1(185.97,151.1)
N12522448: length 8.5
  TOP w0.229: R226.2 R229.1 189.56,153.19 189.3,153.44 R228.1 R227.2 C117.2 185.97,153.72 186.97,154.72 U8.24
N12522508: length 4.7
  TOP w0.229: C118.1 192.32,151.69 191.69,151.05 189.28,151.05 188.77,151.56 R228.2
N12522632: length 4.4
  TOP w0.229: U8.21 185.47,155.43 185.04,154.99 184.07,154.99 183.18,154.1 R231.1
N12522664: length 4.7
  TOP w0.229: R230.2 v1(184.58,154.36) 185.06,154.36 185.97,155.27 U8.22
  BOTTOM w0.229: R230.2 v1(184.58,154.36)
N12522708: length 2.1
  BOTTOM w0.381: R233.2 C131.1
N12523074: length 6.9
  TOP w0.229: U8.1 187.99,157.04 188.26,156.77 188.26,154.99 188.9,154.36 191.61,154.36 191.84,154.58 R234.2
N12523098: length 4.6
  TOP w0.229: U8.19 184.47,156.03 183.43,154.99 182.55,154.99 181.78,154.23 C114.2
N12523126: length 2.7
  TOP w0.229: v1(183.18,155.8) 183.18,156.77 183.46,157.04 U8.18
  BOTTOM w0.381: v1(183.18,155.8) 183.54,155.45 C115.2
N12526727: length 9.1
  TOP w0.254: L1.1 196.29,79.5 SW1.3
  BOTTOM w0.254: SW1.3 SW1.4
N12526853: length 15.7
  TOP w0.109: R1.2 195.65,86 v1(196.13,85.52) ; L1.2 197.76,80.85 198.17,80.44 v1(199.18,80.44) 199.82,80.44 200.43,81.05 C1.1
  BOTTOM w0.109: R3.1 200.43,81.05 199.82,80.44 v1(199.18,80.44) 198.42,80.44 197.79,81.08 197.79,84.13 197.28,84.63 Q1.1 196.57,85.08 v1(196.13,85.52)
N12527177: length 20.8
  TOP w0.254: L2.1 195.63,82.73 195.37,82.47 195.37,79.17 195.25,79.05 195.25,71.52 SW2.3 SW2.4
N12527267: length 6.7
  TOP w0.109: R9.1 200.55,84.79 200.26,85.08 Q4.1 199.56,84.13 199.46,84.02 C2.1 R7.2 198.93,82.22 198.42,82.73 L2.2
N12527562: length 5.9
  TOP w0.109: R72.1 93.8,133.15 93.55,133.4 93.01,133.4 92.63,133.78 92.25,133.78 90.3,135.73 U2.L16
N12528497: length 4.8
  TOP w0.109: R59.2 82.72,148.49 83.21,148.01 U2.A10
N12541458: length 4.2
  TOP w0.109: U2.L2 v1(74.71,135.23)
  BOTTOM w0.109: v1(74.71,135.23) 74.15,134.67 72.77,134.67 72.39,135.05 R74.1
N12546465: length 4.8
  TOP w0.109: R64.2 83.74,146.2 U2.A11
N12556062: length 3
  TOP w0.109: R37.2 R42.1 C8.2 R32.2
N12556533: length 3
  TOP w0.109: R33.2 R43.1 C9.2 R38.2
N12557485: length 3.9
  TOP w0.109: R34.2 C10.2 R44.1 162.99,131.75 162.66,132.08 162.02,132.08 R39.2
N12558669: length 3
  TOP w0.109: R35.2 R45.1 C11.2 R40.2
N12558773: length 2
  TOP w0.109: R36.2 C12.2 R41.2
N12558953: length 2
  TOP w0.109: R30.2 C7.2 R25.2
N12560407: length 2
  TOP w0.109: R26.2 C5.2 R21.2
N12560503: length 2
  TOP w0.109: R22.2 C3.2 R27.2
N12560842: length 2
  TOP w0.109: R23.2 R28.2 C6.2
N12560934: length 3.1
  TOP w0.109: R29.2 C4.2 155.09,92.35 154.96,92.23 R31.1 R24.2
N12564156: length 1.8
  TOP w0.109: U1.2 v1(152.29,101.67)
  BOTTOM w0.109: R55.2 152.53,101.91 v1(152.29,101.67)
N12564196: length 9.3
  TOP w0.33: 158.03,101.02 U1.6
  TOP w0.381: L4.1 C19.1 157.78,97.97 159.33,99.52 C20.2 158.42,100.64 158.03,101.02
N12564244: length 4.3
  TOP w0.109: R54.1 148.92,99.01 149.91,100 149.91,100.51 150.42,101.02 U1.3
N12564264: length 2.6
  TOP w0.109: U1.5 157.78,100.37 157.91,100.25 157.91,100.07 v1(157.69,99.86)
  BOTTOM w0.109: v1(157.69,99.86) 157.69,100.21 157.5,100.41 R56.1
N12564408: length 2.2
  TOP w0.109: U1.7 157.68,101.67 v1(158.16,102.16)
  BOTTOM w0.109: R58.1 157.91,101.91 v1(158.16,102.16)
N12564466: length 2.6
  TOP w0.109: U1.8 157.69,102.32 158.16,102.79 v1(158.16,103.18)
  BOTTOM w0.109: v1(158.16,103.18) 157.91,102.92 C13.1
N12565688: length 4.1
  TOP w0.109: OSC1.3 145.46,103.56 145.84,103.94 R57.1
N12565730: length 0.8
  TOP w0.381: C16.2 138.5,97.49
  vias: v1(139.09,98.04) v1(139.09,97.31)
N12568148: length 3.9
  TOP w0.109: R323.1 R324.1 117.52,77.14 118.03,77.65 v1(118.54,77.65)
  BOTTOM w0.109: v1(118.54,77.65) 118.92,78.03 U18.5
N12568156: length 3.4
  TOP w0.109: v1(120.19,77.52) 119.93,77.52 119.55,77.14 R322.1 R321.1
  BOTTOM w0.109: U18.6 v1(120.19,77.52)
N12568164: length 3.1
  TOP w0.109: R319.1 R318.1 121.59,77.39 v1(121.46,77.52)
  BOTTOM w0.109: U18.7 v1(121.46,77.52)
N12569009: length 4.9
  TOP w0.109: R331.1 136.6,98.07 135.81,98.86 U19.6
N12569029: length 4.8
  TOP w0.109: U19.5 135.68,97.59 136.06,97.21 136.06,94.92 136.19,94.79 R332.1
N12569077: length 3.2
  TOP w0.109: R325.2 R328.2 U19.1
N12569081: length 3.6
  TOP w0.109: R326.2 R329.2 127.3,99.37 128.06,100.13 U19.2
N12569085: length 3.9
  TOP w0.109: U19.3 128.44,98.86 126.92,97.33 R327.2 R330.2
N12569141: length 2.3
  TOP w0.109: R333.2 135.84,100.15 135.81,100.13 U19.7
N12580885: length 3.7
  BOTTOM w0.109: Q14.1 169.66,99.05 169.06,98.45 R167.1 R168.1
N12580929: length 1.7
  TOP w0.109: R166.1 189.89,55.07 190.22,54.74 D20.1
N12580933: length 56.3
  TOP w0.109: v1(191.69,60.38) 191.69,59.11 189.28,56.69 R166.2
  SIG3 w0.107: v1(191.69,60.38) 191.05,61.01 191.05,62.15 192.32,63.42 192.32,64.06 191.82,64.57 187.63,64.57 187.12,65.08 187.12,65.46 184.2,68.38 184.2,76.25 181.91,78.54 181.91,85.78 175.37,92.32 v1(175.37,95.62)
  BOTTOM w0.109: Q14.3 172.13,97.33 172.51,96.95 174.04,96.95 v1(175.37,95.62)
N12727421: length 28.2
  TOP w0.109: U2.K14 v1(87.71,136.23)
  SIG1 w0.086: v1(87.71,136.23) 87.87,136.07 97.79,136.07 98.88,137.16 v1(98.88,137.47)
  BOTTOM w0.109: v1(98.88,137.47) 98.88,135.2 98.29,134.62 98.29,132.68 99.39,131.58 100.29,131.58 100.82,131.05 100.82,129.41 103.81,126.43 R98.2
N12727425: length 1.3
  TOP w0.109: U20.F22 v2(138.69,114.63)
  BOTTOM w0.109: v2(138.69,114.63) 138.41,114.35 R53.2
N13190675: length 5.3
  TOP w0.109: R19.2 62.76,37.64 64.16,37.64 R1094.2 65.07,37.14 65.4,37.46 U54.6
N13190679: length 5.5
  TOP w0.109: R20.2 62.76,36.63 64.16,36.63 R1093.2 65.07,36.12 65.76,36.81 U54.7
N13251249: length 13.4
  TOP w0.508: R1209.1 165.25,14.17 165.24,14.18 R311.2 165.78,14.66 165.81,14.68 C224.1 166.44,7.54 JP1.1
N13251327: length 9.5
  TOP w0.109: JP1.3 159.94,6.12 R314.1
N13251979: length 6.3
  TOP w0.508: JP2.1 163.14,10.08 R312.2 C225.1 R313.1
N13252027: length 4.2
  TOP w0.109: R315.1 158.92,9.93 JP2.3
N13252429: length 5
  BOTTOM w0.508: R316.1 BZ1.1
N13252463: length 1.8
  BOTTOM w0.508: R316.2 153.28,24.18 D21.1
N13331287: length 6.8
  TOP w0.109: v1(59.74,149.15) 59.23,149.15 59.1,149.02 R120.2 59.38,148.62 60.47,147.52 R119.1
  BOTTOM w0.109: v1(59.74,149.15) 59.86,149.15 61.01,148.01 Q7.1
N13331331: length 2.7
  TOP w0.109: D16.1 60.42,148.46 60.24,148.64 60.24,149.4 59.84,149.81 R118.1
N13331335: length 2.5
  TOP w0.109: R118.2 59.46,150.77 v1(60.12,151.44)
  BOTTOM w0.109: Q7.3 60.37,151.18 v1(60.12,151.44)
N13331583: length 4.9
  TOP w0.109: v1(69.01,149.15) 69.01,149.4 69.29,149.68 R122.1 R123.2
  BOTTOM w0.109: v1(69.01,149.15) 67.61,149.15 67.3,149.46 Q8.1
N13331627: length 1.6
  TOP w0.109: D17.1 64.23,148.34 64.08,148.49 R121.1
N13331631: length 5.5
  TOP w0.109: R121.2 63.9,147.52 64.31,147.12 67.1,147.12 67.33,147.35 v1(67.33,147.65)
  BOTTOM w0.109: v1(67.33,147.65) 67.69,148.01 Q8.3
N13331888: length 3.1
  TOP w0.109: R126.2 R125.1 v1(63.42,151.44)
  BOTTOM w0.109: v1(63.42,151.44) 63.36,151.38 Q9.1
N13331932: length 1.6
  TOP w0.109: D18.1 67.66,148.34 67.38,148.62 R124.1
N13331936: length 2.4
  TOP w0.109: R124.2 v1(65.86,147.65)
  BOTTOM w0.109: Q9.3 65.5,148.01 v1(65.86,147.65)
N13334771: length 5.7
  TOP w0.109: Q2.3 160.7,97.46 v1(161.26,96.9)
  BOTTOM w0.109: v1(161.26,96.9) 161.26,96.11 160.89,95.74 Q3.1 160.57,95.17 159.84,94.44 R5.2
N13334891: length 4.5
  TOP w0.109: Q2.1 158.29,95.17 v1(157.91,95.56)
  BOTTOM w0.109: v1(157.91,95.56) 157.91,94.54 158.39,94.06 R4.2 R6.2
N13350702: length 3.4
  BOTTOM w0.109: R1085.1 R1079.2 126.92,70.79 127.02,70.69 U53.3
N13350706: length 4.8
  BOTTOM w0.109: R1083.1 R1080.2 126.54,72.82 126.77,72.59 126.77,71.32 126.92,71.17 127.68,71.17 127.85,71.34 U53.4
N13352439: length 6.7
  BOTTOM w0.109: C692.2 137.23,67.97 136.98,68.22 R1084.1 135.81,68.89 135.31,69.39 U53.20 133.54,69.39 133.37,69.55 133.37,69.88 133.53,70.04 U53.19
N13362638: length 2.5
  TOP w0.109: v1(140.69,73.13) 140.5,72.95 D7.1
  BOTTOM w0.109: R18.1 140.62,73.2 v1(140.69,73.13)
N13362837: length 3
  TOP w0.109: v1(140.05,72.16) 140.05,71.35 139.62,70.92 D4.1
  BOTTOM w0.109: v1(140.05,72.16) 139.98,72.09 R15.1
N13362858: length 3.9
  TOP w0.109: v1(139.98,70.08) 139.98,69.37 139.49,68.89 D5.1
  BOTTOM w0.109: R16.1 141.17,70.43 140.81,70.08 v1(139.98,70.08)
N13362901: length 3.8
  TOP w0.109: v1(140.98,74.46) 140.98,74.51 140.51,74.98 D6.1
  BOTTOM w0.109: R17.1 139.98,74.75 140.27,74.46 v1(140.98,74.46)
N13419508: length 3.1
  TOP w0.109: D1.1 158.75,93.5 v1(159.05,93.8)
  BOTTOM w0.109: v1(159.05,93.8) 159.05,92.76 159.3,92.51 R2.2
N13419676: length 4.7
  TOP w0.109: v1(95.42,129.97) 94.92,129.47 94.92,127.31 94.61,127 D2.1
  BOTTOM w0.109: v1(95.42,129.97) 95.55,129.97 96.03,129.49 R8.2
N13419890: length 5.2
  TOP w0.109: v1(92.3,124.18) 92.3,124.71 90.88,126.14 R14.1 R11.2
  BOTTOM w0.109: v1(92.3,124.18) 92.05,124.43 Q6.1
N13421232: length 8.7
  TOP w0.109: R317.2 R320.2 122.69,73.81 123.05,73.46 123.05,71.24 v1(122.35,70.54)
  BOTTOM w0.109: U18.3 120.19,72.44 121.02,71.61 121.27,71.61 v1(122.35,70.54)
N13449203: length 7.6
  BOTTOM w0.109: Q22.3 Q19.1 126.99,161.15 127.43,160.71 130.09,160.71 130.35,160.96 R268.2
N13449305: length 3
  TOP w0.109: R273.2 R276.1 v1(124.74,158.27)
  BOTTOM w0.109: v1(124.74,158.27) 124.82,158.35 Q22.1
N13450062: length 5.9
  BOTTOM w0.109: Q23.1 94.22,123.31 95.04,124.13 Q26.3 95.93,125.27 97.18,126.52 R277.2
N13450164: length 6.8
  BOTTOM w0.254: Q26.1 94.1,127.12 93.52,126.54 90.34,126.54 88.85,128.04 R284.2
N13467875: length 5.5
  BOTTOM w0.109: U53.16 135.99,71.99 136.19,72.19 R1087.1 R1088.1 R1090.1 R1089.1
N13470118: length 7.4
  TOP w0.109: 121.21,64.19 121.05,64.03 120.73,64.03 120.56,64.19 U55.3 ; 121.21,64.19 121.72,63.68 123.31,63.68 124.43,64.8 124.89,64.8 125.01,64.92 R1096.2 ; 121.21,64.19 U55.2
N13473742: length 3
  TOP w0.229: U7.19 191.33,39.4 v1(191.05,39.68)
  BOTTOM w0.229: C96.2 190.42,39.04 v1(191.05,39.68)
N13473942: length 4.5
  TOP w0.229: v1(190.93,36.37) 191.96,37.4 U7.23
  BOTTOM w0.229: C95.1 C98.1 190.8,36.25 v1(190.93,36.37)
N13473946: length 16.2
  TOP w0.229: U7.24 192.35,36.9 v1(191.82,36.37) 191.31,35.87 190.55,35.87 190.17,36.25 R218.1 R219.1 R215.2 189.89,32.92 189.02,32.06 R217.2 186.97,31.19 187.19,30.96 R216.2
  BOTTOM w0.229: v1(191.82,36.37) 191.82,36.63 191.49,36.96 188.72,36.96 188.41,36.65 C98.2
N13473950: length 3.5
  TOP w0.229: R215.1 187.88,33.45 v1(187.5,33.07)
  BOTTOM w0.229: C95.2 187.98,34.85 187.75,34.62 187.75,33.33 v1(187.5,33.07)
N13474144: length 1.7
  TOP w0.229: R218.2 187.37,36.25 187.35,36.22 C99.1
N13474224: length 2.9
  TOP w0.229: U7.21 191.31,38.4 190.67,39.04 R222.1
N13474252: length 4.6
  TOP w0.229: R221.2 191.31,37.64 v1(191.57,37.9) U7.22
  BOTTOM w0.229: v1(191.57,37.9) 191.31,37.64 R221.2
N13474272: length 9.4
  TOP w0.229: C97.2 186.51,37.77 186.86,38.13 186.86,39.29 188.13,40.56 193.01,40.56 193.23,40.34 U7.18
N13474364: length 10.5
  TOP w0.381: R224.1 199.23,41.53 ; v1(187.02,40.95) 186.76,40.69 C105.2
  BOTTOM w0.381: v1(194.99,40.95) v1(187.02,40.95)
N13474368: length 1.5
  TOP w0.381: C105.1 R223.2
N13474526: length 2.7
  TOP w0.229: R214.1 192.32,34.6 193.23,35.5 U7.1
N13474606: length 9.3
  TOP w0.229: U7.17 193.73,40.55 193.21,41.07 187.88,41.07 186.67,39.87 186.42,39.87 186.08,39.52 R223.1
N13474690: length 2.1
  TOP w0.381: C113.1 200.94,38.89 201.16,39.12 R224.2
N13478611: length 2.1
  TOP w0.381: v1(140.25,158.93) 140.13,158.8 U6.7
  BOTTOM w0.381: C85.1 140.23,158.9 v1(140.25,158.93)
N13478619: length 5.6
  TOP w0.381: U6.2 132.81,158.8 v1(132.23,159.39)
  BOTTOM w0.381: v1(132.23,159.39) 132.25,159.39 132.3,159.44 C86.2 R209.2 R211.1
N13478663: length 5.4
  TOP w0.381: U6.3 132.63,157.53 v1(132.13,158.04)
  BOTTOM w0.381: v1(132.13,158.04) 132.13,155.75 132.63,155.25 C88.1
N13478671: length 4.9
  TOP w0.381: v1(132,154.74) 132,155.88 132.38,156.26 U6.4
  BOTTOM w0.381: C90.1 133.04,153.87 132.48,153.87 132,154.36 v1(132,154.74)
N13478763: length 2.2
  BOTTOM w0.381: R212.1 144.24,156.21 143.79,156.67 C89.2
N13478791: length 3.1
  BOTTOM w0.381: C85.2 139.98,157.43 v1(140.48,157.94) ; C89.1 141.02,156.9 v1(140.76,157.15)
N13479725: length 5.2
  TOP w0.381: v1(135.43,160.96) 134.91,160.96 134.64,161.23 R210.1 R207.1
  BOTTOM w0.381: R208.2 135.17,160.71 v1(135.43,160.96) 135.43,161.21 134.92,161.72 C87.1
N13485147: length 9.4
  TOP w0.089: U43.AD76 97.89,63 97.89,62.41 98.07,62.22 98.07,61.7 97.99,61.62 97.99,59.97
  TOP w0.109: 97.99,59.97 98.22,59.74 98.22,59.23 100.63,56.82 101.9,56.82 102.15,56.57 R835.2
N13485239: length 5.6
  TOP w0.381: R308.1 R304.2 C216.2 172.26,67.23 172,67.49 U17.2
N13485295: length 4.5
  TOP w0.381: 162.61,69.65 164.41,71.45 C217.1
  BOTTOM w0.381: C215.2 v1(163.72,68.86)
N13485589: length 3.4
  TOP w0.381: R303.2 172.64,65.96 171.88,66.73 171.24,66.73 170.73,66.22 U17.1
N13485597: length 2
  TOP w0.381: U17.7 v1(163.75,67.49)
  BOTTOM w0.381: v1(163.75,67.49) 163.85,67.39 C215.1
N13485605: length 2.6
  TOP w0.381: U17.3 170.73,68.76 v1(171.37,68.12)
  BOTTOM w0.381: C218.1 171.09,68.4 v1(171.37,68.12)
N13485609: length 4.4
  TOP w0.381: U17.4 171.34,70.03 v1(171.9,70.59)
  BOTTOM w0.381: C219.1 C220.1 171.73,70.41 v1(171.9,70.59)
N13485681: length 2.4
  TOP w0.381: R309.1 C217.2
N13488505: length 4.7
  BOTTOM w0.109: Q30.3 158.8,74.6 157.85,75.55 Q29.1 157.15,76.38 157.5,76.73 R305.2
N13488607: length 2
  BOTTOM w0.109: R310.2 161.06,76.91 161.84,76.12 Q30.1
N13745783: length 2.3
  TOP w0.109: v2(92.35,64.39) 92.35,64.08 92.84,63.6 U43.AP75
  BOTTOM w0.109: R957.2 v2(92.35,64.39)
N14074963: length 96.3
  TOP w0.099: U43.A38 108.84,81 108.69,81 108.61,80.92 108.61,80.78 108.85,80.54 109.36,80.54 109.39,80.57 110.92,80.57 112.19,79.3 112.52,79.3 112.67,79.45 112.97,79.45 113.12,79.3 114.43,79.3 114.58,79.45 114.88,79.45 115.03,79.3 115.33,79.3 115.48,79.45 115.78,79.45 115.93,79.3 116.84,79.3 116.99,79.45 117.29,79.45 117.44,79.3 127.17,79.3 132.81,84.94 132.81,85.19 v1(132.46,85.54) ; v1(193.92,96.01) 194.25,95.68 194.64,95.68 C728.1
  SIG1 w0.094: v1(132.46,85.54) 132.78,85.86 132.78,86.15 133.55,86.92 173.93,86.92 181.3,94.29 188.26,94.29 189.02,95.05 191.31,95.05 191.95,95.69 193.61,95.69 v1(193.92,96.01)
N14074967: length 97.9
  TOP w0.099: U43.D37 107.68,81.42 108.03,81.07 108.37,81.07 108.52,81.22 111,81.22 111.9,80.32 112.34,80.32 112.31,80.29 125.48,80.29 130.04,84.86 130.04,85.19 v1(130.38,85.52) ; C725.1 194.38,100.51 193.98,100.51 v1(193.67,100.2)
  SIG1 w0.094: v1(130.38,85.52) 130.06,85.84 130.06,85.93 131.68,87.55 173.53,87.55 184.07,98.1 186.74,98.1 188.62,99.97 192.3,99.97 192.84,100.51 193.35,100.51 v1(193.67,100.2)
N14074969: length 102.4
  TOP w0.099: U43.B35 108.31,82.28 108.43,82.28 108.56,82.41 111.23,82.41 111.26,82.43 111.55,82.43 111.71,82.58 112,82.58 112.16,82.43 112.65,82.43 112.8,82.58 113.1,82.58 113.25,82.43 113.66,82.43 113.82,82.58 114.11,82.58 114.27,82.43 114.64,82.43 114.85,82.22 115.49,82.22 115.74,82.47 116.04,82.47 116.19,82.63 116.49,82.63 116.64,82.47 116.94,82.47 117.09,82.63 117.39,82.63 117.54,82.47 117.84,82.47 117.99,82.63 118.29,82.63 118.44,82.47 118.74,82.47 118.89,82.63 119.19,82.63 119.34,82.47 119.64,82.47 119.79,82.63 120.09,82.63 120.24,82.47 122.5,82.47 128.27,88.24 128.27,89.25 v1(127.9,89.61) ; v1(193.67,111.25) 193.99,110.92 194.38,110.92 C722.1
  SIG1 w0.094: v1(193.67,111.25) 193.35,110.93 192.84,110.93 191.05,109.14 191.05,107.75 188.01,104.7 186.48,104.7 173.27,91.49 158.42,91.49 157.78,90.86 128.85,90.86 128.22,90.23 128.22,89.93 v1(127.9,89.61)
N14074975: length 107.1
  TOP w0.099: v1(126.82,91.36) 126.59,91.13 126.59,87.75 122.09,83.26 112.02,83.26 112,83.28 111.35,83.28 110.79,82.73 109.27,82.73 109.15,82.61 108.62,82.61 108.48,82.75 107.83,82.75 U43.C34 ; C719.1 194.38,117.02 194.01,117.02 v1(193.69,116.7)
  SIG1 w0.094: v1(126.82,91.36) 126.51,91.68 126.51,91.78 126.73,92 140.25,92 140.76,91.49 157,91.49 158.39,92.89 160.68,92.89 162.33,94.54 170.21,94.54 175.16,99.49 177.47,99.49 186.23,108.26 187.99,108.26 193.09,113.36 193.09,116.89 193.21,117.02 193.37,117.02 v1(193.69,116.7)
N14074977: length 116.2
  TOP w0.099: U43.A31 109.64,83.89 110.56,84.82 110.53,84.82 111.43,85.73 111.73,85.73 111.88,85.88 112.18,85.88 112.33,85.73 112.63,85.73 112.78,85.88 113.08,85.88 113.23,85.73 113.53,85.73 113.68,85.88 113.98,85.88 114.13,85.73 114.43,85.73 114.58,85.88 114.88,85.88 115.03,85.73 115.33,85.73 115.48,85.88 115.78,85.88 115.93,85.73 116.23,85.73 116.38,85.88 116.68,85.88 116.83,85.73 117.13,85.73 117.28,85.88 117.58,85.88 117.73,85.73 118.03,85.73 118.18,85.88 118.47,85.88 118.63,85.73 119.76,85.73 120.01,85.98 120.01,86.12 120.22,86.33 120.37,86.33 120.6,86.57 120.6,86.72 120.81,86.93 120.96,86.93 121.17,87.14 121.17,87.28 121.38,87.49 121.52,87.49 122.7,88.67 122.7,91.29 v1(122.38,91.62) ; C716.1 195.65,127.43 195.28,127.43 v1(194.96,127.75)
  SIG1 w0.094: v1(194.96,127.75) 194.64,127.43 193.85,127.43 192.07,125.65 189.91,125.65 188.9,124.64 188.9,121.21 181.15,113.46 181.15,110.41 178.61,107.87 178.61,103.53 176.6,101.52 170.1,101.52 169.21,100.64 159.94,100.64 155.11,95.81 154.1,95.81 152.95,94.67 124.15,94.67 122.73,93.25 122.73,91.97 v1(122.38,91.62)
N14074985: length 96.3
  TOP w0.099: U43.C38 107.78,80.82 108.28,80.82 108.76,80.34 109.36,80.34 109.39,80.31 110.82,80.31 112.08,79.05 127.28,79.05 133.07,84.83 133.07,85.26 v1(133.35,85.54) ; C727.1 194.64,95.43 194.24,95.43 v1(193.92,95.12)
  SIG1 w0.094: v1(193.92,95.12) 193.61,95.43 192.06,95.43 191.41,94.79 189.13,94.79 188.37,94.03 181.4,94.03 174.04,86.67 133.65,86.67 133.04,86.05 133.04,85.86 v1(133.35,85.54)
N14074987: length 99
  TOP w0.099: C724.1 194.38,105.84 193.99,105.84 v1(193.67,106.17) ; U43.A36 109.05,81.91 109.15,81.82 111.57,81.82 111.98,81.4 112.4,81.4 112.43,81.43 115.82,81.43 115.98,81.58 116.27,81.58 116.43,81.43 116.84,81.43 116.99,81.58 117.29,81.58 117.44,81.43 117.74,81.43 117.89,81.58 118.19,81.58 118.34,81.43 118.64,81.43 118.79,81.58 119.09,81.58 119.24,81.43 119.54,81.43 119.69,81.58 119.99,81.58 120.14,81.43 120.44,81.43 120.59,81.58 120.89,81.58 121.04,81.43 121.34,81.43 121.49,81.58 121.79,81.58 121.94,81.43 122.23,81.43 122.39,81.58 122.68,81.58 122.84,81.43 123.21,81.43 123.42,81.64 123.42,81.86 123.63,82.07 123.85,82.07 124.06,82.28 124.06,82.49 124.27,82.7 124.48,82.7 129.08,87.3 130.09,87.3 130.6,87.81 130.6,88.23 v1(130.24,88.59)
  SIG1 w0.094: v1(193.67,106.17) 193.35,105.84 191.82,105.84 188.39,102.41 186.25,102.41 173.68,89.84 131.13,89.84 130.56,89.27 130.56,88.91 v1(130.24,88.59)
N14074993: length 102.5
  TOP w0.099: C721.1 194.38,110.67 193.98,110.67 v1(193.67,110.36) ; v1(128.79,89.61) 128.52,89.33 128.52,88.14 122.6,82.22 115.85,82.22 115.6,81.97 114.75,81.97 114.54,82.18 111.26,82.18 111.23,82.21 108.64,82.21 108.5,82.07 108.04,82.07 107.7,82.41 U43.D35
  SIG1 w0.094: v1(128.79,89.61) 128.48,89.93 128.48,90.13 128.95,90.6 157.89,90.6 158.52,91.24 173.38,91.24 186.59,104.45 188.11,104.45 191.31,107.64 191.31,109.04 192.94,110.67 193.35,110.67 v1(193.67,110.36)
N14074995: length 111.8
  TOP w0.099: C718.1 195.65,122.35 195.28,122.35 v1(194.96,122.67) ; v1(123.97,89.59) 124.3,89.25 124.3,88.37 120.62,84.68 119.22,84.68 119.07,84.84 118.77,84.84 118.62,84.68 118.13,84.68 117.98,84.84 117.68,84.84 117.53,84.68 117.23,84.68 117.08,84.84 116.78,84.84 116.63,84.68 116.33,84.68 116.18,84.84 115.88,84.84 115.73,84.68 115.43,84.68 115.28,84.84 114.98,84.84 114.83,84.68 114.53,84.68 114.38,84.84 114.08,84.84 113.93,84.68 113.63,84.68 113.48,84.84 113.18,84.84 113.03,84.68 112.49,84.68 112.34,84.84 112.04,84.84 111.89,84.68 111.41,84.68 110.65,83.92 110.58,83.85 110.57,83.81 110.52,83.76 110.16,83.4 108.63,83.4 108.5,83.26 108.32,83.26 U43.B32
  SIG1 w0.094: v1(123.97,89.59) 124.28,89.9 124.28,91.37 126.18,93.27 153.99,93.27 158.69,97.97 168.22,97.97 170.88,100.64 176.98,100.64 179.88,103.53 179.88,106.86 185.21,112.19 185.21,116 191.56,122.35 194.64,122.35 v1(194.96,122.67)
N14075001: length 116.2
  TOP w0.099: C715.1 195.65,127.18 195.28,127.18 v1(194.96,126.86) ; v1(123.27,91.62) 122.96,91.31 122.96,88.57 119.86,85.47 111.54,85.47 110.68,84.62 110.65,84.62 109.72,83.69 109.22,83.69 109.13,83.6 108.74,83.6 108.6,83.74 107.83,83.74 U43.C31
  SIG1 w0.094: v1(123.27,91.62) 122.98,91.9 122.98,93.14 124.25,94.41 153.06,94.41 154.2,95.56 155.22,95.56 160.05,100.38 169.32,100.38 170.21,101.27 176.7,101.27 178.86,103.43 178.86,107.77 181.4,110.31 181.4,113.36 189.15,121.1 189.15,124.53 190.02,125.4 192.18,125.4 193.95,127.18 194.64,127.18 v1(194.96,126.86)
N14075005: length 97.9
  TOP w0.099: v1(193.67,101.09) 193.99,100.76 194.38,100.76 C726.1 ; v1(129.49,85.52) 129.79,85.22 129.79,84.96 129.19,84.36 128.97,84.36 128.76,84.15 128.76,83.93 128.55,83.72 128.33,83.72 128.12,83.51 128.12,83.3 127.91,83.09 127.7,83.09 127.49,82.88 127.49,82.66 127.28,82.45 127.06,82.45 126.85,82.24 126.85,82.02 126.64,81.81 126.43,81.81 126.22,81.6 126.22,81.39 126.01,81.18 125.79,81.18 125.58,80.97 125.58,80.75 125.37,80.54 115.88,80.54 115.72,80.7 115.43,80.7 115.27,80.54 114.98,80.54 114.82,80.7 114.53,80.7 114.38,80.54 114.08,80.54 113.93,80.7 113.63,80.7 113.48,80.54 113.18,80.54 113.03,80.7 112.73,80.7 112.58,80.54 112.28,80.54 112.25,80.52 111.99,80.52 111.09,81.42 108.39,81.42 108.39,81.42 U43.B37
  SIG1 w0.094: v1(129.49,85.52) 129.81,85.84 129.81,86.04 131.58,87.81 173.42,87.81 183.96,98.35 186.63,98.35 188.51,100.23 192.2,100.23 192.74,100.77 193.35,100.77 v1(193.67,101.09)
N14075011: length 99.1
  TOP w0.099: v1(131.13,88.59) 130.86,88.32 130.86,87.7 130.2,87.05 129.18,87.05 123.31,81.18 112.43,81.18 112.4,81.2 111.9,81.2 111.48,81.62 108.73,81.62 108.58,81.76 107.84,81.76 U43.C36 ; v1(193.67,105.28) 193.98,105.59 194.38,105.59 C723.1
  SIG1 w0.094: v1(131.13,88.59) 130.81,88.91 130.81,89.16 131.24,89.59 173.78,89.59 186.36,102.16 188.49,102.16 191.92,105.59 193.36,105.59 v1(193.67,105.28)
N14075013: length 107
  TOP w0.099: v1(125.94,91.36) 126.03,91.36 126.34,91.06 126.34,87.86 122.62,84.15 122.41,84.15 122.2,83.94 122.2,83.72 121.99,83.51 121.18,83.51 121.02,83.66 120.73,83.66 120.57,83.51 120.28,83.51 120.12,83.66 119.83,83.66 119.67,83.51 119.38,83.51 119.23,83.66 118.93,83.66 118.78,83.51 118.48,83.51 118.33,83.66 118.03,83.66 117.88,83.51 117.58,83.51 117.43,83.66 117.13,83.66 116.98,83.51 116.68,83.51 116.53,83.66 116.23,83.66 116.08,83.51 115.66,83.51 115.51,83.66 115.21,83.66 115.06,83.51 113.82,83.51 113.67,83.66 113.37,83.66 113.22,83.51 112.92,83.51 112.77,83.66 112.47,83.66 112.32,83.51 112.02,83.51 112,83.48 111.26,83.48 110.71,82.93 108.94,82.93 U43.A34 ; v1(193.69,117.59) 194.01,117.27 194.38,117.27 C720.1
  SIG1 w0.094: v1(193.69,117.59) 193.37,117.27 193.11,117.27 192.83,117 192.83,113.46 187.88,108.51 186.12,108.51 177.36,99.75 175.05,99.75 170.1,94.79 162.23,94.79 160.57,93.14 158.29,93.14 156.89,91.75 140.87,91.75 140.36,92.25 126.63,92.25 126.25,91.88 126.25,91.68 v1(125.94,91.36)
N14075019: length 111.8
  TOP w0.099: C717.1 195.65,122.1 195.28,122.1 v1(194.96,121.78) ; v1(124.86,89.59) 124.56,89.29 124.56,88.26 120.73,84.43 111.52,84.43 110.82,83.74 110.75,83.67 110.71,83.67 110.66,83.62 110.24,83.2 108.72,83.2 108.58,83.06 108.04,83.06 107.7,83.4 U43.D32
  SIG1 w0.094: v1(124.86,89.59) 124.54,89.9 124.54,91.27 126.28,93.02 154.1,93.02 158.8,97.71 168.32,97.71 170.99,100.38 177.08,100.38 180.13,103.43 180.13,106.75 185.47,112.09 185.47,115.9 191.67,122.1 194.64,122.1 v1(194.96,121.78)
N14075081: length 119.6
  TOP w0.099: U43.D30 107.68,84.39 108.06,84.01 108.39,84.01 108.63,84.25 109.27,84.25 109.8,84.78 109.84,84.78 109.91,84.85 111.56,86.51 119.13,86.51 121.24,88.62 121.24,93.33 v1(121.55,93.65) ; C713.1 195.65,132.26 195.28,132.26 v1(194.96,131.94)
  SIG1 w0.094: v1(121.55,93.65) 121.24,93.97 121.24,94.57 122.47,95.81 147.09,95.81 149.25,97.97 153.34,97.97 155.88,100.51 158.92,100.51 159.69,101.27 168.45,101.27 170.23,103.05 174.4,103.05 175.05,103.7 175.05,104.72 175.94,105.61 175.94,107.64 180.13,111.83 180.13,113.48 186.36,119.71 186.36,126.06 192.56,132.26 194.64,132.26 v1(194.96,131.94)
N14075085: length 119.6
  TOP w0.099: v1(194.96,132.83) 195.28,132.51 195.65,132.51 C714.1 ; U43.B30 108.24,84.46 109.19,84.46 109.66,84.92 109.66,84.96 109.73,85.03 111.46,86.77 115.42,86.77 115.58,86.92 115.87,86.92 116.03,86.77 116.32,86.77 116.48,86.92 116.77,86.92 116.93,86.77 117.22,86.77 117.37,86.92 117.67,86.92 117.82,86.77 118.12,86.77 118.27,86.92 118.57,86.92 118.72,86.77 119.02,86.77 119.23,86.98 119.23,87.19 119.44,87.4 119.66,87.4 119.87,87.61 119.87,87.83 120.08,88.04 120.29,88.04 120.98,88.73 120.98,89.16 120.83,89.31 120.83,89.61 120.98,89.76 120.98,90.06 120.83,90.21 120.83,90.51 120.98,90.66 120.98,90.96 120.83,91.11 120.83,91.41 120.98,91.56 120.98,93.42 120.75,93.65 v1(120.67,93.65)
  SIG1 w0.094: v1(120.67,93.65) 120.98,93.97 120.98,94.68 122.37,96.06 146.99,96.06 149.14,98.22 153.23,98.22 155.77,100.76 158.82,100.76 159.58,101.52 168.34,101.52 170.12,103.3 174.29,103.3 174.8,103.81 174.8,104.83 175.69,105.72 175.69,107.75 179.88,111.94 179.88,113.59 186.1,119.81 186.1,126.16 192.45,132.51 194.64,132.51 v1(194.96,132.83)
N14342396: length 29.2
  TOP w0.109: v1(91.41,111.79) 91.11,112.09 91.11,114.35 90.92,114.54 90.21,114.54 90.09,114.66 90.09,115.49 89.81,115.77 R1163.1 ; v2(89.84,91.24) 89.43,91.64 U43.BB14
  SIG3 w0.107: v1(91.41,111.79) 91.52,111.79 92.64,110.67 92.64,108.1 93.63,107.1 93.63,105.07 92.33,103.76 92.33,99.82 91.99,99.49 91.99,97.48 90.98,96.47 90.98,95.3 90.53,94.85 90.53,94.47 90.24,94.18 90.24,93.62 90.5,93.37 90.5,92.79 90.22,92.51 90.22,91.62 v2(89.84,91.24)
N16697668: length 79.5
  TOP w0.178: U36.29 63.57,23.93 63.61,23.89 63.81,23.89 64.26,24.33 64.26,25.64 64.22,25.68 64.22,25.72
  TOP w0.254: 64.22,25.72 64.22,27.68 65.62,29.08 v1(65.62,29.16) 65.48,29.29 R1200.2 65.48,30.4 65.45,30.43 R367.1
  SIG2 w0.254: v1(65.62,29.16) 65.88,29.42 65.88,29.72 65.45,30.15 60.85,30.15 59.96,31.04 49.42,31.04 29.71,50.75 11.76,50.75 9.83,48.82 8.58,48.82 8.43,48.67 7.05,48.67 v1(6.52,49.2)
  BOTTOM w0.254: v1(6.52,49.2) 6.87,49.2 7.05,49.38 7.05,49.79 R369.2
N16697688: length 79.6
  TOP w0.178: U36.28 63.53,23.53 63.58,23.58 63.94,23.58 64.56,24.21 64.56,25.64 64.6,25.68 64.6,25.72
  TOP w0.254: 64.6,25.72 64.6,27.52 65.71,28.63 65.96,28.63 66.49,29.16 v1(66.53,29.16) 66.45,29.24 R1200.1 66.45,30.53 66.47,30.55 R366.1
  SIG2 w0.254: v1(7.79,49.2) 7.94,49.05 8.27,49.05 8.42,49.2 9.67,49.2 11.6,51.13 29.86,51.13 49.58,31.42 60.12,31.42 61.01,30.53 65.61,30.53 66.26,29.88 66.26,29.42 v1(66.53,29.16)
  BOTTOM w0.254: R368.1 7.26,49.05 7.41,49.2 v1(7.79,49.2)
N16697962: length 137.8
  TOP w0.178: v4(56.73,23.25) 57.02,23.55 58.09,23.55 58.1,23.53 U36.3
  TOP w0.254: R363.1 76.13,36.9 75.77,36.9 v1(75.61,36.74)
  SIG1 w0.254: v4(56.73,23.25) 57.32,23.85 57.32,24.31 56.56,25.07 56.56,25.45 58.59,27.48 68.25,27.48 74.6,33.83 74.6,36.6 75.01,37.01 75.35,37.01 v1(75.61,36.74)
  SIG2 w0.254: v1(19.38,48.34) 19.57,48.15 19.57,47.81 19.96,47.42 27.22,47.42 28.49,46.15 31.39,46.15 54.5,23.04 55.45,23.04 55.92,23.51 56.47,23.51 v4(56.73,23.25)
  BOTTOM w0.254: v1(19.38,48.34) 19.53,48.49 19.53,48.71 18.72,49.52 18.72,49.93 16.46,52.19 16.46,54.31 12.65,58.12 12.65,66.37 13.53,67.26 13.53,78.06 15.44,79.96 15.44,83.9 16.46,84.92 16.46,88.35 17.34,89.23 27.23,89.23 28.53,87.94 29.03,87.94 R365.2
N16697994: length 136.3
  TOP w0.178: U36.2 58.09,23.93 58.01,23.85 57.02,23.85 v4(56.73,24.14)
  TOP w0.254: v1(75.61,37.66) 75.77,37.5 76.13,37.5 R362.1
  SIG1 w0.254: v1(75.61,37.66) 75.35,37.39 74.85,37.39 74.21,36.75 74.21,33.99 68.09,27.86 58.44,27.86 56.18,25.61 56.18,24.91 56.73,24.37 v4(56.73,24.14)
  SIG2 w0.254: v4(56.73,24.14) 56.47,23.89 55.76,23.89 55.29,23.42 54.66,23.42 31.54,46.53 28.65,46.53 27.38,47.8 20.12,47.8 19.95,47.97 19.95,48.15 20.14,48.34 v1(20.27,48.34)
  BOTTOM w0.254: v1(20.27,48.34) 20.14,48.34 19.96,48.52 19.96,48.82 19.1,49.68 19.1,50.09 16.84,52.35 16.84,54.56 13.03,58.37 13.03,66.21 13.92,67.1 13.92,77.9 15.82,79.81 15.82,83.74 16.84,84.76 16.84,88.19 17.5,88.85 27.07,88.85 28.37,87.55 28.9,87.55 R364.2
N16698122: length 130.8
  TOP w0.178: U33.29 171.52,37.52 171.56,37.48 171.76,37.48 172.21,37.92 172.21,40.59 171.45,41.35 170.3,41.35 v1(170.02,41.07)
  TOP w0.254: v1(136.26,88.95) 136.61,88.6 136.61,88.37 137.61,87.37 137.61,84.44 131.36,78.2 131.36,68.66 124.25,61.55 124.25,54.31 122.73,52.79 122.73,51.44 123.21,50.96 123.38,50.96 v1(123.82,50.52) 124.08,50.79 125.1,50.79 R358.1 ; v1(115.16,95.61) 114.9,95.87 114.51,95.87 R361.2
  SIG1 w0.254: v1(123.82,50.52) 124.07,50.77 124.55,50.77 126.38,48.95 136.29,48.95 138.12,47.12 155.67,47.12 156.89,45.9 159.3,45.9 161.46,43.74 167.48,43.74 169.57,41.66 169.57,41.53 v1(170.02,41.07)
  SIG4 w0.254: v1(115.16,95.61) 115.43,95.87 117.71,95.87 118.74,94.84 131.82,94.84 136.57,90.09 136.57,89.26 v1(136.26,88.95)
N16698154: length 131.3
  TOP w0.178: v1(170.02,41.99) 170.35,41.66 171.57,41.66 172.51,40.72 172.51,37.8 171.89,37.17 171.53,37.17 171.48,37.12 U33.28
  TOP w0.254: v1(137.18,88.95) 136.99,88.77 136.99,88.53 137.99,87.53 137.99,84.29 131.75,78.04 131.75,68.5 124.63,61.39 124.63,54.15 123.11,52.63 123.11,51.6 123.36,51.34 123.72,51.34 v1(123.82,51.44) 124.08,51.17 125.1,51.17 R359.1 ; v1(115.16,96.52) 114.9,96.25 114.51,96.25 R360.2
  SIG1 w0.254: v1(123.82,51.44) 124.1,51.16 124.71,51.16 126.54,49.33 136.44,49.33 138.27,47.5 155.83,47.5 157.05,46.28 159.46,46.28 161.62,44.12 167.64,44.12 169.77,41.99 v1(170.02,41.99)
  SIG4 w0.254: v1(115.16,96.52) 115.43,96.25 117.87,96.25 118.9,95.22 131.98,95.22 136.95,90.25 136.95,89.17 v1(137.18,88.95)
N16698306: length 83.6
  TOP w0.178: v4(165.15,36.84) 165.45,37.14 166.04,37.14 166.05,37.12 U33.3
  TOP w0.254: R357.2 94.94,52.07 95.39,52.07 95.85,51.61 118.95,51.61 121.08,49.49 121.08,48.64 v1(121.84,47.88) 122.35,47.37 122.35,46.64 R355.1
  SIG1 w0.254: v4(165.15,36.84) 164.6,36.84 163.24,35.48 151.78,35.48 144.16,43.1 125.87,43.1 124.86,44.12 123.49,44.12 121.32,46.29 121.32,47.28 121.84,47.8 v1(121.84,47.88)
N16698318: length 81.4
  TOP w0.178: U33.2 166.04,37.52 165.96,37.44 165.45,37.44 v4(165.15,37.73)
  TOP w0.254: R354.1 121.71,46.84 v1(121.84,46.96) 120.7,48.11 120.7,49.33 118.79,51.23 95.69,51.23 95.23,51.69 94.96,51.69 R356.2
  SIG1 w0.254: v4(165.15,37.73) 164.93,37.73 163.06,35.87 151.94,35.87 144.32,43.49 126.03,43.49 125.01,44.5 123.65,44.5 121.7,46.45 121.7,46.83 v1(121.84,46.96)
N16698468: length 70.9
  TOP w0.178: v1(123.42,27.68) 123.72,27.98 124.08,27.98 125.35,26.72 125.35,24.33 124.9,23.89 124.7,23.89 124.66,23.93 U29.29
  TOP w0.254: R351.1 123.33,39.23 122.95,39.23 v1(122.69,38.96)
  SIG1 w0.254: v1(122.69,38.96) 122.69,38.98 122.94,39.23 123.04,39.23 123.29,38.98 123.29,38.62 122.14,37.47 122.14,28.41 122.62,27.93 123.16,27.93 v1(123.42,27.68)
  BOTTOM w0.254: v1(122.69,38.96) 123.02,39.29 123.65,39.29 124.13,39.77 124.13,42.63 123.36,43.39 123.36,48.98 120.14,52.2 95.81,52.2 94.92,53.09 94.92,53.77 92.88,55.8 92.88,60.4 R353.2
N16698500: length 71.2
  TOP w0.178: U29.28 124.62,23.53 124.67,23.58 125.03,23.58 125.65,24.21 125.65,26.85 124.21,28.29 123.72,28.29 v1(123.42,28.59)
  TOP w0.254: v1(122.69,39.88) 122.95,39.61 123.33,39.61 R350.1
  SIG1 w0.254: v1(123.42,28.59) 123.14,28.31 122.78,28.31 122.53,28.57 122.53,37.31 123.67,38.46 123.67,39.13 123.2,39.61 122.94,39.61 122.69,39.87 v1(122.69,39.88)
  BOTTOM w0.254: v1(122.69,39.88) 122.89,39.68 123.49,39.68 123.74,39.93 123.74,42.47 122.98,43.23 122.98,48.82 119.99,51.82 95.65,51.82 94.53,52.93 94.53,53.61 92.5,55.65 92.5,60.53 R352.2
N16698648: length 51.8
  TOP w0.178: v4(117.81,23.25) 118.11,23.55 119.17,23.55 119.19,23.53 U29.3
  TOP w0.254: v1(109.07,44.3) 108.85,44.51 108.49,44.51 R346.1 ; R348.2 92.25,53.67 92.25,51.21 93.12,50.34 93.76,50.34 v1(94.41,49.7)
  SIG1 w0.254: v4(117.81,23.25) 117.52,23.55 117.11,23.55 116.63,24.02 116.63,33.8 109.27,41.17 109.27,44.1 v1(109.07,44.3) 108.73,44.64 108.35,44.64 107.87,45.11 107.87,46.03 105.71,48.18 96.79,48.18 95.01,49.96 94.67,49.96 v1(94.41,49.7)
N16698676: length 51.2
  TOP w0.178: U29.2 119.18,23.93 119.1,23.85 118.11,23.85 v4(117.81,24.14)
  TOP w0.254: v1(109.07,45.21) 108.75,44.89 108.59,44.89 R345.1 ; v1(94.41,50.61) 94.28,50.74 93.26,50.74 92.63,51.37 92.63,53.9 92.5,54.03 R347.2
  SIG1 w0.254: v1(94.41,50.61) 94.67,50.34 95.17,50.34 96.95,48.57 105.87,48.57 108.25,46.18 108.25,45.27 108.5,45.02 108.87,45.02 v1(109.07,45.21) 109.16,45.21 109.65,44.73 109.65,41.33 117.01,33.96 117.01,24.18 117.27,23.93 117.6,23.93 v4(117.81,24.14)
N16705316: length 4.9
  TOP w0.109: R85.1 84.37,126.54 85.21,127.38 U2.T12
N16705352: length 4.7
  TOP w0.109: R86.1 86.41,126.92 86.21,127.12 U2.T13
N16705397: length 4.9
  TOP w0.109: U2.T15 88.21,127.71 87.42,126.92 R87.1
N16706083: length 5.2
  TOP w0.109: U2.T2 75.21,129.99 75.74,129.46 75.74,126.29 75.59,126.14 R88.1
N16706087: length 5.1
  TOP w0.109: U2.T4 77.21,130.15 77.39,129.97 77.39,129.08 76.25,127.94 R89.1
N16706091: length 5
  TOP w0.109: R90.1 77.26,127.43 77.39,127.56 77.39,128.45 78.21,129.27 U2.T5
N16706101: length 5
  TOP w0.109: U2.T6 79.21,129.63 78.28,128.7 R91.1
N16706105: length 4.6
  TOP w0.109: R92.1 80.31,128.39 80.21,128.5 U2.T7
N16706132: length 4.6
  TOP w0.109: U2.T8 81.21,128.44 81.33,128.32 R93.1
N16755005: length 10.3
  TOP w0.229: U5.2 26.84,33.95 v1(27.22,34.34)
  TOP w0.381: C75.1 v1(29.13,33.2) ; R202.1 v1(36.88,31.04)
  SIG1 w0.381: v1(36.88,31.04) 35.61,32.31 30.78,32.31 v1(30.53,32.06)
  vias: v1(29.64,32.06)
N16755089: length 5.7
  TOP w0.229: R205.2 R204.2 R201.1 27.53,28.55 C72.2 26.46,29.52 25.84,30.14 U5.7
N16755125: length 10.9
  TOP w0.229: R206.1 33.35,34.85 28.49,34.85 27.34,33.69 U5.1
  TOP w0.508: R206.1 C76.1 R202.2
N16755585: length 2.2
  TOP w0.229: C77.1 25.07,29.26 25.34,29.53 U5.6
N16793694: length 12.8
  TOP w0.229: U32.4 132.88,20.69 133.45,21.26 136.95,21.26 137.33,20.88 v1(137.33,19.48)
  TOP w0.381: v1(137.33,19.48) 138.35,18.47 138.35,16.05 138.1,15.8 R680.1
  BOTTOM w0.229: C423.1 136.83,18.97 v1(137.33,19.48)
N16794342: length 1.4
  TOP w0.229: R679.2 133.4,12.75 v1(133.52,12.62)
  BOTTOM w0.229: v1(133.52,12.62) 133.4,12.75 R679.2
N16794347: length 2.7
  TOP w0.229: R679.1 132.91,14.25 132.38,14.78 U32.14
N16794368: length 2.2
  TOP w0.229: v1(132.89,15.16) 132.89,15.67 132.88,15.68 U32.15
  BOTTOM w0.229: C422.2 133.4,14.4 132.89,14.91 v1(132.89,15.16)
N16794661: length 3.9
  TOP w0.229: U32.18 134.38,16.08 134.84,15.62
  TOP w0.381: R684.1 C425.1 135.45,15.7 135.38,15.62 134.84,15.62
N16903889: length 1.9
  TOP w0.109: D3.1 92.2,156.59 92.53,156.92 R10.2
N16903915: length 10.9
  TOP w0.109: v1(92.91,153.34) 92.85,153.4 Q5.1
  BOTTOM w0.109: R12.2 R13.1 89.43,147.98 92.95,151.5 92.95,153.3 v1(92.91,153.34)
N16909700: length 3.5
  TOP w0.178: U29.15 121.77,19.48
  TOP w0.254: 121.77,19.48 121.77,17.65 122.09,17.32 R1115.2
N16935902: length 5.4
  TOP w0.229: U30.4 112.17,21.75 v1(112.57,22.15) 113.2,22.78 R665.2
  BOTTOM w0.229: v1(112.57,22.15) 112.57,22.35 113.79,23.57 C357.1
N16936603: length 3.6
  TOP w0.229: U30.3 112.67,21.34 114.42,23.09 R668.2
N16937550: length 20.5
  TOP w0.229: v1(102.51,13.74) R677.2 101.65,14.02 101.23,14.43 U31.11 ; v4(113.84,14.66) 114.09,14.4 R671.1 R670.2 113.08,14.02 113.17,14.12 U30.11
  SIG1 w0.381: v1(102.51,13.74) 104.52,11.74 110.66,11.74 113.58,14.66 v4(113.84,14.66)
N16941751: length 2.3
  TOP w0.229: U30.8 111.67,14.65 111.04,14.02 R666.1
N16941772: length 2
  TOP w0.229: C346.1 112.06,14.15 112.17,14.26 U30.9
N16941889: length 3.1
  TOP w0.229: U30.12 113.67,15.52 113.9,15.3 114.22,15.3
  TOP w0.381: 114.22,15.3 114.58,14.94 C358.1 R669.1
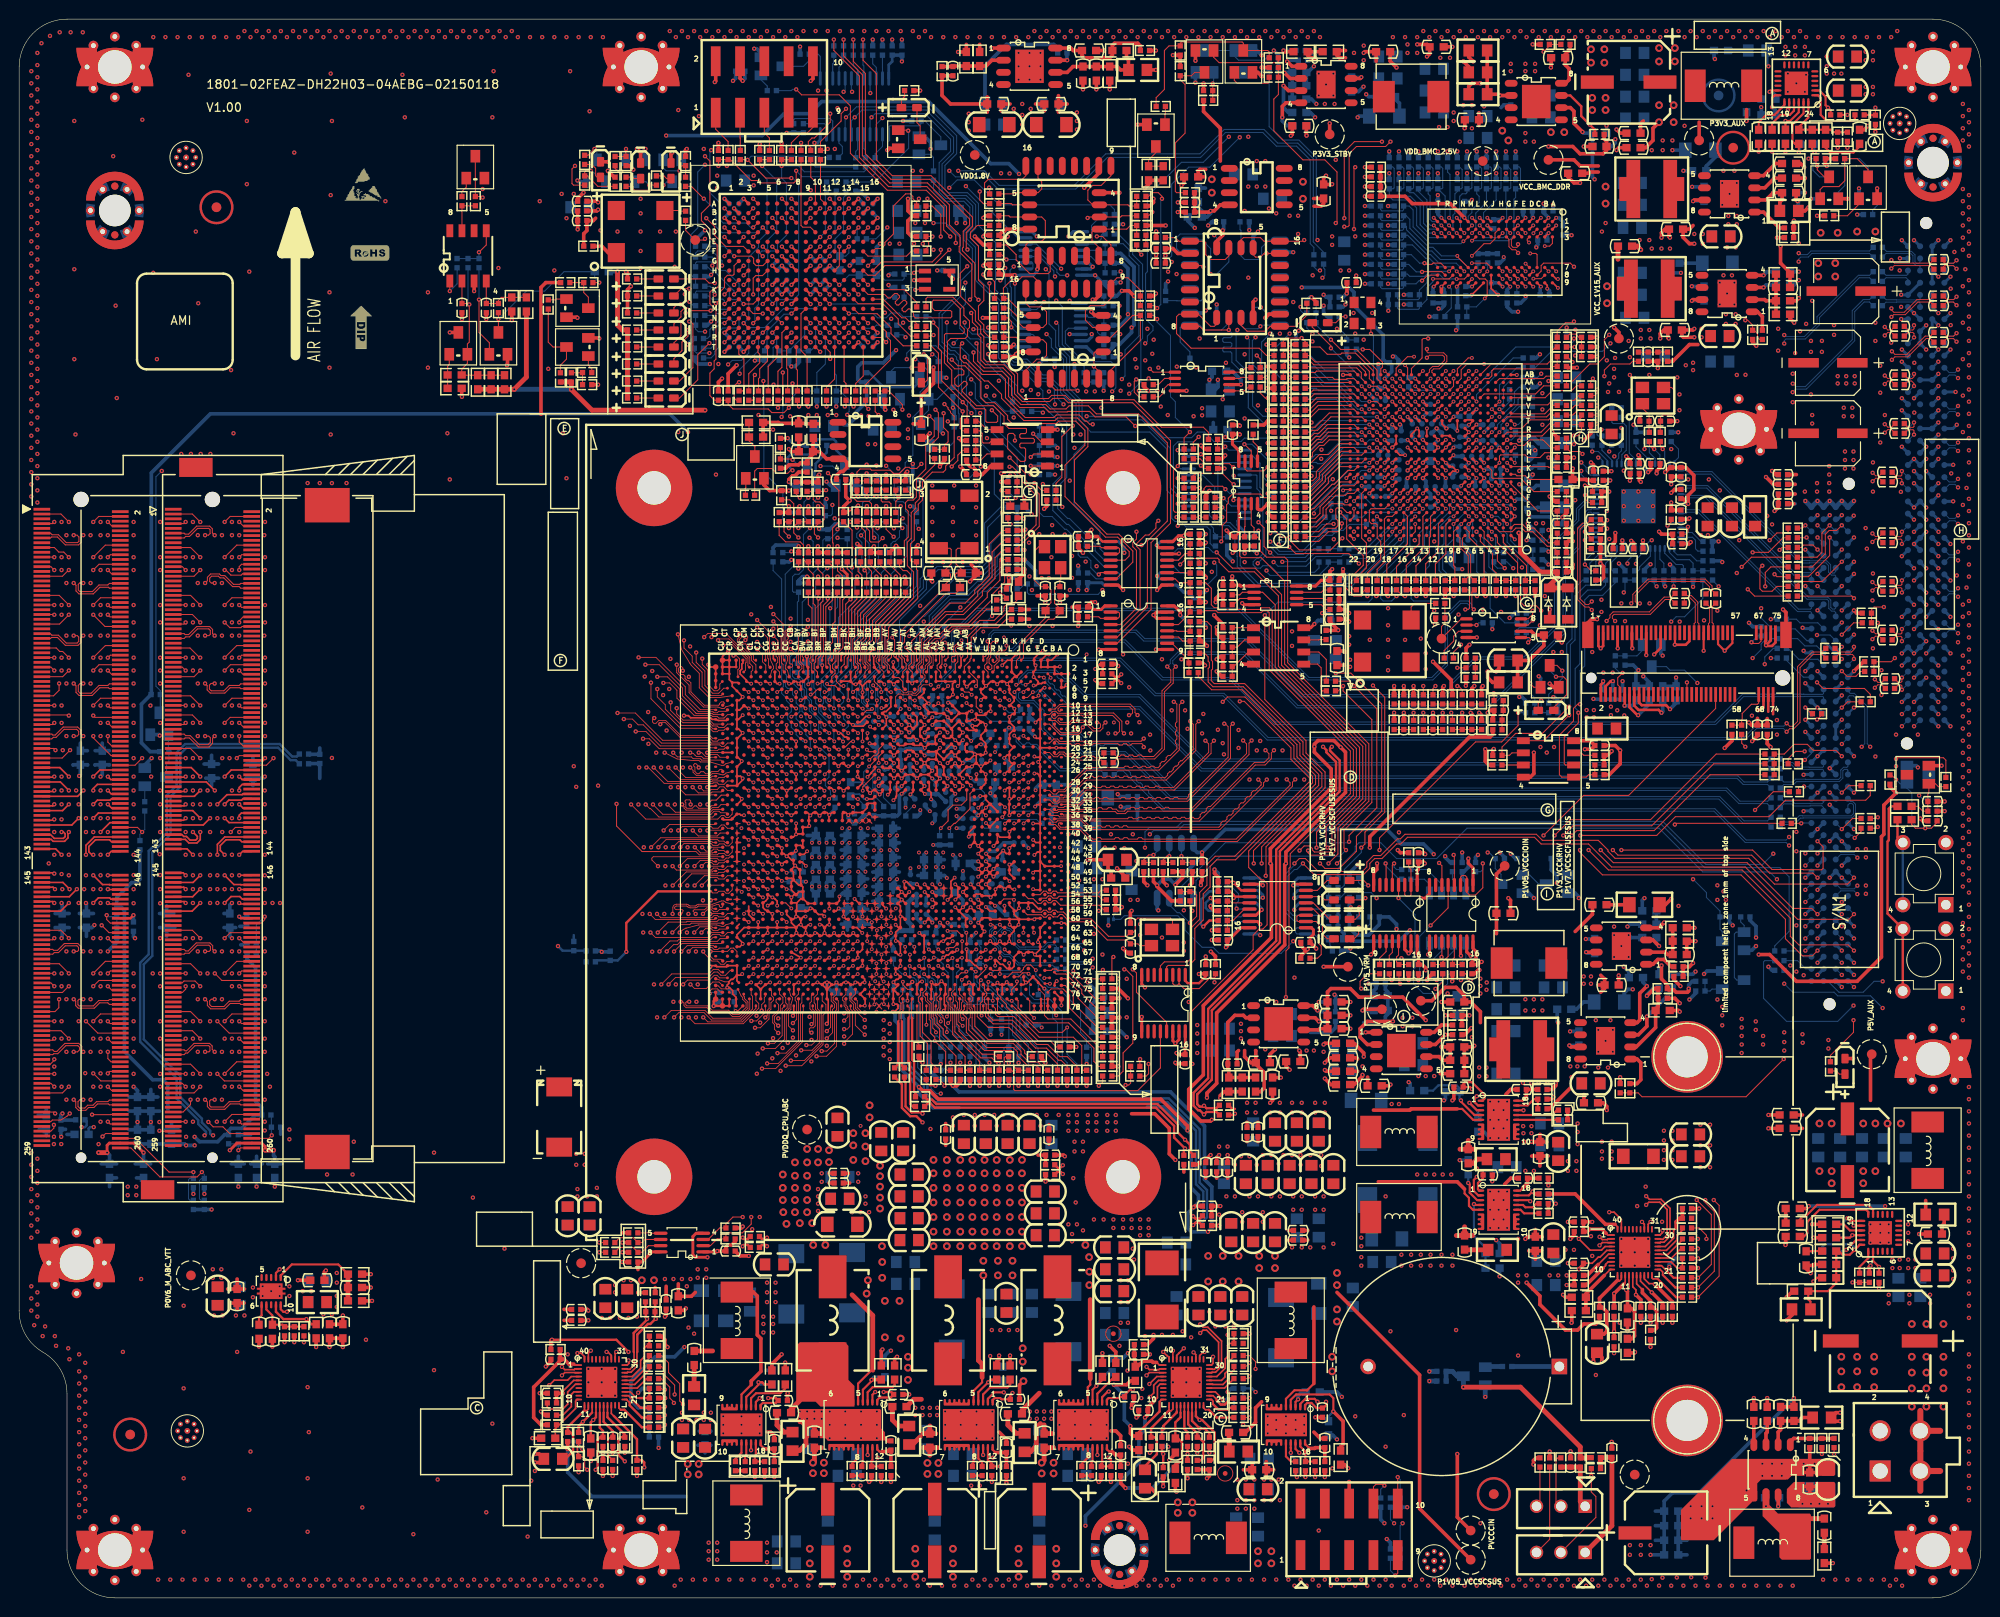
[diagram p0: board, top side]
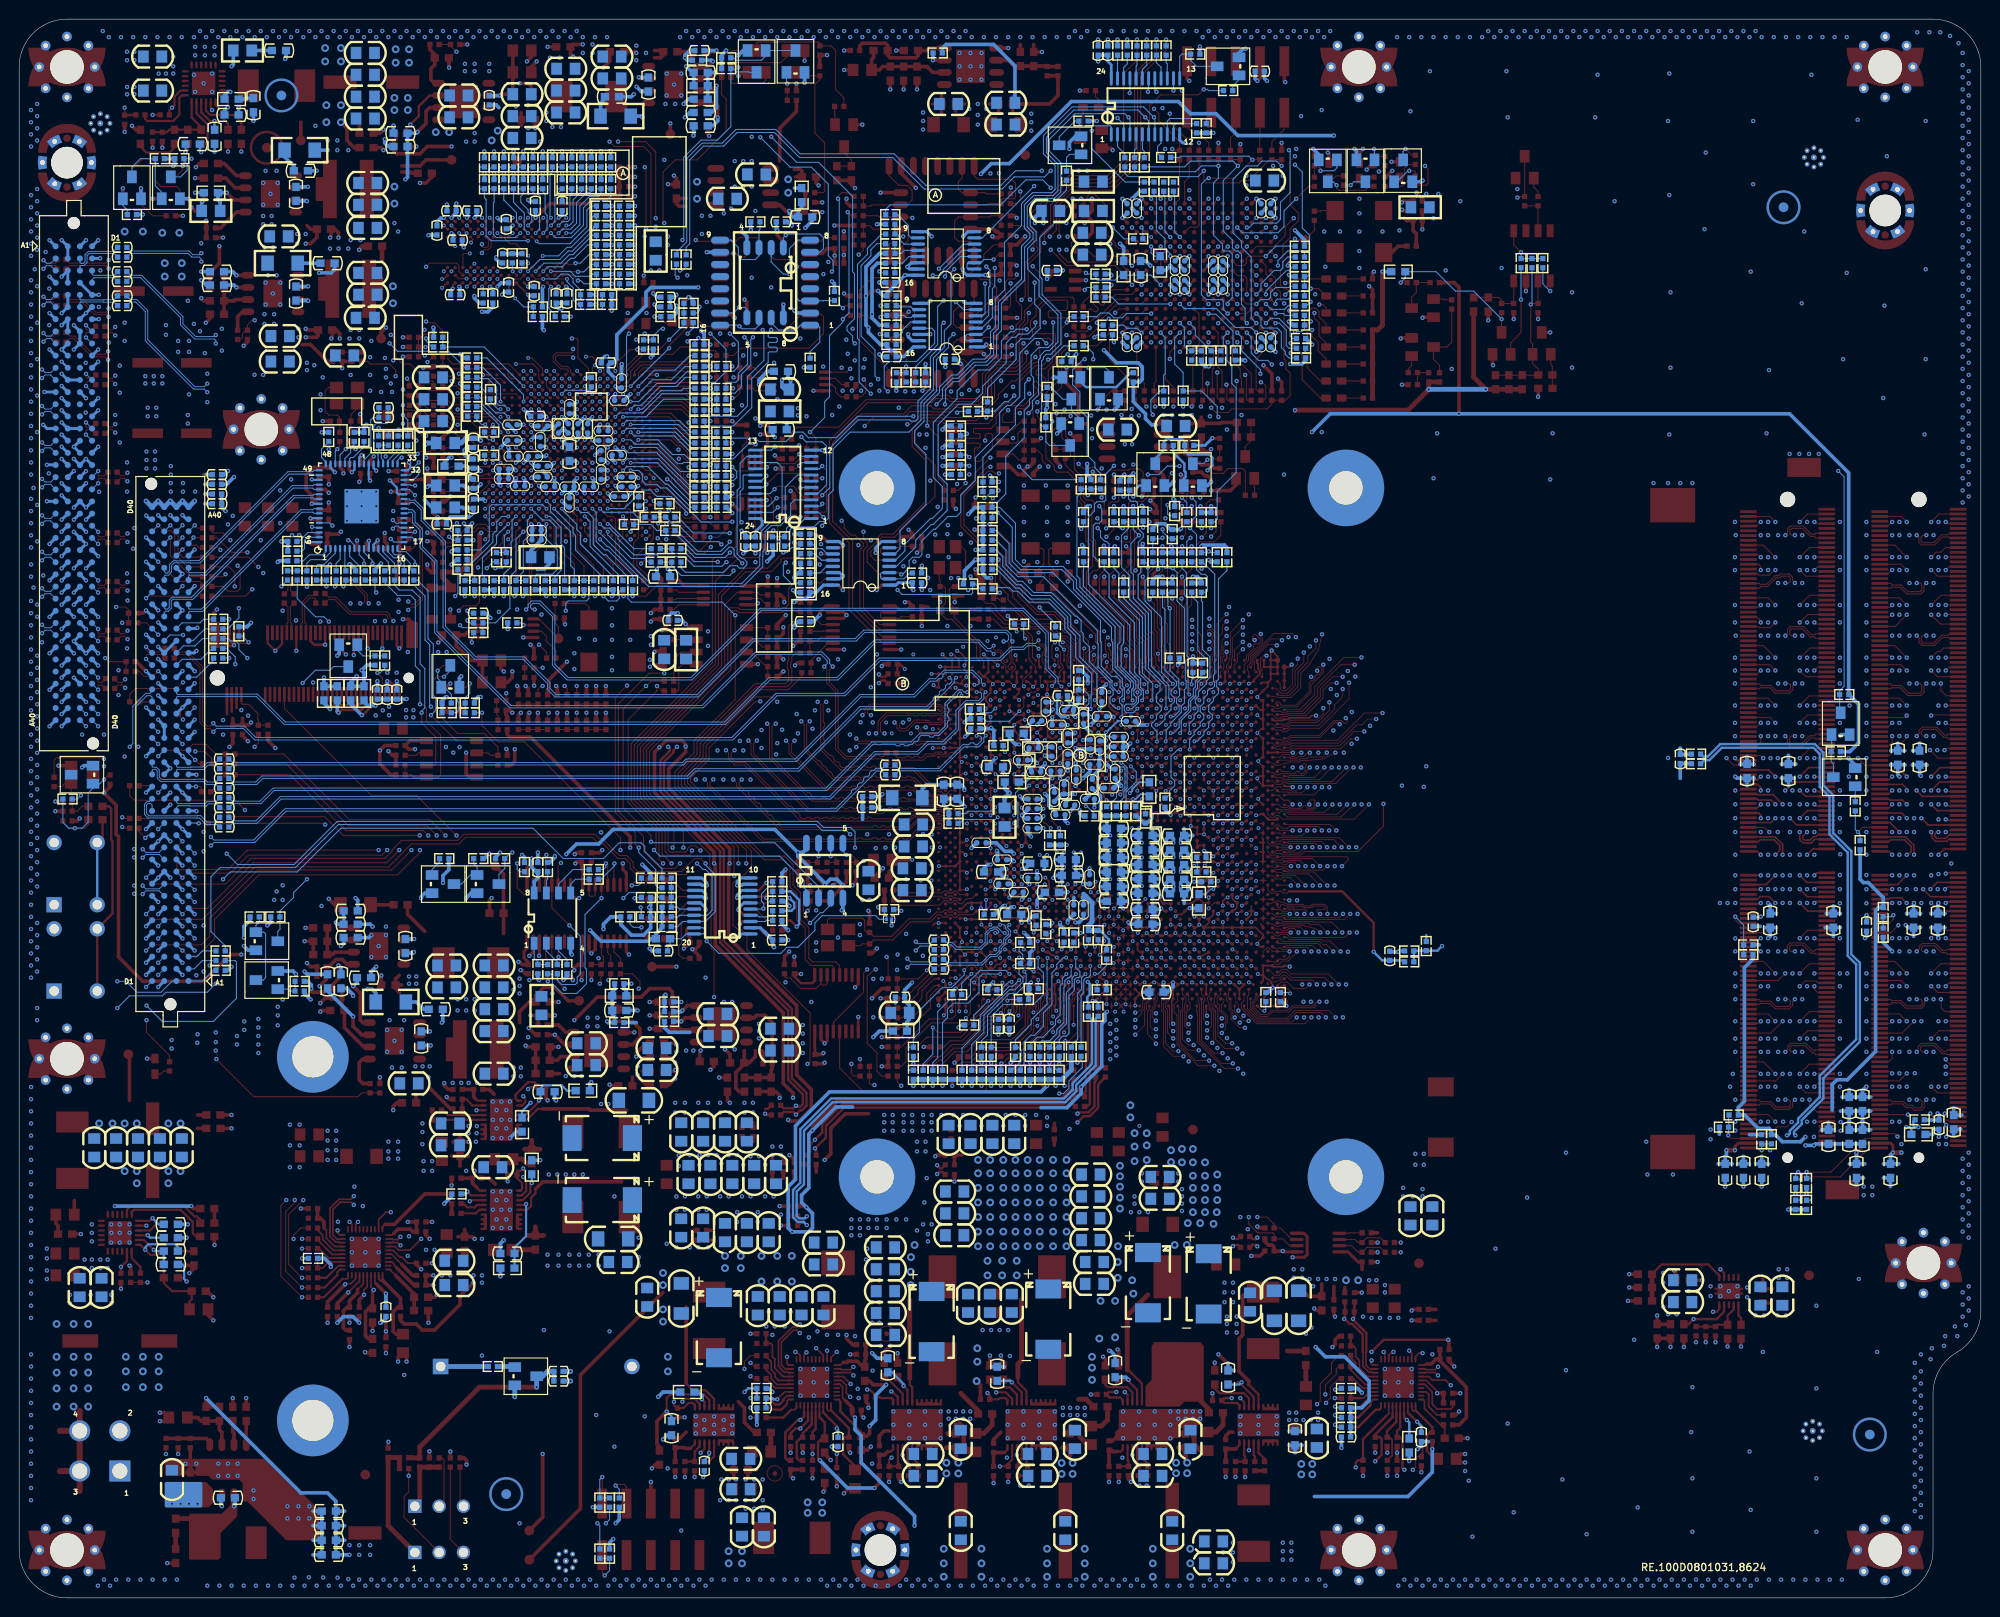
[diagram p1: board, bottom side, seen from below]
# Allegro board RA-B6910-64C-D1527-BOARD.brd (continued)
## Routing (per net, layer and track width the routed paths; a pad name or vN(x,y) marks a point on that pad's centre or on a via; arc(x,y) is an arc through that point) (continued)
N16948518: length 5.1
  TOP w0.229: U31.4 100.23,21.5 v1(101.27,22.53)
  TOP w0.254: R672.2 101.55,22.81 v1(101.27,22.53)
  BOTTOM w0.254: v1(101.27,22.53) 101.42,22.68 C385.1
N16948538: length 4.6
  TOP w0.229: U31.3 100.73,21.26 101.47,22
  TOP w0.254: R675.2 103.55,22.28 103.27,22 101.47,22
N16948700: length 2
  TOP w0.229: R673.1 99.61,14.02 99.73,14.14 U31.8
N16948702: length 2.2
  TOP w0.229: C374.1 100.63,14.15 100.23,14.55 U31.9
N16948718: length 3.3
  TOP w0.229: U31.12 101.73,15.48 102.03,15.19
  TOP w0.381: 102.03,15.19 C386.1 R676.1
N16975861: length 9.1
  TOP w0.109: R146.1 v1(125.73,112.95)
  BOTTOM w0.109: U61.15 125.77,118.66 125.27,118.16 125.27,113.41 v1(125.73,112.95)
N16975864: length 2.3
  TOP w0.109: v1(120.95,112.95) R145.1
  BOTTOM w0.109: v1(120.95,112.95) 121.45,113.46 U61.2
N16975903: length 1.8
  TOP w0.109: R147.1 v1(123.36,116)
  BOTTOM w0.109: v1(123.36,116) 123.31,116 123.26,116.06 U61.6
N16975906: length 6.3
  TOP w0.109: R148.1 122.7,117.27 122.96,117.53 125.73,117.53 126.87,116.38 v1(126.92,116.38)
  BOTTOM w0.109: v1(126.92,116.38) 127.25,116.06 U61.19
N16975938: length 10.6
  TOP w0.109: v1(123.26,121.34) 122.7,120.78 R149.1
  BOTTOM w0.109: v1(123.26,121.34) 122.75,120.83 121.08,120.83 120.62,120.37 120.62,116.33 121.55,115.41 U61.5
N16975941: length 5.8
  TOP w0.109: R150.1 123.41,119.05 123.92,118.54 126.49,118.54 v1(126.87,118.16)
  BOTTOM w0.109: v1(126.87,118.16) 127.02,118.01 U61.16
N16975982: length 2.9
  TOP w0.381: U6.1 133.02,160.07 v1(132.51,160.58)
  BOTTOM w0.381: v1(132.51,160.58) 132.63,160.71 R208.1
N16997266: length 8
  TOP w0.229: v1(152.03,41.16) 152.12,41.06 U34.4
  BOTTOM w0.229: v1(152.03,41.16) 152.03,37.81 153.23,36.6 C452.1 R710.1
N16997274: length 1
  TOP w0.381: R709.2 C451.1
N16997276: length 2.5
  TOP w0.229: U34.14 156.89,40.56 157.27,40.18 R709.1
N16997279: length 2.6
  TOP w0.229: C451.2 158.54,41.2 158.16,40.82 157.4,40.82 157.15,41.06 U34.15
N16997281: length 3.2
  TOP w0.229: 157.15,42.85 156.86,42.56 U34.18
  TOP w0.381: R714.1 C454.1 157.63,43.33 157.15,42.85
N16998858: length 4.6
  TOP w0.229: C471.2 160.7,50.98 160.19,50.46 U35.15
N16998860: length 4.4
  TOP w0.229: U35.14 R716.1
N16998866: length 1
  TOP w0.381: C471.1 R716.2
N16998883: length 8.2
  TOP w0.229: U35.4 152.07,50.46 150.67,51.87 v1(150.67,51.99)
  BOTTOM w0.229: v1(150.67,51.99) 150.52,52.15 C472.1 150.52,53.26 150.21,53.57 148.31,53.57 147.75,53.01 R717.1
N16998909: length 3.2
  TOP w0.229: U35.18 157.11,51.96 157.27,52.12
  TOP w0.381: 157.27,52.12 157.5,52.35 C474.1 R721.1
N17027955: length 2.3
  TOP w0.109: D8.1 R96.2
N17027975: length 2.3
  TOP w0.109: R97.2 D9.1
N17027989: length 2.3
  TOP w0.109: R99.2 D10.1
N17028003: length 2.3
  TOP w0.109: D11.1 R100.2
N17028013: length 2.3
  TOP w0.109: D12.1 R101.2
N17028027: length 2.3
  TOP w0.109: D13.1 R102.2
N17028039: length 2.3
  TOP w0.109: R103.2 D14.1
N17028059: length 2.3
  TOP w0.109: R104.2 D15.1
N17031624: length 5.3
  TOP w0.229: v1(89.07,22.78) 89.07,22.66 88.17,21.75 U37.4
  TOP w0.381: R745.2 89.1,22.81 v1(89.07,22.78)
  BOTTOM w0.381: v1(89.07,22.78) 89.35,23.06 C496.1
N17031630: length 4.7
  TOP w0.229: U37.3 88.67,21.49 89.2,22.02 91.26,22.02 91.49,22.25 R749.2
N17031638: length 3
  TOP w0.229: R752.1 R751.2 89.07,14.31 89.17,14.4 U37.11
N17031650: length 2.3
  TOP w0.229: R746.1 87.04,14.02 87.67,14.65 U37.8
N17031652: length 2
  TOP w0.229: C489.1 88.06,14.02 88.17,14.13 U37.9
N17031655: length 3.5
  TOP w0.229: 90.22,15.29 89.9,15.29 89.67,15.52 U37.12
  TOP w0.381: 90.22,15.29 90.72,15.29 90.88,15.44 C497.1 R750.1
N17031694: length 1
  TOP w0.254: C489.2 R746.2
N17039294: length 9.2
  TOP w0.178: U33.11 167.03,33.2 167.1,33.13 167.24,33.13 167.43,33.32 U33.12
  TOP w0.381: C428.1 165.6,27.56 165.91,27.86 165.91,29.9 165.43,30.38 R693.1 165.15,31.32 167.03,33.2
N17040089: length 5.2
  TOP w0.178: 167.69,32.82 167.83,32.96 U33.13
  TOP w0.381: 167.69,32.82 v1(166.67,31.8) R694.1
  BOTTOM w0.381: R694.1 v1(166.67,31.8)
N17040626: length 7.3
  TOP w0.178: 169.63,32.22 169.03,32.82 U33.16
  TOP w0.381: 169.63,32.22 169.63,31.89 170.48,31.04 C431.1 170.73,30.38 171.12,30 171.12,28.22 170.86,27.97 R696.2
N17041421: length 3.9
  TOP w0.178: R689.1 C427.1 173.27,34.47 172.62,35.12 U33.23
N17047383: length 8.3
  TOP w0.178: U36.12 59.48,19.73 59.29,19.54 59.15,19.54 59.08,19.61 U36.11
  TOP w0.254: C480.1 57.07,14.53 57.88,15.34 57.88,17.02 57.6,17.3 R730.1 57.32,17.85 59.08,19.61
N17047812: length 4.7
  TOP w0.178: U36.13 59.88,19.37
  TOP w0.254: R731.1 58.47,17.96 v1(58.91,18.4) 59.88,19.37
  BOTTOM w0.254: R731.1 58.47,17.96 v1(58.91,18.4)
N17048287: length 6.7
  TOP w0.178: R733.2 61.53,14.87 61.53,16.52 61.79,16.79 C483.1 ; 61.08,19.36 U36.16
  TOP w0.254: 61.08,19.36 61.08,18.39 62.05,17.42 C483.1
N17049239: length 3.9
  TOP w0.178: 64.82,20.88 64.52,20.88 63.87,21.53 U36.23
  TOP w0.254: 64.82,20.88 C479.1 R725.1
N17052448: length 9.4
  TOP w0.178: U29.12 120.57,19.73 120.38,19.54 120.23,19.54 120.17,19.61 U29.11
  TOP w0.254: C337.1 117.65,13.77 118.89,15.01 118.89,16.56 118.66,16.79 R647.1 118.28,17.73 120.17,19.61
N17053094: length 4.9
  TOP w0.178: 120.97,19.48 U29.13
  TOP w0.254: 120.97,19.48 120.97,19.37 119.55,17.96 v1(119.55,17.7) 119.43,17.58 R648.1
  BOTTOM w0.254: R648.1 119.43,17.58 v1(119.55,17.7)
N17053632: length 7
  TOP w0.178: U29.16 122.17,19.43
  TOP w0.254: R650.2 123.49,14.38 123.74,14.63 123.74,16.31 123.26,16.79 C340.1 123.11,17.2 122.17,18.14 122.17,19.43
N17054263: length 4
  TOP w0.178: v1(125.78,20.75) 125,21.53 U29.23
  BOTTOM w0.254: v1(125.78,20.75) 126.16,20.75 126.28,20.88 R644.1 C336.1
N17098376: length 3.9
  TOP w0.178: 165.02,34.85 166.09,35.92 U33.6
  TOP w0.381: R686.1 163.88,33.71 165.02,34.85
N17098434: length 5.6
  TOP w0.178: R726.1 55.19,19.91 55.37,19.74 56.82,19.74 57.32,20.24 57.32,21.51 58.14,22.33 U36.6
N17098818: length 4.1
  TOP w0.178: R728.2 56.82,19.1 57.7,19.99 57.7,21.26 57.97,21.53 U36.8
N17098920: length 4
  TOP w0.178: 165.53,34.47 165.78,34.72 165.78,34.85 166.05,35.12 U33.8
  TOP w0.381: R690.2 163.75,32.69 165.53,34.47
N17105456: length 5
  TOP w0.099: C59.2 174.01,104.39 174.11,104.5 174.64,104.5 175.16,103.98 175.16,101.94 175.03,101.82 J3.41
N17105459: length 5
  TOP w0.099: C58.2 174.24,104.75 174.75,104.75 175.41,104.09 175.41,101.94 175.53,101.82 J3.43
N17105487: length 3.3
  TOP w0.099: C61.2 176.66,103.58 176.66,101.94 176.53,101.82 J3.47
N17105490: length 3.3
  TOP w0.099: C60.2 176.91,103.59 176.91,101.94 177.03,101.82 J3.49
N17107496: length 3.3
  TOP w0.109: v1(181.02,99.87) 181.15,99.75 181.78,99.75 182.03,100 J3.69
  BOTTOM w0.109: v1(181.02,99.87) 181.68,100.53 R164.2
N17107982: length 8.7
  TOP w0.109: R112.1 81.71,143.43 81.89,143.26 82.68,143.26 U2.D10
N17116587: length 2
  TOP w0.229: C511.2 75.87,14.78 75.99,14.9 U38.15
N17116589: length 2.2
  TOP w0.229: R754.1 74.85,14.53 75.48,15.16 U38.14
N17116595: length 1
  TOP w0.381: C511.1 R754.2
N17116612: length 6.1
  TOP w0.229: U38.4 75.99,21 77.26,22.28 v1(77.26,22.53)
  TOP w0.254: v1(77.26,22.53) 77.64,22.53 77.87,22.3 R755.1
  BOTTOM w0.229: C512.1 77.49,22.3 v1(77.26,22.53)
N17116638: length 3.2
  TOP w0.229: U38.18 77.48,15.96 77.83,15.61
  TOP w0.381: 77.83,15.61 77.87,15.57 C514.1 R759.1
N17480014: length 8.6
  TOP w0.109: R1129.1 122.7,113.69 122.47,113.46 120.81,113.46 120.63,113.64 120.63,117.84 v1(121.08,118.29)
  BOTTOM w0.109: v1(121.08,118.29) 121.36,118.01 U61.9
N17480023: length 6.3
  TOP w0.109: R1130.1 122.98,114.99 123.82,115.82 123.82,115.95 124.05,116.18 125.75,116.18 v1(126.06,115.88)
  BOTTOM w0.109: U61.20 126.52,115.41 v1(126.06,115.88)
N17481397: length 4.1
  TOP w0.109: U2.P14 v1(87.71,132.23)
  BOTTOM w0.109: v1(87.71,132.23) 88.17,132.69 89.25,132.69 89.58,133.02 R1131.1
N17481458: length 4.1
  TOP w0.109: v1(126.03,120.32) 125.78,120.07 R1162.1 R1133.1
  BOTTOM w0.109: v1(126.03,120.32) 126.39,119.96 U61.13
N17482004: length 5.3
  BOTTOM w0.109: R1157.2 R1132.2 125.01,111.18 124.81,111.38 124.81,111.79 124.28,112.32 123.36,112.32 122.88,112.81 U61.1
N17547354: length 5.8
  TOP w0.109: U2.E11 v1(84.71,142.23)
  BOTTOM w0.109: R1136.1 85.39,146.61 85.26,146.48 85.26,142.78 v1(84.71,142.23)
N17547355: length 5.8
  TOP w0.109: U2.E10 v1(83.71,142.23)
  BOTTOM w0.109: v1(83.71,142.23) 84.25,142.77 84.25,146.61 84.37,146.74 R1135.1
N17563236: length 2.8
  BOTTOM w0.109: R1139.1 89.45,150.93 90.22,151.69 U62.2
N17563239: length 2.5
  BOTTOM w0.109: U62.5 88.27,151.48 88.44,151.31 R1140.1
N17563242: length 2.5
  BOTTOM w0.109: U62.6 87.62,151.38 87.42,151.18 R1141.1
N17563245: length 2.7
  BOTTOM w0.109: U62.9 85.67,152.04 86.03,151.69 86.03,150.95 R1142.1
N17571333: length 7.2
  BOTTOM w0.109: U62.13 83.72,161.11 83.49,161.34 R1173.2 82.57,160.68 81.96,160.07 Q33.3
N17682193: length 1.9
  BOTTOM w0.109: R1172.1 78.18,158.01 77.52,158.67 Q33.1
N17689359: length 3.4
  BOTTOM w0.109: U62.11 84.37,153.85 84.15,154.08 R1143.2
N17750781: length 3.2
  BOTTOM w0.099: C738.2 195.09,138.23 197.25,138.23 197.38,138.35 U60.D3
N17750784: length 3.2
  BOTTOM w0.099: C732.2 195.09,137.97 197.19,137.97 197.38,137.78 U60.D4
N17756086: length 4.6
  BOTTOM w0.099: C740.2 195.11,135.67 196.16,135.67 196.18,135.65 198.55,135.65 198.65,135.75 U60.C5
N17756089: length 4.6
  BOTTOM w0.099: C741.2 195.08,135.42 196.16,135.42 196.18,135.44 198.55,135.44 198.65,135.34 U60.C6
N17760907: length 3.1
  BOTTOM w0.109: R1175.1 95.55,150.55 95.23,150.87 Q34.1
N17761211: length 8.2
  BOTTOM w0.109: U62.1 90.87,153.72 91,153.85 94.03,153.85 94.26,154.08 R1176.2 94.66,154.36 96.31,152.71 Q34.3
N17768751: length 3.7
  TOP w0.109: R1104.2 136.57,103.3 136.07,103.8 U56.5
N17772566: length 2.4
  BOTTOM w0.109: U62.23 90.22,159.95 90.22,159.95 R1146.1
N17773057: length 2.6
  BOTTOM w0.109: R1145.2 89.2,160.32 89.57,159.95 U62.22
N17794271: length 3.3
  TOP w0.099: C733.2 201.43,131.61 202.14,131.61 v1(202.46,131.29)
  BOTTOM w0.099: U60.A9 201.71,131.62 202.13,131.62 v1(202.46,131.29)
N17794274: length 3.3
  TOP w0.099: C739.2 201.46,131.86 202.14,131.86 v1(202.46,132.18)
  BOTTOM w0.099: v1(202.46,132.18) 202.16,131.88 201.68,131.88 U60.A8
N17794486: length 3.3
  TOP w0.099: v1(202.46,135.1) 202.13,135.43 201.44,135.43 C731.2
  BOTTOM w0.099: v1(202.46,135.1) 202.13,135.43 201.71,135.43 U60.A6
N17794489: length 3.3
  TOP w0.099: v1(202.46,135.99) 202.16,135.69 201.44,135.69 C737.2
  BOTTOM w0.099: v1(202.46,135.99) 202.16,135.69 201.68,135.69 U60.A5
N17794993: length 3.4
  TOP w0.099: v1(202.46,139.8) 202.16,139.5 201.21,139.5 201.06,139.65 C730.2
  BOTTOM w0.099: U60.A2 201.7,139.48 202.14,139.48 v1(202.46,139.8)
N17794996: length 3.4
  TOP w0.099: C734.2 201.06,139.09 201.21,139.24 202.13,139.24 v1(202.46,138.91)
  BOTTOM w0.099: U60.A3 201.7,139.23 202.14,139.23 v1(202.46,138.91)
N17795291: length 5.5
  BOTTOM w0.099: C735.2 195.13,140.73 197.76,140.73 198.12,140.37 198.12,139.65 198.3,139.46 198.52,139.46 198.65,139.59 U60.C2
N17795581: length 5.5
  BOTTOM w0.099: U60.C3 198.65,139.15 198.55,139.25 198.22,139.25 197.9,139.56 197.9,140.28 197.67,140.51 195.09,140.51 C736.2
N17832270: length 6.3
  TOP w0.381: v1(60.5,145.09) 60.37,144.96 C759.2 ; R1184.2 59,142.57 59.33,142.9 C760.2 59.99,143.94 60.24,144.2 ; C758.1 60.37,145.97 v1(60.5,145.85)
N17832309: length 2.7
  TOP w0.381: OSC6.1 61.56,140.6 60.88,141.28 R1184.1
N17832341: length 2.2
  TOP w0.109: OSC6.3 68.97,145 69.03,144.93 R1185.1
N17914718: length 3.8
  TOP w0.109: Q36.3 76.88,120.32 76.27,120.93 R1197.2 R1198.2
N17914746: length 1.8
  TOP w0.109: Q36.1 75.93,116.04 75.9,116 R1199.2
N17916073: length 3.9
  TOP w0.109: Q35.3 118.79,151.05 118.03,150.29 R1194.2 R1193.2
N17916093: length 1.9
  TOP w0.109: R1195.2 119.78,155.09 119.74,155.05 Q35.1
N17918460: length 6
  TOP w0.109: R1188.1 93.26,140.77 92.73,140.23 88.7,140.23 U2.F15
N17918580: length 9.8
  TOP w0.109: U2.F16 89.5,141.02 90.09,141.02 90.47,141.4 90.47,141.66 91.36,142.55 91.36,145.47 92.63,146.74 93.14,146.74 93.39,146.48 93.39,146.23 93.79,145.83 R1189.1
N18052602: length 5
  TOP w0.381: R1212.2 R1210.1 R1211.2 185.44,16.66 185.09,16.31 U63.1
N18052688: length 6.1
  TOP w0.381: U63.2 183.82,17.32 184.07,17.58 C784.2 R1213.2 186,18.49 186.36,18.85 R1214.1
N18052713: length 1.7
  TOP w0.508: R1215.1 C786.2
N18052715: length 2.5
  TOP w0.381: C787.1 U63.4
N18052767: length 2.1
  TOP w0.381: U63.7 v1(183.82,9.58)
  BOTTOM w0.381: C783.1 183.92,9.68 v1(183.82,9.58)
N18052773: length 2.5
  TOP w0.381: U63.3 182.55,17.2 182.67,17.32 C785.1
N18052836: length 2.7
  TOP w0.508: C786.1 186.89,8.28
  BOTTOM w0.381: v1(182.55,9.58) 182.44,9.68 C783.2
N18094371: length 7.9
  TOP w0.109: v1(74.72,140.23) 76.53,140.23 76.75,140.01 76.75,139.5 77.01,139.24 77.72,139.24 U2.G5
  BOTTOM w0.109: R1216.2 73.67,141.28 v1(74.72,140.23)
N18134263: length 2.4
  TOP w0.109: R1217.2 58.85,128.04 R1230.2 R1218.1
N18134715: length 8.5
  TOP w0.109: R1222.1 55.29,131.24 55.8,130.73 Q38.3 57.2,129.46 56.56,128.83 R1219.2
N18135317: length 1.9
  TOP w0.109: Q37.1 56.14,135.75 56.05,135.66 R1222.2
N18135357: length 4.3
  TOP w0.109: Q37.3 59.48,135.94 59,136.42 R1221.1 R1220.2
N18148857: length 10.1
  TOP w0.381: R1237.2 115.72,160.99 115.92,160.78 R1236.2 115.11,159.69 114.75,160.05 R1238.1 C812.1 C811.1 110.13,160.05 109.52,159.44 U64.6
N18148863: length 11.4
  TOP w0.381: R1235.1 117.17,162.2 116.89,162.48 114.47,162.48 114.25,162.26 R1237.1 114.25,161.24 113.97,160.96 111.3,160.96 111.07,161.19 C810.1 110.16,161.72 109.9,161.98 U64.8
N18148873: length 6.7
  TOP w0.381: U64.2 101.65,160.71 101.04,160.1 R1233.2 R1232.2 97.63,160.1 C805.2 R1234.2
N18149045: length 2
  TOP w0.381: U64.7 v1(109.52,160.71)
  BOTTOM w0.381: v1(109.52,160.71) 109.5,160.73 R1231.2
N18169102: length 7
  TOP w0.109: U65.4 C817.1 R1239.1 50.08,135.62 50.38,135.92 R1248.2 R1244.2
N18169160: length 3.8
  TOP w0.109: v1(45,136.58) U65.1
  BOTTOM w0.109: R1240.1 45.77,137.34 v1(45,136.58)
N18169166: length 5.5
  TOP w0.109: v1(48.05,140.64) 48.81,141.4 U65.5
  BOTTOM w0.109: R1240.2 R1245.2 R1246.1 v1(48.05,140.64)
N18169184: length 19.2
  TOP w0.109: R1242.1 R1243.1 R1241.1 46.27,127.79 R1247.2 46.25,128.42 46.84,129.01 Q40.2 46.84,131.05 47.04,131.24 v1(47.04,135.18) 46.94,135.28 C816.1 U65.2
  BOTTOM w0.109: R1245.1 46.91,135.31 v1(47.04,135.18)
N18169218: length 9.5
  TOP w0.109: Q39.1 49.14,131.17 48.05,132.26 v1(48.05,135.69)
  BOTTOM w0.109: R1246.2 v1(48.05,135.69)
N18169273: length 3.6
  TOP w0.109: R1249.1 R1247.1 44.78,128.73 44.95,128.9 Q40.1
N18205231: length 2.1
  TOP w0.109: Q41.1 46.72,147.44 46.27,146.99 R1253.2
N18362458: length 9.9
  TOP w0.109: R431.1 132.38,111.94 132.89,112.45 135.56,112.45 136.26,113.15 136.26,113.91 137.59,115.24 138.6,115.24 138.8,115.43 139.49,115.43 U20.G21
N18362461: length 10.3
  TOP w0.109: U20.G20 140.29,115.43 140.29,110.76 140.79,110.26 140.79,107.65 139.75,106.6 R432.1
N18362464: length 7.5
  TOP w0.109: R434.1 135.81,110.92 136.67,111.79 137.54,111.79 137.82,112.07 137.82,112.58 137.59,112.81 137.59,113.79 137.71,113.92 138.27,113.92 138.76,113.43 U20.D22
N18362467: length 6.2
  TOP w0.109: U20.E22 138.47,114.23 138.35,114.35 137.15,114.35 136.57,113.78 136.57,112.95 135.56,111.94 R435.1
N18373532: length 1.6
  BOTTOM w0.109: Q11.1 R138.2
N18373604: length 4.6
  BOTTOM w0.109: Q11.3 15.41,87.17 15.64,87.4 R133.2 15.6,88.49 Q10.1
N18390944: length 6.7
  TOP w0.109: U20.B8 149.91,111.44 149.91,107.87 150.03,107.75 R548.1 C258.1
N18390947: length 6.3
  TOP w0.109: R549.1 153.08,109.27 151.53,110.82 151.53,111.39 U20.B7
N18391131: length 4.6
  TOP w0.109: v2(150.69,112.23) U20.C7
  BOTTOM w0.381: v2(150.69,112.23) 150.44,111.98 C259.2 C260.1 151.51,109.5 L15.2
N18404073: length 2.8
  TOP w0.109: v1(138.6,133.91) 138.22,133.91 137.59,133.27 D30.1
  BOTTOM w0.109: R551.1 v1(138.6,133.91)
N18404109: length 9.5
  TOP w0.109: v2(141.09,124.23) 141.89,124.23 U20.U18
  BOTTOM w0.109: v2(141.09,124.23) 140.69,124.64 140,124.64 138.03,126.61 136.31,126.61 135.36,127.56 R535.2
N18404132: length 12.1
  TOP w0.109: U20.V18 141.89,125.03 v2(141.09,125.03)
  BOTTOM w0.109: R536.2 132.1,128.35 132.25,128.19 135.17,128.19 136.44,126.92 138.36,126.92 140.25,125.03 v2(141.09,125.03)
N18446289: length 6.9
  BOTTOM w0.109: U26.40 168.96,118.92 168.26,119.62 168.26,123.11 168,123.37 C288.2 C289.2
N18446291: length 7.3
  BOTTOM w0.109: U26.37 167.46,118.95 167.49,118.98 167.49,119.48 167.94,119.94 167.94,122.48 167.69,122.73 166.57,122.73 166.44,122.86 C288.1 C289.1
N18446408: length 2.8
  BOTTOM w0.109: R617.2 172.64,120.83 173.4,120.07 173.4,119.18 172.96,118.74 U26.48
N18446673: length 3.3
  TOP w0.109: R615.1 170.33,121.84 C281.1 170.33,123.65 169.63,124.34 OSC3.1
N18446681: length 6.8
  TOP w0.109: OSC3.3 172.68,126.5 173.02,126.16 173.02,124 172.64,123.62 171.75,123.62 171.52,123.39 C280.1 171.5,122.96 R1138.2
N18462506: length 2.3
  TOP w0.109: U27.7 163.24,88.32 163.5,88.06 R607.1
N18462522: length 2.2
  TOP w0.109: R608.2 U27.3
N18484629: length 2.2
  TOP w0.099: v1(165.94,112.64) 165.72,112.41 165.54,112.41 C264.1
  BOTTOM w0.099: v1(165.94,112.64) 165.58,112.27 165.4,112.27 165.33,112.35 U26.21
N18484631: length 2.2
  TOP w0.099: v1(165.94,111.75) 165.72,111.97 165.54,111.97 C263.1
  BOTTOM w0.099: v1(165.94,111.75) 165.67,112.02 165.4,112.02 165.23,111.85 U26.20
N18490477: length 9.9
  TOP w0.109: U20.P20 v2(140.29,121.83)
  BOTTOM w0.109: v2(140.29,121.83) 136.43,121.83 134.79,120.19 132.25,120.19 132.1,120.35 R445.1
N18490497: length 11.2
  TOP w0.109: U20.M20 140.29,119.43 138.22,119.43 136.19,117.39 136.19,116.82 134.98,115.62 132.25,115.62 132.1,115.47 R444.1
N18491459: length 4.7
  TOP w0.109: U20.AB18 142.29,128.46 142.46,128.63 142.46,129.16 141.14,130.48 v1(140.41,130.48)
  BOTTOM w0.109: R550.2 140.38,130.51 v1(140.41,130.48)
N18565933: length 8.8
  TOP w0.109: R513.2 162.61,124.64 162.1,124.13 160.32,124.13 159.62,123.43 155.49,123.43 U20.T2
N18565936: length 2
  TOP w0.109: U20.T1 156.29,122.63 v2(156.29,122.63)
  BOTTOM w0.109: R514.2 157.17,123.14 156.66,122.63 v2(156.29,122.63)
N18565939: length 5.2
  TOP w0.109: R515.2 160.32,124.64 159.43,123.75 155.98,123.75 U20.U1
N18565942: length 2.2
  TOP w0.109: v2(154.69,124.23) U20.U2
  BOTTOM w0.109: R516.2 155.75,125.02 154.96,124.23 v2(154.69,124.23)
N18565945: length 5.8
  TOP w0.109: U20.P4 v2(153.89,121.83)
  BOTTOM w0.109: R517.2 156.89,125.53 156.64,125.27 156.64,124.77 154.48,122.61 154.48,122.34 153.97,121.83 v2(153.89,121.83)
N18565948: length 4.5
  TOP w0.109: U20.P3 v2(154.69,121.83)
  BOTTOM w0.109: R518.2 156.76,124.51 154.86,122.61 154.86,122 v2(154.69,121.83)
N18581691: length 5.3
  TOP w0.109: U20.R22 136.77,122.23 135.93,121.39 135.48,121.39 134.79,120.7 R490.1
N18581694: length 9
  TOP w0.109: U20.R21 139.49,122.63 136.72,122.63 135.8,121.71 135.35,121.71 134.98,121.34 132.25,121.34 132.1,121.18 R491.1
N18581697: length 5.5
  TOP w0.109: U20.P22 136.86,121.43 136.19,120.76 135.77,120.76 134.56,119.56 R496.1
N18581700: length 9.2
  TOP w0.109: R497.1 132.1,120.04 132.25,120.19 134.75,120.19 135.64,121.08 136.06,121.08 136.81,121.83 139.49,121.83 U20.P21
N18581728: length 7.8
  TOP w0.109: U20.Y20 v2(140.29,126.63)
  BOTTOM w0.109: v2(140.29,126.63) 138.6,128.32 136.44,128.32 134.92,129.85 R499.1
N18581730: length 9.8
  TOP w0.109: U20.AB20 140.69,128.14 139.97,128.86 135.3,128.86 134.83,129.34 132.51,129.34 132.1,128.93 R501.1
N18581732: length 8.5
  TOP w0.109: U20.AB21 139.51,128.22 135.58,128.22 135.43,128.07 132.23,128.07 132.1,127.94 R500.1
N18581734: length 5.8
  TOP w0.109: R502.1 137.25,127.56 137.45,127.36 138.69,127.36 138.77,127.43 139.49,127.43 U20.AA21
N18601236: length 5.5
  TOP w0.109: U20.V3 v2(154.69,125.03)
  BOTTOM w0.109: v2(154.69,125.03) 154.69,126.76 156.51,128.58 R541.1
N18601239: length 6.2
  TOP w0.109: U20.U3 v2(153.89,124.23)
  BOTTOM w0.109: R542.1 156.89,127.56 156.76,127.43 156,127.43 155.11,126.54 155.11,124.89 154.86,124.64 154.3,124.64 v2(153.89,124.23)
N18601328: length 6.7
  TOP w0.109: U20.AA3 154.69,127.43 159.3,127.43 159.56,127.69 R543.1
N18603109: length 8.5
  TOP w0.109: U20.W5 153.09,125.83 158.47,125.83 159.3,126.67 R544.2
N18603113: length 9.8
  TOP w0.109: U20.AB5 153.82,128.96 159.69,128.96 160.19,129.46 160.19,130.35 160.57,130.73 R546.2
N18655553: length 9.5
  TOP w0.109: R462.1 132.1,118.77 132.38,119.05 134.86,119.05 135.14,119.34 135.14,119.69 135.9,120.45 136.32,120.45 136.91,121.03 139.49,121.03 U20.N21
N18655556: length 5.6
  TOP w0.109: U20.N22 137.97,120.63 136.83,119.5 135.87,119.5 135.05,118.67 134.79,118.67 134.54,118.42 R463.1
N18657207: length 8.9
  TOP w0.109: U20.C14 v2(145.89,113.03)
  BOTTOM w0.109: v2(145.89,113.03) 145.33,112.47 145.33,109.91 141.91,106.48 R460.1
N18657210: length 5.7
  TOP w0.109: U20.A13 146.29,110.16 143.94,107.8 R461.1
N18657671: length 5.5
  TOP w0.109: R455.1 160.07,120.19 159.23,121.03 157.86,121.03 157.27,120.45 156.64,120.45 156.45,120.63 U20.N1
N18657674: length 5.3
  TOP w0.109: R456.1 160.32,122.61 159.15,121.43 U20.P1
N18657896: length 9.2
  TOP w0.109: U20.P2 155.49,121.83 159.04,121.83 160.32,123.11 162.99,123.11 163.27,123.39 R457.1
N18657899: length 5.4
  TOP w0.109: R459.1 160.32,123.62 159.81,123.12 157.91,123.12 157.02,122.23 U20.R1
N18673991: length 46.5
  TOP w0.109: U20.K19 v2(141.09,117.83)
  SIG4 w0.086: v1(130.48,112.47) 130.35,112.47 129.36,113.46 123.74,113.46 123.36,113.84 120.95,113.84 120.57,114.22 120.57,119.56 116.67,123.46 112.44,123.46 111.9,124 107.11,124 v1(106.98,123.88)
  BOTTOM w0.109: v1(106.98,123.88) 106.98,123.88 106.86,124 R437.1 ; v2(141.09,117.83) 140.25,117.83 139.87,117.45 139.87,116.76 139.49,116.38 138.35,116.38 137.97,116 137.28,116 133.73,112.45 130.5,112.45 v1(130.48,112.47)
N18673994: length 8.8
  TOP w0.109: U20.L19 v2(141.09,118.63)
  BOTTOM w0.109: R436.1 134.67,114.99 138.31,118.63 v2(141.09,118.63)
N18683698: length 5.8
  TOP w0.109: U20.Y21 139.49,126.63 135.01,126.63 134.79,126.42 R503.1
N18683701: length 6
  TOP w0.109: U20.V21 139.49,125.03 135.69,125.03 134.79,124.13 R504.1
N18683704: length 7.6
  TOP w0.109: U20.Y22 135.24,126.23 134.79,125.78 132.25,125.78 132.1,125.63 R506.1
N18683707: length 7.4
  TOP w0.109: U20.AA22 132.49,127.03 132.1,126.64 R508.1
N18683710: length 8
  TOP w0.109: U20.U22 136.91,123.83 135.43,122.35 132.25,122.35 132.1,122.2 R509.1
N18683713: length 7.1
  TOP w0.109: R510.1 134.92,121.84 135.1,122.02 135.67,122.02 137.08,123.43 140.29,123.43 U20.T20
N18683716: length 9.3
  TOP w0.109: U20.N18 v2(141.89,121.03)
  BOTTOM w0.109: R511.1 134.67,118.42 134.92,118.67 135.56,118.67 135.68,118.54 136.19,118.54 138.22,120.57 140.64,120.57 141.09,121.03 v2(141.89,121.03)
N18683719: length 8.2
  TOP w0.109: U20.P19 v2(141.09,121.83)
  BOTTOM w0.109: R512.1 134.67,119.56 136.55,121.44 140.7,121.44 v2(141.09,121.83)
N18701636: length 8.3
  TOP w0.109: U20.L20 140.29,118.63 137.88,118.63 136.5,117.25 136.5,116.69 134.79,114.99 R370.2
N18701697: length 9.3
  TOP w0.109: R374.2 132.1,114.33 132.25,114.48 134.79,114.48 136.82,116.5 136.82,117.08 137.96,118.23 U20.K22
N18701700: length 10.3
  TOP w0.109: R376.2 132.1,116.61 132.25,116.76 135.17,116.76 135.56,117.15 135.56,117.7 138.08,120.23 139.49,120.23 U20.M21
N18701703: length 6.6
  TOP w0.109: U20.M22 138.17,119.83 135.87,117.54 135.87,116.95 135.05,116.13 R377.2
N18713379: length 9.8
  TOP w0.109: U20.M18 v2(141.89,120.23)
  BOTTOM w0.109: R440.1 134.81,116.13 138.36,119.69 141.35,119.69 v2(141.89,120.23)
N18713382: length 11
  TOP w0.109: U20.M19 v2(141.09,120.23)
  BOTTOM w0.109: v2(141.09,120.23) 138.39,120.23 135.87,117.72 134.86,117.72 134.79,117.78 132.25,117.78 132.1,117.93 R442.1
N18846064: length 7.3
  TOP w0.109: U20.K21 139.49,117.83 138.84,117.83 137.4,116.38 137.21,116.38 134.79,113.97 R371.2
N18997501: length 1.4
  TOP w0.109: U20.L1 v2(156.29,118.63)
  BOTTOM w0.109: R1202.1 156.36,118.7 v2(156.29,118.63)
N18997503: length 2
  TOP w0.109: U20.N2 v1(155.49,121.03)
  BOTTOM w0.109: R1203.1 156.36,121.44 155.95,121.03 v1(155.49,121.03)
N125223401: length 1.8
  TOP w0.229: R227.1 187.37,151.36 v1(187.63,151.1)
  BOTTOM w0.229: v1(187.63,151.1) 187.6,151.13 C116.2
N125223760: length 1.6
  BOTTOM w0.381: R232.2 181.4,156.64 181.3,156.74 C124.1
N127846400: length 35.3
  TOP w0.109: U43.BB27 89.42,86.02 88.16,84.76 v2(88.16,84.35) ; v1(92.33,112.83) 91.97,112.47 R841.1
  SIG3 w0.107: v2(88.16,84.35) 88.03,84.48 88.03,87.2 87.74,87.49 87.74,88 88.18,88.44 88.18,88.82 88.51,89.14 88.51,89.53 89.45,90.48 89.71,90.48 91,91.77 91,93.93 92.12,95.05 92.12,96.46 93.32,97.66 93.32,99.54 93.39,99.62 93.39,103.95 94.18,104.73 94.18,107.33 93.2,108.31 93.2,110.9 93.04,111.06 93.04,112.12 v1(92.33,112.83)
N133349620: length 6.5
  TOP w0.109: v1(160.6,96.27) 161.39,96.27 161.72,95.94 161.72,94.41 160.37,93.07 D1.2
  BOTTOM w0.109: Q3.3 159.94,96.93 v1(160.6,96.27)
N134196140: length 4
  TOP w0.109: v1(93.26,128.58) 93.31,128.63 D2.2
  BOTTOM w0.109: v1(93.26,128.58) 91.49,128.58 91.11,128.19 Q6.3
N169038700: length 3.4
  TOP w0.109: Q5.3 94.15,153.85 93.82,154.18 D3.2
N169417421: length 1
  TOP w0.254: C346.2 R666.2
N169486101: length 1
  TOP w0.254: R673.2 C374.2
N174789369: length 2.3
  TOP w0.109: R1159.1 123.8,118.03 v1(123.49,118.34)
  BOTTOM w0.109: U61.10 123.17,118.66 v1(123.49,118.34)
N175629399: length 6
  BOTTOM w0.109: R1144.1 80.95,154.48 81.07,154.61 84.76,154.61 85.02,154.34 U62.10
N175901350: length 3.3
  TOP w0.508: C347.2 103.32,18.06 104.19,17.2 R667.1
N175914301: length 3.4
  TOP w0.508: R674.1 91.89,17.96 91.26,18.59 C375.2
N175914741: length 2
  TOP w0.508: C402.2 126.44,16.21 126.46,16.18 R678.1
N175915121: length 2.5
  TOP w0.508: R708.1 151.08,36.37 C432.2
N175915511: length 2.1
  TOP w0.508: R715.1 152.37,45.85 151.94,45.42 C455.2
N175915931: length 3.2
  TOP w0.508: R748.1 79.93,17.32 79.19,18.06 C488.2
N175916371: length 2.2
  TOP w0.508: R753.1 70.53,23.17 70.54,23.18 C499.2
N184153402: length 3.5
  BOTTOM w0.109: U26.3 171.96,109.19 173.15,108 173.78,108 173.91,107.87 R612.2
N184153404: length 2.4
  BOTTOM w0.109: R613.2 170.86,107.62 170.96,107.72 U26.5
N184153405: length 3.2
  BOTTOM w0.109: U26.6 170.46,108.87 169.34,107.75 169.34,107.49 169.19,107.34 R614.2
N185203330: length 1
  TOP w0.109: R632.1 R630.2
N185203331: length 8.7
  TOP w0.109: U20.K4 153.89,117.83 153.89,117.1 153.98,117.01 156.9,117.01 158.29,115.62 R632.2
N187134720: length 10.9
  TOP w0.109: U20.E17 142.69,113.83 141.27,113.83 141.09,113.66 141.09,112.5 141.32,112.27 141.79,112.27 141.92,112.14 141.92,110.79 142.29,110.41 142.29,108.51 140.89,107.11 R553.1
N1744816154: length 9.1
  TOP w0.109: R94.1 82.34,129.72 81.71,130.35 81.71,134.23 U2.M9
N1744816155: length 6.2
  TOP w0.109: U2.M8 v1(80.71,134.23)
  BOTTOM w0.109: v1(80.71,134.23) 80.64,134.16 79.93,134.16 78.15,132.39 78.15,130.99 77.9,130.73 R95.1
N1747893610: length 2.4
  TOP w0.109: v1(123.49,119.53) 123.97,119.05 R1158.2
  BOTTOM w0.109: U61.11 123.27,119.31 v1(123.49,119.53)
N1747893621: length 3.4
  TOP w0.109: R1160.2 125.8,114.99 v1(125.85,114.94)
  BOTTOM w0.109: U61.22 126.68,114.11 v1(125.85,114.94)
N1747893622: length 3.3
  TOP w0.109: v1(125.72,113.97) R1161.1
  BOTTOM w0.109: v1(125.72,113.97) 126.24,113.46 U61.23
N1756293914: length 2.5
  BOTTOM w0.109: R1167.1 85.14,160.45 85.02,160.34 U62.15
N1756293915: length 2.6
  BOTTOM w0.109: R1168.1 86.15,160.45 85.67,159.97 U62.16
N1756293918: length 2.6
  BOTTOM w0.109: R1169.1 87.17,160.2 87.62,159.75 U62.19
N1756293919: length 2.5
  BOTTOM w0.109: U62.20 88.27,160.11 88.18,160.2 R1170.1
N1841534011: length 3.1
  BOTTOM w0.109: U26.12 167.46,109.3 166.42,108.26 166.42,107.47 166.54,107.34 R620.1
N1841534012: length 2.8
  BOTTOM w0.109: U26.13 166.96,109.31 165.78,108.13 R619.1
N1841534013: length 3.4
  BOTTOM w0.109: R618.1 164.77,108.32 165.15,108.7 165.85,108.7 166.46,109.31 U26.14
N1841534014: length 3.8
  BOTTOM w0.109: U26.15 165.96,109.26 165.72,109.02 165.02,109.02 164.13,108.13 164.13,107.49 163.98,107.34 R616.1

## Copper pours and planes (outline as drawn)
12V_VCCGBE_P1V05_PCH on TOP: 156.26,49.58 160.83,49.58 161.46,48.95 161.46,47.17 161.34,47.04 159.94,47.04 159.69,47.3 156.26,47.3 156.13,47.42 156.13,49.45
12V_VCCGBE_P1V05_PCH on TOP: 156.13,40.18 156.76,40.18 157.53,39.42 160.57,39.42 160.96,39.04 160.96,37.39 160.83,37.26 156.51,37.26 156.13,37.64
12V_VCCGBE_P1V05_PCH on TOP: 165.02,48.06 168.19,48.06 168.32,47.93 168.32,44.63 168.19,44.5 165.02,44.5 164.89,44.63 164.89,47.93
12V_VCCGBE_P1V05_PCH on BOTTOM: 156,44.12 159.43,44.12 159.56,44.25 159.56,50.22 159.43,50.34 158.03,50.34 157.27,49.58 156.38,49.58 156.38,47.17 155.88,46.66 155.88,44.25
12V_VCCGBE_P1V05_PCH on BOTTOM: 158.8,38.79 159.18,38.41 159.18,32.18 159.05,32.06 156.38,32.06 156.13,32.31 156.13,37.9 157.02,38.79
12V_VCCGBE_P1V05_PCH on POWER2: 166.92,38.79 166.92,47.8 166.54,48.18 159.12,48.18 157.6,46.66 156.26,46.66 155.88,46.28 155.88,32.82 156.13,32.56 160.7,32.56
12V_VCCIN_VCCSCSUS on TOP: 130.35,16.56 131.87,16.56 132,16.43 132,9.96 131.87,9.83 130.09,9.83 129.84,10.08 129.84,16.05
12V_VCCIN_VCCSCSUS on TOP: 122.73,2.59 119.68,2.59 119.55,2.72 119.55,10.34 119.68,10.47 122.98,10.47 123.11,10.34 123.11,2.97
12V_VCCIN_VCCSCSUS on TOP: 111.3,14.66 110.16,13.51 110.16,11.86 110.66,11.35 110.66,8.81 110.41,8.56 105.46,8.56 104.95,9.07 104.95,11.74 106.35,13.13 106.35,14.91 106.6,15.16 106.73,15.16 106.85,15.29 106.85,16.05 106.98,16.18 111.17,16.18 111.3,16.05
12V_VCCIN_VCCSCSUS on TOP: 99.36,14.66 98.22,13.51 98.22,8.81 97.96,8.56 93.26,8.56 93.01,8.81 93.01,12.75 94.03,13.77 94.03,15.93 94.28,16.18 99.23,16.18 99.36,16.05
12V_VCCIN_VCCSCSUS on BOTTOM: 110.16,8.05 109.52,7.42 105.33,7.42 104.95,7.8 104.95,15.93 105.2,16.18 108,16.18 108.38,15.8 110.03,15.8 110.16,15.67
12V_VCCIN_VCCSCSUS on BOTTOM: 129.97,9.96 131.87,9.96 132.13,10.21 132.13,15.93 131.87,16.18 130.09,16.18 129.84,15.93 129.84,10.08
12V_VCCIN_VCCSCSUS on BOTTOM: 98.22,11.99 98.85,11.35 98.85,7.8 98.47,7.42 93.26,7.42 93.01,7.67 93.01,15.93 93.26,16.18 97.84,16.18 98.22,15.8
12V_VCCIN_VCCSCSUS on SIG2: 93.52,9.83 93.52,15.42 94.03,15.93 124.89,15.93 125.4,15.42 129.84,15.42 132.38,12.88 132.38,8.94 131.11,7.67 118.79,7.67 117.27,9.2 94.15,9.2
12V_VDDQ_P2V5_VPP on TOP: 71.55,7.41 68.75,10.21 68.75,16.31 72.56,16.31 72.94,16.69 74.98,16.69 75.1,16.56 75.1,15.67 74.6,15.16 74.34,15.16 73.45,14.28 73.45,12.42 74,11.87 79.94,11.87 81.2,13.13 81.96,13.89 81.96,14.4 82.6,15.04 82.6,15.93 82.85,16.18 87.17,16.18 87.3,16.05 87.3,14.66 86.15,13.51 86.15,8.43 86.03,8.31 83.61,8.31 82.72,7.41
12V_VDDQ_P2V5_VPP on BOTTOM: 68.75,11.1 68.75,16.31 72.56,16.31 73.45,15.42 73.45,12.5 73.58,12.37 73.58,12.37 74.15,11.81 80.38,11.81 80.95,12.37 80.95,15.93 81.2,16.18 85.77,16.18 86.15,15.8 86.15,8.18 85.39,7.42 80.31,7.42 80.3,7.42 72.43,7.42
12V_VIN on TOP (solid shape): 186.57,11.05 187.66,11.05 187.66,12.12 189.66,12.12 189.78,11.99 189.78,9.58 189.66,9.45 185.19,9.45 184.73,9.92 184.73,11.38 185.47,12.12 186.57,12.12
12V_VIN on BOTTOM (solid shape): 189.78,11.99 189.78,9.58 189.66,9.45 185.97,9.45 185.85,9.58 185.85,11.99 185.97,12.12 189.66,12.12
12V_VIN on TOP: 131.75,3.1 131.62,2.97 126.03,2.97 125.9,3.1 125.9,7.93 126.03,8.05 131.49,8.05 131.75,7.8
12V_VIN on TOP: 71.67,5.89 71.8,6.02 78.02,6.02 78.03,6.01 79.3,6.01 79.45,5.87 79.45,3.43 79.25,3.23 71.8,3.23 71.67,3.35
12V_VIN on TOP: 202.74,28.88 202.48,29.13 196.52,29.13 196.01,28.63 196.01,19.61 197.02,18.59 197.02,11.1 197.53,10.59 202.23,10.59 202.74,11.1
12V_VIN on TOP: 185.4,114.16 185.34,114.22 185.34,119.18 185.97,119.81 188.39,119.81 189.4,120.83 189.4,133.78 191.31,135.69 191.31,142.8 191.82,143.31 194.48,143.31 194.61,143.18 194.61,134.42 194.48,134.29 194.48,134.16 194.1,133.78 193.72,133.78 193.47,133.53 193.47,119.94 192.58,119.05 192.58,114.35 192.39,114.16
12V_VIN on TOP: 175.18,145.21 176.58,145.21 177.47,144.32 177.47,141.4 177.34,141.28 174.8,141.28 174.67,141.4 174.67,144.7
12V_VIN on TOP: 142.41,161.21 142.29,161.34 141.27,161.34 141.02,161.6 141.02,162.36 140.76,162.61 138.73,162.61 138.48,162.36 138.48,159.82 138.6,159.69 142.16,159.69 142.41,159.94
12V_VIN on TOP: 175.05,134.67 176.45,134.67 177.34,133.78 177.34,130.86 177.21,130.73 174.67,130.73 174.54,130.86 174.54,134.16
12V_VIN on TOP: 170.23,49.96 173.91,49.96 174.29,49.58 174.29,44.76 174.16,44.63 170.1,44.63 169.97,44.76 169.97,49.71
12V_VIN on TOP: 187.37,157.91 188.39,157.91 189.53,156.77 190.55,156.77 190.67,156.9 190.67,161.72 190.55,161.85 187.75,161.85 187.63,161.72 187.63,160.07 187.24,159.69 187.24,158.04
12V_VIN on TOP: 194.23,36.63 195.75,36.63 196.01,36.37 198.17,36.37 198.55,36.75 199.69,36.75 199.82,36.63 199.82,32.94 199.56,32.69 195.37,32.69 195.12,32.94 195.12,34.6 194.1,35.61 194.1,36.5
12V_VIN on BOTTOM: 199.94,35.61 199.94,33.07 199.69,32.82 195.5,32.82 195.25,33.07 195.25,35.61 195.37,35.74 199.82,35.74
12V_VIN on BOTTOM: 139.24,162.99 142.41,162.99 142.67,162.74 142.67,158.04 141.4,158.04 140.89,158.55 140.89,159.44 140.25,160.07 139.37,160.07 139.24,160.2
12V_VIN on BOTTOM: 174.67,130.73 177.21,130.73 177.34,130.86 177.34,132.77 177.21,132.89 174.67,132.89 174.54,132.77 174.54,130.86
12V_VIN on BOTTOM: 71.67,2.97 71.67,6.53 71.8,6.66 79.61,6.66 79.82,6.45 79.82,3.06 79.6,2.85 71.8,2.85
12V_VIN on BOTTOM: 174.8,141.28 177.34,141.28 177.47,141.4 177.47,143.31 177.34,143.43 174.8,143.43 174.67,143.31 174.67,141.4
12V_VIN on BOTTOM: 189.28,157.53 189.28,157.02 189.53,156.77 190.55,156.77 190.67,156.9 190.67,161.72 190.55,161.85 188.64,161.85 188.39,161.6 188.39,158.42
12V_VIN on BOTTOM: 187.5,114.48 186.99,114.48 186.74,114.22 185.47,114.22 185.34,114.35 185.34,120.45 185.85,120.96 192.32,120.96 192.71,120.57 192.71,114.61 192.45,114.35 191.56,114.35 191.44,114.48 190.67,114.48 190.55,114.35 190.42,114.35 190.17,114.61 189.71,114.61 189.49,114.38 189.04,114.38 188.82,114.61 188.26,114.61 188.01,114.35 187.63,114.35
12V_VIN on BOTTOM: 126.16,7.04 131.49,7.04 131.75,6.78 131.75,3.1 131.62,2.97 126.03,2.97 125.9,3.1 125.9,6.78
12V_VIN on POWER1: 154.48,11.48 171.12,28.12 171.12,51.36 177.08,57.33 179.88,57.33 182.55,60 182.55,64.82 183.82,66.09 183.82,113.46 182.55,114.73 182.55,123.75 180.26,126.04 174.42,126.04 174.16,126.29 174.16,159.69 174.67,160.2 182.29,160.2 182.42,160.07 182.67,160.33 187.12,160.33 188.71,161.91 193.28,161.91 194.74,160.45 194.74,149.78 198.55,145.97 201.34,145.97 201.85,145.47 201.85,100.51 202.61,99.75 202.61,60 203.12,59.49 203.12,12.24 193.53,2.65 152.26,2.65 148.76,6.15 146.73,6.15 143.24,2.65 117.59,2.65 117.39,2.46 112.82,2.46 112.57,2.72 70.66,2.72 70.53,2.85 70.53,11.23 70.79,11.48 ; 1 cut-out
12V_VIN on POWER2: 154.48,11.48 177.47,34.47 177.47,54.92 182.55,60 182.55,69.9 183.56,70.92 183.56,76.51 182.55,77.52 182.55,115.62 182.29,115.88 180.51,115.88 175.81,120.57 175.81,130.48 174.16,132.13 174.16,150.93 173.78,151.31 172.26,151.31 172.13,151.18 120.7,151.18 120.19,151.69 120.19,161.72 120.82,162.36 192.07,162.36 194.74,159.69 194.74,149.78 198.55,145.97 201.34,145.97 201.85,145.47 201.85,100.51 202.36,100 202.36,59.87 202.99,59.23 202.99,12.12 193.47,2.59 152.32,2.59 148.76,6.15 146.73,6.15 143.18,2.59 70.4,2.59 70.4,10.47 71.42,11.48 ; 3 cut-outs
12V_VIN on SIG3: 187.44,128.24 192.17,128.24 192.79,127.62 192.79,114.64 192.31,114.16 186.11,114.16 185.69,114.58 185.69,116.93 187.08,118.31 187.08,127.88
12V_VIN on SIG3: 191.44,153.72 120.82,153.72 119.93,154.61 119.93,161.98 120.32,162.36 191.31,162.36 191.56,162.1 191.56,153.85 ; 3 cut-outs
GND on TOP (solid shape): 189.78,14.4 189.78,12.88 189.66,12.75 187.66,12.75 187.66,13.69 186.57,13.69 186.57,12.75 185.21,12.75 184.83,12.37 182.04,12.37 181.64,11.97 181.64,10.21 181.51,10.08 181.15,10.08 177.08,6.02 173.78,6.02 173.66,6.15 173.66,9.2 178.99,14.53 189.66,14.53
GND on TOP (solid shape): 90.09,19.61 90.09,17.7 90.47,17.32 90.47,16.56 90.34,16.43 84.5,16.43 84.25,16.69 83.7,16.69 83.67,16.7 83.65,16.74 83.65,17.76 82.56,17.76 82.56,16.74 82.54,16.7 82.51,16.69 82.09,16.69 81.96,16.82 81.96,17.89 81.69,18.16 81.49,18.16 81.37,18.28 81.37,19.64 81.47,19.74 89.96,19.74
GND on TOP: 184.7,120.96 188.51,120.96 188.9,121.34 188.9,134.04 190.55,135.69 190.55,142.93 190.29,143.18 186.99,143.18 186.48,142.67 186.48,133.53 184.58,131.62 184.58,121.08
GND on TOP: 117.01,36.88 117.52,37.39 118.16,37.39 118.41,37.64 118.41,42.47 118.79,42.85 118.79,48.44 116.38,50.85 96.61,50.85 96.39,50.63 96.39,48.91 96.61,48.69 109.39,48.69 110.03,48.06 110.03,43.74 109.65,43.36 108,43.36 107.62,42.98 107.62,37.26 107.87,37.01 110.28,37.01 111.68,38.41 114.6,38.41 114.85,38.15 114.85,28.63 114.98,28.5 116.63,28.5 117.01,28.88
GND on TOP: 184.58,157.02 186.86,157.02 186.99,157.15 186.99,159.82 187.24,160.07 187.24,162.23 187.12,162.36 184.32,162.36 184.07,162.1 184.07,160.2 184.45,159.82 184.45,157.15
GND on TOP: 138.73,99.37 141.65,99.37 141.91,99.11 141.91,96.44 142.41,95.94 146.99,95.94 147.37,96.32 147.37,100.51 146.99,100.89 144.32,100.89 144.19,101.02 144.19,103.56 143.94,103.81 142.03,103.81 141.91,103.68 141.91,101.02 141.78,100.89 138.73,100.89 138.6,100.76 138.6,99.49
GND on TOP: 138.98,132.26 138.73,132.51 138.73,134.42 138.86,134.54 142.29,134.54 142.41,134.42 142.41,131.24 142.29,131.12 139.75,131.12 138.98,131.88
GND on TOP: 178.1,134.16 178.1,130.61 178.23,130.48 179.62,130.48 179.88,130.73 179.88,138.99 179.75,139.12 175.31,139.12 175.18,138.99 175.18,138.1 175.43,137.85 177.08,137.85 177.34,137.59 177.34,134.93
GND on TOP: 168.45,162.1 168.45,155.25 168.19,154.99 163.88,154.99 163.62,155.25 163.62,157.02 163.11,157.53 163.11,162.23 163.24,162.36 168.19,162.36
GND on TOP: 89.33,31.29 88.44,31.29 88.06,31.67 88.06,35.87 86.15,37.77 86.15,45.33 86.79,45.96 86.79,49.26 86.42,49.63 84.77,49.63 84.75,49.61 83.88,49.61 83.61,49.89 83.61,52.88 84.12,53.39 88.05,53.39 89.25,52.18 89.25,47.82 88.89,47.46 88.89,40.87 89.77,39.99 89.77,37.52 89.58,37.33 89.58,31.55
GND on TOP: 142.67,134.54 145.97,134.54 146.1,134.67 146.1,144.2 144.45,145.85 141.52,145.85 141.4,145.72 141.4,137.85 142.54,136.7 142.54,134.67
GND on TOP: 153.46,43.1 154.22,43.1 154.61,43.49 155.75,43.49 155.88,43.36 155.88,37.52 156.76,36.63 162.61,36.63 162.73,36.5 162.73,35.74 162.61,35.61 161.59,35.61 160.96,34.98 155.11,34.98 154.86,35.23 154.86,37.01 154.61,37.26 153.59,37.26 153.34,37.52 153.34,42.98
GND on TOP: outline of 143 points within 1.02,1.02 203.98,163.98 ; 38 cut-outs
GND on TOP: 155.24,157.91 156.38,157.91 156.64,158.17 156.64,158.93 157.02,159.31 158.67,159.31 158.67,160.71 155.24,160.71 155.11,160.58 155.11,158.04
GND on TOP: 176.2,110.03 175.31,110.92 175.31,112.07 175.81,112.57 179.75,112.57 180.01,112.32 180.01,110.29 179.75,110.03
GND on TOP: 97.84,161.34 97.96,161.21 101.27,161.21 101.65,161.6 103.55,161.6 103.68,161.72 103.68,162.48 103.55,162.61 97.96,162.61 97.84,162.48
GND on TOP: 129.97,19.36 134.79,19.36 134.92,19.23 134.92,18.47 135.3,18.09 135.3,16.94 135.17,16.82 130.09,16.82 129.33,16.05 129.33,10.08 129.21,9.96 127.17,9.96 127.05,10.08 127.05,13.89 127.81,14.66 127.81,15.93 129.84,17.96 129.84,19.23
GND on TOP: 132,40.69 131.59,41.1 125.68,41.1 125.05,40.47 125.05,38.75 125.47,38.33 131.72,38.33 132,38.6
GND on TOP: 128.32,61.52 129.46,61.52 129.97,62.03 131.49,62.03 131.62,62.15 131.62,62.79 131.49,62.92 128.32,62.92 128.19,62.79 128.19,61.65
GND on TOP: 133.94,38.71 136.43,38.71 136.65,38.49 136.65,36.31 136.54,36.21 133.94,36.21 133.82,36.33 133.82,38.58
GND on TOP: 200.71,36.75 202.36,36.75 202.48,36.63 202.48,33.07 202.23,32.82 200.71,32.82 200.58,32.94 200.58,36.63
GND on TOP: 96.57,16.43 96.31,16.69 94.15,16.69 94.03,16.82 94.03,18.75 93.92,18.86 93.49,18.86 93.4,18.95 93.4,19.99 93.51,20.1 95.98,20.1 96.35,19.74 102.03,19.74 102.15,19.61 102.15,17.96 102.54,17.58 102.54,16.56 102.41,16.43
GND on TOP: 77.18,35.57 78.61,35.57 78.81,35.38 78.81,33.65 79.37,33.09 79.37,31.93 79.13,31.69 77.77,31.69 77.08,32.37 77.08,35.48
GND on TOP: 119.3,70.79 119.55,70.54 119.55,69.14 119.81,68.89 121.2,68.89 121.46,69.14 121.46,70.66 120.82,71.3 116,71.3 115.62,70.92 115.62,69.65 115.49,69.52 113.84,69.52 112.06,71.3 110.03,71.3 109.52,71.81 109.52,72.06 109.65,72.19 111.93,72.19 113.08,71.04 114.73,71.04 115.87,72.19 121.97,72.19 122.09,72.06 122.09,66.73 121.97,66.6 114.85,66.6 113.72,67.73 113.21,67.73 111.04,69.9 109.52,69.9 109.39,70.03 109.39,70.28 109.52,70.41 111.68,70.41 113.58,68.5 115.36,68.5 115.62,68.25 115.62,67.11 115.74,66.98 119.05,66.98 119.43,67.36 119.43,68.76 119.17,69.01 117.01,69.01 116.89,69.14 116.89,70.54 117.14,70.79
GND on TOP: 164.26,69.65 165.65,69.65 166.16,69.14 166.16,66.73 166.42,66.47 168.45,66.47 168.58,66.6 168.58,70.28 168.19,70.66 164.26,70.66 164.13,70.54 164.13,69.77
GND on TOP: 138.22,156.64 139.75,156.64 139.87,156.52 139.87,155.75 139.62,155.5 135.68,155.5 135.43,155.75 135.43,159.56 135.56,159.69 137.71,159.69 138.1,159.31 138.1,156.77
GND on TOP: 113.97,16.43 108.5,16.43 108.25,16.69 106.85,16.69 106.6,16.94 106.6,17.96 106.22,18.34 105.45,18.34 105.38,18.41 105.38,19.57 105.54,19.74 113.97,19.74 114.09,19.61 114.09,16.56
GND on TOP: 174.16,120.83 174.16,127.05 173.02,128.19 171.62,128.19 171.5,128.07 170.86,128.07 170.73,128.19 168.07,128.19 167.94,128.07 167.94,121.08 169.46,119.56 169.97,119.56 170.1,119.69 170.1,120.19 169.72,120.57 169.72,122.23 169.59,122.35 168.96,122.35 168.83,122.48 168.83,123.75 168.7,123.88 168.7,125.65 168.83,125.78 170.48,125.78 170.86,125.4 170.86,123.88 171.12,123.62 172.51,123.62 172.64,123.75 172.64,125.4 172.39,125.65 170.99,125.65 170.73,125.91 170.73,127.43 170.86,127.56 172.64,127.56 173.15,127.05 173.15,122.61 172.64,122.1 172.26,122.1 172.26,120.45 171.75,119.94 171.75,119.56 171.88,119.43 172.77,119.43
GND on TOP: 158.42,45.14 154.86,45.14 154.73,45.26 154.73,46.53 154.48,46.79 153.59,46.79 153.46,46.91 153.46,47.55 153.34,47.68 153.34,52.5 153.59,52.76 155.75,52.76 155.88,52.63 155.88,47.17 156.13,46.91 157.78,46.91 158.29,46.41 161.59,46.41 161.84,46.66 161.84,49.07 162.61,49.84 163.11,49.84 163.24,49.71 163.24,44.63 162.99,44.37 159.18,44.37
GND on TOP: 63.93,146.61 65.83,146.61 66.09,146.36 66.09,143.82 66.34,143.56 68.88,143.56 68.88,138.86 68.75,138.74 63.93,138.74 63.8,138.86 63.8,141.53 63.29,142.04 60.75,142.04 60.5,142.29 60.5,143.56 60.63,143.69 63.55,143.69 63.8,143.94 63.8,146.48
GND on TOP: 175.18,49.96 177.21,49.96 177.47,49.71 177.47,44.76 177.34,44.63 175.18,44.63 175.05,44.76 175.05,49.84
GND on TOP: 167.56,126.29 167.31,126.54 165.65,126.54 165.53,126.42 165.53,123.11 165.65,122.99 167.43,122.99 167.56,123.11
GND on TOP: 171.5,112.19 171.24,111.94 166.92,111.94 166.67,112.19 166.67,116.13 166.8,116.26 171.37,116.26 171.5,116.13
GND on TOP: 101.27,30.79 104.95,30.79 105.2,30.53 105.2,27.48 104.95,27.23 101.52,27.23 101.14,27.61 101.14,30.66
GND on TOP: 115.11,78.79 117.01,78.79 117.14,78.66 117.14,76.63 117.01,76.51 115.11,76.51 114.98,76.63 114.98,78.66
GND on TOP: 193.91,156.77 191.56,156.77 191.44,156.9 191.44,161.85 191.56,161.98 193.98,161.98 194.1,161.85 194.1,156.96
GND on TOP: 73.33,16.82 73.07,17.07 68.5,17.07 68.37,17.2 68.37,19.49 69.58,20.69 71.62,20.69 72.96,19.36 77.64,19.36 77.77,19.23 77.77,18.09 78.28,17.58 78.28,16.94 78.15,16.82
GND on TOP: 63.55,31.04 63.55,31.03 64.64,31.03 64.79,30.89 64.79,29.02 63.89,28.12 59.48,28.12 59.23,28.37 59.23,30.91 59.36,31.04
GND on TOP: 102.54,153.09 107.23,153.09 107.36,153.21 107.36,156.39 107.23,156.52 102.54,156.52 102.41,156.39 102.41,153.21
GND on TOP: 122.73,30.28 128.44,30.28 128.57,30.15 128.57,28.25 128.44,28.12 124.63,28.12 124.25,28.5 122.86,28.5 122.6,28.75 122.6,30.15
GND on TOP: 25.7,32.94 24.94,32.94 24.68,32.69 24.3,32.69 24.18,32.56 24.18,31.67 23.67,31.17 20.24,31.17 20.11,31.04 20.11,29.39 20.37,29.13 24.05,29.13 24.68,29.77 24.68,30.91 24.94,31.17 26.08,31.17 26.21,31.04 26.21,30.28 26.46,30.28 26.46,30.91 26.72,31.17 28.24,31.17 28.49,31.42 28.49,32.69 28.24,32.94 26.08,32.94 25.95,33.07 25.95,33.83 25.7,33.83
GND on TOP: 89.45,47.14 89.45,40.69 90.09,40.06 90.09,37.14 89.84,36.88 89.84,26.72 89.96,26.59 92.5,26.59 92.76,26.85 92.76,45.71 93.01,45.96 93.01,47.01 92.76,47.26 89.57,47.26
GND on TOP: 188.39,28.37 194.48,28.37 194.74,28.12 194.74,21.51 194.48,21.26 188.51,21.26 188.26,21.51 188.26,28.25
GND on TOP: 136.57,48.31 136.7,48.18 136.7,46.9 138,45.61 138,44.84 137.78,44.63 127.42,44.63 126.87,45.18 123.58,45.18 123.57,45.19 123.36,45.19 123.22,45.33 123.22,47.69 123.83,48.31
GND on TOP: 106.6,106.22 107.87,106.22 108,106.35 108,108.51 108.25,108.76 109.39,108.76 109.65,108.51 109.65,106.73 109.39,106.48 109.39,102.67 108.76,102.03 107.87,102.03 105.71,99.87 105.71,99.62 106.09,99.24 106.47,99.24 108.5,101.27 109.27,101.27 110.28,102.29 110.28,111.3 110.03,111.56 105.84,111.56 105.33,111.05 105.33,101.65 104.19,100.51 103.93,100.51 103.55,100.13 103.55,100 103.81,99.75 103.81,98.6 104.06,98.35 104.31,98.35 104.44,98.48 104.44,100 106.6,102.16 106.6,105.33 105.84,106.1 105.84,110.29 106.35,110.8 107.74,110.8 108,110.54 108,109.14 107.62,108.76 106.6,108.76 106.47,108.64 106.47,106.35
GND on TOP: 178.23,144.58 178.23,141.02 178.35,140.89 179.75,140.89 180.01,141.15 180.01,149.4 179.88,149.53 175.43,149.53 175.31,149.4 175.31,148.51 175.56,148.26 177.21,148.26 177.47,148.01 177.47,145.34
GND on TOP: 193.21,37.01 193.21,39.29 193.34,39.42 195.88,39.42 196.01,39.55 197.79,39.55 197.91,39.42 197.91,37.01 197.66,36.75 196.01,36.75 195.88,36.88 193.34,36.88
GND on TOP: 94.53,116.51 101.01,116.51 101.14,116.38 101.14,106.73 100.5,106.1 100.25,106.1 99.61,105.46 99.61,105.08 98.85,104.32 97.2,104.32 93.14,100.25 92.88,100.25 92.76,100.38 92.76,100.64 96.95,104.83 98.73,104.83 99.11,105.21 99.11,106.35 99.23,106.48 100.5,106.48 100.63,106.6 100.63,107.62 100.38,107.87 98.47,107.87 98.34,108 98.34,108.64 98.47,108.76 100.38,108.76 100.63,109.02 100.63,110.41 100.38,110.67 95.04,110.67 94.92,110.54 94.92,108.89 95.04,108.76 96.69,108.76 96.95,108.51 96.95,108 96.82,107.87 94.92,107.87 94.79,107.75 94.79,106.6 94.92,106.48 96.06,106.48 96.19,106.35 96.19,105.08 91.87,100.76 91.49,100.76 91.36,100.89 91.36,101.27 94.28,104.19 94.28,116.26
GND on TOP: 186.86,46.66 195.99,46.66 196.27,46.38 196.27,45.36 192.6,41.69 187.04,41.69 186.74,41.99 186.74,46.53
GND on TOP: 81.83,6.66 111.17,6.66 112.82,8.31 117.01,8.31 118.92,6.4 118.92,1.58 118.41,1.07 81.84,1.07 81.61,1.3 81.61,6.43
GND on TOP, BOTTOM: 162.48,59.74 164,59.74 164.51,59.23 164.51,53.26 164.77,53.01 166.42,53.01 166.54,53.14 166.54,55.8 166.92,56.19 166.92,61.01 166.8,61.14 162.73,61.14 162.35,60.76 162.35,59.87
GND on BOTTOM: 13.69,58.39 13.69,65.7 14.4,66.4 14.4,70.16 14.76,70.52 22.99,70.52 23.17,70.34 23.17,68.69 23.31,68.55 23.31,66.49 24.18,65.61 24.18,50.71 23.05,49.58 21.29,49.58 21.28,49.59 20.52,49.59 17.95,52.15 17.95,54.13
GND on BOTTOM: 192.45,37.01 192.45,40.31 192.58,40.44 196.39,40.44 196.64,40.18 196.64,36.88 196.52,36.75 192.71,36.75
GND on BOTTOM: 130.09,19.48 134.67,19.48 134.79,19.36 134.79,16.94 134.67,16.82 129.84,16.82 129.33,16.31 129.33,10.08 129.21,9.96 127.17,9.96 127.05,10.08 127.05,16.43
GND on BOTTOM: 104.19,22.15 103.93,22.4 103.93,23.67 101.14,23.67 100.76,23.29 100.76,22.53 100.5,22.28 92.5,22.28 92.25,22.53 92.25,25.32 90.85,26.72 89.84,26.72 89.65,26.91 89.65,34.67 89.07,35.25 89.07,38.53 89.39,38.85 89.39,45.76 89.69,46.05 91.59,46.05 92.63,45.01 92.63,36.37 92.38,36.12 92.38,31.55 93.9,30.02 100.12,30.02 100.63,30.53 106.85,30.53 107.49,29.9 110.66,29.9 111.04,29.52 111.04,22.4 110.79,22.15
GND on BOTTOM: 120.32,30.15 128.44,30.15 128.57,30.02 128.57,26.72 128.32,26.47 119.05,26.47 118.54,26.98 118.54,36.63 118.92,37.01 118.92,38.41 119.05,38.53 120.7,38.53 120.82,38.41 120.82,34.09 119.93,33.2 119.93,30.53
GND on BOTTOM: 132.13,40.69 132,40.82 125.4,40.82 125.04,40.46 125.04,38.68 125.27,38.45 131.85,38.45 132.13,38.73
GND on BOTTOM: 156,52.88 159.3,52.88 159.94,53.52 159.94,66.98 159.69,67.23 156,67.23 155.75,66.98 155.75,53.14
GND on BOTTOM: outline of 124 points within 1.02,1.02 136.7,163.98
GND on BOTTOM: 94.92,116.64 100.12,116.64 100.38,116.38 100.38,108.38 100,108 95.17,108 94.79,108.38 94.79,116.51
GND on BOTTOM: 95.3,141.8 95.75,141.35 95.75,139.8 95.57,139.62 93.26,139.62 93.14,139.75 93.14,143.82 93.26,143.94 95.17,143.94 95.3,143.82
GND on BOTTOM: outline of 100 points within 110.92,1.02 203.98,163.98 ; 6 cut-outs
GND on BOTTOM: 78.41,27.61 78.41,30.15 77.77,30.79 77.77,33.45 77.9,33.58 88.31,33.58 88.44,33.71 89.07,33.71 89.26,33.52 89.26,23.86 88.44,23.04 80.18,23.04 79.8,23.42 79.8,26.21
GND on BOTTOM: 150.67,157.91 152.07,157.91 152.19,157.79 152.19,151.82 152.07,151.69 150.41,151.69 150.29,151.82 150.29,153.47 150.54,153.72 150.54,157.79
GND on BOTTOM: 58.97,24.82 59.1,24.94 62.91,24.94 63.17,24.69 63.17,20.37 62.91,20.12 59.1,20.12 58.97,20.24
GND on BOTTOM: 195.12,32.18 200.33,32.18 200.71,31.8 200.71,30.15 200.58,30.02 195.12,30.02 194.99,30.15 194.99,32.06
GND on BOTTOM: 18.08,86.54 25.83,86.54 26.08,86.79 26.08,87.94 25.7,88.32 17.95,88.32 17.83,88.19 17.83,86.79
GND on BOTTOM: 139.24,100.56 139.24,99.37 139.11,99.24 137.08,99.24 136.95,99.37 136.95,100.61 137.06,100.72 139.08,100.72
GND on BOTTOM: 130.09,62.79 131.49,62.79 131.62,62.66 131.62,56.82 131.49,56.69 130.22,56.69 129.97,56.95 129.97,62.66
GND on BOTTOM: 161.21,33.96 161.34,33.83 161.34,32.18 161.21,32.06 159.69,32.06 159.56,32.18 159.56,38.66 159.69,38.79 161.08,38.79 161.21,38.66
GND on BOTTOM: 169.34,131.12 168.96,131.5 168.96,139.12 169.21,139.37 171.12,139.37 171.24,139.24 171.24,138.35 171.62,137.97 173.27,137.97 173.53,137.72 173.53,131.37 173.27,131.12
GND on BOTTOM: 86.53,16.43 84.25,16.43 83.99,16.69 81.14,16.69 80.95,16.88 80.95,19.77 81.16,19.99 89.96,19.99 90.09,19.86 90.09,10.96 89.82,10.69 87.01,10.69 86.79,10.92 86.79,16.18
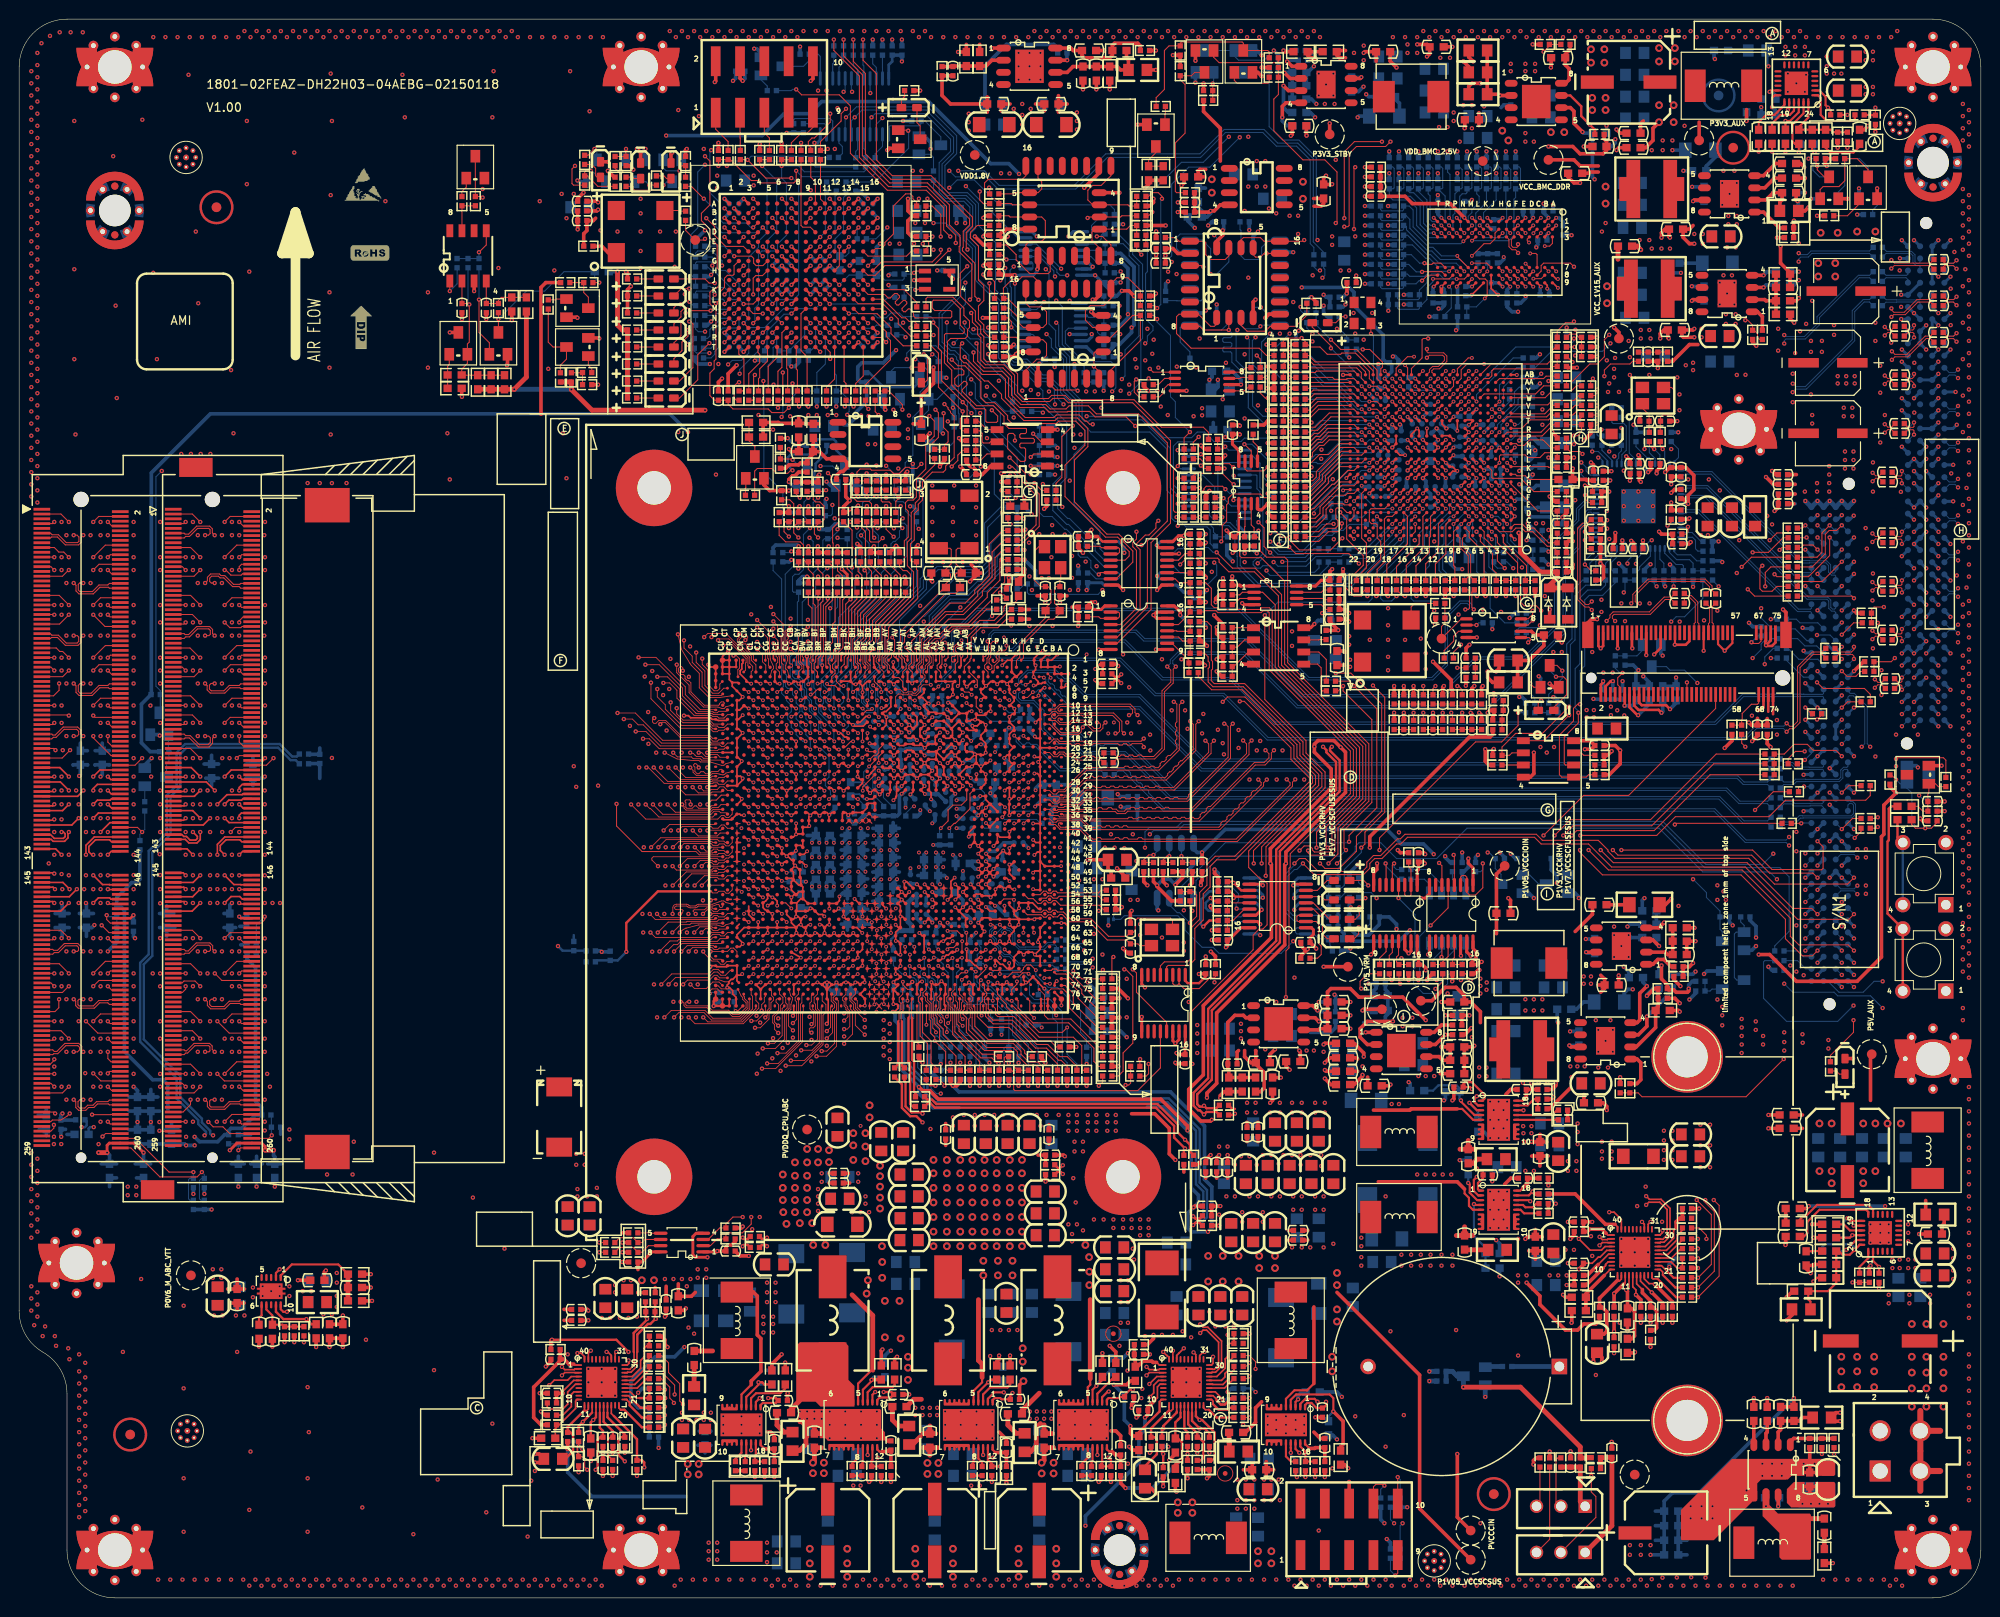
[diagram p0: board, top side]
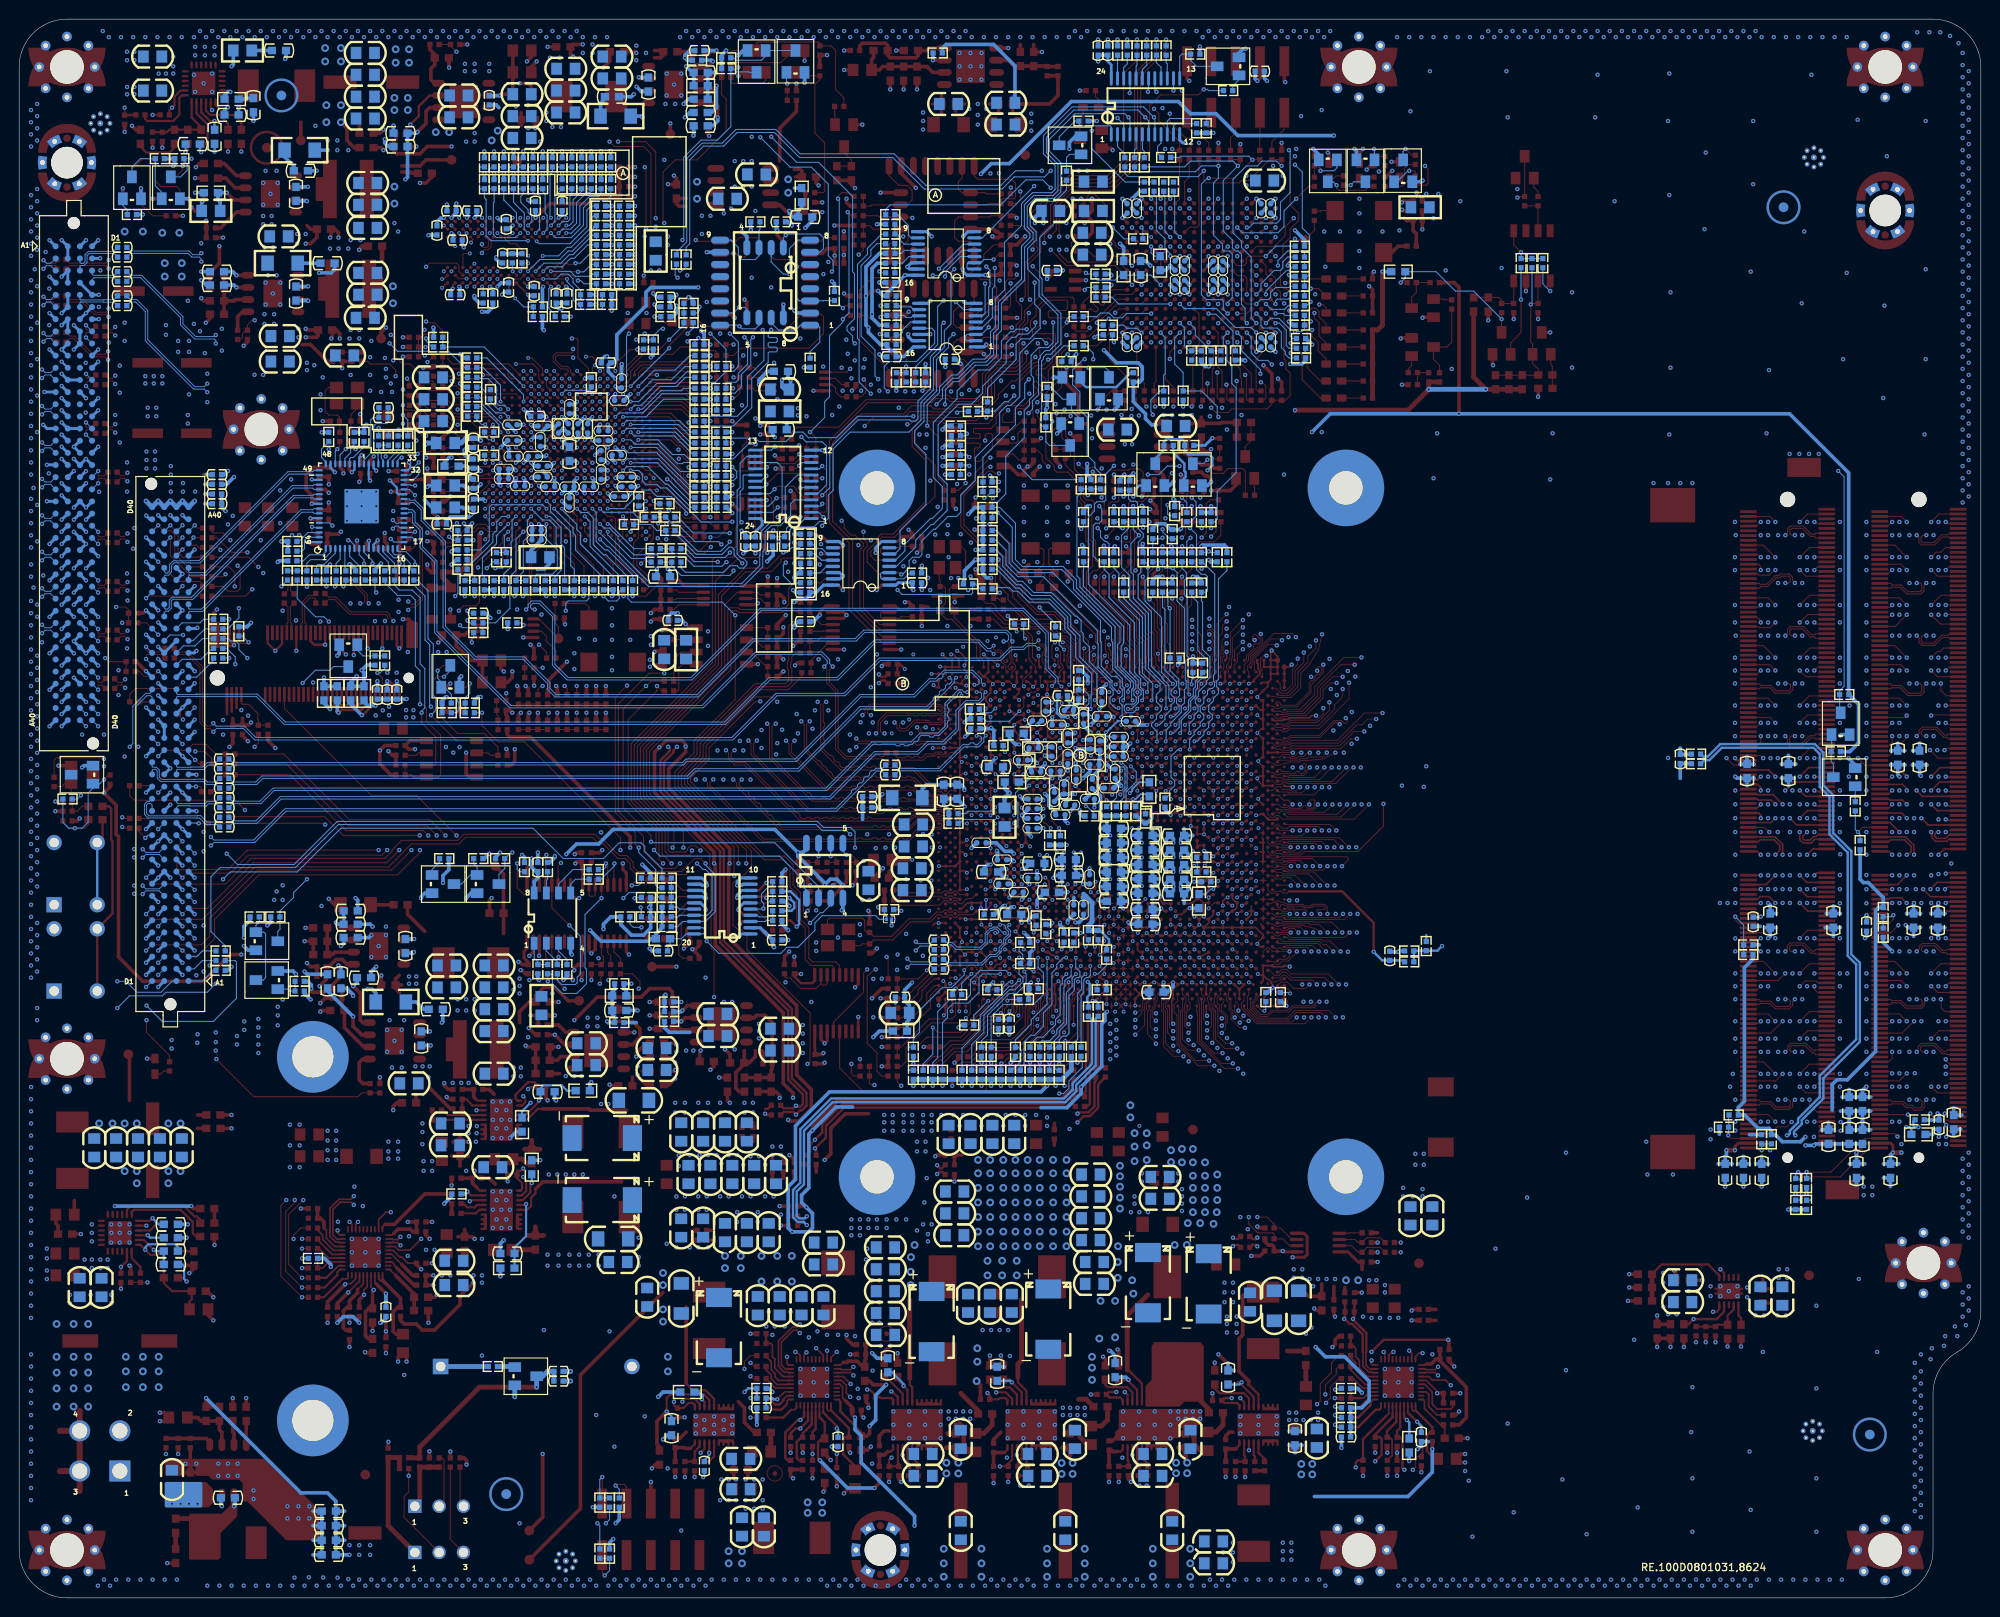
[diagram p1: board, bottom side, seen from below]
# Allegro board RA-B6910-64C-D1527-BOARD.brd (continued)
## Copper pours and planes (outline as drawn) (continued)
GND on BOTTOM: 113.33,60.25 115.87,60.25 116.12,60.5 116.12,61.9 115.74,62.28 113.33,62.28 113.2,62.15 113.2,60.38
GND on BOTTOM: 158.67,151.94 157.15,151.94 156.89,152.2 156.89,160.58 157.02,160.71 158.67,160.71 158.8,160.58 158.8,152.07
GND on BOTTOM: 186.99,46.66 197.79,46.66 197.91,46.53 197.91,41.45 197.79,41.33 186.99,41.33 186.74,41.58 186.74,46.41
GND on BOTTOM: 180.64,130.1 180.89,129.85 180.89,127.81 180.64,127.56 178.23,127.56 178.1,127.69 178.1,129.97 178.23,130.1
GND on BOTTOM: 166.29,70.66 168.32,70.66 168.58,70.41 168.58,66.35 166.16,66.35 166.16,70.54
GND on BOTTOM: 97.48,77.92 97.37,77.8 97.37,75.86 97.57,75.65 98.78,75.65 98.89,75.76 98.89,76.03 98.57,76.35 98.57,77.83 98.48,77.92
GND on BOTTOM: 119.93,24.69 120.06,24.82 123.87,24.82 124.13,24.56 124.13,20.24 123.87,19.99 120.06,19.99 119.93,20.12
GND on BOTTOM: 168.45,162.1 168.45,153.85 166.8,153.85 166.67,153.98 166.67,154.74 166.42,154.99 163.37,154.99 163.11,155.25 163.11,162.23 163.24,162.36 168.19,162.36
GND on BOTTOM: 59.48,30.53 77.26,30.53 78.02,29.77 78.02,27.48 79.29,26.21 79.29,25.32 79.55,25.07 79.55,23.8 78.91,23.17 70.53,23.17 69.9,23.8 69.9,26.72 69.77,26.85 67.23,26.85 66.85,26.47 59.1,26.47 58.97,26.59 58.97,30.02
GND on BOTTOM: 98.6,16.43 96.31,16.43 96.06,16.69 93.32,16.69 93.19,16.82 93.19,19.99 93.54,20.33 101.83,20.33 102.15,20.01 102.15,11.34 101.98,11.17 99.47,11.17 98.85,11.79 98.85,16.18
GND on BOTTOM: 13.13,44.37 9.06,44.37 8.94,44.25 8.94,42.72 9.83,41.83 13.13,41.83 13.25,41.96 13.25,44.25
GND on BOTTOM: 132.76,38.28 136.44,38.28 136.57,38.15 136.57,36.5 136.44,36.37 132.76,36.37 132.63,36.5 132.63,38.15
GND on BOTTOM: 114.73,27.1 114.85,27.23 114.85,38.15 114.6,38.41 111.68,38.41 110.28,37.01 107.87,37.01 107.62,37.26 107.62,42.98 108,43.36 109.65,43.36 110.03,43.74 110.03,47.55 108.89,48.69 98.22,48.69 98.09,48.82 98.09,51.36 98.22,51.49 118.28,51.49 121.33,48.44 121.33,41.58 118.41,38.66 118.41,37.52 118.03,37.14 118.03,26.47 117.65,26.09 114.85,26.09 114.73,26.21
GND on BOTTOM: 72.69,149.02 74.47,149.02 74.6,148.9 74.6,147.12 74.47,146.99 72.69,146.99 72.56,147.12 72.56,148.9
GND on BOTTOM: 136.44,44.63 124.52,44.63 124.33,44.82 124.33,48.05 124.59,48.31 136.44,48.31 136.7,48.06 136.7,44.88
GND on BOTTOM: 130.6,150.67 130.35,150.93 128.06,150.93 127.81,150.67 127.81,144.7 127.94,144.58 130.48,144.58 130.6,144.7
GND on BOTTOM: 185.47,121.46 193.09,121.46 195.22,123.6 195.22,126.25 194.86,126.61 194.86,133.27 193.98,134.16 193.09,134.16 191.82,135.43 191.82,139.12 190.8,140.13 187.75,140.13 186.48,138.86 186.48,137.21 184.7,135.43 181.02,135.43 180.89,135.31 180.89,130.35 183.82,127.43 183.82,123.11
GND on BOTTOM: 112.06,73.08 114.22,73.08 114.6,73.46 114.6,74.85 115.11,75.36 117.01,75.36 117.14,75.49 117.14,81.46 117.01,81.59 112.06,81.59 111.81,81.33 111.81,76.76 111.93,76.63 111.93,73.2
GND on BOTTOM: 153.46,52.38 155.75,52.38 155.88,52.25 155.88,43.87 156.26,43.49 156.26,38.53 154.86,37.14 153.84,37.14 152.95,38.02 152.95,47.55 153.34,47.93 153.34,52.25
GND on BOTTOM: 166.67,38.41 166.8,38.53 170.61,38.53 170.86,38.28 170.86,33.96 170.61,33.71 166.8,33.71 166.67,33.83
GND on BOTTOM: 86.01,69.28 87.28,69.28 87.38,69.39 87.38,69.67 86.99,70.06 86.99,70.7 86.73,70.97 86.73,71.38 86.99,71.64 86.99,80.39 86.72,80.65 85.7,80.65 85.55,80.5 85.55,70.22 85.85,69.92 85.85,69.44
GND on BOTTOM: 80.31,121.46 83.61,121.46 83.87,121.72 83.87,123.62 83.61,123.88 80.31,123.88 80.18,123.75 80.18,121.59
GND on BOTTOM: 72.94,17.07 68.5,17.07 68.37,17.2 68.37,19.86 68.5,19.99 77.9,19.99 78.02,19.86 78.02,16.69 77.77,16.43 73.58,16.43
GND on BOTTOM: 180.01,131.24 179.88,131.12 178.1,131.12 177.97,131.24 177.97,133.4 177.08,134.29 177.08,140.26 177.21,140.39 179.75,140.39 180.01,140.13
GND on BOTTOM: 168.96,140.77 168.96,152.45 169.21,152.71 172.77,152.71 173.15,152.32 173.15,140.64 173.02,140.51 169.21,140.51
GND on BOTTOM: 136.19,58.34 137.84,58.34 137.97,58.22 137.97,53.26 137.84,53.14 136.06,53.14 135.94,53.26 135.94,58.09
GND on BOTTOM: 105.71,111.56 109.27,111.56 110.16,110.67 110.16,105.21 109.9,104.95 108.12,104.95 106.6,106.48 106.6,107.49 105.33,108.76 105.33,111.18
GND on BOTTOM: 20.37,29.13 20.11,29.39 20.11,31.04 20.24,31.17 23.67,31.17 24.18,31.67 24.18,32.56 24.56,32.94 28.24,32.94 28.49,32.69 28.49,29.39 28.24,29.13
GND on BOTTOM: 191.56,156.77 191.44,156.9 191.44,161.85 191.56,161.98 193.98,161.98 194.1,161.85 194.1,157.02 193.85,156.77
GND on BOTTOM: 122.86,60.25 125.14,60.25 125.14,56.57 125.01,56.44 122.98,56.44 122.73,56.69 122.73,60.12
GND on BOTTOM: 150.16,50.22 149.91,50.47 145.97,50.47 145.59,50.09 145.59,40.18 143.56,38.15 143.56,36.5 142.67,35.61 142.67,32.18 142.79,32.06 150.03,32.06 150.16,32.18
GND on BOTTOM: 141.78,51.11 144.19,51.11 144.45,51.36 144.45,54.03 145.46,55.04 145.46,58.73 145.97,59.23 145.97,60.88 145.72,61.14 144.32,61.14 143.94,60.76 143.94,59.87 143.43,59.36 142.03,59.36 141.52,58.85 141.52,51.36
GND on BOTTOM: 107.36,156.77 102.41,156.77 102.28,156.64 102.28,153.34 102.41,153.21 107.23,153.21 107.49,153.47 107.49,156.64
GND on BOTTOM: 135.68,160.2 137.97,160.2 138.1,160.07 138.1,156.01 137.84,155.75 135.43,155.75 135.3,155.88 135.3,159.82
GND on BOTTOM: 116.89,62.92 122.09,62.92 122.47,62.54 122.47,56.44 123.24,55.68 133.02,55.68 133.14,55.55 133.14,53.01 132.63,52.5 126.67,52.5 126.28,52.12 126.28,49.87 126.1,49.69 124.42,49.69 120.59,53.52 114.6,53.52 114.47,53.65 114.47,57.71 114.73,57.96 116.25,57.96 116.76,58.47 116.76,62.79
GND on BOTTOM: 92.62,76.47 92.62,73.09 91.96,72.43 90.88,72.43 90.74,72.57 90.74,81.06 90.9,81.22 94.54,81.22 95.05,80.71 95.05,75.17 94.95,75.06 93.83,75.06 93.62,75.27 93.62,76.53 93.45,76.7 92.85,76.7
GND on BOTTOM: 184.07,162.61 186.99,162.61 187.12,162.48 187.12,155.25 184.58,155.25 184.2,155.63 184.2,158.8 183.94,159.06 183.94,162.48
GND on BOTTOM: 167.69,128.83 167.56,128.96 167.56,131.5 167.81,131.75 168.32,131.75 169.21,130.86 170.48,130.86 170.61,130.73 170.61,128.96 170.48,128.83
GND on BOTTOM: 90.22,120.32 89.58,120.96 89.58,122.73 89.33,122.99 87.8,122.99 87.55,122.73 87.55,120.19 88.44,119.3 90.09,119.3 90.22,119.43
GND on BOTTOM: 30.15,46.66 29.13,47.68 24.18,47.68 23.92,47.93 23.92,49.2 24.68,49.96 25.95,49.96 26.46,49.45 26.97,49.45 26.97,50.6 26.59,50.98 26.21,50.98 25.45,51.74 25.45,69.52 26.08,70.16 27.22,70.16 30.91,66.47 30.91,39.55 33.45,37.01 33.45,32.82 32.69,32.06 32.69,30.28 31.54,30.28 31.54,34.47 30.15,35.87
GND on BOTTOM: 109.39,6.66 109.77,6.27 109.77,1.19 109.65,1.07 81.91,1.07 81.69,1.28 81.69,2.47 81.45,2.72 80.82,2.72 80.58,2.96 80.58,6.43 80.81,6.66
GND on BOTTOM: 84.63,52.76 84.76,52.88 88.12,52.88 89.42,51.59 89.42,46.6 89.01,46.19 89.01,39.36 88.57,38.91 86.41,38.91 86.15,39.17 86.15,47.8 84.63,49.33
GND on BOTTOM: 108,16.69 105.06,16.69 104.95,16.8 104.95,19.78 105.16,19.99 113.97,19.99 114.09,19.86 114.09,12.12 113.97,11.99 111.04,11.99 110.79,12.24 110.79,15.93 110.54,16.18 108.5,16.18
GND on BOTTOM: 145.72,157.91 145.72,154.74 146.1,154.36 147.49,154.36 147.62,154.48 147.62,162.48 147.49,162.61 143.68,162.61 143.43,162.36 143.43,158.17 143.56,158.04 145.59,158.04
GND on BOTTOM: 177.47,149.53 179.88,149.53 180.01,149.4 180.01,141.15 179.75,140.89 178.35,140.89 177.97,141.28 177.97,144.83 177.34,145.47 177.34,149.4
GND on BOTTOM: 161.21,128.32 161.34,128.19 161.34,122.23 161.08,121.97 158.92,121.97 158.8,122.1 158.8,126.16 159.3,126.67 159.3,127.94 159.69,128.32
GND on BOTTOM: 160.32,43.99 163.11,43.99 163.24,44.12 163.24,50.09 162.99,50.34 160.45,50.34 160.19,50.09 160.19,44.12
GND on BOTTOM: 130.73,22.78 138.22,22.78 138.35,22.91 138.35,24.94 140.13,26.72 140.13,30.91 140,31.04 138.73,31.04 138.22,30.53 134.92,30.53 130.48,26.09 130.48,23.04
GND on GND1, GND2, GND3, GND4: 10,1.02 7.18,2.18 6.02,5 6.02,21.34 5.21,24.35 3.01,26.55 1.55,28.01 1.02,30 1.02,160 2.18,162.82 5,163.98 200,163.98 202.82,162.82 203.98,160 203.98,5 202.82,2.18 200,1.02
GND on SIG1: 125.52,41.2 144.57,41.2 150.03,35.74 150.03,32.18 149.65,31.8 129.84,31.8 128.7,32.94 128.7,36.88 128.06,37.52 125.27,37.52 125.01,37.77 125.01,40.69
GND on SIG1: 167.43,33.2 172.26,33.2 172.77,33.71 172.77,36.12 170.1,38.79 167.31,38.79 166.92,38.41 166.92,33.71
GND on SIG1: 70.91,8.05 70.53,8.05 69.13,9.45 68.88,9.2 68.88,1.83 69.13,1.58 70.53,1.58 70.91,1.96
GND on SIG1: 176.83,145.34 180.39,145.34 180.64,145.59 180.64,149.53 180.13,150.04 176.96,150.04 176.7,149.78 176.7,145.47
GND on SIG1: 73.5,19.36 80.95,19.36 82.22,20.63 89.96,20.63 90.72,21.39 90.72,22.02 90.09,22.66 77.52,22.66 75.48,24.69 75.48,32.94 77.01,34.47 82.22,34.47 82.34,34.34 82.34,31.42 84.25,29.52 115.24,29.52 115.36,29.39 115.36,23.17 113.97,21.77 102.41,21.77 102.15,21.51 102.15,20.88 102.66,20.37 116.25,20.37 117.01,19.61 117.01,17.96 116.38,17.32 114.73,17.32 113.58,16.18 92.12,16.18 90.98,15.04 75.36,15.04 73.29,17.11 73.29,19.14
GND on SIG1: 119.93,25.45 123.87,25.45 124.13,25.2 124.13,19.74 123.74,19.36 119.93,19.36 119.55,19.74 119.55,25.07
GND on SIG1: outline of 170 points within 1.02,1.02 203.98,163.98 ; 1 cut-out
GND on SIG1: 64.31,20.75 65.2,21.64 65.2,22.78 63.17,24.82 58.59,24.82 57.7,25.71 57.2,25.71 56.69,25.2 57.07,24.82 57.07,23.17 56.82,22.91 56.56,22.91 56.43,23.04 56.43,24.31 55.93,24.82 55.93,25.83 55.67,26.09 54.78,25.2 54.78,23.8 57.83,20.75
GND on SIG1: 169.21,142.93 176.83,142.93 177.72,142.04 181.15,142.04 181.15,134.16 180.89,133.91 176.7,133.91 175.81,134.8 175.81,139.37 174.54,140.64 169.08,140.64 168.96,140.77 168.96,142.67
GND on SIG2: 121.08,29.64 133.9,29.64 134.41,30.15 134.41,49.07 132.51,50.98 125.14,50.98 123.74,49.58 123.74,44.25 120.32,40.82 120.32,30.4
GND on SIG2: 174.49,105.94 177.51,105.94 177.89,105.57 177.89,102.61 176.99,101.71 172.66,101.71 172.37,102 172.37,103.83
GND on SIG2: 58.85,19.74 64.69,19.74 64.94,19.99 64.94,21.9 62.28,24.56 58.59,24.56 58.47,24.44 58.47,20.12
GND on SIG2: 183.56,51.99 185.97,54.41 185.97,131.62 185.72,131.88 185.72,132.89 186.1,133.27 186.1,143.43 180.26,149.28 141.53,149.28 141.04,149.76 139.95,149.76 139.47,149.28 136.19,149.28 136.06,149.15 136.06,148.64 137.59,147.12 137.59,138.23 137.97,137.85 137.97,133.78 137.08,132.89 137.08,110.29 137.33,110.03 142.16,110.03 142.29,110.16 142.29,113.21 141.52,113.97 141.52,124.77 141.65,124.89 144.83,124.89 145.72,124 152.57,124 152.64,124.07 154.54,124.07 161.46,130.99 161.46,132.89 162.86,134.29 162.86,137.59 164.13,138.86 167.69,138.86 169.21,137.34 169.21,129.21 166.8,126.8 166.8,122.99 168.19,121.59 174.8,121.59 179.37,117.02 179.37,101.65 182.47,98.55 182.47,75.79 178.23,71.55 178.23,62.08 176.44,60.3 172.84,60.3 170.62,58.07 170.62,52.9 171.52,51.99
GND on SIG2: 73.33,1.58 71.55,1.58 71.29,1.83 71.29,3.61 71.93,3.61 72.82,2.72 73.33,2.72
GND on SIG2: 112.55,90.6 112.56,90.6 115.4,93.43 120.3,93.43 120.6,93.13 120.6,92.3 110.72,82.43 100.48,82.43 100.1,82.82 100.1,86.82 101.58,88.3 110.26,88.3
GND on SIG2: 130.09,16.94 134.41,16.94 134.54,17.07 134.54,19.86 134.29,20.12 130.09,20.12 129.84,19.86 129.84,17.2
GND on SIG2: 162.34,114.03 165.79,114.03 166.34,113.48 166.34,112.12 167.07,111.39 167.07,110.81 166.92,110.66 162.49,110.66 162.08,111.07 162.08,113.76
GND on SIG2: 164.38,39.17 173.02,39.17 173.27,38.91 173.27,30.91 172.89,30.53 164.26,30.53 163.88,30.91 163.88,38.66
GND on SIG2: 73.71,16.05 123.87,16.05 125.27,17.45 125.27,22.78 122.22,25.83 117.65,25.83 117.27,25.45 117.27,21.9 115.74,20.37 82.34,20.37 81.83,19.86 80.31,19.86 80.18,19.99 73.58,19.99 73.2,19.61 73.2,16.56
GND on SIG2: outline of 126 points within 1.02,1.02 203.98,163.98
GND on SIG2: 188.71,99.75 190.71,99.75 190.84,99.62 190.84,97.88 190.72,97.76 188.73,97.76 188.61,97.88 188.61,99.65
GND on POWER1: 10,1.02 7.18,2.18 6.02,5 6.02,21.34 5.21,24.35 3.01,26.55 1.55,28.01 1.02,30 1.02,160 2.18,162.82 5,163.98 68.14,163.98 69.13,162.99 69.13,120.32 87.8,101.65 87.8,82.73 86.66,81.59 81.96,81.59 79.42,84.13 56.18,84.13 53.01,87.3 3.98,87.3 2.46,85.78 2.46,72.06 2.97,71.55 45.89,71.55 49.07,68.38 74.09,68.38 76.5,70.79 85.14,70.79 88.69,67.23 88.69,64.19 89.45,63.42 89.45,55.42 79.17,45.14 79.17,40.2 79.18,40.19 79.18,39.28 84.59,33.88 84.59,26.52 86.42,24.69 92.06,24.69 92.18,24.57 93.58,24.57 93.7,24.69 102.79,24.69 102.79,24.69 103.56,24.69 104.07,25.2 111.43,25.2 112.82,26.59 112.82,38.53 113.33,39.04 127.04,39.04 127.42,38.66 130.6,38.66 130.98,39.04 142.92,39.04 143.05,38.91 143.05,28.75 139.37,25.07 139.37,23.67 134.41,18.72 133.9,18.72 132.89,17.7 132.13,17.7 131.75,18.09 131.11,18.09 130.73,17.7 61.01,17.7 60.37,17.07 60.37,11.48 60.75,11.1 69.13,11.1 69.77,10.47 69.77,1.58 69.21,1.02
GND on POWER1, POWER2: 148.64,5.64 146.86,5.64 146.1,4.88 146.1,3.23 147.62,1.7 148.13,1.7 149.65,3.23 149.65,4.62
GND on POWER1, POWER2: 198.67,146.61 195.12,150.17 195.12,163.75 195.35,163.98 200,163.98 201.33,163.75 202.51,163.09 203.09,162.51 203.75,161.33 203.98,160 203.98,147.73 202.87,146.61
GND on POWER2: 10,1.02 7.18,2.18 6.02,5 6.02,21.34 5.21,24.35 1.55,28.01 1.02,30 1.02,160 2.18,162.82 5,163.98 186.51,163.98 186.99,163.5 186.99,162.99 186.86,162.87 120.95,162.87 119.93,161.85 119.93,151.56 120.57,150.93 173.66,150.93 173.91,150.67 173.91,132 175.31,130.61 175.31,120.45 180.26,115.49 181.66,115.49 182.04,115.11 182.04,77.65 183.31,76.38 183.31,71.04 182.29,70.03 182.29,60.25 176.96,54.92 176.96,35.1 153.84,11.99 120.41,11.99 120.26,12.14 119.05,12.14 118.9,11.99 101.7,11.99 101.53,12.16 85.83,12.16 85.66,11.99 70.4,11.99 69.64,11.23 69.64,1.7 69.01,1.07 32.3,1.07 32.25,1.02 ; 1 cut-out
GND on SIG3: 108,63.93 111.93,63.93 113.71,65.71 113.71,66.85 114.22,67.36 121.71,67.36 121.97,67.62 121.97,70.54 121.84,70.66 113.84,70.66 113.2,70.03 110.02,70.03 109.34,69.35 108.2,69.35 107.87,69.01 107.87,64.06
GND on SIG3: 183.77,77.74 182.41,79.1 182.41,89.71 183.13,90.43 184.89,90.43 186.46,92 186.85,92 187.21,91.64 188.91,91.64 189.01,91.54 189.01,89.37 188.33,88.68 188.32,88.68 188.19,88.56 186.77,88.56 186.77,79.21 185.92,78.35 185.92,77.85 185.81,77.74
GND on SIG3: 143.68,116.26 150.29,116.26 151.18,117.15 151.18,119.43 151.81,120.07 155.62,120.07 155.75,120.19 155.75,120.57 154.22,122.1 153.08,122.1 152.45,122.73 152.45,124.13 151.3,125.27 149.53,125.27 148.76,124.51 145.33,124.51 142.54,121.72 142.54,118.8 143.18,118.16 143.18,116.76
GND on SIG3: outline of 111 points within 1.02,1.02 203.98,163.98 ; 1 cut-out
GND on SIG3: 187.74,88.22 189.25,88.22 189.46,88.02 189.46,81.78 190.67,80.57 190.67,65.06 190.45,64.83 187.81,64.83 187.51,65.13 187.51,65.79 185.44,67.86 185.44,76.55 186.44,77.55 186.44,78.1 187.52,79.17 187.52,87.99
GND on SIG3: 95.17,116.76 100,116.76 100.25,116.51 100.25,108.13 100,107.87 95.42,107.87 95.17,108.13 95.17,113.34 94.92,113.59 94.92,116.51
GND on SIG3: 114.95,87.95 114.95,85.17 113.58,83.79 110.95,83.79 110.38,84.37 110.38,86.31 109.66,87.03 109.66,88.03 109.26,88.43 109.26,88.94 109.27,88.95 109.27,90.99 110.41,92.13 114.73,92.13 114.85,92 114.85,91.36 114.09,90.6 114.09,90.09 114.35,89.84 115.62,89.84 116,90.22 116,90.6 116.12,90.73 117.14,90.73 117.27,90.6 117.27,90.26
GND on SIG3: 139.37,103.94 145.08,103.94 147.37,101.65 147.37,96.7 146.99,96.32 140.64,96.32 139.75,97.21 138.98,97.21 138.35,97.84 138.35,100.38 138.98,101.02 138.98,103.56
GND on SIG3: 180.13,149.91 182.93,147.12 187.63,147.12 190.8,143.94 190.8,142.8 191.44,142.16 195.25,142.16 196.53,140.88 198.74,140.88 199.12,140.5 199.12,134.24 198.29,133.41 198.29,130.35 198.23,130.29 198.8,129.72 198.8,89.84 196.13,89.84 196.01,89.97 196.01,112.83 196.13,112.95 196.13,128.83 196.01,128.96 195.5,128.96 194.95,128.4 194.18,128.4 193.35,129.23 186.52,129.23 186.25,128.96 186.25,118.69 184.2,116.64 180.13,116.64 176.07,120.7 176.07,127.81 176.83,128.58 181.02,128.58 181.91,129.46 181.91,129.97 180.77,131.12 168.19,131.12 167.43,131.88 167.43,149.78 167.56,149.91
GND on SIG3: 164.38,38.28 172,38.28 172.77,37.52 172.77,31.55 172.39,31.17 164.51,31.17 164.13,31.55 164.13,37.52 164,37.64 164,37.9
GND on SIG3: 65.45,146.61 68.5,146.61 68.75,146.36 68.75,138.61 67.99,137.85 66.85,137.85 67.74,136.96 67.74,133.4 71.29,129.85 71.29,128.96 76.25,124 77.14,124 79.17,121.97 79.17,118.8 80.69,117.27 80.69,115.62 79.68,114.61 79.68,106.35 80.95,105.08 80.95,99.87 80.82,99.75 77.64,99.75 74.34,103.05 71.67,103.05 68.75,105.97 61.9,105.97 57.07,110.8 4.75,110.8 4.11,111.43 4.11,114.61 6.4,116.89 15.29,116.89 15.79,117.4 15.79,125.65 37.64,147.5 64.56,147.5
GND on SIG3: 170.61,116.89 171.75,115.75 172.77,115.75 172.89,115.62 172.89,110.8 172.39,110.29 166.29,110.29 164.77,111.81 164.77,116.26 165.4,116.89
GND on SIG3: 190.55,103.74 191.96,103.74 192.24,103.45 192.24,95.03 194.21,93.07 194.21,87.78 193.22,86.79 193.22,81.39 193.2,81.38 191.13,81.38 190.19,82.32 190.19,103.38
GND on SIG3: 113.46,30.53 123.11,30.53 124.13,29.52 128.57,29.52 135.05,23.04 138.86,23.04 139.75,22.15 139.75,22.02 156.51,22.02 157.02,22.53 157.02,31.17 153.97,34.21 153.97,35.1 156,37.14 156,43.36 155.49,43.87 152.45,43.87 150.92,45.39 150.92,52.38 150.29,53.01 144.57,53.01 143.81,53.77 143.81,58.6 147.37,62.15 147.37,64.57 144.45,67.49 141.14,67.49 138.6,64.95 138.6,61.01 135.17,57.58 128.7,57.58 125.78,54.66 125.27,54.66 121.97,51.36 111.43,51.36 111.3,51.23 111.3,48.31 110.92,47.93 110.92,45.01 113.08,42.85 113.08,30.91
GND on SIG3: 148.38,66.09 166.8,66.09 167.18,66.47 169.59,66.47 169.72,66.6 169.72,70.41 169.59,70.54 147.75,70.54 147.62,70.41 147.62,66.85
GND on SIG4: 85.39,79.93 85.26,80.06 82.34,80.06 79.8,77.52 79.8,77.01 79.42,76.63 79.42,74.85 80.31,73.97 80.31,72.45 80.92,71.84 80.92,69.55 81.2,69.27 85.52,69.27 85.64,69.39 85.64,70.16 85.26,70.54 85.26,73.71 85.39,73.84
GND on SIG4: 58.72,24.82 64.82,24.82 64.94,24.69 64.94,20.24 64.69,19.99 58.72,19.99 58.59,20.12 58.59,24.69
GND on SIG4: 136.44,96.57 155.75,96.57 157.53,98.35 157.53,104.19 156.89,104.83 137.33,104.83 135.94,103.43 135.94,97.08
GND on SIG4: 170.86,110.41 162.35,110.41 159.18,113.59 159.18,119.81 159.69,120.32 162.86,120.32 162.99,120.19 162.99,118.03 164.13,116.89 172.51,116.89 172.77,116.64 172.77,112.32
GND on SIG4: 70.31,21.51 87.8,21.51 89.96,19.36 89.96,16.05 89.71,15.8 79.54,15.8 78.45,16.89 73.55,16.89 73.01,17.43 68.78,17.43 68.63,17.58 68.63,19.83
GND on SIG4: 154.73,62.41 159.43,62.41 160.32,63.3 173.4,63.3 174.04,63.93 175.05,63.93 175.05,63.3 174.04,62.28 173.4,62.28 173.02,61.9 173.02,61.14 173.27,60.88 175.05,60.88 178.74,64.57 183.56,64.57 184.07,65.08 184.07,69.77 183.43,70.41 143.3,70.41 141.02,68.12 141.02,67.11 141.14,66.98 152.07,66.98 152.45,67.36 153.21,67.36 154.35,66.22 154.35,62.79
GND on SIG4: outline of 211 points within 1.02,1.02 203.98,163.98 ; 1 cut-out
GND on SIG4: 115.11,66.85 125.27,66.85 125.52,67.11 125.52,70.03 124.89,70.66 117.01,70.66 114.85,68.5 114.85,67.11
GND on SIG4: 70.79,8.05 69.01,8.05 68.88,7.93 68.88,1.7 69.01,1.58 70.79,1.58 71.04,1.83 71.04,7.8
GND on SIG4: 138.35,58.22 148.13,58.22 150.54,60.63 150.54,62.41 150.29,62.66 135.3,62.66 135.05,62.41 135.05,58.6 135.17,58.47 138.1,58.47
P0V6_M_ABC_VTT on TOP: 23.8,32.69 24.18,33.07 24.68,33.07 24.81,33.2 25.45,33.2 25.45,34.09 25.57,34.21 26.08,34.21 26.21,34.09 26.21,33.2 26.46,33.2 26.46,34.98 26.21,35.23 17.83,35.23 17.45,34.85 17.45,32.31 17.83,31.93 23.67,31.93 23.8,32.06
P0V6_M_ABC_VTT on BOTTOM: 7.54,41.33 7.54,46.53 7.79,46.79 13.51,46.79 13.64,46.66 18.46,46.66 18.97,47.17 21.26,47.17 21.38,47.04 29,47.04 29.64,46.41 29.64,36.12 28.75,35.23 26.08,35.23 23.67,32.82 23.67,32.06 23.54,31.93 16.94,31.93 ; 1 cut-out
P0V9_NIC_OUT on BOTTOM: 164.13,124.64 165.91,126.42 167.31,126.42 167.56,126.67 167.56,128.45 167.05,128.96 163.75,128.96 163.11,128.32 162.23,128.32 162.1,128.19 162.1,122.23 162.23,122.1 163.88,122.1 164.13,122.35
P0V9_NIC_OUT on SIG4: 164.13,117.53 167.05,117.53 167.43,117.15 171.24,117.15 171.88,117.78 171.88,120.07 168.58,123.37 168.58,128.58 168.45,128.7 164.89,128.7 164.38,128.19 164.38,125.91 165.34,124.96 165.34,123.43 166.54,122.23 166.54,121.34 164.38,119.18 164,119.18 163.88,119.05 163.88,117.78
P1V3_VCCKRHV on TOP: 140,54.41 142.41,54.41 142.54,54.53 142.54,56.82 142.41,56.95 140,56.95 139.87,56.82 139.87,54.53
P1V3_VCCKRHV on BOTTOM: 105.58,71.93 108,69.52 111.17,69.52 112.57,68.12 112.57,64.82 114.22,63.17 138.1,63.17 138.6,62.66 138.6,53.26 138.73,53.14 140.64,53.14 140.76,53.26 140.76,65.58 139.62,66.73 116.25,66.73 115.3,67.68 115.3,68.69 115.24,68.76 115.24,69.27 114.09,70.41 113.2,70.41 112.82,70.79 109.39,70.79 104.95,75.24 103.3,75.24 103.17,75.11 103.17,74.73 103.3,74.6 103.3,73.84 102.66,73.2 102.66,72.31 103.04,71.93
P1V5_NIC_OUT on TOP: 167.43,119.3 167.18,119.05 165.53,119.05 165.4,119.18 165.4,121.97 165.65,122.23 167.31,122.23 167.43,122.1
P1V5_NIC_OUT on BOTTOM: 173.4,130.73 174.04,130.1 177.21,130.1 177.34,129.97 177.34,128.32 177.08,128.07 173.91,128.07 173.15,128.83 171.5,128.83 171.37,128.96 171.37,130.61 171.5,130.73
P1V5_NIC_OUT on SIG1: 172.39,116.38 166.8,116.38 165.65,117.53 165.65,119.69 168.19,122.23 168.19,130.1 168.83,130.73 175.31,130.73 175.43,130.61 175.43,128.45 174.8,127.81 173.53,127.81 173.27,127.56 173.27,119.18 173.15,119.05 173.02,119.05 172.64,118.67 172.64,116.64
P1V05_PCH on TOP: 127.05,49.07 136.83,49.07 137.21,48.69 137.21,46.91 137.46,46.66 141.91,46.66 141.94,46.69 142.16,46.69 142.51,47.04 142.51,50.63 140.25,52.88 135.56,52.88 134.92,52.25 127.17,52.25 126.92,51.99 126.92,49.2
P1V05_PCH on BOTTOM: 112.95,84.76 115.24,84.76 115.36,84.63 115.36,82.09 115.24,81.97 113.08,81.97 112.82,82.22 112.82,84.63
P1V05_PCH on BOTTOM: 127.05,49.07 136.83,49.07 137.21,48.69 137.21,46.91 137.46,46.66 141.91,46.66 142.03,46.79 142.03,49.96 140.64,51.36 140.64,52.5 140.25,52.88 135.56,52.88 134.92,52.25 127.17,52.25 126.92,51.99 126.92,49.2
P1V05_PCH on BOTTOM: 108.63,81.59 111.04,81.59 111.17,81.46 111.17,77.78 111.04,77.65 108.63,77.65 108.5,77.78 108.5,81.46
P1V05_PCH on SIG1: 95.8,86.67 95.8,85.52 95.55,85.27 90.98,85.27 90.72,85.52 90.72,86.54 91.11,86.92 95.55,86.92
P1V05_PCH on POWER1: 125.65,70.95 121.03,75.57 119.58,77.01 108.76,77.01 108.5,76.76 99.49,76.76 93.39,82.86 93.39,88.92 94.41,89.94 94.41,98.19 100.77,104.56 120.81,104.56 143.3,82.06 143.3,50.6 142.92,50.22 128.19,50.22 125.65,52.76
P1V05_PCH_BPH1 on TOP: 146.35,50.22 150.92,50.22 151.56,49.58 153.08,49.58 153.08,47.3 152.19,46.41 146.35,46.41 146.22,46.53 146.22,50.09
P1V05_PROC_IO on TOP: 84.31,119.81 86.28,119.81 86.53,120.07 86.53,123.75 86.07,124.22 81.41,124.22 80.96,123.76 80.96,122.54 81.33,122.17 83.55,122.17 83.81,121.91 83.81,120.32
P1V05_PROC_IO on BOTTOM: 86.28,121.84 86.15,121.72 84.37,121.72 84.25,121.84 84.25,123.88 84.37,124 86.15,124 86.28,123.88
P1V05_VCCCIOIN on TOP: 90.47,118.67 93.26,118.67 93.52,118.92 93.52,123.37 93.39,123.5 90.47,123.5 90.34,123.37 90.34,118.8
P1V05_VCCCIOIN on TOP: 155.62,61.9 155.49,61.77 152.57,61.77 152.45,61.9 152.45,65.08 153.34,65.96 153.34,69.77 153.46,69.9 155.49,69.9 155.62,69.77
P1V05_VCCCIOIN on BOTTOM: 95.55,74.8 95.65,74.7 95.65,73.63 95.47,73.46 95.27,73.46 94.89,73.08 93.49,73.08 93.37,73.2 93.37,74.37 93.8,74.8
P1V05_VCCCIOIN on BOTTOM: 90.6,120.96 93.14,120.96 93.26,121.08 93.26,123.37 93.14,123.5 90.47,123.5 90.34,123.37 90.34,121.21
P1V05_VCCCIOIN on BOTTOM: 154.86,62.79 154.99,62.92 154.99,67.11 154.86,67.23 152.32,67.23 152.19,67.11 152.19,64.69 151.43,63.93 149.4,63.93 149.02,63.55 149.02,62.28 149.14,62.15 151.56,62.15 152.19,62.79
P1V05_VCCCIOIN on SIG2: 110.92,52.63 99.87,52.63 99.09,53.42 99.09,68.96 94.41,73.64 94.41,74.73 95.68,76 95.68,80.44 94.92,81.2 94.92,81.33 94.53,81.71 84.63,81.71 84.12,82.22 84.12,95.94 87.04,98.86 91.11,98.86 91.74,99.49 91.74,100.76 86.15,106.35 86.15,106.86 85.64,107.37 85.64,107.75 85.9,108 85.9,121.84 86.53,122.48 92.88,122.48 93.52,121.84 93.52,105.08 94.28,104.32 94.28,98.1 92.63,96.44 90.34,96.44 88.31,94.41 88.31,85.65 88.57,85.4 92.12,85.4 92.38,85.65 92.5,85.65 92.76,85.9 92.76,88.95 93.9,90.09 95.68,90.09 96.06,89.71 96.06,84.89 96.69,84.25 97.58,84.25 100.12,81.71 110.41,81.71 120.95,92.25 120.95,111.81 121.08,111.94 128.06,111.94 128.32,111.68 128.32,98.22 139.37,87.17 170.86,87.17 172.51,85.52 172.51,71.55 173.4,70.66 176.32,70.66 176.45,70.54 176.45,61.48 176.04,61.06 172.79,61.06 169.74,58.02 169.74,52.57 168.92,51.74 153.59,51.74 146.99,58.34 133.14,58.34 132.63,57.84 132.63,52.88 131.87,52.12 111.43,52.12
P1V05_VCCGB on TOP: 142.03,43.99 142.16,43.87 142.16,38.66 142.14,38.64 142.14,37.07 142.13,37.06 142.13,34.69 141.85,34.41 139.22,34.41 138.76,34.87 138.76,36.97 136.7,39.04 133.04,39.04 132.76,39.32 132.76,41.07 132.51,41.33 124,41.33 123.87,41.45 122.73,41.45 121.84,40.56 121.84,36.75 121.33,36.25 121.33,33.83 121.08,33.58 117.78,33.58 117.65,33.71 117.65,36.5 118.79,37.64 118.79,41.07 118.8,41.08 118.8,41.95 121.51,44.66 122.95,44.66 123.62,43.99
P1V05_VCCGB on BOTTOM: 149.78,61.65 151.05,61.65 151.3,61.39 151.3,59.61 152.07,58.85 152.07,58.22 151.94,58.09 151.05,58.09 149.53,59.61 149.53,61.39
P1V05_VCCGB on BOTTOM: 125.27,43.99 142.03,43.99 142.16,43.87 142.16,34.47 142.03,34.34 139.39,34.34 137.33,36.4 137.33,38.28 136.7,38.91 132.89,38.91 132.76,39.04 132.76,41.07 132.51,41.33 125.52,41.33 125.14,41.71 125.14,43.87
P1V05_VCCGB on BOTTOM: 109.14,77.01 111.3,77.01 111.43,76.89 111.43,73.46 111.17,73.2 109.14,73.2 108.89,73.46 108.89,76.76
P1V05_VCCGB on POWER1: 107.87,62.31 98.85,71.45 98.85,75.87 99.36,76.38 109.01,76.38 109.39,76.76 118.76,76.76 120.49,75.03 125.27,70.25 125.27,52.25 127.81,49.71 142.79,49.71 143.3,49.2 143.3,40.56 142.41,39.68 120.32,39.68 119.68,40.31 119.68,46.03 111.04,54.66 111.04,59.14
P1V05_VCCSCSUS on TOP: 117.52,27.86 121.46,27.86 121.71,28.12 121.71,30.15 122.35,30.79 128.57,30.79 129.08,30.28 137.67,30.28 138.29,30.9 138.29,35.13 137.56,35.87 133.72,35.87 133.33,36.26 133.33,37.22 133.5,37.4 133.5,38.52 133.31,38.71 132.62,38.71 131.67,37.77 126.03,37.77 125.27,37.01 122.09,37.01 121.84,36.75 121.84,33.58 121.33,33.07 117.78,33.07 117.39,32.69 117.39,27.99
P1V05_VCCSCSUS on BOTTOM: 115.49,74.73 117.01,74.73 117.14,74.6 117.14,72.7 117.01,72.57 115.49,72.57 115.36,72.7 115.36,74.6
P1V05_VCCSCSUS on BOTTOM: 128.57,30.79 129.08,30.28 133.52,30.28 134.79,31.55 140,31.55 140.13,31.67 140.13,33.07 137.19,36.01 132.5,36.01 132.13,36.38 132.13,37.49 131.81,37.81 121.47,37.81 121.33,37.67 121.33,33.45 120.19,32.31 120.19,30.91 120.32,30.79
P1V05_VCCSCSUS on POWER2: 112.54,78.03 118.4,72.17 118.4,71.82 119.06,71.16 119.41,71.16 125.24,65.33 133.4,65.33 135.17,63.55 135.17,33.14 134.69,32.65 120.01,32.65 119.68,32.98 119.68,46.03 110.16,55.55 110.16,67.62 105.96,71.81 101.54,71.81 99.76,73.58 99.76,77.79 100,78.03 101.9,78.03 102.15,77.78 103.81,77.78 104.06,78.03
P1V5_VRM on TOP: 127.43,60.25 127.81,60.25 128.32,59.74 129.46,59.74 129.71,59.49 129.71,57.2 129.59,57.07 127.3,57.07 127.17,57.2 127.17,60
P1V5_VRM on BOTTOM: 125.9,60.38 128.06,60.38 128.19,60.25 128.19,56.44 128.06,56.31 126.03,56.31 125.78,56.57 125.78,60.25
P1V5_VRM on SIG4: 95.55,82.98 89.07,82.98 88.69,83.36 88.69,85.4 89.58,86.28 89.96,86.28 90.09,86.41 90.09,87.55 92.38,89.84 100.76,89.84 102.41,88.19 102.41,81.33 104.19,79.55 104.19,68.25 107.62,64.82 107.74,64.82 110.41,62.15 129.08,62.15 129.84,61.39 129.84,58.73 129.27,58.15 109.46,58.15 100.12,67.49 100.12,78.41
P1V7_VCCSCFUSESUS on TOP: 152.19,60.25 152.45,60.5 155.62,60.5 155.75,60.38 155.75,54.03 155.49,53.77 152.45,53.77 152.19,54.03
P1V7_VCCSCFUSESUS on BOTTOM: 154.99,54.03 152.32,54.03 152.07,54.28 152.07,56.82 152.57,57.33 152.57,62.03 152.83,62.28 154.99,62.28 155.11,62.15 155.11,54.15
P1V7_VCCSCFUSESUS on SIG4: 95.55,75.62 99.49,75.62 99.87,75.24 99.87,67.23 109.39,57.71 153.08,57.71 153.59,57.2 153.59,53.26 150.16,49.84 108.89,49.84 94.92,63.81 94.92,74.98
P2V5_M_ABC_VPP on TOP: 1.57,48.44 4.49,48.44 4.75,48.18 4.75,47.42 4.36,47.04 1.57,47.04 1.44,47.17 1.44,48.31
P2V5_M_ABC_VPP on TOP: 53.51,38.41 54.66,39.55 63.04,39.55 63.17,39.42 63.17,38.02 63.04,37.9 60.75,37.9 60.24,37.39 60.24,35.99 60.75,35.48 62.02,35.48 62.91,34.6 65.32,34.6 66.29,35.56 75.66,35.56 76.75,34.47 76.75,30.98 76.56,30.78 71.56,30.78 70.02,32.31 64.44,32.31 63.8,31.67 58.21,31.67 57.2,30.66 57.2,28.75 57.07,28.63 53.89,28.63 53.51,29.01
P2V5_M_ABC_VPP on TOP: 18.59,48.44 18.72,48.31 18.72,47.8 18.59,47.68 17.19,47.68 16.94,47.42 16.94,47.17 16.81,47.04 14.65,47.04 12.11,49.58 12.11,49.84 12.24,49.96 14.78,49.96 14.91,49.84 14.91,49.71 14.27,49.07 14.27,48.69 14.52,48.44
P2V5_M_ABC_VPP on BOTTOM: 77.01,31.17 58.09,31.17 56.69,32.56 56.69,39.42 56.82,39.55 71.17,39.55 73.71,37.01 73.71,36.88 77.01,36.88 77.26,36.63 77.26,31.42
P2V5_M_ABC_VPP on BOTTOM: 15.67,51.36 11.48,51.36 11.22,51.11 11.22,48.69 11.48,48.44 16.3,48.44 16.81,47.93 18.46,47.93 18.59,48.06 18.59,48.44
P2V5_M_ABC_VPP on BOTTOM: 2.08,47.04 1.7,47.42 1.7,49.07 1.82,49.2 5,49.2 5.13,49.07 5.13,47.55 4.62,47.04
P2V5_M_ABC_VPP on SIG1: 3.35,48.31 3.22,48.18 3.22,39.42 3.6,39.04 34.08,39.04 42.59,30.53 69.26,30.53 72.44,33.71 72.44,35.87 69.39,38.91 60.5,38.91 50.97,48.44 16.3,48.44 14.65,50.09 3.98,50.09 3.35,49.45
P2V5_VPP_BPH1 on TOP: 73.2,19.61 72.44,20.37 72.44,26.95 72.72,27.23 76.37,27.23 76.63,26.98 76.63,23.93 75.1,22.4 75.1,19.61
P3V3 on TOP: 165.27,93.14 165.53,92.89 165.53,90.35 165.4,90.22 163.62,90.22 163.5,90.35 163.5,93.02 163.62,93.14
P3V3 on TOP, BOTTOM: 124.25,150.29 127.3,150.29 127.43,150.17 127.43,146.48 127.3,146.36 124.13,146.36 123.87,146.61 123.87,149.91
P3V3 on BOTTOM: 123.36,123.11 123.36,124.77 123.49,124.89 125.14,124.89 125.27,124.77 125.27,122.86 125.14,122.73 123.74,122.73
P3V3 on SIG2: 102.28,88.82 101.14,89.97 99.61,89.97 99.23,89.59 99.23,84.76 99.11,84.63 96.82,84.63 96.57,84.89 96.57,90.86 95.68,91.75 94.03,91.75 93.39,92.38 92.5,92.38 91.74,93.14 91.74,93.52 91.99,93.78 91.99,94.29 92.25,94.54 92.76,94.54 93.9,95.68 102.79,95.68 105.33,98.22 105.33,107.87 104.69,108.51 104.69,110.54 105.33,111.18 105.33,112.19 105.08,112.45 102.41,112.45 102.15,112.7 102.15,116.89 102.79,117.53 102.79,134.8 103.81,135.81 103.81,138.48 103.11,139.18 103.11,144.51 107.36,148.77 135.05,148.77 136.57,147.24 136.57,99.62 142.54,93.65 153.97,93.65 154.73,94.41 164.77,94.41 165.02,94.16 165.02,91.87 165.4,91.49 165.4,88.82 164.89,88.32 140.76,88.32 130.98,98.1 130.98,111.3 129.33,112.95 121.2,112.95 120.44,112.19 120.44,99.24 110.03,88.82
P3V3 on SIG4: 70.02,152.07 70.66,151.44 70.66,140.64 82.72,128.58 82.72,124.38 83.8,123.3 111.24,123.3 111.3,123.24 111.3,119.69 110.54,118.92 110.54,117.91 109.27,116.64 97.71,116.64 90.65,109.58 85.34,109.58 85.32,109.56 84.53,109.56 84.37,109.39 84.37,108.93 84.94,108.35 84.94,106.05 84.61,105.72 81.2,105.72 79.29,107.62 79.29,121.34 57.7,142.93 57.7,151.44 58.34,152.07 ; 1 cut-out
P3V3_AUX on TOP: 183.43,111.56 182.42,110.54 180.77,110.54 180.64,110.67 180.64,112.45 180.77,112.57 182.16,112.57 182.42,112.83 182.42,113.21 182.55,113.34 183.05,113.34 183.43,112.95
P3V3_AUX on TOP: 141.78,134.8 138.22,134.8 138.22,136.58 138.35,136.7 141.65,136.7 141.91,136.45 141.91,134.93
P3V3_AUX on TOP: 176.45,162.48 176.45,153.85 176.32,153.72 170.1,153.72 169.72,154.1 169.72,162.61 169.85,162.74 176.2,162.74
P3V3_AUX on TOP: 131.24,150.04 134.92,150.04 135.43,149.53 135.43,145.21 135.17,144.96 131.24,144.96 131.11,145.09 131.11,149.91
P3V3_AUX on TOP: 141.14,101.27 141.27,101.4 141.27,103.68 138.6,103.68 138.48,103.56 138.48,101.4 138.6,101.27
P3V3_AUX on BOTTOM: 138.98,141.02 136.95,141.02 136.83,141.15 136.83,142.55 136.95,142.67 138.98,142.67 139.11,142.55 139.11,141.15
P3V3_AUX on BOTTOM: 175.05,162.61 175.18,162.48 175.18,153.85 174.93,153.59 169.34,153.59 169.08,153.85 169.08,162.36 169.34,162.61
P3V3_AUX on BOTTOM: 132.76,101.27 135.68,101.27 135.94,101.02 135.94,99.37 135.81,99.24 132.76,99.24 132.63,99.37 132.63,101.14
P3V3_AUX on BOTTOM: 131.24,150.04 134.16,150.04 134.67,149.53 134.67,145.21 134.41,144.96 131.24,144.96 131.11,145.09 131.11,149.91
P3V3_AUX on POWER1: 143.75,67.04 143.68,67.11 143.68,82.47 121.01,105.14 100.28,105.14 93.65,98.51 93.65,90.25 92.63,89.24 92.63,82.89 91.96,82.22 88.6,82.22 88.06,82.76 88.06,101.94 81.33,108.67 69.66,120.34 69.66,162.12 70.28,162.74 172.51,162.74 173.66,161.6 173.66,123.11 183.43,113.34 183.43,66.38 177.69,60.63 173.02,60.63 169.59,57.2 169.59,28.37 153.21,11.99 61.51,11.99 60.75,12.75 60.75,16.69 61.26,17.2 133.52,17.2 143.75,27.42
P3V3_NGFF on TOP: 166.62,96.98 165.32,96.98 165.15,96.8 165.15,95.48 166.57,95.48 166.77,95.68 166.77,96.83
P3V3_NGFF on TOP: 179.24,7.54 181.28,7.54 181.4,7.42 181.4,2.97 181.15,2.72 167.69,2.72 167.05,3.35 167.05,21.39 178.86,33.2 178.86,49.96 184.96,56.06 184.96,59.23 175.69,68.5 175.69,74.6 176.07,74.98 179.5,74.98 180.89,73.58 180.89,67.36 188.64,59.61 188.64,56.69 181.4,49.45 181.4,32.44 169.97,21.01 169.97,8.18 170.61,7.54 170.61,5.89 170.86,5.64 177.34,5.64
P3V3_NGFF on TOP: 167.43,93.02 167.43,93.14 167.18,93.4 166.04,93.4 165.91,93.27 165.91,90.35 166.04,90.22 167.79,90.22 167.99,90.42 167.99,92.46
P3V3_NGFF on TOP: 183.43,93.24 181.99,93.24 181.78,93.04 181.15,93.04 180.49,92.38 180.49,91.24 180.77,90.96 182.88,90.96 183.46,91.54 183.46,93.22
P3V3_NGFF on BOTTOM: 172.26,9.45 168.32,9.45 168.07,9.2 168.07,4.24 168.19,4.12 172.13,4.12 172.26,4.24
P3V3_NGFF on BOTTOM: 168.25,97 165.4,97 165.22,96.83 165.22,95.56 165.32,95.45 167.89,95.45 168.35,95.91 169.77,95.91 169.95,96.09 169.95,96.75 168.98,97.71 168.47,97.71 168.37,97.61 168.37,97.13
P3V3_NGFF on SIG2: 170.61,92 176.2,86.41 176.2,72.95 176.83,72.31 178.35,72.31 182.04,76 182.04,97.84 180.39,99.49 166.54,99.49 165.27,98.22 165.27,95.17 165.91,94.54 165.91,92.28 166.19,92
P3V3_STBY on TOP: 143.05,59.23 145.84,59.23 145.97,59.11 145.97,55.93 146.1,55.8 148.38,55.8 148.51,55.68 148.51,54.03 148.38,53.9 143.3,53.9 142.79,54.41 142.79,58.98
P3V3_STBY on TOP: 135.56,58.34 135.56,56.95 135.43,56.82 133.27,56.82 132,58.09 130.22,58.09 130.09,58.22 130.09,61.65 130.22,61.77 133.02,61.77 133.14,61.65 133.14,58.85 133.4,58.6 135.3,58.6
P3V3_STBY on TOP: 106.98,161.85 104.19,161.85 104.06,161.72 104.06,157.15 104.31,156.9 108,156.9 108.12,156.77 108.12,153.34 108.38,153.09 110.66,153.09 110.92,153.34 110.92,157.15 110.41,157.66 110.41,158.42 110.28,158.55 107.49,158.55 107.11,158.93 107.11,161.72
P3V3_STBY on TOP: 157.4,158.67 159.94,158.67 160.19,158.42 160.19,155.25 160.57,154.86 161.97,154.86 162.1,154.74 162.1,152.71 161.97,152.58 158.29,152.58 157.02,153.85 157.02,158.29
P3V3_STBY on TOP: 147.49,153.47 147.11,153.85 147.11,160.2 148.13,161.21 149.78,161.21 150.16,160.83 150.16,153.72 149.91,153.47
P3V3_STBY on BOTTOM: 148.13,162.48 148.13,153.59 148.26,153.47 149.78,153.47 150.16,153.85 150.16,162.48 150.03,162.61 148.26,162.61
P3V3_STBY on BOTTOM: 58.09,144.45 56.56,144.45 56.43,144.58 56.43,146.99 56.56,147.12 57.96,147.12 58.21,146.86 58.21,144.58
P3V3_STBY on BOTTOM: 132.51,61.9 134.92,61.9 135.05,61.77 135.05,58.85 135.68,58.22 135.68,57.07 135.56,56.95 132.63,56.95 132.38,57.2 132.38,61.77
P3V3_STBY on BOTTOM: 146.1,58.73 148.13,58.73 148.26,58.6 148.26,54.15 148,53.9 145.97,53.9 145.84,54.03 145.84,58.47
P3V3_STBY on BOTTOM: 159.56,157.91 161.59,157.91 162.1,157.4 162.1,152.83 161.84,152.58 159.56,152.58 159.3,152.83 159.3,157.66
P3V3_STBY on BOTTOM: 75.48,149.02 77.01,149.02 77.14,148.9 77.14,147.24 77.01,147.12 75.36,147.12 75.23,147.24 75.23,148.77
P3V3_STBY on BOTTOM: 96.82,145.59 96.82,144.32 96.69,144.2 93.26,144.2 93.14,144.32 93.14,145.47 93.26,145.59 94.41,145.59 94.53,145.72 94.53,145.85 94.41,145.97 93.9,145.97 93.77,146.1 93.77,146.74 93.9,146.86 95.55,146.86
P3V3_STBY on BOTTOM: 108.5,153.21 108.25,153.47 108.25,157.02 108,157.28 103.93,157.28 103.55,157.66 103.55,161.72 103.68,161.85 107.62,161.85 107.74,161.72 107.74,161.09 110.79,158.04 110.79,153.34 110.66,153.21
P3V3_STBY on SIG2: 118.16,2.34 116.63,3.87 72.86,3.87 72.84,3.84 64.56,12.12 41.96,12.12 24.94,29.13 24.94,33.58 25.45,34.09 40.31,34.09 52.5,21.9 56.82,21.9 57.83,20.88 57.83,18.97 59.99,16.82 65.32,16.82 66.72,15.42 71.55,15.42 78.02,8.94 117.14,8.94 118.66,7.42 132,7.42 136.83,12.24 136.83,21.01 134.92,22.91 134.92,50.34 134.98,50.41 133.14,52.25 133.14,57.46 133.52,57.84 146.35,57.84 152.83,51.36 183.94,51.36 186.74,54.15 186.74,143.69 180.77,149.66 99.11,149.66 97.96,148.51 97.96,134.42 92.63,129.08 76.37,129.08 73.45,132 68.75,132 59.48,141.28 59.48,143.43 56.31,146.61 56.31,153.59 58.47,155.75 67.23,155.75 74.02,162.55 188.2,162.55 188.55,162.2 188.55,160.04 189.7,158.88 191.86,158.88 191.88,158.86 194.29,158.86 194.99,158.17 194.99,119.18 194.36,118.54 194.36,98.86 194.74,98.48 194.74,21.13 192.45,18.85 192.45,11.23 192.58,11.1 194.61,11.1 194.74,10.97 194.74,4.24 192.83,2.34 177.3,2.34 176.95,2.69 171.55,2.69 171.19,2.34 154.35,2.34 150.8,5.89 145.21,5.89 141.65,2.34 ; 1 cut-out
P5V_AUX on TOP: 163.37,66.6 165.4,66.6 165.53,66.47 165.53,62.79 165.4,62.66 163.5,62.66 163.24,62.92 163.24,66.47
P5V_AUX on TOP: 200.96,47.42 201.21,47.68 201.21,51.23 200.83,51.61 195.88,51.61 194.74,52.76 186.48,52.76 186.1,52.38 186.1,47.8 186.48,47.42
P5V_AUX on TOP: 161.97,56.69 163.75,56.69 163.88,56.57 163.88,52.63 163.75,52.5 162.61,52.5 161.84,53.26 161.84,56.57
P5V_AUX on BOTTOM: 160.83,62.66 164.13,62.66 164.38,62.92 164.38,63.3 164.51,63.42 164.51,66.22 163.88,66.85 160.83,66.85 160.7,66.73 160.7,62.79
P5V_AUX on BOTTOM: 161.97,56.69 163.75,56.69 163.88,56.57 163.88,53.26 163.75,53.14 161.97,53.14 161.84,53.26 161.84,56.57
P5V_AUX on BOTTOM: 186.99,47.42 197.79,47.42 197.91,47.55 197.91,49.58 194.74,52.76 186.86,52.76 186.74,52.63 186.74,47.68
P5V_AUX on SIG3: 75.99,8.56 168.19,8.56 169.08,9.45 169.08,21.13 171.31,23.36 182.99,23.36 192.96,33.33 192.96,41.2 197.15,45.39 197.15,51.11 196,52.26 196,55.97 195.4,56.57 177.72,56.57 168.83,65.46 151.3,65.46 144.57,58.73 144.57,53.39 163.24,53.39 173.02,43.61 173.02,30.66 172.89,30.53 163.24,30.53 163.11,30.4 159.56,30.4 158.8,29.64 158.8,18.97 154.1,14.28 121.08,14.28 120.7,13.89 119.81,13.89 119.43,14.28 82.47,14.28 80.31,16.43 80.31,26.72 80.18,26.85 78.53,26.85 75.74,24.05 75.74,8.81
PVCCCIN on TOP: 114.09,37.9 114.09,31.17 113.97,31.04 94.03,31.04 93.39,31.67 93.39,47.48 93.18,47.69 89.71,47.69 89.48,47.92 89.48,52.56 89.04,53.01 89.04,60.84 88.36,61.51 88.36,69.65 85.99,72.03 85.99,80.3 85.99,80.3 85.99,80.81 86.6,81.42 87.99,81.42 88.5,81.93 91.52,81.93 91.78,81.67 91.78,70.65 91.37,70.24 91.37,56.32 90.94,55.89 90.94,53.86 91.86,52.93 91.86,50.93 92.78,50.01 93.73,50.01 94.08,49.65 94.84,49.65 96.43,48.06 109.01,48.06 109.14,47.93 109.14,46.53 108.76,46.15 106.85,46.15 106.73,46.03 106.73,43.23 106.85,43.1 106.85,37.14 107.36,36.63 110.54,36.63 111.93,38.02 113.97,38.02
PVCCCIN on TOP: 96.09,72.89 96.81,72.89 97.17,73.25 97.17,77.98 97,78.15 95.57,78.15 95.39,77.97 95.39,74.86 96,74.26 96,72.99
PVCCCIN on BOTTOM: 90.36,72.34 90.51,72.2 91.7,72.2 91.74,72.15 91.74,71.17 91.36,70.79 91.36,69.39 91.11,69.14 91.11,68.76 90.85,68.5 90.85,63.17 90.98,63.04 90.98,60.26 91.29,59.95 91.29,55.62 97.07,49.84 97.07,48.69 97.71,48.06 108.5,48.06 108.63,47.93 108.63,45.52 106.85,43.74 106.85,37.14 107.36,36.63 110.54,36.63 111.93,38.02 113.97,38.02 114.09,37.9 114.09,26.98 113.97,26.85 112.19,26.85 111.93,27.1 111.93,29.64 110.66,30.91 108,30.91 107.74,31.17 94.03,31.17 93.01,32.18 93.01,35.74 93.39,36.12 93.39,44.76 89.85,48.3 89.85,51.82 88.34,53.33 86.82,53.33 86.41,53.74 86.41,64.69 85.9,65.2 85.9,68.12 86.03,68.25 86.03,68.9 86.22,69.09 87.42,69.09 87.69,69.36 87.69,70.38 86.96,71.11 86.96,71.33 87.43,71.8 87.43,80.26 88.08,80.91 90.17,80.91 90.36,80.71
PVCCCIN on BOTTOM: 97.16,74.55 96.97,74.36 95.9,74.36 95.5,74.75 95.5,77.89 95.5,77.9 95.5,78.12 95.65,78.26 96.96,78.26 97.16,78.06
PVCCCIN on SIG1: 85.64,51.61 89.2,55.17 89.2,62.15 87.68,63.68 87.68,64.69 87.93,64.95 87.93,65.33 87.55,65.71 87.55,66.47 88.06,66.98 88.06,68.63 86.41,70.28 86.41,80.82 86.79,81.2 95.68,81.2 98.09,78.79 98.09,71.43 96.57,69.9 96.57,67.74 97.2,67.11 97.2,66.73 97.46,66.47 97.46,61.9 96.82,61.27 96.82,54.41 93.35,50.93 93.35,49.36 95.54,47.17 104.82,47.17 106.09,45.9 106.09,43.1 107.36,41.83 107.36,41.58 112.44,36.5 112.44,30.79 112.06,30.4 86.41,30.4 85.64,31.17
PVCCCIN on SIG2: 87.93,64.95 87.93,65.33 87.55,65.71 87.55,66.47 88.06,66.98 88.06,68.63 86.41,70.28 86.41,80.82 86.79,81.2 94.41,81.2 95.04,80.57 95.04,75.87 94.03,74.85 94.03,73.33 98.53,68.82 98.53,53.26 99.54,52.25 104.31,52.25 110.66,45.9 110.66,44.37 112.7,42.34 112.7,28.37 109.77,25.45 95.3,25.45 93.9,26.85 86.15,26.85 85.45,27.55 85.45,47.23 89.21,50.99 89.21,63.67
PVCCCIN on POWER1: 84.88,80.28 85.29,80.7 86.95,80.7 87.71,81.46 94.03,81.46 98.09,77.39 98.09,71.55 110.66,58.98 110.66,42.09 112.44,40.31 112.44,26.85 111.3,25.71 86.86,25.71 85.5,27.06 85.5,47.2 90.09,51.78 90.09,63.4 89.18,64.31 89.18,67.23 84.88,71.53
PVCCCIN on POWER2: 88.82,53.87 88.82,68.19 88.95,68.31 88.95,69.18 88.82,69.31 87.19,70.79 85.68,70.79 85.14,71.33 85.14,72.31 84.88,72.57 84.88,79.8 86.42,81.33 96.03,81.33 98.73,78.63 98.73,72.03 99.97,70.79 105.55,70.79 108.63,67.71 108.63,54.53 110.66,52.5 110.66,42.09 112.44,40.31 112.44,26.85 111.3,25.71 80.95,25.71 80.06,26.59 80.06,45.11
PVCCCIN on SIG3: 97.58,67.74 97.07,67.23 93.39,67.23 93.2,67.04 93.2,65.52 93.26,65.46 93.26,65.2 95.3,63.17 95.3,53.26 95.93,52.63 106.47,52.63 106.54,52.57 110.35,52.57 110.66,52.25 110.66,44.37 112.7,42.34 112.7,29.13 112.44,28.88 87.04,28.88 86.79,29.13 86.79,35.74 85.71,36.82 85.71,52.82 86.91,54.03 86.91,61.27 89.2,63.55 89.2,67.36 88.31,68.25 88.31,69.65 88.18,69.77 84.88,69.77 84.5,70.16 84.5,80.06 86.41,81.97 97.2,81.97 97.58,81.59
PVCCCIN on SIG4: 88.44,65.84 87.8,66.47 86.41,66.47 86.03,66.85 86.03,70.41 85.64,70.79 85.64,81.59 86.03,81.97 96.19,81.97 96.82,81.33 96.82,77.39 95.17,75.74 94.69,75.33 94.69,64.95 95.17,64.47 95.17,62.79 105.08,52.88 105.2,52.88 113.46,44.63 113.46,29.01 113.2,28.75 87.42,28.75 86.8,29.37 86.8,40.32 86.79,40.34 86.79,41.71 88.44,43.36
PVDDQ_CPU_ABC on TOP: 80.06,30.91 79.8,31.17 79.8,33.33 79.29,33.83 79.29,36.12 78.91,36.5 78.91,39.55 77.77,40.69 72.69,40.69 71.93,41.45 71.93,46.53 68.88,49.58 60.5,49.58 57.83,52.25 47.06,52.25 28.24,71.06 1.7,71.06 1.58,71.18 1.58,86.31 1.94,86.68 15.92,86.68 15.93,86.67 21,86.67 21,86.68 21.63,86.68 22.14,86.16 40.05,86.16 66.98,59.23 73.2,59.23 83.61,48.82 85.9,48.82 86.15,48.57 86.15,46.41 85.39,45.64 85.39,38.02 87.68,35.74 87.68,31.17 87.42,30.91
PVDDQ_CPU_ABC on TOP: 74.83,81.2 75.61,81.2 76.04,80.77 76.04,73.28 77.39,71.93 77.39,70.28 77.09,69.98 75.56,69.98 75.01,70.53 74.23,70.53 73.71,71.05 73.71,76.05 75.29,77.64 75.29,79.18 74.68,79.8 74.68,81.05
PVDDQ_CPU_ABC on TOP: 31.54,29.52 31.54,31.67 31.8,31.93 33.19,31.93 33.45,31.67 33.45,29.77 33.07,29.39 31.67,29.39
PVDDQ_CPU_ABC on BOTTOM: 31.29,39.8 31.29,67.11 26.21,72.19 24.81,72.19 24.3,71.68 22.4,71.68 22.4,71.04 22.27,70.92 14.65,70.92 14.4,71.17 14.4,76.76 16.49,78.85 16.49,83.68 17.19,84.38 17.19,86.03 17.32,86.16 20.99,86.16 21.13,86.02 59.75,86.02 63.67,82.09 72.69,82.09 74.6,84 82.6,84 83.87,82.73 83.87,81.09 83.86,81.08 83.86,73.2 84.11,72.95 84.63,72.95 84.76,72.82 84.76,65.46 83.61,64.31 83.61,49.07 85.39,47.3 85.39,38.53 85.77,38.15 88.06,38.15 88.31,37.9 88.31,35.23 88.06,34.98 79.04,34.98 78.91,35.1 78.91,39.04 77.39,40.56 74.6,40.56 73.45,41.71 73.45,47.04 71.55,48.95 58.34,48.95 37.64,28.25 31.8,28.25 31.54,28.5 31.54,29.77 31.67,29.9 32.81,29.9 32.94,30.02 32.94,31.8 33.96,32.82 33.96,37.14 ; 2 cut-outs
PVDDQ_CPU_ABC on BOTTOM: 2.84,71.04 8.43,71.04 8.81,71.43 8.81,72.44 11.48,75.11 11.48,87.05 10.97,87.55 2.84,87.55 2.46,87.17 2.46,71.43
PVDDQ_CPU_ABC on GND1: 1.44,86.92 1.44,71.68 1.57,71.55 4.49,71.55 5.25,72.31 13.38,72.31 14.52,71.17 39.54,71.17 40.05,70.66 48.31,70.66 53.39,65.58 70.91,65.58 71.8,66.47 72.82,66.47 73.2,66.09 74.47,66.09 75.23,66.85 75.23,69.77 75.87,70.41 77.9,70.41 79.42,71.93 79.42,77.39 80.44,78.41 80.44,83.24 79.68,84 75.74,84 75.23,83.49 75.23,82.09 74.21,81.08 63.67,81.08 63.17,81.59 63.17,83.24 62.66,83.74 59.61,83.74 55.93,87.43 27.35,87.43 26.72,88.06 26.59,88.06 25.83,87.3 13.64,87.3 13,87.94 12.75,87.94 12.11,87.3 1.82,87.3
PVDDQ_CPU_ABC on SIG1: 79.04,45.01 81.71,47.68 84.76,47.68 85.01,47.42 85.01,36.88 84.5,36.37 80.44,36.37 79.04,37.77
PVDDQ_CPU_ABC on GND2: 51.74,86.67 3.35,86.67 2.84,86.16 2.84,72.31 3.22,71.93 18.33,71.93 18.97,71.3 39.8,71.3 40.31,70.79 47.54,70.79 52.75,65.58 70.66,65.58 76.25,71.17 77.14,71.17 79.93,73.97 79.93,82.6 78.66,83.87 54.53,83.87
PVDDQ_CPU_ABC on POWER1: 56.05,83.74 52.88,86.92 4.24,86.92 2.84,85.52 2.84,72.19 3.09,71.93 46.15,71.93 49.32,68.76 73.83,68.76 76.25,71.17 82.34,71.17 83.87,72.7 83.87,79.17 79.29,83.74
PVDDQ_CPU_ABC on POWER2: 2.59,86.67 3.22,87.3 59.36,87.3 62.91,83.74 73.58,83.74 73.88,84.05 80.01,84.05 80.44,83.62 80.44,72.31 78.28,70.16 75.48,70.16 72.56,67.23 58.34,67.23 53.64,71.93 2.97,71.93 2.59,72.31
PVDDQ_CPU_ABC on SIG3: 80.44,36.37 84.5,36.37 85.01,36.88 85.01,47.55 84.76,47.8 82.47,47.8 79.29,44.63 79.29,40.18 79.68,39.8 79.68,37.14
PVDDQ_CPU_ABC on GND3: 3.98,87.17 2.71,85.9 2.71,72.7 3.35,72.06 51.86,72.06 53.13,70.79 54.66,70.79 58.21,67.23 72.56,67.23 75.48,70.16 77.64,70.16 80.31,72.82 80.31,83.62 79.88,84.05 74.27,84.05 72.31,82.09 63.67,82.09 58.59,87.17
PVDDQ_CPU_ABC on GND4: 55.04,86.54 17.57,86.54 17.32,86.28 17.32,84.51 16.43,83.62 16.43,79.81 14.4,77.78 14.4,72.31 14.78,71.93 52.12,71.93 55.8,68.25 64.44,68.25 65.58,67.11 72.31,67.11 72.56,67.36 72.56,79.3 72.18,79.68 61.9,79.68
VCC_1V15_AUX on TOP: 165.65,140.13 169.34,140.13 169.59,139.88 169.59,133.4 169.34,133.15 165.4,133.15 165.27,133.27 165.27,139.75
VCC_1V15_AUX on BOTTOM: 164.89,141.4 168.19,141.4 168.32,141.28 168.32,132.89 168.07,132.64 165.02,132.64 164.77,132.89 164.77,141.28
VCC_1V15_AUX on SIG2: 148,114.61 148.13,114.48 153.84,114.48 156.13,116.76 159.18,116.76 163.24,120.83 163.24,123.88 168.07,128.7 168.07,137.97 167.69,138.35 164,138.35 163.24,137.59 163.24,134.29 161.46,132.51 161.46,130.61 155.75,124.89 153.84,124.89 152.83,123.88 145.46,123.88 144.7,124.64 142.03,124.64 141.78,124.38 141.78,114.73 141.91,114.61
VCC_BATVDD on SIG1: 155.88,110.92 153.59,113.21 153.59,114.22 153.72,114.35 155.37,114.35 157.15,112.57 157.15,111.05 157.02,110.92
VCC_BMC_DDR on TOP: 165.4,150.55 169.08,150.55 169.34,150.29 169.34,143.82 169.08,143.56 165.15,143.56 165.02,143.69 165.02,150.17
VCC_BMC_DDR on BOTTOM: 165.02,150.93 168.32,150.93 168.45,150.8 168.45,142.42 168.19,142.16 165.15,142.16 164.89,142.42 164.89,150.8
VCC_BMC_DDR on POWER1: 169.08,137.85 169.08,150.17 167.69,151.56 143.05,151.56 140,148.51 140,135.31 142.29,133.02 142.29,126.16 144.83,123.62 144.83,122.35 145.46,121.72 150.41,121.72 152.19,123.5 154.73,123.5
VCCAXCK on SIG3: 97.58,85.9 105.33,85.9 106.6,84.63 106.6,84 106.35,83.74 98.34,83.74 97.46,84.63 97.46,85.78
VCCGBE_APH1 on TOP: 146.35,41.45 150.8,41.45 152.07,40.18 152.95,40.18 153.08,40.06 153.08,37.26 152.95,37.14 146.35,37.14 146.22,37.26 146.22,41.33
VDD1.8V on TOP: 98.09,158.04 98.09,153.59 95.3,150.8 93.52,150.8 93.14,150.42 93.14,149.02 93.26,148.9 96.31,148.9 97.07,149.66 100.25,149.66 101.52,150.93 101.52,156.64 101.77,156.9 103.42,156.9 103.68,157.15 103.68,158.42 103.55,158.55 102.28,158.55 102.15,158.67 102.15,158.93 102.28,159.06 103.55,159.06 103.68,159.18 103.68,159.56 103.42,159.82 101.52,159.82 100.88,159.18 99.23,159.18
VDD1.8V on BOTTOM: 94.41,149.4 93.26,149.4 93.14,149.28 93.14,147.37 93.26,147.24 94.41,147.24 94.53,147.37 94.53,149.28
VDD1.8V on BOTTOM: 101.39,156.77 99.36,156.77 98.98,156.39 98.98,153.21 99.11,153.09 101.39,153.09 101.52,153.21 101.52,156.64
VDD_BMC_2.5V on TOP: 152.32,156.13 156.51,156.13 156.64,156.01 156.64,152.58 164.26,144.96 164.26,138.35 160.57,134.67 149.14,134.67 148.38,135.43 148.38,136.58 148.51,136.7 148.89,136.7 150.16,135.43 159.94,135.43 162.99,138.48 162.99,143.94 161.72,145.21 157.15,145.21 152.19,150.17 152.19,156.01
VDD_BMC_2.5V on BOTTOM: 152.95,151.82 156,151.82 156.13,151.94 156.13,154.86 154.99,156.01 154.99,158.42 154.86,158.55 152.57,158.55 152.45,158.42 152.45,158.17 152.83,157.79 152.83,151.94
(no net) on TOP: 87.3,19.99 87.3,22.15 86.66,22.78 86.66,26.34 86.28,26.72 81.58,26.72 81.2,26.34 81.2,20.63 81.33,20.5 83.23,20.5 83.74,19.99
(no net) on TOP: 84.5,16.43 84.25,16.69 82.09,16.69 81.96,16.82 81.96,17.89 81.69,18.16 81.49,18.16 81.37,18.28 81.37,19.64 81.47,19.74 89.96,19.74 90.09,19.61 90.09,17.7 90.47,17.32 90.47,16.56 90.34,16.43
ADCAV33 on SIG4: 152.07,117.27 153.72,117.27 154.99,116 157.4,116 158.29,115.11 158.29,112.57 158.16,112.45 155.62,112.45 151.94,116.13 151.94,117.15
APH1_VCCIN on TOP: 111.3,19.99 111.3,22.15 110.66,22.78 110.66,26.59 110.54,26.72 106.22,26.72 106.09,26.59 106.09,21.26 106.85,20.5 107.23,20.5 107.74,19.99
APH1_VDDQ on TOP (solid shape): 86.66,26.34 86.66,22.78 87.3,22.15 87.3,20.73 87.29,20.66 87.29,20.21 87.3,20.04 87.28,20.01 87.25,19.99 83.74,19.99 83.23,20.5 81.33,20.5 81.2,20.63 81.2,26.34 81.58,26.72 86.28,26.72
APH2_VCCIN on TOP: 99.36,19.99 99.36,22.15 98.73,22.78 98.73,26.59 98.6,26.72 94.03,26.72 93.9,26.59 93.9,20.88 94.28,20.5 96,20.5 96.51,19.99
BPH1_VCCSCSUS on TOP: 129.59,26.85 129.71,26.98 134.16,26.98 134.41,26.72 134.41,22.28 134.29,22.15 132.76,22.15 132,21.39 132,19.74 131.87,19.61 129.71,19.61 129.59,19.74
I210_VDD3V3 on TOP: 182.29,116.76 181.78,117.27 175.81,117.27 175.69,117.15 175.69,113.46 175.81,113.34 182.04,113.34 182.29,113.59
I210_VDD3V3 on SIG2: 173.02,110.03 176.7,110.03 178.1,111.43 178.1,115.75 174.04,119.81 165.78,119.81 165.53,119.56 165.53,116.64 165.78,116.38 166.67,116.38 167.69,117.4 172.77,117.4 173.27,116.89 173.27,111.3 172.89,110.92 172.89,110.16
Net_27 on TOP (solid shape): outline of 128 points within 113.5,26.76 115.2,28.46
Net_28 on TOP (solid shape): outline of 128 points within 125.18,12.15 126.88,13.86
Net_30 on TOP (solid shape): outline of 184 points within 152.32,9.07 155.88,12.62
Net_31 on BOTTOM (solid shape): outline of 184 points within 152.32,9.07 155.88,12.62
